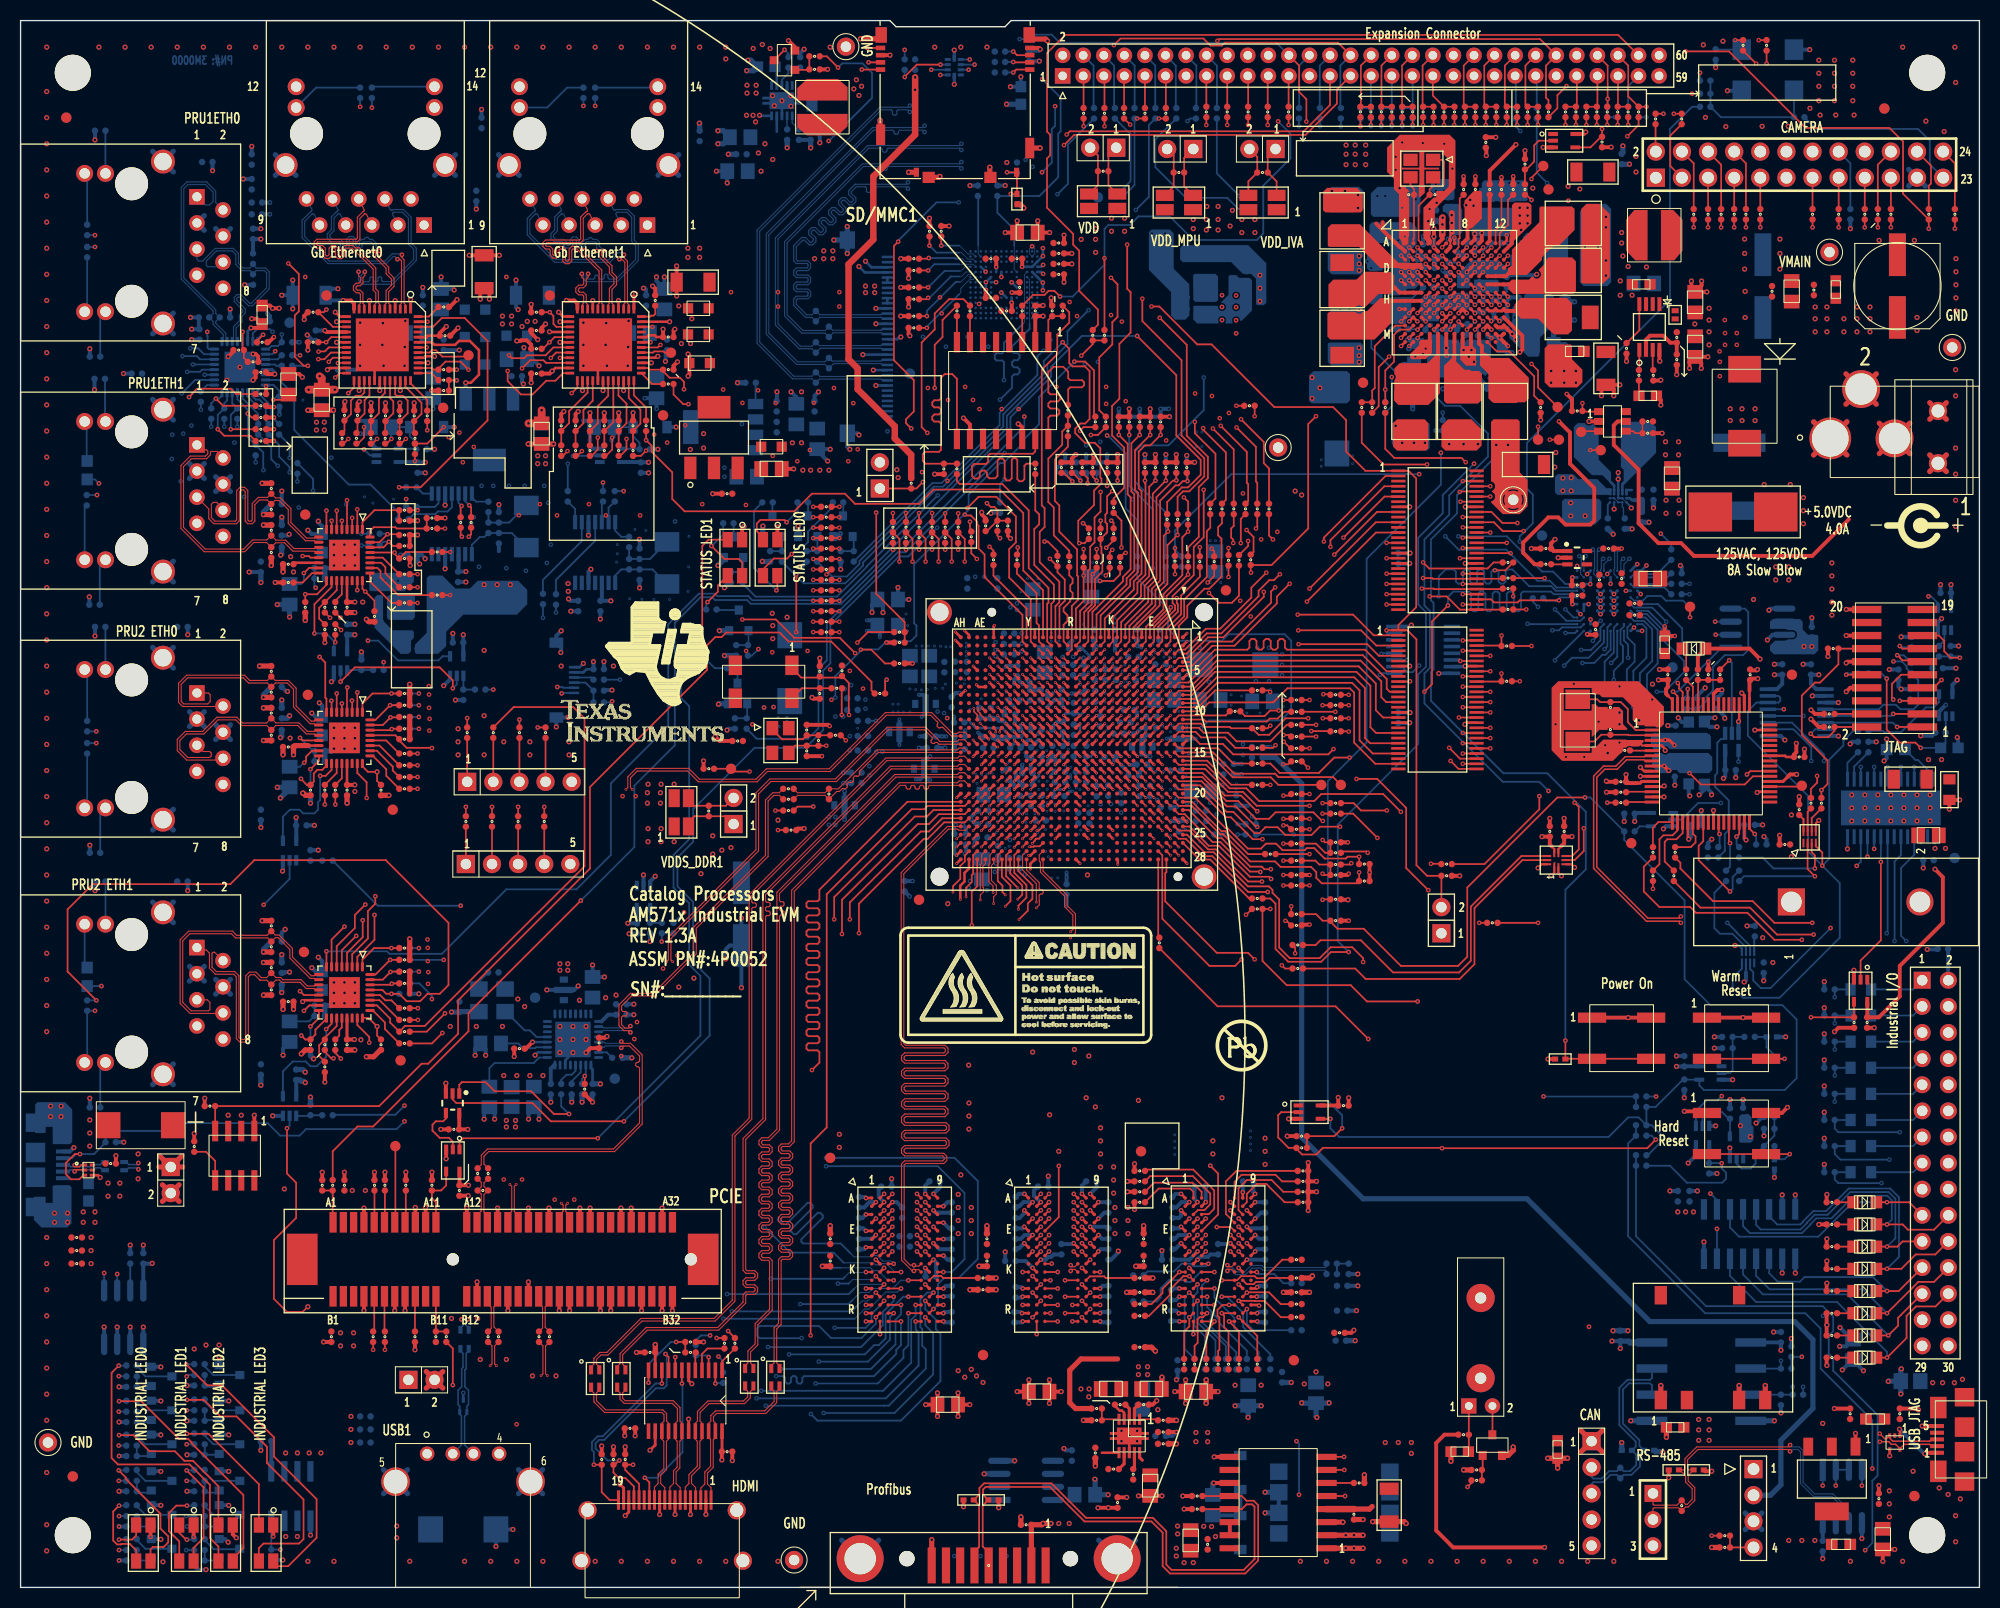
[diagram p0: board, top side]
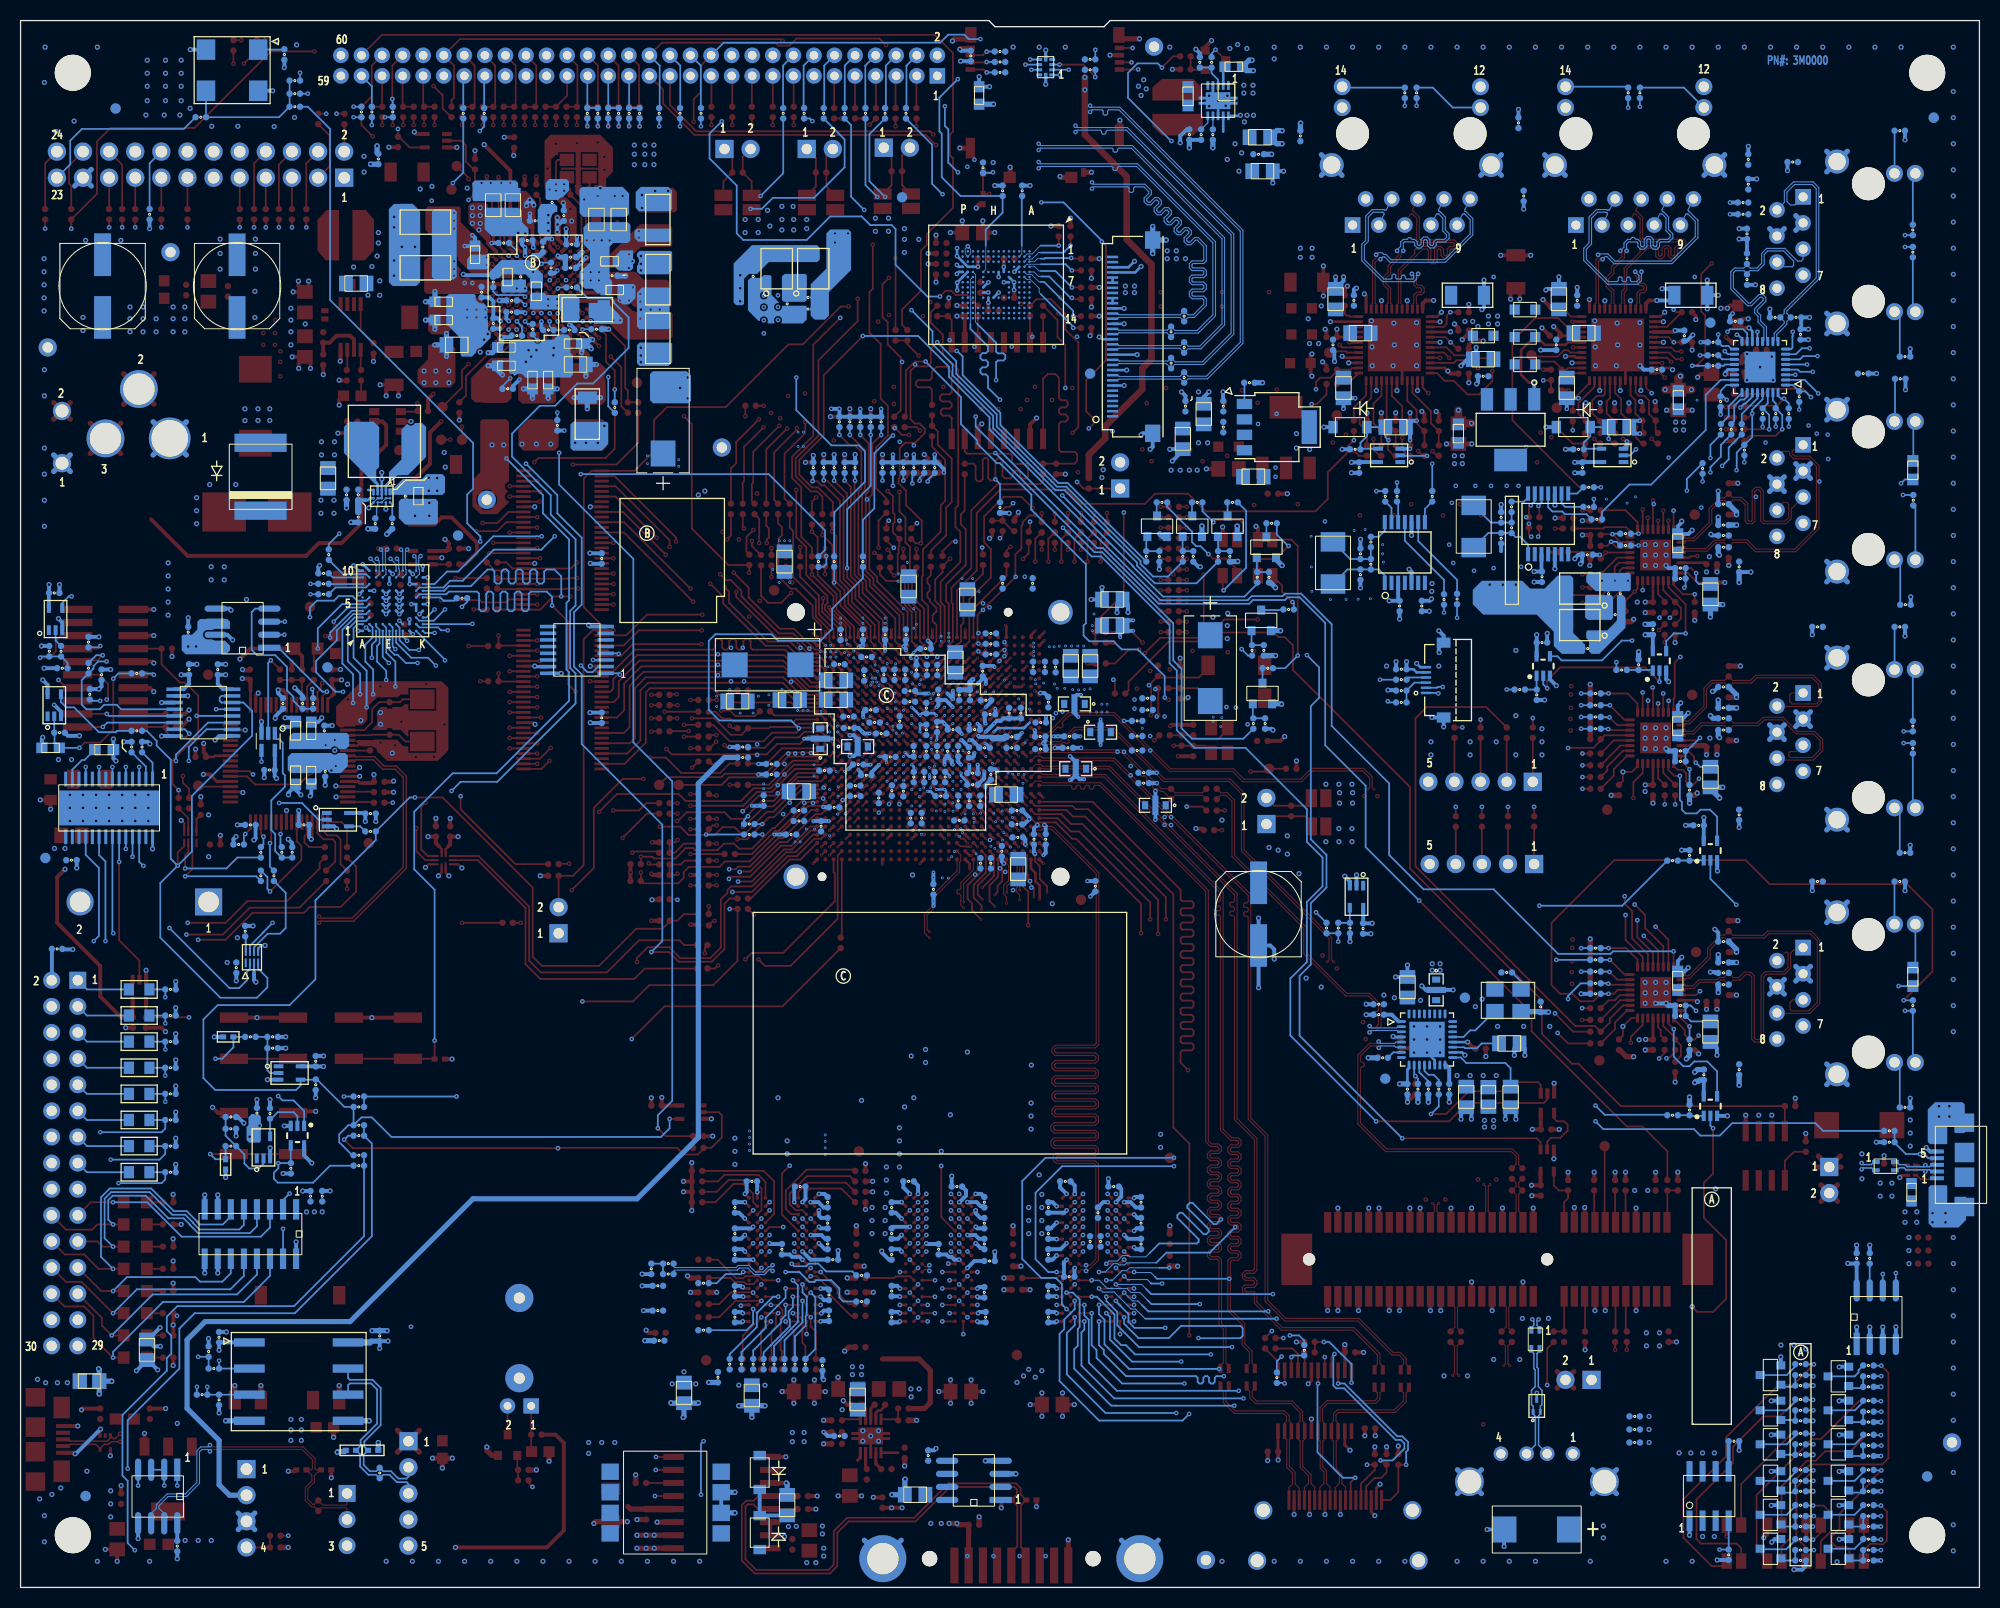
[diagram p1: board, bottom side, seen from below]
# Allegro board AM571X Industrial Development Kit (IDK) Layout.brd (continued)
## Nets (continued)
V3_3AUX_PCIE: J49.2 J52.B10 R654.2(P2)
V3_3D: C3.1 C28.1 C88.1 C104.1 C105.1 C107.1 C113.1 C119.1 C120.1 C122.1 C127.1 C130.1 C132.1 C133.1 C139.1 C143.1 C144.1 C145.1 C151.1 C170.1 C191.1 C209.1 C210.1 C211.1 C212.1 C214.1 C219.1 C220.1 C221.1 C248.1 C249.1 C251.1 C255.1 C256.1 C257.1 C258.1 C261.1 C262.1 C263.1 C264.1 C319.1 C350.1 C360.1 C361.1 C362.1 C363.1 C364.1 C365.1 C367.1 C384.1 C385.1 C386.1 C408.1 C409.1 C410.1 C420.1 C426.1 C428.1 C432.1 C435.1 C444.1 C449.1 C450.1 C451.1 C469.1 C470.1 C479.1 C575.1 C577.1 C579.1 C580.1 D16.1(A) D17.1(A) D18.1(A) D19.1(A) D22.1(A) D23.1(A) FB1.1 FB5.1 FB13.2 J15.4(VDD) J17.5 J21.1 J46.3 J49.1 J52.A9 J52.A10 J52.B8 L2.2 L2.3 L3.1(IN) Q26.2(EMMITTER) R2.2(P2) R8.2(P2) R10.2(P2) R18.2(P2) R22.2(P2) R56.2(P2) R67.2(P2) R76.2(P2) R77.2(P2) R78.2(P2) R89.2(P2) R97.1(P1) R99.1(P1) R100.1(P1) R101.1(P1) R102.1(P1) R107.2(P2) R120.2(P2) R121.2(P2) R122.2(P2) R131.2(P2) R134.2(P2) R141.1(P1) R143.1(P1) R144.1(P1) R145.1(P1) R146.1(P1) R149.2(P2) R152.2(P2) R153.2(P2) R159.2(P2) R160.2(P2) R161.2(P2) R172.2(P2) R180.1(P1) R182.1(P1) R183.1(P1) R184.1(P1) R185.1(P1) R190.2(P2) R200.2(P2) R201.2(P2) R202.2(P2) R203.2(P2) R214.2(P2) R222.1(P1) R224.1(P1) R225.1(P1) R226.1(P1) R227.1(P1) R232.2(P2) R233.2(P2) R259.2(P2) R278.2(P2) R322.2(P2) R366.2(P2) R383.2(P2) R384.2(P2) R410.2(P2) R412.2(P2) R417.2(P2) R419.2(P2) R420.1(P1) R421.2(P2) R422.2(P2) R423.2(P2) R434.2(P2) R435.2(P2) R436.2(P2) R437.2(P2) R438.2(P2) R439.2(P2) R440.2(P2) R441.2(P2) R442.2(P2) R443.2(P2) R444.2(P2) R445.2(P2) R446.2(P2) R447.2(P2) R448.2(P2) R449.2(P2) R450.2(P2) R472.2(P2) R498.2(P2) R505.2(P2) R506.2(P2) R507.2(P2) R508.2(P2) R509.2(P2) R510.2(P2) R511.2(P2) R512.2(P2) R513.2(P2) R543.1(P1) R544.1(P1) R545.2(P2) R551.2(P2) R556.2(P2) R559.2(P2) R563.2(P2) R637.1(P1) R649.2(P2) R678.2(P2) R679.2(P2) R730.2(P2) R741.2(P2) R742.1(P1) R789.2(P2) R790.2(P2) R799.2(P2) R800.2(P2) R804.2(P2) R805.2(P2) R833.2(P2) R834.1(P1) R894.2(P2) R896.2(P2) R902.2(P2) R911.2(P2) R912.2(P2) R924.2(P2) U1.AB6(VDDSHV7#AB6) U1.AB7(VDDSHV7#AB7) U1.AD5(VDDSHV6#AD5) U1.AD7(VDDSHV6#AD7) U1.AE7(VDDSHV6#AE7) U1.AF5(VDDSHV6#AF5) U1.B6(VDDSHV2#B6) U1.B23(VDDSHV3#B23) U1.C24(VDDSHV4) U1.D10(VDDSHV2#D10) U1.D16(VDDSHV3#D16) U1.D22(VDDSHV3#D22) U1.E3(VDDSHV1#E3) U1.E5(VDDSHV1#E5) U1.E10(VDDSHV2#E10) U1.E16(VDDSHV3#E16) U1.E22(VDDSHV3#E22) U1.G4(VDDSHV1#G4) U1.G5(VDDSHV1#G5) U1.G15(VDDSHV3#G15) U1.H8(VDDSHV1#H8) U1.H9(VDDSHV1#H9) U1.H10(VDDSHV2#H10) U1.H11(VDDSHV2#H11) U1.H15(VDDSHV3#H15) U1.H16(VDDSHV3#H16) U1.H18(VDDSHV3#H18) U1.H19(VDDSHV3#H19) U1.J8(VDDSHV11#J8) U1.K8(VDDSHV11#K8) U1.N4(VDDSHV10#N4) U1.N5(VDDSHV10#N5) U1.P10(VDDSHV10#P10) U1.R7(VDDSHV10#R7) U1.R10(VDDSHV10#R10) U1.T4(VDDSHV10#T4) U1.T5(VDDSHV10#T5) U1.U10(VDDSHV9#U10) U1.V12(VDDSHV5) U1.W4(VDDSHV9#W4) U1.W5(VDDSHV9#W5) U2.5(VCC) U3.D9(VIO_IN) U3.J8(SMPS9_FBK) U4.2(VCC) U4.14(VIO/RFU) U8.10(VIN) U9.21(VDD33_IO) U13.21(VDD33_IO) U15.21(VDD33_IO) U17.21(VDD33_IO) U19.5(VCC) U23.6(VDDOUT1) U23.7(VDDOUT2) U25.6(VDDOUT1) U25.7(VDDOUT2) U30.10(VCC) U33.8(VCC) U39.2(A) U39.5(VCC) U40.2(VIN+) U41.1(VCC1) U43.C6(VCCQ#C6) U43.E6(VCC#E6) U43.F5(VCC#F5) U43.J10(VCC#J10) U43.K9(VCC#K9) U43.M4(VCCQ#M4) U43.N4(VCCQ#N4) U43.P3(VCCQ#P3) U43.P5(VCCQ#P5) U44.5(VCC) U46.24(VCCA) U47.5(VCC) U63.1(VCCA) U65.8(VCCB) U68.5(VCC) U69.5(VCC) U70.5(VCC) U71.5(VCC) U73.1(VCC) U74.4(VCC1) U75.1(VCCA) U75.3(A2) U77.8(VCC) U78.5(VCC) U85.5(VCC) U89.B10(VDDIO#B10) U89.H1(VDDIO#H1) U89.K5(VDDIO#K5) U89.K9(VDDIO#K9) U97.5(VCC) U98.5(VCC) U100.1(DIR2) U100.7(VCCA) U102.17(VCC) U103.17(VCC) U104.16(VCC) X1.4(VCC)
V3_3D_PROFIA: L2.4 U74.1(D1)
V3_3D_PROFIB: L2.1 U74.2(D2)
V3_3D_PRU1ETH0JCK: C102.1 C103.1 J3.3 J3.4 R77.1(P1)
V3_3D_PRU1ETH1JCK: C116.1 C117.1 J5.3 J5.4 R121.1(P1)
V3_3D_PRU2ETH0JCK: C128.1 C129.1 J6.3 J6.4 R160.1(P1)
V3_3D_PRU2ETH1JCK: C140.1 C141.1 J8.3 J8.4 R202.1(P1)
V3_3FTDI: C224.1 C228.2 C229.1 C230.2 C233.1 C236.1 C239.1 C242.2 C245.1 C425.1 C443.1 C448.1 C578.1 FB10.2 FB11.2 R472.1(P1) R485.2(P2) R496.2(P2) U34.5(VCC) U37.20(VCCIO.1) U37.31(VCCIO.2) U37.42(VCCIO.3) U37.50(VREGIN) U37.56(VCCIO.4) U38.6(NC2) U38.8(VCC) U63.16(VCCB) U65.1(VCCA) U75.8(VCCB) U99.5(VCC) U100.6(VCCB) U101.2(VOUT1) U101.4(VOUT2)
V3_3USB: C399.1 C400.1 C401.1 U1.AA12(VDDA33V_USB1) U1.Y12(VDDA33V_USB2) U3.B9(LDOUSB_OUT)
V3_7LCD: C222.1 C315.1 C472.1 J16.3 J16.4 J16.5 R681.1 U86.3(VOUT)
V5_0D: C208.1 C418.1 C419.1 C427.1 C476.1 J21.2 J37.27 J37.28 R386.1(P1) R388.1(P1) R389.1(P1) R390.1(P1) R391.1(P1) R392.1(P1) R395.1(P1) R396.1(P1) R424.2(P2) R560.2(P2) R562.2(P2) U46.11(VCC5V) U62.E1(VOUT#E1) U62.E2(VOUT#E2) U66.2(IN#2) U66.3(IN#3) U94.2(IN#2) U94.3(IN#3)
V5_0D_EN: R419.1(P1) U62.A4(EN)
V5_0DFB: R424.1(P1) R427.2(P2) U62.E3(FB)
V5_0HDMICONN: C429.1 J24.18(+5V) U46.13(5V_OUT)
V5_0VOP: C195.1 C205.1 C207.1 U28.5(VCC) U72.15(5VOP)
V12_0D: C196.1 C303.1 C304.1 C461.1 C462.1 D20.1(CATHODE) J37.2 J37.4 J37.6 J37.8 J37.10 J37.12 J37.14 J37.16 J52.A2 J52.A3 J52.B1 J52.B2 J52.B3 R379.2(P2) R647.2(P2)
VDD_CORE: C339.1 C340.1 C341.1 C342.1 C343.1 C344.1 C345.1 C387.1 C473.1 C569.1 C570.1 C571.1 C572.1 C573.1 C574.1 R640.2(I2) R908.2(P2) U1.H13(VDD#H13) U1.H14(VDD#H14) U1.J17(VDD#J17) U1.J18(VDD#J18) U1.L7(VDD#L7) U1.L8(VDD#L8) U1.N10(VDD#N10) U1.N13(VDD#N13) U1.P11(VDD#P11) U1.P12(VDD#P12) U1.P13(VDD#P13) U1.R11(VDD#R11) U1.R16(VDD#R16) U1.R19(VDD#R19) U1.T13(VDD#T13) U1.T16(VDD#T16) U1.T19(VDD#T19) U1.U8(VDD#U8) U1.U9(VDD#U9) U1.U13(VDD#U13) U1.U16(VDD#U16) U1.V8(VDD#V8) U1.V16(VDD#V16) U3.B1(SMPS7_FDBK)
VDD_DSP: C353.1 C354.1 C355.1 C356.1 C357.1 C358.1 C414.1 C475.1 R807.1(P1) TP25.1 U1.K10(VDD_DSP#K10) U1.K11(VDD_DSP#K11) U1.L10(VDD_DSP#L10) U1.L11(VDD_DSP#L11) U1.M10(VDD_DSP#M10) U1.M11(VDD_DSP#M11)
VDD_GPU: C266.1 C267.1 C268.1 C327.1 C328.1 C329.1 C330.1 C331.1 C396.1 L17.2 U1.U11(VDD_GPU#U11) U1.U12(VDD_GPU#U12) U1.V10(VDD_GPU#V10) U1.V11(VDD_GPU#V11) U1.V14(VDD_GPU#V14) U1.W10(VDD_GPU#W10) U1.W11(VDD_GPU#W11) U1.W13(VDD_GPU#W13) U3.K6(SMPS6_FBK)
VDD_IVA: C346.1 C347.1 C348.1 C349.1 C351.1 C413.1 R642.2(I2) R807.2(P2) U1.J13(VDD_IVA#J13) U1.K12(VDD_IVA#K12) U1.K13(VDD_IVA#K13) U1.L12(VDD_IVA#L12) U1.M12(VDD_IVA#M12) U1.M13(VDD_IVA#M13) U3.K2(SMPS45_FDBK)
VDD_MIPI: C424.1 C482.1 FB19.2 U89.E10(VDD_MIPI#E10) U89.H10(VDD_MIPI#H10)
VDD_MPU: C332.1 C333.1 C334.1 C335.1 C336.1 C337.1 C338.1 C352.1 C369.1 C370.1 C371.1 C395.1 C474.1 R641.2(I2) U1.K17(VDD_MPU#K17) U1.K18(VDD_MPU#K18) U1.L15(VDD_MPU#L15) U1.L16(VDD_MPU#L16) U1.L17(VDD_MPU#L17) U1.L18(VDD_MPU#L18) U1.L19(VDD_MPU#L19) U1.M15(VDD_MPU#M15) U1.M16(VDD_MPU#M16) U1.M17(VDD_MPU#M17) U1.M18(VDD_MPU#M18) U1.N17(VDD_MPU#N17) U1.N18(VDD_MPU#N18) U1.P17(VDD_MPU#P17) U1.P18(VDD_MPU#P18) U1.R18(VDD_MPU#R18) U3.B13(SMPS12_FBK)
VDD_RTC: C402.1 R907.2(P2) U3.A5(LDO9_OUT)
VDDR_VREF: C44.2 C45.1 C46.1 C47.2 C53.1 C54.1 C80.2 C81.1 C82.1 C83.1 C99.1 U1.Y18(DDR1_VREF) U5.H1(VREFDQ) U5.M8(VREFCA) U6.H1(VREFDQ) U6.M8(VREFCA) U7.H1(VREFDQ) U7.M8(VREFCA) U8.6(REFOUT)
VDDR_VTT: C87.1 C89.1 C93.1 C94.1 C95.1 C96.1 C97.1 C98.1 C100.1 C313.1 C314.1 R49.1(P1) R50.1(P1) R51.1(P1) R52.1(P1) R53.1(P1) R54.1(P1) R55.1(P1) R57.1(P1) R58.1(P1) R59.1(P1) R60.1(P1) R61.1(P1) R62.1(P1) R63.1(P1) R64.1(P1) R65.1(P1) R66.1(P1) R68.1(P1) R69.2(P2) R70.1(P1) R71.1(P1) R72.1(P1) R73.1(P1) R74.1(P1) R75.1(P1) U8.3(VO)
VDDS_DDR: C29.1 C30.1 C31.1 C32.1 C33.1 C34.1 C35.1 C36.1 C37.1 C38.1 C39.1 C40.1 C41.1 C42.1 C43.1 C44.1 C47.1 C48.1 C49.1 C50.1 C51.1 C52.1 C55.1 C56.1 C57.1 C58.1 C59.1 C60.1 C61.1 C62.1 C63.1 C64.1 C65.1 C66.1 C67.1 C68.1 C69.1 C70.1 C71.1 C72.1 C73.1 C74.1 C75.1 C76.1 C77.1 C78.1 C79.1 C80.1 C84.1 C85.2 C87.2 C89.2 C90.1 C91.1 C92.1 C314.2 R45.2(P2) R639.1(I1) R656.1(P1) U5.A1(VDDQ#A1) U5.A8(VDDQ#A8) U5.B2(VDD#B2) U5.C1(VDDQ#C1) U5.C9(VDDQ#C9) U5.D2(VDDQ#D2) U5.D9(VDD#D9) U5.E9(VDDQ#E9) U5.F1(VDDQ#F1) U5.G7(VDD#G7) U5.H2(VDDQ#H2) U5.H9(VDDQ#H9) U5.K2(VDD#K2) U5.K8(VDD#K8) U5.N1(VDD#N1) U5.N9(VDD#N9) U5.R1(VDD#R1) U5.R9(VDD#R9) U6.A1(VDDQ#A1) U6.A8(VDDQ#A8) U6.B2(VDD#B2) U6.B7(UDQSN) U6.C1(VDDQ#C1) U6.C9(VDDQ#C9) U6.D2(VDDQ#D2) U6.D9(VDD#D9) U6.E9(VDDQ#E9) U6.F1(VDDQ#F1) U6.G7(VDD#G7) U6.H2(VDDQ#H2) U6.H9(VDDQ#H9) U6.K2(VDD#K2) U6.K8(VDD#K8) U6.N1(VDD#N1) U6.N9(VDD#N9) U6.R1(VDD#R1) U6.R9(VDD#R9) U7.A1(VDDQ#A1) U7.A8(VDDQ#A8) U7.B2(VDD#B2) U7.C1(VDDQ#C1) U7.C9(VDDQ#C9) U7.D2(VDDQ#D2) U7.D9(VDD#D9) U7.E9(VDDQ#E9) U7.F1(VDDQ#F1) U7.G7(VDD#G7) U7.H2(VDDQ#H2) U7.H9(VDDQ#H9) U7.K2(VDD#K2) U7.K8(VDD#K8) U7.N1(VDD#N1) U7.N9(VDD#N9) U7.R1(VDD#R1) U7.R9(VDD#R9) U8.2(VLDOIN)
6PORT_LCDN: J51.2 R924.1(P1) R925.2(P2) U102.1(S) U103.1(S) U104.1(S)
AM57XX_AUDIOBUZZER_TRIG: R114.1(P1) U1.A25(SPI1_SCLK)
AM57XX_CLKOUT3: R905.2(P2) U1.C23(XREF_CLK3/CLKOUT3)
AM57XX_GPIO6_14: R685.2(P2) U1.E21(GPIO6_14)
AM57XX_GPIO6_15: R661.2(P2) U1.F20(GPIO6_15)
AM57XX_GPIO6_16: R666.2(P2) U1.F21(GPIO6_16)
AM57XX_GPIO_RS485: R584.2(P2) U1.AA3(MCASP5_ACLKX/PR2_PRU1_R30_1)
AM57XX_GPMC_AD0: R434.1(P1) R453.2(P2) R861.2(P2) U1.M6(GPMC_AD0/GPIO)
AM57XX_GPMC_AD1: R435.1(P1) R454.2(P2) R862.2(P2) U1.M2(GPMC_AD1/GPIO)
AM57XX_GPMC_AD2: R436.1(P1) R455.2(P2) R863.2(P2) U1.L5(GPMC_AD2/GPIO)
AM57XX_GPMC_AD3: R437.1(P1) R456.2(P2) R864.2(P2) U1.M1(GPMC_AD3/GPIO)
AM57XX_GPMC_AD4: R438.1(P1) R457.2(P2) R857.2(P2) U1.L6(GPMC_AD4/GPIO)
AM57XX_GPMC_AD5: R439.1(P1) R458.2(P2) R858.2(P2) U1.L4(GPMC_AD5/GPIO)
AM57XX_GPMC_AD6: R440.1(P1) R459.2(P2) R859.2(P2) U1.L3(GPMC_AD6/GPIO)
AM57XX_GPMC_AD7: R441.1(P1) R460.2(P2) R860.2(P2) U1.L2(GPMC_AD7/GPIO)
AM57XX_GPMC_AD8: R442.1(P1) R461.2(P2) R838.1(P1) U1.L1(GPMC_AD8)
AM57XX_GPMC_AD9: R443.1(P1) R462.2(P2) R839.1(P1) U1.K2(GPMC_AD9)
AM57XX_GPMC_AD10: R444.1(P1) R463.2(P2) R840.1(P1) U1.J1(GPMC_AD10)
AM57XX_GPMC_AD11: R445.1(P1) R464.2(P2) R841.1(P1) U1.J2(GPMC_AD11)
AM57XX_GPMC_AD12: R446.1(P1) R465.2(P2) R842.1(P1) U1.H1(GPMC_AD12)
AM57XX_GPMC_AD13: R447.1(P1) R466.2(P2) R843.1(P1) U1.J3(GPMC_AD13)
AM57XX_GPMC_AD14: R448.1(P1) R467.2(P2) R844.1(P1) U1.H2(GPMC_AD14)
AM57XX_GPMC_AD15: R449.1(P1) R468.2(P2) R845.1(P1) U1.H3(GPMC_AD15)
AM57XX_HDMI_CLK+: L29.4 U1.AH16(HDMI1_CLOCKY)
AM57XX_HDMI_CLK-: L29.1 U1.AG16(HDMI1_CLOCKX)
AM57XX_HDMI_TX0+: L30.4 U1.AH17(HDMI1_DATA0Y)
AM57XX_HDMI_TX0-: L30.1 U1.AG17(HDMI1_DATA0X)
AM57XX_HDMI_TX1+: L31.4 U1.AH18(HDMI1_DATA1Y)
AM57XX_HDMI_TX1-: L31.1 U1.AG18(HDMI1_DATA1X)
AM57XX_HDMI_TX2+: L32.4 U1.AH19(HDMI1_DATA2Y)
AM57XX_HDMI_TX2-: L32.1 U1.AG19(HDMI1_DATA2X)
AM57XX_I2C1_SCL: R384.1(P1) R385.2(P2) R393.2(P2) U1.C20(I2C1_SCL)
AM57XX_I2C1_SDA: R383.1(P1) R387.2(P2) R394.2(P2) U1.C21(I2C1_SDA)
AM57XX_INDETHER_LED0_GRN: R247.1(P1) R803.2(P2)
AM57XX_INDETHER_LED0_RED: R241.2(P2) U1.B26(XREF_CLK2)
AM57XX_INDETHER_LED0_YEL: R253.1(P1) U1.D15(MCASP2_AXR4)
AM57XX_INDETHER_LED1_GRN: R248.1(P1) U1.B17(MCASP2_AXR6)
AM57XX_INDETHER_LED1_RED: R243.2(P2) U1.B16(MCASP2_AXR5)
AM57XX_INDETHER_LED1_YEL: R254.1(P1) U1.A17(MCASP2_AXR7)
AM57XX_INDETHER_LED2_GRN: R590.1(P1) U1.F16(SPI1_D1)
AM57XX_INDETHER_LED2_RED: R600.2(P2) U1.B25(SPI1_D0)
AM57XX_INDETHER_LED2_YEL: R594.1(P1) U1.A24(SPI1_CS0)
AM57XX_INDETHER_LED3_GRN: R593.1(P1) U1.C27(UART1_RTS/GPIO7_25)
AM57XX_INDETHER_LED3_RED: R514.2(P2) U1.A22(SPI1_CS1)
AM57XX_INDETHER_LED3_YEL: R598.1(P1) U1.E25(UART1_CTS/GPIO7_24)
AM57XX_MCASP1_AXR4: R673.2(P2) U1.E12(MCASP1_AXR4)
AM57XX_MCASP1_AXR6: R675.2(P2) U1.C12(MCASP1_AXR6)
AM57XX_MCASP1_AXR7: R676.2(P2) U1.D12(MCASP1_AXR7)
AM57XX_MMC1_CLK: R405.2(P2) U1.W6(MMC1_CLK)
AM57XX_MMC1_CMD: R404.2(P2) U1.Y6(MMC1_CMD)
AM57XX_MMC1_DAT0: R406.2(P2) U1.AA6(MMC1_DAT0)
AM57XX_MMC1_DAT1: R407.2(P2) U1.Y4(MMC1_DAT1)
AM57XX_MMC1_DAT2: R402.2(P2) U1.AA5(MMC1_DAT2)
AM57XX_MMC1_DAT3: R403.2(P2) U1.Y3(MMC1_DAT3)
AM57XX_MMC1_SDCD: R409.2(P2) U1.W7(MMC1_SDCD)
AM57XX_MMC1_SDWP: J44.1 R644.1(P1) U1.Y9(MMC1_SDWP)
AM57XX_OSC0_IN: C2.1 R4.2(P2) U1.AE15(XI_OSC0) Y1.3
AM57XX_OSC0_OUT: R5.1(P1) U1.AD15(XO_OSC0)
AM57XX_PCIE_PERN0: J52.A17 U1.AG13(PCIE_RXN0)
AM57XX_PCIE_PERN1: J52.A22 U1.AF12(PCIE_RXN1)
AM57XX_PCIE_PERP0: J52.A16 U1.AH13(PCIE_RXP0)
AM57XX_PCIE_PERP1: J52.A21 U1.AE12(PCIE_RXP1)
AM57XX_PCIE_PETN0: C477.1 U1.AG14(PCIE_TXN0)
AM57XX_PCIE_PETN1: C581.1 U1.AC11(PCIE_TXN1)
AM57XX_PCIE_PETP0: C478.1 U1.AH14(PCIE_TXP0)
AM57XX_PCIE_PETP1: C582.1 U1.AD11(PCIE_TXP1)
AM57XX_PCIE_REF_CLKN: C438.2 R581.1(P1) U1.AH15(LJCB_CLKN)
AM57XX_PCIE_REF_CLKP: C439.2 R581.2(P2) U1.AG15(LJCB_CLKP)
AM57XX_PORZN: R6.2(P2) U1.F22(PORZ)
AM57XX_PR1_UART0_RXD: R575.2(P2) R851.1(P1) U1.F2(VIN2A_D0/PR1_UART0_RXD)
AM57XX_PR1_UART0_TXD: R199.2(P2) R574.2(P2) R852.1(P1) U1.F3(VIN2A_D1/PR1_UART0_TXD)
AM57XX_PR2_PROFI_TXEN: J21.49 U1.U3(RMII50MHZCLK/PR2_GPIO)
AM57XX_PRU1ETH1_TXCLK: R123.2(P2) U1.C1(VIN2A_D6/PR1_MII_MT1_CLK)
AM57XX_PRU1ETH1_TXD2: R127.2(P2) U1.E6(VIN2A_D9/PR1_MII1_TXD2)
AM57XX_PRU1ETH1_TXD3: R128.2(P2) U1.F5(VIN2A_D8/PR1_MII1_TXD3)
AM57XX_PRU1ETH1_TXEN: R124.2(P2) U1.E4(VIN2A_D7/PR1_MII1_TXEN)
AM57XX_PRU1ETH_MDCLK: R96.2(P2) R140.2(P2) U1.D3(VIN2A_D10/PR1_MDIO_MDCLK)
AM57XX_PRU1ETH_MDDATA: R98.2(P2) R142.2(P2) U1.F6(VIN2A_D11/PR1_MDIO_DATA)
AM57XX_PRU2ETH0_COL: R178.2(P2) R930.1(P1) U1.F15(MCASP3_FSX/PR2_MII0_COL)
AM57XX_PRU2ETH0_CRS: R177.2(P2) R929.1(P1) U1.B18(MCASP3_ACLKX/PR2_MII0_CRS)
AM57XX_PRU2ETH0_MRCLK: R165.2(P2) U1.A13(MCASP1_AXR13/PR2_MII_MR0_CLK)
AM57XX_PRU2ETH0_RXD0: R171.2(P2) U1.C15(MCASP2_AXR2/PR2_MII0_RXD0)
AM57XX_PRU2ETH0_RXD1: R173.2(P2) U1.A18(MCASP2_FSX/PR2_MII0_RXD1)
AM57XX_PRU2ETH0_RXD2: R174.2(P2) U1.A19(MCASP2_ACLKX/PR2_MII0_RXD2)
AM57XX_PRU2ETH0_RXD3: R175.2(P2) U1.F14(MCASP1_AXR15/PR2_MII0_RXD3)
AM57XX_PRU2ETH0_RXDV: R166.2(P2) R197.2(P2) U1.G14(MCASP1_AXR14/PR2_MII0_RXDV)
AM57XX_PRU2ETH0_RXER: R170.2(P2) U1.G12(MCASP1_AXR0/PR2_MII0_RXER)
AM57XX_PRU2ETH0_RXLINK: R188.2(P2) U1.A16(MCASP2_AXR3/PR2_MII0_RXLINK)
AM57XX_PRU2ETH0_TXCLK: R162.2(P2) U1.F12(MCASP1_AXR1/PR2_MII_MT0_CLK)
AM57XX_PRU2ETH0_TXD0: R163.2(P2) U1.E14(MCASP1_AXR12/PR2_MII0_TXD0)
AM57XX_PRU2ETH0_TXD1: R164.2(P2) U1.A12(MCASP1_AXR11/PR2_MII0_TXD1)
AM57XX_PRU2ETH0_TXD2: R168.2(P2) U1.B13(MCASP1_AXR10/PR2_MII0_TXD2)
AM57XX_PRU2ETH0_TXD3: R169.2(P2) U1.A11(MCASP1_AXR9/PR2_MII0_TXD3)
AM57XX_PRU2ETH0_TXEN: R167.2(P2) R196.2(P2) U1.B12(MCASP1_AXR8/PR2_MII0_TXEN)
AM57XX_PRU2ETH1_COL: R220.2(P2) R893.1(P1) U1.D18(XREF_CLK0/PR2_MII1_COL)
AM57XX_PRU2ETH1_CRS: R219.2(P2) R892.1(P1) U1.E17(XREF_CLK1/PR2_MII1_CRS)
AM57XX_PRU2ETH1_MRCLK: R209.2(P2) U1.AC9(MMC3_DAT2/PR2_MII_MR1_CLK)
AM57XX_PRU2ETH1_RXD0: R213.2(P2) U1.AB5(MMC3_DAT7/PR2_MII1_RXD0)
AM57XX_PRU2ETH1_RXD1: R215.2(P2) U1.AB8(MMC3_DAT6/PR2_MII1_RXD1)
AM57XX_PRU2ETH1_RXD2: R216.2(P2) U1.AD6(MMC3_DAT5/PR2_MII1_RXD2)
AM57XX_PRU2ETH1_RXD3: R217.2(P2) U1.AC8(MMC3_DAT4/PR2_MII1_RXD3)
AM57XX_PRU2ETH1_RXDV: R211.2(P2) U1.AC3(MMC3_DAT3/PR2_MII1_RXDV)
AM57XX_PRU2ETH1_RXER: R212.2(P2) U1.B19(MCASP3_AXR0/PR2_MII1_RXER)
AM57XX_PRU2ETH1_TXCLK: R204.2(P2) U1.AC5(GPIO6_10/PR2_MII_MT1_CLK)
AM57XX_PRU2ETH1_TXD0: R206.2(P2) U1.AC6(MMC3_DAT1/PR2_MII1_TXD0)
AM57XX_PRU2ETH1_TXD1: R208.2(P2) U1.AC7(MMC3_DAT0/PR2_MII1_TXD1)
AM57XX_PRU2ETH1_TXD2: R210.2(P2) U1.AC4(MMC3_CMD/PR2_MII1_TXD2)
AM57XX_PRU2ETH1_TXD3: R207.2(P2) U1.AD4(MMC3_CLK/PR2_MII1_TXD3)
AM57XX_PRU2ETH1_TXEN: R205.2(P2) U1.AB4(GPIO6_11/PR2_MII1_TXEN)
AM57XX_PRU2ETH_MDCLK: R179.2(P2) R221.2(P2) U1.C14(MCASP1_ACLKX/PR2_MDIO_MDCLK)
AM57XX_PRU2ETH_MDDATA: R181.2(P2) R223.2(P2) U1.D14(MCASP1_FSX/PR2_MDIO_DATA)
AM57XX_RGMII1_RD0: R333.2(P2) U1.A4(VIN2A_D23/RGMII1_RXD0)
AM57XX_RGMII1_RD1: R334.2(P2) U1.B5(VIN2A_D22/RGMII1_RXD1)
AM57XX_RGMII1_RD2: R335.2(P2) U1.B4(VIN2A_D21/RGMII1_RXD2)
AM57XX_RGMII1_RD3: R336.2(P2) U1.B3(VIN2A_D20/RGMII1_RXD3)
AM57XX_RGMII1_RXCLK: R328.2(P2) U1.C5(VIN2A_D18/RGMII1_RXC)
AM57XX_RGMII1_RXCTL: R329.2(P2) U1.A3(VIN2A_D19/RGMII1_RXCTL)
AM57XX_RGMII1_TD0: R330.2(P2) U1.D6(VIN2A_D17/RGMII1_TXD0)
AM57XX_RGMII1_TD1: R331.2(P2) U1.B2(VIN2A_D16/RGMII1_TXD1)
AM57XX_RGMII1_TD2: R327.2(P2) U1.C4(VIN2A_D15/RGMII1_TXD2)
AM57XX_RGMII1_TD3: R332.2(P2) U1.C3(VIN2A_D14/RGMII1_TXD3)
AM57XX_RGMII1_TXCLK: R325.2(P2) U1.D5(VIN2A_D12/RGMII1_TXC)
AM57XX_RGMII1_TXCTL: R326.2(P2) U1.C2(VIN2A_D13/RGMII1_TXCTL)
AM57XX_RSTOUTN: R36.2(P2) R916.1(P1) U1.F23(RSTOUTN) U47.2(A)
AM57XX_RTCK: R426.2(P2) U1.E18(RTCK)
AM57XX_SPI1_CS0: R369.2(P2) U1.D17(MCASP4_AXR1/SPI3_CS0)
AM57XX_SPI1_D1: R377.2(P2) U1.A21(MCASP4_FSX/SPI3_D1)
AM57XX_SPI1_SCLK: R367.2(P2) U1.C18(MCASP4_ACLKX/SPI3_SCLK)
AM57XX_SPI2_CS0: R890.1(P1) U1.B24(SPI2_CS0)
AM57XX_SPI2_DIN: R888.1(P1) U1.G17(SPI2_D0)
AM57XX_SPI2_DOUT: R889.1(P1) U1.B22(SPI2_D1)
AM57XX_SPI2_SCLK: R684.1(P1) U1.A26(SPI2_SCLK)
AM57XX_STATUSLED0_GRN: R701.1(P1) R732.1(P1) U1.N6(GPMC_BEN0)
AM57XX_STATUSLED0_RED: R692.1(P1) R698.2(P2) U1.M3(GPMC_WEN)
AM57XX_STATUSLED0_YEL: R694.1(P1) R733.1(P1) U1.M4(GPMC_BEN1)
AM57XX_STATUSLED1_GRN: R688.1(P1) R710.1(P1) U1.P1(GPMC_CS3/GPIO)
AM57XX_STATUSLED1_RED: R707.2(P2) R734.1(P1) U1.N2(GPMC_WAIT0)
AM57XX_STATUSLED1_YEL: R686.1(P1) R703.1(P1) U1.T1(GPMC_CS0)
AM57XX_UART2_RXD: R583.2(P2) U1.D28(UART2_RXD)
AM57XX_UART2_TXD: R582.2(P2) U1.D26(UART2_TXD)
AM57XX_UART3_RXD: R487.1(P1) U1.D27(UART2_CTS/UART3_RXD)
AM57XX_UART3_TXD: R486.1(P1) U1.C28(UART2_RTS/UART3_TXD)
AM57XX_USB1_DM: L11.1 U1.AC12(USB1_DM)
AM57XX_USB1_DP: L11.2 U1.AD12(USB1_DP)
AM57XX_USB1_DRVVBUS: R557.2(P2) U1.AB10(USB1_DRVVBUS)
AM57XX_VIN1B_DATA0: R260.2(P2) U1.R6(GPMC_A0/VIN1B_D0)
AM57XX_VIN1B_DATA1: R261.2(P2) U1.T9(GPMC_A1/VIN1B_D1)
AM57XX_VIN1B_DATA2: R263.2(P2) U1.T6(GPMC_A2/VIN1B_D2)
AM57XX_VIN1B_DATA3: R267.2(P2) U1.T7(GPMC_A3/VIN1B_D3)
AM57XX_VIN1B_DATA4: R269.2(P2) U1.P6(GPMC_A4/VIN1B_D4)
AM57XX_VIN1B_DATA5: R271.2(P2) U1.R9(GPMC_A5/VIN1B_D5)
AM57XX_VIN1B_DATA6: R262.1(P1) U1.R5(GPMC_A6/VIN1B_D6)
AM57XX_VIN1B_DATA7: R264.1(P1) U1.P5(GPMC_A7/VIN1B_D7)
AM57XX_VIN1B_DE: R273.2(P2) U1.P9(GPMC_A11/VIN1B_DE1)
AM57XX_VIN1B_FLD: R274.1(P1) U1.P4(GPMC_A12/VIN1B_FLD1)
AM57XX_VIN1B_HSYNC: R258.1(P1) U1.N7(GPMC_A8/VIN1B_HSYNC1)
AM57XX_VIN1B_PCLK: R265.2(P2) U1.N9(GPMC_A10/VIN1B_CLK1)
AM57XX_VIN1B_VSYNC: R257.1(P1) U1.R4(GPMC_A9/VIN1B_VSYNC1)
AM57XX_VIN2A_DE0: R119.2(P2) R670.1(P1) R847.1(P1) U1.G2(VIN2A_DE0)
AM57XX_VIN2A_HSYNC0: R118.2(P2) R672.1(P1) R849.1(P1) U1.G1(VIN2A_HSYNC0)
AM57XX_VOUT1_D0: U1.F11(VOUT1_D0) U103.4(A2)
AM57XX_VOUT1_D1: U1.G10(VOUT1_D1) U103.2(A1)
AM57XX_VOUT1_D2: U1.F10(VOUT1_D2) U103.11(A5)
AM57XX_VOUT1_D3: U1.G11(VOUT1_D3) U103.13(A6)
AM57XX_VOUT1_D4: U1.E9(VOUT1_D4) U103.25(A11)
AM57XX_VOUT1_D5: U1.F9(VOUT1_D5) U103.9(A4)
AM57XX_VOUT1_D6: U1.F8(VOUT1_D6) U103.6(A3)
AM57XX_VOUT1_D7: U1.E7(VOUT1_D7) U103.15(A7)
AM57XX_VOUT1_D8: U1.E8(VOUT1_D8) U103.21(A9)
AM57XX_VOUT1_D9: U1.D9(VOUT1_D9) U103.27(A12)
AM57XX_VOUT1_D10: U1.D7(VOUT1_D10) U103.18(A8)
AM57XX_VOUT1_D11: U1.D8(VOUT1_D11) U103.23(A10)
AM57XX_VOUT1_D12: U1.A5(VOUT1_D12) U102.9(A4)
AM57XX_VOUT1_D13: U1.C6(VOUT1_D13) U102.2(A1)
AM57XX_VOUT1_D14: U1.C8(VOUT1_D14) U102.6(A3)
AM57XX_VOUT1_D15: U1.C7(VOUT1_D15) U102.4(A2)
AM57XX_VOUT1_D16: U1.B7(VOUT1_D16) U102.13(A6)
AM57XX_VOUT1_D17: U1.B8(VOUT1_D17) U102.18(A8)
AM57XX_VOUT1_D18: U1.A7(VOUT1_D18) U102.15(A7)
AM57XX_VOUT1_D19: U1.A8(VOUT1_D19) U102.21(A9)
AM57XX_VOUT1_D20: U1.C9(VOUT1_D20) U102.11(A5)
AM57XX_VOUT1_D21: U1.A9(VOUT1_D21) U102.25(A11)
AM57XX_VOUT1_D22: U1.B9(VOUT1_D22) U102.23(A10)
AM57XX_VOUT1_D23: U1.A10(VOUT1_D23) U102.27(A12)
AM57XX_VOUT1_DE: R634.2(P2) U1.B10(VOUT1_DE)
AM57XX_VOUT1_HSYNC: R636.2(P2) U1.C11(VOUT1_HSYNC)
AM57XX_VOUT1_PCLK: R565.2(P2) U1.D11(VOUT1_CLK)
AM57XX_VOUT1_VSYNC: U1.E11(VOUT1_VSYNC) U104.4(A1)
AM571X_PRU1ETH1_COL: R148.2(P2) R743.2(P2) U1.E2(VIN2A_D3/PR1_MII1_COL)
AM571X_PRU1ETH1_TXD0: R125.2(P2) R576.2(P2) R856.1(P1) U1.F4(VIN2A_D5/PR1_MII1_TXD0)
AM571X_PRU1ETH1_TXD1: R126.2(P2) R855.1(P1) U1.D2(VIN2A_D4/PR1_MII1_TXD1)
AM571X_RGMII0_RD0: R289.2(P2) U1.W2(RGMII0_RXD0)
AM571X_RGMII0_RD1: R290.2(P2) U1.Y2(RGMII0_RXD1)
AM571X_RGMII0_RD2: R291.2(P2) U1.V3(RGMII0_RXD2)
AM571X_RGMII0_RD3: R292.2(P2) U1.V4(RGMII0_RXD3)
AM571X_RGMII0_RXCLK: R288.2(P2) R887.1(P1) U1.U5(RGMII0_RXC)
AM571X_RGMII0_RXCTL: R285.2(P2) U1.V5(RGMII0_RXCTL)
AM571X_RGMII0_TD0: R282.2(P2) R883.1(P1) U1.U6(RGMII0_TXD0)
AM571X_RGMII0_TD1: R287.2(P2) R884.1(P1) U1.V6(RGMII0_TXD1)
AM571X_RGMII0_TD2: R283.2(P2) R885.1(P1) U1.U7(RGMII0_TXD2)
AM571X_RGMII0_TD3: R284.2(P2) R886.1(P1) U1.V7(RGMII0_TXD3)
AM571X_RGMII0_TXCLK: R281.2(P2) R881.1(P1) U1.W9(RGMII0_TXC)
AM571X_RGMII0_TXCTL: R286.2(P2) R882.1(P1) U1.V9(RGMII0_TXCTL)
AM571X_VIN2A_CLK0: R669.1(P1) R846.1(P1) U1.E1(VIN2A_CLK0)
AM571X_VIN2A_D2: R416.2(P2) R853.1(P1) U1.D1(VIN2A_D2/ECAP1_IN_PWM1)
AM571X_VIN2A_FLD0: R671.1(P1) R848.1(P1) U1.H7(VIN2A_FLD0)
AM571X_VIN2A_VSYNC0: R198.2(P2) R803.1(P1) R850.1(P1) U1.G6(VIN2A_VSYNC0)
AM571X_VOUT1_FLD: R564.1(P1) U1.B11(VOUT1_FLD)
AM572X_DCAN1_RX: C253.1 R502.1 U1.G19(DCAN1_RX)
AM572X_DCAN1_TX: R504.1 U1.G20(DCAN1_TX)
AM572X_HDMI_CEC: R683.2(P2) R805.1(P1) U1.B20(SPI1_CS3/HDMI_CEC)
AM572X_HDMI_DDC_SCL: R358.2(P2) R556.1(P1) R795.2(P2) U1.C25(I2C2_SDA/HDMI1_DDC_SCL)
AM572X_HDMI_DDC_SDA: R356.2(P2) R563.1(P1) R796.2(P2) U1.F17(I2C2_SCL/HDMI1_DDC_SDA)
AM572X_HDMI_HPD: R682.2(P2) R804.1(P1) U1.B21(SPI1_CS2/HDMI_HPD)
AM572X_QSPI_CLK: R24.2(P2) U1.R2(GPMC_A18/QSPI1_SCLK)
AM572X_QSPI_CSN: R30.2(P2) U1.P2(GPMC_CS2/QSPI1_CS0)
AM572X_QSPI_D0: R25.2(P2) U1.U1(GPMC_A16/QSPI1_D0)
AM572X_QSPI_D1: R26.2(P2) U1.P3(GPMC_A17/QSPI1_D1)
AM572X_QSPI_D2: R27.2(P2) U1.U2(GPMC_A15/QSPI_D2)
AM572X_QSPI_D3: R28.2(P2) U1.T2(GPMC_A14/QSPI_D3)
AM572X_QSPI_RTCLK: R23.2(P2) U1.R3(GPMC_A13/QSPI_RTCLK)
AM572X_USB2_DM: L33.2 U1.AF11(USB2_DM)
AM572X_USB2_DP: L33.1 U1.AE11(USB2_DP)
AM572X_USB2_DRVVBUS: R787.2(P2) U1.AC10(USB2_DRVVBUS)
BKLT_EN: Q9.G(GATE) R412.1(P1) R416.1(P1)
BKLT_L: L1.1 U32.1(L)
BKLT_SW: L1.2 U32.10(SW)
CAM1_DATA0: J9.3 R260.1(P1)
CAM1_DATA1: J9.5 R261.1(P1)
CAM1_DATA2: J9.7 R263.1(P1)
CAM1_DATA3: J9.13 R267.1(P1)
CAM1_DATA4: J9.15 R269.1(P1)
CAM1_DATA5: J9.17 R271.1(P1)
CAM1_DATA6: J9.6 R262.2(P2)
CAM1_DATA7: J9.8 R264.2(P2)
CAM1_FIELD: J9.20 R274.2(P2)
CAM1_GIO0: J9.16 R259.1(P1)
CAM1_HSYNC: J9.4 R258.2(P2)
CAM1_PCLK: J9.9 R265.1(P1)
CAM1_VSYNC: J9.2 R257.2(P2)
CAM1_WEN: J9.19 R273.1(P1)
CAM_ENN: J9.18 R685.1(P1)
CAN1_H: J38.2 R503.2(P2) U41.7(CANH) U88.1
CAN1_L: J38.3 R503.1(P1) U41.6(CANL) U87.1
CAN1_RXDF: J21.41 R502.2 U41.2(RXD)
CAN1_TXDF: C254.1 J21.43 R504.2 U41.3(TXD)
DDR_A0: R54.2(P2) U1.AD20(DDR1_A0) U5.N3(A0) U6.N3(A0) U7.N3(A0)
DDR_A1: R57.2(P2) U1.AC19(DDR1_A1) U5.P7(A1) U6.P7(A1) U7.P7(A1)
DDR_A2: R55.2(P2) U1.AC20(DDR1_A2) U5.P3(A2) U6.P3(A2) U7.P3(A2)
DDR_A3: R58.2(P2) U1.AB19(DDR1_A3) U5.N2(A3) U6.N2(A3) U7.N2(A3)
DDR_A4: R59.2(P2) U1.AF21(DDR1_A4) U5.P8(A4) U6.P8(A4) U7.P8(A4)
DDR_A5: R60.2(P2) U1.AH22(DDR1_A5) U5.P2(A5) U6.P2(A5) U7.P2(A5)
DDR_A6: R61.2(P2) U1.AG23(DDR1_A6) U5.R8(A6) U6.R8(A6) U7.R8(A6)
DDR_A7: R62.2(P2) U1.AE21(DDR1_A7) U5.R2(A7) U6.R2(A7) U7.R2(A7)
DDR_A8: R63.2(P2) U1.AF22(DDR1_A8) U5.T8(A8) U6.T8(A8) U7.T8(A8)
DDR_A9: R64.2(P2) U1.AE22(DDR1_A9) U5.R3(A9) U6.R3(A9) U7.R3(A9)
DDR_A10: R66.2(P2) U1.AD21(DDR1_A10) U5.L7(A10/AP) U6.L7(A10/AP) U7.L7(A10/AP)
DDR_A11: R65.2(P2) U1.AD22(DDR1_A11) U5.R7(A11) U6.R7(A11) U7.R7(A11)
DDR_A12: R68.2(P2) U1.AC21(DDR1_A12) U5.N7(A12/B\C\) U6.N7(A12/B\C\) U7.N7(A12/B\C\)
DDR_A13: R70.2(P2) U1.AF18(DDR1_A13) U5.T3(A13) U6.T3(A13) U7.T3(A13)
DDR_A14: R71.2(P2) U1.AE17(DDR1_A14) U5.T7(A14) U6.T7(A14) U7.T7(A14)
DDR_BA0: R72.2(P2) U1.AF17(DDR1_BA0) U5.M2(BA0) U6.M2(BA0) U7.M2(BA0)
DDR_BA1: R73.2(P2) U1.AE18(DDR1_BA1) U5.N8(BA1) U6.N8(BA1) U7.N8(BA1)
DDR_BA2: R74.2(P2) U1.AB18(DDR1_BA2) U5.M3(BA2) U6.M3(BA2) U7.M3(BA2)
DDR_CASN: R52.2(P2) U1.AC18(DDR1_CASN) U5.K3(CASN) U6.K3(CASN) U7.K3(CASN)
DDR_CKE: R49.2(P2) U1.AG22(DDR1_CKE) U5.K9(CKE) U6.K9(CKE) U7.K9(CKE)
DDR_CLK: R46.2(P2) U1.AG24(DDR1_CK) U5.J7(CK) U6.J7(CK) U7.J7(CK)
DDR_CLKN: R47.2(P2) U1.AH24(DDR1_CKN) U5.K7(CKN) U6.K7(CKN) U7.K7(CKN)
DDR_CS0N: R50.2(P2) U1.AH23(DDR1_CSN0) U5.L2(CSN) U6.L2(CSN) U7.L2(CSN)
DDR_D0: U1.AF25(DDR1_D0) U5.E3(DQ0)
DDR_D1: U1.AF26(DDR1_D1) U5.F7(DQ1)
DDR_D2: U1.AG26(DDR1_D2) U5.F8(DQ3)
DDR_D3: U1.AH26(DDR1_D3) U5.H8(DQ5)
DDR_D4: U1.AF24(DDR1_D4) U5.F2(DQ2)
DDR_D5: U1.AE24(DDR1_D5) U5.G2(DQ6)
DDR_D6: U1.AF23(DDR1_D6) U5.H3(DQ4)
DDR_D7: U1.AE23(DDR1_D7) U5.H7(DQ7)
DDR_D8: U1.AC23(DDR1_D8) U5.D7(DQ8)
DDR_D9: U1.AF27(DDR1_D9) U5.C3(DQ9)
DDR_D10: U1.AG27(DDR1_D10) U5.A3(DQ15)
DDR_D11: U1.AF28(DDR1_D11) U5.A7(DQ12)
DDR_D12: U1.AE26(DDR1_D12) U5.A2(DQ13)
DDR_D13: U1.AC25(DDR1_D13) U5.C8(DQ10)
DDR_D14: U1.AC24(DDR1_D14) U5.B8(DQ14)
DDR_D15: U1.AD25(DDR1_D15) U5.C2(DQ11)
DDR_D16: U1.V20(DDR1_D16) U7.E3(DQ0)
DDR_D17: U1.W20(DDR1_D17) U7.H8(DQ5)
DDR_D18: U1.AB28(DDR1_D18) U7.H3(DQ4)
DDR_D19: U1.AC28(DDR1_D19) U7.G2(DQ6)
DDR_D20: U1.AC27(DDR1_D20) U7.F2(DQ2)
DDR_D21: U1.Y19(DDR1_D21) U7.F7(DQ1)
DDR_D22: U1.AB27(DDR1_D22) U7.H7(DQ7)
DDR_D23: U1.Y20(DDR1_D23) U7.F8(DQ3)
DDR_D24: U1.AA23(DDR1_D24) U7.D7(DQ8)
DDR_D25: U1.Y22(DDR1_D25) U7.C3(DQ9)
DDR_D26: U1.Y23(DDR1_D26) U7.B8(DQ14)
DDR_D27: U1.AA24(DDR1_D27) U7.A2(DQ13)
DDR_D28: U1.Y24(DDR1_D28) U7.C2(DQ11)
DDR_D29: U1.AA26(DDR1_D29) U7.A7(DQ12)
DDR_D30: U1.AA25(DDR1_D30) U7.C8(DQ10)
DDR_D31: U1.AA28(DDR1_D31) U7.A3(DQ15)
DDR_DQM0: U1.AD23(DDR1_DQM0) U5.E7(LDM)
DDR_DQM1: U1.AB23(DDR1_DQM1) U5.D3(UDM)
DDR_DQM2: U1.AC26(DDR1_DQM2) U7.E7(LDM)
DDR_DQM3: U1.AA27(DDR1_DQM3) U7.D3(UDM)
DDR_DQS0: U1.AH25(DDR1_DQS0) U5.F3(LDQS)
DDR_DQS1: U1.AE27(DDR1_DQS1) U5.C7(UDQS)
DDR_DQS2: U1.AD27(DDR1_DQS2) U7.F3(LDQS)
DDR_DQS3: U1.Y28(DDR1_DQS3) U7.C7(UDQS)
DDR_DQSN0: U1.AG25(DDR1_DQS0N) U5.G3(LDQSN)
DDR_DQSN1: U1.AE28(DDR1_DQS1N) U5.B7(UDQSN)
DDR_DQSN2: U1.AD28(DDR1_DQS2N) U7.G3(LDQSN)
DDR_DQSN3: U1.Y27(DDR1_DQS3N) U7.B7(UDQSN)
DDR_ODT: R75.2(P2) U1.AE20(DDR1_ODT0) U5.K1(ODT) U6.K1(ODT) U7.K1(ODT)
DDR_RASN: R51.2(P2) U1.AF20(DDR1_RASN) U5.J3(RASN) U6.J3(RASN) U7.J3(RASN)
DDR_RESETN: U1.AG21(DDR1_RST) U5.T2(RESETN) U6.T2(RESETN) U7.T2(RESETN)
DDR_WEN: R53.2(P2) U1.AH21(DDR1_WEN) U5.L3(WEN) U6.L3(WEN) U7.L3(WEN)
DDRECC_D0: U1.W22(DDR1_ECC_D0) U6.E3(DQ0)
DDRECC_D1: U1.V23(DDR1_ECC_D1) U6.F7(DQ1)
DDRECC_D2: U1.W19(DDR1_ECC_D2) U6.H8(DQ5)
DDRECC_D3: U1.W23(DDR1_ECC_D3) U6.F8(DQ3)
DDRECC_D4: U1.Y25(DDR1_ECC_D4) U6.F2(DQ2)
DDRECC_D5: U1.V24(DDR1_ECC_D5) U6.H7(DQ7)
DDRECC_D6: U1.V25(DDR1_ECC_D6) U6.H3(DQ4)
DDRECC_D7: U1.Y26(DDR1_ECC_D7) U6.G2(DQ6)
DDRECC_DQM: U1.V26(DDR1_ECC_DQM) U6.E7(LDM)
DDRECC_DQS: U1.V27(DDR1_ECC_DQS) U6.F3(LDQS)
DDRECC_DQSN: U1.V28(DDR1_ECC_DQSN) U6.G3(LDQSN)
DRAIN0: D5.1(CATHODE) J37.19 U73.3(DRAIN0)
DRAIN1: D6.1(CATHODE) J37.20 U73.4(DRAIN1)
DRAIN2: D7.1(CATHODE) J37.21 U73.5(DRAIN2)
DRAIN3: D8.1(CATHODE) J37.22 U73.6(DRAIN3)
DRAIN4: D9.1(CATHODE) J37.23 U73.11(DRAIN4)
DRAIN5: D10.1(CATHODE) J37.24 U73.12(DRAIN5)
DRAIN6: D11.1(CATHODE) J37.25 U73.13(DRAIN6)
DRAIN7: D12.1(CATHODE) J37.26 U73.14(DRAIN7)
EECS: U37.63(EECS) U38.1(CS)
EEDATA: R495.1(P1) U37.61(EEDATA) U38.3(DI)
EESK: U37.62(EESK) U38.2(CLK)
EMMC_RSTN: R564.2(P2) R741.1(P1) U43.K5(RSTN)
EMU_RSTN: C223.1 J18.15(SRST) R429.2(P2) R450.1(P1)
EMU_USB_DM: J19.2(DM) U36.5(IO2) U37.7(DM)
EMU_USB_DP: J19.3(DP) U36.3(IO1) U37.8(DP)
ETH0_LDO_O: Q7.G(GATE) U21.43(LDO_O)
ETH0_MDC: R294.1(P1) U21.36(MDC)
ETH0_MDIO: R295.1(P1) U21.37(MDIO)
ETH0_RXCLK: R288.1(P1) R317.2(P2) U21.35(RX_CLK)
ETH0_RXD0: R289.1(P1) R299.2(P2) U21.32(RXD0)
ETH0_RXD1: R290.1(P1) R301.2(P2) U21.31(RXD1)
ETH0_RXD2: R291.1(P1) R306.2(P2) U21.28(RXD2)
ETH0_RXD3: R292.1(P1) R309.2(P2) U21.27(RXD3)
ETH0_RXDV: R285.1(P1) R304.2(P2) U21.33(RX_DV)
ETH0_TXCLK: R281.1(P1) U21.24(GTX_CLK)
ETH0_TXD0: R282.1(P1) U21.19(TXD0)
ETH0_TXD1: R287.1(P1) U21.20(TXD1)
ETH0_TXD2: R283.1(P1) U21.21(TXD2)
ETH0_TXD3: R284.1(P1) U21.22(TXD3)
ETH0_TXEN: R286.1(P1) U21.25(TX_EN)
ETH0GB_25MHZCLK: R315.2 U21.46(XI)
ETH1_LDO_O: Q8.G(GATE) U24.43(LDO_O)
ETH1_MDC: R338.1(P1) U24.36(MDC)
ETH1_MDIO: R339.1(P1) U24.37(MDIO)
ETH1_RESETN: C189.1 D4.2(ANODE) R324.1(P1) U24.42(RESET_N) U26.4(Y)
ETH1_RXCLK: R328.1(P1) R361.2(P2) U24.35(RX_CLK)
ETH1_RXD0: R333.1(P1) R343.2(P2) U24.32(RXD0)
ETH1_RXD1: R334.1(P1) R345.2(P2) U24.31(RXD1)
ETH1_RXD2: R335.1(P1) R352.2(P2) U24.28(RXD2)
ETH1_RXD3: R336.1(P1) R353.2(P2) U24.27(RXD3)
ETH1_RXDV: R329.1(P1) R348.2(P2) U24.33(RX_DV)
ETH1_TXCLK: R325.1(P1) U24.24(GTX_CLK)
ETH1_TXD0: R330.1(P1) U24.19(TXD0)
ETH1_TXD1: R331.1(P1) U24.20(TXD1)
ETH1_TXD2: R327.1(P1) U24.21(TXD2)
ETH1_TXD3: R332.1(P1) U24.22(TXD3)
ETH1_TXEN: R326.1(P1) U24.25(TX_EN)
ETH1GB_25MHZCLK: R359.2 U24.46(XI)
ETH_MDIO_CLK: R294.2(P2) R338.2(P2) R877.1(P1) U1.V1(MDIO_MCLK)
ETH_MDIO_DATA: R279.1(P1) R295.2(P2) R339.2(P2) R878.1(P1) U1.U4(MDIO_D)
ETHER0_D0N: J10.10 U21.3(TXRXM_A)
ETHER0_D0P: J10.9 U21.2(TXRXP_A)
ETHER0_D1N: J10.8 U21.6(TXRXM_B)
ETHER0_D1P: J10.7 U21.5(TXRXP_B)
ETHER0_D2N: J10.6 U21.8(TXRXM_C)
ETHER0_D2P: J10.5 U21.7(TXRXP_C)
ETHER0_D3N: J10.4 U21.11(TXRXM_D)
ETHER0_D3P: J10.3 U21.10(TXRXP_D)
ETHER1_D0N: J12.10 U24.3(TXRXM_A)
ETHER1_D0P: J12.9 U24.2(TXRXP_A)
ETHER1_D1N: J12.8 U24.6(TXRXM_B)
ETHER1_D1P: J12.7 U24.5(TXRXP_B)
ETHER1_D2N: J12.6 U24.8(TXRXM_C)
ETHER1_D2P: J12.5 U24.7(TXRXP_C)
ETHER1_D3N: J12.4 U24.11(TXRXM_D)
ETHER1_D3P: J12.3 U24.10(TXRXP_D)
F_ADBUS0: R474.2(P2) U37.16(ADBUS0)
F_ADBUS1: R475.2(P2) U37.17(ADBUS1)
F_ADBUS2: R480.2(P2) U37.18(ADBUS2)
F_ADBUS3: R481.2(P2) U37.19(ADBUS3)
F_ADBUS4: R476.2(P2) U37.21(ADBUS4)
F_ADBUS5: R478.2(P2) U37.26(ACBUS0)
F_ADBUS6: R477.2(P2) U37.23(ADBUS6)
F_ADBUS7: R483.2(P2) U37.30(ACBUS4)
FT_SRESET: R478.1(P1) R484.2(P2) U34.1(A)
FT_SRESETB: R473.2(P2) U99.4(Y)
FT_SRESETN: U34.4(Y) U99.2(A)
FT_VBUS: R492.1(P1) U34.2(B)
FTDI_REF: R479.1(P1) U37.6(REF)
FTDI_VPHY: C231.2 C234.2 FB10.1 U37.4(VPHY)
FTDI_VPLL: C237.2 C240.2 FB11.1 U37.9(VPLL)
GB_ETH0_INTN: R297.1(P1) R662.1(P1) U21.38(INT_N / PME_N2)
GB_ETH1_INTN: R342.1(P1) R663.1(P1) U24.38(INT_N / PME_N2)
GBETH0_RESETN: C168.1 D3.2(ANODE) R280.1(P1) U21.42(RESET_N) U22.4(Y)
GPIO_AM572X_USB2_ID: R788.2(P2) U1.F13(MCASP1_AXR5/GPIO)
GPIO_IND_LDN: R371.2(P2) R690.1(P1) R800.1(P1) U1.N1(GPMC_ADVN_ALE)
GPIO_PCIE_RSTDRVN: R659.1(P1) U44.1(O\E\)
GPIO_PCIE_SWRSTN: R660.1(P1) U85.2(B)
GPIO_PRU1_ETH_RESETN: R112.2(P2) R154.2(P2) R675.1(P1)
GPIO_PRU2_ETH_RESETN: R195.2(P2) R234.2(P2) R676.1(P1)
GPIO_TOUCH_RESETN: R661.1(P1) R792.2(P2)
GPIO_USB2_VBUS_DET: R834.2(P2) R904.2(P2) U96.4(Y)
GPIO_VPP_PWR_EN: R638.2(P2) R691.1(P1) U1.M5(GPMC_OEN_REN)
HAPTICS_N: Q16.D(DRAIN) U18.2(N-)
HAPTICS_P: C316.1 R113.1(P1) U18.1(P+)
HDMI_CEC: R683.1(P1) U46.1(CEC_A)
HDMI_CLK+: J24.10(CLK+) L29.3 U46.16(TMDS_CK+)
HDMI_CLK-: J24.12(CLK-) L29.2 U46.15(TMDS_CK-)
HDMI_CT_HPD: R558.2(P2) R559.1(P1) U46.12(CT_HPD)
HDMI_DDC_SCL: R795.1(P1) U46.2(SCL_A)
HDMI_DDC_SDA: R796.1(P1) U46.3(SDA_A)
HDMI_HPLG: R682.1(P1) U46.4(HPD_A)
HDMI_LSOE: R558.1(P1) U46.5(LS_OE)
HDMI_TX0+: J24.7(DAT0+) L30.3 U46.18(TMDS_D0+)
HDMI_TX0-: J24.9(DAT0-) L30.2 U46.17(TMDS_D0-)
HDMI_TX1+: J24.4(DAT1+) L31.3 U46.21(TMDS_D1+)
HDMI_TX1-: J24.6(DAT1-) L31.2 U46.20(TMDS_D1-)
HDMI_TX2+: J24.1(DAT2+) L32.3 U46.23(TMDS_D2+)
HDMI_TX2-: J24.3(DAT2-) L32.2 U46.22(TMDS_D2-)
HDMICONN_CEC: J24.13(CEC) U46.7(CEC_B)
HDMICONN_HPLG: J24.19(HPLG) R561.2(P2) U46.10(HPD_B)
HDMICONN_I2CSCL: J24.15(SCL) R560.1(P1) U46.8(SCL_B)
HDMICONN_I2CSDA: J24.16(SDA) R562.1(P1) U46.9(SDA_B)
HDQ: R300.1(P1) R891.1(P1)
IND_I2C_SCL: J17.2 J21.27 R14.2(P2) R275.1(P1) R314.2(P2) R393.1(P1) R567.2(P2) R652.2(P2) U33.6(SCL)
IND_I2C_SDA: J17.1 J21.29 R15.2(P2) R277.1(P1) R312.2(P2) R394.1(P1) R585.2(P2) R653.2(P2) U33.5(SDA)
INDUS_INPUT0: J37.1 R368.1(P1)
INDUS_INPUT1: J37.3 R370.1(P1)
INDUS_INPUT2: J37.5 R372.1(P1)
INDUS_INPUT3: J37.7 R374.1(P1)
INDUS_INPUT4: J37.9 R373.1(P1)
INDUS_INPUT5: J37.11 R375.1(P1)
INDUS_INPUT6: J37.13 R376.1(P1)
INDUS_INPUT7: J37.15 R378.1(P1)
INDUS_INPUTCLK: R367.1(P1) U72.25(CLK)
INDUS_INPUTCSN: R369.1(P1) U72.24(C\E\)
INDUS_INPUTLDN: R371.1(P1) U72.26(L\D\)
INDUS_INPUTSO: U28.2(A) U72.23(SOP)
JTAG_EMU0: J18.13(EMU0) R422.1(P1) R554.1(P1) U1.G21(EMU0)
JTAG_EMU1: J18.14(EMU1) R423.1(P1) R555.1(P1) U1.D24(EMU1)
JTAG_TCK: R3.2(P2) U1.E20(TCK) U63.4(1A1)
JTAG_TDI: J18.3(TDI) U1.D23(TDI) U63.5(1A2)
JTAG_TDO: J18.7(TDO) U1.F19(TDO) U75.2(A1)
JTAG_TMS: J18.1(TMS) U1.F18(TMS) U63.6(2A1)
JTAG_TRSTN: J18.2(TRSTN) R433.2(P2) U1.D20(TRSTN) U63.7(2A2)
JTAGPOD_PRES: R677.1(P1) U19.4(Y)
LCD_B0: U89.J3(PD0) U103.52(1B2)
LCD_B1: U89.K3(PD1) U103.54(1B1)
LCD_B2: U89.J2(PD2) U103.45(1B5)
LCD_B3: U89.K2(PD3) U103.43(1B6)
LCD_B4: U89.J1(PD4) U103.32(1B11)
LCD_B5: U89.K1(PD5) U103.47(1B4)
LCD_B6: U89.G2(PD6) U103.50(1B3)
LCD_B7: U89.G1(PD7) U103.41(1B7)
LCD_CLKN: J16.20 R632.1(P1) U89.F10(MIPI_CN)
LCD_CLKP: J16.21 R632.2(P2) U89.F9(MIPI_CP)
LCD_DEN: R634.1(P1) U89.J7(DE)
LCD_G0: U89.F2(PD8) U103.36(1B9)
LCD_G1: U89.F1(PD9) U103.30(1B12)
LCD_G2: U89.E2(PD10) U103.39(1B8)
LCD_G3: U89.E1(PD11) U103.34(1B10)
LCD_G4: U89.D2(PD12) U102.47(1B4)
LCD_G5: U89.D1(PD13) U102.54(1B1)
LCD_G6: U89.C2(PD14) U102.50(1B3)
LCD_G7: U89.C1(PD15) U102.52(1B2)
LCD_HS: R636.1(P1) U89.K8(HSYNC)
LCD_MIPI0N: J16.17 R630.2(P2) U89.J10(MIPI_D0N)
LCD_MIPI0P: J16.18 R630.1(P1) U89.J9(MIPI_D0P)
LCD_MIPI1N: J16.14 R631.2(P2) U89.G10(MIPI_D1N)
LCD_MIPI1P: J16.15 R631.1(P1) U89.G9(MIPI_D1P)
LCD_MIPI2N: J16.11 R633.1(P1) U89.D10(MIPI_D2N)
LCD_MIPI2P: J16.12 R633.2(P2) U89.D9(MIPI_D2P)
LCD_MIPI3N: J16.8 R687.1(P1) U89.C10(MIPI_D3N)
LCD_MIPI3P: J16.9 R687.2(P2) U89.C9(MIPI_D3P)
LCD_PCLK: R565.1(P1) U89.J6(PCLK)
LCD_R0: U89.B2(PD16) U102.43(1B6)
LCD_R1: U89.A2(PD17) U102.39(1B8)
LCD_R2: U89.B3(PD18) U102.41(1B7)
LCD_R3: U89.A3(PD19) U102.36(1B9)
LCD_R4: U89.B4(PD20) U102.45(1B5)
LCD_R5: U89.A4(PD21) U102.32(1B11)
LCD_R6: U89.B5(PD22) U102.34(1B10)
LCD_R7: U89.A5(PD23) U102.30(1B12)
LCD_VS: U89.K7(VSYNC) U104.2(1B1)
MMC2_CLK: U1.J7(GPMC_A23/MMC2_CLK) U43.M6(CLK)
MMC2_CMD: R513.1(P1) U1.H6(GPMC_CS1/MMC2_CMD) U43.M5(CMD)
MMC2_DAT0: R505.1(P1) U1.J4(GPMC_A24/MMC2_DAT0) U43.A3(DAT0)
MMC2_DAT1: R506.1(P1) U1.J6(GPMC_A25/MMC2_DAT1) U43.A4(DAT1)
MMC2_DAT2: R507.1(P1) U1.H4(GPMC_A26/MMC2_DAT2) U43.A5(DAT2)
MMC2_DAT3: R508.1(P1) U1.H5(GPMC_A27/MMC2_DAT3) U43.B2(DAT3)
MMC2_DAT4: R509.1(P1) U1.K7(GPMC_A19/MMC2_DAT4) U43.B3(DAT4)
MMC2_DAT5: R510.1(P1) U1.M7(GPMC_A20/MMC2_DAT5) U43.B4(DAT5)
MMC2_DAT6: R511.1(P1) U1.J5(GPMC_A21/MMC2_DAT6) U43.B5(DAT6)
MMC2_DAT7: R512.1(P1) U1.K6(GPMC_A22/MMC2_DAT7) U43.B6(DAT7)
MMC_CD: J15.10(CD) R408.1(P1) R409.1(P1) U84.1
MMC_CLK: J15.5(CLOCK) R405.1(P1) U30.1(IO1)
MMC_CMD: J15.3(CMD) R398.1(P1) R404.1(P1) U30.7(IO5)
MMC_D0: J15.7(DAT0) R399.1(P1) R406.1(P1) U30.2(IO2)
MMC_D1: J15.8(DAT1) R400.1(P1) R407.1(P1) U30.3(IO3)
MMC_D2: J15.1(DAT2) R401.1(P1) R402.1(P1) U30.6(IO4)
MMC_D3: J15.2(CD/DAT3) R397.1(P1) R403.1(P1) U30.8(IO6)
OSC0_OUT: C1.1 R4.1(P1) R5.2(P2) Y1.1
PCI_CONN_REFN: C436.1 U45.5(OUT0N)
PCI_CONN_REFP: C437.1 U45.6(OUT0P)
PCIE_CRDPRESENT: R650.1(P1) R664.1(P1)
PCIE_PERSTN: J52.A11 R545.1(P1) U44.4(Y)
PCIE_REFCLKN: C436.2 J52.A14 R580.2(P2)
PCIE_REFCLKP: C437.2 J52.A13 R580.1(P1)
PCIE_RESETN: R568.2(P2) R917.2(P2) R918.2(P2) U85.1(A)
PCIE_SMB_CLK: J52.B5 R652.1(P1)
PCIE_SMB_DATA: J52.B6 R653.1(P1)
PCIE_TCK: J52.A5 R542.2(P2)
PCIE_TDI: J52.A6 R543.2(P2)
PCIE_TDO: J52.A7 TP20.1
PCIE_TMS: J52.A8 R544.2(P2)
PCIE_TRSTN: J52.B9 R539.1(P1)
PCIE_WAKEN: R655.1(P1) R665.1(P1)
PCIECONN_PETN0: C477.2 J52.B15
PCIECONN_PETN1: C581.2 J52.B20
PCIECONN_PETP0: C478.2 J52.B14
PCIECONN_PETP1: C582.2 J52.B19
PHY0_LED_ACTN: R293.1 R321.2(P2) U21.17(LED1 / PME_N1)
PHY0_LED_LINKN: R296.1 R319.2(P2) U21.15(LED2)
PHY1_LED_ACTN: R337.1 R364.2(P2) U24.17(LED1 / PME_N1)
PHY1_LED_LINKN: R340.1 R363.2(P2) U24.15(LED2)
PHY_RESETN: R913.2(P2) R914.2(P2) U22.2(A) U26.2(A) U68.2(B) U69.2(B) U70.2(B) U71.2(B)
PMIC_EN: R645.1(P1) R922.2(P2) R923.1(P1) U3.E5(NSLEEP)
PMIC_INT: R666.1(P1) U3.K1(INT)
PMIC_RESET_IN: R794.2(P2) R928.2(P2) U105.1(R\E\S\E\T\)
PMIC_RESET_OUTN: R9.1(P1) R833.1(P1) U3.G6(RESET_OUT)
PORZN: C213.1 R6.1(P1) R499.1(P1) R914.1(P1) R918.1(P1) R920.1(P1) U98.4(Y)
PR1_MII0_COL: R95.2(P2) R876.1(P1) U102.33(2B10)
PR1_MII0_CRS: R94.2(P2) U102.29(2B12)
PR1_MII0_RXD0: R88.2(P2) R873.2(P2) U102.35(2B9)
PR1_MII0_RXD1: R90.2(P2) R872.2(P2) U102.40(2B7)
PR1_MII0_RXD2: R91.2(P2) R871.2(P2) U102.37(2B8)
PR1_MII0_RXD3: R92.2(P2) R870.2(P2) U102.42(2B6)
PR1_MII0_RXDV: R86.2(P2) R869.2(P2) U102.51(2B2)
PR1_MII0_RXER: R87.2(P2) R874.1(P1) U102.44(2B5)
PR1_MII0_RXLINK: R76.1(P1) R93.2(P2) R875.1(P1) U9.17(LED_LINK) U102.31(2B11)
PR1_MII0_TXD0: R81.2(P2) R867.2(P2) U102.53(2B1)
PR1_MII0_TXD1: R84.2(P2) R866.2(P2) U102.46(2B4)
PR1_MII0_TXD2: R85.2(P2) R753.2(P2) U103.37(2B8)
PR1_MII0_TXD3: R82.2(P2) R752.2(P2) U103.29(2B12)
PR1_MII0_TXEN: R80.2(P2) R865.2(P2) U103.33(2B10)
PR1_MII1_CRS: R139.2(P2) R744.2(P2) U103.53(2B1)
PR1_MII1_MR1_CLK: R129.2(P2) R745.2(P2) U103.44(2B5)
PR1_MII1_RXD0: R133.2(P2) R750.2(P2) U103.40(2B7)
PR1_MII1_RXD1: R135.2(P2) R749.2(P2) U103.48(2B3)
PR1_MII1_RXD2: R136.2(P2) R748.2(P2) U103.46(2B4)
PR1_MII1_RXD3: R137.2(P2) R747.2(P2) U103.31(2B11)
PR1_MII1_RXDV: R130.2(P2) R746.2(P2) U103.42(2B6)
PR1_MII1_RXER: R132.2(P2) U104.3(2B1)
PR1_MII1_RXLINK: R131.1(P1) R138.2(P2) U13.17(LED_LINK) U103.51(2B2)
PR1_MII_MR0_CLK: R83.2(P2) R868.2(P2) U102.48(2B3)
PR1_MII_MT0_CLK: R79.2(P2) R751.2(P2) U103.35(2B9)
PROFIBUS_A: J14.3 R577.1(P1) U74.12(A) U81.1
PROFIBUS_B: J14.8 R578.2(P2) U74.13(B) U80.1
PRU1ETH0_25MHZCLK: R310.2 U9.23(XI)
PRU1ETH0_COL: R95.1(P1) R104.2(P2) R106.2(P2) U9.29(COL)
PRU1ETH0_CRS: R94.1(P1) U9.27(CRS)
PRU1ETH0_INTN: R669.2(P2) U9.8(PWRDNN/INTN)
PRU1ETH0_MDC: R96.1(P1) U9.20(MDC)
PRU1ETH0_MDIO: R98.1(P1) U9.19(MDIO)
PRU1ETH0_RESETN: U9.18(RESET_N) U68.4(Y)
PRU1ETH0_RXCLK: R83.1(P1) U9.25(RX_CLK)
PRU1ETH0_RXD0: R88.1(P1) R111.2(P2) U9.30(RXD_0)
PRU1ETH0_RXD1: R90.1(P1) R110.2(P2) U9.31(RXD_1)
PRU1ETH0_RXD2: R91.1(P1) R109.2(P2) U9.32(RXD_2)
PRU1ETH0_RXD3: R92.1(P1) R108.2(P2) U9.1(RXD_3)
PRU1ETH0_RXDV: R86.1(P1) U9.26(RX_DV)
PRU1ETH0_RXERR: R87.1(P1) U9.28(RX_ERR)
PRU1ETH0_TXCLK: R79.1(P1) U9.2(TX_CLK)
PRU1ETH0_TXD0: R81.1(P1) U9.4(TXD_0)
PRU1ETH0_TXD1: R84.1(P1) U9.5(TXD_1)
PRU1ETH0_TXD2: R85.1(P1) U9.6(TXD_2)
PRU1ETH0_TXD3: R82.1(P1) U9.7(TXD_3)
PRU1ETH0_TXEN: R80.1(P1) U9.3(TX_EN)
PRU1ETH1_25MHZCLK: R313.2 U13.23(XI)
PRU1ETH1_COL: R148.1(P1) R151.2(P2) R152.1(P1) U13.29(COL)
PRU1ETH1_CRS: R139.1(P1) U13.27(CRS)
PRU1ETH1_INTN: R670.2(P2) U13.8(PWRDNN/INTN)
PRU1ETH1_MDC: R140.1(P1) U13.20(MDC)
PRU1ETH1_MDIO: R120.1(P1) R142.1(P1) U13.19(MDIO)
PRU1ETH1_RESETN: U13.18(RESET_N) U69.4(Y)
PRU1ETH1_RXCLK: R129.1(P1) U13.25(RX_CLK)
PRU1ETH1_RXD0: R133.1(P1) R158.2(P2) U13.30(RXD_0)
PRU1ETH1_RXD1: R135.1(P1) R157.2(P2) U13.31(RXD_1)
PRU1ETH1_RXD2: R136.1(P1) R156.2(P2) U13.32(RXD_2)
PRU1ETH1_RXD3: R137.1(P1) R155.2(P2) U13.1(RXD_3)
PRU1ETH1_RXDV: R130.1(P1) U13.26(RX_DV)
PRU1ETH1_RXERR: R132.1(P1) U13.28(RX_ERR)
PRU1ETH1_TXCLK: R123.1(P1) U13.2(TX_CLK)
PRU1ETH1_TXD0: R125.1(P1) U13.4(TXD_0)
PRU1ETH1_TXD1: R126.1(P1) U13.5(TXD_1)
PRU1ETH1_TXD2: R127.1(P1) U13.6(TXD_2)
PRU1ETH1_TXD3: R128.1(P1) U13.7(TXD_3)
PRU1ETH1_TXEN: R124.1(P1) U13.3(TX_EN)
PRU1ETHER0_RDN: J3.2 R99.2(P2) U9.9(RD-)
PRU1ETHER0_RDP: J3.1 R100.2(P2) U9.10(RD+)
PRU1ETHER0_TDN: J3.6 R101.2(P2) U9.11(TD-)
PRU1ETHER0_TDP: J3.5 R102.2(P2) U9.12(TD+)
PRU1ETHER1_RDN: J5.6 R143.2(P2) U13.9(RD-)
PRU1ETHER1_RDP: J5.5 R144.2(P2) U13.10(RD+)
PRU1ETHER1_TDN: J5.2 R145.2(P2) U13.11(TD-)
PRU1ETHER1_TDP: J5.1 R146.2(P2) U13.12(TD+)
PRU2ETH0_25MHZCLK: R354.2 U15.23(XI)
PRU2ETH0_COL: R178.1(P1) R187.2(P2) R188.1(P1) R189.2(P2) U15.29(COL)
PRU2ETH0_CRS: R177.1(P1) U15.27(CRS)
PRU2ETH0_INTN: R671.2(P2) U15.8(PWRDNN/INTN)
PRU2ETH0_LINKLED: R159.1(P1) R176.2(P2) U15.17(LED_LINK)
PRU2ETH0_MDC: R179.1(P1) U15.20(MDC)
PRU2ETH0_MDIO: R181.1(P1) U15.19(MDIO)
PRU2ETH0_RESETN: U15.18(RESET_N) U70.4(Y)
PRU2ETH0_RXCLK: R165.1(P1) U15.25(RX_CLK)
PRU2ETH0_RXD0: R171.1(P1) R194.2(P2) U15.30(RXD_0)
PRU2ETH0_RXD1: R173.1(P1) R193.2(P2) U15.31(RXD_1)
PRU2ETH0_RXD2: R174.1(P1) R192.2(P2) U15.32(RXD_2)
PRU2ETH0_RXD3: R175.1(P1) R191.2(P2) U15.1(RXD_3)
PRU2ETH0_RXDV: R166.1(P1) U15.26(RX_DV)
PRU2ETH0_RXERR: R170.1(P1) U15.28(RX_ERR)
PRU2ETH0_TXCLK: R162.1(P1) U15.2(TX_CLK)
PRU2ETH0_TXD0: R163.1(P1) U15.4(TXD_0)
PRU2ETH0_TXD1: R164.1(P1) U15.5(TXD_1)
PRU2ETH0_TXD2: R168.1(P1) U15.6(TXD_2)
PRU2ETH0_TXD3: R169.1(P1) U15.7(TXD_3)
PRU2ETH0_TXEN: R167.1(P1) U15.3(TX_EN)
PRU2ETH1_25MHZCLK: R357.2 U17.23(XI)
PRU2ETH1_COL: R220.1(P1) R231.1(P1) R232.1(P1) U17.29(COL)
PRU2ETH1_CRS: R219.1(P1) U17.27(CRS)
PRU2ETH1_INTN: R672.2(P2) U17.8(PWRDNN/INTN)
PRU2ETH1_LINKLED: R200.1(P1) R218.2(P2) U17.17(LED_LINK)
PRU2ETH1_MDC: R221.1(P1) U17.20(MDC)
PRU2ETH1_MDIO: R201.1(P1) R223.1(P1) U17.19(MDIO)
PRU2ETH1_RESETN: U17.18(RESET_N) U71.4(Y)
PRU2ETH1_RXCLK: R209.1(P1) U17.25(RX_CLK)
PRU2ETH1_RXD0: R213.1(P1) R238.2(P2) U17.30(RXD_0)
PRU2ETH1_RXD1: R215.1(P1) R237.2(P2) U17.31(RXD_1)
PRU2ETH1_RXD2: R216.1(P1) R236.2(P2) U17.32(RXD_2)
PRU2ETH1_RXD3: R217.1(P1) R235.2(P2) U17.1(RXD_3)
PRU2ETH1_RXDV: R117.2(P2) R211.1(P1) U17.26(RX_DV)
PRU2ETH1_RXERR: R212.1(P1) U17.28(RX_ERR)
PRU2ETH1_TXCLK: R204.1(P1) U17.2(TX_CLK)
PRU2ETH1_TXD0: R206.1(P1) U17.4(TXD_0)
PRU2ETH1_TXD1: R208.1(P1) U17.5(TXD_1)
PRU2ETH1_TXD2: R210.1(P1) U17.6(TXD_2)
PRU2ETH1_TXD3: R207.1(P1) U17.7(TXD_3)
PRU2ETH1_TXEN: R115.2(P2) R205.1(P1) U17.3(TX_EN)
PRU2ETHER0_RDN: J6.2 R182.2(P2) U15.9(RD-)
PRU2ETHER0_RDP: J6.1 R183.2(P2) U15.10(RD+)
PRU2ETHER0_TDN: J6.6 R184.2(P2) U15.11(TD-)
PRU2ETHER0_TDP: J6.5 R185.2(P2) U15.12(TD+)
PRU2ETHER1_RDN: J8.6 R224.2(P2) U17.9(RD-)
PRU2ETHER1_RDP: J8.5 R225.2(P2) U17.10(RD+)
PRU2ETHER1_TDN: J8.2 R226.2(P2) U17.11(TD-)
PRU2ETHER1_TDP: J8.1 R227.2(P2) U17.12(TD+)
QSPI_CLK: R23.1(P1) R24.1(P1) R31.2(P2)
RS485_A: J39.1 R729.2(P2) U77.6(A) U82.1
RS485_B: J39.2 R729.1(P1) U77.7(B) U83.1
RSTOUTTOPMIC: R36.1(P1) R793.2(P2) U3.E6(NRESWARM)
RT2_MII0_EDIO_DATA0: J7.3 R198.1(P1)
RT2_MII0_EDIO_DATA1: J7.4 R199.1(P1)
RT2_MII0_RXDV: J7.2 R197.1(P1)
RT2_MII0_TXEN: J7.1 R196.1(P1)
RT2_MII1_EDIO_DATA0: J4.3 R118.1(P1)
RT2_MII1_EDIO_DATA1: J4.4 R119.1(P1)
RT2_MII1_RXDV: J4.2 R117.1(P1)
RT2_MII1_TXEN: J4.1 R115.1(P1)
RTCK: J18.9(TCKRTN) R426.1(P1)
SERDES_REF_CLKN: C438.1 U45.2(OUT1N)
SERDES_REF_CLKP: C439.1 U45.3(OUT1P)
SPIMEM_CLK: R31.1(P1) U4.16(SCK)
SPIMEM_CSN: R30.1(P1) U4.7(C\S\)
SPIMEM_D0: R25.1(P1) U4.15(SI/IO0)
SPIMEM_D1: R26.1(P1) U4.8(SO/IO1)
SPIMEM_D2: R22.1(P1) R27.1(P1) U4.9(W\P\/IO2)
SPIMEM_D3: R28.1(P1) R799.1(P1) U4.1(H\O\L\D\/IO3)
SRCCLK: R276.1(P1) R586.2(P2)
SYS_RESETN: J21.25 R29.2(P2) R566.2(P2) R915.2(P2) R916.2(P2)
SYS_WARMRESETN: C576.1 R2.1(P1) R7.2(P2) R473.1(P1) R913.1(P1) R915.1(P1) R917.1(P1) U47.4(Y) U78.4(Y) U97.4(Y)
TCK: J18.11(TCK) R3.1(P1)
TOUCH_INT: R418.2(P2) R673.1(P1)
TSC_INT: J17.4 R418.1(P1)
TSC_RESETN: J17.3 R420.2(P2) R792.1(P1)
UART1_RXD: R879.1(P1) R904.1(P1) U1.B27(UART1_RXD/GPIO7_22)
UART1_TXD: R880.1(P1) U1.C26(UART1_TXD/GPIO7_23)
UARTX_RXD: U37.38(BDBUS0) U100.5(B1)
UARTX_TXD: U37.39(BDBUS1) U100.4(B2)
USB1_CONN_DM: J23.2(DM) L11.4 U64.2(D-)
USB1_CONN_DP: J23.3(DP) L11.3 U64.1(D+)
USB1_OVRCURN: R551.1(P1) U66.5(O\C\)
USB1_VBUS_EN: R553.1(P1) R557.1(P1) U66.4(EN)
USB2_CONN_DM: J45.2(DM) L33.3 U93.2(D-)
USB2_CONN_DP: J45.3(DP) L33.4 U93.1(D+)
USB2_ID: J45.4(ID) R788.1(P1) R789.1(P1) U93.3(ID)
USB2_OVRCURN: R790.1(P1) U94.5(O\C\)
USB2_VBUS_EN: R787.1(P1) R791.1(P1) U94.4(EN)
USBJTAG_ENN: R677.2(P2) U63.14(2O\E\) U63.15(1O\E\) U65.4(O\E\) U75.4(O\E\)
VADD33_PRU1ETH0: C112.1 R97.2(P2) U9.14(AVDD33)
VADD33_PRU1ETH1: C118.1 R141.2(P2) U13.14(AVDD33)
VADD33_PRU2ETH0: C137.1 R180.2(P2) U15.14(AVDD33)
VADD33_PRU2ETH1: C142.1 R222.2(P2) U17.14(AVDD33)
VAM572X_DDR1: C6.1 C7.1 C8.1 C9.1 C10.1 C11.1 C12.1 C114.1 C115.1 C441.1(POS) R639.2(I2) U1.AA21(VDDS_DDR1#AA21) U1.AA22(VDDS_DDR1#AA22) U1.AB21(VDDS_DDR1#AB21) U1.AB22(VDDS_DDR1#AB22) U1.AB24(VDDS_DDR1#AB24) U1.AB25(VDDS_DDR1#AB25) U1.AC22(VDDS_DDR1#AC22) U1.AD26(VDDS_DDR1#AD26) U1.AG20(VDDS_DDR1#AG20) U1.AG28(VDDS_DDR1#AG28) U1.AH27(VDDS_DDR1#AH27) U1.T24(VDDS_DDR1#T24) U1.T25(VDDS_DDR1#T25) U1.W16(VDDS_DDR1#W16) U1.W27(VDDS_DDR1#W27) U3.K13(SMPS3_FDBK)
VANA_OUT: C302.1 U3.C8(LDOVANA_OUT)
VCAN1: C250.1 C252.1 J38.1 U40.7(VOUT+) U41.8(VCC2)
VETH0_AVDDH: C153.1 C154.1 C157.1 FB1.2 Q7.S(SOURCE) U21.1(AVDDH#1) U21.12(AVDDH#12) U21.47(AVDDH#47)
VETH0_AVDDL: C161.1 C162.1 FB4.2 U21.4(AVDDL#4) U21.9(AVDDL#9)
VETH0_AVDDL_PLL: C163.1 C164.1 C165.1 FB2.2 U21.44(AVDDL_PLL)
VETH0_AVDDL_PMOS: C158.1 FB2.1 FB3.1 FB4.1 Q7.D1(DRAIN1) Q7.D2(DRAIN2)
VETH0_DVDDH: C155.1 C156.1 C171.1 D3.1(CATHODE) R278.1(P1) R279.2(P2) R280.2(P2) R297.2(P2) R299.1(P1) R301.1(P1) R306.1(P1) R309.1(P1) U21.16(DVDDH#16) U21.34(DVDDH#34) U21.40(DVDDH#40) U22.5(VCC)
VETH0_DVDDL: C159.1 C160.1 FB3.2 U21.14(DVDDL#14) U21.18(DVDDL#18) U21.23(DVDDL#23) U21.26(DVDDL#26) U21.30(DVDDL#30) U21.39(DVDDL#39)
VETH1_AVDDH: C176.1 C177.1 C178.1 FB5.2 Q8.S(SOURCE) U24.1(AVDDH#1) U24.12(AVDDH#12) U24.47(AVDDH#47)
VETH1_AVDDL: C182.1 C183.1 FB8.2 U24.4(AVDDL#4) U24.9(AVDDL#9)
VETH1_AVDDL_PLL: C184.1 C185.1 C186.1 FB6.2 U24.44(AVDDL_PLL)
VETH1_AVDDL_PMOS: C179.1 FB6.1 FB7.1 FB8.1 Q8.D1(DRAIN1) Q8.D2(DRAIN2)
VETH1_DVDDH: C174.1 C175.1 C192.1 D4.1(CATHODE) R322.1(P1) R324.2(P2) R342.2(P2) R343.1(P1) R345.1(P1) R352.1(P1) R353.1(P1) R364.1(P1) U24.16(DVDDH#16) U24.34(DVDDH#34) U24.40(DVDDH#40) U26.5(VCC)
VETH1_DVDDL: C180.1 C181.1 FB7.2 U24.14(DVDDL#14) U24.18(DVDDL#18) U24.23(DVDDL#23) U24.26(DVDDL#26) U24.30(DVDDL#30) U24.39(DVDDL#39)
VLDO1_OUT: C383.1 R657.2(P2) U3.C6(LDO1_OUT)
VLDO2_OUT: C318.1 R658.2(P2) U3.B6(LDO2_OUT)
VLED+: C215.1 C216.1 C218.1 J16.29 J16.30 U32.9(OUT)
VLED-: J16.23 J16.24 J16.25 J16.26 J16.27 J16.28 R415.2 U32.5(FB)
VMAIN: C20.1 C21.1 C22.1 C23.1 C24.1(POS) C152.1 C217.1 C272.1 C273.1 C274.1 C275.1 C281.1 C282.1 C283.1 C284.1 C285.1 C317.1 C407.1 C411.1(POS) C412.1(POS) C415.1 C416.1 C452.1 C453.1 C458.1 C459.1 C464.1 C465.1 C466.2 C467.2 C468.1 C471.1 C561.1 D2.1(CATHODE) F1.2 J9.1 L28.1 R19.2(P2) R20.2(P2) R113.2(P2) R411.2(P2) R927.2(P2) TP1.1 U3.A6(LDO12_IN) U3.A9(LDOUSB_IN2) U3.A10(LDO7_LDOUSB_IN) U3.C4(LDO9_IN) U3.C5(LDOLN_IN) U3.C7(VCC1) U3.D11(SMPS1_IN_1) U3.D12(SMPS1_IN_2) U3.D13(SMPS1_IN_3) U3.E1(SMPS7_IN_B1_1) U3.E2(SMPS7_IN_B1_2) U3.E3(SMPS7_IN_B1_3) U3.F1(SMPS4_IN1) U3.F2(SMPS4_IN2) U3.F3(SMPS4_IN3) U3.G11(SMPS2_IN_1) U3.G12(SMPS2_IN_2) U3.G13(SMPS2_IN_3) U3.H11(SMPS3_IN1) U3.H12(SMPS3_IN2) U3.H13(SMPS3_IN3) U3.J1(SMPS5_IN1) U3.J2(SMPS5_IN2) U3.J3(SMPS5_IN3) U3.L12(LDO34_IN) U3.L13(LDO34_IN1) U3.M4(LDO58_IN#M4) U3.M6(SMPS6_IN#M6) U3.M8(SMPS9_IN#M8) U3.M9(SMPS8_IN#M9) U3.N3(LDO6_IN) U3.N4(LDO58_IN#N4) U3.N6(SMPS6_IN#N6) U3.N8(SMPS9_IN#N8) U3.N9(SMPS8_IN#N9) U32.2(VIN) U62.A1(VIN#A1) U62.A2(VIN#A2) U76.1(IN) U79.6(IN) U79.7(FREQ) U86.4(VIN) U96.5(VCC) U105.6(VDD)
VPP_CONN: J46.2 R797.1(P1)
VPROFI: C323.1(POS) C325.1(POS) C430.1 C431.1 J14.6 R577.2(P2) U52.7(OUT#7) U52.8(OUT#8) U74.16(VCC2)
VPROFI_SRC: C433.1 C434.1 D14.1(CATHODE) D15.1(CATHODE) U52.5(IN#5) U52.6(IN#6)
VPROFI_TRANSA: D15.2(ANODE) L2.8
VPROFI_TRANSB: D14.2(ANODE) L2.5
VPWRIN_JCK: D1.2(ANODE) J1.1 J2.1 U105.5(SENSE)
VPWRIN_PREFUSE: D1.1(CATHODE) F1.1
VRTC_OUT: C301.1 R17.2(P2) R645.2(P2) R909.2(P2) R928.1(P1) R931.2(P2) U3.A8(LDOVRTC_OUT)
VSDMMC: C483.1 C485.1 C486.1 C487.1 Q27.2(EMMITTER) R397.2(P2) R398.2(P2) R399.2(P2) R400.2(P2) R401.2(P2) R408.2(P2) R644.2(P2) R657.1(P1) R898.2(P2) R900.2(P2) U1.W8(VDDSHV8#W8) U1.Y8(VDDSHV8#Y8)
VSMPS1_2: C276.1 C277.1 L12.2 L13.2 R641.1(I1)
VSMPS1_SW: L12.1 U3.E11(SMPS1_SW_1) U3.E12(SMPS1_SW_2) U3.E13(SMPS1_SW_3)
VSMPS2_SW: L13.1 U3.F11(SMPS2_SW1) U3.F12(SMPS2_SW2) U3.F13(SMPS2_SW3)
VSMPS3: C278.1 L14.2 R656.2(P2)
VSMPS3_SW: L14.1 U3.J11(SMPS3_SW1) U3.J12(SMPS3_SW2) U3.J13(SMPS3_SW3)
VSMPS4_5: C279.1 C280.1 L15.2 L16.2 R642.1(I1)
VSMPS4_SW: L15.1 U3.G1(SMPS4_SW1) U3.G2(SMPS4_SW2) U3.G3(SMPS4_SW3)
VSMPS5_SW: L16.1 U3.H1(SMPS5_SW1) U3.H2(SMPS5_SW2) U3.H3(SMPS5_SW3)
VSMPS6_SW: L17.1 U3.M5(SMPS6_SW#M5) U3.N5(SMPS6_SW#N5)
VSMPS7: C269.1 L18.2 R640.1(I1)
VSMPS7_SW: L18.1 U3.D1(SMPS7_SW1) U3.D2(SMPS7_SW2) U3.D3(SMPS7_SW3)
VSMPS8: C270.1 L19.2 TP26.1 U3.L11(SMPS8_FDBK)
VSMPS8_SW: L19.1 U3.M10(SMPS8_SW#M10) U3.N10(SMPS8_SW#N10)
VSMPS9: C271.1 L20.2 R742.2(P2)
VSMPS9_SW: L20.1 U3.M7(SMPS9_SW#M7) U3.N7(SMPS9_SW#N7)
VUSB_FTDI: C226.1 D13.2(ANODE) FB9.2 R491.2(P2) U101.3(VIN)
VUSB_JTAG: C225.1 FB9.1 J19.1(VBUS) U36.1(VCC)
VUSB_VBUS1: C311.1(POS) J23.1(VBUS) U66.6(OUT#6) U66.7(OUT#7) U66.8(OUT#8)
VUSB_VBUS2: C546.1 C547.1 J45.1(VBUS) J50.2 R21.2(P2) U93.6(VBUS) U94.6(OUT#6) U94.7(OUT#7) U94.8(OUT#8)
XTIN: C243.1 U37.2(XTIN) Y5.1
XTOUT: C244.1 U37.3(XTOUT) Y5.2
N10692191: R11.2(P2) SW2.3 SW2.4 U48.1
N11217419: C85.1 R46.1(P1) R47.1(P1)
N11219802: R67.1(P1) U8.7(EN)
N11219922: R56.1(P1) U8.9(PGOOD)
N11219986: C101.1 R69.1(P1) U8.5(VOSNS)
N11220684: C86.1 R45.1(P1) R48.2(P2) U8.1(REFIN)
N12123192: J10.11 R293.2
N12123204: J10.14 R296.2
N12138943: R298.1 U21.48(ISET)
N12139138: TP16.1 U21.41(CLK125_NDO)
N12220066: C108.1 C109.1 C110.1 C111.1 U9.13(PFBIN1) U9.15(PFBOUT) U9.24(PFBIN2)
N12225140: J5.11 R122.1(P1)
N12225158: C123.1 C124.1 C125.1 C126.1 U13.13(PFBIN1) U13.15(PFBOUT) U13.24(PFBIN2)
N12225278: J5.10 R151.1(P1)
N12226470: J5.9 R134.1(P1)
N12226568: R153.1(P1) R154.1(P1) U69.1(A)
N12957779: R482.2(P2) U37.28(ACBUS2)
N12957783: R482.1(P1) U75.6(B2)
N12957791: R489.2(P2) U37.32(ACBUS5)
N12957851: R491.1(P1) R492.2(P2) R494.2(P2) U37.59(BCBUS7)
N12958009: R485.1(P1) U37.14(RESET#)
N12958129: D13.1(CATHODE) R493.2
N12958219: R495.2(P2) R496.1(P1) U38.4(DO)
N12958339: TP18.1 U37.36(SUSPEND#)
N12958347: R493.1 U37.60(PWREN#)
N12958879: R474.1(P1) U63.13(1B1)
N12958935: R476.1(P1) U63.10(2B2)
N12958939: R481.1(P1) U63.11(2B1)
N12958943: R480.1(P1) U75.7(B1)
N12958955: R475.1(P1) U63.12(1B2)
N15911835: R147.2(P2) U13.16(RBIAS)
N16251668: R385.1(P1) U73.15(SCL)
N16251678: R387.1(P1) U73.2(SDA)
N16383240: C5.1 R11.1(P1) R911.1(P1) U97.2(A)
N16700927: J5.12 R138.1(P1)
N16818596: J3.9 R89.1(P1)
N16818719: R107.1(P1) R112.1(P1) U68.1(A)
N16819128: R103.2(P2) U9.16(RBIAS)
N16839102: C206.1 R379.1(P1) U72.14(VCC)
N16839202: R382.2(P2) U72.13(RLIM)
N16839209: R381.2(P2) U72.2(DB1)
N16839216: R380.2(P2) U72.1(DB0)
N16844891: D6.2(ANODE) R388.2(P2)
N16844892: D11.2(ANODE) R395.2(P2)
N16844893: D12.2(ANODE) R396.2(P2)
N16844894: D9.2(ANODE) R391.2(P2)
N16844899: D10.2(ANODE) R392.2(P2)
N16844909: D5.2(ANODE) R386.2(P2)
N16844924: D8.2(ANODE) R390.2(P2)
N16844930: D7.2(ANODE) R389.2(P2)
N17007255: R366.1(P1) R377.1(P1) U28.4(Y)
N17074741: J3.10 R106.1(P1)
N17120040: J21.3 R743.1(P1)
N17120055: J21.5 R744.1(P1)
N17120058: J21.7 R745.1(P1)
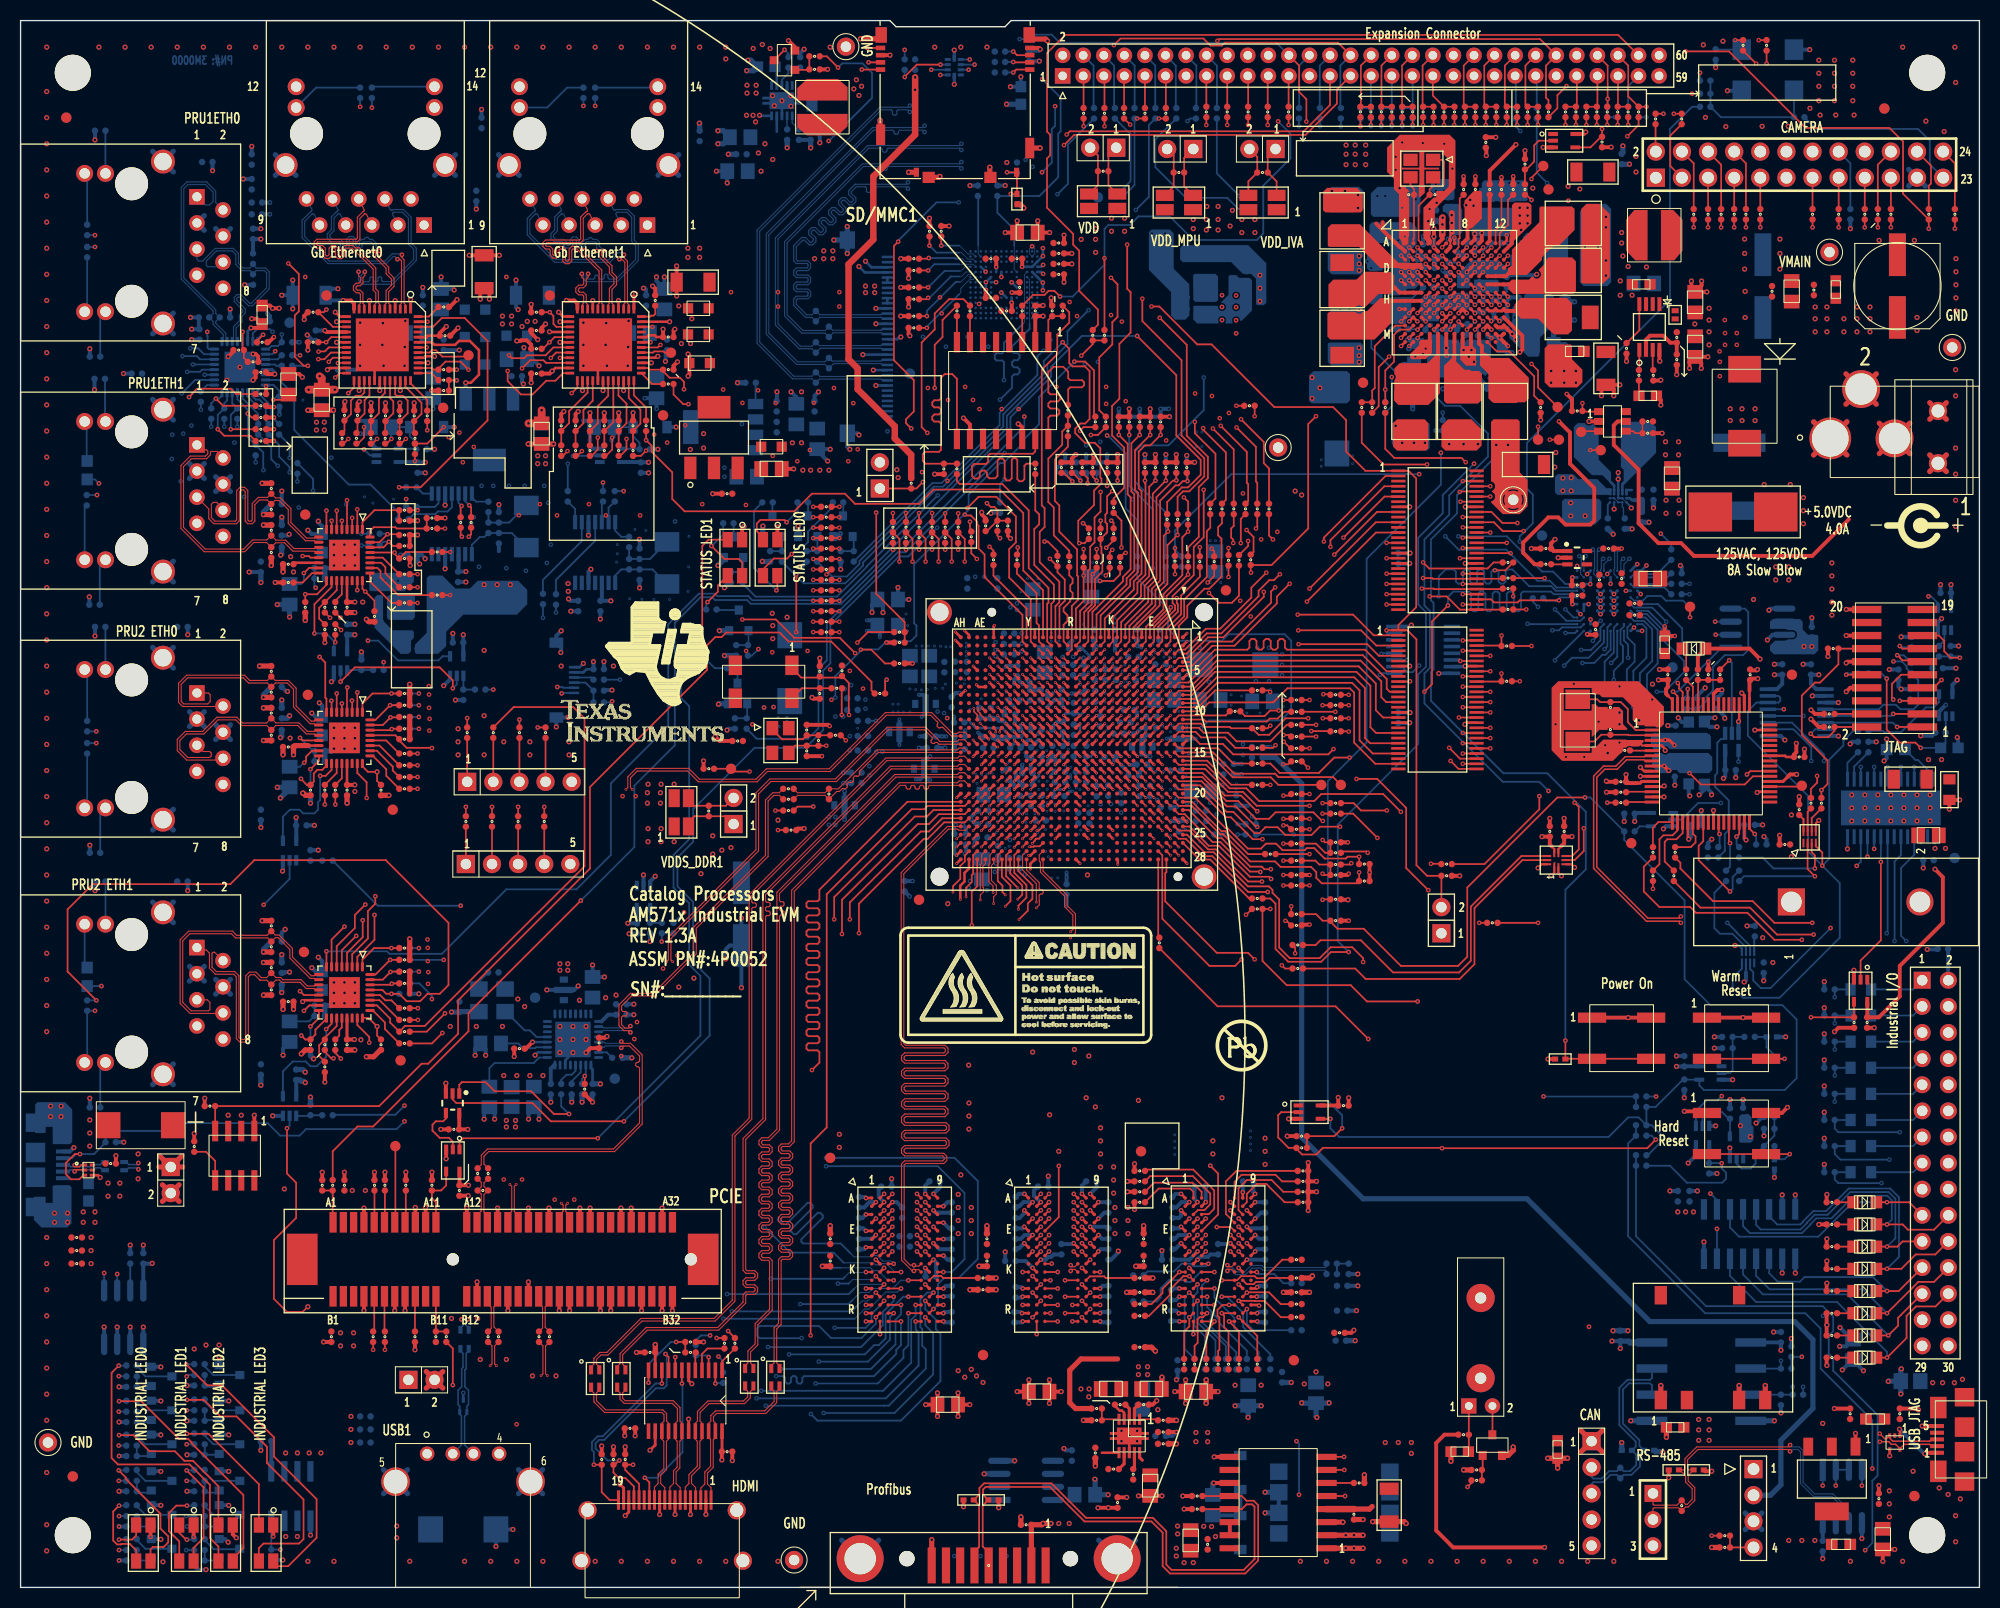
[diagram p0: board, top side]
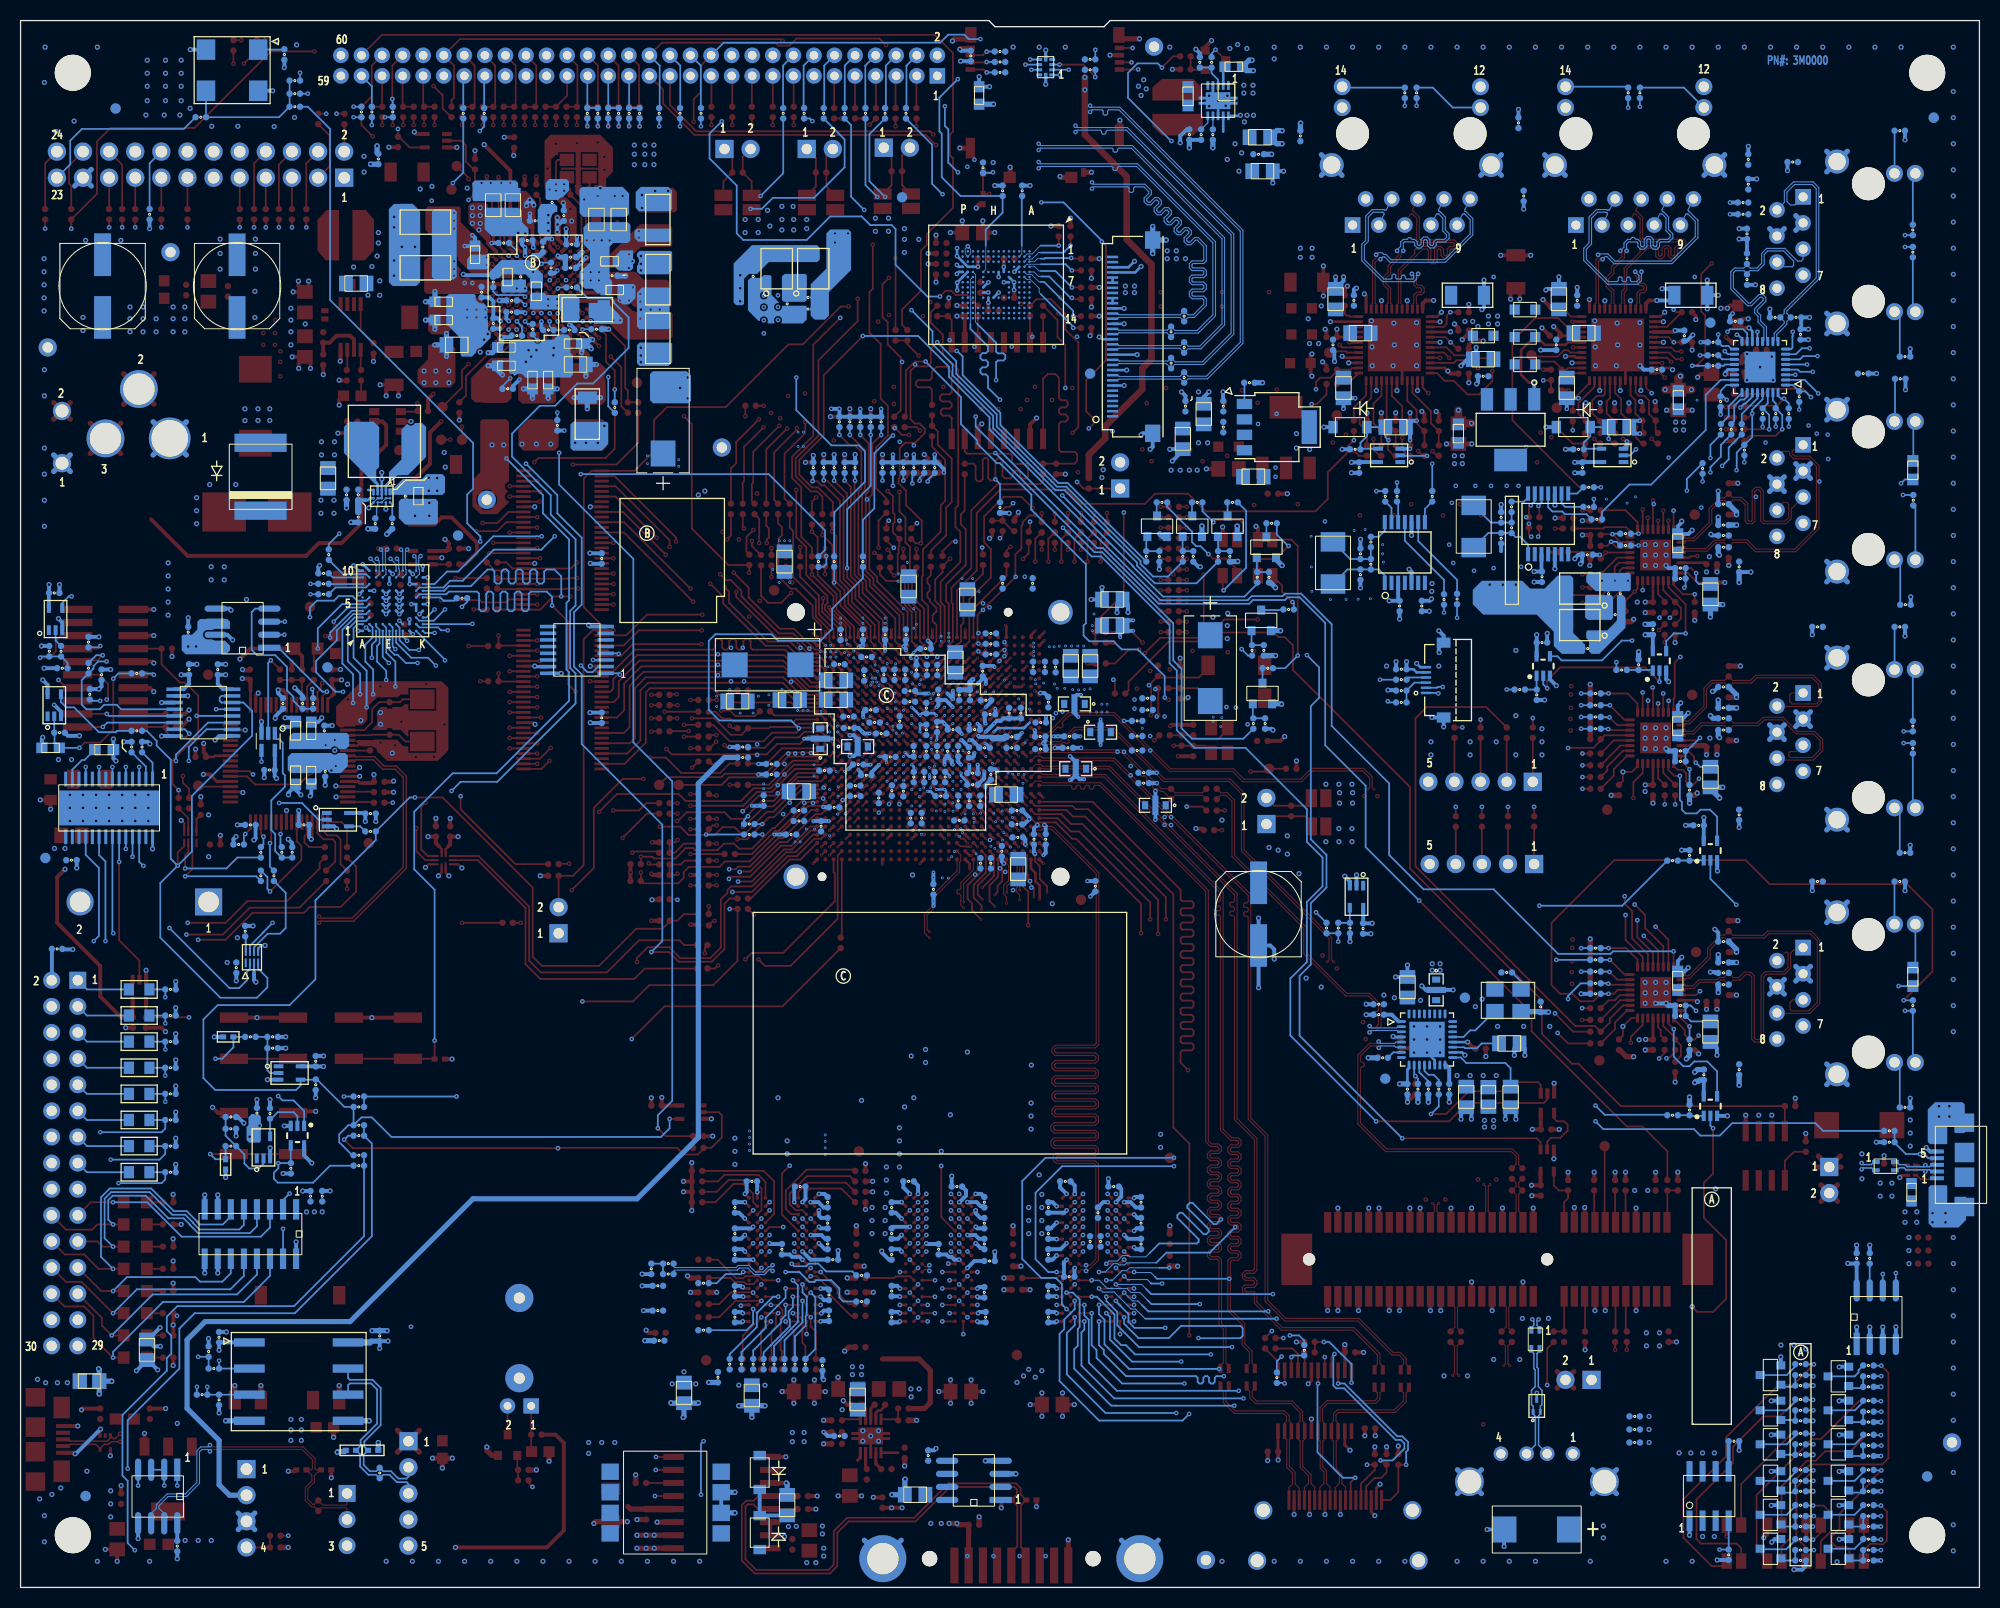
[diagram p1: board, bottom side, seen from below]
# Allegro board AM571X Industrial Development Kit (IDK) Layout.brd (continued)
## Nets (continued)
N17120061: J21.9 R746.1(P1)
N17120072: J21.11 R747.1(P1)
N17120075: J21.13 R748.1(P1)
N17120078: J21.15 R749.1(P1)
N17120081: J21.17 R750.1(P1)
N17120084: J21.19 R751.1(P1)
N17120087: J21.21 R752.1(P1)
N17120090: J21.23 R753.1(P1)
N17120397: J21.45 R869.1(P1)
N17120400: J21.47 R870.1(P1)
N17120403: J21.24 R684.2(P2) R883.2(P2)
N17144335: R29.1(P1) U4.3(R\E\S\E\T\)
N17156111: C172.2 R305.2(P2) U23.1(XIN/CLK) Y3.2
N17156113: C173.2 R305.1(P1) R308.2(P2) Y3.1
N17156222: R308.1(P1) U23.14(XOUT)
N17156522: R310.1 U23.11(Y1)
N17156525: R313.1 U23.9(Y2)
N17156528: R315.1 U23.8(Y3)
N17156983: R314.1(P1) U23.12(S2/SCL)
N17156986: R312.1(P1) U23.13(S1/SDA)
N17569906: J12.11 R337.2
N17569909: J12.14 R340.2
N17569918: R341.1 U24.48(ISET)
N17569921: TP17.1 U24.41(CLK125_NDO)
N17570093: C193.2 R349.2(P2) U25.1(XIN/CLK) Y4.2
N17570094: C194.2 R349.1(P1) R351.2(P2) Y4.1
N17570107: R351.1(P1) U25.14(XOUT)
N17570112: R354.1 U25.11(Y1)
N17570113: R357.1 U25.9(Y2)
N17570114: R359.1 U25.8(Y3)
N17570122: R358.1(P1) U25.12(S2/SCL)
N17570123: R356.1(P1) U25.13(S1/SDA)
N17594977: C134.1 C135.1 C136.1 C138.1 U15.13(PFBIN1) U15.15(PFBOUT) U15.24(PFBIN2)
N17595008: J6.9 R172.1(P1)
N17595032: R190.1(P1) R195.1(P1) U70.1(A)
N17595048: R186.2(P2) U15.16(RBIAS)
N17595072: J6.10 R189.1(P1)
N17595076: J6.11 R161.1(P1)
N17595078: J6.12 R176.1(P1)
N17596821: J8.11 R203.1(P1)
N17596823: C147.1 C148.1 C149.1 C150.1 U17.13(PFBIN1) U17.15(PFBOUT) U17.24(PFBIN2)
N17596838: J8.10 R230.1(P1) R231.2(P2)
N17596847: R230.2(P2) U1.C17(MCASP3_AXR1/PR2_MII1_RXLINK)
N17596886: J8.9 R214.1(P1)
N17596899: R233.1(P1) R234.1(P1) U71.1(A)
N17596976: R228.2(P2) U17.16(RBIAS)
N17596979: J8.12 R218.1(P1)
N17731118: Q1.G(GATE) R241.1(P1) R245.2(P2)
N17731139: Q5.G(GATE) R253.2(P2) R255.2(P2)
N17732522: R410.1(P1) U32.6(EN)
N17732526: R413.2(P2) R414.2(P2) U32.3(SS)
N17732536: Q9.D(DRAIN) R413.1(P1)
N17732560: R411.1(P1) U32.7(FSW)
N17745676: J9.22 R275.2(P2)
N17745678: J9.24 R277.2(P2)
N17745755: R276.2(P2) R300.2(P2) R903.2(P2) R905.1(P1) X1.3(OUT)
N17863265: J3.11 R78.1(P1)
N17863276: J3.12 R93.1(P1)
N18733248: R497.1(P1) U1.AD14(RTC_OSC_XO)
N18733249: C247.1 R497.2(P2) Y6.4
N18733252: C246.1 R919.2(P2) U1.AE14(RTC_OSC_XI) Y6.1
N18733262: R499.2(P2) U1.AF14(RTC_ISO)
N18733263: R498.1(P1) R500.1(P1) U39.4(Y)
N18733273: R500.2(P2) R920.2(P2) U1.AB17(RTC_PORZ)
N18733274: R923.2(P2) U1.Y11(ON_OFF)
N18733276: R921.1(P1) TP19.1 U1.AD17(WAKEUP0)
N18868530: R14.1(P1) R572.2(P2) U3.L1(I2C1_SCL_SCK)
N18868533: R15.1(P1) R588.2(P2) U3.L2(I2C1_SDA_SDI)
N18901325: R794.1(P1) U3.K9(RESET_IN)
N18913166: TP7.1 U3.J5(ENABLE1)
N18913202: R17.1(P1) R906.1(P1) U3.K7(BOOT1)
N18913205: R16.1(P1) U3.L3(BOOT0)
N18913322: R18.1(P1) R931.1(P1) U3.G9(GPIO_7)
N18913403: C26.2 U3.A3(OSC16MIN) Y2.1
N18913412: C25.2 U3.A2(OSC16MOUT) Y2.3
N18913758: C27.2 U3.B7(VBG)
N18914190: TP2.1 U3.M11(CLK32KGO)
N18914214: TP3.1 U3.J7(POWERGOOD)
N18914339: SW3.3 SW3.4 U3.G8(PWRON) U50.1
N18914524: TP6.1 U3.C11(RPWRON)
N18915671: R19.1(P1) U3.B3(VCC_SENSE)
N18915723: R20.1(P1) U3.A11(VCC_SENSE2)
N18915943: R21.1(P1) U3.D8(VBUS)
N19120663: R41.2(P2) U5.L8(ZQ)
N19120749: R44.2(P2) U7.L8(ZQ)
N19127709: R42.2(P2) U6.L8(ZQ)
N19139994: R32.1(P1) U6.D7(DQ8)
N19139997: R33.1(P1) U6.C3(DQ9)
N19140025: R34.1(P1) U6.C8(DQ10)
N19140027: R35.1(P1) U6.C2(DQ11)
N19140065: R37.1(P1) U6.A7(DQ12)
N19140067: R38.1(P1) U6.A2(DQ13)
N19140105: R39.1(P1) U6.B8(DQ14)
N19140107: R40.1(P1) U6.A3(DQ15)
N19258097: R546.1(P1) U45.7(OE)
N19258128: U45.21(XIN) Y7.3(CLK)
N19258198: R547.1(P1) Y7.1(OE)
N19258383: R548.1(P1) U45.11(OS0)
N19258403: R549.1(P1) R550.1(P1) U45.10(OS1)
N19258622: C305.1 U45.17(REG_CAP2)
N19258627: C306.1 U45.19(REG_CAP1)
N19290398: R421.1(P1) U33.7(WP)
N19388440: R566.1(P1) U89.B9(RESXN)
N19415733: R568.1(P1) U45.12(RSTN)
N19425975: R7.1(P1) U1.E23(RESETN)
N19426030: R8.1(P1) U1.D21(NMI_DSP)
N19426454: R569.1(P1) U1.AC15(XI_OSC1)
N19438966: R582.1(P1) U1.AB9(MCASP5_FSX/PR2_PRU1_R31_2) U77.4(D)
N19438972: R583.1(P1) U77.1(R)
N19438984: R584.1(P1) U77.2(R\E\) U77.3(DE)
N19634423: R579.2(P2) U74.6(R\E\)
N19634430: R574.1(P1) U74.8(D)
N19634431: R575.1(P1) U74.5(R)
N19634433: R576.1(P1) U74.7(DE)
N19700674: J18.5(TVDD) R730.1(P1)
N19795587: R425.1(P1) U3.B12(GPIO_0)
N19795594: R428.1(P1) U3.C13(GPIO_1)
N19795604: R430.1(P1) U3.A12(GPIO_2)
N19795606: R431.1(P1) U3.H9(GPIO_3)
N19795618: R570.1(P1) U3.C10(GPIO_5)
N19795620: R571.1(P1) U3.N11(GPIO_6)
N19795629: R432.1(P1) U3.K10(GPIO_4)
N19796448: R572.1(P1) U3.M3(I2C2_SCL_SCE)
N19796451: R588.1(P1) U3.H8(I2C2_SDA_SDO)
N19923823: C286.1 U1.J10(CAP_VBBLDO_IVA)
N19923824: C287.1 U1.J9(CAP_VDDRAM_DSP)
N19923825: C288.1 U1.J16(CAP_VBBLDO_MPU)
N19923831: C292.1 U1.K19(CAP_VDDRAM_MPU)
N19923832: C291.1 U1.K16(CAP_VDDRAM_IVA)
N19923833: C290.1 U1.K9(CAP_VBBLDO_DSP)
N19923834: C289.1 U1.J19(CAP_VDDRAM_CORE4)
N19923844: C293.1 U1.L9(CAP_VDDRAM_CORE3)
N19923851: C298.1 U1.Y14(CAP_VBBLDO_GPU)
N19923852: C297.1 U1.Y13(CAP_VDDRAM_GPU)
N19923853: C296.1 U1.T20(CAP_VDDRAM_CORE1)
N20127658: C403.1 R907.1(P1) R908.1(P1) U1.AB15(VDD_RTC)
N20128389: C404.1 R909.1(P1) R910.1(P1) U1.AB13(VDDA_RTC)
N20144297: R637.2(P2) U89.A9(MSEL)
N20190363: C454.2 J40.2 R639.4(SENS2)
N20190375: C454.1 J40.1 R639.3(SENS1)
N20190748: C455.2 J41.1 R640.3(SENS1)
N20190772: C455.1 J41.2 R640.4(SENS2)
N20190931: C456.2 J42.1 R641.3(SENS1)
N20190955: C456.1 J42.2 R641.4(SENS2)
N20191205: C457.2 J43.1 R642.3(SENS1)
N20191229: C457.1 J43.2 R642.4(SENS2)
N20202943: TP21.1 U3.F8(REGEN1)
N20204529: R643.1(P1) U1.AC16(WAKEUP3)
N20275163: C460.1 U79.8(SS)
N20287248: R647.1(P1) R648.2(P2) U79.2(FB)
N20287275: R646.2(P2) U79.1(COMP)
N20287568: C463.1 R646.1(P1)
N20287584: D20.2(ANODE) L28.2 U79.5(SW)
N20301491: J52.A1 R649.1(P1) R650.2(P2)
N20338433: J52.B11 R654.1(P1) R655.2(P2)
N20537306: U44.2(A) U85.4(Y)
N20594970: R678.1(P1) U86.1(VEN)
N20595300: R679.1(P1) U79.3(EN)
N20619479: R680.2 R681.2 U86.2(ADJ)
N20631200: Q16.G(GATE) R114.2(P2) R116.2(P2)
N20664562: L22.1 U62.B1(L1#B1) U62.B2(L1#B2)
N20664572: C417.1 U62.A3(VINA) U62.B3(VINA1) U62.C4(P\S\) U62.D4(VSEL)
N20665027: L22.2 U62.D1(L2#D1) U62.D2(L2#D2)
N20706534: R554.2(P2) U65.7(B1)
N20706536: R555.2(P2) U65.6(B2)
N20706626: R477.1(P1) U65.2(A1)
N20706635: R483.1(P1) U65.3(A2)
N20721609: Q3.G(GATE) R247.2(P2) R251.2(P2)
N20721766: Q3.D(DRAIN) R242.1(P1)
N20721850: Q1.D(DRAIN) R239.1(P1)
N20722196: D16.3(G) R242.2(P2)
N20722199: Q5.D(DRAIN) R249.1(P1)
N20722204: D16.4(Y) R249.2(P2)
N20722213: D16.2(R) R239.2(P2)
N20722605: Q2.G(GATE) R243.1(P1) R246.2(P2)
N20722618: Q6.G(GATE) R254.2(P2) R256.2(P2)
N20722739: Q4.G(GATE) R248.2(P2) R252.2(P2)
N20722773: Q4.D(DRAIN) R244.1(P1)
N20722790: Q2.D(DRAIN) R240.1(P1)
N20722809: D17.3(G) R244.2(P2)
N20722811: Q6.D(DRAIN) R250.1(P1)
N20722815: D17.4(Y) R250.2(P2)
N20722821: D17.2(R) R240.2(P2)
N20723137: Q11.G(GATE) R599.2(P2) R600.1(P1)
N20723150: Q10.G(GATE) R594.2(P2) R595.2(P2)
N20723271: Q15.G(GATE) R590.2(P2) R591.2(P2)
N20723305: Q15.D(DRAIN) R589.1(P1)
N20723322: Q11.D(DRAIN) R596.1(P1)
N20723341: D18.3(G) R589.2(P2)
N20723343: Q10.D(DRAIN) R601.1(P1)
N20723347: D18.4(Y) R601.2(P2)
N20723353: D18.2(R) R596.2(P2)
N20723697: Q13.G(GATE) R514.1(P1) R597.2(P2)
N20723710: Q12.G(GATE) R515.2(P2) R598.2(P2)
N20723831: Q14.G(GATE) R592.2(P2) R593.2(P2)
N20723865: Q14.D(DRAIN) R603.1(P1)
N20723882: Q13.D(DRAIN) R604.1(P1)
N20723901: D19.3(G) R603.2(P2)
N20723903: Q12.D(DRAIN) R602.1(P1)
N20723907: D19.4(Y) R602.2(P2)
N20723913: D19.2(R) R604.2(P2)
N20729664: Q20.D(DRAIN) R699.1(P1)
N20729666: D22.4(Y) R699.2(P2)
N20729672: D22.2(R) R696.2(P2)
N20729903: Q21.G(GATE) R697.2(P2) R698.1(P1)
N20729915: Q20.G(GATE) R694.2(P2) R695.2(P2)
N20730029: Q22.G(GATE) R700.2(P2) R701.2(P2)
N20730054: Q22.D(DRAIN) R693.1(P1)
N20730079: Q21.D(DRAIN) R696.1(P1)
N20730095: D22.3(G) R693.2(P2)
N20730773: Q23.D(DRAIN) R708.1(P1)
N20730775: D23.4(Y) R708.2(P2)
N20730781: D23.2(R) R705.2(P2)
N20730789: Q24.G(GATE) R706.2(P2) R707.1(P1)
N20730805: Q23.G(GATE) R703.2(P2) R704.2(P2)
N20730910: Q25.G(GATE) R709.2(P2) R710.2(P2)
N20730936: Q25.D(DRAIN) R702.1(P1)
N20730961: Q24.D(DRAIN) R705.1(P1)
N20730985: D23.3(G) R702.2(P2)
N20962931: C421.1 R149.1(P1) R806.1(P1) U19.2(A)
N21013400: R662.2(P2) U1.B14(MCASP1_ACLKR)
N21013403: R663.2(P2) U1.J14(MCASP1_FSR)
N21013406: R664.2(P2) U1.G13(MCASP1_AXR2)
N21013409: R665.2(P2) U1.J11(MCASP1_AXR3)
N21036262: J21.4 R686.2(P2) R877.2(P2)
N21036269: J21.6 R688.2(P2) R878.2(P2)
N21036279: J21.8 R690.2(P2) R880.2(P2)
N21036281: J21.10 R691.2(P2) R879.2(P2)
N21036293: J21.12 R692.2(P2) R874.2(P2)
N21036295: J21.14 R732.2(P2) R875.2(P2)
N21036304: J21.16 R733.2(P2) R876.2(P2)
N21036311: J21.58 R689.2(P2)
N21036394: R689.1(P1) R925.1(P1) U1.P7(GPMC_CLK)
N21036619: J21.52 R734.2(P2)
N21099488: C265.1 U43.C2(VDDI)
N21180149: TP22.1 U1.B15(MCASP2_AXR0)
N21180152: TP23.1 U1.A15(MCASP2_AXR1)
N21306186: TP24.1 U89.B6(GPIO1)
N21306311: R567.1(P1) U89.A8(I2C_SCL)
N21306314: R585.1(P1) U89.B8(I2C_SDA)
N21307911: R586.1(P1) U89.K6(REFCLK)
N21605448: C545.1(POS) J50.1
N21620210: C197.1 R368.2(P2) U72.3(IP0)
N21620213: C198.1 R370.2(P2) U72.5(IP1)
N21620216: C199.1 R372.2(P2) U72.7(IP2)
N21620219: C200.1 R374.2(P2) U72.9(IP3)
N21620222: C201.1 R373.2(P2) U72.11(IP4)
N21620225: C202.1 R375.2(P2) U72.18(IP5)
N21620228: C203.1 R376.2(P2) U72.20(IP6)
N21620231: C204.1 R378.2(P2) U72.22(IP7)
N21685968: C548.1 R797.2(P2) U1.K14(RSVK14)
N21685998: J46.4 R638.1(P1) R798.2(P2)
N21984965: R429.1(P1) U78.2(A)
N21986708: J18.4(TDIS) R587.1(P1)
N21987254: J18.10(GND#10) R806.2(P2)
N22242148: R660.2(P2) U1.V2(UART3_RXD/GPIO5_18)
N22242162: R659.2(P2) U1.Y1(UART3_TXD/GPIO5_19)
N22688543: R428.2(P2) R835.2(P2) U96.2(A)
N22817064: J21.32 R838.2(P2) R846.2(P2)
N22817067: J21.34 R839.2(P2) R847.2(P2)
N22817070: J21.36 R840.2(P2) R848.2(P2)
N22817073: J21.38 R841.2(P2) R849.2(P2)
N22817076: J21.42 R842.2(P2) R850.2(P2)
N22817095: J21.44 R843.2(P2) R851.2(P2)
N22817104: J21.46 R844.2(P2) R852.2(P2)
N22817113: J21.48 R845.2(P2) R853.2(P2)
N22829911: C562.1 R854.2(P2) U3.K12(LDO4_OUT)
N22843188: J21.54 R855.2(P2) R929.2(P2)
N22843197: J21.56 R856.2(P2) R930.2(P2)
N22941894: J21.51 R857.1(P1) R871.1(P1)
N22941897: J21.53 R858.1(P1) R872.1(P1)
N22941900: J21.55 R859.1(P1) R873.1(P1)
N22942582: J21.31 R861.1(P1) R865.1(P1)
N22942589: J21.33 R862.1(P1) R866.1(P1)
N22942599: J21.35 R863.1(P1) R867.1(P1)
N22942601: J21.37 R864.1(P1) R868.1(P1)
N22982995: J21.26 R884.2(P2) R888.2(P2)
N22983025: J21.28 R885.2(P2) R889.2(P2)
N22983056: J21.30 R886.2(P2) R890.2(P2)
N22983147: J21.50 R887.2(P2) R891.2(P2)
N22983150: J21.18 R881.2(P2) R892.2(P2)
N22983153: J21.20 R882.2(P2) R893.2(P2)
N23040939: D24.2(CATHODE) Q26.1(BASE) R894.1(P1) R895.1(P1)
N23040957: D24.1(REF) R895.2(P2) R896.1(P1) R897.2(P2)
N23041291: D25.2(CATHODE) Q27.1(BASE) R898.1(P1) R899.1(P1)
N23041299: D25.1(REF) R899.2(P2) R900.1(P1) R901.2(P2)
N23074888: J21.57 R860.1(P1)
N23239351: R902.1(P1) X1.1(EN)
N23239414: J9.23 R903.1(P1)
N23403418: C4.1 R10.1(P1) R12.1(P1) U2.2(A)
N23403425: R12.2(P2) SW1.3 SW1.4 U49.1
N23403875: R9.2(P2) U98.1(A)
N23404270: R912.1(P1) U2.4(Y) U98.2(B)
N23423235: R487.2(P2) U100.8(A1)
N23423238: R486.2(P2) U100.9(A2)
N23520464: C583.1 R927.1(P1) U105.4(CT)
N23520486: TP27.1 U105.3(M\R\)

Pads without a net: J3 7; J5 7; J6 7; J8 7; J9 10 14; J10 2; J12 2; J14 1 2 4 7 9; J16 1 2 6 31 32; J18 6 17 18 19; J19 4; J24 14; J37 18; J38 5; J52 A19 A25 A26 A29 A30 A32 B12 B17 B23 B24 B27 B28 B30; NOREF 1; NOREF#2 1; NOREF#4 1; NOREF#5 1; NOREF#6 1; NOREF#7 1; NOREF#9 1; NOREF#10 1; NOREF#11 1; NOREF#14 1; NOREF#15 1; NOREF#16 1; NOREF#17 1; NOREF#22 1; NOREF#23 1; NOREF#24 1; NOREF#26 1; NOREF#29 1; NOREF#30 1; NOREF#31 1; NOREF#32 1; NOREF#33 1; NOREF#34 1; NOREF#36 1; NOREF#37 1; NOREF#38 1; NOREF#39 1; NOREF#40 1; NOREF#41 1; NOREF#42 1; NOREF#43 1; NOREF#44 1; NOREF#45 1; NOREF#46 1; NOREF#47 1; U1 A20 A27 AA1 AA2 AA4 AB1 AB2 AB3 AB16 AC1 AC2 AC13 AC17 AD2 AD3 AD8 AD9 AD18 AE1 AE2 AE3 AE5 AE6 AE8 AE9 AF1 AF2 AF3 AF4 AF6 AF8 AF9 AG2 AG3 AG4 AG5 AG6 AG7 AG8 AG9 AG10 AG11 AG12 AH3 AH4 AH5 AH6 AH7 AH9 AH10 AH11 AH12 B28 E15 E24 E26 E27 E28 F24 F25 F26 F27 F28 G16 G22 G23 G24 G25 G26 G27 G28 H20 H21 H22 H23 H24 H25 H26 H27 H28 J20 J21 J22 J23 J24 J25 J26 J27 K20 K21 K22 K23 K27 K28 L20 L21 L22 L23 L24 L25 L26 L27 L28 M20 M21 M22 M23 M24 M25 M26 M27 M28 N20 N21 N22 N23 N27 N28 P19 P22 P23 P24 P25 P26 P27 R20 R22 R23 R24 R25 R26 R27 R28 T22 T23 T27 T28 U18 U19 U22 U23 U24 U25 U26 U27 U28 V18 V19 Y5 Y10 Y15 Y16; U2 1; U3 B4 C9 K4 K5 K8 L4 N12; U4 4 5 6 11 12 13; U5 J1 J9 L1 L9 M7; U6 J1 J9 L1 L9 M7; U7 J1 J9 L1 L9 M7; U9 22; U13 22; U15 22; U17 22; U19 1; U21 45; U22 1; U23 2 4; U24 45; U25 2 4; U26 1; U28 1; U30 4 9; U36 2; U37 22 24 27 29 33 34 40 41 43 44 45 46 48 52 53 54 55 57 58; U39 1; U40 10; U43 A1 A2 A6 A7 A8 A9 A10 A11 A12 A13 A14 B1 B7 B8 B9 B10 B11 B12 B13 B14 C1 C3 C5 C7 C8 C9 C10 C11 C12 C13 C14 D1 D2 D3 D4 D12 D13 D14 E1 E2 E3 E5 E8 E9 E10 E12 E13 E14 F1 F2 F3 F10 F12 F13 F14 G1 G2 G3 G10 G12 G13 G14 H1 H2 H3 H5 H12 H13 H14 J1 J2 J3 J5 J12 J13 J14 K1 K2 K3 K6 K7 K10 K12 K13 K14 L1 L2 L3 L12 L13 L14 M1 M2 M3 M7 M8 M9 M10 M11 M12 M13 M14 N1 N3 N6 N7 N8 N9 N10 N11 N12 N13 N14 P1 P2 P7 P8 P9 P10 P11 P12 P13 P14; U45 8 13 15 23 24 25 26 27 28 29 30 31 32; U47 1; U52 1 2; U72 4 6 8 10 12 16 17 19 21 27; U74 10; U76 4; U78 1; U89 A6; U93 5; U96 1; U97 1; U99 1; U102 3 5 7 10 12 14 16 20 22 24 26 28 55 56; U103 3 5 7 10 12 14 16 20 22 24 26 28 55 56; U104 5 6 7 9 10 11 12 13 14; Y1 2 4; Y2 2 4; Y6 2 3

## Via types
v1: diameter 0.279, hole 0.127, TOP to L2_GND1, 518 vias
v2: diameter 0.457, hole 0.203, TOP to L2_GND1, 612 vias
v3: diameter 0.457, hole 0.203, L2_GND1 to L3_SIG1, 613 vias
v4: diameter 0.279, hole 0.127, L2_GND1 to L3_SIG1, 519 vias
v5: diameter 0.457, hole 0.203, L3_SIG1 to L10_SIG4, 920 vias
v6: diameter 0.457, hole 0.203, L10_SIG4 to L11_GND4, 445 vias
v7: diameter 0.457, hole 0.203, L11_GND4 to BOTTOM, 447 vias
v8: diameter 0.457, hole 0.203, TOP to BOTTOM, 761 vias
v9: diameter 0.508, hole 0.254, TOP to BOTTOM, 1562 vias
v10: diameter 0.279, hole 0.127, L10_SIG4 to L11_GND4, 360 vias
v11: diameter 0.279, hole 0.127, L11_GND4 to BOTTOM, 363 vias

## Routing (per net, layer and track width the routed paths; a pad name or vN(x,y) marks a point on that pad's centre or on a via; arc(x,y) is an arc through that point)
AGND_GBETH0: length 8.5
  BOTTOM w0.508: 40.28,137.35 J10.SHLD1 ; J10.SHLD1 42.28,137.35 ; J10.SHLD1 42.28,139.35 ; 24.77,139.35 J10.SHLD2 ; J10.SHLD2 26.78,137.35 ; J10.SHLD2 24.77,137.35
AGND_GBETH1: length 8.5
  BOTTOM w0.508: J12.SHLD1 64,139.35 ; J12.SHLD1 64,137.35 ; J12.SHLD1 61.99,137.35 ; 46.49,139.35 J12.SHLD2 ; J12.SHLD2 46.49,137.35 ; J12.SHLD2 48.5,137.35
AGND_PROFI: length 12
  TOP w0.381: R573.2 v9(105.79,7.75) v9(104.77,7.75)
  BOTTOM w0.508: 79.86,4.59 J14.11 83.44,4.59 ; 108.44,4.59 J14.10 104.85,4.59
AGNDFRAME_PRU1ETH0: length 8.5
  BOTTOM w0.508: J3.SHLD1 14.85,137.68 ; J3.SHLD1 12.85,139.69 ; J3.SHLD1 14.85,139.69 ; J3.SHLD2 14.85,121.93 ; J3.SHLD2 14.85,123.94 ; J3.SHLD2 12.85,121.93
AGNDFRAME_PRU1ETH1: length 8.5
  BOTTOM w0.508: J5.SHLD2 14.85,97.8 ; J5.SHLD2 14.85,99.81 ; J5.SHLD2 12.85,97.8 ; J5.SHLD1 14.85,113.55 ; J5.SHLD1 12.85,115.56 ; J5.SHLD1 14.85,115.56
AGNDFRAME_PRU2ETH0: length 8.5
  BOTTOM w0.508: J6.SHLD2 14.85,73.67 ; J6.SHLD2 12.85,73.67 ; J6.SHLD2 14.85,75.68 ; 12.85,91.43 J6.SHLD1 ; J6.SHLD1 14.85,89.42 ; J6.SHLD1 14.85,91.43
AGNDFRAME_PRU2ETH1: length 8.5
  BOTTOM w0.508: J8.SHLD2 14.85,50.91 ; J8.SHLD2 12.85,48.91 ; J8.SHLD2 14.85,48.91 ; J8.SHLD1 14.85,64.66 ; J8.SHLD1 14.85,66.66 ; J8.SHLD1 12.85,66.66
DGND: length 2422.4
  TOP w0.203: v9(147.57,69.98) 147.94,70.34 U100.10 ; v9(174.88,74.6) 174.59,74.32 U65.5 ; v3(134.62,131.4) 134.62,131.17 134.65,131.14 U3.A1 ; v9(136.9,132.89) 136.9,132.78 136.91,132.77 136.91,131.28 137.05,131.14 U3.A4 ; U100.2 149.55,69.52 v9(149.86,69.22) ; 157.28,82.3 157.69,81.89 U37.5 ; v9(151.13,70.03) 150.82,70.34 U100.3 ; U3.A7 v3(139.45,131.29)
  TOP w0.254: U5.D8 v8(87.98,35.88) ; U5.A9 v8(88.78,38.28) ; U8.4 107.32,16.98 107.11,17.2 106.88,17.2 106.43,17.65 C100.2 ; U1.E19 v4(110.23,77.62) ; U1.G7 v4(108.63,88.01) ; U21.13 31.03,123.61 v9(30.61,124.03) ; U36.4 v9(181.77,12.81) ; U102.38 140.63,84.11 v9(140.46,83.95) ; U6.E1 v8(112.86,35.08) ; U1.H12 v4(107.83,84.01) ; U1.M19 v4(104.63,77.62) ; U1.R12 v4(101.44,84.01) ; U1.T10 v4(100.64,85.61) ; U1.K25 v4(106.23,72.82) ; U3.E8 v3(139.85,127.93) ; U7.D8 v8(103.22,35.88) ; U6.D3 v8(115.26,35.88) ; v9(159.94,81.41) 159.94,81.54 159.59,81.89 U37.5 ; U1.T21 v4(100.64,76.02) ; U1.T14 v4(100.64,82.41) ; U3.E9 v3(141.44,127.93) ; U3.K3 v3(136.64,123.14) ; U1.N15 v4(103.83,80.82) ; U3.H7 v3(139.84,125.53) ; U37.10 157.9,79.39 v9(157.53,79.76) ; U5.B3 v8(84.78,37.48) ; U1.W28 98.2,70.38 v4(98.2,69.87) ; U37.47 v9(168.66,83.39) ; v9(107.82,14.73) U8.8 ; U3.C1 v3(134.25,129.53) ; U1.T18 v4(100.64,78.42) ; U3.F9 v8(141.44,126.34) ; U3.N1 v3(134.25,120.74) ; U3.L7 v3(139.05,122.34) ; U7.F9 v8(104.82,34.28) ; U1.D13 v4(111.03,83.21) ; U1.AC14 v4(95.04,82.41) ; U1.L13 v4(105.43,83.21) ; U7.G1 v8(97.62,33.48) ; U1.AH20 v4(91.04,76.82) ; v4(94.24,83.21) 94.33,83.12 94.33,83.08 94.55,82.87 94.58,82.87 U1.AD13 ; U1.G8 v4(108.63,87.21) ; U7.G9 v8(104.02,33.48) ; U37.11 v9(157.53,78.89) ; U103.19 v9(135.09,99.6) ; U3.G5 v3(137.45,125.54) ; U1.AE13 94.06,82.59 94.08,82.59 v4(94.16,82.51) ; U6.A9 v8(120.06,38.28) ; v8(120.45,27.41) 120.38,27.48 U6.P9 ; U1.K5 v4(106.23,89.61) ; U3.C3 v3(135.85,129.53) ; U5.B9 v8(89.74,37.08) ; v4(91.82,93.05) 92.24,92.63 U1.AG1 ; U7.J8 v8(104.02,31.88) ; U3.F4 v3(136.65,127.13) ; U24.13 52.75,123.61 v9(52.32,124.03) ; U1.T11 v4(100.64,84.81) ; 98.49,150.6 J15.13 ; v4(91.89,87.22) 91.84,87.22 U1.AH8 ; U5.P1 v8(82.21,27.48) ; U1.U15 v4(99.84,80.82) ; U5.T1 v8(82.21,25.88) ; U1.N24 v4(103.83,73.62) ; U3.G7 v3(139.05,125.54) ; U5.E2 v8(83.98,35.08) ; U6.D8 v8(118.46,35.88) ; U1.N19 v11(103.83,77.62) ; U24.29 56.15,120.11 v9(56.9,120.86) ; J15.14 83.32,150.63 ; U1.A23 v4(113.43,74.42) ; U3.D10 v3(142.24,128.73) ; U3.D4 v3(136.65,128.73) ; U5.M1 v8(82.21,29.08) ; U6.F9 v8(120.06,34.28) ; v9(7.75,39.88) 7.53,40.09 U93.4 ; U3.A13 144.53,131.02 v3(144.53,131.53) ; U6.P1 v8(112.69,27.48) ; U1.W1 v4(98.64,93.15) ; U5.P9 v8(89.74,27.48) ; U1.AD10 v4(94.24,85.61) ; v9(167.07,84.22) 167.14,84.29 U37.51 ; U1.E13 v4(110.23,83.21) ; U7.B9 v8(104.82,37.48) ; U1.R21 v4(101.44,76.02) ; U1.A1 v4(113.43,92.81) ; U1.P28 v4(103.03,70.42) ; U5.M9 v8(89.74,29.08) ; U6.E2 v8(114.46,35.08) ; U1.AD19 v4(94.24,77.62) ; U3.L6 v3(138.25,122.34) ; U3.L9 v3(140.65,122.34) ; U3.E10 v3(142.24,127.93) ; U3.N2 v3(135.05,120.74) ; v9(168.88,77.32) 168.95,77.39 U37.35 ; U37.15 v9(159.82,76.89) ; U1.AB14 v4(95.84,82.41) ; U6.M9 120.14,29.08 v8(120.27,29.21) ; U1.AA10 v4(96.64,85.61) ; U7.E1 97.62,35.08 v8(97.61,35.08) ; U3.J4 v3(136.65,123.94) ; U6.B9 v8(120.06,37.48) ; U1.V17 v11(99.04,79.22) ; U1.N14 v4(103.83,82.41) ; U5.G9 v8(88.78,33.48) ; U1.G9 v4(108.63,86.41) ; U103.8 v9(135.09,105.1) ; U3.D6 v3(138.25,128.73) ; U3.F5 v3(137.45,126.34) ; U5.J2 v8(83.18,31.88) ; U5.D1 v8(83.18,35.88) ; U7.B3 v8(100.02,37.48) ; U1.W15 v4(98.24,80.82) ; U3.G4 v3(136.65,125.54) ; U6.E8 v8(118.46,35.08) ; U1.AA9 v4(96.64,86.41) ; U1.AA11 v4(96.64,84.81) ; U3.D5 v3(137.45,128.73) ; U1.R15 v4(101.44,80.82) ; U102.8 v9(135.09,89.61) ; U6.B1 v8(113.66,37.48) ; U102.19 v9(135.09,84.11) ; U3.L5 v3(137.45,122.34) ; v9(35.18,120.86) 34.43,120.11 U21.29 ; U6.D1 v8(113.66,35.88) ; U1.L14 v4(105.43,82.41) ; U1.K24 v4(106.23,73.62) ; U1.AB11 v4(95.84,84.81) ; U1.AH2 v4(90.91,92.14) ; U1.U17 v11(99.84,79.22) ; U3.F6 v3(138.25,127.13) ; v9(159.84,77.96) 159.78,77.89 U37.13 ; U1.T15 v4(100.64,80.82) ; U1.J15 v11(107.03,80.82) ; U6.B3 v8(115.26,37.48) ; U7.P9 v8(104.98,27.48) ; U5.B1 v8(83.18,37.48) ; U1.A14 v4(113.43,82.41) ; U1.AB20 v4(95.84,76.82) ; U1.F1 v4(109.04,93.15) ; U3.E4 v3(136.65,127.93) ; U1.AD1 94.64,93.49 94.7,93.55 v4(94.7,93.58) ; U3.J9 v8(141.44,123.94) ; U6.T1 v8(112.69,25.88) ; U7.E8 v8(103.22,35.08) ; U5.E1 v8(82.21,34.68) ; U6.C7 v8(117.66,36.68) ; U3.C2 v3(135.05,129.53) ; U7.M1 v8(97.45,29.08) ; U1.B1 v4(112.23,92.98) ; U1.V15 v4(99.04,80.82) ; U3.H10 v3(142.24,124.74) ; U3.M2 v3(135.05,121.54) ; U3.H4 v3(136.65,124.74) ; v4(105.79,93.17) 105.83,93.13 U1.K1 ; U6.G8 v8(118.46,33.48) ; U6.G1 v8(112.86,33.48) ; U1.AH28 v4(91.04,70.42) ; U3.J6 v3(139.04,124.73) ; U1.AA15 v11(96.64,80.82) ; U3.E7 v3(139.05,127.93) ; U7.D1 v8(98.42,35.88) ; U3.J10 v3(142.24,123.94) ; U1.W24 v4(98.24,73.62) ; U37.25 v9(164.64,75.57) ; U1.K4 v4(106.23,90.41) ; U1.U21 v4(99.84,76.02) ; U3.D7 v3(139.05,128.73) ; U7.G8 v8(103.22,33.48) ; U7.B1 v8(98.42,37.48) ; U1.AD24 v4(94.24,73.62) ; U1.AA8 v4(96.64,87.21) ; U1.A2 v4(113.43,92.01) ; U1.A6 v4(113.43,88.81) ; U7.M9 v8(104.98,29.08) ; U103.38 v9(140.5,99.6) ; U1.N25 v4(103.83,72.82) ; U7.T9 v8(104.98,25.88) ; U1.W25 v4(98.24,72.82) ; U102.49 v9(140.5,89.61) ; U1.AE10 v4(93.5,85.55) ; U1.AH1 v4(90.91,92.94) ; U6.T9 v8(120.27,25.88) ; U3.H5 v3(137.45,124.74) ; U3.B2 v3(135.05,130.33) ; U1.U14 v4(99.84,82.41) ; U5.E8 v8(87.98,35.08) ; U3.F7 v3(139.05,126.34) ; U103.49 v9(140.5,105.1) ; U7.P1 v8(97.45,27.48) ; U3.C12 v3(143.84,129.53) ; U3.M1 v3(134.25,121.54) ; U1.J28 106.71,70.74 v4(106.71,70.34) ; U1.F7 v4(109.43,88.01) ; U1.T17 v4(100.64,79.22) ; U1.AA14 v4(96.64,82.41) ; U3.L8 v8(139.85,123.13) ; U3.F10 v8(142.24,126.34) ; U1.T12 v4(100.64,84.01) ; U1.AA20 v4(96.64,76.82) ; U7.A9 v8(104.02,38.28) ; U3.H6 v3(138.25,124.74) ; U1.A28 v4(113.43,70.42) ; U5.T9 v8(89.74,25.88) ; U1.AE19 v4(93.44,77.62) ; U7.T1 v8(97.45,25.88) ; U5.G8 v8(87.98,33.48) ; U6.G9 v8(119.26,33.48) ; U3.G10 v3(142.24,125.54) ; U6.M1 v8(112.69,29.08) ; U1.R1 v4(101.83,93.15) ; U3.L10 v3(141.45,122.34) ; U5.J8 v8(88.78,31.88) ; U1.U20 v4(99.84,76.82) ; U1.D19 v4(111.03,77.62) ; U6.J8 v8(119.26,31.88) ; U3.B10 v3(142.24,130.33) ; U6.J2 v8(114.46,31.88) ; U1.R13 v4(101.44,83.21) ; U5.F9 v8(89.74,33.88) ; U1.K15 v4(106.23,80.82) ; U3.B8 v8(140.64,130.33) ; U3.B11 v3(143.04,130.33) ; U1.J12 v4(107.03,84.01) ; U7.J2 v8(99.22,31.88) ; U5.G1 v8(82.21,33.08) ; U7.E2 v8(99.22,35.08)
  TOP w0.279: J24.5 v9(65.15,7.09) ; J24.17 59.15,7.33 v9(58.8,6.99) ; U46.19 v9(64.97,16.37) ; J24.8 v9(63.65,7.09) ; J24.2 v9(66.65,7.09) ; v9(65.28,19.81) 64.97,20.12 U46.6 ; J24.11 v9(62.15,7.09) ; v9(61.21,13.34) 61.72,13.85 U46.14
  TOP w0.33: R922.1 96.01,102.29 v9(96.27,102.03)
  TOP w0.381: U28.3 178.29,60.02 v9(178.29,60.03) ; R341.2 61.72,126.32 v9(61.47,126.57) ; C186.2 63.5,122.25 v9(63.63,122.38) ; R108.1 v3(23.88,116.84) ; C244.2 v9(155.5,83.95) ; J15.6 v9(84.55,149.04) ; C33.2 v9(91.17,18.92) ; C33.2 v9(92.31,17.78) ; C33.2 v9(91.17,16.64) ; R109.1 24,114.81 v3(24.64,114.81) ; C52.2 v9(101.2,19.05) ; C52.2 v9(100.06,20.19) ; C52.2 v9(100.06,17.91) ; 177.93,17.4 v9(176.39,17.4) ; C261.2 v9(102.23,128.73) ; C547.2 v9(9.27,41.99) ; C232.2 168.29,89.2 168.83,89.2 v9(168.92,89.29) ; v9(22.61,117.43) 22.86,117.68 C105.2 ; v9(20.19,119.72) 20.7,120.22 20.7,120.35 ; v9(177.55,87.12) 177.93,87.5 J18.8 ; R103.1 24.13,121.11 v3(24.64,121.62) ; R38.2 v9(108.33,36.77) ; J52.A18 v9(49.39,36.9) ; R430.2 v3(144.02,137.16) ; J52.B26 v9(57.39,26.92) ; v9(174.12,85.34) 174.5,84.96 R587.2 ; C462.2 163.48,126.64 v9(163.48,127.06) ; C462.2 162.49,126.37 v9(162.49,127.06) ; C462.2 v9(163.99,126.01) ; v9(154.94,115.91) 154.94,116.54 154.51,116.97 ; Q9.S 75.3,149.83 v9(74.68,150.45) ; R317.1 v9(38.28,115.22) ; 154.51,116.97 v9(155.52,116.97) ; 154.51,116.97 C278.2 153.75,116.54 v9(153.75,115.91) ; C195.2 v9(180.28,54.44) ; C176.2 v9(67.31,106.38) ; 56.26,52.45 55.42,52.45 v9(54.99,52.02) ; v9(27.41,117.71) 27.09,118.02 C110.2 ; J52.A23 v9(54.39,36.9) ; J52.B29 v9(60.39,26.92) ; C27.1 v3(140.34,137.24) ; J52.B25 v9(56.39,26.92) ; v9(159.39,89.29) C235.2 ; U76.2 v9(149.53,100.16) ; J52.A24 v9(55.39,36.9) ; R361.1 v9(59.56,114.25) ; C578.2 v9(150.11,74.8) ; U50.2 v9(148.54,51.39) ; v9(63.81,128.53) C179.2 v9(63.81,125.61) ; J52.A15 v9(46.39,36.9) ; v9(50.29,121.37) 49.66,122 C174.2 ; U105.2 v9(152.53,113.41) ; SW1.2 171.29,46.15 v9(171.83,46.69) ; J52.B4 v9(33.39,26.92) ; v9(111,8.91) C88.2 v9(108.71,8.91) ; C461.2 162.31,119.15 v9(162.31,118.57) ; C461.2 163.45,119.09 v9(163.45,118.57) ; C461.2 v9(164.08,119.69) ; R835.1 v9(146.3,139.75) ; C264.2 v9(101.47,126.95) ; R494.1 v3(164.13,90.05) ; SW1.1 163.84,46.31 v9(161.8,46.31) ; v9(43.64,129.57) C158.2 v9(46.56,129.57) ; R304.1 v9(36.88,115.22) ; J52.A27 v9(58.39,36.9) ; R791.2 v9(17.91,47.58) ; v9(161.06,117.96) 161.07,117.97 R648.1 ; v9(91.7,113.74) 92.33,113.11 92.33,111.71 ; v3(143.84,121.54) 144.23,121.94 U3.M13 ; v3(143.84,121.54) U3.N13 v3(144.64,120.74) ; v3(143.84,121.54) U3.M12 ; U44.3 v9(41.39,41.69) ; C303.2 v9(29.46,23.88) ; SW3.2 v9(156.34,55.42) SW3.1 ; J52.B31 v9(62.39,26.92) ; C263.2 v9(101.47,131.53) ; J52.B18 v9(49.39,29.72) ; J52.B16 v9(47.39,26.92) ; U85.3 v9(41.36,49.04) ; C484.2 v3(155.7,101.05) ; v9(76.96,86.56) 77.08,86.44 C247.2 ; C577.2 v9(148.72,74.8) ; J52.B7 v9(36.39,26.92) ; C425.2 v9(171.07,73.15) ; R793.1 v9(123.19,43.9) ; R348.1 v9(58.17,114.25) ; C427.2 v9(59.89,22.86) ; R37.2 R32.2 v9(125.22,41.32) ; R37.2 v9(126.03,39.5) ; R37.2 R34.2 ; C243.2 v9(155.5,85.09) ; R104.1 v3(24.64,113.79) ; v9(110.49,18.16) 110.11,17.78 C90.2 ; J18.12 177.67,90.04 v9(177.55,89.92) ; 182.75,17.4 184.43,17.4 184.56,17.27 v9(184.57,17.27) ; R542.1 v9(34.42,40.39) ; J52.B21 v9(52.39,26.92) ; C177.2 v9(75.18,108.79) ; U83.2 163.82,11.3 v9(164.47,11.3) ; C238.2 154.28,78.36 v9(154.22,78.43) ; J52.B22 v9(53.39,26.92) ; v9(76.2,73.81) 75.59,73.81 R643.2 ; C470.2 v9(40.87,44.55) ; C28.2 99.42,124.67 v9(99.44,124.69) ; J52.A31 v9(62.39,36.9) ; v9(159.64,112.27) C583.2 ; C246.2 v9(77.72,90.38) ; R110.1 v3(24.64,111.51) ; R111.1 v3(24.64,112.65) ; v3(159.89,93.47) C241.2 v3(160.87,92.54) ; R319.1 27.58,123.68 v9(27.58,123.32) ; U94.1 v9(22.73,45.93) ; v9(42.55,122.51) C165.2 ; R921.2 v9(66.42,80.39) ; R571.2 v9(147.83,113.54) ; C181.2 v9(49.66,117.18) ; R425.2 v3(145.16,137.24) ; C109.2 23.11,119.72 22.86,119.97 v9(22.61,119.97) ; U96.3 v9(148.07,140.07) ; J18.16 v9(177.55,92.58) ; J52.B32 v9(63.39,26.92) ; C407.2 v9(146.92,101.05) ; SW2.1 v9(167.51,55.42) SW2.2 ; U47.3 v9(123.32,45.58) ; R33.2 v9(108.33,41.21) ; v9(38.61,102.36) R157.1 R158.1 ; R539.2 v9(38.35,23.11) ; C460.2 v9(156.18,119.25) ; R156.1 v9(41.27,104.01) ; R155.1 v9(38.61,103.76) ; R561.1 v9(56.52,13.76) ; v9(55.63,47.2) R550.2 ; J19.5 v9(184.94,15.7) ; C575.2 v9(129.16,47.62) ; v9(159.42,119.27) 159.42,119.32 159.38,119.36 U79.4 ; v9(178.45,14.99) U101.1 ; C308.2 v9(48.01,51.64) ; C463.2 159.51,115.48 v9(159.51,115) ; R298.2 41.73,124.54 v9(42.44,125.25) ; R321.1 v9(27.94,120.35) ; U82.2 v9(160.28,10.67) ; R34.2 R39.2 v9(125.22,36.66) ; R34.2 v9(126.03,38.48) ; J52.A12 v9(43.39,36.9) ; J18.20 v9(177.55,95.12) ; C428.2 v9(69.22,12.34) ; v9(173.48,81.53) C233.2 ; R13.2 69.22,82.34 67.98,82.34 v9(67.56,82.76) ; R35.2 v9(107.63,39.5) ; v9(98.92,132.92) C479.2 v9(100.08,131.78) ; R433.1 174.88,83.69 v9(174.12,84.45) ; J52.B13 v9(44.39,29.72) ; C429.2 v9(58.76,14.75) ; v3(141.48,137.24) C301.2 ; C262.2 v9(102.23,129.75) ; J52.A4 v9(33.39,36.9) ; C304.2 v9(31.5,40.39) ; C420.2 v9(172.97,76.92) ; R363.1 v9(49.66,124.8) ; v9(181.1,2.54) C224.2 v9(182.26,3.7) ; J52.A20 v9(51.39,36.9) ; J52.A28 v9(59.39,36.9) ; R40.2 v9(107.63,38.48) ; C242.1 v9(180.72,9.91) ; R147.1 v9(24.77,97.74) ; C469.2 v9(43.54,38.1)
  TOP w0.508: v9(30.43,114.5) C156.2 v9(27.94,114.5) ; v9(134.75,6.22) 134.57,6.4 C435.2 v9(131.5,6.4) ; R579.1 v9(130.68,10.95) ; U74.3 v9(128.6,6.35) ; v9(125.63,30.3) 125.43,30.1 124.59,30.1 ; R187.1 R194.1 R193.1 ; v9(33.63,94.16) 33.86,93.93 C123.2 ; 185.67,113.62 J2.2 ; J2.2 187.28,113.62 ; J2.2 187.28,115.23 ; J2.2 185.67,115.23 ; J15.9 v9(86.36,137.65) ; J15.11 v9(99.15,140) ; C53.2 v9(108.46,31.24) ; R44.1 v9(110.11,30.1) ; 180.76,113.24 J1.3 ; J1.3 183.72,113.24 ; J1.3 183.72,110.28 ; J1.3 180.76,110.28 ; C82.2 v9(93.22,31.24) ; R237.1 R238.1 37.85,57.74 ; R236.1 R235.1 v9(37.85,63.07) ; v9(94.26,138.13) 94.26,137.2 J15.15 ; R798.1 v9(164.47,3.89) ; v9(89.41,137.24) 89.31,137.15 J15.16 ; C99.2 v9(104.52,11.81) ; v9(145.16,13.65) 145.16,13.34 144.67,12.84 Q16.S ; C46.2 v9(94.87,28.96) ; v9(83.59,142.7) 83.59,141.35 J15.12 ; v9(37.85,87.84) R191.1 R192.1 ; C45.2 v9(77.98,31.24) ; v9(51.84,111.22) C175.2 v9(49.37,111.22) ; U84.2 97.19,134.54 v9(97.56,134.17) ; C91.2 111,19.32 v9(111,20.45) ; 124.59,28.7 v9(125.35,28.7) ; C86.2 v9(112.41,16.26) ; 83.32,150.63 v9(81.69,150.63) ; C147.2 35,52.28 34.34,51.62 v9(33.63,51.62) ; C64.2 v9(115.3,17.91) ; C64.2 v9(115.3,20.19) ; C64.2 v9(116.44,19.05) ; C144.2 v9(32.5,52.28) ; C142.2 v9(25.53,56.23) ; v9(35.81,77.04) C135.2 ; C93.2 109.98,23.37 v9(110.36,22.99) ; C137.2 v9(25.53,80.99) ; C118.2 v9(25.53,98.77) ; 177.51,118.04 J1.2 ; J1.2 180.47,115.08 ; J1.2 180.47,118.04 ; J1.2 177.51,115.08 ; C101.2 v9(103.37,16.26) ; 98.49,150.6 99.69,150.6 v9(99.87,150.42) ; C83.2 v9(110.11,28.7) ; U40.1 v9(159.51,19.64) ; C130.2 v9(31.75,76.28) ; R41.1 v9(94.87,30.1) ; C432.2 v9(130.56,6.6) ; C120.2 v9(32.5,94.82) ; R48.1 v9(112.41,13.97) ; v9(160.06,14.61) C249.2 ; C316.2 v9(139.1,12.27) ; R116.1 v9(140.34,11.43)
  L2_GND1 w0.508: J44.2 84.37,108.62 ; J44.2 82.76,108.62 ; J44.2 82.76,110.23 ; J44.2 84.37,110.23 ; J21.39 140.04,147.72 ; J21.39 138.65,147.72 ; J21.39 138.65,146.32 ; J21.39 140.04,146.32 ; U18.M2 143.14,27 ; U18.M2 143.14,29.3 ; U18.M2 140.84,27 ; U18.M2 140.84,29.3 ; 170.92,140.46 J9.12 ; J9.12 172.54,140.46 ; J9.12 172.54,138.85 ; J9.12 170.92,138.85 ; J24.MTG3 55.35,1.79 ; J24.MTG3 55.35,3.41 ; J24.MTG3 53.74,1.79 ; J24.MTG3 53.74,3.41 ; 177.51,115.08 J1.2 ; J1.2 180.47,115.08 ; J1.2 180.47,118.04 ; J1.2 177.51,118.04 ; J9.11 172.54,137.92 ; J9.11 172.54,136.31 ; J9.11 170.92,136.31 ; J9.11 170.92,137.92 ; J1.3 183.72,113.24 ; J1.3 183.72,110.28 ; J1.3 180.76,110.28 ; J1.3 180.76,113.24 ; 52.66,69.55 J7.5 ; J7.5 54.27,71.16 ; J7.5 52.66,71.16 ; J7.5 54.27,69.55 ; 60.24,133.23 J12.1 ; J12.1 60.24,131.79 ; J12.1 61.68,133.23 ; J12.1 61.68,131.79 ; 18.97,101.52 J5.8 ; J5.8 18.97,102.95 ; J5.8 20.41,101.52 ; J5.8 20.41,102.95 ; J37.30 188.24,24.26 ; J37.30 186.72,22.73 ; J37.30 188.24,22.73 ; J37.30 186.72,24.26 ; J53.2 185.82,67.79 ; J53.2 185.82,65.56 ; J53.2 183.6,65.56 ; J53.2 183.6,67.79 ; 18.97,127.08 19.69,126.36 ; 19.69,126.36 20.41,127.08 ; 19.69,126.36 20.41,125.65 ; 19.69,126.36 18.97,125.65 ; J12.13 62.73,143.18 ; J12.13 61.21,144.7 ; J12.13 62.73,144.7 ; 170.71,65.18 J53.1 ; J53.1 170.71,68.17 ; J53.1 173.71,68.17 ; J53.1 173.71,65.18 ; J24.MTG1 55.95,6.69 ; J24.MTG1 54.34,6.69 ; J24.MTG1 54.34,8.31 ; J24.MTG1 55.95,8.31 ; TP8.1 81.07,150.67 ; TP8.1 79.46,150.67 ; TP8.1 81.07,149.05 ; TP8.1 79.46,149.05 ; 47.76,146.73 J12.12 ; J12.12 47.76,145.21 ; J12.12 49.28,146.73 ; J12.12 49.28,145.21 ; J21.22 122.04,149.72 ; J21.22 120.65,149.72 ; J21.22 122.04,148.32 ; J21.22 120.65,148.32 ; J10.1 39.96,131.79 ; J10.1 38.53,133.23 ; J10.1 39.96,133.23 ; J10.1 38.53,131.79 ; J10.12 27.57,146.73 ; J10.12 27.57,145.21 ; J10.12 26.04,146.73 ; J10.12 26.04,145.21 ; 18.97,54.06 J8.8 ; J8.8 20.41,54.06 ; J8.8 18.97,52.63 ; J8.8 20.41,52.63 ; 45.86,13.68 J23.4 ; J23.4 47.22,13.68 ; J23.4 45.86,12.33 ; J23.4 47.22,12.33 ; U18.M1 143.14,19.2 ; U18.M1 140.84,19.2 ; U18.M1 143.14,21.5 ; U18.M1 140.84,21.5 ; TP11.1 3.47,14.9 ; TP11.1 1.86,14.9 ; TP11.1 1.86,13.29 ; TP11.1 3.47,13.29 ; J4.5 54.4,77.55 ; J4.5 54.4,79.16 ; J4.5 52.79,79.16 ; J4.5 52.79,77.55 ; TP10.1 76.03,3.47 ; TP10.1 74.42,1.86 ; TP10.1 76.03,1.86 ; TP10.1 74.42,3.47 ; 18.97,77.39 J6.8 ; J6.8 20.41,77.39 ; J6.8 18.97,78.82 ; J6.8 20.41,78.82 ; SCKT1.MCH2 116.11,70.14 ; SCKT1.MCH2 114.09,70.14 ; SCKT1.MCH2 116.11,68.12 ; SCKT1.MCH2 114.09,68.12 ; 184.18,22.73 J37.29 ; J37.29 185.7,24.26 ; J37.29 185.7,22.73 ; J37.29 184.18,24.26 ; 187.05,119.8 TP9.1 ; TP9.1 188.66,119.8 ; TP9.1 187.05,121.41 ; TP9.1 188.66,121.41 ; J2.2 187.28,113.62 ; J2.2 187.28,115.23 ; J2.2 185.67,115.23 ; J2.2 185.67,113.62 ; 158.65,146.32 J21.59 ; J21.59 160.04,146.32 ; J21.59 160.04,147.72 ; J21.59 158.65,147.72 ; J21.40 140.04,149.72 ; J21.40 138.65,148.32 ; J21.40 138.65,149.72 ; J21.40 140.04,148.32 ; J24.MTG4 71.05,1.79 ; J24.MTG4 69.44,3.41 ; J24.MTG4 71.05,3.41 ; J24.MTG4 69.44,1.79 ; J24.MTG2 70.45,8.31 ; J24.MTG2 68.84,8.31 ; J24.MTG2 68.84,6.69 ; J24.MTG2 70.45,6.69 ; 137.37,64.43 J51.1 ; J51.1 137.37,62.82 ; J51.1 138.98,62.82 ; J51.1 138.98,64.43 ; J9.21 185.24,136.31 ; J9.21 185.24,137.92 ; J9.21 183.62,137.92 ; J9.21 183.62,136.31 ; 184.18,37.97 J37.17 ; J37.17 185.7,37.97 ; J37.17 184.18,39.5 ; J37.17 185.7,39.5 ; J39.3 159.51,4.82 ; J39.3 157.99,3.3 ; J39.3 157.99,4.82 ; J39.3 159.51,3.3 ; J10.13 41.01,144.7 ; J10.13 39.49,144.7 ; J10.13 41.01,143.18 ; J46.1 169.33,10.71 ; J46.1 167.72,12.32 ; J46.1 167.72,10.71 ; J46.1 169.33,12.32 ; 88.36,93.84 SCKT1.MCH4 ; SCKT1.MCH4 90.38,95.86 ; SCKT1.MCH4 90.38,93.84 ; SCKT1.MCH4 88.36,95.86 ; J21.60 160.04,148.32 ; J21.60 158.65,149.72 ; J21.60 158.65,148.32 ; J21.60 160.04,149.72
  L3_SIG1 w0.203: v4(94.24,73.62) v5(93.84,73.37)
  L3_SIG1 w0.254: v5(100.23,75.75) 100.2,75.77 100.08,75.77 v4(99.84,76.02) ; v4(91.04,70.42) 91.04,69.95 v5(91.03,69.95) ; v5(96.24,87.46) 96.24,87.46 v4(96.64,87.21) ; v5(96.24,86.66) 96.24,86.66 v4(96.64,86.41) ; v5(113.83,89.06) v4(113.43,88.81) ; v4(94.24,85.61) 94.24,85.61 v5(93.84,85.93) ; v4(98.24,80.82) v5(97.84,80.57) ; v4(100.64,84.01) 100.24,84.26 v5(100.24,84.26) ; v5(96.24,85.06) 96.24,85.06 v4(96.64,84.81) ; v5(109.03,87.46) v4(108.63,87.21) ; v4(95.04,82.41) 94.92,82.41 v5(94.51,82.83) 94.24,83.1 v4(94.24,83.21) ; v4(98.64,93.15) v5(98.64,93.62) ; v5(104.23,82.66) 104.23,82.66 v4(103.83,82.41) ; v4(96.64,76.82) v5(96.24,76.57) ; v11(107.03,80.82) v5(107.43,80.57) ; v5(104.2,73.26) 104.19,73.26 v4(103.83,73.62) ; v5(104.2,72.46) 104.19,72.46 v4(103.83,72.82) ; v5(113.83,82.66) v4(113.43,82.41) ; v4(99.84,80.82) v5(99.44,80.57) ; v4(99.04,80.82) v5(98.64,80.57) ; v5(107.07,69.98) 107.06,69.98 v4(106.71,70.34) ; v5(95.44,85.06) v4(95.84,84.81) ; v5(109.03,86.66) v4(108.63,86.41) ; v5(106.6,73.26) 106.59,73.26 v4(106.23,73.62) ; v5(91.42,93.29) v4(91.82,93.05) ; v4(101.83,93.15) v5(101.83,93.62) ; v5(99.44,82.66) v4(99.84,82.41) ; v5(111.43,83.46) v4(111.03,83.21) ; v5(93.77,82.88) 93.95,82.7 93.96,82.7 94.14,82.51 v4(94.16,82.51) ; v5(101.02,75.72) 100.99,75.75 100.9,75.75 v4(100.64,76.02) ; v5(106.6,72.46) 106.59,72.46 v4(106.23,72.82) ; v4(94.7,93.58) 94.53,93.4 v5(94.24,93.4) ; v3(42.68,112.32) v3(44.07,110.93) 49.64,105.36 v3(50.5,105.36) v3(55.27,105.36) v3(66.29,105.36) 66.34,105.36 66.69,105.72 68.13,105.72 72.47,110.06 v3(73.15,110.06) 73.72,110.63 v3(76.76,110.63) 78.67,110.63 v9(78.74,110.7) 78.81,110.63 80.57,110.63 ; v4(100.64,78.42) v5(100.24,78.17) ; v4(95.84,76.82) v5(95.44,76.57) ; v4(99.84,76.82) 100.14,76.51 100.23,76.51 100.23,76.52 v5(100.26,76.52) ; v11(96.64,80.82) v5(96.24,80.57) ; v4(100.64,84.81) 100.24,85.06 v5(100.24,85.06) ; 80.57,110.63 v9(80.64,110.7) ; 80.57,110.63 81.34,110.63 v3(81.41,110.7) 81.72,110.7 82.11,111.08 84.25,111.08 86.85,108.48 v3(87.67,108.48) 88.52,107.62 v3(90.14,107.62) ; v4(94.24,77.62) v5(93.84,77.37) ; v5(90.51,93.19) v4(90.91,92.94) ; v4(113.43,74.42) 113.68,74.17 v5(113.84,74.17) ; v5(100.24,85.86) 100.24,85.86 v4(100.64,85.61) ; v4(91.04,76.82) v5(90.64,76.57) ; v4(93.5,85.55) 93.5,85.62 93.26,85.87 v5(93.26,85.97) ; v5(113.83,92.26) v4(113.43,92.01) ; v4(98.24,73.62) v5(97.84,73.37) ; v11(99.04,79.22) v5(98.64,78.97) ; v4(100.64,79.22) v11(99.84,79.22) v5(99.44,78.97) ; v3(41.63,111.88) 41.63,110.81 v3(43.01,109.44) 46.53,105.92 46.82,105.92 v3(48.45,104.29) 48.47,104.27 v3(52.17,104.27) v3(56.92,104.27) v3(60.25,104.27) 68.43,104.27 69.44,105.28 v3(70.54,105.28) 74.79,109.54 v3(75.54,109.54) 78.47,109.54 v9(78.49,109.56) 78.5,109.54 v3(80.49,109.54) 83.46,109.54 ; v4(106.23,80.82) v5(106.63,80.57) ; v4(98.2,69.87) v5(97.84,70.17) ; v4(110.23,77.62) v5(110.63,77.37) ; v4(101.44,76.02) 101.68,75.77 v5(101.85,75.77) ; v5(109.83,88.26) v4(109.43,88.01) ; v5(108.23,84.26) 108.23,84.26 v4(107.83,84.01) ; v5(110.63,83.46) v4(110.23,83.21) ; v5(101.04,84.26) v4(101.44,84.01) ; v5(100.24,82.66) 100.24,82.66 v4(100.64,82.41) ; v4(98.24,72.82) v5(97.84,72.57) ; v5(112.63,93.23) v4(112.23,92.98) ; v5(107.43,84.26) v4(107.03,84.01) ; v4(101.44,80.82) v5(101.04,80.57) ; v5(90.51,92.39) v4(90.91,92.14) ; v4(113.43,70.42) v5(112.96,70.42) ; v4(111.03,77.62) v5(111.43,77.37) ; v4(96.64,85.61) 96.24,85.86 v5(96.24,85.86) ; v5(113.83,93.06) v4(113.43,92.81) ; v5(101.04,83.46) v4(101.44,83.21) ; v4(100.64,80.82) v5(100.24,80.57) ; v4(103.83,80.82) v5(104.23,80.57) ; v11(103.83,77.62) v5(104.23,77.37) ; v5(105.83,82.66) v4(105.43,82.41) ; v4(93.44,77.62) v5(93.04,77.37) ; v4(109.04,93.15) v5(109.04,93.62) ; v4(104.63,77.62) v5(105.03,77.37) ; v5(109.03,88.26) v4(108.63,88.01)
  L3_SIG1 w0.381: J44.2 83.46,109.54
  L3_SIG1 w0.508: 79.46,150.67 TP8.1 ; TP8.1 79.46,149.05 ; TP8.1 81.07,150.67 ; TP8.1 81.07,149.05 ; 186.72,22.73 J37.30 ; J37.30 188.24,24.26 ; J37.30 186.72,24.26 ; J37.30 188.24,22.73 ; 39.49,144.7 J10.13 ; J10.13 41.01,144.7 ; J10.13 41.01,143.18 ; U18.M2 143.14,29.3 ; U18.M2 140.84,27 ; U18.M2 140.84,29.3 ; U18.M2 143.14,27 ; 180.76,110.28 J1.3 ; J1.3 180.76,113.24 ; J1.3 183.72,113.24 ; J1.3 183.72,110.28 ; 177.51,115.08 J1.2 ; J1.2 177.51,118.04 ; J1.2 180.47,118.04 ; J1.2 180.47,115.08 ; J37.17 185.7,39.5 ; J37.17 185.7,37.97 ; J37.17 184.18,39.5 ; J37.17 184.18,37.97 ; 38.53,133.23 J10.1 ; J10.1 39.96,133.23 ; J10.1 38.53,131.79 ; J10.1 39.96,131.79 ; 26.04,146.73 J10.12 ; J10.12 26.04,145.21 ; J10.12 27.57,146.73 ; J10.12 27.57,145.21 ; 52.79,79.16 J4.5 ; J4.5 52.79,77.55 ; J4.5 54.4,77.55 ; J4.5 54.4,79.16 ; J8.8 20.41,54.06 ; J8.8 18.97,52.63 ; J8.8 18.97,54.06 ; J8.8 20.41,52.63 ; 185.67,115.23 J2.2 ; J2.2 185.67,113.62 ; J2.2 187.28,115.23 ; J2.2 187.28,113.62 ; 52.66,71.16 J7.5 ; J7.5 54.27,71.16 ; J7.5 52.66,69.55 ; J12.13 62.73,144.7 ; J12.13 61.21,144.7 ; J12.13 62.73,143.18 ; 170.71,65.18 J53.1 173.71,65.18 ; 183.6,65.56 J53.2 185.82,65.56 ; J9.12 172.54,138.85 ; J9.12 170.92,138.85 ; J9.12 170.92,140.46 ; J9.12 172.54,140.46 ; J6.8 20.41,78.82 ; J6.8 18.97,77.39 ; J6.8 20.41,77.39 ; J6.8 18.97,78.82 ; J37.29 185.7,24.26 ; J37.29 184.18,24.26 ; J37.29 185.7,22.73 ; J37.29 184.18,22.73 ; 47.76,146.73 J12.12 ; J12.12 47.76,145.21 ; J12.12 49.28,146.73 ; J12.12 49.28,145.21 ; TP9.1 188.66,121.41 ; TP9.1 187.05,119.8 ; TP9.1 188.66,119.8 ; TP9.1 187.05,121.41 ; J9.11 172.54,137.92 ; J9.11 172.54,136.31 ; J9.11 170.92,137.92 ; J9.11 170.92,136.31 ; 140.84,19.2 U18.M1 ; U18.M1 143.14,19.2 ; U18.M1 143.14,21.5 ; U18.M1 140.84,21.5
  L4_SIG2 w0.508: 19.69,126.36 20.41,125.65 ; 19.69,126.36 18.97,125.65 ; 19.69,126.36 18.97,127.08 ; 19.69,126.36 20.41,127.08 ; J1.3 183.72,113.24 ; J1.3 180.76,113.24 ; J1.3 180.76,110.28 ; J1.3 183.72,110.28 ; 39.49,144.7 J10.13 ; J10.13 41.01,144.7 ; J10.13 41.01,143.18 ; TP8.1 81.07,149.05 ; TP8.1 81.07,150.67 ; TP8.1 79.46,150.67 ; TP8.1 79.46,149.05 ; J10.12 27.57,146.73 ; J10.12 26.04,146.73 ; J10.12 26.04,145.21 ; J10.12 27.57,145.21 ; 38.53,131.79 J10.1 ; J10.1 39.96,131.79 ; J10.1 39.96,133.23 ; J10.1 38.53,133.23 ; 47.76,146.73 J12.12 ; J12.12 47.76,145.21 ; J12.12 49.28,146.73 ; J12.12 49.28,145.21 ; 185.67,113.62 J2.2 ; J2.2 187.28,113.62 ; J2.2 187.28,115.23 ; J2.2 185.67,115.23 ; J12.13 62.73,144.7 ; J12.13 61.21,144.7 ; J12.13 62.73,143.18 ; 177.51,118.04 J1.2 ; J1.2 177.51,115.08 ; J1.2 180.47,118.04 ; J1.2 180.47,115.08
  L5_GND2 w0.508: 183.6,67.79 J53.2 ; J53.2 185.82,65.56 ; J53.2 185.82,67.79 ; J53.2 183.6,65.56 ; 170.71,68.17 J53.1 ; J53.1 170.71,65.18 ; J53.1 173.71,68.17 ; J53.1 173.71,65.18 ; SCKT1.MCH4 90.38,95.86 ; SCKT1.MCH4 90.38,93.84 ; SCKT1.MCH4 88.36,93.84 ; SCKT1.MCH4 88.36,95.86 ; 74.42,3.47 TP10.1 ; TP10.1 76.03,1.86 ; TP10.1 76.03,3.47 ; TP10.1 74.42,1.86 ; TP8.1 81.07,150.67 ; TP8.1 79.46,150.67 ; TP8.1 81.07,149.05 ; TP8.1 79.46,149.05 ; J37.30 188.24,22.73 ; J37.30 186.72,22.73 ; J37.30 188.24,24.26 ; J37.30 186.72,24.26 ; 52.66,71.16 J7.5 ; J7.5 54.27,69.55 ; J7.5 52.66,69.55 ; J7.5 54.27,71.16 ; 187.05,121.41 TP9.1 ; TP9.1 188.66,119.8 ; TP9.1 187.05,119.8 ; TP9.1 188.66,121.41 ; J1.3 183.72,113.24 ; J1.3 180.76,110.28 ; J1.3 183.72,110.28 ; J1.3 180.76,113.24 ; 140.84,27 U18.M2 ; U18.M2 140.84,29.3 ; U18.M2 143.14,27 ; U18.M2 143.14,29.3 ; J24.MTG2 70.45,8.31 ; J24.MTG2 68.84,6.69 ; J24.MTG2 68.84,8.31 ; J24.MTG2 70.45,6.69 ; 1.86,13.29 TP11.1 ; TP11.1 3.47,14.9 ; TP11.1 3.47,13.29 ; TP11.1 1.86,14.9 ; 170.92,136.31 J9.11 ; J9.11 172.54,136.31 ; J9.11 170.92,137.92 ; J9.11 172.54,137.92 ; J44.2 84.37,110.23 ; J44.2 82.76,108.62 ; J44.2 84.37,108.62 ; J44.2 82.76,110.23 ; 19.69,126.36 20.41,127.08 ; 19.69,126.36 18.97,125.65 ; 19.69,126.36 20.41,125.65 ; 19.69,126.36 18.97,127.08 ; 26.04,146.73 J10.12 ; J10.12 27.57,145.21 ; J10.12 27.57,146.73 ; J10.12 26.04,145.21 ; J21.40 140.04,148.32 ; J21.40 138.65,149.72 ; J21.40 138.65,148.32 ; J21.40 140.04,149.72 ; 177.51,115.08 J1.2 ; J1.2 177.51,118.04 ; J1.2 180.47,118.04 ; J1.2 180.47,115.08 ; 158.65,146.32 J21.59 ; J21.59 160.04,146.32 ; J21.59 158.65,147.72 ; J21.59 160.04,147.72 ; 184.18,39.5 J37.17 ; J37.17 185.7,39.5 ; J37.17 184.18,37.97 ; J37.17 185.7,37.97 ; J9.12 172.54,138.85 ; J9.12 172.54,140.46 ; J9.12 170.92,140.46 ; J9.12 170.92,138.85 ; J24.MTG4 71.05,3.41 ; J24.MTG4 71.05,1.79 ; J24.MTG4 69.44,3.41 ; J24.MTG4 69.44,1.79 ; J4.5 54.4,77.55 ; J4.5 52.79,77.55 ; J4.5 54.4,79.16 ; J4.5 52.79,79.16 ; 38.53,131.79 J10.1 ; J10.1 38.53,133.23 ; J10.1 39.96,133.23 ; J10.1 39.96,131.79 ; 45.86,12.33 J23.4 ; J23.4 47.22,12.33 ; J23.4 45.86,13.68 ; J23.4 47.22,13.68 ; 157.99,3.3 J39.3 ; J39.3 159.51,4.82 ; J39.3 157.99,4.82 ; J39.3 159.51,3.3 ; 18.97,54.06 J8.8 ; J8.8 20.41,54.06 ; J8.8 20.41,52.63 ; J8.8 18.97,52.63 ; J21.60 160.04,148.32 ; J21.60 158.65,148.32 ; J21.60 160.04,149.72 ; J21.60 158.65,149.72 ; 47.76,146.73 J12.12 ; J12.12 49.28,146.73 ; J12.12 49.28,145.21 ; J12.12 47.76,145.21 ; J10.13 41.01,144.7 ; J10.13 41.01,143.18 ; J10.13 39.49,144.7 ; U18.M1 143.14,21.5 ; U18.M1 143.14,19.2 ; U18.M1 140.84,19.2 ; U18.M1 140.84,21.5 ; 114.09,68.12 SCKT1.MCH2 ; SCKT1.MCH2 114.09,70.14 ; SCKT1.MCH2 116.11,70.14 ; SCKT1.MCH2 116.11,68.12 ; 60.24,131.79 J12.1 ; J12.1 61.68,131.79 ; J12.1 61.68,133.23 ; J12.1 60.24,133.23 ; J51.1 138.98,64.43 ; J51.1 138.98,62.82 ; J51.1 137.37,62.82 ; J51.1 137.37,64.43 ; J37.29 185.7,22.73 ; J37.29 185.7,24.26 ; J37.29 184.18,24.26 ; J37.29 184.18,22.73 ; 138.65,147.72 J21.39 ; J21.39 140.04,147.72 ; J21.39 138.65,146.32 ; J21.39 140.04,146.32 ; J6.8 20.41,77.39 ; J6.8 20.41,78.82 ; J6.8 18.97,78.82 ; J6.8 18.97,77.39 ; 120.65,149.72 J21.22 ; J21.22 122.04,149.72 ; J21.22 120.65,148.32 ; J21.22 122.04,148.32 ; J24.MTG1 55.95,6.69 ; J24.MTG1 54.34,8.31 ; J24.MTG1 55.95,8.31 ; J24.MTG1 54.34,6.69 ; J24.MTG3 55.35,1.79 ; J24.MTG3 53.74,3.41 ; J24.MTG3 55.35,3.41 ; J24.MTG3 53.74,1.79 ; J2.2 187.28,113.62 ; J2.2 185.67,115.23 ; J2.2 185.67,113.62 ; J2.2 187.28,115.23 ; J12.13 62.73,143.18 ; J12.13 62.73,144.7 ; J12.13 61.21,144.7 ; J5.8 20.41,102.95 ; J5.8 18.97,101.52 ; J5.8 18.97,102.95 ; J5.8 20.41,101.52 ; 183.62,137.92 J9.21 ; J9.21 185.24,136.31 ; J9.21 185.24,137.92 ; J9.21 183.62,136.31 ; J46.1 169.33,10.71 ; J46.1 167.72,10.71 ; J46.1 169.33,12.32 ; J46.1 167.72,12.32
  L6_PWR1 w0.508: J5.8 20.41,102.95 ; J5.8 20.41,101.52 ; J5.8 18.97,102.95 ; J5.8 18.97,101.52 ; 38.53,133.23 J10.1 ; J10.1 39.96,131.79 ; J10.1 39.96,133.23 ; J10.1 38.53,131.79 ; 82.76,110.23 J44.2 ; J44.2 82.76,108.62 ; J44.2 84.37,108.62 ; J44.2 84.37,110.23 ; 39.49,144.7 J10.13 ; J10.13 41.01,144.7 ; J10.13 41.01,143.18 ; J12.13 62.73,143.18 ; J12.13 62.73,144.7 ; J12.13 61.21,144.7 ; 52.79,77.55 J4.5 ; J4.5 52.79,79.16 ; J4.5 54.4,77.55 ; J4.5 54.4,79.16 ; 47.76,146.73 J12.12 ; J12.12 49.28,146.73 ; J12.12 49.28,145.21 ; J12.12 47.76,145.21 ; 26.04,146.73 J10.12 ; J10.12 26.04,145.21 ; J10.12 27.57,145.21 ; J10.12 27.57,146.73 ; J12.1 61.68,133.23 ; J12.1 60.24,133.23 ; J12.1 60.24,131.79 ; J12.1 61.68,131.79 ; 18.97,54.06 J8.8 ; J8.8 20.41,52.63 ; J8.8 20.41,54.06 ; J8.8 18.97,52.63 ; J6.8 20.41,78.82 ; J6.8 18.97,78.82 ; J6.8 18.97,77.39 ; J6.8 20.41,77.39 ; 19.69,126.36 20.41,125.65 ; 19.69,126.36 18.97,127.08 ; 19.69,126.36 20.41,127.08 ; 19.69,126.36 18.97,125.65 ; 88.36,95.86 SCKT1.MCH4 90.38,95.86
  L8_GND3 w0.508: J9.12 172.54,140.46 ; J9.12 172.54,138.85 ; J9.12 170.92,138.85 ; J9.12 170.92,140.46 ; J24.MTG1 55.95,8.31 ; J24.MTG1 54.34,6.69 ; J24.MTG1 54.34,8.31 ; J24.MTG1 55.95,6.69 ; 186.72,22.73 J37.30 ; J37.30 186.72,24.26 ; J37.30 188.24,22.73 ; J37.30 188.24,24.26 ; 74.42,1.86 TP10.1 ; TP10.1 76.03,1.86 ; TP10.1 74.42,3.47 ; TP10.1 76.03,3.47 ; J46.1 169.33,12.32 ; J46.1 167.72,12.32 ; J46.1 169.33,10.71 ; J46.1 167.72,10.71 ; 158.65,149.72 J21.60 ; J21.60 160.04,148.32 ; J21.60 160.04,149.72 ; J21.60 158.65,148.32 ; 158.65,146.32 J21.59 ; J21.59 158.65,147.72 ; J21.59 160.04,147.72 ; J21.59 160.04,146.32 ; 18.97,125.65 19.69,126.36 ; 19.69,126.36 20.41,127.08 ; 19.69,126.36 18.97,127.08 ; 19.69,126.36 20.41,125.65 ; J9.11 172.54,137.92 ; J9.11 172.54,136.31 ; J9.11 170.92,137.92 ; J9.11 170.92,136.31 ; 183.62,136.31 J9.21 ; J9.21 185.24,136.31 ; J9.21 183.62,137.92 ; J9.21 185.24,137.92 ; J21.40 140.04,148.32 ; J21.40 138.65,149.72 ; J21.40 138.65,148.32 ; J21.40 140.04,149.72 ; 68.84,6.69 J24.MTG2 ; J24.MTG2 70.45,8.31 ; J24.MTG2 68.84,8.31 ; J24.MTG2 70.45,6.69 ; 1.86,13.29 TP11.1 ; TP11.1 1.86,14.9 ; TP11.1 3.47,13.29 ; TP11.1 3.47,14.9 ; SCKT1.MCH2 116.11,68.12 ; SCKT1.MCH2 114.09,70.14 ; SCKT1.MCH2 116.11,70.14 ; SCKT1.MCH2 114.09,68.12 ; TP8.1 81.07,150.67 ; TP8.1 79.46,150.67 ; TP8.1 79.46,149.05 ; TP8.1 81.07,149.05 ; J37.29 185.7,22.73 ; J37.29 184.18,22.73 ; J37.29 185.7,24.26 ; J37.29 184.18,24.26 ; 18.97,101.52 J5.8 ; J5.8 20.41,101.52 ; J5.8 18.97,102.95 ; J5.8 20.41,102.95 ; 52.79,77.55 J4.5 ; J4.5 52.79,79.16 ; J4.5 54.4,77.55 ; J4.5 54.4,79.16 ; J2.2 187.28,115.23 ; J2.2 185.67,115.23 ; J2.2 185.67,113.62 ; J2.2 187.28,113.62 ; 47.76,146.73 J12.12 ; J12.12 47.76,145.21 ; J12.12 49.28,146.73 ; J12.12 49.28,145.21 ; J10.12 27.57,145.21 ; J10.12 27.57,146.73 ; J10.12 26.04,146.73 ; J10.12 26.04,145.21 ; J39.3 159.51,3.3 ; J39.3 157.99,4.82 ; J39.3 159.51,4.82 ; J39.3 157.99,3.3 ; 120.65,148.32 J21.22 ; J21.22 122.04,149.72 ; J21.22 120.65,149.72 ; J21.22 122.04,148.32 ; J6.8 20.41,78.82 ; J6.8 18.97,78.82 ; J6.8 18.97,77.39 ; J6.8 20.41,77.39 ; 137.37,62.82 J51.1 ; J51.1 138.98,64.43 ; J51.1 138.98,62.82 ; J51.1 137.37,64.43 ; U18.M1 143.14,19.2 ; U18.M1 143.14,21.5 ; U18.M1 140.84,19.2 ; U18.M1 140.84,21.5 ; 180.76,110.28 J1.3 ; J1.3 183.72,110.28 ; J1.3 180.76,113.24 ; J1.3 183.72,113.24 ; 18.97,54.06 J8.8 ; J8.8 20.41,52.63 ; J8.8 20.41,54.06 ; J8.8 18.97,52.63 ; TP9.1 188.66,119.8 ; TP9.1 188.66,121.41 ; TP9.1 187.05,121.41 ; TP9.1 187.05,119.8 ; J21.39 140.04,146.32 ; J21.39 140.04,147.72 ; J21.39 138.65,146.32 ; J21.39 138.65,147.72 ; J12.13 62.73,143.18 ; J12.13 62.73,144.7 ; J12.13 61.21,144.7 ; 53.74,1.79 J24.MTG3 ; J24.MTG3 55.35,1.79 ; J24.MTG3 55.35,3.41 ; J24.MTG3 53.74,3.41 ; 52.66,71.16 J7.5 ; J7.5 54.27,71.16 ; J7.5 54.27,69.55 ; J7.5 52.66,69.55 ; 45.86,12.33 J23.4 ; J23.4 47.22,13.68 ; J23.4 45.86,13.68 ; J23.4 47.22,12.33 ; 39.49,144.7 J10.13 ; J10.13 41.01,143.18 ; J10.13 41.01,144.7 ; J12.1 61.68,131.79 ; J12.1 61.68,133.23 ; J12.1 60.24,131.79 ; J12.1 60.24,133.23 ; 69.44,1.79 J24.MTG4 ; J24.MTG4 71.05,3.41 ; J24.MTG4 71.05,1.79 ; J24.MTG4 69.44,3.41 ; 184.18,39.5 J37.17 ; J37.17 185.7,39.5 ; J37.17 185.7,37.97 ; J37.17 184.18,37.97 ; J1.2 180.47,118.04 ; J1.2 177.51,115.08 ; J1.2 180.47,115.08 ; J1.2 177.51,118.04 ; J53.2 185.82,65.56 ; J53.2 183.6,67.79 ; J53.2 183.6,65.56 ; J53.2 185.82,67.79 ; 38.53,131.79 J10.1 ; J10.1 39.96,133.23 ; J10.1 39.96,131.79 ; J10.1 38.53,133.23 ; 170.71,68.17 J53.1 170.71,65.18 ; 140.84,27 U18.M2 ; U18.M2 143.14,29.3 ; U18.M2 140.84,29.3 ; U18.M2 143.14,27
  L9_SIG3 w0.508: J1.3 183.72,110.28 ; J1.3 180.76,113.24 ; J1.3 180.76,110.28 ; J1.3 183.72,113.24 ; J12.13 62.73,144.7 ; J12.13 61.21,144.7 ; J12.13 62.73,143.18 ; 1.86,14.9 TP11.1 ; TP11.1 3.47,14.9 ; TP11.1 1.86,13.29 ; TP11.1 3.47,13.29 ; 177.51,115.08 J1.2 ; J1.2 180.47,115.08 ; J1.2 180.47,118.04 ; J1.2 177.51,118.04 ; J37.17 185.7,39.5 ; J37.17 184.18,39.5 ; J37.17 184.18,37.97 ; J37.17 185.7,37.97 ; J12.1 61.68,133.23 ; J12.1 60.24,131.79 ; J12.1 61.68,131.79 ; J12.1 60.24,133.23 ; J53.1 173.71,68.17 ; J53.1 170.71,68.17 ; J53.1 173.71,65.18 ; J53.1 170.71,65.18 ; 140.84,21.5 U18.M1 ; U18.M1 143.14,19.2 ; U18.M1 143.14,21.5 ; U18.M1 140.84,19.2 ; J24.MTG4 71.05,1.79 ; J24.MTG4 69.44,1.79 ; J24.MTG4 69.44,3.41 ; J24.MTG4 71.05,3.41 ; J53.2 185.82,67.79 ; J53.2 185.82,65.56 ; J53.2 183.6,67.79 ; J53.2 183.6,65.56 ; J12.12 49.28,146.73 ; J12.12 47.76,145.21 ; J12.12 47.76,146.73 ; J12.12 49.28,145.21 ; J46.1 169.33,12.32 ; J46.1 167.72,12.32 ; J46.1 167.72,10.71 ; J46.1 169.33,10.71 ; J51.1 138.98,64.43 ; J51.1 137.37,64.43 ; J51.1 138.98,62.82 ; J51.1 137.37,62.82 ; J5.8 20.41,102.95 ; J5.8 18.97,101.52 ; J5.8 18.97,102.95 ; J5.8 20.41,101.52 ; J24.MTG3 55.35,1.79 ; J24.MTG3 53.74,3.41 ; J24.MTG3 55.35,3.41 ; J24.MTG3 53.74,1.79 ; 68.84,6.69 J24.MTG2 ; J24.MTG2 70.45,6.69 ; J24.MTG2 68.84,8.31 ; J24.MTG2 70.45,8.31 ; J37.30 188.24,22.73 ; J37.30 188.24,24.26 ; J37.30 186.72,24.26 ; J37.30 186.72,22.73 ; TP10.1 76.03,3.47 ; TP10.1 76.03,1.86 ; TP10.1 74.42,1.86 ; TP10.1 74.42,3.47 ; J2.2 187.28,115.23 ; J2.2 185.67,113.62 ; J2.2 185.67,115.23 ; J2.2 187.28,113.62 ; 184.18,22.73 J37.29 ; J37.29 185.7,22.73 ; J37.29 185.7,24.26 ; J37.29 184.18,24.26 ; J4.5 54.4,77.55 ; J4.5 52.79,77.55 ; J4.5 52.79,79.16 ; J4.5 54.4,79.16 ; J10.12 27.57,145.21 ; J10.12 26.04,146.73 ; J10.12 26.04,145.21 ; J10.12 27.57,146.73 ; 79.46,150.67 TP8.1 ; TP8.1 81.07,150.67 ; TP8.1 79.46,149.05 ; TP8.1 81.07,149.05 ; 18.97,78.82 J6.8 ; J6.8 18.97,77.39 ; J6.8 20.41,78.82 ; J6.8 20.41,77.39 ; 140.84,29.3 U18.M2 ; U18.M2 143.14,27 ; U18.M2 140.84,27 ; U18.M2 143.14,29.3 ; 52.66,71.16 J7.5 ; J7.5 54.27,71.16 ; J7.5 54.27,69.55 ; J7.5 52.66,69.55 ; J24.MTG1 55.95,8.31 ; J24.MTG1 55.95,6.69 ; J24.MTG1 54.34,6.69 ; J24.MTG1 54.34,8.31 ; J39.3 159.51,3.3 ; J39.3 157.99,4.82 ; J39.3 159.51,4.82 ; J39.3 157.99,3.3 ; 18.97,54.06 J8.8 ; J8.8 20.41,52.63 ; J8.8 20.41,54.06 ; J8.8 18.97,52.63 ; J10.1 39.96,131.79 ; J10.1 38.53,131.79 ; J10.1 39.96,133.23 ; J10.1 38.53,133.23 ; 39.49,144.7 J10.13 ; J10.13 41.01,143.18 ; J10.13 41.01,144.7
  L10_SIG4 w0.254: v5(107.43,84.26) 107.43,84.37 107.72,84.66 107.87,84.66 v11(107.9,84.68) ; v5(110.63,77.37) 110.63,77.33 v11(111,76.97) ; v11(100.64,85.62) v5(100.24,85.86) ; v11(102.34,77.45) 102.32,77.45 v11(101.99,77.78) ; v11(103.02,77.6) 103.06,77.6 v5(103.43,77.37) ; v11(103.83,77.62) v5(104.23,77.37) ; v5(100.26,76.52) 100.05,76.32 v11(99.84,76.32) ; v11(99.84,79.22) v5(99.44,78.97) ; v5(101.02,75.72) 100.76,75.47 v11(100.61,75.47) ; v11(101.9,81.51) 101.9,80.98 101.49,80.57 v5(101.04,80.57) ; v11(96.64,80.82) v5(96.24,80.57) ; v11(93.83,85.34) 93.83,85.86 93.84,85.86 v5(93.84,85.93) ; v5(104.23,80.57) 104.23,80.97 v11(104.5,81.23) ; v11(100.84,81.44) 100.56,81.16 100.56,80.89 v5(100.24,80.57) ; v11(111.83,77.62) v5(111.43,77.37) ; v11(105.43,82.42) v5(105.83,82.66) ; v11(100.64,84.02) v5(100.24,84.26) ; v5(97.84,80.57) 97.84,81.04 v11(97.71,81.16) ; v5(106.63,80.57) 106.61,80.46 106.43,80.35 106.41,80.29 v11(106.3,80.22) ; v11(99.82,75.5) 99.98,75.5 v5(100.23,75.75) ; v11(95.85,87.08) v5(96.24,87.46) ; v11(101.45,75.52) 101.6,75.52 v5(101.85,75.77) ; v5(113.83,82.66) 114.19,82.66 v11(114.3,82.55) ; v11(101.96,82.58) v11(101.96,82.19) ; v11(100.64,82.42) v5(100.24,82.66) ; v11(99.04,79.22) v5(98.64,78.97) ; v5(93.26,85.97) 93.26,86.25 v11(93.43,86.42) ; v11(99.84,82.42) v5(99.44,82.66) ; v5(99.44,80.57) 99.8,80.93 v11(99.8,81.39) ; v11(107.03,80.82) v5(107.43,80.57) ; v5(108.23,84.26) 108.23,84.31 v11(108.56,84.64) ; v11(98.86,81.39) 98.64,81.17 v5(98.64,80.57) ; v11(100.64,84.82) v5(100.24,85.06) ; v11(111.03,83.22) v5(110.63,83.46) ; v11(114.09,73.77) v5(113.84,74.17) ; v11(111.83,83.22) v5(111.43,83.46) ; v11(96.64,85.62) v5(96.24,85.86)
  L10_SIG4 w0.381: v7(103.63,110.19) v7(103.63,111.08) ; v7(87.38,81.66) v5(88.14,81.66) ; v5(86.46,66.62) v7(86.46,67.21)
  L10_SIG4 w0.508: 184.18,39.5 J37.17 ; J37.17 184.18,37.97 ; J37.17 185.7,39.5 ; J37.17 185.7,37.97 ; U18.M2 143.14,27 ; U18.M2 143.14,29.3 ; U18.M2 140.84,29.3 ; U18.M2 140.84,27 ; J24.MTG1 55.95,8.31 ; J24.MTG1 54.34,8.31 ; J24.MTG1 54.34,6.69 ; J24.MTG1 55.95,6.69 ; 18.97,77.39 J6.8 18.97,78.82 ; 53.74,1.79 J24.MTG3 ; J24.MTG3 55.35,1.79 ; J24.MTG3 55.35,3.41 ; J24.MTG3 53.74,3.41 ; 18.97,54.06 J8.8 18.97,52.63 ; 140.84,21.5 U18.M1 ; U18.M1 143.14,19.2 ; U18.M1 143.14,21.5 ; U18.M1 140.84,19.2 ; J37.29 185.7,22.73 ; J37.29 184.18,24.26 ; J37.29 185.7,24.26 ; J37.29 184.18,22.73 ; J2.2 187.28,113.62 ; J2.2 185.67,115.23 ; J2.2 185.67,113.62 ; J2.2 187.28,115.23 ; J1.2 180.47,115.08 ; J1.2 180.47,118.04 ; J1.2 177.51,115.08 ; J1.2 177.51,118.04 ; J1.3 183.72,110.28 ; J1.3 183.72,113.24 ; J1.3 180.76,113.24 ; J1.3 180.76,110.28 ; 74.42,3.47 TP10.1 ; TP10.1 74.42,1.86 ; TP10.1 76.03,1.86 ; TP10.1 76.03,3.47 ; TP9.1 188.66,121.41 ; TP9.1 187.05,121.41 ; TP9.1 187.05,119.8 ; TP9.1 188.66,119.8 ; 167.72,12.32 J46.1 ; J46.1 169.33,12.32 ; J46.1 169.33,10.71 ; J46.1 167.72,10.71 ; J39.3 159.51,4.82 ; J39.3 159.51,3.3 ; J39.3 157.99,4.82 ; J39.3 157.99,3.3 ; 186.72,22.73 J37.30 ; J37.30 188.24,22.73 ; J37.30 186.72,24.26 ; J37.30 188.24,24.26 ; J24.MTG4 71.05,1.79 ; J24.MTG4 71.05,3.41 ; J24.MTG4 69.44,3.41 ; J24.MTG4 69.44,1.79 ; 185.82,67.79 J53.2 185.82,65.56 ; J44.2 84.37,108.62 ; J44.2 84.37,110.23 ; J44.2 82.76,110.23 ; 1.86,13.29 TP11.1 ; TP11.1 3.47,13.29 ; TP11.1 3.47,14.9 ; TP11.1 1.86,14.9
  L11_GND4 w0.508: 157.99,4.82 J39.3 ; J39.3 157.99,3.3 ; J39.3 159.51,4.82 ; J39.3 159.51,3.3 ; J21.40 140.04,148.32 ; J21.40 138.65,149.72 ; J21.40 140.04,149.72 ; J21.40 138.65,148.32 ; 38.53,131.79 J10.1 ; J10.1 39.96,131.79 ; J10.1 39.96,133.23 ; J10.1 38.53,133.23 ; 45.86,13.68 J23.4 ; J23.4 47.22,13.68 ; J23.4 47.22,12.33 ; J23.4 45.86,12.33 ; 170.71,65.18 J53.1 ; J53.1 173.71,68.17 ; J53.1 170.71,68.17 ; J53.1 173.71,65.18 ; J37.29 185.7,24.26 ; J37.29 185.7,22.73 ; J37.29 184.18,24.26 ; J37.29 184.18,22.73 ; J4.5 54.4,79.16 ; J4.5 54.4,77.55 ; J4.5 52.79,77.55 ; J4.5 52.79,79.16 ; 79.46,150.67 TP8.1 ; TP8.1 81.07,150.67 ; TP8.1 81.07,149.05 ; TP8.1 79.46,149.05 ; J10.13 41.01,144.7 ; J10.13 39.49,144.7 ; J10.13 41.01,143.18 ; 26.04,145.21 J10.12 ; J10.12 27.57,145.21 ; J10.12 26.04,146.73 ; J10.12 27.57,146.73 ; 47.76,146.73 J12.12 ; J12.12 47.76,145.21 ; J12.12 49.28,145.21 ; J12.12 49.28,146.73 ; J5.8 20.41,102.95 ; J5.8 18.97,102.95 ; J5.8 18.97,101.52 ; J5.8 20.41,101.52 ; 137.37,64.43 J51.1 ; J51.1 138.98,64.43 ; J51.1 138.98,62.82 ; J51.1 137.37,62.82 ; J24.MTG1 55.95,6.69 ; J24.MTG1 54.34,6.69 ; J24.MTG1 54.34,8.31 ; J24.MTG1 55.95,8.31 ; J24.MTG2 70.45,8.31 ; J24.MTG2 70.45,6.69 ; J24.MTG2 68.84,8.31 ; J24.MTG2 68.84,6.69 ; J12.13 62.73,143.18 ; J12.13 62.73,144.7 ; J12.13 61.21,144.7 ; 158.65,146.32 J21.59 ; J21.59 160.04,146.32 ; J21.59 158.65,147.72 ; J21.59 160.04,147.72 ; J1.3 183.72,113.24 ; J1.3 183.72,110.28 ; J1.3 180.76,110.28 ; J1.3 180.76,113.24 ; J37.17 185.7,39.5 ; J37.17 184.18,37.97 ; J37.17 185.7,37.97 ; J37.17 184.18,39.5 ; 185.67,113.62 J2.2 ; J2.2 185.67,115.23 ; J2.2 187.28,115.23 ; J2.2 187.28,113.62 ; 170.92,136.31 J9.11 ; J9.11 170.92,137.92 ; J9.11 172.54,137.92 ; J9.11 172.54,136.31 ; 167.72,12.32 J46.1 ; J46.1 167.72,10.71 ; J46.1 169.33,12.32 ; J46.1 169.33,10.71 ; 187.05,121.41 TP9.1 ; TP9.1 187.05,119.8 ; TP9.1 188.66,119.8 ; TP9.1 188.66,121.41 ; 18.97,127.08 19.69,126.36 ; 19.69,126.36 20.41,127.08 ; 19.69,126.36 20.41,125.65 ; 19.69,126.36 18.97,125.65 ; 53.74,1.79 J24.MTG3 ; J24.MTG3 53.74,3.41 ; J24.MTG3 55.35,1.79 ; J24.MTG3 55.35,3.41 ; J7.5 54.27,71.16 ; J7.5 54.27,69.55 ; J7.5 52.66,71.16 ; J7.5 52.66,69.55 ; 82.76,110.23 J44.2 ; J44.2 84.37,108.62 ; J44.2 82.76,108.62 ; J44.2 84.37,110.23 ; 69.44,1.79 J24.MTG4 ; J24.MTG4 71.05,3.41 ; J24.MTG4 69.44,3.41 ; J24.MTG4 71.05,1.79 ; U18.M1 143.14,19.2 ; U18.M1 140.84,21.5 ; U18.M1 143.14,21.5 ; U18.M1 140.84,19.2 ; 177.51,118.04 J1.2 ; J1.2 180.47,118.04 ; J1.2 180.47,115.08 ; J1.2 177.51,115.08 ; 18.97,77.39 J6.8 ; J6.8 20.41,78.82 ; J6.8 20.41,77.39 ; J6.8 18.97,78.82 ; 186.72,24.26 J37.30 ; J37.30 188.24,24.26 ; J37.30 186.72,22.73 ; J37.30 188.24,22.73 ; J8.8 20.41,54.06 ; J8.8 18.97,52.63 ; J8.8 18.97,54.06 ; J8.8 20.41,52.63 ; SCKT1.MCH2 116.11,68.12 ; SCKT1.MCH2 116.11,70.14 ; SCKT1.MCH2 114.09,70.14 ; SCKT1.MCH2 114.09,68.12 ; 140.84,27 U18.M2 ; U18.M2 140.84,29.3 ; U18.M2 143.14,29.3 ; U18.M2 143.14,27 ; 88.36,93.84 SCKT1.MCH4 ; SCKT1.MCH4 88.36,95.86 ; SCKT1.MCH4 90.38,93.84 ; SCKT1.MCH4 90.38,95.86 ; 1.86,13.29 TP11.1 ; TP11.1 1.86,14.9 ; TP11.1 3.47,13.29 ; TP11.1 3.47,14.9 ; J21.60 160.04,149.72 ; J21.60 160.04,148.32 ; J21.60 158.65,149.72 ; J21.60 158.65,148.32 ; J12.1 61.68,131.79 ; J12.1 61.68,133.23 ; J12.1 60.24,131.79 ; J12.1 60.24,133.23 ; J21.39 140.04,147.72 ; J21.39 138.65,146.32 ; J21.39 138.65,147.72 ; J21.39 140.04,146.32 ; J21.22 122.04,149.72 ; J21.22 120.65,149.72 ; J21.22 122.04,148.32 ; J21.22 120.65,148.32 ; J53.2 185.82,67.79 ; J53.2 183.6,67.79 ; J53.2 185.82,65.56 ; J53.2 183.6,65.56 ; J9.12 172.54,140.46 ; J9.12 170.92,140.46 ; J9.12 170.92,138.85 ; J9.12 172.54,138.85 ; 74.42,3.47 TP10.1 ; TP10.1 76.03,3.47 ; TP10.1 76.03,1.86 ; TP10.1 74.42,1.86 ; 183.62,137.92 J9.21 ; J9.21 185.24,137.92 ; J9.21 183.62,136.31 ; J9.21 185.24,136.31
  BOTTOM w0.083: v8(98.38,130.44) 98.63,130.19 98.63,129.7 U43.N2 98.13,129.7 98.13,130.19 v8(98.38,130.44)
  BOTTOM w0.102: U62.E4 U62.D3
  BOTTOM w0.203: U62.E4 156.64,105.07 v9(156.64,105) ; U75.5 167.4,62.15 167.11,62.44 v9(166.73,62.44) ; U62.C2 U62.C3 U62.D3 ; U62.B4 v9(154.97,104.89)
  BOTTOM w0.254: v9(53.72,52.02) 52.97,51.27 U45.14 ; U89.A1 v8(157.69,93.04) ; U89.D6 155.28,96.29 v8(154.96,95.97) U89.E6 ; U43.N5 U43.P6 v8(99.42,126.92) v8(99.42,126.16) ; v9(81.91,119.9) J16.13 ; U89.D4 v8(154.96,94.67) U89.E4 ; U43.K8 96.39,126.94 v8(96.38,126.94) ; C566.2 98.42,78.33 99.04,78.94 v11(99.04,79.22) ; v8(93.85,127.97) 93.85,127.98 U43.C4 ; J16.16 85.26,121.4 85.47,121.62 v9(85.6,121.62) ; J16.22 v9(83.18,124.4) ; U89.H2 v8(152.68,94.15) ; v9(54.74,89.87) 54.37,89.51 J17.6 ; v11(96.72,82.07) 96.68,82.07 96.66,82.05 96.57,82.05 96.49,81.97 96.49,81.92 C394.2 ; U32.8 v9(74.04,144.61) ; U89.G5 153.33,95.64 v8(153.66,95.32) U89.F5 ; v8(99.44,128.63) 99.26,128.45 U43.P4 ; U43.G5 v8(95.38,127.46) ; U89.F7 153.98,96.94 v8(153.66,96.62) U89.G7 ; U89.F4 v8(153.66,94.67) 153.33,94.99 U89.G4 ; U43.E7 v8(94.87,126.95) ; v8(158.12,99.4) 157.61,98.89 U89.A10 ; U62.C2 U62.C1 v9(155.37,107.8) v9(155.37,108.44) ; 103.5,87.2 103.26,86.95 102.62,86.95 ; U89.D5 v8(154.96,95.32) U89.E5 ; U64.3 v7(43.05,18.92) ; J16.19 v9(83.18,122.9) ; U89.J8 v8(152.65,97.59) 152.68,97.62 U89.H9 ; v9(82.93,118.4) J16.10 ; v11(106.3,80.22) 106.3,80.65 C338.2 106.46,80.82 v11(107.03,80.82) ; U89.E9 v8(154.63,97.62) ; v9(74.91,145.09) 74.54,145.46 U32.4 ; C339.2 101.96,77.41 102.15,77.41 102.19,77.45 v11(102.34,77.45) ; U72.28 v9(177.66,71.84) ; U89.D7 155.28,96.94 v8(154.96,96.62) U89.E7 ; U89.K10 v8(151.38,99.35) ; U89.B7 v8(156.12,96.94) ; U89.J4 U89.J5 v8(152.49,95.64) ; U89.G6 v8(153.66,95.97) 153.98,96.29 U89.F6 ; C388.2 104.09,80.83 v11(104.5,81.23) ; J16.7 v9(83.18,116.9) ; v8(95.38,125.94) 95.39,125.94 U43.H10
  BOTTOM w0.305: v9(90.8,149.53) 90.8,149.53 U30.5
  BOTTOM w0.33: v9(140.5,89.61) 140.45,89.56 U104.15
  BOTTOM w0.381: v9(48.9,117.05) 48.77,117.19 C153.2 ; v7(38.99,115.67) C159.2 v7(40.13,114.64) ; 44.72,52.91 44.21,52.41 v9(44.21,51.75) ; 44.72,52.91 45.23,52.41 v9(45.23,51.75) ; 44.72,52.91 C306.2 ; R570.2 v7(144.69,130.76) ; C248.2 v9(59.18,63.58) ; C322.2 v9(59.64,55.71) ; v9(33.02,118.83) 32.64,118.45 C160.2 ; C76.2 120.07,37.46 v8(120.06,37.48) ; v11(87.63,84.66) 88.01,85.04 L25.2 88.01,86.57 87.76,86.82 87.38,86.82 v11(87.38,86.82) ; C107.2 v9(23.37,132.16) ; C229.2 v9(169.42,74.17) ; v9(25.53,51.77) 25.53,52.42 C149.2 ; C192.2 v9(61.07,108.41) ; C209.2 v9(160.4,38.56) ; C187.1 44.83,143.75 v9(44.83,143.76) ; v7(55.37,111.59) 55.37,112.19 55.77,112.59 C189.2 55.77,113.11 55.4,113.48 v7(54.74,113.48) ; C567.2 v7(80.01,79.25) ; v9(26.12,102.43) 26.01,102.32 C116.2 ; 90.8,81.53 90.8,81.86 v11(91.06,82.12) 90.83,82.35 C298.2 ; v7(91.31,87) 90.93,87 C446.2 ; v9(30.23,88.09) 30.47,88.33 U69.3 ; v9(13.64,7.98) 13.61,8.01 Q5.S ; v7(88.43,80.84) 87.88,80.29 L26.2 87.88,78.99 ; C239.2 v9(163.45,75.56) ; C9.2 95.07,70.62 v7(94.87,70.41) ; v9(181.47,82.51) R382.1 181.47,80.63 v9(181.23,80.39) ; U66.1 v9(28.19,5.08) ; v9(45.09,45.55) 45.09,46.2 C305.2 45.59,46.71 46.1,46.2 v9(46.1,45.55) ; v8(112.69,25.88) 112.66,25.91 C72.2 ; v7(33.02,112.22) 33.69,112.22 34.05,112.59 C168.2 34.05,113.11 33.69,113.48 v7(33.02,113.48) ; C131.1 v9(16.26,92.66) ; C406.2 95.9,89.63 v11(95.78,89.51) ; v8(84.78,37.48) 85.21,37.48 C41.2 ; U70.3 25.51,69.71 v9(25.48,69.68) ; R489.1 169.8,72.77 v9(169.55,73.02) ; C579.2 135.06,84.07 v9(135.09,84.11) ; v8(88.78,31.88) 89.03,31.63 89.03,30.23 ; R246.1 16.89,2.08 17.24,1.73 v9(18.03,1.73) ; v9(46.23,3.99) C311.2 v9(47.88,5.64) ; v9(111.38,110.19) R464.1 R465.1 ; Q10.S 13.61,21.47 v9(13.64,21.44) ; v9(78.49,109.56) 77.47,110.57 C222.2 78.72,110.71 v9(78.74,110.7) ; U97.3 v9(166.5,49.39) ; v9(25.5,2.67) 24.38,2.67 ; C199.2 v9(175.41,53.85) ; C441.2 68.96,62.44 68.58,62.05 v9(68.58,61.12) ; C441.2 v9(70.1,58.33) ; C441.2 v9(70.1,65.11) ; v9(68.72,136.61) C215.2 v9(67.67,137.75) ; v9(80.64,110.7) 80.4,110.94 J16.MNT1 81.37,112.25 v9(81.53,112.1) ; C70.2 120.37,25.78 v8(120.27,25.88) ; C318.2 v7(140.97,133.61) ; C38.2 89.78,33.91 v8(89.74,33.88) ; C79.2 112.01,29.08 v8(112.69,29.08) ; Q6.S 20.22,8.01 v9(20.24,7.98) ; C201.2 v9(175.41,48.77) ; v9(25.96,87.15) 25.84,87.15 C133.2 ; 108.33,85.34 108.56,85.12 v11(108.56,84.64) ; C265.2 v9(92.33,136.35) ; v7(187.23,85.84) 186.57,85.19 U19.3 ; C166.1 v9(22.48,140.16) ; C51.2 97.36,25.78 v8(97.45,25.88) ; v9(135.09,99.6) 135.06,99.57 C580.2 ; v9(161.21,84.59) 161.21,84.52 161.56,84.17 C231.1 ; 46.51,100.81 46.51,100.81 C172.1 ; R466.1 v7(105.66,110.19) ; R466.1 R468.1 ; R466.1 R455.1 R458.1 ; v7(60.71,115.67) C180.2 v7(61.85,114.64) ; v11(109.99,79.6) C288.2 ; U77.5 v9(179.07,4.75) ; v9(188.34,82.68) 188.43,82.59 C421.2 ; U33.2 v9(10.67,25.32) ; C11.2 92.41,74.88 v7(92.41,74.73) 92.91,74.22 C8.2 ; v9(185.42,62.06) 186.39,62.06 C196.2 ; v9(112.41,20.21) 112.52,20.32 C94.2 ; v9(5.18,42.78) 4.81,42.4 J45.5 ; C329.2 97.94,80.7 97.79,80.85 97.79,81.08 v11(97.71,81.16) ; C399.2 140.64,130.94 v8(140.64,130.33) ; C50.2 104.65,38.91 v8(104.02,38.28) ; Q11.S 13.61,14.86 v9(13.64,14.84) ; U73.8 v9(172.59,38.18) ; C289.2 v11(116.71,73.23) v11(117.2,73.23) ; C140.2 25.68,59.77 25.76,59.85 v9(26.16,59.85) ; 87.88,78.99 87.5,78.61 87.08,78.61 v11(87.07,78.61) ; 87.88,78.99 88.34,78.54 v11(88.47,78.54) ; v9(51.18,58.12) L3.2 53.85,58.12 v9(54.23,58.5) ; U33.4 v9(8.13,25.32) ; U33.1 v9(11.94,25.32) ; v9(68.71,83.39) 68.84,83.52 R706.1 ; C55.2 105.08,25.78 v8(104.98,25.88) ; v9(177.93,82.04) 178.14,82.25 R380.1 ; C108.2 v7(25.17,114.08) ; v7(92.79,72.27) 92.79,72.73 C7.2 ; v11(113.41,74.55) C362.2 111.91,74.55 v11(111.9,74.54) ; R484.1 164.08,72.39 v9(164.47,72.77) ; C34.2 89.41,38.91 v8(88.78,38.28) ; C230.1 v9(155.96,74.5) ; 164.21,40.26 v9(164.97,40.26) ; v9(49.4,45.55) 49.4,46.2 49.91,46.71 C307.2 50.42,46.2 v9(50.42,45.55) ; C568.2 v7(80.01,78.23) ; v9(48.39,124.29) 48.18,124.49 C178.2 v9(48.18,127.16) ; C49.2 96.9,37.08 97.14,37.08 97.53,37.48 v8(98.42,37.48) ; C319.2 v9(186.72,97.54) ; v9(61.72,69.17) 61.23,68.68 U39.3 ; v9(170.03,95.05) 170.18,95.2 U38.5 ; v9(30.48,56.82) v9(31.5,56.82) ; C32.2 90.13,37.46 v8(89.74,37.08) ; C251.2 v9(170.48,24.85) ; v11(98.23,84.01) 98.22,84 C401.2 ; v8(112.86,33.48) 112.28,32.89 112.01,32.89 ; R463.1 R462.1 v9(109.35,110.19) ; R592.1 v9(16.18,19.64) ; C564.2 100.33,83.71 v11(100.64,84.02) 100.83,84.21 C380.2 ; v7(80.14,77.47) L35.2 v7(80.14,74.68) ; R458.1 v7(103.63,110.19) ; R458.1 R459.1 R453.1 ; C104.2 v9(16.64,121.37) ; C236.2 165.74,84.71 v9(165.74,84.54) ; C240.1 v9(160.87,78.02) ; v9(55.63,60.53) C320.2 v9(56.79,59.37) ; v9(20.24,18.14) 20.22,18.17 Q12.S ; v11(82.3,93.05) 83.06,93.05 83.33,93.32 C361.2 ; C48.2 104.83,37.46 v8(104.82,37.48) ; v9(186.82,94.23) 186.45,93.86 U78.3 ; v9(176.94,25.27) 178.1,24.11 C208.2 177.54,23.45 v9(176.91,23.45) ; v8(99.22,31.88) 99.69,31.88 99.97,32.16 100.24,32.16 100.46,32.38 C58.2 ; v9(82.8,94.84) 82.8,95.57 C483.2 83.87,95.55 v9(83.87,94.82) ; v9(176.78,82.8) 176.77,82.81 U63.8 ; 117.98,80.09 v7(118.75,80.09) ; v11(119.38,76.03) v11(118.87,76.03) C292.2 ; v8(97.45,29.08) 97.32,29.21 C57.2 ; v7(146.56,131.53) 146.3,131.27 C281.2 v7(147.32,130.47) ; R467.1 v9(113.41,110.1) ; v9(55.46,99.03) 55.23,98.79 U25.5 ; C169.2 v9(43.31,97.79) ; R515.1 v9(16.18,16.21) ; 81.53,32.89 82.03,32.89 v8(82.21,33.08) ; v8(89.74,29.08) 90,29.34 C37.2 ; C571.2 v7(86.46,67.21) ; C31.2 82.04,36.96 82.56,37.48 v8(83.18,37.48) ; U63.2 v9(174.24,86.72) ; v7(24,123.91) 24.26,123.65 C112.2 ; C155.2 28.46,121.24 v9(27.88,121.82) ; C223.2 v9(188.47,91.57) ; R417.1 77.09,141.81 77.72,141.18 v9(77.72,140.52) ; v8(114.46,31.88) 114.74,32.16 115.48,32.16 115.7,32.38 C62.2 ; C361.2 83.33,93.79 83.06,94.06 v11(82.3,94.06) ; C361.2 83.57,93.32 v11(83.57,92.41) ; C405.2 v7(103.38,90.42) ; v11(111.46,82.55) L21.2 v11(114.3,82.55) ; C324.2 v9(59.64,56.72) ; U23.5 v9(41.29,99.08) ; U68.3 41.77,88.33 v9(41.15,87.71) ; C173.1 46.51,105.32 v9(46.52,105.32) ; v8(88.78,33.48) 89.36,32.89 C36.2 ; R251.1 v9(9.58,9.35) ; v8(141.44,123.94) 141.53,124.03 C392.2 ; U38.7 170.39,92.66 v9(169.88,92.16) ; R906.2 139.85,122.48 v8(139.85,123.13) ; C210.2 v9(163.07,38.56) ; C71.2 115.26,38.92 v8(115.26,37.48) ; R432.2 142.88,121.62 v7(143.76,121.62) ; v11(95.48,79.35) 95.71,79.58 C81.2 ; C113.2 v9(42.04,92.79) ; C234.1 v9(160.2,83.82) ; C61.2 119.26,31.88 v8(119.26,31.88) ; U34.3 v9(167.07,84.22) ; v8(89.74,25.88) 89.84,25.78 C35.2 ; C4.2 v9(169.55,43.91) ; C245.2 v9(174.2,94.32) ; v8(104.98,29.08) 105.24,29.34 C66.2 ; C548.2 v7(121.54,81.74) ; v7(111.66,114.64) v7(110.87,114.64) R460.1 R461.1 R454.1 ; C302.2 139.4,131.19 138.86,131.19 v7(138.81,131.15) ; v9(42.16,126.19) 42.05,126.3 C161.2 v9(40.89,127.46) ; C69.2 v9(99.95,40) ; C211.2 v9(99.08,148.45) ; C562.2 v7(143.87,122.43) ; v9(20.24,14.84) 20.22,14.86 Q13.S ; C200.2 v9(175.41,51.31) ; C219.2 v9(56.73,90.05) ; R453.1 v7(101.6,110.19) ; R453.1 101.36,109.43 100.71,108.78 v7(100.71,108.44) ; v9(73.56,116.29) 73.56,115.42 R680.1 ; v8(97.62,33.48) 97.6,33.48 97.14,33.02 96.9,33.02 96.77,32.89 ; v9(62.71,119.24) 62.67,119.24 62.67,119.27 62.74,119.27 62.74,120.22 C185.2 ; C65.2 106.05,31.88 106.76,32.59 v9(106.76,32.72) ; v9(48.94,120.6) 48.95,120.6 48.95,119.78 C154.2 49.78,119.46 v9(50.42,118.83) ; C103.2 v7(24.26,133.56) ; C207.2 v9(185.04,69.98) ; 112.01,34.92 112.71,34.92 v8(112.86,35.08) ; C167.1 v9(44.32,134.07) ; C202.2 v9(175.41,46.23) ; C253.2 v9(172.21,24.21) ; Q15.S 13.61,18.17 v9(13.64,18.14) ; U26.3 v7(55.37,110.76) ; v9(25.4,125.68) C157.2 ; C157.2 v9(26.47,127.16) ; C157.2 v9(26.47,124.36) ; R414.1 75.82,149.23 v9(76.2,149.61) ; C60.2 v9(111,32.77) ; v9(137.71,134.67) 137.67,134.63 C402.2 ; C214.2 v9(161.04,51.69) ; v8(82.21,34.68) 81.97,34.92 81.53,34.92 ; U71.3 v9(24.52,45.87) ; C164.2 v9(42.67,120.35) ; C194.1 60.2,101.93 v9(60.18,101.94) ; v8(104.82,34.28) 105.19,33.91 C68.2 ; C191.2 v9(53.5,94.95) ; C331.2 96.11,86.14 v11(96.64,85.62) ; U49.2 v9(170.56,39.88) ; R381.1 v9(180.47,82.25) ; R599.1 v8(9.58,12.78) ; C221.2 v9(181.74,89.28) ; U98.3 v9(164.85,44.89) ; v9(52.58,93.05) 52.1,92.57 J17.MNT2 52.58,91.42 52.58,90.98 v9(52.54,90.93) ; C315.2 77.22,115.91 v9(77.6,116.29) ; C162.2 v9(39.12,126.45) ; R245.1 v8(9.58,2.62) ; R252.1 v9(16.18,9.35) ; v9(135.26,93.6) 135.12,93.46 U104.8 ; v9(75.77,99.27) 75.95,99.27 R697.1 ; v5(88.14,81.66) v7(87.38,81.66) ; v11(109.02,79.51) 108.76,79.25 C291.2 ; v9(41.29,105.27) 41.29,105.28 U23.10 ; v9(79.76,99.02) R695.1 ; v9(52.1,83.7) J17.MNT1 v9(53.25,84.62) ; v11(112.45,75.9) 112.42,75.9 112.42,75.9 111.91,75.9 C385.2 ; R595.1 v9(9.58,19.51) ; C190.2 v9(56.39,94.19) ; C3.2 v9(167.51,47.45) ; v7(91.62,74.17) 91.95,73.84 C570.2 ; v11(93.12,83.13) 93.52,82.73 C297.2 ; U73.16 v9(163.7,33.61) ; v7(106.81,114.64) R456.1 R457.1 R454.1 ; U99.3 160.71,74.03 160.01,74.03 v9(159.77,73.79) ; v8(120.06,38.28) 119.89,38.45 C63.2 ; v11(85.47,81.94) L34.2 v11(85.47,84.43) ; U73.10 v9(171.32,30.58) ; v7(34.29,111.46) 34.29,111.08 34.61,110.76 U22.3 ; v7(102.25,92.08) 102.23,92.08 101.98,91.82 101.98,91.31 ; Q2.S 19.89,4.7 v9(20.19,4.4) ; v7(109.86,80.85) 109.47,80.85 109.09,81.23 L24.2 109.09,82.5 109.47,82.89 v7(109.86,82.89) ; 96.77,34.92 97.46,34.92 v8(97.61,35.08) ; v9(30.48,99.4) 30.23,99.14 C124.2 ; v9(162.33,76.99) 162.23,77.09 C237.1 ; C472.2 75.44,115.78 v9(74.93,116.29) ; v7(118.75,79.08) 117.98,79.08 ; U2.3 v9(166.23,42.75) ; v8(113.66,37.48) 112.91,37.48 112.39,36.96 C74.2 ; C203.2 v9(175.41,43.69) ; U33.3 v9(9.4,25.32) ; C228.1 v9(166.8,78.77) ; R255.1 v8(9.58,5.92) ; C73.2 120.43,33.91 v8(120.06,34.28) ; C204.2 v9(175.41,41.15) ; v9(62.61,127.46) C182.2 61.84,127.07 v9(61.84,127.46) ; C254.2 v9(171.2,16.97) ; Q4.S 20.22,11.31 v9(20.24,11.28) ; v11(101.73,66.27) v11(101.73,66.76) C296.2 ; 97.41,79.2 97.41,80.01 v11(97.43,80.04) ; v9(171.58,82.42) 171.19,82.81 U63.9 ; X1.2 v9(173.99,149.57) ; C121.1 v9(10.01,118.06) ; C145.2 25.4,63.68 v9(25.73,64.01) ; C310.2 v9(55.63,47.2) ; C139.2 v9(28.58,74.12) ; C220.2 v9(11.94,33.3) ; v9(19.32,22.43) Q14.S ; C30.2 v9(84.71,39.75) ; R454.1 v7(108.84,114.64) ; C12.2 90.8,74.04 v7(90.93,74.17) ; U73.7 v9(171.32,38.18) ; R597.1 v9(16.18,12.91) ; R591.1 v9(9.58,16.08) ; C171.2 v9(39.36,108.41) ; C106.1 v9(18.67,137.8) ; v9(60.58,126.37) 60.71,126.37 60.83,126.24 C183.2 ; C309.2 v9(51.56,47.2) ; C102.2 v7(24.26,134.7) ; C193.1 v9(60.2,97.22) ; v11(90.78,84.71) C404.2 ; U63.3 v9(176.78,86.07) ; v9(55.23,102.33) U25.10 ; C382.2 v7(136.4,131.4) ; 102.62,86.95 v11(102.18,86.95) ; v9(175.41,56.39) C198.2 ; U48.2 v9(171.66,53.55) ; C403.2 v11(87.43,82.78) ; C75.2 120.48,29.34 120.36,29.21 v8(120.27,29.21) ; v9(175.41,58.93) C197.2 ; U73.9 v9(172.59,30.58) ; C170.2 v7(36.93,100.44) ; C449.2 v9(175.26,2.79) ; C119.2 v9(25.4,106.63) ; R256.1 v7(16.18,5.92) ; Q1.S 13.61,4.7 v9(13.64,4.68) ; C443.2 v9(170.56,89.79) ; C444.2 v9(169.52,59.01) ; 161.8,48.39 v9(161.8,47.62) ; C448.2 v9(167.89,64.34) ; C426.2 v9(173.36,89.79) ; C5.2 v9(164.72,53.55) ; C56.2 v9(95.76,32.64) ; Q3.S 13.61,11.31 v9(13.64,11.28) ; C400.2 v11(95.71,85.48) ; C146.1 v9(16.26,67.77)
  BOTTOM w0.508: C267.2 C327.2 98.17,88.04 v11(97.9,88.31) ; v9(72.14,99.8) 72.16,99.78 R700.1 ; v7(143.94,125.19) 143.92,125.18 R431.2 ; C268.2 v7(135.38,114.64) ; C268.2 v7(134.1,115.73) ; C268.2 v7(136.66,115.73) ; C122.2 v9(25.4,104.09) ; R427.1 v9(158.37,103.6) ; C95.2 125.98,16.61 v9(126.06,16.54) ; C95.2 124.62,17.92 v9(124.59,17.96) ; C95.2 127.22,17.92 v9(127.25,17.96) ; C476.2 v9(158.8,105) ; 135.51,120.99 C272.2 v7(135.93,120.1) ; 135.51,120.99 135.13,121.37 v7(134.87,121.37) ; 135.51,120.99 v7(135,120.48) ; v7(135.89,129.88) 136.37,129.39 C383.2 ; v9(67.82,141.69) 68.32,141.71 C218.2 68.34,140.42 v9(67.82,140.42) ; C134.2 C138.2 30.26,81.36 v9(30.48,81.58) ; C117.2 25.4,100.51 v9(25.3,100.41) ; v7(150.2,122.38) C282.2 v7(151.13,123.27) ; FB12.2 181.66,20.07 v9(181.64,20.04) ; FB12.2 182.84,21.2 v9(182.91,21.26) ; FB12.2 182.84,18.83 v9(182.85,18.82) ; v11(79.73,102.49) 79.45,102.21 Q20.S ; v9(70.61,147.53) 71.29,147.53 C217.2 71.03,148.54 v9(70.74,148.54) ; v7(141.61,116.58) C285.2 v7(140.72,115.65) ; v7(134.49,118.95) C468.2 v7(135.53,117.81) ; Q22.S 72.18,103.22 v9(72.19,103.23) ; R709.1 68.96,97.74 v9(68.45,97.24) ; v9(28.5,51.41) 28.19,51.72 R228.1 ; C188.1 66.04,142.4 v9(66.01,142.42) ; v7(131.65,127.59) 131.69,127.55 132.42,127.55 C453.2 ; R16.2 v7(133.31,122.38) ; v7(150.2,126.07) C283.2 v7(151.13,125.05) ; C313.2 v9(123.57,19.94) ; C152.2 155.83,139.57 v9(155.83,140.21) ; C96.2 v9(118.11,17.67) ; C96.2 v9(120.65,17.67) ; C96.2 v9(119.38,16.54) ; J16.MNT2 v9(80.4,132.37) ; J16.MNT2 v9(80.4,129.74) ; J16.MNT2 v9(79.08,131.05) ; v9(26.16,94.39) C125.2 v9(24.97,95.6) ; C141.2 v9(25.4,57.87) ; R704.1 v9(68.45,90.63) ; v9(25.27,82.66) 25.4,82.78 C129.2 ; v9(25.27,76.79) 25.27,76.79 26.16,77.68 C136.2 v9(24.97,77.82) ; v7(143.76,121.62) 143.76,120.95 C274.2 144.61,120.1 v7(145.03,120.1) ; C151.2 27.43,50.37 v9(27.69,50.12) ; v9(67.87,85.91) 67.91,85.95 Q24.S ; Q23.S v9(67.96,93.06) ; v9(28.19,76.28) R186.1 ; v9(26.16,84.79) 25.91,84.54 C128.2 ; C284.2 v7(130.99,128.99) ; C284.2 131.69,129.67 v7(131.32,129.67) ; C284.2 132.37,128.95 131.75,128.33 v7(131.34,128.33) ; C98.2 v9(129.79,24) ; Q21.S 75.61,103.22 v9(75.62,103.23) ; C132.2 v9(25.4,86.31) ; 183.62,136.31 J9.21 ; J9.21 183.62,137.92 ; J9.21 185.24,136.31 ; v7(139.19,115.65) C452.2 v7(138.3,116.58) ; v9(30.48,56.82) 30.26,56.6 C148.2 C150.2 ; C126.2 C124.2 ; C127.2 v9(32.51,93.68) ; C317.2 v7(150.22,120.86) ; C317.2 v7(149.08,121.98) ; C317.2 v7(149.08,119.74) ; C212.2 v9(95.89,144.27) ; C216.2 v9(68.83,139.4) ; C417.2 v9(156.72,102.96) ; v9(67.82,99.4) 68.4,99.98 Q25.S ; U41.4 v9(170.56,16.21) ; v7(143.64,117.94) 144.11,118.41 C275.2 v7(145.03,118.83) ; C143.2 v9(25.4,61.55)
  vias: v2(39.57,63.02) v2(39.6,62.21) v2(39.6,60.91) v2(39.62,58.7) v2(39.7,87.66) v2(39.73,86.85) v2(39.73,85.55) v2(39.65,59.85) v2(39.78,84.49) v2(39.75,83.34) v2(46.99,39.67) v2(48.25,15.87) v2(48.77,39.67) v2(51.94,37.72) v2(53.85,37.72) v2(58.42,51.69) v2(58.55,76.96) v2(59.69,53.34) v2(59.82,76.96) v2(59.94,54.99) v2(61.61,112.13) v2(62.48,60.2) v2(62.88,111.36) v2(63.88,61.47) v2(64.64,113.04) v2(68.33,116.52) v2(69.09,125.98) v2(70.2,115.22) v2(70.56,91.09) v2(71.72,116.44) v2(73.1,90.96) v2(73.43,115.2) v2(73.66,125.98) v2(73.66,124.59) v2(76.53,91.09) v2(77.14,115.22) v2(78.74,89.28) v2(78.86,86.34) v2(79.1,116.66) v2(79.63,125.98) v2(79.63,124.59) v2(80.64,89.15) v2(80.98,115.18) v2(81.93,87.42) v2(88.23,116.67) v2(89.41,125.48) v2(89.58,123.92) v2(90.2,115.5) v2(91.86,116.77) v2(92.62,115.5) v2(93.22,124.84) v2(93.25,114.61) v2(95.41,114.61) v2(97.06,114.61) v2(100.75,116.77) v2(102.02,125.03) v2(102.74,123.65) v2(105.57,116.77) v2(105.57,115.12) v2(106.05,123.75) v2(107.1,123.12) v2(107.48,115.37) v2(111.41,111.56) v2(114.22,116.13) v2(115.86,115.88) v2(116.62,113.72) v2(117.51,114.23) v2(118.61,95.97) v2(118.87,106.41) v2(119.63,94.44) v2(120.65,101.94) v2(122.22,102.67) v2(133.73,139.15) v2(133.73,137.88) v2(134.37,140.54) v2(134.37,134.19) v2(136.37,140.49) v2(137.03,134.07) v2(138.46,140.41) v2(139.24,138) v2(149.28,83.95) v2(150.29,80.78) v2(151.05,87.89) v2(152.07,80.78) v2(153.47,84.21) v2(154.1,81.92) v2(155.5,87.63) v2(155.5,82.17) v2(158.67,86.36) v2(165.23,120.22) v2(165.25,119.21) v2(165.25,117.81) v2(165.74,123.27) v2(165.76,122) v2(165.76,120.86) v2(166.9,122) v2(166.9,120.86) v3(39.57,63.02) v3(39.6,62.21) v3(39.6,60.91) v3(39.62,58.7) v3(39.7,87.66) v3(39.73,86.85) v3(39.73,85.55) v3(39.65,59.85) v3(39.78,84.49) v3(39.75,83.34) v3(46.99,39.67) v3(48.25,15.87) v3(48.77,39.67) v3(51.94,37.72) v3(53.85,37.72) v3(58.42,51.69) v3(58.55,76.96) v3(59.69,53.34) v3(59.82,76.96) v3(59.94,54.99) v3(61.61,112.13) v3(62.48,60.2) v3(62.88,111.36) v3(63.88,61.47) v3(64.64,113.04) v3(68.33,116.52) v3(69.09,125.98) v3(70.2,115.22) v3(70.56,91.09) v3(71.72,116.44) v3(73.1,90.96) v3(73.43,115.2) v3(73.66,125.98) v3(73.66,124.59) v3(76.53,91.09) v3(77.14,115.22) v3(78.74,89.28) v3(78.86,86.34) v3(79.1,116.66) v3(79.63,125.98) v3(79.63,124.59) v3(80.64,89.15) v3(80.98,115.18) v3(81.93,87.42) v3(88.23,116.67) v3(89.41,125.48) v3(89.58,123.92) v3(90.2,115.5) v3(91.86,116.77) v3(92.62,115.5) v3(93.22,124.84) v3(93.25,114.61) v3(95.41,114.61) v3(97.06,114.61) v3(100.75,116.77) v3(102.02,125.03) v3(102.74,123.65) v3(105.57,116.77) v3(105.57,115.12) v3(106.05,123.75) v3(107.1,123.12) v3(107.48,115.37) v3(111.41,111.56) v3(114.22,116.13) v3(115.86,115.88) v3(116.62,113.72) v3(117.51,114.23) v3(118.61,95.97) v3(118.87,106.41) v3(119.63,94.44) v3(120.65,101.94) v3(122.22,102.67) v3(133.73,139.15) v3(133.73,137.88) v3(134.37,140.54) v3(134.37,134.19) v3(136.37,140.49) v3(136.65,129.53) v3(137.03,134.07) v3(138.46,140.41) v3(139.24,138) v3(149.28,83.95) v3(150.29,80.78) v3(151.05,87.89) v3(152.07,80.78) v3(153.47,84.21) v3(154.1,81.92) v3(155.5,87.63) v3(155.5,82.17) v3(158.67,86.36) v3(165.23,120.22) v3(165.25,119.21) v3(165.25,117.81) v3(165.74,123.27) v3(165.76,122) v3(165.76,120.86) v3(166.9,122) v3(166.9,120.86) v4(107.83,76.82) v6(14.71,109.76) v6(14.76,112.12) v6(15.57,107.57) v6(15.82,112.22) v6(16.61,113.01) v6(20.8,111.36) v6(21.74,106.08) v6(27.05,105.03) v6(30.23,109.89) v6(31.67,105.36) v6(43.81,103.46) v6(44.07,104.09) v6(44.58,99.27) v6(44.83,107.14) v6(45.97,107.14) v6(47.24,99.14) v6(47.5,107.14) v6(49.02,107.14) v6(49.15,98.89) v6(50.93,107.14) v6(51.18,99.65) v6(51.31,105.49) v6(51.56,101.43) v6(63.65,103.69) v6(68.35,114.15) v6(68.45,108.92) v6(68.45,108.03) v6(70.15,113.16) v6(80.64,82.8) v6(80.64,81.41) v6(84.3,112.45) v6(87.76,121.65) v6(89.99,120.68) v6(90.8,3.05) v6(92.1,121.65) v6(92.2,68.07) v6(92.33,68.71) v6(93.34,3.05) v6(93.98,67.82) v6(94.11,120.68) v6(94.74,69.6) v6(95.25,69.93) v6(95.89,3.05) v6(96.22,72.7) v6(97.35,92.83) v6(97.35,91.81) v6(97.35,91.05) v6(97.66,69.34) v6(97.74,120.68) v6(98.42,3.05) v6(100.15,121.32) v6(101.35,90.51) v6(102.36,90.51) v6(103.5,118.95) v6(104.77,119.21) v6(105,111.43) v6(105.03,76.18) v6(105.49,112.76) v6(106.05,76.2) v6(107.04,75.37) v6(108.18,105.82) v6(110.54,76.59) v6(115.7,76.33) v6(116.33,75.21) v6(116.87,78.03) v6(116.87,77.24) v6(120.14,88.14) v6(120.27,91.39) v6(121.41,91.39) v6(121.41,88.14) v6(122.68,90.76) v6(122.68,89.74) v6(122.68,88.73) v6(128.33,124.3) v6(129.22,124.3) v6(130.24,125.82) v6(130.24,125.06) v6(130.24,123.41) v6(130.36,131.92) v6(130.36,131.28) v6(130.94,126.45) v6(131.32,125.18) v6(131.95,135.34) v6(132.21,125.18) v6(132.21,123.25) v6(132.72,135.34) v6(132.84,123.25) v6(134.37,135.34) v6(135.69,135) v6(142.88,136.61) v6(143.76,136.61) v6(144.78,136.61) v6(145.67,136.61) v6(148.34,133.69) v6(148.34,132.92) v6(148.34,132.16) v6(148.34,128.99) v6(148.34,128.22) v6(148.34,127.59) v6(175.29,26.42) v7(14.71,109.76) v7(14.76,112.12) v7(15.57,107.57) v7(15.82,112.22) v7(16.61,113.01) v7(20.8,111.36) v7(21.74,106.08) v7(27.05,105.03) v7(30.23,109.89) v7(31.67,105.36) v7(43.81,103.46) v7(44.07,104.09) v7(44.58,99.27) v7(44.83,107.14) v7(45.97,107.14) v7(47.24,99.14) v7(47.5,107.14) v7(49.02,107.14) v7(49.15,98.89) v7(50.93,107.14) v7(51.18,99.65) v7(51.31,105.49) v7(51.56,101.43) v7(63.65,103.69) v7(68.35,114.15) v7(68.45,108.92) v7(68.45,108.03) v7(70.15,113.16) v7(80.64,82.8) v7(80.64,81.41) v7(84.3,112.45) v7(87.76,121.65) v7(89.99,120.68) v7(90.8,3.05) v7(92.1,121.65) v7(92.2,68.07) v7(92.33,68.71) v7(93.34,3.05) v7(93.98,67.82) v7(94.11,120.68) v7(94.74,69.6) v7(95.25,69.93) v7(95.89,3.05) v7(96.22,72.7) v7(97.35,92.83) v7(97.35,91.81) v7(97.35,91.05) v7(97.66,69.34) v7(97.74,120.68) v7(98.42,3.05) v7(100.15,121.32) v7(101.35,90.51) v7(102.36,90.51) v7(103.5,118.95) v7(104.77,119.21) v7(105,111.43) v7(105.03,76.18) v7(105.49,112.76) v7(106.05,76.2) v7(107.04,75.37) v7(108.18,105.82) v7(110.54,76.59) v7(115.7,76.33) v7(116.33,75.21) v7(116.87,78.03) v7(116.87,77.24) v7(120.14,88.14) v7(120.27,91.39) v7(121.41,91.39) v7(121.41,88.14) v7(122.68,90.76) v7(122.68,89.74) v7(122.68,88.73) v7(128.33,124.3) v7(129.22,124.3) v7(130.24,125.82) v7(130.24,125.06) v7(130.24,123.41) v7(130.36,131.92) v7(130.36,131.28) v7(130.94,126.45) v7(131.32,125.18) v7(131.95,135.34) v7(132.21,125.18) v7(132.21,123.25) v7(132.72,135.34) v7(132.84,123.25) v7(134.37,135.34) v7(135.69,135) v7(142.88,136.61) v7(143.76,136.61) v7(144.78,136.61) v7(145.67,136.61) v7(148.34,133.69) v7(148.34,132.92) v7(148.34,132.16) v7(148.34,128.99) v7(148.34,128.22) v7(148.34,127.59) v7(175.29,26.42) v8(71.17,83.94) v8(72.31,85.58) v8(73.23,85.63) v8(90.12,84.56) v8(152.53,25.35) v9(2.54,149.81) v9(2.54,145.5) v9(2.54,142.96) v9(2.54,140.42) v9(2.54,137.88) v9(2.54,135.34) v9(2.54,132.8) v9(2.54,130.26) v9(2.54,127.72) v9(2.54,125.18) v9(2.54,122.64) v9(2.54,120.1) v9(2.54,117.56) v9(2.54,115.02) v9(2.54,112.48) v9(2.54,109.94) v9(2.54,107.4) v9(2.54,104.86) v9(2.54,102.32) v9(2.54,99.78) v9(2.54,97.24) v9(2.54,94.7) v9(2.54,92.16) v9(2.54,89.62) v9(2.54,87.08) v9(2.54,84.54) v9(2.54,82) v9(2.54,79.46) v9(2.54,76.92) v9(2.54,74.38) v9(2.54,71.84) v9(2.54,69.3) v9(2.54,66.76) v9(2.54,64.22) v9(2.54,61.68) v9(2.54,59.14) v9(2.54,56.6) v9(2.54,54.06) v9(2.54,34.04) v9(2.54,31.5) v9(2.54,28.96) v9(2.54,26.42) v9(2.54,23.88) v9(2.54,21.34) v9(2.54,18.8) v9(2.54,16.26) v9(2.54,11.18) v9(2.54,6.1) v9(2.54,3.56) v9(6.1,36.53) v9(6.1,35.51) v9(6.73,45.47) v9(6.73,44.2) v9(6.73,42.93) v9(6.86,34.04) v9(6.86,32.77) v9(6.86,31.5) v9(7.24,36.53) v9(7.24,35.51) v9(7.62,149.81) v9(10.16,149.81) v9(11.43,42.16) v9(11.43,39.75) v9(12.7,149.81) v9(13.84,2.49) v9(15.24,149.81) v9(16.89,23.2) v9(17.78,149.81) v9(18.03,23.58) v9(19.3,23.58) v9(20.07,117.43) v9(20.32,149.81) v9(21.34,118.7) v9(22.86,149.81) v9(25.4,149.81) v9(27.94,149.81) v9(27.94,2.54) v9(30.48,149.81) v9(30.48,101.43) v9(30.48,100.41) v9(30.48,83.61) v9(30.48,82.6) v9(30.48,58.85) v9(30.48,57.83) v9(30.48,2.54) v9(31.5,101.43) v9(31.5,100.41) v9(31.5,99.4) v9(31.5,83.61) v9(31.5,82.6) v9(31.5,81.58) v9(31.5,58.85) v9(31.5,57.83) v9(32.13,16.64) v9(32.13,15.37) v9(32.13,14.1) v9(32.51,101.43) v9(32.51,100.41) v9(32.51,99.4) v9(32.51,83.61) v9(32.51,82.6) v9(32.51,81.58) v9(32.51,58.85) v9(32.51,57.83) v9(32.51,56.82) v9(33.02,149.81) v9(33.02,123.02) v9(33.02,120.86) v9(35.23,122.97) v9(35.31,118.83) v9(35.56,149.81) v9(37.41,123.19) v9(37.36,120.65) v9(37.34,118.83) v9(38.1,149.81) v9(40.64,149.81) v9(41.78,54.56) v9(41.91,26.16) v9(42.55,83.52) v9(42.55,82.25) v9(42.55,80.98) v9(43.18,149.81) v9(43.18,2.54) v9(44.32,54.56) v9(44.45,26.16) v9(44.7,22.17) v9(45.09,91.14) v9(45.09,84.79) v9(45.09,80.98) v9(45.72,149.81) v9(45.72,2.54) v9(46.86,54.56) v9(46.99,82.25) v9(47.24,22.17) v9(48.26,149.81) v9(48.26,2.54) v9(48.36,57.23) v9(49.02,56.49) v9(49.53,82.25) v9(49.53,80.98) v9(49.78,20.57) v9(50.8,149.81) v9(50.8,2.54) v9(52.07,20.57) v9(52.45,54.56) v9(52.45,53.29) v9(52.45,52.02) v9(52.58,89.62) v9(53.34,149.81) v9(53.34,82.25) v9(53.34,80.98) v9(53.72,54.56) v9(53.72,53.29) v9(54.74,123.02) v9(54.74,120.86) v9(54.74,118.83) v9(54.99,54.56) v9(54.99,53.29) v9(55.88,149.81) v9(55.88,2.54) v9(56.95,122.97) v9(57.02,118.83) v9(57.66,89.62) v9(58.42,149.81) v9(58.42,2.54) v9(59.08,120.65) v9(59.05,118.83) v9(59.13,123.19) v9(60.96,149.81) v9(60.96,2.54) v9(63.5,149.81) v9(63.5,2.54) v9(64.01,58.39) v9(65.48,59.26) v9(66.04,149.81) v9(66.04,2.54) v9(66.42,112.22) v9(66.42,110.83) v9(67.31,73.11) v9(68.58,149.81) v9(68.58,148.67) v9(68.58,2.54) v9(73.13,145.09) v9(73.3,144.12) v9(73.66,74.63) v9(73.66,2.54) v9(74.91,144.07) v9(75.95,116.29) v9(78.74,149.81) v9(79.63,44.07) v9(79.63,42.8) v9(88.9,149.81) v9(90.17,66.5) v9(91.19,38.23) v9(91.19,36.96) v9(91.19,35.69) v9(91.19,34.42) v9(91.44,149.81) v9(91.44,40.13) v9(92.2,50.8) v9(92.23,47.12) v9(92.23,45.85) v9(92.23,44.58) v9(92.46,36.96) v9(92.46,35.69) v9(92.46,34.42) v9(93.98,149.81) v9(98.42,52.07) v9(100.08,45.97) v9(100.97,42.42) v9(102.49,52.32) v9(102.49,51.05) v9(103.12,19.3) v9(103.63,47.62) v9(103.76,69.3) v9(103.89,51.69) v9(103.91,19.3) v9(103.89,18.54) v9(104.52,46.74) v9(105.03,44.7) v9(105.03,43.43) v9(105.03,42.16) v9(105.03,40.89) v9(106.3,40.89) v9(106.3,39.62) v9(106.3,38.35) v9(106.43,36.96) v9(106.43,35.69) v9(106.43,34.42) v9(107.06,15.24) v9(107.06,14.22) v9(107.7,36.96) v9(107.7,35.69) v9(107.7,34.42) v9(108.58,15.24) v9(108.58,14.22) v9(108.71,47.37) v9(110.6,17.29) v9(115.95,43.43) v9(115.95,42.16) v9(116.84,47.62) v9(121.03,43.69) v9(121.03,42.42) v9(121.03,41.15) v9(124.46,2.54) v9(125.6,117.68) v9(125.6,115.65) v9(126.36,116.67) v9(127,2.54) v9(129.54,2.54) v9(130.18,124.29) v9(132.08,2.54) v9(134.11,136.1) v9(134.62,2.54) v9(137.16,2.54) v9(139.7,2.54) v9(142.24,2.54) v9(144.78,2.54) v9(147.07,136.1) v9(147.32,2.54) v9(149.2,108.97) v9(149.3,110.39) v9(149.86,2.54) v9(150.5,136.27) v9(150.75,105.49) v9(150.75,104.22) v9(151.64,136.02) v9(152.15,104.22) v9(152.4,2.54) v9(154.35,81.15) v9(154.94,2.54) v9(155.58,127.08) v9(155.58,125.68) v9(156.72,125.68) v9(157.4,84.33) v9(159.97,111.43) v9(159.97,110.16) v9(161.24,111.43) v9(161.24,110.16) v9(163.65,150.04) v9(163.86,142.98) v9(165.56,150.39) v9(165.84,142.09) v9(167.67,131.15) v9(167.67,129.75) v9(167.67,128.22) v9(167.71,126.06) v9(167.71,123.52) v9(169.37,142.11) v9(171.09,131.15) v9(171.09,129.75) v9(171.09,128.22) v9(171.91,142.11) v9(174.02,143.87) v9(177.95,2.54) v9(178.08,77.09) v9(178.08,75.82) v9(178.08,74.55) v9(179.35,77.09) v9(179.35,75.82) v9(179.35,74.55) v9(180.62,77.09) v9(180.62,75.82) v9(180.62,74.55) v9(180.75,131.02) v9(181.89,77.09) v9(181.89,75.82) v9(181.89,74.55) v9(183.03,149.81) v9(183.03,2.54) v9(183.16,77.09) v9(183.16,75.82) v9(183.16,74.55) v9(184.05,11.3) v9(184.18,131.02) v9(184.43,77.09) v9(184.43,75.82) v9(184.43,74.55) v9(185.29,142.62) v9(185.7,77.09) v9(185.7,75.82) v9(185.7,74.55) v9(187.07,141.61) v9(188.11,149.81) v9(188.18,146.38) v9(188.18,118.44) v9(188.18,115.9) v9(188.18,110.82) v9(188.18,108.28) v9(188.18,105.74) v9(188.18,103.2) v9(188.18,6.98) v9(188.18,4.44) v10(27.46,115.47) v10(33.45,106.08) v10(34.26,105.47) v10(36.27,105.85) v10(57.96,99.73) v10(58.04,101.43) v10(58.04,100.54) v10(59.23,96.17) v10(59.74,102.9) v10(60.43,96.12) v10(60.81,102.8) v10(61.59,96.09) v10(63.12,96.09) v10(64.92,96.88) v10(65,102.24) v10(64.97,99.27) v10(73.68,84.61) v10(73.78,83.74) v10(74.51,84.64) v10(74.52,84.23) v10(81.41,83.57) v10(87.1,91.56) v10(87.68,91.57) v10(88.29,91.57) v10(88.87,91.57) v10(89.48,91.54) v10(89.99,91.49) v10(90.45,91.49) v10(91.82,88.29) v10(91.77,87.88) v10(92.38,85.43) v10(92.81,82.14) v10(92.91,79.08) v10(93.01,78.21) v10(93.47,79.08) v10(94.01,79.1) v10(94.49,79.2) v10(94.82,88.24) v10(97.28,96.86) v10(97.92,98.13) v10(98.89,73.41) v10(98.93,98.13) v10(99.06,73.79) v10(99.19,73.06) v10(99.67,73.72) v10(99.69,71.58) v10(99.95,71.07) v10(100.23,92.82) v10(100.23,92.44) v10(100.23,92.03) v10(100.28,68.99) v10(100.6,76.19) v10(100.86,69.02) v10(100.97,92.54) v10(100.97,92.03) v10(101.73,86.95) v10(101.98,86.44) v10(102.67,77.75) v10(102.9,73.26) v10(103.1,73.66) v10(103.38,93.68) v10(103.63,93.3) v10(103.68,73.64) v10(104.27,99.69) v10(105.17,98.57) v10(105.17,97.87) v10(105.41,89.84) v10(106.22,89.87) v10(106.43,94.29) v10(106.43,93.78) v10(106.91,90.37) v10(107.16,89.1) v10(107.39,89.71) v10(108.58,94.29) v10(108.58,93.78) v10(108.58,83.95) v10(110.74,94.29) v10(110.74,93.78) v10(110.97,77.88) v10(111.07,83.77) v10(111.2,91) v10(111.2,90.5) v10(111.38,84.35) v10(111.71,91.64) v10(111.71,91) v10(111.71,90.5) v10(112.01,89.53) v10(112.22,91.64) v10(112.22,91) v10(112.22,90.5) v10(112.24,44.02) v10(112.24,43.38) v10(112.24,42.75) v10(112.24,42.11) v10(112.73,91) v10(112.65,85.22) v10(113.33,78.94) v10(113.33,80.02) v10(114.38,112.37) v10(114.38,110.98) v10(114.88,112.37) v10(114.88,110.98) v10(115.7,101.81) v10(116.2,101.81) v10(116.46,87.33) v10(116.71,101.81) v10(117.73,86.82) v10(117.73,85.81) v10(119.61,44.4) v10(119.61,43.76) v10(119.61,43.13) v10(119.61,42.49) v10(121.54,87.33) v10(122.81,86.7) v10(122.81,85.68) v11(27.46,115.47) v11(33.45,106.08) v11(34.26,105.47) v11(36.27,105.85) v11(57.96,99.73) v11(58.04,101.43) v11(58.04,100.54) v11(59.23,96.17) v11(59.74,102.9) v11(60.43,96.12) v11(60.81,102.8) v11(61.59,96.09) v11(63.12,96.09) v11(64.92,96.88) v11(65,102.24) v11(64.97,99.27) v11(73.68,84.61) v11(73.78,83.74) v11(74.51,84.64) v11(74.52,84.23) v11(81.41,83.57) v11(87.1,91.56) v11(87.68,91.57) v11(88.29,91.57) v11(88.87,91.57) v11(89.48,91.54) v11(89.99,91.49) v11(90.45,91.49) v11(91.82,88.29) v11(91.77,87.88) v11(92.38,85.43) v11(92.81,82.14) v11(92.91,79.08) v11(93.01,78.21) v11(93.47,79.08) v11(94.01,79.1) v11(94.49,79.2) v11(94.82,88.24) v11(97.28,96.86) v11(97.92,98.13) v11(98.89,73.41) v11(98.93,98.13) v11(99.06,73.79) v11(99.19,73.06) v11(99.67,73.72) v11(99.69,71.58) v11(99.95,71.07) v11(100.23,92.82) v11(100.23,92.44) v11(100.23,92.03) v11(100.28,68.99) v11(100.6,76.19) v11(100.86,69.02) v11(100.97,92.54) v11(100.97,92.03) v11(101.73,86.95) v11(101.98,86.44) v11(102.67,77.75) v11(102.9,73.26) v11(103.1,73.66) v11(103.38,93.68) v11(103.63,93.3) v11(103.68,73.64) v11(104.27,99.69) v11(105.17,98.57) v11(105.17,97.87) v11(105.41,89.84) v11(106.22,89.87) v11(106.43,94.29) v11(106.43,93.78) v11(106.91,90.37) v11(107.16,89.1) v11(107.39,89.71) v11(108.58,94.29) v11(108.58,93.78) v11(108.58,83.95) v11(110.74,94.29) v11(110.74,93.78) v11(110.97,77.88) v11(111.07,83.77) v11(111.2,91) v11(111.2,90.5) v11(111.38,84.35) v11(111.71,91.64) v11(111.71,91) v11(111.71,90.5) v11(112.01,89.53) v11(112.22,91.64) v11(112.22,91) v11(112.22,90.5) v11(112.24,44.02) v11(112.24,43.38) v11(112.24,42.75) v11(112.24,42.11) v11(112.73,91) v11(112.65,85.22) v11(113.33,78.94) v11(113.33,80.02) v11(114.38,112.37) v11(114.38,110.98) v11(114.88,112.37) v11(114.88,110.98) v11(115.7,101.81) v11(116.2,101.81) v11(116.46,87.33) v11(116.71,101.81) v11(117.73,86.82) v11(117.73,85.81) v11(119.61,44.4) v11(119.61,43.76) v11(119.61,43.13) v11(119.61,42.49) v11(121.54,87.33) v11(122.81,86.7) v11(122.81,85.68)
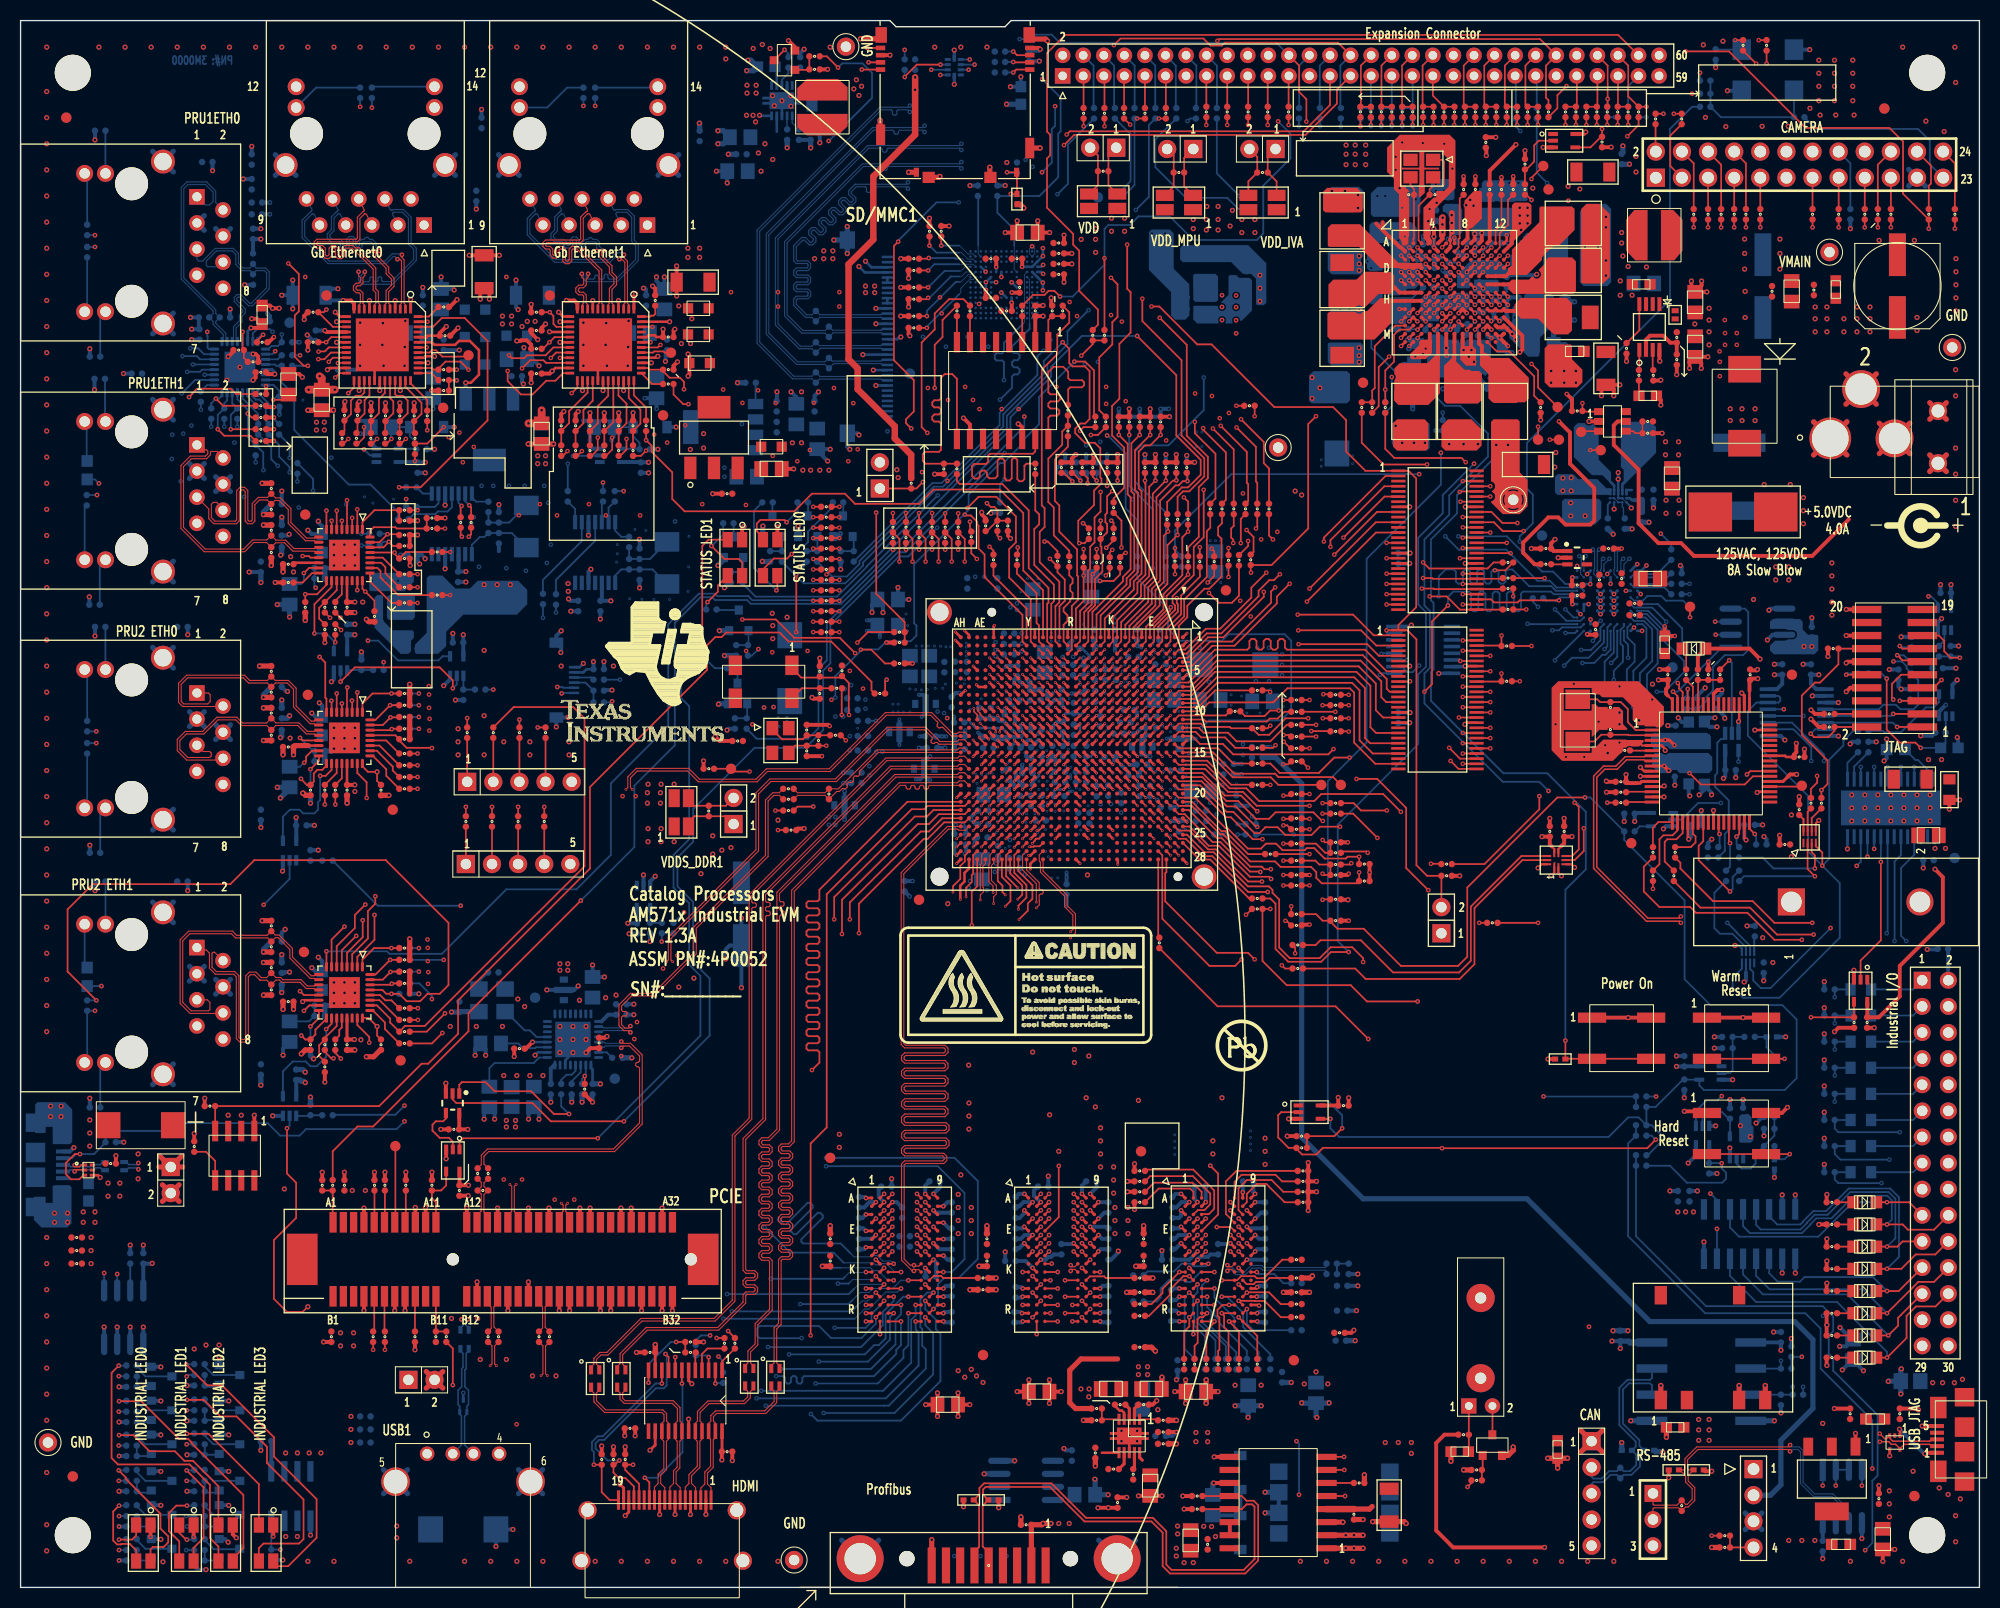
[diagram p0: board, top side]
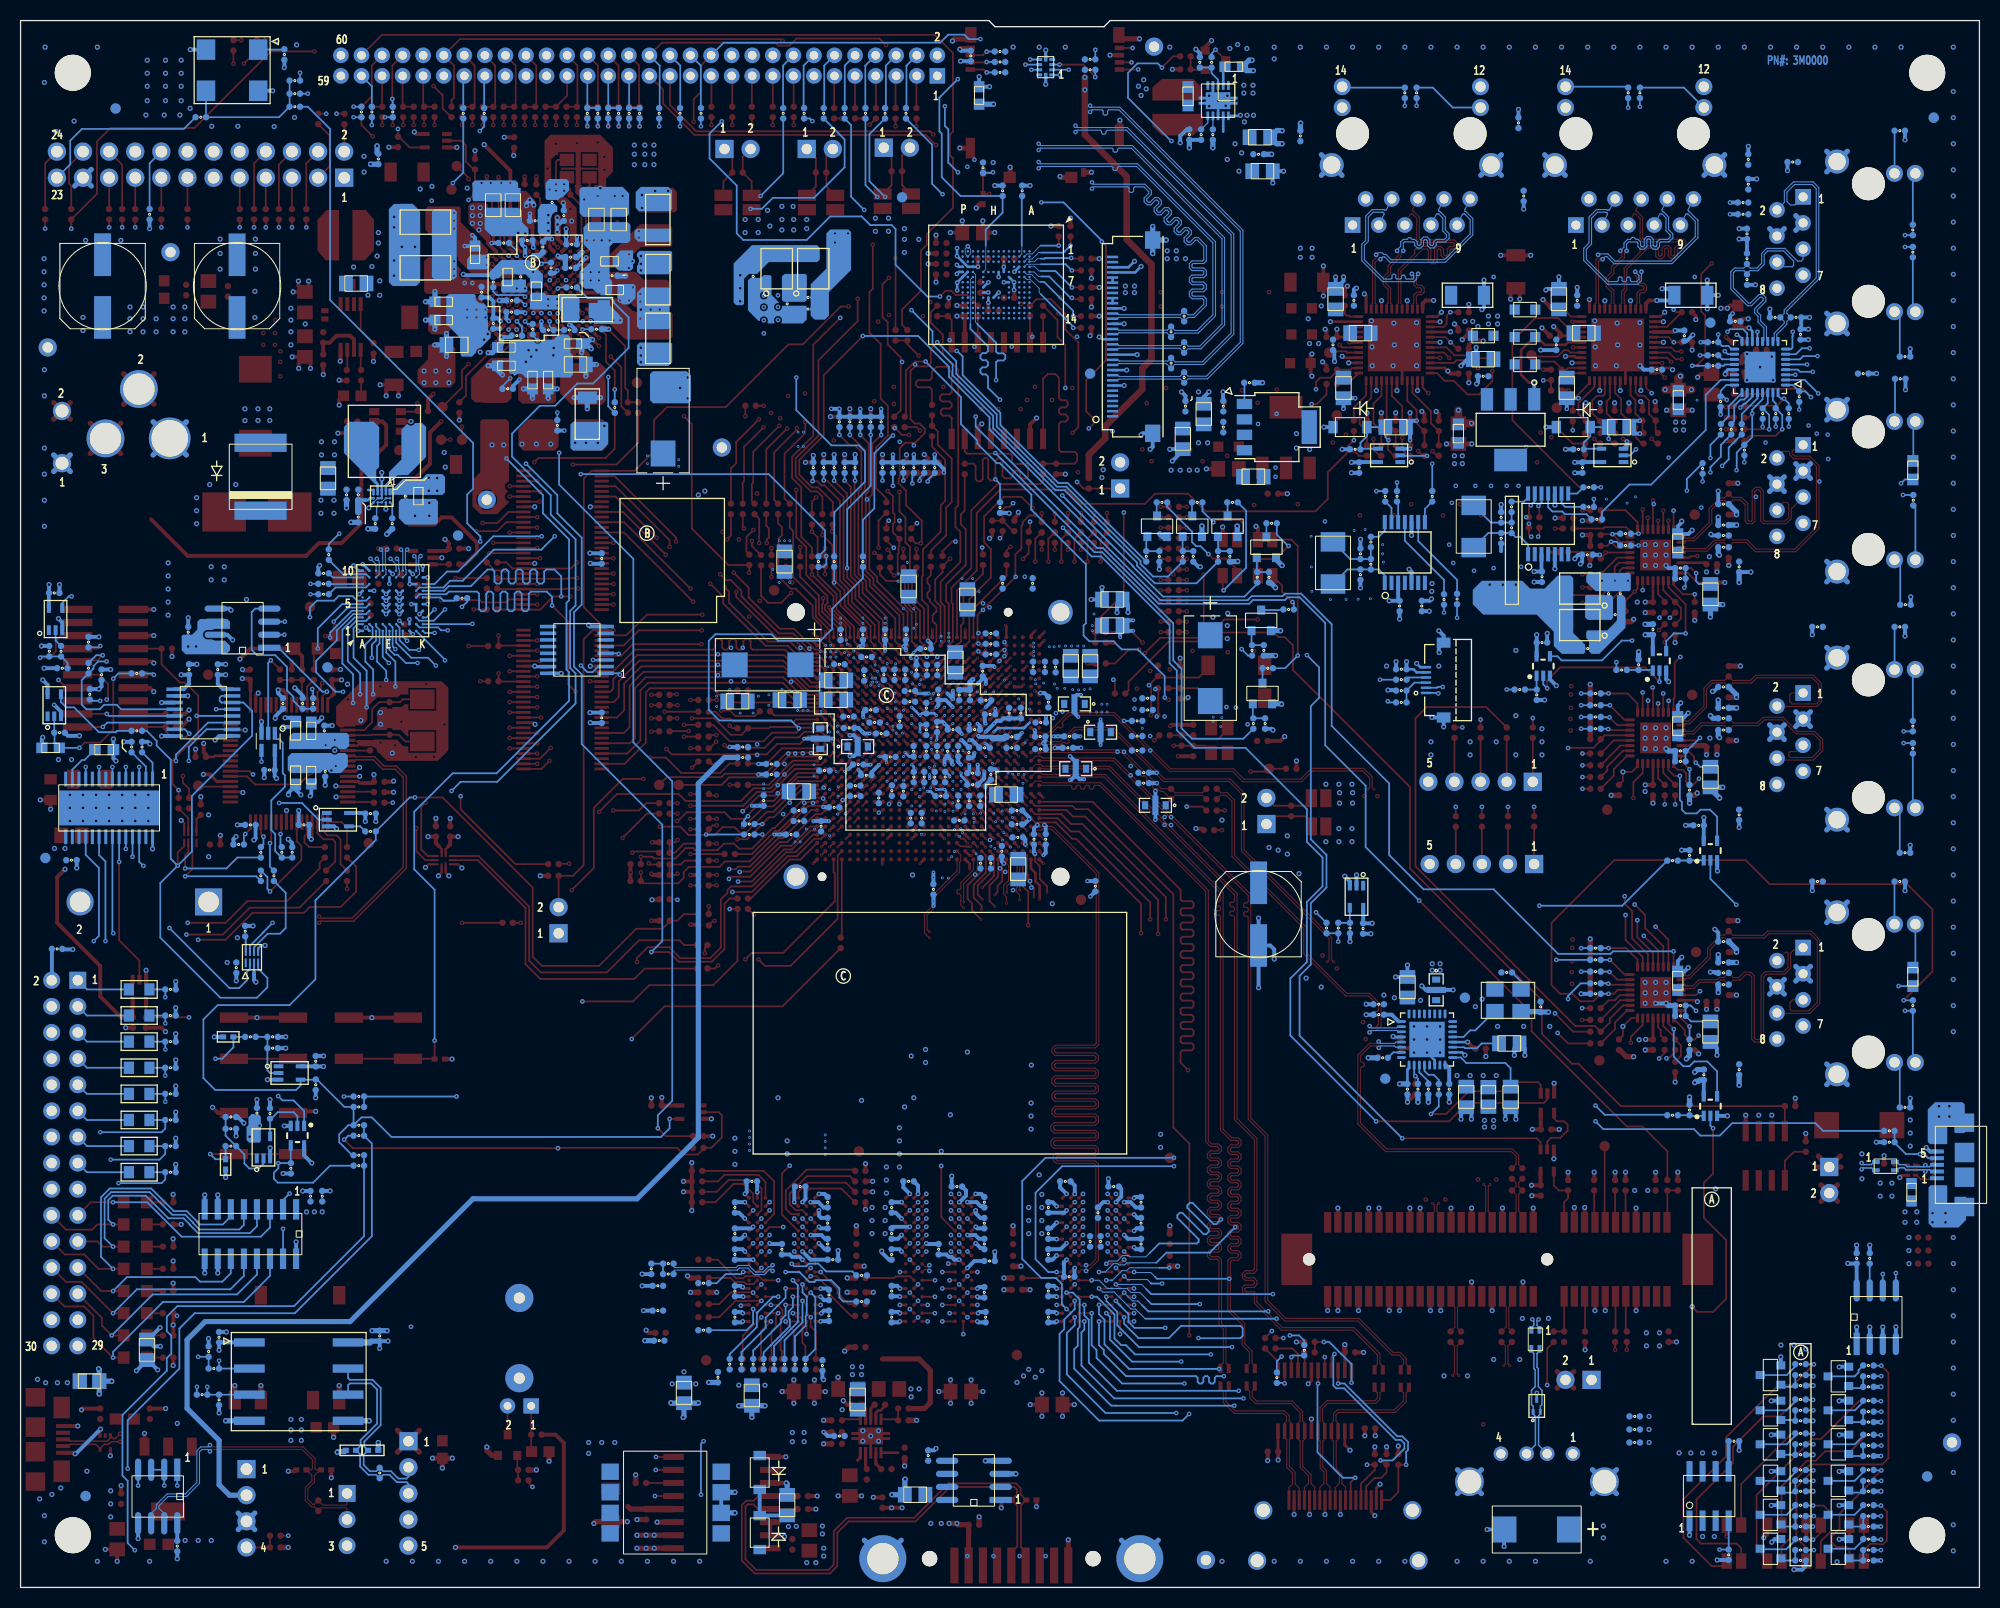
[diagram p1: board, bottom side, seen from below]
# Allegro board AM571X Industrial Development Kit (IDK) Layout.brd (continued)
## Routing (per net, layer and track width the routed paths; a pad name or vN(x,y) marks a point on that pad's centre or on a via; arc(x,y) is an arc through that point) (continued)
GND_CAN1: length 15.5
  TOP w0.508: C250.2 v9(149.48,11.61) ; C250.2 v9(148.51,12.57) ; C250.2 v9(150.44,12.57) ; U40.4 v9(167.13,19.64) ; U40.5 v9(169.67,19.64)
  L3_SIG1 w0.508: 151.98,5.8 J38.4 ; J38.4 151.98,7.41 ; J38.4 153.59,5.8 ; J38.4 153.59,7.41
  BOTTOM w0.508: v9(159.7,13.14) 159.64,13.21 159,13.21 U87.2 ; v9(154.86,24.97) C252.2 v9(156.31,24.97) ; U88.2 v9(155.71,14.1) ; v9(156.59,16.21) U41.5
GND_OSC0: length 10
  TOP w0.254: U1.AF15 v4(92.64,80.82)
  TOP w0.381: C1.2 78.56,83.9 v3(78.68,83.78) ; C2.2 v3(77.93,80.85)
  L3_SIG1 w0.381: 87.12,80.67 87.2,80.59 91.84,80.59 92.06,80.82 v4(92.64,80.82)
GNDPROFI: length 23.1
  TOP w0.381: R573.1 v9(107.57,8.76) ; U74.15 U74.14 ; v9(95.12,7.75) 95.12,7.87 95.12,7.88 U81.2 ; R578.1 v9(113.16,7.62) ; U74.11 v9(116.03,10.16) ; U74.9 v9(116.08,12.7) ; U80.2 v9(91.7,7.85)
  TOP w0.508: J14.5 v9(88.61,4.64) ; C430.2 v9(97.28,6.86)
  BOTTOM w0.381: L2.6 L2.7 ; 102.23,13.34 101.65,13.34 v9(101.47,13.51)
  BOTTOM w0.508: U52.3 v9(93.71,11.05) ; v9(121.03,7.26) L2.6 ; L2.7 v9(121.03,9.25) ; v9(105.77,9.02) C325.2 104.5,10.49 v9(104.47,10.52) ; U52.4 v9(96.67,12.32) ; C433.2 115.95,10.08 v9(116.03,10.16)
  vias: v9(112.52,5.97) v9(112.52,5.21) v9(115.06,5.94) v9(115.82,5.92) v9(116.2,4.95)
GNDUSB1: length 13.2
  BOTTOM w0.508: J23.S1 37.63,9.12 ; J23.S1 35.3,9.12 ; J23.S1 37.63,11.45 ; J23.S1 35.3,11.45 ; J23.S2 50.76,9.12 ; J23.S2 50.76,11.45 ; J23.S2 48.43,9.12 ; J23.S2 48.43,11.45
GNDUSB2:
  vias: v9(2.92,46.82) v9(2.92,45.8) v9(3.3,36.4) v9(3.3,35.51) v9(3.94,46.82) v9(3.94,45.8) v9(4.57,36.4) v9(4.57,35.51)
GNDUSBJ:
  vias: v9(185.95,19.91) v9(186.59,9.68) v9(186.92,19.91) v9(187.45,9.04) v9(188.06,19.91) v9(188.65,8.61) v9(188.85,20.24)
V1_2D: length 1.4
  BOTTOM w0.254: U89.B1 v8(156.91,93.37) ; U89.A7 v8(157.56,96.62) ; U89.K4 v8(151.71,94.67)
V1_2D_EN: length 1.6
  TOP w0.173: R451.1 148.86,99.51 U76.3
V1_8D: length 80.2
  TOP w0.254: U1.P20 v4(103.03,76.82) ; U1.T8 v4(100.64,87.21) ; U1.V22 v4(99.04,76.02) U1.V21 ; U1.P8 v4(103.03,87.21) ; U1.AA7 v4(96.64,88.01) ; U1.Y7 v4(97.44,88.01) ; U1.AA18 v4(96.64,78.42) ; U1.M9 v4(104.63,86.41) ; U1.G18 v4(108.63,78.42) ; U1.R8 v4(101.44,87.21) ; U1.H17 v4(107.83,79.22) ; v4(97.44,76.02) U1.Y21 U1.W21 v4(98.24,76.02) ; U1.W17 v4(98.24,79.22) ; U1.P21 v11(103.03,76.02) ; U1.AA19 v4(96.64,77.62) ; U1.W18 v4(98.24,78.42) ; U1.M8 v4(104.63,87.21) ; U1.N8 v4(103.83,87.21)
  TOP w0.381: R451.2 147.24,99.52 146.13,100.63 146.13,101.63 148.58,104.08 149.54,104.08 150.24,103.38 152.65,103.38 153.04,103.76 153.04,106.93 150.69,109.28 150.69,112.33 v3(149.61,113.41)
  L3_SIG1 w0.254: v5(104.23,87.46) 104.23,87.46 v4(103.83,87.21) ; v5(97.84,75.77) v4(98.24,76.02) ; v11(103.03,76.02) v5(103.43,75.77) ; v4(96.64,78.42) v5(96.24,78.17) ; v4(96.64,88.01) 96.24,88.26 v5(96.24,88.26) ; v4(97.44,88.01) v5(97.04,88.26) ; v4(98.24,79.22) v5(97.84,78.97) ; v4(99.04,76.02) v5(98.64,75.77) ; v4(103.03,76.82) v5(103.43,76.57) ; v4(104.63,86.41) v5(105.03,86.66) ; v4(107.83,79.22) v5(108.23,78.97) ; v4(98.24,78.42) v5(97.84,78.17) ; v5(100.24,87.46) 100.24,87.46 v4(100.64,87.21) ; v4(101.44,87.21) v5(101.04,87.46) ; v4(96.64,77.62) v5(96.24,77.37) ; v4(97.44,76.02) v5(97.04,75.77) ; v4(104.63,87.21) v5(105.03,87.46) ; v4(108.63,78.42) v5(109.03,78.17) ; v4(103.03,87.21) v5(103.43,87.46)
  L3_SIG1 w0.381: v5(132.72,118.75) 132.72,117.47 136.53,113.66 138.05,113.66 139.07,114.68 147.83,114.68 149.1,113.41 v3(149.61,113.41)
  L7_PWR2 w0.381: v5(98.64,78.17) 98.64,78.17 99.03,78.56 ; 99.8,78.54 99.44,78.18 v5(99.44,78.17)
  L10_SIG4 w0.254: v11(99.04,77.62) v5(98.64,77.37) ; v11(98.65,75.24) 98.65,75.75 v5(98.64,75.77) ; v11(97.15,75.3) 97.04,75.41 v5(97.04,75.77) ; v5(97.84,75.77) 97.85,75.76 v11(97.85,75.25) 97.85,74.89 v11(97.76,74.81) v11(97.76,74.43) ; v11(99.04,78.42) v5(98.64,78.17) ; v11(103.1,76.92) v5(103.43,76.57) ; v11(103.03,76.02) v5(103.43,75.77) v11(103.83,76.02) ; v11(97.42,87.88) v5(97.04,88.26) ; v11(103.08,87.82) v5(103.43,87.46) ; v11(99.84,77.62) v5(99.44,77.37) ; v11(99.84,78.42) v5(99.44,78.17) ; v11(96.62,87.88) v5(96.24,88.26)
  L10_SIG4 w0.381: 104.75,86.95 v5(105.03,86.66)
  BOTTOM w0.381: v11(97.42,87.88) 96.93,88.37 C406.1 96.62,88.31 v11(96.62,87.88) ; v9(57.4,95.97) C190.1 56.53,96.11 U25.3 ; U23.3 42.59,98.85 C169.1 v9(43.31,98.81)
  vias: v5(92.61,97.66) v5(93.62,97.33) v5(136.53,135.72) v5(137.03,136.23) v5(138.05,135.34) v5(138.84,135.13) v5(139.57,135.08) v6(92.84,98.3) v6(93.73,98.3) v6(137.64,136.48) v6(137.64,135.84) v6(138.43,136.48) v6(138.43,135.84) v6(139.07,135.97) v7(92.84,98.3) v7(93.73,98.3) v7(137.64,136.48) v7(137.64,135.84) v7(138.43,136.48) v7(138.43,135.84) v7(139.07,135.97) v9(45.09,97.54) v9(46.35,97.54) v9(47.62,97.54) v9(120.52,127.64) v9(120.52,126.36) v9(120.52,125.09) v10(102.95,88.29) v10(103.76,87.88) v10(103.85,89.03) v11(102.95,88.29) v11(103.76,87.88) v11(103.85,89.03)
V1_8FTDI: length 13.2
  TOP w0.203: U37.64 160.64,86.3 160.2,86.75
  TOP w0.254: 168.14,87.21 U37.49
  TOP w0.305: U37.12 157.66,78.39 157.5,78.23 157.2,78.23 ; 171.85,78.84 171.4,78.39 U37.37
  TOP w0.381: v9(156.13,79.06) C238.1 156.27,78.23 157.2,78.23 ; 171.85,78.84 172.09,79.08 v9(172.72,79.08) ; 160.2,86.75 160.03,86.91 160.03,87.41 160.2,87.57 C235.1 v9(159.28,88.27) ; 168.14,87.21 168.14,88.21 C232.1 168.33,88.4 v9(168.94,88.4)
  vias: v9(158.71,87.85)
V1_8PHY_HDMI: length 3
  TOP w0.254: U1.Y17 v4(97.44,79.22)
  L3_SIG1 w0.254: v4(97.44,79.22) v5(97.04,78.97)
  L10_SIG4 w0.254: v11(96.79,79.37) v5(97.04,78.97)
  BOTTOM w0.381: v11(96.79,79.37) 96.79,78.7 97.41,78.08
  vias: v5(81.15,78.49) v5(81.53,79.38) v6(82.55,79.88) v6(82.55,78.99) v7(82.55,79.88) v7(82.55,78.99)
V1_8PHY_LDO3: length 1.5
  TOP w0.254: U3.K11 143.01,123.17 v8(143.03,123.17)
  BOTTOM w0.381: C392.1 143.26,123.4 v8(143.03,123.17)
  vias: v5(85.09,82.58) v5(85.83,82.57) v5(86.01,84.29) v5(86.45,82.58) v5(86.89,84.23) v10(84.84,85.91) v10(84.84,85.15) v10(85.34,85.91) v10(85.34,85.15) v10(85.85,85.15) v10(86.49,85.15) v11(84.84,85.91) v11(84.84,85.15) v11(85.34,85.91) v11(85.34,85.15) v11(85.85,85.15) v11(86.49,85.15)
V1_8PHY_LDO4:
  vias: v5(78.61,78.61) v5(78.61,77.6) v5(79.38,78.11) v5(87.35,85.78) v5(88.16,85.78) v5(145.03,126.87) v5(145.8,127.38) v6(78.61,74.93) v6(78.61,74.17) v6(79.25,74.93) v6(79.25,74.17) v6(146.56,126.87) v6(147.32,126.87) v7(78.61,74.93) v7(78.61,74.17) v7(79.25,74.93) v7(79.25,74.17) v7(146.56,126.87) v7(147.32,126.87)
V1_8PHY_PCIE: length 6.1
  TOP w0.254: U1.AA16 v4(96.64,80.02) ; U1.AA17 v4(96.64,79.22) ; U1.W14 v4(98.24,82.41)
  L3_SIG1 w0.254: v5(97.84,82.66) v4(98.24,82.41) ; v4(96.64,79.22) v5(96.24,78.97) ; v4(96.64,80.02) v5(96.24,79.77)
  L4_SIG2 w0.381: v5(96.24,79.77) v5(96.24,78.97)
  L10_SIG4 w0.254: v11(98.24,82.42) v5(97.84,82.66) ; v11(95.99,80.17) v5(96.24,79.77)
  BOTTOM w0.381: v11(98.24,82.42) 97.96,82.42 97.26,81.72
V1_8PHY_SATA: length 14.8
  TOP w0.254: U1.V13 v4(99.04,83.21)
  L3_SIG1 w0.254: v5(98.64,83.46) v4(99.04,83.21)
  L10_SIG4 w0.254: v11(98.96,83.01) v5(98.64,83.46)
  L10_SIG4 w0.381: v7(83.19,81.28) v7(83.82,81.28) 84.07,81.28 84.84,80.52
  L10_SIG4 w0.508: 92.4,80.42 v5(94.82,80.42)
  L10_SIG4 w0.635: 84.84,80.52 85.75,79.6 91.59,79.6 92.4,80.42
  BOTTOM w0.381: v11(98.96,83.01) 99.31,83.36 C564.1
V1_8PHY_USB: length 8
  TOP w0.254: U1.W12 v4(98.24,84.01) ; U1.AB12 v4(95.84,84.01) ; U1.AA13 v4(96.64,83.21)
  L3_SIG1 w0.254: v4(96.64,83.21) 96.24,83.46 v5(96.24,83.46) ; v5(95.44,84.26) v4(95.84,84.01) ; v5(97.84,84.26) v4(98.24,84.01)
  L10_SIG4 w0.254: v11(96.64,83.22) v5(96.24,83.46) ; v11(95.84,84.02) v5(95.44,84.26)
  BOTTOM w0.381: C391.1 C390.1 94.92,84.54 95.17,84.28 95.57,84.28 v11(95.84,84.02) v11(96.64,83.22)
  vias: v6(89.18,85.19) v6(89.81,85.04) v7(89.18,85.19) v7(89.81,85.04)
V1_8PLL: length 7.8
  TOP w0.152: v3(137.45,130.34) v9(137.45,131.39)
  TOP w0.254: U1.AD16 v4(94.24,80.02) ; U1.AE16 v4(93.44,80.02)
  TOP w0.381: v9(137.45,132.15) v9(137.45,131.39) ; U3.B5 v3(137.45,130.34)
  L3_SIG1 w0.254: v4(93.44,80.02) v5(93.04,79.77) ; v4(94.24,80.02) v5(93.84,79.77)
  L3_SIG1 w0.381: v3(137.45,130.34) v9(137.45,131.39) v9(137.45,132.15)
  BOTTOM w0.381: v9(137.45,132.15) v9(137.45,131.39) 137.45,130.67 C382.1
  vias: v5(93.84,78.17) v5(112.73,81.79) v5(113.61,81.79) v5(114.5,81.79) v5(115.39,81.79) v6(113.64,81.16) v6(114.43,81.13) v6(115.16,81.11) v6(115.82,81.11) v7(113.64,81.16) v7(114.43,81.13) v7(115.16,81.11) v7(115.82,81.11) v9(123.95,106.63) v9(124.59,106.25)
V1_8PLLA: length 7.8
  TOP w0.254: U1.R17 v4(101.44,79.22) ; U1.M14 v4(104.63,82.41) ; U1.N16 v11(103.83,80.02) ; U1.R14 v4(101.44,82.41)
  L3_SIG1 w0.254: v4(101.44,79.22) v5(101.04,78.97) ; v11(103.83,80.02) v5(104.23,79.77) ; v4(101.44,82.41) v5(101.04,82.66)
  L10_SIG4 w0.254: v11(100.13,78.87) 100.22,78.97 v5(101.04,78.97) ; v11(101.44,82.42) v5(101.04,82.66) ; v11(103.83,80.02) v5(104.23,79.77)
  BOTTOM w0.254: C381.1 100.51,79.33 100.13,78.95 v11(100.13,78.87) ; v11(103.83,80.02) 103.63,79.81 C442.1 ; C380.1 101.37,82.48 v11(101.44,82.42)
  vias: v5(106.43,81.49) v5(107.31,81.49) v5(108.2,81.49) v5(109.09,81.49) v10(112.01,83.82) v10(113.41,83.82) v10(113.41,83.44) v11(112.01,83.82) v11(113.41,83.82) v11(113.41,83.44)
V1_8PLLB: length 7.5
  TOP w0.254: U1.N11 v4(103.83,84.81) ; U1.N12 v4(103.83,84.01) ; U1.P16 v11(103.03,80.02) ; U1.P14 v4(103.03,82.41) ; U1.P15 v11(103.03,80.82)
  L3_SIG1 w0.254: v5(104.23,84.26) 104.23,84.26 v4(103.83,84.01) ; v5(104.23,85.06) 104.23,85.06 v4(103.83,84.81) ; v11(103.03,80.82) v5(103.43,80.57) ; v5(103.43,82.66) v4(103.03,82.41) ; v11(103.03,80.02) v5(103.43,79.77)
  L10_SIG4 w0.254: v11(103.83,84.02) v5(104.23,84.26) ; v11(103.03,80.82) v5(103.43,80.57) ; v11(103.83,84.82) v5(104.23,85.06) ; v11(103.03,82.42) v5(103.43,82.66) ; v11(103.03,80.02) v5(103.43,79.77)
V3_3ACDCM: length 3.7
  TOP w0.381: C321.1 56.85,53.47 56.95,53.57 57,53.57 v9(57.02,53.59)
  BOTTOM w0.254: v9(57.02,53.59) 57,53.57 56.95,53.57 56.93,53.54 U45.4 ; U45.1 56.49,55.04
  BOTTOM w0.381: C322.1 57.15,55.71 56.49,55.04
  vias: v9(54.36,57.1) v9(56.9,57.36) v9(57.91,57.61)
V3_3APCIE: length 13.6
  TOP w0.381: C308.1 49.14,52.41 v9(49.78,53.04)
  BOTTOM w0.254: v9(50.04,51.77) 50.31,52.04 U45.18 ; U45.9 55.47,50.53 55.63,50.37 C310.1 ; U45.20 v9(49.78,53.04)
  BOTTOM w0.381: C309.1 51.56,50.47 51.91,50.82 U45.16
  BOTTOM w0.508: R546.2 v9(59.44,51.52) ; Y7.4 42.71,56 C326.1 v9(41.91,55.96) ; R548.2 v9(53.59,47.2) ; R549.2 v9(54.61,47.2) ; C310.1 v9(56.39,48.98)
  vias: v9(46.99,49.78) v9(48.26,49.78) v9(49.53,49.78) v9(50.8,49.78)
V3_3AUX_PCIE: length 4.6
  TOP w0.508: J49.2 41.06,19.39 ; J49.2 39.45,21 ; J49.2 39.45,19.39 ; J49.2 41.06,21
V3_3D: length 316.7
  TOP w0.203: U100.1 149.15,69.52 v9(148.84,69.22) ; U100.7 149.15,71.83 148.91,72.07 ; U65.8 173.39,74.72 C420.1
  TOP w0.254: U1.H10 v4(107.83,85.61) ; v4(92.95,87.8) 92.96,87.8 93.18,87.58 93.8,87.58 U1.AE7 ; U1.H9 v4(107.83,86.41) ; C120.1 31.75,95.84 U13.21 ; U1.C24 v4(111.83,73.62) ; U1.H15 v4(107.83,80.82) ; U1.H8 v4(107.83,87.21) ; U1.G4 v4(108.63,90.41) ; U1.AB7 v4(95.84,88.01) ; U1.AB6 v4(95.84,88.81) ; U1.H19 v4(107.83,77.62) ; U1.T5 v4(100.64,89.61) ; U1.J8 v4(107.03,87.21) ; U1.R7 v4(101.44,88.01) ; U1.E3 v4(110.23,91.21) ; U1.T4 v4(100.64,90.41) ; U1.D10 v4(111.03,85.61) ; U1.K8 v4(106.23,87.21) ; U1.P10 v4(103.03,85.61) ; U1.R10 v4(101.44,85.61) ; U1.N5 v4(103.83,89.61) ; U1.D16 v4(111.03,80.02) ; U102.17 135.11,85.11 v9(135.13,85.09) ; U1.B23 v4(112.63,74.42) ; U1.AD7 v4(94.24,88.01) ; U1.H18 v4(107.83,78.42) ; U1.E22 v4(110.23,75.22) ; U1.W5 v4(98.24,89.61) ; U1.E10 v4(110.23,85.61) ; U1.G5 v4(108.63,89.61) ; U1.W4 v4(98.24,90.41) ; U1.H11 v4(107.83,84.81) ; U1.V12 v4(99.04,84.01) ; C130.1 31.75,78.06 U15.21 ; U1.E5 v4(110.23,89.61) ; v8(141.44,128.73) U3.D9 v8(140.65,127.94) ; U1.AF5 v4(92.64,89.61) ; U1.N4 v4(103.83,90.41) ; U1.AD5 v4(94.24,89.61) ; U1.E16 v4(110.23,80.02) ; U1.U10 v4(99.84,85.61) ; U1.G15 v4(108.63,80.82) ; U1.H16 v4(107.83,80.02) ; U1.B6 v4(112.63,88.81) ; U103.17 v9(135.13,100.6) ; U1.D22 v11(111.03,75.22)
  TOP w0.279: U46.24 68.22,13.23 C428.1
  TOP w0.305: U8.10 108.82,12.64 109.09,12.37 ; C144.1 31.75,53.3 U17.21
  TOP w0.381: v9(100.23,125.43) 100.23,124.77 R799.2 ; v9(99.16,149.61) 99.03,149.73 98.55,149.73 98.55,149.74 J15.4 ; v9(20.98,4.83) 20.64,5.17 D18.1 ; v8(140.64,123.96) 140.26,124.34 U3.J8 v8(139.85,123.94) ; C257.1 94.88,129.23 v8(94.88,128.44) ; v9(96.92,132.92) C479.1 v9(95.76,131.78) ; 148.91,72.07 148.72,72.26 148.72,73.02 v9(147.96,73.02) ; v9(112.39,110.19) R446.2 R445.2 ; R507.2 v9(86.36,124.54) ; R545.2 v9(40,40.39) ; R97.1 24.25,124.68 v9(24.51,124.41) v9(25.15,124.41) ; R544.1 v9(37.46,40.39) ; R22.2 v9(88.9,108.29) ; R383.2 129.03,69.3 v3(129.16,69.42) ; R506.2 v9(85.6,126.45) ; U47.5 128.13,46.88 C575.1 v9(128.14,47.66) ; R366.2 176.78,54.44 v9(176.4,54.06) ; v9(129.1,66.88) 128.44,66.88 R563.2 ; U85.5 42.66,44.57 C470.1 v9(43.48,44.55) ; R423.2 v9(175.77,90.55) ; v5(128.4,72.47) v3(129.07,72.47) ; v8(150.92,95.64) 150.88,95.69 C408.1 ; R412.2 v9(78.49,147.66) ; v9(106.68,110.19) R449.2 R447.2 ; R435.2 R442.2 v9(109.86,114.64) ; R439.2 R436.2 104.34,109.5 v9(104.34,110.16) ; R834.1 v9(154.69,140.08) ; R437.2 R438.2 v9(107.82,114.64) ; R924.2 v9(139.95,69.22) ; R511.2 v9(85.6,123.65) ; R790.2 v9(16.89,44.15) ; U4.2 C28.1 v9(99.44,123.65) ; C105.1 24.05,118.01 v9(24.71,118.01) ; C144.1 v9(32.46,53.29) ; v9(43.56,39.12) C469.1 42.69,39.13 U44.5 ; C130.1 v9(32.5,78.06) ; C409.1 150.88,98.2 v8(150.92,98.24) ; R510.2 v9(86.36,127.34) ; C256.1 96.39,124.95 v8(96.38,124.96) ; R434.2 R440.2 102.23,109.81 v9(102.62,110.19) ; D19.1 v3(24.58,4.95) ; v5(84.96,91.9) v3(84.2,91.9) ; R509.2 v9(88.39,133.18) ; R508.2 v9(90.3,132.42) ; 124.59,64.39 124.67,64.47 v3(125.35,64.47) ; v9(86.49,121.75) 86.36,121.87 R512.2 ; J52.B8 v9(37.39,26.92) ; R120.2 v9(29.59,91.9) ; C120.1 v9(32.5,95.84) ; R649.2 v9(29.34,40.39) ; 97.41,111.71 97.41,112.85 97.09,113.17 v9(97.02,113.17) ; R559.2 v9(66.42,23.88) ; v8(93.88,126.19) 93.85,126.17 93.85,125.43 ; v8(152.35,92.72) 152.41,92.66 C410.1 ; R441.2 v9(111.73,113.87) ; v9(110.36,110.19) R444.2 R443.2 ; v8(96.39,125.95) 96.4,125.94 C258.1 ; D16.1 v3(12.64,4.91) ; R505.2 v9(85.6,129.24) ; D22.1 v9(73.6,103.14) ; C350.1 97.41,128.47 v8(97.39,128.45) ; R679.2 159.47,117.39 v9(159.51,117.43) ; R152.2 37.85,99.45 v9(37.9,99.4) ; J52.A9 v9(38.39,36.96) ; R201.2 v9(29.59,49.15) ; 131.19,68.71 v3(131.19,69.55) 131.19,70.36 ; R448.2 v9(114.17,109.43) ; D17.1 v3(16.83,4.91) ; v5(128.4,64.85) v3(129.16,64.85) ; C428.1 v9(68.2,12.4) ; v9(70.36,103.21) 70.17,103.02 D23.1 ; v5(124.59,69.3) v3(125.35,69.3) ; R543.1 v9(35.43,40.39) ; J52.A10 v9(39.39,36.96)
  TOP w0.508: C432.1 131.19,7.62 131.44,7.87 ; v9(24.38,99.4) 24.38,99.41 R146.1 ; R200.2 27.69,52.28 v9(27.3,51.9) ; R144.1 v9(23.62,104.35) ; v9(23.49,107.4) R143.1 ; R184.1 v9(23.62,85.55) ; R131.2 v9(27.69,94.06) ; R185.1 v9(23.62,82.38) ; v9(23.24,89.62) R182.1 ; R226.1 v9(23.62,60.79) ; R145.1 v9(23.62,103.33) ; R159.2 27.7,77.04 27.49,77.26 v9(27.45,77.26) ; R183.1 v9(23.62,86.57) ; R225.1 v9(23.62,61.8) ; R227.1 v9(23.62,57.61) ; v9(23.49,64.85) R224.1
  TOP w0.635: U74.4 C432.1
  L3_SIG1 w0.254: v5(95.44,88.26) v4(95.84,88.01) ; v5(110.64,74.91) 110.63,74.97 v4(110.23,75.22) ; v5(108.23,85.06) 108.23,85.06 v4(107.83,84.81) ; v5(107.43,87.46) v4(107.03,87.21) ; v4(111.83,73.62) v5(112.23,73.37) ; v4(107.83,77.62) v5(108.23,77.37) ; v5(95.44,89.06) v4(95.84,88.81) ; v4(92.95,87.8) 92.96,87.81 92.96,87.82 92.96,87.82 92.96,87.84 93.04,87.95 v5(93.04,88.26) ; v5(92.24,89.86) 92.24,89.86 v4(92.64,89.61) ; v5(110.63,89.86) v4(110.23,89.61) ; v5(98.64,84.26) v4(99.04,84.01) ; v5(106.63,87.46) v4(106.23,87.21) ; v5(109.03,90.66) v4(108.63,90.41) ; v5(99.44,85.86) v4(99.84,85.61) ; v4(103.83,90.41) 104.23,90.66 v5(104.23,90.66) ; v4(107.83,85.61) 108.23,85.86 v5(108.23,85.86) ; v5(93.84,88.26) v4(94.24,88.01) ; v4(107.83,80.82) v5(108.23,80.57) ; v4(110.23,80.02) v5(110.63,79.77) ; v4(111.03,80.02) v5(111.43,79.77) ; v4(107.83,86.41) 108.23,86.66 v5(108.23,86.66) ; v11(111.03,75.22) v5(111.43,74.97) ; v5(110.63,85.86) v4(110.23,85.61) ; v4(103.83,89.61) 104.23,89.86 v5(104.23,89.86) ; v4(107.83,80.02) v5(108.23,79.77) ; v5(93.84,89.86) v4(94.24,89.61) ; v4(107.83,78.42) v5(108.23,78.17) ; v5(111.43,85.86) v4(111.03,85.61) ; v5(103.43,85.86) v4(103.03,85.61) ; v4(100.64,89.61) 100.24,89.86 v5(100.24,89.86) ; v4(108.63,80.82) v5(109.03,80.57) ; v4(107.83,87.21) 108.23,87.46 v5(108.23,87.46) ; v5(101.04,88.26) v4(101.44,88.01) ; v5(100.24,90.66) 100.24,90.66 v4(100.64,90.41) ; v5(97.84,90.66) v4(98.24,90.41) ; v5(113.03,89.06) v4(112.63,88.81) ; v5(101.04,85.86) v4(101.44,85.61) ; v4(112.63,74.42) v5(113.03,74.17) ; v5(110.63,91.46) v4(110.23,91.21) ; v5(97.84,89.86) v4(98.24,89.61) ; v5(109.03,89.86) v4(108.63,89.61)
  L3_SIG1 w0.381: v3(84.2,91.9) v5(84.96,91.9) ; v5(16.83,4.19) v3(16.83,4.91) ; v3(131.19,69.55) 131.41,69.77 v5(131.95,69.77) ; v3(129.16,69.42) v5(128.4,69.42) ; v3(129.16,64.85) v5(128.4,64.85) ; v3(129.07,72.47) v5(128.4,72.47) ; v3(125.35,64.47) v5(124.59,64.47) ; v3(24.58,4.95) v5(23.9,4.95) ; v5(12.64,4.27) v3(12.64,4.91) ; v3(125.35,69.3) v5(124.59,69.3)
  L7_PWR2 w0.381: v5(108.23,79.77) v5(108.23,80.57)
  L7_PWR2 w0.508: 36.91,21 J49.1 ; J49.1 36.91,19.39 ; J49.1 38.52,21 ; J49.1 38.52,19.39 ; 100.65,146.32 J21.1 ; J21.1 100.65,147.72 ; J21.1 102.04,147.72 ; J21.1 102.04,146.32
  L10_SIG4 w0.254: v11(111.83,73.12) v5(112.23,73.37) ; v11(109.47,90.42) 109.4,90.09 v5(109.03,89.86) ; v11(101.44,85.62) v5(101.04,85.86) ; v11(110.38,79.37) v5(110.63,79.77) ; v11(109.47,91.06) 109.07,90.8 v5(109.03,90.66) ; v5(110.64,74.91) 110.64,74.96 110.31,75.23 v11(110.31,75.26) ; v5(111.43,74.97) 111.27,75.07 111.11,75.17 v11(111.03,75.22) ; v11(103.89,90.34) 103.91,90.34 103.98,90.27 v5(104.23,89.86) ; v11(113.28,73.77) v5(113.03,74.17) ; v11(109.98,90.68) 109.98,90.52 v5(110.63,89.86) ; v5(104.23,90.66) 104.14,90.81 v11(103.63,90.93) ; v5(110.63,91.46) 110.63,91.19 110.38,90.93 v11(110.36,90.93) ; v11(111.18,79.37) v5(111.43,79.77) ; v11(99.84,85.62) v5(99.44,85.86)
  L10_SIG4 w0.381: v7(27.11,121.11) v5(26.42,121.11) ; v7(137.62,112.52) v5(138.3,112.52)
  BOTTOM w0.203: 167.8,59.83 U75.3
  BOTTOM w0.254: v8(157.23,99.52) 157.21,99.52 U89.B10 ; U89.K5 v8(150.92,95.64) ; v8(99.42,130.26) v8(99.42,129.49) U43.P3 U43.N4 U43.M4 v8(97.39,128.45) ; U43.K9 v8(96.39,125.95) ; U89.H1 v8(152.35,92.72) ; U43.E6 94.24,127.3 94.23,127.3 v8(93.88,126.95) v8(93.88,126.19) ; C386.1 103.25,91.31 v11(103.63,90.93) 103.98,90.58 103.98,90.43 v11(103.89,90.34) ; J17.5 54.74,89.01 55.04,89.31 C219.1 ; U43.J10 v8(96.38,124.96) ; U43.P5 99.26,127.95 v8(99.44,127.77) ; U89.K9 v8(150.92,98.24) ; U43.F5 v8(94.88,128.44)
  BOTTOM w0.305: U9.21 24.46,118.45 24.71,118.19 v9(24.71,118.01) ; v9(90.81,146.2) 90.8,146.2 U30.10
  BOTTOM w0.33: v9(137.92,88.9) 138.05,88.9 138.06,88.91 U104.16
  BOTTOM w0.381: R422.2 v9(182.88,92.46) ; v9(135.13,100.6) 135.11,100.58 C580.1 ; 6.73,46.69 v9(6.73,47.58) ; v9(28.32,60.28) 28.69,59.91 R222.1 29.34,60.91 v9(28.96,61.3) ; v9(23.37,131.15) C107.1 R102.1 ; R513.2 94.41,104.52 v9(94.36,104.48) ; C3.1 167.51,45.17 v9(167.26,44.91) ; v9(97.28,146.94) C212.1 v9(96.27,145.96) ; v9(43.05,92.66) 43.05,90.58 U68.5 ; v9(61.21,62.82) R498.2 ; v9(166.24,47.45) R912.2 ; v5(26.42,121.11) v7(27.11,121.11) ; R911.2 v9(164.72,52.45) ; R134.2 v9(6.69,96.35) ; v9(168.78,45.17) 169.37,45.76 R10.2 ; C127.1 31.75,92.5 31.76,92.49 U69.5 ; R789.2 v9(10.03,43.31) ; v11(99.84,85.62) 100.53,86.31 C363.1 101.24,85.81 v11(101.44,85.62) ; R160.2 v9(23.37,73.92) ; U71.5 26.81,49.26 26.8,49.28 C151.1 ; v9(22.23,98.76) R121.2 ; R450.2 v9(188.21,89.41) ; R730.2 v9(182.88,87.38) 182.63,87.63 C221.1 ; U70.5 26.81,74.11 26.8,74.12 v9(26.8,74.88) ; v9(59.05,64.6) C248.1 59.93,64.61 U39.5 ; C219.1 v9(55.72,90.05) ; v9(99.16,149.61) 99.02,149.47 C211.1 ; R18.2 144.7,127.64 147.37,127.64 v9(147.45,127.72) ; R161.2 v9(7.24,92.54) ; R101.1 v9(21.79,126.7) ; U98.5 162.93,42.02 v9(162.18,41.27) ; R203.2 v9(7.24,67.77) ; U97.5 161.81,50.69 C214.1 v9(161.04,50.67) ; 167.8,59.83 167.8,59.06 v9(167.61,58.88) ; v9(12.8,31.52) 12.78,31.5 C220.1 U33.8 ; R259.2 v9(177.95,132.16) ; R122.2 v9(7.19,116.49) ; R741.2 v9(95.76,136.35) ; U19.5 187.87,87.8 v9(188.34,88.27) ; R420.1 56.78,87.28 v9(57.52,87.28) ; v9(171.2,23.07) C251.1 U41.1 ; R100.1 v9(20.38,124.34) ; C191.1 53.47,95.97 v9(53.29,96.14) ; U77.8 C449.1 ; R902.2 v9(164.85,147.83) ; R77.2 v9(21.67,136.99) ; v9(174.88,88.77) C426.1 174.12,87.88 174.64,87.37 U63.1 ; R421.2 v9(10.67,33.3) ; v9(39.34,100.06) 39.34,100.11 39.01,100.44 C170.1 38.63,99.73 v9(38.81,99.55) ; v9(28.96,103.71) 28.96,103.59 29.34,103.21 R141.1 28.31,102.45 v9(27.94,102.82) ; v5(138.3,112.52) v7(137.62,112.52) ; v9(16.64,122.38) C104.1 17.33,122.45 R99.1 v9(16.52,123.53) ; R551.2 v9(23.37,13.34) ; R637.1 161.54,99.27 v9(161.42,99.4) ; R190.2 v9(28.96,71.71) ; R410.2 R417.2 ; U39.2 v9(60.58,69.3) ; U78.5 187.75,96.71 C319.1 v9(187.73,97.54) ; v9(29.05,86.04) 29.34,85.75 R180.1 28.69,84.67 v9(28.32,85.04) ; R107.2 v9(42.29,86.31) ; R149.2 185.9,82.83 v9(184.79,82.83) ; 6.73,119.72 v9(6.73,120.48) ; 6.73,71.46 v9(6.73,72.19) ; C579.1 v9(135.13,85.09) ; R232.2 v9(38.73,57.74) ; R78.2 v9(7.24,140.8) ; X1.4 v9(165.99,145.57)
  BOTTOM w0.508: R226.1 v9(23.62,60.79) ; R121.2 v9(23.37,97.74) ; v9(23.62,86.57) 23.62,86.82 C133.1 ; R145.1 v9(23.62,103.33) ; 167.72,7.24 J46.3 ; J46.3 169.33,7.24 ; J46.3 169.33,5.63 ; J46.3 167.72,5.63 ; R419.2 v9(154.88,102.44) ; C127.1 v9(32.5,92.66) ; R233.2 v9(28.19,47.69) ; v9(23.62,104.35) 23.62,104.6 C119.1 ; v9(27.69,49.1) 27.56,49.23 27.32,49.23 27.19,49.36 C151.1 ; R417.2 v9(76.83,140.03) ; R202.2 v9(23.37,48.85) ; R184.1 v9(23.62,85.55) ; v9(23.62,61.8) 23.62,62.06 C145.1 ; R678.2 v9(69.72,117.18) ; R153.2 v9(33.15,91)
  vias: v5(34.04,97.28) v5(35.18,97.28) v5(37.08,97.28) v5(85.34,94.87) v5(85.34,93.86) v5(85.78,92.74) v5(118.87,86.06) v5(119.63,86.06) v5(120.4,86.06) v6(34.16,97.92) v6(35.43,97.92) v6(36.7,97.92) v7(34.16,97.92) v7(35.43,97.92) v7(36.7,97.92) v9(28.78,113.34) v9(28.78,112.58) v9(29.54,113.34) v9(29.54,112.58) v9(32.51,77.42) v9(33.1,53.27) v9(33.27,95.84) v9(47.24,45.42) v9(47.24,44.79) v9(48.13,45.42) v9(48.13,44.79) v9(48.77,122.64) v9(49.28,123.14) v9(50.04,123.14) v9(50.29,110.06) v9(50.29,109.3) v9(51.05,110.06) v9(51.05,109.3) v9(52.45,60.66) v9(52.45,60.03) v9(53.21,60.66) v9(53.21,60.03) v9(53.24,97.64) v9(53.26,96.88) v9(75.06,111.33) v9(75.95,111.33) v9(114.3,15.07) v9(114.3,14.18) v9(115.44,15.07) v9(115.44,14.18) v9(132.72,14.1) v9(133.99,14.1) v9(135.26,14.1) v9(135.26,13.04) v9(161.16,36.53) v9(161.93,36.53) v9(162.69,36.53) v9(163.2,16.34) v9(163.2,15.32) v9(163.2,14.31) v9(164.21,16.34) v9(164.21,15.32) v9(164.21,14.31) v9(168.22,43.84) v9(170.41,60.79) v9(171.96,4.57) v9(172.21,75.14) v9(173.23,4.57) v9(174.5,4.57) v9(176.15,99.65) v9(176.15,98.38) v9(176.15,97.11) v9(176.15,95.84) v9(176.15,94.57) v10(86.11,94.68) v10(86.27,93.55) v10(86.27,93.05) v10(91.97,91.85) v10(91.97,91.47) v10(91.97,91.03) v10(91.97,90.6) v10(107.03,87.72) v10(107.24,88.06) v10(107.34,88.44) v10(107.62,88.06) v10(107.7,88.44) v10(107.82,87.76) v10(118.75,86.7) v10(119.25,85.04) v10(120.52,85.04) v11(86.11,94.68) v11(86.27,93.55) v11(86.27,93.05) v11(91.97,91.85) v11(91.97,91.47) v11(91.97,91.03) v11(91.97,90.6) v11(107.03,87.72) v11(107.24,88.06) v11(107.34,88.44) v11(107.62,88.06) v11(107.7,88.44) v11(107.82,87.76) v11(118.75,86.7) v11(119.25,85.04) v11(120.52,85.04)
V3_3D_PROFIA: length 3.6
  TOP w0.508: U74.1 v9(128.87,3.81) v9(129.67,3.81) v9(130.56,3.81)
V3_3D_PROFIB: length 3.6
  TOP w0.508: U74.2 v9(128.87,5.08) v9(129.67,5.08) v9(130.56,5.08)
V3_3D_PRU1ETH0JCK: length 4.1
  BOTTOM w0.508: 17.87,133.43 J3.3 17.87,132 ; 18.97,132.16 19.69,131.44 20.41,132.16
V3_3D_PRU1ETH1JCK: length 8.1
  BOTTOM w0.508: J5.4 20.41,108.03 ; J5.4 18.97,108.03 ; J5.4 20.41,106.6 ; J5.4 18.97,106.6 ; 16.43,107.87 J5.3 ; J5.3 17.87,109.3 ; J5.3 16.43,109.3 ; J5.3 17.87,107.87
V3_3D_PRU2ETH0JCK: length 8.1
  BOTTOM w0.508: J6.4 20.41,83.9 ; J6.4 18.97,82.47 ; J6.4 20.41,82.47 ; J6.4 18.97,83.9 ; 16.43,85.17 J6.3 ; J6.3 16.43,83.74 ; J6.3 17.87,85.17 ; J6.3 17.87,83.74
V3_3D_PRU2ETH1JCK: length 8.1
  BOTTOM w0.508: 18.97,59.14 J8.4 ; J8.4 18.97,57.71 ; J8.4 20.41,57.71 ; J8.4 20.41,59.14 ; 16.43,60.41 J8.3 ; J8.3 16.43,58.98 ; J8.3 17.87,58.98 ; J8.3 17.87,60.41
V3_3FTDI: length 42
  TOP w0.203: U100.6 149.55,71.83 149.8,72.07
  TOP w0.254: U37.20 162.14,72.87 v9(162.23,72.78) ; v9(167.81,72.7) 167.64,72.87 U37.31 ; U37.42 171.58,80.89 171.7,80.77 C233.1
  TOP w0.305: U37.50 167.64,86.74 v9(167.39,87) ; 164.64,86.91 U37.56
  TOP w0.381: 164.64,86.91 165.02,87.3 v9(165.45,87.3) ; R485.2 v9(154.23,77.35) ; C233.1 172.47,81.01 172.69,81.24 v9(172.69,82.09) ; 149.8,72.07 150.11,72.39 150.11,73.02 v9(150.88,73.02)
  L10_SIG4 w0.381: v9(156.97,74.5) 155.49,73.02 v9(150.88,73.02)
  BOTTOM w0.203: U75.8 168.6,63.27 C448.1
  BOTTOM w0.381: R496.2 163.07,86.74 v9(163.83,87.5) ; v9(162.23,72.78) 162.43,72.98 C239.1 ; C229.1 167.64,72.87 v9(167.81,72.7) ; 163.75,77.98 163.75,77.6 v9(163.25,77.09) ; 163.75,77.98 164.45,77.28 v9(164.45,77.09) ; 163.75,77.98 FB11.2 ; C236.1 165.45,86.96 v9(165.45,87.3) ; v9(156.97,74.5) C230.2 157.03,75.33 U99.5 ; v9(165.61,78.69) 165.79,78.87 C228.2 165.77,79.52 U34.5 ; C245.1 v9(174.2,91.52) ; U63.16 170.8,87.37 171.32,87.88 C443.1 v9(170.56,88.77) ; v9(164.78,84.59) 164.12,84.59 FB10.2 163.75,84.21 164.26,83.7 v9(164.97,83.7)
  vias: v9(169.42,63.2) v9(172.21,71.07) v9(173.44,91.52) v9(181.74,9.4) v9(181.74,8.13) v9(181.74,6.86)
V3_3USB: length 7.3
  TOP w0.254: v8(141.44,130.33) U3.B9 v8(141.44,129.54) ; U1.Y12 v4(97.44,84.01) ; U1.AA12 v4(96.64,84.01)
  L3_SIG1 w0.254: v5(97.04,84.26) v4(97.44,84.01) ; v5(96.24,84.26) 96.24,84.26 v4(96.64,84.01)
  L10_SIG4 w0.254: v11(96.64,84.02) v5(96.24,84.26) ; v11(97.44,84.02) v5(97.04,84.26)
  BOTTOM w0.381: C399.1 141.73,130.62 v8(141.44,130.33) v8(141.44,129.54) ; C401.1 97.21,83.79 v11(97.44,84.02) ; C400.1 96.72,84.1 v11(96.64,84.02)
  vias: v5(82.32,91.26) v5(82.73,92.05) v5(82.83,93.57) v5(83.51,93.55) v5(83.59,91.71)
V5_0D: length 26.1
  TOP w0.279: 61.72,22.86 U46.11
  TOP w0.381: R560.2 v9(58.8,13.68) ; C427.1 61.72,22.86 ; v9(175.67,29.59) 175.64,29.57 R391.1 ; R389.1 175.64,33.88 v9(175.67,33.91) ; R386.1 175.64,38.2 v9(175.67,38.23) ; v9(175.67,21.59) 175.64,21.62 R396.1 ; R390.1 175.64,31.72 v9(175.67,31.75) ; R388.1 v9(174.88,35.31) ; R562.2 v9(57.66,13.68) ; R392.1 175.64,25.55 v9(175.67,25.53) 175.64,25.5 R395.1
  TOP w0.508: C427.1 v9(61.72,23.62)
  L6_PWR1 w0.508: 184.18,26.8 J37.27 ; J37.27 184.18,25.27 ; J37.27 185.7,25.27 ; J37.27 185.7,26.8 ; 186.72,26.8 J37.28 ; J37.28 188.24,25.27 ; J37.28 188.24,26.8 ; J37.28 186.72,25.27
  L9_SIG3 w0.508: J21.2 102.04,148.32 ; J21.2 100.65,149.72 ; J21.2 100.65,148.32
  BOTTOM w0.254: 156.69,106.74 U62.E1 U62.E2
  BOTTOM w0.381: v9(179.22,21.08) 178.21,22.1 C208.1 178.12,22.11 v9(177.17,21.16)
  vias: v9(20.19,45.93) v9(21.46,45.93) v9(25.78,4.95) v9(26.92,4.95) v9(160.02,105.75) v9(160.02,104.48) v9(161.29,105.75) v9(161.29,104.48) v9(170.69,99.27) v9(170.69,98) v9(171.96,99.27) v9(171.96,98) v9(174.88,148.54) v9(174.88,147.27) v9(174.88,146) v9(174.88,144.61) v9(175.01,143.21) v9(176.4,148.54) v9(176.4,147.27) v9(176.4,146) v9(176.4,144.61) v9(176.53,143.21) v9(178.18,148.54) v9(178.18,147.27) v9(178.18,146) v9(178.18,144.61) v9(178.31,143.21)
V5_0D_EN: length 1.6
  BOTTOM w0.173: U62.A4 154.36,105.32 R419.1
V5_0DFB: length 2.7
  BOTTOM w0.254: U62.E3 156.51,105.94 156.7,105.76 156.91,105.76
  BOTTOM w0.381: 156.91,105.76 R424.1
  BOTTOM w0.635: R424.1 R427.2
V5_0HDMICONN: length 2.4
  TOP w0.279: v9(58.29,10.03) 58.65,9.68 J24.18
  TOP w0.381: C429.1 v9(59.77,14.75)
V5_0VOP: length 20
  TOP w0.381: U28.5 179.59,55.47 C195.1 180.72,55.45 182.75,57.49 182.75,60.45 186.94,64.64 186.94,69.09 v9(186.18,69.85)
  vias: v9(186.18,71.88) v9(187.2,71.88)
V12_0D: length 39.4
  TOP w0.381: v9(188.58,76.6) R379.2 v9(187.58,75.69)
  L7_PWR2 w0.508: 186.72,45.59 J37.12 ; J37.12 188.24,47.12 ; J37.12 186.72,47.12 ; J37.12 188.24,45.59 ; 186.72,52.2 J37.8 ; J37.8 186.72,50.67 ; J37.8 188.24,50.67 ; J37.8 188.24,52.2 ; J37.14 188.24,43.05 ; J37.14 188.24,44.58 ; J37.14 186.72,43.05 ; J37.14 186.72,44.58 ; J37.2 188.24,59.82 ; J37.2 186.72,59.82 ; J37.2 186.72,58.29 ; J37.2 188.24,58.29 ; J37.10 188.24,49.66 ; J37.10 186.72,48.13 ; J37.10 188.24,48.13 ; J37.10 186.72,49.66 ; J37.16 188.24,42.04 ; J37.16 188.24,40.51 ; J37.16 186.72,40.51 ; J37.16 186.72,42.04 ; J37.6 188.24,54.74 ; J37.6 186.72,53.21 ; J37.6 186.72,54.74 ; J37.6 188.24,53.21 ; J37.4 188.24,55.75 ; J37.4 188.24,57.28 ; J37.4 186.72,55.75 ; J37.4 186.72,57.28
  BOTTOM w0.381: C196.1 187.45,59.08 J37.2
  vias: v9(31.12,24.77) v9(31.12,23.49) v9(32.26,38.61) v9(32.38,24.77) v9(32.38,23.49) v9(33.53,38.61) v9(162.81,122.89) v9(164.21,124.41) v9(164.21,123.27) v9(164.21,122.13) v9(164.21,120.86) v9(188.21,129.24) v9(188.21,127.97) v9(188.21,126.7) v9(188.21,125.43) v9(188.21,124.16)
VDD_CORE: length 51.7
  TOP w0.254: U1.P12 v4(103.03,84.01) ; U1.L7 v4(105.43,88.01) ; U1.U13 v4(99.84,83.21) ; U1.U8 v4(99.84,87.21) ; U1.U16 v11(99.84,80.02) ; U1.R16 v4(101.44,80.02) ; U1.L8 v4(105.43,87.21) ; U1.N13 v4(103.83,83.21) ; U1.J18 v4(107.03,78.42) ; U1.P11 v4(103.03,84.81) ; U1.V8 v4(99.04,87.21) ; U1.T19 v11(100.64,77.62) ; U1.N10 v4(103.83,85.61) ; U1.J17 v4(107.03,79.22) ; U1.H13 v4(107.83,83.21) ; U1.R19 v11(101.44,77.62) ; U1.T13 v4(100.64,83.21) ; U1.U9 v4(99.84,86.41) ; U1.H14 v4(107.83,82.41) ; U1.T16 v11(100.64,80.02) ; U1.V16 v11(99.04,80.02) ; U1.P13 v4(103.03,83.21) ; U1.R11 v4(101.44,84.81)
  TOP w0.381: 132.46,132.03 134.16,130.33 134.25,130.33 U3.B1 ; 132.46,132.03 131.83,132.67 ; 132.46,132.03 132.46,132.8
  L3_SIG1 w0.203: v11(101.44,77.62) v5(101.04,77.37) ; v11(100.64,77.62) v5(100.24,77.37)
  L3_SIG1 w0.254: v5(99.44,86.66) v4(99.84,86.41) ; v4(107.03,78.42) v5(107.43,78.17) ; v5(104.23,83.46) 104.23,83.46 v4(103.83,83.21) ; v5(108.23,83.46) 108.23,83.46 v4(107.83,83.21) ; v11(99.84,80.02) v5(99.44,79.77) ; v5(103.43,85.06) v4(103.03,84.81) ; v5(103.43,84.26) v4(103.03,84.01) ; v5(101.04,85.06) v4(101.44,84.81) ; v4(103.83,85.61) 104.23,85.86 v5(104.23,85.86) ; v5(98.64,87.46) v4(99.04,87.21) ; v5(99.44,87.46) v4(99.84,87.21) ; v5(105.83,88.26) v4(105.43,88.01) ; v11(99.04,80.02) v5(98.64,79.77) ; v4(101.44,80.02) v5(101.04,79.77) ; v5(103.43,83.46) v4(103.03,83.21) ; v11(100.64,80.02) v5(100.24,79.77) ; v4(107.03,79.22) v5(107.43,78.97) ; v5(99.44,83.46) v4(99.84,83.21) ; v4(107.83,82.41) 108.23,82.66 v5(108.23,82.66) ; v5(100.24,83.46) 100.24,83.46 v4(100.64,83.21) ; v5(105.83,87.46) v4(105.43,87.21)
  L10_SIG4 w0.254: v11(100.64,80.02) v5(100.24,79.77) ; v11(107.95,83.06) 108.01,82.8 v5(108.23,82.66) ; v11(99.84,87.22) v5(99.44,87.46) ; v11(108.63,83.22) v5(108.23,83.46) ; v11(101.44,84.82) v5(101.04,85.06) ; v11(103.03,84.82) v5(103.43,85.06) ; v11(99.84,86.42) v5(99.44,86.66) ; v11(101.44,77.62) 101.4,77.6 101.19,77.39 101.07,77.39 v5(101.04,77.37) ; v11(103.03,84.02) v5(103.43,84.26) ; v11(99.04,80.02) v5(98.64,79.77) ; v11(100.64,77.62) v5(100.24,77.37) ; v11(103.03,83.22) v5(103.43,83.46) ; v11(103.83,85.62) v5(104.23,85.86) ; v11(99.84,80.02) v5(99.44,79.77)
  L10_SIG4 w0.381: v5(86.44,68.2) 86.74,68.5 v7(86.74,68.71) ; v7(89.92,81.66) v5(89.15,81.66) ; v7(91.85,71.35) v5(91.85,70.76)
  BOTTOM w0.254: v11(103.83,85.62) v11(103.03,84.82) 102.83,85.02 C341.1 101.64,85.02 v11(101.44,84.82) ; C339.1 100.51,77.49 v11(100.64,77.62) v11(101.44,77.62) ; v11(103.03,83.22) v11(103.03,84.02) 102.95,83.93 C343.1
  BOTTOM w0.381: 99.84,86.42 v11(99.84,86.42) ; 99.84,86.42 100.38,86.97 ; 99.84,86.42 v11(99.84,87.22) ; v7(91.85,71.35) 91.95,71.45 C570.1 ; v11(99.84,80.02) 99.93,80.11 99.93,80.4 C344.1 100.64,80.55 v11(100.64,80.02) ; v7(86.74,68.71) C571.1 ; v5(89.15,81.66) v7(89.92,81.66) ; v11(107.95,83.06) 108.47,83.06 v11(108.63,83.22) 109.01,83.6 C342.1 ; v11(99.04,80.02) 99.31,80.29 C345.1
  vias: v5(79.25,84.07) v5(80.01,84.07) v5(112.14,77.22) v5(112.75,77.25) v5(113.46,77.24) v6(79.25,84.71) v6(80.01,84.71) v6(112.39,77.81) v6(112.45,76.73) v6(113.44,76.3) v6(114.3,76.33) v7(79.25,84.71) v7(80.01,84.71) v7(112.39,77.81) v7(112.45,76.73) v7(113.44,76.3) v7(114.3,76.33) v9(73.1,94.74) v9(73.15,93.55) v9(73.15,92.28) v9(74.55,94.37) v9(103.15,131.12) v9(104.55,132.16) v9(104.55,131.12) v9(104.55,129.85) v9(128.91,140.29) v9(128.91,139.4) v9(128.91,138.38) v9(129.79,140.29) v9(129.79,139.4) v9(129.79,138.38) v9(130.81,140.29) v9(130.81,139.4) v9(130.81,138.38)
VDD_DSP: length 13.2
  TOP w0.254: U1.M11 v4(104.63,84.81) ; U1.K10 v4(106.23,85.61) ; U1.M10 v4(104.63,85.61) ; U1.L11 v4(105.43,84.81) ; U1.L10 v4(105.43,85.61) ; U1.K11 v4(106.23,84.81)
  L3_SIG1 w0.254: v5(105.03,85.06) v4(104.63,84.81) ; v5(105.83,85.86) v4(105.43,85.61) ; v5(105.83,85.06) v4(105.43,84.81) ; v5(106.63,85.86) v4(106.23,85.61) ; v5(106.63,85.06) v4(106.23,84.81) ; v5(105.03,85.86) v4(104.63,85.61)
  L4_SIG2 w0.508: TP25.1 123.11,110.07 ; TP25.1 123.11,111.68 ; TP25.1 121.5,111.68 ; TP25.1 121.5,110.07
  L10_SIG4 w0.254: v5(127,109.81) 126.87,109.68 v11(126.49,109.68) ; v11(126.49,109.05) v5(127.3,109.05) ; v11(129.54,110.06) v5(129.03,110.06) ; v11(129.54,109.3) v5(129.03,109.3)
  vias: v5(113.41,86.06) v5(114.17,86.06) v5(114.94,86.06) v5(115.44,98.63) v5(116.03,105.59) v5(116.03,104.83) v5(116.03,98.63) v5(116.2,97.87) v5(116.79,105.59) v5(116.79,104.83) v5(116.79,104.07) v5(117.55,104.83) v10(104.63,85.31) v10(105.41,85.45) v10(105.48,86.97) v10(105.44,86.13) v10(106.2,86.16) v10(106.22,85.48) v10(113.94,85.32) v10(114.4,85.31) v10(114.94,85.3) v10(115.7,97.74) v10(116.71,97.74) v10(117.35,99.01) v11(104.63,85.31) v11(105.41,85.45) v11(105.48,86.97) v11(105.44,86.13) v11(106.2,86.16) v11(106.22,85.48) v11(113.94,85.32) v11(114.4,85.31) v11(114.94,85.3) v11(115.7,97.74) v11(116.71,97.74) v11(117.35,99.01)
VDD_GPU: length 14.3
  TOP w0.254: U1.W13 v4(98.24,83.21) ; U1.U11 v4(99.84,84.81) ; U3.K6 v8(138.25,123.14) ; U3.K6 v8(138.25,123.93) ; U3.K6 v8(139.04,123.93) ; U1.V10 v4(99.04,85.61) ; U1.V14 v4(99.04,82.41) ; U1.W10 v4(98.24,85.61) ; U1.V11 v4(99.04,84.81) ; U1.U12 v4(99.84,84.01) ; U1.W11 v4(98.24,84.81)
  L3_SIG1 w0.254: v5(97.84,85.06) v4(98.24,84.81) ; v5(98.64,85.86) v4(99.04,85.61) ; v5(97.84,83.46) v4(98.24,83.21) ; v5(97.84,85.86) v4(98.24,85.61) ; v5(98.64,85.06) v4(99.04,84.81) ; v5(98.64,82.66) v4(99.04,82.41) ; v5(99.44,85.06) v4(99.84,84.81) ; v5(99.44,84.26) v4(99.84,84.01)
  L10_SIG4 w0.254: v11(99.04,85.62) v5(98.64,85.86) ; v11(99.84,84.82) v5(99.44,85.06) ; v11(99.04,84.82) v5(98.64,85.06) ; v11(99.04,82.42) v5(98.64,82.66) ; v11(99.84,84.02) v5(99.44,84.26) ; v11(98.24,84.82) v5(97.84,85.06) ; v11(98.24,85.62) v5(97.84,85.86)
  BOTTOM w0.381: v11(99.04,82.42) 98.97,82.42 C329.1
  vias: v5(89.04,88.45) v5(89.61,88.35) v5(90.17,88.34) v5(90.42,87.76) v5(90.86,87.41) v9(133.73,112.98) v9(134.37,111.33) v9(135.51,111.33) v9(136.58,111.33) v10(86.49,87.4) v10(87.05,87.33) v10(87.6,87.3) v10(88.19,87.33) v10(88.95,87.45) v10(89.69,87.45) v10(89.94,87.86) v10(91.01,87.96) v11(86.49,87.4) v11(87.05,87.33) v11(87.6,87.3) v11(88.19,87.33) v11(88.95,87.45) v11(89.69,87.45) v11(89.94,87.86) v11(91.01,87.96)
VDD_IVA: length 7.3
  TOP w0.254: U1.M12 v4(104.63,84.01) ; U1.K12 v4(106.23,84.01) ; U1.L12 v4(105.43,84.01) ; v8(135.05,123.14) U3.K2 v8(135.84,123.14) ; U1.M13 v4(104.63,83.21) ; U1.J13 v4(107.03,83.21) ; U1.K13 v4(106.23,83.21)
  L3_SIG1 w0.254: v5(105.03,84.26) v4(104.63,84.01) ; v5(105.03,83.46) v4(104.63,83.21) ; v5(106.63,84.26) v4(106.23,84.01) ; v5(106.63,83.46) v4(106.23,83.21) ; v5(107.43,83.46) v4(107.03,83.21) ; v5(105.83,84.26) v4(105.43,84.01)
  vias: v9(117.62,132.42) v9(117.86,133.94) v9(118.77,133.05) v9(118.77,131.78) v9(120.04,133.05) v9(120.04,131.78) v10(104.75,83.08) v10(105.33,83.08) v10(105.66,83.77) v10(105.66,83.39) v10(106.23,84.02) v11(104.75,83.08) v11(105.33,83.08) v11(105.66,83.77) v11(105.66,83.39) v11(106.23,84.02)
VDD_MIPI: length 0.9
  BOTTOM w0.254: U89.E10 v8(154.31,98.57) ; U89.H10 v8(152.35,98.57)
VDD_MPU: length 29.6
  TOP w0.254: U1.M17 v11(104.63,79.22) ; U1.L17 v11(105.43,79.22) ; U1.L19 v4(105.43,77.62) ; U1.P18 v4(103.03,78.42) ; U1.M18 v4(104.63,78.42) ; U1.K17 v11(106.23,79.22) ; U1.M15 v11(104.63,80.82) ; U1.L16 v11(105.43,80.02) ; U1.L18 v4(105.43,78.42) ; U1.N18 v4(103.83,78.42) ; U1.K18 v11(106.23,78.42) ; U1.P17 v4(103.03,79.22) ; U1.R18 v4(101.44,78.42) ; U1.N17 v4(103.83,79.22) ; U1.M16 v11(104.63,80.02) ; U1.L15 v4(105.43,80.82)
  TOP w0.381: U3.B13 145.03,130.73 145.03,131.15 145.42,131.53
  L3_SIG1 w0.254: v4(104.63,78.42) v5(105.03,78.17) ; v11(105.43,79.22) v5(105.83,78.97) ; v4(105.43,80.82) v5(105.83,80.57) ; v4(103.03,79.22) v5(103.43,78.97) ; v11(104.63,80.82) v5(105.03,80.57) ; v4(103.03,78.42) v5(103.43,78.17) ; v11(104.63,80.02) v5(105.03,79.77) ; v11(106.23,78.42) v5(106.63,78.17) ; v11(106.23,79.22) v5(106.63,78.97) ; v11(104.63,79.22) v5(105.03,78.97) ; v11(105.43,80.02) v5(105.83,79.77) ; v4(105.43,77.62) v5(105.83,77.37) ; v4(101.44,78.42) v5(101.04,78.17) ; v4(103.83,79.22) v5(104.23,78.97) ; v4(103.83,78.42) v5(104.23,78.17) ; v4(105.43,78.42) v5(105.83,78.17)
  L10_SIG4 w0.254: v5(104.23,78.17) 104.59,78.39 v11(104.62,78.52) 104.65,78.41 v5(105.03,78.17) ; v11(106.23,79.22) v5(106.63,78.97) ; v11(104.63,80.02) v5(105.03,79.77) ; v11(106.23,78.42) v5(106.63,78.17) ; v11(105.43,80.02) v5(105.83,79.77) ; v5(105.03,78.97) v11(104.63,79.22) v5(104.23,78.97) ; v11(105.41,78.52) 105.81,78.27 v5(105.83,78.17) ; v11(105.43,79.22) v5(105.83,78.97) ; v11(104.63,80.82) v5(105.03,80.57)
  L10_SIG4 w0.381: v7(116.2,79.08) v5(115.57,79.08) ; v11(103.63,95.2) v5(103.63,94.47) ; v11(104.65,95.2) v5(104.65,94.44) ; v5(113.44,90.66) 113.79,91.01 v7(113.79,91.31) ; v7(114.66,91.39) 114.66,91.5 v5(115.06,91.9) ; v7(115.57,88.09) v5(116.46,88.09) ; v7(116.2,80.09) v5(115.57,80.09)
  BOTTOM w0.254: v11(102.11,79.05) v11(102.11,78.67)
  vias: v5(97.26,94.62) v5(97.26,94.06) v5(97.26,93.5) v6(96.27,95.33) v6(96.9,95.71) v6(96.9,95.08) v7(96.27,95.33) v7(96.9,95.71) v7(96.9,95.08) v8(116.84,125.68) v8(116.84,124.54) v8(116.84,123.27) v8(118.21,125.66) v8(118.21,124.52) v8(118.21,123.25) v8(118.21,121.98) v9(145.8,134.19) v9(145.8,133.43) v9(145.8,132.67) v9(145.92,132.03) v9(146.56,134.19) v9(146.56,133.43) v9(146.56,132.67) v10(101.63,79.89) v10(102.13,79.76) v11(101.63,79.89) v11(102.13,79.76)
VDD_RTC: length 3.5
  TOP w0.381: v9(138.29,131.83) 138.29,131.18 U3.A5
  BOTTOM w0.381: v9(138.29,131.83) 138.3,131.84 138.3,132.54 v9(138.28,132.57) ; v9(138.28,132.57) 138.28,132.59 138.3,132.62 v9(138.3,133.23) ; v9(138.28,132.57) 138.19,132.66 138.07,132.66 137.8,132.92 C402.1
  vias: v5(79.91,86.44) v5(80.67,86.44) v6(80.14,87.38) v6(80.77,87.76) v7(80.14,87.38) v7(80.77,87.76)
VDDR_VREF: length 9.9
  TOP w0.254: U5.M8 v8(87.98,29.48) ; U8.6 105.15,13.11 ; U5.H1 v8(83.18,32.68) ; U7.H1 v8(98.42,32.68) ; U7.M8 v8(103.22,29.48) ; U1.Y18 v4(97.44,78.42) ; U6.M8 v8(118.46,29.48) ; U6.H1 v8(113.66,32.68)
  TOP w0.508: C46.1 v9(92.33,28.96) ; C54.1 v9(122.81,28.7) ; C83.1 v9(107.57,28.7)
  L3_SIG1 w0.254: v4(97.44,78.42) v5(97.04,78.17)
  L10_SIG4 w0.254: v11(96.66,77.82) 96.81,77.97 97.01,78.17 v5(97.04,78.17)
  BOTTOM w0.381: v11(96.66,77.82) 96.66,78.05 C81.1
  vias: v9(91.19,21.08) v9(91.82,20.45) v9(92.46,21.21) v9(92.96,20.57) v9(93.6,19.94)
VDDR_VTT: length 12.2
  TOP w0.305: C100.1 107.82,17.4 U8.3
  TOP w0.508: R69.2 102.6,17.4 102.03,17.97 102.03,21.13 103.13,22.23 106.68,22.23
  vias: v9(118.11,19.67) v9(120.65,19.67) v9(124.84,19.8) v9(125.98,20.98) v9(127.13,19.8)
VDDS_DDR: length 108.5
  TOP w0.254: U7.A8 v8(103.22,38.28) ; U7.C1 v8(97.62,36.68) ; U7.K2 v8(98.42,31.08) ; U6.H2 v8(114.46,32.68) ; U5.N9 v8(89.74,28.28) ; U5.D2 v8(83.98,35.88) ; U7.F1 v8(98.42,34.28) ; U5.E9 v8(88.78,35.08) ; U5.R1 v8(82.21,26.68) ; U6.C1 v8(112.86,36.68) ; U5.G7 v8(87.18,33.48) ; U6.H9 v8(120.06,32.68) ; U6.E9 v8(119.26,35.08) ; U7.N1 v8(97.45,28.28) ; U5.F1 v8(83.18,34.28) ; U6.A8 v8(118.86,38.44) ; v8(97.38,26.68) U7.R1 ; U5.H2 v8(83.98,32.68) ; U7.A1 v8(97.62,38.28) ; U5.C1 v8(82.21,36.28) ; U5.H9 v8(89.74,32.28) ; U7.H2 v8(99.22,32.68) ; U6.A1 v8(112.86,38.28) ; U7.N9 v8(104.98,28.28) ; U7.D2 v8(99.22,35.88) ; U7.H9 v8(104.82,32.68) ; U6.N9 v8(120.22,28.28) ; U6.D9 v8(120.06,35.88) ; U6.B7 v8(117.66,37.48) ; v8(112.64,26.66) 112.65,26.68 U6.R1 ; U5.D9 v8(89.74,35.48) ; U5.K8 v8(87.98,31.08) ; U6.C9 v8(119.26,36.68) ; U7.C9 v8(104.02,36.68) ; U5.C9 v8(88.78,36.68) ; U7.R9 v8(104.98,26.68) ; U7.E9 v8(104.02,35.08) ; U7.B2 v8(99.22,37.48) ; U5.N1 v8(82.21,28.28) ; U5.K2 v8(83.98,31.08) ; U5.A8 v8(87.98,38.28) ; U7.D9 v8(104.82,35.88) ; U6.D2 v8(114.46,35.88) ; U6.B2 v8(114.46,37.48) ; U6.K8 v8(118.46,31.08) ; U6.G7 v8(117.66,33.48) ; U7.K8 v8(103.22,31.08) ; U5.A1 v8(82.21,37.88) ; U5.R9 v8(89.74,26.68) ; U5.B2 v8(83.98,37.48) ; U6.F1 v8(113.66,34.28) ; U6.R9 v8(120.27,26.68) ; U6.N1 v8(112.69,28.28) ; U7.G7 v8(102.42,33.48) ; U6.K2 v8(113.66,31.08)
  TOP w0.305: U8.2 108.32,17.39 C90.1
  TOP w0.381: C64.1 v9(112.24,19.05) ; C64.1 v9(113.3,17.91) ; C64.1 v9(113.3,20.19) ; C52.1 v9(98.06,17.91) ; C52.1 v9(96.92,19.05) ; C52.1 v9(98.06,20.19) ; v9(129.67,25.02) 129.41,24.77 C89.2 ; C33.1 v9(89.17,16.64) ; C33.1 v9(88.03,17.78) ; C33.1 v9(89.17,18.92) ; R45.2 v8(112.39,15.11)
  TOP w0.508: C47.1 v9(109.22,35.18) ; C80.1 v9(93.98,35.18) ; C44.1 v9(78.74,35.18)
  L3_SIG1 w0.381: v9(109.6,20.7) 108.97,20.07 108.97,17.1 110.95,15.11 v8(112.39,15.11)
  BOTTOM w0.381: v8(112.64,26.66) 112.38,26.92 C72.1 ; v8(97.62,38.28) 97.08,38.28 C49.1 ; C48.1 105.39,36.45 v8(104.82,35.88) ; v8(104.98,26.68) 105.1,26.8 C55.1 ; C50.1 103.22,39.08 v8(103.22,38.28) ; C85.2 v9(130.05,30.48) ; C32.1 89.01,36.45 v8(88.78,36.68) ; C59.1 97.28,33.91 97.65,34.28 v8(98.42,34.28) ; v8(104.82,32.68) 105.03,32.89 C65.1 ; C77.1 112.65,35.94 112.86,36.15 v8(112.86,36.68) ; C60.1 113.66,31.88 v8(114.46,32.68) ; C67.1 97.16,35.94 97.62,36.41 v8(97.62,36.68) ; v8(89.74,26.68) 89.86,26.8 C35.1 ; v8(117.66,33.48) 117.58,33.4 C62.1 ; 111.38,14.73 112.01,14.73 v8(112.39,15.11) ; C61.1 120.27,32.89 v8(120.06,32.68) ; v8(83.98,37.48) 83.46,38 83.46,38.75 C30.1 ; v8(119.26,35.08) 119.41,34.92 C73.1 ; v8(87.98,38.28) 87.98,39.08 C34.1 ; C51.1 97.26,26.8 v8(97.38,26.68) ; v8(113.66,34.28) 112.62,34.28 112.26,33.91 C78.1 ; v8(112.69,28.28) 112.36,27.94 C79.1 ; v8(114.46,37.48) 114.17,37.76 C71.1 ; C63.1 118.87,38.46 v8(118.86,38.44) ; v8(83.18,34.28) 82.81,33.91 C42.1 ; v8(97.45,28.28) 97.37,28.19 C57.1 ; C314.2 v9(129.92,26.92) ; v8(89.74,28.28) 89.79,28.32 C37.1 ; C56.1 97.75,31.75 v8(98.42,31.08) ; C29.1 81.88,35.94 v8(82.21,36.28) ; v8(89.74,32.28) 90.14,31.88 C36.1 ; C70.1 120.39,26.8 v8(120.27,26.68) ; v8(87.98,31.08) 88.01,31.05 C39.1 ; v8(120.06,35.88) 120.63,36.45 C76.1 ; C66.1 105.03,28.32 v8(104.98,28.28) ; v8(120.22,28.28) 120.27,28.32 C75.1 ; C38.1 90.3,34.92 v8(89.74,35.48) ; v8(82.21,37.88) 82.12,37.97 C31.1 ; C58.1 102.34,33.4 v8(102.42,33.48) ; v8(112.86,38.28) 112.32,38.28 C74.1 ; C68.1 105.64,35.08 v8(104.02,35.08) ; 98.93,38.99 98.55,38.61 98.55,38.1 99.18,37.48 v8(99.22,37.48) ; C87.2 v9(130.05,29.34)
  vias: v9(61.02,73.81) v9(61.02,72.54) v9(62.29,73.81) v9(62.29,72.54) v9(63.56,72.54) v9(108.71,21.46) v9(108.71,20.7) v9(109.6,21.46) v9(148.84,118.32) v9(148.84,117.18) v9(150.11,118.32) v9(150.11,117.18) v9(151.26,118.32) v9(151.26,117.18)
6PORT_LCDN: length 102.1
  TOP w0.173: v3(109.98,124.59) 110.74,124.59 114.43,120.9 115.82,120.9 121.92,114.81 127.64,114.81 128.91,113.54 128.91,110.49 130.79,108.6 U103.1 134.98,108.6 135.72,107.86 135.72,95.34 133.99,93.61 U102.1 ; R925.2 v3(105.41,129.29) ; v3(132.84,93.09) 132.86,93.11 U102.1 ; 138.18,66.17 R924.1 136.78,69.22 135.74,70.25 135.74,92.22 134.85,93.11 U102.1
  L3_SIG1 w0.109: v3(105.41,129.29) 106.3,129.29 109.98,125.6 v3(109.98,124.59) ; v3(132.84,93.09) v5(133.48,93.09)
  L10_SIG4 w0.109: v5(133.48,93.09) 133.48,90.65 132.21,89.38 v7(132.21,88.77)
  BOTTOM w0.173: U104.1 132.34,88.91 v7(132.21,88.77)
AM57XX_AUDIOBUZZER_TRIG: length 82.7
  TOP w0.173: v8(140.72,9.78) 141.1,10.16 R114.1 ; U1.A25 113.43,73.21 115.13,71.51 116.03,71.51 119.36,68.19 121.4,68.19 121.75,67.84 121.75,67.56 122.4,66.91 122.4,62.24 123.43,61.21 126.34,61.21 127.4,62.27 129.5,62.27 130.57,61.2 v3(130.57,60.83)
  L3_SIG1 w0.109: v3(130.57,60.83) 130.57,19.93 v8(140.72,9.78)
AM57XX_CLKOUT3: length 164.8
  TOP w0.173: U1.C23 v4(111.83,74.42)
  L3_SIG1 w0.109: v4(111.83,74.42) 112.46,75.04 114.83,75.04 119.08,70.79 119.08,69.25 120.19,68.13 121.44,68.13 122.3,67.26 125.99,67.26 126.24,67.51 132.02,67.51 135.77,71.26 140.36,71.26 141.64,72.55 146.75,72.55 147.74,73.54 150.04,73.54 151.37,74.86 154.56,74.86 155.49,75.79 160.41,75.79 162.12,77.5 162.84,77.5 165.91,80.57 169.39,80.57 v5(169.67,80.85) ; v8(163.32,147.32) 163.32,147.96 164.21,148.84 174.12,148.84 174.83,149.56 177.89,149.56 180.79,146.66 180.79,137 172.72,128.93 172.72,116.29 v5(166.12,109.68)
  L10_SIG4 w0.109: v5(169.67,80.85) 170.59,81.76 170.59,86.75 172.41,88.57 172.41,89.39 172.4,89.39 172.4,96.83 171.2,98.03 171.2,104.6 v5(166.12,109.68)
  BOTTOM w0.173: R905.2 v8(163.32,147.32)
AM57XX_GPIO6_14: length 17.7
  TOP w0.173: R685.2 v3(122.81,68.28) ; U1.E21 v4(110.23,76.02)
  L3_SIG1 w0.109: v3(122.81,68.28) 122.35,68.74 122.35,69.37 122.05,69.68 122.05,70.03 121.01,71.07 119.91,71.07 115.7,75.29 111.76,75.29 111.35,75.7 110.9,75.7 110.58,76.02 v4(110.23,76.02)
AM57XX_GPIO6_15: length 11.5
  TOP w0.173: U1.F20 v4(109.43,76.82)
  L3_SIG1 w0.109: v4(109.43,76.82) v5(109.83,76.57)
  L10_SIG4 w0.109: v7(118.36,74.25) 118.36,74.68 117.83,75.21 117.4,75.21 117.02,75.6 112.32,75.6 111.76,76.15 110.25,76.15 v5(109.83,76.57)
  BOTTOM w0.173: R661.2 v7(118.36,74.25)
AM57XX_GPIO6_16: length 11.5
  TOP w0.173: U1.F21 v4(109.43,76.02)
  L3_SIG1 w0.109: v4(109.43,76.02) v5(109.83,75.77)
  L10_SIG4 w0.109: v7(118.36,73.23) 117.32,74.27 116.71,74.27 115.62,75.37 112.17,75.37 111.61,75.93 109.99,75.93 v5(109.83,75.77)
  BOTTOM w0.173: R666.2 v7(118.36,73.23)
AM57XX_GPIO_RS485: length 12.9
  TOP w0.173: R584.2 92.46,100.58 v3(93,100.04) ; U1.AA3 v4(96.64,91.21)
  L3_SIG1 w0.109: v3(93,100.04) 93.64,99.4 93.83,99.4 95.94,97.29 95.94,96.85 96.64,96.15 v4(96.64,91.21)
AM57XX_GPMC_AD0: length 96.5
  TOP w0.173: R434.1 101.45,108.41 v8(102.29,107.57) ; U1.M6 v4(104.63,88.81)
  L3_SIG1 w0.109: v5(116.89,138.35) 124.79,138.35 128.55,142.11 v5(129.41,142.11) ; v5(105.03,89.06) 105.03,89.06 104.64,88.81 v4(104.63,88.81)
  L4_SIG2 w0.114: v5(105.03,89.06) 105.44,89.47 105.44,92.2 105.03,92.6 105.03,93.17 105.31,93.45 105.31,94.51 104.77,95.05 104.77,96.83 106.24,98.29 107.83,98.29 108.81,99.28 108.81,102.21 108.41,102.62 108.41,104.06 106.65,105.82 105.02,105.82 104.19,106.64 103.22,106.64 v8(102.29,107.57) 103.22,108.51 103.22,108.51 103.41,108.51 104.86,109.95 104.86,110.58 104.06,111.38 104.06,113.63 104.62,114.2 104.62,115.84 105.22,116.44 105.22,123.83 104.59,124.47 104.59,128.56 104.03,129.11 104.03,134.9 106,136.87 107.54,136.87 109.65,138.97 109.65,141.25 110.55,142.15 115.1,142.15 v5(115.82,142.88)
  L9_SIG3 w0.114: v5(115.82,142.88) 116.2,142.5 116.2,139.05 v5(116.89,138.35)
  L10_SIG4 w0.109: v7(130.3,142.11) v5(129.41,142.11)
  BOTTOM w0.173: R453.2 102.29,107.73 v8(102.29,107.57) ; R861.2 v7(130.3,142.11)
AM57XX_GPMC_AD1: length 76.2
  TOP w0.173: R435.1 v8(108.84,112.1) 108.03,111.28 108.03,106.6 108.31,106.32 108.31,98.89 107.56,98.14 107.56,97.55 104.64,94.63 104.64,92.02 U1.M2
  L4_SIG2 w0.114: v8(108.84,112.1) 108.84,113.47 108.33,113.98 108.33,114.42 108.34,114.42 108.34,114.85 108.33,114.85 108.33,120.37 107.85,120.85 107.85,127.92 109.05,129.12 109.05,134.15 111.33,136.43 113.62,136.43 113.62,136.43 113.86,136.43 116.44,139.01 117.4,139.01 117.83,138.58 122.81,138.58 126.8,142.57 v5(129.82,142.57)
  L10_SIG4 w0.109: v7(133.35,142.11) 132.89,142.57 v5(129.82,142.57)
  BOTTOM w0.173: R862.2 v7(133.35,142.11) ; R435.1 v8(108.84,112.1)
AM57XX_GPMC_AD2: length 95.6
  TOP w0.173: R436.1 104.27,108.03 v8(104.65,107.65) ; U1.L5 v4(105.43,89.61)
  L3_SIG1 w0.099: v5(106.54,97.13) 106.06,97.13 104.92,95.99 104.92,95.47 105.23,95.16 105.23,94.16 104.7,93.63 104.7,92.15 104.93,91.92 104.93,90.5
  L3_SIG1 w0.109: 104.93,90.5 105.43,89.99 v4(105.43,89.61)
  L4_SIG2 w0.114: v5(136.02,141.53) 136.02,144.07 134.64,145.45 130,145.45 128.83,144.27 119.58,144.27 116.31,141.01 113.59,141.01 112.95,140.36 112.95,138.94 111.91,137.91 110.67,137.91 106.61,133.85 106.61,128.75 106.39,128.53 106.39,127.12 105.5,126.23 105.5,124.79 106.1,124.19 106.1,116.08 105.5,115.48 105.5,112.99 104.93,112.43 104.93,111.74 105.77,110.91 105.77,108.77 v8(104.65,107.65) 104.65,107.54 105.48,106.7 107.09,106.7 109.37,104.42 109.37,103.1 109.86,102.62 109.86,98.37 108.61,97.13 v5(106.54,97.13)
  L10_SIG4 w0.109: v5(136.02,141.53) 135.43,142.11 v7(135.38,142.11)
  BOTTOM w0.173: R863.2 v7(135.38,142.11) ; R455.2 v8(104.65,107.65)
AM57XX_GPMC_AD3: length 82.9
  TOP w0.173: R864.2 v3(138.43,142.24) ; R437.1 v8(106.81,112.1) 107.67,111.23 107.67,106.32 107.95,106.04 107.95,99.03 107.21,98.29 107.21,97.86 104.23,94.88 U1.M1
  L3_SIG1 w0.109: v3(138.43,142.24) v5(138.43,141.66)
  L4_SIG2 w0.114: v8(106.81,112.1) 106.43,112.48 106.43,115.17 106.97,115.72 106.97,124.62 106.43,125.16 106.43,125.92 107.27,126.76 107.27,128.16 108.46,129.36 108.46,134.39 111.09,137.02 111.21,137.02 111.21,137.02 113.62,137.02 119.68,143.08 127.67,143.08 v5(128.21,143.62)
  L9_SIG3 w0.114: v5(128.21,143.62) 136.46,143.62 v5(138.43,141.66)
  BOTTOM w0.173: R437.1 v8(106.81,112.1)
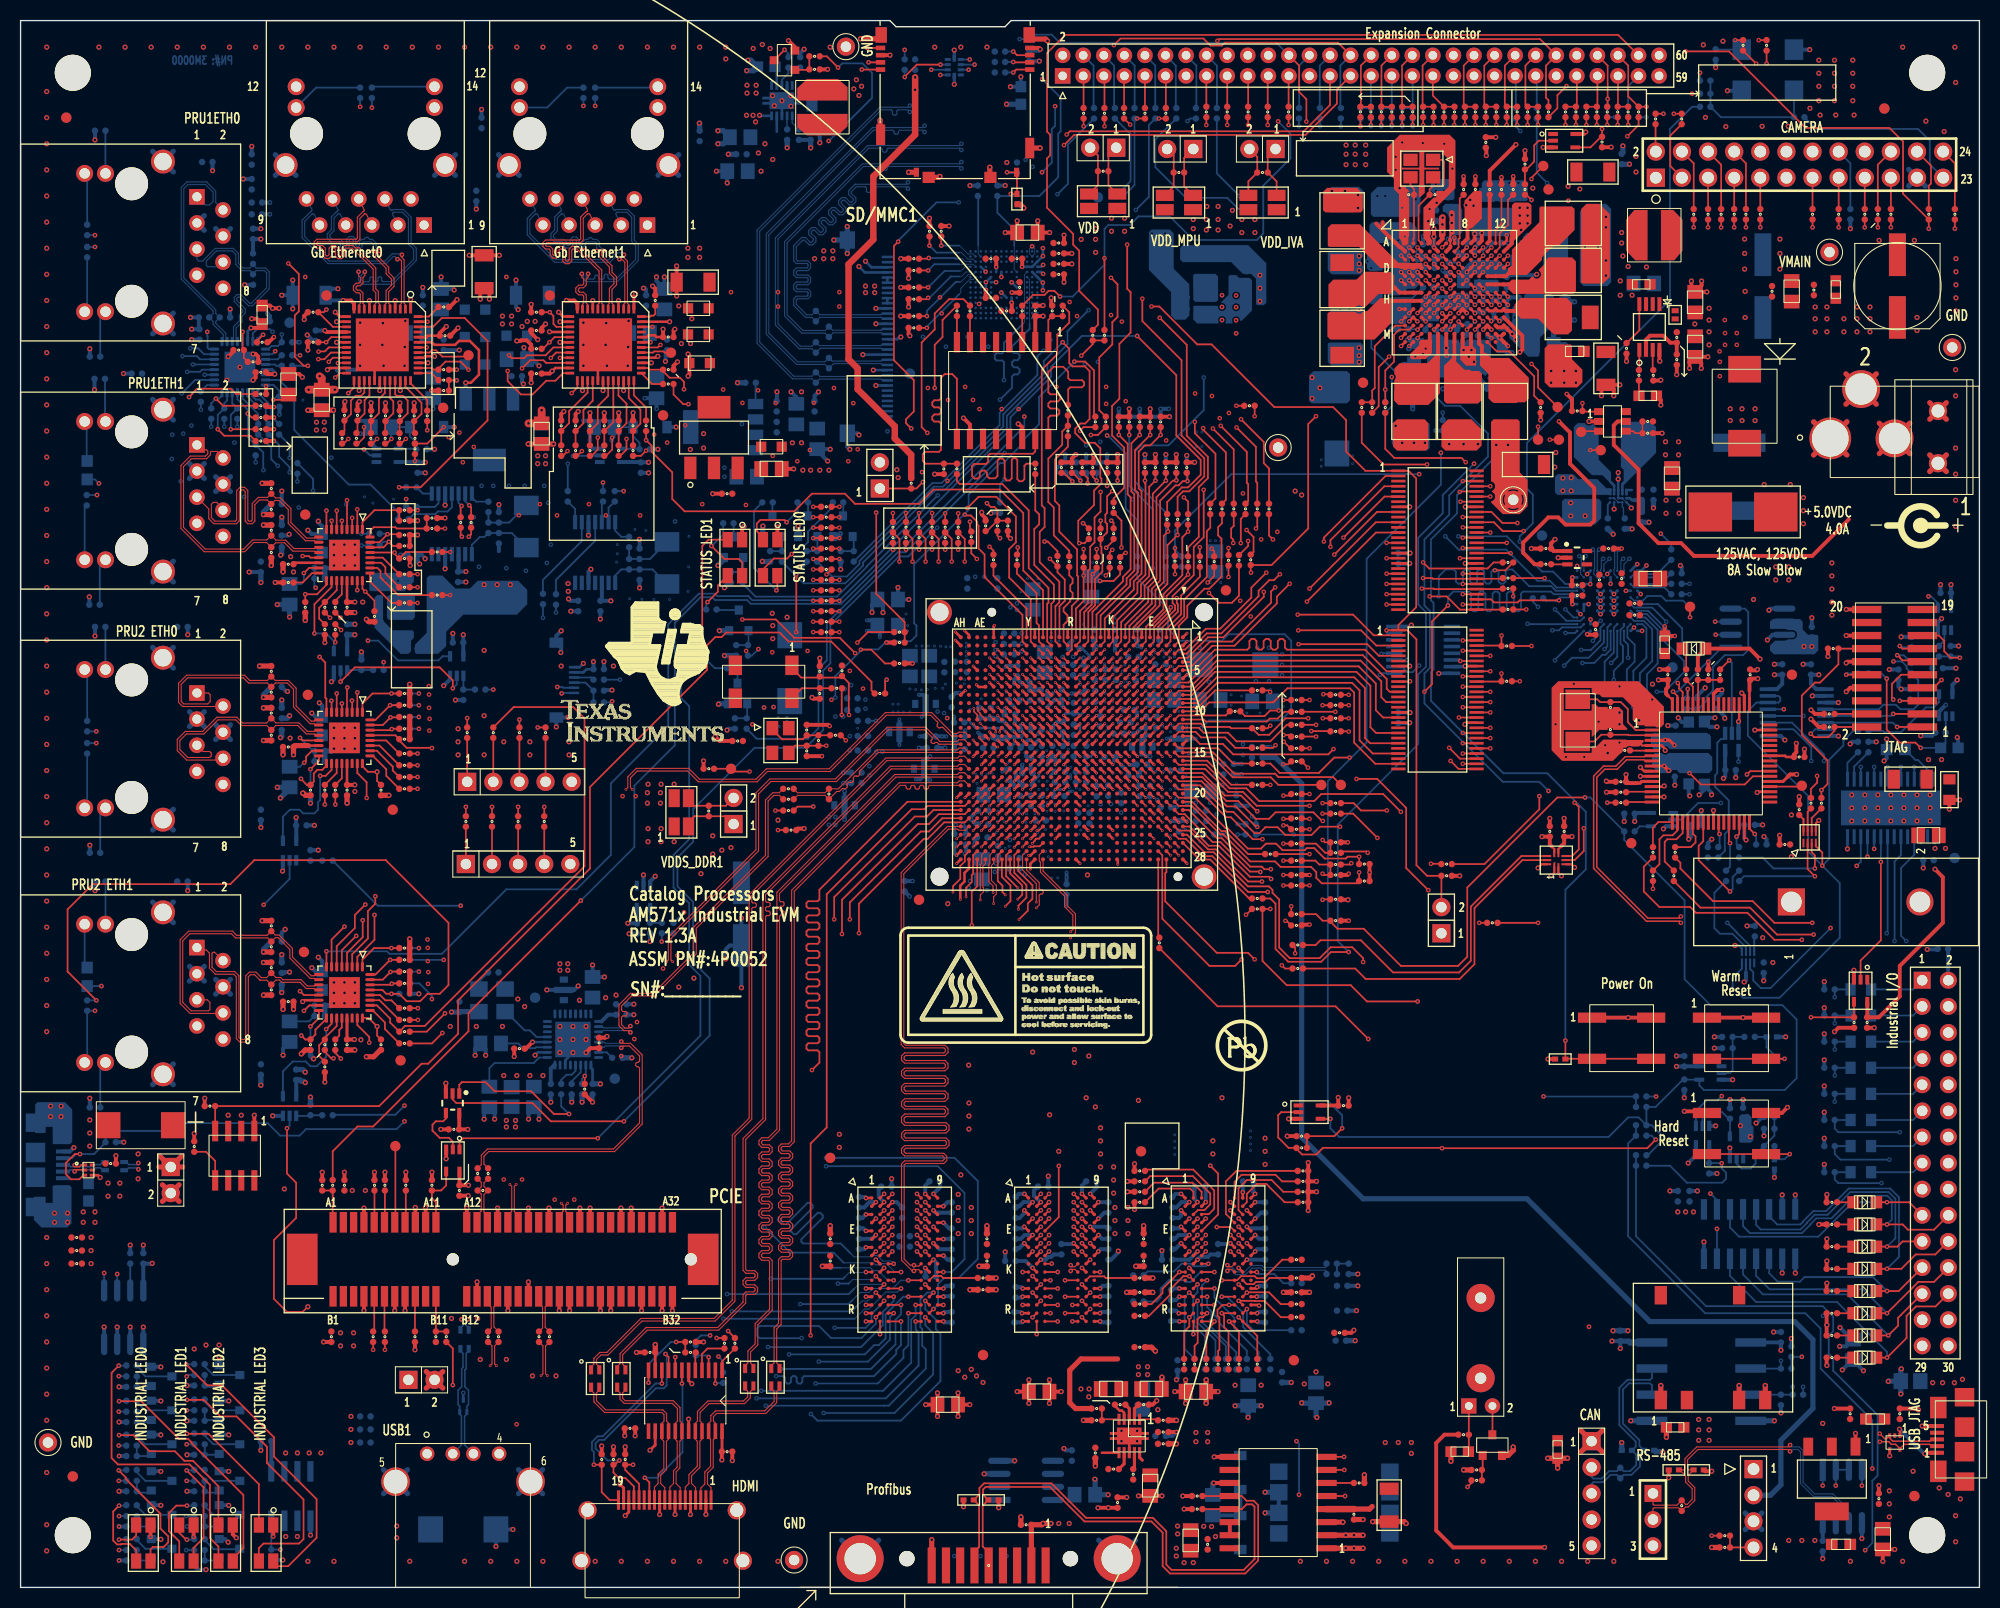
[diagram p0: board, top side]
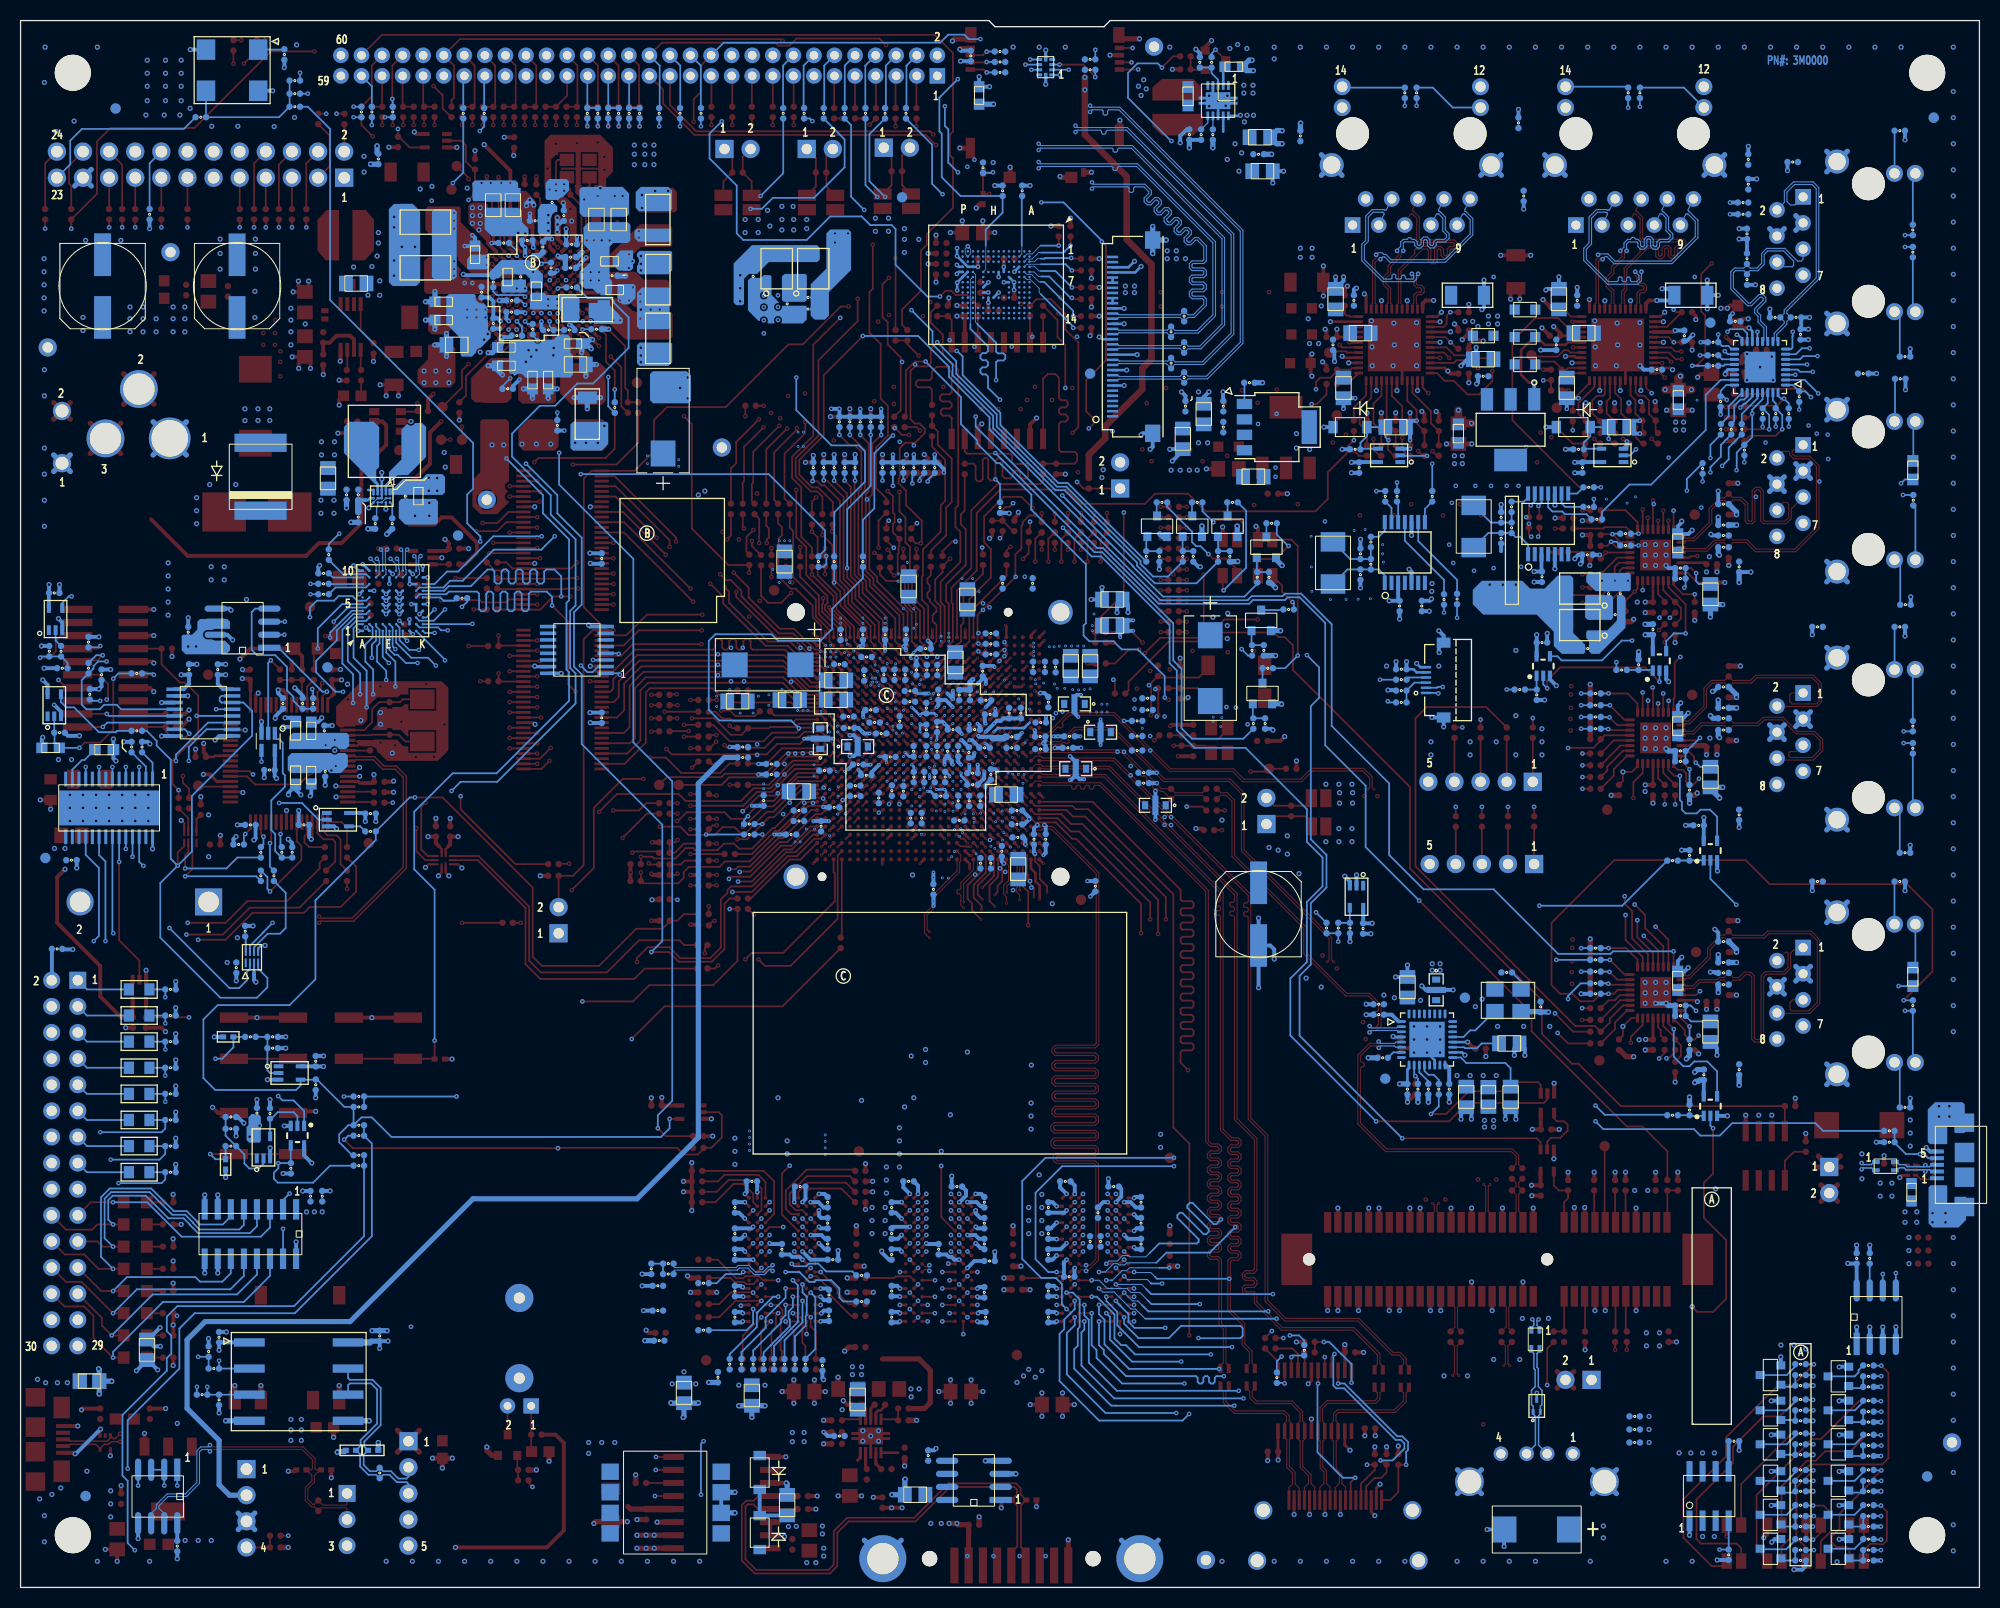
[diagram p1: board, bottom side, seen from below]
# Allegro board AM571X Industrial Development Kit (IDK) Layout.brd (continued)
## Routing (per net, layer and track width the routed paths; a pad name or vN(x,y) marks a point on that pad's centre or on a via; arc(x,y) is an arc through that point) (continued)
AM57XX_GPMC_AD4: length 103.1
  TOP w0.173: U1.L6 v4(105.43,88.81) ; R438.1 v8(107.82,112.1) ; R857.2 v3(150.24,142.24)
  L3_SIG1 w0.109: v3(150.24,142.24) 149.1,142.24 147.18,144.16 132.88,144.16 132.19,144.85 126.69,144.85 124.48,142.64 v5(123.9,142.64) ; v5(105.83,89.06) 105.83,89.06 105.44,88.81 v4(105.43,88.81)
  L4_SIG2 w0.114: v5(123.9,142.64) 122.98,142.64 122.45,142.11 119.13,142.11 113.74,136.72 111.21,136.72 108.76,134.27 108.76,129.24 107.56,128.04 107.56,126.64 106.81,125.89 106.81,125.2 107.27,124.74 107.27,115.6 106.81,115.14 106.81,113.11 v8(107.82,112.1) ; v5(111.59,99.36) 111.59,97.57 108.59,94.57 107.12,94.57 105.83,93.29 v5(105.83,89.06)
  L10_SIG4 w0.109: v5(111.59,99.36) 110.33,99.36 v7(110.11,99.14)
  BOTTOM w0.173: v7(110.11,99.14) 110.11,104.86 107.82,107.14 v8(107.82,112.1) R438.1
AM57XX_GPMC_AD5: length 111.3
  TOP w0.173: v8(103.77,107.38) 103.78,107.4 103.78,107.88 R439.1 ; U1.L4 v4(105.43,90.41) ; R858.2 v3(152.27,142.24)
  L3_SIG1 w0.099: 105.79,96.29 105.54,96.29 105.17,95.92 105.17,95.51 105.43,95.24 105.43,94.07 104.9,93.54 104.9,92.54 105.14,92.3 105.14,91.07
  L3_SIG1 w0.109: v5(125.3,144.71) 125.33,144.71 125.76,145.14 132.46,145.14 133.15,144.44 150.07,144.44 v3(152.27,142.24) ; v4(105.43,90.41) 105.43,90.78 105.14,91.07 ; 105.79,96.29 v5(106.09,96.6)
  L4_SIG2 w0.114: v8(103.77,107.38) 103.78,107.4 ; 103.78,107.4 104.26,107.4 105.25,106.41 106.95,106.41 109.07,104.29 109.07,102.9 109.52,102.44 109.52,98.53 108.7,97.7 106.48,97.7 106.09,97.31 v5(106.09,96.6) ; 103.78,107.4 103.78,107.88 104.27,108.36 104.74,108.36 105.46,109.08 105.46,110.8 104.64,111.62 104.64,112.72 105.21,113.28 105.21,115.6 105.81,116.2 105.81,124.07 105.21,124.67 105.21,126.35 105.58,126.73 105.58,135.54 106.32,136.28 107.78,136.28 110.29,138.78 110.29,140.44 111.15,141.31 116.11,141.31 116.15,141.34 116.15,141.34 119.37,144.56 125.16,144.56 125.3,144.7 v5(125.3,144.71)
  BOTTOM w0.173: v8(103.77,107.38) 103.78,107.4 103.78,108.26 R458.2
AM57XX_GPMC_AD6: length 115
  TOP w0.173: R440.1 102.31,108.41 v8(103.07,107.65) ; U1.L3 v4(105.43,91.21) ; R859.2 v3(156.34,142.24)
  L3_SIG1 w0.099: v4(105.43,91.21) 105.43,92.29 105.1,92.63 105.1,93.46 105.66,94.02 v5(105.66,95.87)
  L3_SIG1 w0.109: v3(156.34,142.24) 156.34,143.51 154.27,145.58 125.15,145.58 v5(124.61,145.03)
  L4_SIG2 w0.114: v5(105.66,95.87) 105.66,97.3 106.36,98 107.95,98 109.17,99.21 109.17,102.29 108.71,102.74 108.71,104.22 106.81,106.12 105.13,106.12 104.31,106.93 103.58,106.93 103.07,107.44 v8(103.07,107.65) 105.15,109.73 105.15,110.7 104.35,111.5 104.35,113.09 104.91,113.65 104.91,115.72 105.51,116.32 105.51,123.95 104.91,124.55 104.91,126.47 105.29,126.85 105.29,135.66 105.46,135.83 105.46,135.83 106.2,136.57 107.66,136.57 109.98,138.89 109.98,140.67 110.95,141.64 116.03,141.64 119.43,145.03 v5(124.61,145.03)
  BOTTOM w0.173: R459.2 102.62,108.39 103.07,107.93 v8(103.07,107.65)
AM57XX_GPMC_AD7: length 106.4
  TOP w0.173: U1.L2 105.43,92.01 105.43,94.24 108.26,97.06 108.26,97.85 109.02,98.61 109.02,106.63 108.74,106.91 108.74,110.47 109.35,111.08 109.86,111.08 v8(110.87,112.1) R441.1
  L3_SIG1 w0.109: v5(157.35,141.61) 156.36,141.61 155.76,142.2 155.76,142.57 153.31,145.01 v5(133.79,145.01)
  L4_SIG2 w0.114: v8(110.87,112.1) 110.42,112.54 110.42,114.83 109.55,115.7 109.55,122.33 108.73,123.14 108.73,125.6 109.98,126.85 109.98,133.83 111.7,135.55 114.22,135.55 115.97,137.3 123.97,137.3 124.46,137.8 131.06,137.8 133.79,140.52 v5(133.79,145.01)
  L10_SIG4 w0.109: v7(156.34,142.24) 156.72,142.24 v5(157.35,141.61)
  BOTTOM w0.173: R860.2 v7(156.34,142.24) ; R441.1 v8(110.87,112.1)
AM57XX_GPMC_AD8: length 72.7
  TOP w0.173: R442.1 v8(109.86,112.1) 108.38,110.62 108.38,106.76 108.66,106.48 108.66,98.75 107.91,98 107.91,97.41 105.04,94.53 U1.L1 ; R838.1 v3(131.32,142.24)
  L3_SIG1 w0.109: v3(131.32,142.24) v5(131.32,141.5)
  L4_SIG2 w0.114: v8(109.86,112.1) 109.86,113.51 109.26,114.11 109.26,122.21 108.44,123.02 108.44,123.08 108.44,123.08 108.44,125.99 109.63,127.18 109.63,133.9 111.58,135.84 114.1,135.84 115.85,137.6 122.92,137.6 126.19,140.87 130.68,140.87 v5(131.32,141.5)
  BOTTOM w0.173: v8(109.86,112.1) R442.1
AM57XX_GPMC_AD9: length 76.4
  TOP w0.173: R443.1 v8(109.35,107.65) 109.35,107.39 109.4,107.34 109.4,98.5 108.61,97.71 108.61,96.73 106.24,94.35 106.24,92.02 U1.K2 ; R839.1 v3(133.35,142.24)
  L3_SIG1 w0.109: v3(133.35,142.24) v5(133.35,141.5)
  L4_SIG2 w0.114: v5(133.35,141.5) 132.61,142.24 131.37,142.24 130.48,141.35 126.24,141.35 122.78,137.89 115.73,137.89 113.98,136.14 111.7,136.14 111.45,136.14 109.34,134.02 109.34,127.32 108.14,126.13 108.14,121.17 108.77,120.54 108.77,113.95 109.28,113.45 109.28,111.9 108.41,111.03 108.41,108.59 v8(109.35,107.65)
  BOTTOM w0.173: R443.1 v8(109.35,107.65)
AM57XX_GPMC_AD10: length 75.9
  TOP w0.173: R444.1 v8(110.36,107.65) 109.75,107.04 109.75,98.36 108.96,97.56 108.96,96.39 106.64,94.07 U1.J1 ; R840.1 v3(135.38,142.24)
  L3_SIG1 w0.109: v3(135.38,142.24) v5(135.38,141.5)
  L4_SIG2 w0.114: v5(135.38,141.5) 131.27,137.39 124.47,137.39 124.09,137.01 116.09,137.01 114.33,135.25 112.14,135.25 110.3,133.41 110.3,126.63 109.54,125.87 109.54,124.97 110.18,124.33 110.18,115.81 110.72,115.27 110.72,113.29 111.38,112.62 111.38,111.98 109.86,110.46 109.86,108.16 v8(110.36,107.65)
  BOTTOM w0.173: R444.1 v8(110.36,107.65)
AM57XX_GPMC_AD11: length 77.1
  TOP w0.173: U1.J2 107.03,92.01 107.03,93.88 109.31,96.16 109.31,97.42 110.11,98.22 110.11,106.38 v8(111.38,107.65) R445.1 ; R841.1 v3(137.41,142.24)
  L3_SIG1 w0.109: v3(137.41,142.24) v5(137.41,141.66)
  L4_SIG2 w0.114: v5(137.41,141.66) 132.82,137.06 124.56,137.06 124.22,136.72 116.21,136.72 114.45,134.96 113.14,134.96 111.42,133.23 111.42,129.27 111.96,128.73 111.96,123.21 111.58,122.83 111.58,115.26 112.39,114.45 112.39,111.43 111.91,110.95 111.91,109.07 111.38,108.54 v8(111.38,107.65)
  BOTTOM w0.173: R445.1 v8(111.38,107.65)
AM57XX_GPMC_AD12: length 80.6
  TOP w0.173: R842.1 v3(141.48,142.24) ; U1.H1 107.43,93.62 109.66,95.85 109.66,97.27 110.46,98.08 110.46,106.04 112.07,107.65 112.37,107.65 v8(112.39,107.68) R446.1
  L3_SIG1 w0.109: v3(141.48,142.24) v5(141.48,141.66)
  L4_SIG2 w0.114: v5(141.48,141.66) 141.04,141.22 137.97,141.22 133.45,136.7 124.62,136.7 124.34,136.43 116.33,136.43 114.48,134.57 113.41,134.57 111.91,133.08 111.91,129.29 112.39,128.8 112.39,122.95 112.04,122.59 112.04,115.39 113.93,113.51 113.93,109.85 113.02,108.94 113.02,108.27 112.42,107.68 v8(112.39,107.68)
  BOTTOM w0.173: R446.1 v8(112.39,107.68)
AM57XX_GPMC_AD13: length 94.6
  TOP w0.173: R843.1 v3(143.51,142.24) ; R447.1 v8(105.66,107.14) ; U1.J3 v4(107.03,91.21)
  L3_SIG1 w0.099: v4(107.03,91.21) 107.03,91.5 107.28,91.74 107.28,94.92
  L3_SIG1 w0.109: v3(143.51,142.24) 142.54,143.21 132.84,143.21 131.77,144.27 128.04,144.27 v5(127.36,143.59) ; v5(108.4,96.03) 107.28,94.92
  L4_SIG2 w0.114: v5(127.36,143.59) 126.97,143.97 119.74,143.97 113.38,137.61 111.01,137.61 111.01,137.61 110.97,137.61 110.96,137.6 110.77,137.6 107.88,134.71 107.88,129.6 106.68,128.41 106.68,127 105.79,126.11 105.79,124.91 106.39,124.31 106.39,115.96 105.79,115.36 105.79,112.79 105.23,112.23 105.23,111.86 106.07,111.02 106.07,109.96 106.55,109.48 106.55,108.14 106.24,107.83 106.24,107.72 v8(105.66,107.14) 107.08,107.14 109.83,104.39 109.83,103.1 110.2,102.73 110.2,98.21 108.4,96.41 v5(108.4,96.03)
  BOTTOM w0.173: R447.1 v8(105.66,107.14)
AM57XX_GPMC_AD14: length 87.4
  TOP w0.173: U1.H2 107.83,92.01 107.83,93.51 110.01,95.69 110.01,97.13 110.82,97.94 110.82,105.7 112.32,107.19 112.62,107.19 113.03,107.6 v8(113.48,107.6) 113.48,108.35 R448.1 ; R844.1 v3(145.54,142.24)
  L3_SIG1 w0.109: v3(145.54,142.24) v5(145.54,143.43)
  L4_SIG2 w0.114: v8(113.48,107.6) 113.95,107.6 114.94,108.58 114.94,113.77 113.16,115.54 113.16,129.72 112.9,129.97 112.9,133.4 113.44,133.94 114.26,133.94 116.44,136.12 124.59,136.12 124.87,136.4 133.68,136.4 138.1,140.82 141.38,140.82 142.04,141.48 142.04,142.39 143.08,143.43 v5(145.54,143.43)
  BOTTOM w0.173: v8(113.48,107.6) 113.41,107.67 R448.1
AM57XX_GPMC_AD15: length 96.2
  TOP w0.173: R449.1 v8(106.68,107.65) ; U1.H3 v4(107.83,91.21) ; R845.1 v3(147.57,142.24)
  L3_SIG1 w0.099: v4(107.83,91.21) 107.94,91.32 107.94,94.14
  L3_SIG1 w0.109: v5(109.57,96.43) 109.57,95.77 107.94,94.14 ; v3(147.57,142.24) 145.94,143.87 132.61,143.87 131.92,144.56 127.38,144.56 v5(126.35,143.53)
  L4_SIG2 w0.114: v5(109.57,96.43) 109.57,97.13 110.49,98.04 110.49,103 110.13,103.35 110.13,105.18 107.67,107.65 v8(106.68,107.65) 107.44,108.41 107.44,110.84 106.08,112.2 106.08,115.24 106.68,115.84 106.68,124.43 106.08,125.03 106.08,125.99 106.97,126.88 106.97,128.28 108.17,129.48 108.17,134.51 110.97,137.31 111.08,137.31 111.09,137.31 111.38,137.31 111.38,137.32 113.5,137.32 119.72,143.53 v5(126.35,143.53)
  BOTTOM w0.173: R449.1 v8(106.68,107.65)
AM57XX_HDMI_CLK+: length 84.1
  TOP w0.108: U1.AH16 84.25,80.42 71.11,67.28 71.11,66.69 71.22,66.58 71.44,66.58 71.55,66.47 71.55,66.25 71.44,66.15 71.22,66.15 71.11,66.04 71.11,65.82 71.22,65.71 71.44,65.71 71.55,65.61 71.55,65.39 71.44,65.28 71.22,65.28 71.11,65.17 71.11,45.53 69.47,43.9 69.47,27.83 67.54,25.91 60.43,25.91 57.13,22.61 56.44,22.61 56.01,22.18 56.01,21.72 56.28,21.44 L29.4
AM57XX_HDMI_CLK-: length 84.3
  TOP w0.108: U1.AG16 91.81,80.84 91.28,80.84 91.11,80.67 84.14,80.67 70.85,67.38 70.85,45.64 69.22,44 69.22,27.94 67.44,26.16 60.32,26.16 57.02,22.86 56.33,22.86 55.75,22.28 55.75,21.72 55.48,21.44 L29.1
AM57XX_HDMI_TX0+: length 85.2
  TOP w0.108: U1.AH17 84.68,79.62 72.45,67.38 72.45,66.75 72.56,66.64 72.79,66.64 72.9,66.53 72.9,66.31 72.79,66.21 72.56,66.21 72.45,66.1 72.45,65.88 72.56,65.78 72.79,65.78 72.9,65.67 72.9,65.45 72.79,65.34 72.56,65.34 72.45,65.24 72.45,45.5 70.52,43.56 70.52,30.93 70.64,30.81 71.4,30.81 71.68,30.53 71.68,30.14 71.4,29.87 70.64,29.87 70.52,29.74 70.52,29.56 70.64,29.44 71.4,29.44 71.68,29.16 71.68,28.77 71.4,28.5 70.64,28.5 70.52,28.37 70.52,27.65 67.89,25.02 60.94,25.02 58.56,22.64 58.56,21.71 58.82,21.44 L30.4
AM57XX_HDMI_TX0-: length 85.4
  TOP w0.108: U1.AG17 91.81,80.04 91.28,80.04 91.11,79.87 84.58,79.87 72.2,67.49 72.2,45.6 70.26,43.67 70.26,30.83 70.54,30.55 71.3,30.55 71.42,30.43 71.42,30.25 71.3,30.12 70.54,30.12 70.26,29.85 70.26,29.46 70.54,29.18 71.3,29.18 71.42,29.05 71.42,28.88 71.3,28.75 70.54,28.75 70.26,28.47 70.26,27.76 67.78,25.28 60.84,25.28 58.3,22.74 58.3,21.77 58.02,21.49 L30.1
AM57XX_HDMI_TX1+: length 85.4
  TOP w0.108: L31.4 71.27,21.57 70.99,21.84 70.99,22.89 71.69,23.59 71.69,25.55 73.09,26.95 73.09,31.8 72.82,32.08 72.19,32.08 72.06,32.2 72.06,32.38 72.19,32.51 72.82,32.51 73.09,32.78 73.09,33.17 72.82,33.45 72.19,33.45 72.06,33.57 72.06,33.75 72.19,33.88 72.82,33.88 73.09,34.16 73.09,34.54 72.82,34.82 72.19,34.82 72.06,34.95 72.06,35.13 72.19,35.25 72.82,35.25 73.09,35.53 73.09,35.92 72.82,36.19 72.19,36.19 72.06,36.32 72.06,36.5 72.19,36.62 72.82,36.62 73.09,36.9 73.09,37.29 72.82,37.56 72.19,37.56 72.06,37.69 72.06,37.87 72.19,37.99 72.82,37.99 73.09,38.27 73.09,38.66 72.82,38.93 72.19,38.93 72.06,39.06 72.06,39.24 72.19,39.37 72.82,39.37 73.09,39.64 73.09,40.03 72.82,40.31 72.19,40.31 72.06,40.43 72.06,40.61 72.19,40.74 72.82,40.74 73.09,41.01 73.09,41.4 72.82,41.68 72.19,41.68 72.06,41.8 72.06,41.98 72.19,42.11 72.82,42.11 73.09,42.38 73.09,42.77 72.82,43.05 72.19,43.05 72.06,43.18 72.06,43.35 72.19,43.48 72.82,43.48 73.81,44.47 73.81,65.29 73.92,65.4 74.14,65.4 74.24,65.5 74.24,65.72 74.14,65.83 73.92,65.83 73.81,65.94 73.81,66.15 73.92,66.26 74.14,66.26 74.24,66.37 74.24,66.58 74.14,66.69 73.92,66.69 73.81,66.8 73.81,67.51 85.12,78.81 U1.AH18
AM57XX_HDMI_TX1-: length 85.7
  TOP w0.108: U1.AG18 91.81,79.24 91.28,79.24 91.11,79.07 85.01,79.07 73.55,67.61 73.55,44.58 72.71,43.74 72.08,43.74 71.81,43.46 71.81,43.07 72.08,42.8 72.71,42.8 72.84,42.67 72.84,42.49 72.71,42.36 72.08,42.36 71.81,42.09 71.81,41.7 72.08,41.42 72.71,41.42 72.84,41.3 72.84,41.12 72.71,40.99 72.08,40.99 71.81,40.72 71.81,40.33 72.08,40.05 72.71,40.05 72.84,39.93 72.84,39.75 72.71,39.62 72.08,39.62 71.81,39.35 71.81,38.96 72.08,38.68 72.71,38.68 72.84,38.55 72.84,38.38 72.71,38.25 72.08,38.25 71.81,37.97 71.81,37.58 72.08,37.31 72.71,37.31 72.84,37.18 72.84,37 72.71,36.88 72.08,36.88 71.81,36.6 71.81,36.21 72.08,35.94 72.71,35.94 72.84,35.81 72.84,35.63 72.71,35.51 72.08,35.51 71.81,35.23 71.81,34.84 72.08,34.57 72.71,34.57 72.84,34.44 72.84,34.26 72.71,34.13 72.08,34.13 71.81,33.86 71.81,33.47 72.08,33.19 72.71,33.19 72.84,33.07 72.84,32.89 72.71,32.76 72.08,32.76 71.81,32.49 71.81,32.1 72.08,31.82 72.71,31.82 72.84,31.7 72.84,27.06 71.44,25.66 71.44,23.7 70.74,23 70.74,21.84 70.47,21.57 L31.1
AM57XX_HDMI_TX2+: length 83.6
  TOP w0.108: L32.4 73.81,21.57 73.53,21.84 73.53,25.15 73.96,25.58 73.96,31.79 74.09,31.91 74.81,31.91 75.08,32.19 75.08,32.58 74.81,32.85 74.09,32.85 73.96,32.98 73.96,33.16 74.09,33.29 74.81,33.29 75.08,33.56 75.08,33.95 74.81,34.23 74.09,34.23 73.96,34.35 73.96,34.53 74.09,34.66 74.81,34.66 75.08,34.93 75.08,35.32 74.81,35.6 74.09,35.6 73.96,35.72 73.96,35.9 74.09,36.03 74.81,36.03 75.08,36.3 75.08,36.69 74.81,36.97 74.09,36.97 73.96,37.1 73.96,37.27 74.09,37.4 74.81,37.4 75.08,37.68 75.08,38.07 74.81,38.34 74.09,38.34 73.96,38.47 73.96,38.65 74.09,38.77 74.81,38.77 75.08,39.05 75.08,39.44 74.81,39.71 74.09,39.71 73.96,39.84 73.96,40.02 74.09,40.14 74.81,40.14 75.08,40.42 75.08,40.81 74.81,41.08 74.09,41.08 73.96,41.21 73.96,41.39 74.09,41.52 74.81,41.52 75.08,41.79 75.08,42.18 74.81,42.46 74.09,42.46 73.96,42.58 73.96,42.76 74.09,42.89 74.78,42.89 75.24,43.35 75.24,67.7 85.55,78.02 86.02,78.02 86.13,77.91 86.13,77.76 86.23,77.65 86.45,77.65 86.56,77.76 86.56,77.91 86.67,78.02 86.88,78.02 86.99,77.91 86.99,77.76 87.1,77.65 87.31,77.65 87.42,77.76 87.42,77.91 87.53,78.02 87.74,78.02 87.85,77.91 87.85,77.76 87.96,77.65 88.18,77.65 88.28,77.76 88.28,77.91 88.39,78.02 U1.AH19
AM57XX_HDMI_TX2-: length 83.7
  TOP w0.108: L32.1 73.01,21.57 73.28,21.84 73.28,25.25 73.71,25.68 73.71,31.89 73.99,32.17 74.7,32.17 74.83,32.29 74.83,32.47 74.7,32.6 73.99,32.6 73.71,32.88 73.71,33.26 73.99,33.54 74.7,33.54 74.83,33.67 74.83,33.85 74.7,33.97 73.99,33.97 73.71,34.25 73.71,34.64 73.99,34.91 74.7,34.91 74.83,35.04 74.83,35.22 74.7,35.34 73.99,35.34 73.71,35.62 73.71,36.01 73.99,36.28 74.7,36.28 74.83,36.41 74.83,36.59 74.7,36.71 73.99,36.71 73.71,36.99 73.71,37.38 73.99,37.65 74.7,37.65 74.83,37.78 74.83,37.96 74.7,38.09 73.99,38.09 73.71,38.36 73.71,38.75 73.99,39.03 74.7,39.03 74.83,39.15 74.83,39.33 74.7,39.46 73.99,39.46 73.71,39.73 73.71,40.12 73.99,40.4 74.7,40.4 74.83,40.52 74.83,40.7 74.7,40.83 73.99,40.83 73.71,41.1 73.71,41.49 73.99,41.77 74.7,41.77 74.83,41.9 74.83,42.07 74.7,42.2 73.99,42.2 73.71,42.48 73.71,42.87 73.99,43.14 74.68,43.14 74.99,43.45 74.99,67.81 85.45,78.27 91.11,78.27 91.28,78.44 91.81,78.44 U1.AG19
AM57XX_I2C1_SCL: length 22.3
  TOP w0.173: U1.C20 v4(111.83,76.82) ; v3(126.62,72.7) 126.85,72.47 R384.1 R385.2 126.87,71.46 125.98,72.34 124.59,72.34
  L3_SIG1 w0.109: v3(126.62,72.7) 126.03,73.29 125.19,73.29 124.81,73.66 122.4,73.66 121.03,75.04 120.02,75.04 117.96,77.09 116.28,77.09 116,76.82 v4(111.83,76.82)
AM57XX_I2C1_SDA: length 22.9
  TOP w0.173: U1.C21 v4(111.83,76.02) ; 124.59,70.69 125.92,70.69 126.3,70.31 R387.2 R383.1 126.75,69.3 v3(126.62,69.42)
  L3_SIG1 w0.109: v3(126.62,69.42) 125.65,70.39 124.53,70.39 123.75,71.18 122.28,71.18 121.13,72.32 119.48,72.32 116,75.8 112.05,75.8 v4(111.83,76.02)
AM57XX_INDETHER_LED0_GRN: length 264.5
  TOP w0.173: R803.2 106.3,105.92 107.31,106.93 107.31,110.87 106.15,112.04 106.15,114.91 106.86,115.62 106.86,120.95 107.95,122.05 107.95,125.98 107.62,126.31 v3(107.62,130.61)
  L3_SIG1 w0.109: v5(4.19,83.13) 3.89,82.84 3.89,48.21 4.83,47.27 4.83,44.63 2.79,42.59 2.79,35.01 3.79,34.01 3.79,32.46 6.65,29.59 6.65,13.26 v8(9.55,10.37) ; v5(72.03,135.86) 77.83,135.86 79.18,137.22 84.75,137.22 86.74,139.22 103.02,139.22 108.03,134.21 108.03,131.65 107.62,131.24 v3(107.62,130.61)
  L4_SIG2 w0.114: v5(4.19,83.13) 4.19,92.33 5.74,93.88 16.31,93.88 18.95,91.24 31.29,91.24 31.62,91.57 37.59,91.57 41.91,95.89 41.91,96.9 40.31,98.5 40.31,105.13 41.76,106.58 57.2,106.58 58.24,107.62 60.73,107.62 60.74,107.61 63.87,107.61 65.79,109.52 65.79,112.78 66.9,113.89 66.9,129.08 68.4,130.59 68.4,132.23 v5(72.03,135.86)
  BOTTOM w0.173: R247.1 v8(9.55,10.37)
AM57XX_INDETHER_LED0_RED: length 196.9
  TOP w0.173: U1.B26 v4(112.63,72.02)
  L3_SIG1 w0.109: v8(9.58,3.64) 9.98,3.23 14.2,3.23 14.66,2.77 17.5,2.77 17.96,3.23 25.44,3.23 26.07,3.86 29.95,3.86 32.01,1.8 48.46,1.8 51.31,4.65 69.98,4.65 v5(86.87,21.54) ; v4(112.63,72.02) v5(113.03,71.77)
  L4_SIG2 w0.114: v5(113.03,71.77) 115.97,71.77 121.03,66.7 121.5,66.7 122.61,65.59 122.61,64.87 137.41,50.06 137.41,29.84 129.85,22.28 87.61,22.28 v5(86.87,21.54)
  BOTTOM w0.173: R241.2 v8(9.58,3.64)
AM57XX_INDETHER_LED0_YEL: length 249
  TOP w0.173: U1.D15 v4(111.03,80.82)
  L3_SIG1 w0.109: v5(128.02,78.69) 128.01,78.7 126.9,78.7 126.48,78.28 123.62,78.28 123.06,78.84 120.9,78.84 120.32,79.42 117.46,79.42 116.4,80.48 111.73,80.48 111.39,80.82 v4(111.03,80.82) ; v8(9.58,6.94) 10.59,5.92 17.64,5.92 18.66,6.94 28.24,6.94 31.39,3.78 41.35,3.78 42.21,4.65 48.44,4.65 49.43,5.64 65.92,5.64 68.32,8.05 68.32,8.05 69.88,9.61 v5(72.77,9.61)
  L4_SIG2 w0.114: v5(72.77,9.61) 102.91,9.61 104.25,8.26 106,8.26 106.13,8.13 113.37,8.13 113.68,7.83 133.58,7.83 139.47,13.72 144.45,13.72 153.49,22.76 153.49,63.55 149.86,67.18 149.1,67.18 145.92,70.36 145.92,70.99 140.59,76.33 140.59,77.47 138.72,79.34 130.17,79.34 129.47,78.64 128.07,78.64 v5(128.02,78.69)
  BOTTOM w0.173: R253.1 v8(9.58,6.94)
AM57XX_INDETHER_LED1_GRN: length 253.1
  TOP w0.173: U1.B17 112.64,79.21 114.93,79.21 117.12,77.02 118.69,77.02 120.22,75.49 v8(120.27,75.49)
  L3_SIG1 w0.109: v8(16.15,10.37) 17.91,12.12 21.05,12.12 24.99,8.18 28.42,8.18 31.14,5.46 37.84,5.46 38.85,6.46 52.94,6.46 v5(53.21,6.73)
  L4_SIG2 w0.114: v8(120.27,75.49) 123.53,78.76 127.21,78.76 128.52,80.07 132.31,80.07 133.86,81.62 136.02,81.62 136.99,80.64 139.45,80.64 140.65,79.44 141.92,79.44 144.78,76.58 144.78,75.31 155.83,64.26 155.83,56.13 155.58,55.88 155.58,47.12 155.83,46.86 155.83,27.56 156.84,26.54 156.84,22.78 139.52,5.46 130.9,5.46 130.65,5.71 128.78,5.71 128.53,5.46 117.35,5.46 116.33,6.48 103.75,6.48 101.87,8.37 74.81,8.37 72.62,6.17 53.77,6.17 v5(53.21,6.73)
  BOTTOM w0.173: R248.1 v8(16.15,10.37)
AM57XX_INDETHER_LED1_RED: length 237
  TOP w0.173: v3(134.24,75.44) 132.51,77.17 126.49,77.17 125.82,76.49 125.16,76.49 125.15,76.48 120.45,76.48 119.21,77.72 117.58,77.72 115.29,80.01 112.64,80.01 U1.B16
  L3_SIG1 w0.109: v5(74.42,12.34) 74.42,10.4 69.21,5.19 50.35,5.19 48.59,3.43 43,3.43 42.95,3.48 31.17,3.48 28.72,5.92 23.42,5.92 21.14,3.64 17.73,3.64 17.35,3.25 15.88,3.25 v5(15.49,3.64) ; v3(134.24,75.44) 136.14,75.44 v5(137.67,76.96)
  L4_SIG2 w0.114: v5(74.42,12.34) 74.79,12.71 95.37,12.71 97,11.08 113.22,11.08 114.95,9.35 116.59,9.35 117.4,10.16 131.19,10.16 134.61,13.58 134.61,15.54 141.24,22.17 145.94,22.17 149.73,25.96 149.73,63.88 143.51,70.1 143.51,71.12 v5(137.67,76.96)
  L10_SIG4 w0.109: v7(16.1,3.64) v5(15.49,3.64)
  BOTTOM w0.173: R243.2 v7(16.1,3.64)
AM57XX_INDETHER_LED1_YEL: length 223.6
  TOP w0.173: U1.A17 115.2,79.62 117.44,77.37 118.87,77.37 120.22,76.03 v3(125.35,76.03)
  L3_SIG1 w0.109: v5(16.71,6.93) 18.5,8.72 22.78,8.72 24.05,7.44 28.27,7.44 31.62,4.09 41.2,4.09 43.28,6.18 56.13,6.18 58.04,8.08 66.92,8.08 v5(73.15,14.31) ; v3(125.35,76.03) 125.65,75.72 127.28,75.72 v5(127.38,75.62)
  L4_SIG2 w0.114: v5(73.15,14.31) 101.6,14.31 102.21,13.7 105.01,13.7 106.13,12.58 115.05,12.58 115.44,12.19 116.3,12.19 117.54,13.43 128.85,13.43 139.93,24.51 144.12,24.51 146.53,26.92 146.53,64.19 140.65,70.07 140.65,71.44 135.79,76.3 131.84,76.3 131.17,75.62 v5(127.38,75.62)
  L10_SIG4 w0.109: v5(16.71,6.93) 16.71,6.94 v7(16.1,6.94)
  BOTTOM w0.173: R254.1 v7(16.1,6.94)
AM57XX_INDETHER_LED2_GRN: length 251.3
  TOP w0.173: U1.F16 v4(109.44,80.01)
  L3_SIG1 w0.109: v8(9.55,17.1) 9.86,16.79 17.53,16.79 20.22,14.1 20.57,14.1 25.25,9.42 28.78,9.42 30.43,7.77 50.75,7.77 52.81,9.83 56.26,9.83 57.76,11.33 62.89,11.33 v5(63.5,10.72) ; v5(127.08,78.26) 126.79,77.98 123.52,77.98 122.96,78.53 120.79,78.53 120.19,79.13 116.98,79.13 116.42,79.69 112.18,79.69 111.56,80.32 109.75,80.32 v4(109.44,80.01)
  L4_SIG2 w0.114: v5(127.08,78.26) 127.83,78.26 127.83,78.26 129.61,78.26 130.4,79.04 138.38,79.04 139.95,77.47 139.95,76.45 145.29,71.12 145.29,70.48 148.88,66.89 149.64,66.89 152.63,63.91 152.63,25.94 153.02,25.56 153.02,22.89 144.45,14.33 139.45,14.33 133.28,8.16 114.49,8.16 112.74,9.91 105.82,9.91 105.05,9.13 103.79,9.13 103.01,9.91 74.29,9.91 73.48,10.72 v5(63.5,10.72)
  BOTTOM w0.173: R590.1 v8(9.55,17.1)
AM57XX_INDETHER_LED2_RED: length 210.2
  TOP w0.173: v8(121.28,67.65) 119.38,67.65 115.9,71.12 115,71.12 113.31,72.82 112.63,72.82 U1.B25
  L3_SIG1 w0.109: v5(70.08,20.22) 70.08,15.94 63.57,9.42 52.83,9.42 50.77,7.37 30.23,7.37 28.47,9.12 25.15,9.12 20.62,13.64 18.62,13.64 16.69,15.58 13.31,15.58 11.54,13.8 v8(9.55,13.8)
  L4_SIG2 w0.114: v8(121.28,67.65) 129.64,67.65 140.03,57.25 140.03,30.82 128.49,19.28 121.76,19.28 120.86,20.18 117.9,20.18 117.39,19.68 112.21,19.68 112.07,19.82 100.41,19.82 100.27,19.68 94.48,19.68 93.93,19.13 91.99,19.13 90.91,20.22 v5(70.08,20.22)
  BOTTOM w0.173: R600.2 v8(9.55,13.8)
AM57XX_INDETHER_LED2_YEL: length 204.7
  TOP w0.173: v8(121.61,68.92) 121.61,68.95 121.44,69.12 119.55,69.12 116.54,72.14 115.54,72.14 113.67,74.02 U1.A24
  L3_SIG1 w0.109: v5(59.69,19.77) 54.66,14.73 24.51,14.73 18.28,20.96 13.9,20.96 13.49,20.55 v8(9.55,20.55)
  L4_SIG2 w0.114: v8(121.61,68.92) 122.5,68.03 130.27,68.03 140.57,57.73 140.57,30.95 128.16,18.54 116.21,18.54 115.57,19.18 113.1,19.18 112.46,18.54 111.34,18.54 110.87,19 107.19,19 106.21,18.03 100.67,18.03 100.27,18.42 97.85,18.42 97.83,18.41 64.44,18.41 63.66,19.19 60.27,19.19 v5(59.69,19.77)
  BOTTOM w0.173: v8(9.55,20.55) 10.26,20.55 R594.1
AM57XX_INDETHER_LED3_GRN: length 189.5
  TOP w0.173: v4(111.83,71.22) U1.C27
  L3_SIG1 w0.109: v5(30.99,13.46) 30.11,14.34 24.4,14.34 21.11,17.63 20.03,17.63 17.13,20.53 v8(16.15,20.53) ; v4(111.83,71.22) v5(112.23,70.97)
  L4_SIG2 w0.114: v5(30.99,13.46) 32.51,13.46 37.34,18.29 54.36,18.29 61.47,25.4 67.26,25.4 71.32,21.34 81.28,21.34 82.52,22.57 129.63,22.57 136.88,29.82 136.88,49.39 117.35,68.94 117.27,69.02 117.27,69.85 115.9,71.22 112.49,71.22 v5(112.23,70.97)
  BOTTOM w0.173: R593.1 16.28,20.66 v8(16.15,20.53)
AM57XX_INDETHER_LED3_RED: length 206.2
  TOP w0.173: v8(121.59,69.86) 120.96,69.86 120.76,70.06 120.74,70.06 120.69,70.11 119.58,70.11 116.81,72.88 116.35,72.88 113.61,75.62 U1.A22
  L3_SIG1 w0.109: v5(71.12,17.91) 71.12,13.52 66.62,9.02 53.24,9.02 51.26,7.04 30.05,7.04 28.37,8.71 25.07,8.71 20.52,13.26 16.82,13.26 v8(16.15,13.92)
  L4_SIG2 w0.114: v5(71.12,17.91) 86.86,17.91 87.5,17.27 88.24,17.27 88.84,17.86 91.5,17.86 92.1,17.27 102.5,17.27 102.97,17.74 106.33,17.74 106.38,17.78 106.85,17.78 107.75,18.68 110.74,18.68 111.25,18.16 112.49,18.16 112.95,18.62 115.71,18.62 116.09,18.24 121.59,18.24 122.68,17.15 124.51,17.15 124.8,17.44 127.48,17.44 141.1,31.06 141.1,58.39 131.16,68.33 123.12,68.33 v8(121.59,69.86)
  BOTTOM w0.173: R514.2 v8(16.15,13.92)
AM57XX_INDETHER_LED3_YEL: length 223.2
  TOP w0.173: v4(110.23,72.82) U1.E25
  L3_SIG1 w0.109: v5(139.77,66.49) 139.77,65.73 139.07,65.02 136.65,65.02 133.6,61.98 130.18,61.98 129.67,62.48 128.91,62.48 128.49,62.06 125.74,62.06 125.02,62.78 122.9,62.78 117.42,68.26 117.42,70.17 115.02,72.56 112.01,72.56 111.97,72.52 110.53,72.52 v4(110.23,72.82) ; v8(16.15,17.23) 18.58,17.23 23.94,11.86 v5(30.23,11.86)
  L4_SIG2 w0.114: v5(30.23,11.86) 33.1,11.86 38.13,16.89 55.4,16.89 56.82,18.31 61.19,18.31 63.64,15.86 65.18,15.86 65.45,16.13 73.28,16.13 73.93,15.48 102.48,15.48 102.94,15.02 105.83,15.02 106.7,15.89 109.2,15.89 110.47,14.62 112.6,14.62 112.88,14.91 112.88,15.2 113.85,16.17 116.93,16.17 118.01,15.08 120,15.08 120.55,15.63 124.99,15.63 125.48,15.14 126.87,15.14 127.61,15.88 128.83,15.88 138.99,26.04 143.27,26.04 144.53,27.3 144.53,32.51 143.68,33.36 143.68,63.33 140.52,66.49 v5(139.77,66.49)
  BOTTOM w0.173: R598.1 v8(16.15,17.23)
AM57XX_MCASP1_AXR4: length 18.6
  TOP w0.173: R673.2 v3(126.62,85.81) ; U1.E12 v4(110.23,84.01)
  L3_SIG1 w0.109: v3(126.62,85.81) 126.37,85.55 125.86,85.55 125.71,85.7 123.57,85.7 122.72,84.85 116.79,84.85 116.64,84.7 112.14,84.7 111.96,84.52 111.95,84.52 111.94,84.51 110.73,84.51 v4(110.23,84.01)
AM57XX_MCASP1_AXR6: length 17.4
  TOP w0.173: v3(125.53,83.29) 127.36,83.29 R675.2 ; U1.C12 v4(111.83,84.01)
  L3_SIG1 w0.109: v3(125.53,83.29) 124.89,83.93 123.34,83.93 122.78,83.36 122.66,83.36 122.36,83.07 121.61,83.07 121.36,82.82 120.35,82.82 119.02,84.15 112.31,84.15 112.18,84.01 v4(111.83,84.01)
AM57XX_MCASP1_AXR7: length 18.6
  TOP w0.173: U1.D12 v4(111.03,84.01) ; R676.2 v3(126.64,84.54)
  L3_SIG1 w0.099: v4(111.03,84.01) 111.33,84.31 112.16,84.31
  L3_SIG1 w0.109: 112.16,84.31 112.28,84.43 116.79,84.43 116.9,84.54 119.12,84.54 120.47,83.19 121.28,83.19 121.46,83.36 122.2,83.36 122.48,83.64 122.55,83.64 123.9,84.99 125.38,84.99 125.5,84.87 126.31,84.87 v3(126.64,84.54)
AM57XX_MMC1_CLK: length 33.3
  TOP w0.173: 78.87,105.11 v3(79.63,105.11) ; U1.W6 v4(98.24,88.81)
  L3_SIG1 w0.109: v5(98.02,98.61) 97.54,99.09 97.54,99.27 95.53,101.27 95.4,101.27 93.54,103.13 81.61,103.13 v3(79.63,105.11) ; v4(98.24,88.81) 98.23,88.81 97.84,89.06 v5(97.84,89.06)
  L10_SIG4 w0.109: v5(98.02,98.61) 98.37,98.25 98.37,94.47 97.97,94.06 97.97,93.25 97.79,93.07 97.79,91.29 98.25,90.84 98.25,89.47 v5(97.84,89.06)
AM57XX_MMC1_CMD: length 32.3
  TOP w0.173: 78.87,104.09 v3(79.63,104.09) ; U1.Y6 v4(97.44,88.81)
  L3_SIG1 w0.109: v3(79.63,104.09) 80.06,104.09 81.38,102.77 93.37,102.77 97.03,99.12 v5(97.03,98.42) ; v5(97.04,89.06) v4(97.44,88.81)
  L10_SIG4 w0.109: v5(97.03,98.42) 97.03,97.26 95.81,96.04 95.81,93.1 96.52,92.39 96.52,89.58 v5(97.04,89.06)
AM57XX_MMC1_DAT0: length 27.7
  TOP w0.173: 78.87,101.05 v3(79.63,101.05) ; U1.AA6 v4(96.64,88.81)
  L3_SIG1 w0.109: v5(95.5,97.11) 95.3,97.11 93.8,98.6 84.79,98.6 82.34,101.05 v3(79.63,101.05) ; v4(96.64,88.81) 96.64,88.82 v5(96.24,89.06)
  L10_SIG4 w0.109: v5(95.5,97.11) 95.58,97.03 95.58,93.02 96.24,92.36 v5(96.24,89.06)
AM57XX_MMC1_DAT1: length 27.7
  TOP w0.173: 78.87,102.06 v3(79.63,102.06) ; U1.Y4 v4(97.44,90.41)
  L3_SIG1 w0.109: v4(97.44,90.41) 97.03,90.82 97.03,92.57 96.85,92.75 96.85,94.98 97.21,95.33 97.21,96.12 96.4,96.93 96.4,97.31 93.22,100.48 83.92,100.48 82.93,101.47 80.22,101.47 v3(79.63,102.06)
AM57XX_MMC1_DAT2: length 25.9
  TOP w0.173: 78.87,100.03 v3(79.63,100.03) ; U1.AA5 v4(96.64,89.61)
  L3_SIG1 w0.102: v4(96.64,89.61) 96.14,90.11 96.14,91.93 96.14,91.93
  L3_SIG1 w0.109: v3(79.63,100.03) 80.26,100.03 82.04,98.25 93.62,98.25 96.14,95.74 96.14,91.93
AM57XX_MMC1_DAT3: length 27.9
  TOP w0.173: 78.87,103.08 v3(79.63,103.08) ; U1.Y3 v4(97.44,91.21)
  L3_SIG1 w0.109: v4(97.44,91.21) 97.44,92.74 97.69,92.99 97.69,94.59 97.92,94.82 97.92,95.89 96.74,97.07 96.74,97.45 92.11,102.07 82.04,102.07 81.81,101.84 80.86,101.84 v3(79.63,103.08)
AM57XX_MMC1_SDCD: length 35.8
  TOP w0.173: 78.87,99.01 v3(78.38,98.53) ; v3(75.44,92.92) v3(75.44,98.51) ; U1.W7 v4(98.24,88.01)
  L3_SIG1 w0.099: 94.87,87.72 95.16,87.72 95.28,87.84 95.58,87.84 95.61,87.83 95.71,87.72 95.96,87.72 96.07,87.84 96.08,87.84 96.38,87.84 96.41,87.83 96.51,87.72 96.76,87.72 96.88,87.84 96.88,87.84 97.18,87.84 97.21,87.83 97.31,87.72 97.56,87.72 97.85,88.01 v4(98.24,88.01)
  L3_SIG1 w0.109: v3(78.38,98.53) 78.36,98.51 v3(75.44,98.51) ; 94.87,87.72 94.54,88.05 94.54,88.93 94.35,89.12 93.61,89.12 92.48,90.25 91.76,90.25 91.09,90.91 90.07,90.91 89.03,91.95 85.83,91.95 85.22,92.56 81.03,92.56 80.87,92.41 75.95,92.41 v3(75.44,92.92)
AM57XX_MMC1_SDWP: length 40.3
  TOP w0.173: v8(87.76,107.52) 87.12,106.89 R644.1 J44.1 ; U1.Y9 v4(97.44,86.41)
  L3_SIG1 w0.109: v4(97.44,86.41) v5(97.04,86.66)
  L4_SIG2 w0.114: v5(97.04,86.66) 97.45,86.25 101.41,86.25 101.73,86.57 101.73,91.82 100.13,93.42 100.13,98.25 99.09,99.29 99.09,101.53 94.91,105.7 94.55,105.7 94.08,106.17 92.74,106.17 92.18,106.73 88.55,106.73 v8(87.76,107.52)
AM57XX_OSC0_IN: length 20.2
  TOP w0.173: Y1.3 74.71,81.27 75.31,81.87 C2.1 R4.2 v3(78.36,81.87) ; U1.AE15 v4(93.44,80.82)
  L3_SIG1 w0.109: v3(78.36,81.87) 78.43,81.94 82.04,81.94 82.6,81.38 87.35,81.38 87.71,81.03 91.62,81.03 91.75,81.16 92.78,81.16 92.86,81.08 93.17,81.08 v4(93.44,80.82)
AM57XX_OSC0_OUT: length 16
  TOP w0.173: U1.AD15 v4(94.24,80.82) ; v3(80.25,82.39) R5.1
  L3_SIG1 w0.109: v4(94.24,80.82) 93.67,81.38 91.56,81.38 91.44,81.25 87.96,81.25 87.38,81.84 82.78,81.84 82.23,82.39 v3(80.25,82.39)
AM57XX_PCIE_PERN0: length 90.3
  TOP w0.108: U1.AG13 91.87,83.18 91.23,83.18 91.12,83.07 90.63,83.07 88.61,85.09 84.11,85.09 78.64,79.62 72.53,79.62 71.52,78.61 66.02,78.61 64.96,79.67 59.88,79.67 59.05,78.85 59.05,77.8 v4(58.88,77.62) ; v4(48.2,39.19) 48.02,39.02 48.02,36.56 48.39,36.19 J52.A17
  L3_SIG1 w0.083: v4(48.2,39.19) 48.06,39.06 48.06,38.25 48.58,37.73 49.16,37.73 52.45,41.02 52.45,50.04 51.18,51.31 51.18,56.9 54.1,59.82 54.1,63.37 59.03,68.3 59.03,77.47 v4(58.88,77.62)
AM57XX_PCIE_PERN1: length 85.4
  TOP w0.108: J52.A22 53.39,36.19 53.02,36.56 53.02,37.19 v4(53.2,37.37) ; v4(92.66,83.99) U1.AF12
  L3_SIG1 w0.083: v4(92.66,83.99) 91.65,83.99 91.11,84.53 90.98,84.53 90.87,84.42 90.74,84.42 90.64,84.52 90.64,84.66 90.74,84.76 90.74,84.9 90.18,85.46 90.04,85.46 89.94,85.36 89.8,85.36 89.7,85.45 89.7,85.59 89.81,85.7 89.81,85.83 89.41,86.23 89.23,86.23 89.13,86.14 89.13,85.97 89.03,85.88 88.9,85.88 88.8,85.97 88.8,86.14 88.7,86.23 84.45,86.23 84.2,86.49 81.53,86.49 81.11,86.91 78.65,86.91 76.33,84.58 68.33,84.58 64.64,80.9 64.64,70.23 61.1,66.68 60.08,66.68 58.04,64.64 58.04,61.09 58.8,60.32 58.8,57.15 58.38,56.73 58.38,53.81 57.53,52.96 57.53,43.05 53.04,38.57 53.04,37.52 v4(53.2,37.37)
AM57XX_PCIE_PERP0: length 90.2
  TOP w0.108: v4(59.49,77.62) 59.31,77.8 59.31,78.74 59.98,79.41 64.86,79.41 65.91,78.36 71.63,78.36 72.64,79.37 78.75,79.37 84.21,84.84 88.5,84.84 89.19,84.15 89.19,83.97 89.14,83.91 89.14,83.76 89.29,83.61 89.44,83.61 89.5,83.66 89.67,83.66 90.52,82.81 U1.AH13 ; J52.A16 47.39,36.22 47.76,36.59 47.76,39.02 v4(47.59,39.19)
  L3_SIG1 w0.083: v4(59.49,77.62) 59.33,77.47 59.33,68.17 54.41,63.25 54.41,59.69 51.49,56.77 51.49,51.43 52.76,50.16 52.76,40.89 49.29,37.43 48.45,37.43 47.75,38.13 47.75,39.03 v4(47.59,39.19)
AM57XX_PCIE_PERP1: length 85.4
  TOP w0.108: U1.AE12 93.76,83.62 v4(93.32,84.06) ; J52.A21 52.39,36.22 52.76,36.59 52.76,37.19 v4(52.59,37.37)
  L3_SIG1 w0.083: v4(93.32,84.06) 93.02,84.06 92.79,84.29 91.78,84.29 89.53,86.54 84.58,86.54 84.33,86.79 81.66,86.79 81.24,87.21 78.53,87.21 76.2,84.89 68.2,84.89 64.34,81.03 64.34,70.36 60.97,66.99 59.95,66.99 57.73,64.77 57.73,60.96 58.5,60.2 58.5,57.28 58.08,56.86 58.08,53.93 57.23,53.08 57.23,43.18 52.74,38.69 52.74,37.52 v4(52.59,37.37)
AM57XX_PCIE_PETN0: length 99.6
  TOP w0.108: U1.AG14 91.81,82.44 91.23,82.44 91.06,82.27 89.42,82.27 88.02,83.67 84.27,83.67 79.24,78.64 72.86,78.64 71.52,77.29 71.52,71.75 62.99,63.23 62.99,61.04 v4(62.81,60.86) ; C477.1 46.1,23.49 46.1,21.74 v4(46.28,21.57)
  L3_SIG1 w0.083: v4(62.81,60.86) 62.99,61.04 62.99,61.72 62.86,61.85 62.1,61.85 61.9,61.65 61.9,58.88 63.63,57.15 63.63,35.31 54.1,25.78 49.76,25.78 46.13,22.15 46.13,21.72 v4(46.28,21.57)
AM57XX_PCIE_PETN1: length 122.8
  TOP w0.108: U1.AC11 v4(95.04,84.81) ; C581.1 51.05,23.49 51.05,20.78 v4(51.23,20.6)
  L3_SIG1 w0.083: v4(51.23,20.6) 51.08,20.75 51.08,21.36 50.67,21.77 49.12,21.77 48.31,20.95 42.72,20.95 39.93,23.75 39.93,34.93 42.47,37.47 42.47,53.47 57.96,68.96 57.96,78.87 66.04,86.94 75.56,86.94 76.71,88.09 82.42,88.09 83.11,87.4 89.49,87.4 92.38,84.51 94.73,84.51 v4(95.04,84.81)
AM57XX_PCIE_PETP0: length 99.6
  TOP w0.108: C478.1 45.85,23.49 45.85,21.74 v4(45.67,21.57) ; U1.AH14 89.31,82.02 89.14,82.19 88.96,82.19 88.85,82.09 88.68,82.09 88.55,82.22 88.55,82.39 88.65,82.5 88.65,82.68 87.91,83.41 84.38,83.41 79.35,78.38 72.97,78.38 71.77,77.18 71.77,71.64 63.25,63.12 63.25,61.04 v4(63.42,60.86)
  L3_SIG1 w0.083: v4(63.42,60.86) 63.3,60.98 63.3,61.85 62.99,62.15 61.98,62.15 61.59,61.77 61.59,58.75 63.32,57.02 63.32,35.43 53.98,26.09 49.63,26.09 45.82,22.28 45.82,21.72 v4(45.67,21.57)
AM57XX_PCIE_PETP1: length 122.7
  TOP w0.108: v4(50.62,20.6) 50.8,20.78 50.8,23.49 C582.1 ; U1.AD11 v4(94.24,84.81)
  L3_SIG1 w0.083: v4(94.24,84.81) 93.61,84.81 93.51,84.91 93.51,85.02 93.42,85.12 93.28,85.12 93.18,85.02 93.18,84.91 93.09,84.81 92.51,84.81 89.62,87.71 83.24,87.71 82.55,88.39 76.58,88.39 75.44,87.25 65.91,87.25 57.66,78.99 57.66,69.09 42.16,53.59 42.16,37.59 39.62,35.05 39.62,23.62 42.6,20.65 48.44,20.65 49.25,21.46 50.55,21.46 50.77,21.23 50.77,20.75 v4(50.62,20.6)
AM57XX_PCIE_REF_CLKN: length 19.2
  TOP w0.108: U1.AH15 83.43,81.21 83.24,81.02 81.6,79.38 81.6,79.23 81.62,79.21 81.62,79.06 81.46,78.9 81.31,78.9 81.29,78.92 81.14,78.92 80.99,78.77 80.99,78.62 81.01,78.6 81.01,78.45 80.85,78.29 80.7,78.29 80.68,78.31 80.53,78.31 80.37,78.16 80.37,78.01 80.4,77.99 80.4,77.84 80.24,77.68 80.09,77.68 80.07,77.7 79.92,77.7 79.64,77.42 79.38,77.42 R581.1 78.23,77.04 75.56,77.04 C438.2
AM57XX_PCIE_REF_CLKP: length 19.2
  TOP w0.108: U1.AG15 91.81,81.64 91.28,81.64 91.11,81.47 83.32,81.47 79.53,77.68 R581.2 78.23,77.3 75.56,77.3 C439.2
AM57XX_PORZN: length 34.6
  TOP w0.173: v3(137.16,70.39) 138.15,70.39 R6.2 ; U1.F22 v4(109.43,75.22)
  L3_SIG1 w0.109: v3(137.16,70.39) 136.56,70.39 136.53,70.36 v5(136.4,70.36) ; v4(109.43,75.22) v5(109.83,74.97)
  L4_SIG2 w0.114: v5(109.83,74.97) 109.83,74.99 110.62,75.77 112.02,75.77 112.27,76.02 115.17,76.02 116.24,74.96 116.24,74.54 119.5,71.28 128.78,71.28 130.97,73.46 133.93,73.46 136.4,70.99 v5(136.4,70.36)
AM57XX_PR1_UART0_RXD: length 109.4
  TOP w0.173: R851.1 v3(142.49,142.24) ; U1.F2 109.43,92.01 109.43,93.41 111.15,95.13 111.15,96.63 112.98,98.46 112.98,102.13 v3(113.54,102.69) R575.2
  L3_SIG1 w0.109: v5(114.15,102.59) 114.05,102.69 v3(113.54,102.69) ; v3(142.49,142.24) v5(142.49,141.66)
  L4_SIG2 w0.114: v5(142.49,141.66) 142.49,141.33 141.59,140.42 139.84,140.42 138.05,138.63 138.05,136.03 136.39,134.37 136.39,131.72 136.78,131.33 136.78,122.17 135.66,121.05 135.66,113.9 137.09,112.46 137.09,110.3 137.67,109.73 137.67,98.54 138.87,97.34 138.87,96.2 138.37,95.7 138.37,93.48 135.44,90.55 131.84,90.55 128.41,87.12 127.83,87.12 127.42,86.71 125.94,86.71 125.44,86.21 120.93,86.21 118.72,88.43 118.72,98.51 114.63,102.59 v5(114.15,102.59)
AM57XX_PR1_UART0_TXD: length 302.1
  TOP w0.173: R852.1 v3(144.53,142.24) ; U1.F3 v4(109.43,91.21) ; R199.2 v8(50.93,75.92)
  L3_SIG1 w0.099: 109.43,94.17 v4(109.43,91.21)
  L3_SIG1 w0.109: v3(144.53,142.24) v5(144.53,141.63) ; 109.43,94.17 111.25,95.99 111.25,96.61 111.46,96.82 111.46,98.37 112.04,98.96 112.04,100.23 112.56,100.75 v5(113.27,100.75)
  L4_SIG2 w0.114: v5(113.27,100.75) 114.21,100.75 114.86,100.1 116.18,100.1 117.83,98.45 117.83,86.26 118.62,85.47 126.6,85.47 127.96,86.83 128.53,86.83 131.94,90.25 135.55,90.25 139.25,93.95 139.25,95.66 140.01,96.42 140.01,96.79 137.96,98.84 137.96,105.03 141.94,109.01 145.65,109.01 146.39,109.75 146.39,117.72 147.03,118.36 147.03,122.18 144.15,125.06 144.15,135.64 141.76,138.02 141.76,140.08 143.31,141.63 v5(144.53,141.63) 144.53,141.68 148.13,145.29 151.41,145.29 152.37,146.25 152.37,150.01 151.62,150.76 101.39,150.76 100.33,149.7 100.33,144.35 v8(100.61,144.07) ; v8(99.34,137.65) 96.26,134.57 85.45,134.57 84.11,133.24 84.11,116.14 83.74,115.77 83.74,115.77 79.91,111.93 79.91,110.04 80.59,109.35 80.59,101.86 77.29,98.56 64.39,98.56 61.85,96.01 61.85,88.14 55.56,81.85 55.56,81.85 55.37,81.66 48.89,81.66 47.42,80.18 47.42,77.73 48.44,76.71 50.14,76.71 v8(50.93,75.92)
  L10_SIG4 w0.109: v5(113.27,100.75) 112.53,100.75 112.14,100.36 v7(112.14,100.31)
  BOTTOM w0.173: v8(99.34,137.65) 100.28,138.59 100.28,141.83 100.61,142.16 v8(100.61,144.07) ; v7(112.14,100.31) 112.14,99.52 112.39,99.27 R574.2
AM57XX_PR2_PROFI_TXEN: length 112.5
  TOP w0.173: U1.U3 v4(99.84,91.21)
  L3_SIG1 w0.109: v4(99.84,91.21) 100,91.38 100,92 99.77,92.23 99.77,96.14 99.92,96.29 100.02,96.29 100.29,96.55 100.29,98.29 101.93,99.93 101.93,100.66 v5(101.78,100.81)
  L4_SIG2 w0.114: J21.49 148.15,145.82 138.85,145.82 138.64,146.03 124.11,146.03 123.8,145.72 116.76,145.72 114.37,143.33 110.91,143.33 109.07,141.49 109.07,139.22 107.3,137.45 105.76,137.45 102.64,134.33 102.64,130.44 103.45,129.62 103.45,128.34 103.74,128.05 103.74,126.1 102.58,124.93 102.58,120.61 103.34,119.84 103.34,118.68 102.26,117.59 102.26,111.2 100.47,109.41 100.47,107.4 102.54,105.33 103.36,105.33 104.25,104.44 106.02,104.44 106.51,103.96 106.51,102.56 107.52,101.54 107.52,99.88 107.27,99.62 104.66,99.62 103.47,100.81 v5(101.78,100.81)
AM57XX_PRU1ETH1_TXCLK: length 8.2
  TOP w0.173: U1.C1 111.43,93.23 112.86,94.66 112.86,96.48 114.71,98.32 114.71,98.48 114.68,98.51 R123.2
AM57XX_PRU1ETH1_TXD2: length 14.4
  TOP w0.173: R127.2 116.08,98.38 v3(115.44,97.74) ; U1.E6 v4(110.23,88.81)
  L3_SIG1 w0.099: 111.33,92.99 111.33,91.09 111.16,90.92 110.33,90.92 109.94,90.54 109.94,89.49 110.23,89.2 v4(110.23,88.81)
  L3_SIG1 w0.109: v3(115.44,97.74) 114.8,97.1 114.37,97.1 112.57,95.3 112.57,94.24 111.33,92.99
AM57XX_PRU1ETH1_TXD3: length 17.9
  TOP w0.173: U1.F5 v4(109.43,89.61) ; v3(117.47,98.28) R128.2
  L3_SIG1 w0.099: 109.94,94 109.94,90.82 109.74,90.62 109.74,89.92 v4(109.43,89.61)
  L3_SIG1 w0.109: 109.94,94 111.77,95.83 111.77,96.22 112.73,97.18 112.73,97.89 112.65,97.97 112.65,98.32 114.1,99.78 116.08,99.78 117.47,98.38 v3(117.47,98.28)
AM57XX_PRU1ETH1_TXEN: length 16.8
  TOP w0.173: v3(115.57,96.73) 116.53,95.77 117.8,95.77 118.49,96.46 R124.2 ; U1.E4 v4(110.23,90.41)
  L3_SIG1 w0.099: 111.54,92.7 111.54,90.97 110.98,90.41 v4(110.23,90.41)
  L3_SIG1 w0.109: v3(115.57,96.73) 114.35,96.73 113.03,95.41 113.03,94.19 111.54,92.7
AM57XX_PRU1ETH_MDCLK: length 189.4
  TOP w0.173: v3(26.03,128.78) 27.06,127.75 27.06,124.12 26.67,123.73 26.67,119.69 27.53,118.83 v8(27.94,118.83) ; R140.2 v8(31.12,94.32) ; U1.D3 v4(111.03,91.21)
  L3_SIG1 w0.099: v4(111.03,91.21) 111.03,93.59
  L3_SIG1 w0.109: v3(26.03,128.78) 26.29,129.03 33.91,129.03 34.72,128.22 37.01,128.22 38.44,129.65 42.75,129.65 47.14,134.03 61.59,134.03 62.43,134.87 103.87,134.87 105.46,133.28 105.46,131.27 112.62,124.11 112.62,122.64 123.8,111.46 123.8,107.78 125.98,105.59 125.98,103.1 v5(126.31,102.77) ; 111.03,93.59 v5(111.76,94.32)
  L9_SIG3 w0.114: v8(27.94,118.83) 26.88,118.83 26.29,118.24 26.29,109.46 28.24,107.51 28.24,103.33 29.63,101.94 29.63,99.5 31.12,98.02 v8(31.12,94.32)
  L10_SIG4 w0.109: v5(111.76,94.32) 112.22,93.86 112.22,93.01 113.51,91.72 114.12,91.72 115.01,92.61 116.23,92.61 120.93,97.31 122.45,97.31 124.64,99.5 124.64,101.1 v5(126.31,102.77)
  BOTTOM w0.173: v8(27.94,118.83) 27.41,118.83 R96.2
AM57XX_PRU1ETH_MDDATA: length 239.9
  TOP w0.173: v8(30.1,94.32) R142.2 ; U1.F6 v4(109.43,88.81)
  L3_SIG1 w0.109: v4(109.43,88.81) 109.43,88.82 v5(109.83,89.06) ; v5(126.85,103.45) 126.85,105.52 124.31,108.06 124.31,111.71 113,123.02 113,124.29 106.81,130.48 106.81,133.53 103.15,137.19 91.51,137.19 90.83,136.5 79.53,136.5 78.23,135.2 61.9,135.2 61.08,136.02 48.72,136.02 42.64,129.94 38.27,129.94 36.91,128.57 34.9,128.57 34.06,129.41 25.25,129.41 20.89,125.06 20.89,124.13 20.59,123.83 17.88,123.83 17.44,123.38 17.44,121.05 17.99,120.49 17.99,114.76 15.56,112.33 15.56,102.3 16.26,101.6 16.26,93.47 18.67,91.06 27.56,91.06 29.24,92.74 29.24,93.45 v8(30.1,94.32)
  L9_SIG3 w0.114: v8(27.18,119.84) 25.76,118.42 25.76,109.58 27.43,107.91 27.43,102.61 27.46,102.58 27.46,102.56 29.18,100.84 29.18,99.21 30.1,98.3 v8(30.1,94.32)
  L10_SIG4 w0.109: v5(126.85,103.45) 126.85,102.29 126.64,102.09 126.29,102.09 125.07,100.87 125.07,99.45 122.63,97.01 121.29,97.01 114.15,89.87 111.33,89.87 110.53,89.06 v5(109.83,89.06)
  BOTTOM w0.173: R98.2 v8(27.18,119.84)
AM57XX_PRU2ETH0_COL: length 188
  TOP w0.173: v3(136.91,67.82) 134.75,69.98 134.75,75.82 131.93,78.64 v3(129.92,78.64) ; R178.2 123.29,80.07 v3(122.81,80.07) ; U1.F15 v4(109.43,80.82)
  L3_SIG1 w0.109: v3(136.91,67.82) 137.29,67.44 156.71,67.44 160.02,70.75 170.18,70.75 176.01,76.58 178.29,76.58 178.59,76.88 178.59,78.01 178.91,78.33 181.98,78.33 183.68,80.02 183.68,84.49 185.67,86.49 185.67,94.11 186.56,95 186.56,96.77 180.39,102.95 167.71,102.95 163.54,107.13 163.54,107.19 161.85,108.87 159.5,108.87 156.49,111.88 156.49,118.11 157.23,118.85 157.23,131.72 155.9,133.05 155.9,138.73 158.14,140.97 161.67,140.97 162.76,142.06 v5(162.76,142.11) ; v3(129.92,78.64) 128.95,78.64 127.58,80.02 126.95,80.02 125.89,78.96 124.44,78.96 123.62,79.78 123.09,79.78 v3(122.81,80.07) 121.29,80.07 120.94,80.42 117.94,80.42 117.2,81.16 112.21,81.16 112.04,81.32 110.82,81.32 110.81,81.31 110.28,81.31 109.79,80.82 v4(109.43,80.82)
  L10_SIG4 w0.109: v7(158.12,143) 159.48,143 159.59,142.9 160.96,142.9 161.06,143 161.87,143 v5(162.76,142.11)
  BOTTOM w0.173: R930.1 v7(158.12,143)
AM57XX_PRU2ETH0_CRS: length 434
  TOP w0.173: U1.B18 112.23,78.81 112.63,78.42 114.86,78.42 117.31,75.97 118.17,75.97 120.14,74 120.25,74 v3(120.27,73.98) ; R177.2 v8(38.61,79.96)
  L3_SIG1 w0.109: v5(161.01,141.66) 158.42,141.66 155.58,138.81 155.58,132.97 156.34,132.2 156.34,129.21 155.83,128.69 155.83,128.27 156.21,127.88 156.21,119.94 156.69,119.46 156.69,119.04 156.21,118.55 156.21,111.76 159.39,108.58 161.73,108.58 163.25,107.07 163.25,107.01 167.6,102.66 180.17,102.66 186.18,96.65 186.18,95.12 185.32,94.25 185.32,86.61 183.39,84.68 183.39,80.14 181.86,78.61 178.69,78.61 177.17,77.09 176.02,77.09 170.18,71.25 159.89,71.25 159.19,70.54 147.42,70.54 146.98,70.1 v5(141.35,70.1) ; v3(120.27,73.98) v5(119.68,73.98)
  L4_SIG2 w0.114: v8(38.61,79.96) 37.33,78.69 37.33,61.22 38.01,60.54 38.01,53.53 34.42,49.94 34.42,42.29 33.9,41.78 33.9,39.63 34.32,39.22 34.32,30.25 27.58,23.52 27.58,22.6 26.59,21.6 26.59,20.51 26.3,20.22 26.3,10.55 28.94,7.91 49.85,7.91 57.5,15.56 60.11,15.56 61.23,14.44 72.4,14.44 72.97,13.87 99.28,13.87 100.33,12.83 101.85,12.83 102.23,13.2 105.1,13.2 106.01,12.29 114.93,12.29 115.32,11.89 116.42,11.89 117.66,13.14 129.34,13.14 140.28,24.08 144.4,24.08 147.09,26.77 147.09,64.05 141.35,69.79 v5(141.35,70.1) 141.35,71.25 135.86,76.74 131.65,76.74 130.97,76.06 127.2,76.06 125.04,73.9 119.76,73.9 v5(119.68,73.98)
  L10_SIG4 w0.109: v7(155.07,143) 156.72,143 158.06,141.66 v5(161.01,141.66)
  BOTTOM w0.173: R929.1 v7(155.07,143)
AM57XX_PRU2ETH0_MRCLK: length 258.1
  TOP w0.173: U1.A13 113.92,82.81 114.69,82.04 116.92,82.04 117.94,81.03 127.17,81.03 v3(127.69,81.54) ; R165.2 v8(38.61,77.68)
  L3_SIG1 w0.109: v3(127.69,81.54) 127.3,81.15 v5(127.24,81.15)
  L10_SIG4 w0.109: v8(38.61,77.68) 38.61,73.11 30.72,65.22 30.72,62.14 34.21,58.66 34.21,55.88 38.86,51.23 38.86,36.58 41.91,33.53 43.18,33.53 51.56,25.15 55.88,25.15 59.71,21.32 62.2,21.32 64.92,18.6 67.95,18.6 71.44,15.11 91.59,15.11 92.2,15.73 103.56,15.73 106.83,19 107.32,19 107.45,18.87 107.45,18.44 107.57,18.31 107.75,18.31 107.88,18.44 107.88,18.87 108.01,19 108.19,19 108.32,18.87 108.32,18.44 108.45,18.31 108.63,18.31 108.76,18.44 108.76,18.87 108.88,19 111.25,19 111.66,18.59 115.16,18.59 122.33,25.76 122.33,30.24 122.44,30.35 123.16,30.35 123.27,30.46 123.27,30.68 123.16,30.79 122.44,30.79 122.33,30.9 122.33,31.12 122.44,31.23 123.41,31.23 123.52,31.34 123.52,31.55 123.41,31.66 122.44,31.66 122.33,31.77 122.33,32.18 122.44,32.29 123.49,32.29 123.6,32.39 123.6,32.61 123.49,32.72 122.44,32.72 122.33,32.83 122.33,33.05 122.44,33.16 123.49,33.16 123.6,33.27 123.6,33.49 123.49,33.6 122.44,33.6 122.33,33.71 122.33,33.92 122.44,34.03 123.49,34.03 123.6,34.14 123.6,34.36 123.49,34.47 122.44,34.47 122.33,34.58 122.33,34.8 122.44,34.91 123.49,34.91 123.6,35.02 123.6,35.23 123.49,35.34 122.44,35.34 122.33,35.45 122.33,35.67 122.44,35.78 123.49,35.78 123.6,35.89 123.6,36.11 123.49,36.22 122.44,36.22 122.33,36.33 122.33,36.54 122.44,36.65 123.49,36.65 123.6,36.76 123.6,36.98 123.49,37.09 122.44,37.09 122.33,37.2 122.33,37.42 122.44,37.53 123.49,37.53 123.6,37.64 123.6,37.86 123.49,37.96 122.44,37.96 122.33,38.07 122.33,38.29 122.44,38.4 123.49,38.4 123.6,38.51 123.6,38.73 123.49,38.84 122.44,38.84 122.33,38.95 122.33,39.17 122.44,39.28 123.49,39.28 123.6,39.38 123.6,39.6 123.49,39.71 122.44,39.71 122.33,39.82 122.33,40.04 122.44,40.15 123.49,40.15 123.6,40.26 123.6,40.48 123.49,40.59 122.44,40.59 122.33,40.7 122.33,40.91 122.44,41.02 123.49,41.02 123.6,41.13 123.6,41.35 123.49,41.46 122.44,41.46 122.33,41.57 122.33,41.79 122.44,41.9 123.49,41.9 123.6,42.01 123.6,42.22 123.49,42.33 122.44,42.33 122.33,42.44 122.33,42.66 122.44,42.77 123.49,42.77 123.6,42.88 123.6,43.1 123.49,43.21 122.44,43.21 122.33,43.32 122.33,45.31 118.75,48.89 118.75,70.23 121.12,72.61 121.12,73.29 123.24,75.41 123.24,77.72 126.67,81.15 v5(127.24,81.15)
AM57XX_PRU2ETH0_RXD0: length 258.5
  TOP w0.173: v4(111.83,80.82) 111.81,80.82 111.43,81.19 U1.C15
  L3_SIG1 w0.109: v4(111.83,80.82) 111.96,80.69 116.79,80.69 117.71,79.77 120.48,79.77 121.05,79.2 123.18,79.2 123.76,78.62 126.16,78.62 v5(127.13,79.58)
  L10_SIG4 w0.109: v5(127.13,79.58) 126.39,78.85 126.39,77.75 126.8,77.35 126.8,70.76 122.33,66.29 122.33,65.81 122.45,65.68 123.44,65.68 123.57,65.55 123.57,65.37 123.44,65.24 122.45,65.24 122.33,65.12 122.33,64.93 122.45,64.81 123.44,64.81 123.57,64.68 123.57,64.5 123.44,64.37 122.45,64.37 122.33,64.24 122.33,64.06 122.45,63.93 123.44,63.93 123.57,63.8 123.57,63.62 123.44,63.5 122.45,63.5 122.33,63.37 122.33,63.19 122.45,63.06 123.44,63.06 123.57,62.93 123.57,62.75 123.44,62.62 122.45,62.62 122.33,62.49 122.33,62.31 122.45,62.19 123.44,62.19 123.57,62.06 123.57,61.88 123.44,61.75 122.45,61.75 122.33,61.62 122.33,61.44 122.45,61.31 123.44,61.31 123.57,61.18 123.57,61 123.44,60.87 122.45,60.87 122.33,60.75 122.33,60.57 122.45,60.44 123.44,60.44 123.57,60.31 123.57,60.13 123.44,60 122.45,60 122.33,59.87 122.33,59.69 122.45,59.56 123.44,59.56 123.57,59.44 123.57,59.26 123.44,59.13 122.45,59.13 122.33,59 122.33,58.82 122.45,58.69 123.44,58.69 123.57,58.56 123.57,58.38 123.44,58.25 122.45,58.25 122.33,58.13 122.33,57.94 122.45,57.82 123.44,57.82 123.57,57.69 123.57,57.51 123.44,57.38 122.45,57.38 122.33,57.25 122.33,49.12 122.89,48.56 124.05,48.56 125.12,47.5 125.12,41.87 124.76,41.51 124.76,26.34 118.8,20.37 118.8,19.53 116.03,16.77 112.02,16.77 111.05,15.79 106.1,15.79 104.68,14.38 93.19,14.38 92.35,13.54 70.36,13.54 68.63,15.27 64.44,15.27 60.6,19.12 59.62,19.12 54.74,24 51.05,24 48.6,26.45 46.95,26.45 43.94,29.46 40.08,29.46 36.6,32.94 36.6,38.35 36,38.95 36,41.21 31.58,45.63 31.58,54.5 29.35,56.73 29.35,60.25 28.49,61.1 28.49,64.69 37.29,73.49 37.29,79.3 38.53,80.55 39.04,80.55 39.34,80.85 39.34,82.91 v8(38.73,83.52)
  BOTTOM w0.173: R171.2 v8(38.73,83.52)
AM57XX_PRU2ETH0_RXD1: length 257.7
  TOP w0.173: v3(126.64,74.55) 126.56,74.55 125.72,75.39 122.05,75.39 121.41,74.76 120.14,74.76 118.4,76.49 117.26,76.49 114.94,78.81 U1.A18
  L3_SIG1 w0.109: v5(126.06,74.2) 126.42,74.55 v3(126.64,74.55)
  L10_SIG4 w0.109: v5(126.06,74.2) 126.06,71.8 120.37,66.12 120.37,65.69 120.5,65.57 121.18,65.57 121.31,65.44 121.31,65.26 121.18,65.13 120.5,65.13 120.37,65 120.37,64.82 120.5,64.69 121.18,64.69 121.31,64.56 121.31,64.38 121.18,64.26 120.5,64.26 120.37,64.13 120.37,63.95 120.5,63.82 121.18,63.82 121.31,63.69 121.31,63.51 121.18,63.38 120.5,63.38 120.37,63.25 120.37,63.07 120.5,62.95 121.18,62.95 121.31,62.82 121.31,62.64 121.18,62.51 120.5,62.51 120.37,62.38 120.37,62.2 120.5,62.07 121.18,62.07 121.31,61.94 121.31,61.76 121.18,61.63 120.5,61.63 120.37,61.51 120.37,61.33 120.5,61.2 121.18,61.2 121.31,61.07 121.31,60.89 121.18,60.76 120.5,60.76 120.37,60.63 120.37,60.45 120.5,60.32 121.18,60.32 121.31,60.2 121.31,60.02 121.18,59.89 120.5,59.89 120.37,59.76 120.37,59.58 120.5,59.45 121.18,59.45 121.31,59.32 121.31,59.14 121.18,59.01 120.5,59.01 120.37,58.89 120.37,58.7 120.5,58.58 121.18,58.58 121.31,58.45 121.31,58.27 121.18,58.14 120.5,58.14 120.37,58.01 120.37,57.83 120.5,57.7 121.18,57.7 121.31,57.57 121.31,57.39 121.18,57.27 120.5,57.27 120.37,57.14 120.37,56.96 120.5,56.83 121.18,56.83 121.31,56.7 121.31,56.52 121.18,56.39 120.5,56.39 120.37,56.26 120.37,56.08 120.5,55.96 121.18,55.96 121.31,55.83 121.31,55.65 121.18,55.52 120.5,55.52 120.37,55.39 120.37,55.21 120.5,55.08 121.18,55.08 121.31,54.95 121.31,54.77 121.18,54.64 120.5,54.64 120.37,54.52 120.37,54.34 120.5,54.21 121.18,54.21 121.31,54.08 121.31,53.9 121.18,53.77 120.5,53.77 120.37,53.64 120.37,53.46 120.5,53.33 121.18,53.33 121.31,53.21 121.31,53.03 121.18,52.9 120.5,52.9 120.37,52.77 120.37,52.59 120.5,52.46 121.18,52.46 121.31,52.33 121.31,52.15 121.18,52.02 120.5,52.02 120.37,51.9 120.37,51.71 120.5,51.59 121.18,51.59 121.31,51.46 121.31,51.28 121.18,51.15 120.5,51.15 120.37,51.02 120.37,49.38 121.84,47.9 122.66,47.9 124.37,46.19 124.37,26.7 117.55,19.88 117.55,19.02 115.63,17.11 111.71,17.11 110.89,16.29 106.12,16.29 104.56,14.73 93.04,14.73 92.18,13.88 70.53,13.88 68.61,15.8 64.39,15.8 59.92,20.27 59.61,20.27 55.5,24.38 51.31,24.38 45.47,30.23 39.83,30.23 37.24,32.82 37.24,38.61 36.56,39.28 36.56,42.79 31.92,47.43 31.92,54.64 30.02,56.54 30.02,60.98 29.31,61.69 29.31,64.95 37.64,73.28 37.64,78.49 38.53,79.38 38.77,79.38 40.49,81.1 40.49,82.91 v8(38.73,84.66)
  BOTTOM w0.173: R173.2 v8(38.73,84.66)
AM57XX_PRU2ETH0_RXD2: length 257.6
  TOP w0.173: v3(128.32,74) 126.35,74 125.54,73.18 123,73.18 122.24,73.94 121.06,73.94 120.48,73.36 120.02,73.36 117.94,75.44 117.29,75.44 114.72,78.02 U1.A19
  L3_SIG1 w0.109: v3(128.32,74) v5(129.03,74)
  L10_SIG4 w0.109: v8(38.73,85.81) 37.53,84.6 37.53,82.15 36.3,80.91 36.3,73.74 27.52,64.97 27.52,59.95 28.62,58.85 28.67,58.8 28.67,55.88 29.29,55.25 29.29,51.3 30.31,50.28 30.31,43.22 34.57,38.96 34.57,33.83 39.83,28.58 43.82,28.58 46.61,25.78 48.18,25.78 50.8,23.16 53.8,23.16 58.52,18.44 60.32,18.44 63.89,14.86 64.45,14.31 68.5,14.31 70.03,12.77 92.75,12.77 93.64,13.66 100.41,13.66 101.04,13.04 101.83,13.04 102.46,13.66 106.49,13.66 106.73,13.43 109.63,13.43 110.66,14.45 112.35,14.45 113.99,16.09 116.31,16.09 117.2,16.98 118.28,16.98 119.89,18.59 120.51,18.59 121.36,19.44 121.36,21.11 126.49,26.24 126.49,39.69 126.18,40 126.18,49.2 124.71,50.67 124.71,55.38 124.84,55.51 125.86,55.51 125.98,55.63 125.98,55.81 125.86,55.94 124.84,55.94 124.71,56.07 124.71,56.25 124.84,56.38 125.86,56.38 125.98,56.51 125.98,56.69 125.86,56.82 124.84,56.82 124.71,56.94 124.71,57.13 124.84,57.25 125.86,57.25 125.98,57.38 125.98,57.56 125.86,57.69 124.84,57.69 124.71,57.82 124.71,58 124.84,58.13 125.86,58.13 125.98,58.25 125.98,58.44 125.86,58.56 124.84,58.56 124.71,58.69 124.71,58.87 124.84,59 125.86,59 125.98,59.13 125.98,59.31 125.86,59.44 124.84,59.44 124.71,59.57 124.71,59.75 124.84,59.87 125.86,59.87 125.98,60 125.98,60.18 125.86,60.31 124.84,60.31 124.71,60.44 124.71,60.62 124.84,60.75 125.86,60.75 125.98,60.88 125.98,61.06 125.86,61.19 124.84,61.19 124.71,61.31 124.71,61.49 124.84,61.62 125.86,61.62 125.98,61.75 125.98,61.93 125.86,62.06 124.84,62.06 124.71,62.19 124.71,62.37 124.84,62.5 125.86,62.5 125.98,62.62 125.98,62.8 125.86,62.93 124.84,62.93 124.71,63.06 124.71,63.7 125.15,64.14 125.15,67.03 127.71,69.6 127.71,72.67 129.03,73.99 v5(129.03,74)
  BOTTOM w0.173: R174.2 v8(38.73,85.81)
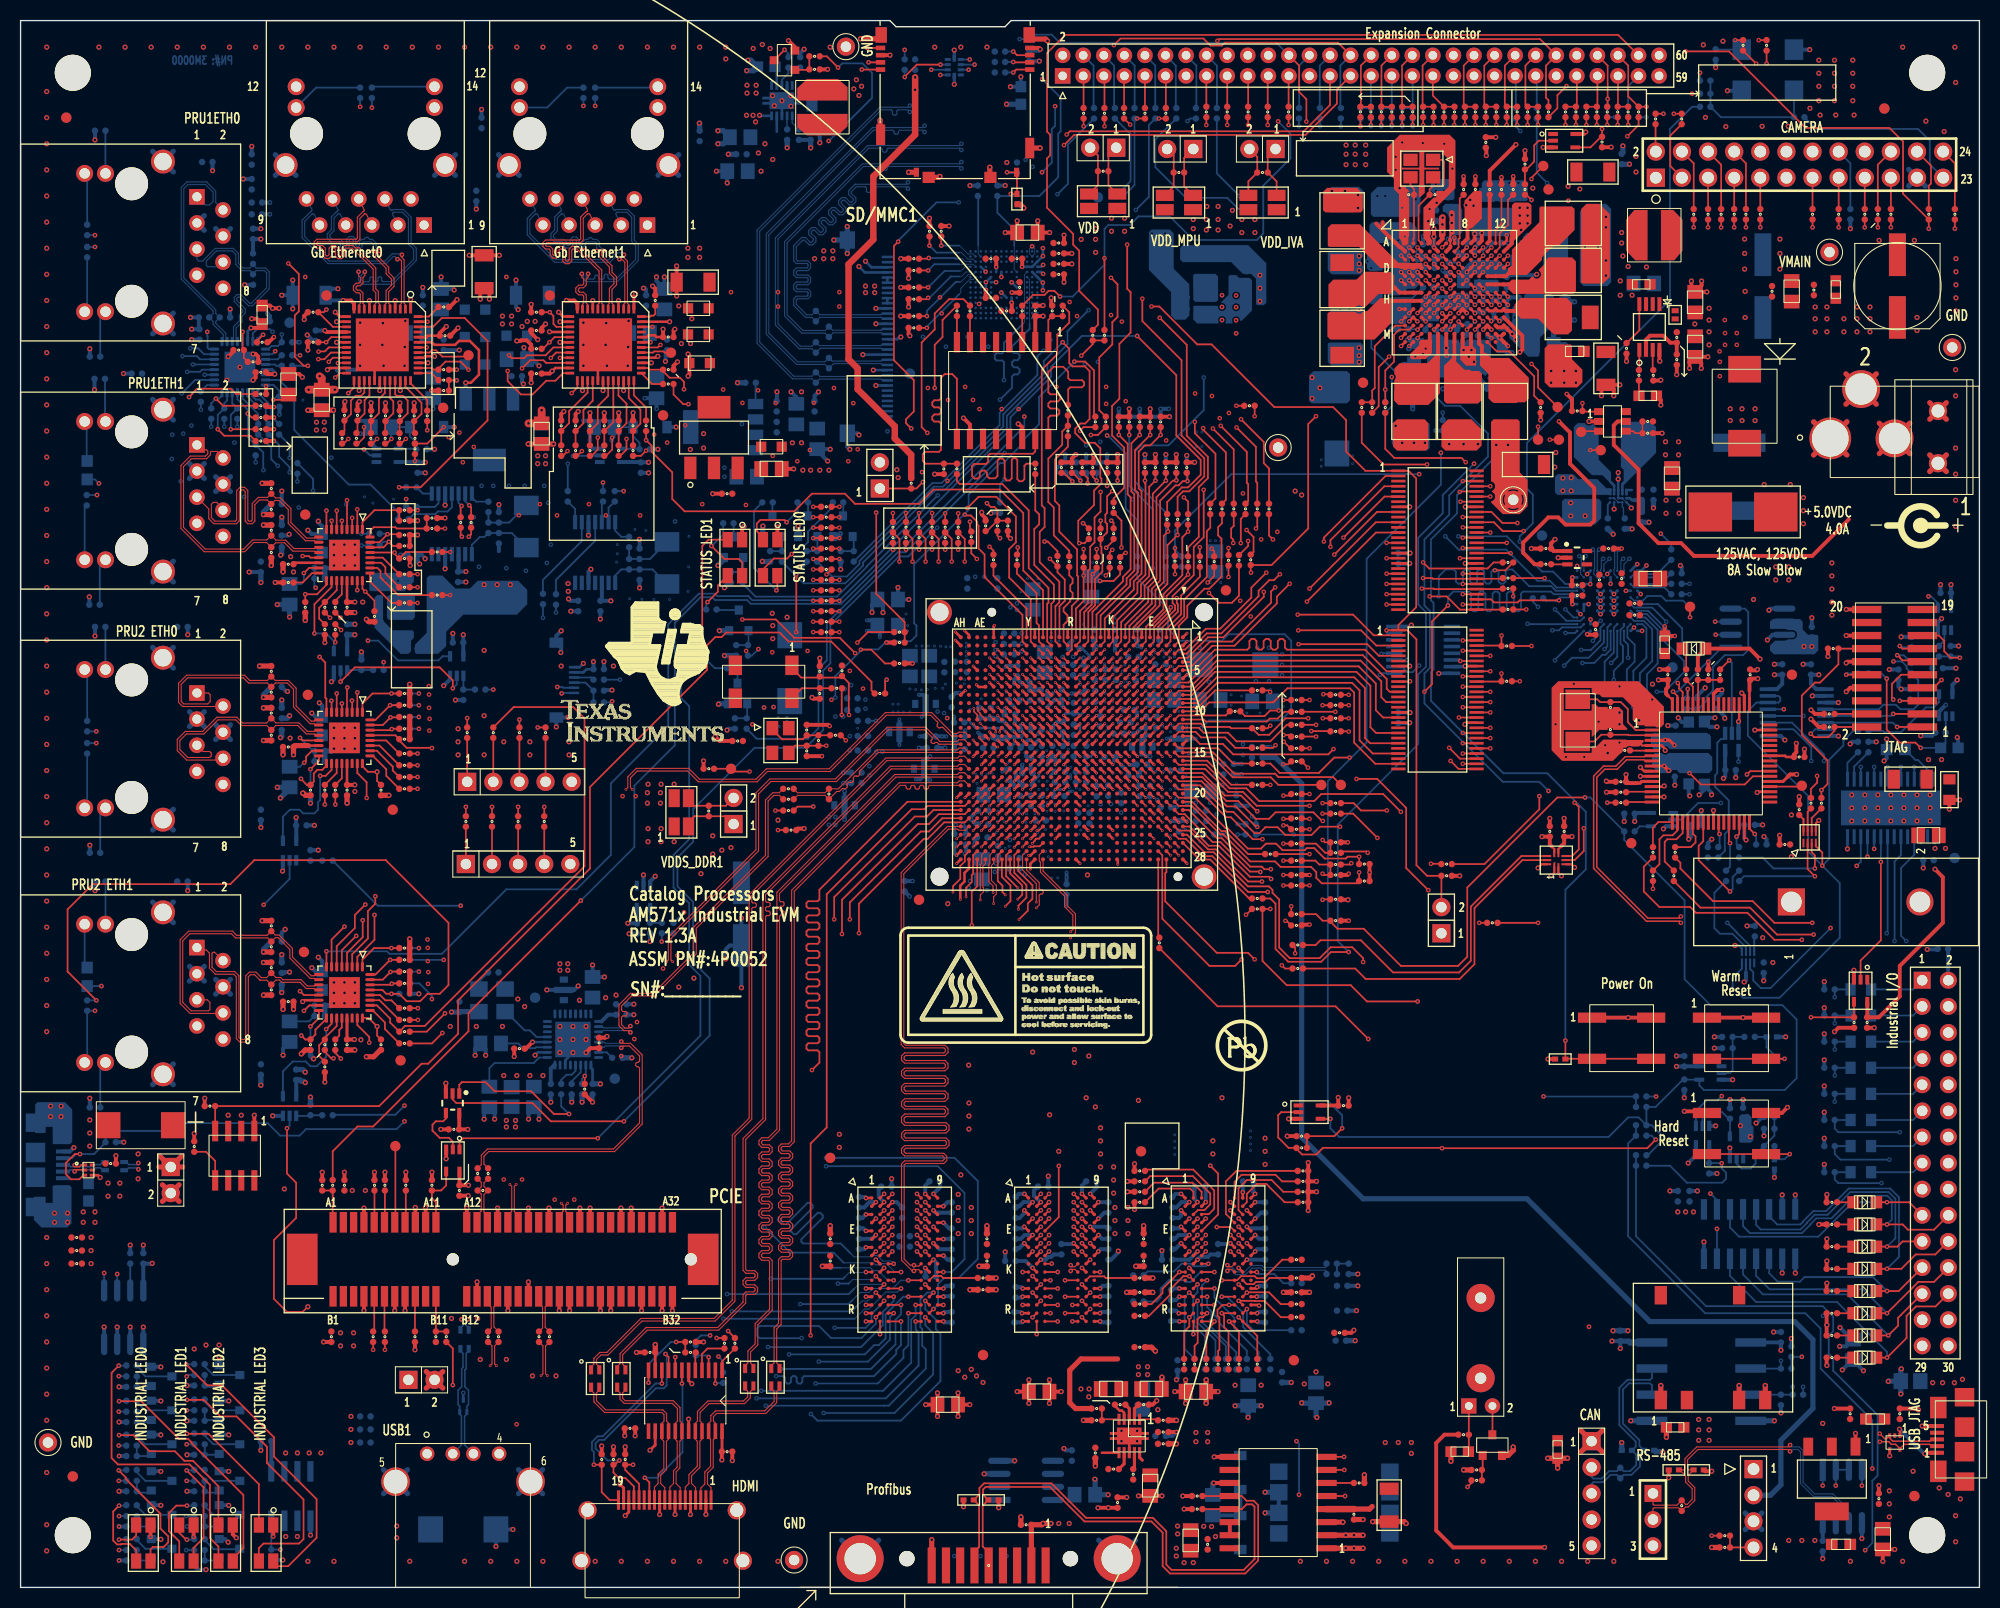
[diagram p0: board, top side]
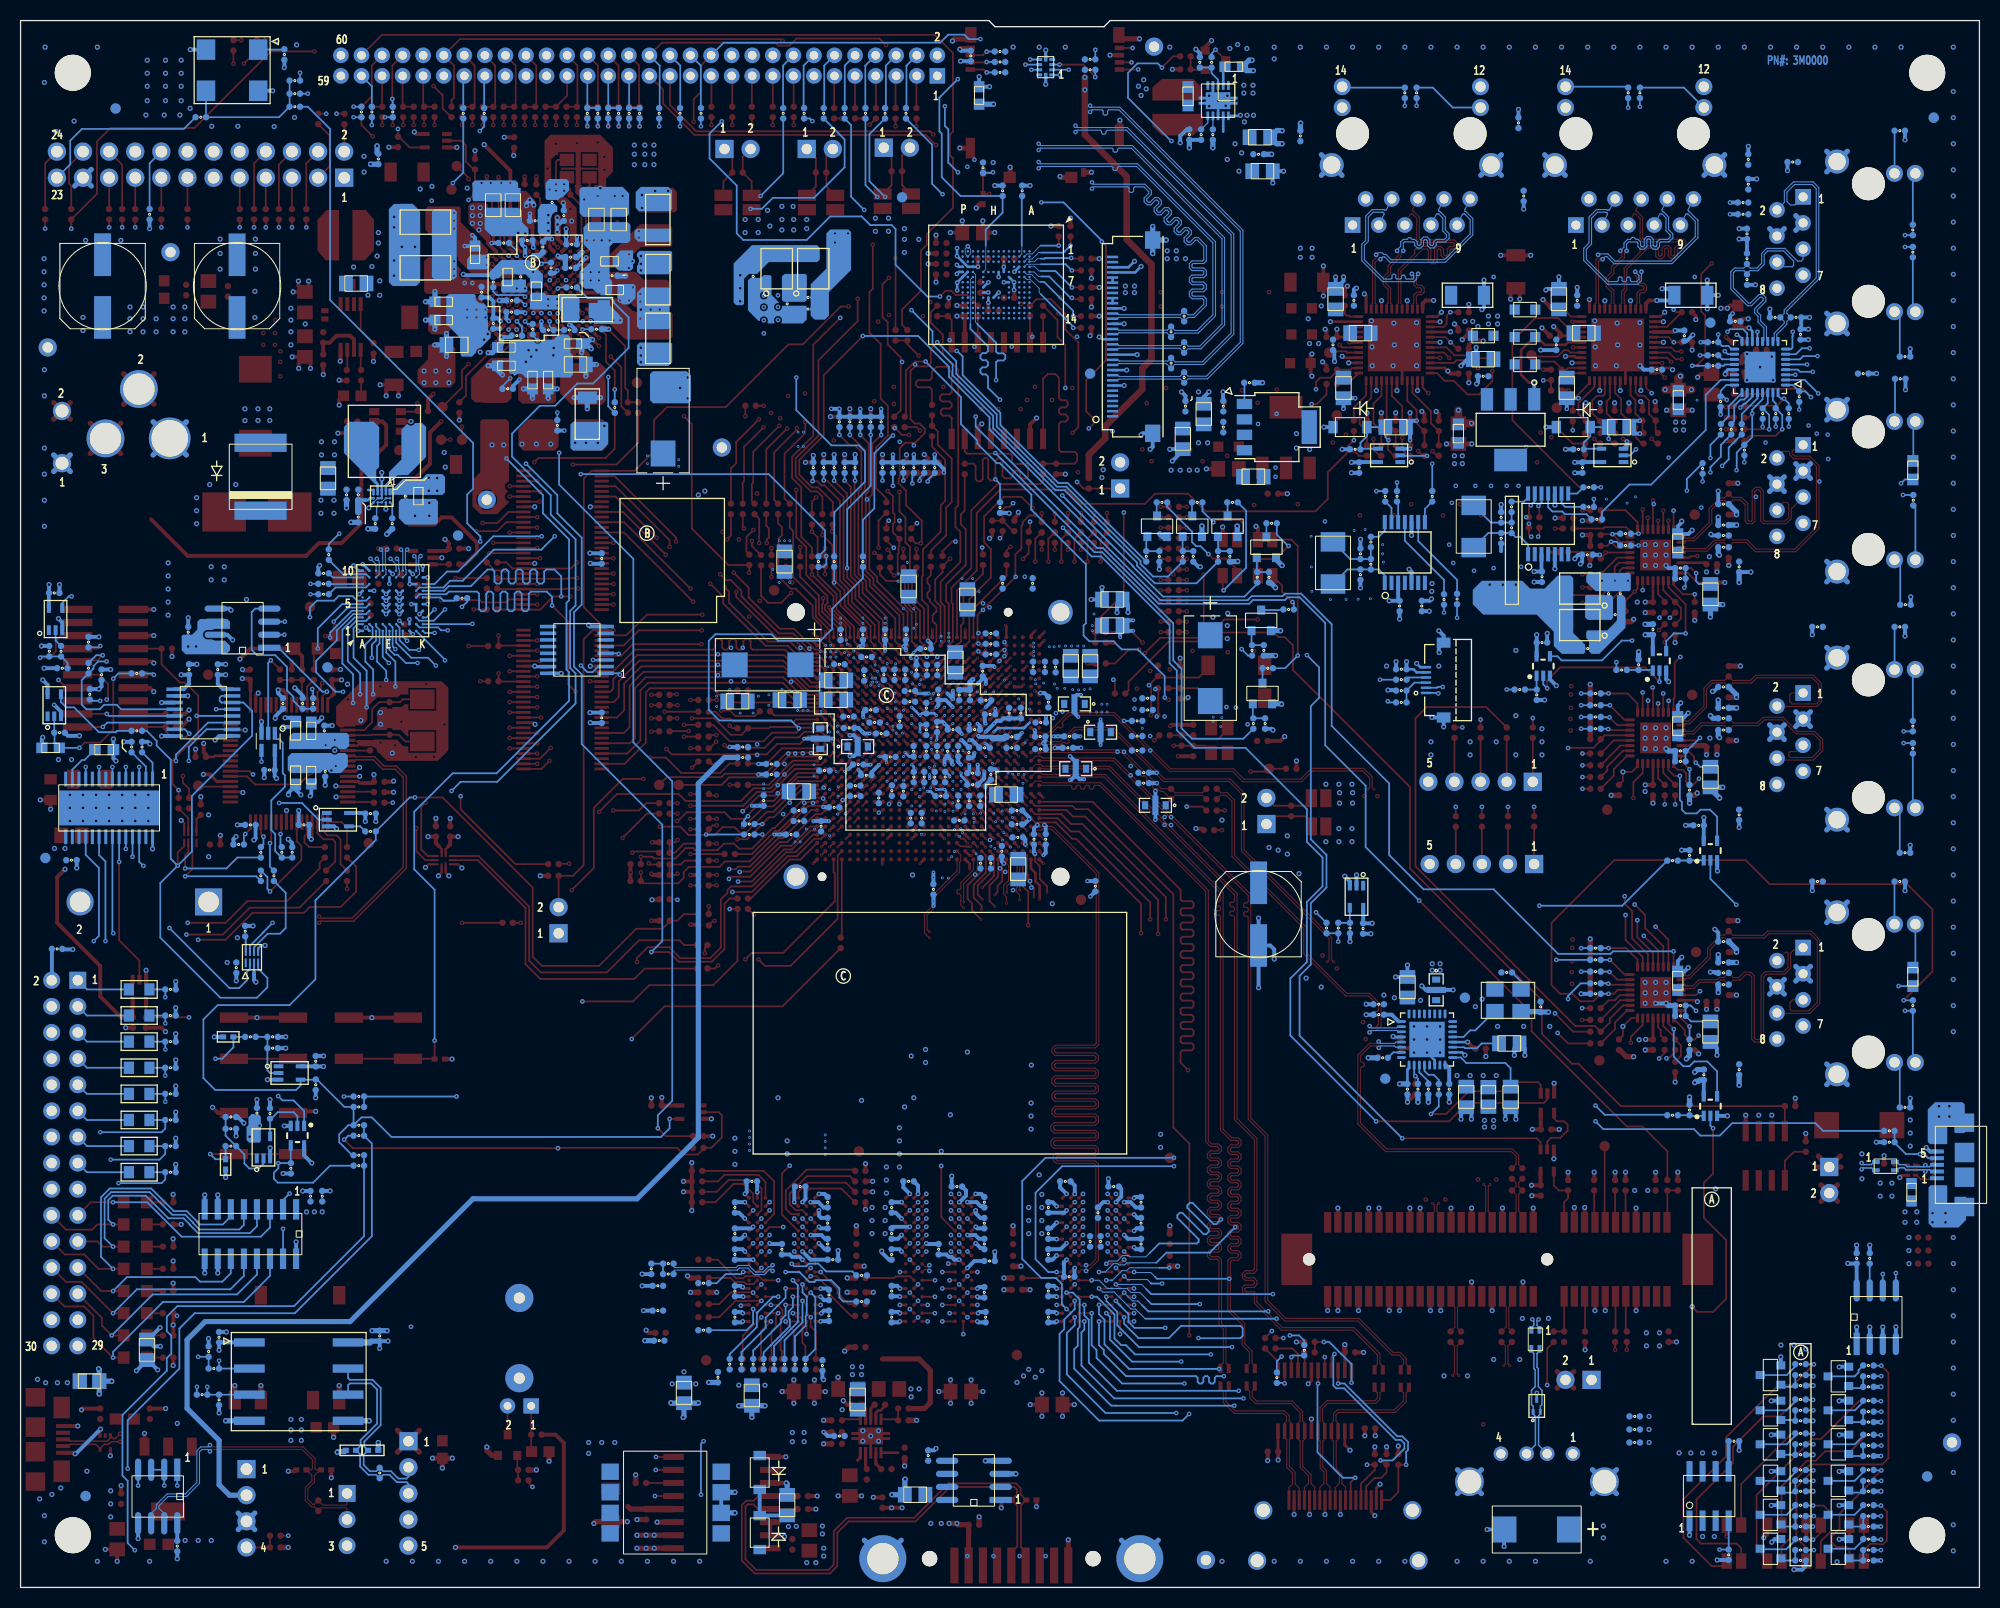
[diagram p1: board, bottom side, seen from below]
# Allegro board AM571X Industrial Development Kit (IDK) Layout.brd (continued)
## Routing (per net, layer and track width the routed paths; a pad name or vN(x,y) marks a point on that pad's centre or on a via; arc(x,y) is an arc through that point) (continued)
AM57XX_PRU2ETH0_RXD3: length 256.1
  TOP w0.173: U1.F14 v4(109.43,82.41)
  L3_SIG1 w0.109: v5(129.29,79.08) 128.5,79.86 128.26,79.86 127.77,80.36 126.81,80.36 126.62,80.17 125.04,80.17 124.37,80.84 121.5,80.84 121.24,81.1 119.56,81.1 118.21,82.45 117.3,82.45 116.7,83.05 113.22,83.05 112.27,82.1 109.75,82.1 v4(109.43,82.41)
  L10_SIG4 w0.109: v5(129.29,79.08) 129.59,78.77 129.59,73.48 129.01,72.9 129.01,68.07 126.82,65.88 126.82,58.96 126.83,58.95 126.83,53.37 126.7,53.25 125.93,53.25 125.81,53.12 125.81,52.94 125.93,52.81 126.7,52.81 126.83,52.68 126.83,52.5 126.7,52.37 125.93,52.37 125.81,52.25 125.81,52.06 125.93,51.94 126.7,51.94 126.83,51.81 126.83,51.63 126.7,51.5 125.93,51.5 125.81,51.37 125.81,51.19 125.93,51.06 126.7,51.06 126.83,50.93 126.83,50.75 126.7,50.63 125.93,50.63 125.81,50.5 125.81,50.32 125.93,50.19 126.7,50.19 126.83,50.06 126.83,26.1 121.7,20.97 121.7,19.3 120.58,18.19 120.1,18.19 118.56,16.64 117.34,16.64 116.45,15.76 114.34,15.76 113.84,15.26 113.84,14.7 112.23,13.09 106.59,13.09 106.35,13.32 102.6,13.32 101.97,12.7 100.9,12.7 100.27,13.32 94.17,13.32 92.75,11.9 70.37,11.9 68.31,13.97 64.31,13.97 60.18,18.1 58.22,18.1 53.5,22.83 50.66,22.83 48.04,25.44 46.44,25.44 43.69,28.19 39.73,28.19 34.16,33.76 34.16,38.73 29.97,42.92 29.97,48.12 29.13,48.96 29.13,49.91 28.04,51.01 28.04,52.68 28.88,53.52 28.88,55.18 28.33,55.74 28.33,58.59 27.18,59.73 27.18,66.13 35.33,74.27 35.33,80.9 36.83,82.4 36.83,85.04 v8(38.73,86.95)
  BOTTOM w0.173: R175.2 v8(38.73,86.95)
AM57XX_PRU2ETH0_RXDV: length 259.3
  TOP w0.173: R197.2 v8(45.85,75.92) ; U1.G14 v4(108.63,82.41) ; R166.2 v8(38.61,78.82)
  L3_SIG1 w0.109: v5(124.23,80.35) 123.18,80.35 123.03,80.5 121.36,80.5 121.1,80.76 118.51,80.76 117.9,81.37 112.57,81.37 112.24,81.7 109.72,81.7 109,82.41 v4(108.63,82.41)
  L10_SIG4 w0.109: v8(38.61,78.82) 40.41,78.82 41.22,79.63 44.27,79.63 44.78,79.13 44.78,76.99 v8(45.85,75.92) 45.3,75.37 41.45,75.37 31.06,64.97 31.06,62.28 34.82,58.52 34.82,56.31 39.5,51.64 39.5,37.72 51.69,25.53 56.01,25.53 59.74,21.8 64.23,21.8 66.85,19.18 67.87,19.18 71.51,15.54 91.21,15.54 92.46,16.79 100.87,16.79 101,16.92 101,17.27 101.12,17.4 101.3,17.4 101.43,17.27 101.43,16.92 101.56,16.79 101.74,16.79 101.87,16.92 101.87,17.27 102,17.4 102.18,17.4 102.31,17.27 102.31,16.92 102.43,16.79 102.85,16.79 105.57,19.51 112.43,19.51 112.69,19.25 115.24,19.25 121.92,25.94 121.92,44.81 121,45.72 120.4,45.72 117.73,48.39 117.73,52.22 117.6,52.35 117.1,52.35 116.97,52.48 116.97,52.66 117.1,52.78 117.6,52.78 117.73,52.91 117.73,53.72 117.6,53.85 116.87,53.85 116.74,53.98 116.74,54.16 116.87,54.29 117.6,54.29 117.73,54.41 117.73,54.59 117.6,54.72 116.87,54.72 116.74,54.85 116.74,55.03 116.87,55.16 117.6,55.16 117.73,55.29 117.73,55.47 117.6,55.6 116.87,55.6 116.74,55.72 116.74,55.91 116.87,56.03 117.6,56.03 117.73,56.16 117.73,56.34 117.6,56.47 116.87,56.47 116.74,56.6 116.74,56.78 116.87,56.91 117.6,56.91 117.73,57.03 117.73,57.22 117.6,57.34 116.87,57.34 116.74,57.47 116.74,57.65 116.87,57.78 117.6,57.78 117.73,57.91 117.73,58.09 117.6,58.22 116.87,58.22 116.74,58.35 116.74,58.53 116.87,58.65 117.6,58.65 117.73,58.78 117.73,58.96 117.6,59.09 116.87,59.09 116.74,59.22 116.74,59.4 116.87,59.53 117.6,59.53 117.73,59.66 117.73,59.84 117.6,59.97 116.87,59.97 116.74,60.09 116.74,60.27 116.87,60.4 117.6,60.4 117.73,60.53 117.73,60.71 117.6,60.84 116.87,60.84 116.74,60.97 116.74,61.15 116.87,61.28 117.6,61.28 117.73,61.4 117.73,61.58 117.6,61.71 116.87,61.71 116.74,61.84 116.74,62.02 116.87,62.15 117.6,62.15 117.73,62.28 117.73,62.46 117.6,62.59 116.87,62.59 116.74,62.71 116.74,62.9 116.87,63.02 117.6,63.02 117.73,63.15 117.73,63.33 117.6,63.46 116.87,63.46 116.74,63.59 116.74,63.77 116.87,63.9 117.6,63.9 117.73,64.03 117.73,64.21 117.6,64.33 116.87,64.33 116.74,64.46 116.74,64.64 116.87,64.77 117.6,64.77 117.73,64.9 117.73,71.4 122.66,76.33 122.66,78.77 v5(124.23,80.35)
AM57XX_PRU2ETH0_RXER: length 259.1
  TOP w0.173: U1.G12 v4(108.63,84.01) ; R170.2 v8(38.61,81.11)
  L3_SIG1 w0.109: v4(108.63,84.01) 108.63,84.02 109.03,84.26 v5(109.03,84.26)
  L10_SIG4 w0.109: v5(109.03,84.26) 110.02,84.26 110.41,84.66 113.5,84.66 114.09,84.08 123.04,84.08 123.61,84.65 129.86,84.65 130.2,84.31 130.2,83.77 129.39,82.96 129.39,80.57 128.6,79.79 128.6,75.67 127.23,74.3 127.23,70.19 124.15,67.11 124.15,56.15 124.02,56.02 123.27,56.02 123.14,55.89 123.14,55.71 123.27,55.58 124.02,55.58 124.15,55.45 124.15,55.27 124.02,55.14 123.27,55.14 123.14,55.02 123.14,54.84 123.27,54.71 124.02,54.71 124.15,54.58 124.15,54.4 124.02,54.27 123.27,54.27 123.14,54.14 123.14,53.96 123.27,53.83 124.02,53.83 124.15,53.71 124.15,53.52 124.02,53.4 123.27,53.4 123.14,53.27 123.14,53.09 123.27,52.96 124.02,52.96 124.15,52.83 124.15,52.65 124.02,52.52 123.27,52.52 123.14,52.39 123.14,52.21 123.27,52.09 124.02,52.09 124.15,51.96 124.15,51.78 124.02,51.65 123.27,51.65 123.14,51.52 123.14,51.34 123.27,51.21 124.02,51.21 124.15,51.08 124.15,50.9 124.02,50.78 123.27,50.78 123.14,50.65 123.14,50.47 123.27,50.34 124.02,50.34 124.15,50.21 124.15,50.03 124.02,49.9 123.27,49.9 123.14,49.77 123.14,49.59 123.27,49.46 124.02,49.46 124.15,49.34 124.15,49.05 125.68,47.52 125.68,41.13 125.57,41.02 125.57,38.29 126.09,37.77 126.09,26.35 116.17,16.43 113.24,16.43 112.35,15.55 111.28,15.55 109.49,13.76 106.87,13.76 106.63,14 93.5,14 92.7,13.2 70.14,13.2 68.61,14.74 64.5,14.74 60.46,18.78 58.95,18.78 54.13,23.6 50.84,23.6 48.32,26.12 46.78,26.12 43.81,29.08 39.8,29.08 35.86,33.02 35.86,38.18 30.65,43.39 30.65,50.63 30,51.28 30,51.64 30.25,51.9 30.25,54.77 29.01,56.02 29.01,58.94 27.86,60.09 27.86,64.67 36.7,73.51 36.7,79.2 v8(38.61,81.11)
AM57XX_PRU2ETH0_RXLINK: length 7.7
  TOP w0.173: U1.A16 115.39,80.42 117.73,78.07 119.75,78.07 R188.2
AM57XX_PRU2ETH0_TXCLK: length 15.9
  TOP w0.173: R162.2 123.42,82.91 v3(122.83,82.91) ; U1.F12 v4(109.43,84.01)
  L3_SIG1 w0.099: 111.96,83.72 111.71,83.72 111.59,83.84 111.28,83.84 111.16,83.72 110.91,83.72 110.79,83.84 110.48,83.84 110.36,83.72 110.11,83.72 109.82,84.01 v4(109.43,84.01)
  L3_SIG1 w0.109: 111.96,83.72 112.64,83.72 112.81,83.89 117.13,83.89 117.21,83.81 118.88,83.81 120.21,82.48 121.5,82.48 121.75,82.73 122.65,82.73 v3(122.83,82.91)
AM57XX_PRU2ETH0_TXD0: length 15.5
  TOP w0.173: R163.2 123.49,81.62 v3(122.85,82.26) ; U1.E14 v4(110.23,82.41)
  L3_SIG1 w0.109: v4(110.23,82.41) 110.53,82.71 111.41,82.71 111.62,82.92 112.13,82.92 112.89,83.68 117.01,83.68 117.22,83.47 118.71,83.47 120.09,82.09 121.59,82.09 121.87,82.37 122.73,82.37 v3(122.85,82.26)
AM57XX_PRU2ETH0_TXD1: length 11.7
  TOP w0.173: U1.A12 114.58,83.62 115.06,83.13 117.41,83.13 118.25,82.3 121.54,82.3 123.14,83.9 R164.2
AM57XX_PRU2ETH0_TXD2: length 8.3
  TOP w0.173: R168.2 118.14,81.66 117.12,82.68 114.81,82.68 114.27,83.22 112.64,83.22 U1.B13
AM57XX_PRU2ETH0_TXD3: length 11
  TOP w0.173: R169.2 122.92,85.17 122.25,84.51 121.48,84.51 121.19,84.22 115.27,84.22 115.08,84.42 U1.A11
AM57XX_PRU2ETH0_TXEN: length 241.4
  TOP w0.173: v3(125.22,84.54) 123.03,84.54 121.43,82.93 120.4,82.93 R167.2 117.73,83.57 117.6,83.69 115.11,83.69 114.79,84.01 112.63,84.01 U1.B12 ; R196.2 v8(43.31,75.92)
  L3_SIG1 w0.109: v3(125.22,84.54) 126.01,84.54 126.47,84.08 126.83,84.08 127.13,84.38 128.6,84.38 128.9,84.08 129.69,84.08 v5(129.72,84.1)
  L10_SIG4 w0.109: v8(43.31,75.92) 41.06,78.16 38.38,78.16 38.02,77.81 38.02,73.11 30.38,65.47 30.38,62 33.6,58.79 33.6,54.19 34.34,53.45 34.34,48.97 36.45,46.86 36.45,44.58 37,44.02 37,39.45 37.85,38.61 37.85,34.16 41.4,30.61 45.59,30.61 51.43,24.77 55.63,24.77 59.61,20.78 62.08,20.78 65.23,17.63 67.28,17.63 70.17,14.75 92.19,14.75 92.71,15.27 104.62,15.27 106.17,16.83 110.79,16.83 111.41,17.45 115.49,17.45 117.17,19.13 117.17,19.99 124.03,26.85 124.03,46 123.24,46.79 122.17,46.79 119.43,49.53 119.43,69.37 122.2,72.14 122.2,73.75 123.81,75.36 124.31,75.36 125.22,76.28 125.22,78.49 127,80.26 128.57,80.26 128.99,80.69 128.99,83.33 129.72,84.05 v5(129.72,84.1)
AM57XX_PRU2ETH1_COL: length 169.8
  TOP w0.173: U1.D18 v4(111.03,78.42) ; v3(122.81,74.76) 123.53,74.76 R220.2 ; R893.1 v3(169.8,148.21)
  L3_SIG1 w0.109: v3(169.8,148.21) v5(169.8,146.35) ; v3(122.81,74.76) 122.56,75.01 v5(122.2,75.01) 122.13,75.01 119.44,77.69 116.22,77.69 116.08,77.55 114.35,77.55 114.02,77.88 111.91,77.88 111.38,78.42 v4(111.03,78.42)
  L4_SIG2 w0.114: v5(122.2,75.01) 122.2,75.01 122.61,75.41 125.31,75.41 126.84,76.94 129.94,76.94 130.86,77.85 136.16,77.85 143.22,70.79 143.22,69.98 147.37,65.83 v5(147.37,65.56)
  L9_SIG3 w0.114: v5(147.37,65.56) 169.01,65.56 171.2,63.37 v5(172.21,63.37)
  L10_SIG4 w0.109: v5(169.8,146.35) 173.06,143.1 173.06,136.38 171.22,134.54 170.33,134.54 168.5,132.72 168.5,117.78 170.41,115.87 170.41,109.73 174.12,106.02 174.12,96.04 174.8,95.35 174.8,89.84 173.7,88.74 173.7,85.71 172.94,84.95 172.94,83.07 172.18,82.3 172.18,81.33 174.41,79.1 174.41,76.75 173.36,75.69 173.36,71.49 169.98,68.12 169.98,65.6 v5(172.21,63.37)
AM57XX_PRU2ETH1_CRS: length 406.8
  TOP w0.173: U1.E17 v4(110.23,79.22) ; R892.1 v3(168.78,148.21) ; R219.2 v3(38.64,55.2)
  L3_SIG1 w0.099: 112.04,78.71 110.74,78.71 v4(110.23,79.22)
  L3_SIG1 w0.109: v5(124.33,76.03) 121.97,76.03 119.73,78.26 116.05,78.26 115.87,78.08 114.7,78.08 114.08,78.71 112.04,78.71 ; v3(38.64,55.2) 37,55.2 v5(36.98,55.22) ; v3(168.78,148.21) v5(168.78,147.45)
  L4_SIG2 w0.114: v5(36.98,55.22) 36.98,54.16 30.86,48.04 30.86,35.05 33.44,32.47 33.44,30.61 26.71,23.88 26.71,22.99 24.64,20.92 24.64,10.85 28.94,6.55 31.27,4.22 41.16,4.22 42.02,5.09 48.26,5.09 55.55,12.38 56.31,12.38 56.9,11.79 58.56,11.79 59.31,12.54 64.19,12.54 64.76,13.11 71.85,13.11 73.14,11.82 74.53,11.82 74.89,12.19 95.47,12.19 96.88,10.79 103.38,10.79 104.16,10.01 104.68,10.01 105.46,10.79 113.1,10.79 114.83,9.06 116.71,9.06 117.52,9.87 132.82,9.87 139,16.05 143.56,16.05 150.42,22.91 150.42,52.63 150.75,52.96 150.75,53.9 150.42,54.23 v5(150.42,63.74) 143.89,70.26 143.89,71.15 138.5,76.54 138.5,77.16 137.5,78.17 130.76,78.17 129.82,77.23 126.71,77.23 125.51,76.03 v5(124.33,76.03)
  L9_SIG3 w0.114: v5(150.42,63.74) 168.02,63.74 170.03,61.72 v5(172.09,61.72)
  L10_SIG4 w0.109: v5(168.78,147.45) 168.78,144.27 170.31,142.75 170.31,135.89 167.26,132.84 167.26,131.83 166.37,130.94 166.37,118.24 169.55,115.06 169.55,108.97 172.85,105.66 172.85,90 172.84,90 172.84,89.58 172.85,89.57 172.85,88.37 172.66,88.18 172.66,84.23 171.04,82.61 171.04,82.07 174.12,78.98 174.12,76.97 172.85,75.69 172.85,73.28 171.58,72.01 171.58,70.59 169.7,68.71 169.7,64.14 170.34,63.49 170.34,63.47 v5(172.09,61.72)
AM57XX_PRU2ETH1_MRCLK: length 113.9
  TOP w0.173: R209.2 40,52.91 v8(41.02,53.93) ; U1.AC9 v4(95.04,86.41)
  L3_SIG1 w0.109: v4(95.04,86.41) 95.03,86.42 v5(94.64,86.66)
  L10_SIG4 w0.109: v8(41.02,53.93) 56.22,53.93 56.76,54.47 57.26,54.47 59.04,56.25 59.83,56.25 63.43,59.86 65.06,59.86 65.68,60.47 65.68,60.65 65.1,61.23 65.1,61.41 65.23,61.54 65.41,61.54 65.99,60.96 66.17,60.96 66.3,61.09 66.3,61.27 65.72,61.85 65.72,62.03 65.84,62.16 66.02,62.16 66.61,61.58 66.79,61.58 68.91,63.7 68.91,64.56 69.91,65.57 70.91,65.57 71.39,66.05 71.39,66.23 70.77,66.86 70.77,67.04 70.9,67.17 71.08,67.17 71.7,66.54 71.88,66.54 72.01,66.67 72.01,66.85 71.39,67.47 71.39,67.66 71.52,67.78 71.7,67.78 72.32,67.16 72.5,67.16 72.63,67.29 72.63,67.47 72.01,68.09 72.01,68.27 72.14,68.4 72.32,68.4 72.94,67.78 73.12,67.78 73.25,67.91 73.25,68.09 72.63,68.71 72.63,68.89 72.75,69.02 72.93,69.02 73.56,68.4 73.74,68.4 73.87,68.53 73.87,68.71 73.24,69.33 73.24,69.51 73.37,69.64 73.55,69.64 74.17,69.02 74.36,69.02 74.48,69.14 74.48,69.33 73.86,69.95 73.86,70.13 73.99,70.26 74.17,70.26 74.79,69.63 74.97,69.63 75.1,69.76 75.1,69.94 74.48,70.57 74.48,70.75 74.61,70.87 74.79,70.87 75.41,70.25 75.59,70.25 75.72,70.38 75.72,70.56 75.1,71.18 75.1,71.36 75.23,71.49 75.41,71.49 76.03,70.87 76.21,70.87 76.34,71 76.34,71.18 75.72,71.8 75.72,71.98 75.84,72.11 76.03,72.11 76.65,71.49 76.83,71.49 77.72,72.38 77.72,78.9 77.6,79.03 77.01,79.03 76.89,79.16 76.89,79.34 77.01,79.47 77.6,79.47 77.72,79.6 77.72,79.78 77.6,79.91 77.01,79.91 76.89,80.03 76.89,80.21 77.01,80.34 77.6,80.34 77.72,80.47 77.72,80.65 77.6,80.78 77.01,80.78 76.89,80.91 76.89,81.09 77.01,81.22 77.6,81.22 77.72,81.34 77.72,81.52 77.6,81.65 77.01,81.65 76.89,81.78 76.89,81.96 77.01,82.09 77.6,82.09 77.72,82.22 77.72,82.4 77.6,82.53 77.01,82.53 76.89,82.65 76.89,82.84 77.01,82.96 77.6,82.96 77.72,83.09 77.72,83.27 77.6,83.4 77.01,83.4 76.89,83.53 76.89,83.71 77.01,83.84 77.6,83.84 77.72,83.97 77.72,84.15 77.6,84.27 77.01,84.27 76.89,84.4 76.89,84.58 77.01,84.71 77.6,84.71 77.72,84.84 77.72,85.8 80.84,88.92 86.17,88.92 86.69,89.44 90.91,89.44 91.26,89.08 91.87,89.08 92.38,88.57 92.38,87.91 92.76,87.53 93.77,87.53 v5(94.64,86.66)
AM57XX_PRU2ETH1_RXD0: length 114.1
  TOP w0.173: U1.AB5 v4(95.84,89.61)
  L3_SIG1 w0.102: 95.33,91.62 95.33,90.5 95.84,90 v4(95.84,89.61)
  L3_SIG1 w0.109: v5(92.79,96.21) 93.22,95.78 93.22,94.37 93.73,93.86 93.73,93.22 95.33,91.62
  L10_SIG4 w0.109: v5(92.79,96.21) 92.38,95.8 92.38,93.14 90.98,91.74 90.98,91.14 90.15,90.31 85.8,90.31 85.23,89.74 79.37,89.74 76.15,86.52 76.15,74.68 75.69,74.22 75.69,73.16 65.55,63.02 63.49,63.02 63.35,62.88 63.35,62.68 63.91,62.12 63.91,61.92 63.76,61.78 63.57,61.78 63.01,62.34 62.81,62.34 62.67,62.2 62.67,62 63.23,61.44 63.23,61.24 62.94,60.95 62.74,60.95 61.6,62.09 61.4,62.09 61.26,61.95 61.26,61.75 62.4,60.61 62.4,60.41 62.26,60.27 62.06,60.27 60.92,61.41 60.72,61.41 60.58,61.27 60.58,61.07 61.72,59.93 61.72,59.73 61.58,59.59 61.38,59.59 60.24,60.73 60.04,60.73 59.9,60.59 59.9,60.39 61.04,59.25 61.04,59.06 60.88,58.89 60.23,58.89 59.18,59.94 56.29,59.94 55.8,59.46 51.92,59.46 51.12,60.26 46.95,60.26 46.81,60.4 46.81,61.64 46.67,61.78 46.47,61.78 46.33,61.64 46.33,60.4 46.19,60.26 45.99,60.26 45.85,60.4 45.85,61.64 45.71,61.78 45.51,61.78 45.37,61.64 45.37,60.4 45.23,60.26 43.82,60.26 42.42,58.85 42.42,55.75 42.06,55.4 40.95,55.4 40,56.34 v8(40,57.23)
  BOTTOM w0.173: v8(40,57.23) 40,57.53 38.78,58.76 R213.2
AM57XX_PRU2ETH1_RXD1: length 114.5
  TOP w0.173: U1.AB8 v4(95.84,87.21)
  L3_SIG1 w0.109: v5(95.44,87.46) 95.83,87.22 v4(95.84,87.21)
  L10_SIG4 w0.109: v5(95.44,87.46) 94.13,87.46 93.86,87.74 92.91,87.74 92.61,88.04 92.61,88.8 92.08,89.33 91.52,89.33 90.93,89.92 86.66,89.92 86.02,89.27 80.58,89.27 76.5,85.2 76.5,74.5 76.83,74.17 76.83,73.53 76.45,73.15 76.33,73.15 63.63,60.45 63.11,60.45 60.83,58.17 55.57,58.17 55.29,57.89 53.52,57.89 52.75,58.65 48.73,58.65 48.4,58.98 48.4,59.54 48.26,59.68 48.06,59.68 47.92,59.54 47.92,57.93 47.78,57.79 47.58,57.79 47.44,57.93 47.44,59.59 47.3,59.73 47.1,59.73 46.96,59.59 46.96,57.98 46.82,57.84 46.62,57.84 46.48,57.98 46.48,59.62 46.34,59.76 46.14,59.76 46,59.62 46,57.93 45.86,57.79 45.66,57.79 45.52,57.93 45.52,59.62 45.38,59.76 45.18,59.76 45.04,59.62 45.04,57.93 44.9,57.79 44.7,57.79 44.56,57.93 44.56,59.62 44.42,59.76 44.22,59.76 44.08,59.62 44.08,58.31 43.94,58.17 43.01,58.17 42.8,57.96 42.8,55.63 42.22,55.04 40.67,55.04 38.79,56.92 36.98,56.92 36.83,57.07 36.83,57.42 36.96,57.54 37.9,57.54 38.02,57.67 38.02,57.85 37.9,57.98 36.96,57.98 36.83,58.11 36.83,58.29 36.96,58.42 37.9,58.42 38.02,58.55 38.02,58.73 37.9,58.86 36.96,58.86 36.83,58.98 36.83,59.16 36.96,59.29 37.9,59.29 38.02,59.42 38.02,59.6 37.9,59.73 36.96,59.73 36.83,59.86 36.83,60.25 37.11,60.53 38.1,60.53 v8(38.73,59.9)
  BOTTOM w0.173: R215.2 v8(38.73,59.9)
AM57XX_PRU2ETH1_RXD2: length 113.9
  TOP w0.173: U1.AD6 v4(94.24,88.81)
  L3_SIG1 w0.109: v5(85.12,91.26) 85.42,91.57 88.97,91.57 89.93,90.6 90.84,90.6 92.63,88.81 v4(94.24,88.81)
  L10_SIG4 w0.109: v5(85.12,91.26) 83.57,91.26 83.11,90.8 81.86,90.8 81.53,91.14 77.74,91.14 74.88,88.27 74.88,75.18 73.41,73.71 73.41,72.7 69.38,68.68 54.05,68.68 53.94,68.57 53.94,67.45 53.8,67.31 53.6,67.31 53.46,67.45 53.46,68.57 53.32,68.71 53.12,68.71 52.98,68.57 52.98,67.45 52.84,67.31 52.64,67.31 52.5,67.45 52.5,68.57 52.36,68.71 52.16,68.71 52.02,68.57 52.02,67.45 51.88,67.31 51.68,67.31 51.54,67.45 51.54,68.57 51.4,68.71 51.2,68.71 51.06,68.57 51.06,67.45 50.92,67.31 50.72,67.31 50.58,67.45 50.58,68.57 50.44,68.71 50.24,68.71 50.1,68.57 50.1,67.45 49.96,67.31 49.76,67.31 49.62,67.45 49.62,68.57 49.48,68.71 49.28,68.71 49.14,68.57 49.14,67.45 49,67.31 48.8,67.31 48.66,67.45 48.66,68.57 48.52,68.71 48.32,68.71 48.18,68.57 48.18,67.45 48.04,67.31 47.84,67.31 47.7,67.45 47.7,68.57 47.56,68.71 47.36,68.71 47.22,68.57 47.22,67.45 47.08,67.31 46.88,67.31 46.74,67.45 46.74,68.57 46.6,68.71 46.4,68.71 46.26,68.57 46.26,67.45 46.12,67.31 45.92,67.31 45.78,67.45 45.78,68.57 45.64,68.71 45.24,68.71 45.13,68.6 45.13,67.3 45.02,67.19 44.81,67.19 44.7,67.3 44.7,68.6 44.59,68.71 44.37,68.71 44.26,68.6 44.26,67.3 44.15,67.19 43.93,67.19 43.82,67.3 43.82,68.6 43.71,68.71 43.49,68.71 43.39,68.6 43.39,67.3 43.28,67.19 43.06,67.19 42.95,67.3 42.95,68.6 42.84,68.71 41.96,68.71 41.15,67.9 v8(41.15,61.04)
  BOTTOM w0.173: R216.2 v8(41.15,61.04)
AM57XX_PRU2ETH1_RXD3: length 112.7
  TOP w0.173: U1.AC8 v4(95.04,87.21)
  L3_SIG1 w0.109: v4(95.04,87.21) 94.74,87.51 93.08,87.51 93.07,87.51 92.81,87.51 90.22,90.09 89.76,90.09 88.93,90.93 85.6,90.93 85.42,90.75 v5(83.92,90.75)
  L10_SIG4 w0.109: v5(83.92,90.75) 83.58,90.42 79.06,90.42 75.44,86.79 75.44,75.06 74.93,74.55 74.93,73.36 67.78,66.21 60.94,66.21 60.82,66.09 60.82,65.53 60.69,65.41 60.51,65.41 60.38,65.53 60.38,66.09 60.25,66.21 60.07,66.21 59.94,66.09 59.94,65.53 59.81,65.41 59.63,65.41 59.51,65.53 59.51,66.09 59.38,66.21 59.2,66.21 59.07,66.09 59.07,65.53 58.94,65.41 58.76,65.41 58.63,65.53 58.63,66.09 58.5,66.21 58.32,66.21 58.19,66.09 58.19,65.53 58.07,65.41 57.89,65.41 57.76,65.53 57.76,66.09 57.63,66.21 57.45,66.21 57.32,66.09 57.32,65.53 57.19,65.41 57.01,65.41 56.88,65.53 56.88,66.09 56.76,66.21 56.57,66.21 56.45,66.09 56.45,65.53 56.32,65.41 56.14,65.41 56.01,65.53 56.01,66.09 55.88,66.21 55.7,66.21 55.57,66.09 55.57,65.53 55.45,65.41 55.26,65.41 55.14,65.53 55.14,66.09 55.01,66.21 54.83,66.21 54.7,66.09 54.7,65.53 54.57,65.41 54.39,65.41 54.26,65.53 54.26,66.09 54.13,66.21 52.21,66.21 51.83,66.59 49.43,66.59 49.29,66.46 49.29,65.44 49.19,65.33 48.97,65.33 48.86,65.44 48.86,66.46 48.75,66.57 48.53,66.57 48.42,66.46 48.42,65.44 48.31,65.33 48.09,65.33 47.98,65.44 47.98,66.46 47.87,66.57 47.66,66.57 47.55,66.46 47.55,65.44 47.44,65.33 47.22,65.33 47.11,65.44 47.11,66.46 47,66.57 46.78,66.57 46.67,66.46 46.67,65.44 46.56,65.33 46.35,65.33 46.24,65.44 46.24,66.46 46.13,66.57 45.91,66.57 45.8,66.46 45.8,65.44 45.69,65.33 45.47,65.33 45.36,65.44 45.36,66.46 45.25,66.57 45.04,66.57 44.93,66.46 44.93,65.44 44.82,65.33 44.6,65.33 44.49,65.44 44.49,66.46 44.2,66.75 42.14,66.75 41.83,66.45 41.83,65.83 41.96,65.7 43,65.7 43.13,65.57 43.13,65.39 43,65.26 41.96,65.26 41.83,65.13 41.83,64.95 41.96,64.82 43,64.82 43.13,64.7 43.13,64.51 43,64.39 41.96,64.39 41.83,64.26 41.83,60.57 41.57,60.3 40.62,60.3 v8(38.73,62.18)
  BOTTOM w0.173: R217.2 v8(38.73,62.18)
AM57XX_PRU2ETH1_RXDV: length 112.4
  TOP w0.173: R211.2 39.5,54.06 v8(41.27,55.83) ; U1.AC3 v4(95.04,91.21)
  L3_SIG1 w0.109: v5(92.48,96.68) 92.41,96.6 92.41,94.77 93.47,93.71 93.47,93.1 95.04,91.53 v4(95.04,91.21)
  L10_SIG4 w0.109: v5(92.48,96.68) 92.1,96.3 92.1,93.19 90.77,91.86 90.77,91.22 90.19,90.64 85.66,90.64 85.09,90.08 79.2,90.08 75.79,86.67 75.79,74.93 75.31,74.45 75.31,73.26 65.57,63.52 61.03,63.52 60.49,62.98 53.21,62.98 53.08,63.1 53.08,63.91 52.95,64.03 52.77,64.03 52.65,63.91 52.65,63.1 52.52,62.98 52.34,62.98 52.21,63.1 52.21,63.91 52.08,64.03 51.9,64.03 51.77,63.91 51.77,63.1 51.64,62.98 51.46,62.98 51.34,63.1 51.34,63.91 51.21,64.03 51.03,64.03 50.9,63.91 50.9,63.1 50.77,62.98 50.59,62.98 50.46,63.1 50.46,63.91 50.33,64.03 50.15,64.03 50.02,63.91 50.02,63.1 49.9,62.98 49.72,62.98 49.59,63.1 49.59,63.91 49.46,64.03 49.28,64.03 49.15,63.91 49.15,63.1 49.02,62.98 48.84,62.98 48.71,63.1 48.71,63.91 48.59,64.03 48.41,64.03 48.28,63.91 48.28,63.1 48.15,62.98 47.97,62.98 47.84,63.1 47.84,63.91 47.71,64.03 47.53,64.03 47.4,63.91 47.4,63.1 47.28,62.98 47.09,62.98 46.97,63.1 46.97,63.91 46.84,64.03 46.66,64.03 46.53,63.91 46.53,63.1 46.4,62.98 46.22,62.98 46.09,63.1 46.09,63.91 45.96,64.03 45.78,64.03 45.66,63.91 45.66,63.1 45.53,62.98 45.35,62.98 45.22,63.1 45.22,63.91 45.09,64.03 44.91,64.03 44.78,63.91 44.78,63.1 44.65,62.98 44.47,62.98 44.35,63.1 44.35,63.91 44.22,64.03 44.04,64.03 43.91,63.91 43.91,63.1 43.78,62.98 42.91,62.98 42.56,62.63 42.56,60.6 41.27,59.31 v8(41.27,55.83)
AM57XX_PRU2ETH1_RXER: length 114
  TOP w0.173: U1.B19 112.23,78.01 112.63,77.62 114.54,77.62 117.25,74.91 117.7,74.91 119.84,72.78 120.77,72.78 v3(120.78,72.77) ; R212.2 v8(38.64,56.34)
  L3_SIG1 w0.109: v3(120.78,72.77) 120.77,72.78 v5(119.74,72.78)
  L9_SIG3 w0.114: v5(62.99,58.42) 68.96,64.39 70.94,64.39 85.09,78.54 89.1,78.54 89.95,79.38 96.4,79.38 97.2,80.18 112.51,80.18 113.63,79.06 114.03,79.06 116.56,76.53 117.58,76.53 119.13,74.98 119.13,73.39 v5(119.74,72.78)
  L10_SIG4 w0.109: v5(62.99,58.42) 62.99,57.2 60.45,54.66 60.45,53.82 58.19,51.56 52.2,51.56 51.46,52.3 40.41,52.3 39.5,53.21 39.5,55.48 v8(38.64,56.34)
AM57XX_PRU2ETH1_TXCLK: length 22.6
  TOP w0.173: 78.87,95.97 v3(79.63,95.97) ; U1.AC5 v4(95.04,89.61)
  L3_SIG1 w0.102: v4(95.04,89.61) 94.74,89.91 94.74,90.76 94.54,90.96 94.54,91.38 94.44,91.47
  L3_SIG1 w0.109: 94.44,91.47 92.86,93.05 92.86,93.42 91.64,94.64 91.64,96.42 91.08,96.98 87.83,96.98 87.5,96.65 86.23,96.65 85.72,96.14 82.96,96.14 82.52,96.58 80.24,96.58 v3(79.63,95.97)
AM57XX_PRU2ETH1_TXD0: length 22.9
  TOP w0.173: U1.AC6 v4(95.04,88.81) ; 78.87,94.95 v3(79.63,94.95)
  L3_SIG1 w0.099: 93.94,91.56 93.94,91 94.24,90.71
  L3_SIG1 w0.102: 94.24,90.71 94.36,90.71 94.53,90.54 94.53,89.71 95.04,89.2 v4(95.04,88.81)
  L3_SIG1 w0.109: 93.94,91.56 92.46,93.05 92.46,93.26 91.39,94.33 91.39,95.94 90.73,96.6 87.96,96.6 86.97,95.61 86.08,95.61 85.9,95.79 82.17,95.79 81.34,94.95 v3(79.63,94.95)
AM57XX_PRU2ETH1_TXD1: length 19.7
  TOP w0.173: U1.AC7 v4(95.04,88.01) ; 78.87,92.92 v3(79.63,92.92)
  L3_SIG1 w0.099: v4(95.04,88.01) 94.74,88.31 94.74,89.05 94.47,89.32 93.72,89.32 93.38,89.66 93.38,89.9 93.22,90.06 92.98,90.06 92.47,90.58 91.73,90.58
  L3_SIG1 w0.109: 91.73,90.58 91.12,91.19 90.42,91.19 89.23,92.38 86.84,92.38 85.9,93.32 83.95,93.32 83.55,92.92 v3(79.63,92.92)
AM57XX_PRU2ETH1_TXD2: length 22.5
  TOP w0.173: U1.AC4 v4(95.04,90.41) ; 78.87,96.98 v3(79.63,96.98)
  L3_SIG1 w0.102: 94.74,91.49 94.74,91.09 95.04,90.8 v4(95.04,90.41)
  L3_SIG1 w0.109: 94.74,91.49 93.22,93.02 93.22,93.53 91.95,94.8 91.95,96.83 91.34,97.44 86.44,97.44 85.65,96.65 83.26,96.65 82.4,97.52 80.16,97.52 v3(79.63,96.98)
AM57XX_PRU2ETH1_TXD3: length 19
  TOP w0.173: U1.AD4 v4(94.24,90.41) ; 78.87,93.93 v3(79.63,93.93)
  L3_SIG1 w0.099: 93.73,91.39 93.73,90.92 94.23,90.41
  L3_SIG1 w0.109: v4(94.24,90.41) 94.23,90.41 ; v3(79.63,93.93) 81.03,93.93 82.45,95.36 85.67,95.36 88.19,92.84 89.34,92.84 90.6,91.57 91.52,91.57 91.72,91.78 93.35,91.78 93.73,91.39
AM57XX_PRU2ETH1_TXEN: length 23.4
  TOP w0.173: U1.AB4 v4(95.84,90.41) ; 78.87,98 v3(79.63,98)
  L3_SIG1 w0.102: 95.58,91.37 95.54,91.34 95.54,90.71 v4(95.84,90.41)
  L3_SIG1 w0.109: v3(79.63,98) 79.73,97.9 91.74,97.9 92.53,97.11 92.99,97.11 93.49,96.61 94.27,96.61 95.58,95.31 95.58,91.37
AM57XX_PRU2ETH_MDCLK: length 355.9
  TOP w0.173: U1.C14 v4(111.83,82.41) ; R179.2 v8(30.61,76.15) ; v8(31.15,51.45) 30.61,51.99 R221.2
  L3_SIG1 w0.109: v5(135.64,80.35) 131.17,80.35 130.89,80.07 129.21,80.07 128.97,80.31 128.41,80.31 128,80.71 126.68,80.71 126.52,80.55 125.14,80.55 124.51,81.18 121.67,81.18 121.39,81.45 119.72,81.45 118.36,82.81 117.25,82.81 116.8,83.26 113.07,83.26 112.23,82.41 v4(111.83,82.41) ; v8(30.61,76.15) 29.59,75.14 28.63,75.14 22.23,68.73 22.23,53.47 15.65,46.89 12.09,46.89 7.24,42.03 7.24,37.47 9.78,34.92 13.46,34.92 v5(25.02,23.37)
  L4_SIG2 w0.114: v5(25.02,23.37) 22.73,21.08 22.73,11.3 30.05,3.99 30.69,3.35 47.76,3.35 53.59,9.17 61.11,9.17 61.85,9.91 71.25,9.91 71.99,9.17 102.63,9.17 104.73,7.07 120.49,7.07 120.82,6.74 121.24,6.74 122.04,7.54 139.77,7.54 154.15,21.92 154.15,63.65 149.92,67.88 148.91,67.88 146.56,70.23 146.56,70.99 141.22,76.33 141.22,77.47 139,79.69 136.29,79.69 v5(135.64,80.35)
  L9_SIG3 w0.114: v8(31.15,51.45) 31.15,53.88 33.27,56.01 33.27,63.88 32.51,64.65 32.51,66.43 30.61,68.33 v8(30.61,76.15)
AM57XX_PRU2ETH_MDDATA: length 368.4
  TOP w0.173: U1.D14 v4(111.03,82.41) ; R223.2 29.59,52.09 30.22,51.46 v8(30.43,51.46) ; R181.2 v8(29.59,76.15)
  L3_SIG1 w0.109: v5(135,81.18) 128.85,81.18 128.04,82 127.37,82 126.35,80.98 125.12,80.98 124.63,81.46 121.82,81.46 121.53,81.75 119.92,81.75 118.56,83.11 117.25,83.11 116.89,83.47 112.98,83.47 112.22,82.71 111.71,82.71 111.42,82.41 v4(111.03,82.41)
  L4_SIG2 w0.114: v5(135,81.18) 135.76,81.18 136.81,80.14 139.19,80.14 148.12,71.21 148.12,69.17 148.84,68.45 149.99,68.45 154.94,63.5 154.94,27.18 155.73,26.39 155.73,24.19 154.94,23.41 154.94,21.72 140.44,7.22 127.13,7.22 126.36,6.45 120.7,6.45 120.37,6.78 104.61,6.78 102.51,8.88 53.71,8.88 47.89,3.05 29.33,3.05 27.44,4.95 27.44,6.04 22.35,11.13 22.35,22.48 27.05,27.18 27.05,28.7 25.78,29.97 19.71,29.97 10.72,38.96 10.72,44.78 4.93,50.57 4.93,56.24 7.87,59.18 13.21,59.18 14.99,60.96 17.65,60.96 19.43,62.74 19.43,65.53 25.15,71.25 27.05,71.25 29.59,73.79 v8(29.59,76.15)
  L9_SIG3 w0.114: v8(30.43,51.46) 30.43,55.25 29.69,55.99 29.69,58.01 27.71,59.99 27.71,64.21 29.59,66.09 v8(29.59,76.15)
AM57XX_RGMII1_RD0: length 115.8
  TOP w0.173: U1.A4 113.68,90.02 115.67,92 117.83,92 121.61,95.78 121.61,96.88 v3(122.01,97.27) ; R333.2 56.92,110.06 57.53,110.67 v3(57.53,111.84)
  L3_SIG1 w0.109: v3(57.53,111.84) 56.91,112.47 54.98,112.47 54.74,112.7 54.74,115.25 54.96,115.47 55.84,115.47 55.96,115.35 55.96,114.98 56.07,114.86 56.24,114.86 56.35,114.98 56.35,115.35 56.47,115.47 59.12,115.47 59.35,115.24 59.51,115.24 59.63,115.36 59.63,115.52 59.19,115.96 59.19,116.12 59.31,116.24 59.47,116.24 59.91,115.8 60.07,115.8 60.19,115.92 60.19,116.08 59.75,116.52 59.75,116.68 59.87,116.8 60.03,116.8 60.47,116.36 60.63,116.36 60.75,116.48 60.75,116.64 60.32,117.08 60.32,117.24 60.48,117.4 63.09,117.4 63.93,118.24 64.53,118.24 65.51,119.22 65.67,119.22 65.79,119.1 65.96,119.1 66.07,119.21 66.07,119.38 65.96,119.49 65.96,119.65 66.08,119.77 66.24,119.77 66.45,119.56 66.62,119.56 66.73,119.67 66.73,119.84 66.52,120.05 66.52,120.24 67.09,120.81 75.25,120.81 75.36,120.7 75.36,120.33 75.46,120.22 75.68,120.22 75.79,120.33 75.79,120.7 75.9,120.81 76.12,120.81 76.23,120.7 76.23,120.33 76.34,120.22 76.56,120.22 76.67,120.33 76.67,120.7 76.78,120.81 78,120.81 79.43,119.38 101.44,119.38 102.1,118.72 107.7,118.72 113.23,113.19 113.23,112.65 114.2,111.69 116.87,111.69 124.49,104.07 124.49,99.75 v3(122.01,97.27)
AM57XX_RGMII1_RD1: length 114.8
  TOP w0.173: R334.2 55.52,110.06 56.13,110.67 v3(56.13,111.84) ; U1.B5 112.64,89.62 113.2,89.62 113.2,89.62 113.92,89.62 115.89,91.59 118.05,91.59 122.17,95.71 122.17,96.37 v3(123.42,97.62)
  L3_SIG1 w0.109: v3(56.13,111.84) 53.6,111.84 53.43,112.01 53.43,115.23 54.12,115.92 57.37,115.92 59.31,117.86 62.92,117.86 63.75,118.7 64.36,118.7 67,121.34 78.34,121.34 79.15,120.53 79.59,120.53 79.69,120.42 79.69,120 79.8,119.89 80.02,119.89 80.13,120 80.13,120.42 80.24,120.53 80.46,120.53 80.57,120.42 80.57,120 80.68,119.89 80.9,119.89 81,120 81,120.42 81.11,120.53 81.97,120.53 82.67,119.82 101.25,119.82 102.03,120.6 104.09,120.6 105.49,119.21 107.9,119.21 113.74,113.37 113.74,113.16 114.73,112.17 117.02,112.17 125.4,103.79 125.4,99.6 v3(123.42,97.62)
AM57XX_RGMII1_RD2: length 114.4
  TOP w0.173: v3(120.9,96.83) 120.9,96.35 116.97,92.41 115.47,92.41 113.48,90.41 112.63,90.41 U1.B4 ; R335.2 54.13,110.06 v3(54.58,110.52)
  L3_SIG1 w0.109: v3(120.9,96.83) 121.46,97.39 121.46,98.25 123.44,100.23 123.44,103.48 116.56,110.37 113.96,110.37 110.2,114.13 109.6,114.13 109.09,114.64 109.09,115.47 106.76,117.81 101.6,117.81 101.17,118.24 83.42,118.24 83.12,117.94 79.44,117.94 79,118.39 78.84,118.39 78.4,117.95 78.24,117.95 78.09,118.11 78.09,118.26 78.53,118.7 78.53,118.86 78.07,119.31 77.42,119.31 77.31,119.2 77.31,118.33 77.2,118.22 76.99,118.22 76.88,118.33 76.88,119.2 76.77,119.31 76.55,119.31 76.44,119.2 76.44,118.33 76.33,118.22 76.11,118.22 76,118.33 76,119.2 75.89,119.31 70.29,119.31 70.18,119.2 70.18,118.33 70.07,118.22 69.85,118.22 69.74,118.33 69.74,119.2 69.63,119.31 69.41,119.31 69.3,119.2 69.3,118.33 69.19,118.22 68.98,118.22 68.87,118.33 68.87,119.2 68.76,119.31 68.1,119.31 64.87,116.08 63.11,116.08 62.45,115.42 62.45,115.26 62.82,114.89 62.82,114.74 62.66,114.58 62.51,114.58 62.14,114.95 61.98,114.95 61.83,114.8 61.83,114.65 62.2,114.27 62.2,114.12 62.04,113.97 61.89,113.97 61.52,114.34 61.36,114.34 61.21,114.18 61.21,114.03 61.58,113.66 61.58,113.5 61.43,113.35 61.27,113.35 60.9,113.72 60.75,113.72 60.59,113.56 60.59,113.41 60.86,113.14 60.86,112.99 60.71,112.83 60.55,112.83 60.28,113.1 60.13,113.1 59.55,112.53 59.55,111.68 59,111.13 55.19,111.13 v3(54.58,110.52)
AM57XX_RGMII1_RD3: length 114.2
  TOP w0.173: R336.2 52.73,110.06 v3(53.19,110.52) ; U1.B3 112.64,91.22 113.25,91.22 115.28,93.25 116.66,93.25 119.69,96.28 119.69,97.24 v3(121.15,98.7)
  L3_SIG1 w0.109: v3(53.19,110.52) 53.67,110.04 55.56,110.04 55.67,110.15 55.67,110.51 55.78,110.62 56,110.62 56.11,110.51 56.11,110.15 56.21,110.04 56.43,110.04 56.54,110.15 56.54,110.51 56.65,110.62 56.87,110.62 56.98,110.51 56.98,110.15 57.09,110.04 57.31,110.04 57.42,110.15 57.42,110.51 57.53,110.62 57.74,110.62 57.85,110.51 57.85,110.15 57.96,110.04 58.55,110.04 61.26,112.75 61.74,112.75 62.35,113.36 62.51,113.36 62.71,113.16 62.86,113.16 62.97,113.27 62.97,113.43 62.77,113.64 62.77,113.8 64.59,115.63 65.09,115.63 67.22,117.76 70.9,117.76 71.02,117.87 71.02,118.74 71.14,118.85 71.3,118.85 71.42,118.74 71.42,117.87 71.53,117.76 71.7,117.76 71.81,117.87 71.81,118.74 71.93,118.85 72.09,118.85 72.21,118.74 72.21,117.87 72.33,117.76 72.49,117.76 72.61,117.87 72.61,118.74 72.72,118.85 72.89,118.85 73,118.74 73,117.87 73.12,117.76 73.28,117.76 73.4,117.87 73.4,118.74 73.51,118.85 73.68,118.85 73.79,118.74 73.79,117.87 73.91,117.76 74.07,117.76 74.19,117.87 74.19,118.74 74.31,118.85 74.47,118.85 74.59,118.74 74.59,117.87 74.7,117.76 74.87,117.76 74.98,117.87 74.98,118.74 75.1,118.85 75.26,118.85 75.38,118.74 75.38,117.87 75.75,117.5 83.3,117.5 83.56,117.76 100.99,117.76 101.4,117.35 106.48,117.35 108.54,115.29 108.54,114.55 109.47,113.62 110.09,113.62 113,110.7 113,109.89 113.24,109.65 113.58,109.65 113.82,109.89 116.25,109.89 122.81,103.33 122.81,101.68 121.15,100.01 v3(121.15,98.7)
AM57XX_RGMII1_RXCLK: length 115.4
  TOP w0.173: U1.C5 v4(111.83,89.61) ; v3(60.83,110.57) 60.32,110.06 R328.2
  L3_SIG1 w0.109: v3(60.83,110.57) 62.11,111.85 64.24,111.85 66.08,113.69 66.23,113.69 66.72,113.2 66.87,113.2 67.02,113.36 67.02,113.51 66.52,114.02 66.52,114.18 66.67,114.33 66.83,114.33 67.33,113.82 67.49,113.82 67.64,113.98 67.64,114.13 67.12,114.65 67.12,114.81 67.26,114.95 67.44,114.95 67.95,114.44 68.11,114.44 68.26,114.6 68.26,114.75 67.78,115.23 67.78,115.39 68.12,115.73 74.12,115.73 74.3,115.55 75.44,115.55 75.61,115.73 80.58,115.73 80.86,116.01 97.75,116.01 97.86,115.9 97.86,114.74 97.97,114.64 98.19,114.64 98.29,114.74 98.29,115.9 98.4,116.01 98.62,116.01 98.73,115.9 98.73,114.74 98.84,114.64 99.06,114.64 99.17,114.74 99.17,115.9 99.28,116.01 99.5,116.01 99.61,115.9 99.61,114.74 99.71,114.64 99.93,114.64 100.04,114.74 100.04,115.9 100.15,116.01 100.37,116.01 100.48,115.9 100.48,114.74 100.59,114.64 100.81,114.64 100.92,114.74 100.92,115.9 101.03,116.01 101.24,116.01 101.35,115.9 101.35,114.74 101.46,114.64 101.68,114.64 101.79,114.74 101.79,115.9 101.9,116.01 102.12,116.01 102.23,115.9 102.23,114.74 102.34,114.64 102.55,114.64 102.66,114.74 102.66,115.9 102.77,116.01 102.99,116.01 103.1,115.9 103.1,114.74 103.21,114.64 103.43,114.64 103.54,114.74 103.54,115.9 103.65,116.01 103.87,116.01 103.97,115.9 103.97,114.74 104.08,114.64 104.3,114.64 104.41,114.74 104.41,115.9 104.52,116.01 105.67,116.01 108.88,112.79 109.04,112.63 109.98,112.63 110.34,112.27 110.34,111.36 110.87,110.83 111.61,110.83 111.93,110.5 111.93,110.01 112.63,109.31 113.65,109.31 113.99,108.97 115.66,108.97 121.22,103.41 121.22,101.66 120.24,100.69 120.24,97.87 119.2,96.82 119.2,95.18 119,94.98 119,93.17 116.08,90.25 112.78,90.25 112.14,89.61 v4(111.83,89.61)
AM57XX_RGMII1_RXCTL: length 114.7
  TOP w0.173: v3(122.47,98.54) 121.89,97.97 121.44,97.97 120.4,96.93 120.4,96.42 116.77,92.79 115.37,92.79 113.39,90.81 U1.A3 ; v3(58.93,111.71) 58.93,110.67 58.32,110.06 R329.2
  L3_SIG1 w0.109: v3(58.93,111.71) 58.93,112.49 58.81,112.61 57.83,112.61 57.7,112.73 57.7,112.9 57.81,113 59.19,113 59.31,113.12 59.31,113.28 59.19,113.4 57.87,113.4 57.76,113.51 57.76,113.66 57.87,113.77 58.81,113.77 58.81,113.77 60.09,113.77 60.46,114.15 60.46,114.31 59.98,114.79 59.98,114.95 60.1,115.07 60.26,115.07 60.74,114.59 60.9,114.59 61.02,114.71 61.02,114.87 60.57,115.33 60.57,115.49 60.69,115.61 60.85,115.61 61.3,115.15 61.47,115.15 61.58,115.27 61.58,115.44 61.13,115.89 61.13,116.05 61.25,116.17 61.41,116.17 61.86,115.72 62.03,115.72 62.14,115.83 62.14,116 61.67,116.47 61.67,116.64 61.78,116.75 61.95,116.75 62.42,116.28 62.59,116.28 62.71,116.4 62.71,116.56 62.58,116.69 62.58,116.85 62.69,116.96 62.88,116.96 62.99,116.84 63.15,116.84 63.31,117 64.82,117 68.18,120.35 68.67,120.35 68.78,120.24 68.78,119.9 68.89,119.79 69.11,119.79 69.22,119.9 69.22,120.24 69.33,120.35 69.54,120.35 69.65,120.24 69.65,119.9 69.76,119.79 69.98,119.79 70.09,119.9 70.09,120.24 70.2,120.35 70.42,120.35 70.53,120.24 70.53,119.9 70.64,119.79 70.85,119.79 70.96,119.9 70.96,120.24 71.07,120.35 71.29,120.35 71.4,120.24 71.4,119.9 71.51,119.79 71.73,119.79 71.84,119.9 71.84,120.24 71.95,120.35 72.17,120.35 72.27,120.24 72.27,119.9 72.38,119.79 72.6,119.79 72.71,119.9 72.71,120.24 72.82,120.35 73.04,120.35 73.15,120.24 73.15,119.9 73.26,119.79 73.48,119.79 73.59,119.9 73.59,120.24 73.69,120.35 74.06,120.35 74.66,119.75 78.35,119.75 79.16,118.94 101.15,118.94 101.83,118.27 107.32,118.27 111.28,114.3 111.28,114.07 111.27,114.06 111.27,113.68 111.28,113.68 111.28,113.67 114.07,110.88 116.83,110.88 123.95,103.76 123.95,100.03 v3(122.47,98.54)
AM57XX_RGMII1_TD0: length 23.5
  TOP w0.173: R330.2 121.41,102.32 v3(121.79,101.94) ; U1.D6 v4(111.03,88.81)
  L3_SIG1 w0.109: v4(111.03,88.81) 111.34,89.12 112.04,89.12 112.94,90.02 116.87,90.02 120.45,93.6 120.45,97.21 120.7,97.46 120.7,100.41 121.79,101.5 v3(121.79,101.94)
AM57XX_RGMII1_TD1: length 15.2
  TOP w0.173: U1.B2 112.63,92.01 112.63,93.53 113.46,94.36 113.46,95.48 115.13,97.14 115.61,97.14 116.79,98.33 116.79,102 116.46,102.33 116.46,103.12 116.84,103.5 R331.2
AM57XX_RGMII1_TD2: length 18.4
  TOP w0.173: v3(117.93,101.58) 117.93,101.91 117.73,102.11 117.73,103 117.98,103.25 R327.2 ; U1.C4 v4(111.83,90.41)
  L3_SIG1 w0.109: v3(117.93,101.58) 117.93,98.09 117.04,97.21 117.04,93.6 116.11,92.66 114.78,92.66 113.83,91.72 113.14,91.72 v4(111.83,90.41)
AM57XX_RGMII1_TD3: length 20.7
  TOP w0.173: R332.2 118.67,103.94 v3(118.67,101.58) ; U1.C3 v4(111.83,91.21)
  L3_SIG1 w0.099: 111.96,90.12 111.65,90.12 111.52,90.25 111.52,90.57 111.83,90.89 v4(111.83,91.21)
  L3_SIG1 w0.109: 111.96,90.12 113.27,91.43 115.56,91.43 117.58,93.45 117.58,97.03 118.49,97.94 118.49,101.4 v3(118.67,101.58)
AM57XX_RGMII1_TXCLK: length 21.2
  TOP w0.173: U1.D5 v4(111.03,89.61) ; R325.2 120.27,103.12 v3(120.14,103)
  L3_SIG1 w0.099: v4(111.03,89.61) 111.34,89.92 112.06,89.92
  L3_SIG1 w0.109: 112.06,89.92 113.28,91.14 115.96,91.14 118.05,93.24 118.05,96.72 119,97.66 119,100.41 120.14,101.55 v3(120.14,103)
AM57XX_RGMII1_TXCTL: length 14.5
  TOP w0.173: U1.C2 111.83,92.01 111.83,93.12 113.16,94.44 113.16,96.08 115.37,98.29 115.37,102.74 115.7,103.07 R326.2
AM57XX_RSTOUTN: length 91
  TOP w0.173: v8(159.03,43.56) 158.19,42.72 v8(138.24,42.72) 138.21,42.75 126.65,42.75 126.01,42.11 124.63,42.11 124.08,42.66 R36.2 123.32,42.75 122.3,43.77 122.3,45.93 122.6,46.23 U47.2 ; U1.F23 v4(109.43,74.42)
  L3_SIG1 w0.109: v4(109.43,74.42) v5(109.83,74.17)
  L4_SIG2 w0.114: v5(109.83,74.17) 110.74,74.17 112.06,72.85 115.31,72.85 121.13,67.03 122.72,67.03 138.24,51.51 v8(138.24,42.72)
  BOTTOM w0.173: R916.1 158.62,43.94 159,43.56 v8(159.03,43.56)
AM57XX_RTCK: length 15.9
  TOP w0.173: R426.2 123.19,74.12 v3(122.81,74.12) ; U1.E18 v4(110.23,78.42)
  L3_SIG1 w0.109: v3(122.81,74.12) 122.5,74.43 122.04,74.43 120.52,75.95 119.63,75.95 118.18,77.4 116.26,77.4 116.13,77.27 114.12,77.27 113.74,77.65 111.81,77.65 111.39,78.07 110.58,78.07 v4(110.23,78.42)
AM57XX_SPI1_CS0: length 18.2
  TOP w0.173: U1.D17 v4(111.03,79.22) ; R369.2 v3(126.62,76.28)
  L3_SIG1 w0.099: 111.96,78.92 111.33,78.92 v4(111.03,79.22)
  L3_SIG1 w0.109: v3(126.62,76.28) 125.98,76.28 125.78,76.48 121.92,76.48 119.85,78.55 115.96,78.55 115.82,78.41 114.75,78.41 114.24,78.92 111.96,78.92
AM57XX_SPI1_D1: length 10.1
  TOP w0.173: R377.2 119.38,71.33 117.14,73.56 116.78,73.56 113.93,76.42 U1.A21
AM57XX_SPI1_SCLK: length 17.6
  TOP w0.173: U1.C18 v4(111.83,78.42) ; R367.2 v3(126.62,75.27)
  L3_SIG1 w0.109: v3(126.62,75.27) 123.7,75.27 123.41,75.55 122.04,75.55 119.61,77.98 116.2,77.98 116,77.78 114.63,77.78 113.99,78.42 v4(111.83,78.42)
AM57XX_SPI2_CS0: length 126.6
  TOP w0.173: U1.B24 112.63,73.62 113.66,73.62 115.49,71.79 116.26,71.79 119.38,68.66 120.72,68.66 v8(120.72,68.66)
  L4_SIG2 w0.114: v5(150.06,133.83) 148.95,134.94 148.95,140.4 149.23,140.67 149.23,142.34 v5(149.58,142.7)
  L9_SIG3 w0.114: v8(120.72,68.66) 120.12,69.26 120.12,69.78 123.81,73.47 124.87,73.47 125.18,73.79 125.18,74.61 126.59,76.02 126.59,79.71 128.96,82.07 128.96,84.07 129.43,84.54 130.01,84.54 131.19,85.72 131.19,86.61 130.68,87.12 130.68,88.65 131.96,89.92 132.96,89.92 137.27,94.23 140.34,94.23 143.38,97.28 143.38,106.86 150.72,114.2 150.72,121.49 151.28,122.05 151.28,124.89 152.17,125.77 152.17,129.01 150.06,131.12 v5(150.06,133.83)
  L10_SIG4 w0.109: v5(149.58,142.7) 149,142.11 140.92,142.11 140.01,143.02 129.17,143.02 128.4,142.24 v7(128.4,142.11)
  BOTTOM w0.173: R890.1 v7(128.4,142.11)
AM57XX_SPI2_DIN: length 149.4
  TOP w0.173: U1.G17 v4(108.63,79.22)
  L3_SIG1 w0.109: v4(108.63,79.22) v5(109.03,78.97)
  L4_SIG2 w0.114: v5(147.65,143.07) 147.69,143.07 148.44,143.81 v5(153.26,143.81) ; v5(109.03,78.97) 109.42,79.35 114.76,79.35 114.99,79.58 116.01,79.58 117.37,80.94 117.37,82.2 117.85,82.68 125.2,82.68 130.57,88.05 134.67,88.05 135.9,89.28 135.9,89.77 139.83,93.71 139.83,95.42 140.6,96.18 140.6,97.33 140.01,97.91 140.01,98.79 139.74,99.06 138.94,99.06 138.54,99.45 138.54,103.88 139.24,104.57 140.97,104.57 144.68,108.28 145.75,108.28 152.27,114.81 156.97,114.81 158.2,116.03 v5(163.7,116.03)
  L10_SIG4 w0.109: v5(163.7,116.03) 164.08,116.41 164.08,118.7 163.48,119.31 163.48,124.77 164.5,125.8 164.5,131.28 163.57,132.21 163.57,134.94 162.75,135.76 162.75,141.29 161.8,142.24 158.19,142.24 156.62,143.81 v5(153.26,143.81) ; v5(147.65,143.07) 147.3,142.72 141.12,142.72 140.25,143.59 128.8,143.59 128.36,143.15 126.58,143.15 125.55,142.11 v7(124.33,142.11)
  BOTTOM w0.173: R888.1 v7(124.33,142.11)
AM57XX_SPI2_DOUT: length 128.2
  TOP w0.173: U1.B22 112.23,75.61 112.63,75.22 113.21,75.22 115.93,72.5 116.69,72.5 119.56,69.63 120.53,69.63 v8(120.57,69.59)
  L4_SIG2 w0.114: v8(150.52,134.87) 149.86,135.53 149.86,139.76 150.24,140.14 150.24,142.98 v5(149.91,143.31)
  L9_SIG3 w0.114: v8(150.52,134.87) 150.52,131.14 152.46,129.2 152.46,123.43 151.79,122.77 151.79,114.81 143.76,106.78 143.76,97.02 140.47,93.73 137.18,93.73 133.08,89.63 132.08,89.63 130.98,88.52 130.98,87.24 131.51,86.7 131.51,81.55 129.73,79.76 129.73,78.73 125.48,74.48 125.48,73.53 124.92,72.98 123.95,72.98 v8(120.57,69.59)
  L10_SIG4 w0.109: v5(149.91,143.31) 149.07,143.31 148.18,142.42 141.02,142.42 140.13,143.3 128.92,143.3 128.47,142.86 127.12,142.86 v7(126.36,142.11)
  BOTTOM w0.173: R889.1 v7(126.36,142.11)
AM57XX_SPI2_SCLK: length 9
  TOP w0.173: U1.A26 114.66,70.79 115.7,70.79 119.48,67.01 R684.1
AM57XX_STATUSLED0_GRN: length 92.7
  TOP w0.173: v3(104.98,97.89) 106.29,97.89 106.93,98.53 R732.1 ; U1.N6 v4(103.83,88.81)
  L3_SIG1 w0.099: v4(103.83,88.81) 103.83,89.2 103.53,89.51 103.53,91.42 103.4,91.54 103.4,94.16 103.25,94.31 103.25,94.65 103.76,95.15 103.76,96.64 v5(104.58,97.46) 104.98,97.86 v3(104.98,97.89)
  L4_SIG2 w0.114: v5(104.58,97.46) 105.87,98.75 107.72,98.75 108.48,99.51 108.48,102.03 107.92,102.59 107.92,104.09 106.55,105.46 104.96,105.46 104.07,106.35 102.89,106.35 101.85,107.39 101.85,108.28 103.66,110.09 103.66,113.74 104.29,114.38 104.29,118.39 104.6,118.7 104.6,123.46 v5(104.41,123.66)
  L10_SIG4 w0.109: v5(104.41,123.66) 104.41,123.69 v7(103.86,124.23)
  BOTTOM w0.173: v7(103.86,124.23) 101.81,122.18 101.81,120.92 99.86,118.97 99.86,117.9 95.92,113.95 95.92,112.77 89.86,106.72 88.96,106.72 81.93,99.69 81.93,99.4 80.2,97.66 76.15,97.66 R701.1
AM57XX_STATUSLED0_RED: length 77.2
  TOP w0.173: U1.M3 v4(104.63,91.21) ; 103.89,101.98 103.47,101.57 v3(102.96,101.57) 102.86,101.67 102.86,103.75 104.39,105.28 104.39,106.68 105.12,107.4 105.12,107.84 105,107.96 105,110.8 104.47,111.33 103.5,111.33 102.56,112.28 102.56,112.7 103.07,113.21 103.53,113.21 103.96,113.64 103.96,118.3 103.5,118.77 102.3,118.77 101.98,119.08 101.98,120.48 v8(101.35,121.11)
  L3_SIG1 w0.099: 106.32,98.2 104.27,96.14 104.27,94.22 103.87,93.82 103.87,91.85 104.26,91.46 104.39,91.46 v4(104.63,91.21)
  L3_SIG1 w0.109: 106.32,98.2 106.32,100.41 106.61,100.69 106.61,101.1 106.14,101.57 v3(102.96,101.57)
  BOTTOM w0.173: R698.2 78.92,98.32 80.36,98.32 81.58,99.55 81.58,99.84 88.81,107.07 89.71,107.07 95.56,112.92 95.56,114.1 99.51,118.04 99.51,119.28 v8(101.35,121.11)
AM57XX_STATUSLED0_YEL: length 67.5
  TOP w0.173: 106.3,101.98 106.3,101.84 v8(105.58,101.12) ; U1.M4 v4(104.63,90.41)
  L3_SIG1 w0.099: v4(104.63,90.41) 104.63,90.8 103.6,91.83 103.6,93.84 104.01,94.25 104.01,96.28 106.02,98.29
  L3_SIG1 w0.109: v8(105.58,101.12) 105.16,100.7 105.16,99.9 106.02,99.03 106.02,98.29
  L4_SIG2 w0.114: v5(100.36,120.27) 100.8,119.82 100.8,111.8 99.01,110.01 99.01,106.38 101.78,103.61 102.5,103.61 104.98,101.12 v8(105.58,101.12)
  L10_SIG4 w0.109: v5(100.36,120.27) v7(99.47,120.27)
  BOTTOM w0.173: R694.1 88.67,107.42 89.57,107.42 95.21,113.06 95.21,114.25 98.88,117.91 98.88,119.74 99.42,120.27 v7(99.47,120.27)
AM57XX_STATUSLED1_GRN: length 50.4
  TOP w0.173: R688.1 v3(103.38,98.42) 103.38,95.95 102.64,95.2 U1.P1
  L3_SIG1 w0.109: v3(103.38,98.42) v5(102.95,98.86)
  L4_SIG2 w0.114: v5(102.95,98.86) 102.95,99.52 102.62,99.85 101.3,99.85 100.83,100.31 100.83,102.56 99.33,104.05 v5(99,104.05)
  L10_SIG4 w0.109: v7(89.19,106.21) 89.46,106.21 91,104.67 92.53,104.67 93.09,105.23 93.57,105.23 93.82,104.99 98.07,104.99 v5(99,104.05)
  BOTTOM w0.173: v7(89.19,106.21) 82.28,99.31 82.28,99.25 79.4,96.37 71.48,96.37 70.23,97.62 R710.1
AM57XX_STATUSLED1_RED: length 71.4
  TOP w0.173: U1.N2 103.83,92.01 103.83,94.87 104.5,95.53 104.5,98.09 105.2,98.8 105.2,100.51 105.12,100.6 105.12,101.2 105.03,101.28 105.03,101.98 105.66,102.62 105.66,103.44 105.5,103.61 105.5,104.35 105.66,104.52 105.66,106.12 v3(106.17,106.63)
  L3_SIG1 w0.109: v5(97,110.34) 98.9,108.44 105.15,108.44 106.17,107.42 v3(106.17,106.63)
  L10_SIG4 w0.109: v5(97,110.34) v7(95.71,110.34)
  BOTTOM w0.173: v7(95.71,110.34) 86.06,100.69 85.32,100.69 78.41,93.78 78.41,90.17 77.6,89.36 77.6,83.57 76.58,82.55 71.58,82.55 R707.2
AM57XX_STATUSLED1_YEL: length 45.5
  TOP w0.173: v3(100.1,100.05) R686.1 100.84,98.75 101.55,98.03 101.55,95.96 101.04,95.45 U1.T1
  L3_SIG1 w0.109: v5(100.1,100.71) v3(100.1,100.05)
  L10_SIG4 w0.109: v5(100.1,100.71) 90.12,100.71 89.87,100.46 88.77,100.46 88.09,99.77 79.02,99.77 77.6,98.35 77.6,97.13 76.96,96.49 76.07,96.49 74.96,95.38 72.9,95.38 71.32,93.8 71.32,91.7 v8(71.75,91.27)
  BOTTOM w0.173: R703.1 71.12,90.63 v8(71.75,91.27)
AM57XX_UART2_RXD: length 7.7
  TOP w0.173: R583.2 110.64,63.31 U1.D28
AM57XX_UART2_TXD: length 13.7
  TOP w0.173: R582.2 119.2,65.44 v3(119.18,65.44) ; U1.D26 v4(111.03,72.02)
  L3_SIG1 w0.099: 114.49,71.51 113.31,71.51 113.19,71.39 112.88,71.39 112.76,71.51 111.54,71.51 v4(111.03,72.02)
  L3_SIG1 w0.109: 114.49,71.51 115.44,71.51 116.89,70.05 116.89,67.72 v3(119.18,65.44)
AM57XX_UART3_RXD: length 23
  TOP w0.173: v3(118.75,61.09) 118.11,60.45 115.62,60.45 111.04,65.04 111.04,71.21 U1.D27 ; v3(123.95,61.68) 123.95,62.23 R487.1
  L3_SIG1 w0.109: v3(118.75,61.09) 119.33,61.68 v3(123.95,61.68)
AM57XX_UART3_TXD: length 19.2
  TOP w0.173: v3(120.02,61.09) 119.38,61.72 116.33,61.72 111.31,66.74 111.31,69.45 111.43,69.58 U1.C28 ; v3(122.66,60.51) 122.97,60.2 R486.1
  L3_SIG1 w0.109: v3(120.02,61.09) 122.08,61.09 v3(122.66,60.51)
AM57XX_USB1_DM: length 103.9
  TOP w0.15: v4(95.22,83.2) 95.22,83.2 95.22,83.4 U1.AC12
  L3_SIG1 w0.109: v8(42.88,26.07) 43.03,26.23 43.03,29.52 45.19,31.67 55.42,31.67 62.1,38.35 62.1,56.72 60.27,58.55 60.27,64.74 65.61,70.07 65.61,76.45 70.49,81.33 74.71,81.33 79.31,85.93 80.99,85.93 81.57,85.34 84.48,85.34 84.72,85.1 88.92,85.1 89.97,84.05 91.08,84.05 91.55,83.59 93.62,83.59 93.87,83.84 94.64,83.84 95.22,83.25 v4(95.22,83.2)
  BOTTOM w0.15: L11.1 42.78,25.25 43.03,25.5 43.03,25.92 v8(42.88,26.07)
AM57XX_USB1_DP: length 103.3
  TOP w0.15: U1.AD12 94.83,83.42 v4(94.83,83.21)
  L3_SIG1 w0.109: v8(43.48,26.07) 43.33,26.23 43.33,29.39 45.31,31.37 55.55,31.37 62.41,38.23 62.41,56.85 60.58,58.67 60.58,64.61 65.91,69.95 65.91,76.33 70.61,81.03 74.84,81.03 79.44,85.62 80.86,85.62 81.44,85.04 82.4,85.04 82.47,84.96 82.9,84.96 82.98,85.04 83.31,85.04 83.46,84.89 83.82,84.89 83.97,85.04 84.35,85.04 84.6,84.79 86.28,84.79 86.39,84.68 86.72,84.68 86.83,84.79 87.15,84.79 87.27,84.68 87.59,84.68 87.7,84.79 88.03,84.79 88.14,84.68 88.47,84.68 88.58,84.79 88.8,84.79 89.84,83.75 90.96,83.75 91.42,83.28 93.75,83.28 94,83.53 94.51,83.53 v4(94.83,83.21)
  BOTTOM w0.15: L11.2 43.58,25.25 43.33,25.5 43.33,25.92 v8(43.48,26.07)
AM57XX_USB1_DRVVBUS: length 2.6
  TOP w0.254: U1.AB10 v4(95.84,85.61)
  TOP w0.381: v5(85.98,89.87) v3(86.74,89.87)
  L3_SIG1 w0.254: v5(95.44,85.86) v4(95.84,85.61)
  L3_SIG1 w0.381: v3(86.74,89.87) v5(85.98,89.87)
AM57XX_VIN1B_DATA0: length 110.5
  TOP w0.173: U1.R6 v4(101.44,88.81) ; R260.2 v8(160.78,143.34)
  L3_SIG1 w0.099: v4(101.44,88.81) 101.94,89.32 101.94,91.48
  L3_SIG1 w0.109: 101.94,91.48 101.94,91.79 100.91,92.82 100.91,94.44 v5(101.65,95.18)
  L4_SIG2 w0.114: v8(160.78,143.34) 159.89,142.44 155.22,142.44 153.16,140.39 153.16,139.47 153.28,139.36 154.06,139.36 154.18,139.25 154.18,139.02 154.06,138.9 153.28,138.9 153.16,138.79 153.16,138.56 153.28,138.45 154.06,138.45 154.18,138.33 154.18,138.1 154.06,137.99 153.28,137.99 153.16,137.87 153.16,137.65 153.28,137.53 154.06,137.53 154.18,137.42 154.18,137.19 154.06,137.07 153.28,137.07 153.16,136.96 v5(153.16,131.4)
  L10_SIG4 w0.109: v5(153.16,131.4) 152.83,131.07 152.83,129.68 154.66,127.84 154.66,118.21 153.92,117.47 153.92,117.18 142.74,105.99 133.42,105.99 131.85,104.42 126.36,104.42 123.88,101.94 123.88,99.68 122.16,97.97 120.7,97.97 119.48,96.75 119.48,96.75 118.94,96.22 116.59,96.22 116.18,96.63 113.82,96.63 112.46,95.27 105.11,95.27 104.75,95.63 102.1,95.63 v5(101.65,95.18)
AM57XX_VIN1B_DATA1: length 112.6
  TOP w0.173: U1.T9 v4(100.64,86.41) ; R261.2 v8(164.11,132.29)
  L3_SIG1 w0.109: v5(100.24,86.66) 100.24,86.66 v4(100.64,86.41)
  L4_SIG2 w0.114: v5(149.1,126.7) 149.73,126.7 152.27,129.24 153.42,129.24 154.31,130.13 156.03,130.13 156.16,130.26 156.77,130.26 156.88,130.37 156.88,131.18 157,131.3 157.23,131.3 157.34,131.18 157.34,130.37 157.45,130.26 157.68,130.26 157.8,130.37 157.8,131.18 157.91,131.3 158.14,131.3 158.25,131.18 158.25,130.37 158.37,130.26 158.6,130.26 158.71,130.37 158.71,131.18 158.83,131.3 159.05,131.3 159.17,131.18 159.17,130.37 159.28,130.26 159.51,130.26 159.63,130.37 159.63,131.18 159.74,131.3 159.97,131.3 160.08,131.18 160.08,130.37 160.2,130.26 160.43,130.26 160.54,130.37 160.54,131.18 160.65,131.3 160.88,131.3 161,131.18 161,130.37 161.11,130.26 161.34,130.26 161.45,130.37 161.45,131.18 161.57,131.3 161.8,131.3 161.91,131.18 161.91,130.37 162.03,130.26 162.25,130.26 162.37,130.37 162.37,131.18 162.48,131.3 162.71,131.3 162.83,131.18 162.83,130.37 162.94,130.26 163.7,130.26 164.11,130.66 v8(164.11,132.29)
  L10_SIG4 w0.109: v5(100.24,86.66) 100.63,87.06 100.63,101.01 101.4,101.77 102.18,101.77 103.14,102.74 106.97,102.74 107.57,102.14 112.55,102.14 114.22,103.81 114.22,104.98 122.24,112.99 131.01,112.99 133.83,110.17 137.09,110.17 148.31,121.39 148.31,125.91 v5(149.1,126.7)
AM57XX_VIN1B_DATA2: length 112.7
  TOP w0.173: R263.2 v8(166.65,132.29) ; U1.T6 v4(100.64,88.81)
  L3_SIG1 w0.099: 100.93,91.24 100.93,89.11 v4(100.64,88.81)
  L3_SIG1 w0.109: v5(101.6,98.76) 100.62,97.78 100.62,96.59 100.43,96.39 100.42,96.39 100.37,96.34 100,95.97 100,92.38 100.93,91.46 100.93,91.24
  L4_SIG2 w0.114: v8(166.65,132.29) 166.65,129.06 165.25,127.67 164.86,127.67 164.75,127.78 164.75,128.24 164.63,128.35 164.4,128.35 164.29,128.24 164.29,127.78 164.17,127.67 163.95,127.67 163.83,127.78 163.83,128.24 163.72,128.35 163.49,128.35 163.37,128.24 163.37,127.78 163.26,127.67 163.03,127.67 162.92,127.78 162.92,128.24 162.8,128.35 162.57,128.35 162.46,128.24 162.46,127.78 162.35,127.67 161.71,127.67 161.6,127.55 161.6,126.99 161.49,126.88 161.26,126.88 161.14,126.99 161.14,127.55 161.03,127.67 160.8,127.67 160.69,127.55 160.69,126.99 160.57,126.88 160.34,126.88 160.23,126.99 160.23,127.55 160.11,127.67 159.89,127.67 159.77,127.55 159.77,126.99 159.66,126.88 159.43,126.88 159.31,126.99 159.31,127.55 159.2,127.67 158.97,127.67 158.86,127.55 158.86,126.99 158.74,126.88 158.51,126.88 158.4,126.99 158.4,127.55 158.28,127.67 158.06,127.67 157.94,127.55 157.94,126.99 157.83,126.88 157.6,126.88 157.48,126.99 157.48,127.55 157.37,127.67 157.14,127.67 157.03,127.55 157.03,126.99 156.91,126.88 156.68,126.88 156.57,126.99 156.57,127.55 156.46,127.67 155.24,127.67 154.38,126.8 153.18,126.8 152.81,126.42 151.92,126.42 v5(151.38,126.96)
  L10_SIG4 w0.109: v5(101.6,98.76) 101.6,99.6 102.72,100.72 103.92,100.72 104.8,101.6 106.53,101.6 107.01,101.12 113.01,101.12 113.08,101.19 113.86,101.19 115.8,103.13 116.94,103.13 119.48,105.67 119.48,106 125.46,111.98 130.52,111.98 133.35,109.15 138.96,109.15 141.25,111.44 141.25,112.22 148.34,119.3 149.29,119.3 151.57,121.58 151.57,123.62 150.69,124.49 150.69,126.27 v5(151.38,126.96)
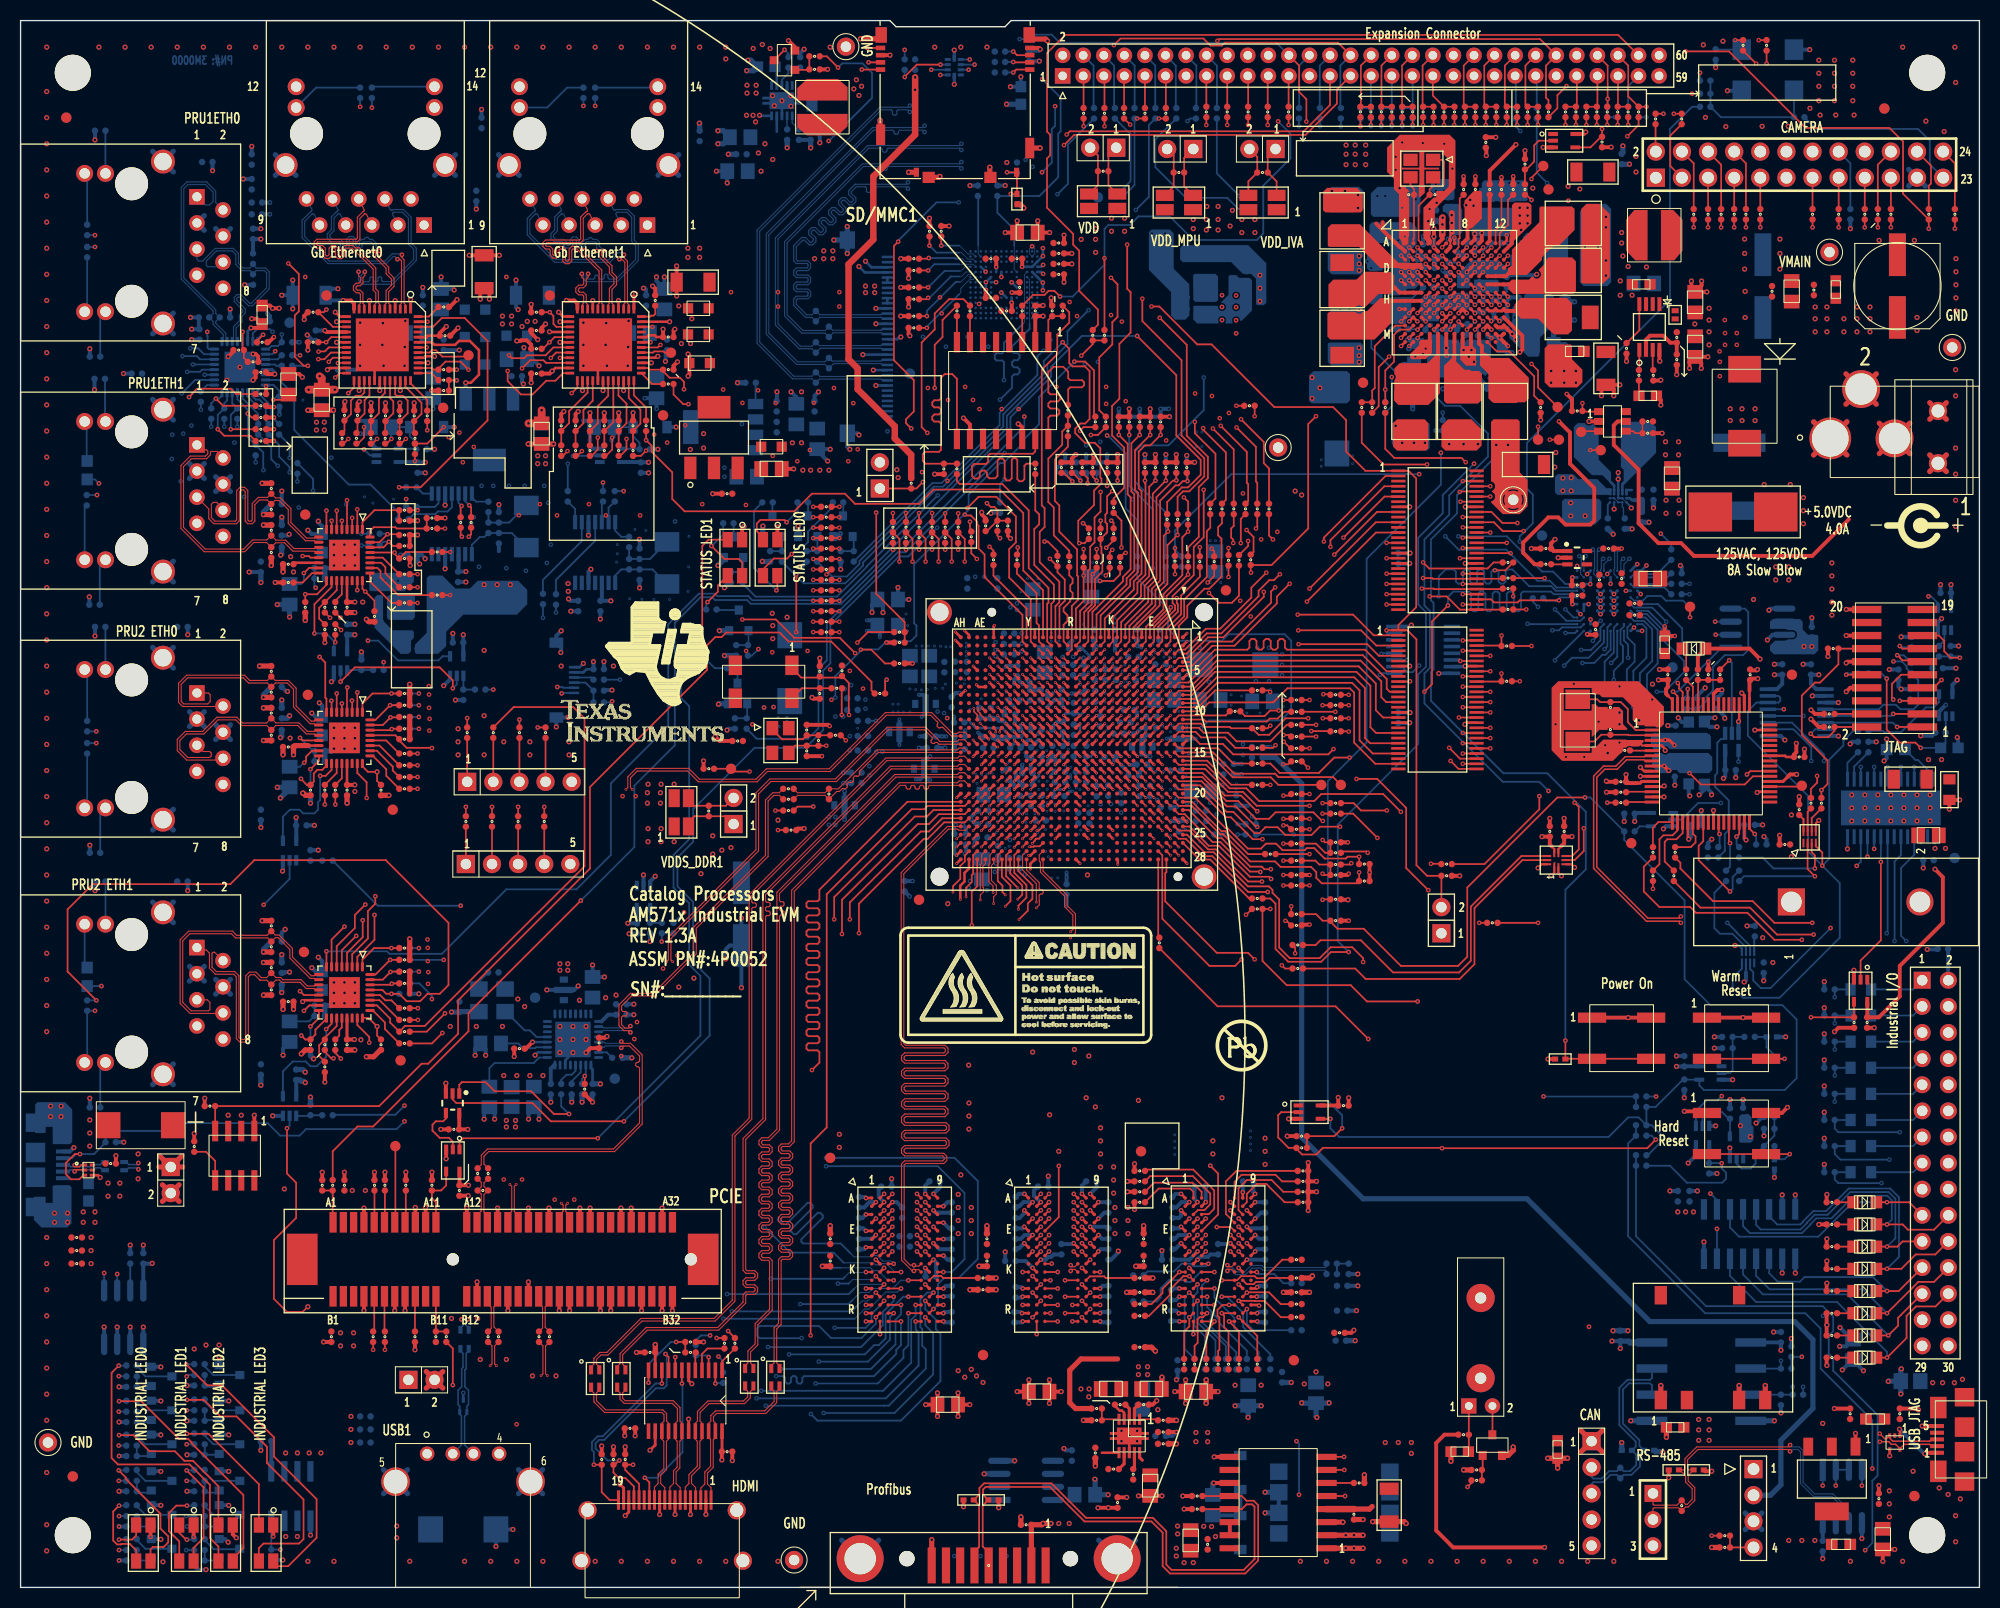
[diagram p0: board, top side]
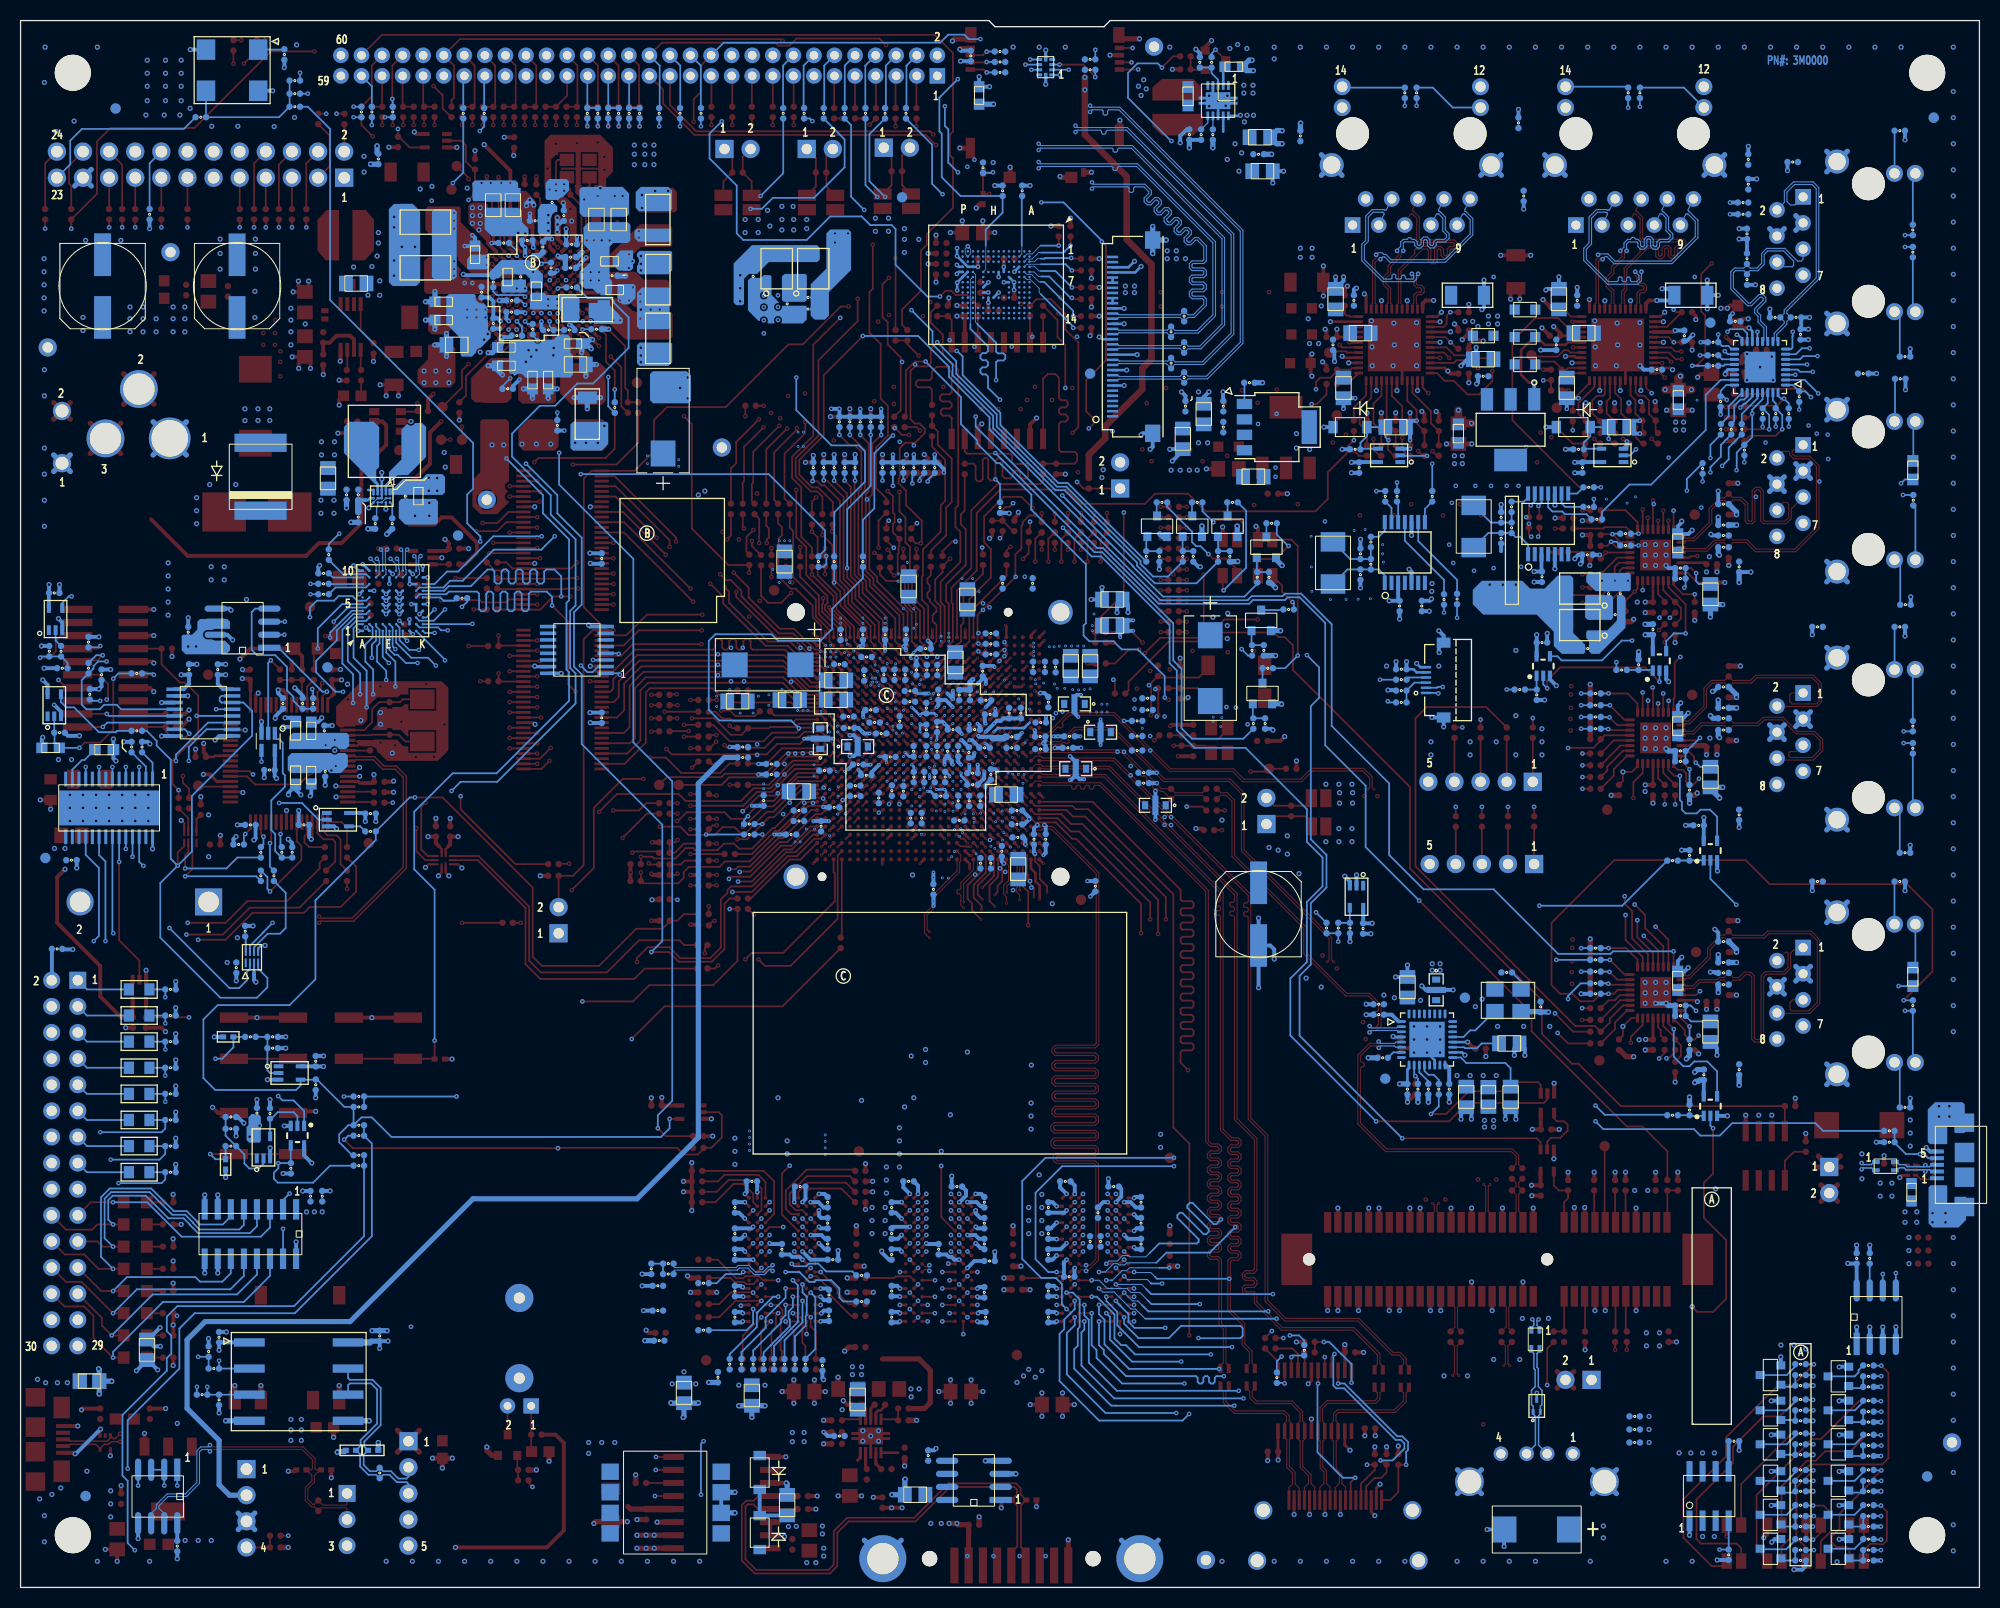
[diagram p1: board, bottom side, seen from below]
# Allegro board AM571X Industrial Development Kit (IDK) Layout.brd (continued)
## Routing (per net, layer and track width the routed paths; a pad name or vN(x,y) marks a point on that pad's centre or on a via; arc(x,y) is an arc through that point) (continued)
AM57XX_VIN1B_DATA3: length 113.1
  TOP w0.173: U1.T7 v4(100.64,88.01) ; R267.2 v8(174.27,132.29)
  L3_SIG1 w0.099: 101.14,91.4 101.14,88.91 100.64,88.4 v4(100.64,88.01)
  L3_SIG1 w0.109: 101.14,91.4 101.14,91.57 100.23,92.49 100.23,95.79 101.14,96.7 101.14,97.54 v5(101.6,98)
  L4_SIG2 w0.114: v8(174.27,132.29) 173.36,131.37 173.36,127.84 171.39,125.88 171.23,125.88 170.69,126.42 170.53,126.42 170.37,126.25 170.37,126.09 170.91,125.56 170.91,125.39 170.74,125.23 170.58,125.23 170.05,125.77 169.88,125.77 169.72,125.61 169.72,125.45 170.26,124.91 170.26,124.75 169.75,124.24 165.99,124.24 165.61,123.86 152.83,123.86 v5(152.02,124.67)
  L10_SIG4 w0.109: v5(101.6,98) 102.03,98.43 102.03,99.55 102.2,99.73 103.45,99.73 104.44,100.72 104.83,100.72 105.02,100.53 105.64,100.53 105.83,100.72 108.94,100.72 109.83,99.82 112.97,99.82 114.6,101.45 116.99,101.45 119.89,104.35 119.89,105.92 125.6,111.64 130.35,111.64 133.17,108.81 139.99,108.81 142.19,111.02 142.19,111.53 142.19,111.53 142.19,111.89 148.15,117.86 149.04,117.86 149.45,118.28 149.45,118.79 151.92,121.26 151.92,122.89 152.02,122.99 v5(152.02,124.67)
AM57XX_VIN1B_DATA4: length 112.8
  TOP w0.173: U1.P6 v4(103.03,88.81) ; R269.2 v8(176.81,132.29)
  L3_SIG1 w0.099: v4(103.03,88.81) 102.15,89.7 102.15,91.54
  L3_SIG1 w0.109: 102.15,91.54 102.15,91.94 101.14,92.94 101.14,94.12 102.13,95.11 102.13,98.91 v5(102.49,99.27)
  L4_SIG2 w0.114: v5(152.36,122.71) 152.97,122.1 156.77,122.1 156.9,122.24 156.9,122.55 157.04,122.68 157.23,122.68 157.36,122.55 157.36,122.24 157.49,122.1 163.04,122.1 163.65,122.71 169.98,122.71 174.24,126.98 174.24,130.71 175.82,132.29 v8(176.81,132.29)
  L10_SIG4 w0.109: v5(102.49,99.27) 102.57,99.34 108.36,99.34 109,98.71 110.69,98.71 110.89,98.91 112.32,98.91 112.67,99.26 112.9,99.26 114.73,101.1 117.12,101.1 117.8,101.78 119.34,101.78 120.42,102.87 120.42,105.98 125.74,111.3 130.18,111.3 133.63,107.85 137.92,107.85 138.55,108.48 141.14,108.48 143.05,110.38 143.05,111.4 146.92,115.27 148.9,115.27 150.6,116.97 150.6,119.45 152.36,121.21 v5(152.36,122.71)
AM57XX_VIN1B_DATA5: length 114.3
  TOP w0.173: U1.R9 v4(101.44,86.41) ; R271.2 v8(179.35,132.29)
  L3_SIG1 w0.109: v5(101.04,86.66) v4(101.44,86.41)
  L4_SIG2 w0.114: v5(149.89,123.13) 151.5,121.52 169.67,121.52 179.35,131.2 v8(179.35,132.29)
  L10_SIG4 w0.109: v5(149.89,123.13) 149.52,122.75 149.52,121.52 149.24,121.24 149.05,121.24 139.54,111.72 139.54,111.15 138.21,109.83 133.66,109.83 130.84,112.65 122.47,112.65 114.58,104.76 114.58,103.68 112.69,101.8 107.43,101.8 106.83,102.4 103.44,102.4 102.53,101.48 101.82,101.48 101,100.66 101,93.26 101.26,93 101.26,91.75 100.96,91.45 100.96,89.56 101.42,89.1 101.42,87.05 v5(101.04,86.66)
AM57XX_VIN1B_DATA6: length 109.6
  TOP w0.173: U1.R5 v4(101.44,89.61) ; R262.1 v8(165.38,132.29)
  L3_SIG1 w0.099: v4(101.44,89.61) 101.73,89.91 101.73,91.43
  L3_SIG1 w0.109: 101.73,91.43 101.73,91.65 100.69,92.69 100.69,95.18 v5(101.73,96.22)
  L4_SIG2 w0.114: v8(165.38,132.29) 165.38,131.53 165.49,131.42 165.95,131.42 166.07,131.3 166.07,131.07 165.95,130.96 165.49,130.96 165.38,130.84 165.38,130.62 165.49,130.5 165.95,130.5 166.07,130.39 166.07,130.16 165.95,130.04 165.49,130.04 165.38,129.93 165.38,129.6 164.81,129.03 164.35,129.03 164.23,129.14 164.23,129.74 164.12,129.85 163.89,129.85 163.77,129.74 163.77,129.14 163.66,129.03 163.43,129.03 163.32,129.14 163.32,129.74 163.2,129.85 162.97,129.85 162.86,129.74 162.86,129.14 162.75,129.03 162.52,129.03 162.4,129.14 162.4,129.74 162.29,129.85 162.06,129.85 161.95,129.74 161.95,129.14 161.83,129.03 161.6,129.03 161.49,129.14 161.49,129.74 161.37,129.85 161.15,129.85 161.03,129.74 161.03,129.14 160.92,129.03 160.69,129.03 160.57,129.14 160.57,129.74 160.46,129.85 160.23,129.85 160.12,129.74 160.12,129.14 160,129.03 159.77,129.03 159.66,129.14 159.66,129.74 159.55,129.85 159.32,129.85 159.2,129.74 159.2,129.14 159.09,129.03 158.86,129.03 158.75,129.14 158.75,129.74 158.63,129.85 158.4,129.85 158.29,129.74 158.29,129.14 158.17,129.03 156.15,129.03 155.47,128.35 154.18,128.35 153.65,127.82 v5(153.65,127.24)
  L10_SIG4 w0.109: v5(101.73,96.22) 104.54,96.22 105.27,95.48 112.17,95.48 113.58,96.9 116.2,96.9 116.55,96.56 118.8,96.56 120.57,98.33 122.04,98.33 123.52,99.81 123.52,102.06 126.34,104.88 130.02,104.88 131.5,106.35 142.62,106.35 153.54,117.27 153.54,117.6 154.1,118.16 154.1,126.78 v5(153.65,127.24)
AM57XX_VIN1B_DATA7: length 110.3
  TOP w0.173: R264.1 v8(167.79,132.29) ; U1.P5 v4(103.03,89.61)
  L3_SIG1 w0.099: v4(103.03,89.61) 102.37,90.28 102.37,91.56
  L3_SIG1 w0.109: 102.37,91.56 102.37,92.07 101.4,93.05 101.4,94.07 102.49,95.17 102.49,97.96 v5(102.65,98.13)
  L4_SIG2 w0.114: v8(167.79,132.29) 168.3,131.78 168.3,129.6 165.53,126.83 164.01,126.83 163.58,126.4 162.89,126.4 162.77,126.28 162.77,125.75 162.66,125.63 162.43,125.63 162.32,125.75 162.32,126.28 162.2,126.4 161.97,126.4 161.86,126.28 161.86,125.75 161.75,125.63 161.52,125.63 161.4,125.75 161.4,126.28 161.29,126.4 161.06,126.4 160.95,126.28 160.95,125.75 160.83,125.63 160.6,125.63 160.49,125.75 160.49,126.28 160.37,126.4 160.14,126.4 160.03,126.28 160.03,125.75 159.92,125.63 159.69,125.63 159.57,125.75 159.57,126.28 159.46,126.4 159.23,126.4 159.12,126.28 159.12,125.75 159,125.63 158.77,125.63 158.66,125.75 158.66,126.28 158.54,126.4 158.32,126.4 158.2,126.28 158.2,125.75 158.09,125.63 157.86,125.63 157.74,125.75 157.74,126.28 157.63,126.4 153.6,126.4 v5(153.22,126.01)
  L10_SIG4 w0.109: v5(102.65,98.13) 102.93,98.4 103.58,98.4 104.12,98.94 107.9,98.94 108.47,98.37 110.86,98.37 111.04,98.55 112.45,98.55 112.8,98.91 113.03,98.91 114.71,100.59 117.14,100.59 117.98,101.43 119.46,101.43 120.93,102.9 120.93,106.01 125.88,110.96 130.03,110.96 133.48,107.51 138.3,107.51 138.93,108.14 142.43,108.14 145.29,111 145.29,112.02 147.52,114.25 148.99,114.25 152.02,117.29 152.02,119.88 152.79,120.66 152.79,124.04 153.22,124.47 v5(153.22,126.01)
AM57XX_VIN1B_DE: length 112
  TOP w0.173: U1.P9 v4(103.03,86.41) ; R273.2 v8(181.89,132.29)
  L3_SIG1 w0.109: v5(103.43,86.66) v4(103.03,86.41)
  L9_SIG3 w0.114: v5(155.18,122.56) 155.18,123.25 163.32,131.39 163.32,132.42 164.34,133.43 180.75,133.43 v8(181.89,132.29)
  L10_SIG4 w0.109: v5(103.43,86.66) 103.05,86.66 102.72,87 102.72,87.3 102.18,87.83 102.18,89.33 102.95,90.09 102.95,93.67 103.32,94.04 105.33,94.04 106.12,94.82 112.65,94.82 114.24,96.42 115.85,96.42 116.43,95.84 119.05,95.84 120.83,97.62 122.29,97.62 124.26,99.59 124.26,101.84 126.49,104.07 133.48,104.07 133.93,104.52 138.83,104.52 139.95,105.64 142.86,105.64 152.29,115.06 153.63,115.06 154.31,115.74 154.31,117.09 155.18,117.97 v5(155.18,122.56)
AM57XX_VIN1B_FLD: length 108.6
  TOP w0.173: U1.P4 v4(103.03,90.41) ; R274.1 v8(180.62,132.29)
  L3_SIG1 w0.099: v4(103.03,90.41) 102.74,90.71 102.74,93.96 102.65,94.06 102.65,95.02 102.89,95.26 102.89,97.43
  L3_SIG1 w0.109: v5(103.25,97.79) 102.89,97.43
  L9_SIG3 w0.114: v8(180.62,132.29) 179.86,133.05 165.35,133.05 164.67,132.36 164.67,130.59 v5(153.16,119.08)
  L10_SIG4 w0.109: v5(153.16,119.08) 152.65,118.57 152.65,117.34 143.06,107.75 139.38,107.75 138.81,107.17 133.29,107.17 129.84,110.63 126.02,110.63 121.31,105.91 121.31,102.8 119.58,101.07 118.19,101.07 117.35,100.23 114.86,100.23 113.18,98.55 112.93,98.55 112.57,98.2 111.2,98.2 111.03,98.03 108.04,98.03 107.94,98.13 106.46,98.13 105.35,97.02 104.02,97.02 v5(103.25,97.79)
AM57XX_VIN1B_HSYNC: length 110.6
  TOP w0.173: U1.N7 v4(103.83,88.01) ; R258.1 v8(162.71,132.29)
  L3_SIG1 w0.109: v5(104.23,88.26) 104.23,88.26 v4(103.83,88.01)
  L4_SIG2 w0.114: v5(155.04,131.15) 155.04,133.48 155.35,133.79 155.89,133.79 156,133.67 156,132.53 156.12,132.42 156.34,132.42 156.46,132.53 156.46,133.67 156.57,133.79 156.8,133.79 156.92,133.67 156.92,132.53 157.03,132.42 157.26,132.42 157.37,132.53 157.37,133.67 157.49,133.79 157.72,133.79 157.83,133.67 157.83,132.53 157.94,132.42 158.17,132.42 158.29,132.53 158.29,133.67 158.4,133.79 158.63,133.79 158.74,133.67 158.74,132.53 158.86,132.42 159.09,132.42 159.2,132.53 159.2,133.67 159.32,133.79 159.55,133.79 159.66,133.67 159.66,132.53 159.77,132.42 160,132.42 160.12,132.53 160.12,133.67 160.23,133.79 160.46,133.79 160.57,133.67 160.57,132.53 160.69,132.42 160.92,132.42 161.03,132.53 161.03,133.67 161.15,133.79 161.37,133.79 161.49,133.67 161.49,132.53 161.6,132.42 161.83,132.42 161.95,132.53 161.95,133.67 162.06,133.79 162.43,133.79 162.71,133.51 v8(162.71,132.29)
  L10_SIG4 w0.109: v5(155.04,131.15) 155.04,125.05 155.62,124.48 155.62,117.77 155.06,117.22 155.06,116.67 155.4,116.33 155.4,115.71 154.2,114.51 152.21,114.51 142.35,104.65 140.59,104.65 139.95,104.01 134.11,104.01 133.73,103.63 129.41,103.63 127.48,101.71 126.45,101.71 125.53,100.79 125.53,99.42 122.75,96.65 121.41,96.65 114.27,89.51 112.88,89.51 112.52,89.15 111.22,89.15 110.74,88.68 108.43,88.68 107.71,89.4 106.89,89.4 106.17,88.68 105.2,88.68 104.79,88.26 v5(104.23,88.26)
AM57XX_VIN1B_PCLK: length 114.9
  TOP w0.173: U1.N9 v4(103.83,86.41) ; R265.2 v8(169.19,132.29)
  L3_SIG1 w0.109: v5(104.23,86.66) 104.23,86.66 v4(103.83,86.41)
  L4_SIG2 w0.114: v5(149.73,125.31) 149.98,125.56 154.46,125.56 155.04,124.97 165.61,124.97 169.19,128.55 169.19,129.01 169.3,129.13 170.35,129.13 170.46,129.24 170.46,129.47 170.35,129.59 169.3,129.59 169.19,129.7 169.19,129.93 169.3,130.04 170.4,130.04 170.51,130.16 170.51,130.39 170.4,130.5 169.3,130.5 169.19,130.62 169.19,130.84 169.3,130.96 170.37,130.96 170.48,131.07 170.48,131.3 170.37,131.42 169.3,131.42 169.19,131.53 v8(169.19,132.29)
  L10_SIG4 w0.109: v5(149.73,125.31) 149.73,124.37 150.67,123.42 150.67,121.95 149.2,120.48 148.93,120.48 139.87,111.43 139.87,111.01 138.35,109.49 133.52,109.49 130.69,112.31 125.32,112.31 119.07,106.07 119.07,105.74 116.92,103.59 115.77,103.59 113.74,101.55 112.95,101.55 112.86,101.46 107.29,101.46 106.76,101.99 103.51,101.99 101.22,99.69 101.22,93.43 101.87,92.78 101.87,87.78 102.49,87.16 102.49,86.93 103.13,86.28 103.85,86.28 v5(104.23,86.66)
AM57XX_VIN1B_VSYNC: length 115.1
  TOP w0.173: R257.1 v8(159.77,143.34) ; U1.R4 v4(101.44,90.41)
  L3_SIG1 w0.109: v5(101.6,97.21) 101.6,96.65 100.46,95.51 100.46,92.59 101.44,91.61 v4(101.44,90.41)
  L4_SIG2 w0.114: v5(152.27,132.29) 152.27,137.46 152.16,137.57 151.27,137.57 151.16,137.69 151.16,137.92 151.27,138.03 152.16,138.03 152.27,138.14 152.27,138.37 152.16,138.49 151.27,138.49 151.16,138.6 151.16,138.83 151.27,138.94 152.16,138.94 152.27,139.06 152.27,139.29 152.16,139.4 151.27,139.4 151.16,139.52 151.16,139.74 151.27,139.86 152.16,139.86 152.27,139.97 152.27,140.2 152.16,140.32 151.27,140.32 151.16,140.43 151.16,140.66 151.27,140.77 152.16,140.77 152.91,141.52 152.91,142.24 154.01,143.34 v8(159.77,143.34)
  L10_SIG4 w0.109: v5(101.6,97.21) 102.16,96.65 105.44,96.65 105.87,96.21 107.87,96.21 108.07,96.42 108.92,96.42 109.29,96.04 111.79,96.04 113.89,98.14 113.89,98.78 114.99,99.88 117.47,99.88 118.31,100.72 119.7,100.72 121.69,102.7 121.69,105.82 124.16,108.29 130.29,108.29 131.75,106.84 139.35,106.84 139.9,107.39 143.18,107.39 153.16,117.37 153.16,117.73 153.72,118.29 153.72,126.12 152.83,127.02 152.83,128.6 151.61,129.82 151.61,131.63 v5(152.27,132.29)
AM57XX_VIN2A_DE0: length 174.6
  TOP w0.173: R119.2 v8(50.29,83.65) ; R670.1 v3(112.52,102.36) 111.53,101.37 111.53,97.61 110.78,96.85 110.78,95.52 108.63,93.37 108.63,92.01 108.24,91.62 U1.G2 ; R847.1 v3(132.33,142.24)
  L3_SIG1 w0.109: v5(112.37,130.76) 112.85,130.76 113.31,131.22 117.15,131.22 118.27,132.33 120.04,132.33 122,134.29 126.26,134.29 126.61,134.63 126.61,135.62 127.84,136.86 131.22,136.86 132.82,138.46 132.82,141.76 v3(132.33,142.24) ; v3(112.52,102.36) v5(112.52,103.66) ; v5(76.54,128.57) 80.37,128.57 81.29,129.5 83.66,129.5 84.58,128.57 85.67,128.57 86.89,129.8 97.36,129.8 98.12,129.04 100.66,129.04 102.87,126.83 106.63,126.83 107.82,125.63 107.82,125.18 v5(112.52,120.48)
  L4_SIG2 w0.114: v5(112.37,130.76) 112.37,129.51 112.8,129.08 112.8,122.66 112.52,122.38 v5(112.52,120.48) 112.52,115.52 114.59,113.45 114.59,109.26 114.34,109.01 114.18,109.01 112.95,107.79 112.95,105.28 112.52,104.85 v5(112.52,103.66) ; v8(50.29,83.65) 50.97,84.33 52.45,84.33 52.7,84.07 56.64,84.07 61.15,88.58 61.15,98.26 70.09,107.2 70.09,112.87 70.42,113.21 70.42,122.46 v5(76.54,128.57)
AM57XX_VIN2A_HSYNC0: length 172.3
  TOP w0.173: U1.G1 108.23,93.38 110.36,95.51 110.36,96.98 111.18,97.79 111.18,102.29 v3(111.59,102.7) 111.59,103.29 R672.1 ; R118.2 v8(48.51,84.41) ; R849.1 v3(136.4,142.24)
  L3_SIG1 w0.109: v5(115.57,126.16) 116.26,126.16 122.68,132.59 129.72,132.59 132.36,135.23 132.36,136.3 133.11,137.05 134.02,137.05 135.48,138.51 135.48,140.31 136.63,141.45 136.63,142.01 v3(136.4,142.24) ; v5(107.26,125.56) 106.5,126.32 102.97,126.32 101.09,128.2 98.71,128.2 98.42,127.92 96.94,127.92 95.57,129.29 90.3,129.29 89.82,128.8 86.31,128.8 85.47,127.97 78.46,127.97 78.36,128.07 75.34,128.07 v5(74.87,128.54) ; v5(110.82,104.04) 110.82,103.48 v3(111.59,102.7)
  L4_SIG2 w0.114: v5(107.26,125.56) 107.56,125.26 107.56,115.38 107.26,115.08 107.26,113.78 108.38,112.65 108.38,111.64 108,111.26 108,108.03 110.82,105.21 v5(110.82,104.04) ; v5(74.87,128.54) 69.09,122.76 69.09,106.99 60.85,98.75 60.85,88.79 57.23,85.17 49.28,85.17 v8(48.51,84.41)
  L10_SIG4 w0.109: v5(115.57,126.16) 108.79,126.16 108.18,125.56 v5(107.26,125.56)
AM57XX_VOUT1_D0: length 37.5
  TOP w0.173: v3(127.38,101.22) 127.38,101.85 132.63,107.1 U103.4 ; U1.F11 v4(109.43,84.81)
  L3_SIG1 w0.109: v3(127.38,101.22) 126.62,100.46 126.62,99.31 123.7,96.39 123.36,96.39 v5(121.79,94.82) ; v5(109.83,85.06) v4(109.43,84.81)
  L10_SIG4 w0.109: v5(109.83,85.06) 109.91,85.15 111.79,85.15 112.32,85.68 112.32,86.21 113.44,87.33 114.78,87.33 115.09,87.03 116.71,87.03 117.37,87.69 117.37,89.59 121.79,94.01 v5(121.79,94.82)
AM57XX_VOUT1_D1: length 39
  TOP w0.173: v3(126.75,101.73) 126.75,102.11 132.74,108.1 U103.2 ; U1.G10 v4(108.63,85.61)
  L3_SIG1 w0.109: v5(109.03,85.86) v4(108.63,85.61) ; v5(121.28,94.44) 121.28,95.46 122.63,96.8 123.47,96.8 126.11,99.44 126.11,101.09 v3(126.75,101.73)
  L10_SIG4 w0.109: v5(121.28,94.44) 121.28,94.06 116.99,89.77 116.99,87.84 116.79,87.63 115.01,87.63 114.94,87.71 113.41,87.71 112.04,86.34 112.04,85.91 111.58,85.45 109.45,85.45 v5(109.03,85.86)
AM57XX_VOUT1_D2: length 32.8
  TOP w0.173: v3(125.35,97.16) 131.8,103.6 U103.11 ; U1.F10 v4(109.43,85.61)
  L3_SIG1 w0.109: v5(109.83,85.86) v4(109.43,85.61) ; v5(124.59,96.65) 124.84,96.65 v3(125.35,97.16)
  L10_SIG4 w0.109: v5(109.83,85.86) 111.92,87.95 114.64,87.95 120.75,94.06 120.75,94.54 121.68,95.48 123.03,95.48 124.2,96.65 v5(124.59,96.65)
AM57XX_VOUT1_D3: length 35.2
  TOP w0.173: v3(125.09,95.89) 131.81,102.6 U103.13 ; U1.G11 v4(108.63,84.81)
  L3_SIG1 w0.109: v5(124.33,95.89) v3(125.09,95.89) ; v5(109.03,85.06) v4(108.63,84.81)
  L10_SIG4 w0.109: v5(124.33,95.89) 124.33,95 120.85,91.52 120.85,90.69 117.38,87.22 117.38,86.81 115.04,84.46 114.14,84.46 113.72,84.89 110.26,84.89 110.01,84.64 109.46,84.64 v5(109.03,85.06)
AM57XX_VOUT1_D4: length 28.5
  TOP w0.173: U1.E9 v4(110.23,86.41) ; U103.25 v3(132.84,96.6)
  L3_SIG1 w0.099: v4(110.23,86.41) 110.74,86.92 111.97,86.92
  L3_SIG1 w0.109: v3(132.84,96.6) 130.68,96.6 124.53,90.45 122.58,90.45 119.64,87.51 118.27,87.51 117.82,87.05 117.54,87.05 117.21,87.05 117.08,86.92 111.97,86.92
AM57XX_VOUT1_D5: length 32.9
  TOP w0.173: U1.F9 v4(109.43,86.41) ; v3(127.76,100.46) 131.91,104.6 U103.9
  L3_SIG1 w0.109: v3(127.76,100.46) 127.76,100.41 127.3,99.95 v5(127.25,99.95) ; v5(109.83,86.66) v4(109.43,86.41)
  L10_SIG4 w0.109: v5(127.25,99.95) 127.02,99.95 122.94,95.86 121.59,95.86 120.32,94.59 120.32,94.14 114.4,88.22 111.39,88.22 v5(109.83,86.66)
AM57XX_VOUT1_D6: length 34
  TOP w0.173: U103.6 132.65,106.1 v3(128.65,102.11) ; U1.F8 v4(109.43,87.21)
  L3_SIG1 w0.109: v3(128.65,102.11) 128.65,102.08 128.17,101.6 v5(128.14,101.6) ; v5(109.83,87.46) v4(109.43,87.21)
  L10_SIG4 w0.109: v5(109.83,87.46) 110.97,88.6 114.3,88.6 119.96,94.26 119.96,94.72 121.54,96.3 122.88,96.3 126.03,99.45 126.03,100.82 126.31,101.09 127.68,101.09 128.14,101.55 v5(128.14,101.6)
AM57XX_VOUT1_D7: length 30.9
  TOP w0.173: U1.E7 v4(110.23,88.01) ; U103.15 v3(132.84,101.6)
  L3_SIG1 w0.109: v4(110.23,88.01) 110.74,88.52 111.62,88.52 111.62,88.52 114.22,88.52 115.1,89.4 117.3,89.4 117.43,89.54 117.49,89.54 117.88,89.54 122.4,94.06 126.03,94.06 128.79,96.81 128.79,98.39 132,101.6 132.84,101.6 v3(132.84,101.6)
AM57XX_VOUT1_D8: length 29.3
  TOP w0.173: U1.E8 v4(110.23,87.21) ; U103.21 v3(132.84,98.6)
  L3_SIG1 w0.109: v4(110.23,87.21) 110.74,87.72 114.73,87.72 115.49,88.48 116.62,88.48 116.62,88.47 116.64,88.47 116.97,88.14 117.47,88.14 117.85,88.52 118.95,88.52 123.04,92.61 125.73,92.61 131.72,98.6 v3(132.84,98.6)
AM57XX_VOUT1_D9: length 27.3
  TOP w0.173: U1.D9 v4(111.03,86.41) ; U103.27 v3(132.84,95.6)
  L3_SIG1 w0.099: v4(111.03,86.41) 111.33,86.71 112.05,86.71
  L3_SIG1 w0.109: v3(132.84,95.6) 130.73,95.6 124.66,89.54 122.43,89.54 122.41,89.52 122.19,89.52 119.84,87.17 118.41,87.17 117.95,86.71 112.05,86.71
AM57XX_VOUT1_D10: length 29.1
  TOP w0.173: U1.D7 v4(111.03,88.01) ; U103.18 v3(132.84,100.1)
  L3_SIG1 w0.099: v4(111.03,88.01) 111.42,88.01 111.71,88.31 112.04,88.31
  L3_SIG1 w0.109: v3(132.84,100.1) 131.68,100.1 129.18,97.61 129.18,96.65 126.22,93.68 122.81,93.68 118.33,89.2 117.63,89.2 117.57,89.2 117.44,89.06 115.22,89.06 114.46,88.31 112.04,88.31
AM57XX_VOUT1_D11: length 27.8
  TOP w0.173: U1.D8 v4(111.03,87.21) ; U103.23 v3(132.84,97.6)
  L3_SIG1 w0.099: 111.96,87.51 111.83,87.51 111.33,87.51 v4(111.03,87.21)
  L3_SIG1 w0.109: v3(132.84,97.6) 131.2,97.6 125.85,92.26 123.16,92.26 119.09,88.18 117.99,88.18 117.54,87.73 116.91,87.73 116.69,87.51 111.96,87.51 111.96,87.51
AM57XX_VOUT1_D12: length 27.5
  TOP w0.173: U1.A5 114.15,89.21 116.15,91.21 119.3,91.21 119.51,91.41 119.51,92.05 119.71,92.25 119.99,92.25 120.2,92.05 120.2,91.41 120.4,91.21 120.69,91.21 120.89,91.41 120.89,92.05 121.09,92.25 121.38,92.25 121.58,92.05 121.58,91.41 121.78,91.21 122.07,91.21 122.27,91.41 122.27,92.05 122.47,92.25 122.76,92.25 122.96,92.05 122.96,91.41 123.16,91.21 130.75,91.21 132.85,89.11 U102.9
AM57XX_VOUT1_D13: length 26
  TOP w0.173: U1.C6 v4(111.83,88.81) ; v3(124.2,94.62) 129.58,94.62 131.59,92.61 U102.2
  L3_SIG1 w0.109: v3(124.2,94.62) 122.2,94.62 117.63,90.05 117.39,90.05 117.06,89.72 113.01,89.72 112.1,88.81 v4(111.83,88.81)
AM57XX_VOUT1_D14: length 25.1
  TOP w0.173: U1.C8 v4(111.83,87.21) ; U102.6 132.1,90.61 130.96,91.74 v3(124.28,91.74)
  L3_SIG1 w0.109: v3(124.28,91.74) 123.39,91.74 119.49,87.85 118.13,87.85 117.68,87.39 117.06,87.39 116.88,87.21 v4(111.83,87.21)
AM57XX_VOUT1_D15: length 25.4
  TOP w0.173: v3(124.26,93.09) 130.36,93.09 131.84,91.61 U102.4 ; U1.C7 v4(111.83,88.01)
  L3_SIG1 w0.109: v3(124.26,93.09) 122.73,93.09 118.5,88.86 117.71,88.86 117.58,88.73 115.31,88.73 114.6,88.01 v4(111.83,88.01)
AM57XX_VOUT1_D16: length 25.1
  TOP w0.173: U1.B7 112.64,88.02 113.59,88.02 116.25,90.68 130.53,90.68 132.86,88.35 132.86,87.41 133.16,87.11 U102.13
AM57XX_VOUT1_D17: length 26.5
  TOP w0.173: U1.B8 112.63,87.21 113.9,87.21 116.28,89.59 130.13,89.59 131.8,87.92 131.8,85.32 132.51,84.61 U102.18
AM57XX_VOUT1_D18: length 24.6
  TOP w0.173: U102.15 132.81,86.11 132.33,86.59 132.33,88.14 130.32,90.14 116.33,90.14 113.8,87.62 U1.A7
AM57XX_VOUT1_D19: length 26.7
  TOP w0.173: U1.A8 113.93,86.81 116.16,89.05 129.92,89.05 131.27,87.7 131.27,83.66 131.82,83.11 U102.21
AM57XX_VOUT1_D20: length 26.9
  TOP w0.173: U102.11 135.1,88.11 v3(135.13,88.14) ; U1.C9 v4(111.83,86.41)
  L3_SIG1 w0.109: v3(135.13,88.14) 135.02,88.14 133.98,89.18 122.33,89.18 119.98,86.83 118.55,86.83 118.01,86.3 115.24,86.3 115.09,86.44 113.25,86.44 113.02,86.21 112.04,86.21 v4(111.83,86.41)
AM57XX_VOUT1_D21: length 27.5
  TOP w0.173: U102.25 131.5,81.11 130.22,82.39 130.22,87.26 129.49,87.99 116.37,87.99 114.4,86.02 U1.A9
AM57XX_VOUT1_D22: length 28.3
  TOP w0.173: U102.23 131.25,82.11 130.74,82.61 130.74,87.48 129.7,88.52 116.33,88.52 114.22,86.41 112.63,86.41 U1.B9
AM57XX_VOUT1_D23: length 27.8
  TOP w0.173: U102.27 131.75,80.11 129.69,82.17 129.69,87.04 129.28,87.45 123.2,87.45 121.83,86.08 115.58,86.08 114.72,85.21 U1.A10
AM57XX_VOUT1_DE: length 8.4
  TOP w0.173: U1.B10 112.63,85.61 114.54,85.61 116.17,87.25 R634.2
AM57XX_VOUT1_HSYNC: length 12.9
  TOP w0.173: R636.2 v3(122.81,86.31) ; U1.C11 v4(111.83,84.81)
  L3_SIG1 w0.109: v3(122.81,86.31) 122.25,85.75 122.15,85.75 121.59,85.19 116.67,85.19 116.48,85.01 112.03,85.01 v4(111.83,84.81)
AM57XX_VOUT1_PCLK: length 18
  TOP w0.173: U1.D11 v4(111.03,84.81) ; v3(126.7,86.87) 127.33,86.87 R565.2
  L3_SIG1 w0.109: v4(111.03,84.81) 111.31,85.09 111.61,85.09 111.79,85.27 116.28,85.27 116.61,85.6 121.52,85.6 122.37,86.45 122.37,86.49 122.7,86.82 124.71,86.82 125.04,87.15 126.01,87.15 126.28,86.87 v3(126.7,86.87)
AM57XX_VOUT1_VSYNC: length 26.4
  TOP w0.173: U1.E11 v4(110.23,84.81)
  L3_SIG1 w0.109: v5(128.52,88.65) 127.97,88.09 121.8,88.09 120.2,86.5 118.69,86.5 118.15,85.96 117.87,85.96 116.13,85.96 115.8,85.63 111.86,85.63 111.52,85.3 110.72,85.3 v4(110.23,84.81)
  L10_SIG4 w0.109: v7(132.33,90.8) 130.68,90.8 v5(128.52,88.65)
  BOTTOM w0.173: v7(132.33,90.8) 132.39,90.86 U104.4
AM571X_PRU1ETH1_COL: length 389.2
  TOP w0.173: v3(111.86,95.33) 111.81,95.28 111.81,95.01 110.24,93.44 110.24,92.02 U1.E2 ; R148.2 v3(41.78,100.71) ; R743.2 v3(103.38,142.11)
  L3_SIG1 w0.109: v5(71.12,135.76) 71.88,136.53 73.72,136.53 75.5,138.3 76.58,138.3 77.02,137.87 78.83,137.87 80.52,139.56 85.76,139.56 86.1,139.89 96.73,139.89 97.74,140.9 100.45,140.9 101.66,142.11 v3(103.38,142.11) ; v3(41.78,100.71) v5(38.73,100.71) ; v5(113.87,97.36) 113.61,97.1 113.61,96.7 112.24,95.33 v3(111.86,95.33)
  L4_SIG2 w0.114: v5(71.12,135.76) 68.07,132.72 68.07,130.67 66.42,129.02 66.42,114.53 65.28,113.39 65.28,112.01 64.62,111.36 64.62,110.34 63.88,109.6 63.88,108.33 63.45,107.9 60.86,107.9 60.45,108.3 55.7,108.3 54.48,107.08 41.04,107.08 38.73,104.77 38.73,104.52 39.12,104.13 39.12,101.1 v5(38.73,100.71) ; v5(120.8,83.64) 120.03,83.64 117.37,86.3 117.37,96.01 116.03,97.36 v5(113.87,97.36)
  L9_SIG3 w0.114: v5(38.73,100.71) 38.49,100.71 37.2,99.42 37.2,98.06 38.48,96.77 38.48,95.22 37.49,94.23 37.49,90.26 35.03,87.8 35.03,80.47 33.15,78.59 31.32,78.59 29.15,76.42 29.15,73.22 28.44,72.51 28.44,65.6 27.05,64.21 27.05,59.66 28.8,57.91 28.8,56.01 29.03,55.78 29.03,51.87 31.78,49.12 31.78,42.01 35,38.79 35,33.71 39.62,29.08 46.25,29.08 49.15,26.19 49.15,20.07 56.7,12.52 57.75,12.52 58.27,13.03 59.41,13.03 59.66,12.78 66.47,12.78 67.02,13.32 74.01,13.32 74.41,13.72 76.73,13.72 77.85,12.6 95.43,12.6 96.27,11.76 101.78,11.76 103.53,13.51 105.89,13.51 106.5,12.9 115.54,12.9 116.15,13.51 124.41,13.51 131.57,20.68 131.57,48.56 127.23,52.91 127.23,56.97 126.14,58.06 126.14,59.39 118.24,67.28 118.24,70.59 120.8,73.15 v5(120.8,83.64)
AM571X_PRU1ETH1_TXD0: length 89.7
  TOP w0.173: R576.2 v3(118.24,114.94) ; R856.1 157.35,142.24 v3(156.26,141.15) ; U1.F4 v4(109.43,90.41) ; R125.2 v3(112.27,98.55)
  L3_SIG1 w0.099: 109.73,94.09 109.73,91.06 109.43,90.76 v4(109.43,90.41)
  L3_SIG1 w0.109: v5(119.79,123.47) 119.79,127.66 123.09,130.96 130.17,130.96 136.77,137.56 139.53,137.56 141.07,139.1 141.07,139.35 141.55,139.83 142.72,139.83 143.74,138.81 151.89,138.81 153.77,140.69 155.8,140.69 v3(156.26,141.15) ; v5(112.75,100.31) 112.75,99.06 112.27,98.58 v3(112.27,98.55) 111.81,98.09 111.81,96.67 111.54,96.4 111.54,95.9 109.73,94.09 ; v3(118.24,114.94) v5(117.73,115.44)
  L4_SIG2 w0.114: v5(112.75,100.31) 112.75,101.91 114.73,103.89 114.73,105.31 116.2,106.78 116.2,112.01 117.12,112.93 117.12,114.83 v5(117.73,115.44) 117.73,118.57 118.88,119.72 118.88,122.57 v5(119.79,123.47)
AM571X_PRU1ETH1_TXD1: length 94.4
  TOP w0.173: U1.D2 111.03,92.01 111.03,93.39 112.55,94.9 112.55,95.62 112.45,95.72 v3(112.45,96.22) ; R855.1 v3(154.31,142.24) ; v3(125.98,113.92) 125.22,113.16 125.22,103 121.67,99.44 R126.2 119.63,98.73 v3(119.66,98.7)
  L3_SIG1 w0.109: v3(154.31,142.24) 154.31,141.73 151.77,139.19 144.15,139.19 143.17,140.16 141.38,140.16 140.67,139.45 140.67,139.27 139.92,138.52 137.25,138.52 130.05,131.32 122.68,131.32 119.32,127.95 119.32,120.59 v3(125.98,113.92) ; v3(112.45,96.22) 112.49,96.22 113.14,96.87 113.14,97.27 113.8,97.92 v5(114.35,97.92) ; v3(119.66,98.7) v5(119.66,99.44)
  L10_SIG4 w0.109: v5(114.35,97.92) 114.25,98.02 114.25,98.66 115.11,99.52 117.73,99.52 117.86,99.4 119.61,99.4 v5(119.66,99.44)
AM571X_RGMII0_RD0: length 101.9
  TOP w0.173: U1.W2 98.24,92.01 98.24,96.13 96.14,98.23 96.14,100.99 96.8,101.65 96.8,104.17 94.89,106.08 93.17,106.08 v3(92.08,104.98) ; v3(36.07,111.71) 35.61,111.26 R289.2
  L3_SIG1 w0.109: v3(92.08,104.98) 91.52,105.54 90.85,105.54 90.55,105.24 90.55,104.32 90.27,104.04 82.75,104.04 80.42,106.38 76.14,106.38 72.95,103.19 72.95,102.16 71.42,100.64 68.73,100.64 68.63,100.75 68.63,101.29 68.52,101.4 68.32,101.4 68.19,101.27 68.19,100.75 68.08,100.64 66.46,100.64 66.35,100.75 66.35,101.72 66.24,101.83 66.02,101.83 65.91,101.72 65.91,100.75 65.8,100.64 65.59,100.64 65.48,100.75 65.48,101.72 65.37,101.83 65.15,101.83 65.04,101.72 65.04,100.75 64.93,100.64 64.71,100.64 64.6,100.75 64.6,101.72 64.49,101.83 64.27,101.83 64.17,101.72 64.17,100.75 64.06,100.64 63.84,100.64 63.73,100.75 63.73,101.72 63.62,101.83 63.4,101.83 63.29,101.72 63.29,100.75 63.18,100.64 62.96,100.64 62.85,100.75 62.85,101.72 62.75,101.83 62.53,101.83 62.42,101.72 62.42,100.75 62.31,100.64 62.09,100.64 61.98,100.75 61.98,101.72 61.87,101.83 61.65,101.83 61.54,101.72 61.54,100.75 61.43,100.64 51.43,100.64 50.35,101.72 45.5,101.72 42.44,104.78 42.44,105.41 41.13,106.73 39.49,106.73 36.07,110.15 v3(36.07,111.71)
AM571X_RGMII0_RD1: length 101.7
  TOP w0.173: R290.2 34.21,111.26 v3(34.67,111.71) ; v3(91.82,104.35) 91.9,104.27 92.41,104.27 93.04,103.63 93.04,103.38 93.17,103.25 93.17,101.05 93.75,100.46 93.75,98.28 97.43,94.59 97.43,92.02 U1.Y2
  L3_SIG1 w0.109: v3(34.67,111.71) 34.67,110.8 39.2,106.27 40.95,106.27 41.88,105.34 41.88,104.69 45.31,101.27 50.02,101.27 51.71,99.57 52.46,99.57 52.56,99.68 52.56,100.07 52.67,100.18 52.89,100.18 53,100.07 53,99.68 53.11,99.57 53.33,99.57 53.44,99.68 53.44,100.07 53.55,100.18 53.77,100.18 53.87,100.07 53.87,99.68 53.98,99.57 54.2,99.57 54.31,99.68 54.31,100.07 54.42,100.18 54.64,100.18 54.75,100.07 54.75,99.68 54.86,99.57 55.08,99.57 55.19,99.68 55.19,100.07 55.29,100.18 55.51,100.18 55.62,100.07 55.62,99.68 55.73,99.57 55.95,99.57 56.06,99.68 56.06,100.07 56.17,100.18 56.39,100.18 56.5,100.07 56.5,99.68 56.61,99.57 56.82,99.57 56.93,99.68 56.93,100.07 57.04,100.18 57.26,100.18 57.37,100.07 57.37,99.68 57.48,99.57 57.7,99.57 57.81,99.68 57.81,100.07 57.92,100.18 58.13,100.18 58.24,100.07 58.24,99.68 58.35,99.57 58.57,99.57 58.68,99.68 58.68,100.07 58.79,100.18 59.01,100.18 59.12,100.07 59.12,99.68 59.23,99.57 59.45,99.57 59.55,99.68 59.55,100.07 59.66,100.18 59.88,100.18 59.99,100.07 59.99,99.68 60.1,99.57 60.32,99.57 60.43,99.68 60.43,100.07 60.54,100.18 60.76,100.18 60.87,100.07 60.87,99.68 60.97,99.57 61.19,99.57 61.3,99.68 61.3,100.07 61.41,100.18 61.63,100.18 61.74,100.07 61.74,99.68 61.85,99.57 62.74,99.57 63.5,98.81 64.92,98.81 65.03,98.92 65.03,99.72 65.14,99.83 65.36,99.83 65.47,99.72 65.47,98.92 65.58,98.81 65.8,98.81 65.91,98.92 65.91,99.72 66.02,99.83 66.23,99.83 66.34,99.72 66.34,98.92 66.45,98.81 66.67,98.81 66.78,98.92 66.78,99.72 66.89,99.83 67.11,99.83 67.22,99.72 67.22,98.92 67.33,98.81 68.54,98.81 68.65,98.92 68.65,99.49 68.76,99.6 68.98,99.6 69.09,99.49 69.09,98.92 69.2,98.81 70.41,98.81 75.44,103.84 75.44,104.86 76.35,105.77 79.98,105.77 82.17,103.59 91.06,103.59 v3(91.82,104.35)
AM571X_RGMII0_RD2: length 101.9
  TOP w0.173: U1.V3 v4(99.04,91.21) ; R291.2 32.82,111.26 33.4,111.84 v3(33.4,112.86)
  L3_SIG1 w0.109: v3(33.4,112.86) 33.83,113.29 37.94,113.29 39.93,111.3 40.41,111.3 41,110.71 41,109.85 41.27,109.58 41.42,109.58 41.7,109.86 41.86,109.86 42.01,109.71 42.01,109.55 41.73,109.27 41.73,109.12 41.89,108.97 42.04,108.97 42.32,109.24 42.47,109.24 42.63,109.09 42.63,108.94 42.35,108.66 42.35,108.5 42.5,108.35 42.66,108.35 42.94,108.63 43.09,108.63 43.25,108.47 43.25,108.32 42.97,108.04 42.97,107.88 43.12,107.73 43.28,107.73 43.56,108.01 43.71,108.01 43.87,107.85 43.87,107.7 43.59,107.42 43.59,107.27 43.74,107.11 43.89,107.11 44.17,107.39 44.33,107.39 44.48,107.24 44.48,107.08 44.2,106.8 44.2,106.65 44.36,106.49 44.51,106.49 44.79,106.77 44.95,106.77 45.1,106.62 45.1,106.46 44.82,106.18 44.82,106.03 44.98,105.87 45.13,105.87 45.41,106.15 45.57,106.15 45.72,106 45.72,105.84 45.44,105.56 45.44,105.41 46.45,104.4 46.6,104.4 46.87,104.67 47.03,104.67 47.18,104.51 47.18,104.36 46.91,104.09 46.91,103.94 47.19,103.66 68.83,103.66 69.8,104.63 72.09,104.63 73.19,105.73 73.19,105.9 72.67,106.42 72.67,106.58 72.78,106.7 72.95,106.7 73.47,106.18 73.63,106.18 73.75,106.29 73.75,106.46 73.23,106.98 73.23,107.14 73.34,107.26 73.51,107.26 74.03,106.74 74.2,106.74 75.56,108.11 79.54,108.11 79.65,108.22 79.65,108.56 79.76,108.67 79.98,108.67 80.09,108.56 80.09,108.22 80.2,108.11 80.42,108.11 80.53,108.22 80.53,108.56 80.64,108.67 80.85,108.67 80.96,108.56 80.96,108.22 81.07,108.11 81.29,108.11 81.4,108.22 81.4,108.56 81.51,108.67 81.73,108.67 81.84,108.56 81.84,108.22 81.95,108.11 84.3,108.11 85.85,106.56 92.09,106.56 93.74,104.91 94.79,104.91 96.85,102.85 97.82,102.85 98.52,102.15 98.52,100.22 99.39,99.34 99.39,96.6 99.29,96.5 99.29,92.74 98.83,92.28 98.83,91.42 v4(99.04,91.21)
AM571X_RGMII0_RD3: length 100.7
  TOP w0.173: U1.V4 v4(99.04,90.41) ; R292.2 31.42,111.26 v3(31.88,111.71)
  L3_SIG1 w0.099: v4(99.04,90.41) 99.04,90.75 98.55,91.23 98.55,91.5
  L3_SIG1 w0.109: v3(31.88,111.71) 33.08,111.71 33.21,111.84 33.21,112.23 33.32,112.35 33.49,112.35 33.6,112.23 33.6,111.7 33.72,111.59 34.06,111.59 34.2,111.72 34.2,112.38 34.59,112.78 35.05,112.78 35.17,112.66 35.17,112.22 35.28,112.1 35.45,112.1 35.56,112.22 35.56,112.66 35.71,112.81 37.03,112.81 37.31,112.53 37.47,112.53 37.68,112.74 37.85,112.74 37.96,112.63 37.96,112.46 37.75,112.25 37.75,112.09 37.87,111.97 38.03,111.97 38.24,112.18 38.41,112.18 38.53,112.06 38.53,111.9 38.31,111.69 38.31,111.52 38.43,111.41 38.59,111.41 38.81,111.62 38.97,111.62 39.09,111.5 39.09,111.34 38.87,111.13 38.87,110.96 38.99,110.85 39.15,110.85 39.37,111.06 39.53,111.06 39.65,110.94 39.65,110.78 39.44,110.57 39.44,110.4 40.52,109.32 40.87,109.32 40.99,109.2 40.99,109.04 40.53,108.59 40.53,108.42 40.65,108.31 40.82,108.31 41.27,108.77 41.44,108.77 41.56,108.65 41.56,108.49 41.1,108.03 41.1,107.86 41.21,107.75 41.38,107.75 41.54,107.91 41.54,107.92 41.81,108.18 41.99,108.18 46.96,103.21 50.6,103.21 52.17,101.63 52.74,101.63 52.85,101.74 52.85,102.31 52.96,102.42 53.17,102.42 53.28,102.31 53.28,101.74 53.39,101.63 55.24,101.63 56.72,103.1 69.06,103.1 70.13,104.17 72.44,104.17 75.82,107.55 81.25,107.55 83.03,105.77 84.12,105.77 84.43,106.08 90.25,106.08 90.4,106.23 91.97,106.23 92.81,105.39 92.81,104.42 93.09,104.14 93.85,104.14 94.1,103.89 95.17,103.89 96.67,102.39 97.33,102.39 98.02,101.7 98.02,100.09 98.93,99.18 98.93,96.7 98.76,96.52 98.76,94.52 99.03,94.24 99.03,92.99 98.55,92.51 98.55,91.5
AM571X_RGMII0_RXCLK: length 101.6
  TOP w0.173: v3(41.15,112.86) 39.55,111.26 38.36,111.26 R887.1 ; U1.U5 v4(99.84,89.61)
  L3_SIG1 w0.099: 99.11,91.7 99.11,91.55 99.33,91.33 99.33,90.12 v4(99.84,89.61)
  L3_SIG1 w0.109: v3(41.15,112.86) 41.48,112.52 41.73,112.52 42.92,111.33 42.92,111.1 42.64,110.83 42.64,110.66 42.76,110.55 42.92,110.55 43.2,110.82 43.37,110.82 43.48,110.71 43.48,110.54 43.2,110.27 43.2,110.1 43.32,109.98 43.49,109.98 43.76,110.26 43.93,110.26 44.04,110.15 44.04,109.98 43.77,109.7 43.77,109.54 43.88,109.42 44.05,109.42 44.32,109.7 44.49,109.7 44.6,109.59 44.6,109.42 44.33,109.14 44.33,108.98 44.44,108.86 44.61,108.86 44.89,109.14 45.05,109.14 45.17,109.02 45.17,108.86 44.89,108.58 44.89,108.42 45,108.3 45.17,108.3 45.45,108.58 45.61,108.58 45.73,108.46 45.73,108.3 45.45,108.02 45.45,107.86 45.56,107.74 45.73,107.74 46.01,108.02 46.17,108.02 46.29,107.9 46.29,107.74 46.01,107.46 46.01,107.3 46.13,107.18 46.29,107.18 46.57,107.46 46.73,107.46 46.85,107.34 46.85,107.18 46.57,106.9 46.57,106.74 46.68,106.63 46.86,106.63 47.13,106.9 47.29,106.9 47.47,106.72 47.47,106.57 47.27,106.36 47.27,106.21 47.42,106.05 47.57,106.05 47.78,106.26 47.93,106.26 48.09,106.1 48.09,105.95 47.88,105.74 47.88,105.59 48.04,105.43 48.19,105.43 48.4,105.64 48.55,105.64 48.71,105.48 48.71,105.33 48.5,105.12 48.5,104.97 48.66,104.82 48.81,104.82 49.02,105.02 49.17,105.02 49.38,104.81 68.09,104.81 69.7,106.43 69.86,106.43 70.31,105.98 70.5,105.98 70.63,106.1 70.63,106.26 70.13,106.76 70.13,106.91 70.28,107.07 70.44,107.07 70.94,106.57 71.09,106.57 71.25,106.72 71.25,106.88 70.75,107.38 70.75,107.53 70.9,107.68 71.05,107.68 71.55,107.18 71.71,107.18 71.86,107.34 71.86,107.49 71.36,107.99 71.36,108.15 71.52,108.3 71.67,108.3 72.17,107.8 72.33,107.8 72.48,107.96 72.48,108.11 71.98,108.61 71.98,108.77 72.14,108.92 72.29,108.92 72.79,108.42 72.95,108.42 74.61,110.08 81.9,110.08 82.37,110.55 84.05,110.55 87.53,107.07 90.82,107.07 91,106.89 92.33,106.89 93.19,106.02 93.95,106.02 94.61,105.36 95.04,105.36 97.1,103.31 98.15,103.31 99.13,102.33 99.13,100.23 99.85,99.51 99.85,96.68 99.54,96.37 99.54,92.66 99.11,92.23 99.11,91.7
AM571X_RGMII0_RXCTL: length 100.8
  TOP w0.173: U1.V5 v4(99.04,89.61) ; R285.2 37.01,111.26 v3(37.46,111.71)
  L3_SIG1 w0.099: 98.09,91.48 98.09,91.32 98.74,90.67 98.74,89.91 v4(99.04,89.61)
  L3_SIG1 w0.109: v3(37.46,111.71) 37.46,109.4 39.65,107.21 42.3,107.21 44.47,105.04 44.47,104.88 43.84,104.25 43.84,104.09 43.96,103.97 44.12,103.97 44.72,104.57 44.89,104.57 45,104.46 45,104.29 44.38,103.67 44.38,103.5 44.49,103.38 44.66,103.38 45.26,103.99 45.45,103.99 45.56,103.88 45.56,103.73 44.92,103.08 44.92,102.93 45.03,102.82 45.22,102.82 45.82,103.43 45.98,103.43 46.1,103.31 46.1,103.14 45.57,102.62 45.57,102.46 45.81,102.23 46.41,102.23 46.52,102.34 46.52,102.59 46.63,102.7 46.85,102.7 46.96,102.59 46.96,102.34 47.07,102.23 47.28,102.23 47.39,102.34 47.39,102.59 47.5,102.7 47.72,102.7 47.83,102.59 47.83,102.34 47.94,102.23 48.16,102.23 48.27,102.34 48.27,102.59 48.38,102.7 48.6,102.7 48.7,102.59 48.7,102.34 48.81,102.23 49.03,102.23 49.14,102.34 49.14,102.59 49.25,102.7 49.47,102.7 49.58,102.59 49.58,102.34 49.69,102.23 49.91,102.23 50.01,102.34 50.01,102.59 50.12,102.7 50.34,102.7 50.45,102.59 50.45,102.34 50.56,102.23 50.71,102.23 51.82,101.12 56.23,101.12 56.34,101.23 56.34,101.75 56.45,101.86 56.66,101.86 56.77,101.75 56.77,101.23 56.88,101.12 57.1,101.12 57.21,101.23 57.21,101.75 57.32,101.86 57.54,101.86 57.65,101.75 57.65,101.23 57.76,101.12 57.97,101.12 58.08,101.23 58.08,101.75 58.19,101.86 58.41,101.86 58.52,101.75 58.52,101.23 58.63,101.12 58.85,101.12 58.96,101.23 58.96,101.75 59.07,101.86 59.28,101.86 59.39,101.75 59.39,101.23 59.5,101.12 60.25,101.12 61.52,102.39 70.64,102.39 71.96,103.71 72.72,103.71 75.97,106.96 81.14,106.96 82.82,105.29 84.3,105.29 84.6,105.58 90.33,105.58 90.64,105.9 91.77,105.9 92.48,105.19 92.48,104.09 92.8,103.77 93.59,103.77 93.92,103.43 94.87,103.43 95.78,102.52 95.78,101.71 98.48,99.01 98.48,94.52 98.25,94.29 98.25,92.61 98.09,92.46 98.09,91.48
AM571X_RGMII0_TD0: length 29.8
  TOP w0.173: U1.U6 v4(99.84,88.81) ; v3(86.74,99.78) 86.74,101.98 R883.1
  L3_SIG1 w0.109: v4(99.84,88.81) 99.84,88.82 v5(99.44,89.06) ; v3(86.74,99.78) v5(86.74,99.14)
  L10_SIG4 w0.109: v5(86.74,99.14) 87.2,98.68 88.19,98.68 89.24,99.74 90.16,99.74 90.53,100.1 99.07,100.1 99.7,99.47 100,99.17 100,93.32 99.11,92.44 99.11,91.5 99.44,91.17 99.44,89.07 v5(99.44,89.06)
AM571X_RGMII0_TD1: length 20.3
  TOP w0.173: U1.V6 v4(99.04,88.81) ; v3(91.82,99.78) 91.82,101.98 R884.1
  L3_SIG1 w0.099: v4(99.04,88.81) 98.54,89.31 98.54,90.59 97.84,91.29 97.84,91.42
  L3_SIG1 w0.109: v5(95.54,99.28) 95.54,99.27 98.02,96.79 98.02,96.6 98.17,96.45 98.17,94.57 98.02,94.42 98.02,92.84 97.84,92.66 97.84,91.42 ; v3(91.82,99.78) v5(91.82,99.14)
  L10_SIG4 w0.109: v5(95.54,99.28) 91.96,99.28 v5(91.82,99.14)
AM571X_RGMII0_TD2: length 29.8
  TOP w0.173: v3(88.01,99.78) 88.01,101.98 R885.1 ; U1.U7 v4(99.84,88.01)
  L3_SIG1 w0.109: v3(88.01,99.78) v5(88.01,99.14) ; v5(99.44,88.26) v4(99.84,88.01)
  L10_SIG4 w0.109: v5(88.01,99.14) 88.02,99.14 89.07,100.19 90.03,100.19 90.28,100.43 99.17,100.43 100.3,99.29 100.3,93.32 99.69,92.71 99.69,92.16 99.97,91.88 99.97,91.17 99.74,90.93 99.74,89.83 99.89,89.68 99.89,88.71 v5(99.44,88.26)
AM571X_RGMII0_TD3: length 26.9
  TOP w0.173: v3(89.28,99.78) 89.28,101.98 R886.1 ; U1.V7 v4(99.04,88.01)
  L3_SIG1 w0.109: v3(89.28,99.78) v5(89.28,99.14) ; v5(98.64,88.26) v4(99.04,88.01)
  L10_SIG4 w0.109: v5(89.28,99.14) 89.71,98.71 91.95,98.71 92.27,99.03 94.46,99.03 94.74,98.76 95.73,98.76 96.42,99.44 98.55,99.44 99.49,98.5 99.49,93.48 98.48,92.46 98.48,91.37 98.78,91.06 98.78,88.41 v5(98.64,88.26)
AM571X_RGMII0_TXCLK: length 32.5
  TOP w0.173: U1.W9 v4(98.24,86.41) ; R881.1 85.47,101.98 v3(85.47,99.78)
  L3_SIG1 w0.109: v3(85.47,99.78) v5(85.47,99.14) ; v5(97.84,86.66) v4(98.24,86.41)
  L10_SIG4 w0.109: v5(97.84,86.66) 98.22,87.05 98.22,88.93 98.5,89.21 98.5,90.96 98.06,91.4 98.06,92.4 99.06,93.4 99.06,97.57 98.6,98.02 98.6,98.71 98.28,99.03 96.7,99.03 96.03,98.36 94.47,98.36 94.06,98.78 92.48,98.78 91.62,97.92 86.7,97.92 v5(85.47,99.14)
AM571X_RGMII0_TXCTL: length 27.5
  TOP w0.173: U1.V9 v4(99.04,86.41) ; v3(90.55,99.78) 90.55,101.98 R286.2
  L3_SIG1 w0.109: v3(90.55,99.78) v5(90.55,99.14) ; v5(98.64,86.66) v4(99.04,86.41)
  L10_SIG4 w0.109: v5(90.55,99.14) 91.12,99.71 99.03,99.71 99.77,98.97 99.77,93.43 98.78,92.44 98.78,91.39 99.03,91.14 99.03,87.06 v5(98.64,86.66)
AM571X_VIN2A_CLK0: length 69.9
  TOP w0.173: R846.1 v3(130.3,142.11) ; U1.E1 109.83,93.42 111.45,95.03 111.45,96.43 v3(113.54,98.52) R669.1
  L3_SIG1 w0.109: v5(113.12,98.11) 113.53,98.52 v3(113.54,98.52) ; v5(125.37,135.18) 125.37,137.54 128.93,141.1 129.29,141.1 v3(130.3,142.11)
  L4_SIG2 w0.114: v5(125.37,135.18) 125.37,134.42 124.03,133.07 123.34,133.07 121.16,135.25 117.75,135.25 117.31,134.8 117.31,133.97 116.97,133.63 116.97,131.53 114.91,129.46 114.91,121.36 115.85,120.42 115.85,107.01 114.38,105.54 114.38,104.11 111.66,101.4 111.66,100.41 113.12,98.95 v5(113.12,98.11)
AM571X_VIN2A_D2: length 141.9
  TOP w0.173: R853.1 v3(146.56,142.24) ; R416.2 78.4,148.93 v8(79.5,147.83) ; v3(115.06,106.76) 115.06,102.16 114.09,101.19 114.09,98.47 112.03,96.41 112.03,95.75 112.28,95.5 112.28,95.09 110.64,93.45 U1.D1
  L3_SIG1 w0.109: v5(137.31,139.19) 137.64,138.86 139.78,138.86 140.23,139.32 140.23,139.5 141.27,140.54 144.27,140.54 144.6,140.87 145.77,140.87 146.56,141.66 v3(146.56,142.24) ; v3(115.06,106.76) v5(114.48,106.76)
  L4_SIG2 w0.114: v5(137.31,139.19) 137.31,138.57 134.33,135.58 133.9,135.58 133.52,135.97 129.67,135.97 129.01,135.31 127.31,135.31 126.79,135.83 116.56,135.83 115.88,135.15 115.88,134.11 115.42,133.65 113.92,133.65 113.45,133.19 v5(113.45,130.26) 113.49,130.22 113.49,115.87 115.24,114.12 115.24,108.33 114.48,107.57 v5(114.48,106.76)
  L10_SIG4 w0.109: v8(78.59,140.69) 79.1,140.69 84.68,135.1 89.92,135.1 91.72,136.91 96.52,136.91 97.41,136.02 107.69,136.02 108.94,134.77 108.94,130.86 109.55,130.26 v5(113.45,130.26)
  BOTTOM w0.173: v8(79.5,147.83) 79.91,148.23 81.88,148.23 82.8,147.31 82.8,144.88 78.61,140.69 v8(78.59,140.69)
AM571X_VIN2A_FLD0: length 82.4
  TOP w0.173: R848.1 v3(134.37,142.24) ; U1.H7 v4(107.83,88.01)
  L3_SIG1 w0.109: v5(108.23,88.26) 108.23,88.26 v4(107.83,88.01) ; v5(123.52,133.51) 128.02,133.51 129.24,134.72 130.25,134.72 132.92,137.39 133.93,137.39 134.9,138.36 134.9,141.71 v3(134.37,142.24)
  L4_SIG2 w0.114: v5(108.23,88.26) 107.75,88.74 107.75,93.06 107.78,93.09 107.78,93.43 110.75,96.41 110.93,96.41 v5(112.27,97.74) 112.27,99.36 111.81,99.82 111.48,99.82 111.25,100.05 111.25,101.6 114.07,104.42 114.07,105.71 115.54,107.19 115.54,120.09 114.33,121.31 114.33,130.32 115.94,131.94 115.94,133.26 116.25,133.56 116.5,133.56 117.02,134.09 117.02,135.03 117.53,135.54 121.48,135.54 v5(123.52,133.51)
  L10_SIG4 w0.109: v5(112.27,97.74) v7(111.38,97.74)
  BOTTOM w0.173: v7(111.38,97.74) R671.1
AM571X_VIN2A_VSYNC0: length 215.8
  TOP w0.173: R850.1 v3(140.46,142.24) ; R198.2 v8(48.39,75.92) ; R803.1 107.06,103.76 v3(107.06,101.14) ; U1.G6 v4(108.63,88.81)
  L3_SIG1 w0.099: 106.63,98.1 104.66,96.13 104.66,95.45 105.03,95.08 105.03,94.24 104.47,93.68 104.36,93.68 v5(104.26,93.58)
  L3_SIG1 w0.109: v3(140.46,142.24) v5(140.46,141.66) ; 106.63,98.1 106.63,100.23 106.91,100.51 106.91,100.99 v3(107.06,101.14) ; v4(108.63,88.81) 108.64,88.82 v5(109.03,89.06) ; v5(77.8,127.59) 85.83,127.59 86.16,127.92 87.43,127.92 87.91,127.44 92.18,127.44 93.71,128.97 95.22,128.97 96.85,127.34 100.37,127.34 101.26,126.44 102.44,126.44 103.35,125.53 v5(104.04,125.53)
  L4_SIG2 w0.114: v5(77.8,127.59) 70.72,120.5 70.72,113.08 70.38,112.75 70.38,106.71 61.44,97.77 61.44,88.24 56.26,83.06 49.12,83.06 47.12,81.05 47.12,77.19 v8(48.39,75.92) ; v5(140.46,141.66) 136.38,145.74 124.29,145.74 123.98,145.43 117.34,145.43 114.35,142.44 110.43,142.44 109.36,141.37 109.36,139.09 107.42,137.16 105.88,137.16 103.74,135.02 103.74,128.46 104.03,128.17 104.03,125.54 v5(104.04,125.53) 103.53,125.03 103.53,123.35 104.31,122.57 104.31,118.82 103.23,117.73 103.23,110.07 101.56,108.4 101.56,107.21 102.71,106.06 103.95,106.06 104.9,105.11 106.19,105.11 107.09,104.2 107.09,102.94 108.11,101.92 108.11,99.55 107.6,99.04 105.34,99.04 104.14,97.84 104.14,97.64 104.14,97.64 104.14,97.27 104.14,97.27 104.14,93.7 v5(104.26,93.58)
  L10_SIG4 w0.109: v5(109.03,89.06) 108.05,90.04 106.63,90.04 105.92,90.76 105.92,92.03 104.37,93.58 v5(104.26,93.58)
AM571X_VOUT1_FLD: length 5.7
  TOP w0.173: U1.B11 112.63,84.81 117.2,84.81 R564.1
AM572X_DCAN1_RX: length 121.5
  TOP w0.173: U1.G19 v4(108.63,77.62)
  L3_SIG1 w0.109: v4(108.63,77.62) v5(109.03,77.37)
  L4_SIG2 w0.114: v8(173.23,22.43) 173.23,56.39 168.54,61.09 167.01,61.09 160.98,67.12 160.98,68.65 142.37,87.25 140.46,87.25 139.95,86.74 139.07,86.74 138.05,85.72 136.4,85.72 136.02,86.11 133.52,86.11 132.16,87.46 130.82,87.46 125.43,82.08 119.32,82.08 118.24,81 118.24,79.84 115.84,77.44 114.2,77.44 113.89,77.75 109.42,77.75 v5(109.03,77.37)
  BOTTOM w0.173: v8(173.23,22.43) C253.1 R502.1
AM572X_DCAN1_TX: length 122.8
  TOP w0.173: U1.G20 v4(108.63,76.82)
  L3_SIG1 w0.109: v4(108.63,76.82) v5(109.03,76.57)
  L4_SIG2 w0.114: v5(109.03,76.57) 109.42,76.95 111.27,76.95 111.39,76.83 115.74,76.83 118.62,79.71 118.62,80.97 119.44,81.79 125.55,81.79 130.94,87.17 132.04,87.17 133.49,85.72 135.51,85.72 136.53,84.71 139.57,84.71 140.34,85.47 142.59,85.47 159.75,68.31 159.75,67.69 168.53,58.91 168.53,57.91 168.03,57.41 168.03,44.38 167.71,44.06 167.71,24.4 v5(173.36,18.75)
  L10_SIG4 w0.109: v7(173.36,19.51) v5(173.36,18.75)
  BOTTOM w0.173: v5(173.36,18.75) v7(173.36,19.51)
AM572X_HDMI_CEC: length 167.5
  TOP w0.173: R805.1 v3(130.18,71.07) 129.06,71.07 128.88,70.9 126.82,70.9 125.81,71.91 125.09,71.91 124.89,71.71 122.73,71.71 122.1,72.34 121.11,72.34 120.63,71.86 119.35,71.86 117.35,73.87 117.17,73.87 114.22,76.81 113.2,76.81 113.2,76.81 112.64,76.81 U1.B20 ; v8(68.81,24.93) 69.47,24.27 R683.2
  L3_SIG1 w0.109: v3(130.18,71.07) v5(130.18,71.66)
  L4_SIG2 w0.114: v5(130.18,71.66) 131.09,70.74 131.83,70.74 137.61,64.95 139.13,64.95 141.29,62.8 141.29,61.28 142.26,60.3 142.26,31.4 127.62,16.76 127.25,16.76 126.51,16.02 125.85,16.02 125.36,16.51 122.5,16.51 122.15,16.86 120.54,16.86 119.63,15.96 118.38,15.96 117.23,17.1 111.55,17.1 110.94,16.48 109.85,16.48 109.32,17.02 103.12,17.02 102.74,16.64 91.9,16.64 91.38,17.15 88.96,17.15 88.45,16.64 87.3,16.64 86.62,17.32 71.57,17.32 71.42,17.18 69.28,17.18 68.64,17.81 64.64,17.81 v5(64.01,17.18)
  L9_SIG3 w0.114: v5(64.01,17.18) 68.81,21.98 v8(68.81,24.93)
AM572X_HDMI_DDC_SCL: length 236.2
  TOP w0.173: v4(111.83,72.82) U1.C25 ; R556.1 123.12,64.84 v3(123.01,64.84)
  L3_SIG1 w0.099: 111.92,72.77 111.88,72.77 v4(111.83,72.82)
  L3_SIG1 w0.109: v5(132.59,62.51) 130.55,62.51 130.05,63.02 125.45,63.02 124.96,63.51 124.34,63.51 v3(123.01,64.84) 121.25,64.84 117.7,68.38 117.7,70.29 115.22,72.77 111.93,72.77 111.92,72.77
  L4_SIG2 w0.114: v5(132.59,62.51) 132.59,62.51 138.81,56.29 138.81,30.64 130.16,21.99 89.09,21.99 88.05,20.95 69.38,20.95 v8(67.87,22.46)
  L9_SIG3 w0.114: v8(56.64,107.47) 56.64,100.16 58.55,98.25 58.55,95.5 59.69,94.36 59.69,85.47 58.67,84.45 58.67,81.79 57.81,80.92 57.81,74.04 55.65,71.88 55.65,61.83 60.83,56.64 60.83,29.59 59.82,28.58 59.82,26.59 63.32,23.09 67.23,23.09 v8(67.87,22.46)
  BOTTOM w0.173: R358.2 v8(56.64,107.47) ; v8(67.87,22.46) 68.33,22 R795.2
AM572X_HDMI_DDC_SDA: length 277.7
  TOP w0.173: U1.F17 v4(109.43,79.22) ; v8(126.62,66.88) 126.66,66.93 R563.1
  L3_SIG1 w0.109: v4(109.43,79.22) v5(109.83,78.97)
  L4_SIG2 w0.114: v8(67.06,24.51) 67.06,23.65 66.45,23.04 66.45,21.77 67.56,20.66 90.89,20.66 92.12,19.42 93.81,19.42 95.09,20.71 107.98,20.71 108.5,20.19 110.01,20.19 110.78,20.96 120.5,20.96 121,20.46 129.17,20.46 139.45,30.73 139.45,56.87 130.23,66.09 127.41,66.09 v8(126.62,66.88) ; v5(136.35,86.48) 135.93,86.9 133.14,86.9 132.28,87.76 130.69,87.76 125.31,82.37 119.2,82.37 117.84,81.01 117.84,80.2 116.33,78.69 115.93,78.69 115.44,78.21 112.45,78.21 111.69,78.97 v5(109.83,78.97)
  L9_SIG3 w0.114: v5(136.35,86.48) 135.76,86.48 134.44,85.17 134.44,80.67 126.18,72.41 126.18,67.32 v8(126.62,66.88) ; v8(58.65,106.63) 57.28,105.26 57.28,100.42 59.35,98.34 59.35,95.71 60.32,94.74 60.32,84.96 59.69,84.33 59.69,80.26 59.18,79.76 59.18,73.41 57.15,71.37 57.15,61.75 61.47,57.43 61.47,26.92 63.27,25.12 66.45,25.12 v8(67.06,24.51)
  BOTTOM w0.173: R356.2 v8(58.65,106.63) ; v8(67.06,24.51) 66.17,24.51 65.66,24 R796.2
AM572X_HDMI_HPD: length 161.9
  TOP w0.173: v3(130.18,69.55) R804.1 129.95,68.48 126.54,68.48 126.01,69.02 126.01,69.57 125.5,70.08 122.53,70.08 122,70.62 119.58,70.62 116.94,73.26 116.66,73.26 113.9,76.02 112.63,76.02 U1.B21 ; R682.2 v8(67.69,24.26)
  L3_SIG1 w0.109: v3(130.18,69.55) v5(130.18,68.94)
  L4_SIG2 w0.114: v5(130.18,68.94) 130.23,68.88 131.04,68.88 141.61,58.32 141.61,31.16 127.5,17.05 124.82,17.05 124.63,16.86 122.56,16.86 122.27,17.15 120.44,17.15 120.32,17.27 118.44,17.27 118.32,17.15 117.59,17.15 117.35,17.39 111.43,17.39 110.81,16.77 109.97,16.77 109.35,17.4 103.04,17.4 102.62,16.97 91.97,16.97 91.47,17.48 88.87,17.48 88.33,16.93 87.42,16.93 86.74,17.61 71.45,17.61 71.3,17.47 69.4,17.47 68.76,18.1 v5(63.5,18.1)
  L9_SIG3 w0.114: v5(63.5,18.1) 64.38,18.1 68.38,22.1 68.38,23.57 v8(67.69,24.26)
AM572X_QSPI_CLK: length 8.8
  TOP w0.173: U1.R2 101.44,92.01 101.44,93.62 101.63,93.82 101.8,93.99 101.8,94.56 101.63,94.73 101.44,94.92 101.44,95.27 102.08,95.92 102.08,96.08 102.31,96.31 102.31,96.72 102.08,96.95 102.08,97.47 102.31,97.7 102.31,98.12 101.98,98.45 R24.2
AM572X_QSPI_CSN: length 51.9
  TOP w0.173: R30.2 91.69,125.3 90.3,125.3 88.9,123.91 88.9,122.36 87.63,121.09 87.63,112.86 v3(88.19,112.3) ; v3(105.03,106.55) 105.03,104.65 104.44,104.06 104.44,101.65 104.01,101.22 104.01,99.09 103.81,98.88 103.81,95.74 103.03,94.97 103.03,92.01 U1.P2
  L3_SIG1 w0.109: v3(88.19,112.3) 89.26,112.3 90.4,111.16 95.55,111.16 98.6,108.1 103.69,108.1 104.22,107.57 104.22,107.37 v3(105.03,106.55)
AM572X_QSPI_D0: length 17.1
  TOP w0.173: R25.2 98.68,104.75 99.06,104.37 99.06,103.41 98.58,102.93 98.58,99.45 100.49,97.54 100.49,95.93 100.24,95.67 U1.U1
AM572X_QSPI_D1: length 43.8
  TOP w0.173: U1.P3 v4(103.03,91.21) ; v8(88.9,116.67) 88.9,120.86 89.66,121.62 89.66,123.27 R26.2
  L3_SIG1 w0.099: 103,91.25 103,93.99 102.85,94.14 102.85,94.88 103.22,95.25 103.22,97.15 103.81,97.74
  L3_SIG1 w0.109: v4(103.03,91.21) 103,91.25 ; v5(93.22,106.63) 93.98,106.63 94.77,105.85 95.35,105.85 97.44,103.76 98.32,103.76 100.58,101.5 101.88,101.5 102.46,100.91 102.46,99.97 103.81,98.62 103.81,97.74
  L4_SIG2 w0.114: v8(88.9,116.67) 89.66,115.91 89.66,113.87 91.51,112.03 91.51,108.07 92.32,107.26 92.59,107.26 v5(93.22,106.63)
AM572X_QSPI_D2: length 23
  TOP w0.173: R27.2 91.06,107.6 91.34,107.32 95.48,107.32 98.04,104.75 98.04,99.14 99.96,97.22 99.96,95.79 99.83,95.66 99.83,92.02 U1.U2
AM572X_QSPI_D3: length 35.8
  TOP w0.173: R28.2 101.98,124.03 101.98,123.02 100.82,121.85 100.82,119.95 99.31,118.45 99.31,105.24 99.59,104.96 99.59,103.14 99.11,102.67 99.11,99.73 101.02,97.82 101.02,95.82 100.64,95.43 100.64,92.01 U1.T2
AM572X_QSPI_RTCLK: length 23
  TOP w0.173: R23.2 101.85,110.96 100.59,109.69 100.59,105.68 101.02,105.25 101.02,102.69 102.74,100.96 102.74,98.43 102.84,98.34 102.84,96.06 102.23,95.46 102.23,91.21 U1.R3
AM572X_USB2_DM: length 112.6
  TOP w0.15: U1.AF11 93.04,84.88 92.71,85.2 v4(92.71,85.49)
  L3_SIG1 w0.109: v4(92.71,85.49) 92.71,85.51 91.29,86.94 91.29,87.77 90.01,89.05 87.88,89.05 87.4,88.57 85.14,88.57 84.47,89.24 81.3,89.24 80.68,89.85 78.53,89.85 78.19,89.51 66.4,89.51 56.16,79.27 56.16,70.25 53.6,67.69 52.4,67.69 40.31,55.6 40.31,55.19 28.07,42.95 14.78,42.95 12.81,40.98 11.77,40.98 11.46,40.67 v8(11.45,40.67)
  BOTTOM w0.15: L33.2 10.27,40.57 10.49,40.8 11.33,40.8 v8(11.45,40.67)
AM572X_USB2_DP: length 113.2
  TOP w0.15: U1.AE11 93.34,84.91 93.34,85.01 93.1,85.25 v4(93.1,85.49)
  L3_SIG1 w0.109: v4(93.1,85.49) 93.1,85.56 91.59,87.07 91.59,87.9 90.13,89.35 87.75,89.35 87.27,88.87 85.27,88.87 84.6,89.54 81.42,89.54 80.81,90.16 78.4,90.16 78.06,89.82 66.27,89.82 55.85,79.4 55.85,70.38 53.47,68 52.27,68 40,55.73 40,55.32 27.94,43.26 14.66,43.26 12.68,41.28 v8(11.45,41.28)
  BOTTOM w0.15: v8(11.45,41.28) 11.3,41.13 10.52,41.13 10.27,41.38 L33.1
AM572X_USB2_DRVVBUS: length 14.7
  TOP w0.173: R787.2 84.07,88.14 v8(84.23,88.29) ; U1.AC10 v4(95.04,85.61)
  L3_SIG1 w0.109: v4(95.04,85.61) 95.03,85.61 v5(94.64,85.86)
  L10_SIG4 w0.109: v8(84.23,88.29) 84.23,87.53 84.67,87.09 85.63,87.09 86.26,86.46 91.44,86.46 91.95,86.97 93.53,86.97 94.63,85.86 v5(94.64,85.86)
BKLT_EN: length 2.7
  TOP w0.173: R416.1 R412.1 76.66,147.6 Q9.G
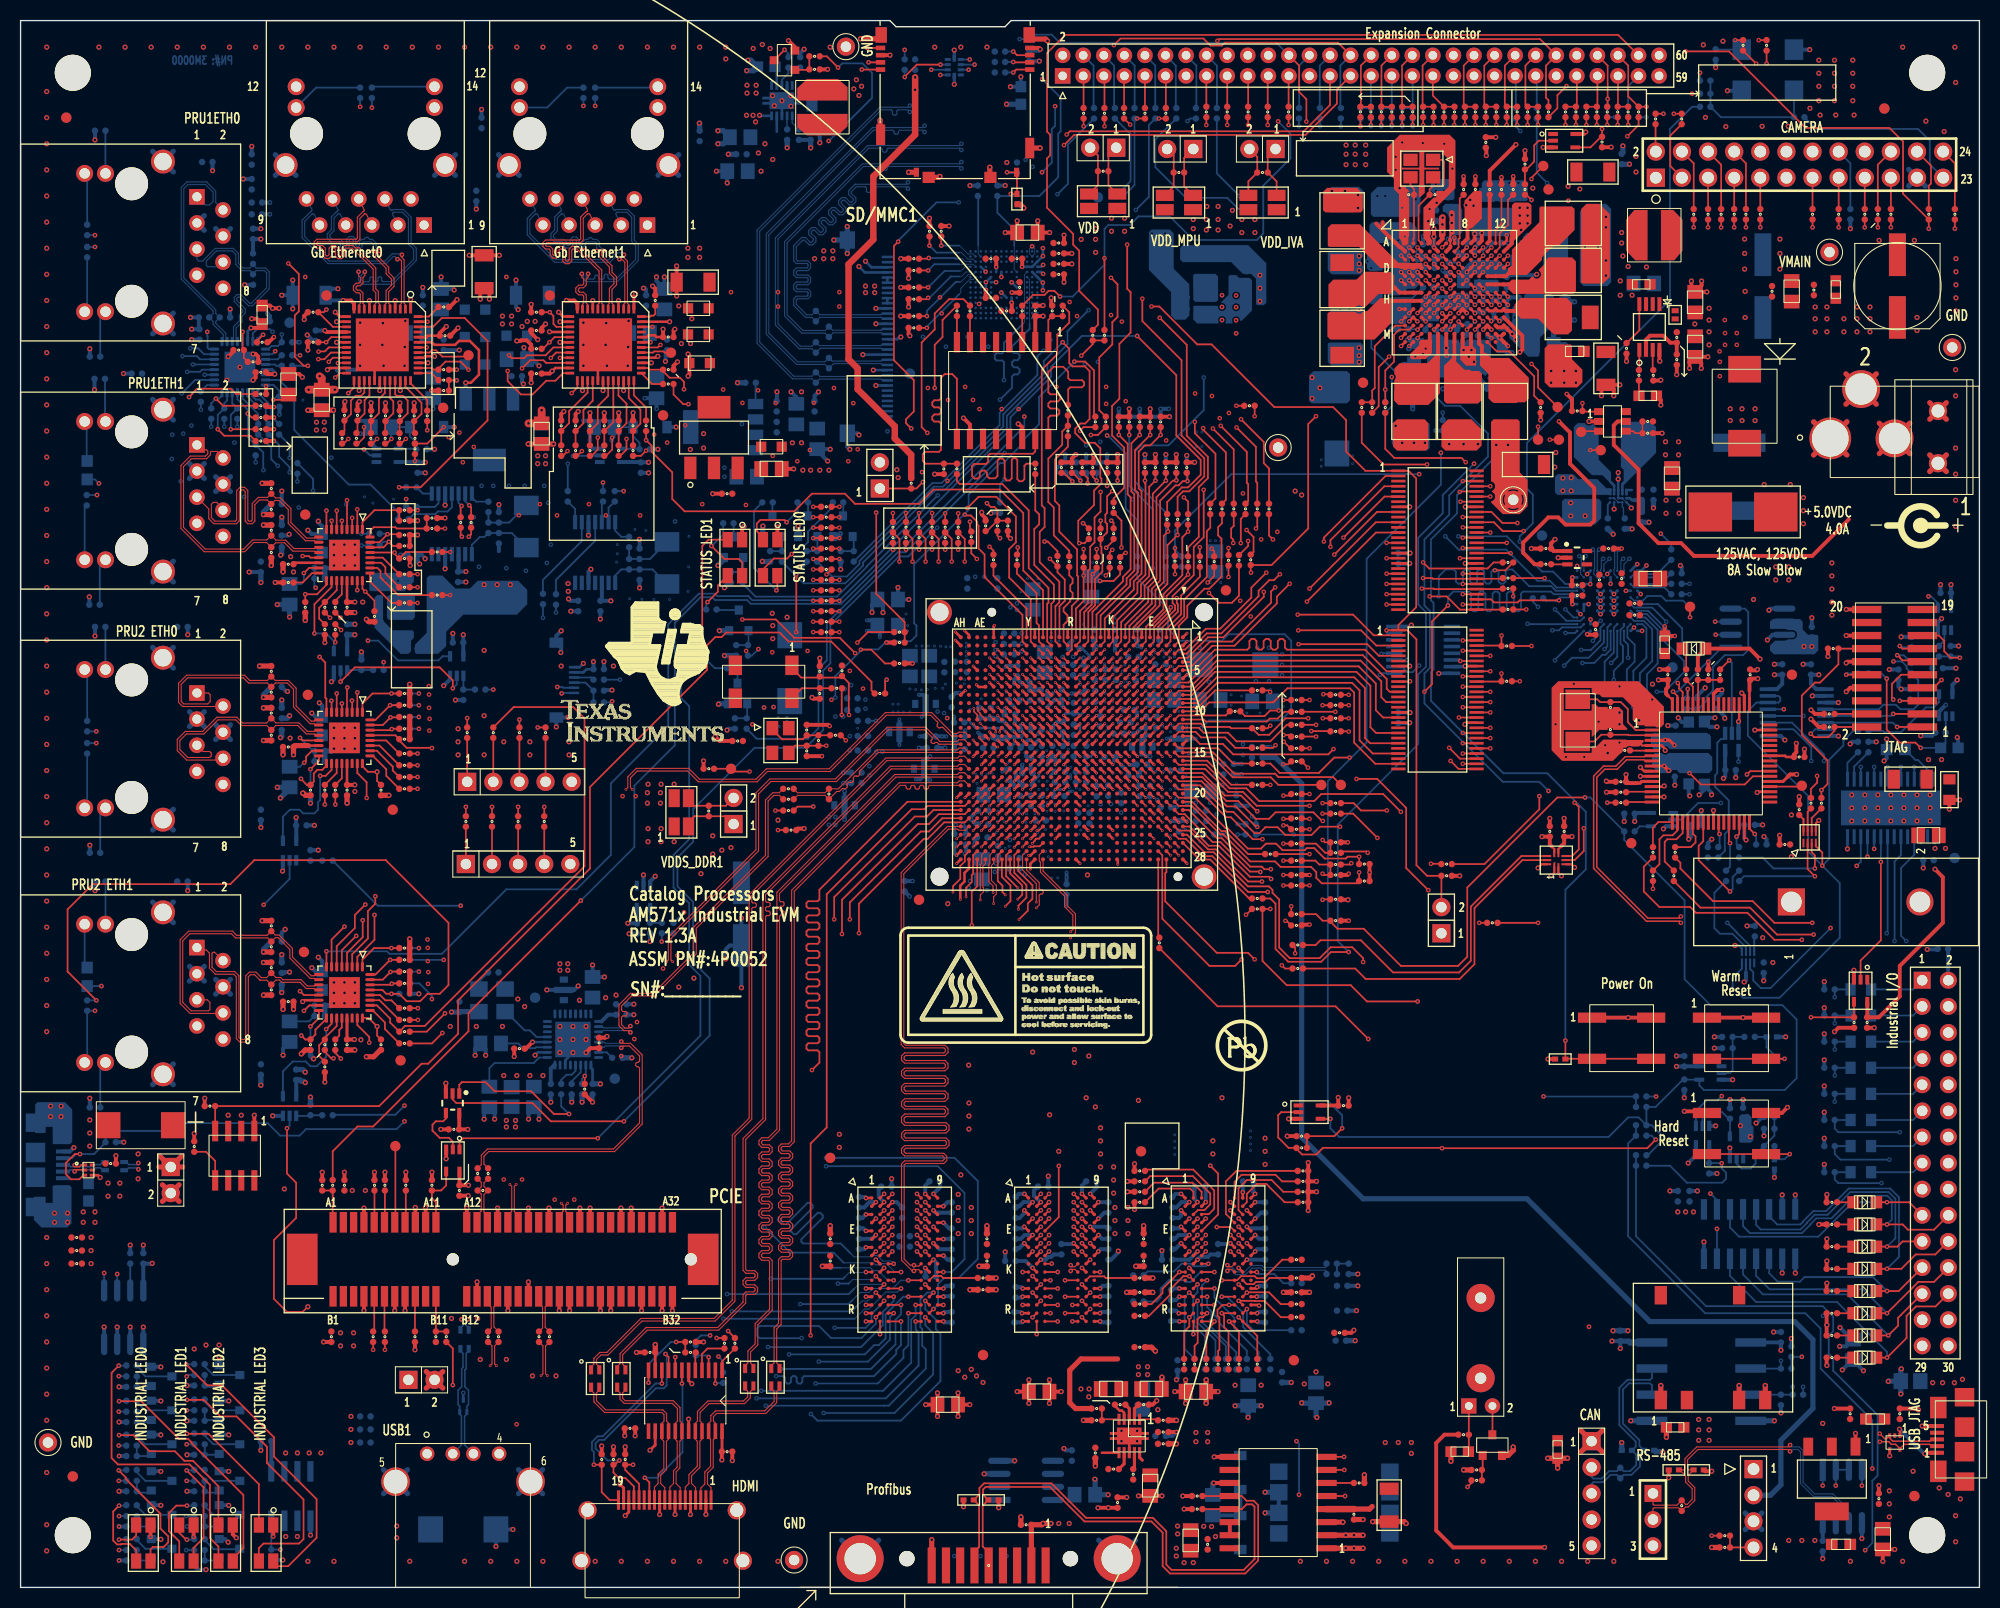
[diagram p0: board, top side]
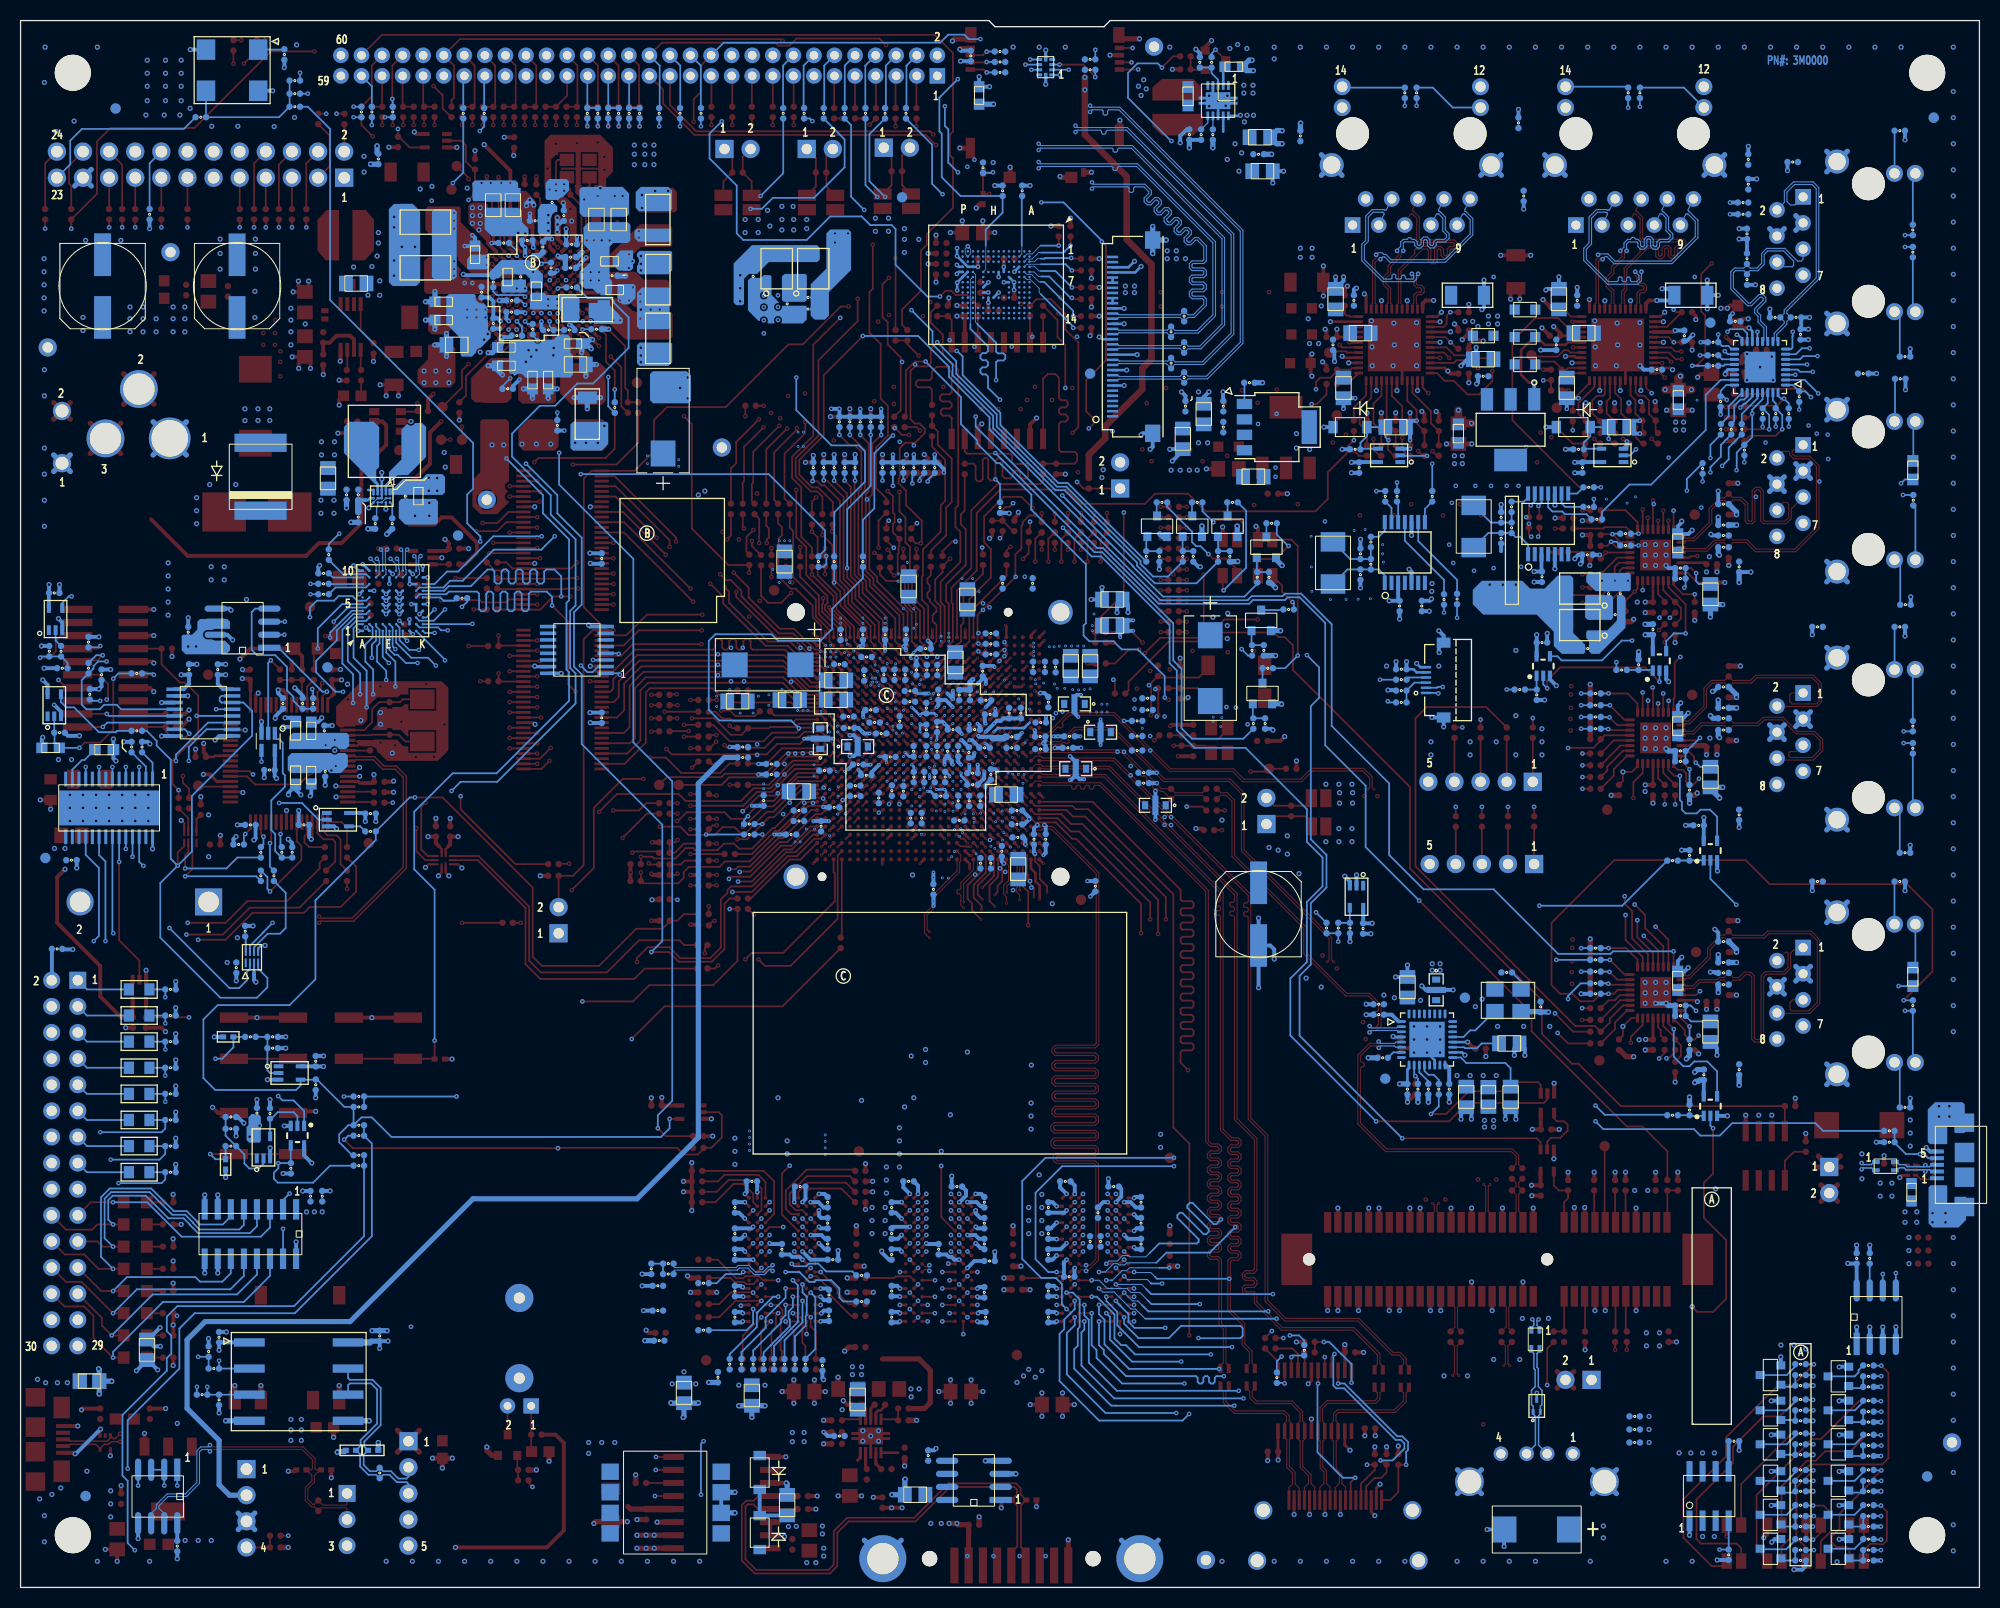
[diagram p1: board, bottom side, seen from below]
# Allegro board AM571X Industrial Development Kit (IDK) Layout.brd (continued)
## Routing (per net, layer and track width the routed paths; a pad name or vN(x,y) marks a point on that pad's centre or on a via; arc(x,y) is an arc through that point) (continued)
BKLT_L:
  vias: v9(70.64,146.11) v9(70.64,145.34) v9(71.53,146.11) v9(71.53,145.34)
BKLT_SW: length 1.2
  BOTTOM w0.254: U32.10 71.92,143.13 v9(71.86,143.18)
  vias: v9(70.59,143.18) v9(71.23,143.18) v9(71.48,142.55)
CAM1_DATA0: length 6.1
  TOP w0.173: R260.1 160.44,141.21 160.44,138.25 J9.3
CAM1_DATA1: length 3
  TOP w0.173: R261.1 J9.5
CAM1_DATA2: length 3
  TOP w0.173: R263.1 J9.7
CAM1_DATA3: length 3
  TOP w0.173: R267.1 J9.13
CAM1_DATA4: length 3
  TOP w0.173: R269.1 J9.15
CAM1_DATA5: length 3
  TOP w0.173: J9.17 R271.1
CAM1_DATA6: length 6.1
  TOP w0.173: J9.6 165.38,138.38 R262.2
CAM1_DATA7: length 6.1
  TOP w0.173: J9.8 167.79,138.51 R264.2
CAM1_FIELD: length 6.1
  TOP w0.173: R274.2 180.62,138.38 J9.20
CAM1_GIO0: length 6.1
  BOTTOM w0.173: J9.16 177.95,138.51 R259.1
CAM1_HSYNC: length 6.1
  TOP w0.173: R258.2 162.71,138.51 J9.4
CAM1_PCLK: length 3
  TOP w0.173: R265.1 J9.9
CAM1_VSYNC: length 2.7
  TOP w0.173: R257.2 159,139.68 J9.2
CAM1_WEN: length 3
  TOP w0.173: J9.19 R273.1
CAM_ENN: length 115
  TOP w0.173: 124.59,68.28 v3(125.35,68.28)
  L3_SIG1 w0.109: v5(164.34,114.13) 164.34,114.13 172.18,121.97 172.18,129.36 177.91,135.09 177.91,138.21 J9.18 ; v5(165.1,81) 163.22,81 160.87,78.66 159,78.66 157.16,76.81 153.8,76.81 153.27,77.34 150.13,77.34 146.06,73.27 141.34,73.27 140.08,72.01 135.26,72.01 133.91,70.66 133.78,70.66 131.6,68.48 125.55,68.48 v3(125.35,68.28)
  L10_SIG4 w0.109: v5(164.34,114.13) 164.34,108.97 169.42,103.89 169.42,92.86 168.12,91.56 168.12,88.45 166.87,87.21 166.87,85.58 166.25,84.95 166.25,83.27 165.1,82.12 v5(165.1,81)
CAN1_H: length 19.1
  BOTTOM w0.173: U41.7 158.65,20.37 158.48,20.2 156.27,20.2 155.48,19.4 155.48,15.79 157.08,14.19 157.08,13.7 U88.1 157.13,12.92 157.13,11.91 156.52,11.31 155.91,11.31 R503.2 155.24,11.31 154.48,11.31 153.76,10.59 152.95,10.59 152.78,10.76 J38.2
CAN1_L: length 19.2
  BOTTOM w0.173: J38.3 152.78,10.07 152.95,10.24 153.91,10.24 154.63,10.95 155.24,10.95 R503.1 155.91,10.95 156.67,10.95 157.48,11.77 157.48,12.95 U87.1 157.43,13.78 157.43,14.33 155.83,15.93 155.83,19.26 156.42,19.84 158.48,19.84 158.65,19.67 U41.6
CAN1_RXDF: length 159
  L10_SIG4 w0.109: J21.41 142.57,145.8 160.02,145.8 165.51,140.31 165.51,135.82 164.87,135.18 164.87,108.94 169.8,104.01 169.8,96.88 170.79,95.89 170.79,92.05 170.05,91.31 169.22,91.31 168.41,90.5 168.41,87.18 167.61,86.39 167.61,80.5 168.48,79.64 168.48,78.41 168.21,78.15 168.21,73.09 168.85,72.45 168.85,71.06 167.13,69.34 167.13,63.33 167.68,62.78 167.68,60.52 168.63,59.56 168.63,59.08 170.99,56.72 170.99,43.18 169.8,41.99 169.8,27.89 172.97,24.72 172.97,23.94 171.98,22.95 171.98,22.84 v7(171.2,22.05)
  BOTTOM w0.173: v7(171.2,22.05) R502.2 U41.2
CAN1_TXDF: length 167.9
  L10_SIG4 w0.109: J21.43 144.38,148.05 144.38,149.42 145.17,150.22 160.93,150.22 162.05,149.1 162.05,146.77 167.86,140.97 167.86,135.88 165.89,133.91 165.89,131.3 165.48,130.89 165.48,109.09 170.18,104.4 170.18,97.79 171.96,96 171.96,89.28 170.13,87.45 170.13,82.35 169.21,81.43 169.21,80.67 171.25,78.64 171.25,75.37 171.83,74.78 171.83,72.77 171.07,72.01 171.07,70.87 169.41,69.22 169.41,64.02 170.05,63.37 170.05,62.86 172.5,60.42 172.5,58.41 173.29,57.61 173.29,26.69 174.37,25.61 174.37,21.54 v7(172.34,19.51)
  BOTTOM w0.173: U41.3 C254.1 R504.2 v7(172.34,19.51)
DDR_A0: length 146.4
  TOP w0.173: U6.N3 v8(115.39,28.28) ; U5.N3 v8(84.91,28.28) ; U7.N3 v8(100.15,28.28) ; U1.AD20 v4(94.24,76.82)
  L3_SIG1 w0.109: v8(115.39,28.28) 114.23,28.28 113.03,27.08 112.32,27.08 111.84,26.6 108.97,26.6 108.82,26.45 108.57,26.45 108.42,26.6 108.16,26.6 108.01,26.45 107.76,26.45 107.61,26.6 107.35,26.6 107.21,26.45 106.95,26.45 106.8,26.6 105.74,26.6 105.26,27.08 104.72,27.08 104.32,27.49 103.89,27.49 103.83,27.43 103.03,27.43 102.59,27.87 101.4,27.87 100.99,28.28 v8(100.15,28.28) 99.04,28.28 97.84,27.08 97.23,27.08 96.75,26.6 96.15,26.6 96,26.45 95.75,26.45 95.6,26.6 95.34,26.6 95.2,26.45 94.94,26.45 94.79,26.6 94.54,26.6 94.39,26.45 94.13,26.45 93.98,26.6 93.73,26.6 93.58,26.45 93.33,26.45 93.18,26.6 92.92,26.6 92.77,26.45 92.52,26.45 92.37,26.6 92.11,26.6 91.97,26.45 91.71,26.45 91.56,26.6 91.31,26.6 91.16,26.45 90.9,26.45 90.75,26.6 90.47,26.6 89.99,27.08 89.48,27.08 89.1,27.46 88.63,27.46 88.59,27.43 87.73,27.43 87.3,27.86 86.16,27.86 85.75,28.28 v8(84.91,28.28) ; v4(94.24,76.82) v5(93.84,76.57)
  L10_SIG4 w0.109: v7(72.69,23.37) 72.69,23.84 70.99,25.53 70.99,39.6 74.41,43.01 74.41,45.22 74.3,45.33 73.95,45.33 73.84,45.44 73.84,45.66 73.95,45.77 74.3,45.77 74.41,45.88 74.41,46.1 74.3,46.21 73.72,46.21 73.61,46.32 73.61,46.54 73.72,46.64 74.3,46.64 74.41,46.75 74.41,46.97 74.3,47.08 73.72,47.08 73.61,47.19 73.61,47.41 73.72,47.52 74.3,47.52 74.41,47.63 74.41,47.85 74.3,47.96 73.72,47.96 73.61,48.06 73.61,48.28 73.72,48.39 74.3,48.39 74.41,48.5 74.41,48.72 74.3,48.83 73.72,48.83 73.61,48.94 73.61,49.16 73.72,49.27 74.3,49.27 74.41,49.38 74.41,49.59 74.3,49.7 73.72,49.7 73.61,49.81 73.61,50.03 73.72,50.14 74.3,50.14 74.41,50.25 74.41,50.47 74.3,50.58 73.72,50.58 73.61,50.69 73.61,50.9 73.72,51.01 74.3,51.01 74.41,51.12 74.41,51.34 74.3,51.45 73.72,51.45 73.61,51.56 73.61,51.78 73.72,51.89 74.3,51.89 74.41,52 74.41,52.22 74.3,52.32 73.72,52.32 73.61,52.43 73.61,52.65 73.72,52.76 74.3,52.76 74.41,52.87 74.41,53.09 74.3,53.2 73.72,53.2 73.61,53.31 73.61,53.53 73.72,53.63 74.3,53.63 74.41,53.74 74.41,53.96 74.3,54.07 73.72,54.07 73.61,54.18 73.61,54.4 73.72,54.51 74.3,54.51 74.41,54.62 74.41,54.84 74.3,54.95 73.72,54.95 73.61,55.05 73.61,55.27 73.72,55.38 74.3,55.38 74.41,55.49 74.41,55.71 74.3,55.82 73.72,55.82 73.61,55.93 73.61,56.15 73.72,56.26 74.3,56.26 74.41,56.37 74.41,56.58 74.3,56.69 73.72,56.69 73.61,56.8 73.61,57.02 73.72,57.13 74.3,57.13 74.41,57.24 74.41,64.99 85.27,75.85 89.15,75.85 90.35,77.04 91.69,77.04 92.17,76.57 v5(93.84,76.57)
  BOTTOM w0.173: v8(115.39,28.28) 115.39,27.27 115.81,26.85 115.81,26.17 115.68,26.05 115.68,25.42 117.5,23.61 117.5,23.6 118.24,22.86 R54.2 ; v7(72.69,23.37) 81.73,23.37 83.84,25.49 83.84,26.8 84.91,27.86 v8(84.91,28.28)
DDR_A1: length 145.9
  TOP w0.173: U6.P7 v8(117.53,27.48) 116.88,27.48 116.4,26.99 116.4,26.42 116.59,26.24 116.59,23.11 116.46,22.99 R57.2 ; U5.P7 v8(87.05,27.48) ; U1.AC19 v4(95.04,77.62) ; U7.P7 v8(102.29,27.48)
  L3_SIG1 w0.109: v4(95.04,77.62) v5(94.64,77.37)
  L10_SIG4 w0.109: v7(72.03,19.13) 71.5,19.66 71.5,23.47 70.08,24.9 70.08,39.47 72.62,42.01 72.62,58.79 72.73,58.9 73.25,58.9 73.36,59 73.36,59.22 73.25,59.33 72.73,59.33 72.62,59.44 72.62,59.66 72.73,59.77 73.25,59.77 73.36,59.88 73.36,60.1 73.25,60.21 72.73,60.21 72.62,60.32 72.62,60.53 72.73,60.64 73.25,60.64 73.36,60.75 73.36,60.97 73.25,61.08 72.73,61.08 72.62,61.19 72.62,61.41 72.73,61.52 73.25,61.52 73.36,61.63 73.36,61.84 73.25,61.95 72.73,61.95 72.62,62.06 72.62,62.28 72.73,62.39 73.25,62.39 73.36,62.5 73.36,62.72 73.25,62.83 72.73,62.83 72.62,62.94 72.62,63.84 85.5,76.71 89.54,76.71 90.27,77.45 92.23,77.45 92.71,76.97 94.24,76.97 v5(94.64,77.37) ; v8(117.53,27.48) 116.67,27.48 116.26,27.89 115.95,27.89 115.44,27.39 114.1,27.39 112.98,26.27 108,26.27 107.87,26.14 107.58,26.14 107.46,26.26 107.14,26.26 107.03,26.14 107.03,26 106.91,25.88 106.74,25.88 106.62,26 106.62,26.14 106.5,26.26 106.1,26.26 105.28,27.08 104.7,27.08 104.3,27.48 v8(102.29,27.48) 101.41,27.48 101.02,27.87 100.69,27.87 100.23,27.41 98.88,27.41 97.74,26.27 93.61,26.27 93.39,26.05 93.15,26.05 92.94,26.26 92.71,26.26 92.59,26.14 92.59,26 92.48,25.88 92.31,25.88 92.19,26 92.19,26.14 92.07,26.26 91.9,26.26 91.79,26.14 91.79,26 91.67,25.88 91.5,25.88 91.38,26 91.38,26.14 91.26,26.26 90.86,26.26 90.04,27.08 89.53,27.08 89.14,27.48 v8(87.05,27.48)
  BOTTOM w0.173: v7(72.03,19.13) 83.88,19.13 86.61,21.86 86.61,26.03 87.05,26.47 v8(87.05,27.48)
DDR_A2: length 147.3
  TOP w0.173: U6.P3 v8(116.1,27.48) ; U5.P3 v8(85.62,27.48) ; U7.P3 v8(100.86,27.48) ; U1.AC20 v4(95.04,76.82)
  L3_SIG1 w0.109: v8(85.62,27.48) 86.02,27.08 86.49,27.08 86.89,26.67 88.23,26.67 89.59,25.32 94.86,25.32 95.02,25.49 95.34,25.49 95.5,25.32 97.45,25.32 97.99,25.87 97.99,26.42 98.35,26.78 98.82,26.78 99.52,27.48 v8(100.86,27.48) 101.26,27.08 101.75,27.08 102.16,26.67 103.47,26.67 104.66,25.49 112.85,25.49 113.26,25.89 113.26,26.45 113.49,26.67 113.96,26.67 114.76,27.48 v8(116.1,27.48) ; v4(95.04,76.82) v5(94.64,76.57)
  L10_SIG4 w0.109: v7(73.94,21.25) 73.94,24.24 71.91,26.27 71.91,39.67 75.56,43.33 75.56,44.96 75.67,45.06 76.22,45.06 76.33,45.17 76.33,45.39 76.22,45.5 75.67,45.5 75.56,45.61 75.56,45.83 75.67,45.94 76.22,45.94 76.33,46.05 76.33,46.27 76.22,46.38 75.67,46.38 75.56,46.48 75.56,46.7 75.67,46.81 76.22,46.81 76.33,46.92 76.33,47.14 76.22,47.25 75.67,47.25 75.56,47.36 75.56,47.58 75.67,47.69 76.22,47.69 76.33,47.8 76.33,48.01 76.22,48.12 75.67,48.12 75.56,48.23 75.56,48.45 75.67,48.56 76.22,48.56 76.33,48.67 76.33,48.89 76.22,49 75.67,49 75.56,49.11 75.56,49.32 75.67,49.43 76.22,49.43 76.33,49.54 76.33,49.76 76.22,49.87 75.67,49.87 75.56,49.98 75.56,50.2 75.67,50.31 76.22,50.31 76.33,50.42 76.33,50.63 76.22,50.74 75.67,50.74 75.56,50.85 75.56,51.07 75.67,51.18 76.22,51.18 76.33,51.29 76.33,51.51 76.22,51.62 75.67,51.62 75.56,51.73 75.56,51.95 75.67,52.05 76.22,52.05 76.33,52.16 76.33,52.38 76.22,52.49 75.67,52.49 75.56,52.6 75.56,52.82 75.67,52.93 76.17,52.93 76.28,53.04 76.28,53.26 76.17,53.37 75.67,53.37 75.56,53.47 75.56,53.69 75.67,53.8 76.14,53.8 76.25,53.91 76.25,54.13 76.14,54.24 75.67,54.24 75.56,54.35 75.56,54.57 75.67,54.68 76.14,54.68 76.25,54.79 76.25,55 76.14,55.11 75.67,55.11 75.56,55.22 75.56,55.3 75.57,55.3 75.57,65.51 85.45,75.39 89.77,75.39 90.04,75.67 91.28,75.67 91.79,76.17 94.24,76.17 v5(94.64,76.57)
  BOTTOM w0.173: v8(85.62,27.48) 85.62,26.57 85.09,26.03 85.09,23.65 82.7,21.25 v7(73.94,21.25) ; v8(116.1,27.48) 116.1,26.47 116.52,26.05 116.52,25.77 119.25,23.04 R55.2
DDR_A3: length 146.2
  TOP w0.173: U5.N2 v8(83.18,28.68) ; U1.AB19 v4(95.84,77.62) ; U7.N2 v8(98.42,28.68) ; U6.N2 v8(113.66,28.68)
  L3_SIG1 w0.109: v8(113.66,28.68) 112.85,27.87 112.37,27.87 111.56,27.06 109.63,27.06 109.48,27.21 109.24,27.21 109.09,27.06 108.78,27.06 108.6,27.24 108.4,27.24 108.22,27.06 107.98,27.06 107.79,27.24 107.6,27.24 107.39,27.03 106.18,27.03 105.34,27.87 103.86,27.87 103.45,28.28 103.08,28.28 102.99,28.19 102.25,28.19 101.76,28.68 v8(98.42,28.68) 97.61,27.87 97.13,27.87 96.3,27.03 95.18,27.03 94.98,27.24 94.78,27.24 94.59,27.06 94.35,27.06 94.17,27.24 93.97,27.24 93.79,27.06 93.54,27.06 93.36,27.24 93.16,27.24 92.98,27.06 92.74,27.06 92.55,27.24 92.36,27.24 92.15,27.03 91.95,27.03 91.74,27.24 91.55,27.24 91.34,27.03 90.94,27.03 90.1,27.87 88.54,27.87 88.14,28.28 87.71,28.28 87.62,28.19 87.01,28.19 86.52,28.68 v8(83.18,28.68) ; v4(95.84,77.62) v5(95.44,77.37)
  L10_SIG4 w0.109: v7(69.16,26.85) 69.16,39.32 70.73,40.89 70.73,42.26 70.87,42.4 71.83,42.4 72.04,42.61 72.04,43.13 71.93,43.24 70.98,43.24 70.87,43.35 70.87,43.57 70.98,43.68 71.93,43.68 72.04,43.79 72.04,44 71.93,44.11 70.98,44.11 70.87,44.22 70.87,44.44 70.98,44.55 71.93,44.55 72.04,44.66 72.04,44.88 71.93,44.99 70.98,44.99 70.87,45.1 70.87,45.32 70.98,45.42 71.93,45.42 72.04,45.53 72.04,45.75 71.93,45.86 70.98,45.86 70.87,45.97 70.87,46.19 70.98,46.3 71.93,46.3 72.04,46.41 72.04,46.63 71.93,46.73 70.98,46.73 70.87,46.84 70.87,47.06 70.98,47.17 71.93,47.17 72.04,47.28 72.04,47.5 71.93,47.61 70.98,47.61 70.87,47.72 70.87,47.94 70.98,48.05 71.93,48.05 72.04,48.15 72.04,48.37 71.93,48.48 70.98,48.48 70.87,48.59 70.87,48.81 70.98,48.92 71.93,48.92 72.04,49.03 72.04,49.25 71.93,49.36 70.98,49.36 70.87,49.47 70.87,49.68 70.98,49.79 71.93,49.79 72.04,49.9 72.04,50.12 71.93,50.23 70.9,50.23 70.79,50.34 70.79,50.56 70.9,50.67 71.93,50.67 72.04,50.78 72.04,63.92 85.29,77.17 89.52,77.17 90.1,77.75 95.05,77.75 v5(95.44,77.37)
  BOTTOM w0.102: 81.46,27.48 81.84,27.86 82.37,27.86 v8(83.18,28.68)
  BOTTOM w0.173: v8(113.66,28.68) 113.21,28.23 113.21,23.19 R58.2 ; v7(69.16,26.85) 69.49,26.85 69.5,26.85 80.82,26.85 81.46,27.48
DDR_A4: length 145.2
  TOP w0.173: U7.P8 v8(103.22,27.88) ; U1.AF21 v4(92.64,76.02) ; U5.P8 v8(87.98,27.88) ; R59.2 122.55,26.29 120.98,27.86 120.05,27.86 120.04,27.88 v8(118.46,27.88) U6.P8
  L3_SIG1 w0.099: 92.23,76.02 92.03,75.82
  L3_SIG1 w0.109: v5(75.13,38.21) 75.13,48.39 74.55,48.98 74.55,52.91 75.95,54.31 75.95,64.65 78.69,67.39 81.53,67.39 89.97,75.82 92.03,75.82 ; v4(92.64,76.02) 92.23,76.02
  L10_SIG4 w0.109: v7(76.86,16.87) 75.52,16.87 74.51,17.87 73.37,17.87 73.23,18.02 73.23,18.22 73.36,18.35 75.06,18.35 75.2,18.49 75.2,18.69 75.06,18.83 73.57,18.83 73.43,18.97 73.43,19.17 73.57,19.31 75.06,19.31 75.2,19.45 75.2,23.22 75.6,23.61 76.41,23.61 76.82,24.02 76.82,28.01 75.13,29.69 v5(75.13,38.21) ; v8(118.46,27.88) 116.58,27.88 116.26,28.2 115.9,28.2 115.54,27.84 115.11,27.84 114.68,28.28 114.25,28.28 113.06,27.08 112.22,27.08 111.96,26.82 111.31,26.82 111.15,26.66 110.83,26.66 110.64,26.85 110.08,26.85 109.96,26.73 109.45,26.73 109.35,26.82 106.3,26.82 105.24,27.88 v8(103.22,27.88) 101.36,27.88 101.02,28.22 100.66,28.22 100.3,27.87 99.82,27.87 99.39,28.3 99.03,28.3 97.82,27.08 97.23,27.08 96.97,26.82 96.86,26.82 96.67,26.63 96.45,26.63 96.26,26.82 96.02,26.82 95.9,26.94 95.9,27.12 95.78,27.23 95.61,27.23 95.5,27.12 95.5,26.94 95.38,26.82 91.06,26.82 90,27.88 v8(87.98,27.88)
  BOTTOM w0.173: v7(76.86,16.87) 77.5,16.23 85.62,16.23 89.46,20.07 89.46,24.66 89.01,25.12 89.01,26.06 87.98,27.08 v8(87.98,27.88)
DDR_A5: length 146.1
  TOP w0.173: v3(79.12,64.98) 79.12,67.14 86.97,74.98 88.15,74.98 88.78,75.62 U1.AH22 ; U5.P2 v8(83.98,27.88) ; U6.P2 v8(114.46,27.88) ; U7.P2 v8(99.22,27.88)
  L3_SIG1 w0.109: v5(77.42,39.75) 77.42,52.84 78.71,54.13 78.71,64.57 v3(79.12,64.98) ; v8(114.46,27.88) 114.07,27.49 114.07,27.25 113.72,26.9 113.28,26.9 113.03,26.65 113.03,26.45 112.85,26.27 112.42,26.27 112.12,25.96 107.32,25.96 107.2,25.84 106.77,25.84 106.65,25.96 105.64,25.96 105.33,26.27 104.72,26.27 104.36,26.62 103.91,26.62 103.45,27.08 102.14,27.08 101.88,27.34 101.55,27.34 101.01,27.88 v8(99.22,27.88) 98.83,27.49 98.83,27.25 98.61,27.03 98.3,27.03 97.54,26.27 97.21,26.27 96.83,25.89 93.91,25.89 93.78,25.76 93.53,25.76 93.38,25.92 93.13,25.92 92.98,25.76 92.72,25.76 92.6,25.89 92.32,25.89 92.17,25.74 91.92,25.74 91.76,25.89 91.51,25.89 91.36,25.74 91.11,25.74 90.96,25.89 90.32,25.89 89.94,26.27 89.48,26.27 89.07,26.67 88.62,26.67 88.24,27.06 86.89,27.06 86.64,27.31 86.33,27.31 85.77,27.88 v8(83.98,27.88)
  L10_SIG4 w0.109: v7(79.17,25.25) 80.16,25.25 80.98,24.44 80.98,18.1 80.26,17.38 79.89,17.38 79.75,17.52 79.75,18.23 79.61,18.37 79.41,18.37 79.27,18.22 79.27,17.52 79.13,17.38 78.92,17.38 78.63,17.67 78.63,18.65 78.77,18.79 80.14,18.79 80.27,18.92 80.27,19.12 80.12,19.27 78.77,19.27 78.63,19.41 78.63,19.61 78.77,19.75 80.13,19.75 80.27,19.89 80.27,20.09 80.13,20.23 78.77,20.23 78.63,20.37 78.63,20.57 78.77,20.71 80.13,20.71 80.27,20.85 80.27,21.05 80.13,21.19 78.77,21.19 78.63,21.33 78.63,21.53 78.77,21.67 80.13,21.67 80.27,21.81 80.27,22.01 80.13,22.15 78.77,22.15 78.63,22.29 78.63,22.49 78.77,22.63 80.13,22.63 80.27,22.77 80.27,22.97 80.13,23.11 78.77,23.11 78.63,23.25 78.63,23.51 78.77,23.65 79.35,23.65 79.5,23.8 79.5,23.99 79.37,24.13 78.75,24.13 78.64,24.24 78.64,25.56 80.23,27.16 80.23,32.64 79.76,33.12 79.76,37.46 77.47,39.75 v5(77.42,39.75)
  BOTTOM w0.173: v7(79.17,25.25) 79.2,25.25 79.2,25.25 82.17,25.25 82.75,25.83 82.75,26.59 83.98,27.82 v8(83.98,27.88) ; R60.2 116.2,24.03 114.46,25.78 v8(114.46,27.88)
DDR_A6: length 146.9
  TOP w0.173: v3(81.53,63.63) 81.53,66.5 87.84,72.81 88.22,72.81 89.83,74.41 91.83,74.41 U1.AG23 ; U6.R8 v8(119.26,27.08) ; U7.R8 v8(104.02,27.08) ; U5.R8 v8(88.78,27.08)
  L3_SIG1 w0.109: v3(81.53,63.63) 81.53,62.83 81.64,62.72 82.01,62.72 82.12,62.61 82.12,62.39 82.01,62.28 81.64,62.28 81.53,62.17 81.53,61.95 81.64,61.84 82.01,61.84 82.12,61.73 82.12,61.51 82.01,61.41 81.64,61.41 81.53,61.3 81.53,61.08 81.64,60.97 82.01,60.97 82.12,60.86 82.12,60.64 82.01,60.53 81.64,60.53 81.53,60.42 81.53,51.31 79,48.78 79,48.35 79.11,48.23 79.83,48.23 79.95,48.11 79.95,47.95 79.84,47.83 79.11,47.83 79,47.72 79,47.55 79.11,47.44 79.84,47.44 79.96,47.32 79.96,47.16 79.84,47.04 79.11,47.04 79,46.93 79,46.76 79.11,46.65 79.77,46.65 79.88,46.53 79.88,46.37 79.77,46.25 79.11,46.25 79,46.13 79,45.97 79.11,45.85 79.77,45.85 79.88,45.74 79.88,45.57 79.77,45.46 79.11,45.46 79,45.34 79,45.18 79.11,45.06 79.89,45.06 80.01,44.94 80.01,44.78 79.89,44.66 79.11,44.66 79,44.55 79,43.81 79.38,43.43 79.76,43.43 80.52,42.67 80.52,38.1 80.06,37.65 78.81,37.65 78.33,38.13 78.33,39.28 78.47,39.42 79.96,39.42 80.1,39.57 80.1,39.76 79.96,39.9 78.47,39.9 78.33,40.05 78.33,40.24 78.47,40.38 79.96,40.38 80.1,40.53 80.1,40.72 79.96,40.86 78.47,40.86 78.33,41.01 78.33,41.2 78.47,41.34 79.96,41.34 80.1,41.49 80.1,41.68 79.96,41.82 78.47,41.82 78.33,41.97 v5(78.33,43.13)
  L10_SIG4 w0.109: v5(78.33,43.13) v7(78.33,41.78) ; v8(119.26,27.08) 115.18,27.08 113.97,25.86 113.59,25.86 113.21,25.48 111.76,25.48 111.59,25.65 111.27,25.65 111.11,25.5 110.79,25.5 110.63,25.65 110.31,25.65 110.15,25.5 109.83,25.5 109.67,25.65 109.35,25.65 109.19,25.5 108.87,25.5 108.71,25.65 108.39,25.65 108.23,25.5 106.08,25.5 105.31,26.27 104.83,26.27 v8(104.02,27.08) 99.97,27.08 98.73,25.84 98.32,25.84 97.97,25.48 96.82,25.48 96.69,25.62 96.69,25.7 96.57,25.82 96.4,25.82 96.29,25.7 96.29,25.62 96.17,25.5 96,25.5 95.88,25.62 95.88,25.7 95.76,25.81 95.6,25.81 95.48,25.7 95.48,25.62 95.36,25.5 95.04,25.5 94.92,25.61 94.92,25.68 94.8,25.8 94.64,25.8 94.53,25.69 94.53,25.61 94.41,25.5 90.84,25.5 90.07,26.27 89.59,26.27 v8(88.78,27.08)
  BOTTOM w0.173: R61.2 119.89,25.02 119.26,25.65 v8(119.26,27.08) ; v8(88.78,27.08) 89.23,27.53 89.23,29.51 89.81,30.1 91.23,30.1 93.09,31.96 93.09,39.52 90.83,41.78 v7(78.33,41.78)
DDR_A7: length 143.7
  TOP w0.173: R62.2 113.16,24.89 113.66,25.39 v8(113.66,26.28) U6.R2 ; U5.R2 v8(83.18,26.28) ; U1.AE21 v4(93.44,76.02) ; U7.R2 v8(98.42,26.28)
  L3_SIG1 w0.099: v4(93.44,76.02) 93.05,76.02 92.76,76.31 92.13,76.31 91.98,76.15
  L3_SIG1 w0.109: v8(83.18,26.28) 83.86,26.28 84.66,27.08 85.09,27.08 85.32,26.85 85.6,26.85 86.16,26.29 87.25,26.29 88.75,24.79 94.57,24.79 94.72,24.94 95.05,24.94 95.2,24.79 95.51,24.79 95.69,24.97 95.92,24.97 96.09,24.79 97.23,24.79 98.42,25.98 v8(98.42,26.28) 99.1,26.28 99.9,27.08 100.61,27.08 101.4,26.29 102.49,26.29 103.88,24.9 112.68,24.9 113.66,25.88 v8(113.66,26.28) ; 91.98,76.15 89.66,76.15 81.36,67.85 78.41,67.85 75.44,64.88 75.44,54.44 74.05,53.05 74.05,48.77 74.68,48.14 74.68,47.58 74.57,47.47 74.33,47.47 74.22,47.36 74.22,47.14 74.33,47.03 74.57,47.03 74.68,46.92 74.68,46.57 74.57,46.46 73.64,46.46 73.53,46.35 73.53,46.13 73.64,46.02 74.57,46.02 74.68,45.91 74.68,45.69 74.57,45.58 73.64,45.58 73.53,45.48 73.53,45.26 73.64,45.15 74.57,45.15 74.68,45.04 74.68,44.82 74.57,44.71 73.64,44.71 73.53,44.6 73.53,44.38 73.64,44.27 74.57,44.27 74.68,44.16 74.68,43.95 74.57,43.84 73.64,43.84 73.53,43.73 73.53,43.51 73.64,43.4 74.57,43.4 74.68,43.29 74.68,43.07 74.57,42.96 73.64,42.96 73.53,42.85 73.53,42.64 73.64,42.53 74.57,42.53 74.68,42.42 74.68,42.2 74.57,42.09 73.64,42.09 73.53,41.98 73.53,41.76 73.64,41.65 74.57,41.65 74.68,41.54 v5(74.68,39.75)
  L10_SIG4 w0.109: v7(75.95,24.26) 76.37,24.67 76.37,25.29 76.26,25.4 74.89,25.4 74.78,25.5 74.78,25.72 74.89,25.83 76.26,25.83 76.37,25.94 76.37,26.16 76.26,26.27 74.89,26.27 74.78,26.38 74.78,26.6 74.89,26.71 76.26,26.71 76.37,26.82 76.37,27.77 74.68,29.46 v5(74.68,39.75)
  BOTTOM w0.173: v8(83.18,26.28) 83.18,25.65 81.79,24.26 78.82,24.26 77.65,25.43 71.86,25.43 71.65,25.22 71.65,24.48 71.88,24.24 75.94,24.24 v7(75.95,24.26)
DDR_A8: length 143.6
  TOP w0.173: U1.AF22 v4(92.64,75.22) ; U7.T8 v8(103.22,26.28) ; v8(118.46,26.28) U6.T8 120.27,24.47 R63.2 ; U5.T8 v8(87.98,26.28)
  L3_SIG1 w0.109: v5(76.5,39.75) 76.5,52.89 77.37,53.75 77.37,54.05 77.48,54.16 77.97,54.16 78.08,54.27 78.08,54.49 77.97,54.6 77.48,54.6 77.37,54.71 77.37,54.93 77.48,55.03 78.15,55.03 78.26,55.14 78.26,55.36 78.15,55.47 77.48,55.47 77.37,55.58 77.37,55.8 77.48,55.91 78.15,55.91 78.26,56.02 78.26,56.24 78.15,56.35 77.48,56.35 77.37,56.45 77.37,56.67 77.48,56.78 78.15,56.78 78.26,56.89 78.26,57.11 78.15,57.22 77.48,57.22 77.37,57.33 77.37,57.55 77.48,57.66 78.15,57.66 78.26,57.77 78.26,57.98 78.15,58.09 77.48,58.09 77.37,58.2 77.37,58.42 77.48,58.53 78.15,58.53 78.26,58.64 78.26,58.86 78.15,58.97 77.48,58.97 77.37,59.08 77.37,59.29 77.48,59.4 78.15,59.4 78.26,59.51 78.26,59.73 78.15,59.84 77.48,59.84 77.37,59.95 77.37,60.17 77.48,60.28 78.15,60.28 78.26,60.39 78.26,60.6 78.15,60.71 77.48,60.71 77.37,60.82 77.37,61.04 77.48,61.15 78.15,61.15 78.26,61.26 78.26,61.48 78.15,61.59 77.48,61.59 77.37,61.7 77.37,61.92 77.48,62.02 78.15,62.02 78.26,62.13 78.26,62.35 78.15,62.46 77.48,62.46 77.37,62.57 77.37,62.79 77.48,62.9 78.15,62.9 78.26,63.01 78.26,63.23 78.15,63.34 77.48,63.34 77.37,63.44 77.37,63.89 79.5,66.02 82.07,66.02 91.06,75.01 92.43,75.01 v4(92.64,75.22)
  L10_SIG4 w0.109: v5(76.5,39.75) 76.5,37.55 76.76,37.29 76.76,30.36 78.18,28.94 78.18,17.04 v7(78.11,16.97) ; v8(118.46,26.28) 117.09,26.28 116.19,25.38 113.84,25.38 112.74,24.28 104.79,24.28 103.22,25.86 v8(103.22,26.28) 101.85,26.28 100.9,25.33 98.55,25.33 97.18,23.96 93.37,23.96 93.23,24.1 93.23,24.18 93.09,24.32 92.89,24.32 92.75,24.18 92.75,24.1 92.61,23.96 90.3,23.96 v8(87.98,26.28)
  BOTTOM w0.173: v7(78.11,16.97) 84.99,16.97 88.75,20.73 88.75,24.74 87.98,25.51 v8(87.98,26.28)
DDR_A9: length 144.1
  TOP w0.173: U6.R3 v8(115.39,26.68) 115,26.29 114.68,26.29 114.45,26.06 114.45,24.83 114.48,24.81 114.48,23.8 114.17,23.49 R64.2 ; U7.R3 v8(100.15,26.68) ; U1.AE22 v4(93.44,75.22) ; U5.R3 v8(84.91,26.68)
  L3_SIG1 w0.099: 92.2,75.27 92.44,75.51 92.82,75.51 93.12,75.22 v4(93.44,75.22)
  L3_SIG1 w0.109: v8(115.39,26.68) 114.91,26.2 114.91,26.2 112.94,24.23 103.1,24.23 101.02,26.32 100.51,26.32 v8(100.15,26.68) 99.67,26.2 99.67,26.2 97.7,24.23 96.17,24.23 96.05,24.11 95.78,24.11 95.66,24.23 95.36,24.23 95.26,24.12 94.96,24.12 94.85,24.23 87.86,24.23 85.83,26.27 85.32,26.27 v8(84.91,26.68) ; 92.2,75.27 90.68,75.27 81.89,66.48 79.3,66.48 76.91,64.09 76.91,53.98 76.05,53.12 76.05,37.78 76.79,37.04 76.79,29.68 76.39,29.28 75.45,29.28 75.03,29.7 75.03,30.28 75.17,30.42 75.71,30.42 75.86,30.57 75.86,30.77 75.72,30.9 75.17,30.9 75.03,31.04 75.03,31.35 75.17,31.49 75.82,31.49 75.96,31.63 75.96,31.83 75.82,31.97 75.17,31.97 75.03,32.11 75.03,32.31 75.17,32.45 75.82,32.45 75.96,32.59 75.96,32.79 75.82,32.93 75.17,32.93 75.03,33.07 75.03,33.27 75.17,33.41 75.82,33.41 75.96,33.55 75.96,33.75 75.82,33.89 75.17,33.89 75.03,34.03 75.03,34.23 75.17,34.37 75.82,34.37 75.96,34.51 75.96,34.71 75.82,34.85 75.17,34.85 75.03,34.99 75.03,35.19 75.17,35.33 75.82,35.33 75.96,35.47 75.96,35.67 75.82,35.81 75.17,35.81 75.03,35.95 75.03,36.67 75.34,36.98 v5(76.17,36.98)
  L10_SIG4 w0.109: v5(76.17,36.98) 76.15,36.96 76.15,30.26 77.7,28.71 77.7,22.04 v7(77.63,21.97)
  BOTTOM w0.173: v7(77.63,21.97) 77.64,21.96 82.41,21.96 84.55,24.11 84.55,26.32 v8(84.91,26.68)
DDR_A10: length 146.7
  TOP w0.173: U5.L7 v8(86.34,29.88) ; U1.AD21 v4(94.24,76.02) ; R66.2 122.71,31.88 120.9,30.07 120.22,30.07 120.02,30.28 118.69,30.28 118.29,29.88 U6.L7 v8(116.82,29.88) ; U7.L7 v8(101.58,29.88)
  L3_SIG1 w0.099: v4(94.24,76.02) 93.85,76.02 93.35,76.51 92.53,76.51 92.13,76.91 92.13,76.94 91.84,77.22
  L3_SIG1 w0.109: v5(74.22,36.96) 74.45,36.73 74.45,30.12 74.25,29.92 73.6,29.92 73.42,30.09 73.42,32.55 73.28,32.69 72.1,32.69 71.96,32.83 71.96,33.03 72.1,33.17 73.28,33.17 73.42,33.31 73.42,33.51 73.28,33.65 72.1,33.65 71.96,33.79 71.96,33.99 72.1,34.13 73.28,34.13 73.42,34.27 73.42,34.47 73.28,34.61 72.1,34.61 71.96,34.75 71.96,34.95 72.1,35.09 73.28,35.09 73.42,35.23 73.42,35.43 73.28,35.57 72.1,35.57 71.96,35.71 71.96,35.91 72.1,36.05 73.28,36.05 73.42,36.19 73.42,36.98 74.17,37.72 74.17,40.31 73.05,41.43 73.05,47.25 73.61,47.81 73.61,53.32 74.98,54.69 74.98,65.13 78.21,68.36 81.05,68.36 89.92,77.22 91.84,77.22
  L10_SIG4 w0.109: v8(116.82,29.88) 116.41,30.28 114.66,30.28 113.84,29.47 112.13,29.47 111.91,29.25 111.71,29.25 111.51,29.46 111.31,29.46 111.19,29.34 111.19,29.1 111.07,28.98 110.9,28.98 110.79,29.1 110.79,29.34 110.67,29.46 106.41,29.46 105.8,30.06 104.12,30.06 103.94,29.88 v8(101.58,29.88) 101.17,30.28 99.39,30.28 98.58,29.47 96.92,29.47 96.79,29.34 96.79,29.24 96.67,29.12 96.51,29.12 96.39,29.24 96.39,29.34 96.27,29.46 96.07,29.46 95.95,29.34 95.95,29.1 95.83,28.98 95.66,28.98 95.55,29.1 95.55,29.34 95.43,29.46 91.17,29.46 90.56,30.06 89.72,30.06 89.2,30.58 88.39,30.58 88.14,30.33 87.58,30.33 87.13,29.88 v8(86.34,29.88) ; v5(74.22,36.96) 74.22,29.17 v7(75.83,27.56)
  BOTTOM w0.102: 80.9,27.94 81.65,28.69 82.52,28.69 82.9,29.08 84.82,29.08 85.62,29.88 v8(86.34,29.88)
  BOTTOM w0.173: v7(75.83,27.56) 80.52,27.56 80.9,27.94
DDR_A11: length 145.3
  TOP w0.173: U5.R7 v8(86.34,26.68) ; R65.2 117.47,24.89 117.04,25.32 117.04,26.45 v8(116.82,26.68) U6.R7 ; U1.AD22 v4(94.24,75.22) ; U7.R7 v8(101.58,26.68)
  L3_SIG1 w0.099: 92.11,75.52 92.3,75.71 93.43,75.71 93.93,75.22 v4(94.24,75.22)
  L3_SIG1 w0.109: 92.11,75.52 90.3,75.52 81.71,66.93 78.99,66.93 76.45,64.39 76.45,54.16 74.99,52.69 74.99,52.18 75.1,52.08 75.43,52.08 75.54,51.97 75.54,51.75 75.43,51.64 75.1,51.64 74.99,51.53 74.99,51.31 75.1,51.2 75.43,51.2 75.54,51.09 75.54,50.87 75.43,50.76 75.1,50.76 74.99,50.66 74.99,49.18 75.59,48.58 v5(75.59,39.75)
  L10_SIG4 w0.109: v8(86.34,26.68) 88.24,26.68 90.15,24.77 90.77,24.77 90.89,24.65 90.89,24.53 91.01,24.41 91.17,24.41 91.29,24.53 91.29,24.65 91.41,24.77 91.58,24.77 91.7,24.65 91.7,24.53 91.81,24.41 91.98,24.41 92.1,24.53 92.1,24.65 92.22,24.77 97.64,24.77 98.45,25.58 99.9,25.58 100.99,26.68 v8(101.58,26.68) 103.53,26.68 105.44,24.77 106.14,24.77 106.31,24.95 106.54,24.95 106.72,24.77 106.94,24.77 107.12,24.95 107.35,24.95 107.53,24.77 112.88,24.77 113.74,25.63 115.16,25.63 115.9,26.37 116.51,26.37 v8(116.82,26.68) ; v5(75.59,39.75) 75.59,29.98 77.26,28.32 77.26,23.28 77.1,23.13 75.96,23.13 75.66,22.83 75.66,22.61 75.8,22.47 76.96,22.47 77.1,22.32 77.1,22.13 76.96,21.99 75.8,21.99 75.66,21.84 75.66,21.65 75.8,21.51 77.29,21.51 77.44,21.36 77.44,21.16 77.3,21.03 75.8,21.03 75.66,20.88 75.66,20.69 75.8,20.55 76.8,20.55 76.94,20.4 76.94,20.21 76.8,20.06 75.8,20.06 75.66,19.92 75.66,19.73 75.8,19.58 76.7,19.58 76.84,19.44 76.84,19.25 76.7,19.1 75.8,19.1 75.66,18.96 75.66,18.1 76.07,17.69 76.99,17.69 77.32,18.02 v7(77.32,19.84)
  BOTTOM w0.173: v7(77.32,19.84) 83.37,19.84 85.86,22.33 85.86,23.09 86.34,23.57 v8(86.34,26.68)
DDR_A12: length 149
  TOP w0.173: U7.N7 v8(101.58,28.28) ; U5.N7 v8(86.34,28.28) ; U1.AC21 v4(95.04,76.02) ; U6.N7 v8(116.82,28.28)
  L3_SIG1 w0.109: v4(95.04,76.02) v5(94.64,75.77)
  L10_SIG4 w0.109: v8(116.82,28.28) 116.41,28.68 114.25,28.68 113.44,27.87 112.29,27.87 111.96,27.53 109.59,27.53 109.35,27.29 109.11,27.29 108.87,27.53 108.63,27.53 108.39,27.29 108.18,27.29 107.94,27.53 107.71,27.53 107.59,27.42 107.59,27.34 107.48,27.23 107.31,27.23 107.19,27.34 107.19,27.42 107.07,27.53 106.55,27.53 105.41,28.68 104.72,28.68 104.32,28.28 v8(101.58,28.28) 101.17,28.68 98.98,28.68 98.17,27.87 96.93,27.87 96.59,27.53 95.31,27.53 95.07,27.29 94.83,27.29 94.59,27.53 94.35,27.53 94.11,27.29 93.87,27.29 93.63,27.53 93.39,27.53 93.15,27.29 92.94,27.29 92.7,27.53 92.47,27.53 92.35,27.42 92.35,27.34 92.24,27.23 92.07,27.23 91.95,27.34 91.95,27.42 91.83,27.53 91.31,27.53 90.17,28.68 89.53,28.68 89.13,28.28 v8(86.34,28.28) ; v5(94.64,75.77) 94.37,75.5 91.97,75.5 91.69,75.22 90.21,75.22 89.92,74.93 85.8,74.93 77.25,66.39 77.25,56.32 77.36,56.21 77.97,56.21 78.08,56.1 78.08,55.88 77.97,55.77 77.36,55.77 77.25,55.66 77.25,55.44 77.36,55.33 77.97,55.33 78.08,55.23 78.08,55.01 77.97,54.9 77.36,54.9 77.25,54.79 77.25,54.57 77.36,54.46 77.97,54.46 78.08,54.35 78.08,54.13 77.97,54.02 77.36,54.02 77.25,53.92 77.25,53.7 77.36,53.59 77.97,53.59 78.08,53.48 78.08,53.26 77.97,53.15 77.36,53.15 77.25,53.04 77.25,52.82 77.36,52.71 77.97,52.71 78.08,52.6 78.08,52.39 77.97,52.28 77.36,52.28 77.25,52.17 77.25,51.95 77.36,51.84 77.97,51.84 78.08,51.73 78.08,51.51 77.97,51.4 77.36,51.4 77.25,51.29 77.25,51.08 77.36,50.97 77.97,50.97 78.08,50.86 78.08,50.64 77.97,50.53 77.36,50.53 77.25,50.42 77.25,50.2 77.36,50.09 77.97,50.09 78.08,49.98 78.08,49.76 77.97,49.66 77.36,49.66 77.25,49.55 77.25,49.33 77.36,49.22 77.97,49.22 78.08,49.11 78.08,48.89 77.97,48.78 77.36,48.78 77.25,48.67 77.25,48.45 77.36,48.34 77.97,48.34 78.08,48.24 78.08,48.02 77.97,47.91 77.36,47.91 77.25,47.8 77.25,47.58 77.36,47.47 77.97,47.47 78.08,47.36 78.08,47.14 77.97,47.03 77.36,47.03 77.25,46.92 77.25,46.71 77.36,46.6 77.94,46.6 78.05,46.49 78.05,46.27 77.94,46.16 77.36,46.16 77.25,46.05 77.25,45.83 77.36,45.72 77.94,45.72 78.05,45.61 78.05,45.4 77.94,45.29 77.36,45.29 77.25,45.18 77.25,44.03 72.82,39.6 72.82,34.22 72.49,33.89 72.49,26.53 74.74,24.27 v7(74.74,22.67)
  BOTTOM w0.173: v8(86.34,28.28) 85.83,28.28 84.12,26.56 84.12,24.22 83.46,23.57 83.01,23.57 82.11,22.67 v7(74.74,22.67) ; v8(116.82,28.28) 117.32,28.28 118.9,26.7 118.9,25.32 121.54,22.68 R68.2
DDR_A13: length 144.7
  TOP w0.173: U6.T3 v8(116.1,25.88) 116.1,25.78 115.32,24.99 R70.2 ; U1.AF18 v4(92.64,78.42) ; U7.T3 v8(100.86,25.88) ; U5.T3 v8(85.62,25.88)
  L3_SIG1 w0.109: v5(71.45,38.23) 70.99,38.69 70.99,53.73 71.65,54.39 71.65,66.25 72.44,67.04 72.59,67.04 72.95,66.68 73.1,66.68 73.26,66.84 73.26,66.99 72.9,67.34 72.9,67.5 73.06,67.65 73.21,67.65 73.57,67.3 73.72,67.3 73.88,67.46 73.88,67.61 73.52,67.96 73.52,68.12 73.68,68.27 73.83,68.27 74.19,67.92 74.34,67.92 74.49,68.07 74.49,68.23 74.14,68.58 74.14,68.74 74.3,68.89 74.45,68.89 74.8,68.54 74.96,68.54 75.11,68.69 75.11,68.85 74.76,69.2 74.76,69.35 74.91,69.51 75.07,69.51 75.42,69.16 75.58,69.16 75.73,69.31 75.73,69.46 75.38,69.82 75.38,69.97 75.53,70.13 75.69,70.13 76.04,69.77 76.19,69.77 76.35,69.93 76.35,70.08 76,70.44 76,70.59 82.73,77.32 86.13,77.32 86.66,77.86 88.21,77.86 88.77,78.42 v4(92.64,78.42) ; v8(116.1,25.88) 116.1,25.72 114.07,23.68 103.16,23.68 100.97,25.88 v8(100.86,25.88) 100.86,25.12 99.43,23.68 87.92,23.68 85.73,25.88 v8(85.62,25.88)
  L10_SIG4 w0.109: v5(71.45,38.23) 71.45,25.91 73.48,23.88 73.48,22.94 73.34,22.8 72.55,22.8 72.41,22.66 72.41,22.46 72.55,22.32 73.34,22.32 73.48,22.18 73.48,21.98 73.34,21.84 72.55,21.84 72.41,21.7 72.41,21.5 72.55,21.36 73.34,21.36 73.48,21.22 v7(73.48,20.55)
  BOTTOM w0.173: v7(73.48,20.55) 74.21,20.55 74.37,20.39 74.37,19.99 74.53,19.83 74.76,19.83 74.92,19.99 74.92,20.39 75.08,20.55 75.31,20.55 75.48,20.39 75.48,19.99 75.64,19.83 75.87,19.83 76.03,19.99 76.03,20.39 76.19,20.55 82.99,20.55 85.15,22.71 85.15,23.1 85.62,23.57 v8(85.62,25.88)
DDR_A14: length 143.3
  TOP w0.173: R71.2 118.49,24.91 v8(117.53,25.88) U6.T7 ; U5.T7 v8(87.05,25.88) ; U7.T7 v8(102.29,25.88) ; U1.AE17 v4(93.44,79.22)
  L3_SIG1 w0.099: 91.8,79.11 92.32,79.11 92.51,78.92 93.14,78.92 v4(93.44,79.22)
  L3_SIG1 w0.109: v5(69.62,38.21) 69.62,53.83 70.74,54.95 70.74,59.49 70.63,59.6 70.14,59.6 70.03,59.71 70.03,59.93 70.14,60.04 70.63,60.04 70.74,60.15 70.74,60.37 70.63,60.48 70.11,60.48 70,60.58 70,60.8 70.11,60.91 70.63,60.91 70.74,61.02 70.74,61.24 70.63,61.35 70.11,61.35 70,61.46 70,61.68 70.11,61.79 70.63,61.79 70.74,61.9 70.74,66.63 82.45,78.34 85.88,78.34 86.37,78.83 88.07,78.83 88.35,79.11 91.8,79.11
  L10_SIG4 w0.109: v7(71.58,18.39) 71.02,18.95 71.02,23.14 69.62,24.54 v5(69.62,38.21) ; v8(87.05,25.88) 89.44,23.49 97.1,23.49 98.7,25.09 99.34,25.09 99.46,24.97 99.46,24.91 99.58,24.79 99.74,24.79 99.86,24.91 99.86,24.97 99.98,25.09 101.5,25.09 v8(102.29,25.88) 104.32,23.84 112.69,23.84 113.97,25.13 116.78,25.13 v8(117.53,25.88)
  BOTTOM w0.173: v7(71.58,18.39) 84.14,18.39 87.33,21.58 87.33,24.81 87.05,25.09 v8(87.05,25.88)
DDR_BA0: length 147.3
  TOP w0.173: U5.M2 v8(83.98,29.48) ; U6.M2 v8(114.46,29.48) ; U1.AF17 v4(92.64,79.22) ; U7.M2 v8(99.22,29.48)
  L3_SIG1 w0.109: v8(83.98,29.48) 83.98,29.48 85.79,29.48 86.03,29.24 86.72,29.24 86.93,29.46 87.44,29.46 88.02,28.88 88.38,28.88 88.6,29.09 89.2,29.09 89.59,29.47 90.01,29.47 91.01,28.47 92.79,28.47 92.93,28.61 92.93,28.86 93.07,29 93.27,29 93.41,28.86 93.41,28.61 93.55,28.47 95.66,28.47 96.25,29.06 96.85,29.06 97.31,29.52 97.84,29.52 97.94,29.42 99.16,29.42 v8(99.22,29.48) 100.69,29.48 100.69,29.48 101.08,29.48 101.32,29.24 101.96,29.24 102.17,29.46 102.63,29.46 103.21,28.88 103.65,28.88 103.89,29.11 104.42,29.11 104.77,29.47 105.25,29.47 106.25,28.47 107.2,28.47 107.46,28.21 107.97,28.21 108.23,28.47 109.25,28.47 109.53,28.19 110.62,28.19 111.49,29.06 112.06,29.06 112.48,29.48 112.93,29.48 113.09,29.32 114.3,29.32 v8(114.46,29.48) ; v4(92.64,79.22) 92.33,79.52 88.25,79.52 88.01,79.28 86.08,79.28 85.65,78.85 82.24,78.85 69.24,65.85 69.24,65.48 69.13,65.37 68.44,65.37 68.33,65.26 68.33,65.04 68.44,64.93 69.13,64.93 69.24,64.82 69.24,64.6 69.13,64.49 68.44,64.49 68.33,64.38 68.33,64.17 68.44,64.06 69.13,64.06 69.24,63.95 69.24,63.73 69.13,63.62 68.44,63.62 68.33,63.51 68.33,63.29 68.44,63.18 69.13,63.18 69.24,63.07 69.24,62.85 69.13,62.75 68.44,62.75 68.33,62.64 68.33,62.42 68.44,62.31 69.13,62.31 69.24,62.2 69.24,54.41 68.71,53.88 68.71,47.03 68.6,46.93 67.93,46.93 67.82,46.82 67.82,46.6 67.93,46.49 68.6,46.49 68.71,46.38 68.71,46.16 68.6,46.05 67.93,46.05 67.82,45.94 67.82,45.72 67.93,45.61 68.6,45.61 68.71,45.51 68.71,45.29 68.6,45.18 67.93,45.18 67.82,45.07 67.82,44.85 67.93,44.74 68.6,44.74 68.71,44.63 68.71,44.41 68.6,44.3 67.93,44.3 67.82,44.19 67.82,43.98 67.93,43.87 68.6,43.87 68.71,43.76 68.71,43.54 68.6,43.43 67.93,43.43 67.82,43.32 67.82,43.1 67.93,42.99 68.6,42.99 68.71,42.88 68.71,42.67 68.6,42.56 67.93,42.56 67.82,42.45 67.82,42.23 67.93,42.12 68.6,42.12 68.71,42.01 68.71,41.79 68.6,41.68 67.93,41.68 67.82,41.57 67.82,41.36 67.93,41.25 68.6,41.25 68.71,41.14 68.71,40.92 68.6,40.81 67.93,40.81 67.82,40.7 67.82,40.48 67.93,40.37 68.6,40.37 68.71,40.26 68.71,40.04 68.6,39.94 68,39.94 67.89,39.83 67.89,39.61 68,39.5 68.6,39.5 68.71,39.39 v5(68.71,37.67)
  L10_SIG4 w0.109: v7(68.71,28.53) v5(68.71,37.67)
  BOTTOM w0.102: v8(83.98,29.48) 81.49,29.48 81.04,29.03
  BOTTOM w0.173: v8(114.46,29.48) 114.46,28.7 114.04,28.29 114.04,26.48 114.15,26.38 114.15,25.46 115.19,24.42 R72.2 ; 81.04,29.03 80.54,28.53 v7(68.71,28.53)
DDR_BA1: length 144.6
  TOP w0.173: U6.N8 v8(119.26,28.68) 119.28,28.7 121.41,28.7 122.55,27.56 R73.2 ; U5.N8 v8(88.78,28.68) ; U7.N8 v8(104.02,28.68) ; U1.AE18 v4(93.44,78.42)
  L3_SIG1 w0.099: v4(93.44,78.42) 93.14,78.71 91.83,78.71
  L3_SIG1 w0.109: v5(70.54,37.01) 70.54,54.03 71.2,54.69 71.2,66.43 82.55,77.78 85.95,77.78 86.49,78.31 88.15,78.31 88.54,78.71 91.83,78.71
  L10_SIG4 w0.109: v7(72.47,17.68) 72.52,17.73 72.52,20.27 71.95,20.83 71.95,23.78 70.54,25.2 v5(70.54,37.01) ; v8(88.78,28.68) 89.17,29.06 89.17,29.15 89.49,29.47 90.19,29.47 91.67,27.99 92.86,27.99 93,28.13 93,28.23 93.14,28.37 93.34,28.37 93.48,28.23 93.48,28.13 93.62,27.99 96.16,27.99 96.85,28.68 97.78,28.68 98.16,29.06 100.05,29.06 100.46,29.47 101.63,29.47 102.42,28.68 v8(104.02,28.68) 104.41,29.06 104.41,29.15 104.73,29.47 105.43,29.47 106.78,28.12 111.68,28.12 112.24,28.68 113.02,28.68 113.43,29.09 115.32,29.09 115.72,29.49 116.54,29.49 117.35,28.68 v8(119.26,28.68)
  BOTTOM w0.173: v7(72.47,17.68) 83.99,17.68 83.99,17.68 84.43,17.68 88.04,21.29 88.04,23.15 87.68,23.5 87.68,25.14 87.5,25.32 87.5,28.01 88.17,28.68 v8(88.78,28.68)
DDR_BA2: length 149.4
  TOP w0.173: U5.M3 v8(85.62,29.08) ; U6.M3 v8(116.1,29.08) ; U1.AB18 v4(95.84,78.42) ; U7.M3 v8(100.86,29.08)
  L3_SIG1 w0.109: v4(95.84,78.42) v5(95.44,78.17) ; v8(116.1,29.08) 113.3,29.08 112.9,28.68 112.11,28.68 111.09,27.66 109.36,27.66 109.12,27.89 108.59,27.89 108.39,27.69 107.35,27.69 107.15,27.89 106.06,27.89 105.27,28.68 104.83,28.68 104.24,28.1 104.01,28.1 103.58,28.53 102.39,28.53 101.91,29.01 100.93,29.01 v8(100.86,29.08) 98.16,29.08 97.76,28.68 96.87,28.68 96.08,27.89 94.97,27.89 94.73,27.66 94.57,27.66 94.33,27.89 94.16,27.89 93.96,27.69 93.72,27.69 93.52,27.89 93.35,27.89 93.15,27.69 92.92,27.69 92.71,27.89 92.55,27.89 92.31,27.66 92.14,27.66 91.91,27.89 91.74,27.89 91.5,27.66 91.33,27.66 91.1,27.89 90.82,27.89 90.03,28.68 89.48,28.68 88.9,28.1 88.67,28.1 88.26,28.5 87.17,28.5 86.67,29.01 85.69,29.01 v8(85.62,29.08)
  L10_SIG4 w0.109: v7(68.35,26.14) 68.25,26.24 68.25,39.65 69.08,40.47 69.61,40.47 69.75,40.62 69.75,40.81 69.61,40.95 68.06,40.95 67.92,41.1 67.92,41.29 68.06,41.44 69.73,41.44 69.87,41.58 69.87,41.77 69.73,41.92 68.57,41.92 68.43,42.06 68.43,42.25 68.57,42.4 69.73,42.4 69.87,42.54 69.87,42.73 69.73,42.88 68.9,42.88 68.76,43.02 68.76,43.21 68.9,43.36 69.73,43.36 69.87,43.5 69.87,43.69 69.73,43.84 68.9,43.84 68.76,43.98 68.76,44.17 68.9,44.32 69.73,44.32 69.87,44.46 69.87,44.65 69.73,44.8 68.77,44.8 68.63,44.94 68.63,45.14 68.76,45.28 69.73,45.28 69.87,45.42 69.87,45.64 69.73,45.78 69.14,45.78 69.02,45.91 69.02,46.11 69.18,46.26 69.47,46.26 69.55,46.34 69.55,62.11 85.31,77.87 89.35,77.87 90.04,78.57 94.03,78.57 94.43,78.17 v5(95.44,78.17)
  BOTTOM w0.102: v8(85.62,29.08) 85.27,28.73 84.15,28.73 82.5,27.08 82.07,27.08 81.13,26.14
  BOTTOM w0.173: R74.2 120.4,22.89 118.04,25.24 118.04,26.23 116.1,28.17 v8(116.1,29.08) ; v7(68.35,26.14) 68.36,26.14 81.13,26.14
DDR_CASN: length 149.1
  TOP w0.173: U1.AC18 v4(95.04,78.42) ; U5.K3 v8(85.62,30.68) ; U7.K3 v8(100.86,30.68) ; U6.K3 v8(116.1,30.68)
  L3_SIG1 w0.099: v4(95.04,78.42) 94.71,78.09 94.3,78.09 94.01,77.8 93.98,77.79 93.68,77.79 93.47,78 92.96,78
  L3_SIG1 w0.109: v5(72.36,36.98) 72.36,38.18 71.58,38.97 71.58,53.6 72.16,54.18 72.16,54.8 72.27,54.91 72.56,54.91 72.67,55.02 72.67,55.23 72.56,55.34 72.27,55.34 72.16,55.45 72.16,55.67 72.27,55.78 72.79,55.78 72.9,55.89 72.9,56.11 72.79,56.22 72.27,56.22 72.16,56.33 72.16,56.54 72.27,56.65 72.79,56.65 72.9,56.76 72.9,56.98 72.79,57.09 72.27,57.09 72.16,57.2 72.16,57.42 72.27,57.53 72.79,57.53 72.9,57.64 72.9,57.86 72.79,57.96 72.27,57.96 72.16,58.07 72.16,58.29 72.27,58.4 72.79,58.4 72.9,58.51 72.9,58.73 72.79,58.84 72.27,58.84 72.16,58.95 72.16,59.17 72.27,59.28 72.79,59.28 72.9,59.38 72.9,59.6 72.79,59.71 72.27,59.71 72.16,59.82 72.16,60.04 72.27,60.15 72.79,60.15 72.9,60.26 72.9,60.48 72.79,60.59 72.27,60.59 72.16,60.7 72.16,60.91 72.27,61.02 72.79,61.02 72.9,61.13 72.9,61.35 72.79,61.46 72.27,61.46 72.16,61.57 72.16,61.79 72.27,61.9 72.79,61.9 72.9,62.01 72.9,62.22 72.79,62.33 72.27,62.33 72.16,62.44 72.16,62.66 72.27,62.77 72.79,62.77 72.9,62.88 72.9,63.1 72.79,63.21 72.27,63.21 72.16,63.32 72.16,63.53 72.27,63.64 72.79,63.64 72.9,63.75 72.9,63.97 72.79,64.08 72.27,64.08 72.16,64.19 72.16,64.73 77.84,70.41 77.84,70.61 77.36,71.1 77.36,71.3 77.5,71.44 77.7,71.44 78.18,70.95 78.38,70.95 78.52,71.09 78.52,71.29 78.04,71.78 78.04,71.98 78.18,72.12 78.38,72.12 78.86,71.63 79.06,71.63 79.2,71.77 79.2,71.97 78.72,72.46 78.72,72.66 78.86,72.8 79.05,72.8 79.54,72.31 79.74,72.31 79.88,72.45 79.88,72.65 79.39,73.14 79.39,73.34 79.53,73.48 79.73,73.48 80.22,72.99 80.42,72.99 80.56,73.13 80.56,73.33 80.07,73.82 80.07,74.02 80.21,74.16 80.41,74.16 80.9,73.67 81.1,73.67 81.24,73.81 81.24,74.01 80.75,74.5 80.75,74.7 80.89,74.84 81.09,74.84 81.58,74.35 81.78,74.35 81.92,74.49 81.92,74.69 81.43,75.18 81.43,75.38 81.57,75.52 81.77,75.52 82.26,75.03 82.46,75.03 82.6,75.17 82.6,75.37 82.11,75.86 82.11,76.06 82.25,76.2 82.45,76.2 82.94,75.71 83.14,75.71 83.28,75.85 83.28,76.05 82.79,76.54 82.79,76.73 82.93,76.88 83.13,76.88 83.62,76.39 83.82,76.39 84.21,76.78 86.22,76.78 86.84,77.4 88.3,77.4 88.9,78 92.96,78 ; v8(116.1,30.68) 115.44,30.68 115.01,30.25 114.22,30.25 113.84,29.88 113.46,29.88 113.06,30.28 111.2,30.28 110.79,30.69 109.65,30.69 109.17,30.21 107.39,30.21 107.06,30.54 106.66,30.54 106.33,30.21 104.85,30.21 104.47,30.59 103.79,30.59 103.31,30.1 101.9,30.1 101.73,30.28 101.26,30.28 v8(100.86,30.68) 100.2,30.68 99.77,30.25 99.03,30.25 98.65,29.88 98.22,29.88 97.82,30.28 95.96,30.28 95.55,30.69 94.39,30.69 93.91,30.21 92.04,30.21 91.92,30.33 91.92,30.64 91.81,30.75 91.64,30.75 91.52,30.64 91.52,30.33 91.4,30.21 89.63,30.21 89.26,30.59 88.55,30.59 88.04,30.08 86.69,30.08 86.39,30.38 85.91,30.38 v8(85.62,30.68)
  L10_SIG4 w0.109: v5(72.36,36.98) v7(72.36,35.05)
  BOTTOM w0.102: 80.06,31.58 82.93,31.58 83.13,31.37 83.69,31.37 83.82,31.5 84.2,31.5 85.02,30.68 v8(85.62,30.68)
  BOTTOM w0.173: v8(116.1,30.68) 114.75,30.68 113.79,29.72 113.28,29.72 113.11,29.89 111.67,29.89 110.87,29.09 110.87,28.19 110.49,27.81 R52.2 ; v7(72.36,35.05) 74.85,32.56 79.07,32.56 80.06,31.58
DDR_CKE: length 105.3
  TOP w0.173: U5.K9 v8(89.74,30.68) ; U7.K9 v8(104.98,30.68) ; v3(79.88,63.56) 79.88,66.88 87.25,74.25 88.34,74.25 89.3,75.21 91.83,75.21 U1.AG22 ; U6.K9 v8(120.22,30.68)
  L3_SIG1 w0.109: v3(79.88,63.56) 79.88,50.66 78.33,49.11 v5(78.33,44.09)
  L10_SIG4 w0.109: v8(89.74,30.68) 95.99,30.68 96.79,29.88 98.6,29.88 99.4,30.68 100.17,30.68 100.61,31.12 101.04,31.12 101.8,30.36 103.53,30.36 103.87,30.7 104.97,30.7 v8(104.98,30.68) 111.23,30.68 112.05,29.85 113.82,29.85 114.64,30.68 115.43,30.68 115.85,31.09 116.38,31.09 117.09,30.38 119.93,30.38 v8(120.22,30.68) ; v5(78.33,44.09) 77.55,43.31 77.55,41.76 v7(78.33,40.97)
  BOTTOM w0.173: v7(78.33,40.97) 89.2,40.97 91.8,38.38 91.8,31.93 90.54,30.68 v8(89.74,30.68) ; R49.2 122.81,29.59 121.92,30.48 120.42,30.48 v8(120.22,30.68)
DDR_CLK: length 158.5
  TOP w0.108: v8(102.12,31.34) 102.27,31.19 102.53,31.19 U7.J7 ; U5.J7 87.36,31.26 86.97,31.26 v8(86.88,31.34) 86.88,31.35 86.51,31.35 85.93,31.93 85.93,41.09 86.07,41.23 89.78,41.23 90.07,41.53 90.07,41.94 89.78,42.23 86.07,42.23 85.93,42.37 85.93,42.57 86.07,42.72 90.01,42.72 90.3,43.01 90.3,43.42 90.01,43.71 86.07,43.71 85.93,43.86 85.93,44.06 86.07,44.2 90.01,44.2 90.3,44.5 90.3,44.91 90.01,45.2 86.07,45.2 85.93,45.34 85.93,45.65 86.07,45.79 89.9,45.79 90.2,46.09 90.2,46.5 89.9,46.79 86.07,46.79 85.93,46.93 85.93,47.14 86.07,47.28 89.9,47.28 90.2,47.57 90.2,47.99 89.9,48.28 86.07,48.28 85.93,48.42 85.93,48.62 86.07,48.77 89.9,48.77 90.2,49.06 90.2,49.47 89.9,49.76 86.07,49.76 85.93,49.91 85.93,50.11 86.07,50.25 89.9,50.25 90.2,50.54 90.2,50.96 89.9,51.25 86.07,51.25 85.93,51.39 85.93,51.59 86.07,51.74 89.9,51.74 90.2,52.03 90.2,52.44 89.9,52.73 86.07,52.73 85.89,52.91 85.89,69.41 90.24,73.76 91.14,73.76 91.25,73.64 91.86,73.64 U1.AG24 ; U6.J7 117.77,31.19 117.51,31.19 v8(117.36,31.34)
  L3_SIG1 w0.083: v8(117.36,31.34) 117.24,31.22 116.94,31.22 115.99,32.17 115.22,32.17 114.84,31.8 114.84,31.71 114.64,31.51 114.3,31.51 113.6,32.21 106.85,32.21 106.54,31.91 104.65,31.91 104.25,31.51 103.86,31.51 103.62,31.75 102.94,31.75 102.4,31.22 102.25,31.22 v8(102.12,31.34) 102,31.22 101.7,31.22 100.75,32.17 99.98,32.17 99.6,31.8 99.6,31.71 99.4,31.51 99.06,31.51 98.36,32.21 91.61,32.21 91.3,31.91 89.41,31.91 89.01,31.51 88.62,31.51 88.38,31.75 87.7,31.75 87.16,31.22 87.01,31.22 v8(86.88,31.34)
  BOTTOM w0.108: R46.2 127,31.22 126.89,31.12 120.9,31.12 120.7,31.32 119.66,31.32 119.02,30.68 118.27,30.68 117.76,31.19 117.51,31.19 v8(117.36,31.34)
DDR_CLKN: length 158.5
  TOP w0.108: U7.K7 102.56,30.94 102.27,30.94 v8(102.12,30.78) ; U5.K7 87.35,30.9 87,30.9 v8(86.88,30.78) 86.88,30.79 86.72,30.79 85.67,31.83 85.67,41.19 85.97,41.49 89.67,41.49 89.82,41.63 89.82,41.83 89.68,41.98 85.97,41.98 85.67,42.27 85.67,42.68 85.97,42.97 89.9,42.97 90.04,43.12 90.04,43.32 89.9,43.46 85.97,43.46 85.67,43.75 85.67,44.17 85.97,44.46 89.9,44.46 90.04,44.6 90.04,44.8 89.9,44.95 85.97,44.95 85.67,45.24 85.67,45.76 85.97,46.05 89.8,46.05 89.94,46.19 89.94,46.39 89.8,46.54 85.97,46.54 85.67,46.83 85.67,47.24 85.97,47.53 89.8,47.53 89.94,47.68 89.94,47.88 89.8,48.02 85.97,48.02 85.67,48.31 85.67,48.73 85.97,49.02 89.8,49.02 89.94,49.16 89.94,49.37 89.8,49.51 85.97,49.51 85.67,49.8 85.67,50.21 85.97,50.51 89.8,50.51 89.94,50.65 89.94,50.85 89.8,50.99 85.97,50.99 85.67,51.29 85.67,51.7 85.97,51.99 89.8,51.99 89.94,52.14 89.94,52.34 89.8,52.48 85.97,52.48 85.64,52.81 85.64,69.52 90.14,74.02 U1.AH24 ; v8(117.36,30.78) 117.51,30.94 117.8,30.94 U6.K7
  L3_SIG1 w0.083: v8(117.36,30.78) 117.23,30.92 116.81,30.92 115.86,31.87 115.35,31.87 115.15,31.67 115.15,31.58 114.77,31.2 114.18,31.2 113.48,31.9 106.97,31.9 106.67,31.6 104.78,31.6 104.38,31.2 103.74,31.2 103.49,31.45 103.07,31.45 102.53,30.91 102.25,30.91 v8(102.12,30.78) 101.99,30.92 101.57,30.92 100.62,31.87 100.11,31.87 99.91,31.67 99.91,31.58 99.53,31.2 98.94,31.2 98.24,31.9 91.73,31.9 91.43,31.6 89.54,31.6 89.14,31.2 88.5,31.2 88.25,31.45 87.83,31.45 87.29,30.91 87.01,30.91 v8(86.88,30.78)
  BOTTOM w0.108: R47.2 127,30.75 126.89,30.86 120.8,30.86 120.6,31.06 119.76,31.06 119.13,30.43 118.16,30.43 117.65,30.94 117.51,30.94 v8(117.36,30.78)
DDR_CS0N: length 145.7
  TOP w0.173: R50.2 109.74,26.42 110.59,27.27 111.76,28.44 111.76,28.95 113.09,30.28 v8(113.66,30.28) U6.L2 ; U5.L2 v8(83.18,30.28) ; U7.L2 v8(98.42,30.28) ; U1.AH23 89.64,74.81 88.35,73.53 87.54,73.53 80.64,66.63 v3(80.64,64.98)
  L3_SIG1 w0.109: v3(80.64,64.98) 79.38,63.71 79.38,51.94 79.1,51.67 79.1,51.51 79.26,51.35 79.26,51.18 79.15,51.07 78.98,51.07 78.82,51.23 78.66,51.23 77.88,50.44 77.88,37.94 79.36,36.46 79.36,36.11 79.89,35.57 80.87,35.57 80.99,35.46 80.99,35.29 80.87,35.17 79.89,35.17 79.78,35.05 79.78,34.88 79.89,34.77 80.87,34.77 80.99,34.65 80.99,34.48 80.87,34.36 79.89,34.36 79.78,34.24 79.78,34.08 79.89,33.96 80.87,33.96 80.99,33.84 80.99,33.67 80.87,33.55 79.89,33.55 79.78,33.44 79.78,33.27 79.89,33.15 80.87,33.15 80.99,33.03 80.99,32.87 80.87,32.75 79.89,32.75 79.78,32.63 79.78,32.46 79.89,32.34 80.87,32.34 80.99,32.22 80.99,32.06 80.87,31.94 79.89,31.94 79.78,31.82 79.78,31.65 79.89,31.54 80.87,31.54 80.99,31.42 80.99,31.25 80.87,31.13 79.89,31.13 79.78,31.01 79.78,30.72 79.89,30.6 80.87,30.6 80.98,30.49 80.98,30.32 80.86,30.2 80.41,30.2 79.78,29.57 79.44,29.57 79.33,29.46 79.33,29.1 79.22,28.99 79,28.99 78.9,29.1 78.9,29.46 78.79,29.57 78.57,29.57 78.46,29.46 78.46,29.1 78.35,28.99 78.13,28.99 78.02,29.1 78.02,29.46 77.91,29.57 77.63,29.57 77.29,29.91 77.29,31.8 77.43,31.94 78.93,31.94 79.07,32.08 79.07,32.28 78.93,32.42 77.43,32.42 77.29,32.56 77.29,32.76 77.43,32.9 78.99,32.9 79.14,33.04 79.14,33.24 78.99,33.38 77.43,33.38 77.29,33.52 77.29,33.72 77.43,33.86 78.99,33.86 79.14,34 79.14,34.2 78.99,34.34 77.43,34.34 77.29,34.48 77.29,36.75 77.54,37.01 v5(77.9,37.01)
  L10_SIG4 w0.109: v8(83.18,30.28) 83.52,30.62 84.66,30.62 85.77,31.73 87.42,31.73 87.65,31.5 88.18,31.5 88.56,31.12 91.69,31.12 92.33,31.75 93.99,31.75 94.17,31.58 94.17,31.42 94.31,31.27 94.51,31.27 94.65,31.41 94.65,31.56 94.79,31.7 95.84,31.7 97.26,30.28 v8(98.42,30.28) 100.05,31.91 100.82,31.91 100.91,31.82 101.26,31.82 101.31,31.88 102.52,31.88 102.89,31.5 103.42,31.5 103.8,31.12 106.93,31.12 107.57,31.75 110.64,31.75 112.12,30.28 v8(113.66,30.28) ; v5(77.9,37.01) 79.5,35.41 79.5,32.52 80.02,32 80.02,30.09 v7(79.48,29.56)
  BOTTOM w0.102: v8(83.18,30.28) 82.85,29.95 80.92,29.95 80.59,29.62
  BOTTOM w0.173: v7(79.48,29.56) 80.53,29.56 80.59,29.62
DDR_D0: length 59.5
  TOP w0.173: U5.E3 v8(84.78,35.08) ; U1.AF25 v4(92.64,72.82)
  L3_SIG1 w0.109: v4(92.64,72.82) v5(92.24,72.57)
  L10_SIG4 w0.109: v5(92.24,72.57) 91.8,73 88.29,73 83.57,68.28 83.57,53.28 83.68,53.16 83.99,53.16 84.1,53.05 84.1,52.88 83.99,52.77 83.68,52.77 83.57,52.65 83.57,52.49 83.68,52.37 83.99,52.37 84.1,52.25 84.1,52.09 83.99,51.97 83.68,51.97 83.57,51.86 83.57,51.69 83.68,51.58 83.99,51.58 84.1,51.46 84.1,51.3 83.99,51.18 83.68,51.18 83.57,51.07 83.57,50.9 83.68,50.79 83.99,50.79 84.1,50.67 84.1,50.51 83.99,50.39 83.68,50.39 83.57,50.27 83.57,50.11 83.68,49.99 83.99,49.99 84.1,49.88 84.1,49.71 83.99,49.6 83.68,49.6 83.57,49.48 83.57,49.32 83.68,49.2 83.99,49.2 84.1,49.08 84.1,48.92 83.99,48.8 83.68,48.8 83.57,48.69 83.57,48.52 83.68,48.41 83.99,48.41 84.1,48.29 84.1,48.13 83.99,48.01 83.68,48.01 83.57,47.9 83.57,47.73 83.68,47.62 83.99,47.62 84.1,47.5 84.1,47.34 83.99,47.22 83.68,47.22 83.57,47.1 83.57,46.94 83.68,46.82 83.99,46.82 84.1,46.71 84.1,46.54 83.99,46.43 83.68,46.43 83.57,46.31 83.57,46.15 83.68,46.03 83.96,46.03 84.08,45.91 84.08,45.75 83.96,45.63 83.68,45.63 83.57,45.52 83.57,45.35 83.68,45.24 83.96,45.24 84.08,45.12 84.08,44.96 83.96,44.84 83.68,44.84 83.57,44.73 83.57,44.56 83.68,44.45 83.96,44.45 84.08,44.33 84.08,44.17 83.96,44.05 83.68,44.05 83.57,43.93 83.57,43.77 83.68,43.65 83.96,43.65 84.08,43.54 84.08,43.37 83.96,43.26 83.68,43.26 83.57,43.14 83.57,42.98 83.68,42.86 83.96,42.86 84.08,42.74 84.08,42.58 83.96,42.46 83.68,42.46 83.57,42.35 83.57,42.18 83.68,42.07 83.96,42.07 84.08,41.95 84.08,41.79 83.96,41.67 83.62,41.67 83.5,41.56 83.5,41.39 83.62,41.28 83.91,41.28 84.03,41.16 84.03,40.88 83.91,40.76 83.71,40.76 83.59,40.64 83.59,40.47 83.71,40.36 83.91,40.36 84.03,40.24 84.03,39.88 83.57,39.42 83.57,35.74 83.82,35.48 84.15,35.48 84.56,35.08 v8(84.78,35.08)
DDR_D1: length 59.5
  TOP w0.173: U1.AF26 v4(92.64,72.02) ; U5.F7 v8(87.18,34.28)
  L3_SIG1 w0.109: v4(92.64,72.02) v5(92.24,71.77)
  L10_SIG4 w0.109: v8(87.18,34.28) 86.72,34.74 86.72,35.66 86.56,35.82 86.56,39.95 89.39,42.78 89.39,43.94 89.51,44.06 90.39,44.06 90.5,44.16 90.5,44.33 90.37,44.45 89.51,44.45 89.39,44.57 89.39,44.73 89.51,44.85 90.4,44.85 90.52,44.97 90.52,45.13 90.4,45.25 89.51,45.25 89.39,45.36 89.39,45.53 89.51,45.64 90.22,45.64 90.34,45.76 90.34,45.92 90.22,46.04 89.51,46.04 89.39,46.15 89.39,46.32 89.51,46.43 90.22,46.43 90.34,46.55 90.34,46.71 90.22,46.83 89.51,46.83 89.39,46.95 89.39,47.11 89.51,47.23 90.22,47.23 90.34,47.34 90.34,47.51 90.22,47.62 89.51,47.62 89.39,47.74 89.39,47.9 89.51,48.02 90.17,48.02 90.29,48.14 90.29,48.3 90.17,48.42 89.51,48.42 89.39,48.53 89.39,48.7 89.51,48.81 90.17,48.81 90.29,48.93 90.29,49.09 90.17,49.21 89.51,49.21 89.39,49.32 89.39,49.49 89.51,49.6 90.17,49.6 90.29,49.72 90.29,49.88 90.17,50 89.51,50 89.39,50.12 89.39,50.28 89.51,50.4 90.17,50.4 90.29,50.51 90.29,50.68 90.17,50.79 89.51,50.79 89.39,50.91 89.39,51.07 89.51,51.19 90.17,51.19 90.29,51.31 90.29,51.47 90.17,51.59 89.51,51.59 89.39,51.7 89.39,51.87 89.51,51.98 90.13,51.98 90.24,52.09 90.24,52.25 90.11,52.38 89.51,52.38 89.39,52.49 89.39,64.71 89.64,64.95 89.64,66.6 92.24,69.2 v5(92.24,71.77)
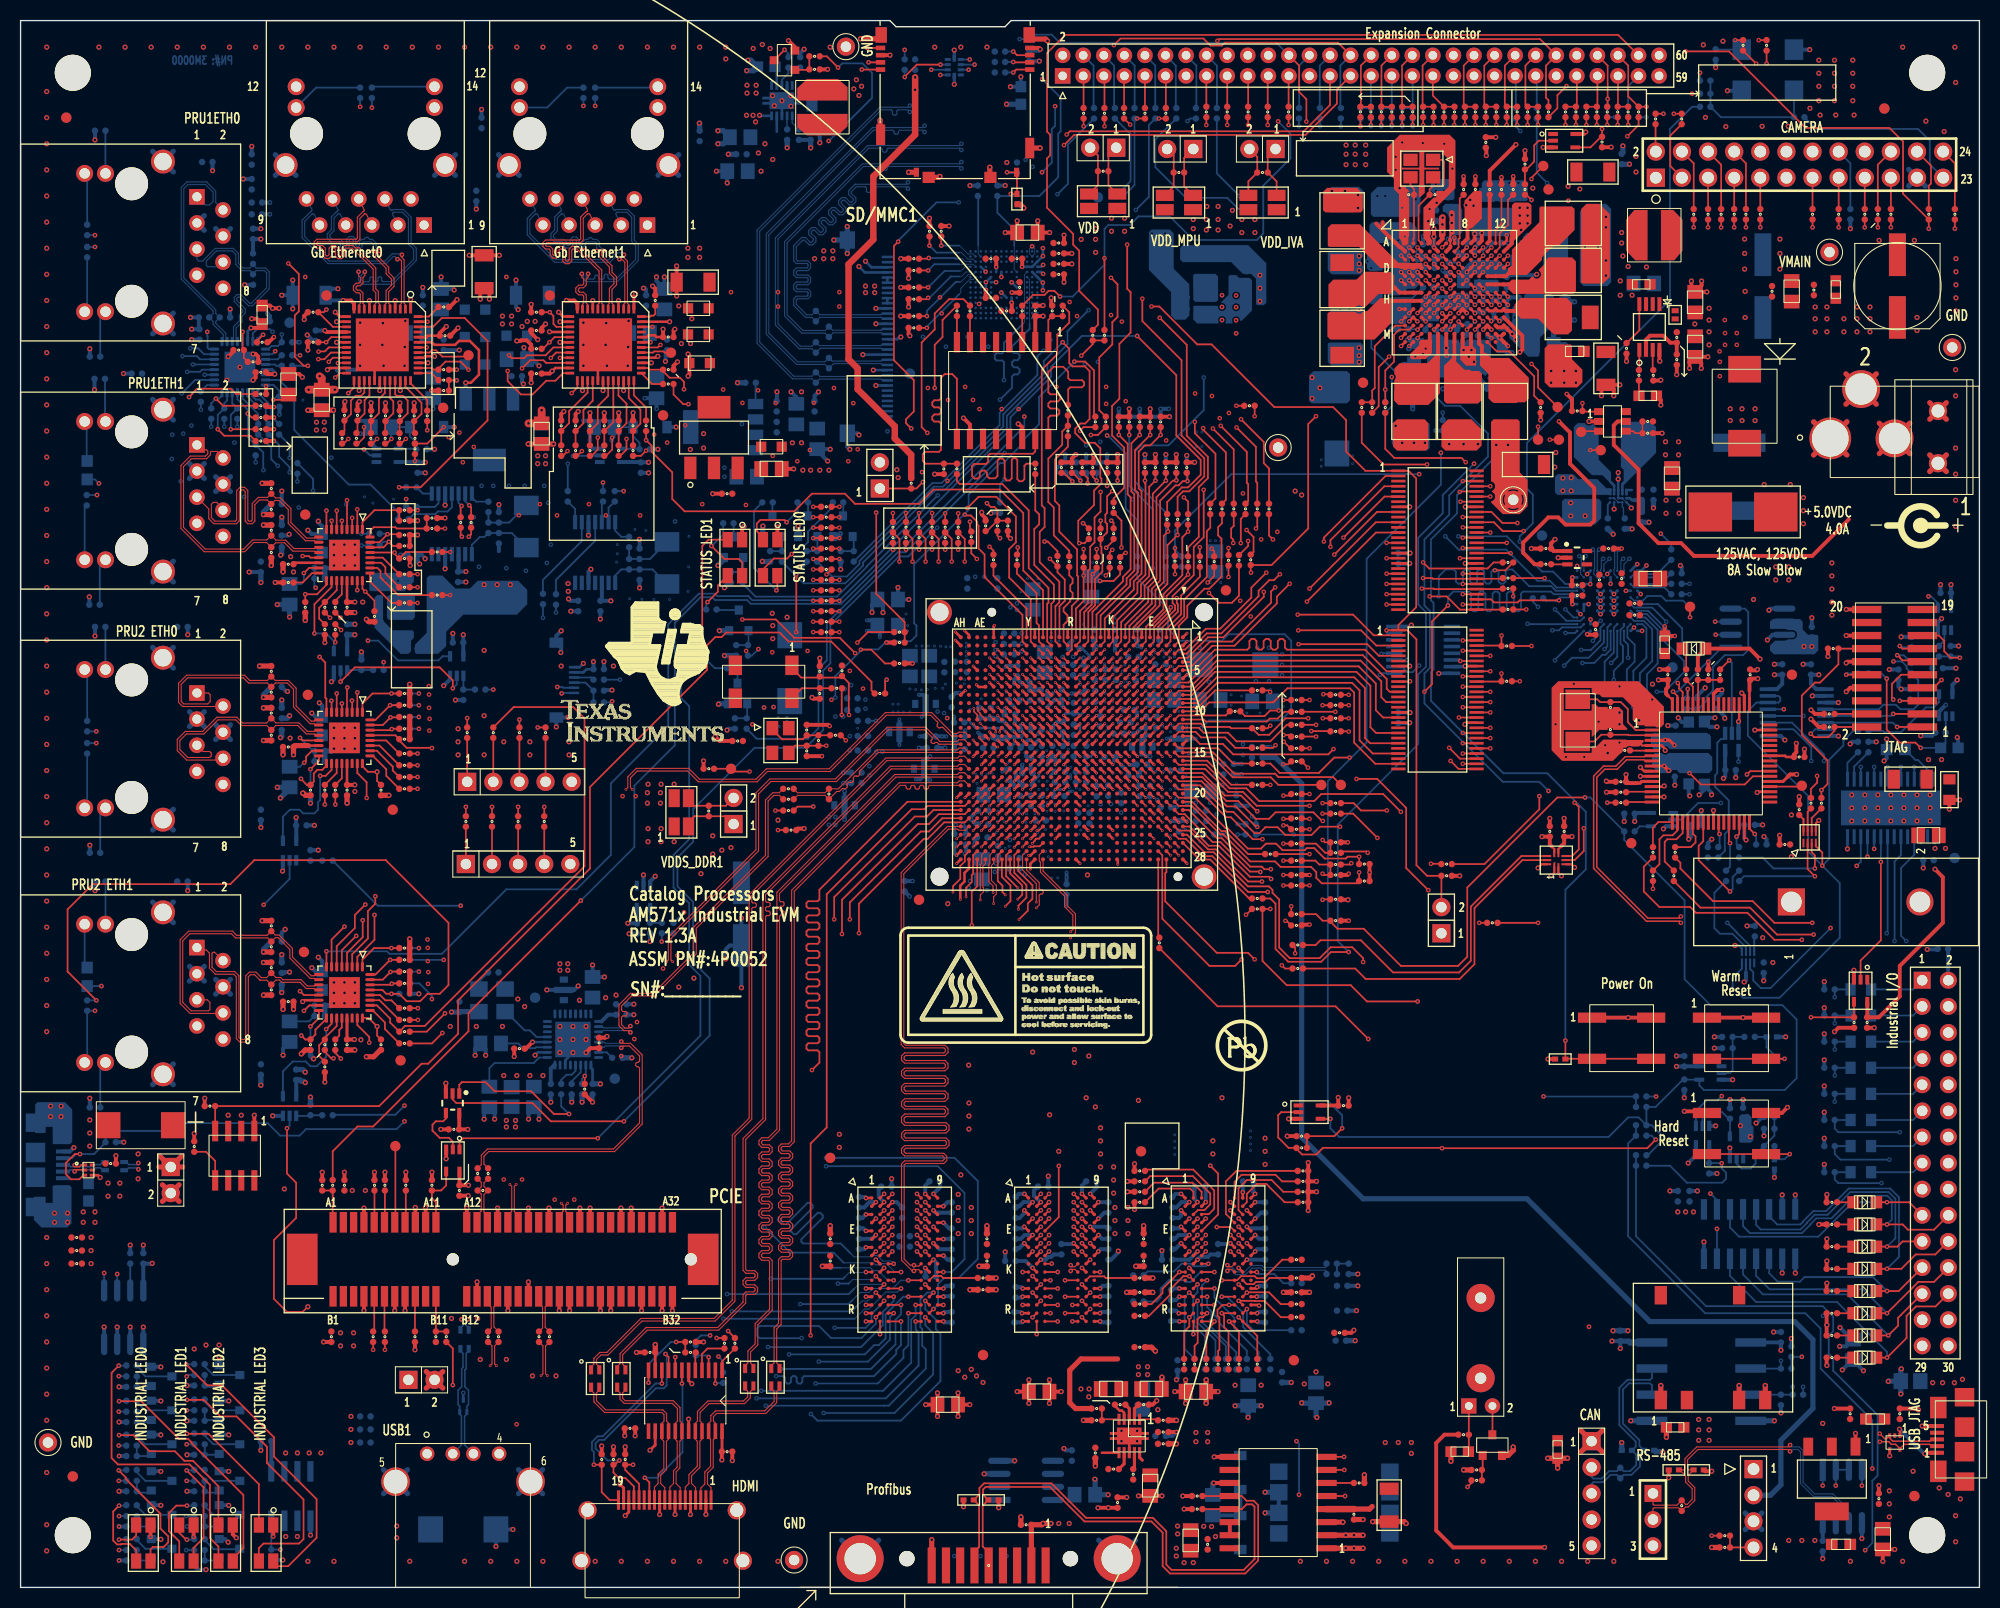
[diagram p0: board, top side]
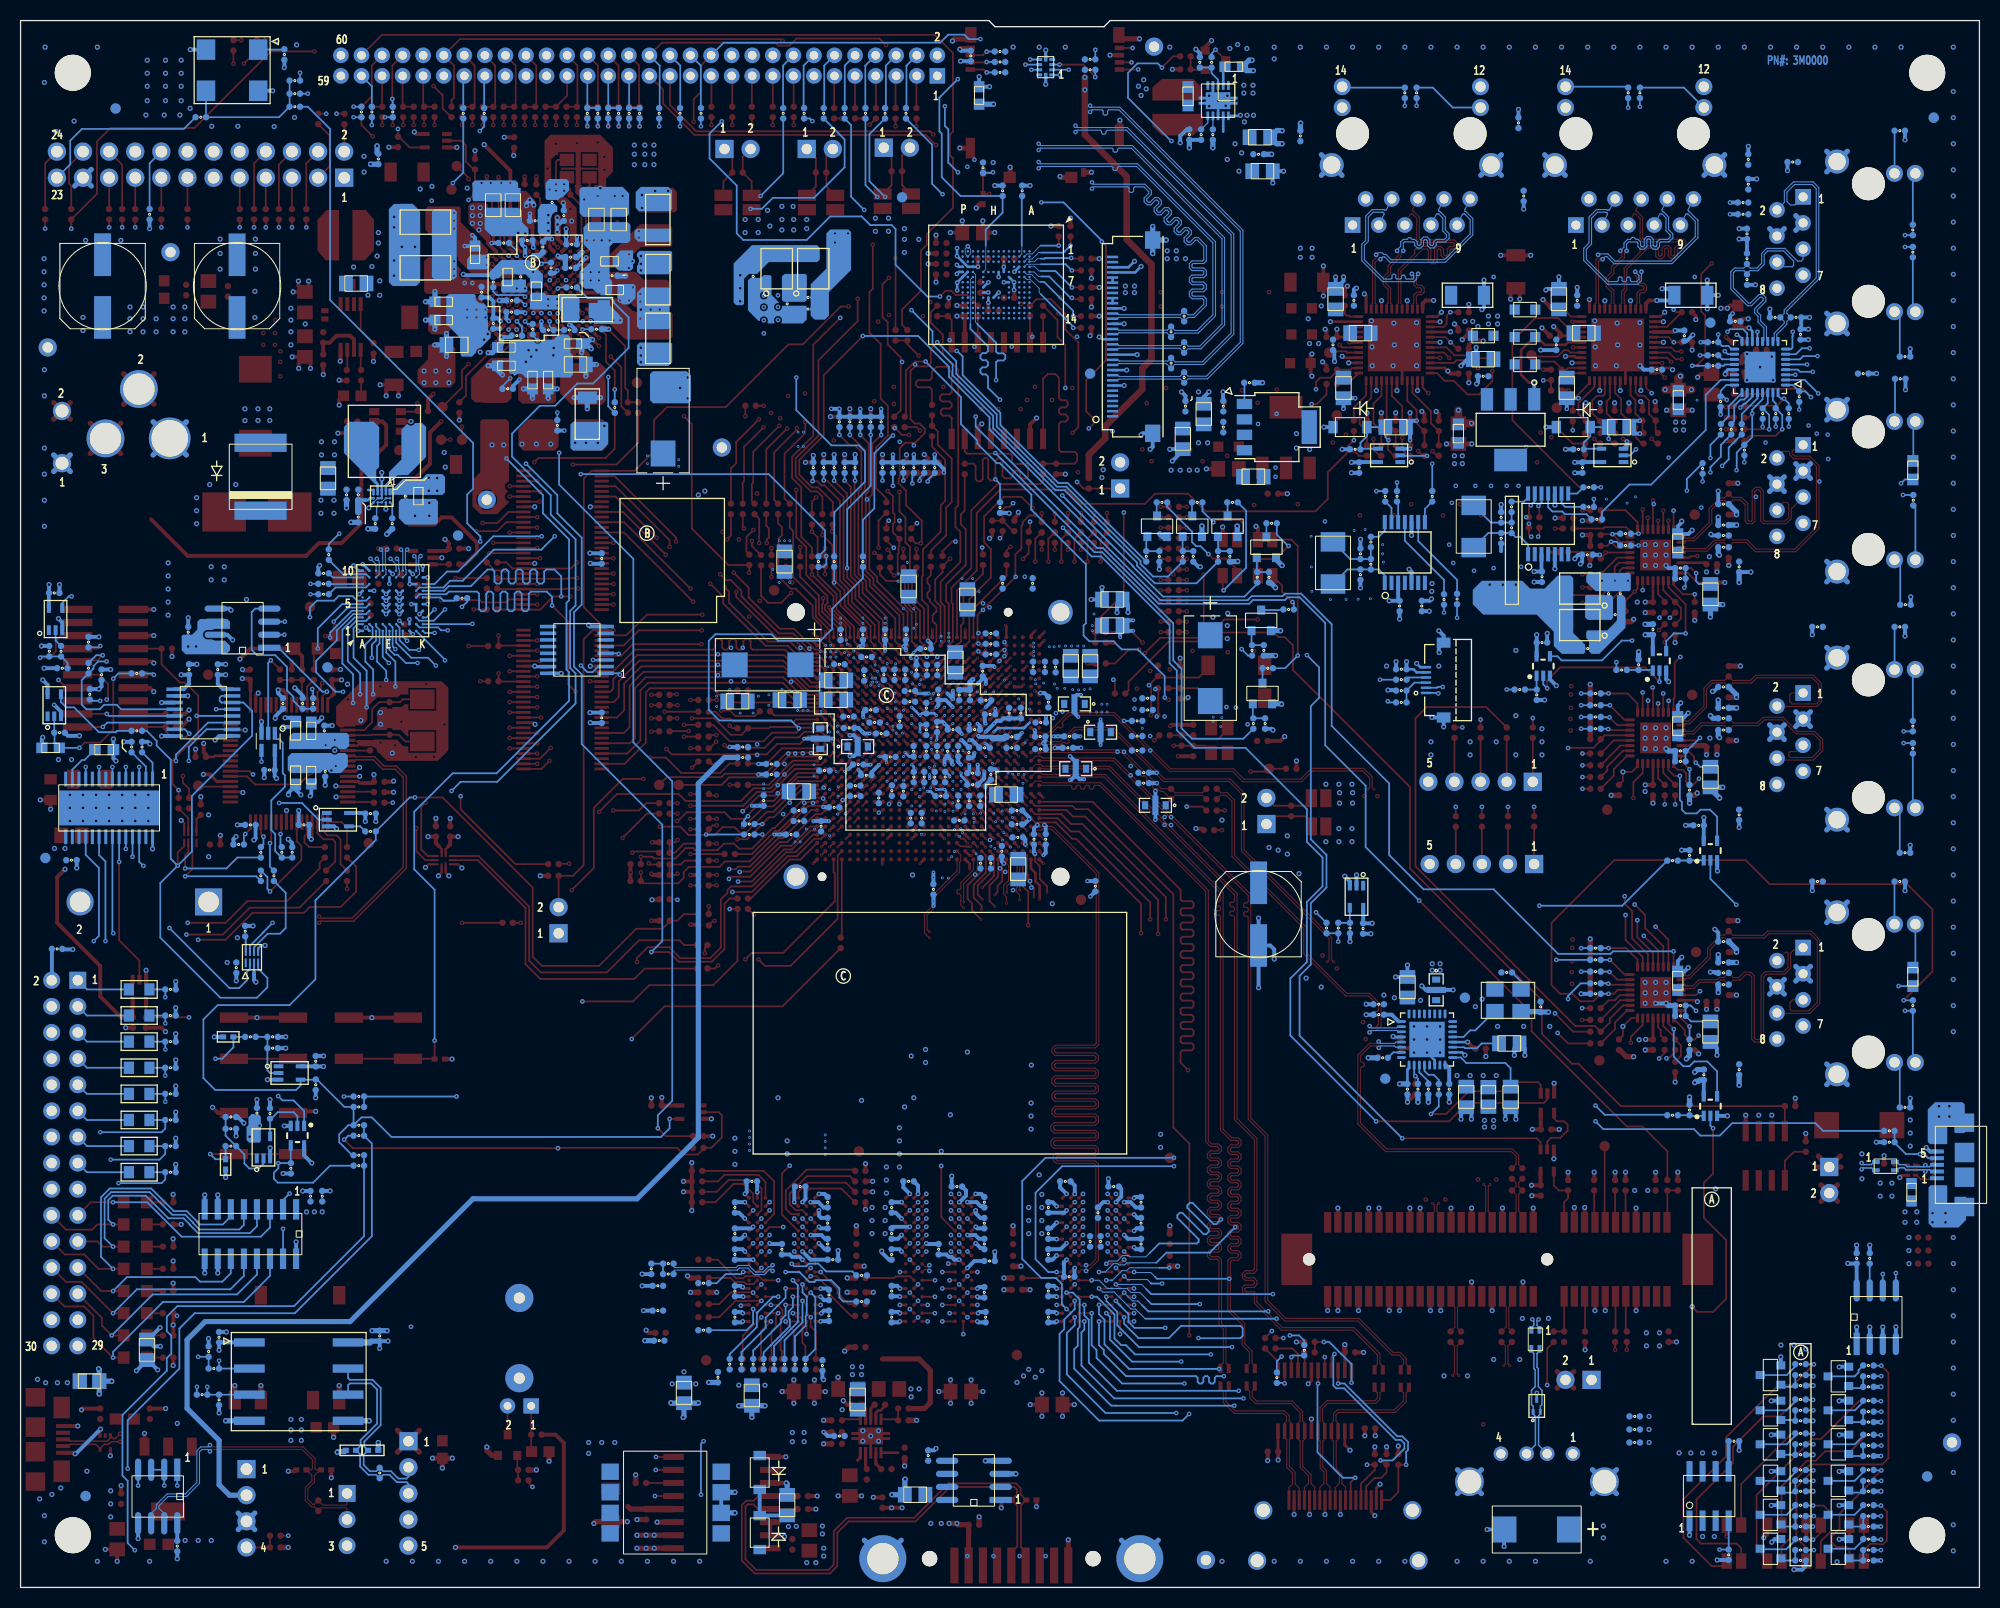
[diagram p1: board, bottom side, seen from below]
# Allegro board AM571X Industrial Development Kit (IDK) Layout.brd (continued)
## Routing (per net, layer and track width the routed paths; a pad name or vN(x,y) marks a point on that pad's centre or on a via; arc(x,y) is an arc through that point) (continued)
DDR_D2: length 59.5
  TOP w0.173: U5.F8 v8(87.98,34.28) ; U1.AG26 v4(91.84,72.02)
  L3_SIG1 w0.109: v4(91.84,72.02) v5(91.44,71.77)
  L10_SIG4 w0.109: v8(87.98,34.28) 87.59,33.88 87.02,33.88 86.46,34.44 86.46,35.61 86.33,35.74 86.33,40.4 87.91,41.98 87.91,44.06 88.02,44.18 88.74,44.18 88.85,44.3 88.85,44.46 88.74,44.58 88.02,44.58 87.91,44.69 87.91,44.86 88.02,44.97 88.74,44.97 88.85,45.09 88.85,45.25 88.74,45.37 88.02,45.37 87.91,45.48 87.91,45.65 88.02,45.76 88.74,45.76 88.85,45.88 88.85,46.04 88.74,46.16 88.02,46.16 87.91,46.28 87.91,46.44 88.02,46.56 88.74,46.56 88.85,46.67 88.85,46.84 88.74,46.95 88.02,46.95 87.91,47.07 87.91,47.23 88.02,47.35 88.74,47.35 88.85,47.47 88.85,47.63 88.74,47.75 88.02,47.75 87.91,47.86 87.91,48.03 88.02,48.14 88.76,48.14 88.87,48.25 88.87,48.42 88.75,48.54 88.02,48.54 87.91,48.65 87.91,48.82 88.02,48.93 88.78,48.93 88.89,49.05 88.89,49.21 88.77,49.33 88.02,49.33 87.91,49.45 87.91,49.61 88.02,49.73 88.79,49.73 88.89,49.83 88.89,50 88.77,50.12 88.02,50.12 87.91,50.24 87.91,50.4 88.02,50.52 88.79,50.52 88.89,50.62 88.89,50.79 88.77,50.92 88.02,50.92 87.91,51.03 87.91,51.2 88.02,51.31 88.75,51.31 88.88,51.44 88.88,51.6 88.77,51.71 88.02,51.71 87.91,51.82 87.91,65.43 91.44,68.96 v5(91.44,71.77)
DDR_D3: length 59.4
  TOP w0.173: U5.H8 v8(87.98,32.68) ; U1.AH26 v4(91.04,72.02)
  L3_SIG1 w0.109: v4(91.04,72.02) v5(90.64,71.77)
  L10_SIG4 w0.109: v8(87.98,32.68) 87.59,33.07 87.02,33.07 86.79,33.3 86.79,33.48 86.23,34.04 86.23,35.33 86.06,35.51 86.06,40.81 87.37,42.12 87.37,42.77 87.26,42.89 85.75,42.89 85.64,43.01 85.64,43.17 85.75,43.29 87.26,43.29 87.37,43.4 87.37,43.57 87.26,43.68 85.75,43.68 85.64,43.8 85.64,43.96 85.75,44.08 87.26,44.08 87.37,44.19 87.37,44.36 87.26,44.47 85.75,44.47 85.64,44.59 85.64,44.75 85.75,44.87 87.26,44.87 87.37,44.99 87.37,45.21 87.26,45.33 86.42,45.33 86.3,45.44 86.3,45.61 86.42,45.73 87.26,45.73 87.37,45.84 87.37,53.12 87.26,53.23 86.52,53.23 86.41,53.34 86.41,53.51 86.53,53.63 87.26,53.63 87.37,53.75 87.37,53.91 87.26,54.03 86.42,54.03 86.31,54.14 86.31,54.31 86.42,54.42 87.26,54.42 87.37,54.54 87.37,69.81 89.33,71.77 v5(90.64,71.77)
DDR_D4: length 59.5
  TOP w0.173: U5.F2 v8(83.98,34.28) ; U1.AF24 v4(92.64,73.62)
  L3_SIG1 w0.109: v4(92.64,73.62) v5(92.24,73.37)
  L10_SIG4 w0.109: v8(83.98,34.28) 82.68,35.58 82.68,36.7 81.81,37.57 81.81,39.48 82.87,40.54 82.87,47.87 83,48.01 83,48.25 82.89,48.37 82.53,48.37 82.41,48.49 82.41,48.65 82.52,48.76 82.89,48.76 83,48.88 83,49.04 82.89,49.16 82.44,49.16 82.33,49.27 82.33,49.43 82.45,49.56 82.89,49.56 83,49.67 83,49.84 82.89,49.95 82.33,49.95 82.22,50.07 82.22,50.23 82.33,50.35 82.89,50.35 83,50.46 83,50.63 82.89,50.74 82.33,50.74 82.22,50.86 82.22,51.02 82.33,51.14 82.89,51.14 83,51.26 83,51.42 82.89,51.54 82.33,51.54 82.22,51.65 82.22,51.82 82.33,51.93 82.89,51.93 83,52.05 83,52.21 82.89,52.33 82.33,52.33 82.22,52.45 82.22,52.61 82.33,52.73 82.89,52.73 83,52.84 83,53.01 82.89,53.12 82.33,53.12 82.22,53.24 82.22,53.4 82.33,53.52 82.89,53.52 83,53.63 83,53.8 82.89,53.91 82.33,53.91 82.22,54.03 82.22,54.19 82.33,54.31 82.89,54.31 83,54.43 83,54.59 82.89,54.71 82.33,54.71 82.22,54.82 82.22,54.99 82.33,55.1 82.89,55.1 83,55.22 83,68.4 87.97,73.37 v5(92.24,73.37)
DDR_D5: length 59.5
  TOP w0.173: U5.G2 v8(83.98,33.48) ; U1.AE24 v4(93.44,73.62)
  L3_SIG1 w0.109: v5(93.04,73.37) 93.04,73.39 93.42,73.62 v4(93.44,73.62)
  L10_SIG4 w0.109: v8(83.98,33.48) 83.36,33.48 82.68,34.16 82.68,34.9 82.4,35.18 81.91,35.18 81.39,35.71 81.39,39.72 81.8,40.13 81.8,40.29 81.38,40.71 81.38,40.88 81.5,41 81.65,41 82.08,40.57 82.25,40.57 82.4,40.72 82.4,41.55 82.28,41.66 81.47,41.66 81.35,41.78 81.35,41.94 81.47,42.06 82.3,42.06 82.42,42.18 82.42,42.35 82.31,42.46 81.47,42.46 81.35,42.57 81.35,42.74 81.47,42.85 82.3,42.85 82.41,42.96 82.41,43.13 82.29,43.25 81.47,43.25 81.35,43.36 81.35,43.53 81.47,43.64 82.28,43.64 82.4,43.76 82.4,47.3 81.39,48.31 81.39,67.46 87.69,73.77 92.64,73.77 v5(93.04,73.37)
DDR_D6: length 59.5
  TOP w0.173: U1.AF23 v4(92.64,74.42) ; U5.H3 v8(84.78,32.68)
  L3_SIG1 w0.109: v4(92.64,74.42) v5(92.24,74.17)
  L10_SIG4 w0.109: v8(84.78,32.68) 84.38,33.08 83.04,33.08 81.59,34.53 81.43,34.53 81.24,34.34 81.08,34.34 80.97,34.45 80.97,34.64 81.14,34.81 81.14,34.98 80.9,35.22 80.9,44.49 81.04,44.63 81.8,44.63 81.94,44.77 81.94,44.97 81.8,45.11 81.04,45.11 80.9,45.25 80.9,45.45 81.04,45.59 81.8,45.59 81.94,45.73 81.94,45.93 81.8,46.07 81.04,46.07 80.9,46.21 80.9,46.41 81.04,46.55 81.8,46.55 81.94,46.69 81.94,46.89 81.8,47.03 81.04,47.03 80.9,47.17 80.9,67.86 87.06,74.02 90.15,74.02 90.73,74.6 91.8,74.6 v5(92.24,74.17)
DDR_D7: length 59.6
  TOP w0.173: U1.AE23 v4(93.44,74.42) ; U5.H7 v8(87.18,32.68)
  L3_SIG1 w0.109: v4(93.44,74.42) v5(93.04,74.17)
  L10_SIG4 w0.109: v5(93.04,74.17) 93.04,74.17 93.04,74.74 92.63,75.14 92.13,75.14 91.87,74.88 90.43,74.88 90.02,74.48 86.54,74.48 80.39,68.33 80.39,34.34 82.44,32.29 85.88,32.29 86.27,32.68 v8(87.18,32.68)
DDR_D8: length 52.7
  TOP w0.173: U5.D7 v8(87.18,35.88) ; U1.AC23 v4(95.04,74.42)
  L3_SIG1 w0.099: 90.43,73.11 91.96,73.11 92.08,72.99 92.39,72.99 92.51,73.11 92.76,73.11 92.88,72.99 93.99,72.99 94.11,73.11 94.32,73.11 94.74,73.53 94.74,74.12 v4(95.04,74.42)
  L3_SIG1 w0.109: 90.43,73.11 87,69.67 87,66.32 85.35,64.67 85.35,51.19 82.74,48.58 82.58,48.58 82.46,48.7 82.3,48.7 82.19,48.59 82.19,48.41 82.3,48.3 82.3,48.14 81.79,47.63 81.79,37.29 82.8,36.28 86.78,36.28 v8(87.18,35.88)
DDR_D9: length 53
  TOP w0.173: U5.C3 v8(84.78,36.68) ; v4(91.95,67.16) 91.95,68.05 92.51,68.61 92.51,69.29 92.63,69.42 92.63,71.22 93.03,71.62 U1.AF27
  L3_SIG1 w0.109: v4(91.95,67.16) 91.95,66.93 88.87,63.85 88.87,60.41 88.76,60.3 88.45,60.3 88.34,60.19 88.34,59.97 88.45,59.86 88.76,59.86 88.87,59.76 88.87,59.54 88.76,59.43 88.45,59.43 88.34,59.32 88.34,59.1 88.45,58.99 88.76,58.99 88.87,58.88 88.87,58.66 88.76,58.55 88.45,58.55 88.34,58.44 88.34,58.23 88.45,58.12 88.76,58.12 88.87,58.01 88.87,57.79 88.76,57.68 88.45,57.68 88.34,57.57 88.34,57.35 88.45,57.24 88.76,57.24 88.87,57.13 88.87,56.92 88.76,56.81 88.45,56.81 88.34,56.7 88.34,56.48 88.45,56.37 88.76,56.37 88.87,56.26 88.87,56.04 88.76,55.93 88.45,55.93 88.34,55.82 88.34,55.61 88.45,55.5 88.76,55.5 88.87,55.39 88.87,55.17 88.76,55.06 88.45,55.06 88.34,54.95 88.34,54.73 88.45,54.62 88.76,54.62 88.87,54.51 88.87,54.29 88.76,54.19 88.45,54.19 88.34,54.08 88.34,53.86 88.45,53.75 88.76,53.75 88.87,53.64 88.87,53.42 88.76,53.31 88.45,53.31 88.34,53.2 88.34,52.98 88.45,52.87 88.76,52.87 88.87,52.77 88.87,51.66 87.93,50.73 87.93,50.23 88.04,50.12 88.64,50.12 88.75,50.01 88.75,49.79 88.64,49.68 88.04,49.68 87.93,49.57 87.93,49.35 88.04,49.24 88.64,49.24 88.75,49.13 88.75,48.92 88.64,48.81 88.04,48.81 87.93,48.7 87.93,48.48 88.04,48.37 88.64,48.37 88.75,48.26 88.75,48.04 88.64,47.93 88.04,47.93 87.93,47.82 87.93,47.61 88.04,47.5 88.64,47.5 88.75,47.39 88.75,47.17 88.64,47.06 88.04,47.06 87.93,46.95 87.93,46.73 88.04,46.62 88.64,46.62 88.75,46.51 88.75,46.29 88.64,46.19 88.04,46.19 87.93,46.08 87.93,42.23 85.36,39.66 85.36,37.26 v8(84.78,36.68)
DDR_D10: length 53
  TOP w0.173: v4(90.68,67.62) 90.68,68.2 91.39,68.91 91.39,70.17 91.83,70.62 91.83,71.21 U1.AG27 ; U5.A3 v8(84.78,38.28)
  L3_SIG1 w0.109: v4(90.68,67.62) 90.14,67.09 89.89,67.09 87.86,65.05 87.86,59.8 87.75,59.69 87.41,59.69 87.3,59.58 87.3,59.36 87.41,59.25 87.75,59.25 87.86,59.15 87.86,58.93 87.75,58.82 87.41,58.82 87.3,58.71 87.3,58.49 87.41,58.38 87.75,58.38 87.86,58.27 87.86,58.05 87.75,57.94 87.41,57.94 87.3,57.84 87.3,57.62 87.41,57.51 87.75,57.51 87.86,57.4 87.86,57.18 87.75,57.07 87.41,57.07 87.3,56.96 87.3,56.74 87.41,56.63 87.75,56.63 87.86,56.52 87.86,56.31 87.75,56.2 87.41,56.2 87.3,56.09 87.3,55.87 87.41,55.76 87.75,55.76 87.86,55.65 87.86,55.43 87.75,55.32 87.41,55.32 87.3,55.21 87.3,55 87.41,54.89 87.75,54.89 87.86,54.78 87.86,54.56 87.75,54.45 87.41,54.45 87.3,54.34 87.3,54.12 87.41,54.01 87.75,54.01 87.86,53.9 87.86,53.68 87.75,53.58 87.41,53.58 87.3,53.47 87.3,53.25 87.41,53.14 87.75,53.14 87.86,53.03 87.86,52.35 87.38,51.88 87.38,43.93 86.6,43.15 86.6,42.99 87.18,42.41 87.18,42.24 87.06,42.13 86.9,42.13 86.2,42.83 86.02,42.83 85.9,42.71 85.9,42.56 86.62,41.85 86.62,41.68 86.5,41.57 86.34,41.57 85.62,42.29 85.45,42.29 85.34,42.17 85.34,42.01 86.06,41.29 86.06,41.12 85.94,41.01 85.78,41.01 85.03,41.75 84.86,41.75 84.74,41.63 84.74,41.48 85.5,40.73 85.5,40.56 85.38,40.45 85.21,40.45 84.64,41.03 84.47,41.03 84.28,40.83 84.28,38.78 v8(84.78,38.28)
DDR_D11: length 53.1
  TOP w0.173: U1.AF28 93.04,68.2 92.51,67.67 v3(92.51,64.39) ; U5.A7 v8(87.18,38.28)
  L3_SIG1 w0.109: v8(87.18,38.28) 87.18,38.79 90.02,41.63 90.18,41.63 91.17,40.65 91.33,40.65 91.45,40.76 91.45,40.93 90.46,41.91 90.46,42.08 90.58,42.19 90.75,42.19 91.79,41.15 91.98,41.15 92.09,41.26 92.09,41.41 91.03,42.47 91.03,42.64 91.14,42.75 91.31,42.75 92.42,41.64 92.59,41.64 92.7,41.76 92.7,41.92 91.59,43.04 91.59,43.2 91.7,43.32 91.87,43.32 92.75,42.43 92.92,42.43 93.03,42.55 93.03,42.71 92.15,43.6 92.15,43.76 93.03,44.64 93.03,48.11 92.91,48.23 92.34,48.23 92.23,48.34 92.23,48.51 92.34,48.62 92.91,48.62 93.03,48.74 93.03,48.9 92.91,49.02 92.37,49.02 92.25,49.13 92.25,49.3 92.37,49.41 92.91,49.41 93.03,49.53 93.03,49.69 92.91,49.81 92.37,49.81 92.25,49.93 92.25,50.09 92.37,50.21 92.91,50.21 93.03,50.32 93.03,52.28 92.92,52.39 92.46,52.39 92.35,52.49 92.35,52.71 92.46,52.82 92.92,52.82 93.03,52.93 93.03,53.41 92.51,53.93 v3(92.51,64.39)
DDR_D12: length 52.7
  TOP w0.173: U1.AE26 v4(93.44,72.02) ; U5.A2 v8(83.98,38.28)
  L3_SIG1 w0.109: v4(93.44,72.02) 93.35,71.93 93.35,71.91 92.33,70.9 92.33,69.69 90.19,67.55 89.5,67.55 86.61,64.66 86.61,49.08 86.72,48.96 86.82,48.96 86.94,48.85 86.94,48.68 86.82,48.57 86.72,48.57 86.61,48.45 86.61,48.29 86.72,48.17 86.82,48.17 86.94,48.05 86.94,47.89 86.82,47.77 86.72,47.77 86.61,47.66 86.61,47.49 86.72,47.38 86.82,47.38 86.94,47.26 86.94,47.1 86.82,46.98 86.72,46.98 86.61,46.87 86.61,46.7 86.72,46.58 86.82,46.58 86.94,46.47 86.94,46.3 86.82,46.19 86.72,46.19 86.61,46.07 86.61,45.91 86.72,45.79 86.82,45.79 86.94,45.68 86.94,45.51 86.82,45.4 86.72,45.4 86.61,45.28 86.61,45.05 86.31,44.76 83.9,44.76 83.7,44.55 83.7,44.39 83.9,44.18 86.19,44.18 86.3,44.07 86.3,43.91 86.18,43.79 83.86,43.79 83.74,43.67 83.74,43.51 83.86,43.39 85.55,43.39 85.67,43.27 85.67,43.1 85.56,42.99 83.86,42.99 83.74,42.88 83.74,42.71 83.86,42.6 84.48,42.6 84.6,42.48 84.6,42.31 84.49,42.2 83.86,42.2 83.74,42.09 83.74,38.51 v8(83.98,38.28)
DDR_D13: length 52.7
  TOP w0.173: U1.AC25 v4(95.04,72.82) ; U5.C8 v8(87.98,36.68)
  L3_SIG1 w0.099: 94.17,71.24 94.74,71.81 94.74,72.52 v4(95.04,72.82)
  L3_SIG1 w0.109: v8(87.98,36.68) 88.37,36.28 93.58,36.28 93.96,36.67 93.96,37.59 93.85,37.7 92.51,37.7 92.39,37.82 92.39,37.98 92.51,38.1 93.85,38.1 93.96,38.22 93.96,38.38 93.85,38.5 92.48,38.5 92.37,38.61 92.37,38.78 92.48,38.89 93.85,38.89 93.96,39.01 93.96,39.17 93.85,39.29 92.49,39.29 92.38,39.4 92.38,39.56 92.5,39.68 93.85,39.68 93.96,39.8 93.96,66.48 94.17,66.69 94.17,71.24
DDR_D14: length 52.7
  TOP w0.173: U5.B8 v8(87.98,37.48) ; U1.AC24 v4(95.04,73.62)
  L3_SIG1 w0.099: v4(95.04,73.62) 95.04,73.32 94.53,72.82 94.53,71.9 93.73,71.09
  L3_SIG1 w0.109: 93.73,71.09 93.73,66.82 93.48,66.58 93.48,41.41 91.95,39.88 91.95,38.25 91.18,37.48 90.74,37.48 90.63,37.59 90.63,40.17 90.52,40.28 90.35,40.28 90.23,40.15 90.23,37.59 90.11,37.48 89.95,37.48 89.83,37.59 89.83,40.12 89.72,40.24 89.55,40.24 89.44,40.12 89.44,37.59 89.32,37.48 v8(87.98,37.48)
DDR_D15: length 52.6
  TOP w0.173: U1.AD25 v4(94.24,72.82) ; U5.C2 v8(83.98,36.68)
  L3_SIG1 w0.099: v4(94.24,72.82) 93.94,72.52 92.73,72.52 92.4,72.19 92.08,72.19 91.96,72.31 91.71,72.31 91.59,72.19 91.28,72.19 91.16,72.31 90.91,72.31 90.79,72.19 90.19,72.19
  L3_SIG1 w0.109: 90.19,72.19 87.5,69.5 87.5,66.19 85.95,64.64 85.95,50.67 85.57,50.29 85.57,50.13 85.96,49.74 85.96,49.58 85.84,49.46 85.68,49.46 85.29,49.85 85.13,49.85 85.01,49.73 85.01,49.57 85.48,49.11 85.48,48.94 85.36,48.83 85.2,48.83 84.73,49.29 84.57,49.29 84.45,49.17 84.45,49.01 84.91,48.55 84.91,48.38 84.8,48.26 84.63,48.26 84.17,48.73 84.01,48.73 83.89,48.61 83.89,48.45 84.35,47.98 84.35,47.82 84.24,47.7 84.07,47.7 83.61,48.17 83.45,48.17 83.33,48.05 83.33,47.89 83.82,47.4 83.82,47.25 83.7,47.13 83.53,47.13 83.05,47.61 82.89,47.61 82.63,47.35 82.63,37.26 83.21,36.68 v8(83.98,36.68)
DDR_D16: length 52.1
  TOP w0.173: v8(100.97,41) 100.97,36.02 U7.E3 ; U1.V20 v4(99.04,76.82)
  L3_SIG1 w0.109: v4(99.04,76.82) v5(98.64,76.57)
  L10_SIG4 w0.109: v8(100.97,41) 101.86,41.89 101.86,52.32 101.75,52.43 101.43,52.43 101.32,52.54 101.32,52.76 101.43,52.87 101.75,52.87 101.86,52.98 101.86,53.2 101.75,53.31 101.43,53.31 101.32,53.41 101.32,53.63 101.43,53.74 101.75,53.74 101.86,53.85 101.86,54.07 101.75,54.18 101.43,54.18 101.32,54.29 101.32,54.51 101.43,54.62 101.75,54.62 101.86,54.73 101.86,54.94 101.75,55.05 101.43,55.05 101.32,55.16 101.32,55.38 101.43,55.49 101.75,55.49 101.86,55.6 101.86,55.82 101.75,55.93 101.43,55.93 101.32,56.04 101.32,56.25 101.43,56.36 101.75,56.36 101.86,56.47 101.86,56.69 101.75,56.8 101.43,56.8 101.32,56.91 101.32,57.13 101.43,57.24 101.75,57.24 101.86,57.35 101.86,57.57 101.75,57.67 101.43,57.67 101.32,57.78 101.32,58 101.43,58.11 101.75,58.11 101.86,58.22 101.86,58.44 101.75,58.55 101.43,58.55 101.32,58.66 101.32,58.88 101.43,58.98 101.75,58.98 101.86,59.09 101.86,62.17 100.81,63.23 100.81,66.53 98.25,69.09 98.25,76.18 v5(98.64,76.57)
DDR_D17: length 51.8
  TOP w0.173: U1.W20 v4(98.24,76.82) ; U7.H8 v8(103.22,32.68)
  L3_SIG1 w0.109: v4(98.24,76.82) v5(97.84,76.57)
  L10_SIG4 w0.109: v8(103.22,32.68) 103.88,32.68 105.28,34.08 105.28,39.12 103.02,41.38 103.02,47.98 103.58,48.54 103.58,50.04 103.02,50.61 103.02,61.73 101.3,63.45 101.3,67.01 98.58,69.72 98.58,74.54 99.06,75.03 99.06,76.69 98.78,76.97 98.24,76.97 v5(97.84,76.57)
DDR_D18: length 52
  TOP w0.173: U7.H3 v8(100.02,32.68) ; v4(96.98,66.93) 97.41,67.37 97.41,68.28 96.24,69.45 U1.AB28
  L3_SIG1 w0.109: v4(96.98,66.93) 96.98,66.93 v5(96.63,66.59)
  L10_SIG4 w0.109: v8(100.02,32.68) 101.08,33.73 101.08,35.02 100.53,35.56 100.53,37.57 100.23,37.88 99.85,37.88 99.62,38.1 99.62,38.44 99.37,38.68 95.84,38.68 94.8,39.72 94.8,40.38 94.91,40.49 95.62,40.49 95.73,40.6 95.73,40.82 95.62,40.93 94.91,40.93 94.8,41.04 94.8,41.26 94.91,41.37 95.57,41.37 95.68,41.48 95.68,41.69 95.57,41.8 94.91,41.8 94.8,41.91 94.8,42.13 94.91,42.24 95.57,42.24 95.68,42.35 95.68,42.57 95.57,42.68 94.91,42.68 94.8,42.79 94.8,43.01 94.91,43.11 95.57,43.11 95.68,43.22 95.68,43.44 95.57,43.55 94.91,43.55 94.8,43.66 94.8,48.32 96.96,50.47 96.96,66.29 96.66,66.59 v5(96.63,66.59)
DDR_D19: length 52.1
  TOP w0.173: U7.G2 v8(99.22,33.48) ; U1.AC28 95.43,69.11 96.27,68.28 96.27,66.76 v4(95.76,66.25)
  L3_SIG1 w0.109: v5(95.46,65.83) 95.76,66.13 v4(95.76,66.25)
  L10_SIG4 w0.109: v5(95.46,65.83) 96.1,66.48 96.1,68.42 95.37,69.14 94.21,69.14 92.78,67.72 92.78,37.37 97.13,33.02 97.94,33.02 98.4,33.48 v8(99.22,33.48)
DDR_D20: length 52
  TOP w0.173: U7.F2 v8(99.22,34.28) ; v4(95.76,67.37) 95.49,67.63 95.49,68.25 95.04,68.71 95.04,71.22 U1.AC27
  L3_SIG1 w0.109: v5(95.5,66.96) 95.5,67.11 v4(95.76,67.37)
  L10_SIG4 w0.109: v8(99.22,34.28) 98.83,33.89 97,33.89 96.72,34.17 96.72,34.42 96.52,34.63 96.27,34.63 95.95,34.94 95.95,35.1 96.21,35.36 96.21,35.52 96.06,35.67 95.91,35.67 95.64,35.41 95.49,35.41 95.33,35.56 95.33,35.71 95.62,36 95.62,36.16 95.47,36.31 95.31,36.31 95.02,36.02 94.87,36.02 94.71,36.18 94.71,36.33 95,36.62 95,36.78 94.85,36.93 94.69,36.93 94.4,36.64 94.25,36.64 94.09,36.8 94.09,36.95 94.38,37.24 94.38,37.4 94.23,37.55 94.08,37.55 93.79,37.26 93.63,37.26 93.26,37.63 93.26,67.68 94.49,68.9 95.09,68.9 95.5,68.49 v5(95.5,66.96)
DDR_D21: length 51.8
  TOP w0.173: U7.F7 v8(102.42,34.28) ; U1.Y19 v4(97.44,77.62)
  L3_SIG1 w0.109: v4(97.44,77.62) v5(97.04,77.37)
  L10_SIG4 w0.109: v8(102.42,34.28) 102.82,34.68 102.82,39.04 101.85,40.01 100.66,40.01 99.53,41.14 99.53,45.03 99.42,45.14 98.94,45.14 98.83,45.25 98.83,45.47 98.94,45.57 99.42,45.57 99.53,45.68 99.53,45.9 99.42,46.01 98.92,46.01 98.81,46.12 98.81,46.34 98.92,46.45 99.42,46.45 99.53,46.56 99.53,46.78 99.42,46.89 98.92,46.89 98.81,46.99 98.81,47.21 98.92,47.32 99.42,47.32 99.53,47.43 99.53,66.08 96.65,68.97 96.65,76.98 v5(97.04,77.37)
DDR_D22: length 52
  TOP w0.173: U1.AB27 95.84,71.22 95.84,69.19 v4(96.98,68.05) ; U7.H7 v8(102.42,32.68)
  L3_SIG1 w0.109: v4(96.98,68.05) v5(96.64,67.71)
  L10_SIG4 w0.109: v8(102.42,32.68) 101.48,33.62 101.48,35.57 101.05,35.99 101.05,38 100.08,38.98 97.44,38.98 96.74,39.67 96.74,44.9 96.63,45.01 95.82,45.01 95.71,45.11 95.71,45.33 95.82,45.44 96.63,45.44 96.74,45.55 96.74,45.77 96.63,45.88 95.84,45.88 95.73,45.99 95.73,46.21 95.84,46.32 96.63,46.32 96.74,46.43 96.74,46.64 96.63,46.75 95.84,46.75 95.73,46.86 95.73,47.08 95.84,47.19 96.63,47.19 96.74,47.3 96.74,47.52 96.63,47.63 95.84,47.63 95.73,47.74 95.73,47.95 95.84,48.06 96.63,48.06 96.74,48.17 96.74,49.62 97.56,50.45 97.56,66.8 96.65,67.71 v5(96.64,67.71)
DDR_D23: length 51.8
  TOP w0.173: U1.Y20 v4(97.44,76.82) ; U7.F8 v8(103.22,34.28)
  L3_SIG1 w0.109: v4(97.44,76.82) v5(97.04,76.57)
  L10_SIG4 w0.109: v5(97.04,76.57) 97.43,76.17 97.43,75.57 97.54,75.47 97.54,75.01 97.43,74.91 97.43,72.96 97.18,72.7 97.18,69.07 100.32,65.93 100.32,62.39 100.84,61.88 100.84,51.45 100.73,51.34 100.44,51.34 100.33,51.23 100.33,51.01 100.44,50.9 100.73,50.9 100.84,50.79 100.84,50.57 100.73,50.46 100.44,50.46 100.33,50.35 100.33,50.13 100.44,50.03 100.73,50.03 100.84,49.92 100.84,49.7 100.73,49.59 100.44,49.59 100.33,49.48 100.33,49.26 100.44,49.15 100.73,49.15 100.84,49.04 100.84,48.82 100.73,48.71 100.44,48.71 100.33,48.61 100.33,48.39 100.44,48.28 100.73,48.28 100.84,48.17 100.84,47.95 100.73,47.84 100.57,47.84 100.46,47.73 100.46,47.51 100.57,47.4 100.73,47.4 100.84,47.29 100.84,45.21 100.38,44.75 100.38,40.97 100.79,40.57 102.14,40.57 103.63,39.07 103.63,34.69 v8(103.22,34.28)
DDR_D24: length 48.4
  TOP w0.173: U1.AA23 v4(96.64,74.42) ; U7.D7 v8(102.42,35.88)
  L3_SIG1 w0.099: 95.98,69.47 95.98,71.91 96.14,72.06 96.14,72.19 96.34,72.39 96.34,72.94 96.51,73.11 96.65,73.11 96.94,73.4 96.94,73.75 96.64,74.06 v4(96.64,74.42)
  L3_SIG1 w0.109: v8(102.42,35.88) 101.59,35.88 100.74,36.73 100.74,39.93 99.16,41.5 99,41.5 98.64,41.15 98.49,41.15 98.37,41.26 98.37,41.44 98.72,41.78 98.72,41.95 98.6,42.06 98.44,42.06 98,41.63 97.84,41.63 97.72,41.74 97.72,41.91 98.16,42.34 98.16,42.51 98.04,42.62 97.88,42.62 97.41,42.16 97.26,42.16 97.15,42.27 97.15,42.46 97.6,42.9 97.6,43.07 97.12,43.54 97.12,57.24 96.55,57.82 96.55,63.63 97.59,64.68 97.59,67.87 95.98,69.47
DDR_D25: length 48.4
  TOP w0.173: U1.Y22 v4(97.44,75.22) ; U7.C3 v8(100.02,36.68)
  L3_SIG1 w0.099: 95.44,72.02 95.2,72.27 95.2,72.57 95.48,72.84 95.48,72.87 95.71,73.11 95.83,73.11 96.14,73.41 96.14,74.33 96.64,74.84 97.06,74.84 v4(97.44,75.22)
  L3_SIG1 w0.109: v8(100.02,36.68) 99.63,37.06 95.98,37.06 95.81,37.23 95.65,37.23 95.37,36.96 95.18,36.96 95.07,37.07 95.07,37.22 95.52,37.67 95.52,37.83 95.42,37.94 95.23,37.94 94.73,37.44 94.57,37.44 94.45,37.56 94.45,37.72 94.81,38.08 94.81,38.24 94.56,38.49 94.56,65.84 95.11,66.39 95.11,67.99 95.44,68.32 95.44,72.02
DDR_D26: length 48.4
  TOP w0.173: U7.B8 v8(103.22,37.48) ; U1.Y23 v4(97.44,74.42)
  L3_SIG1 w0.099: 96.63,69.79 96.63,71.54 96.93,71.84 96.93,73 97.14,73.22 97.14,73.74 97.44,74.03
  L3_SIG1 w0.109: v4(97.44,74.42) 97.44,74.03 ; v8(103.22,37.48) 103.63,37.89 103.63,39.4 103.52,39.51 103,39.51 102.88,39.63 102.88,39.79 103,39.91 103.64,39.91 103.77,40.04 103.77,40.2 103.66,40.31 103.02,40.31 102.91,40.42 102.91,40.58 103.03,40.7 103.6,40.7 103.71,40.82 103.71,40.98 103.6,41.1 103.02,41.1 102.91,41.21 102.91,41.37 103.03,41.5 103.52,41.5 103.64,41.61 103.64,45.1 103.52,45.22 102.99,45.22 102.87,45.34 102.87,45.5 102.99,45.62 103.52,45.62 103.64,45.73 103.64,46.12 102.7,47.06 102.54,47.06 102.44,46.97 102.28,46.97 102.16,47.08 102.16,47.25 102.26,47.34 102.26,47.51 102.14,47.62 101.98,47.62 101.88,47.53 101.72,47.53 101.6,47.64 101.6,47.81 101.69,47.9 101.69,48.07 101.58,48.18 101.41,48.18 101.32,48.09 101.16,48.09 101.04,48.2 101.04,48.37 101.13,48.46 101.13,48.63 100.53,49.23 100.53,54.31 100.18,54.67 100.18,66.65 98.65,68.18 98.24,68.18 96.63,69.79
DDR_D27: length 48.4
  TOP w0.173: U7.A2 v8(99.22,38.28) ; U1.AA24 v4(96.64,73.62)
  L3_SIG1 w0.099: v4(96.64,73.62) 96.13,73.11 96.13,72.46 95.94,72.27 95.94,72.23 95.65,71.94
  L3_SIG1 w0.109: 95.65,71.94 95.65,68.51 96.2,67.95 96.2,65.93 95,64.73 95,45.45 95.11,45.34 95.5,45.34 95.61,45.23 95.61,45.01 95.5,44.9 95.11,44.9 95,44.79 95,44.57 95.11,44.46 95.5,44.46 95.61,44.35 95.61,44.14 95.5,44.03 95.11,44.03 95,43.92 95,43.7 95.11,43.59 95.5,43.59 95.61,43.48 95.61,43.26 95.5,43.15 95.11,43.15 95,43.04 95,42.83 95.11,42.72 95.5,42.72 95.61,42.61 95.61,42.39 95.5,42.28 95.11,42.28 95,42.17 95,41.95 95.11,41.84 95.5,41.84 95.61,41.73 95.61,41.51 95.5,41.41 95.11,41.41 95,41.3 95,41.08 95.11,40.97 95.5,40.97 95.61,40.86 95.61,40.64 95.5,40.53 95.11,40.53 95,40.42 95,40.2 95.11,40.09 95.5,40.09 95.61,39.99 95.61,39.77 95.5,39.66 95.11,39.66 95,39.55 95,39.09 96.22,37.87 98.82,37.87 v8(99.22,38.28)
DDR_D28: length 48.4
  TOP w0.173: U7.C2 v8(99.22,36.68) ; U1.Y24 v4(97.44,73.62)
  L3_SIG1 w0.099: v4(97.44,73.62) 97.44,73.23 97.14,72.94 97.14,71.68 96.84,71.37 96.84,69.97
  L3_SIG1 w0.109: v8(99.22,36.68) 99.62,36.28 99.62,35.72 99.85,35.49 103.38,35.49 104.42,36.52 104.42,46.11 100.99,49.54 100.99,54.67 100.62,55.04 100.62,66.8 98.83,68.58 98.22,68.58 96.84,69.97
DDR_D29: length 48.3
  TOP w0.173: U1.AA26 96.64,72.02 v4(96.64,71.98) ; U7.A7 v8(102.42,38.28)
  L3_SIG1 w0.099: 96.64,71.97 96.42,71.76 96.42,69.69
  L3_SIG1 w0.109: v8(102.42,38.28) 102.44,38.3 102.44,41.97 102.56,42.09 102.95,42.09 103.05,42.19 103.05,42.36 102.92,42.49 102.56,42.49 102.44,42.6 102.44,42.77 102.56,42.88 103,42.88 103.11,43 103.11,43.16 102.99,43.28 102.53,43.28 102.42,43.39 102.42,43.56 102.53,43.67 102.94,43.67 103.06,43.79 103.06,43.95 102.94,44.07 102.53,44.07 102.42,44.19 102.42,44.51 102.3,44.63 101.33,44.63 101.22,44.74 101.22,44.91 101.33,45.02 102.3,45.02 102.42,45.14 102.42,46.14 102.16,46.4 101.99,46.4 100.88,45.29 100.72,45.29 100.6,45.4 100.6,45.57 101.71,46.68 101.71,46.85 101.39,47.17 101.23,47.17 100.69,46.62 100.52,46.62 100.4,46.74 100.4,46.9 100.95,47.45 100.95,47.61 100.83,47.73 100.67,47.73 100.57,47.63 100.4,47.63 100.29,47.74 100.29,47.91 100.39,48.01 100.39,48.17 100.08,48.49 100.08,54.06 99.73,54.4 99.73,66.66 98.47,67.92 98.19,67.92 96.42,69.69 ; 96.64,71.97 v4(96.64,71.98)
DDR_D30: length 48.3
  TOP w0.173: U7.C8 v8(103.22,36.68) ; U1.AA25 v4(96.64,72.82)
  L3_SIG1 w0.099: 96.2,69.59 96.2,71.82 96.34,71.96 96.34,72.11 96.64,72.4 v4(96.64,72.82)
  L3_SIG1 w0.109: 96.2,69.59 98.04,67.76 98.04,63.88 97,62.84 97,58.25 97.6,57.65 97.6,45.05 97.72,44.93 98.08,44.93 98.19,44.81 98.19,44.65 98.08,44.53 97.72,44.53 97.6,44.42 97.6,43.77 97.8,43.57 97.96,43.57 98.25,43.86 98.42,43.86 98.54,43.74 98.54,43.59 98.24,43.29 98.24,43.13 98.36,43.01 98.52,43.01 98.84,43.33 99,43.33 99.12,43.21 99.12,43.05 98.8,42.73 98.8,42.57 98.92,42.45 99.08,42.45 99.36,42.73 99.54,42.73 99.65,42.61 99.65,42.46 99.36,42.17 99.36,42.01 99.48,41.89 99.64,41.89 100.18,42.42 100.35,42.42 100.46,42.3 100.46,42.15 99.92,41.61 99.92,41.44 100.96,40.41 100.96,37.11 101.8,36.28 102.82,36.28 v8(103.22,36.68)
DDR_D31: length 48.6
  TOP w0.173: U1.AA28 97.04,69.67 98.4,68.31 98.4,66.97 97.96,66.53 97.96,65.83 v4(97.1,64.97) ; U7.A3 v8(100.02,38.28)
  L3_SIG1 w0.109: v4(97.1,64.97) 96.09,63.96 96.09,57.61 96.65,57.05 96.65,56.68 96.54,56.57 96.17,56.57 96.06,56.47 96.06,56.25 96.17,56.14 96.54,56.14 96.65,56.03 96.65,55.81 96.54,55.7 96.2,55.7 96.09,55.59 96.09,55.37 96.2,55.26 96.54,55.26 96.65,55.16 96.65,54.94 96.54,54.83 96.2,54.83 96.09,54.72 96.09,54.5 96.2,54.39 96.54,54.39 96.65,54.28 96.65,40.01 96.77,39.9 96.94,39.9 97.9,40.86 98.07,40.86 98.18,40.74 98.18,40.58 96.97,39.36 96.97,39.2 97.08,39.08 97.25,39.08 98.92,40.75 99.1,40.75 99.25,40.6 99.25,40.46 98.12,39.33 98.12,39.16 98.23,39.05 98.4,39.05 99.05,39.7 99.22,39.7 99.33,39.59 99.33,39.42 99.21,39.3 99.21,39.13 99.32,39.02 99.49,39.02 99.61,39.14 99.78,39.14 100.02,38.9 v8(100.02,38.28)
DDR_DQM0: length 59.5
  TOP w0.173: U5.E7 v8(87.18,35.08) ; U1.AD23 v4(94.24,74.42)
  L3_SIG1 w0.099: v4(94.24,74.42) v5(93.84,74.17)
  L10_SIG4 w0.109: v5(93.84,74.17) 94.22,73.78 94.22,73.12 92.95,71.85 92.95,68.25 91.71,67.01 91.71,53.46 91.6,53.34 90.92,53.34 90.79,53.22 90.79,53.06 90.9,52.95 91.6,52.95 91.71,52.83 91.71,52.67 91.6,52.55 90.86,52.55 90.74,52.43 90.74,52.27 90.86,52.15 91.6,52.15 91.71,52.04 91.71,51.87 91.6,51.76 90.86,51.76 90.74,51.64 90.74,51.48 90.86,51.36 91.6,51.36 91.71,51.25 91.71,51.08 91.6,50.97 90.86,50.97 90.74,50.85 90.74,50.69 90.86,50.57 91.6,50.57 91.71,50.45 91.71,50.29 91.6,50.17 90.86,50.17 90.74,50.06 90.74,49.89 90.86,49.78 91.6,49.78 91.71,49.66 91.71,49.5 91.6,49.38 90.86,49.38 90.74,49.26 90.74,49.1 90.86,48.98 91.6,48.98 91.71,48.87 91.71,48.7 91.6,48.59 90.9,48.59 90.78,48.46 90.78,48.3 90.88,48.19 91.6,48.19 91.71,48.08 91.71,47.91 91.6,47.8 91.06,47.8 90.94,47.67 90.94,47.51 91.05,47.4 91.6,47.4 91.71,47.28 91.71,47.12 91.6,47 91.03,47 90.91,46.88 90.91,46.72 91.02,46.61 91.6,46.61 91.71,46.49 91.71,46.33 91.6,46.21 91.04,46.21 90.93,46.1 90.93,45.94 91.05,45.81 91.6,45.81 91.71,45.7 91.71,43.76 88.39,40.44 88.39,35.74 88.13,35.48 87.59,35.48 v8(87.18,35.08)
DDR_DQM1: length 52.6
  TOP w0.173: U5.D3 v8(84.78,35.88) ; U1.AB23 v4(95.84,74.42)
  L3_SIG1 w0.099: v4(95.84,74.42) 95.45,74.42 95.16,74.71 94.91,74.71 94.74,74.54 94.74,74.41 94.31,73.97 94.18,73.97 93.99,73.79 93.68,73.79 93.56,73.91 93.31,73.91 93.19,73.79 92.88,73.79 92.76,73.91 92.51,73.91 92.39,73.79 90.47,73.79
  L3_SIG1 w0.109: 90.47,73.79 84.74,68.06 84.74,52.19 81.28,48.73 81.28,36.16 81.95,35.49 84.39,35.49 v8(84.78,35.88)
DDR_DQM2: length 51.8
  TOP w0.173: U7.E7 v8(102.42,35.08) ; U1.AC26 v4(95.04,72.02)
  L3_SIG1 w0.109: v5(95.03,71.45) 95.03,72.02 v4(95.04,72.02)
  L10_SIG4 w0.109: v5(95.03,71.45) 95.03,70.91 95.81,70.13 95.81,69.16 98.98,65.99 98.98,51.09 97.55,49.66 97.55,44.49 97.66,44.38 98.32,44.38 98.42,44.27 98.42,44.05 98.32,43.94 97.66,43.94 97.55,43.84 97.55,43.62 97.66,43.51 98.32,43.51 98.42,43.4 98.42,43.18 98.32,43.07 97.66,43.07 97.55,42.96 97.55,42.74 97.66,42.63 98.32,42.63 98.42,42.52 98.42,42.31 98.32,42.2 97.66,42.2 97.55,42.09 97.55,41.87 97.66,41.76 98.32,41.76 98.42,41.65 98.42,41.43 98.32,41.32 97.66,41.32 97.55,41.21 97.55,41 97.66,40.89 98.39,40.89 98.53,40.75 98.53,40.56 98.42,40.45 97.66,40.45 97.55,40.34 97.55,39.95 98.15,39.35 101.28,39.35 101.88,38.75 101.88,35.61 v8(102.42,35.08)
DDR_DQM3: length 48.7
  TOP w0.173: v4(97.05,65.95) 97.05,66.32 97.82,67.09 97.82,68.33 96.64,69.51 96.64,71.22 U1.AA27 ; U7.D3 v8(100.02,35.88)
  L3_SIG1 w0.109: v8(100.02,35.88) 100.46,36.31 100.46,37.6 100.18,37.88 99.86,37.88 99.62,38.12 99.62,38.44 99.39,38.66 96.67,38.66 96.09,39.25 96.09,47.49 95.98,47.6 95.64,47.6 95.53,47.71 95.53,47.92 95.64,48.03 95.98,48.03 96.09,48.14 96.09,48.36 95.98,48.47 95.56,48.47 95.45,48.58 95.45,48.8 95.56,48.91 95.98,48.91 96.09,49.02 96.09,49.23 95.98,49.34 95.56,49.34 95.45,49.45 95.45,49.67 95.56,49.78 95.98,49.78 96.09,49.89 96.09,50.11 95.98,50.22 95.56,50.22 95.45,50.33 95.45,50.54 95.56,50.65 95.98,50.65 96.09,50.76 96.09,50.98 95.98,51.09 95.56,51.09 95.45,51.2 95.45,51.42 95.56,51.53 95.98,51.53 96.09,51.64 96.09,51.86 95.98,51.96 95.59,51.96 95.48,52.07 95.48,52.29 95.59,52.4 95.98,52.4 96.09,52.51 96.09,52.73 95.98,52.84 95.59,52.84 95.48,52.95 95.48,53.17 95.59,53.28 95.98,53.28 96.09,53.38 96.09,53.83 95.55,54.36 95.55,64.46 v4(97.05,65.95)
DDR_DQS0: length 59.6
  TOP w0.108: U5.F3 v8(84.78,34.28) ; U1.AH25 v4(91.04,72.82)
  L3_SIG1 w0.083: v4(91.04,72.82) v5(90.64,72.57)
  L10_SIG4 w0.083: v8(84.78,34.28) 85.04,34.01 85.16,34.01 85.24,34.1 85.24,41.44 84.73,41.95 84.73,53.58 84.24,54.06 84.24,55.58 84.5,55.84 85.34,55.84 85.42,55.92 85.42,56.09 85.34,56.17 84.5,56.17 84.24,56.43 84.24,56.85 84.5,57.11 85.34,57.11 85.42,57.19 85.42,57.36 85.34,57.44 84.5,57.44 84.24,57.7 84.24,58.12 84.5,58.38 85.34,58.38 85.42,58.46 85.42,58.63 85.34,58.71 84.5,58.71 84.24,58.97 84.24,59.39 84.5,59.65 85.34,59.65 85.42,59.73 85.42,59.9 85.34,59.98 84.5,59.98 84.24,60.24 84.24,60.66 84.5,60.92 85.34,60.92 85.42,61 85.42,61.17 85.34,61.25 84.5,61.25 84.24,61.51 84.24,61.93 84.5,62.19 85.34,62.19 85.42,62.27 85.42,62.44 85.34,62.52 84.5,62.52 84.24,62.78 84.24,63.2 84.5,63.46 85.34,63.46 85.42,63.54 85.42,63.71 85.34,63.79 84.5,63.79 84.24,64.05 84.24,65.71 84.63,66.09 85.09,66.09 85.37,66.37 85.37,67.63 85.29,67.71 84.92,67.71 84.84,67.8 84.84,67.96 84.92,68.04 85.29,68.04 85.37,68.13 85.37,69.14 88.79,72.57 v5(90.64,72.57)
DDR_DQS1: length 53.1
  TOP w0.108: U5.C7 v8(87.18,36.68) ; v4(93.33,67.82) 93.33,70.28 93.46,70.41 93.46,71.24 U1.AE27
  L3_SIG1 w0.083: v4(93.33,67.82) 93.33,67.82 92.32,66.81 92.32,66.2 91.34,65.23 91.34,50.38 91.26,50.3 89.72,50.3 89.46,50.04 89.46,49.62 89.72,49.36 91.26,49.36 91.34,49.28 91.34,49.11 91.26,49.03 89.72,49.03 89.46,48.77 89.46,48.35 89.72,48.09 91.26,48.09 91.34,48.01 91.34,47.84 91.26,47.76 89.72,47.76 89.46,47.5 89.46,47.08 89.72,46.82 91.26,46.82 91.34,46.74 91.34,46.57 91.26,46.49 89.72,46.49 89.46,46.23 89.46,45.81 89.72,45.55 91.26,45.55 91.34,45.47 91.34,44.54 85.95,39.14 85.95,37.41 86.43,36.92 86.93,36.92 v8(87.18,36.68)
DDR_DQS2: length 52.1
  TOP w0.108: U7.F3 v8(100.02,34.28) ; v4(94.58,67.59) 94.57,67.6 94.57,68.22 94.17,68.63 94.17,70.32 94.27,70.43 94.27,71.25 U1.AD27
  L3_SIG1 w0.083: v4(94.58,67.59) 94.58,68.02 v5(94.67,68.1)
  L10_SIG4 w0.083: v8(100.02,34.28) 99.59,34.71 98.55,34.71 97.61,35.65 97,35.65 93.89,38.77 93.89,50.95 94.15,51.21 95.12,51.21 95.2,51.29 95.2,51.46 95.12,51.54 94.15,51.54 93.89,51.8 93.89,52.22 94.15,52.48 95.12,52.48 95.2,52.56 95.2,52.73 95.12,52.81 94.15,52.81 93.89,53.07 93.89,53.49 94.15,53.75 95.12,53.75 95.2,53.83 95.2,54 95.12,54.08 94.15,54.08 93.89,54.34 93.89,54.76 94.15,55.02 95.12,55.02 95.2,55.1 95.2,55.27 95.12,55.35 94.15,55.35 93.89,55.61 93.89,66.69 94.26,67.06 94.26,67.16 94.67,67.57 v5(94.67,68.1)
DDR_DQS3: length 48.7
  TOP w0.108: v4(98.78,66.1) 99.08,66.39 99.08,66.78 99.06,66.79 99.06,67.33 99.17,67.44 99.33,67.44 99.44,67.55 99.44,67.76 99.33,67.87 99.17,67.87 99.06,67.98 99.06,68.56 97.83,69.79 U1.Y28 ; U7.C7 v8(102.42,36.68)
  L3_SIG1 w0.083: v8(102.42,36.68) 102.17,36.92 101.93,36.92 101.54,37.32 101.54,42.95 100.99,43.49 100.87,43.49 100.52,43.14 100.15,43.14 99.85,43.43 99.85,43.8 100.21,44.16 100.21,44.27 100.09,44.39 99.97,44.39 99.54,43.96 99.17,43.96 98.88,44.26 98.88,44.63 99.31,45.06 99.31,45.17 99.02,45.47 99.02,46.63 98.93,46.71 98.48,46.71 98.22,46.97 98.22,47.39 98.48,47.65 98.93,47.65 99.02,47.73 99.02,47.9 98.93,47.98 98.48,47.98 98.22,48.24 98.22,48.66 98.48,48.92 98.93,48.92 99.02,49 99.02,49.17 98.93,49.25 98.48,49.25 98.22,49.51 98.22,49.93 98.48,50.19 98.93,50.19 99.02,50.27 99.02,50.44 98.93,50.52 98.48,50.52 98.22,50.78 98.22,51.2 98.48,51.46 98.93,51.46 99.02,51.54 99.02,53.68 98.43,54.26 98.43,57.68 97.61,58.5 97.61,59.56 97.87,59.82 98.42,59.82 98.5,59.91 98.5,60.07 98.42,60.15 97.89,60.15 97.63,60.41 97.63,60.83 97.89,61.09 98.42,61.09 98.5,61.18 98.5,61.34 98.42,61.42 97.87,61.42 97.61,61.68 97.61,62.53 98.78,63.71 v4(98.78,66.1)
DDR_DQSN0: length 59.7
  TOP w0.108: U1.AG25 v4(91.84,72.82) ; U5.G3 v8(84.78,33.48)
  L3_SIG1 w0.083: v4(91.84,72.82) v5(91.44,72.57)
  L10_SIG4 w0.083: v8(84.78,33.48) 85.01,33.71 85.29,33.71 85.55,33.97 85.55,41.56 85.03,42.08 85.03,53.71 84.55,54.19 84.55,55.45 84.63,55.53 85.46,55.53 85.72,55.8 85.72,56.21 85.46,56.47 84.63,56.47 84.55,56.56 84.55,56.72 84.63,56.8 85.46,56.8 85.72,57.07 85.72,57.48 85.46,57.74 84.63,57.74 84.55,57.83 84.55,57.99 84.63,58.07 85.46,58.07 85.72,58.34 85.72,58.75 85.46,59.01 84.63,59.01 84.55,59.1 84.55,59.26 84.63,59.34 85.46,59.34 85.72,59.61 85.72,60.02 85.46,60.28 84.63,60.28 84.55,60.37 84.55,60.53 84.63,60.61 85.46,60.61 85.72,60.88 85.72,61.29 85.46,61.55 84.63,61.55 84.55,61.64 84.55,61.8 84.63,61.88 85.46,61.88 85.72,62.15 85.72,62.56 85.46,62.82 84.63,62.82 84.55,62.91 84.55,63.07 84.63,63.15 85.46,63.15 85.72,63.42 85.72,63.83 85.46,64.09 84.63,64.09 84.55,64.18 84.55,65.58 84.75,65.79 85.21,65.79 85.67,66.25 85.67,69.02 88.92,72.26 90.4,72.26 90.47,72.19 91.06,72.19 v5(91.44,72.57)
DDR_DQSN1: length 53
  TOP w0.108: v4(93.33,66.88) 93.33,67.35 93.65,67.67 93.65,68.05 93.59,68.11 93.59,70.17 93.83,70.42 U1.AE28 ; U5.B7 v8(87.18,37.48)
  L3_SIG1 w0.083: v4(93.33,66.88) 93.33,67.12 93.25,67.2 93.13,67.2 92.62,66.69 92.62,66.08 92.36,65.81 92.36,65.69 92.52,65.54 92.52,65.42 92.4,65.3 92.28,65.3 92.12,65.46 92.01,65.46 91.65,65.1 91.65,50.26 91.39,50 89.85,50 89.76,49.91 89.76,49.75 89.85,49.67 91.39,49.67 91.65,49.4 91.65,48.99 91.39,48.73 89.85,48.73 89.76,48.64 89.76,48.48 89.85,48.4 91.39,48.4 91.65,48.13 91.65,47.72 91.39,47.46 89.85,47.46 89.76,47.37 89.76,47.21 89.85,47.13 91.39,47.13 91.65,46.86 91.65,46.45 91.39,46.19 89.85,46.19 89.76,46.1 89.76,45.94 89.85,45.86 91.39,45.86 91.65,45.59 91.65,44.41 86.25,39.01 86.25,37.53 86.55,37.23 86.93,37.23 v8(87.18,37.48)
DDR_DQSN2: length 52.1
  TOP w0.108: U7.G3 v8(100.02,33.48) ; U1.AD28 94.64,70.43 94.42,70.22 94.42,68.75 94.89,68.28 94.89,67.44 94.63,67.18 v4(94.63,66.51)
  L3_SIG1 w0.083: v4(94.63,66.51) v5(94.63,67)
  L10_SIG4 w0.083: v5(94.63,67) 94.19,66.56 94.19,55.74 94.27,55.65 95.24,55.65 95.5,55.39 95.5,54.97 95.24,54.71 94.27,54.71 94.19,54.63 94.19,54.47 94.27,54.38 95.24,54.38 95.5,54.12 95.5,53.7 95.24,53.44 94.27,53.44 94.19,53.36 94.19,53.2 94.27,53.11 95.24,53.11 95.5,52.85 95.5,52.43 95.24,52.17 94.27,52.17 94.19,52.09 94.19,51.93 94.27,51.84 95.24,51.84 95.5,51.58 95.5,51.16 95.24,50.9 94.27,50.9 94.19,50.82 94.19,38.89 97.12,35.96 97.73,35.96 98.24,35.45 99.37,35.45 100.39,34.43 100.39,33.85 v8(100.02,33.48)
DDR_DQSN3: length 48.7
  TOP w0.108: U1.Y27 97.83,71.62 97.45,71.23 97.45,69.79 98.78,68.46 v4(98.78,66.65) ; U7.B7 v8(102.42,37.48)
  L3_SIG1 w0.083: v4(98.78,66.65) 99.11,66.32 99.11,65.97 99.08,65.95 99.08,63.58 97.91,62.41 97.91,61.81 97.99,61.73 98.55,61.73 98.81,61.47 98.81,61.05 98.55,60.79 98.02,60.79 97.94,60.71 97.94,60.54 98.02,60.46 98.55,60.46 98.81,60.2 98.81,59.78 98.55,59.52 97.99,59.52 97.91,59.44 97.91,58.63 98.73,57.81 98.73,54.39 99.32,53.8 99.32,51.42 99.06,51.16 98.61,51.16 98.53,51.07 98.53,50.91 98.61,50.83 99.06,50.83 99.32,50.57 99.32,50.15 99.06,49.89 98.61,49.89 98.53,49.8 98.53,49.64 98.61,49.56 99.06,49.56 99.32,49.3 99.32,48.88 99.06,48.62 98.61,48.62 98.53,48.53 98.53,48.37 98.61,48.29 99.06,48.29 99.32,48.03 99.32,47.61 99.06,47.35 98.61,47.35 98.53,47.26 98.53,47.1 98.61,47.02 99.06,47.02 99.32,46.76 99.32,45.59 99.61,45.3 99.61,44.93 99.18,44.5 99.18,44.38 99.3,44.27 99.42,44.27 99.85,44.7 100.22,44.7 100.51,44.4 100.51,44.03 100.16,43.68 100.16,43.56 100.28,43.44 100.39,43.44 100.75,43.8 101.12,43.8 101.84,43.07 101.84,37.44 102.05,37.23 102.17,37.23 v8(102.42,37.48)
DDR_ODT: length 143.7
  TOP w0.173: R75.2 109.98,27.56 111.05,28.63 111.05,29.04 v8(112.69,30.68) U6.K1 ; U5.K1 v8(82.21,30.68) ; U1.AE20 v4(93.44,76.82) ; U7.K1 v8(97.45,30.68)
  L3_SIG1 w0.099: 91.93,77.7 92.16,77.7 93.05,76.82 v4(93.44,76.82)
  L3_SIG1 w0.109: v5(73.28,38.21) 72.06,39.43 72.06,53.14 73.36,54.44 73.36,55.26 73.46,55.37 73.7,55.37 73.81,55.48 73.81,55.69 73.7,55.8 73.46,55.8 73.36,55.91 73.36,56.13 73.46,56.24 73.96,56.24 74.07,56.35 74.07,56.57 73.96,56.68 73.46,56.68 73.36,56.79 73.36,57.01 73.46,57.11 73.96,57.11 74.07,57.22 74.07,57.44 73.96,57.55 73.46,57.55 73.36,57.66 73.36,57.88 73.46,57.99 73.96,57.99 74.07,58.1 74.07,58.32 73.96,58.43 73.46,58.43 73.36,58.53 73.36,58.75 73.46,58.86 73.96,58.86 74.07,58.97 74.07,59.19 73.96,59.3 73.46,59.3 73.36,59.41 73.36,59.63 73.46,59.74 73.96,59.74 74.07,59.84 74.07,60.06 73.96,60.17 73.46,60.17 73.36,60.28 73.36,60.5 73.46,60.61 73.96,60.61 74.07,60.72 74.07,60.94 73.96,61.05 73.46,61.05 73.36,61.16 73.36,61.37 73.46,61.48 73.96,61.48 74.07,61.59 74.07,61.81 73.96,61.92 73.46,61.92 73.36,62.03 73.36,62.25 73.46,62.36 73.96,62.36 74.07,62.47 74.07,62.68 73.96,62.79 73.46,62.79 73.36,62.9 73.36,63.12 73.46,63.23 73.96,63.23 74.07,63.34 74.07,63.56 73.96,63.67 73.46,63.67 73.36,63.78 73.36,64 73.46,64.1 73.96,64.1 74.07,64.21 74.07,64.43 73.96,64.54 73.46,64.54 73.36,64.65 73.36,65.3 78.19,70.14 78.39,70.14 79.02,69.52 79.22,69.52 79.36,69.66 79.36,69.86 78.73,70.48 78.73,70.68 78.87,70.82 79.07,70.82 79.7,70.2 79.9,70.2 80.04,70.34 80.04,70.53 79.41,71.16 79.41,71.36 79.55,71.5 79.75,71.5 80.38,70.87 80.58,70.87 80.72,71.01 80.72,71.21 80.09,71.84 80.09,72.04 80.23,72.18 80.43,72.18 81.06,71.55 81.26,71.55 81.4,71.69 81.4,71.89 80.77,72.52 80.77,72.72 80.91,72.86 81.11,72.86 81.74,72.23 81.94,72.23 82.08,72.37 82.08,72.57 81.45,73.2 81.45,73.4 81.59,73.54 81.79,73.54 82.42,72.91 82.62,72.91 82.76,73.05 82.76,73.25 82.13,73.88 82.13,74.08 82.27,74.22 82.47,74.22 83.1,73.59 83.29,73.59 83.44,73.73 83.44,73.93 82.81,74.56 82.81,74.76 82.95,74.9 83.15,74.9 83.78,74.27 83.97,74.27 84.11,74.41 84.11,74.61 83.49,75.24 83.49,75.44 83.63,75.58 83.83,75.58 84.45,74.95 84.65,74.95 84.79,75.09 84.79,75.29 84.17,75.92 84.17,76.11 84.38,76.33 86.41,76.33 87.02,76.94 88.39,76.94 89.15,77.7 91.93,77.7
  L10_SIG4 w0.109: v8(112.69,30.68) 111.16,32.22 107.27,32.22 106.54,31.49 103.83,31.49 103.58,31.73 103.14,31.73 102.74,32.13 99.65,32.13 99.49,32.29 99.06,32.29 v8(97.45,30.68) 97.45,31.41 96.65,32.21 92.03,32.21 91.21,31.39 88.68,31.39 88.34,31.73 87.9,31.73 87.6,32.03 85.49,32.03 85.37,31.91 84.05,31.91 82.82,30.68 v8(82.21,30.68) ; v7(72.95,30.02) 72.95,33.13 73.28,33.46 v5(73.28,38.21)
  BOTTOM w0.102: 80.16,30.2 80.59,30.63 82.17,30.63 v8(82.21,30.68)
  BOTTOM w0.173: v7(72.95,30.02) 79.98,30.02 80.16,30.2
DDR_RASN: length 146.9
  TOP w0.173: U7.J3 100.26,31.48 v8(100.28,31.5) ; U5.J3 v8(84.91,31.48) ; U1.AF20 v4(92.64,76.82) ; U6.J3 v8(115.51,31.48)
  L3_SIG1 w0.109: v4(92.64,76.82) 91.98,77.47 89.36,77.47 88.47,76.59 87.3,76.59 87.04,76.33 87.04,75.99 87.48,75.55 87.48,75.36 87.34,75.21 87.14,75.21 86.54,75.82 86.34,75.82 86.2,75.68 86.2,75.48 86.77,74.9 86.77,74.7 86.63,74.56 86.43,74.56 85.86,75.14 85.66,75.14 85.52,75 85.52,74.8 86.09,74.22 86.09,74.02 85.95,73.88 85.75,73.88 85.18,74.46 84.98,74.46 84.84,74.32 84.84,74.12 85.41,73.54 85.41,73.34 85.27,73.2 85.08,73.2 84.5,73.78 84.3,73.78 84.16,73.64 84.16,73.44 84.74,72.86 84.74,72.66 84.59,72.52 84.4,72.52 83.82,73.1 83.62,73.1 83.48,72.96 83.48,72.76 84.06,72.18 84.06,71.99 83.92,71.84 83.72,71.84 83.14,72.42 82.94,72.42 82.8,72.28 82.8,72.08 83.38,71.5 83.38,71.31 83.24,71.16 83.04,71.16 82.46,71.74 82.26,71.74 82.12,71.6 82.12,71.4 82.7,70.83 82.7,70.63 82.56,70.49 82.36,70.49 81.78,71.06 81.58,71.06 81.44,70.92 81.44,70.72 82.02,70.15 82.02,69.97 81.88,69.83 81.65,69.83 81.1,70.38 80.9,70.38 80.76,70.24 80.76,70.04 81.34,69.47 81.34,69.27 81.2,69.13 81,69.13 80.42,69.7 80.22,69.7 79.54,69.02 77.94,69.02 74.52,65.61 74.52,54.87 72.57,52.91 72.57,52.32 72.68,52.21 73.04,52.21 73.15,52.1 73.15,51.88 73.04,51.77 72.68,51.77 72.57,51.66 72.57,51.45 72.68,51.34 73.04,51.34 73.15,51.23 73.15,51.01 73.04,50.9 72.68,50.9 72.57,50.79 72.57,50.57 72.68,50.46 73.04,50.46 73.15,50.35 73.15,50.13 73.04,50.03 72.68,50.03 72.57,49.92 72.57,49.7 72.68,49.59 73.04,49.59 73.15,49.48 73.15,49.26 73.04,49.15 72.68,49.15 72.57,49.04 72.57,48.82 72.68,48.71 73.04,48.71 73.15,48.61 73.15,48.39 73.04,48.28 72.68,48.28 72.57,48.17 72.57,40.9 v5(73.71,39.76) ; v8(84.91,31.48) 85.45,31.48 86.21,30.71 86.38,30.71 86.72,30.38 87.83,30.38 88.29,30.84 89.18,30.84 89.41,31.07 90.3,31.07 90.43,30.94 90.43,30.74 90.55,30.62 90.72,30.62 90.84,30.74 90.84,30.94 90.95,31.06 92.58,31.06 92.96,30.68 93.64,30.68 94.1,31.14 97.77,31.14 98.22,30.69 99.47,30.69 v8(100.28,31.5) 100.63,31.15 100.99,31.15 101.5,30.64 101.7,30.64 101.96,30.38 103.1,30.38 103.53,30.82 104.39,30.82 104.65,31.07 105.33,31.07 105.66,30.74 106.07,30.74 106.39,31.06 107.82,31.06 108.2,30.68 109,30.68 109.45,31.14 112.94,31.14 113.39,30.69 114.72,30.69 v8(115.51,31.48)
  L10_SIG4 w0.109: v7(73.76,35.79) 73.76,39.71 v5(73.71,39.76)
  BOTTOM w0.102: 80.71,32.51 81.06,32.16 82.63,32.16 82.75,32.28 83.31,32.28 83.85,31.75 84.64,31.75 v8(84.91,31.48)
  BOTTOM w0.173: v8(115.51,31.48) 115.28,31.24 114.08,31.24 113.83,31.49 112.92,31.49 112.16,30.73 109.6,30.73 R51.2 ; 80.71,32.51 79.76,33.45 76.1,33.45 75.93,33.62 75.93,33.87 78.01,35.95 78.01,36.19 77.77,36.44 77.52,36.44 75.44,34.36 75.2,34.36 74.95,34.6 74.95,34.85 77.03,36.93 77.03,37.17 76.79,37.41 76.54,37.41 74.46,35.34 74.22,35.34 v7(73.76,35.79)
DDR_RESETN: length 106.3
  TOP w0.173: U5.T2 v8(83.58,24.64) ; U6.T2 v8(114.06,24.64) ; U7.T2 v8(98.82,24.64) ; v3(76.83,24.51) 76.83,43.18 78.39,44.74 78.39,67.43 86.66,75.7 87.89,75.7 88.21,76.02 91.83,76.02 U1.AG21
  L3_SIG1 w0.109: v8(83.58,24.64) 82.9,23.96 77.39,23.96 v3(76.83,24.51)
  L10_SIG4 w0.109: v8(83.58,24.64) 83.58,24.6 85.78,22.4 96.59,22.4 v8(98.82,24.64) 98.82,24.6 101.02,22.4 111.83,22.4 v8(114.06,24.64)
DDR_WEN: length 150.8
  TOP w0.173: U7.L3 v8(100.15,29.88) ; v3(76.96,50.32) 77.69,51.05 77.69,52.07 77.52,52.24 76.6,52.24 76.43,52.41 76.43,52.76 76.6,52.93 77.52,52.93 77.69,53.1 77.69,53.45 77.52,53.62 76.6,53.62 76.43,53.79 76.43,54.14 76.6,54.31 77.52,54.31 77.69,54.48 77.69,54.83 77.52,55 76.6,55 76.43,55.17 76.43,55.52 76.6,55.69 77.52,55.69 77.69,55.87 77.69,56.21 77.52,56.38 76.6,56.38 76.43,56.56 76.43,56.9 76.6,57.07 77.52,57.07 77.69,57.25 77.69,57.59 77.52,57.77 76.6,57.77 76.43,57.94 76.43,58.28 76.6,58.46 77.52,58.46 77.69,58.63 77.69,58.97 77.52,59.15 76.6,59.15 76.43,59.32 76.43,59.67 76.6,59.84 77.52,59.84 77.69,60.01 77.69,60.36 77.52,60.53 76.6,60.53 76.43,60.7 76.43,61.05 76.6,61.22 77.52,61.22 77.69,61.39 77.69,61.74 77.52,61.91 76.6,61.91 76.43,62.08 76.43,62.43 76.6,62.6 77.52,62.6 77.69,62.77 77.69,63.12 77.52,63.29 76.6,63.29 76.43,63.47 76.43,63.81 76.6,63.98 77.52,63.98 77.69,64.16 77.69,64.5 77.52,64.67 76.6,64.67 76.43,64.85 76.43,65.19 76.6,65.37 77.52,65.37 77.69,65.54 77.69,65.88 77.52,66.06 76.6,66.06 76.43,66.23 76.43,66.57 76.6,66.75 77.52,66.75 77.69,66.92 77.69,67.86 86.24,76.42 U1.AH21 ; U5.L3 v8(84.91,29.88) ; U6.L3 v8(115.39,29.88)
  L3_SIG1 w0.109: v8(115.39,29.88) 114.63,29.88 114.63,29.88 114.23,29.88 114,29.65 113.36,29.65 113.13,29.88 112.39,29.88 112.05,29.54 107.9,29.54 107.58,29.86 107.22,29.86 107.1,29.74 107.1,29.22 106.99,29.11 106.83,29.11 106.7,29.24 106.7,29.74 106.58,29.86 102.12,29.86 101.73,29.47 101.42,29.47 101.01,29.88 v8(100.15,29.88) 99.39,29.88 99.39,29.88 99.01,29.88 98.78,29.65 98.02,29.65 97.78,29.88 96.98,29.88 96.64,29.54 92.66,29.54 92.34,29.86 91.98,29.86 91.86,29.74 91.86,29.35 91.75,29.24 91.58,29.24 91.46,29.37 91.46,29.74 91.34,29.86 91,29.86 90.89,29.74 90.89,29.61 90.77,29.49 90.6,29.49 90.48,29.61 90.48,29.74 90.36,29.86 86.88,29.86 86.49,29.47 86.18,29.47 85.77,29.88 v8(84.91,29.88) ; v3(76.96,50.32) 76.96,38.31 77.09,38.18 v5(77.22,38.18)
  L10_SIG4 w0.109: v7(78.79,31.09) 79.39,30.49 79.39,30.27 79.02,29.9 79.02,29.29 79.49,28.82 79.49,27 79.24,26.75 78.84,26.75 78.64,26.95 78.64,29.27 78.06,29.85 78.06,30 78.15,30.09 78.15,30.31 78,30.45 77.83,30.45 77.72,30.34 77.57,30.34 77.24,30.67 77.24,32.16 77.38,32.3 79.06,32.3 79.2,32.44 79.2,32.64 79.07,32.78 77.36,32.78 77.22,32.92 77.22,33.12 77.36,33.26 78.82,33.26 78.96,33.4 78.96,33.6 78.82,33.74 77.36,33.74 77.22,33.88 77.22,34.08 77.36,34.22 78.4,34.22 78.54,34.36 78.54,34.56 78.4,34.7 77.36,34.7 77.22,34.84 77.22,35.1 77.36,35.24 77.85,35.24 77.99,35.38 77.99,35.58 77.85,35.72 77.33,35.72 77.22,35.83 v5(77.22,38.18)
  BOTTOM w0.102: v8(84.91,29.88) 84.32,29.88 83.39,30.81 82.93,30.81 82.65,31.09 79.76,31.09
  BOTTOM w0.173: R53.2 117.22,23.49 114.91,25.81 114.91,29.4 v8(115.39,29.88) ; v7(78.79,31.09) 79.76,31.09
DDRECC_D0: length 58.2
  TOP w0.173: U1.W22 v4(99.02,75.23) ; v8(115.7,41.02) 116.46,40.26 116.46,36.28 U6.E3
  L3_SIG1 w0.099: v4(99.02,75.23) 99.46,74.79 99.46,74.14 99.56,74.04 99.56,73.23 99.34,73.02 99.34,71.02 99.58,70.78
  L3_SIG1 w0.109: 99.58,70.78 100.46,69.91 101,69.91 104.26,66.64 104.26,66 105.44,64.83 105.44,62.74 105.99,62.18 105.99,56.76 117.8,44.96 117.8,44.44 117.91,44.33 118.64,44.33 118.75,44.22 118.75,44 118.64,43.89 117.91,43.89 117.8,43.78 117.8,43.56 117.91,43.45 118.94,43.45 119.05,43.34 119.05,43.12 118.94,43.02 117.91,43.02 117.8,42.91 117.8,42.69 117.91,42.58 118.94,42.58 119.05,42.47 119.05,42.25 118.94,42.14 117.91,42.14 117.8,42.03 117.8,41.6 117.22,41.02 v8(115.7,41.02)
DDRECC_D1: length 57.8
  TOP w0.173: U1.V23 v4(98.96,74.34) ; U6.F7 v8(117.66,34.28)
  L3_SIG1 w0.099: 99.19,70.55 98.94,70.79 98.94,73.19 99.12,73.37 99.12,73.86 98.96,74.02 v4(98.96,74.34)
  L3_SIG1 w0.109: 99.19,70.55 100.47,69.27 100.78,69.27 103.38,66.67 103.38,65.44 104.42,64.4 104.42,62.41 105.08,61.76 105.08,56.26 113.55,47.79 113.55,47.62 113.25,47.32 113.25,47.13 113.36,47.02 113.51,47.02 113.83,47.34 113.99,47.34 114.17,47.16 114.17,46.64 114.29,46.52 114.68,46.52 114.81,46.39 114.81,46.23 114.71,46.12 114.29,46.12 114.17,46.01 114.17,45.84 114.29,45.73 114.67,45.73 114.78,45.61 114.78,45.45 114.67,45.33 114.29,45.33 114.17,45.21 114.17,45.05 114.29,44.93 114.67,44.93 114.78,44.82 114.78,44.65 114.67,44.54 114.29,44.54 114.17,44.42 114.17,44.26 114.29,44.14 114.67,44.14 114.78,44.03 114.78,43.86 114.67,43.75 114.29,43.75 114.17,43.63 114.17,43.47 114.29,43.35 114.67,43.35 114.78,43.23 114.78,43.07 114.67,42.95 114.29,42.95 114.17,42.84 114.17,42.67 114.29,42.56 114.67,42.56 114.78,42.44 114.78,42.28 114.67,42.16 114.29,42.16 114.17,42.04 114.17,41.06 115.23,40 117.35,40 118.06,39.29 118.06,34.68 v8(117.66,34.28)
DDRECC_D2: length 57.8
  TOP w0.173: U1.W19 v4(98.24,77.62) ; U6.H8 v8(118.46,32.68)
  L3_SIG1 w0.099: 99.83,70.83 99.54,71.12 99.54,72.94 99.77,73.16 99.77,74.11 99.66,74.23 99.66,74.98 99.47,75.17 99.47,76.79 99.16,77.11 98.91,77.11 98.75,76.95 98.52,76.95 98.24,77.23 v4(98.24,77.62)
  L3_SIG1 w0.109: v8(118.46,32.68) 119.3,32.68 120.57,33.95 120.57,39.5 119.92,40.15 119.92,43.79 106.45,57.26 106.45,62.36 105.89,62.92 105.89,65 104.95,65.94 104.95,66.26 101,70.21 100.45,70.21 99.83,70.83
DDRECC_D3: length 57.9
  TOP w0.173: U6.F8 v8(118.46,34.28) ; U1.W23 v4(98.24,74.42)
  L3_SIG1 w0.099: v4(98.24,74.42) 98.46,74.64 99.09,74.64 99.26,74.47 99.26,74.06 99.32,73.99 99.32,73.28 99.14,73.1 99.14,70.9 99.41,70.63
  L3_SIG1 w0.109: v8(118.46,34.28) 118.85,34.66 118.85,37.06 119.28,37.49 119.28,38.69 117.66,40.31 115.65,40.31 115.24,40.72 115.24,43.92 115.35,44.04 116.55,44.04 116.66,44.16 116.66,44.32 116.55,44.44 115.38,44.44 115.26,44.55 115.26,44.72 115.38,44.83 116.55,44.83 116.66,44.95 116.66,45.11 116.55,45.23 115.38,45.23 115.26,45.34 115.26,46.73 105.54,56.45 105.54,61.94 104.93,62.55 104.93,64.59 103.82,65.7 103.82,66.77 101.02,69.58 100.47,69.58 99.41,70.63
DDRECC_D4: length 57.8
  TOP w0.173: U6.F2 v8(114.46,34.28) ; U1.Y25 v4(97.44,72.82)
  L3_SIG1 w0.099: 97.25,70.2 97.25,71.04 97.73,71.51 97.73,72.14 97.44,72.43 v4(97.44,72.82)
  L3_SIG1 w0.109: v8(114.46,34.28) 114.42,34.28 113.9,34.8 113.41,34.8 113.06,34.45 112.07,34.45 110.24,36.28 110.24,36.64 110.35,36.75 110.92,36.75 111.03,36.87 111.03,37.03 110.92,37.15 110.35,37.15 110.24,37.27 110.24,37.43 110.35,37.55 110.92,37.55 111.03,37.66 111.03,37.83 110.92,37.94 110.35,37.94 110.24,38.06 110.24,38.22 110.35,38.34 110.92,38.34 111.03,38.46 111.03,38.62 110.92,38.74 110.35,38.74 110.24,38.85 110.24,40.16 109.53,40.87 109.53,41.03 109.89,41.4 109.89,41.57 109.77,41.68 109.62,41.68 109.25,41.31 109.08,41.31 108.97,41.43 108.97,41.59 109.65,42.28 109.65,42.43 109.54,42.54 109.36,42.54 108.69,41.87 108.52,41.87 107.95,42.44 107.95,43.33 108.07,43.44 108.66,43.44 108.78,43.56 108.78,43.72 108.66,43.84 108.07,43.84 107.95,43.96 107.95,44.76 101.96,50.75 101.96,55 101.51,55.44 101.51,66.62 98.96,69.16 98.29,69.16 97.25,70.2
DDRECC_D5: length 57.9
  TOP w0.173: U1.V24 99.03,73.61 v4(98.83,73.61) ; U6.H7 v8(117.66,32.68)
  L3_SIG1 w0.099: v4(98.83,73.61) 98.83,73.38 98.74,73.29 98.74,70.67 98.95,70.46
  L3_SIG1 w0.109: v8(117.66,32.68) 117.22,33.11 117.22,38.61 116.2,39.62 115,39.62 113.66,40.96 113.66,45.93 112.53,47.07 112.53,47.95 108.82,51.66 108.65,51.66 108.51,51.52 108.35,51.52 108.23,51.64 108.23,51.8 108.37,51.94 108.37,52.11 108.26,52.22 108.09,52.22 107.72,51.85 107.56,51.85 107.44,51.97 107.44,52.13 107.81,52.5 107.81,52.67 107.7,52.78 107.53,52.78 107.16,52.41 107,52.41 106.88,52.53 106.88,52.69 107.25,53.06 107.25,53.23 107.13,53.34 106.97,53.34 106.6,52.97 106.44,52.97 106.32,53.09 106.32,53.25 106.69,53.62 106.69,53.79 106.57,53.91 106.41,53.91 106.04,53.53 105.88,53.53 105.76,53.65 105.76,53.81 106.13,54.19 106.13,54.35 106.01,54.47 105.85,54.47 105.48,54.1 105.31,54.1 105.2,54.21 105.2,54.38 105.67,54.85 105.67,55.04 104.62,56.09 104.62,61.59 103.95,62.26 103.95,64.11 102.94,65.12 102.94,66.71 100.68,68.97 100.45,68.97 98.95,70.46
DDRECC_D6: length 58
  TOP w0.173: U1.V25 99.05,72.83 98.78,72.83 98.62,72.67 98.62,72.61 v4(98.39,72.38) ; U6.H3 v8(115.26,32.68)
  L3_SIG1 w0.099: v4(98.39,72.38) 98.54,72.22 98.54,70.52 98.7,70.36
  L3_SIG1 w0.109: 98.7,70.36 102.49,66.57 102.49,64.93 103.51,63.91 103.51,62.07 104.17,61.41 104.17,55.91 104.72,55.35 104.72,53.97 108.92,49.77 109.09,49.77 109.41,50.1 109.58,50.1 109.69,49.98 109.69,49.82 109.37,49.49 109.37,49.33 109.48,49.21 109.65,49.21 109.97,49.54 110.14,49.54 110.25,49.42 110.25,49.26 109.93,48.93 109.93,48.77 110.04,48.65 110.21,48.65 110.53,48.98 110.7,48.98 110.81,48.86 110.81,48.7 110.49,48.37 110.49,48.21 112.52,46.17 112.52,45.34 112.64,45.22 113.08,45.22 113.2,45.1 113.2,44.94 113.08,44.82 112.64,44.82 112.52,44.71 112.52,44.54 112.64,44.43 113.08,44.43 113.2,44.31 113.2,44.15 113.08,44.03 112.64,44.03 112.52,43.92 112.52,43.75 112.64,43.64 113.08,43.64 113.2,43.52 113.2,43.36 113.08,43.24 112.64,43.24 112.52,43.12 112.52,42.96 112.64,42.84 112.86,42.84 112.97,42.73 112.97,42.56 112.86,42.45 112.64,42.45 112.52,42.33 112.52,41.41 114.58,39.35 115.71,39.35 116.97,38.1 116.97,34.38 v8(115.26,32.68)
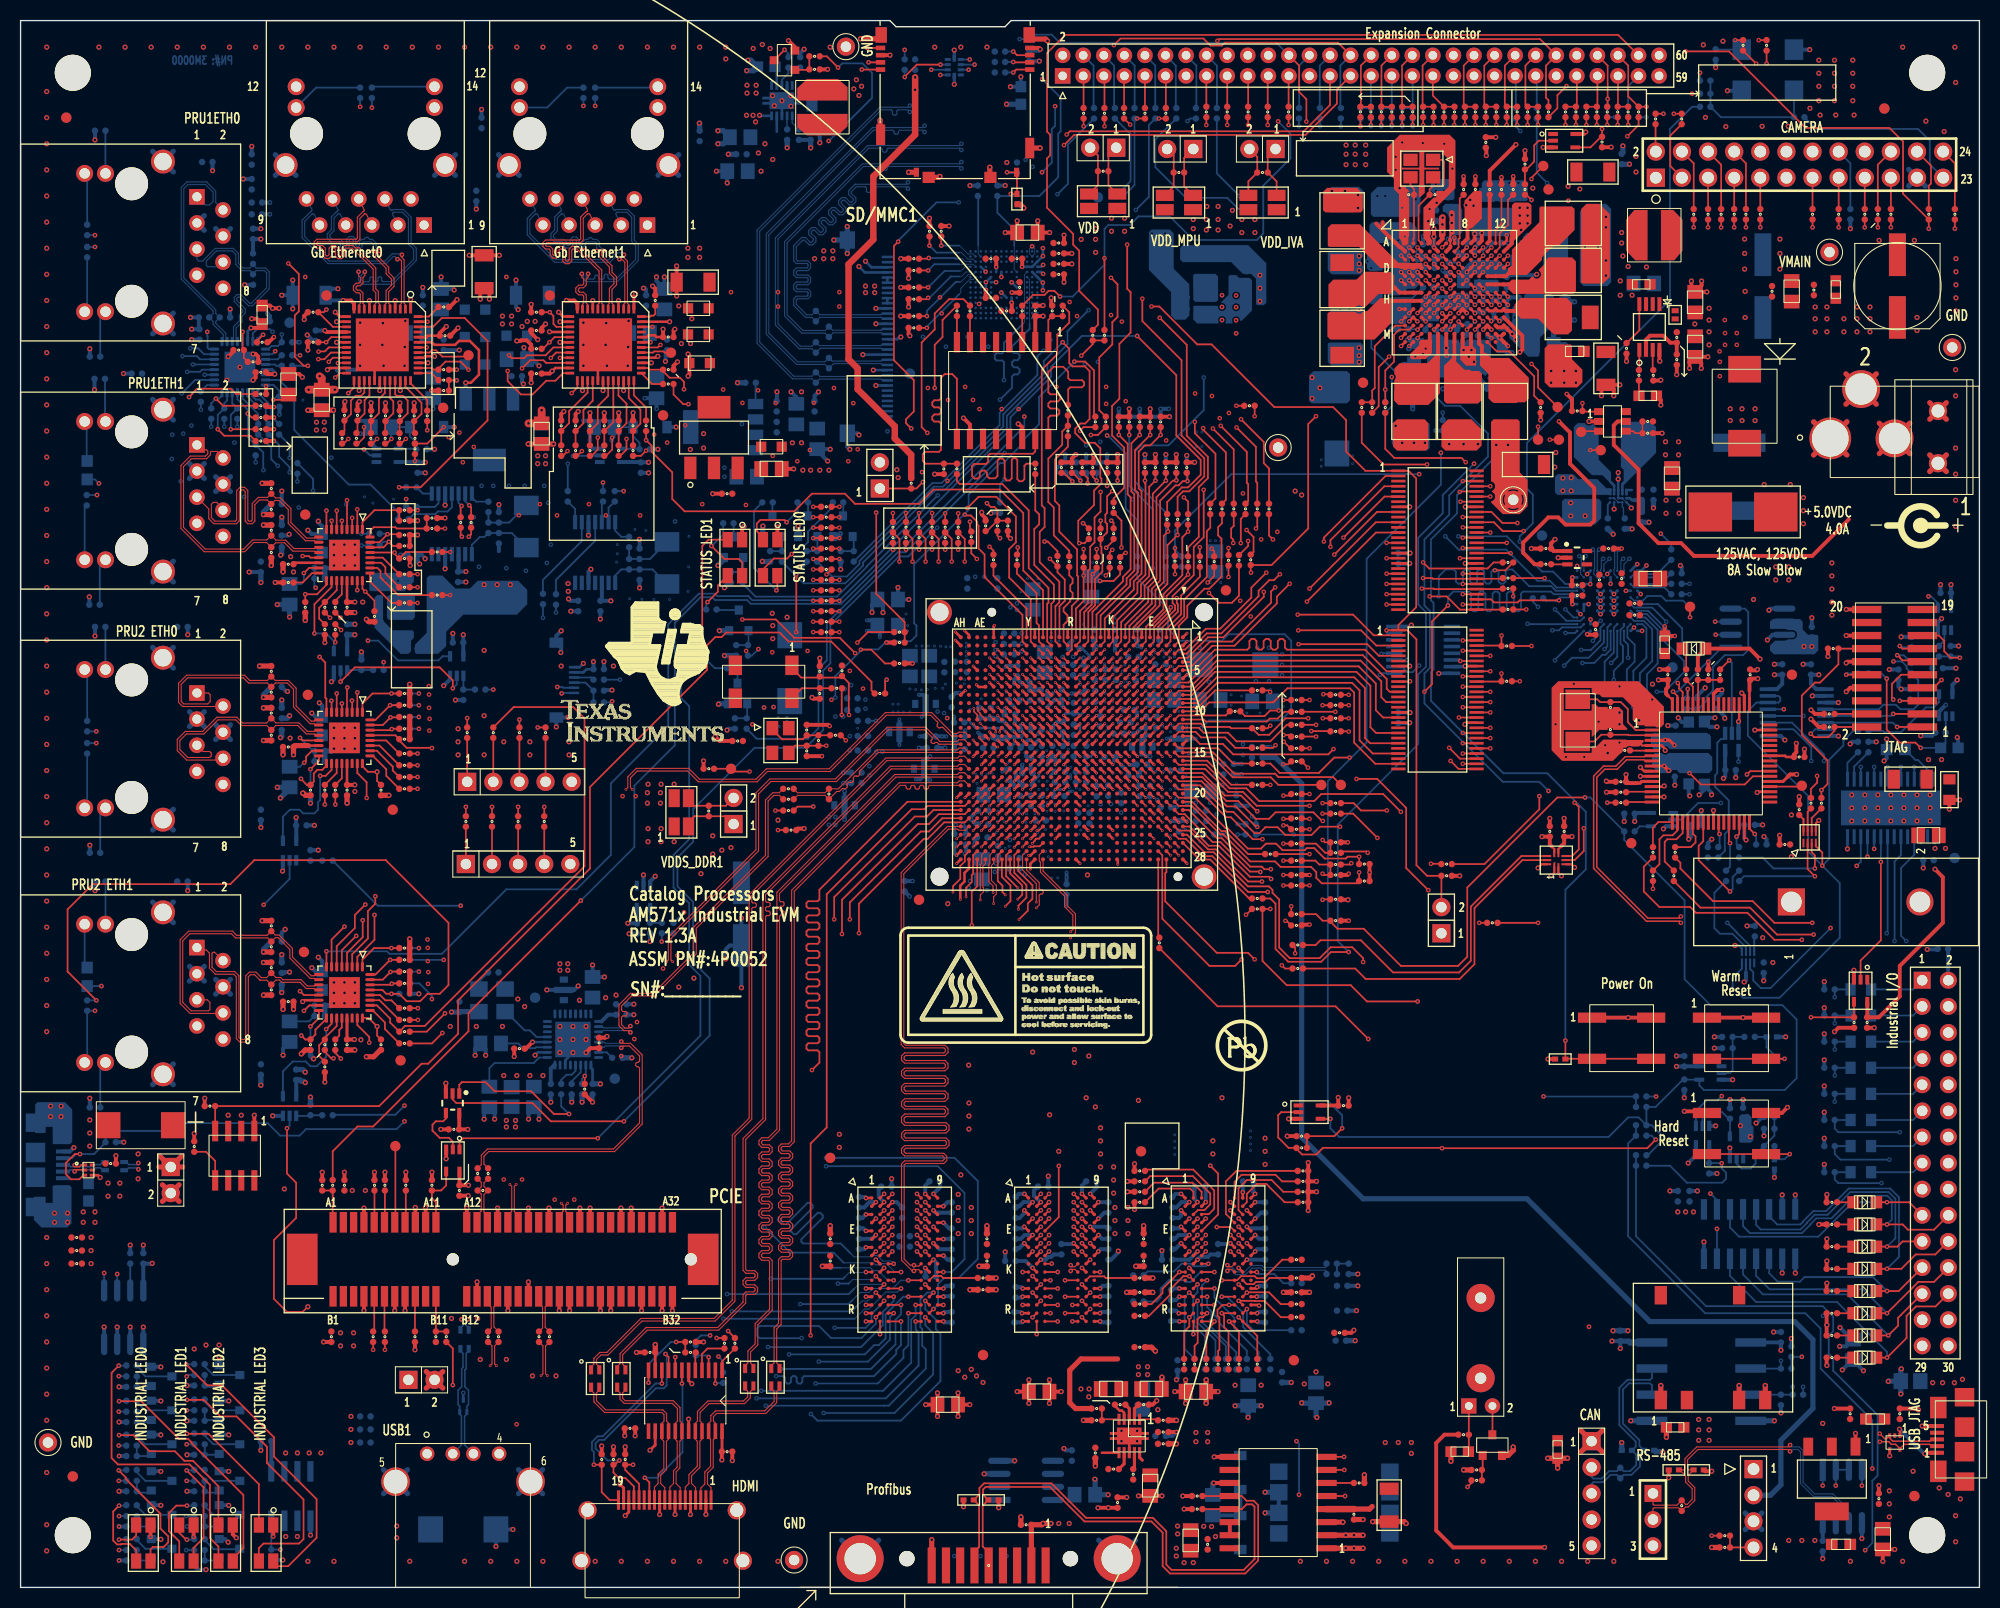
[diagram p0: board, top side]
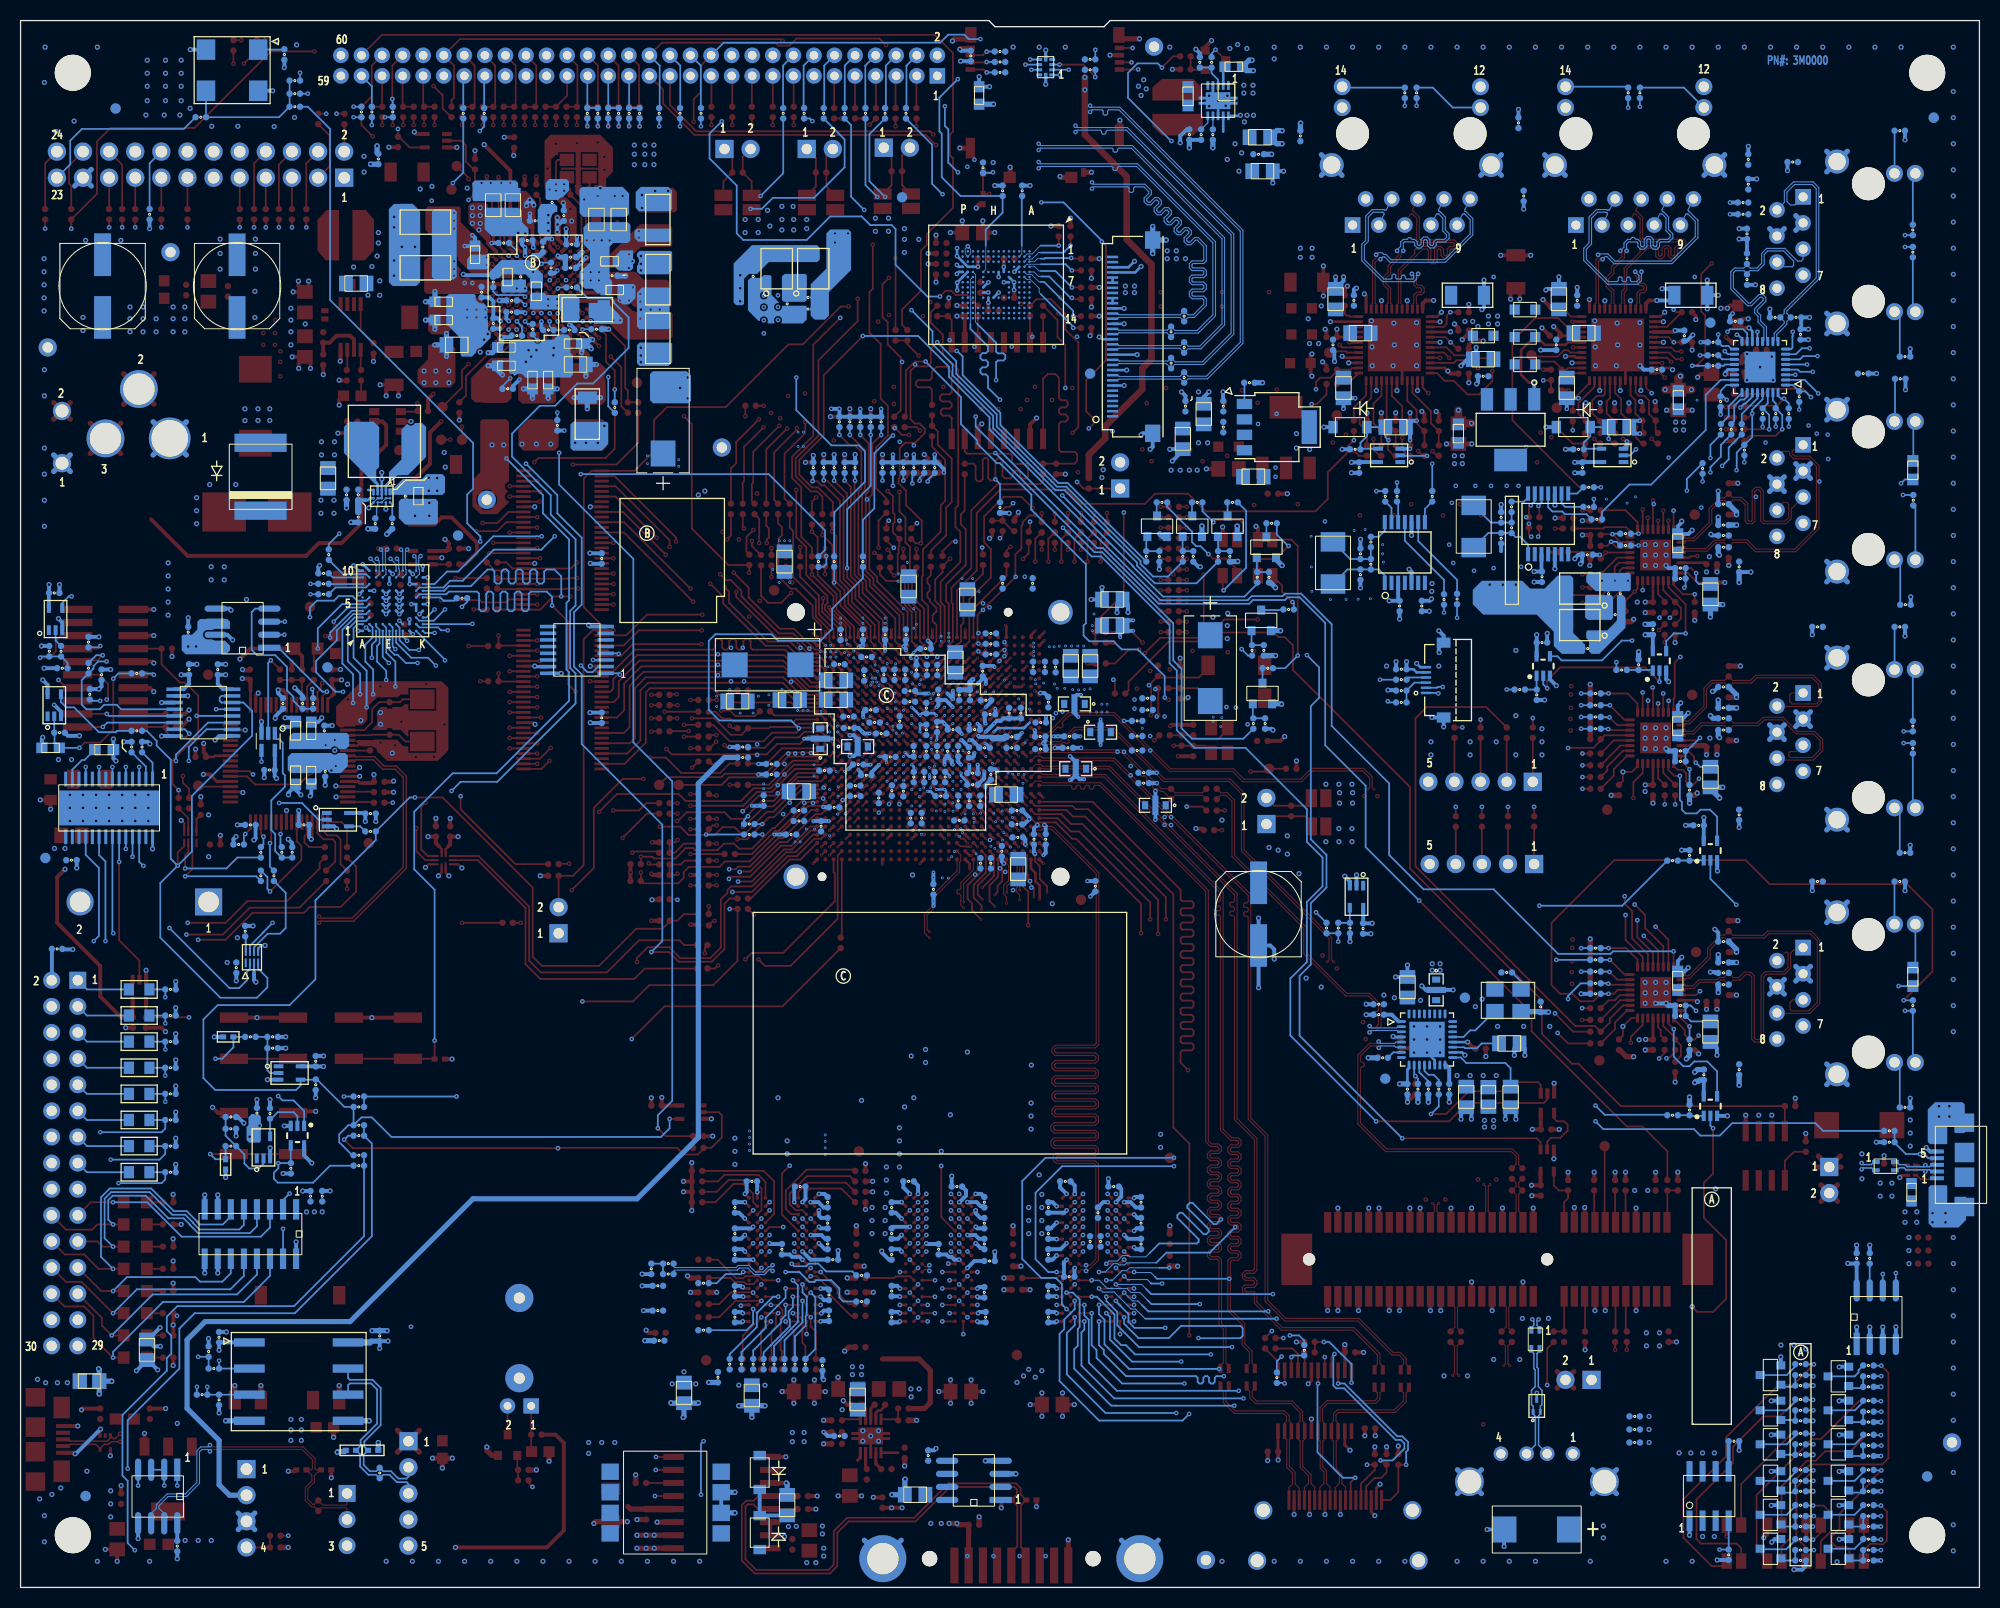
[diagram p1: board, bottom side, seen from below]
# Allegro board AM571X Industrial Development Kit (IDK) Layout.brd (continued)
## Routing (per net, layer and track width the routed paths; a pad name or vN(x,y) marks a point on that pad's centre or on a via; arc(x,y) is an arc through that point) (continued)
DDRECC_D7: length 57.8
  TOP w0.173: U6.G2 v8(114.46,33.48) ; U1.Y26 v4(97.44,72.02)
  L3_SIG1 w0.099: 97.05,70.09 97.05,71.21 97.44,71.6 v4(97.44,72.02)
  L3_SIG1 w0.109: 97.05,70.09 98.23,68.91 98.89,68.91 101.07,66.73 101.07,55.26 101.52,54.81 101.52,50.5 106.37,45.65 106.37,45.49 105.87,44.99 105.87,44.8 105.98,44.69 106.14,44.69 106.65,45.21 106.81,45.21 107.23,44.79 107.23,44.09 107.11,43.98 105.96,43.98 105.85,43.86 105.85,43.7 105.96,43.58 107.11,43.58 107.23,43.47 107.23,43.3 107.11,43.19 105.96,43.19 105.85,43.07 105.85,42.91 105.96,42.79 107.11,42.79 107.23,42.67 107.23,42.51 107.11,42.39 105.96,42.39 105.85,42.28 105.85,42.11 105.96,42 107.11,42 107.23,41.88 107.23,41.39 109.47,39.14 109.47,36.32 111.76,34.04 113.16,34.04 113.72,33.48 v8(114.46,33.48)
DDRECC_DQM: length 57.9
  TOP w0.173: v4(98.12,72.06) 98.25,72.06 98.25,72.05 98.53,72.05 98.57,72.09 99.11,72.09 U1.V26 ; U6.E7 117.68,35.05 v8(116.33,35.05)
  L3_SIG1 w0.099: v4(98.12,72.06) 98.34,71.84 98.34,70.29 98.56,70.07
  L3_SIG1 w0.109: 98.56,70.07 101.99,66.64 101.99,64.8 103.06,63.73 103.06,56.28 103.64,55.69 103.91,55.43 103.91,53.96 105.75,52.12 105.75,51.97 105.43,51.65 105.43,51.5 105.58,51.34 105.74,51.34 106.06,51.66 106.21,51.66 106.37,51.51 106.37,51.35 106.05,51.03 106.05,50.88 106.2,50.72 106.36,50.72 106.67,51.04 106.83,51.04 106.98,50.89 106.98,50.73 106.79,50.54 106.79,50.39 106.95,50.23 107.1,50.23 107.29,50.42 107.45,50.42 107.6,50.27 107.6,50.11 107.41,49.92 107.41,49.77 107.57,49.61 107.72,49.61 107.91,49.81 108.07,49.81 108.22,49.65 108.22,49.5 108.03,49.31 108.03,49.15 108.18,49 108.34,49 108.53,49.19 108.68,49.19 108.84,49.03 108.84,48.88 108.65,48.69 108.65,48.53 108.8,48.38 108.96,48.38 109.15,48.57 109.3,48.57 109.46,48.41 109.46,48.26 109.14,47.94 109.14,47.79 109.29,47.63 109.45,47.63 109.77,47.95 109.92,47.95 110.08,47.8 110.08,47.64 109.88,47.45 109.88,47.3 110.04,47.14 110.19,47.14 110.38,47.33 110.54,47.33 110.69,47.18 110.69,47.02 110.5,46.83 110.5,46.68 110.66,46.52 110.81,46.52 111,46.71 111.16,46.71 111.74,46.13 111.74,40.79 112.2,40.33 112.35,40.33 112.56,40.53 112.71,40.53 112.87,40.38 112.87,40.22 112.66,40.02 112.66,39.86 112.82,39.71 112.97,39.71 113.18,39.91 113.33,39.91 113.48,39.76 113.48,39.6 113.28,39.4 113.28,39.25 113.66,38.86 115.3,38.86 116.33,37.83 v8(116.33,35.05)
DDRECC_DQS: length 58.4
  TOP w0.108: U6.F3 v8(115.26,34.28) ; U1.V27 99.07,71.25 99.07,70.66 99.18,70.55 99.18,69.58 101.52,67.23 101.52,66.22 102.34,65.41 102.34,64.01 v4(102.12,63.79)
  L3_SIG1 w0.083: v8(115.26,34.28) 115.26,34.82 115.99,35.55 115.99,36.35 115.5,36.84 113.69,36.84 112.02,38.52 112.02,39.38 111.14,40.26 111.14,42.96 110.61,43.49 110.61,43.61 111.08,44.08 111.08,44.45 110.78,44.75 110.41,44.75 109.94,44.27 109.82,44.27 109.71,44.39 109.71,44.5 110.46,45.26 110.46,45.65 110.18,45.94 109.81,45.94 109.04,45.17 108.92,45.17 108.81,45.29 108.81,45.4 109.66,46.26 109.66,46.63 109.37,46.92 109,46.92 108.14,46.07 108.03,46.07 106.75,47.35 106.75,47.46 107.54,48.26 107.54,48.62 107.24,48.92 106.87,48.92 106.08,48.13 105.96,48.13 105.85,48.25 105.85,48.36 106.64,49.16 106.64,49.52 106.34,49.82 105.97,49.82 105.18,49.03 105.07,49.03 104.81,49.29 104.81,52.21 103.3,53.71 103.3,54.93 102.42,55.82 102.42,63.02 102.45,63.05 102.45,63.45 v4(102.12,63.79)
DDRECC_DQSN: length 58.4
  TOP w0.108: U6.G3 v8(115.26,33.48) ; U1.V28 99.43,69.68 101.78,67.34 101.78,66.32 102.59,65.51 102.59,63.65 v4(102.11,63.17)
  L3_SIG1 w0.083: v8(115.26,33.48) 114.89,33.85 114.89,34.44 114.95,34.5 114.95,34.94 115.69,35.68 115.69,36.22 115.37,36.54 113.57,36.54 111.71,38.39 111.71,39.25 110.83,40.14 110.83,42.83 110.3,43.36 110.3,43.73 110.78,44.21 110.78,44.32 110.66,44.44 110.54,44.44 110.07,43.97 109.7,43.97 109.4,44.26 109.4,44.63 110.16,45.38 110.16,45.53 110.05,45.63 109.93,45.63 109.17,44.87 108.8,44.87 108.5,45.16 108.5,45.53 109.36,46.39 109.36,46.5 109.24,46.62 109.12,46.62 108.27,45.76 107.9,45.76 106.44,47.22 106.44,47.59 107.23,48.38 107.23,48.5 107.12,48.62 107,48.62 106.21,47.83 105.84,47.83 105.54,48.12 105.54,48.49 106.33,49.28 106.33,49.4 106.22,49.52 106.1,49.52 105.31,48.72 104.94,48.72 104.5,49.16 104.5,52.08 103,53.59 103,54.81 102.11,55.69 v4(102.11,63.17)
DRAIN0: length 23.8
  TOP w0.173: D5.1 v8(181.51,37.46) 183.67,37.46 J37.19
  BOTTOM w0.173: U73.3 166.24,35.01 167.13,34.12 174.83,34.12 178.18,37.46 v8(181.51,37.46)
DRAIN1: length 28.4
  TOP w0.173: J37.20 186.08,34.8 183.54,34.8 183.03,35.31 v8(181.51,35.31) D6.1
  BOTTOM w0.173: v8(181.51,35.31) 181.98,35.77 181.98,37.66 181.53,38.1 178.32,38.1 176.12,35.9 174.63,35.9 174.06,35.33 174.06,35.29 173.24,34.47 168.18,34.47 167.51,35.13 167.51,36.77
DRAIN2: length 26.7
  TOP w0.173: J37.21 183.03,33.66 182.52,33.15 v8(181.51,33.15) D7.1
  BOTTOM w0.173: U73.5 168.78,35.26 169.22,34.82 173.1,34.82 173.71,35.43 173.71,35.47 174.49,36.25 175.74,36.25 177.94,38.45 181.68,38.45 182.33,37.8 182.33,33.96 v8(181.51,33.15)
DRAIN3: length 31
  TOP w0.173: J37.22 186.21,32.38 184.3,32.38 182.91,30.99 v8(181.51,30.99) D8.1
  BOTTOM w0.173: v8(181.51,30.99) 182.68,32.16 182.68,37.95 181.82,38.8 177.8,38.8 175.6,36.6 174.34,36.6 173.36,35.62 173.36,35.58 173.09,35.3 170.83,35.3 170.05,36.08 U73.6
DRAIN4: length 19.4
  TOP w0.173: D9.1 v8(181.51,28.83) 182.65,28.83 J37.23
  BOTTOM w0.173: U73.11 170.05,30.56 170.87,29.74 173.05,29.74 173.49,30.19 180.15,30.19 v8(181.51,28.83)
DRAIN5: length 24.7
  TOP w0.173: D10.1 v8(181.51,26.67) 184.56,29.72 186.08,29.72 J37.24
  BOTTOM w0.173: v8(181.51,26.67) 179.18,29 170.09,29 168.78,30.31 U73.12
DRAIN6: length 24.7
  TOP w0.173: D11.1 v8(181.64,24.51) 182.59,25.46 182.59,26.23 J37.25
  BOTTOM w0.173: v8(181.64,24.51) 177.65,28.5 169.45,28.5 167.51,30.43 167.51,31.97
DRAIN7: length 31.4
  TOP w0.173: J37.26 186.23,27.33 184.33,27.33 183.41,26.42 183.41,24.26 v8(181.51,22.35) D12.1
  BOTTOM w0.173: U73.14 166.24,30.31 168.78,27.77 176.65,27.77 181.51,22.91 v8(181.51,22.35)
EECS: length 8.8
  TOP w0.173: U37.63 161.14,86.69 v8(160.71,87.13)
  BOTTOM w0.173: v8(160.71,87.13) 161.15,87.13 165.41,91.39 U38.1
EEDATA: length 12.3
  TOP w0.173: U37.61 v8(162.14,87.38)
  L3_SIG1 w0.109: v8(162.14,87.38) 162.14,88.86 165.61,92.33 165.61,93.13 v8(164.8,93.93)
  BOTTOM w0.173: U38.3 v8(164.8,93.93) ; R495.1 162.05,87.29 v8(162.14,87.38)
EESK: length 10
  TOP w0.173: U37.62 161.64,87.08 161.29,87.43 161.29,87.84 v3(161.16,87.97)
  L3_SIG1 w0.109: v3(161.16,87.97) 161.16,88.98 v8(164.85,92.66)
  BOTTOM w0.173: U38.2 v8(164.85,92.66)
EMMC_RSTN: length 180.1
  TOP w0.173: v3(122.35,85.29) 121.52,85.29 120.97,84.75 119.09,84.75 R564.2
  L3_SIG1 w0.109: v3(122.35,85.29) 122.63,85.29 123.78,86.44 124.84,86.44 125.17,86.77 125.91,86.77 126.28,86.39 v5(128.14,86.39)
  L4_SIG2 w0.114: v5(128.14,86.39) 128.5,86.39 130.45,88.34 134.55,88.34 135.61,89.4 135.61,89.89 139.54,93.83 139.54,95.54 140.3,96.3 140.3,96.91 138.25,98.96 138.25,104.91 142.06,108.72 145.77,108.72 146.69,109.63 146.69,117.6 147.32,118.24 147.32,122.3 144.53,125.09 144.53,140.28 145.11,140.87 145.11,141.85 147.99,144.73 152.55,144.73 154.32,146.49 154.32,149.42 152.69,151.05 101.27,151.05 99.85,149.64 99.85,147.2 v8(99.35,146.7)
  BOTTOM w0.083: 96.63,130.51 96.63,128.2 U43.K5
  BOTTOM w0.173: v8(99.35,146.7) 101.14,144.91 101.14,141.63 100.91,141.4 100.91,137.16 99.09,135.34 R741.1 95,133.71 96.63,132.07 96.63,130.51
EMU_RSTN: length 8.6
  TOP w0.173: J18.15 186.56,92.58 187.07,92.08 187.07,91.06 187.71,90.42 v8(188.59,90.42)
  BOTTOM w0.173: R450.1 185.93,89.92 R429.2 C223.1 188.47,90.55 v8(188.59,90.42)
EMU_USB_DM: length 97.5
  TOP w0.15: U37.7 158,80.89 157.91,80.8 156.05,80.8 155.14,79.89 153.95,79.89 152.98,78.92 152.98,69.93 158.12,64.8 161.31,64.8 v3(161.46,64.65) ; J19.2 185.83,13.75 185.65,13.92 183.19,13.92 182.77,13.5 ; 182.77,13.5 182.35,13.92 181.94,13.92 181.69,14.17 v3(180.82,14.17) ; 182.77,13.5 U36.5
  L3_SIG1 w0.109: v3(161.46,64.65) 161.62,64.8 162.31,64.8 163.96,63.15 167.13,63.15 168.6,61.68 170.38,61.68 171.43,60.63 175.82,60.63 178.05,58.4 178.05,16.18 179.84,14.4 180.59,14.4 v3(180.82,14.17)
EMU_USB_DP: length 96.6
  TOP w0.15: U37.8 157.99,80.39 157.89,80.49 156.18,80.49 155.27,79.58 154.08,79.58 153.29,78.8 153.29,70.06 158.24,65.11 161.31,65.11 v3(161.46,65.26) ; J19.3 185.84,14.4 185.67,14.23 182.06,14.23 181.77,14.52 U36.3 181.48,14.48 181.28,14.48 v3(180.8,14.96)
  L3_SIG1 w0.109: v3(161.46,65.26) 161.62,65.11 162.43,65.11 164.08,63.45 167.25,63.45 168.73,61.98 170.51,61.98 171.55,60.94 175.95,60.94 178.36,58.53 178.36,16.31 179.96,14.71 180.54,14.71 v3(180.8,14.96)
ETH0_LDO_O: length 12.2
  TOP w0.254: U21.43 40.01,121.11 40.26,120.86 42.26,120.86 42.64,121.24 43.69,121.24 44.58,120.35 44.58,117.95 43.8,117.18 v9(43.29,117.18)
  BOTTOM w0.381: Q7.G v9(43.29,117.18)
ETH0_MDC: length 3.6
  TOP w0.173: R294.1 39.55,115.5 37.93,117.12 U21.36
ETH0_MDIO: length 2.3
  TOP w0.173: U21.37 39.96,118.11 R295.1
ETH0_RXCLK: length 6.1
  TOP w0.173: U21.35 37.43,116.78 38.99,115.22 38.99,114.15 R317.2 38.25,113.42 38.25,112.37 R288.1
ETH0_RXD0: length 5.6
  TOP w0.173: U21.32 35.93,115.69 36.25,115.37 36.25,114.21 R299.2 35.46,113.42 R289.1
ETH0_RXD1: length 5.7
  TOP w0.173: R290.1 34.06,113.42 R301.2 34.85,114.2 34.85,115.6 35.43,116.18 U21.31
ETH0_RXD2: length 5.6
  TOP w0.173: U21.28 33.93,115.96 33.45,115.48 33.45,114.18 R306.2 32.77,112.37 R291.1
ETH0_RXD3: length 6.3
  TOP w0.173: R292.1 31.5,112.5 R309.2 32.13,114.13 32.13,115.45 32.58,115.91 33.12,115.91 33.43,116.21 U21.27
ETH0_RXDV: length 6.3
  TOP w0.173: U21.33 36.43,116.05 36.58,115.91 37.19,115.91 37.65,115.45 37.65,114.21 R304.2 36.86,113.42 R285.1
ETH0_TXCLK: length 70.3
  TOP w0.173: v3(30.61,117.68) 31.03,118.11 U21.24 ; R281.1 v3(84.84,104.5)
  L3_SIG1 w0.109: v3(30.61,117.68) v5(29.97,117.68) ; v3(84.84,104.5) v5(84.84,105.11)
  L10_SIG4 w0.109: v5(84.84,105.11) 85.9,106.18 85.9,110.01 82.24,113.68 80.43,113.68 80.32,113.57 80.32,113.02 80.21,112.91 79.99,112.91 79.88,113.02 79.88,113.57 79.77,113.68 79.55,113.68 79.44,113.57 79.44,113.04 79.33,112.93 79.12,112.93 79.01,113.04 79.01,113.57 78.9,113.68 61.95,113.68 59.98,115.65 42.42,115.65 40.64,117.43 30.23,117.43 v5(29.97,117.68)
ETH0_TXD0: length 72.4
  TOP w0.173: v3(28.98,120.2) 29.01,120.22 29.59,120.22 29.98,120.61 U21.19 ; R282.1 v3(86.11,104.5)
  L3_SIG1 w0.109: v5(30.23,120.2) 30.15,120.27 29.05,120.27 v3(28.98,120.2) ; v3(86.11,104.5) v5(86.11,105.11)
  L10_SIG4 w0.109: v5(86.11,105.11) 86.82,105.82 86.82,110.65 82.82,114.64 62.6,114.64 60.32,116.92 52.07,116.92 51.74,116.59 44.65,116.59 43.28,117.96 41.5,117.96 41.3,118.17 33.04,118.17 33.01,118.14 32.23,118.14 30.23,120.14 v5(30.23,120.2)
ETH0_TXD1: length 82.5
  TOP w0.173: U21.20 30.19,120.11 29.54,119.46 v3(28.96,119.46) ; R287.1 v3(91.19,104.48)
  L3_SIG1 w0.109: v3(28.96,119.46) 29.4,119.46 v5(29.72,119.78) ; v3(91.19,104.48) v5(91.19,105.11)
  L10_SIG4 w0.109: v5(29.72,119.78) 29.72,120.4 29.98,120.65 30.47,120.65 30.86,120.27 35.66,120.27 36.53,121.14 38.15,121.14 38.51,120.78 41.25,120.78 42.16,119.87 45.31,119.87 45.89,119.29 51.96,119.29 52.91,118.34 62.89,118.34 64.03,117.2 65.39,117.2 66.02,117.83 66.58,117.83 66.71,117.96 66.71,118.24 66.83,118.36 67.01,118.36 67.14,118.24 67.14,117.96 67.27,117.83 67.45,117.83 67.58,117.96 67.58,118.24 67.71,118.36 67.89,118.36 68.02,118.24 68.02,117.96 68.14,117.83 68.32,117.83 68.45,117.96 68.45,118.24 68.58,118.36 68.76,118.36 68.89,118.24 68.89,117.96 69.02,117.83 69.2,117.83 69.33,117.96 69.33,118.24 69.45,118.36 69.64,118.36 69.76,118.24 69.76,117.96 69.89,117.83 82.23,117.83 82.56,117.5 84,117.5 84.5,117.01 86.42,117.01 89.71,113.72 89.71,106.59 v5(91.19,105.11)
ETH0_TXD2: length 72.4
  TOP w0.173: v3(29.97,119.21) 30.37,119.61 U21.21 ; R283.1 v3(87.38,104.5)
  L3_SIG1 w0.109: v3(29.97,119.21) 30.53,119.76 v5(31.24,119.76) ; v3(87.38,104.5) v5(87.38,105.11)
  L10_SIG4 w0.109: v5(31.24,119.76) 32,119 32.38,119 32.73,119.34 38.29,119.34 39.01,118.62 41.1,118.62 41.39,118.92 44.23,118.92 45.24,117.91 49.68,117.91 50.22,117.38 60.53,117.38 62.28,115.63 67.18,115.63 67.69,115.12 80.67,115.12 80.8,115.25 80.8,115.72 80.93,115.85 81.11,115.85 81.24,115.72 81.24,115.25 81.37,115.12 83.54,115.12 87.3,111.36 87.3,105.19 v5(87.38,105.11)
ETH0_TXD3: length 75.1
  TOP w0.173: U21.22 30.89,119.11 v3(30.86,119.08) ; R284.1 v3(88.65,104.5)
  L3_SIG1 w0.109: v3(88.65,104.5) v5(88.65,105.11) ; v3(30.86,119.08) 31.83,119.08 v5(32.26,119.51)
  L10_SIG4 w0.109: v5(32.26,119.51) 32.57,119.82 38.46,119.82 38.67,119.6 39.37,119.6 40.04,120.27 40.87,120.27 41.76,119.38 45.03,119.38 46.02,118.39 49.89,118.39 50.44,117.84 61.85,117.84 63.62,116.07 66.44,116.07 66.55,116.17 66.55,116.81 66.66,116.92 66.87,116.92 66.98,116.81 66.98,116.17 67.09,116.07 67.31,116.07 67.42,116.17 67.42,116.81 67.53,116.92 67.75,116.92 67.86,116.81 67.86,116.17 67.97,116.07 72.54,116.07 73.03,115.57 79.15,115.57 80.02,116.44 84.83,116.44 87.88,113.39 87.88,111.03 88.39,110.52 88.39,107.5 88.65,107.24 v5(88.65,105.11)
ETH0_TXEN: length 74.6
  TOP w0.173: U21.25 32.43,116.71 v8(31.88,116.16) ; R286.1 v3(89.92,104.48)
  L3_SIG1 w0.109: v3(89.92,104.48) v5(89.92,105.11)
  L10_SIG4 w0.109: v5(89.92,105.11) 89.13,104.32 84.38,104.32 82.17,106.53 82.17,108.45 78.43,112.19 77.94,112.19 77.82,112.08 77.82,110.76 77.71,110.65 77.54,110.65 77.43,110.76 77.43,112.08 77.31,112.19 77.14,112.19 77.03,112.08 77.03,110.76 76.91,110.65 76.75,110.65 76.63,110.76 76.63,112.08 76.52,112.19 72.75,112.19 72.72,112.16 70.12,112.16 69.99,112.03 69.99,111.63 69.86,111.51 69.68,111.51 69.55,111.63 69.55,112.03 69.42,112.16 67.56,112.16 67.12,111.71 66.28,111.71 65.83,112.16 61.54,112.16 60.71,112.99 54.2,112.99 53.31,113.87 50.47,113.87 49.94,114.41 40.79,114.41 40.51,114.13 38.71,114.13 37.01,115.83 32.77,115.83 32.44,116.16 v8(31.88,116.16)
ETH0GB_25MHZCLK: length 27.7
  TOP w0.173: v8(36.82,107) 38.9,107 45.42,113.52 45.42,121.24 43.18,123.47 40.97,123.47 40.1,122.61 U21.46
  BOTTOM w0.173: R315.2 v8(36.82,107)
ETH1_LDO_O: length 14.3
  TOP w0.254: U24.43 v3(61.26,121.11)
  L3_SIG1 w0.381: v3(61.26,121.11) v5(60.66,121.11)
  L9_SIG3 w0.381: v5(60.66,121.11) 60.52,120.97 60.52,119.45
  L9_SIG3 w0.635: 60.52,119.45 60.52,114.54 64.38,110.68 v9(65.14,110.68)
ETH1_MDC: length 4.4
  TOP w0.173: R338.1 60.83,114.76 59.65,115.95 U24.36
ETH1_MDIO: length 2.6
  TOP w0.173: R339.1 61.43,117.05 U24.37
ETH1_RESETN: length 26.3
  TOP w0.173: U24.42 61.98,120.61 v3(62.23,120.86)
  L3_SIG1 w0.109: v3(62.23,120.86) v5(62.81,120.86)
  L9_SIG3 w0.114: v5(62.81,120.86) 62.15,121.52 62.13,121.52 61.5,122.15 59.48,122.15 58.08,120.75 58.08,115.89 58.98,114.99 58.98,113.31 58.22,112.55 v5(58.22,111.59)
  L10_SIG4 w0.109: v7(57.47,111.59) v5(58.22,111.59)
  BOTTOM w0.173: v7(57.47,111.59) 57.77,111.88 C189.1 D4.2 59.56,111.97 60.2,111.33 R324.1 60.14,110.76 U26.4
ETH1_RXCLK: length 7.1
  TOP w0.173: R328.1 R361.2 60.28,113.19 60.28,114.56 59.15,115.69 U24.35
ETH1_RXD0: length 6.7
  TOP w0.173: R333.1 R343.2 57.65,113.35 U24.32
ETH1_RXD1: length 7
  TOP w0.173: U24.31 57.15,115.9 56.13,114.89 56.13,113.24 R345.2 R334.1
ETH1_RXD2: length 7
  TOP w0.173: U24.28 55.65,115.42 54.74,114.52 54.74,113.24 R352.2 R335.1
ETH1_RXD3: length 7.4
  TOP w0.173: U24.27 55.15,116.22 53.34,114.41 53.34,113.24 R353.2 R336.1
ETH1_RXDV: length 6.9
  TOP w0.173: R329.1 R348.2 58.93,113.24 58.93,115.14 58.15,115.93 U24.33
ETH1_TXCLK: length 100.5
  TOP w0.173: U24.24 52.75,118.11 52.01,117.37 51.12,117.37 49.78,116.03 48.67,116.03 47.37,117.33 v3(47.37,118.32) ; v3(118.26,112.82) 120.14,110.93 120.14,107.57 120.27,107.44 R325.1
  L3_SIG1 w0.109: v3(47.37,118.32) 49.43,120.38 49.43,121.87 50.6,123.04 50.6,123.09 50.9,123.4 51.43,123.4 52.2,122.64 52.71,122.64 53.75,123.68 58.45,123.68 59.08,124.31 60.05,124.31 60.83,125.1 63.81,125.1 63.82,125.1 64.2,125.1 64.21,125.1 65.15,125.1 65.26,125.21 65.26,125.55 65.37,125.66 65.59,125.66 65.7,125.55 65.7,125.21 65.81,125.1 66.03,125.1 66.14,125.21 66.14,125.55 66.25,125.66 66.46,125.66 66.57,125.55 66.57,125.21 66.68,125.1 66.9,125.1 67.01,125.21 67.01,125.55 67.12,125.66 67.34,125.66 67.45,125.55 67.45,125.21 67.56,125.1 67.77,125.1 67.88,125.21 67.88,125.55 67.99,125.66 68.21,125.66 68.32,125.55 68.32,125.21 68.43,125.1 83.12,125.1 83.15,125.13 87.23,125.13 87.7,124.65 89.74,124.65 90.18,124.21 106.86,124.21 v3(118.26,112.82)
ETH1_TXD0: length 98.3
  TOP w0.173: v3(47.5,119.84) 47.78,119.56 48.97,119.56 49.25,119.84 51.05,119.84 51.82,120.61 U24.19 ; R330.1 121.41,108.84 120.9,109.35 120.9,111.41 v3(118.69,113.62)
  L3_SIG1 w0.109: v3(47.5,119.84) 47.5,121.46 48.21,122.17 48.21,122.69 48.21,122.7 48.21,122.91 49.18,123.88 49.63,123.88 52.04,126.29 59.99,126.29 60.4,125.89 61.34,125.89 61.57,126.12 63.04,126.12 64.01,127.08 85.72,127.08 86.11,126.7 87.3,126.7 87.48,126.88 91.77,126.88 92.96,125.68 94.23,125.68 94.97,126.42 96.9,126.42 97.64,125.68 99.67,125.68 99.98,125.99 102.15,125.99 103.1,125.05 107.31,125.05 118.69,113.67 v3(118.69,113.62)
ETH1_TXD1: length 106.4
  TOP w0.173: R331.1 117.22,105.79 117.22,110.39 115.01,112.6 v3(115.01,112.76) ; U24.20 52.08,120.11 v3(51.56,119.59)
  L3_SIG1 w0.109: v3(115.01,112.76) 115.01,113.39 107.96,120.44 106.31,120.44 104.72,122.03 100.79,122.03 100.28,121.52 87.08,121.52 86.31,120.76 83.07,120.76 82.38,121.44 79.49,121.44 78.7,122.23 72.77,122.23 72.16,122.84 66.07,122.84 64.74,121.52 64.11,121.52 62.99,120.4 61.88,120.4 60.93,119.46 60.62,119.46 60.5,119.58 60.5,120.46 60.39,120.58 60.22,120.58 60.11,120.46 60.11,119.58 59.99,119.46 59.82,119.46 59.71,119.58 59.71,120.01 59.59,120.12 59.43,120.12 59.31,120.01 59.31,119.58 59.2,119.46 58.31,119.46 58.19,119.34 58.19,118.94 58.07,118.83 57.91,118.83 57.79,118.94 57.79,119.34 57.68,119.46 56.18,119.46 54.81,118.09 54.64,118.09 53.55,119.18 53.39,119.18 53.29,119.07 53.29,118.88 54.36,117.81 54.36,117.64 54.24,117.53 54.08,117.53 52.98,118.63 52.82,118.63 52.7,118.51 52.7,118.35 53.8,117.25 53.8,117.08 53.68,116.97 53.52,116.97 52.42,118.07 52.26,118.07 52.14,117.95 52.14,117.79 53.24,116.69 53.24,116.52 52.06,115.34 51.02,115.34 50.73,115.64 50.73,116.29 50.85,116.4 52.04,116.4 52.16,116.52 52.16,116.68 52.04,116.8 50.85,116.8 50.73,116.92 50.73,117.08 50.85,117.2 51.78,117.2 51.91,117.32 51.91,117.48 51.8,117.59 50.85,117.59 50.73,117.71 50.73,118.41 51.56,119.24 v3(51.56,119.59)
ETH1_TXD2: length 102.5
  TOP w0.173: v3(52.45,119.59) 52.47,119.61 U24.21 ; R327.1 117.98,110.69 v3(115.95,112.72)
  L3_SIG1 w0.109: v3(115.95,112.72) 115.95,113.09 107.93,121.11 106.41,121.11 105.03,122.48 100.58,122.48 100.08,121.98 97.59,121.98 97.14,122.42 96.03,122.42 95.91,122.54 95.91,122.81 95.8,122.92 95.63,122.92 95.52,122.81 95.52,122.54 95.38,122.41 95.23,122.41 95.12,122.51 95.12,122.81 95,122.92 94.84,122.92 94.72,122.81 94.72,122.54 94.59,122.41 94.44,122.41 94.33,122.51 94.33,122.81 94.21,122.92 94.05,122.92 93.93,122.81 93.93,122.54 93.8,122.41 93.64,122.41 93.53,122.51 93.53,122.81 93.42,122.92 93.25,122.92 93.14,122.81 93.14,122.54 93.01,122.41 92.85,122.41 92.74,122.51 92.74,122.81 92.63,122.92 92.46,122.92 92.35,122.81 92.35,122.54 92.21,122.41 92.06,122.41 91.95,122.51 91.95,122.81 91.83,122.92 91.67,122.92 91.55,122.81 91.55,122.54 91.42,122.41 91.27,122.41 91.16,122.51 91.16,122.81 91.04,122.92 90.88,122.92 90.76,122.81 90.76,122.54 90.63,122.41 90.47,122.41 90.36,122.51 90.36,122.81 90.25,122.92 90.08,122.92 89.97,122.81 89.97,122.54 89.84,122.41 89.68,122.41 89.57,122.51 89.57,122.81 89.46,122.92 89.29,122.92 89.18,122.81 89.18,122.54 89.04,122.41 88.89,122.41 88.78,122.51 88.78,122.86 88.66,122.97 87.77,122.97 87.48,122.69 84.91,122.69 84.17,123.43 82.58,123.43 82.47,123.32 82.47,122.87 82.36,122.76 82.14,122.76 82.03,122.87 82.03,123.32 81.92,123.43 81.7,123.43 81.59,123.32 81.59,122.87 81.48,122.76 81.27,122.76 81.16,122.87 81.16,123.32 81.05,123.43 80.83,123.43 80.72,123.32 80.72,122.87 80.61,122.76 80.39,122.76 80.28,122.87 80.28,123.32 80.17,123.43 79.96,123.43 79.85,123.32 79.85,122.87 79.74,122.76 79.52,122.76 79.41,122.87 79.41,123.32 79.3,123.43 79.08,123.43 78.97,123.32 78.97,122.87 78.86,122.76 78.64,122.76 78.54,122.87 78.54,123.32 78.43,123.43 78.21,123.43 78.1,123.32 78.1,122.87 77.99,122.76 77.77,122.76 77.66,122.87 77.66,123.32 77.55,123.43 77.33,123.43 77.22,123.32 77.22,122.87 77.12,122.76 76.9,122.76 76.79,122.87 76.79,123.32 76.68,123.43 76.46,123.43 76.35,123.32 76.35,122.87 76.24,122.76 76.02,122.76 75.91,122.87 75.91,123.32 75.81,123.43 75.59,123.43 75.48,123.32 75.48,122.87 75.37,122.76 75.15,122.76 75.04,122.87 75.04,123.32 74.93,123.43 74.71,123.43 74.6,123.32 74.6,122.87 74.49,122.76 74.28,122.76 74.17,122.87 74.17,123.32 74.06,123.43 73.84,123.43 73.73,123.32 73.73,122.87 73.62,122.76 73.4,122.76 73.29,122.87 73.29,123.32 73.18,123.43 66.02,123.43 65.4,122.81 64.74,122.81 63.8,121.87 63.59,121.87 63.47,121.76 63.47,121.58 63.34,121.45 63.18,121.45 63.07,121.56 63.07,121.7 62.96,121.82 62.79,121.82 62.68,121.7 62.68,121.53 62.56,121.42 62.4,121.42 62.28,121.53 62.28,121.7 62.17,121.82 59.81,121.82 59.7,121.71 59.7,121.08 59.59,120.97 59.43,120.97 59.26,121.14 58.9,121.14 58.57,120.8 58.4,120.8 58.2,121 58.05,121 57.94,120.89 57.94,120.7 58.12,120.52 58.12,120.36 57.96,120.2 55.97,120.2 55.86,120.31 55.86,120.87 55.74,120.99 55.58,120.99 55.46,120.87 55.46,120.31 55.35,120.2 54.89,120.2 54.28,119.59 53.85,119.59 53.73,119.7 53.73,119.85 53.61,119.97 53.45,119.97 53.33,119.85 53.33,119.7 53.22,119.59 v3(52.45,119.59)
ETH1_TXD3: length 100.1
  TOP w0.173: U24.22 52.13,119.11 52.13,119.11 51.1,119.11 50.85,119.36 49.56,119.36 v3(48.77,118.57) ; R332.1 119.38,105.66 119.38,107.31 119.25,107.44 119.25,110.44 v3(116.71,112.98)
  L3_SIG1 w0.109: v3(116.71,112.98) 116.33,113.37 116.31,113.37 107.94,121.73 106.51,121.73 106.31,121.94 106.31,122.12 106.51,122.32 106.51,122.5 106.38,122.63 106.2,122.63 106,122.43 105.82,122.43 105.31,122.94 100.33,122.94 99.85,122.46 97.74,122.46 96.82,123.38 89.15,123.38 88.42,124.11 87.78,124.11 86.84,123.17 85.22,123.17 84.47,123.92 82.88,123.92 82.68,124.12 65.15,124.12 64.88,123.86 64.35,123.86 64.24,123.74 64.24,123.03 64.12,122.92 63.96,122.92 63.84,123.03 63.84,123.74 63.73,123.86 62.38,123.86 62.26,123.74 62.26,122.98 62.14,122.86 61.98,122.86 61.86,122.98 61.86,123.74 61.75,123.86 61.58,123.86 61.47,123.74 61.47,123.21 61.35,123.09 61.19,123.09 61.07,123.21 61.07,123.74 60.96,123.86 60.58,123.86 58.94,122.22 58.43,122.22 58.12,121.9 57.65,121.9 57.53,122.02 57.53,122.39 57.42,122.51 57.25,122.51 57.14,122.39 57.14,122.02 57.02,121.9 56.86,121.9 56.74,122.02 56.74,122.39 56.62,122.51 56.46,122.51 56.34,122.39 56.34,122.02 56.23,121.9 56.06,121.9 55.95,122.02 55.95,122.39 55.83,122.51 55.67,122.51 55.55,122.39 55.55,122.02 55.44,121.9 55.27,121.9 55.16,122.02 55.16,122.39 55.04,122.51 54.88,122.51 54.76,122.39 54.76,122.02 54.64,121.9 54.48,121.9 54.36,122.02 54.36,122.39 54.25,122.51 54.08,122.51 53.97,122.39 53.97,121.86 52.61,120.5 50.7,120.5 v3(48.77,118.57)
ETH1_TXEN: length 107.3
  TOP w0.173: R326.1 116.2,105.92 116.2,110.26 114.2,112.27 v3(114.2,113.37) ; U24.25 54.15,116.71 v3(53.59,116.16)
  L3_SIG1 w0.109: v3(53.59,116.16) 54.93,117.5 55.09,117.5 55.34,117.25 55.5,117.25 55.62,117.37 55.62,117.53 55.38,117.78 55.38,117.94 55.75,118.32 56.1,118.32 56.22,118.2 56.22,117.35 56.33,117.23 56.5,117.23 56.61,117.35 56.61,118.2 56.73,118.32 56.89,118.32 57.01,118.2 57.01,116.87 57.12,116.75 57.29,116.75 57.4,116.87 57.4,118.2 57.52,118.32 57.68,118.32 57.8,118.2 57.8,117.4 57.92,117.29 58.08,117.29 58.2,117.4 58.2,118.2 58.31,118.32 59.57,118.32 59.68,118.43 59.68,118.81 59.8,118.92 59.97,118.92 60.08,118.81 60.08,118.43 60.2,118.32 60.36,118.32 60.48,118.43 60.48,118.81 60.59,118.92 60.76,118.92 60.87,118.81 60.87,118.43 60.99,118.32 62.69,118.32 63.32,118.95 63.32,119.79 64.01,120.48 65.37,120.48 65.97,121.07 65.97,121.24 65.67,121.54 65.67,121.7 65.79,121.82 65.95,121.82 66.25,121.52 66.41,121.52 66.53,121.64 66.53,121.8 66.23,122.1 66.23,122.26 66.35,122.38 66.51,122.38 66.81,122.08 66.98,122.08 67.26,122.37 67.55,122.37 67.67,122.25 67.67,121.9 67.79,121.78 67.95,121.78 68.07,121.9 68.07,122.25 68.18,122.37 68.35,122.37 68.46,122.25 68.46,121.9 68.58,121.78 68.74,121.78 68.86,121.9 68.86,122.25 68.97,122.37 69.14,122.37 69.25,122.25 69.25,121.9 69.37,121.78 69.53,121.78 69.65,121.9 69.65,122.25 69.77,122.37 69.93,122.37 70.05,122.25 70.05,121.9 70.16,121.78 70.33,121.78 70.44,121.9 70.44,122.25 70.56,122.37 70.72,122.37 70.84,122.25 70.84,121.9 70.96,121.78 71.12,121.78 71.24,121.9 71.24,122.25 71.35,122.37 71.52,122.37 71.63,122.25 71.63,121.9 71.75,121.78 78.53,121.78 79.32,120.99 82.22,120.99 82.91,120.3 89.93,120.3 90.05,120.43 90.05,120.88 90.18,121.01 90.36,121.01 90.49,120.88 90.49,120.43 90.62,120.3 90.8,120.3 90.93,120.43 90.93,120.88 91.05,121.01 91.24,121.01 91.36,120.88 91.36,120.43 91.49,120.3 91.67,120.3 91.8,120.43 91.8,120.88 91.93,121.01 92.11,121.01 92.24,120.88 92.24,120.43 92.37,120.3 92.55,120.3 92.67,120.43 92.67,120.88 92.8,121.01 92.98,121.01 93.11,120.88 93.11,120.43 93.24,120.3 93.42,120.3 93.55,120.43 93.55,120.88 93.68,121.01 93.86,121.01 93.99,120.88 93.99,120.43 94.11,120.3 94.29,120.3 94.42,120.43 94.42,120.88 94.55,121.01 94.73,121.01 94.86,120.88 94.86,120.43 94.99,120.3 95.17,120.3 95.3,120.43 95.3,120.88 95.42,121.01 95.6,121.01 95.73,120.88 95.73,120.43 95.86,120.3 96.04,120.3 96.17,120.43 96.17,120.88 96.3,121.01 96.48,121.01 96.61,120.88 96.61,120.43 96.73,120.3 96.92,120.3 97.04,120.43 97.04,120.88 97.17,121.01 97.35,121.01 97.48,120.88 97.48,120.43 97.61,120.3 97.79,120.3 97.92,120.43 97.92,120.88 98.05,121.01 98.23,121.01 98.35,120.88 98.35,120.43 98.48,120.3 98.66,120.3 98.79,120.43 98.79,120.88 98.92,121.01 99.1,121.01 99.23,120.88 99.23,120.43 99.36,120.3 99.72,120.3 100.99,121.57 104.39,121.57 106.13,119.83 107.91,119.83 114.2,113.54 v3(114.2,113.37)
ETH1GB_25MHZCLK: length 28.9
  TOP w0.173: U24.46 v3(61.44,122.61)
  L3_SIG1 w0.109: v5(50.16,111.08) 50,111.24 50,115.29 50.24,115.52 50.24,118.22 49.86,118.6 49.86,119.02 50.88,120.05 52.78,120.05 54.18,121.44 58.34,121.44 58.63,121.73 59.09,121.73 59.97,122.61 v3(61.44,122.61)
  L10_SIG4 w0.109: v7(53.21,109.3) 51.92,110.59 50.65,110.59 v5(50.16,111.08)
  BOTTOM w0.173: v7(53.21,109.3) R359.2
ETH_MDIO_CLK: length 187.6
  TOP w0.173: R338.2 v8(60.83,111.59) 61.38,111.04 61.38,110.45 63.37,108.46 63.37,105.87 64.58,104.67 75.25,104.67 76.96,106.38 80.17,106.38 81.15,105.39 87.39,105.39 88.79,106.79 95.22,106.79 97.51,104.5 97.51,98.91 99.43,96.99 U1.V1 ; R294.2 v8(39.55,112.55)
  L9_SIG3 w0.114: v8(60.83,111.59) 62.17,111.59 64.08,109.68 66.42,109.68 67.49,110.74 67.49,122.89 64.14,126.24 62.71,126.24 61.01,124.54 54.76,124.54 53.24,126.06 53.24,128.88 55.32,130.96 56.31,130.96 57.1,131.75 57.1,133.1 58.42,134.42 58.42,136.27 v5(57.28,137.41)
  L10_SIG4 w0.109: v5(57.28,137.41) 61.03,137.41 61.7,136.75 67.71,136.75 68.08,137.12 81.98,137.12 84.3,134.8 90.2,134.8 90.96,135.56 92.13,135.56 92.68,135 95.89,135 96.39,135.51 v7(100.84,135.51) ; v8(60.83,111.59) 59.87,112.55 53.82,112.55 53.06,113.31 50.24,113.31 49.68,113.87 41.91,113.87 40.59,112.55 v8(39.55,112.55)
  BOTTOM w0.173: R877.1 101.85,140.34 101.85,136.53 v7(100.84,135.51)
ETH_MDIO_DATA: length 176.3
  TOP w0.173: U1.U4 v4(99.84,90.41) ; v8(42.42,117.4) 41.68,117.4 R295.2 R279.1 ; v8(64.95,115.09) 64.44,115.09 63.5,116.03 R339.2 ; v8(86.61,112.73) 86.11,113.24 86.11,113.62 86.87,114.38 86.87,117.43 84.94,119.36 84.94,130.48 v8(85.34,130.89)
  L3_SIG1 w0.099: v5(99.57,91.72) 99.54,91.7 99.54,90.71 v4(99.84,90.41)
  L3_SIG1 w0.109: v8(85.34,130.89) 84.38,131.86 80.19,131.86 79.43,132.62 64.19,132.62 58.7,127.13 53.6,127.13 52.91,127.82 47.6,127.82 v8(47.24,127.46)
  L4_SIG2 w0.114: v5(99.57,91.72) 99.16,92.13 99.16,98.55 98.51,99.2 98.51,101.69 95.21,104.99 93.82,104.99 93.37,105.44 93.01,105.44 92.05,106.4 87.98,106.4 87.3,107.08 87.3,110.37 86.61,111.05 v8(86.61,112.73)
  L9_SIG3 w0.114: v8(47.24,127.46) 46.16,126.38 46.16,125.07 42.11,121.01 42.11,120.12 42.42,119.8 v8(42.42,117.4) 42.44,117.43 42.55,117.43 44.7,119.59 52.45,119.59 56.69,123.83 63.96,123.83 66.34,121.44 66.34,116.46 64.97,115.09 v8(64.95,115.09)
  L10_SIG4 w0.109: v7(106.43,135.26) 101.2,135.26 101.02,135.07 96.36,135.07 96,134.71 v7(91.24,134.71)
  BOTTOM w0.173: v7(106.43,135.26) 107.95,136.78 107.95,141.35 R878.1 ; v7(91.24,134.71) 89.07,134.71 85.34,130.99 v8(85.34,130.89)
ETHER0_D0N: length 20.2
  TOP w0.108: U21.3 36.93,124.78 37.04,124.9 37.04,129.03 36.88,129.19 v8(36.65,129.19)
  BOTTOM w0.108: J10.10 28.34,133.99 28.3,133.85 28.29,133.84 28.2,133.8 27.38,132.98 27.38,131.27 29.89,128.76 35.55,128.76 36.24,129.45 36.39,129.45 v8(36.65,129.19)
ETHER0_D0P: length 20.1
  TOP w0.108: v8(37.08,129.62) 37.08,129.35 37.3,129.13 37.3,124.91 37.43,124.78 U21.2
  BOTTOM w0.108: v8(37.08,129.62) 37,129.71 36.14,129.71 35.44,129.01 30,129.01 27.63,131.38 27.63,132.87 28.35,133.59 28.41,133.62 28.55,133.57 29.08,132.51
ETHER0_D1N: length 19
  TOP w0.108: v8(34.32,130) 34.52,129.8 34.52,129.34 35.54,128.31 35.54,127.78 36.07,127.26 36.07,126.65 35.54,126.13 35.54,124.91 35.43,124.79 U21.6
  BOTTOM w0.108: J10.8 30.88,133.99 30.84,133.85 30.83,133.84 30.74,133.8 30.7,133.78 30.23,133.3 30.23,132.06 29.82,131.65 29.82,131.25 30.2,130.87 31,130.87 31.11,130.76 31.11,130.41 31.36,130.15 31.72,130.15 31.98,130.41 31.98,131.04 32.08,131.15 32.23,131.15 32.34,131.04 32.34,130.41 32.59,130.15 32.96,130.15 33.21,130.41 33.21,130.76 33.32,130.87 34.11,130.87 34.32,130.66 v8(34.32,130)
ETHER0_D1P: length 19
  TOP w0.108: v8(34.92,130) 34.77,129.85 34.77,129.44 35.8,128.42 35.8,127.88 36.32,127.36 36.32,126.55 35.8,126.02 35.8,124.91 35.93,124.78 U21.5
  BOTTOM w0.108: v8(34.92,130) 34.92,130.01 34.57,130.36 34.57,130.77 34.22,131.12 33.96,131.12 33.77,131.31 33.6,131.31 33.41,131.12 33.21,131.12 32.96,130.87 32.96,130.51 32.85,130.41 32.7,130.41 32.59,130.51 32.59,131.14 32.34,131.4 31.98,131.4 31.72,131.14 31.72,130.51 31.62,130.41 31.47,130.41 31.36,130.51 31.36,130.87 31.11,131.12 30.31,131.12 30.07,131.35 30.07,131.55 30.48,131.95 30.48,133.2 30.85,133.57 30.86,133.57 30.95,133.62 31.09,133.57 31.62,132.51
ETHER0_D2N: length 22.9
  TOP w0.108: J10.6 33.42,133.99 33.38,133.85 33.37,133.84 33.28,133.8 32.75,133.27 32.75,131.24 32.64,131.13 28.8,131.13 28.55,130.88 28.55,130.51 28.8,130.26 29.28,130.26 29.38,130.15 29.38,129.51 29.63,129.26 29.99,129.26 30.25,129.52 30.25,130.15 30.36,130.26 30.51,130.26 30.61,130.15 30.61,129.49 30.87,129.24 31.23,129.24 31.48,129.49 31.48,130.15 31.59,130.26 32.25,130.26 34.29,128.22 34.29,126.19 34.54,125.94 34.54,124.9 34.43,124.78 U21.8
ETHER0_D2P: length 22.8
  TOP w0.108: U21.7 34.93,124.79 34.8,124.92 34.8,126.04 34.54,126.3 34.54,128.33 33,129.87 33,130.02 33.04,130.06 33.04,130.21 32.93,130.31 32.78,130.31 32.75,130.28 32.6,130.28 32.36,130.51 31.48,130.51 31.23,130.26 31.23,129.6 31.12,129.49 30.97,129.49 30.87,129.6 30.87,130.26 30.61,130.51 30.25,130.51 30,130.26 30,129.63 29.88,129.52 29.73,129.52 29.64,129.61 29.64,130.26 29.38,130.51 28.91,130.51 28.8,130.62 28.8,130.77 28.91,130.88 32.75,130.88 33,131.13 33,133.16 33.43,133.59 33.49,133.62 33.63,133.57 J10.5
ETHER0_D3N: length 20.2
  TOP w0.108: U21.11 32.93,124.78 33.04,124.9 33.04,125.79 32.92,125.92 32.64,125.92 32.37,126.19 32.37,126.58 32.64,126.86 32.92,126.86 33.04,126.99 33.04,127.42 32.87,127.6 v8(32.87,127.97)
  BOTTOM w0.108: v8(32.87,127.97) 32.87,127.11 33.22,126.75 36.17,126.75 38.48,129.06 38.48,130.26 37.97,130.76 37.97,133.28 37.24,134.02 36.26,134.02 36.11,133.94 35.96,133.99 J10.4
ETHER0_D3P: length 20.3
  TOP w0.108: U21.10 33.43,124.77 33.3,124.9 33.3,125.9 33.02,126.17 32.75,126.17 32.62,126.3 32.62,126.48 32.75,126.61 33.02,126.61 33.3,126.88 33.3,127.42 33.48,127.6 v8(33.48,127.97)
  BOTTOM w0.108: v8(33.48,127.97) 33.12,127.61 33.12,127.21 33.33,127.01 33.85,127.01 33.95,127.11 33.95,127.34 34.06,127.45 34.21,127.45 34.31,127.34 34.31,127.11 34.42,127.01 34.65,127.01 34.76,127.11 34.76,127.36 34.87,127.47 35.02,127.47 35.12,127.36 35.12,127.11 35.23,127.01 36.06,127.01 38.23,129.17 38.23,130.15 37.72,130.66 37.72,133.18 37.13,133.76 36.32,133.76 36.22,133.72 36.22,133.71 36.17,133.57 36.7,132.51
ETHER1_D0N: length 19.6
  TOP w0.108: v8(58.24,129.19) 58.47,129.19 58.76,128.9 58.76,124.91 58.65,124.79 U24.3
  BOTTOM w0.108: v8(58.24,129.19) 58.03,129.41 57.84,129.41 57.32,128.89 51.93,128.89 49.27,131.55 49.27,133.15 49.92,133.8 50.01,133.84 50.01,133.85 50.06,133.99 J12.10
ETHER1_D0P: length 19.6
  TOP w0.108: U24.2 59.15,124.78 59.01,124.91 59.01,129 58.67,129.35 v8(58.67,129.62)
  BOTTOM w0.108: v8(58.67,129.62) 58.48,129.82 58.09,129.82 57.94,129.66 57.73,129.66 57.22,129.15 52.04,129.15 49.53,131.66 49.53,133.05 50.07,133.59 50.12,133.62 50.27,133.57 J12.9
ETHER1_D1N: length 18.4
  TOP w0.108: U24.6 57.15,124.79 57.26,124.91 57.26,126.36 57.71,126.8 57.71,127.37 57.26,127.82 57.26,128.44 56.24,129.46 56.24,129.8 v8(56.03,130)
  BOTTOM w0.108: v8(56.03,130) 56.03,130.76 55.92,130.87 55.03,130.87 54.93,130.76 54.93,130.54 54.67,130.28 54.31,130.28 54.06,130.54 54.06,130.99 53.95,131.09 53.8,131.09 53.7,130.99 53.7,130.54 53.44,130.28 53.08,130.28 52.83,130.54 52.83,130.76 52.72,130.87 51.92,130.87 51.57,131.21 51.57,131.67 51.94,132.03 51.94,133.3 52.42,133.78 52.46,133.8 52.55,133.84 52.55,133.85 52.6,133.99 J12.8
ETHER1_D1P: length 18.3
  TOP w0.108: U24.5 57.65,124.78 57.51,124.91 57.51,126.25 57.96,126.7 57.96,127.47 57.51,127.92 57.51,128.54 56.49,129.57 56.49,129.85 v8(56.64,130)
  BOTTOM w0.108: J12.7 52.81,133.57 52.66,133.62 52.57,133.57 52.57,133.57 52.2,133.2 52.2,131.93 51.83,131.56 51.83,131.31 52.02,131.12 52.82,131.12 53.08,130.87 53.08,130.64 53.19,130.54 53.34,130.54 53.44,130.64 53.44,131.09 53.7,131.35 54.06,131.35 54.31,131.09 54.31,130.64 54.42,130.54 54.57,130.54 54.67,130.64 54.67,130.87 54.93,131.12 55.16,131.12 55.31,131.27 55.52,131.27 55.67,131.12 56.03,131.12 56.29,130.86 56.29,130.44 56.64,130.09 v8(56.64,130)
ETHER1_D2N: length 22.5
  TOP w0.108: U24.8 56.15,124.78 56.26,124.9 56.26,128.03 54.11,130.18 53.71,130.18 53.6,130.08 53.6,129.02 53.34,128.75 52.97,128.75 52.73,129 52.73,130.08 52.63,130.18 52.48,130.18 52.37,130.08 52.37,129.55 52.12,129.3 51.76,129.3 51.5,129.55 51.5,130.08 51.4,130.18 51.05,130.18 50.8,130.44 50.8,130.8 51.05,131.05 54.36,131.05 54.47,131.16 54.47,133.29 54.96,133.78 55,133.8 55.09,133.84 55.09,133.85 55.14,133.99 J12.6
ETHER1_D2P: length 22.5
  TOP w0.108: U24.7 56.65,124.77 56.51,124.9 56.51,128.14 54.91,129.74 54.91,129.89 54.95,129.93 54.95,130.08 54.84,130.19 54.69,130.19 54.65,130.15 54.5,130.15 54.22,130.44 53.6,130.44 53.35,130.18 53.35,129.13 53.23,129.01 53.08,129.01 52.99,129.1 52.99,130.18 52.73,130.44 52.37,130.44 52.12,130.18 52.12,129.66 52.01,129.55 51.86,129.55 51.76,129.66 51.76,130.18 51.5,130.44 51.16,130.44 51.05,130.54 51.05,130.69 51.16,130.8 54.47,130.8 54.72,131.05 54.72,133.18 55.11,133.57 55.11,133.57 55.2,133.62 55.35,133.57 J12.5
ETHER1_D3N: length 19.5
  TOP w0.108: v8(54.58,127.77) 54.58,127.45 54.76,127.27 54.76,126.79 54.63,126.66 54.27,126.66 53.99,126.39 53.99,126 54.27,125.72 54.63,125.72 54.76,125.6 54.76,124.92 54.65,124.81 U24.11
  BOTTOM w0.108: v8(54.58,127.77) 54.76,127.59 54.76,127.23 54.98,127.01 58.03,127.01 60.07,129.05 60.07,130.64 59.69,131.02 59.69,133.38 59.05,134.02 57.93,134.02 57.89,133.97 57.83,133.94 57.68,133.99 J12.4
ETHER1_D3P: length 19.2
  TOP w0.108: v8(55.19,127.77) 55.19,127.45 55.01,127.27 55.01,126.68 54.74,126.41 54.38,126.41 54.25,126.28 54.25,126.1 54.38,125.98 54.74,125.98 55.01,125.7 55.01,124.92 55.15,124.79 U24.10
  BOTTOM w0.108: J12.3 57.89,133.57 57.94,133.71 58.04,133.76 58.95,133.76 59.44,133.27 59.44,130.91 59.82,130.53 59.82,129.15 57.93,127.26 57.23,127.26 57.12,127.37 57.12,127.62 57.02,127.72 56.87,127.72 56.76,127.62 56.76,127.37 56.66,127.26 56.31,127.26 56.2,127.37 56.2,127.53 56.1,127.63 55.95,127.63 55.84,127.53 55.84,127.37 55.73,127.26 55.09,127.26 55.01,127.34 55.01,127.59 v8(55.19,127.77)
F_ADBUS0: length 2.6
  TOP w0.173: U37.16 156.19,76.39 R474.2
F_ADBUS1: length 4
  TOP w0.173: R475.2 158.75,73.91 159.28,74.44 U37.17
F_ADBUS2: length 6.2
  TOP w0.173: U37.18 161.14,73.64 160.66,73.15 159.77,73.15 159.39,72.77 159.39,70.36 R480.2
F_ADBUS3: length 6.3
  TOP w0.173: R481.2 159.89,70.61 159.89,72.52 160.15,72.77 161.04,72.77 161.64,73.37 U37.19
F_ADBUS4: length 4.3
  TOP w0.173: U37.21 162.64,73.3 162.89,73.04 162.89,72.47 162.43,72.01 R476.2
F_ADBUS5: length 2.5
  TOP w0.173: v8(165.23,73.28) 165.14,73.37 U37.26
  BOTTOM w0.173: R478.2 165.23,72.14 v8(165.23,73.28)
F_ADBUS6: length 10.6
  TOP w0.173: U37.23 163.64,72.58 163.2,72.14 163.2,70.74 v8(166.24,67.69)
  BOTTOM w0.173: v8(166.24,67.69) 166.5,67.95 166.5,69.09 R477.2
F_ADBUS7: length 2.6
  TOP w0.173: U37.30 167.14,73.29 v8(166.88,73.02)
  BOTTOM w0.173: v8(166.88,73.02) 166.88,72.26 R483.2
FT_SRESET: length 14.6
  BOTTOM w0.173: U34.1 165.77,82.67 165.62,82.52 165.36,82.52 165,82.16 165,79.2 164.8,78.99 164.8,77.87 166.12,76.55 166.12,73.66 165.74,73.28 165.74,71.63 165.1,70.99 164.08,70.99
FT_SRESETB: length 1.8
  BOTTOM w0.173: R473.2 157.47,74.03 U99.4
FT_SRESETN: length 11.1
  L10_SIG4 w0.109: v7(167.07,80.31) 166.27,79.51 166.27,77.21 v7(165.35,76.3)
  BOTTOM w0.173: U99.2 161.52,74.68 163.14,76.3 v7(165.35,76.3) ; v7(167.07,80.31) U34.4
FT_VBUS: length 8.5
  TOP w0.173: v8(166.17,90.17) R492.1
  BOTTOM w0.173: v8(166.17,90.17) 166.42,89.92 U34.2
FTDI_REF: length 2.2
  TOP w0.173: U37.6 156.53,81.39 R479.1
FTDI_VPHY: length 2.4
  TOP w0.305: U37.4 159.91,82.39 v8(159.94,82.43) 160.32,82.43 v8(160.83,81.92)
FTDI_VPLL: length 1.8
  TOP w0.254: v8(159.84,79.89) U37.9
  TOP w0.381: v8(159.84,79.89) 160.25,79.49 160.25,79.48 v9(160.27,79.46)
GB_ETH0_INTN: length 355.2
  TOP w0.173: R662.1 121.54,80.14 122.45,79.22 126.26,79.22 127.75,80.71 v3(129.25,80.71) ; v3(43.56,118.45) 42.78,119.23 41.33,119.23 40.64,118.54 R297.1 40.17,118.45 40,118.61 U21.38
  L3_SIG1 w0.109: v3(129.25,80.71) 129.12,80.85 v5(128.52,80.85) ; v3(43.56,118.45) v5(44.07,117.94)
  L4_SIG2 w0.114: v5(128.52,80.85) 127.72,80.85 126,79.14 120.35,79.14 119.96,78.75 119.96,77.36 119.25,76.65 119.25,73.8 119.5,73.54 126.02,73.54 127.81,75.33 131.38,75.33 132.06,76.01 135.67,76.01 140.14,71.53 140.14,70.17 146.02,64.29 146.02,27.1 143.87,24.94 139.7,24.94 128.48,13.72 116.47,13.72 116.11,13.37 113.53,13.37 113.03,12.87 106.38,12.87 105.26,13.99 102.59,13.99 101.98,14.6 73.48,14.6 73.22,14.86 63.26,14.86 61.63,16.49 58.02,16.49 55.68,14.15 37.52,14.15 32.89,9.53 29.72,9.53 27.44,11.81 27.44,22.04 27.88,22.48 27.88,23.4 35.51,31.03 35.51,39.74 35.95,40.17 35.95,50.17 38.3,52.53 38.3,55.32 39.37,56.39 39.37,76.58 40.96,78.17 40.96,84.6 v5(40.51,85.04)
  L9_SIG3 w0.114: v5(44.07,117.94) 44.07,117.15 43.53,116.61 41.98,116.61 37.21,111.84 33.66,111.84 32.64,110.83 32.64,109.56 37.53,104.66 37.53,103.92 38.23,103.23 38.97,103.23 39.91,102.28 39.91,88.31 40.51,87.71 v5(40.51,85.04)
GB_ETH1_INTN: length 80.7
  TOP w0.173: v3(106.05,127.38) 106.68,126.75 106.68,123.57 106.17,123.06 106.17,120.9 104.9,119.63 104.9,114.51 R663.1 ; U24.38 61,118.61 61.16,118.45 R342.1 62.48,118.29 63.12,117.66 64.13,117.66 64.52,117.27 v8(64.52,116.54)
  L3_SIG1 w0.109: v3(106.05,127.38) 102.85,127.38 99.16,131.07 87,131.07 86.14,130.21 80.99,130.21 79.55,131.65 v5(64.62,131.65)
  L4_SIG2 w0.114: v8(64.52,116.54) 64.59,116.54 65.84,117.8 65.84,127.53 64.31,129.06 64.31,131.34 v5(64.62,131.65)
GBETH0_RESETN: length 19.2
  TOP w0.173: U21.42 v3(39.49,120.61)
  L3_SIG1 w0.109: v3(39.49,120.61) 39.49,120.6 v5(38.99,120.1)
  L9_SIG3 w0.114: v5(36.07,112.35) 36.07,118.7 37.46,120.1 v5(38.99,120.1)
  L10_SIG4 w0.109: v7(36.07,111.71) v5(36.07,112.35)
  BOTTOM w0.173: U22.4 38.42,110.76 R280.1 38.48,111.33 37.85,111.97 D3.2 C168.1 36.05,111.73 v7(36.07,111.71)
GPIO_AM572X_USB2_ID: length 301.9
  TOP w0.173: U1.F13 v4(109.43,83.21)
  L3_SIG1 w0.109: v5(109.83,83.46) v4(109.43,83.21)
  L4_SIG2 w0.114: v8(37.34,45.34) 36.83,44.83 36.83,31.52 34.8,29.49 34.8,24.51 29.46,19.18 29.46,14.1 29.72,13.84 29.72,12.33 29.46,12.07 29.46,11.56 29.84,11.18 33.02,11.18 38.23,16.38 55.75,16.38 57.18,17.81 61.18,17.81 63.43,15.57 73.34,15.57 73.72,15.19 102.36,15.19 102.82,14.73 105.79,14.73 107.07,13.46 112.62,13.46 113.66,14.5 113.66,15.16 114.09,15.58 115.66,15.58 116.63,14.61 123.32,14.61 123.79,15.08 124.4,15.08 125.09,14.39 127.75,14.39 139.11,25.75 143.39,25.75 144.88,27.24 144.88,63.78 141.29,67.37 140.02,67.37 138.68,68.71 138.68,69.98 134.14,74.52 127.83,74.52 126.26,72.95 122.91,72.95 122.09,72.14 119.43,72.14 118.32,73.25 118.32,78.4 119.37,79.45 119.37,80.9 119.78,81.31 126.01,81.31 v5(128.24,83.54) ; v5(109.83,83.46) 110.22,83.08 122.17,83.08 122.48,83.39 v5(123.44,83.39)
  L10_SIG4 w0.109: v5(123.44,83.39) 128.1,83.39 v5(128.24,83.54)
  BOTTOM w0.173: v8(37.34,45.34) 36.58,44.58 27.76,44.58 27.13,43.95 25.25,43.95 24.03,45.16 15.95,45.16 15.19,44.4 R788.2
GPIO_IND_LDN: length 45.6
  TOP w0.173: v8(83.21,104.55) 83.21,96.65 85.98,93.88 R371.2 R800.1 ; R690.1 104.65,98.93 v3(104.27,98.55) 104.17,98.45 104.17,95.59 103.43,94.86 U1.N1
  L3_SIG1 w0.109: v5(99.66,103.11) 100.91,101.85 102.01,101.85 102.8,101.06 102.8,100.12 104.27,98.65 v3(104.27,98.55)
  L10_SIG4 w0.109: v5(99.66,103.11) 97.52,103.11 96.72,103.91 93.24,103.91 92.96,104.19 90.7,104.19 90.22,103.71 84.05,103.71 v8(83.21,104.55)
GPIO_PCIE_RSTDRVN: length 104.2
  TOP w0.173: v8(56.13,43.69) 43.05,43.69 42.69,43.32 U44.1 ; v3(94.23,101.22) 94.61,100.84 R659.1
  L3_SIG1 w0.109: v5(81.15,102.36) 81.2,102.41 93.04,102.41 v3(94.23,101.22)
  L4_SIG2 w0.114: v5(81.15,102.36) 81.15,101.15 77.42,97.42 76.21,97.42 74.68,95.89 71.88,95.89 69.72,93.73 v5(69.72,92.98)
  L10_SIG4 w0.109: v7(65.41,90.68) 65.79,91.07 66.69,91.07 68.61,92.98 v5(69.72,92.98)
  BOTTOM w0.173: v7(65.41,90.68) 64.22,89.49 64.22,86.53 65.02,85.72 65.02,72.77 63.5,71.25 63.5,68.07 65.02,66.55 65.02,60.58 66.12,59.49 66.12,53.67 v8(56.13,43.69)
GPIO_PCIE_SWRSTN: length 103.9
  TOP w0.173: v8(96.98,101.15) 96.98,100.53 R660.1 ; U85.2 42.01,47.48 42.37,47.12 49.78,47.12 51.56,45.34 v8(58.67,45.34)
  L10_SIG4 w0.109: v8(96.98,101.15) 96.6,101.52 94.69,101.52 93.14,103.07 v7(89.13,103.07)
  BOTTOM w0.173: v7(89.13,103.07) 86.33,100.28 85.42,100.28 78.76,93.62 78.76,89.89 78.06,89.19 78.06,83.39 76.33,81.66 71.37,81.66 65.41,75.69 65.41,72.52 63.88,70.99 63.88,68.2 65.41,66.67 65.41,60.83 67.02,59.22 67.02,53.68 v8(58.67,45.34)
GPIO_PRU1_ETH_RESETN: length 356.1
  TOP w0.173: R675.1 129.13,83.27 v3(129.16,83.24)
  L3_SIG1 w0.109: v8(35.31,90) 35.31,87.09 36.04,86.36 41.58,86.36 42.55,87.33 v8(45.97,87.33) 45,86.36 43.18,86.36 41.27,84.45 41.27,82.02 39.86,80.6 37.95,80.6 34.8,77.44 33.25,77.44 32.87,77.06 32.87,76.68 29.6,73.41 27.81,73.41 22.51,68.11 22.51,51.46 17.65,46.6 14.47,46.6 10.19,42.33 10.19,38.69 21.96,26.92 25.15,26.92 v5(26.16,27.94) ; v3(129.16,83.24) 129.44,82.96 v5(130.15,82.96)
  L4_SIG2 w0.114: v5(26.16,27.94) 22.01,23.79 22.01,10.83 26.3,6.55 26.3,4.5 27.42,3.38 28.43,3.38 29.82,1.98 48.43,1.98 49.83,3.38 53.04,3.38 53.92,4.27 72.23,4.27 75.2,7.23 95.34,7.23 96.18,8.08 101.73,8.08 103.61,6.19 110.74,6.19 112.5,4.44 130.93,4.44 131.18,4.69 139.54,4.69 157.4,22.56 157.4,64.59 140.08,81.91 134.11,81.91 132.84,83.19 130.37,83.19 v5(130.15,82.96)
  BOTTOM w0.173: R154.2 v8(35.31,90) ; v8(45.97,87.33) R112.2
GPIO_PRU2_ETH_RESETN: length 303.8
  TOP w0.173: R676.1 v3(129.16,84.54)
  L3_SIG1 w0.109: v3(129.16,84.54) 129.26,84.64 130.3,84.64 v5(130.86,84.08)
  L4_SIG2 w0.114: v5(130.86,84.08) 130.31,84.08 128.43,82.19 127.39,82.19 126.18,80.98 120.85,80.98 119.67,79.79 119.67,79.23 118.61,78.18 118.61,73.92 119.29,73.25 126.14,73.25 127.93,75.04 136.23,75.04 139.32,71.94 139.32,69.12 140.05,68.39 141.29,68.39 145.47,64.21 145.47,27.28 143.61,25.43 139.39,25.43 128.07,14.1 124.97,14.1 124.38,14.69 123.83,14.69 123.42,14.28 116.27,14.28 115.66,13.66 113.4,13.66 112.9,13.16 106.72,13.16 105.54,14.35 102.78,14.35 102.23,14.9 73.6,14.9 73.26,15.24 63.29,15.24 61.75,16.78 57.89,16.78 56.1,14.99 37.46,14.99 32.51,10.03 29.85,10.03 28.58,11.3 28.58,14.09 28.19,14.48 28.19,18.32 34.07,24.2 34.07,29.18 36.32,31.43 36.32,45.85 v8(37.34,46.86) 37.34,50.93 38.6,52.18 38.6,55.11 40.51,57.02 40.51,64.02 v8(42.8,66.31)
  BOTTOM w0.173: R195.2 34.74,66.31 v8(42.8,66.31) ; v8(37.34,46.86) 36.45,45.97 30.4,45.97 R234.2
GPIO_TOUCH_RESETN: length 317.5
  L4_SIG2 w0.114: v5(120.04,76.41) 119.63,76 119.63,75.23 119.99,74.88 121.61,74.88 122.3,74.19 124.92,74.19 127.08,76.35 130.5,76.35 131.41,77.27 135.84,77.27 142.49,70.61 142.49,69.06 147.65,63.9 147.65,26.49 144.76,23.6 140.51,23.6 129.14,12.23 117.17,12.23 116.54,11.6 115.2,11.6 114.81,12 105.89,12 104.98,12.91 102.7,12.91 102.23,12.45 99.82,12.45 98.69,13.58 72.85,13.58 72.28,14.15 59.06,14.15 59.01,14.19 57.44,14.19 57.03,13.77 57.03,13.54 56.73,13.24 55.59,13.24 49.97,7.62 28.73,7.62 25.27,11.09 25.27,19.6 26.3,20.63 26.3,21.72 27.29,22.72 27.29,23.64 34.02,30.37 34.02,32.72 32.33,34.41 32.33,37.21 33.01,37.89 33.01,42.48 33.91,43.37 33.91,50.06 37.72,53.87 37.72,60.28 37.04,60.96 37.04,79.02 38.5,80.47 39.46,80.47 40.44,81.46 40.44,83.46 40.07,83.83 40.07,87.53 41.5,88.95 46.39,88.95 49.66,85.68 57.02,85.68 v8(57.53,86.19)
  L10_SIG4 w0.109: v7(119.76,75.01) 119.79,75.04 119.79,76.15 v5(120.04,76.41)
  BOTTOM w0.173: v7(119.76,75.01) 120.14,74.63 R661.1 ; R792.2 57.43,86.08 v8(57.53,86.19)
GPIO_USB2_VBUS_DET: length 105.7
  TOP w0.173: 143.64,64.64 v3(147.57,64.64) ; U96.4 152.67,140.07 153.7,141.1 R834.2 v8(153.8,141.86)
  L3_SIG1 w0.109: v3(147.57,64.64) v5(148.21,64.64)
  L10_SIG4 w0.109: v8(153.8,141.86) 154.56,141.1 159.64,141.1 160.36,140.38 160.36,135.26 163.15,132.47 163.15,128.12 163.99,127.27 163.99,126.85 162.3,125.16 162.3,119.3 162.86,118.74 162.86,116.03 163.45,115.44 163.45,109.98 162.01,108.55 162.01,103.52 160.88,102.39 160.88,100.99 162.81,99.06 162.81,86.33 162.05,85.57 162.05,82.09 160.86,80.9 159.18,80.9 158.7,80.42 158.7,79.22 157.34,77.86 152.55,77.86 151.71,77.02 151.71,74.88 150.24,73.41 150.24,71.63 148.21,69.6 v5(148.21,64.64)
GPIO_VPP_PWR_EN: length 389
  TOP w0.173: U1.M5 v4(104.63,89.61) ; v3(81.17,90.87) 79.67,92.36 75.23,92.36 73.45,94.15 v3(70.19,94.15) ; v3(105.54,98.42) 105.92,98.81 R691.1 ; R638.2 v8(164.47,5.03)
  L3_SIG1 w0.099: 103.33,88.69 103.16,88.52 103.13,88.52 102.23,87.63 102.23,87.15 101.96,86.87 101.37,86.87 101.21,87.03 101.18,87.04 100.88,87.04 100.88,87.04 100.7,86.87 100.57,86.87 100.41,87.03 100.38,87.04 100.08,87.04 100.08,87.04 99.9,86.87 99.77,86.87 99.61,87.03 99.58,87.04 99.28,87.04 99.28,87.04 99.1,86.87 98.97,86.87 98.81,87.03 98.78,87.04 98.48,87.04 98.48,87.04 98.3,86.87 98.17,86.87 98.01,87.03 97.98,87.04 97.68,87.04 97.68,87.04 97.5,86.87 97.37,86.87 97.21,87.03 97.18,87.04 96.88,87.04 96.88,87.04 96.7,86.87 96.57,86.87 96.41,87.03 96.38,87.04 96.08,87.04 95.9,86.87 95.77,86.87 95.59,87.04 95.28,87.04 95.1,86.87 94.97,86.87 94.79,87.04 94.46,87.04 ; 103.33,88.69 103.33,91.34 103.2,91.46 103.2,94.08 103.05,94.23 103.05,94.75 103.56,95.26 103.56,96.98 104,97.42 ; 103.33,88.69 103.54,88.69 103.71,88.52 103.96,88.52 104.13,88.69 104.13,89.11 v4(104.63,89.61)
  L3_SIG1 w0.109: 94.46,87.04 92.81,87.04 90.17,89.69 89.43,89.69 88.62,90.5 85.67,90.5 85.47,90.3 81.74,90.3 v3(81.17,90.87) ; v8(164.47,5.03) 161.01,1.57 146.97,1.57 138,10.54 135.39,10.54 124.44,21.49 110.29,21.49 109.65,22.14 108.67,22.14 107.95,21.43 97.29,21.43 91.49,15.62 85.26,15.62 73.73,4.09 51.28,4.09 48.63,1.44 23.92,1.44 22.73,2.62 18.09,2.62 17.33,1.86 8.38,1.86 7.52,2.72 7.52,7.34 5.46,9.4 5.46,29.34 2.03,32.77 2.03,33.82 2.03,33.82 2.03,34.25 2.03,34.25 2.03,47.71 3.3,48.98 3.3,83.74 5.24,85.68 12.07,85.68 15.24,88.85 19.03,88.85 19.58,88.3 24.76,88.3 25.32,88.85 28.64,88.85 29.54,89.75 32.65,89.75 34.13,91.24 34.69,91.8 36.24,91.8 38.64,89.39 50.15,89.39 52.58,91.82 67.06,91.82 67.56,92.33 69.72,92.33 70.19,92.8 v3(70.19,94.15) ; v3(105.54,98.42) 105.53,98.41 104.76,98.41 104.15,97.81 104.15,97.57 104,97.42
HAPTICS_N: length 2.8
  TOP w0.173: U18.2 143.14,14.86 Q16.D
HAPTICS_P: length 4.5
  TOP w0.173: U18.1 R113.1 140.84,13.25 C316.1
HDMI_CEC: length 2.6
  TOP w0.173: U46.1 68.22,21.99 R683.1
HDMI_CLK+: length 17.7
  TOP w0.108: L29.3 56.28,19.2 56.01,18.92 56.01,18.16 56.9,17.27 62.46,17.27 62.83,16.91 62.83,16.18 63.02,15.99 U46.16 63.02,14.43 62.81,14.23 62.81,11.46 62.25,10.9 62.25,10.11 62.65,9.72 J24.10
HDMI_CLK-: length 17.7
  TOP w0.108: J24.12 61.65,9.76 62,10.11 62,11.01 62.56,11.57 62.56,14.23 62.37,14.42 U46.15 62.37,15.97 62.57,16.18 62.57,16.8 62.36,17.02 56.79,17.02 55.75,18.06 55.75,18.92 55.48,19.2 L29.2
HDMI_CT_HPD: length 8.5
  TOP w0.173: U46.12 v8(61.07,19.92) ; v8(63.75,23.88) 64.64,23.88 64.64,22.86
  BOTTOM w0.173: v8(61.07,19.92) 61.07,21.71 63.23,23.88 v8(63.75,23.88)
HDMI_DDC_SCL: length 2.1
  TOP w0.173: U46.2 v8(67.57,19.84)
  BOTTOM w0.173: v8(67.57,19.84) 67.62,19.89 R795.1
HDMI_DDC_SDA: length 2.6
  TOP w0.173: U46.3 v8(66.92,22.4)
  BOTTOM w0.173: R796.1 66.76,22.56 v8(66.92,22.4)
HDMI_HPLG: length 4
  TOP w0.173: R682.1 66.8,23.24 66.27,22.71 U46.4
HDMI_LSOE: length 1.8
  TOP w0.173: U46.5 65.62,22.82 R558.1
HDMI_TX0+: length 16.6
  TOP w0.108: J24.7 64.15,9.72 63.75,10.11 63.75,11.25 64.11,11.61 64.11,14.23 64.32,14.43 U46.18 64.32,15.99 64.13,16.18 64.13,17.51 63.48,18.16 58.8,18.16 58.55,18.41 58.55,18.92 58.82,19.2 L30.3
HDMI_TX0-: length 16.6
  TOP w0.108: J24.9 63.15,9.76 63.5,10.11 63.5,11.36 63.86,11.71 63.86,14.23 63.67,14.42 U46.17 63.67,15.97 63.87,16.18 63.87,17.41 63.37,17.91 58.7,17.91 58.29,18.31 58.29,18.92 58.02,19.2 L30.2
HDMI_TX1+: length 15.9
  TOP w0.108: L31.3 71.27,19.35 70.97,19.05 70.97,18.44 70.41,17.88 66.94,17.88 66.08,17.01 66.08,16.18 66.27,15.99 U46.21 66.27,14.43 66.06,14.23 66.06,11.68 65.25,10.87 65.25,10.11 65.65,9.72 J24.4
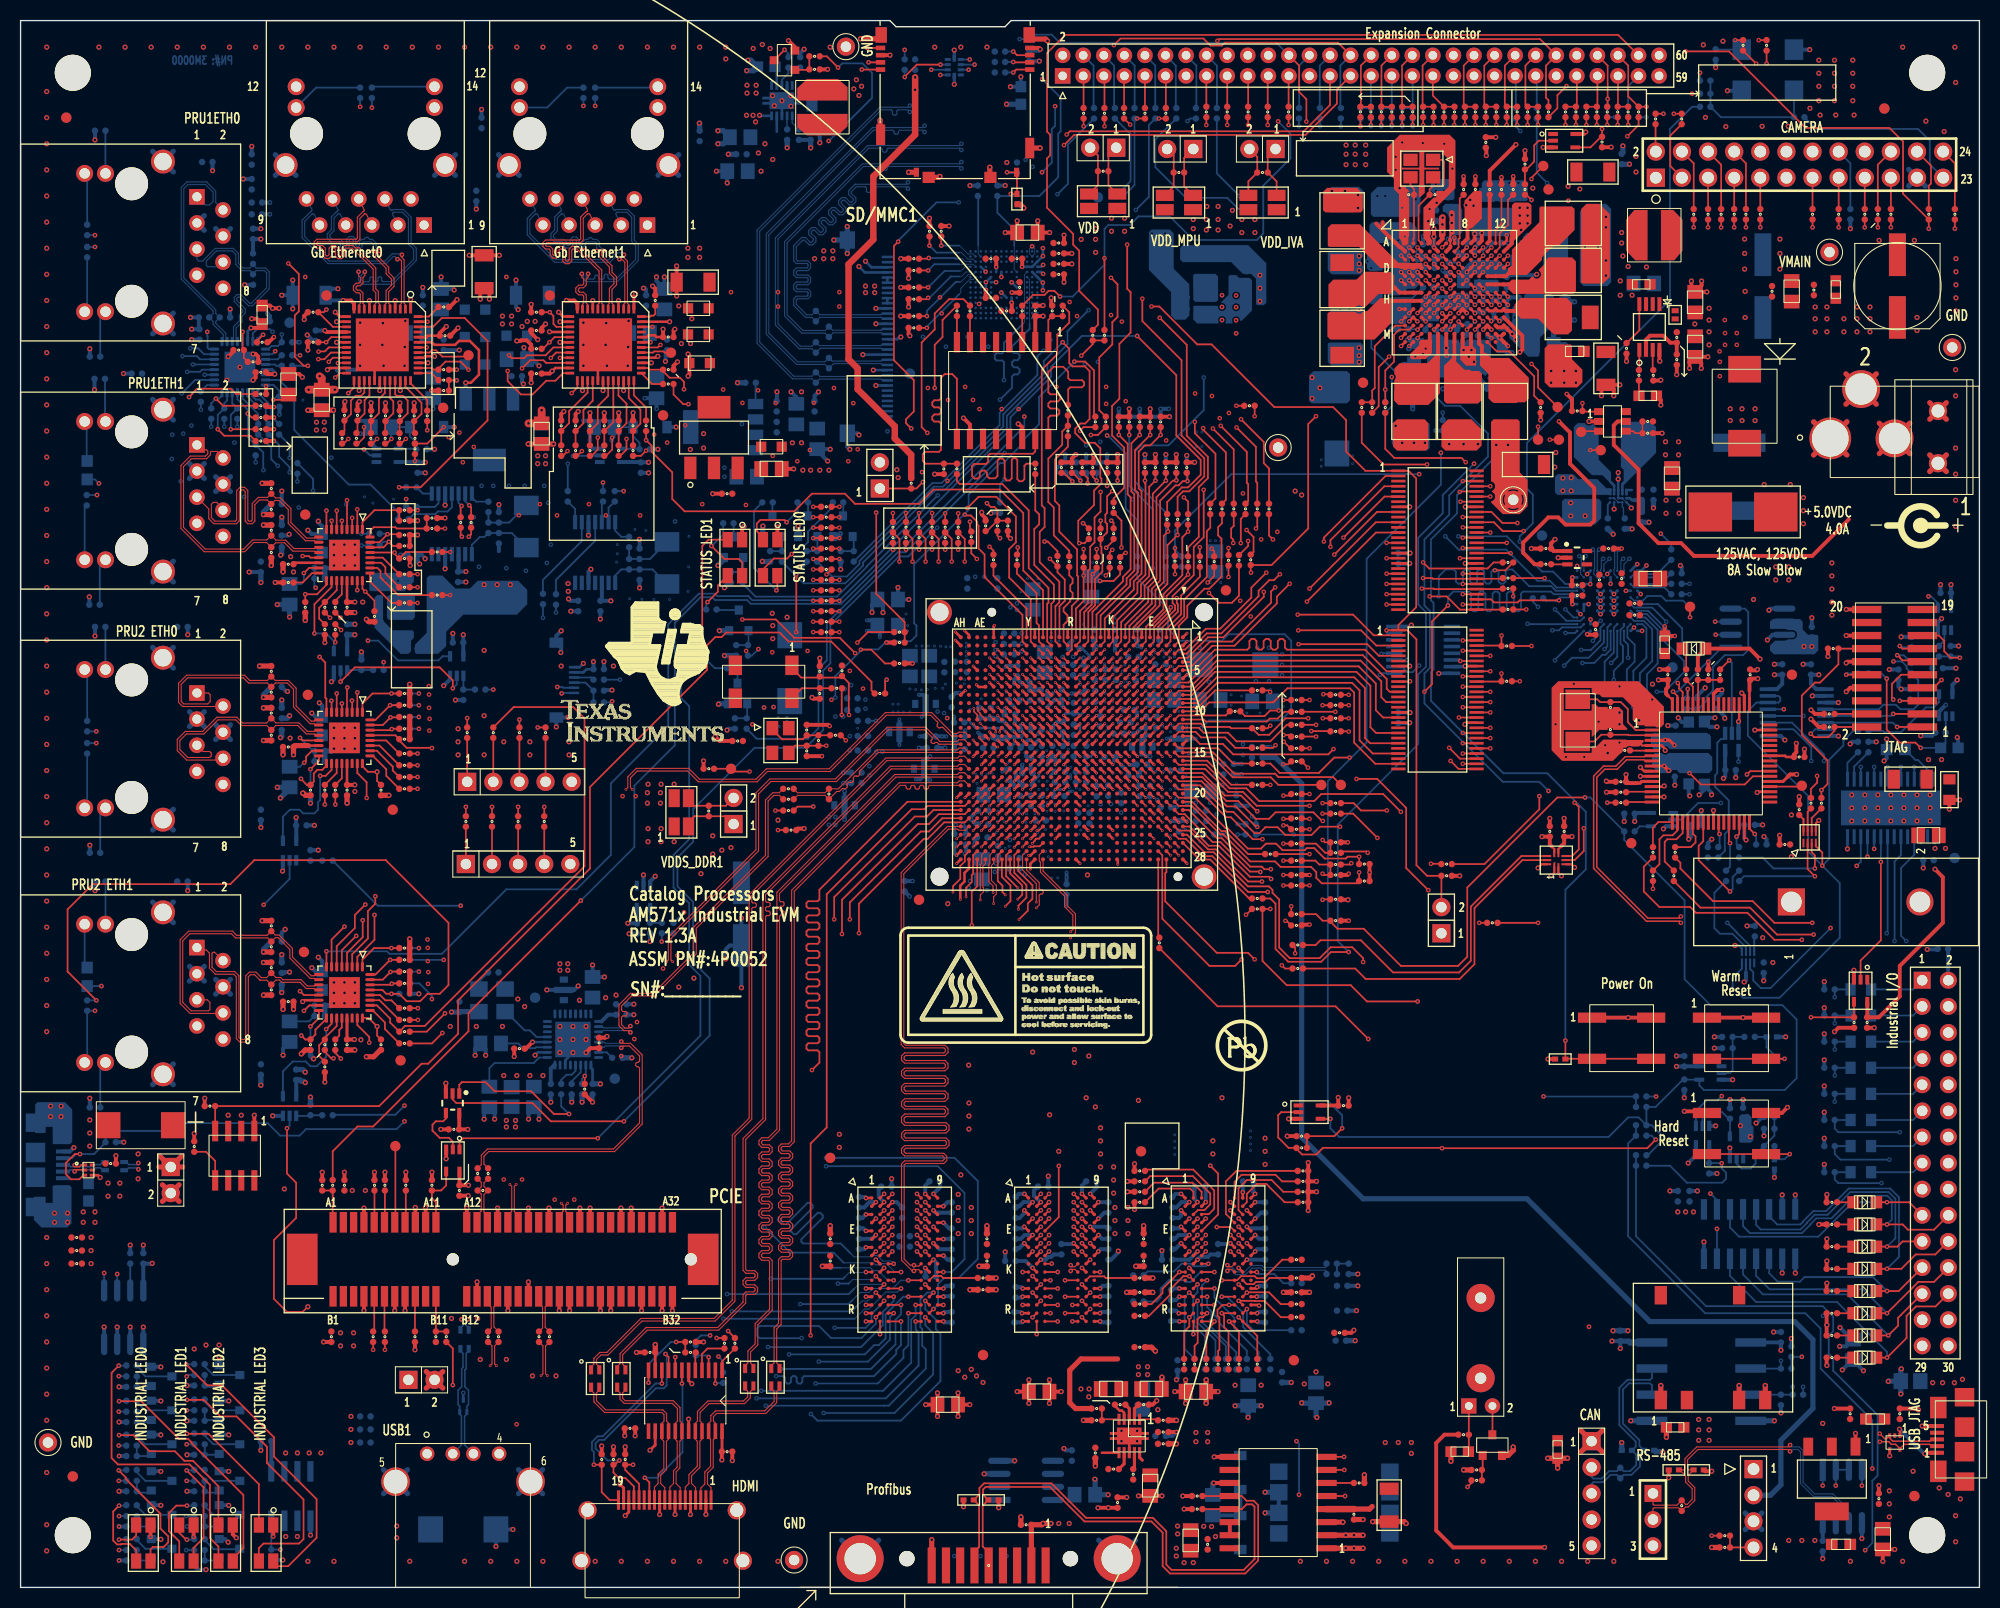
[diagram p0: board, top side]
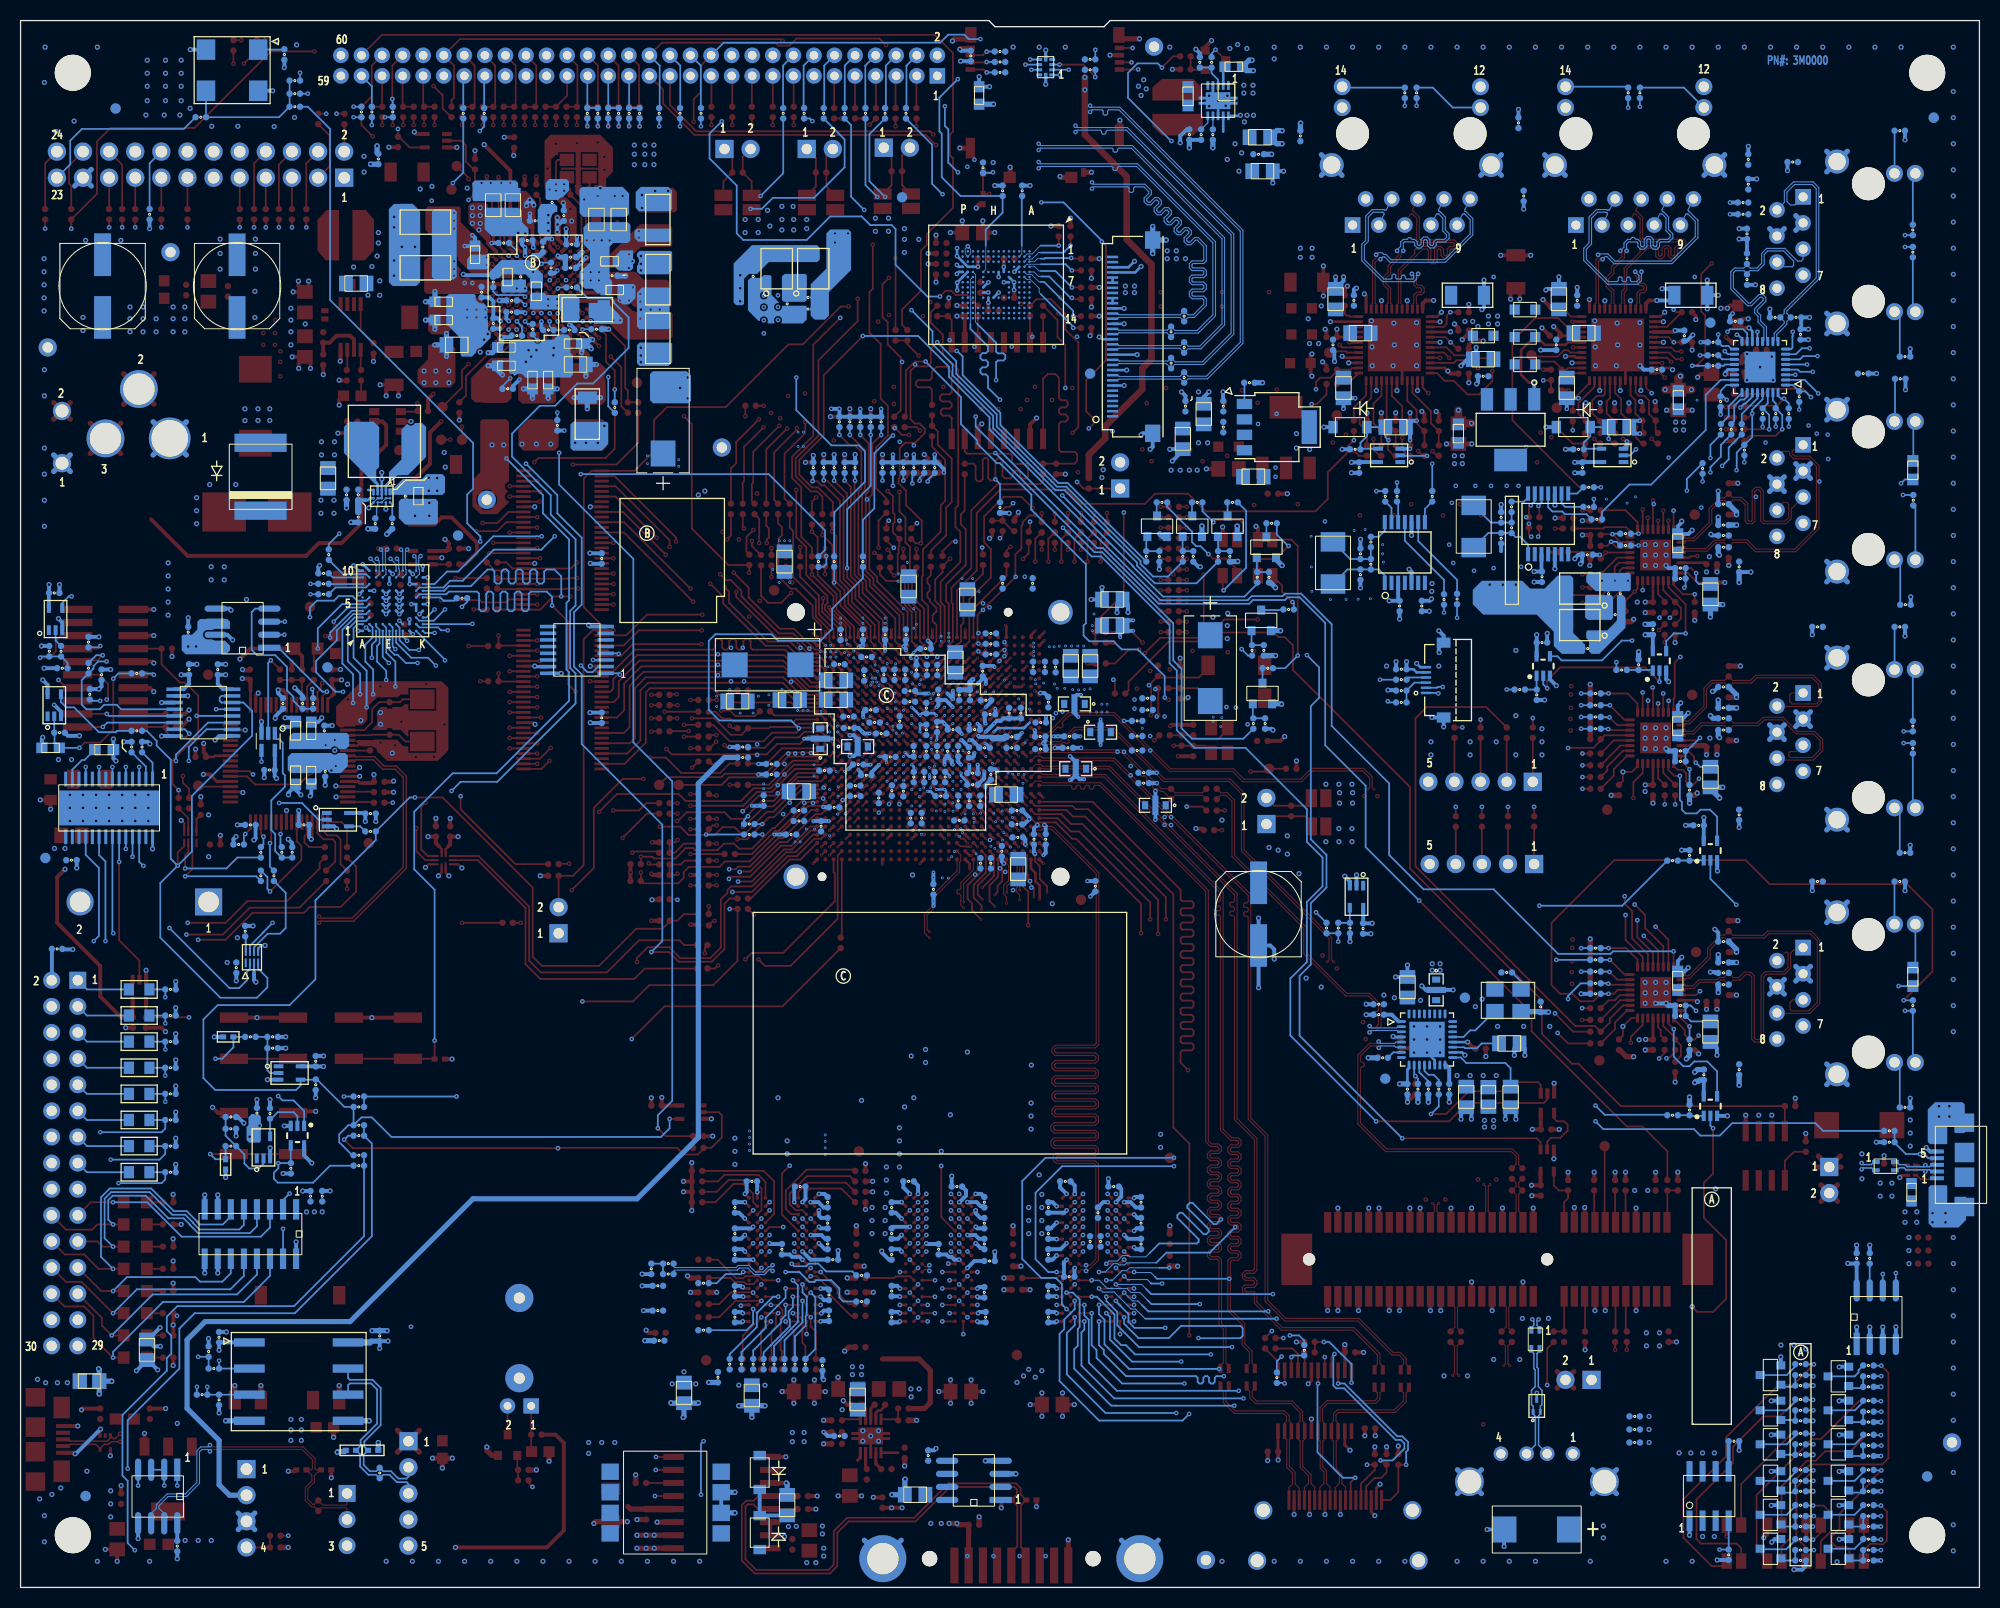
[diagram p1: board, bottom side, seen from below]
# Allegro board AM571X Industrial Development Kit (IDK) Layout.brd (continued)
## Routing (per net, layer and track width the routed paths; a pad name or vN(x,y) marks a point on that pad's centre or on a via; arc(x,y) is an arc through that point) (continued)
HDMI_TX1-: length 15.9
  TOP w0.108: J24.6 64.65,9.76 65,10.11 65,10.97 65.81,11.78 65.81,14.23 65.62,14.42 U46.20 65.62,15.97 65.83,16.18 65.83,17.12 66.84,18.13 70.3,18.13 70.71,18.54 70.71,19.08 70.47,19.32 L31.2
HDMI_TX2+: length 17.1
  TOP w0.108: J24.1 67.15,9.71 66.8,10.06 66.8,11.12 67.36,11.68 67.36,14.35 67.57,14.56 U46.23 67.57,15.99 67.38,16.18 67.38,16.61 67.69,16.92 72.47,16.92 73.53,17.98 73.53,19.05 73.81,19.32 L32.3
HDMI_TX2-: length 17.1
  TOP w0.108: J24.3 66.15,9.66 66.55,10.06 66.55,11.23 67.11,11.79 67.11,14.38 66.92,14.57 U46.22 66.92,15.97 67.13,16.18 67.13,16.72 67.59,17.18 72.37,17.18 73.28,18.09 73.28,19.05 73.01,19.32 L32.2
HDMICONN_CEC: length 15
  TOP w0.173: v8(60.71,10.67) 61.15,10.23 J24.13 ; U46.7 v8(64.32,19.84)
  BOTTOM w0.173: v8(60.71,10.67) 61.89,10.67 64.37,13.15 64.37,19.78 v8(64.32,19.84)
HDMICONN_HPLG: length 18.1
  TOP w0.173: J24.19 57.29,8.5 56.52,9.27 R561.2 v8(55.75,11.94) ; U46.10 v8(62.37,19.84)
  BOTTOM w0.173: v8(62.37,19.84) 61.75,19.84 56.62,14.7 56.12,14.7 55.57,14.15 55.57,13.37 55.75,13.18 v8(55.75,11.94)
HDMICONN_I2CSCL: length 22.1
  TOP w0.173: v8(59.56,11.94) R560.1 58.8,11.43 60.15,10.08 J24.15 ; U46.8 v8(63.67,22.4)
  L3_SIG1 w0.109: v8(63.67,22.4) 66.17,19.91 66.17,15.58 62.48,11.89 59.61,11.89 v8(59.56,11.94)
HDMICONN_I2CSDA: length 22.7
  TOP w0.173: U46.9 63.02,22.41 v8(62.72,22.71) ; J24.16 59.65,9.82 58.83,10.64 58.19,10.64 57.66,11.18 R562.1 57.78,11.94 58.2,12.35 v8(58.24,12.35)
  BOTTOM w0.173: v8(58.24,12.35) 57.08,12.35 55.92,13.51 55.92,14 56.27,14.35 56.76,14.35 61.78,19.37 62.56,19.37 62.84,19.64 62.84,22.59 v8(62.72,22.71)
HDQ: length 17
  TOP w0.173: R891.1 149.45,143.87 149.45,145.14 v3(150.34,146.02)
  L3_SIG1 w0.109: v8(162.56,145.29) 161.82,146.02 v3(150.34,146.02)
  BOTTOM w0.173: R300.1 v8(162.56,145.29)
IND_I2C_SCL: length 505.9
  TOP w0.173: J21.27 127.35,144.19 124.79,141.63 102.05,141.63 v3(101.74,141.32) ; R14.2 130.43,111.33 132.54,109.22 v3(136.78,109.22) ; R314.2 42.8,102.32 v8(42.91,102.21) ; v3(34.29,23.11) R652.2 ; R393.1 v3(122.81,72.34) ; v8(185.57,132.16) R275.1 183.07,135.55 183.07,140.63 181.75,141.95 173.6,141.95 166.15,149.4 v3(161.93,149.4)
  L3_SIG1 w0.109: v8(52.2,87.58) 46.65,87.58 46.02,88.22 38.19,88.22 35.88,90.53 35.08,90.53 33.16,88.6 30.01,88.6 29.11,87.7 25.79,87.7 25.24,87.15 19.28,87.15 17.78,85.65 15.88,85.65 14,83.77 7.04,83.77 5.11,81.84 5.11,48.48 6.16,47.43 6.16,42.76 6.71,42.21 6.71,34.93 9.4,32.24 v8(9.4,30.48) 9.4,29.72 10.82,28.3 18.52,28.3 24.3,22.52 33.7,22.52 v3(34.29,23.11) ; v5(147.19,107.31) 146.05,108.46 140.84,108.46 140.08,109.22 v3(136.78,109.22) ; v3(161.93,149.4) 161.9,149.4 160.68,150.62 129.58,150.62 128.38,149.42 128.38,148.05 J21.27 ; v3(101.74,141.32) 101.74,141.31 v5(101.3,140.87) ; v3(122.81,72.34) v5(124.21,72.34)
  L4_SIG2 w0.114: v5(101.3,140.87) 101.3,141.24 97.83,144.7 97.83,149.56 97.04,150.34 90.75,150.34 89.69,149.28 86.99,149.28 81.75,144.03 81.75,139.99 77.39,135.63 72.65,135.63 69.22,132.2 69.22,132.2 68.69,131.67 68.69,130.46 67.78,129.55 67.78,108.83 63.95,105 54.17,105 52.22,103.05 43.75,103.05 v8(42.91,102.21) 42.91,100.06 42.67,99.82 42.67,97.11 v8(52.2,87.58) ; v5(147.19,107.31) 148.59,107.31 154.69,113.41 160.53,113.41 162.18,115.06 164.08,115.06 169.16,120.14 179.27,120.14 185.57,126.45 v8(185.57,132.16)
  L9_SIG3 w0.114: v5(161.67,97.62) 158.29,97.62 156.18,99.72 156.18,102.85 152.65,106.38 152.65,107.52 150.45,109.73 148.64,109.73 147.19,108.28 v5(147.19,107.31) 147.19,103.63 145.29,101.73 145.29,97.57 140.55,92.84 139.57,92.84 137.03,90.3 137.03,89.36 133.6,85.92 133.6,81.1 124.84,72.34 v5(124.21,72.34)
  L10_SIG4 w0.109: v7(162.31,97.62) v5(161.67,97.62)
  BOTTOM w0.173: R567.2 v7(162.31,97.62) ; U33.6 v8(9.4,30.48) ; v8(52.2,87.58) 52.69,87.58 52.77,87.51 J17.2
IND_I2C_SDA: length 509.1
  TOP w0.173: R277.1 v8(188.11,132.16) ; R15.2 132.72,110.74 133.6,109.86 140.13,109.86 v3(140.54,109.45) ; J21.29 128.02,145.69 128.02,144.32 124.97,141.27 102.46,141.27 v3(101.47,140.28) ; R312.2 43.81,102.42 v8(43.59,102.2) ; v3(35.43,23.11) R653.2 ; R394.1 v3(122.81,70.69)
  L3_SIG1 w0.109: v3(101.47,140.28) v5(100.63,140.28) ; v3(122.81,70.69) v5(123.44,70.69) ; v8(52.62,86.96) 52.75,87.09 52.75,87.84 52.08,88.51 38.3,88.51 36,90.81 34.96,90.81 33.04,88.89 29.89,88.89 28.99,87.99 25.67,87.99 25.12,87.44 19.22,87.44 18.67,87.99 16.77,87.99 12.89,84.1 6.79,84.1 4.49,81.8 4.49,48.6 5.78,47.31 5.78,44.66 4.45,43.33 4.45,39.55 5.41,38.58 5.41,33.45 6.73,32.13 7.18,32.13 8.13,31.18 v8(8.13,30.58) 10.74,27.97 18.44,27.97 24.19,22.23 34.54,22.23 v3(35.43,23.11) ; v5(148.21,107.82) 147.7,107.82 146.66,108.87 141.12,108.87 v3(140.54,109.45)
  L4_SIG2 w0.114: v5(148.21,107.82) 148.21,108.71 149.25,109.75 149.76,109.75 154.43,114.43 160.27,114.43 161.42,115.57 164.08,115.57 169.29,120.78 179.45,120.78 183.26,124.59 183.26,131.27 184.83,132.84 187.43,132.84 v8(188.11,132.16) ; v5(100.63,140.28) 100.63,141.12 97.28,144.48 97.28,145.8 93.8,149.28 91.69,149.28 91.38,148.97 87.14,148.97 82.04,143.87 82.04,139.85 76.81,134.62 72.05,134.62 68.98,131.55 68.98,130.34 68.07,129.43 68.07,108.71 63.97,104.61 55.56,104.61 53.46,102.51 43.91,102.51 v8(43.59,102.2) 43.59,100.58 44.11,100.06 44.11,96.81 52.96,87.97 52.96,87.3 v8(52.62,86.96)
  L9_SIG3 w0.114: v5(161.67,96.6) 158.41,96.6 155.78,99.24 155.78,102.6 151,107.37 149.5,107.37 149.05,107.82 v5(148.21,107.82) 148.21,103.89 146.05,101.73 146.05,97.92 133.89,85.76 133.89,80.63 123.95,70.69 v5(123.44,70.69)
  L10_SIG4 w0.109: v8(188.11,132.16) 187.5,132.16 183.1,136.56 183.1,137.46 182.34,138.21 181.77,138.21 180.79,139.2 180.79,139.77 179,141.56 175.39,141.56 167.85,149.1 162.69,149.1 161.09,150.7 131.65,150.7 130.31,149.36 130.31,147.99 J21.29 ; v7(162.31,96.6) v5(161.67,96.6)
  BOTTOM w0.173: J17.1 52.71,87.01 52.67,86.96 v8(52.62,86.96) ; R585.2 v7(162.31,96.6) ; U33.5 v8(8.13,30.58)
INDUS_INPUT0: length 5.3
  BOTTOM w0.173: J37.1 184.05,58.17 R368.1
INDUS_INPUT1: length 5.3
  BOTTOM w0.173: J37.3 184.05,55.63 R370.1
INDUS_INPUT2: length 5.3
  BOTTOM w0.173: R372.1 184.05,53.09 J37.5
INDUS_INPUT3: length 5.3
  BOTTOM w0.173: J37.7 184.05,50.55 R374.1
INDUS_INPUT4: length 5.3
  BOTTOM w0.173: J37.9 184.05,48.01 R373.1
INDUS_INPUT5: length 5.3
  BOTTOM w0.173: J37.11 184.05,45.47 R375.1
INDUS_INPUT6: length 5.3
  BOTTOM w0.173: R376.1 184.05,42.93 J37.13
INDUS_INPUT7: length 5.3
  BOTTOM w0.173: J37.15 184.05,40.39 R378.1
INDUS_INPUTCLK: length 57.8
  TOP w0.173: v3(131.95,72.9) 129.59,75.27 R367.1
  L3_SIG1 w0.109: v3(131.95,72.9) v5(133.78,72.9)
  L9_SIG3 w0.114: v5(133.78,72.9) 135.81,74.93 146.81,74.93 147.45,75.56 152.18,75.56 156.75,70.99 170.82,70.99 171.45,71.63 175.77,71.63 176.28,71.12 178.05,71.12 178.31,71.37 179.31,71.37 v8(179.61,71.07)
  BOTTOM w0.173: U72.25 v8(179.61,71.07)
INDUS_INPUTCSN: length 56.3
  TOP w0.173: R369.1 129.64,76.28 130.35,75.57 v3(132.87,75.57)
  L3_SIG1 w0.109: v3(132.87,75.57) v5(133.53,75.57)
  L9_SIG3 w0.114: v5(133.53,75.57) 146.56,75.57 147.07,76.07 152.74,76.07 157.31,71.5 170.43,71.5 171.12,72.18 176.45,72.18 176.91,72.64 179.46,72.64 v8(180.26,71.84)
  BOTTOM w0.173: U72.24 v8(180.26,71.84)
INDUS_INPUTLDN: length 281.9
  TOP w0.173: v3(81.38,91.9) 82.4,92.92 R371.1
  L3_SIG1 w0.109: v3(81.38,91.9) v5(79.25,91.9)
  L9_SIG3 w0.114: v8(124.33,9.02) 125.73,7.62 131.32,7.62 133.73,5.21 153.92,5.21 156.81,2.32 173.01,2.32 179.58,8.89 179.58,20.02 180.21,20.66 180.21,50.67 181.1,51.56 181.1,58.29 178.56,60.83 v8(178.56,70.19) ; v5(79.25,91.9) 77.96,91.9 75.62,89.56 75.62,75.49 73.8,73.67 73.8,72 62.1,60.3 62.1,39.24 63.12,38.22 63.12,29.82 67.54,25.4 68.96,25.4 69.25,25.12 69.25,18.76 71.33,16.68 74.59,16.68 77.93,13.34 96.88,13.34 97.71,12.5 102.01,12.5 103.68,14.17 105.74,14.17 106.65,13.26 115.47,13.26 116.43,14.22 v8(124.08,14.22)
  BOTTOM w0.173: v8(124.08,14.22) 124.33,13.97 v8(124.33,9.02) ; U72.26 178.96,70.59 v8(178.56,70.19)
INDUS_INPUTSO: length 14.7
  TOP w0.173: v8(180.91,70.57) 180.91,62.95 178.94,60.97 U28.2
  BOTTOM w0.173: U72.23 v8(180.91,70.57)
JTAG_EMU0: length 101.4
  TOP w0.173: J18.13 183.01,91.31 v8(182.75,91.57) ; v3(174.72,78.93) 174.72,78.28 174.12,77.68 R554.1 ; U1.G21 v4(108.63,76.02)
  L3_SIG1 w0.109: v4(108.63,76.02) v5(109.03,75.77) ; v5(115.85,74.57) 115.98,74.57 119.53,71.02 119.53,70.44 119.84,70.13 120.68,70.13 121.46,69.35 121.81,69.35 122.05,69.12 122.05,68.18 122.43,67.79 125.8,67.79 126.01,68 131.65,68 135.36,71.7 140.18,71.7 141.46,72.99 146.18,72.99 148.63,75.44 154.43,75.44 155.24,76.24 160.24,76.24 161.94,77.94 162.66,77.94 165.73,81.01 168.89,81.01 169.37,81.48 171.2,81.48 172.08,80.6 173.05,80.6 v3(174.72,78.93) 177.73,78.93 v5(179.37,80.57)
  L10_SIG4 w0.109: v8(182.75,91.57) 179.37,88.19 v5(179.37,80.57) ; v5(109.03,75.77) 109.43,75.37 109.98,75.37 110.2,75.58 111.52,75.58 111.99,75.11 115.31,75.11 v5(115.85,74.57)
  BOTTOM w0.173: R422.1 182.88,91.44 v8(182.75,91.57)
JTAG_EMU1: length 104.3
  TOP w0.173: J18.14 R423.1 176.78,89.79 175.01,88.01 174.5,88.01 173.23,86.74 173.23,82.93 175.73,80.43 175.73,78.15 v8(175.13,77.55) R555.1 ; v4(111.03,73.62) U1.D24
  L3_SIG1 w0.099: 112.96,73.16 112.79,72.99 112.08,72.99 111.78,73.28 111.37,73.28 v4(111.03,73.62)
  L3_SIG1 w0.109: v8(175.13,77.55) 172.29,77.55 171.4,76.66 169.29,76.66 168.1,75.48 167.95,75.48 167.65,75.78 167.49,75.78 167.34,75.62 167.34,75.47 167.64,75.17 167.64,75.01 167.49,74.86 167.33,74.86 167.03,75.16 166.87,75.16 166.72,75.01 166.72,74.85 167.02,74.55 167.02,74.39 166.87,74.24 166.71,74.24 166.41,74.54 166.26,74.54 166.09,74.38 164.03,74.38 163.92,74.27 163.92,73.42 163.82,73.31 163.6,73.31 163.49,73.42 163.49,74.27 163.38,74.38 163.16,74.38 163.05,74.27 163.05,73.42 162.94,73.31 162.72,73.31 162.61,73.42 162.61,74.27 162.5,74.38 162.29,74.38 162.18,74.27 162.18,73.42 162.07,73.31 161.85,73.31 161.74,73.42 161.74,74.27 161.63,74.38 161.41,74.38 161.3,74.27 161.3,73.42 161.19,73.31 160.6,73.31 158.12,70.83 147.3,70.83 147.01,70.54 141.07,70.54 140.36,69.83 138.38,69.83 137.67,69.11 136.02,69.11 130.93,64.03 127.83,64.03 126.57,65.28 121.21,65.28 118.01,68.48 118.01,70.39 115.24,73.16 112.96,73.16
JTAG_TCK: length 99.6
  TOP w0.173: U1.E20 v4(110.23,76.82)
  L3_SIG1 w0.109: v4(110.23,76.82) 110.74,76.31 116.51,76.31 116.64,76.43 117.53,76.43 119.53,74.43 120.75,74.43 122.08,73.09 124.57,73.09 125.04,72.62 125.6,72.62 126.49,71.73 129.23,71.73 131.85,74.36 145.71,74.36 148.15,76.8 148.15,77.65 148.41,77.91 149.2,77.91 151.1,79.81 155.85,79.81 157.98,81.94 160.17,81.94 160.63,82.41 166.78,82.41 v5(168.53,84.16)
  L9_SIG3 w0.114: v8(182.14,90.07) 181,90.07 179.12,88.19 179.12,86.42 176.63,83.92 173.38,83.92 172.72,84.58 168.96,84.58 v5(168.53,84.16)
  BOTTOM w0.173: v8(182.14,90.07) 182.95,90.07 183.41,89.61 183.41,89.39 R3.2 184.55,88.24 184.55,85.87 184.09,85.42 182.81,85.42 182.37,85.85 181.16,85.85 180.72,85.42 U63.4
JTAG_TDI: length 97.5
  TOP w0.173: J18.3 v8(182.12,84.96) ; v4(111.03,74.42) U1.D23
  L3_SIG1 w0.099: 112.5,74.12 111.33,74.12 v4(111.03,74.42)
  L3_SIG1 w0.109: 112.5,74.12 112.88,73.74 115.49,73.74 118.62,70.62 118.62,69.04 120.84,66.82 124.72,66.82 125.17,66.37 131.5,66.37 135.95,70.82 140.54,70.82 141.83,72.11 149.24,72.11 151.55,74.42 154.74,74.42 155.66,75.34 160.63,75.34 161.72,76.43 164.52,76.43 166.27,78.18 166.27,79.1 166.73,79.55 168.01,79.55 168.11,79.46 170.82,79.46 171.91,78.36 177.78,78.36 180.46,81.04 181.87,81.04 182.93,82.1 182.93,84.15 v8(182.12,84.96)
  BOTTOM w0.173: v8(182.12,84.96) 181.92,84.76 U63.5
JTAG_TDO: length 122.5
  TOP w0.173: v8(186.82,88.27) 186.06,87.5 J18.7 ; U1.F19 v4(109.43,77.62)
  L3_SIG1 w0.109: v4(109.43,77.62) v5(109.83,77.37) ; v5(174.75,81.11) 174.67,81.02 172.25,81.02 171.36,81.91 169.37,81.91 168.94,81.49 163.03,81.49 160.49,78.94 158.77,78.94 157.73,77.91 150.28,77.91 145.94,73.56 141.22,73.56 140.83,73.17 136.01,73.17 134.58,71.74 133.24,71.74 132.35,70.85 131.12,70.85 130.81,70.54 129.97,70.54 129.57,70.95 126.36,70.95 125.53,71.79 124.89,71.79 124.59,71.48 122.58,71.48 122.17,71.89 122.17,72.19 121.13,73.23 119.08,73.23 116.84,75.47 v5(116.84,76.03)
  L4_SIG2 w0.114: v5(174.75,81.11) 176.02,79.84 176.02,74.85 176.02,74.84 176.02,64.14 v8(176.02,64.14)
  L9_SIG3 w0.114: v8(186.82,88.27) 186.51,87.95 182.08,87.95 181.79,87.66 181.31,87.66 177.93,84.28 177.5,84.28 176.15,82.93 176.15,82.5 v5(174.75,81.11)
  L10_SIG4 w0.109: v5(109.83,77.37) 110.75,78.29 113.69,78.29 115.04,76.94 115.93,76.94 v5(116.84,76.03)
  BOTTOM w0.173: U75.2 168.2,60.15 168.5,59.84 168.5,59.03 169.25,58.29 170.18,58.29 v8(176.02,64.14)
JTAG_TMS: length 94.5
  TOP w0.173: J18.1 v8(182.5,83.69) ; U1.F18 v4(109.43,78.42)
  L3_SIG1 w0.109: v4(109.43,78.42) v5(109.83,78.17) ; v5(117.47,75.77) 117.47,75.29 119.23,73.54 121.23,73.54 121.97,72.8 124.43,72.8 124.92,72.32 125.48,72.32 126.44,71.35 129.25,71.35 131.97,74.07 146.04,74.07 150.39,78.41 153.26,78.41 153.8,78.95 154.43,78.95 155.07,78.31 157.73,78.31 158.67,79.25 158.67,79.53 159.89,80.75 161.09,80.75 162.32,81.98 167.97,81.98 168.95,82.96 172.77,82.96 173.46,82.27 174.48,82.27 175.64,81.11 178.39,81.11 180.98,83.69 v8(182.5,83.69)
  L10_SIG4 w0.109: v5(109.83,78.17) 110.31,78.64 114.1,78.64 115.29,77.45 115.85,77.45 116.57,76.72 117.11,76.72 117.47,76.36 v5(117.47,75.77)
  BOTTOM w0.173: U63.6 182.08,84.11 v8(182.5,83.69)
JTAG_TRSTN: length 79.7
  TOP w0.173: v4(111.03,76.82) U1.D20 ; J18.2 R433.2 176.4,83.31 175.79,82.7 174.42,82.7 v8(174.09,83.03)
  L3_SIG1 w0.099: v4(111.03,76.82) 111.33,76.52 112.22,76.52
  L3_SIG1 w0.109: 112.22,76.52 116.17,76.52 116.38,76.74 117.81,76.74 119.81,74.73 120.87,74.73 122.23,73.38 124.69,73.38 125.14,72.93 125.76,72.93 126.57,72.12 127.11,72.12 128.13,73.13 129.03,73.13 129.36,73.46 130.37,73.46 131.56,74.65 144.74,74.65 150.37,80.27 155.65,80.27 158.52,83.14 160.81,83.14 161.11,82.83 166.45,82.83 168.28,84.66 169.16,84.66 170.43,83.39 173.73,83.39 v8(174.09,83.03)
  BOTTOM w0.173: v8(174.09,83.03) 174.52,83.46 U63.7
JTAGPOD_PRES: length 8.9
  BOTTOM w0.173: R677.1 181.11,83.31 181.24,83.19 182.88,83.19 185.29,85.6 186.06,85.6 186.57,86.12 U19.4
LCD_B0: length 22.4
  TOP w0.173: v3(139.95,106.55) 140.01,106.6 U103.52
  L3_SIG1 w0.109: v5(146.02,103.99) 144.3,103.99 142.24,106.05 140.46,106.05 v3(139.95,106.55)
  L10_SIG4 w0.109: v5(146.02,103.99) 146.02,103.4 148.79,100.63 148.79,95.55 v7(149.23,95.12)
  BOTTOM w0.173: v7(149.23,95.12) 150.32,94.03 151.72,94.03 U89.J3
LCD_B1: length 22.6
  TOP w0.173: U103.54 v3(140.26,107.6)
  L3_SIG1 w0.109: v5(147.7,105.66) 145.76,107.6 v3(140.26,107.6)
  L10_SIG4 w0.109: v5(147.7,105.66) 150.24,103.12 v7(150.24,95.12)
  BOTTOM w0.173: U89.K3 151.02,94.34 v7(150.24,95.12)
LCD_B2: length 26.8
  TOP w0.173: U103.45 v3(140.26,103.1)
  L3_SIG1 w0.109: v3(140.26,103.1) v5(139.57,103.1)
  L10_SIG4 w0.109: v5(139.57,103.1) 140.99,103.1 141.53,102.57 141.53,100.41 143.97,97.97 143.97,96.95 144.46,96.46 144.46,96.28 143.86,95.67 143.86,95.49 143.98,95.36 144.17,95.36 144.77,95.97 144.95,95.97 145.08,95.84 145.08,95.66 144.4,94.97 144.4,94.82 144.53,94.69 144.73,94.69 145.39,95.35 145.57,95.35 145.7,95.22 145.7,95.04 145.07,94.41 145.07,94.23 145.2,94.1 145.38,94.1 146.01,94.73 146.19,94.73 147.83,93.09 v7(148.97,93.09)
  BOTTOM w0.173: U89.J2 151.72,93.38 149.89,93.38 149.61,93.09 v7(148.97,93.09)
LCD_B3: length 24.4
  TOP w0.173: U103.43 v3(140.26,102.1)
  L3_SIG1 w0.109: v3(140.26,102.1) v5(140.94,102.1)
  L10_SIG4 w0.109: v5(140.94,102.1) 140.94,101.49 140.82,101.37 140.39,101.37 140.26,101.24 140.26,101.06 140.39,100.93 140.82,100.93 140.94,100.8 140.94,100.43 143.51,97.87 143.51,94.79 145.06,93.24 145.24,93.24 145.53,93.53 145.71,93.53 145.84,93.41 145.84,93.22 145.55,92.94 145.55,92.75 145.89,92.41 146.19,92.41 146.32,92.54 146.32,92.84 146.44,92.96 146.62,92.96 146.75,92.84 146.75,92.54 146.88,92.41 147.12,92.41 147.29,92.58 147.29,92.99 v7(146.56,93.73)
  BOTTOM w0.173: v7(146.56,93.73) 146.59,93.69 U89.K2
LCD_B4: length 32.5
  TOP w0.173: U103.32 v3(140.26,96.6)
  L3_SIG1 w0.109: v3(140.26,96.6) v5(139.57,96.6)
  L10_SIG4 w0.109: v7(149.23,90.17) 148.51,89.46 148.04,89.46 147.91,89.33 147.91,89.03 147.78,88.9 147.6,88.9 147.48,89.03 147.48,89.33 147.35,89.46 147.17,89.46 147.04,89.33 147.04,89.03 146.91,88.9 146.73,88.9 146.6,89.03 146.6,89.33 146.47,89.46 146.29,89.46 146.17,89.33 146.17,89.03 146.04,88.9 145.86,88.9 145.73,89.03 145.73,89.33 145.6,89.46 145.34,89.46 145.19,89.61 145.01,89.61 144.76,89.36 144.57,89.36 144.45,89.49 144.45,89.67 144.7,89.92 144.7,90.1 144.57,90.23 144.39,90.23 144.14,89.98 143.96,89.98 143.83,90.11 143.83,90.29 144.08,90.54 144.08,90.72 143.95,90.85 143.77,90.85 143.52,90.6 143.34,90.6 143.21,90.72 143.21,90.91 143.46,91.16 143.46,91.34 143.33,91.47 143.15,91.47 142.9,91.21 142.72,91.21 142.59,91.34 142.59,91.52 142.84,91.77 142.84,91.96 142.71,92.08 142.53,92.08 142.28,91.83 142.1,91.83 141.97,91.96 141.97,92.14 142.22,92.39 142.22,92.57 142.1,92.7 141.91,92.7 141.66,92.45 141.48,92.45 141.35,92.58 141.35,92.76 141.61,93.01 141.61,93.19 141.38,93.42 141.38,93.62 141.25,93.75 140.31,93.75 140.18,93.88 140.18,94.06 140.31,94.19 141.25,94.19 141.38,94.32 141.38,94.5 141.25,94.63 140.31,94.63 140.18,94.75 140.18,94.93 140.31,95.06 141.25,95.06 141.38,95.19 141.38,95.78 140.56,96.6 v5(139.57,96.6)
  BOTTOM w0.173: v7(149.23,90.17) 149.23,90.24 U89.J1
LCD_B5: length 26.5
  TOP w0.173: U103.47 v3(140.26,104.1)
  L3_SIG1 w0.109: v3(140.26,104.1) v5(140.94,104.1)
  L10_SIG4 w0.109: v5(140.94,104.1) 141.74,104.1 142.85,103 142.85,102.09 142.72,101.96 142.29,101.96 142.16,101.83 142.16,101.65 142.29,101.53 142.72,101.53 142.85,101.4 142.85,101.22 142.72,101.09 142.29,101.09 142.16,100.96 142.16,100.78 142.29,100.65 142.72,100.65 142.85,100.52 142.85,99.77 144.4,98.22 144.4,97.89 144.7,97.59 144.7,97.4 144.48,97.18 144.48,97 144.61,96.87 144.79,96.87 145.01,97.1 145.19,97.1 145.32,96.97 145.32,96.79 145.1,96.56 145.1,96.38 145.23,96.25 145.41,96.25 145.63,96.48 145.81,96.48 145.94,96.35 145.94,96.17 145.72,95.94 145.72,95.76 145.84,95.63 146.02,95.63 146.25,95.86 146.43,95.86 146.56,95.73 146.56,95.55 146.33,95.32 146.33,95.14 146.46,95.02 146.64,95.02 146.87,95.24 147.05,95.24 147.37,94.92 148.16,94.92 148.37,94.71 148.37,94.53 147.86,94.03 147.86,93.85 147.99,93.72 148.17,93.72 148.68,94.22 148.86,94.22 v7(150.24,92.84)
  BOTTOM w0.173: U89.K1 151.18,92.84 v7(150.24,92.84)
LCD_B6: length 25.4
  TOP w0.173: U103.50 v3(140.03,105.6)
  L3_SIG1 w0.109: v3(140.03,105.6) 142.12,105.6 v5(144.63,103.1)
  L10_SIG4 w0.109: v5(144.63,103.1) 145.57,103.1 147.5,101.17 147.5,100.05 147.37,99.93 147.04,99.93 146.91,99.8 146.91,99.62 147.04,99.49 147.37,99.49 147.5,99.36 147.5,99.18 147.37,99.05 147.04,99.05 146.91,98.92 146.91,98.74 147.04,98.62 147.37,98.62 147.5,98.49 147.5,96.19 149.46,94.23 151.89,94.23 152.24,94.59 152.86,94.59 153.43,94.02 v7(153.66,94.02)
  BOTTOM w0.173: v7(153.66,94.02) U89.G2
LCD_B7: length 30.1
  TOP w0.173: U103.41 v3(140.26,101.1)
  L3_SIG1 w0.109: v3(140.26,101.1) v5(139.57,101.1)
  L10_SIG4 w0.109: v7(152.91,92.08) 145.62,92.08 142.93,94.77 142.93,97.84 140.96,99.81 140.94,99.81 140.69,100.07 139.95,100.07 139.5,100.51 139.07,100.51 138.61,100.05 136.12,100.05 135.86,100.3 135.86,100.81 136.16,101.1 v5(139.57,101.1)
  BOTTOM w0.173: U89.G1 153.33,92.5 v7(152.91,92.08)
LCD_CLKN: length 164.7
  L10_SIG4 w0.083: v7(154.52,100.05) 154.51,100.05 154.3,100.27 154.3,109.01 158.83,113.54 158.83,122.33 159.81,123.32 159.81,131.61 152.2,139.22 145.73,139.22 144.87,140.09 132.18,140.09 131.17,141.1 123.14,141.1 120.61,143.63 118.22,143.63 117.95,143.36 117.95,142.74 117.85,142.65 117.71,142.65 117.61,142.74 117.61,143.36 117.34,143.63 98.99,143.63 98.15,142.8 90.85,142.8 88.49,140.44 88.49,137.24 87.76,136.5 86.46,136.5 v7(86.3,136.66)
  BOTTOM w0.108: v7(154.52,100.05) 153.98,99.51 U89.F10 ; v7(86.3,136.66) 86.12,136.48 81.16,136.48 80.53,135.85 80.53,135.49 80.98,135.04 80.98,134.89 80.82,134.73 80.67,134.73 80.22,135.18 79.86,135.18 79.56,134.88 79.56,134.52 80.01,134.07 80.01,133.91 79.85,133.76 79.7,133.76 79.25,134.21 78.89,134.21 78.58,133.91 78.58,133.55 79.04,133.1 79.04,132.94 78.88,132.79 78.73,132.79 78.28,133.24 77.91,133.24 77.61,132.94 77.61,132.58 78.06,132.12 78.06,131.97 77.91,131.82 77.76,131.82 77.31,132.27 76.94,132.27 76.64,131.97 76.64,131.6 77.09,131.15 77.09,131 76.94,130.85 76.79,130.85 76.34,131.3 75.97,131.3 75.18,130.51 75.18,129.03 75.44,128.77 76.47,128.77 76.58,128.66 76.58,128.44 76.47,128.34 75.44,128.34 75.18,128.08 75.18,127.65 75.44,127.4 76.47,127.4 76.58,127.29 76.58,127.07 76.47,126.97 75.44,126.97 75.18,126.71 75.18,126.28 75.44,126.03 76.47,126.03 76.58,125.92 76.58,125.7 76.47,125.59 75.44,125.59 75.18,125.34 75.18,124.69 76.35,123.53 76.96,123.53 R632.1 77.73,123.53 83.69,123.53 83.82,123.4 J16.20
LCD_CLKP: length 164.8
  L10_SIG4 w0.083: v7(86.3,136.05) 86.45,136.2 87.88,136.2 88.8,137.11 88.8,140.31 90.98,142.49 98.28,142.49 99.12,143.33 117.21,143.33 117.31,143.23 117.31,142.62 117.59,142.34 117.97,142.34 118.25,142.62 118.25,143.23 118.35,143.33 120.48,143.33 123.02,140.8 131.04,140.8 132.06,139.78 144.74,139.78 145.61,138.92 152.07,138.92 159.51,131.48 159.51,123.45 158.52,122.46 158.52,113.66 154,109.14 154,100.14 v7(153.91,100.05)
  BOTTOM w0.108: J16.21 83.79,123.9 83.67,123.78 77.72,123.78 R632.2 76.96,123.78 76.45,123.78 75.44,124.8 75.44,125.23 75.55,125.34 76.58,125.34 76.83,125.6 76.83,126.02 76.58,126.28 75.55,126.28 75.44,126.39 75.44,126.6 75.55,126.71 76.58,126.71 76.83,126.97 76.83,127.39 76.58,127.65 75.55,127.65 75.44,127.76 75.44,127.97 75.55,128.08 76.58,128.08 76.83,128.34 76.83,128.77 76.58,129.02 75.55,129.02 75.44,129.13 75.44,130.4 76.08,131.04 76.23,131.04 76.68,130.59 77.04,130.59 77.35,130.9 77.35,131.26 76.9,131.71 76.9,131.86 77.05,132.02 77.2,132.02 77.65,131.56 78.02,131.56 78.32,131.87 78.32,132.23 77.87,132.68 77.87,132.83 78.02,132.99 78.17,132.99 78.62,132.53 78.99,132.53 79.29,132.84 79.29,133.2 78.84,133.65 78.84,133.81 78.99,133.96 79.14,133.96 79.6,133.51 79.96,133.51 80.26,133.81 80.26,134.17 79.81,134.62 79.81,134.78 79.96,134.93 80.12,134.93 80.57,134.48 80.93,134.48 81.23,134.78 81.23,135.14 80.78,135.59 80.78,135.75 81.26,136.23 82.15,136.23 82.26,136.12 82.26,135.8 82.37,135.69 82.58,135.69 82.69,135.8 82.69,136.12 82.8,136.23 86.12,136.23 v7(86.3,136.05) ; v7(153.91,100.05) 153.73,99.87 153.73,99.08 153.66,99.01 153.66,98.56 U89.F9
LCD_DEN: length 54.3
  TOP w0.173: R634.1 121.37,87.25 v3(121.52,87.1)
  L3_SIG1 w0.109: v3(121.52,87.1) 121.56,87.1 v5(122.05,87.58)
  L10_SIG4 w0.109: v7(138.56,102.23) 132.23,102.23 131.61,101.61 131.42,101.61 131.05,101.99 130.86,101.99 130.74,101.86 130.74,101.68 131.12,101.3 131.12,101.12 130.99,100.99 130.81,100.99 130.43,101.37 130.25,101.37 130.12,101.24 130.12,101.06 130.5,100.68 130.5,100.5 130.37,100.37 130.19,100.37 129.81,100.75 129.63,100.75 129.5,100.62 129.5,100.44 129.88,100.07 129.88,99.88 129.75,99.76 129.57,99.76 129.19,100.13 129.01,100.13 128.88,100.01 128.88,99.83 129.26,99.45 129.26,99.27 129.13,99.14 128.95,99.14 128.57,99.52 128.39,99.52 128.27,99.39 128.27,99.21 128.65,98.83 128.65,98.65 128.52,98.52 128.34,98.52 127.96,98.9 127.78,98.9 127.65,98.77 127.65,98.59 128.03,98.21 128.03,98.03 127.9,97.9 127.72,97.9 127.34,98.28 127.16,98.28 127.03,98.15 127.03,97.97 127.41,97.59 127.41,97.41 127.28,97.28 127.1,97.28 126.72,97.66 126.54,97.66 126.41,97.53 126.41,97.35 126.79,96.97 126.79,96.79 126.66,96.66 126.48,96.66 126.1,97.04 125.92,97.04 125.8,96.92 125.8,96.73 126.17,96.36 126.17,96.17 125.4,95.4 125.4,90.37 122.61,87.58 v5(122.05,87.58)
  BOTTOM w0.173: v7(138.56,102.23) 139.85,100.94 144.48,100.94 147.5,97.92 148.72,97.92 149.38,97.25 151.72,97.25 U89.J7
LCD_G0: length 31.7
  TOP w0.173: U103.36 v3(140.26,98.6)
  L3_SIG1 w0.109: v3(140.26,98.6) v5(139.57,98.6)
  L10_SIG4 w0.109: v5(139.57,98.6) 138.84,99.34 137.36,99.34 136.86,98.83 136.86,98.02 137.28,97.59 137.71,97.59 137.84,97.72 137.84,98.12 137.97,98.25 138.15,98.25 138.28,98.12 138.28,97.72 138.41,97.59 138.59,97.59 138.71,97.72 138.71,98.12 138.84,98.25 139.02,98.25 139.15,98.12 139.15,97.72 139.28,97.59 140.19,97.59 140.64,98.04 141.23,98.04 142.14,97.13 142.14,94.46 145.42,91.19 v7(151.77,91.19)
  BOTTOM w0.173: v7(151.77,91.19) 152.7,91.19 153.64,92.13 153.64,93.35 U89.F2
LCD_G1: length 34.2
  TOP w0.173: U103.30 v3(140.26,95.6)
  L3_SIG1 w0.109: v3(140.26,95.6) v5(140.94,95.6)
  L10_SIG4 w0.109: v5(140.94,95.6) 139.6,95.6 139.01,95.02 137.54,95.02 136.91,94.39 136.91,93.09 137.45,92.55 137.74,92.55 137.87,92.67 137.87,93.37 137.99,93.5 138.17,93.5 138.3,93.37 138.3,92.67 138.43,92.55 138.61,92.55 138.74,92.67 138.74,93.37 138.87,93.5 139.05,93.5 139.18,93.37 139.18,92.67 139.3,92.55 139.48,92.55 139.61,92.67 139.61,93.37 139.74,93.5 139.92,93.5 140.05,93.37 140.05,92.67 140.18,92.55 140.91,92.55 144.91,88.54 149,88.54 v7(150.11,89.66)
  BOTTOM w0.173: U89.F1 153.98,91.9 152.5,90.42 150.88,90.42 v7(150.11,89.66)
LCD_G2: length 32.1
  TOP w0.173: U103.39 v3(139.98,100.1)
  L3_SIG1 w0.109: v5(139.32,100.08) 139.35,100.1 v3(139.98,100.1)
  L10_SIG4 w0.109: v7(154.05,91.27) 154.61,91.83 154.61,92.35 154.94,92.68 155.63,92.68 155.91,92.41 155.91,92.12 155.78,92 155.47,92 155.35,91.87 155.35,91.69 155.47,91.56 155.78,91.56 155.91,91.43 155.91,91.19 155.35,90.63 153,90.63 151.94,91.69 145.52,91.69 142.54,94.67 142.54,97.26 140.82,98.98 140.41,98.98 v5(139.32,100.08)
  BOTTOM w0.173: v7(154.05,91.27) 154.32,91.53 154.32,93.38 U89.E2
LCD_G3: length 33.5
  TOP w0.173: U103.34 v3(140.26,97.6)
  L3_SIG1 w0.109: v3(140.26,97.6) v5(140.94,97.6)
  L10_SIG4 w0.109: v7(151.89,89.92) 151.89,89.18 151.26,88.54 150.83,88.54 150.55,88.82 150.55,90.04 149.91,90.68 148.34,90.68 148.21,90.55 148.21,89.94 148.08,89.81 147.9,89.81 147.77,89.94 147.77,90.55 147.65,90.68 147.47,90.68 147.34,90.55 147.34,89.94 147.21,89.81 147.03,89.81 146.9,89.94 146.9,90.55 146.77,90.68 146.59,90.68 146.46,90.55 146.46,89.94 146.34,89.81 146.15,89.81 146.03,89.94 146.03,90.55 145.9,90.68 145.36,90.68 145.16,90.89 144.98,90.89 144.75,90.66 144.57,90.66 144.44,90.79 144.44,90.97 144.67,91.19 144.67,91.38 144.54,91.5 144.36,91.5 144.13,91.28 143.95,91.28 143.82,91.41 143.82,91.59 144.05,91.81 144.05,91.99 143.92,92.12 143.74,92.12 143.51,91.9 143.33,91.9 143.2,92.02 143.2,92.21 143.43,92.43 143.43,92.61 143.3,92.74 143.12,92.74 142.9,92.51 142.71,92.51 142.59,92.64 142.59,92.82 142.81,93.05 142.81,93.23 142.68,93.36 142.5,93.36 142.28,93.13 142.1,93.13 141.97,93.26 141.97,93.44 142.19,93.67 142.19,93.85 141.76,94.28 141.76,95.88 140.94,96.7 v5(140.94,97.6)
  BOTTOM w0.173: U89.E1 154.63,91.21 154.14,90.72 153.84,90.72 153.04,89.92 v7(151.89,89.92)
LCD_G4: length 36.9
  TOP w0.173: U102.47 v3(140.26,88.61)
  L3_SIG1 w0.109: v3(140.26,88.61) v5(140.94,88.61)
  L10_SIG4 w0.109: v7(154.05,87.63) 154.05,86.49 153.44,85.88 153.31,85.88 153.18,85.75 153.18,85.52 153.06,85.39 152.87,85.39 152.75,85.52 152.75,85.75 152.62,85.88 152.44,85.88 152.31,85.75 152.31,85.52 152.18,85.39 152,85.39 151.87,85.52 151.87,85.75 151.75,85.88 151.56,85.88 151.44,85.75 151.44,85.52 151.31,85.39 151.13,85.39 151,85.52 151,85.75 150.87,85.88 150.69,85.88 150.56,85.75 150.56,85.52 150.43,85.39 150.25,85.39 150.13,85.52 150.13,85.75 150,85.88 149.82,85.88 149.69,85.75 149.69,85.52 149.56,85.39 149.38,85.39 149.25,85.52 149.25,85.75 149.12,85.88 148.94,85.88 148.82,85.75 148.82,85.52 148.69,85.39 148.51,85.39 148.38,85.52 148.38,85.75 148.25,85.88 148.07,85.88 147.94,85.75 147.94,85.52 147.81,85.39 147.63,85.39 147.5,85.52 147.5,85.75 147.38,85.88 147.2,85.88 147.07,85.75 147.07,85.52 146.94,85.39 146.76,85.39 146.63,85.52 146.63,85.75 146.5,85.88 146.32,85.88 146.19,85.75 146.19,85.52 146.07,85.39 145.88,85.39 145.76,85.52 145.76,85.75 145.63,85.88 145.45,85.88 145.32,85.75 145.32,85.52 145.19,85.39 145.01,85.39 144.88,85.52 144.88,85.75 144.76,85.88 144.57,85.88 144.45,85.75 144.45,85.52 144.32,85.39 144.14,85.39 144.01,85.52 144.01,85.75 143.88,85.88 143.68,85.88 143.46,86.1 143.28,86.1 143.07,85.89 142.89,85.89 142.76,86.02 142.76,86.2 142.97,86.4 142.97,86.59 142.84,86.71 142.66,86.71 142.45,86.51 142.27,86.51 142.14,86.63 142.14,86.82 142.35,87.02 142.35,87.2 142.22,87.33 142.04,87.33 141.83,87.12 141.65,87.12 141.52,87.25 141.52,87.43 141.73,87.64 141.73,87.82 141.48,88.07 139.97,88.07 139.75,88.29 139.75,88.8 139.95,89 140.55,89 v5(140.94,88.61)
  BOTTOM w0.173: v7(154.05,87.63) 154.05,90.04 154.94,90.93 154.94,93.35 U89.D2
LCD_G5: length 35.6
  TOP w0.173: U102.54 v3(140.26,92.11)
  L3_SIG1 w0.109: v3(140.26,92.11) v5(139.57,92.11)
  L10_SIG4 w0.109: v5(139.57,92.11) 140.66,92.11 144.68,88.09 145.39,88.09 145.52,87.96 145.52,87.43 145.64,87.3 145.82,87.3 145.95,87.43 145.95,87.96 146.08,88.09 146.26,88.09 146.39,87.96 146.39,87.43 146.52,87.3 146.7,87.3 146.83,87.43 146.83,87.96 146.95,88.09 147.13,88.09 147.26,87.96 147.26,87.43 147.39,87.3 147.57,87.3 147.7,87.43 147.7,87.96 147.83,88.09 148.01,88.09 148.14,87.96 148.14,87.43 148.26,87.3 148.45,87.3 148.57,87.43 148.57,87.96 148.7,88.09 148.88,88.09 149.01,87.96 149.01,87.43 149.14,87.3 149.32,87.3 149.45,87.43 149.45,87.96 149.58,88.09 149.76,88.09 149.88,87.96 149.88,87.43 150.01,87.3 150.19,87.3 150.32,87.43 150.32,87.96 150.45,88.09 150.63,88.09 150.76,87.96 150.76,87.43 150.89,87.3 151.07,87.3 151.19,87.43 151.19,87.96 151.31,88.08 151.49,88.08 151.82,87.74 152,87.74 152.13,87.87 152.13,88.05 151.8,88.38 151.8,88.57 151.93,88.69 152.11,88.69 152.44,88.36 152.62,88.36 152.75,88.49 152.75,88.67 152.42,89 152.42,89.18 152.55,89.31 152.73,89.31 153.06,88.98 153.24,88.98 153.37,89.11 153.37,89.29 153.04,89.62 153.04,89.8 153.53,90.3 154.31,90.3 v7(154.69,89.92)
  BOTTOM w0.173: U89.D1 155.28,90.51 v7(154.69,89.92)
LCD_G6: length 36.7
  TOP w0.173: U102.50 v3(140,90.11)
  L3_SIG1 w0.109: v3(140,90.11) v5(139.32,90.11)
  L10_SIG4 w0.109: v5(139.32,90.11) 138.09,91.34 137.06,91.34 136.7,90.98 136.7,90.55 136.83,90.42 137.59,90.42 137.72,90.29 137.72,90.11 137.59,89.98 136.83,89.98 136.7,89.85 136.7,89.03 137.31,88.42 138.61,88.42 140.28,90.09 140.72,90.09 144.35,86.46 152.1,86.46 153.9,88.27 v7(154.94,88.27)
  BOTTOM w0.173: v7(154.94,88.27) 154.94,89.15 155.83,90.04 155.83,91.57 155.59,91.8 155.59,93.15 155.93,93.48 U89.C2
LCD_G7: length 36.2
  TOP w0.173: U102.52 v3(140.26,91.11)
  L3_SIG1 w0.109: v3(140.26,91.11) v5(140.94,91.11)
  L10_SIG4 w0.109: v7(156.34,90.42) 156.34,90.91 156.74,91.31 158.55,91.31 158.88,90.98 158.88,90.62 158.75,90.49 158.14,90.49 158.01,90.36 158.01,90.18 158.14,90.05 158.75,90.05 158.88,89.93 158.88,89.74 158.75,89.62 158.14,89.62 158.01,89.49 158.01,89.31 158.14,89.18 158.75,89.18 158.88,89.05 158.88,88.75 158.01,87.88 157.3,87.88 157.17,88.01 157.17,88.7 157.05,88.82 156.87,88.82 156.74,88.7 156.74,88.01 156.61,87.88 156.18,87.88 155.04,89.03 153.8,89.03 151.71,86.94 145.11,86.94 v5(140.94,91.11)
  BOTTOM w0.173: U89.C1 155.93,92.1 156.34,91.69 v7(156.34,90.42)
LCD_HS: length 48.5
  TOP w0.173: 124.59,86.31 v3(125.35,86.31)
  L3_SIG1 w0.109: v3(125.35,86.31) 125.73,86.31 v5(126.01,86.03)
  L10_SIG4 w0.109: v7(139.83,102.23) 139.19,101.6 133.45,101.6 131.33,99.48 131.15,99.48 130.86,99.77 130.68,99.77 130.55,99.64 130.55,99.46 130.84,99.17 130.84,98.99 130.72,98.86 130.53,98.86 130.25,99.15 130.07,99.15 129.94,99.02 129.94,98.84 130.23,98.55 130.23,98.37 130.1,98.25 129.92,98.25 129.63,98.53 129.45,98.53 129.32,98.41 129.32,98.23 129.61,97.94 129.61,97.76 129.48,97.63 129.3,97.63 129.01,97.92 128.83,97.92 128.7,97.79 128.7,97.61 128.99,97.32 128.99,97.14 128.86,97.01 128.68,97.01 128.39,97.3 128.21,97.3 128.08,97.17 128.08,96.99 128.37,96.7 128.37,96.52 128.24,96.39 128.06,96.39 127.77,96.68 127.59,96.68 127.46,96.55 127.46,96.37 127.75,96.08 127.75,95.9 127.62,95.77 127.44,95.77 127.15,96.06 126.97,96.06 126.85,95.93 126.85,95.75 127.13,95.46 127.13,95.28 127.01,95.15 126.83,95.15 126.54,95.44 126.36,95.44 126.23,95.32 126.23,95.13 126.52,94.85 126.52,94.66 126.01,94.16 v5(126.01,86.03)
  BOTTOM w0.173: v7(139.83,102.23) 144.53,102.23 147.96,98.81 149.03,98.81 150.24,97.59 U89.K8
LCD_MIPI0N: length 164.9
  L10_SIG4 w0.083: v7(152.21,100.31) 152.07,100.44 152.07,102.54 151.64,102.97 151.64,109.3 151.36,109.57 150.77,109.57 150.67,109.67 150.67,109.8 150.77,109.9 151.36,109.9 151.64,110.18 151.64,110.64 157.04,116.03 157.04,123.97 157.61,124.54 157.61,131.22 151.44,137.39 144.17,137.39 143.8,137.76 134.1,137.76 133.04,136.71 124.46,136.71 124.19,136.45 124.19,135.44 124.11,135.36 123.95,135.36 123.86,135.44 123.86,136.45 123.6,136.71 123.19,136.71 122.92,136.45 122.92,135.44 122.84,135.36 122.68,135.36 122.59,135.44 122.59,136.45 122.33,136.71 121.92,136.71 121.65,136.45 121.65,135.44 121.57,135.36 121.41,135.36 121.32,135.44 121.32,136.45 121.06,136.71 120.65,136.71 120.38,136.45 120.38,135.44 120.3,135.36 120.14,135.36 120.05,135.44 120.05,136.45 119.79,136.71 118.1,136.71 118.01,136.79 118.01,137.77 117.75,138.03 117.34,138.03 117.07,137.77 117.07,136.79 116.99,136.71 116.83,136.71 116.74,136.79 116.74,137.77 116.48,138.03 116.07,138.03 115.8,137.77 115.8,136.79 115.72,136.71 115.56,136.71 115.47,136.79 115.47,137.77 115.21,138.03 114.8,138.03 114.53,137.77 114.53,136.79 114.45,136.71 114.29,136.71 114.2,136.79 114.2,137.77 113.94,138.03 113.53,138.03 113.26,137.77 113.26,136.79 113.18,136.71 112.41,136.71 110.58,138.54 99.89,138.54 98.27,140.16 94.95,140.16 93.29,138.51 91.62,138.51 v7(91.49,138.64)
  BOTTOM w0.108: v7(152.21,100.31) 152.03,100.13 U89.J10 ; v7(91.49,138.64) 91.31,138.46 81.87,138.46 74.3,130.89 74.3,123.67 75.97,122 78.23,122 R630.2 79.02,122.03 83.69,122.03 83.81,121.9 J16.17
LCD_MIPI0P: length 164.8
  L10_SIG4 w0.083: v7(151.6,100.31) 151.77,100.47 151.77,102.41 151.33,102.84 151.33,109.17 151.24,109.27 150.64,109.27 150.37,109.54 150.37,109.93 150.64,110.21 151.24,110.21 151.33,110.3 151.33,110.76 156.73,116.16 156.73,124.1 157.3,124.67 157.3,131.09 151.31,137.09 144.04,137.09 143.67,137.46 134.22,137.46 133.17,136.4 124.58,136.4 124.5,136.32 124.5,135.32 124.24,135.06 123.82,135.06 123.56,135.32 123.56,136.32 123.48,136.4 123.31,136.4 123.23,136.32 123.23,135.32 122.97,135.06 122.55,135.06 122.29,135.32 122.29,136.32 122.21,136.4 122.04,136.4 121.96,136.32 121.96,135.32 121.7,135.06 121.28,135.06 121.02,135.32 121.02,136.32 120.94,136.4 120.77,136.4 120.69,136.32 120.69,135.32 120.43,135.06 120.01,135.06 119.75,135.32 119.75,136.32 119.67,136.4 117.97,136.4 117.71,136.66 117.71,137.64 117.63,137.72 117.46,137.72 117.38,137.64 117.38,136.66 117.12,136.4 116.7,136.4 116.44,136.66 116.44,137.64 116.36,137.72 116.19,137.72 116.11,137.64 116.11,136.66 115.85,136.4 115.43,136.4 115.17,136.66 115.17,137.64 115.09,137.72 114.92,137.72 114.84,137.64 114.84,136.66 114.58,136.4 114.16,136.4 113.9,136.66 113.9,137.64 113.82,137.72 113.65,137.72 113.57,137.64 113.57,136.66 113.31,136.4 112.29,136.4 110.45,138.24 99.76,138.24 98.14,139.86 95.07,139.86 93.42,138.21 91.67,138.21 v7(91.49,138.03)
  BOTTOM w0.108: J16.18 83.82,122.4 83.7,122.28 78.96,122.28 R630.1 78.23,122.26 76.07,122.26 74.55,123.78 74.55,130.79 81.97,138.21 83.73,138.21 83.83,138.1 83.83,137.93 83.94,137.83 84.16,137.83 84.26,137.93 84.26,138.1 84.37,138.21 91.31,138.21 v7(91.49,138.03) ; U89.J9 151.71,98.56 151.71,99.01 151.78,99.08 151.78,100.13 v7(151.6,100.31)
LCD_MIPI1N: length 165.3
  L10_SIG4 w0.083: v7(153.51,100.94) 153.29,101.16 153.29,110.37 153.77,110.85 153.9,110.85 154.15,110.6 154.54,110.6 154.82,110.88 154.82,111.27 154.57,111.52 154.57,111.65 154.67,111.75 154.8,111.75 155.05,111.5 155.44,111.5 155.72,111.78 155.72,112.17 155.47,112.42 155.47,112.55 155.56,112.65 155.7,112.65 155.95,112.4 156.34,112.4 156.62,112.68 156.62,113.06 156.37,113.32 156.37,113.45 157.93,115.02 157.93,122.7 158.92,123.69 158.92,131.23 151.84,138.31 144.52,138.31 144.12,138.71 133.67,138.71 132.66,137.7 128.3,137.7 128.22,137.78 128.22,139.06 127.95,139.32 127.54,139.32 127.28,139.06 127.28,137.78 127.19,137.7 127.03,137.7 126.95,137.78 126.95,139.06 126.68,139.32 126.27,139.32 126.01,139.06 126.01,137.78 125.92,137.7 125.76,137.7 125.68,137.78 125.68,139.06 125.41,139.32 125,139.32 124.74,139.06 124.74,137.78 124.65,137.7 124.49,137.7 124.41,137.78 124.41,139.06 124.14,139.32 123.73,139.32 123.47,139.06 123.47,137.78 123.38,137.7 119.94,137.7 116.09,141.54 103.11,141.54 102.68,141.97 99.7,141.97 99,141.28 93.44,141.28 92.51,140.34 91.59,140.34 91.58,140.33 v7(91.49,140.42)
  BOTTOM w0.108: v7(91.49,140.42) 91.31,140.24 82.38,140.24 73.41,131.27 73.41,122.78 75.71,120.48 76.96,120.48 R631.2 77.78,120.53 83.69,120.53 83.82,120.4 J16.14 ; v7(153.51,100.94) 153.33,100.77 U89.G10
LCD_MIPI1P: length 165.2
  L10_SIG4 w0.083: v7(152.9,100.94) 152.9,101.27 152.98,101.35 152.98,110.5 153.64,111.16 154.03,111.16 154.28,110.91 154.42,110.91 154.51,111 154.51,111.14 154.26,111.39 154.26,111.78 154.54,112.06 154.93,112.06 155.18,111.8 155.32,111.8 155.41,111.9 155.41,112.04 155.16,112.29 155.16,112.68 155.44,112.96 155.83,112.96 156.08,112.7 156.21,112.7 156.31,112.8 156.31,112.94 156.06,113.19 156.06,113.58 157.63,115.14 157.63,122.83 158.61,123.82 158.61,131.1 151.71,138 144.39,138 143.99,138.4 133.8,138.4 132.79,137.39 128.17,137.39 127.91,137.65 127.91,138.94 127.83,139.02 127.66,139.02 127.58,138.94 127.58,137.65 127.32,137.39 126.9,137.39 126.64,137.65 126.64,138.94 126.56,139.02 126.39,139.02 126.31,138.94 126.31,137.65 126.05,137.39 125.63,137.39 125.37,137.65 125.37,138.94 125.29,139.02 125.12,139.02 125.04,138.94 125.04,137.65 124.78,137.39 124.36,137.39 124.1,137.65 124.1,138.94 124.02,139.02 123.85,139.02 123.77,138.94 123.77,137.65 123.51,137.39 119.81,137.39 115.97,141.24 102.98,141.24 102.55,141.67 99.82,141.67 99.12,140.97 93.57,140.97 92.63,140.04 91.72,140.04 v7(91.49,139.81)
  BOTTOM w0.108: J16.15 83.79,120.9 83.67,120.78 77.67,120.78 R631.1 76.96,120.73 75.82,120.73 73.66,122.89 73.66,131.17 82.48,139.99 83.71,139.99 83.82,139.88 83.82,139.71 83.92,139.6 84.14,139.6 84.25,139.71 84.25,139.88 84.36,139.99 91.31,139.99 v7(91.49,139.81) ; U89.G9 153.01,98.56 153.01,99.01 153.08,99.08 153.08,100.77 v7(152.9,100.94)
LCD_MIPI2N: length 165.2
  L10_SIG4 w0.083: v7(87.91,142.17) 88.04,142.03 88.79,142.03 90.47,143.72 97.73,143.72 98.89,144.88 123.25,144.88 123.85,144.27 125.68,144.27 125.91,144.5 141.7,144.5 141.93,144.27 150.27,144.27 151.69,142.85 151.69,141 160.71,131.98 160.71,119.18 160.28,118.75 160.28,117.83 161.19,116.92 161.19,114.53 158.98,112.32 158.98,111.89 158.7,111.62 158.26,111.62 158.17,111.52 158.17,111.39 158.26,111.29 158.7,111.29 158.98,111.01 158.98,110.27 158.62,109.9 158.62,109.79 159.02,109.38 159.02,109.01 158.73,108.72 158.36,108.72 157.95,109.12 157.83,109.12 157.72,109.01 157.72,108.89 158.12,108.48 158.12,108.11 157.83,107.82 157.46,107.82 157.05,108.22 156.94,108.22 156.82,108.11 156.82,107.99 157.22,107.58 157.22,107.22 156.93,106.92 156.56,106.92 156.15,107.32 156.04,107.32 155.85,107.14 155.85,102.18 155.32,101.65 155.32,101.08 v7(155.46,100.94)
  BOTTOM w0.108: v7(155.46,100.94) 155.28,100.77 U89.D10 ; J16.11 84.07,118.9 84.07,118.91 83.82,118.91 83.69,119.03 79.07,119.03 R633.1 78.23,118.95 75.46,118.95 72.52,121.9 72.52,131.65 82.85,141.99 87.73,141.99 v7(87.91,142.17)
LCD_MIPI2P: length 165.2
  L10_SIG4 w0.083: v7(154.85,100.94) 155.02,101.11 155.02,101.78 155.55,102.31 155.55,107.27 155.91,107.63 156.28,107.63 156.68,107.22 156.8,107.22 156.92,107.34 156.92,107.46 156.51,107.86 156.51,108.23 156.81,108.53 157.18,108.53 157.58,108.12 157.7,108.12 157.82,108.24 157.82,108.36 157.41,108.76 157.41,109.13 157.71,109.43 158.08,109.43 158.48,109.02 158.6,109.02 158.72,109.14 158.72,109.26 158.31,109.66 158.31,110.03 158.67,110.39 158.67,110.89 158.58,110.98 158.14,110.98 157.86,111.26 157.86,111.65 158.14,111.92 158.58,111.92 158.67,112.02 158.67,112.45 160.88,114.66 160.88,116.79 159.98,117.7 159.98,118.88 160.4,119.3 160.4,131.85 151.38,140.87 151.38,142.72 150.14,143.97 141.81,143.97 141.58,144.2 126.03,144.2 125.81,143.97 123.72,143.97 123.12,144.57 99.02,144.57 97.86,143.41 90.6,143.41 88.92,141.73 88.08,141.73 v7(87.91,141.56)
  BOTTOM w0.108: J16.12 83.79,119.4 83.67,119.28 78.92,119.28 R633.2 78.23,119.21 75.56,119.21 72.77,122 72.77,131.55 82.96,141.74 84.84,141.74 84.95,141.63 84.95,141.46 85.05,141.36 85.27,141.36 85.38,141.46 85.38,141.63 85.48,141.74 87.73,141.74 v7(87.91,141.56) ; v7(154.85,100.94) 155.03,100.77 155.03,99.08 154.96,99.01 154.96,98.56 U89.D9
LCD_MIPI3N: length 165.3
  L10_SIG4 w0.083: v7(156.47,100.05) 156.32,100.21 156.32,100.56 157.53,101.78 157.53,105.11 160.05,107.63 160.19,107.63 160.39,107.44 160.78,107.44 161.05,107.71 161.05,108.1 160.86,108.3 160.86,108.44 162.26,109.83 162.26,117.9 161.67,118.49 161.67,132.29 153.16,140.8 153.16,142.77 150.74,145.19 142.31,145.19 141.72,145.79 98.29,145.79 97.65,145.14 88.45,145.14 87.28,143.97 86.64,143.97 v7(86.49,144.12)
  BOTTOM w0.108: J16.8 83.82,117.4 83.69,117.53 77.7,117.53 R687.1 76.96,117.56 75.08,117.56 71.63,121.01 71.63,132.01 83.59,143.97 86.33,143.97 v7(86.49,144.12) ; U89.C10 155.93,99.51 v7(156.47,100.05)
LCD_MIPI3P: length 165.4
  L10_SIG4 w0.083: v7(86.49,143.51) 86.64,143.67 87.4,143.67 88.58,144.84 97.77,144.84 98.41,145.48 141.59,145.48 142.19,144.89 150.62,144.89 152.86,142.65 152.86,140.67 161.37,132.16 161.37,118.36 161.95,117.78 161.95,109.96 160.55,108.56 160.55,108.17 160.75,107.98 160.75,107.84 160.65,107.74 160.51,107.74 160.32,107.94 159.93,107.94 157.23,105.24 157.23,101.9 156.01,100.69 156.01,100.21 v7(155.86,100.05)
  BOTTOM w0.108: v7(155.86,100.05) 155.63,99.82 155.63,98.55 U89.C9 ; J16.9 83.79,117.9 83.67,117.78 77.75,117.78 R687.2 76.96,117.81 75.18,117.81 71.88,121.11 71.88,131.91 83.69,143.72 84.68,143.72 84.79,143.61 84.79,143.32 84.89,143.21 85.11,143.21 85.22,143.32 85.22,143.61 85.32,143.72 86.28,143.72 v7(86.49,143.51)
LCD_PCLK: length 45.6
  TOP w0.173: R565.1 v3(129.16,86.82) ; v3(136.53,87.12) 137.26,87.86 137.26,93.95 v8(138.81,95.5)
  L3_SIG1 w0.109: v3(129.16,86.82) 129.62,87.28 134.67,87.28 134.83,87.12 v3(136.53,87.12)
  BOTTOM w0.173: v8(138.81,95.5) 138.81,96.34 139.33,96.86 140.87,96.86 141.08,96.66 141.08,95.15 141.28,94.95 141.56,94.95 141.77,95.15 141.77,96.66 141.97,96.86 142.25,96.86 142.46,96.66 142.46,95.15 142.66,94.95 142.95,94.95 143.15,95.15 143.15,96.66 143.35,96.86 143.64,96.86 143.84,96.66 143.84,95.15 144.04,94.95 144.33,94.95 144.53,95.15 144.53,96.66 144.73,96.86 145.02,96.86 145.22,96.66 145.22,95.15 145.42,94.95 145.71,94.95 145.91,95.15 145.91,96.66 146.11,96.86 148.84,96.86 149.09,96.6 151.72,96.6 U89.J6
LCD_R0: length 38.3
  TOP w0.173: U102.43 v3(140.26,86.61)
  L3_SIG1 w0.109: v3(140.26,86.61) v5(140.94,86.61)
  L10_SIG4 w0.109: v5(140.94,86.61) 141.73,85.82 141.73,85.64 141.41,85.32 141.41,85.14 141.53,85.01 141.72,85.01 142.04,85.33 142.22,85.33 142.35,85.2 142.35,85.02 142.02,84.7 142.02,84.52 142.15,84.39 142.33,84.39 142.66,84.71 142.84,84.71 142.97,84.59 142.97,84.41 142.64,84.08 142.64,83.9 142.77,83.77 142.95,83.77 143.28,84.1 143.46,84.1 143.73,83.82 144,83.82 144.12,83.69 144.12,83.41 144.25,83.29 144.43,83.29 144.56,83.41 144.56,83.69 144.69,83.82 144.87,83.82 145,83.69 145,83.41 145.12,83.29 145.31,83.29 145.43,83.41 145.43,83.69 145.56,83.82 145.74,83.82 145.87,83.69 145.87,83.41 146,83.29 146.18,83.29 146.31,83.41 146.31,83.69 146.44,83.82 146.62,83.82 146.74,83.69 146.74,83.41 146.87,83.29 147.05,83.29 147.18,83.41 147.18,83.69 147.31,83.82 147.49,83.82 147.62,83.69 147.62,83.41 147.75,83.29 147.93,83.29 148.06,83.41 148.06,83.69 148.18,83.82 148.36,83.82 148.49,83.69 148.49,83.41 148.62,83.29 148.8,83.29 148.93,83.41 148.93,83.69 149.06,83.82 149.24,83.82 149.37,83.69 149.37,83.41 149.49,83.29 149.67,83.29 149.8,83.41 149.8,83.69 149.93,83.82 150.11,83.82 150.24,83.69 150.24,83.41 150.37,83.29 150.55,83.29 150.68,83.41 150.68,83.69 150.8,83.82 150.99,83.82 151.11,83.69 151.11,83.41 151.24,83.29 151.42,83.29 151.55,83.41 151.55,83.69 151.68,83.82 151.86,83.82 151.99,83.69 151.99,83.41 152.12,83.29 152.3,83.29 152.42,83.41 152.42,83.69 152.55,83.82 153.01,83.82 155.23,86.04 155.38,86.04 v7(156.21,86.87)
  BOTTOM w0.173: v7(156.21,86.87) 156.21,89.28 156.97,90.04 156.97,91.69 156.26,92.4 156.26,93.38 U89.B2
LCD_R1: length 37.2
  TOP w0.173: U102.39 v3(139.88,84.61)
  L3_SIG1 w0.109: v3(139.88,84.61) v5(140.56,84.61)
  L10_SIG4 w0.109: v5(140.56,84.61) 137.73,84.61 137.57,84.45 137.57,83.72 137.73,83.55 138.7,83.55 138.83,83.68 138.83,83.95 138.96,84.07 139.14,84.07 139.27,83.95 139.27,83.68 139.4,83.55 139.76,83.55 140.36,82.96 141.43,82.96 141.83,82.55 153.31,82.55 155.27,84.51 155.72,84.51 156.81,85.6 v7(156.84,85.6)
  BOTTOM w0.173: v7(156.84,85.6) 156.84,89.15 158.12,90.42 158.12,93.3 157.72,93.69 U89.A2
LCD_R2: length 39.5
  TOP w0.173: U102.41 v3(140.26,85.61)
  L3_SIG1 w0.109: v3(140.26,85.61) v5(139.57,85.61)
  L10_SIG4 w0.109: v5(139.57,85.61) 138.75,86.44 137.9,86.44 137.59,86.13 137.59,85.42 137.9,85.12 140.84,85.12 141.51,84.45 141.51,84.27 141.16,83.91 141.16,83.73 141.29,83.61 141.47,83.61 141.82,83.96 142,83.96 142.13,83.83 142.13,83.65 141.78,83.3 141.78,83.12 141.9,82.99 142.09,82.99 142.44,83.34 142.62,83.34 143.03,82.93 152.65,82.93 155.32,85.6 156.21,85.6 v7(157.48,86.87)
  BOTTOM w0.173: v7(157.48,86.87) 157.48,88.9 158.67,90.09 158.67,93.21 157.87,94 156.92,94 U89.B3
LCD_R3: length 36.6
  TOP w0.173: U102.36 v3(140.26,83.11)
  L3_SIG1 w0.109: v3(140.26,83.11) v5(139.57,83.11)
  L10_SIG4 w0.109: v5(139.57,83.11) 140.11,82.58 141.2,82.58 141.61,82.17 154.3,82.17 154.43,82.3 154.43,82.85 154.55,82.98 154.73,82.98 154.86,82.85 154.86,82.3 154.99,82.17 155.27,82.17 155.63,82.53 155.63,82.71 155.32,83.01 155.32,83.19 155.45,83.32 155.63,83.32 155.94,83.02 156.12,83.02 156.24,83.14 156.24,83.32 155.94,83.63 155.94,83.81 156.07,83.94 156.25,83.94 156.55,83.63 156.73,83.63 156.9,83.79 156.9,84.76 v7(158.17,86.03)
  BOTTOM w0.173: U89.A3 158.01,94.34 159.21,93.15 159.21,89.87 158.17,88.82 v7(158.17,86.03)
LCD_R4: length 36
  TOP w0.173: U102.45 v3(140.26,87.61)
  L3_SIG1 w0.109: v3(140.26,87.61) v5(139.57,87.61)
  L10_SIG4 w0.109: v7(159.13,87.12) 158.34,87.12 158.09,87.38 155.7,87.38 153.37,85.04 143.26,85.04 140.69,87.61 v5(139.57,87.61)
  BOTTOM w0.173: v7(159.13,87.12) 159.87,87.12 161.77,89.03 161.77,90.1 159.74,92.13 159.74,93.07 158.14,94.67 156.9,94.67 U89.B4
LCD_R5: length 36.3
  TOP w0.173: U102.32 v3(140.26,81.11)
  L3_SIG1 w0.109: v3(140.26,81.11) v5(139.57,81.11)
  L10_SIG4 w0.109: v5(139.57,81.11) 140.68,81.11 141.39,80.4 154.65,80.4 160.27,86.03 160.27,87.31 160.4,87.44 v7(160.4,92.38)
  BOTTOM w0.173: U89.A4 158.28,94.99 160.4,92.87 v7(160.4,92.38)
LCD_R6: length 35.4
  TOP w0.173: U102.34 v3(140.26,82.11)
  L3_SIG1 w0.109: v3(140.26,82.11) v5(140.94,82.11)
  L10_SIG4 w0.109: v5(140.94,82.11) 141.42,81.64 155.4,81.64 159.92,86.16 159.92,90.4 159.51,90.8 159.51,93.4 v7(160.05,93.93)
  BOTTOM w0.173: U89.B5 156.92,95.31 158.67,95.31 v7(160.05,93.93)
LCD_R7: length 37.3
  TOP w0.173: U102.30 v3(140.26,80.11)
  L3_SIG1 w0.109: v3(140.26,80.11) v5(140.94,80.11)
  L10_SIG4 w0.109: v5(140.94,80.11) 140.99,80.07 154.84,80.07 161.59,86.82 v7(161.59,91.32)
  BOTTOM w0.173: U89.A5 159.23,95.64 161.59,93.27 v7(161.59,91.32)
LCD_VS: length 36
  L10_SIG4 w0.109: v7(137.92,96.39) 136.02,94.49 v7(136.02,89.66)
  BOTTOM w0.173: U89.K7 149.3,96.94 148.86,97.39 146.71,97.39 145.08,99.01 144.62,99.01 144.42,98.81 144.42,97.84 144.22,97.64 143.93,97.64 143.73,97.84 143.73,98.81 143.53,99.01 143.24,99.01 143.04,98.81 143.04,97.84 142.84,97.64 142.55,97.64 142.35,97.84 142.35,98.81 142.15,99.01 141.86,99.01 141.66,98.81 141.66,97.84 141.45,97.64 141.17,97.64 140.97,97.84 140.97,98.81 140.76,99.01 140.48,99.01 140.28,98.81 140.28,97.84 140.07,97.64 139.79,97.64 139.58,97.84 139.58,98.81 139.38,99.01 138.58,99.01 137.92,98.35 v7(137.92,96.39) ; v7(136.02,89.66) 135.38,89.03 134.87,89.03 134.34,89.56 U104.2
MMC2_CLK: length 68.7
  TOP w0.173: U1.J7 v4(107.03,88.01)
  L3_SIG1 w0.099: 108.34,88.91 107.9,88.47 107.54,88.47 107.16,88.09 ; 110.88,96.05 108.57,93.75 108.57,90.77 ; 108.34,90.54 108.34,88.91
  L3_SIG1 w0.102: 108.57,90.77 108.34,90.54
  L3_SIG1 w0.109: 110.88,96.05 110.88,96.73 111.08,96.93 111.08,102.11 111,102.2 109.58,103.61 109.57,104.45 108.26,105.76 107.44,105.76 107.15,106.05 104.62,106.05 104.17,106.5 103.05,106.5 102.5,107.05 101.99,107.05 101.3,107.74 98.48,107.74 95.6,110.62 v5(93.6,110.62) ; 108.34,88.91 108.34,88.91 ; 107.16,88.09 v4(107.03,88.01)
  L10_SIG4 w0.109: v7(95.25,115.52) 93.6,113.87 93.6,113.29 93.72,113.17 95.26,113.17 95.38,113.06 95.38,112.89 95.26,112.78 93.72,112.78 93.6,112.66 93.6,112.5 93.72,112.38 95.26,112.38 95.38,112.26 95.38,112.1 95.26,111.98 93.72,111.98 93.6,111.87 93.6,111.7 93.72,111.59 95.26,111.59 95.38,111.47 95.38,111.31 95.26,111.19 93.72,111.19 93.6,111.08 v5(93.6,110.62)
  BOTTOM w0.083: U43.M6 98.13,127.2 98.13,122.89
  BOTTOM w0.173: v7(95.25,115.52) 96.42,116.69 96.42,117.78 96.62,117.98 96.95,117.98 97.16,118.18 97.16,118.47 96.95,118.67 96.62,118.67 96.42,118.88 96.42,119.16 96.62,119.36 96.95,119.36 97.16,119.57 97.16,119.85 96.95,120.05 96.62,120.05 96.42,120.26 96.42,120.71 98.13,122.42 98.13,122.89
MMC2_CMD: length 64.3
  TOP w0.173: U1.H6 v4(107.83,88.81)
  L3_SIG1 w0.099: 107.72,94.3 107.72,91.55 107.54,91.37 107.54,89.49 107.83,89.2 v4(107.83,88.81)
  L3_SIG1 w0.109: 107.72,94.3 109.14,95.73 109.14,97.4 110.01,98.27 110.01,101.75 108.21,103.55 108.21,103.56 108.21,103.56 108.21,103.94 108.21,104.01 107.47,104.75 107.01,104.75 106.81,104.95 104.62,104.95 104.49,104.82 102.27,104.82 102.19,104.9 102.19,104.9 100.36,106.73 98.06,106.73 96.34,108.45 v5(95.7,108.45)
  L4_SIG2 w0.114: v5(95.63,116.79) 95.63,115.96 95.49,115.83 94.88,115.83 94.74,115.69 94.74,115.5 94.88,115.36 95.49,115.36 95.63,115.22 95.63,115.03 95.49,114.89 94.88,114.89 94.74,114.76 94.74,114.56 94.88,114.43 95.49,114.43 95.63,114.29 95.63,114.1 95.49,113.96 94.88,113.96 94.74,113.82 94.74,113.63 94.88,113.49 95.49,113.49 95.63,113.35 95.63,113.16 95.49,113.02 94.88,113.02 94.74,112.89 94.74,112.69 94.88,112.56 95.49,112.56 95.63,112.42 95.63,112.23 95.49,112.09 94.88,112.09 94.74,111.95 94.74,111.76 94.88,111.62 95.49,111.62 95.63,111.48 95.63,108.52 v5(95.7,108.45)
  L10_SIG4 w0.109: v5(95.7,108.45) v7(95.7,107.78) ; v7(95.63,117.43) v5(95.63,116.79)
  BOTTOM w0.083: 97.46,122.89 97.63,123.06 97.63,127.7 U43.M5
  BOTTOM w0.173: 97.46,122.89 95.63,121.06 95.63,120.2 95.46,120.03 94.91,120.03 94.74,119.86 94.74,119.51 94.91,119.34 95.46,119.34 95.63,119.17 v7(95.63,117.43) ; R513.1 95.25,107.33 v7(95.7,107.78)
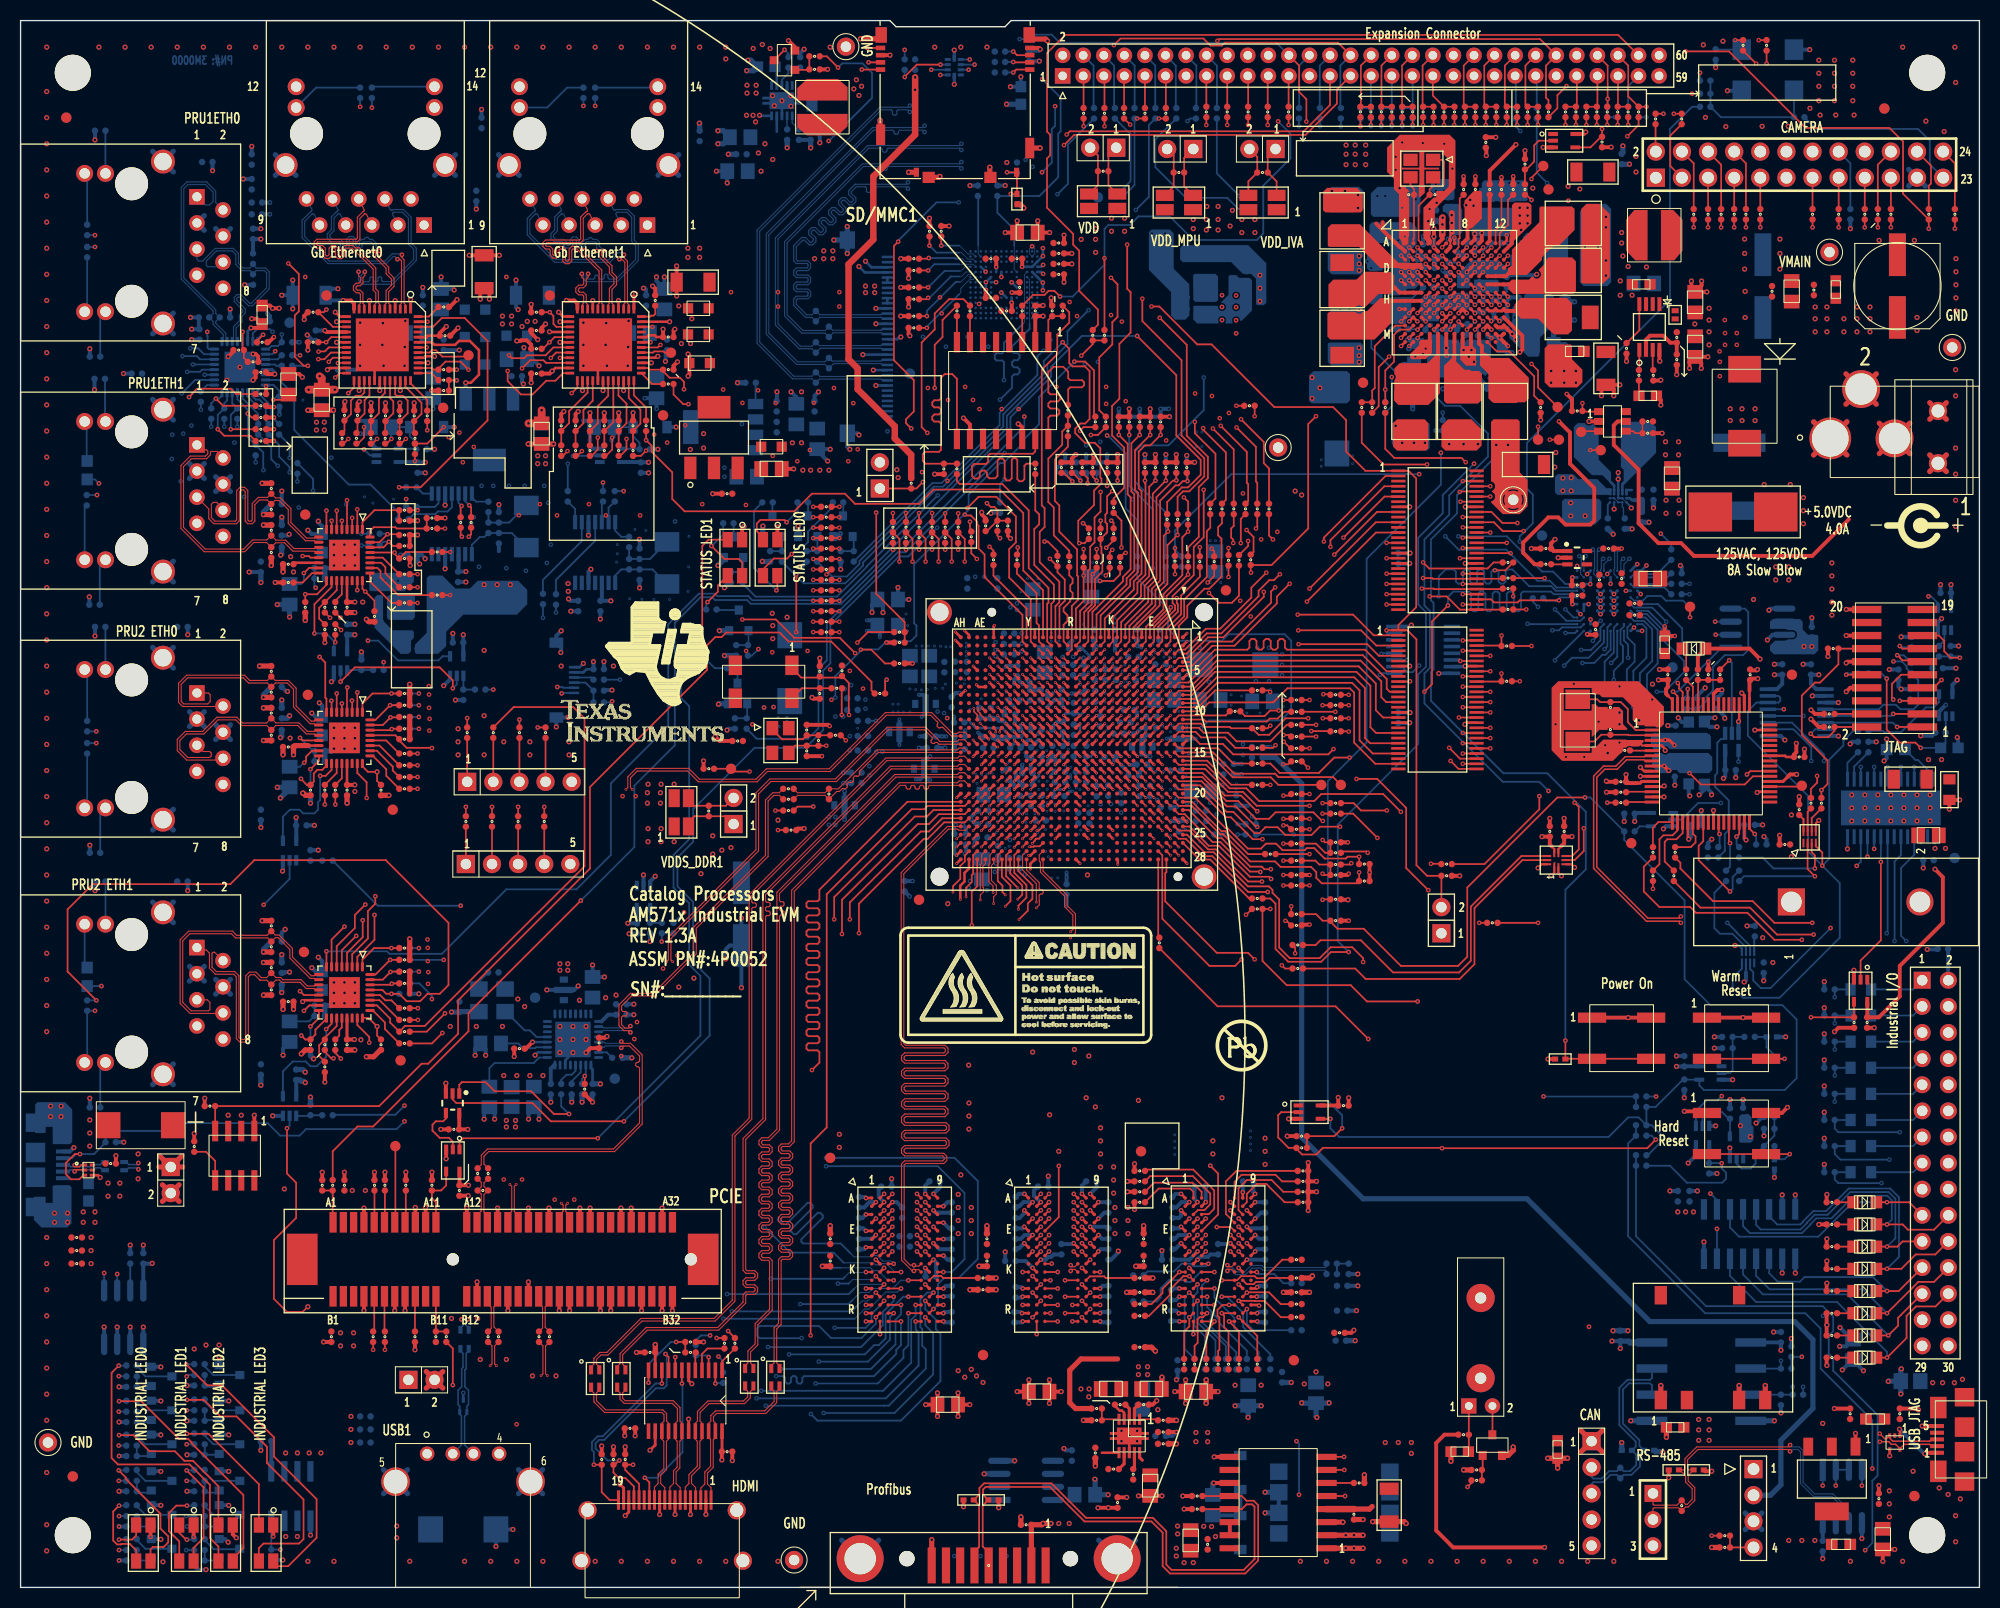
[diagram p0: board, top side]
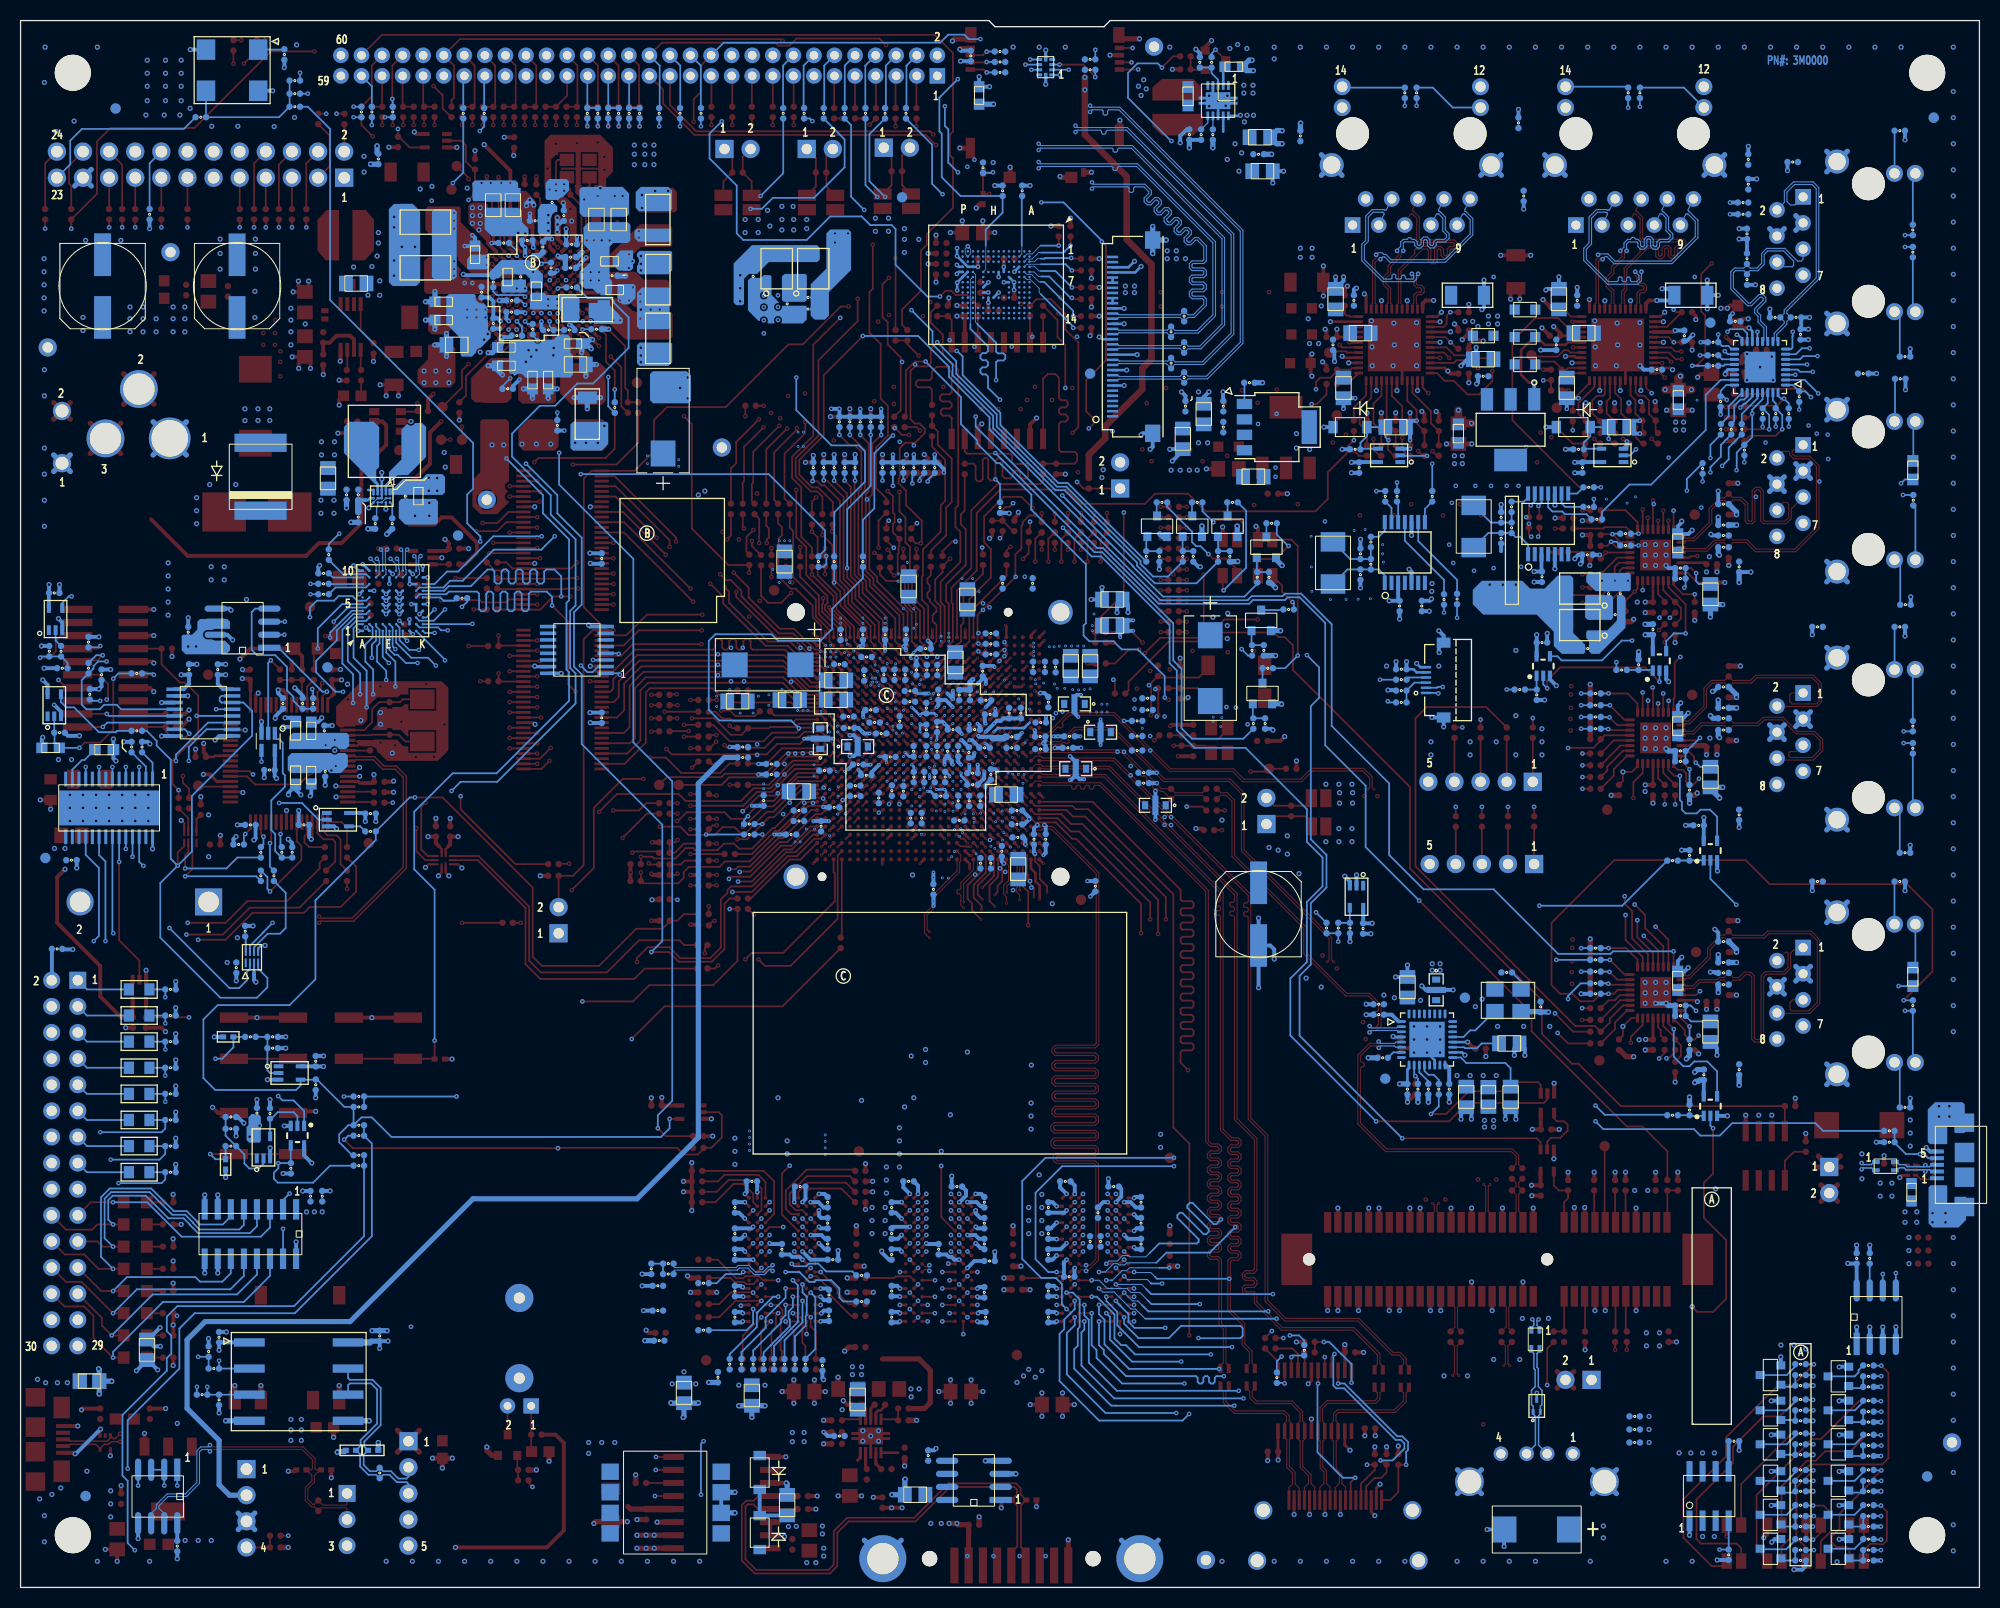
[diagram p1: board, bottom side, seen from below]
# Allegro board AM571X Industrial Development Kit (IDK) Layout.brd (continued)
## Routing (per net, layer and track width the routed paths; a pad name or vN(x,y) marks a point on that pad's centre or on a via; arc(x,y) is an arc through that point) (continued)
MMC2_DAT0: length 62.4
  TOP w0.173: v8(88.33,129.3) 88.27,129.24 R505.1 ; U1.J4 v4(107.03,90.41)
  L3_SIG1 w0.099: v4(107.03,90.41) 107.03,90.8 106.74,91.09 106.74,91.61 107.07,91.93 107.07,95.26
  L3_SIG1 w0.109: 107.07,95.26 108.46,96.65 108.46,97.68 109.34,98.56 109.34,101.44 106.5,104.27 104.9,104.27 104.77,104.14 101.99,104.14 100.13,106 97.74,106 96.09,107.65 95.38,107.65 94.39,108.64 92.48,108.64 v5(90.8,110.32)
  L4_SIG2 w0.114: v8(88.33,129.3) 87.25,128.22 87.25,115.78 87.66,115.37 87.66,111.43 88.77,110.32 v5(90.8,110.32)
  BOTTOM w0.083: U43.A3 91.9,128.95 91.61,129.24 91.27,129.24
  BOTTOM w0.173: v8(88.33,129.3) 90.87,129.3 90.93,129.24 91.27,129.24
MMC2_DAT1: length 62.6
  TOP w0.173: R506.1 v8(88.27,126.45) ; U1.J6 v4(107.03,88.81)
  L3_SIG1 w0.099: v4(107.03,88.81) 107.03,89.2 106.74,89.49 106.74,90.81 106.54,91.01 106.54,91.73 106.27,92 106.27,92.95 106.8,93.47 106.8,95.37
  L3_SIG1 w0.109: v5(92.1,108.29) 94.26,108.29 95.25,107.29 95.96,107.29 97.61,105.64 99.97,105.64 101.86,103.76 102.46,103.76 103.16,103.06 107.23,103.06 109,101.29 109,98.76 108.12,97.88 108.12,96.69 106.8,95.37
  L4_SIG2 w0.114: v8(88.27,126.45) 90.04,124.67 90.04,124.05 92.33,121.76 92.33,118.42 92.19,118.29 91.83,118.29 91.69,118.15 91.69,117.96 91.83,117.82 92.19,117.82 92.33,117.68 92.33,117.49 92.19,117.35 91.83,117.35 91.69,117.21 91.69,117.02 91.83,116.88 92.19,116.88 92.33,116.75 92.33,116.03 93.16,115.2 93.16,109.34 v5(92.1,108.29)
  BOTTOM w0.083: U43.A4 91.86,128.45 91.45,128.04 91.27,128.04
  BOTTOM w0.173: v8(88.27,126.45) 89.86,128.04 91.27,128.04
MMC2_DAT2: length 62.5
  TOP w0.173: U1.H4 v4(107.83,90.41) ; R507.1 88.14,125.3 v8(88.27,125.43)
  L3_SIG1 w0.099: 107.83,90.73 108.15,91.05 108.15,93.97 110.01,95.83
  L3_SIG1 w0.109: 110.01,95.83 110.01,97.08 109.84,97.25 109.84,97.61 110.35,98.12 110.35,101.89 109.45,102.79 108.55,103.69 108.55,103.7 108.55,103.96 108.54,104.16 107.61,105.08 107.15,105.08 106.95,105.28 106.69,105.28 104.44,105.28 104.32,105.16 102.41,105.16 100.51,107.07 98.2,107.07 95.92,109.35 93.07,109.35 92.71,109.71 v5(92.71,110.32) ; v4(107.83,90.41) 107.83,90.73
  L4_SIG2 w0.114: v8(88.27,125.43) 88.27,124.59 91.06,121.79 91.06,121.38 91.2,121.25 91.81,121.25 91.95,121.11 91.95,120.92 91.81,120.78 91.2,120.78 91.06,120.64 91.06,120.45 91.2,120.31 91.81,120.31 91.95,120.17 91.95,119.98 91.81,119.84 91.2,119.84 91.06,119.71 91.06,119.51 91.2,119.38 91.81,119.38 91.95,119.24 91.95,119.05 91.81,118.91 91.2,118.91 91.06,118.77 91.06,116.16 92.71,114.51 v5(92.71,110.32)
  BOTTOM w0.083: U43.A5 91.93,127.95 91.49,127.51 91.27,127.51
  BOTTOM w0.173: 91.27,127.51 90.47,127.51 88.39,125.43 v8(88.27,125.43)
MMC2_DAT3: length 62.3
  TOP w0.173: R508.1 v8(89.53,130.51) ; U1.H5 v4(107.83,89.61)
  L3_SIG1 w0.099: 108.36,93.83 108.36,90.84 108.13,90.62 ; 108.36,93.83 110.31,95.79
  L3_SIG1 w0.102: 108.13,89.91 108.13,90.62
  L3_SIG1 w0.109: 110.31,95.79 110.54,96.02 110.54,96.87 110.74,97.07 110.74,97.88 110.69,97.93 110.69,102.03 109.2,103.52 109.19,103.98 109.19,103.99 107.76,105.42 107.3,105.42 107.06,105.66 104.52,105.66 104.27,105.92 102.62,105.92 101.13,107.41 98.34,107.41 95.91,109.83 v5(93.62,109.83) ; v4(107.83,89.61) 108.13,89.91 ; 108.36,93.83 108.36,93.83
  L4_SIG2 w0.114: v5(93.62,109.83) 94.23,110.44 94.23,120.6 91.31,123.53 91.31,128.73 v8(89.53,130.51)
  BOTTOM w0.083: 91.27,130.51 91.32,130.51 92.13,129.7 92.63,129.7 U43.B2
  BOTTOM w0.173: v8(89.53,130.51) 91.27,130.51
MMC2_DAT4: length 68.5
  TOP w0.173: R509.1 v8(88.39,130.51) ; U1.K7 v4(106.23,88.01)
  L3_SIG1 w0.099: 106.58,95.58 106.58,93.53 106.07,93.03 106.07,91.92 106.22,91.77 106.22,91.05 106.53,90.74 106.53,88.69 106.23,88.4 v4(106.23,88.01)
  L3_SIG1 w0.109: v5(90.8,109.43) 90.8,108.95 91.97,107.78 94.28,107.78 95.15,106.91 95.86,106.91 97.51,105.26 99.88,105.26 101.72,103.42 102.32,103.42 103.02,102.72 107.06,102.72 108.66,101.12 108.66,98.91 107.78,98.03 107.78,96.78 106.58,95.58
  L4_SIG2 w0.114: v5(90.8,109.43) 89.03,109.43 87.22,111.23 87.22,113.39 85.09,115.52 85.09,127.21 v8(88.39,130.51)
  BOTTOM w0.083: U43.B3 92.63,129.2 92.13,129.2 91.77,129.56 91.49,129.83 91.27,129.83
  BOTTOM w0.173: v8(88.39,130.51) 89.07,129.83 91.27,129.83
MMC2_DAT5: length 63.9
  TOP w0.173: R510.1 v8(88.27,128.1) ; U1.M7 v4(104.63,88.01)
  L3_SIG1 w0.099: v4(104.63,88.01) 104.63,88.4 104.34,88.69 104.34,88.94 104.51,89.11 104.54,89.11 104.88,89.44 105.19,89.44 105.31,89.32 105.56,89.32 105.73,89.49 105.73,91.63 105.64,91.72 105.64,92.37 105.3,92.71 105.3,93.38 106.09,94.17 106.09,96.05
  L3_SIG1 w0.109: 106.09,96.05 107.06,97.02 107.06,98.36 107.95,99.25 107.95,100.87 106.81,102.01 102.78,102.01 102.58,102.21 101.36,102.21 100.9,102.66 100.9,103.12 99.5,104.53 97.18,104.53 95.5,106.2 94.89,106.2 93.92,107.17 91.51,107.17 89.94,108.74 89.94,110.04 v5(88.39,111.59)
  L4_SIG2 w0.114: v8(88.27,128.1) 87.68,127.52 87.68,116.22 88.39,115.51 v5(88.39,111.59)
  BOTTOM w0.083: 91.27,128.7 92.63,128.7 U43.B4
  BOTTOM w0.173: 91.27,128.7 88.87,128.7 v8(88.27,128.1)
MMC2_DAT6: length 62.2
  TOP w0.173: U1.J5 v4(107.03,89.61) ; R511.1 v8(88.14,123.65)
  L3_SIG1 w0.099: v4(107.03,89.61) 107.03,90 107.34,90.31 107.34,91.46 107.49,91.61 107.49,94.57
  L3_SIG1 w0.109: 107.49,94.57 108.8,95.87 108.8,97.54 109.68,98.42 109.68,101.58 106.65,104.61 104.76,104.61 104.64,104.49 102.13,104.49 102.1,104.52 102.09,104.52 100.25,106.35 97.96,106.35 96.31,108.01 95.5,108.01 94.51,109 92.83,109 v5(92.27,109.56)
  L4_SIG2 w0.114: v8(88.14,123.65) 89.85,121.94 89.85,121.42 89.99,121.28 90.42,121.28 90.55,121.15 90.55,120.96 90.42,120.83 89.99,120.83 89.85,120.69 89.85,120.5 89.99,120.37 90.42,120.37 90.55,120.23 90.55,120.05 90.42,119.91 89.99,119.91 89.85,119.78 89.85,119.59 89.99,119.45 90.42,119.45 90.55,119.32 90.55,119.13 90.42,119 89.99,119 89.85,118.86 89.85,118.67 89.99,118.54 90.42,118.54 90.55,118.41 90.55,118.22 90.42,118.08 89.99,118.08 89.85,117.95 89.85,116.67 92.27,114.25 v5(92.27,109.56)
  BOTTOM w0.083: U43.B5 92.63,127.7 92.17,127.7 91.45,126.98 91.27,126.98
  BOTTOM w0.173: v8(88.14,123.65) 88.14,124.16 90.96,126.98 91.27,126.98
MMC2_DAT7: length 63
  TOP w0.173: U1.K6 v4(106.23,88.81) ; v8(88.14,122.51) R512.1
  L3_SIG1 w0.099: 106.33,95.8 106.33,94.12 105.5,93.29 105.5,92.79 105.87,92.42 105.87,91.83 105.94,91.76 105.94,89.49 106.23,89.2 v4(106.23,88.81)
  L3_SIG1 w0.109: 106.33,95.8 107.43,96.91 107.43,98.18 108.32,99.07 108.32,100.98 108.24,101.06 108.24,101.06 106.94,102.37 102.9,102.37 102.72,102.55 101.5,102.55 101.24,102.8 101.24,103.26 99.59,104.91 97.38,104.91 95.73,106.56 95.02,106.56 94.1,107.48 91.74,107.48 90.28,108.93 90.28,110.58 v5(89.03,111.84)
  L4_SIG2 w0.114: v5(89.03,111.84) 89.03,115.4 88.14,116.29 88.14,117.78 88.27,117.92 88.77,117.92 88.9,118.05 88.9,118.24 88.77,118.37 88.27,118.37 88.14,118.51 88.14,118.7 88.27,118.83 88.77,118.83 88.9,118.96 88.9,119.15 88.77,119.29 88.27,119.29 88.14,119.42 88.14,119.61 88.27,119.75 88.77,119.75 88.9,119.88 88.9,120.07 88.77,120.2 88.27,120.2 88.14,120.34 88.14,120.53 88.27,120.66 88.77,120.66 88.9,120.79 88.9,120.98 88.77,121.12 88.27,121.12 88.14,121.25 v8(88.14,122.51)
  BOTTOM w0.083: 91.27,125.78 91.44,125.94 91.44,126.36 92.28,127.2 92.63,127.2 U43.B6
  BOTTOM w0.173: v8(88.14,122.51) 88.14,122.64 91.27,125.78
MMC_CD: length 57.1
  TOP w0.173: v3(96.29,135.54) 96.29,135.54 U84.1 96.9,137.61 J15.10 95.94,137.65 v8(95.93,137.65) ; R409.1 v3(77.09,99.01)
  L3_SIG1 w0.109: v3(77.09,99.01) v5(76.45,99.01) ; v3(96.29,135.54) v5(95.71,135.54)
  L4_SIG2 w0.114: v5(76.45,99.01) 76.56,99.01 79.32,101.78 79.32,111.76 83.82,116.26 83.82,133.73 85.63,135.54 v5(95.71,135.54)
  BOTTOM w0.173: R408.1 96.01,137.58 v8(95.93,137.65)
MMC_CLK: length 65
  TOP w0.173: R405.1 v3(77.09,105.11) ; J15.5 v8(82.36,149.74)
  L3_SIG1 w0.109: v3(77.09,105.11) v5(76.45,105.11) ; v8(82.36,149.74) 82.36,149.2 82.02,148.85 82.02,148.16 82.3,147.88 87.13,147.88 87.9,147.11 v8(89.45,147.11)
  L4_SIG2 w0.114: v8(89.45,147.11) 89.45,145.19 82.68,138.42 82.68,128.61 81.91,127.84 81.62,127.84 72.2,118.41 72.2,107.68 74.77,105.11 v5(76.45,105.11)
  BOTTOM w0.173: U30.1 v8(89.45,147.11)
MMC_CMD: length 66.9
  TOP w0.173: J15.3 96.9,149.04 v8(96.55,149.39) ; R404.1 v3(77.09,104.09)
  L3_SIG1 w0.109: v8(92.78,148.11) 93.49,148.82 94.81,148.82 95.38,149.39 v8(96.55,149.39) ; v3(77.09,104.09) v5(76.45,104.09)
  L4_SIG2 w0.114: v5(76.45,104.09) 76.86,104.09 77.54,104.77 77.54,105.29 76.91,105.92 74.48,105.92 72.57,107.83 72.57,118.26 81.8,127.49 82.07,127.49 83.07,128.49 83.07,138.28 90.34,145.56 90.34,146.74 91.72,148.11 v8(92.78,148.11)
  BOTTOM w0.173: R398.1 v8(96.55,149.39) ; U30.7 v8(92.78,148.11)
MMC_D0: length 69.4
  TOP w0.173: J15.7 v8(82.47,148.34) ; R406.1 v3(77.09,101.05)
  L3_SIG1 w0.109: v3(77.09,101.05) v5(76.45,101.05) ; v8(88.57,147.61) 87.23,148.95 86.58,148.95 v8(85.98,149.55) 83.69,149.55 v8(82.47,148.34)
  L4_SIG2 w0.114: v5(76.45,101.05) 74.45,101.05 72.69,102.8 72.69,103.79 71.46,105.03 71.46,119.93 80.9,129.37 80.9,137.69 88.57,145.36 v8(88.57,147.61)
  BOTTOM w0.173: U30.2 v8(88.57,147.61) ; R399.1 v8(85.98,149.55)
MMC_D1: length 69.8
  TOP w0.173: R407.1 v3(77.09,102.06) ; v8(85.99,146.9) 85.99,146.95 87.15,148.11 v8(89.46,148.11) ; J15.8 v8(81.82,147.64)
  L3_SIG1 w0.109: v8(85.99,146.9) 82.55,146.9 v8(81.82,147.64) ; v3(77.09,102.06) v5(76.45,102.06)
  L4_SIG2 w0.114: v5(76.45,102.06) 75.33,102.06 73.04,104.36 73.04,104.55 73.24,104.75 73.24,104.94 73.11,105.08 72.92,105.08 72.71,104.87 72.53,104.87 71.83,105.57 71.83,119.72 81.41,129.3 81.41,137.67 89.01,145.28 89.01,147.66 v8(89.46,148.11)
  BOTTOM w0.173: v8(85.99,146.9) 85.98,146.91 R400.1 ; U30.3 v8(89.46,148.11)
MMC_D2: length 74.7
  TOP w0.173: v8(96.55,147.36) 96.83,147.64 J15.1 ; R402.1 v3(77.09,100.03)
  L3_SIG1 w0.109: v3(77.09,100.03) v5(76.45,100.03) ; v8(96.55,147.36) 95.75,146.56 92.23,146.56 91.64,147.15 91.64,147.95 v8(92.3,148.61)
  L4_SIG2 w0.114: v8(92.3,148.61) 88.76,148.61 87.46,147.32 87.46,144.77 79.76,137.07 79.76,128.76 71.09,120.09 71.09,103.65 74.7,100.03 v5(76.45,100.03)
  BOTTOM w0.173: U30.6 v8(92.3,148.61) ; R401.1 v8(96.55,147.36)
MMC_D3: length 72.7
  TOP w0.173: v8(96.55,148.37) 96.58,148.34 J15.2 ; R403.1 v3(77.09,103.08)
  L3_SIG1 w0.109: v3(77.09,103.08) v5(76.45,103.08) ; v8(92.2,147.61) 95.79,147.61 v8(96.55,148.37)
  L4_SIG2 w0.114: v8(92.2,147.61) 92.2,146.89 83.44,138.13 83.44,128.22 82.32,127.11 81.94,127.11 74.02,119.19 74.02,115.42 74.14,115.31 74.99,115.31 75.11,115.19 75.11,114.96 74.99,114.85 74.14,114.85 74.02,114.74 74.02,114.51 74.14,114.39 74.99,114.39 75.11,114.28 75.11,114.05 74.99,113.94 74.14,113.94 74.02,113.82 74.02,113.59 74.14,113.48 74.99,113.48 75.11,113.36 75.11,113.14 74.99,113.02 74.14,113.02 74.02,112.91 74.02,112.68 74.14,112.56 74.99,112.56 75.11,112.45 75.11,112.22 74.99,112.11 74.14,112.11 74.02,111.99 74.02,107.28 74.75,106.55 76.97,106.55 77.95,105.57 77.95,104.58 v5(76.45,103.08)
  BOTTOM w0.173: R397.1 v8(96.55,148.37) ; U30.8 v8(92.2,147.61)
OSC0_OUT: length 6.3
  TOP w0.173: Y1.1 73.11,83.43 74.05,82.49 76.06,82.49 C1.1 R4.1 R5.2
PCI_CONN_REFN: length 29.7
  TOP w0.108: v8(58.42,53.1) 58.6,52.92 59.32,52.92 60.45,51.79 60.45,45.08 57.76,42.39 45.52,42.39 45.06,41.94 45.06,41.17 C436.1
  BOTTOM w0.108: v8(58.42,53.1) 58.24,52.92 56.87,52.92 56.74,53.04 U45.5
PCI_CONN_REFP: length 29.7
  TOP w0.108: C437.1 44.81,41.12 44.81,42.04 45.41,42.65 57.66,42.65 60.2,45.19 60.2,50.51 60.07,50.64 59.94,50.64 59.82,50.77 59.82,50.95 59.94,51.07 60.07,51.07 60.2,51.2 60.2,51.69 59.22,52.67 58.6,52.67 v8(58.42,52.49)
  BOTTOM w0.108: v8(58.42,52.49) 58.24,52.67 56.87,52.67 56.75,52.54 U45.6
PCIE_CRDPRESENT: length 134.1
  TOP w0.173: R650.1 30.35,42.42 32.77,44.83 34.29,44.83 43.56,54.1 43.56,55.88 v8(54.48,66.8)
  L9_SIG3 w0.114: v8(105.66,112.04) 103.83,113.88 v8(97.61,113.88)
  BOTTOM w0.173: v8(97.61,113.88) 97.61,113.88 97.61,112.91 85.8,101.1 85.23,101.1 79.81,95.67 71.02,95.67 70.65,96.04 67.54,96.04 67.27,96.31 66.11,96.31 63.63,93.82 63.63,81.91 59.69,77.98 59.69,72.01 v8(54.48,66.8) ; R664.1 108.58,103.84 107.47,104.95 107.47,110.31 105.74,112.04 v8(105.66,112.04)
PCIE_PERSTN: length 6.2
  TOP w0.173: U44.4 41.39,39.1 40.89,38.61 R545.1 40,37.85 40.39,37.46 J52.A11
PCIE_REFCLKN: length 4.9
  TOP w0.108: C436.2 45.06,39.34 45.06,39.01 R580.2 45.06,38.2 45.06,36.52 45.39,36.19 J52.A14
PCIE_REFCLKP: length 4.9
  TOP w0.108: C437.2 44.81,39.4 44.81,38.96 R580.1 44.81,38.25 44.81,36.63 44.39,36.22 J52.A13
PCIE_RESETN: length 177.6
  TOP w0.173: U85.1 42.66,48.88 42.93,49.15 45.21,49.15 46.1,48.26 49.66,48.26 51.87,46.05 v8(53.34,46.05)
  L4_SIG2 w0.114: v5(62.74,13.68) 62.77,13.71 72.31,13.71 72.73,13.29 97.96,13.29 99.1,12.15 102.96,12.15 103.42,12.62 104.86,12.62 105.77,11.7 114.69,11.7 115.08,11.31 116.66,11.31 117.29,11.94 129.67,11.94 140.77,23.04 145.03,23.04 148.11,26.11 v8(148.11,47.75)
  L9_SIG3 w0.114: v5(62.74,13.68) 62.74,15.75 59.05,19.43 59.05,35.05 57.53,36.58 57.53,44.65 56.13,46.05 v8(53.34,46.05)
  BOTTOM w0.173: v8(53.34,46.05) 53.31,46.05 52.58,46.79 R568.2 ; v8(148.11,47.75) 157.1,47.75 157.1,46.74
PCIE_SMB_CLK: length 3.5
  TOP w0.173: J52.B5 34.39,24.99 R652.1
PCIE_SMB_DATA: length 3.4
  TOP w0.173: J52.B6 35.39,24.93 R653.1
PCIE_TCK: length 3.1
  TOP w0.173: R542.2 34.42,35.54 J52.A5
PCIE_TDI: length 3.1
  TOP w0.173: R543.2 35.43,35.55 J52.A6
PCIE_TDO: length 7.4
  TOP w0.173: TP20.1 36.45,35.57 J52.A7
PCIE_TMS: length 3.1
  TOP w0.173: J52.A8 37.46,35.59 R544.2
PCIE_TRSTN: length 3.4
  TOP w0.173: J52.B9 38.35,28.27 R539.1
PCIE_WAKEN: length 159.5
  TOP w0.173: R665.1 104.39,114 104.39,118.37 103.53,119.23 v8(102.49,119.23) ; R655.1 42.04,23.24 v8(42.04,19.69)
  L4_SIG2 w0.114: v8(42.04,19.69) 41.02,18.67 37.21,18.67 36.39,19.49 36.39,23.18 38.48,25.27 38.48,31.24 37.85,31.88 37.85,38.1 39.12,39.37 39.12,48.26 v5(41.02,50.16)
  L10_SIG4 w0.109: v5(41.02,50.16) 44.7,50.16 45.21,50.67 54.99,50.67 55.5,50.16 59.94,50.16 62.28,52.5 62.28,54.94 66.04,58.7 66.04,60.22 78.11,72.29 78.11,78.99 78.56,79.45 78.56,85.88 v7(79.23,86.55)
  BOTTOM w0.173: v8(102.49,119.23) 99.05,115.79 99.05,113.15 97.46,111.56 97.46,111.25 95.55,109.35 95.25,109.35 92.2,106.3 92.2,104.82 86.9,99.52 86.9,93.78 87.12,93.55 87.12,92.58 86.57,92.03 84.21,92.03 83.41,91.24 81.84,91.24 79.23,88.63 v7(79.23,86.55)
PCIECONN_PETN0: length 3.8
  TOP w0.108: J52.B15 46.39,27.64 46.02,27.28 46.02,25.35 C477.2
PCIECONN_PETN1: length 3.7
  TOP w0.108: J52.B20 51.39,27.64 51.02,27.27 51.02,25.31 C581.2
PCIECONN_PETP0: length 3.7
  TOP w0.108: C478.2 45.77,25.2 45.77,27.26 45.39,27.64 J52.B14
PCIECONN_PETP1: length 3.7
  TOP w0.108: C582.2 50.76,25.24 50.76,27.26 50.39,27.64 J52.B19
PHY0_LED_ACTN: length 29.7
  TOP w0.173: U21.17 30.21,121.61 v8(29.72,121.11) R321.2
  L9_SIG3 w0.114: v8(33.02,144.02) 33.87,143.17 33.87,134.65 33.02,133.8 33.02,131.65 28.63,127.26 28.63,122.2 v8(29.72,121.11)
  BOTTOM w0.173: R293.1 v8(33.02,144.02)
PHY0_LED_LINKN: length 28.7
  TOP w0.173: v8(29.74,124.29) 29.49,124.03 R319.2 30.38,122.61 U21.15
  L9_SIG3 w0.114: v8(29.74,124.29) 32.68,127.23 34.44,127.23 35.43,128.22 35.43,132.62 34.17,133.88 34.17,143.93 v8(34.16,143.93)
  BOTTOM w0.173: R296.1 v8(34.16,143.93)
PHY1_LED_ACTN: length 29.7
  TOP w0.173: R364.2 50.8,120.48 v8(51.43,121.11) 51.93,121.61 U24.17
  L9_SIG3 w0.114: v8(51.43,121.11) 52,121.68 52,122.85 51.02,123.83 51.02,129.72 52.37,131.06 52.37,132.91 53.64,134.18 53.64,135.45 55.37,137.19 55.37,143.47 v8(54.74,144.1)
  BOTTOM w0.173: R337.1 v8(54.74,144.1)
PHY1_LED_LINKN: length 26.5
  TOP w0.173: U24.15 52.11,122.61 51.82,122.9 51.82,123.68 v8(51.46,124.03) R363.2
  L9_SIG3 w0.114: v8(55.88,144.1) 55.88,134.7 54.31,133.13 54.31,132.11 51.46,129.25 v8(51.46,124.03)
  BOTTOM w0.173: R340.1 v8(55.88,144.1)
PHY_RESETN: length 367.8
  TOP w0.173: v8(42.04,87.46) 42.04,88.22 40.77,89.49 32.51,89.49 v8(31.12,88.09) ; v8(25.91,44.66) 25.91,40.26 26.8,39.37 26.8,35.94 24.64,33.78 24.64,28.07 25.91,26.8 27.43,26.8 v9(27.94,27.3)
  L9_SIG3 w0.114: v5(52.58,110.7) 52.51,110.63 44.51,110.63 43.63,109.75 39.84,109.75 38.89,110.7 v8(33.4,110.7) 33.4,109.3 38.18,104.52 38.96,104.52 39.7,103.78 39.7,103 40.39,102.32 40.39,91.01 42.04,89.36 v8(42.04,87.46) ; v9(27.94,27.3) 29.08,26.16 32.59,26.16 34.52,24.24 34.52,19.71 37.08,17.14 45.34,17.14 53.42,9.07 59.97,9.07 60.2,9.3 72.06,9.3 72.64,8.71 96.27,8.71 96.65,9.09 104.9,9.09 105.84,10.03 114.3,10.03 122.31,2.03 175.64,2.03 177.23,3.62 v8(179.39,3.62) ; v8(25.91,44.66) 25.91,48.41 22.5,51.82 22.5,65.26 v8(23.65,66.4) 22.83,67.21 22.83,76.56 29.08,82.8 29.08,85.32 29.62,85.85 29.62,86.59 v8(31.12,88.09)
  L10_SIG4 w0.109: v7(53.72,110.06) 53.21,110.06 v5(52.58,110.7)
  BOTTOM w0.173: U26.2 56.28,110.06 v7(53.72,110.06) ; v8(42.04,87.46) 42.42,87.84 U68.2 ; 157.1,42.04 157.1,34.16 163.91,27.36 175.26,27.36 176.28,26.34 176.28,24.92 175.84,24.49 175.84,22.73 176.28,22.3 176.28,21.08 180.59,16.76 180.59,10.88 180.09,10.37 180.09,4.32 v8(179.39,3.62) ; v8(25.91,44.66) 26.16,44.91 U71.2 ; v8(23.65,66.4) 26.16,68.92 U70.2 ; v8(31.12,88.09) U69.2 ; U22.2 33.99,110.11 v8(33.4,110.7)
PMIC_EN: length 69.4
  TOP w0.173: R923.1 93.98,102.74 R645.1 ; R923.1 R922.2 ; R923.1 95,104.81 94.72,105.08 94.35,105.08 v8(93.98,105.45) ; U3.E5 v8(137.45,127.14)
  L10_SIG4 w0.109: v8(93.98,105.45) 99.35,105.45 100.6,106.71 105.92,106.71 109.04,103.59 111,103.59 112.57,105.15 112.57,105.85 111.91,106.51 111.91,111.99 114.29,114.37 119.78,114.37 122.31,116.91 124.1,116.91 125.39,118.19 126.56,118.19 128.2,116.56 131.32,116.56 134.11,119.35 134.11,121.64 134.67,122.2 134.67,124.36 v8(137.45,127.14)
PMIC_INT: length 63.9
  TOP w0.173: U3.K1 v3(134.25,123.14)
  L3_SIG1 w0.109: v5(133.55,123.14) v3(134.25,123.14)
  L4_SIG2 w0.114: v5(133.55,123.14) 135.26,121.44 135.26,112.52 136.02,111.75 136.02,109.98 137.03,108.97 137.03,98.55 v5(138.43,97.16)
  L9_SIG3 w0.114: v5(123.83,74.76) 123.88,74.76 125.73,76.61 125.73,81.25 126.73,82.26 126.73,83.28 130.18,86.73 130.18,88.65 131.85,90.32 132.94,90.32 137.15,94.53 137.71,94.53 138.36,95.18 138.36,97.09 v5(138.43,97.16)
  L10_SIG4 w0.109: v7(123.83,73.23) v5(123.83,74.76)
  BOTTOM w0.173: R666.1 v7(123.83,73.23)
PMIC_RESET_IN: length 18.2
  TOP w0.173: v3(151.89,115.19) R928.2 151.96,114.36 U105.1
  L3_SIG1 w0.109: v5(140.97,121.28) 141.73,121.28 142.49,120.52 142.49,119.25 143.64,118.11 146.05,118.11 148.97,115.19 v3(151.89,115.19)
  L10_SIG4 w0.109: v7(140.21,121.28) v5(140.97,121.28)
  BOTTOM w0.173: R794.2 140.69,121.77 v7(140.21,121.28)
PMIC_RESET_OUTN: length 23.6
  TOP w0.173: U3.G6 v8(138.25,126.33)
  L10_SIG4 w0.109: v7(138.3,114.27) 138.84,114.81 141.22,114.81 144.27,117.86 144.27,118.49 143.38,119.38 143.38,121.78 143.43,121.83 143.43,125.69 142.4,126.73 138.67,126.73 138.27,126.33 v8(138.25,126.33)
  BOTTOM w0.173: R9.1 138.14,126.45 v8(138.25,126.33) ; R833.1 v7(138.3,114.27)
PORZN: length 262.8
  TOP w0.173: R499.1 v3(73.41,75.56) ; R6.1 142.37,70.36 147.7,75.69 v8(147.7,76.96)
  L3_SIG1 w0.109: v8(159.05,47.75) 159.05,46.81 161.93,43.94 162.75,43.94 165.42,41.27 ; 165.42,41.27 164.59,41.27 158.88,35.56 158.88,32.77 147.19,21.08 147.19,13.44 142.39,8.64 141.1,8.64 138.62,11.11 135.81,11.11 133.23,13.7 133.23,14.46 125.9,21.78 110.41,21.78 109.77,22.43 108.55,22.43 107.94,21.82 87.34,21.82 86.82,22.34 70.71,22.34 68.2,24.85 68.2,33.79 66.04,35.95 66.04,59.44 64.52,60.96 v8(64.52,65.66) 70.87,72.01 70.87,73.91 72.52,75.56 v3(73.41,75.56) ; 165.42,41.27 v8(165.43,41.26)
  L4_SIG2 w0.114: v8(165.43,41.26) 165.43,45.33 159.08,51.68 159.08,66.98 149.1,76.96 v8(147.7,76.96)
  BOTTOM w0.173: R920.1 v8(64.52,65.66) ; R918.1 v8(159.05,47.75) ; R914.1 160.4,41.02 162.05,39.37 165.48,39.37 165.86,39.75 165.86,40.34 165.43,40.77 v8(165.43,41.26) 165.42,41.27 C213.1 164.23,41.29 U98.4
PR1_MII0_COL: length 376.6
  TOP w0.173: U102.33 v3(142.93,81.61)
  L3_SIG1 w0.109: v3(142.93,81.61) 139.75,81.61 138.68,82.68 138.68,85.54 138.09,86.13 138.09,87.51 136.14,89.46 136.14,89.92 135.38,90.68 v5(129.16,90.68)
  L4_SIG2 w0.114: v5(129.16,90.68) 128.78,91.06 128.78,106.68 129.9,107.8 129.9,113.31 128.14,115.06 125.3,115.06 119.91,120.45 119.91,122.91 121.16,124.16 121.16,129.41 119.51,131.06 119.51,134.38 v5(119.2,134.68)
  L9_SIG3 w0.114: v5(22.86,110.21) 26.64,106.43 26.64,100.61 28.26,98.99 28.26,94.95 31.54,91.67 33.22,91.67 33.93,90.96 33.93,81.05 32.77,79.88 30.73,79.88 28.62,77.77 27.24,77.77 26.94,77.47 26.94,76.06 26.25,75.38 26.25,65.47 24.46,63.68 24.46,51.43 27.56,48.34 27.56,47.5 28.5,46.56 28.5,34.04 37.57,24.97 40.31,24.97 41.61,23.67 41.61,22.71 53.26,11.05 60.12,11.05 60.25,11.18 63.66,11.18 63.84,11 92.15,11 93.04,10.11 95.99,10.11 96.27,10.39 102.95,10.39 103.78,11.23 124.54,11.23 133.78,20.47 133.78,48.65 128.65,53.78 128.65,60.55 127,62.2 127,64.01 124.46,66.55 120.93,66.55 119.3,68.17 119.3,70.05 123.01,73.76 123.01,76 122.43,76.58 122.43,83.2 126.24,87.01 126.24,87.38 128.6,89.74 128.6,90.12 v5(129.16,90.68)
  L10_SIG4 w0.109: v7(22.86,109.43) v5(22.86,110.21) ; v5(119.2,134.68) 119.19,134.68 v7(118.54,135.33)
  BOTTOM w0.173: R876.1 116.33,137.54 v7(118.54,135.33) ; 22.86,110.11 v7(22.86,109.43)
PR1_MII0_CRS: length 309.2
  TOP w0.173: U102.29 139.85,79.61 v3(139.07,80.39)
  L3_SIG1 w0.109: v3(139.07,80.39) 137.92,81.53 137.92,85.34 137.41,85.85 137.41,87.23 137.09,87.56 136.32,87.56 135.24,88.65 134.99,88.65 134.12,89.52 128.41,89.52 v5(127.89,90.04)
  L9_SIG3 w0.114: v5(127.89,90.04) 125.5,87.66 125.5,87.02 121.92,83.44 121.92,76.2 122.66,75.46 122.66,73.91 118.95,70.21 118.95,67.97 121.58,65.33 124.89,65.33 126.57,63.65 126.57,61.92 128.3,60.2 128.3,53.49 133.2,48.59 133.2,20.85 123.95,11.61 105.86,11.61 104.98,12.5 104.07,12.5 102.34,10.77 95.22,10.77 94.31,11.68 60,11.68 59.77,11.46 53.82,11.46 42.11,23.16 42.11,23.93 36.58,29.46 34.32,29.46 30.23,33.55 30.23,41.4 29.21,42.42 29.21,48.01 28.83,48.39 28.83,49.7 27.45,51.08 27.03,51.08 24.79,53.31 24.79,60.03 26.34,61.58 26.34,64.82 27.68,66.16 27.68,76.49 27.98,76.8 28.21,76.8 30.86,79.45 32.87,79.45 34.29,80.87 34.29,88.3 36.2,90.2 36.2,97.76 33.45,100.51 33.45,103.96 v5(29.84,107.57)
  L10_SIG4 w0.109: v7(26.92,107.57) v5(29.84,107.57)
  BOTTOM w0.173: R94.2 v7(26.92,107.57)
PR1_MII0_RXD0: length 243.8
  TOP w0.173: R873.2 v3(155.32,142.24) ; U102.35 v3(142.93,82.61)
  L3_SIG1 w0.109: v3(142.93,82.61) 139.39,82.61 139.02,82.97 139.02,85.68 138.43,86.27 138.43,87.65 136.91,89.17 136.91,89.66 135.38,91.19 v5(135.26,91.19) ; v3(155.32,142.24) v5(155.32,141.66)
  L4_SIG2 w0.114: v5(123.06,121.79) 130.43,121.79 133.86,118.36 133.86,114.81 133.06,114.01 133.06,110.86 134.57,109.35 134.57,108 135.71,106.86 135.71,94.79 136.02,94.49 136.02,91.95 v5(135.26,91.19) ; v5(155.32,141.66) 155.32,136.47 153.71,134.87 153.71,131.71 v5(154.13,131.29)
  L9_SIG3 w0.114: v5(154.13,131.29) 154.81,130.61 154.81,123.88 152.2,121.26 152.2,114.71 146.99,109.5 146.62,109.13 146.62,103.95 144.78,102.11 144.78,97.55 140.41,93.18 139.43,93.18 137.44,91.19 v5(135.26,91.19)
  L10_SIG4 w0.109: v5(123.06,121.79) 119.02,117.75 116.23,117.75 115.26,118.73 114.28,118.73 113.54,117.98 109.25,117.98 109.12,118.11 109.12,118.87 108.99,119 108.81,119 108.68,118.87 108.68,118.11 108.55,117.98 108.37,117.98 108.24,118.11 108.24,118.87 108.12,119 107.94,119 107.81,118.87 107.81,118.11 107.68,117.98 107.5,117.98 107.37,118.11 107.37,118.87 107.24,119 107.06,119 106.93,118.87 106.93,118.11 106.81,117.98 106.63,117.98 106.5,118.11 106.5,118.87 106.37,119 106.19,119 106.06,118.87 106.06,118.11 105.93,117.98 97.79,117.98 96.77,119 86.26,119 85.12,120.14 82.93,120.14 82.3,120.78 67.31,120.78 65.79,122.3 64.58,122.3 63.31,123.57 60.62,123.57 59.56,122.51 52.09,122.51 50.83,123.77 49.96,123.77 48.64,125.09 47.12,125.09 46.81,124.79 39.28,124.79 38.41,123.92 31.94,123.92 30.77,125.09 29.46,125.09 28.24,123.88 28.24,123.24 27.3,122.3 26.8,122.3 25.91,121.41 25.91,120.14 23.62,117.86 23.62,116.71 21.08,114.17 v7(21.08,112.9)
  BOTTOM w0.173: 21.08,113.66 v7(21.08,112.9)
PR1_MII0_RXD1: length 249
  TOP w0.173: R872.2 v3(153.29,142.24) ; U102.40 v3(142.93,85.11)
  L3_SIG1 w0.109: v3(153.29,142.24) 153.29,141.94 152.3,140.94 148.29,140.94 147.52,140.18 v5(147.02,140.18) ; v5(131.83,92.58) 135.51,92.58 140.05,88.05 140.55,88.05 141.38,87.22 141.38,86.66 v3(142.93,85.11)
  L4_SIG2 w0.114: v5(131.83,92.58) 130.94,92.58 129.92,93.6 129.92,106.55 130.78,107.42 130.78,113.69 126.24,118.24 123.57,118.24 v5(120.78,121.03)
  L9_SIG3 w0.114: v5(131.83,92.58) 131.83,94.74 132.84,95.76 134.24,95.76 137.41,98.93 139.07,98.93 142.24,102.11 142.24,107.19 148.38,113.33 148.38,118.51 149.29,119.42 149.29,126 149.73,126.44 149.73,129.51 148.94,130.31 148.94,134.3 149.1,134.46 149.1,137.8 147.02,139.88 v5(147.02,140.18)
  L10_SIG4 w0.109: v5(120.78,121.03) 119.13,119.38 106.68,119.38 105.41,120.65 102.74,120.65 101.47,119.38 98.33,119.38 98.21,119.51 98.21,120.01 98.08,120.14 97.9,120.14 97.77,120.01 97.77,119.51 97.64,119.38 97.46,119.38 97.33,119.51 97.33,120.01 97.2,120.14 97.02,120.14 96.9,120.01 96.9,119.51 96.77,119.38 96.59,119.38 96.46,119.51 96.46,120.01 96.33,120.14 96.15,120.14 96.02,120.01 96.02,119.51 95.89,119.38 95.71,119.38 95.59,119.51 95.59,120.01 95.46,120.14 95.28,120.14 95.15,120.01 95.15,119.51 95.02,119.38 94.84,119.38 94.71,119.51 94.71,120.01 94.58,120.14 94.4,120.14 94.27,120.01 94.27,119.51 94.15,119.38 93.97,119.38 93.84,119.51 93.84,120.01 93.71,120.14 93.53,120.14 93.4,120.01 93.4,119.51 93.27,119.38 93.09,119.38 92.96,119.51 92.96,120.01 92.84,120.14 92.65,120.14 92.53,120.01 92.53,119.51 92.4,119.38 92.22,119.38 92.09,119.51 92.09,120.01 91.96,120.14 91.78,120.14 91.65,120.01 91.65,119.51 91.53,119.38 91.34,119.38 91.22,119.51 91.22,120.01 91.09,120.14 90.91,120.14 90.78,120.01 90.78,119.51 90.65,119.38 90.47,119.38 90.34,119.51 90.34,120.01 90.21,120.14 90.03,120.14 89.91,120.01 89.91,119.51 89.78,119.38 89.6,119.38 89.47,119.51 89.47,120.01 89.34,120.14 89.16,120.14 89.03,120.01 89.03,119.51 88.9,119.38 88.72,119.38 88.59,119.51 88.59,120.01 88.47,120.14 88.29,120.14 88.16,120.01 88.16,119.51 88.03,119.38 87.85,119.38 87.72,119.51 87.72,120.01 87.59,120.14 87.41,120.14 87.28,120.01 87.28,119.51 87.16,119.38 86.5,119.38 85.36,120.52 83.18,120.52 82.55,121.16 68.45,121.16 65.6,124.01 53,124.01 52.52,124.49 50.67,124.49 48.92,126.24 42.86,126.24 42.36,125.73 39.6,125.73 38.23,124.36 36.07,124.36 34.79,125.64 28.48,125.64 24.96,122.12 24.96,121.54 21.59,118.17 21.59,115.57 19.81,113.79 v7(19.81,112.9)
  BOTTOM w0.173: 19.81,113.66 v7(19.81,112.9)
PR1_MII0_RXD2: length 248
  TOP w0.173: U102.37 v3(142.93,83.61) ; R871.2 v3(151.26,142.24)
  L3_SIG1 w0.109: v3(151.26,142.24) 150.6,141.58 147.8,141.58 v5(147.32,141.1) ; v3(142.93,83.61) 142.32,83.61 140.84,85.09 140.84,85.64 140.44,86.05 140.01,86.05 138.77,87.29 138.77,88.82 135.64,91.95 v5(131.19,91.95)
  L4_SIG2 w0.114: v5(131.19,91.95) 130.56,91.95 129.41,93.09 129.41,106.68 130.44,107.71 130.44,113.4 126.62,117.22 123.63,117.22 120.34,120.51 120.34,122.12 v5(120.78,122.55)
  L9_SIG3 w0.114: v5(131.19,91.95) 132.08,91.95 132.33,92.2 132.33,94.61 132.97,95.25 134.37,95.25 137.28,98.17 140.08,98.17 142.66,100.75 142.66,107.1 149.31,113.75 149.31,118.9 149.65,119.25 149.65,121.98 150.37,122.7 150.37,129.64 149.28,130.73 149.28,134.16 149.53,134.4 149.53,137.95 147.52,139.95 147.52,140.89 v5(147.32,141.1)
  L10_SIG4 w0.109: v7(18.54,112.9) 18.54,113.57 20.79,115.82 20.79,122.37 22.29,123.86 23.23,123.86 23.77,123.32 24.73,123.32 27.53,126.11 28.96,126.11 29.7,126.86 32.12,126.86 32.66,126.32 37.51,126.32 38.32,127.13 40.26,127.13 40.69,126.7 49.09,126.7 50.02,125.76 53.15,125.76 54.57,124.35 61.1,124.35 61.86,125.1 62.33,125.1 62.46,124.98 62.46,124.59 62.58,124.46 62.76,124.46 62.89,124.59 62.89,124.98 63.02,125.1 65.02,125.1 68.62,121.5 82.69,121.5 83.28,120.9 85.6,120.9 85.98,120.52 88.9,120.52 89.53,121.16 90.13,121.16 90.51,120.78 92.96,120.78 93.98,121.79 101.85,121.79 102.49,121.16 115.21,121.16 115.34,121.29 115.34,122.05 115.47,122.17 115.65,122.17 115.78,122.05 115.78,121.29 115.9,121.16 116.08,121.16 116.21,121.29 116.21,122.05 116.34,122.17 116.52,122.17 116.65,122.05 116.65,121.29 116.78,121.16 116.96,121.16 117.09,121.29 117.09,122.05 117.21,122.17 117.39,122.17 117.52,122.05 117.52,121.29 117.65,121.16 119.38,121.16 v5(120.78,122.55)
  BOTTOM w0.173: 18.54,113.66 v7(18.54,112.9)
PR1_MII0_RXD3: length 242.1
  TOP w0.173: U102.42 v3(142.93,86.11)
  L3_SIG1 w0.109: v5(130.81,93.47) 131.57,93.47 131.7,93.6 133.99,93.6 134.62,92.96 135.64,92.96 139.55,89.05 141.12,89.05 141.38,88.79 141.38,87.73 142.93,86.18 v3(142.93,86.11)
  L4_SIG2 w0.114: v5(130.81,93.47) 130.43,93.85 130.43,106.17 131.22,106.96 131.22,114.02 126.36,118.87 v5(125.35,118.87)
  L9_SIG3 w0.114: v5(130.81,93.47) 130.81,93.74 130.75,93.8 130.75,94.18 132.72,96.14 133.99,96.14 138.43,100.58 140.23,100.58 141.86,102.21 141.86,107.31 147.35,112.8 147.35,117.98 148.49,119.13 148.49,135.99 v5(148.46,136.02)
  L10_SIG4 w0.109: v7(17.53,114.55) 17.53,115.06 19.56,117.09 19.56,121.75 22.79,124.99 25.78,124.99 27.64,126.84 29.05,126.84 30.02,127.81 31.79,127.81 32.76,126.84 37.31,126.84 38.39,127.92 48.48,127.92 50.2,126.2 57.75,126.2 59.04,124.91 61.08,124.91 62.24,126.07 64.68,126.07 68.92,121.83 69.28,121.83 69.4,121.96 69.4,122.81 69.53,122.94 69.71,122.94 69.84,122.81 69.84,121.96 69.97,121.83 70.15,121.83 70.28,121.96 70.28,122.81 70.41,122.94 70.59,122.94 70.72,122.81 70.72,121.96 70.84,121.83 71.02,121.83 71.15,121.96 71.15,122.81 71.28,122.94 71.46,122.94 71.59,122.81 71.59,121.96 71.72,121.83 71.9,121.83 72.03,121.96 72.03,122.81 72.15,122.94 72.33,122.94 72.46,122.81 72.46,121.96 72.59,121.83 72.77,121.83 72.9,121.96 72.9,122.81 73.03,122.94 73.21,122.94 73.34,122.81 73.34,121.96 73.46,121.83 85.13,121.83 85.6,122.3 87.63,122.3 87.86,122.07 88.32,122.07 89,122.75 109.44,122.75 110.6,123.92 124.11,123.92 126.11,121.92 126.11,119.63 v5(125.35,118.87) ; v7(148.46,136.6) v5(148.46,136.02)
  BOTTOM w0.173: R92.2 v7(17.53,114.55) ; R870.2 147.45,137.62 v7(148.46,136.6)
PR1_MII0_RXDV: length 241.1
  TOP w0.173: U102.51 v3(142.93,90.61)
  L3_SIG1 w0.109: v3(142.93,90.61) 140.66,92.88 138.26,92.88 135.79,95.35 133.71,95.35 v5(132.84,94.49)
  L4_SIG2 w0.114: v5(132.84,94.49) 131.57,95.76 131.57,105.79 132.84,107.06 132.84,109.73 132.28,110.29 132.28,114.35 126.49,120.14 v5(125.35,120.14)
  L9_SIG3 w0.114: v5(146.56,140.97) 147.14,141.55 147.5,141.55 148.84,140.21 148.84,139.12 149.87,138.09 149.87,134.26 149.63,134.01 149.63,130.87 151.12,129.38 151.12,127.5 150.83,127.2 150.83,122.67 150.38,122.22 150.38,119.24 149.65,118.51 149.65,113.89 149.65,113.61 143,106.96 143,100.58 140.21,97.79 138.43,97.79 134.62,93.98 133.35,93.98 v5(132.84,94.49)
  L10_SIG4 w0.109: v5(125.35,120.14) 122.94,117.73 122.3,117.73 120.52,115.95 102.63,115.95 102.51,115.82 102.51,114.68 102.38,114.55 102.2,114.55 102.07,114.68 102.07,115.82 101.94,115.95 101.76,115.95 101.63,115.82 101.63,114.68 101.5,114.55 101.32,114.55 101.19,114.68 101.19,115.82 101.07,115.95 100.89,115.95 100.76,115.82 100.76,114.68 100.63,114.55 100.45,114.55 100.32,114.68 100.32,115.82 100.19,115.95 100.01,115.95 99.88,115.82 99.88,114.68 99.76,114.55 99.58,114.55 99.45,114.68 99.45,115.82 99.32,115.95 99.14,115.95 99.01,115.82 99.01,114.68 98.88,114.55 98.7,114.55 98.57,114.68 98.57,115.82 98.45,115.95 97.92,115.95 96.01,117.86 95.82,117.86 95.81,117.86 95.45,117.86 95.44,117.86 85.54,117.86 84.39,119 65.02,119 63.79,120.23 59.31,120.23 58.97,119.89 47.35,119.89 45.44,121.79 29.78,121.79 29.21,121.22 29.21,118.7 28.62,118.11 28.62,115.4 30.1,113.92 30.1,110.49 28.07,108.46 v7(26.16,108.46) ; v7(145.85,141.66) 146.53,140.97 v5(146.56,140.97)
  BOTTOM w0.173: v7(26.16,108.46) 26.16,108.97 25.15,109.98 25.15,111.12 R86.2 ; v7(145.85,141.66) 145.42,142.09 R869.2
PR1_MII0_RXER: length 211.1
  TOP w0.173: U102.44 v3(142.93,87.11)
  L3_SIG1 w0.109: v5(131.19,93.98) 134.24,93.98 134.49,94.23 135.64,94.23 139.32,90.55 140.21,90.55 141.72,89.04 141.72,88.32 v3(142.93,87.11)
  L4_SIG2 w0.114: v5(120.14,134.09) 121.54,132.69 121.54,120.93 122.96,119.51 v5(123.06,119.51) 126.24,119.51 131.67,114.07 131.67,106.78 130.94,106.05 130.94,94.23 v5(131.19,93.98)
  L10_SIG4 w0.109: v7(25.02,109.09) 25.02,111.69 25.91,112.58 25.91,119.19 28.32,121.6 28.32,121.6 28.34,121.63 28.34,122.31 29.6,123.57 30.92,123.57 31.02,123.48 36.48,123.48 37.22,122.73 38.02,122.73 39.65,124.36 44.12,124.36 46.43,122.05 50.86,122.05 51.24,121.67 51.63,121.67 51.88,121.92 65.5,121.92 67.06,120.37 67.86,120.37 67.99,120.24 67.99,120.02 68.11,119.89 68.29,119.89 68.42,120.02 68.42,120.24 68.55,120.37 68.73,120.37 68.86,120.24 68.86,120.02 68.99,119.89 69.17,119.89 69.3,120.02 69.3,120.24 69.42,120.37 69.61,120.37 69.73,120.24 69.73,120.02 69.86,119.89 70.04,119.89 70.17,120.02 70.17,120.24 70.3,120.37 70.48,120.37 70.61,120.24 70.61,120.02 70.74,119.89 70.92,119.89 71.04,120.02 71.04,120.24 71.17,120.37 71.35,120.37 71.48,120.24 71.48,120.02 71.61,119.89 71.79,119.89 71.92,120.02 71.92,120.24 72.05,120.37 72.23,120.37 72.35,120.24 72.35,120.02 72.48,119.89 72.66,119.89 72.79,120.02 72.79,120.24 72.92,120.37 73.1,120.37 73.23,120.24 73.23,120.02 73.36,119.89 73.54,119.89 73.67,120.02 73.67,120.24 73.79,120.37 82.11,120.37 82.69,119.78 84.71,119.78 85.92,118.57 96.53,118.57 98.31,116.8 98.78,116.8 98.91,116.92 98.91,117.47 99.03,117.6 99.21,117.6 99.34,117.47 99.34,116.92 99.47,116.8 99.65,116.8 99.78,116.92 99.78,117.47 99.91,117.6 100.09,117.6 100.22,117.47 100.22,116.92 100.34,116.8 100.53,116.8 100.65,116.92 100.65,117.47 100.78,117.6 100.96,117.6 101.09,117.47 101.09,116.92 101.22,116.8 101.4,116.8 101.53,116.92 101.53,117.47 101.66,117.6 101.84,117.6 101.96,117.47 101.96,116.92 102.09,116.8 102.27,116.8 102.4,116.92 102.4,117.47 102.53,117.6 102.71,117.6 102.84,117.47 102.84,116.92 102.97,116.8 120.35,116.8 v5(123.06,119.51) ; v7(119.51,134.09) v5(120.14,134.09)
  BOTTOM w0.173: v7(119.51,134.09) 118.41,134.09 117.35,135.15 113.33,135.15 110.36,138.13 110.36,140.84 R874.1 ; R87.2 24.38,110.87 24.38,109.73 v7(25.02,109.09)
PR1_MII0_RXLINK: length 472.5
  TOP w0.173: U102.31 139.99,80.61 v3(138.94,81.66)
  L3_SIG1 w0.109: v3(138.94,81.66) 138.3,82.3 138.3,85.44 137.75,85.99 137.75,87.37 135.64,89.49 135.64,89.92 135.41,90.14 128.68,90.14 v5(127.89,90.93)
  L9_SIG3 w0.114: v5(127.89,90.93) 125.04,88.09 125.04,87.17 121.51,83.64 121.51,73.28 118.59,70.36 118.59,67.67 126.57,59.69 126.57,58.57 127.89,57.25 127.89,53.31 132.77,48.44 132.77,20.93 123.75,11.91 106.58,11.91 105.36,13.13 103.66,13.13 101.75,11.23 96.19,11.23 95.25,12.17 76.86,12.17 76.05,12.98 67.16,12.98 66.65,12.47 59.39,12.47 58.8,11.89 56.82,11.89 55.75,12.95 53.19,12.95 43.21,22.94 43.21,23.49 36.89,29.81 35.27,29.81 30.81,34.26 30.81,49.38 29.72,50.47 28.7,50.47 27.86,51.31 27.86,53.8 27.61,54.05 27.61,55.19 28.17,55.75 28.17,57.73 26.7,59.2 26.7,64.62 28.06,65.98 28.06,74.59 28.8,75.34 28.8,76.71 31.08,78.99 32.97,78.99 34.65,80.67 34.65,87.93 36.58,89.87 36.58,98.58 34.54,100.62 34.54,103.86 27.18,111.23 27.18,116.4 28.45,117.67 28.45,120.56 28.15,120.86 27.98,120.86 27.18,121.67 25.95,121.67 v5(25.4,121.11) 25.4,122 22.31,125.09 17.93,125.09 15.75,127.28 15.75,127.89 14.99,128.65 11.64,128.65 8.76,131.53 v8(7.24,131.53)
  L10_SIG4 w0.109: v7(113.49,142.62) 99.43,142.62 98.68,141.88 91.82,141.88 90.65,140.72 90.65,136.3 89.79,135.43 85.01,135.43 78.46,141.99 69.72,141.99 64.39,147.32 25.91,147.32 17.02,138.43 16.26,138.43 9.91,132.08 7.79,132.08 v8(7.24,131.53) ; v7(25.4,121.87) v5(25.4,121.11)
  BOTTOM w0.173: R93.2 v8(7.24,131.53) ; U9.17 24.11,120.45 24.41,120.75 25.04,120.75 v5(25.4,121.11) v7(25.4,121.87) ; v7(113.49,142.62) 113.74,142.88 R875.1
PR1_MII0_TXD0: length 79.5
  TOP w0.173: U102.53 143.98,91.61 R81.2 v3(144.02,92.58)
  L3_SIG1 w0.109: v3(144.02,92.58) 141.38,95.22 141.38,96.1 140.44,97.04 139.94,97.04 138.13,98.86 138.13,99.32 136.88,100.56 136.88,101.91 131.71,107.08 128.57,107.08 126.49,109.16 126.49,112.42 116.18,122.73 116.18,124.38 115.11,125.45 115.11,126.32 119.67,130.88 120.27,130.88 123.34,133.94 127.87,133.94 130.07,136.14 131.2,136.14 133.3,138.24 133.3,140.36 v5(134.37,141.43)
  L10_SIG4 w0.109: v7(134.37,142.11) v5(134.37,141.43)
  BOTTOM w0.173: R867.2 v7(134.37,142.11)
PR1_MII0_TXD1: length 90.8
  TOP w0.173: v3(144.02,88.9) R84.2 143.99,88.11 U102.46
  L3_SIG1 w0.109: v5(132.33,141.43) 132.33,138.79 130.78,137.24 127.74,137.24 126.27,135.76 126.27,135.13 125.86,134.72 124.49,134.72 123.83,135.38 115.06,135.38 110.74,131.06 110.74,129.34 115.77,124.31 115.77,122.66 126.15,112.28 126.15,109.02 128.43,106.74 131.57,106.74 136.53,101.79 136.53,100.44 137.46,99.5 137.46,98.98 139.14,97.31 139.14,96.42 139.45,96.12 139.45,95.25 144.02,90.68 v3(144.02,88.9)
  L10_SIG4 w0.109: v7(132.33,142.11) v5(132.33,141.43)
  BOTTOM w0.173: R866.2 v7(132.33,142.11)
PR1_MII0_TXD2: length 73.1
  TOP w0.173: v3(136.4,99.69) 136.99,99.1 U103.37 142.66,99.1 143.26,99.69 R85.2 ; R753.2 v3(123.32,142.24)
  L3_SIG1 w0.109: v3(136.4,99.69) 136.02,100.08 136.02,101.09 133.48,103.63 130.89,103.63 125.81,108.71 125.81,112.14 114.53,123.42 114.53,125.04 110.13,129.44 110.13,132.46 116.49,138.81 122.76,138.81 123.32,139.37 v3(123.32,142.24)
PR1_MII0_TXD3: length 73.5
  TOP w0.173: R752.2 v3(121.28,142.24) ; R82.2 144.13,95.1 U103.29 139.97,95.1 138.68,96.39 v3(137.03,96.39)
  L3_SIG1 w0.109: v3(137.03,96.39) 137.03,98.3 135.59,99.74 135.59,101.01 133.35,103.25 129.8,103.25 128.15,104.9 128.15,105.85 125.48,108.52 125.48,112 114.12,123.35 114.12,124.95 109.78,129.29 109.78,132.59 118.54,141.35 119.4,141.35 120.29,142.24 v3(121.28,142.24)
PR1_MII0_TXEN: length 92.6
  TOP w0.173: v3(136.27,97.16) 137.41,97.16 137.47,97.1 U103.33 144.09,97.1 R80.2
  L3_SIG1 w0.109: v5(111.86,144.13) 112.8,143.19 112.8,137.29 108.61,133.1 108.61,129.24 113.36,124.49 113.36,123.16 124.71,111.8 124.71,108.33 127.41,105.64 127.41,103.69 128.52,102.58 132.56,102.58 133.99,101.15 133.99,98.93 135.76,97.16 v3(136.27,97.16)
  L10_SIG4 w0.109: v5(111.86,144.13) 121.58,144.13 124.1,141.61 130.43,141.61 130.94,142.11 v7(131.32,142.11)
  BOTTOM w0.173: R865.2 v7(131.32,142.11)
PR1_MII1_CRS: length 473.7
  TOP w0.173: R744.2 v3(105.41,142.11) ; U103.53 v3(142.93,107.1) ; R139.2 v3(38.61,97.28)
  L3_SIG1 w0.109: v5(35.69,95.35) 37.11,96.77 38.1,96.77 v3(38.61,97.28) ; v5(76.07,137.8) 76.83,137.03 78.51,137.03 79.27,137.8 84.84,137.8 86.6,139.56 96.87,139.56 97.83,140.51 99.47,140.51 100.28,139.7 101.98,139.7 104.39,142.11 v3(105.41,142.11) ; v5(141.35,106.93) 141.52,107.1 v3(142.93,107.1)
  L4_SIG2 w0.114: v5(35.69,95.35) 33.88,95.35 32.77,94.23 31.65,94.23 31.22,93.8 29.03,93.8 v5(28.78,93.55) 28.3,93.55 28.02,93.27 19.38,93.27 17.6,95.05 6.07,95.05 4.48,96.63 4.48,106.06 6.97,108.55 12.56,108.55 18.2,114.19 18.2,118.89 20.62,121.31 20.62,122.71 22.64,124.73 22.64,125.24 27.02,129.62 34.09,129.62 34.95,128.75 36.9,128.75 37.58,129.44 42.8,129.44 43.19,129.04 47,129.04 47.87,129.91 54.99,129.91 56.16,128.75 59.06,128.75 64.7,134.39 67.64,134.39 70.1,136.84 70.1,138.01 71.08,138.99 72.24,138.99 72.67,139.42 74.45,139.42 v5(76.07,137.8)
  L9_SIG3 w0.114: v5(28.78,93.55) 31.19,91.14 31.83,91.14 33.45,89.52 33.45,81.2 32.54,80.29 29.79,80.29 28.59,79.1 26.97,79.1 26.21,78.33 26.21,75.83 24.79,74.4 24.79,64.64 24.16,64.01 24.16,51.23 27.2,48.18 27.2,46.81 28.07,45.94 28.07,33.45 37.83,23.69 39.15,23.69 42.65,20.19 43.56,20.19 53.16,10.59 59,10.59 59.44,10.16 63.65,10.16 64.13,10.64 74.17,10.64 74.8,10.01 91.06,10.01 91.32,9.75 96.22,9.75 96.47,10.01 104.78,10.01 105.64,10.87 125.02,10.87 134.47,20.32 134.47,48.72 130,53.19 130,60.05 127.46,62.59 127.46,64.06 124.46,67.06 120.9,67.06 119.76,68.2 119.76,69.93 123.37,73.53 123.37,76.28 122.89,76.76 122.89,81.33 126.67,85.12 126.67,86.97 127.74,88.04 128.89,88.04 130.3,89.45 130.3,94.23 132.59,96.52 133.86,96.52 139.19,101.85 139.83,101.85 141.48,103.5 141.48,105.92 141.35,106.05 v5(141.35,106.93)
PR1_MII1_MR1_CLK: length 492.8
  TOP w0.173: U103.44 v3(142.93,102.6) ; v5(37.85,95.76) v3(38.61,95.76) ; R745.2 v3(107.91,142.28)
  L3_SIG1 w0.109: v3(107.91,142.28) 106.74,142.28 106.47,142.55 101.62,142.55 100.31,141.24 97.6,141.24 96.59,140.23 85.24,140.23 84.9,139.89 80.38,139.89 78.79,138.3 v5(77.98,138.3) ; v3(142.93,102.6) 142.93,101.21 147.53,96.61 147.53,87.71 143.51,83.69 143.51,80.52 142.11,79.12 v5(142.11,76.45) ; v3(38.61,95.76) v5(37.85,95.76)
  L4_SIG2 w0.114: v5(37.85,95.76) 37.85,94.57 36.41,93.13 31.75,93.13 31.65,93.23 29.73,93.23 28.83,92.33 28.19,92.33 27.99,92.53 19.58,92.53 17.41,94.7 5.93,94.7 4.14,96.49 4.14,106.2 6.83,108.89 12.42,108.89 17.86,114.33 17.86,119.03 20.17,121.34 20.17,122.74 22.3,124.87 22.3,125.38 27.55,130.63 38.1,130.63 38.47,130.26 55.14,130.26 55.83,129.56 57.43,129.56 58.12,130.26 60.08,130.26 64.55,134.73 67.5,134.73 69.76,136.99 69.76,138.19 71.56,139.99 72.13,139.99 72.31,139.8 73.67,139.8 74.36,140.49 75.16,140.49 77.34,138.3 v5(77.98,138.3)
  L10_SIG4 w0.109: v5(142.11,76.45) 142.11,62.27 141.98,62.14 141.1,62.14 140.97,62.01 140.97,61.83 141.1,61.7 141.98,61.7 142.11,61.58 142.11,61.39 141.98,61.27 141.1,61.27 140.97,61.14 140.97,60.96 141.1,60.83 141.98,60.83 142.11,60.7 142.11,60.52 141.98,60.39 141.1,60.39 140.97,60.26 140.97,60.08 141.1,59.96 141.98,59.96 142.11,59.83 142.11,59.65 141.98,59.52 141.1,59.52 140.97,59.39 140.97,59.21 141.1,59.08 141.98,59.08 142.11,58.95 142.11,58.77 141.98,58.65 141.1,58.65 140.97,58.52 140.97,58.34 141.1,58.21 141.98,58.21 142.11,58.08 142.11,57.9 141.98,57.77 141.1,57.77 140.97,57.64 140.97,57.46 141.1,57.33 141.98,57.33 142.11,57.21 142.11,57.03 141.98,56.9 141.1,56.9 140.97,56.77 140.97,56.59 141.1,56.46 141.98,56.46 142.11,56.33 142.11,54.61 141.3,53.8 141.12,53.8 140.35,54.57 140.17,54.57 140.04,54.44 140.04,54.26 140.81,53.49 140.81,53.31 140.68,53.18 140.5,53.18 139.73,53.95 139.55,53.95 139.42,53.82 139.42,53.64 140.19,52.87 140.19,52.69 140.06,52.56 139.88,52.56 139.11,53.33 138.93,53.33 138.8,53.21 138.8,53.02 139.57,52.25 139.57,52.07 139.45,51.94 139.27,51.94 138.49,52.72 138.31,52.72 138.18,52.59 138.18,52.41 138.96,51.63 138.96,51.45 138.83,51.33 138.65,51.33 137.88,52.1 137.69,52.1 137.57,51.97 137.57,51.79 138.34,51.02 138.34,50.84 138.21,50.71 138.03,50.71 137.26,51.48 137.08,51.48 136.95,51.35 136.95,51.17 137.72,50.4 137.72,50.22 137.59,50.09 137.41,50.09 136.64,50.86 136.46,50.86 136.33,50.73 136.33,50.55 137.1,49.78 137.1,49.6 136.97,49.47 136.79,49.47 136.02,50.24 135.84,50.24 135.71,50.11 135.71,49.93 136.48,49.16 136.48,48.98 135.28,47.78 135.28,24.63 123.48,12.83 121.77,12.83 119.66,10.72 106.28,10.72 104.45,8.9 91.07,8.9 90.68,8.51 72.61,8.51 71.64,9.48 63.19,9.48 59.46,13.21 57.47,13.21 56.98,13.71 56.98,14.02 56.15,14.85 55.32,14.85 51.13,19.04 47.63,19.04 46.3,20.37 42.73,20.37 37.83,25.26 36.62,25.26 35.48,26.4 35.48,28.88 31.51,32.84 28.93,32.84 26.38,35.39 26.38,39.66 23.75,42.29 23.75,47.24 22.69,48.31 22.69,79.71 24.26,81.28 24.26,82.42 25.27,83.44 25.65,83.44 26.92,84.71 26.92,85.85 33.91,92.84 34.92,92.84 v5(37.85,95.76)
PR1_MII1_RXD0: length 487.5
  TOP w0.173: v3(144.91,100.58) 144.89,100.6 U103.40 ; R750.2 v3(117.35,142.24)
  L3_SIG1 w0.109: v5(22.61,88.9) 20.45,88.9 19.56,89.79 17.65,89.79 15.11,92.33 15.11,96.9 15.49,97.28 15.49,100.97 14.86,101.6 14.86,113.28 15.71,114.14 15.71,124.65 19,127.94 21,127.94 23.93,130.86 42.34,130.86 48.39,136.91 61.98,136.91 62.27,136.61 67.77,136.61 74.38,143.21 98.55,143.21 100.08,144.74 100.08,149.63 101.07,150.62 115.49,150.62 116.33,149.78 116.33,143.26 v3(117.35,142.24) ; v5(144.91,78.11) 144.91,84.13 148.34,87.56 148.34,97.28 147.07,98.55 147.07,99.06 145.54,100.58 v3(144.91,100.58)
  L10_SIG4 w0.109: v7(33.15,101.35) 33.15,99.03 29.62,95.5 28.48,95.5 22.61,89.63 v5(22.61,88.9) 21.67,87.97 21.67,48.09 21,47.42 21,40.97 23.37,38.61 23.37,34.29 25.85,31.81 29.47,31.81 34.38,26.9 34.38,26.01 35.31,25.08 35.31,20.89 38.18,18.02 49.53,18.02 53.72,13.83 54.67,13.83 56.39,12.12 56.39,11.29 61.27,6.4 95.94,6.4 96.9,7.37 102.24,7.37 102.66,6.94 117.31,6.94 121.45,11.07 123.16,11.07 137.21,25.12 137.21,37.26 137.96,38.01 137.96,38.19 136.93,39.22 136.93,39.4 137.06,39.52 137.24,39.52 138.27,38.5 138.45,38.5 138.58,38.63 138.58,38.81 137.55,39.83 137.55,40.01 137.68,40.14 137.86,40.14 138.89,39.12 139.07,39.12 139.19,39.25 139.19,39.43 138.17,40.45 138.17,40.63 138.3,40.76 138.48,40.76 139.5,39.74 139.68,39.74 139.81,39.86 139.81,40.04 138.79,41.07 138.79,41.25 138.92,41.38 139.1,41.38 140.12,40.35 140.3,40.35 140.43,40.48 140.43,40.66 139.41,41.69 139.41,41.87 139.53,42 139.71,42 140.74,40.97 140.92,40.97 141.05,41.1 141.05,41.28 140.02,42.31 140.02,42.49 140.15,42.62 140.33,42.62 141.36,41.59 141.54,41.59 141.67,41.72 141.67,41.9 140.64,42.93 140.64,43.11 140.77,43.23 140.95,43.23 141.98,42.21 142.16,42.21 142.29,42.34 142.29,42.52 141.26,43.54 141.26,43.72 141.39,43.85 141.57,43.85 142.6,42.83 142.78,42.83 144.25,44.3 144.25,74.65 145.42,75.82 145.42,77.6 v5(144.91,78.11)
  BOTTOM w0.173: R133.2 v7(33.15,101.35)
PR1_MII1_RXD1: length 452.8
  TOP w0.173: U103.48 143.05,104.6 144.12,103.53 v3(145.57,103.53) ; R749.2 v3(115.32,142.24)
  L3_SIG1 w0.109: v5(145.92,78.11) 145.92,84.67 148.72,87.47 148.72,98.6 145.57,101.75 v3(145.57,103.53) ; v3(115.32,142.24) 115.32,143.41 113.74,144.98 102.62,144.98 99.89,142.25 97.18,142.25 96.17,141.24 84.7,141.24 84.37,140.91 80.38,140.91 79.44,140.91 78.04,139.51 75.75,139.51 75.05,138.81 v5(74.42,138.81)
  L4_SIG2 w0.114: v5(33.91,102.49) 30.99,102.49 27.69,105.79 27.69,106.3 20.84,113.15 20.84,115.61 19.56,116.89 19.56,118.01 22.83,121.29 22.83,121.95 23.65,122.76 23.65,124.99 27.53,128.88 33.76,128.88 34.57,128.07 37.18,128.07 37.48,128.36 47.28,128.36 48.15,129.23 54.71,129.23 55.87,128.07 59.35,128.07 64.88,133.6 67.83,133.6 71.51,137.29 72.9,137.29 v5(74.42,138.81)
  L10_SIG4 w0.109: v5(145.92,78.11) 145.96,78.07 145.96,72.8 144.69,71.53 144.69,41.56 143.83,40.71 143.65,40.71 143.17,41.19 142.99,41.19 142.87,41.06 142.87,40.88 143.34,40.4 143.34,40.22 143.22,40.09 143.04,40.09 142.56,40.57 142.38,40.57 142.25,40.44 142.25,40.26 142.73,39.78 142.73,39.6 142.6,39.47 142.42,39.47 141.94,39.95 141.76,39.95 141.63,39.83 141.63,39.64 142.11,39.17 142.11,38.98 141.98,38.86 141.8,38.86 141.32,39.34 141.14,39.34 141.01,39.21 141.01,39.03 141.49,38.55 141.49,38.37 141.36,38.24 141.18,38.24 140.7,38.72 140.52,38.72 140.39,38.59 140.39,38.41 140.87,37.93 140.87,37.75 140.74,37.62 140.56,37.62 140.08,38.1 139.9,38.1 139.77,37.97 139.77,37.79 140.25,37.31 140.25,37.13 140.13,37 139.94,37 139.47,37.48 139.28,37.48 139.16,37.35 139.16,37.17 139.64,36.69 139.64,36.51 139.51,36.38 139.33,36.38 138.85,36.86 138.67,36.86 138.54,36.73 138.54,36.55 139.02,36.07 139.02,35.89 138.89,35.77 138.71,35.77 138.23,36.24 138.05,36.24 137.92,36.12 137.92,35.94 138.4,35.46 138.4,35.28 137.92,34.8 137.92,25.35 123.06,10.49 121.34,10.49 117.45,6.6 102.25,6.6 102.17,6.68 97.76,6.68 97.14,6.07 61.01,6.07 49.55,17.53 38.2,17.53 34.8,20.93 34.8,24.31 27.64,31.47 25.55,31.47 22.99,34.03 22.99,36.7 20.66,39.03 20.66,47.71 21.34,48.39 21.34,88.84 27,94.51 27,99.14 30.35,102.49 v7(33.15,102.49) v5(33.91,102.49)
  BOTTOM w0.173: v5(33.91,102.49) v7(33.15,102.49)
PR1_MII1_RXD2: length 326.6
  TOP w0.173: R748.2 v3(31.16,93.12) ; U103.46 143.28,103.6 144.15,102.74 v3(146.18,102.74) ; R136.2 v3(41.27,103)
  L3_SIG1 w0.109: v5(22.29,90.61) 27.59,90.61 30.1,93.12 v3(31.16,93.12) ; v3(146.18,102.74) 147.45,102.74 149.07,101.12 149.07,87.34 146.56,84.83 v5(146.56,78.74) ; v3(41.27,103) v5(41.27,102.23)
  L10_SIG4 w0.109: v5(146.56,78.74) 146.56,72.64 145.34,71.42 145.34,41.58 138.3,34.54 138.3,25.26 123.05,10.01 122.44,10.01 117.84,5.41 115.27,5.41 114.6,4.75 110.44,4.75 109.56,5.63 60.97,5.63 50.34,16.26 38.99,16.26 34.18,21.07 34.18,24.32 27.37,31.13 25.41,31.13 22.4,34.14 22.4,36.53 19.56,39.37 19.56,47.4 21,48.84 21,89.32 v5(22.29,90.61) 23.85,92.18 23.85,97.75 25.8,99.69 26.8,99.69 30.39,103.29 35.91,103.29 37.41,101.78 40.82,101.78 v5(41.27,102.23)
PR1_MII1_RXD3: length 503.7
  TOP w0.173: R137.2 v3(38.61,104.77) ; U103.31 143,96.1 143.3,95.81 145.59,95.81 145.8,96.01 v3(149.61,96.01) ; R747.2 v3(110.69,142.88)
  L3_SIG1 w0.109: v3(110.69,142.88) 109.52,144.04 102.16,144.04 100.03,141.91 97.32,141.91 96.31,140.91 84.87,140.91 84.54,140.57 79.61,140.57 78.42,139.38 78.39,139.38 78.18,139.17 75.89,139.17 74.93,138.21 v5(73.02,138.21) ; v3(149.61,96.01) 149.61,87.4 147.19,84.99 v5(147.19,79.38) ; v3(38.61,104.77) v5(39.37,104.77)
  L4_SIG2 w0.114: v5(73.02,138.21) 70.79,138.21 70.45,137.87 70.45,136.7 67.79,134.04 64.84,134.04 59.2,128.41 56.02,128.41 54.85,129.57 48.01,129.57 47.14,128.7 37.33,128.7 37.04,128.41 34.79,128.41 33.93,129.26 27.15,129.26 22.99,125.09 22.99,124.59 21.08,122.68 21.08,121.28 18.54,118.75 18.54,114.05 12.7,108.2 7.11,108.2 4.83,105.92 4.83,96.77 6.21,95.39 21.23,95.39 21.5,95.12 30.61,95.12 32.05,96.56 37.38,96.56 39.81,98.99 39.81,104.34 v5(39.37,104.77)
  L10_SIG4 w0.109: v5(147.19,79.38) 147.19,72.39 146.69,71.88 146.69,42.04 143.85,39.2 143.85,39.02 144.36,38.52 144.36,38.34 144.23,38.21 144.05,38.21 143.54,38.71 143.36,38.71 143.23,38.59 143.23,38.41 143.74,37.9 143.74,37.72 143.61,37.59 143.43,37.59 142.93,38.1 142.74,38.1 142.62,37.97 142.62,37.79 143.12,37.28 143.12,37.1 142.99,36.97 142.81,36.97 142.31,37.48 142.13,37.48 142,37.35 142,37.17 142.5,36.66 142.5,36.48 142.37,36.36 142.19,36.36 141.69,36.86 141.51,36.86 141.38,36.73 141.38,36.55 141.88,36.05 141.88,35.87 141.76,35.74 141.58,35.74 141.07,36.24 140.89,36.24 140.76,36.11 140.76,35.93 141.27,35.43 141.27,35.25 141.14,35.12 140.96,35.12 140.45,35.62 140.27,35.62 140.14,35.5 140.14,35.31 140.65,34.81 140.65,34.63 140.52,34.5 140.34,34.5 139.83,35.01 139.65,35.01 138.68,34.04 138.68,25.16 123.18,9.65 122.78,9.65 117.53,4.41 110.15,4.41 109.26,5.29 59.78,5.29 50.34,14.73 40,14.73 33.48,21.26 33.48,24.32 27.02,30.79 25.27,30.79 21.84,34.22 21.84,35.18 19.18,37.85 19.18,47.5 20.66,48.98 20.66,89.62 22.91,91.87 22.91,98.7 25.3,101.09 27.72,101.09 30.25,103.62 35.43,103.62 36.59,104.77 v5(39.37,104.77)
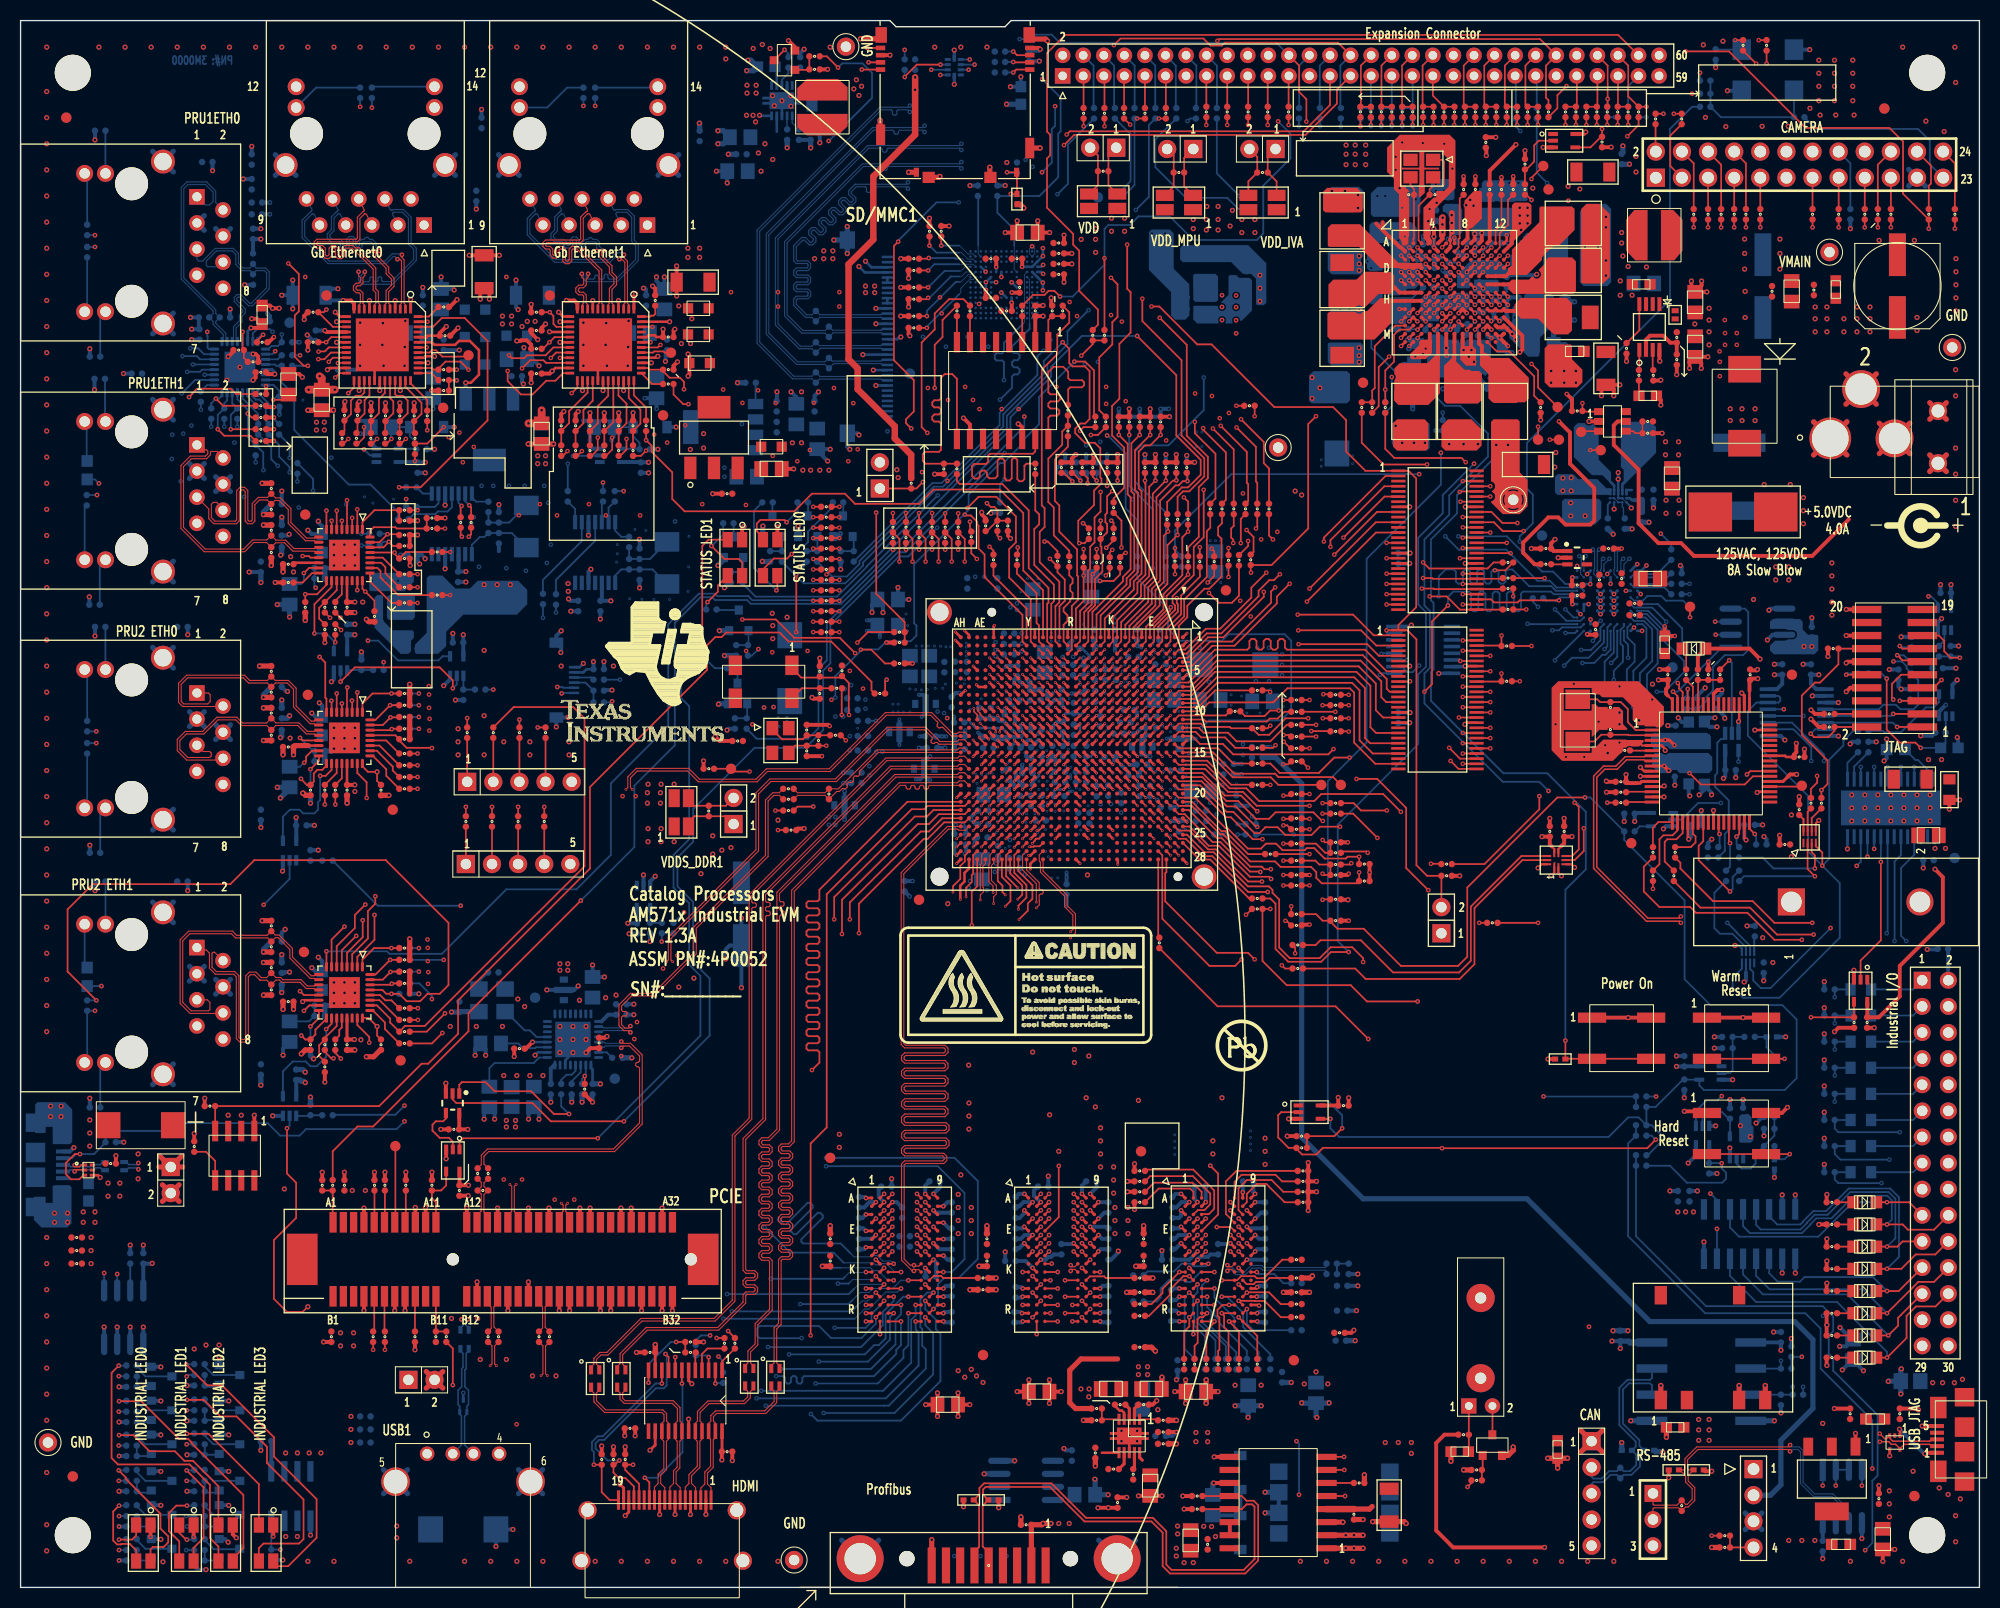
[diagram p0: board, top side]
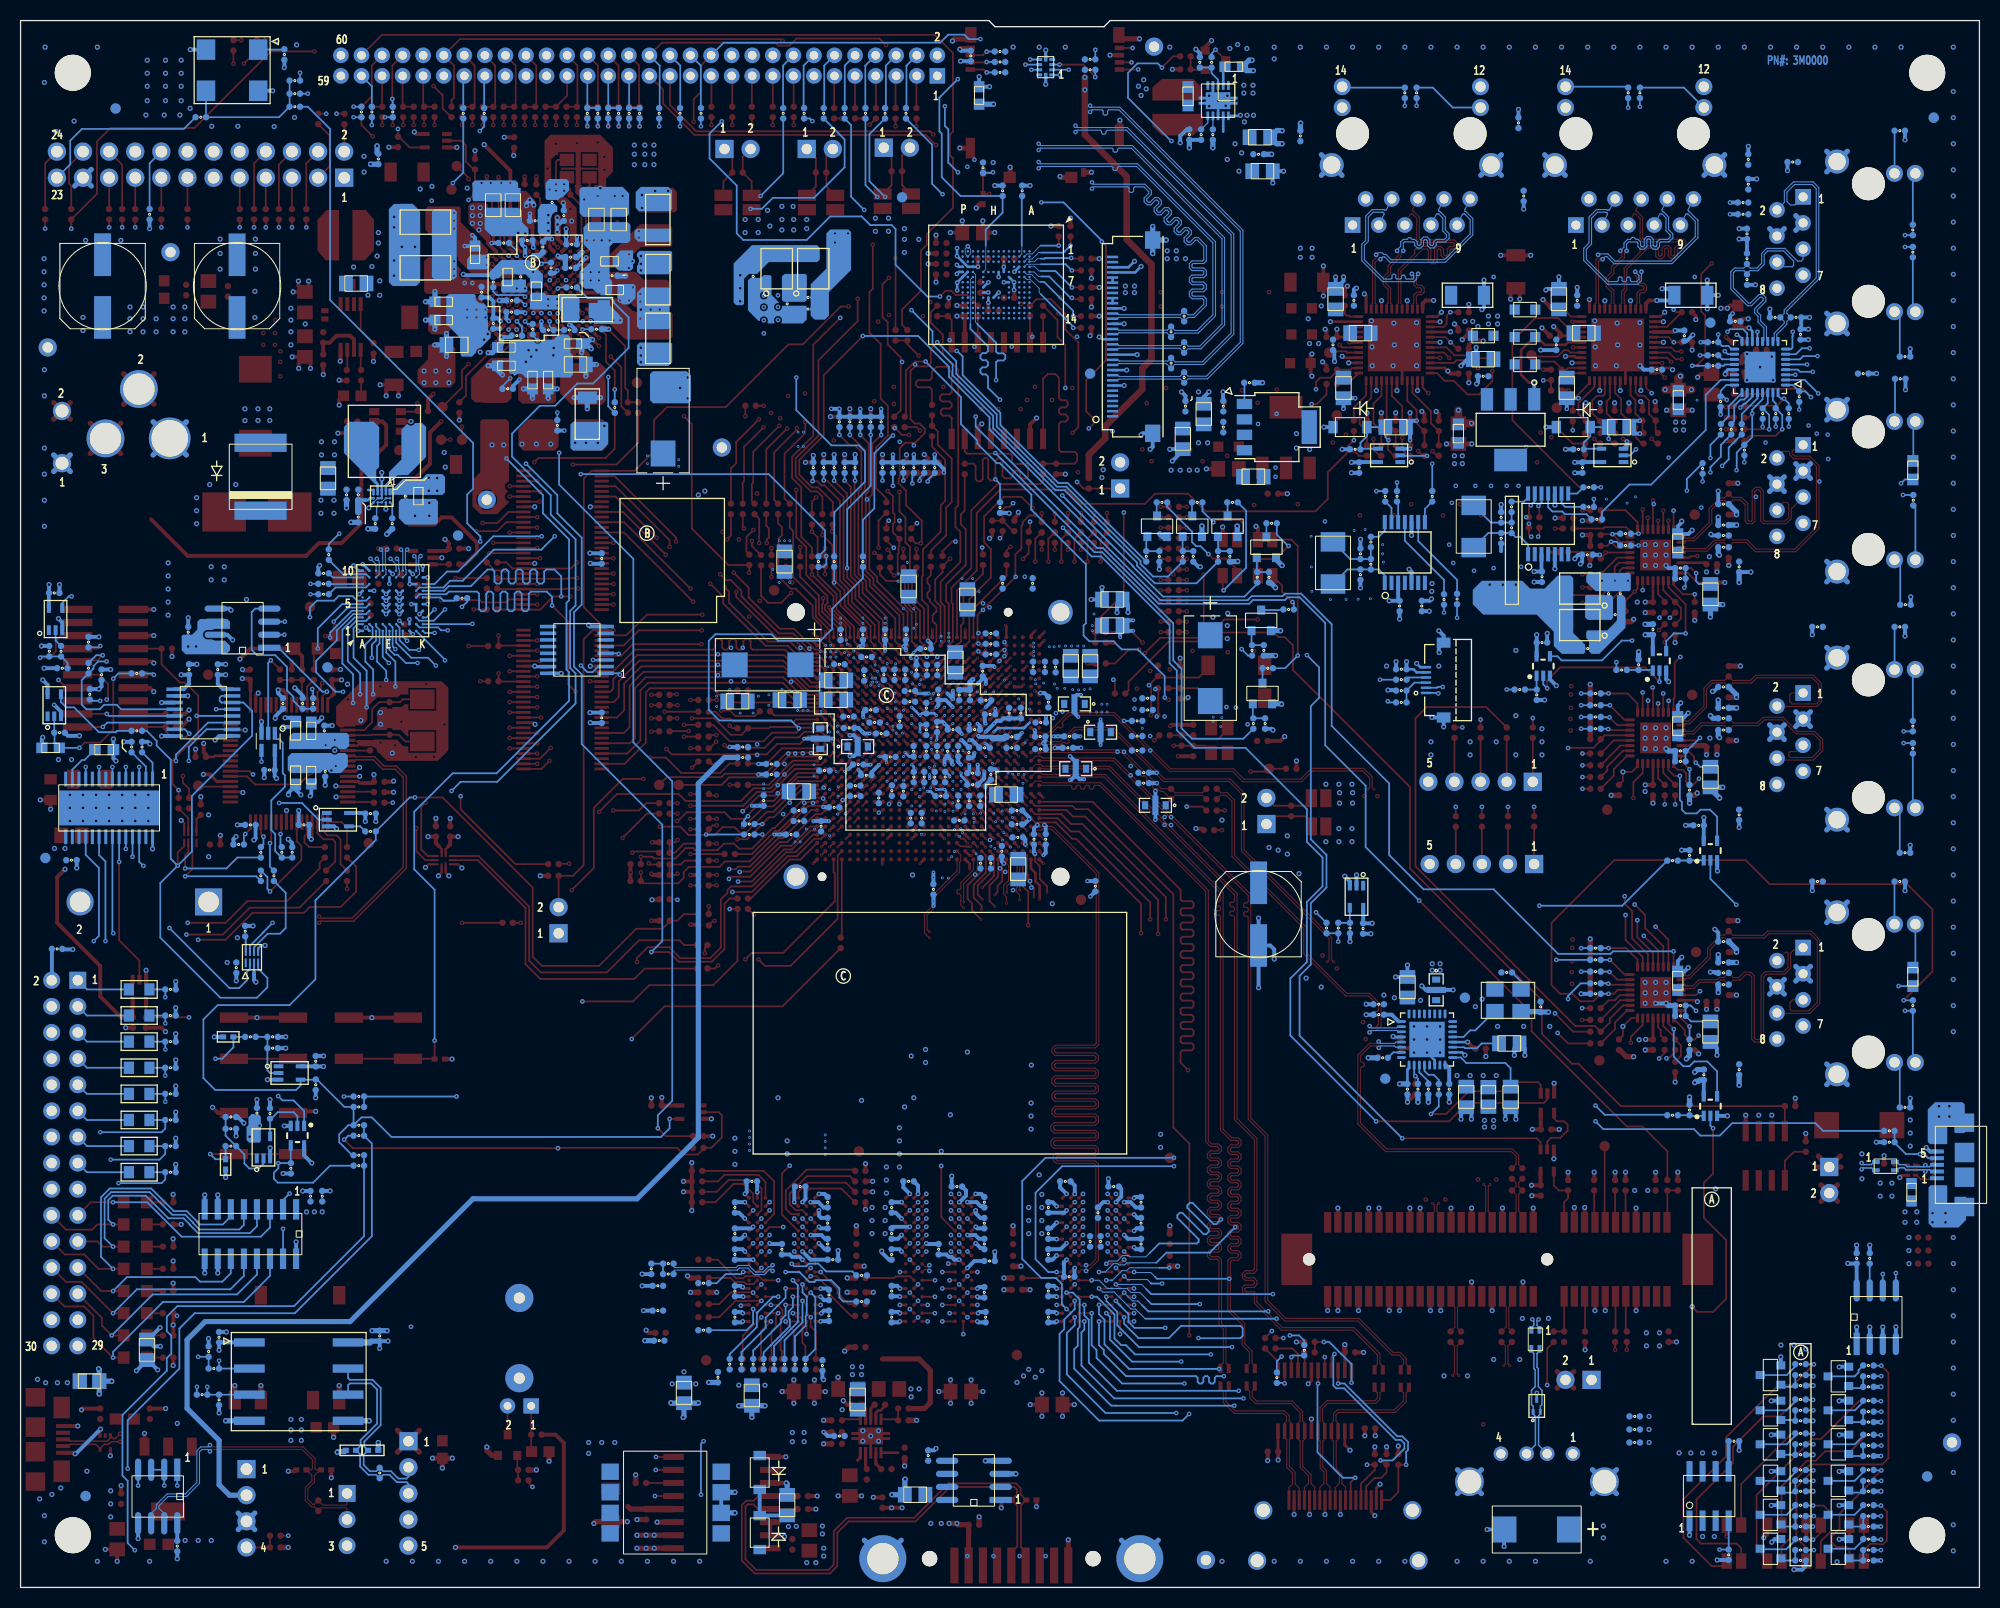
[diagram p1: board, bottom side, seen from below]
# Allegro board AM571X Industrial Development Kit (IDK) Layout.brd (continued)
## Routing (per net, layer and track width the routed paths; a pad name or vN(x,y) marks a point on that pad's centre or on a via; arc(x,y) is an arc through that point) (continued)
PR1_MII1_RXDV: length 491.9
  TOP w0.173: U103.42 144.52,101.6 v3(144.53,101.6) ; v5(41.02,96.52) v3(41.78,96.52) ; R746.2 v3(108.58,142.88)
  L3_SIG1 w0.109: v5(78.69,138.83) 80.09,140.23 84.73,140.23 85.07,140.57 96.45,140.57 97.46,141.58 100.17,141.58 101.48,142.89 108.57,142.89 v3(108.58,142.88) ; v3(41.78,96.52) v5(41.02,96.52) ; v5(142.75,77.47) 142.75,79.28 143.85,80.38 143.85,83.55 147.96,87.66 147.96,96.66 144.22,100.4 144.22,101.3 v3(144.53,101.6)
  L4_SIG2 w0.114: v5(78.69,138.83) 76.64,140.88 71.66,140.88 66.22,135.43 62.26,135.43 59.69,132.87 59.69,131.67 58.62,130.6 38.74,130.6 38.35,130.99 27.42,130.99 21.96,125.52 21.96,125.01 19.1,122.16 19.1,120.76 17.51,119.17 17.51,114.47 12.27,109.23 6.69,109.23 3.8,106.34 3.8,96.35 5.78,94.36 16.56,94.36 18.97,91.95 28.96,91.95 29.37,92.37 29.78,92.37 29.96,92.19 33.26,92.19 33.6,92.53 33.96,92.53 34.3,92.19 37.73,92.19 41.02,95.48 v5(41.02,96.52)
  L10_SIG4 w0.109: v5(41.02,96.52) 37.99,96.52 34.65,93.17 33.77,93.17 22.35,81.76 22.35,46.2 22.27,46.12 22.27,41.53 25.15,38.65 25.15,35.59 28.25,32.48 29.75,32.48 35.05,27.18 35.05,26.29 36.58,24.77 37.74,24.77 42.48,20.03 45.86,20.03 47.19,18.7 50.77,18.7 56.59,12.88 59.32,12.88 63.05,9.14 71.5,9.14 72.64,8 90.81,8 91.37,8.56 104.59,8.56 105.56,9.53 106.72,9.53 106.85,9.65 106.85,10.16 106.97,10.29 107.16,10.29 107.28,10.16 107.28,9.65 107.41,9.53 107.59,9.53 107.72,9.65 107.72,10.16 107.85,10.29 108.03,10.29 108.16,10.16 108.16,9.65 108.29,9.53 108.47,9.53 108.59,9.65 108.59,10.16 108.72,10.29 108.9,10.29 109.03,10.16 109.03,9.65 109.16,9.53 109.34,9.53 109.47,9.65 109.47,10.16 109.6,10.29 109.78,10.29 109.9,10.16 109.9,9.65 110.03,9.53 110.21,9.53 110.34,9.65 110.34,10.16 110.47,10.29 110.65,10.29 110.78,10.16 110.78,9.65 110.91,9.53 111.09,9.53 111.22,9.65 111.22,10.16 111.34,10.29 111.52,10.29 111.65,10.16 111.65,9.65 111.78,9.53 111.96,9.53 112.09,9.65 112.09,10.16 112.22,10.29 112.4,10.29 112.53,10.16 112.53,9.65 112.65,9.53 112.83,9.53 112.96,9.65 112.96,10.16 113.09,10.29 113.27,10.29 113.4,10.16 113.4,9.65 113.53,9.53 113.71,9.53 113.84,9.65 113.84,10.16 113.96,10.29 114.15,10.29 114.27,10.16 114.27,9.65 114.4,9.53 114.58,9.53 114.71,9.65 114.71,10.16 114.84,10.29 115.02,10.29 115.15,10.16 115.15,9.65 115.28,9.53 116.88,9.53 117.01,9.65 117.01,10.01 117.14,10.13 117.32,10.13 117.45,10.01 117.45,9.65 117.58,9.53 117.76,9.53 117.89,9.65 117.89,10.01 118.01,10.13 118.19,10.13 118.32,10.01 118.32,9.65 118.45,9.53 118.94,9.53 121.89,12.47 123.61,12.47 135.62,24.49 135.62,42.4 137.4,44.18 137.4,44.36 136.44,45.33 136.44,45.51 136.57,45.63 136.75,45.63 137.71,44.67 137.89,44.67 138.02,44.8 138.02,44.98 137.06,45.94 137.06,46.12 137.19,46.25 137.37,46.25 138.33,45.29 138.51,45.29 138.64,45.42 138.64,45.6 137.68,46.56 137.68,46.74 137.8,46.87 137.98,46.87 138.95,45.91 139.13,45.91 142.75,49.53 v5(142.75,77.47)
PR1_MII1_RXER: length 326.7
  TOP w0.173: v5(37.85,98.55) v3(38.61,98.55)
  L3_SIG1 w0.109: v3(38.61,98.55) v5(37.85,98.55)
  L10_SIG4 w0.109: v7(134.83,90.21) 134.44,89.82 134.44,86.54 135.76,85.22 135.76,80.95 138.48,78.23 142.88,78.23 144.17,76.94 144.17,75.46 143.57,74.86 143.57,49.72 142.98,49.13 142.98,48.95 143.88,48.05 143.88,47.87 143.75,47.74 143.57,47.74 142.67,48.64 142.49,48.64 142.36,48.51 142.36,48.33 143.26,47.43 143.26,47.25 143.13,47.12 142.95,47.12 142.05,48.02 141.87,48.02 141.74,47.89 141.74,47.71 142.64,46.81 142.64,46.63 142.51,46.5 142.33,46.5 141.43,47.4 141.25,47.4 141.12,47.27 141.12,47.09 142.02,46.19 142.02,46.01 141.89,45.88 141.71,45.88 140.82,46.78 140.63,46.78 140.51,46.65 140.51,46.47 141.4,45.57 141.4,45.39 141.28,45.27 141.1,45.27 140.2,46.16 140.02,46.16 139.89,46.03 139.89,45.85 140.79,44.96 140.79,44.78 140.66,44.65 140.48,44.65 139.58,45.54 139.4,45.54 139.27,45.42 139.27,45.24 140.17,44.34 140.17,44.16 140.04,44.03 139.86,44.03 138.96,44.93 138.78,44.93 138.65,44.8 138.65,44.62 139.55,43.72 139.55,43.54 139.42,43.41 139.24,43.41 138.34,44.31 138.16,44.31 137.25,43.39 137.25,43.21 137.7,42.76 137.7,42.58 137.57,42.45 137.39,42.45 136.94,42.9 136.76,42.9 136.63,42.78 136.63,42.59 137.34,41.89 137.34,41.71 137.21,41.58 137.03,41.58 136.32,42.29 136.14,42.29 135.96,42.11 135.96,36.68 136.09,36.55 136.73,36.55 136.86,36.42 136.86,36.24 136.73,36.11 136.09,36.11 135.96,35.99 135.96,35.8 136.09,35.68 136.73,35.68 136.86,35.55 136.86,35.37 136.73,35.24 136.09,35.24 135.96,35.11 135.96,34.93 136.09,34.8 136.73,34.8 136.86,34.67 136.86,34.49 136.73,34.37 136.09,34.37 135.96,34.24 135.96,34.06 136.09,33.93 136.73,33.93 136.86,33.8 136.86,33.62 136.73,33.49 136.09,33.49 135.96,33.36 135.96,33.18 136.09,33.06 136.73,33.06 136.86,32.93 136.86,32.75 136.73,32.62 136.09,32.62 135.96,32.49 135.96,32.31 136.09,32.18 136.73,32.18 136.86,32.05 136.86,31.87 136.73,31.74 136.09,31.74 135.96,31.62 135.96,24.35 123.45,11.84 121.73,11.84 118.1,8.21 117.11,8.21 116.98,8.08 116.98,7.49 116.85,7.37 116.67,7.37 116.54,7.49 116.54,8.08 116.42,8.21 116.23,8.21 116.11,8.08 116.11,7.49 115.98,7.37 115.8,7.37 115.67,7.49 115.67,8.08 115.54,8.21 115.36,8.21 115.23,8.08 115.23,7.49 115.11,7.37 114.92,7.37 114.8,7.49 114.8,8.08 114.67,8.21 114.49,8.21 114.36,8.08 114.36,7.49 114.23,7.37 114.05,7.37 113.92,7.49 113.92,8.08 113.79,8.21 112.65,8.21 111.72,7.28 111.15,7.28 111.02,7.41 111.02,7.75 110.9,7.87 110.72,7.87 110.59,7.75 110.59,7.41 110.46,7.28 110.28,7.28 110.15,7.41 110.15,7.75 110.02,7.87 109.84,7.87 109.71,7.75 109.71,7.41 109.59,7.28 102.83,7.28 102.36,7.75 96.39,7.75 95.93,7.29 72.34,7.29 70.82,8.8 60.19,8.8 54.82,14.17 53.86,14.17 49.67,18.36 40.19,18.36 38.99,19.56 38.99,21.46 35.69,24.77 35.69,25.18 34.71,26.15 34.71,27.04 29.61,32.14 27.9,32.14 24.64,35.41 24.64,38.1 21.93,40.8 21.93,46.26 22.01,46.34 22.01,87.42 33.15,98.55 v5(37.85,98.55)
  BOTTOM w0.173: U104.3 v7(134.83,90.21)
PR1_MII1_RXLINK: length 336.8
  TOP w0.173: U13.17 29.75,97.52 28.83,96.6 v8(27.69,96.6) R131.1 ; U103.51 v3(142.93,106.1)
  L3_SIG1 w0.109: v5(148.59,103.5) 147.57,103.5 146.63,104.44 144.59,104.44 v3(142.93,106.1)
  L4_SIG2 w0.114: v8(7.62,107.38) 10.68,107.38 21.46,96.6 v8(27.69,96.6)
  L9_SIG3 w0.114: v8(27.69,96.6) 27.05,95.97 27.05,93.17 29.51,90.7 31.44,90.7 32.31,89.83 32.31,86.87 33.08,86.09 33.08,81.39 32.38,80.7 28.69,80.7 27.57,79.58 26.57,79.58 25.83,78.84 25.83,76.32 24.41,74.9 24.41,64.9 22.86,63.35 22.86,51.99 26.54,48.31 26.54,33.02 35.08,24.49 35.08,20.42 37.64,17.86 45.14,17.86 53.54,9.45 59.64,9.45 59.84,9.65 65,9.65 65.63,10.29 73.91,10.29 74.65,9.55 90.88,9.55 91.34,9.09 96.14,9.09 96.6,9.55 104.83,9.55 105.77,10.49 114.5,10.49 115.6,9.4 119.05,9.4 119.94,10.29 124.97,10.29 135.15,20.47 135.15,48.59 130.62,53.12 130.62,62.2 129.26,63.56 129.26,65.53 127.89,66.9 127.89,68.03 127,68.92 127,71.77 128.19,72.96 129.4,72.96 136.14,79.7 136.14,85.55 139.95,89.36 139.95,91.06 147.7,98.81 147.7,102.62 v5(148.59,103.5)
  BOTTOM w0.173: R138.2 7.24,107.77 v8(7.62,107.38)
PR1_MII_MR0_CLK: length 216.6
  TOP w0.173: v3(139.42,142.24) 139.45,142.27 R868.2 ; U102.48 v3(142.93,89.11)
  L3_SIG1 w0.109: v3(142.93,89.11) 141.72,90.32 141.72,90.95 140.69,91.98 140.69,92.29 140.44,92.55 137.96,92.55 135.89,94.61 133.73,94.61 v5(133.6,94.49) ; v3(139.42,142.24) 139.42,140.76 138.29,139.63 136.71,139.63 136.37,139.29 136.37,138.58 134.5,136.71 133.81,136.71 133.3,136.2 133.3,135.26 130.18,132.13 v5(124.08,132.13)
  L4_SIG2 w0.114: v5(124.08,132.13) 121.92,129.97 121.92,122.12 122.89,121.16 v5(124.21,121.16) 126.85,121.16 132.72,115.29 132.72,110.46 134.11,109.07 134.11,103.42 133.98,103.29 132.62,103.29 132.49,103.15 132.49,102.96 132.62,102.83 133.98,102.83 134.11,102.7 134.11,102.51 133.98,102.37 132.62,102.37 132.49,102.24 132.49,102.05 132.62,101.92 133.98,101.92 134.11,101.78 134.11,101.59 133.98,101.46 132.62,101.46 132.49,101.33 132.49,101.14 132.62,101 133.98,101 134.11,100.87 134.11,100.68 133.98,100.54 132.62,100.54 132.49,100.41 132.49,100.22 132.62,100.09 133.98,100.09 134.42,99.64 134.42,95.31 v5(133.6,94.49)
  L10_SIG4 w0.109: v5(124.21,121.16) 124.21,119.89 122.38,118.07 122.16,118.07 120.55,116.46 98.17,116.46 96.39,118.24 85.78,118.24 84.57,119.44 67.5,119.44 65.46,121.48 62.42,121.48 61.62,120.67 60.18,120.67 59.37,121.48 54.1,121.48 53.15,120.52 49.95,120.52 49.4,121.07 48.75,121.07 48.72,121.03 48.7,121.03 48.32,120.65 47.21,120.65 44.29,123.57 39.48,123.57 38.21,122.29 30.61,122.29 29.97,122.94 29.59,122.94 28.77,122.12 28.77,120.34 26.8,118.36 26.8,113.65 26.93,113.52 27.28,113.52 27.41,113.39 27.41,113.21 27.28,113.08 26.93,113.08 26.8,112.95 26.8,112.77 26.93,112.64 27.28,112.64 27.41,112.52 27.41,112.34 27.28,112.21 26.93,112.21 26.8,112.08 26.8,111.9 26.93,111.77 27.28,111.77 27.41,111.64 27.41,111.46 27.28,111.33 26.93,111.33 26.8,111.21 26.8,110.49 v7(26.16,109.86)
  BOTTOM w0.173: R83.2 26.16,111.12 v7(26.16,109.86)
PR1_MII_MT0_CLK: length 71.5
  TOP w0.173: R79.2 144.08,98.1 U103.35 137.35,98.1 137.29,98.17 v3(136.4,98.17) ; R751.2 v3(119.38,142.24)
  L3_SIG1 w0.109: v3(136.4,98.17) 135.49,98.17 134.49,99.17 134.49,101.12 132.7,102.91 128.66,102.91 127.81,103.76 127.81,105.71 125.12,108.4 125.12,111.88 113.72,123.28 113.72,124.72 109.19,129.24 109.19,132.82 118.62,142.24 v3(119.38,142.24)
PROFIBUS_A: length 52
  TOP w0.173: 114.94,8.89 U74.12 118.76,8.89 119.22,8.43 119.93,8.43 120.36,8 120.36,2.61 119.1,1.36 111.79,1.36 111.07,2.07 111.07,5.33 109.98,6.42 103.46,6.42 100.1,9.78 93.85,9.78 93.6,9.53 93.6,9.02 U81.1 93.57,7.96 93.57,3.99 94.15,3.41 J14.3
PROFIBUS_B: length 51.4
  TOP w0.173: 114.94,7.62 U74.13 118.76,7.62 119.22,8.08 119.78,8.08 120,7.86 120,2.76 118.95,1.71 111.93,1.71 111.42,2.22 111.42,5.47 110.12,6.77 103.61,6.77 100.25,10.13 93.71,10.13 93.25,9.67 93.25,9.06 U80.1 93.22,7.99 93.22,3.94 92.76,3.48 J14.8
PRU1ETH0_25MHZCLK: length 20.9
  BOTTOM w0.173: R310.2 36.7,104.6 34.04,107.27 31.92,107.27 26.62,112.57 26.62,115.98 25.15,117.45 U9.23
PRU1ETH0_COL: length 41.9
  TOP w0.173: R104.2 22.48,113.79 v8(22.1,114.17)
  L9_SIG3 w0.114: v8(7.24,130.38) 8.89,130.38 16,123.27 16,121.75 14.99,120.73 14.99,118.19 16.89,116.28 16.89,114.1 20.83,110.16 20.83,109.68 v5(22.1,108.41)
  L10_SIG4 w0.109: v7(23.62,108.67) 22.35,108.67 v5(22.1,108.41)
  BOTTOM w0.173: R106.2 v8(7.24,130.38) ; v7(23.62,108.67) 23.6,108.69 23.6,110.38 R95.1 22.1,111.89 v8(22.1,114.17) 22.1,114.55 21.09,115.57 U9.29
PRU1ETH0_CRS: length 16.7
  L10_SIG4 w0.109: v7(28.45,106.68) 26.54,106.68 24.08,109.14 24.08,113.92 v7(23.24,114.76)
  BOTTOM w0.173: R94.1 28.45,107.82 v7(28.45,106.68) ; v7(23.24,114.76) 22.86,115.14 22.76,115.14 22.09,115.82 U9.27
PRU1ETH0_INTN: length 133.6
  TOP w0.173: v8(110.78,123.48) 113.41,120.86 113.41,112.02 115.47,109.96 115.47,107.9 114.58,107.01 114.58,102.18 113.54,101.14 R669.2
  L3_SIG1 w0.109: v8(18.16,122.13) 19.28,123.25 20.48,123.25 22.12,124.89 22.12,125.48 24.84,128.2 27.26,128.2 27.77,128.71 33.68,128.71 34.54,127.84 37.19,127.84 38.41,129.06 43.85,129.06 48.54,133.74 84.48,133.74 85.1,133.12 87.48,133.12 88.09,133.73 97.21,133.73 97.33,133.61 104.27,133.61 105.08,132.8 105.08,131.25 110.78,125.54 v8(110.78,123.48)
  BOTTOM w0.173: v8(18.16,122.13) 18.16,121.71 18.18,121.69 18.18,120.58 18.32,120.45 U9.8
PRU1ETH0_MDC: length 1.6
  BOTTOM w0.173: U9.20 24.75,118.95 24.87,118.83 R96.1
PRU1ETH0_MDIO: length 1.8
  BOTTOM w0.173: U9.19 25.01,119.45 R98.1
PRU1ETH0_RESETN: length 43.2
  L9_SIG3 w0.114: v8(33.78,92.09) 31.61,92.09 29.59,94.11 29.59,98.04 28.78,98.86 28.78,100.66 27.05,102.39 27.05,107.87 25.45,109.47 25.45,118.18 24.77,118.87 v8(24.77,120.24)
  BOTTOM w0.173: U68.4 41.04,90.57 40.64,90.17 36.7,90.17 34.78,92.09 v8(33.78,92.09) ; U9.18 24.47,119.95 v8(24.77,120.24)
PRU1ETH0_RXCLK: length 3.9
  BOTTOM w0.173: R83.1 24.38,113.92 24.38,114.89 23.09,116.19 U9.25
PRU1ETH0_RXD0: length 6.5
  TOP w0.173: R111.2 v8(20.45,112.65)
  BOTTOM w0.173: v8(20.45,112.65) 20.45,114.05 R88.1 20.59,115.18 U9.30
PRU1ETH0_RXD1: length 8.1
  TOP w0.173: R110.2 22.35,112.01 19.81,112.01 v8(19.18,112.65)
  BOTTOM w0.173: U9.31 20.09,115.44 19.81,115.17 R90.1 19.18,114.05 v8(19.18,112.65)
PRU1ETH0_RXD2: length 6.3
  TOP w0.173: R109.2 19.69,114.94 v8(19,115.63)
  BOTTOM w0.173: U9.32 19.59,115.92 19.28,115.62 19,115.62 v8(19,115.63) 18.54,115.17 R91.1
PRU1ETH0_RXD3: length 10
  TOP w0.173: v8(16.38,115.78) 16.7,116.09 16.7,116.14 17.14,116.59 20.45,116.59 20.95,116.08 R108.2
  BOTTOM w0.173: U9.1 18.14,116.95 R92.1 16.94,116.33 v8(16.38,115.78)
PRU1ETH0_RXDV: length 3.9
  BOTTOM w0.173: R86.1 23.85,113.44 23.85,114.91 23.23,115.54 22.87,115.54 22.59,115.82 U9.26
PRU1ETH0_RXERR: length 3.7
  BOTTOM w0.173: U9.28 21.59,115.66 23.11,114.13 R87.1
PRU1ETH0_TXCLK: length 178.1
  TOP w0.173: 145.16,98.17 v3(148.21,98.17)
  L3_SIG1 w0.109: v5(123.57,129.03) 130.64,121.97 130.64,114.85 132.44,113.05 132.44,110.82 139.62,103.63 143.21,103.63 147.45,99.39 147.45,98.93 v3(148.21,98.17)
  L10_SIG4 w0.109: v7(15.67,116.13) 12.34,119.47 12.34,123.43 16.18,127.27 16.18,128.04 16.75,128.6 17.55,128.6 19.42,130.48 23.35,130.48 23.81,130.94 40.51,130.94 41.66,132.08 49.15,132.08 50.42,130.81 77.17,130.81 79.71,133.35 80.64,133.35 82.55,131.44 89.28,131.44 90.17,130.56 97.03,130.56 98.04,131.57 99.28,131.57 100.43,130.43 104.77,130.43 106.17,129.03 v5(123.57,129.03)
  BOTTOM w0.173: U9.2 16.99,117.45 v7(15.67,116.13)
PRU1ETH0_TXD0: length 180.7
  TOP w0.173: R81.1 v3(146.94,91.57)
  L3_SIG1 w0.109: v3(146.94,91.57) 146.94,96.72 141.12,102.54 139.52,102.54 139.14,102.92 139.14,103.61 132.1,110.64 132.1,112.6 129.16,115.54 129.16,119.01 129.29,119.14 129.54,119.14 129.67,119.27 129.67,119.45 129.54,119.58 129.29,119.58 129.16,119.71 129.16,119.89 129.29,120.02 129.54,120.02 129.67,120.14 129.67,120.32 129.54,120.45 129.29,120.45 129.16,120.58 129.16,120.76 129.29,120.89 129.54,120.89 129.67,121.02 129.67,121.2 129.54,121.33 129.29,121.33 129.16,121.45 129.16,121.64 129.29,121.76 129.54,121.76 129.67,121.89 129.67,122.07 129.54,122.2 129.29,122.2 129.16,122.33 129.16,122.81 123.38,128.59 v5(122.43,128.59)
  L10_SIG4 w0.109: v7(16.21,118.24) 15.24,119.21 15.24,123.91 19.11,127.77 19.93,127.77 21.7,129.54 23.04,129.54 23.99,130.5 40.77,130.5 41.84,131.57 48.89,131.57 51.18,129.29 57.02,129.29 57.91,130.18 63.12,130.18 64.77,128.52 69.09,128.52 70.36,129.79 76.76,129.79 78.79,131.83 80.39,131.83 82.42,129.79 91.84,129.79 91.96,129.67 91.96,129.16 92.09,129.03 92.27,129.03 92.4,129.16 92.4,129.67 92.53,129.79 92.71,129.79 92.84,129.67 92.84,129.16 92.97,129.03 93.15,129.03 93.27,129.16 93.27,129.67 93.4,129.79 97.03,129.79 98.17,130.94 99.3,130.94 100.95,129.29 102.62,129.29 103.31,128.59 v5(122.43,128.59)
  BOTTOM w0.173: U9.4 17.66,118.45 17.44,118.24 v7(16.21,118.24)
PRU1ETH0_TXD1: length 180.2
  TOP w0.173: R84.1 v3(145.8,88.14)
  L3_SIG1 w0.109: v3(145.8,88.14) 145.8,96.39 144.91,97.28 142.49,97.28 140.63,99.14 139.62,99.14 137.8,100.96 137.8,103.04 131.93,108.92 131.66,108.92 131.35,108.6 131.17,108.6 131.04,108.73 131.04,108.91 131.43,109.3 131.43,109.48 131.3,109.61 131.12,109.61 130.73,109.22 130.55,109.22 130.42,109.35 130.42,109.53 130.81,109.92 130.81,110.1 130.68,110.23 130.5,110.23 130.12,109.84 129.93,109.84 129.81,109.97 129.81,110.15 130.19,110.54 130.19,110.72 130.07,110.85 129.88,110.85 129.5,110.46 129.32,110.46 129.19,110.59 129.19,110.77 129.58,111.16 129.58,111.34 129.33,111.58 129.33,112.08 129.2,112.21 128.4,112.21 128.27,112.34 128.27,112.52 128.4,112.64 129.2,112.64 129.33,112.77 129.33,112.95 129.2,113.08 128.4,113.08 128.27,113.21 128.27,113.39 128.4,113.52 129.2,113.52 129.33,113.65 129.33,113.83 129.2,113.95 128.4,113.95 127.34,115.02 127.34,116.85 126.49,117.7 126.49,121.54 123.57,124.46 v5(123.57,126.11)
  L10_SIG4 w0.109: v7(16.76,118.95) 18.12,118.95 18.68,119.51 18.68,123.29 20.19,124.8 21.36,124.8 25.74,129.18 32.91,129.18 33.43,128.66 34.15,128.66 34.62,128.2 36.9,128.2 37.75,129.05 41.19,129.05 42.32,130.18 47.47,130.18 50.32,127.33 61.32,127.33 61.65,127 71.66,127 73.63,125.04 86.87,125.04 87.2,124.7 95.9,124.7 96.37,124.23 100.74,124.23 103.12,126.62 118.75,126.62 119.63,125.73 121.16,125.73 122.05,126.62 123.06,126.62 v5(123.57,126.11)
  BOTTOM w0.173: U9.5 v7(16.76,118.95)
PRU1ETH0_TXD2: length 176.7
  TOP w0.173: 145.16,99.69 144.4,98.93 v3(143.38,98.93)
  L3_SIG1 w0.109: v5(123.57,127.13) 123.58,127.13 124.34,126.37 124.34,125.29 124.44,125.19 124.62,125.19 125.04,125.61 125.22,125.61 125.35,125.48 125.35,125.3 124.93,124.88 124.93,124.7 125.06,124.57 125.24,124.57 125.65,124.99 125.84,124.99 125.96,124.86 125.96,124.68 125.55,124.27 125.55,124.08 125.68,123.96 125.86,123.96 126.27,124.37 126.45,124.37 126.58,124.24 126.58,124.06 126.17,123.65 126.17,123.47 126.3,123.34 126.48,123.34 126.89,123.75 127.07,123.75 127.2,123.62 127.2,123.44 126.79,123.03 126.79,122.85 127,122.63 127,122.34 127.13,122.21 127.63,122.21 127.76,122.08 127.76,121.9 127.63,121.77 127.13,121.77 127,121.65 127,121.47 127.13,121.34 127.63,121.34 127.76,121.21 127.76,121.03 127.63,120.9 127.13,120.9 127,120.77 127,120.59 127.13,120.46 127.63,120.46 127.76,120.34 127.76,120.15 127.63,120.03 127.13,120.03 127,119.9 127,119.72 127.13,119.59 127.63,119.59 127.76,119.46 127.76,119.28 127.63,119.15 127.13,119.15 127,119.02 127,117.67 127.68,116.99 127.68,115.15 128.54,114.29 129.41,114.29 129.67,114.04 129.67,113.09 129.8,112.96 130.55,112.96 130.68,112.83 130.68,112.65 130.55,112.52 129.8,112.52 129.67,112.4 129.67,111.84 138.4,103.1 138.4,101.66 139.39,100.67 140.76,100.67 142.49,98.93 v3(143.38,98.93)
  L10_SIG4 w0.109: v5(123.57,127.13) 122.55,128.15 100.72,128.15 99.87,127.3 97.36,127.3 96.77,127.9 94.88,127.9 94.37,127.39 93.46,127.39 92.32,128.53 82.69,128.53 81.19,127.03 74.26,127.03 74.13,127.16 74.13,127.86 74,127.99 73.82,127.99 73.69,127.86 73.69,127.16 73.56,127.03 72.87,127.03 71.88,128.03 63.66,128.03 62.93,128.75 51.09,128.75 48.71,131.13 42.02,131.13 40.95,130.06 36.2,130.06 35.69,129.54 33.79,129.54 33.27,130.06 24.17,130.06 23.22,129.1 21.88,129.1 20.11,127.33 19.29,127.33 15.75,123.79 v7(15.75,119.76)
  BOTTOM w0.173: U9.6 17.46,119.45 17.14,119.76 v7(15.75,119.76)
PRU1ETH0_TXD3: length 177.8
  TOP w0.173: 145.16,95.12 v3(146.43,95.12)
  L3_SIG1 w0.109: v5(122.43,127.25) 122.74,127.56 123.93,127.56 128.14,123.35 128.14,122.71 128.27,122.58 128.68,122.58 128.8,122.45 128.8,122.27 128.68,122.15 128.27,122.15 128.14,122.02 128.14,121.84 128.27,121.71 128.68,121.71 128.8,121.58 128.8,121.4 128.68,121.27 128.27,121.27 128.14,121.14 128.14,120.96 128.27,120.84 128.68,120.84 128.8,120.71 128.8,120.53 128.68,120.4 128.27,120.4 128.14,120.27 128.14,120.09 128.27,119.96 128.68,119.96 128.8,119.83 128.8,119.65 128.68,119.52 128.27,119.52 128.14,119.4 128.14,119.22 128.27,119.09 128.68,119.09 128.8,118.96 128.8,118.78 128.68,118.65 128.27,118.65 128.14,118.52 128.14,118.34 128.27,118.21 128.68,118.21 128.8,118.09 128.8,117.91 128.68,117.78 128.27,117.78 128.14,117.65 128.14,117.47 128.27,117.34 128.68,117.34 128.8,117.21 128.8,117.03 128.68,116.9 128.27,116.9 128.14,116.78 128.14,116.08 131.06,113.16 131.06,111.93 131.19,111.8 131.57,111.8 131.7,111.67 131.7,111.49 131.57,111.36 131.19,111.36 131.06,111.23 131.06,110.95 138.8,103.21 138.8,102.78 139.92,101.67 140.77,101.67 142.88,99.57 143.51,99.57 146.43,96.65 v3(146.43,95.12)
  L10_SIG4 w0.109: v7(16.51,120.52) 17.14,121.16 17.14,122.38 21.1,126.33 21.1,127.4 22.34,128.64 23.38,128.64 24.36,129.62 33.09,129.62 33.61,129.1 34.6,129.1 34.95,128.75 36.83,128.75 37.57,129.49 41,129.49 42.2,130.68 48.51,130.68 50.88,128.31 62.75,128.31 63.47,127.59 71.7,127.59 73.81,125.48 85.6,125.48 86.13,126.01 89.4,126.01 89.53,126.14 89.53,126.72 89.66,126.85 89.84,126.85 89.97,126.72 89.97,126.14 90.1,126.01 90.28,126.01 90.41,126.14 90.41,126.72 90.53,126.85 90.72,126.85 90.84,126.72 90.84,126.14 90.97,126.01 91.15,126.01 91.28,126.14 91.28,126.72 91.41,126.85 91.59,126.85 91.72,126.72 91.72,126.14 91.84,126.01 92.03,126.01 92.15,126.14 92.15,126.72 92.28,126.85 92.46,126.85 92.59,126.72 92.59,126.14 92.72,126.01 93.44,126.01 93.95,125.5 99.3,125.5 101.44,127.64 110.62,127.64 111,127.25 119.63,127.25 119.89,127 121.28,127 121.54,127.25 v5(122.43,127.25)
  BOTTOM w0.173: v7(16.51,120.52) 17.27,120.52 17.85,119.95 U9.7
PRU1ETH0_TXEN: length 178.2
  TOP w0.173: 145.16,97.16 v3(145.16,96.39)
  L3_SIG1 w0.109: v5(122.43,125.86) 122.43,123.7 126.11,120.02 126.11,117.6 127,116.71 127,110.72 130.3,107.41 131.85,107.41 137.47,101.8 137.47,100.81 138.68,99.59 138.68,98.78 139.3,98.17 140.44,98.17 140.44,98.17 141.1,98.17 142.49,96.77 144.78,96.77 v3(145.16,96.39)
  L10_SIG4 w0.109: v7(17.91,117.95) 19.12,119.16 19.12,121.93 25.92,128.74 31.48,128.74 32.69,127.53 36.86,127.53 37.8,128.47 48.51,128.47 50.24,126.75 57.98,126.75 59.38,125.35 60.9,125.35 62.11,126.56 71.48,126.56 73.45,124.6 82.34,124.6 83.74,123.19 88.88,123.19 89.01,123.32 89.01,124.08 89.13,124.21 89.31,124.21 89.44,124.08 89.44,123.32 89.57,123.19 89.75,123.19 89.88,123.32 89.88,124.08 90.01,124.21 90.19,124.21 90.32,124.08 90.32,123.32 90.44,123.19 90.62,123.19 90.75,123.32 90.75,124.08 90.88,124.21 91.06,124.21 91.19,124.08 91.19,123.32 91.32,123.19 91.5,123.19 91.63,123.32 91.63,124.08 91.75,124.21 91.94,124.21 92.06,124.08 92.06,123.32 92.19,123.19 101.02,123.19 102.7,124.87 106.21,124.87 106.81,124.27 110.76,124.27 110.89,124.4 110.89,125.63 111.01,125.76 111.2,125.76 111.32,125.63 111.32,124.4 111.45,124.27 111.63,124.27 111.76,124.4 111.76,125.63 111.89,125.76 112.07,125.76 112.2,125.63 112.2,124.4 112.32,124.27 112.51,124.27 112.63,124.4 112.63,125.63 112.76,125.76 112.94,125.76 113.07,125.63 113.07,124.4 113.2,124.27 113.38,124.27 113.51,124.4 113.51,125.63 113.64,125.76 113.82,125.76 113.94,125.63 113.94,124.4 114.07,124.27 114.62,124.27 115.44,125.09 119.25,125.09 119.76,124.59 121.16,124.59 v5(122.43,125.86)
  BOTTOM w0.173: U9.3 v7(17.91,117.95)
PRU1ETH1_25MHZCLK: length 12.5
  TOP w0.173: U13.23 v8(32.75,97)
  L4_SIG2 w0.114: v8(32.75,97) 37.5,101.75 v8(37.5,105.86)
  BOTTOM w0.173: R313.2 v8(37.5,105.86)
PRU1ETH1_COL: length 43
  TOP w0.173: R148.1 37.46,100.71 R152.1 36.38,100.53 v3(36.38,100.66) U13.29
  L3_SIG1 w0.109: v3(36.38,100.66) v5(35.94,101.1)
  L4_SIG2 w0.114: v5(35.94,101.1) 30.96,96.12 20.8,96.12 10.67,106.25 v8(7.43,106.25)
  BOTTOM w0.173: R151.2 v8(7.43,106.25)
PRU1ETH1_CRS: length 4.2
  TOP w0.173: R139.1 35.48,98.63 35.48,99.25 35.07,99.66 U13.27
PRU1ETH1_INTN: length 143.4
  TOP w0.173: v3(109.09,125.35) 109.09,123.17 112.9,119.36 112.9,112.03 115.12,109.82 115.12,108.07 113.65,106.61 113.04,106.61 112.52,106.09 R670.2 ; U13.8 v8(29.75,104.73)
  L3_SIG1 w0.109: v8(27.69,127.46) 28.42,128.19 29.97,128.19 30.63,127.53 37.39,127.53 38.43,128.57 59.13,128.57 64.01,133.46 84.19,133.46 85.03,132.62 88.62,132.62 89.16,133.15 95.9,133.15 96.69,132.37 99.15,132.37 99.4,132.61 102.49,132.61 104.03,131.07 104.03,129.64 104.97,128.71 105.99,128.71 109.09,125.6 v3(109.09,125.35)
  L4_SIG2 w0.114: v8(27.69,127.46) 27.69,124.84 23.24,120.4 23.24,111.23 v8(29.75,104.73)
PRU1ETH1_MDC: length 2.4
  TOP w0.173: R140.1 30.61,95.97 31.25,96.61 U13.20
PRU1ETH1_MDIO: length 5.2
  TOP w0.173: U13.19 30.75,96.99 R142.1 29.59,95.83 29.03,95.28 29.03,94.24 R120.1
PRU1ETH1_RESETN: length 9
  TOP w0.173: U13.18 30.25,97.3 28.58,95.63 v8(28.58,92.79)
  BOTTOM w0.173: U69.4 30.47,92.04 29.72,92.79 v8(28.58,92.79)
PRU1ETH1_RXCLK: length 4.5
  TOP w0.173: U13.25 33.97,97.86 36.07,95.76 R129.1
PRU1ETH1_RXD0: length 4.3
  TOP w0.173: 35.81,101.68 36.2,101.3 R158.2 ; 35.81,101.68 v8(35.81,101.71) ; 35.81,101.68 35.29,101.16 U13.30
  BOTTOM w0.173: R133.1 35.29,101.71 v8(35.81,101.71)
PRU1ETH1_RXD1: length 4
  TOP w0.173: U13.31 34.9,101.66 v8(35.69,102.44) 36.75,102.44 R157.2
  BOTTOM w0.173: v8(35.69,102.44) 35.64,102.49 R135.1
PRU1ETH1_RXD2: length 7.3
  TOP w0.173: R156.2 R136.1 36.58,103 36.45,103.12 34.35,103.12 33.97,102.74 U13.32
PRU1ETH1_RXD3: length 5.8
  TOP w0.173: R155.2 R137.1 34.42,104.77 33.25,103.6 U13.1
PRU1ETH1_RXDV: length 7.5
  TOP w0.173: R130.1 36.73,96.52 35,98.25 35,98.86 34.7,99.16 U13.26
PRU1ETH1_RXERR: length 3.5
  TOP w0.173: U13.28 35.22,100.16 R132.1
PRU1ETH1_TXCLK: length 352.3
  TOP w0.173: R123.1 v3(114.68,101.17) ; U13.2 v3(32.75,104.86)
  L3_SIG1 w0.109: v3(114.68,101.17) 114.68,101.17 113.77,101.17 113.08,101.85 113.08,103.84 112.57,104.34 111.39,104.34 106.6,109.14 99.34,109.14 97.34,111.14 96.52,111.14 95.81,111.85 90.84,111.85 89.41,113.28 86.41,113.28 85.67,112.55 81.73,112.55 81.73,112.56 81.34,112.56 81.33,112.55 73.9,112.55 69.41,108.06 65.89,108.06 64.26,106.43 59.56,106.43 58.9,107.09 58.29,107.09 58.03,106.82 55.25,106.82 54.77,106.34 50.03,106.34 45.34,111.02 45.34,111.53 42.14,114.73 33.19,114.73 30.98,112.51 30.98,111.03 32.21,109.8 34.57,109.8 36.2,108.18 36.2,107.01 36.64,106.57 37.81,106.57 38.92,105.45 39.4,105.45 40.72,104.14 40.72,103.89 41.05,103.55 41.47,103.55 41.85,103.17 41.85,102.17 43.53,100.49 49.7,100.49 49.91,100.28 49.91,100.1 49.21,99.41 49.21,99.23 49.34,99.1 49.52,99.1 50.22,99.79 50.4,99.79 50.52,99.66 50.52,99.48 49.83,98.79 49.83,98.61 49.96,98.48 50.14,98.48 50.83,99.17 51.01,99.17 51.14,99.05 51.14,98.86 50.45,98.17 50.45,97.99 50.58,97.86 50.76,97.86 51.45,98.56 51.63,98.56 51.75,98.44 51.98,98.44 52.11,98.31 52.11,97.36 52.24,97.23 52.42,97.23 52.55,97.36 52.55,98.31 52.68,98.44 54.19,98.44 54.51,98.12 54.75,98.12 54.88,97.99 54.88,97.16 55.01,97.03 55.19,97.03 55.32,97.16 55.32,97.99 55.45,98.12 55.63,98.12 55.76,97.99 55.76,96.62 55.88,96.49 56.06,96.49 56.19,96.62 56.19,97.99 56.32,98.12 56.46,98.12 57.28,97.31 59.46,97.31 60.22,96.55 60.69,96.55 60.82,96.67 60.82,97.23 60.95,97.36 61.13,97.36 61.26,97.23 61.26,96.67 61.39,96.55 61.57,96.55 61.69,96.67 61.69,97.23 61.82,97.36 62,97.36 62.13,97.23 62.13,96.67 62.26,96.55 62.44,96.55 62.57,96.67 62.57,97.23 62.7,97.36 62.88,97.36 63.01,97.23 63.01,96.67 63.13,96.55 66.09,96.55 66.34,96.29 66.34,94.41 66.04,94.1 65.67,94.1 65.54,94.23 65.54,95.99 65.41,96.11 65.23,96.11 65.1,95.99 65.1,94.23 64.97,94.1 64.79,94.1 64.67,94.23 64.67,95.99 64.54,96.11 64.36,96.11 64.23,95.99 64.23,94.23 64.1,94.1 63.92,94.1 63.79,94.23 63.79,95.99 63.66,96.11 63.48,96.11 63.35,95.99 63.35,94.23 63.23,94.1 63.05,94.1 62.92,94.23 62.92,95.99 62.79,96.11 62.61,96.11 62.48,95.99 62.48,94.23 62.35,94.1 62.17,94.1 62.04,94.23 62.04,95.99 61.92,96.11 61.74,96.11 61.61,95.99 61.61,94.23 61.48,94.1 61.3,94.1 61.17,94.23 61.17,95.99 61.04,96.11 60.86,96.11 60.73,95.99 60.73,94.23 60.61,94.1 60.42,94.1 60.3,94.23 60.3,95.99 60.17,96.11 59.99,96.11 59.86,95.99 59.86,94.23 59.73,94.1 59.55,94.1 59.42,94.23 59.42,96.57 59.3,96.7 59.11,96.7 58.99,96.57 58.99,94.23 58.86,94.1 58.68,94.1 58.55,94.23 58.55,96.57 58.42,96.7 58.24,96.7 58.11,96.57 58.11,94.23 57.98,94.1 57.12,94.1 57.05,94.18 57.05,95.22 56.79,95.48 55.8,95.48 55.62,95.29 55.62,94.07 55.46,93.91 54.87,93.91 54.74,94.04 54.74,96.37 54.62,96.49 54.43,96.49 54.31,96.37 54.31,94.04 54.18,93.91 53.37,93.91 53,93.55 51.54,93.55 51.41,93.68 51.41,94.12 51.54,94.25 52.68,94.25 52.81,94.38 52.81,94.56 52.68,94.69 51.54,94.69 51.41,94.82 51.41,95 51.54,95.13 52.68,95.13 52.81,95.25 52.81,95.44 52.68,95.56 51.54,95.56 51.41,95.69 51.41,95.87 51.54,96 52.68,96 52.81,96.13 52.81,96.31 52.68,96.44 51.54,96.44 51.41,96.57 51.41,96.82 51.29,96.95 51.11,96.95 50.98,96.82 50.98,93.68 50.85,93.55 50.67,93.55 50.54,93.68 50.54,96.82 50.41,96.95 50.23,96.95 50.1,96.82 50.1,93.68 49.98,93.55 49.8,93.55 49.67,93.68 49.67,96.82 49.54,96.95 49.36,96.95 49.23,96.82 49.23,93.68 49.1,93.55 48.92,93.55 48.79,93.68 48.79,96.82 48.67,96.95 48.48,96.95 48.36,96.82 48.36,93.68 48.23,93.55 48.05,93.55 47.92,93.68 47.92,96.82 47.79,96.95 47.61,96.95 47.48,96.82 47.48,93.68 47.35,93.55 47.17,93.55 47.05,93.68 47.05,96.82 46.92,96.95 46.74,96.95 46.61,96.82 46.61,93.68 46.48,93.55 46.3,93.55 46.17,93.68 46.17,96.82 46.04,96.95 45.86,96.95 45.74,96.82 45.74,93.68 45.61,93.55 45.43,93.55 45.3,93.68 45.3,96.82 45.17,96.95 44.99,96.95 44.86,96.82 44.86,93.68 44.73,93.55 44.55,93.55 44.42,93.68 44.42,96.82 44.3,96.95 44.12,96.95 43.99,96.82 43.99,93.68 43.86,93.55 43.68,93.55 43.55,93.68 43.55,96.82 43.42,96.95 43.24,96.95 43.11,96.82 43.11,93.68 42.99,93.55 42.81,93.55 42.68,93.68 42.68,96.82 42.55,96.95 42.37,96.95 42.24,96.82 42.24,93.68 41.96,93.4 41.19,93.4 41.06,93.52 41.06,95.12 40.93,95.25 40.75,95.25 40.62,95.12 40.62,93.52 40.49,93.4 40.31,93.4 40.18,93.52 40.18,95.12 40.06,95.25 39.88,95.25 39.75,95.12 39.75,93.52 39.62,93.4 37.7,93.4 37.57,93.52 37.57,94.87 37.44,95 37.26,95 37.13,94.87 37.13,93.52 37,93.4 36.82,93.4 36.69,93.52 36.69,94.87 36.57,95 36.39,95 36.26,94.87 36.26,93.52 36.13,93.4 35.79,93.4 34.92,94.26 34.92,96.01 35.66,96.75 35.66,98.22 37.2,99.76 37.2,103.57 34.16,106.6 31.39,106.6 30.94,106.15 30.94,105.49 31.57,104.86 v3(32.75,104.86)
PRU1ETH1_TXD0: length 348.3
  TOP w0.173: R125.1 v3(112.27,101.09) ; v3(31.75,105.74) U13.4
  L3_SIG1 w0.109: v3(31.75,105.74) 33.3,105.74 36.86,102.18 36.86,100.03 35.59,98.76 34.87,98.76 34.54,98.42 34.54,94.01 35.68,92.86 39.14,92.86 39.27,92.74 39.27,92.56 39.14,92.43 38.08,92.43 37.95,92.3 37.95,92.12 38.08,91.99 39.7,91.99 39.83,91.86 39.83,91.68 39.7,91.55 38.08,91.55 37.95,91.43 37.95,91.25 38.08,91.12 39.7,91.12 39.83,90.99 39.83,90.7 40.11,90.42 40.43,90.42 40.56,90.55 40.56,91.95 40.68,92.08 40.87,92.08 40.99,91.95 40.99,90.55 41.12,90.42 41.3,90.42 41.43,90.55 41.43,91.95 41.56,92.08 41.74,92.08 41.87,91.95 41.87,90.55 41.99,90.42 42.18,90.42 42.3,90.55 42.3,91.95 42.43,92.08 42.61,92.08 42.74,91.95 42.74,90.55 42.87,90.42 43.05,90.42 43.18,90.55 43.18,91.95 43.31,92.08 43.49,92.08 43.61,91.95 43.61,90.55 43.74,90.42 43.92,90.42 44.05,90.55 44.05,91.95 44.18,92.08 44.36,92.08 44.49,91.95 44.49,90.55 44.62,90.42 45.44,90.42 45.56,90.55 45.56,92.94 45.69,93.07 45.87,93.07 46,92.94 46,90.55 46.13,90.42 46.31,90.42 46.44,90.55 46.44,92.94 46.57,93.07 46.75,93.07 46.87,92.94 46.87,90.55 47,90.42 47.18,90.42 47.31,90.55 47.31,92.94 47.44,93.07 47.62,93.07 47.75,92.94 47.75,90.55 47.88,90.42 48.06,90.42 48.19,90.55 48.19,92.94 48.31,93.07 48.49,93.07 48.62,92.94 48.62,90.55 48.75,90.42 48.93,90.42 49.06,90.55 49.06,92.94 49.19,93.07 49.37,93.07 49.5,92.94 49.5,90.55 49.62,90.42 49.81,90.42 49.93,90.55 49.93,92.94 50.06,93.07 50.24,93.07 50.37,92.94 50.37,90.55 50.5,90.42 50.7,90.42 52.44,92.16 53.25,92.16 53.38,92.29 53.38,93.45 53.51,93.57 53.69,93.57 53.82,93.45 53.82,92.29 53.94,92.16 54.13,92.16 54.25,92.29 54.25,93.45 54.38,93.57 54.56,93.57 54.69,93.45 54.69,92.29 54.82,92.16 55,92.16 55.13,92.29 55.13,93.45 55.26,93.57 55.44,93.57 55.56,93.45 55.56,92.29 55.69,92.16 55.87,92.16 56,92.29 56,93.45 56.13,93.57 56.31,93.57 56.44,93.45 56.44,92.29 56.57,92.16 56.75,92.16 56.87,92.29 56.87,93.45 57,93.57 57.18,93.57 57.31,93.45 57.31,92.29 57.44,92.16 57.62,92.16 57.75,92.29 57.75,93.45 57.88,93.57 58.06,93.57 58.19,93.45 58.19,92.29 58.31,92.16 58.49,92.16 58.62,92.29 58.62,93.45 58.75,93.57 58.93,93.57 59.06,93.45 59.06,92.29 59.19,92.16 59.37,92.16 59.5,92.29 59.5,93.45 59.62,93.57 59.8,93.57 59.93,93.45 59.93,92.29 60.06,92.16 60.24,92.16 60.37,92.29 60.37,93.45 60.5,93.57 60.68,93.57 60.81,93.45 60.81,92.29 60.93,92.16 61.12,92.16 61.24,92.29 61.24,93.45 61.37,93.57 61.55,93.57 61.68,93.45 61.68,92.29 61.81,92.16 61.99,92.16 62.12,92.29 62.12,93.45 62.25,93.57 62.43,93.57 62.55,93.45 62.55,92.29 62.68,92.16 62.86,92.16 62.99,92.29 62.99,93.45 63.12,93.57 63.3,93.57 63.43,93.45 63.43,92.29 63.56,92.16 63.74,92.16 63.86,92.29 63.86,93.45 63.99,93.57 64.17,93.57 64.3,93.45 64.3,92.29 64.43,92.16 64.61,92.16 64.74,92.29 64.74,93.45 64.87,93.57 65.05,93.57 65.18,93.45 65.18,92.29 65.3,92.16 65.48,92.16 65.61,92.29 65.61,93.45 65.74,93.57 65.92,93.57 66.05,93.45 66.05,92.29 66.18,92.16 66.68,92.16 67.28,92.76 67.28,93.52 67.41,93.64 69.19,93.64 69.32,93.77 69.32,93.95 69.19,94.08 67.41,94.08 67.28,94.21 67.28,94.39 67.41,94.52 69.19,94.52 69.32,94.65 69.32,94.83 69.19,94.96 67.41,94.96 67.28,95.08 67.28,95.26 67.41,95.39 69.44,95.39 69.57,95.52 69.57,95.7 69.44,95.83 67.41,95.83 67.28,95.96 67.28,96.14 67.41,96.27 69.44,96.27 69.57,96.39 69.57,96.58 69.44,96.7 67.93,96.7 67.82,96.81 67.82,97.97 67.64,98.15 65.98,98.15 65.85,98.02 65.85,97.33 65.72,97.21 65.54,97.21 65.41,97.33 65.41,98.02 65.28,98.15 65.1,98.15 64.98,98.02 64.98,97.33 64.85,97.21 64.67,97.21 64.54,97.33 64.54,98.02 64.41,98.15 64.23,98.15 64.1,98.02 64.1,97.33 63.97,97.21 63.79,97.21 63.67,97.33 63.67,98.02 63.54,98.15 63.35,98.15 62.41,99.09 62.2,99.09 62.07,98.96 62.07,97.89 61.94,97.76 61.76,97.76 61.63,97.89 61.63,98.96 61.51,99.09 61.32,99.09 61.2,98.96 61.2,97.89 61.07,97.76 60.89,97.76 60.76,97.89 60.76,98.96 60.63,99.09 60.45,99.09 60.32,98.96 60.32,97.89 60.19,97.76 60.01,97.76 59.89,97.89 59.89,98.96 59.76,99.09 59.58,99.09 59.45,98.96 59.45,97.89 59.32,97.76 59.14,97.76 59.01,97.89 59.01,98.96 58.88,99.09 58.7,99.09 58.57,98.96 58.57,97.89 58.45,97.76 58.27,97.76 58.14,97.89 58.14,98.96 58.01,99.09 57.83,99.09 57.7,98.96 57.7,97.89 57.57,97.76 57.39,97.76 57.26,97.89 57.26,98.96 57.14,99.09 56.92,99.09 56.34,98.5 54.61,98.5 54.33,98.78 51.89,98.78 49.84,100.83 43.67,100.83 42.19,102.31 42.19,103.76 41.14,104.81 41.06,104.81 40.08,105.79 39.06,105.79 34.61,110.24 32.49,110.24 31.32,111.4 31.32,112.21 33.16,114.05 38.46,114.05 38.99,113.52 42.87,113.52 45.01,111.39 45.01,110.88 49.89,106 55.17,106 55.28,106.11 55.28,106.37 55.39,106.48 55.61,106.48 55.72,106.37 55.72,106.11 55.83,106 56.04,106 56.15,106.11 56.15,106.37 56.26,106.48 56.48,106.48 56.59,106.37 56.59,106.11 56.7,106 56.92,106 57.03,106.11 57.03,106.37 57.14,106.48 57.36,106.48 57.46,106.37 57.46,106.11 57.57,106 64.43,106 65.03,106.6 65.19,106.6 65.83,105.96 65.99,105.96 66.11,106.08 66.11,106.24 65.47,106.88 65.47,107.04 65.59,107.16 65.75,107.16 66.39,106.52 66.55,106.52 66.67,106.64 66.67,106.8 66.03,107.44 66.03,107.6 66.15,107.72 66.31,107.72 66.95,107.08 68.91,107.08 73.82,111.99 76.99,111.99 77.1,111.88 77.1,111.29 77.22,111.17 77.38,111.17 77.5,111.29 77.5,111.88 77.61,111.99 77.78,111.99 77.89,111.88 77.89,111.29 78.01,111.17 78.17,111.17 78.29,111.29 78.29,111.88 78.41,111.99 78.57,111.99 78.69,111.88 78.69,111.29 78.8,111.17 78.97,111.17 79.08,111.29 79.08,111.88 79.2,111.99 79.36,111.99 79.48,111.88 79.48,111.29 79.59,111.17 79.76,111.17 80.09,111.5 83.17,111.5 83.28,111.62 83.28,112.04 83.4,112.15 83.56,112.15 83.68,112.04 83.68,111.62 83.8,111.5 83.96,111.5 84.08,111.62 84.08,112.04 84.19,112.15 84.36,112.15 84.47,112.04 84.47,111.56 84.59,111.45 84.75,111.45 84.87,111.56 84.87,112.04 84.99,112.15 85.5,112.15 85.62,112.04 85.62,110.52 85.73,110.41 85.9,110.41 86.01,110.52 86.01,112.04 86.13,112.15 86.29,112.15 86.41,112.04 86.41,109.78 86.52,109.67 86.69,109.67 86.81,109.79 86.81,110.39 86.92,110.5 87.74,110.5 87.85,110.62 87.85,110.78 87.74,110.9 86.92,110.9 86.81,111.01 86.81,111.33 86.92,111.44 87.7,111.44 87.82,111.56 87.82,111.72 87.7,111.84 86.92,111.84 86.81,111.95 86.81,112.28 87.3,112.78 89.41,112.78 90.68,111.51 95.67,111.51 96.38,110.8 97.2,110.8 99.21,108.79 106.18,108.79 109.98,104.98 109.98,103.7 111.63,102.05 111.63,101.73 v3(112.27,101.09)
PRU1ETH1_TXD1: length 340.3
  TOP w0.173: R126.1 119.91,100.73 119.91,102.17 v3(119.23,102.85) ; U13.5 31.25,103.75 v3(31.25,103.75)
  L3_SIG1 w0.109: v3(31.25,103.75) 31.41,103.6 32.2,103.6 32.87,102.93 32.87,102.08 32.67,101.89 32.5,101.89 32.37,102.02 32.37,102.92 32.24,103.05 32.06,103.05 31.93,102.92 31.93,102.02 31.8,101.89 31.62,101.89 31.5,102.02 31.5,102.92 31.37,103.05 31.19,103.05 31.06,102.92 31.06,102.02 30.93,101.89 30.75,101.89 30.62,102.02 30.62,102.92 30.49,103.05 30.31,103.05 30.18,102.92 30.18,102.02 30.06,101.89 29.88,101.89 29.75,102.02 29.75,102.92 29.62,103.05 29.44,103.05 29.31,102.92 29.31,102.02 29.18,101.89 29.02,101.89 28.85,102.06 28.85,102.82 28.37,103.3 26.09,103.3 25.81,103.03 25.63,103.03 25.05,103.61 24.87,103.61 24.74,103.48 24.74,103.3 25.32,102.72 25.32,102.54 24.99,102.21 23.22,102.21 23.09,102.34 23.09,103.96 22.97,104.09 22.78,104.09 22.66,103.96 22.66,102.34 22.53,102.21 21.95,102.21 21.76,102.03 21.76,101.23 21.64,101.1 18.42,101.1 18.29,100.97 18.29,100.79 18.42,100.66 21.64,100.66 21.76,100.54 21.76,100.36 21.64,100.23 18.42,100.23 18.29,100.1 18.29,99.92 18.42,99.79 21.64,99.79 21.76,99.66 21.76,99.48 21.64,99.35 18.42,99.35 18.29,99.23 18.29,99.05 18.42,98.92 21.64,98.92 21.76,98.79 21.76,98.61 21.64,98.48 18.42,98.48 18.29,98.35 18.29,98.17 18.42,98.04 21.64,98.04 21.76,97.92 21.76,97.73 21.64,97.61 18.42,97.61 18.29,97.48 18.29,97.3 18.42,97.17 21.64,97.17 21.76,97.04 21.76,96.82 21.59,96.65 18.67,96.65 18.29,96.27 18.29,95.25 18.53,95.01 18.95,95.01 19.07,95.14 19.07,96.01 19.2,96.14 19.38,96.14 19.51,96.01 19.51,95.14 19.64,95.01 19.82,95.01 19.95,95.14 19.95,96.01 20.07,96.14 20.26,96.14 20.38,96.01 20.38,95.14 20.51,95.01 20.69,95.01 20.82,95.14 20.82,96.01 20.95,96.14 21.13,96.14 21.26,96.01 21.26,95.14 21.39,95.01 21.57,95.01 21.69,95.14 21.69,96.01 21.82,96.14 22,96.14 22.13,96.01 22.13,95.14 22.26,95.01 22.44,95.01 22.57,95.14 22.57,96.01 22.7,96.14 22.88,96.14 23.01,96.01 23.01,95.14 23.13,95.01 24.14,95.01 24.64,94.52 24.64,93.81 24.26,93.43 23.84,93.43 23.71,93.56 23.71,94.23 23.58,94.36 23.4,94.36 23.28,94.23 23.28,93.56 23.15,93.43 22.97,93.43 22.84,93.56 22.84,94.23 22.71,94.36 22.53,94.36 22.4,94.23 22.4,93.56 22.27,93.43 22.09,93.43 21.97,93.56 21.97,94.23 21.84,94.36 21.66,94.36 21.53,94.23 21.53,93.56 21.4,93.43 21.22,93.43 21.09,93.56 21.09,94.23 20.96,94.36 20.78,94.36 20.65,94.23 20.65,93.56 20.53,93.43 20.35,93.43 20.22,93.56 20.22,94.23 20.09,94.36 19.91,94.36 19.78,94.23 19.78,93.56 19.65,93.43 19.47,93.43 19.34,93.56 19.34,94.23 19.22,94.36 19.04,94.36 18.91,94.23 18.91,93.56 18.78,93.43 18.3,93.43 18.15,93.58 17.36,94.37 17.36,101.33 18.75,102.73 18.75,102.83 19.3,103.38 20.45,103.38 20.66,103.59 20.66,104.76 20.79,104.89 22.86,104.89 22.99,105.02 22.99,105.2 22.86,105.33 20.79,105.33 20.66,105.46 20.66,105.64 20.79,105.76 22.86,105.76 22.99,105.89 22.99,106.07 22.86,106.2 20.79,106.2 20.66,106.33 20.66,106.51 20.79,106.64 22.86,106.64 22.99,106.77 22.99,106.95 22.86,107.08 20.79,107.08 20.66,107.2 20.66,107.38 20.79,107.51 22.86,107.51 22.99,107.64 22.99,107.82 22.86,107.95 20.79,107.95 20.66,108.08 20.66,108.42 21.04,108.8 21.04,110.44 21.17,110.56 22.58,110.56 22.71,110.69 22.71,110.87 22.58,111 21.17,111 21.04,111.13 21.04,111.31 21.17,111.44 23.39,111.44 23.52,111.57 23.52,111.75 23.39,111.87 21.17,111.87 21.04,112 21.04,112.18 21.17,112.31 23.39,112.31 23.52,112.44 23.52,112.62 23.39,112.75 21.17,112.75 21.04,112.88 21.04,113.06 21.17,113.18 23.39,113.18 23.52,113.31 23.52,113.49 23.39,113.62 21.17,113.62 21.04,113.75 21.04,114.6 21.17,114.73 23.29,114.73 23.42,114.86 23.42,115.04 23.29,115.17 21.17,115.17 21.04,115.3 21.04,115.48 21.17,115.61 23.29,115.61 23.42,115.73 23.42,115.91 23.29,116.04 21.17,116.04 21.04,116.17 21.04,116.35 21.17,116.48 23.29,116.48 23.42,116.61 23.42,116.79 23.29,116.92 21.17,116.92 21.04,117.04 21.04,117.4 25.94,122.31 25.94,124.49 26.28,124.82 30.59,124.82 31.17,124.25 31.92,124.25 32.05,124.38 32.05,125.09 32.18,125.22 32.36,125.22 32.48,125.09 32.48,124.38 32.61,124.25 32.79,124.25 32.92,124.38 32.92,125.09 33.05,125.22 33.23,125.22 33.36,125.09 33.36,124.38 33.49,124.25 34.29,124.25 34.42,124.38 34.42,125.09 34.55,125.22 34.73,125.22 34.86,125.09 34.86,124.38 34.98,124.25 35.16,124.25 35.29,124.38 35.29,125.09 35.42,125.22 35.6,125.22 35.73,125.09 35.73,124.38 35.86,124.25 36.87,124.25 37,124.38 37,125.22 37.13,125.35 37.31,125.35 37.44,125.22 37.44,124.38 37.56,124.25 38.62,124.25 38.75,124.38 38.75,125.86 38.88,125.98 39.06,125.98 39.19,125.86 39.19,124.38 39.32,124.25 39.5,124.25 39.62,124.38 39.62,125.86 39.75,125.98 39.93,125.98 40.06,125.86 40.06,124.38 40.19,124.25 40.37,124.25 40.5,124.38 40.5,125.86 40.63,125.98 40.81,125.98 40.93,125.86 40.93,124.38 41.06,124.25 41.24,124.25 41.37,124.38 41.37,125.86 41.5,125.98 41.68,125.98 41.81,125.86 41.81,124.38 41.94,124.25 42.59,124.25 42.7,124.36 42.7,124.86 42.86,125.02 44.2,125.02 44.41,124.81 45.57,124.81 46.02,124.37 46.02,117.69 48.51,115.19 48.51,110.95 49.61,109.86 49.61,109.18 49.94,108.84 51.18,108.84 51.18,108.84 51.25,108.84 51.67,109.26 59.57,109.26 60.88,107.95 61.27,107.95 61.94,108.63 64.15,108.63 65.42,109.9 66.87,109.9 71.17,114.2 84.71,114.2 84.98,114.47 91.63,114.47 92.84,113.26 96.24,113.26 96.8,112.7 98.42,112.7 99.2,111.92 103.65,111.92 103.91,111.66 104.88,111.66 105.55,110.99 107.1,110.99 109.5,108.58 110.52,108.58 110.65,108.46 110.65,108 110.78,107.87 110.96,107.87 111.08,108 111.08,108.46 111.21,108.58 111.57,108.58 111.7,108.46 111.7,108.05 111.83,107.92 112.01,107.92 112.14,108.05 112.14,108.46 112.26,108.58 112.67,108.58 113.18,108.08 113.85,108.08 113.98,107.95 113.98,107.29 114.11,107.16 114.29,107.16 114.42,107.29 114.42,107.95 114.54,108.08 115.06,108.08 115.25,107.89 115.25,107.71 115.05,107.51 115.05,107.33 115.18,107.2 115.36,107.2 115.56,107.4 115.74,107.4 116,107.14 116,106.96 115.35,106.32 115.35,106.14 115.48,106.01 115.66,106.01 116.31,106.65 116.49,106.65 118.4,104.74 118.4,104.56 117.14,103.31 117.14,103.13 117.27,103 117.45,103 118.71,104.25 118.89,104.25 119.23,103.91 v3(119.23,102.85)
PRU1ETH1_TXD2: length 345
  TOP w0.173: R127.1 116.08,100.79 v3(115.82,101.05) ; U13.6 v3(30.75,104.73)
  L3_SIG1 w0.109: v3(30.75,104.73) 29.79,105.69 27.15,105.69 26.95,105.89 26.95,106.44 27.08,106.57 30.45,106.57 30.58,106.7 30.58,106.88 30.45,107.01 27.08,107.01 26.95,107.13 26.95,107.32 27.08,107.44 29.16,107.44 29.29,107.57 29.29,107.75 29.16,107.88 27.08,107.88 26.95,108.01 26.95,108.19 27.08,108.32 30.45,108.32 30.58,108.45 30.58,108.63 30.45,108.75 27.08,108.75 26.95,108.88 26.95,109.06 27.08,109.19 30.45,109.19 30.58,109.32 30.58,109.5 30.45,109.63 27.08,109.63 26.95,109.76 26.95,109.94 27.08,110.06 30.45,110.06 30.58,110.19 30.58,110.37 30.45,110.5 27.08,110.5 26.95,110.63 26.95,110.81 27.08,110.94 30.45,110.94 30.58,111.07 30.58,111.25 30.45,111.38 27.08,111.38 26.95,111.5 26.95,111.68 27.08,111.81 28.35,111.81 28.47,111.94 28.47,112.12 28.35,112.25 27.08,112.25 26.95,112.38 26.95,112.56 27.08,112.69 28.22,112.69 28.35,112.81 28.35,112.99 28.22,113.12 27.08,113.12 26.95,113.25 26.95,113.5 27.08,113.63 28.19,113.63 28.47,113.92 28.47,114.22 28.6,114.35 29.82,114.35 29.95,114.48 29.95,114.66 29.82,114.79 28.6,114.79 28.47,114.92 28.47,115.1 28.6,115.23 29.82,115.23 29.95,115.35 29.95,115.53 29.82,115.66 28.6,115.66 28.47,115.79 28.47,115.97 28.6,116.1 29.82,116.1 29.95,116.23 29.95,116.41 29.82,116.54 28.6,116.54 28.47,116.66 28.47,116.87 28.22,117.12 27,117.12 26.61,117.5 25.66,117.5 25.53,117.63 25.53,117.81 25.66,117.94 26.61,117.94 26.74,118.07 26.74,120.8 27.2,121.26 27.98,121.26 28.43,121.72 29.73,121.72 30.15,121.29 30.15,120.89 30.62,120.42 32.03,120.42 33.16,119.29 33.49,119.29 33.62,119.42 33.62,120.06 33.75,120.19 33.93,120.19 34.06,120.06 34.06,119.42 34.19,119.29 34.37,119.29 34.49,119.42 34.49,120.06 34.62,120.19 34.8,120.19 34.93,120.06 34.93,119.42 35.06,119.29 35.24,119.29 35.37,119.42 35.37,120.06 35.5,120.19 35.68,120.19 35.81,120.06 35.81,119.42 35.93,119.29 36.11,119.29 36.24,119.42 36.24,120.06 36.37,120.19 36.55,120.19 36.68,120.06 36.68,119.42 36.81,119.29 36.99,119.29 37.12,119.42 37.12,120.06 37.24,120.19 37.42,120.19 37.55,120.06 37.55,119.42 37.68,119.29 37.86,119.29 37.99,119.42 37.99,120.06 38.12,120.19 38.3,120.19 38.43,120.06 38.43,119.42 38.55,119.29 39.15,119.29 40.07,120.2 40.89,120.2 41.02,120.08 41.02,119.05 41.15,118.92 41.33,118.92 41.46,119.05 41.46,120.08 41.59,120.2 42.17,120.2 42.93,119.44 42.93,118.19 42.7,117.97 41.41,117.97 41.02,118.37 31.4,118.37 31.06,118.03 31.06,117.17 31.34,116.89 31.68,116.89 31.8,117.02 31.8,117.83 31.93,117.96 32.11,117.96 32.24,117.83 32.24,117.02 32.37,116.89 32.55,116.89 32.68,117.02 32.68,117.83 32.81,117.96 32.99,117.96 33.11,117.83 33.11,117.02 33.24,116.89 33.42,116.89 33.55,117.02 33.55,117.83 33.68,117.96 33.86,117.96 33.99,117.83 33.99,115.88 34.12,115.75 34.3,115.75 34.42,115.88 34.42,117.83 34.55,117.96 34.73,117.96 34.86,117.83 34.86,117.02 34.99,116.89 35.17,116.89 35.3,117.02 35.3,117.83 35.43,117.96 35.61,117.96 35.74,117.83 35.74,115.77 35.86,115.65 36.04,115.65 36.17,115.77 36.17,117.83 36.3,117.96 36.48,117.96 36.61,117.83 36.61,117.02 36.74,116.89 36.92,116.89 37.05,117.02 37.05,117.83 37.17,117.96 37.36,117.96 37.48,117.83 37.48,115.88 37.61,115.75 37.79,115.75 37.92,115.88 37.92,117.83 38.05,117.96 38.23,117.96 38.36,117.83 38.36,115.88 38.48,115.75 38.67,115.75 38.79,115.88 38.79,117.83 38.92,117.96 39.1,117.96 39.23,117.83 39.23,117.02 39.36,116.89 39.54,116.89 39.67,117.02 39.67,117.83 39.8,117.96 39.98,117.96 40.1,117.83 40.1,117.02 40.23,116.89 40.41,116.89 40.54,117.02 40.54,117.83 40.67,117.96 40.85,117.96 40.98,117.83 40.98,116.58 41.11,116.45 44.25,116.45 44.37,116.32 44.37,116.14 44.25,116.02 41.11,116.02 40.98,115.89 40.98,115.51 41.17,115.32 42.16,115.32 42.83,114.65 43.79,114.65 44.87,115.73 45.05,115.73 45.18,115.6 45.18,115.42 44.1,114.35 44.1,114.16 44.23,114.04 44.41,114.04 45.49,115.11 45.67,115.11 45.8,114.98 45.8,114.8 44.52,113.52 44.52,113.29 44.63,113.18 44.79,113.18 46.11,114.49 46.29,114.49 46.63,114.15 46.63,113.68 46.51,113.56 45.75,113.56 45.62,113.43 45.62,113.25 45.75,113.12 46.51,113.12 46.63,112.99 46.63,112.81 46.51,112.68 45.75,112.68 45.62,112.55 45.62,112.37 45.75,112.24 46.51,112.24 46.63,112.12 46.63,111.19 46.83,110.99 46.83,110.81 46.52,110.5 46.52,110.32 46.65,110.19 46.83,110.19 47.14,110.5 47.32,110.5 47.45,110.37 47.45,110.19 47.14,109.88 47.14,109.7 47.27,109.57 47.45,109.57 47.76,109.88 47.94,109.88 48.07,109.76 48.07,109.57 47.76,109.27 47.76,109.08 47.89,108.96 48.07,108.96 48.38,109.27 48.56,109.27 48.69,109.14 48.69,108.96 48.38,108.65 48.38,108.47 48.51,108.34 48.69,108.34 49,108.65 49.18,108.65 49.31,108.52 49.31,108.34 49,108.03 49,107.85 49.13,107.72 49.31,107.72 49.62,108.03 49.8,108.03 49.92,107.91 50.33,107.91 50.45,107.78 50.45,106.83 50.58,106.71 50.76,106.71 50.89,106.83 50.89,107.78 51.02,107.91 51.2,107.91 51.33,107.78 51.33,106.83 51.46,106.71 51.64,106.71 51.76,106.83 51.76,107.78 51.89,107.91 52.07,107.91 52.2,107.78 52.2,106.83 52.33,106.71 52.51,106.71 52.64,106.83 52.64,107.78 52.77,107.91 52.95,107.91 53.07,107.78 53.07,106.83 53.2,106.71 53.38,106.71 53.51,106.83 53.51,107.78 53.64,107.91 53.82,107.91 53.95,107.78 53.95,106.83 54.08,106.71 54.26,106.71 54.39,106.83 54.39,107.78 54.51,107.91 54.69,107.91 54.82,107.78 54.82,107.32 54.98,107.16 55.15,107.16 55.26,107.27 55.26,107.78 55.39,107.91 55.57,107.91 55.7,107.78 55.7,107.29 55.82,107.16 56,107.16 56.13,107.29 56.13,107.78 56.26,107.91 57.11,107.91 57.24,107.78 57.24,107.29 57.37,107.16 57.55,107.16 57.68,107.29 57.68,107.78 57.81,107.91 59.97,107.91 60.41,107.47 60.41,107.47 60.6,107.28 61.55,107.28 62.22,107.95 62.53,107.95 62.66,107.83 62.66,107.01 62.79,106.88 62.97,106.88 63.1,107.01 63.1,107.83 63.22,107.95 63.41,107.95 63.53,107.83 63.53,107.01 63.66,106.88 63.84,106.88 63.97,107.01 63.97,107.83 64.1,107.95 64.43,107.95 65.7,109.22 65.92,109.22 66.05,109.09 66.05,108.56 66.18,108.43 66.36,108.43 66.49,108.56 66.49,109.09 66.62,109.22 66.8,109.22 66.92,109.09 66.92,108.56 67.05,108.43 67.23,108.43 67.36,108.56 67.36,109.09 67.49,109.22 67.67,109.22 68.08,108.81 68.55,108.81 68.87,109.13 69.05,109.13 69.43,108.75 69.61,108.75 69.74,108.88 69.74,109.06 69.36,109.44 69.36,109.62 69.49,109.75 69.67,109.75 70.05,109.37 70.23,109.37 70.36,109.5 70.36,109.68 69.98,110.06 69.98,110.24 70.1,110.37 70.29,110.37 70.67,109.99 70.85,109.99 70.97,110.12 70.97,110.3 70.59,110.68 70.59,110.86 70.72,110.99 70.9,110.99 71.28,110.61 71.46,110.61 71.59,110.73 71.59,110.92 71.21,111.3 71.21,111.48 71.34,111.6 71.52,111.6 71.9,111.22 72.08,111.22 72.21,111.35 72.21,111.53 71.83,111.91 71.83,112.09 72.19,112.46 72.19,112.64 71.7,113.13 71.7,113.31 71.83,113.44 72.01,113.44 72.5,112.95 72.68,112.95 73.26,113.52 73.5,113.52 73.63,113.39 73.63,113.03 73.76,112.9 73.94,112.9 74.07,113.03 74.07,113.39 74.19,113.52 74.38,113.52 74.5,113.39 74.5,113.03 74.63,112.9 74.81,112.9 74.94,113.03 74.94,113.39 75.07,113.52 75.25,113.52 75.38,113.39 75.38,113.03 75.51,112.9 75.69,112.9 75.81,113.03 75.81,113.39 75.94,113.52 76.12,113.52 76.25,113.39 76.25,113.03 76.38,112.9 76.56,112.9 76.69,113.03 76.69,113.39 76.82,113.52 77,113.52 77.13,113.39 77.13,113.03 77.25,112.9 77.43,112.9 77.56,113.03 77.56,113.39 77.69,113.52 77.87,113.52 78,113.39 78,113.03 78.13,112.9 78.31,112.9 78.44,113.03 78.44,113.39 78.56,113.52 78.74,113.52 78.87,113.39 78.87,113.03 79,112.9 79.18,112.9 79.31,113.03 79.31,113.39 79.44,113.52 79.62,113.52 79.75,113.39 79.75,113.03 79.87,112.9 80.06,112.9 80.18,113.03 80.18,113.39 80.31,113.52 80.49,113.52 80.62,113.39 80.62,113.03 80.75,112.9 80.93,112.9 81.06,113.03 81.06,113.39 81.19,113.52 81.37,113.52 81.49,113.39 81.49,113.03 81.62,112.9 81.8,112.9 81.93,113.03 81.93,113.39 82.06,113.52 82.24,113.52 82.37,113.39 82.37,113.03 82.5,112.9 82.68,112.9 82.8,113.03 82.8,113.39 82.93,113.52 83.11,113.52 83.24,113.39 83.24,113.03 83.37,112.9 83.55,112.9 83.68,113.03 83.68,113.39 83.81,113.52 83.99,113.52 84.12,113.39 84.12,113.03 84.24,112.9 84.42,112.9 84.55,113.03 84.55,113.39 84.68,113.52 84.99,113.52 85.26,113.79 90.52,113.79 91.37,112.94 92.2,112.94 92.56,112.58 95.96,112.58 96.52,112.02 98.14,112.02 98.92,111.25 99.57,111.25 99.7,111.12 99.7,109.6 99.82,109.47 100.01,109.47 100.13,109.6 100.13,111.12 100.26,111.25 100.44,111.25 100.57,111.12 100.57,109.6 100.7,109.47 100.88,109.47 101.01,109.6 101.01,111.12 101.13,111.25 101.32,111.25 101.44,111.12 101.44,109.6 101.57,109.47 101.75,109.47 101.88,109.6 101.88,111.12 102.01,111.25 103.37,111.25 103.63,110.98 104.6,110.98 105.27,110.31 105.9,110.31 106.74,109.48 106.92,109.48 107.16,109.73 107.34,109.73 107.47,109.6 107.47,109.42 107.23,109.17 107.23,108.99 107.36,108.86 107.54,108.86 107.78,109.11 107.96,109.11 108.09,108.98 108.09,108.8 107.85,108.55 107.85,108.37 107.97,108.24 108.15,108.24 108.4,108.49 108.58,108.49 108.71,108.36 108.71,108.18 108.46,107.94 108.46,107.75 109.03,107.19 109.71,107.19 110.05,106.85 111.19,106.85 111.38,106.66 111.38,106.48 110.76,105.86 110.76,105.67 110.89,105.55 111.07,105.55 111.69,106.17 111.87,106.17 112,106.04 112,105.86 111.38,105.24 111.38,105.06 111.51,104.93 111.69,104.93 112.31,105.55 112.49,105.55 112.8,105.24 114.07,105.24 114.26,105.05 114.26,104.87 113.49,104.09 113.49,103.91 113.61,103.78 113.79,103.78 114.57,104.56 114.75,104.56 114.88,104.43 114.88,104.25 114.1,103.48 114.1,103.29 114.23,103.17 114.41,103.17 115.19,103.94 115.37,103.94 115.5,103.81 115.5,103.63 114.72,102.86 114.72,102.68 114.85,102.55 115.03,102.55 115.81,103.32 115.99,103.32 116.12,103.2 116.12,103.02 115.34,102.24 115.34,102.06 115.47,101.93 115.65,101.93 116.43,102.71 116.61,102.71 116.87,102.45 116.87,102.09 v3(115.82,101.05)
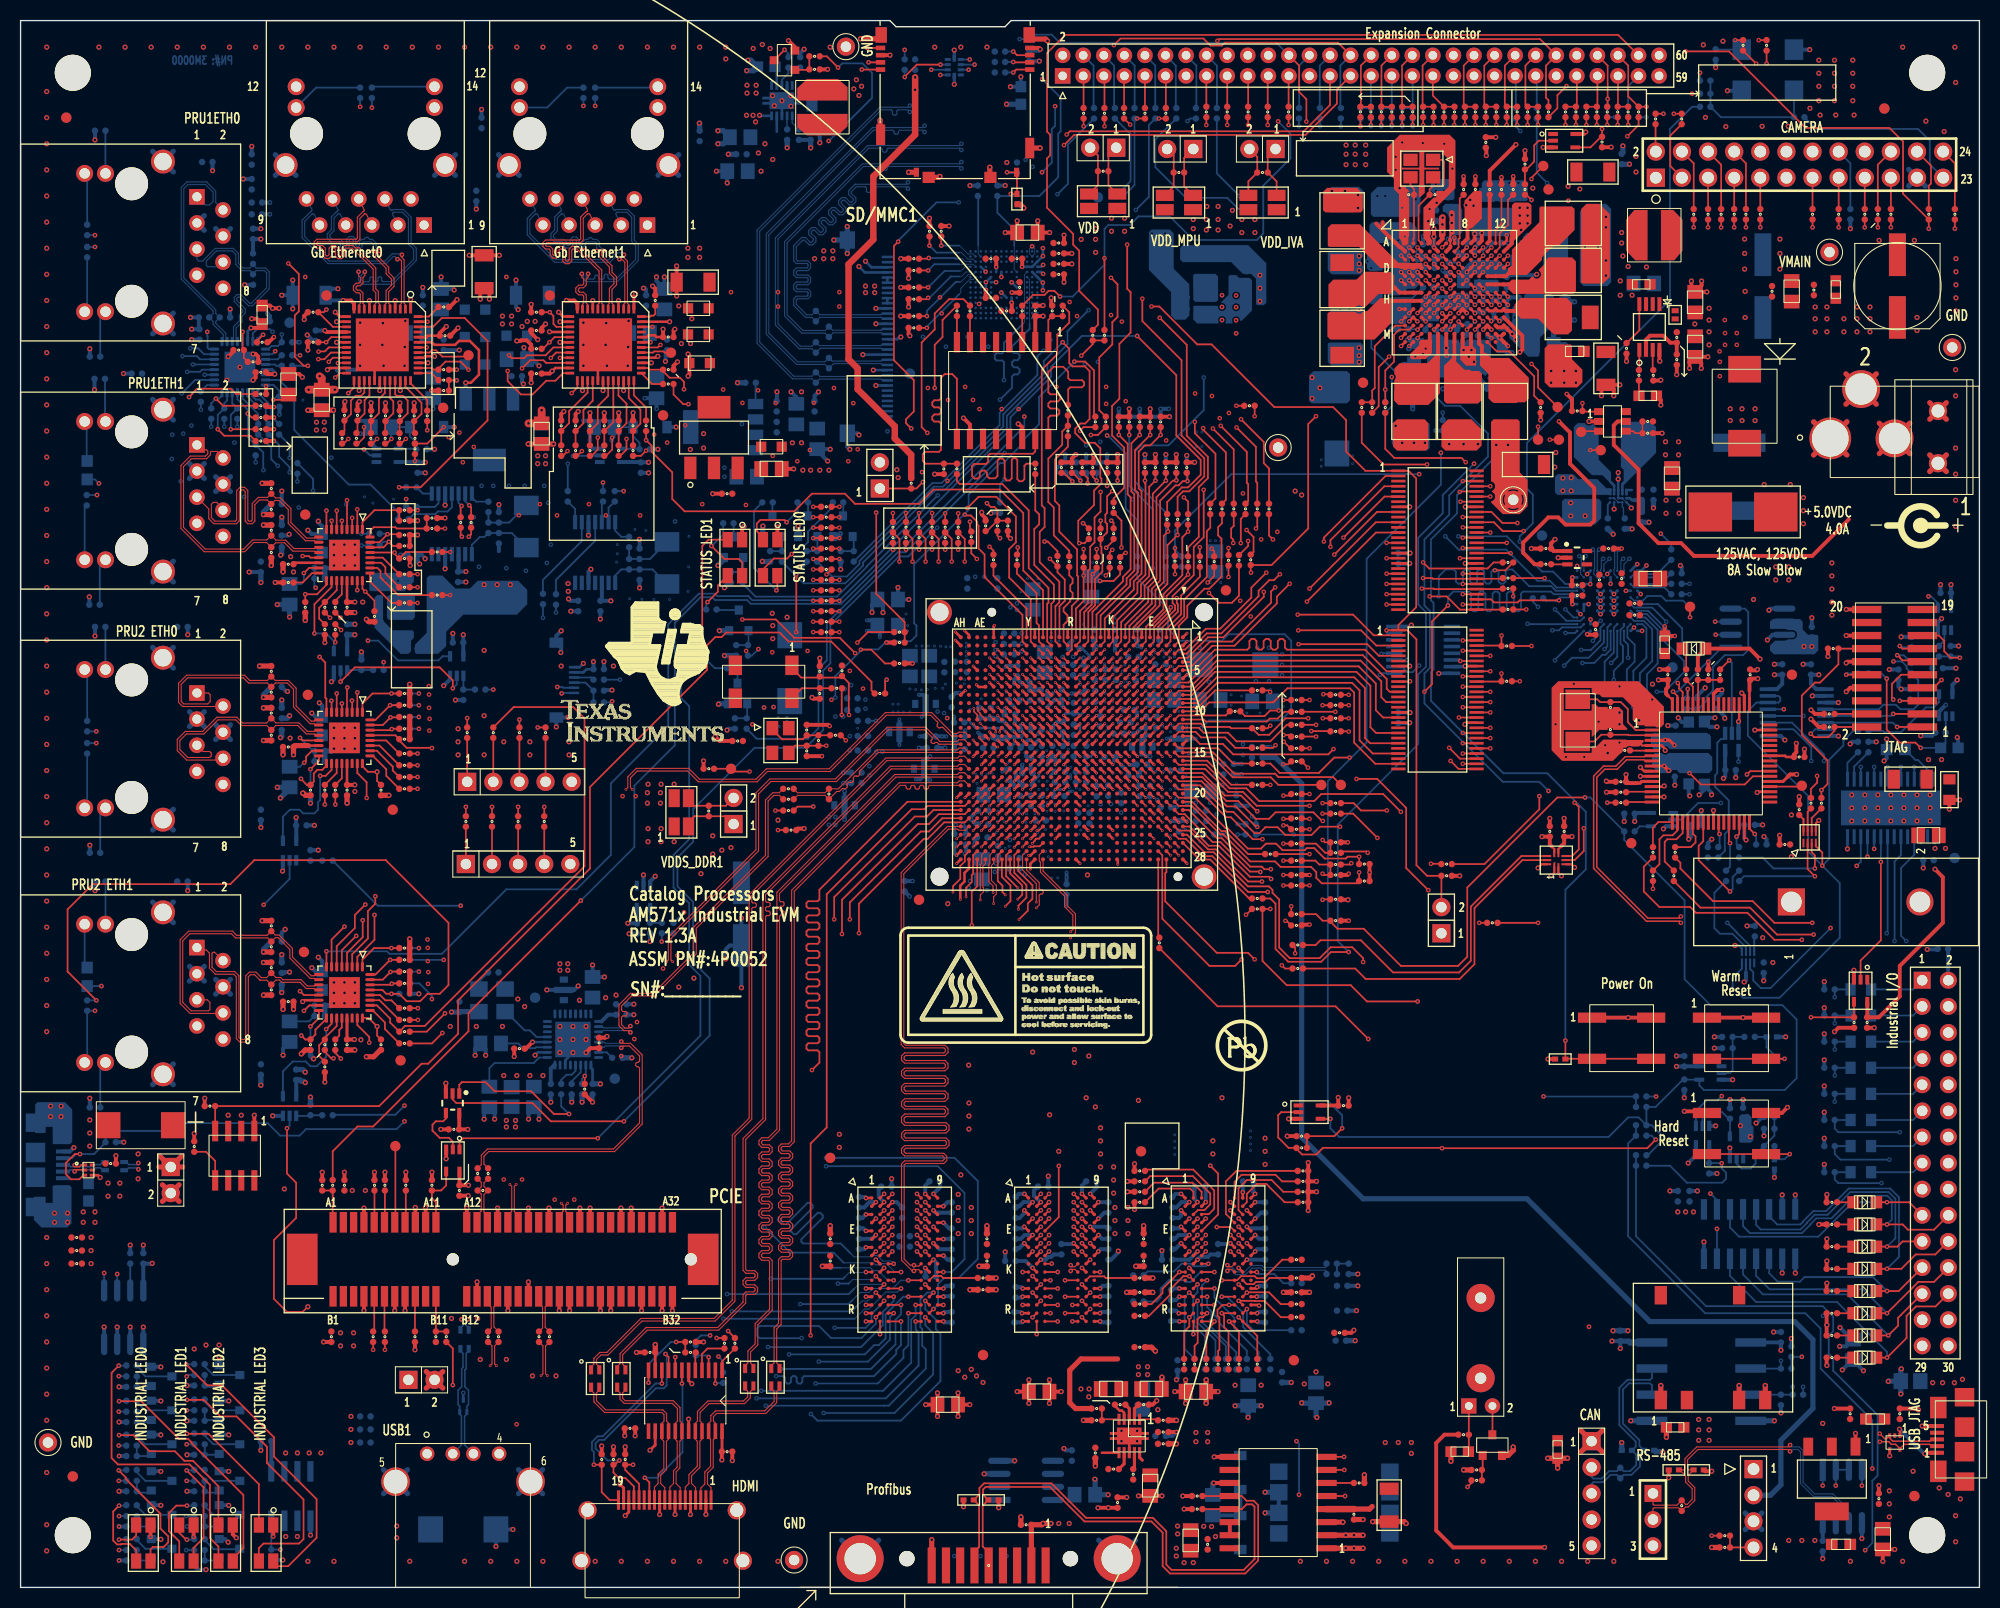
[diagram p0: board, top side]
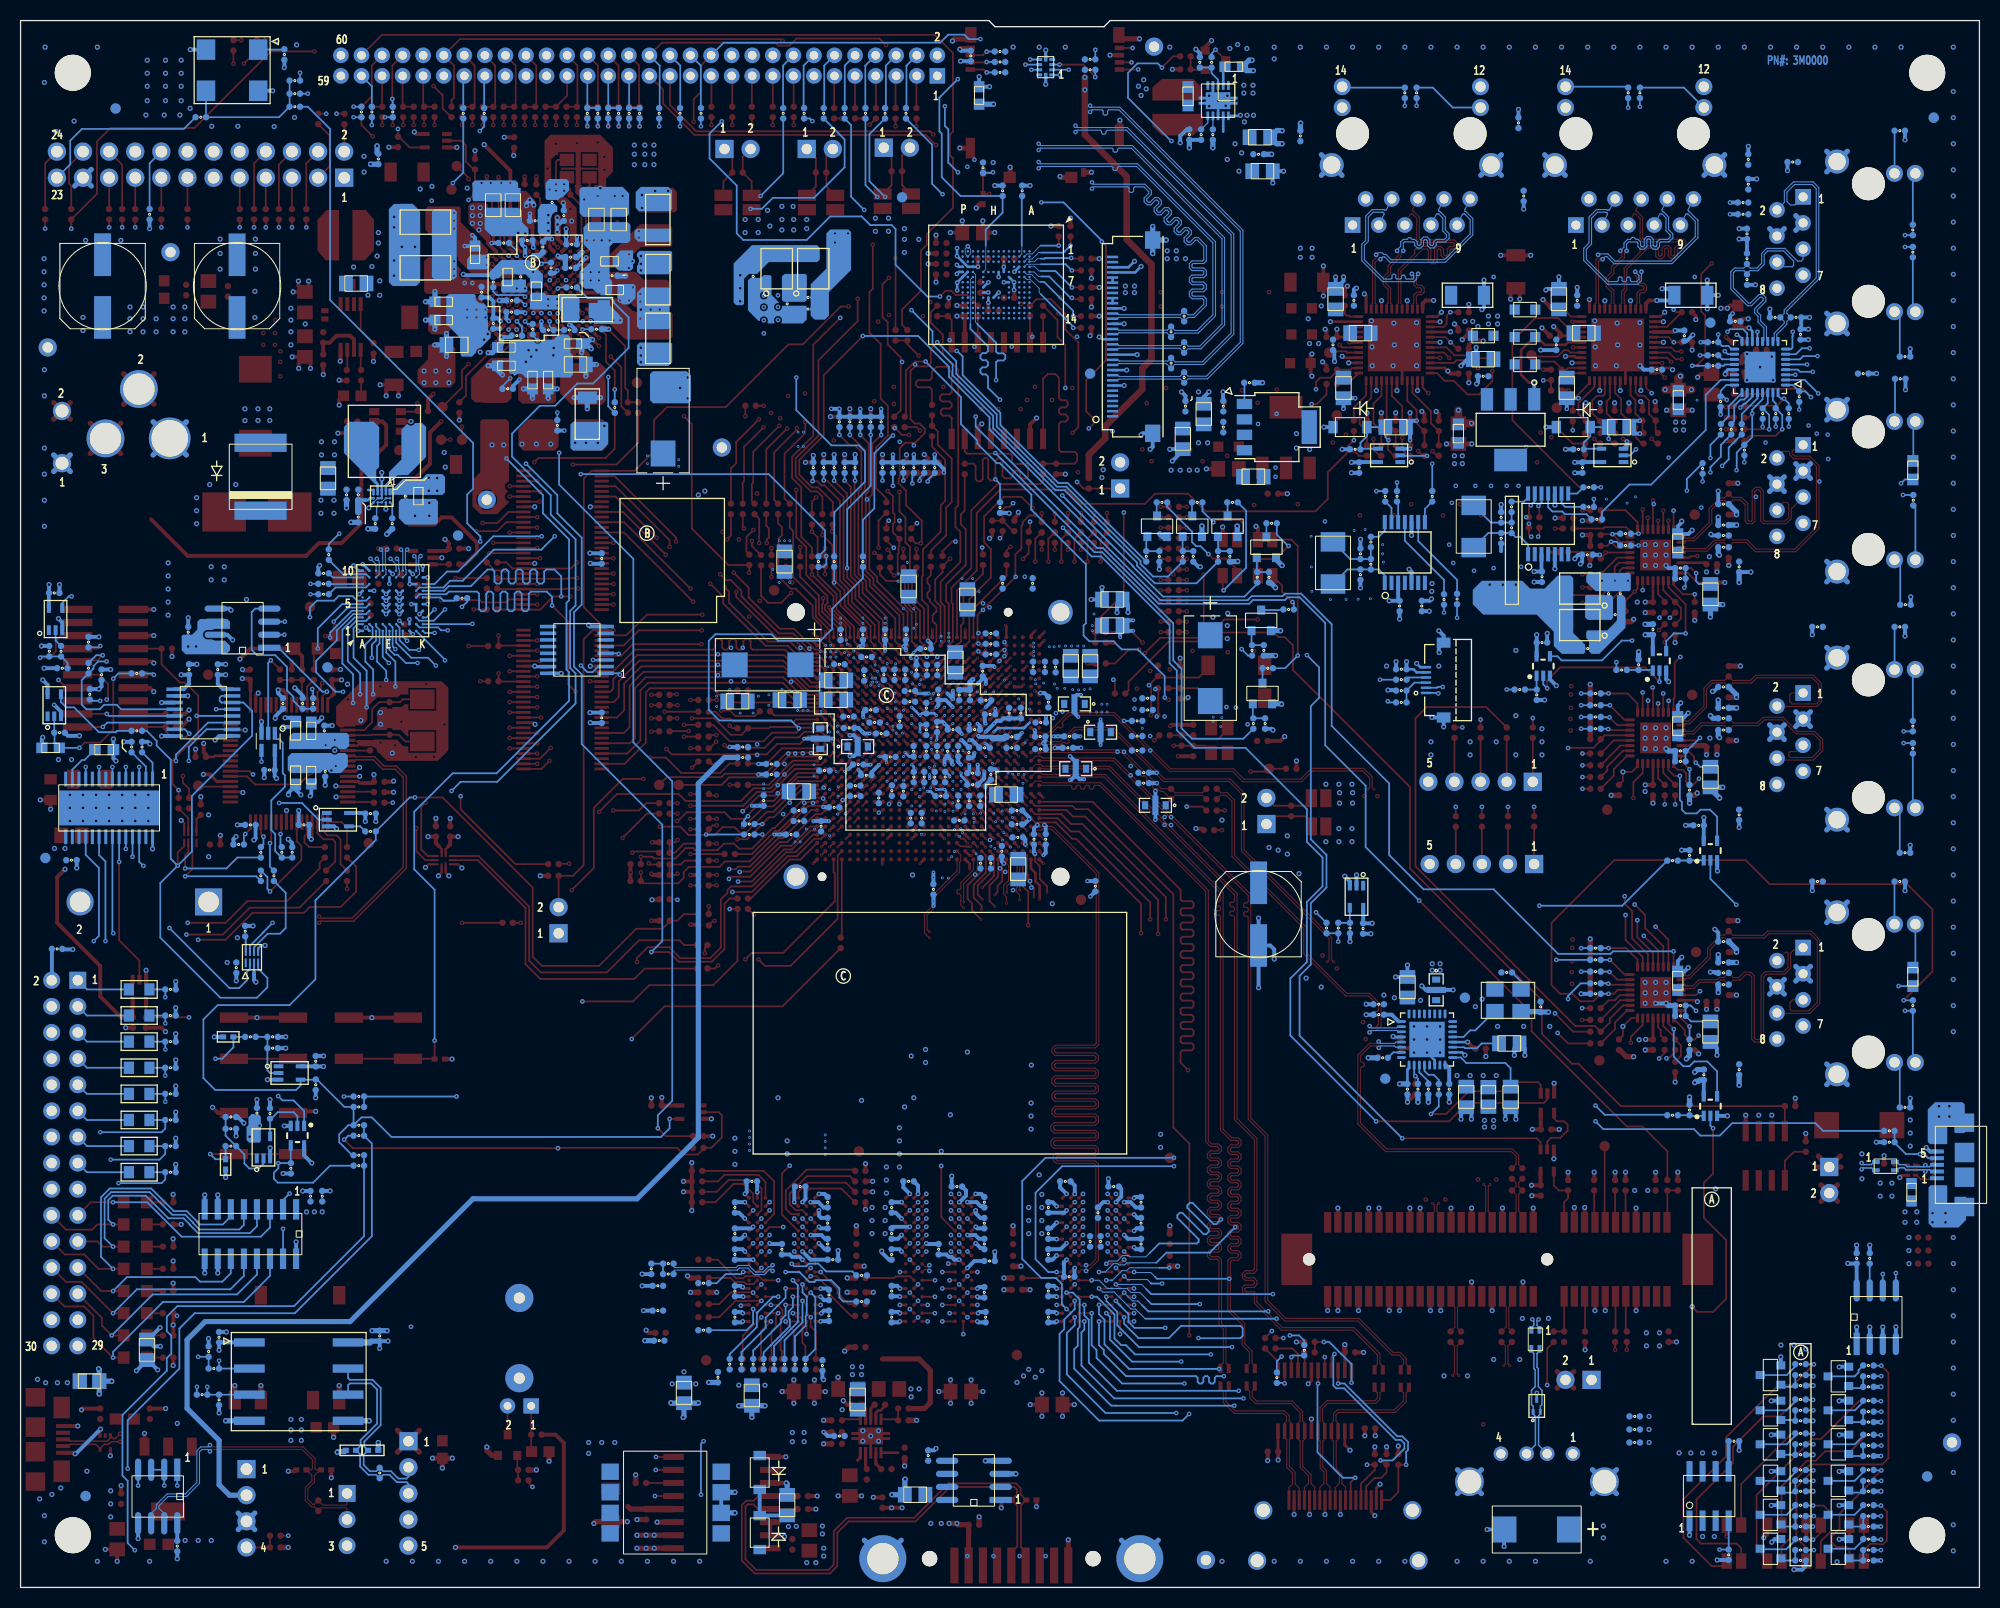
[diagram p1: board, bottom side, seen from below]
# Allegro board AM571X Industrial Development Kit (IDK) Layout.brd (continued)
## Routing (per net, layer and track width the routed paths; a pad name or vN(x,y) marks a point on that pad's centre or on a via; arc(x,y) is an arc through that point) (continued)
PRU1ETH1_TXD3: length 340.9
  TOP w0.173: v3(30.25,103.75) 30.25,103.75 U13.7 ; R128.1 v3(117.47,101.1)
  L3_SIG1 w0.109: v3(117.47,101.1) 117.47,102.32 114.21,105.58 112.96,105.58 112.95,105.59 112.93,105.59 111.33,107.19 110.19,107.19 109.89,107.48 109.89,107.72 109.53,108.09 109.47,108.09 106.9,110.65 105.41,110.65 104.74,111.32 103.77,111.32 103.51,111.58 99.06,111.58 98.28,112.36 96.66,112.36 96.1,112.92 92.7,112.92 92.34,113.28 91.51,113.28 90.66,114.13 85.12,114.13 84.85,113.86 71.31,113.86 70.9,113.45 70.9,113.27 71.62,112.55 71.62,112.37 71.5,112.24 71.32,112.24 70.59,112.96 70.41,112.96 70.28,112.83 70.28,112.65 71.01,111.93 71.01,111.75 70.88,111.62 70.7,111.62 69.97,112.34 69.79,112.34 69.67,112.21 69.67,112.03 70.39,111.31 70.39,111.13 70.26,111 70.08,111 69.36,111.72 69.18,111.72 69.05,111.6 69.05,111.42 69.77,110.69 69.77,110.51 69.64,110.38 69.46,110.38 68.74,111.11 68.56,111.11 68.43,110.98 68.43,110.8 69.15,110.07 69.15,109.89 69.02,109.77 68.84,109.77 68.12,110.49 67.94,110.49 67.81,110.36 67.81,110.18 68.53,109.46 68.53,109.28 68.41,109.15 68.22,109.15 67.5,109.87 67.32,109.87 67.01,109.56 65.56,109.56 64.29,108.29 62.08,108.29 61.41,107.61 60.74,107.61 59.43,108.92 59.03,108.92 58.9,108.79 58.9,108.38 58.77,108.25 58.59,108.25 58.46,108.38 58.46,108.79 58.33,108.92 58.15,108.92 58.02,108.79 58.02,108.38 57.9,108.25 57.72,108.25 57.59,108.38 57.59,108.79 57.46,108.92 57.28,108.92 57.15,108.79 57.15,108.38 57.02,108.25 56.84,108.25 56.71,108.38 56.71,108.79 56.59,108.92 56.4,108.92 56.28,108.79 56.28,108.38 56.15,108.25 55.97,108.25 55.84,108.38 55.84,108.79 55.71,108.92 55.53,108.92 55.4,108.79 55.4,108.38 55.27,108.25 55.09,108.25 54.97,108.38 54.97,108.79 54.84,108.92 54.66,108.92 54.53,108.79 54.53,108.38 54.4,108.25 54.22,108.25 54.09,108.38 54.09,108.79 53.96,108.92 53.78,108.92 53.66,108.79 53.66,108.38 53.53,108.25 53.35,108.25 53.22,108.38 53.22,108.79 53.09,108.92 52.91,108.92 52.78,108.79 52.78,108.38 52.65,108.25 52.47,108.25 52.34,108.38 52.34,108.79 52.22,108.92 51.81,108.92 51.38,108.5 51.32,108.5 51.32,108.5 49.8,108.5 49.27,109.04 49.27,109.72 48.18,110.81 48.18,111.32 48.05,111.45 47.12,111.45 46.99,111.58 46.99,111.76 47.12,111.89 48.05,111.89 48.18,112.01 48.18,112.2 48.05,112.32 47.12,112.32 46.99,112.45 46.99,112.63 47.12,112.76 48.05,112.76 48.18,112.89 48.18,113.07 48.05,113.2 47.12,113.2 46.99,113.33 46.99,113.51 47.12,113.63 48.05,113.63 48.18,113.76 48.18,113.94 48.05,114.07 47.12,114.07 46.99,114.2 46.99,114.38 47.12,114.51 48.05,114.51 48.18,114.64 48.18,115.05 47.67,115.56 47.49,115.56 46.77,114.85 46.59,114.85 46.46,114.98 46.46,115.16 47.18,115.87 47.18,116.05 47.05,116.18 46.87,116.18 46.15,115.47 45.97,115.47 45.85,115.6 45.85,115.78 46.56,116.49 46.56,116.67 46.43,116.8 46.25,116.8 45.54,116.09 45.36,116.09 45.23,116.21 45.23,116.4 45.94,117.11 45.94,117.29 45.68,117.55 45.68,118.05 45.55,118.18 44.63,118.18 44.5,118.31 44.5,118.49 44.63,118.62 45.55,118.62 45.68,118.75 45.68,119.07 45.55,119.19 43.44,119.19 43.31,119.32 43.31,119.5 43.44,119.63 45.55,119.63 45.68,119.76 45.68,119.94 45.55,120.07 43.44,120.07 43.31,120.2 43.31,120.38 43.44,120.5 45.55,120.5 45.68,120.63 45.68,120.81 45.55,120.94 43.03,120.94 42.9,121.07 42.9,121.25 43.03,121.38 45.55,121.38 45.68,121.51 45.68,121.69 45.55,121.82 43.03,121.82 42.9,121.94 42.9,122.12 43.03,122.25 45.55,122.25 45.68,122.38 45.68,124.09 45.31,124.46 44.93,124.46 44.8,124.33 44.8,122.84 44.67,122.71 44.49,122.71 44.36,122.84 44.36,124.33 44.23,124.46 44.05,124.46 43.92,124.33 43.92,122.84 43.8,122.71 43.62,122.71 43.49,122.84 43.49,124.33 43.36,124.46 43.18,124.46 43.05,124.33 43.05,123.09 42.92,122.96 42.74,122.96 42.61,123.09 42.61,123.7 42.49,123.83 42.19,123.83 42.04,123.67 42.04,121.88 41.91,121.75 41.58,121.75 41.45,121.63 41.45,121.45 41.58,121.32 41.91,121.32 42.04,121.19 42.04,120.8 41.82,120.58 41.27,120.58 41.04,120.81 41.04,122.02 40.92,122.15 40.74,122.15 40.61,122.02 40.61,120.69 40.48,120.56 40.3,120.56 40.17,120.69 40.17,122.02 40.04,122.15 39.86,122.15 39.73,122.02 39.73,121.19 39.61,121.07 39.42,121.07 39.3,121.19 39.3,122.02 39.17,122.15 38.99,122.15 38.86,122.02 38.86,120.63 38.73,120.51 38.55,120.51 38.42,120.63 38.42,122.02 38.3,122.15 38.11,122.15 37.99,122.02 37.99,121.19 37.86,121.07 37.68,121.07 37.55,121.19 37.55,122.02 37.42,122.15 37.24,122.15 37.11,122.02 37.11,121.07 36.98,120.94 36.8,120.94 36.68,121.07 36.68,122.02 36.55,122.15 36.37,122.15 36.24,122.02 36.24,120.79 36.11,120.66 35.93,120.66 35.8,120.79 35.8,122.02 35.67,122.15 35.49,122.15 35.36,122.02 35.36,121.45 35.24,121.32 35.06,121.32 34.93,121.45 34.93,122.02 34.8,122.15 34.62,122.15 34.49,122.02 34.49,120.76 34.36,120.63 34.18,120.63 34.05,120.76 34.05,122.02 33.93,122.15 33.75,122.15 33.62,122.02 33.62,121.45 33.49,121.32 33.31,121.32 33.18,121.45 33.18,122.02 33.05,122.15 32.87,122.15 32.74,122.02 32.74,121.45 32.62,121.32 32.43,121.32 32.31,121.45 32.31,122.02 32.18,122.15 32,122.15 31.87,122.02 31.87,121.45 31.74,121.32 31.39,121.32 31.19,121.51 31.19,121.7 31.06,121.83 30.2,121.83 30.07,121.95 30.07,122.14 30.2,122.26 31.06,122.26 31.19,122.39 31.19,122.63 31.34,122.78 32.6,122.78 32.87,122.51 40.64,122.51 41,122.87 41,123.52 40.69,123.83 39.39,123.83 39.26,123.7 39.26,123.47 39.13,123.34 38.95,123.34 38.82,123.47 38.82,123.7 38.69,123.83 38.51,123.83 38.38,123.7 38.38,122.91 38.26,122.78 38.08,122.78 37.95,122.91 37.95,123.7 37.82,123.83 37.18,123.83 37.05,123.7 37.05,123.5 36.92,123.37 36.74,123.37 36.62,123.5 36.62,123.7 36.49,123.83 36.31,123.83 36.18,123.7 36.18,122.94 36.05,122.81 35.87,122.81 35.74,122.94 35.74,123.7 35.61,123.83 34.98,123.83 34.85,123.7 34.85,123.25 34.74,123.14 34.56,123.14 34.41,123.29 34.41,123.7 34.28,123.83 34.1,123.83 33.97,123.7 33.97,122.89 33.85,122.76 33.67,122.76 33.54,122.89 33.54,123.7 33.41,123.83 32.82,123.83 32.69,123.7 32.69,123.34 32.56,123.22 32.38,123.22 32.26,123.34 32.26,123.7 32.13,123.83 31.95,123.83 31.82,123.7 31.82,123.22 31.69,123.09 31.51,123.09 31.38,123.22 31.38,123.7 31.25,123.83 31.05,123.83 30.8,123.57 30.42,123.57 30.16,123.83 29.67,123.83 29.55,123.7 29.55,122.86 29.42,122.73 29.24,122.73 29.11,122.86 29.11,124.12 29,124.23 28.78,124.23 28.67,124.12 28.67,122.86 28.54,122.73 28.36,122.73 28.24,122.86 28.24,123.7 28.11,123.83 27.84,123.83 27.71,123.95 27.71,124.36 27.59,124.49 27.41,124.49 27.28,124.36 27.28,123.95 27.15,123.83 26.88,123.83 26.39,123.33 26.39,121.7 25.98,121.29 25.98,120.84 25.59,120.45 25.59,120.27 26.36,119.51 26.36,119.32 26.23,119.2 26.05,119.2 25.28,119.96 25.1,119.96 24.98,119.83 24.98,119.65 25.74,118.89 25.74,118.71 25.61,118.58 25.43,118.58 24.67,119.34 24.49,119.34 24.23,119.09 24.23,118.86 24.1,118.73 22.84,118.73 22.71,118.6 22.71,118.42 22.84,118.29 24.1,118.29 24.23,118.16 24.23,117.98 24.1,117.86 23.19,117.86 23.06,117.73 23.06,117.55 23.19,117.42 24.92,117.42 25.1,117.25 25.1,117.05 25.22,116.92 26.47,116.92 26.59,116.8 26.59,116.61 26.47,116.49 25.22,116.49 25.1,116.36 25.1,116.18 25.22,116.05 26.47,116.05 26.59,115.92 26.59,115.74 26.47,115.61 25.22,115.61 25.1,115.48 25.1,115.3 25.22,115.18 26.47,115.18 26.59,115.05 26.59,114.87 26.47,114.74 25.22,114.74 25.1,114.61 25.1,114.43 25.22,114.3 26.47,114.3 26.59,114.17 26.59,113.99 26.47,113.87 25.22,113.87 25.1,113.74 25.1,113.56 25.22,113.43 26.47,113.43 26.59,113.3 26.59,113.12 26.47,112.99 25.22,112.99 25.1,112.86 25.1,112.68 25.22,112.55 26.47,112.55 26.59,112.43 26.59,112.25 26.47,112.12 25.22,112.12 25.1,111.99 25.1,111.81 25.22,111.68 26.47,111.68 26.59,111.55 26.59,111.37 26.47,111.24 25.22,111.24 25.1,111.12 25.1,110.94 25.22,110.81 26.47,110.81 26.59,110.68 26.59,110.5 26.47,110.37 25.22,110.37 25.1,110.24 25.1,110.08 24.94,109.93 23.2,109.93 23.07,109.8 23.07,109.62 23.2,109.49 26.47,109.49 26.59,109.36 26.59,109.18 26.47,109.05 23.12,109.05 22.99,108.92 22.99,108.74 23.12,108.61 26.47,108.61 26.59,108.49 26.59,108.31 26.47,108.18 24.08,108.18 23.96,108.05 23.96,107.87 24.08,107.74 26.47,107.74 26.59,107.61 26.59,107.43 26.47,107.3 24.08,107.3 23.96,107.18 23.96,107 24.08,106.87 24.79,106.87 24.92,106.74 24.92,106.56 24.79,106.43 23.5,106.43 23.37,106.3 23.37,106.12 23.5,105.99 25.68,105.99 25.81,105.87 25.81,105.68 25.68,105.56 24.08,105.56 23.96,105.43 23.96,104.97 24.33,104.6 25.58,104.6 25.98,104.19 26.35,104.19 26.48,104.32 26.48,105.21 26.61,105.33 26.79,105.33 26.92,105.21 26.92,103.84 27.05,103.71 27.23,103.71 27.36,103.84 27.36,105.21 27.48,105.33 27.66,105.33 27.79,105.21 27.79,103.84 27.92,103.71 28.1,103.71 28.23,103.84 28.23,105.21 28.36,105.33 28.54,105.33 28.67,105.21 28.67,104.32 28.79,104.19 29.16,104.19 29.6,103.75 v3(30.25,103.75)
PRU1ETH1_TXEN: length 342.6
  TOP w0.173: v3(32.25,104.03) U13.3 ; v3(119.38,101.78) 119.38,101.3 R124.1
  L3_SIG1 w0.109: v3(32.25,104.03) 32.87,104.03 33.53,103.38 33.53,103.08 33.66,102.95 35.05,102.95 35.18,102.82 35.18,102.13 35.05,102.01 33.66,102.01 33.53,101.88 33.53,101.7 33.66,101.57 35.05,101.57 35.18,101.44 35.18,101.26 35.05,101.13 33.66,101.13 33.53,101 33.53,100.82 33.66,100.7 35.05,100.7 35.18,100.57 35.18,100.39 35.05,100.26 33.66,100.26 33.53,100.13 33.53,99.95 33.66,99.82 35.05,99.82 35.18,99.69 35.18,99.51 35.05,99.39 33.66,99.39 33.53,99.26 33.53,98.3 33.15,97.92 32.83,97.92 32.71,98.05 32.71,98.8 32.58,98.93 32.4,98.93 32.27,98.8 32.27,98.05 32.14,97.92 31.96,97.92 31.83,98.05 31.83,98.8 31.7,98.93 31.52,98.93 31.4,98.8 31.4,98.05 31.27,97.92 30.86,97.92 29.51,99.26 29.51,99.44 29.97,99.9 29.97,100.08 29.84,100.21 29.66,100.21 29.21,99.75 29.02,99.75 28.5,100.28 28.5,100.46 28.63,100.59 29.84,100.59 29.97,100.72 29.97,100.9 29.84,101.03 28.63,101.03 28.5,101.15 28.5,102.23 28.37,102.36 28.19,102.36 28.06,102.23 28.06,101.09 27.93,100.97 27.75,100.97 27.63,101.09 27.63,102.23 27.5,102.36 27.32,102.36 27.19,102.23 27.19,101.09 27.06,100.97 26.79,100.97 26.67,101.09 26.67,101.73 26.54,101.85 26.36,101.85 26.23,101.73 26.23,101.09 26.1,100.97 25.92,100.97 25.79,101.09 25.79,101.73 25.66,101.85 25.48,101.85 25.35,101.73 25.35,101.09 25.23,100.97 25.05,100.97 24.92,101.09 24.92,101.73 24.79,101.85 24.61,101.85 24.48,101.73 24.48,100.08 24.35,99.95 24.17,99.95 24.04,100.08 24.04,101.73 23.92,101.85 23.74,101.85 23.61,101.73 23.61,98.43 23.48,98.3 23.3,98.3 23.17,98.43 23.17,101.73 23.04,101.85 22.86,101.85 22.73,101.73 22.73,96.9 26.16,93.47 26.16,92.58 25.78,92.2 25.48,92.2 25.35,92.33 25.35,92.96 25.22,93.09 25.04,93.09 24.91,92.96 24.91,92.33 24.79,92.2 24.61,92.2 24.48,92.33 24.48,92.96 24.35,93.09 24.17,93.09 24.04,92.96 24.04,92.33 23.91,92.2 23.73,92.2 23.6,92.33 23.6,92.96 23.48,93.09 23.29,93.09 23.17,92.96 23.17,92.33 23.04,92.2 22.86,92.2 22.73,92.33 22.73,92.96 22.6,93.09 22.42,93.09 22.29,92.96 22.29,92.33 22.16,92.2 21.98,92.2 21.86,92.33 21.86,92.96 21.73,93.09 21.55,93.09 21.42,92.96 21.42,92.33 21.29,92.2 21.11,92.2 20.98,92.33 20.98,92.96 20.85,93.09 20.67,93.09 20.55,92.96 20.55,92.33 20.42,92.2 20.24,92.2 20.11,92.33 20.11,92.96 19.98,93.09 19.8,93.09 19.67,92.96 19.67,92.33 19.54,92.2 19.05,92.2 17.02,94.23 17.02,101.47 18.41,102.87 18.41,107.41 19.65,108.65 20.26,108.65 20.7,109.09 20.7,110.36 19.81,111.25 19.81,113.29 19.94,113.42 20.55,113.42 20.68,113.55 20.68,113.73 20.55,113.86 19.94,113.86 19.81,113.99 19.81,114.17 19.94,114.29 20.55,114.29 20.68,114.42 20.68,114.6 20.55,114.73 19.94,114.73 19.81,114.86 19.81,115.04 19.94,115.17 20.55,115.17 20.68,115.3 20.68,115.48 20.55,115.6 19.94,115.6 19.81,115.73 19.81,115.95 19.05,116.71 19.05,118.22 19.18,118.34 20.57,118.34 20.7,118.47 20.7,118.65 20.57,118.78 19.18,118.78 19.05,118.91 19.05,119.09 19.18,119.22 19.62,119.22 19.73,119.33 19.73,119.59 19.62,119.7 19.22,119.7 19.01,119.91 19.01,120.3 19.15,120.45 19.36,120.45 19.49,120.57 19.49,122.25 19.62,122.38 19.8,122.38 19.93,122.25 19.93,120.57 20.06,120.45 20.24,120.45 20.37,120.57 20.37,122.25 20.49,122.38 20.67,122.38 20.8,122.25 20.8,120.57 20.93,120.45 21.25,120.45 21.38,120.57 21.38,121.56 21.5,121.69 21.68,121.69 21.81,121.56 21.81,120.57 21.94,120.45 22.12,120.45 22.25,120.57 22.25,121.56 22.38,121.69 22.56,121.69 22.69,121.56 22.69,120.57 22.81,120.45 23.49,120.45 24.02,120.98 24.02,121.69 24.26,121.92 24.26,122.1 23.21,123.15 23.21,123.34 23.34,123.46 23.52,123.46 24.57,122.41 24.75,122.41 24.88,122.54 24.88,122.72 23.83,123.77 23.83,123.95 23.95,124.08 24.14,124.08 25.19,123.03 25.37,123.03 25.61,123.27 25.61,124.67 26.16,125.22 26.33,125.22 26.46,125.35 26.46,126.54 26.59,126.67 26.77,126.67 26.9,126.54 26.9,125.35 27.03,125.22 27.21,125.22 27.33,125.35 27.33,126.54 27.46,126.67 27.64,126.67 27.77,126.54 27.77,125.35 27.9,125.22 28.08,125.22 28.21,125.35 28.21,126.54 28.34,126.67 28.52,126.67 28.65,126.54 28.65,125.35 28.77,125.22 28.95,125.22 29.08,125.35 29.08,126.54 29.21,126.67 29.39,126.67 29.52,126.54 29.52,125.35 29.65,125.22 29.83,125.22 29.96,125.35 29.96,126.54 30.08,126.67 30.26,126.67 30.39,126.54 30.39,125.35 30.52,125.22 30.67,125.22 31.1,125.65 31.53,125.65 31.65,125.78 31.65,126.72 31.78,126.85 31.96,126.85 32.09,126.72 32.09,125.78 32.22,125.65 32.4,125.65 32.53,125.78 32.53,126.72 32.66,126.85 32.84,126.85 32.97,126.72 32.97,125.78 33.09,125.65 33.27,125.65 33.4,125.78 33.4,126.72 33.53,126.85 33.71,126.85 33.84,126.72 33.84,125.78 33.97,125.65 34.15,125.65 34.28,125.78 34.28,126.72 34.4,126.85 34.58,126.85 34.71,126.72 34.71,125.78 34.84,125.65 35.02,125.65 35.15,125.78 35.15,126.72 35.28,126.85 35.46,126.85 35.59,126.72 35.59,125.78 35.71,125.65 35.9,125.65 36.02,125.78 36.02,126.72 36.15,126.85 36.33,126.85 36.46,126.72 36.46,125.78 36.59,125.65 36.77,125.65 36.9,125.78 36.9,126.72 37.03,126.85 37.21,126.85 37.33,126.72 37.33,125.78 37.46,125.65 37.67,125.65 37.74,125.72 38.05,125.72 38.16,125.83 38.16,126.78 38.29,126.91 38.99,126.91 39.12,127.04 39.12,127.79 39.25,127.91 39.43,127.91 39.56,127.79 39.56,127.04 39.68,126.91 39.87,126.91 39.99,127.04 39.99,127.79 40.12,127.91 40.3,127.91 40.43,127.79 40.43,127.04 40.56,126.91 41.59,126.91 41.72,127.04 41.72,127.79 41.85,127.91 42.03,127.91 42.16,127.79 42.16,127.04 42.28,126.91 42.46,126.91 42.59,127.04 42.59,127.79 42.72,127.91 42.9,127.91 43.03,127.79 43.03,127.04 43.16,126.91 43.34,126.91 43.47,127.04 43.47,127.79 43.59,127.91 43.77,127.91 43.9,127.79 43.9,127.04 44.03,126.91 44.21,126.91 44.34,127.04 44.34,127.79 44.47,127.91 44.65,127.91 44.78,127.79 44.78,127.04 44.9,126.91 45.09,126.91 45.21,127.04 45.21,127.79 45.34,127.91 45.52,127.91 45.65,127.79 45.65,127.04 45.78,126.91 45.97,126.91 46.55,126.32 48.21,126.32 48.34,126.19 48.34,126.01 48.21,125.88 46.48,125.88 46.35,125.75 46.35,125.57 46.48,125.45 47.75,125.45 47.88,125.32 47.88,125.14 47.75,125.01 46.48,125.01 46.35,124.88 46.35,124.7 46.48,124.57 47.75,124.57 47.88,124.44 47.88,124.26 47.75,124.13 46.48,124.13 46.35,124.01 46.35,117.83 48.89,115.29 48.89,111.05 49.33,110.62 52.02,110.62 53.04,109.6 60.2,109.6 60.83,108.97 61.83,108.97 61.96,109.1 61.96,109.88 62.09,110.01 62.27,110.01 62.4,109.88 62.4,109.1 62.53,108.97 62.71,108.97 62.83,109.1 62.83,109.88 62.96,110.01 63.14,110.01 63.27,109.88 63.27,109.1 63.4,108.97 64.01,108.97 65.28,110.24 66.67,110.24 67.34,110.9 67.34,111.08 66.73,111.69 66.73,111.87 66.86,112 67.04,112 67.65,111.39 67.83,111.39 67.96,111.52 67.96,111.7 67.35,112.31 67.35,112.49 67.48,112.62 67.66,112.62 68.27,112.01 68.45,112.01 68.58,112.14 68.58,112.32 67.97,112.93 67.97,113.11 68.1,113.23 68.28,113.23 68.89,112.63 69.07,112.63 69.2,112.76 69.2,112.94 68.59,113.54 68.59,113.72 68.72,113.85 68.9,113.85 69.5,113.25 69.69,113.25 69.81,113.37 69.81,113.56 69.21,114.16 69.21,114.34 69.34,114.47 69.52,114.47 70.12,113.86 70.3,113.86 70.99,114.55 84.58,114.55 84.84,114.81 91.82,114.81 93,113.63 97.21,113.63 97.51,113.33 103.68,113.33 103.91,113.11 104.09,113.11 104.78,113.8 104.96,113.8 105.09,113.68 105.09,113.5 104.4,112.8 104.4,112.62 104.53,112.49 104.71,112.49 105.4,113.19 105.58,113.19 105.71,113.06 105.71,112.88 105.02,112.18 105.02,112 105.69,111.33 107.24,111.33 109.6,108.97 112.83,108.97 113.26,108.53 115.24,108.53 119.67,104.11 119.67,102.07 v3(119.38,101.78)
PRU1ETHER0_RDN: length 23.1
  BOTTOM w0.108: J3.2 18.97,134.7 18.97,135.82 18.09,136.71 16.18,136.71 15.62,136.15 15.62,127.26 18.73,124.15 18.73,123.91 R99.2 18.73,123.14 18.73,122.85 19.71,121.88 19.71,121.3 U9.9
PRU1ETHER0_RDP: length 23.2
  BOTTOM w0.108: J3.1 17.93,134.47 18.39,134.47 18.72,134.8 18.72,135.72 17.98,136.45 16.28,136.45 15.88,136.05 15.88,127.36 18.98,124.26 18.98,123.91 R100.2 18.98,123.14 18.98,122.96 19.96,121.98 19.96,121.3 U9.10
PRU1ETHER0_TDN: length 21.1
  BOTTOM w0.108: 22.61,127.79 22.89,128.07 23.72,128.07 23.93,127.87 23.93,126.4 22.45,124.92 22.27,124.92 21.44,125.75 21.05,125.75 20.77,125.48 20.77,125.09 21.61,124.25 21.61,124.07 21.28,123.75 21.28,123.2 20.71,122.62 20.71,121.3 U9.11 ; 22.61,127.79 R101.2 ; 22.61,127.79 22.33,128.07 21.54,128.07 20.93,128.68 20.93,129.64 20.58,129.99 19.04,129.99 18.06,129.01 18.06,128.61 18.21,128.45 19.24,128.45 19.69,128.91
PRU1ETHER0_TDP: length 21.3
  BOTTOM w0.108: 22.61,128.63 22.3,128.33 21.64,128.33 21.18,128.78 21.18,129.75 20.69,130.24 18.94,130.24 17.7,129.01 17.32,129.01 17.15,129.18 J3.5 ; 22.61,128.63 R102.2 ; 22.61,128.63 22.91,128.33 23.83,128.33 24.18,127.97 24.18,126.29 22.55,124.66 22.17,124.66 21.33,125.5 21.15,125.5 21.03,125.37 21.03,125.19 21.86,124.36 21.86,123.97 21.54,123.64 21.54,123.08 20.96,122.51 20.96,121.3 U9.12
PRU1ETHER1_RDN: length 24.3
  TOP w0.108: U13.9 28.7,102.16 28.6,102.06 27.81,102.06 26.29,103.59 26.29,104.94 25.26,105.97 24.79,105.97 R143.2 24.03,106.02 23.13,106.02 22.53,105.42 22.53,103.82 22.42,103.71 22.2,103.71 22.1,103.82 22.1,106.69 21.78,107 21.35,107 21.02,106.67 21.02,103.84 20.89,103.71 18.9,103.71 18.55,104.06 18.55,105.35 18.75,105.54 19.08,105.54 19.69,104.93 J5.6
PRU1ETHER1_RDP: length 24.2
  TOP w0.108: U13.10 28.72,101.66 28.58,101.81 27.71,101.81 26.03,103.48 26.03,104.83 25.15,105.72 24.74,105.72 R144.2 23.98,105.77 23.24,105.77 22.78,105.32 22.78,103.72 22.53,103.46 22.1,103.46 21.84,103.71 21.84,106.58 21.68,106.75 21.45,106.75 21.27,106.57 21.27,103.74 20.99,103.46 18.8,103.46 18.3,103.96 18.3,104.9 J5.5
PRU1ETHER1_TDN: length 26
  TOP w0.108: U13.11 28.69,101.16 28.58,101.05 26.6,101.05 25.78,101.86 24.84,101.86 R145.2 23.95,101.88 22.58,101.88 21.69,101 17.96,101 15.85,103.1 15.85,109.02 16.61,109.78 18.08,109.78 18.46,110.16 18.46,110.41 18.55,110.49 19.1,110.49 19.68,109.92 19.68,109.87 J5.2
PRU1ETHER1_TDP: length 26.3
  TOP w0.108: U13.12 28.71,100.66 28.58,100.79 26.49,100.79 25.68,101.6 24.82,101.6 R146.2 23.93,101.63 22.68,101.63 21.79,100.74 17.85,100.74 15.6,103 15.6,109.13 16.51,110.04 17.98,110.04 18.21,110.27 18.21,110.52 18.08,110.65 17.63,110.65 J5.1
PRU2ETH0_25MHZCLK: length 38.1
  TOP w0.173: v3(33.66,76.79) 33.66,78.31 32.75,79.22 U15.23
  L3_SIG1 w0.109: v3(33.66,76.79) v5(34.42,76.79)
  L9_SIG3 w0.114: v5(39.24,94.82) 39.24,90.76 36.69,88.21 36.69,83.3 35.97,82.58 35.97,78.34 v5(34.42,76.79)
  L10_SIG4 w0.109: v7(52.07,94.82) v5(39.24,94.82)
  BOTTOM w0.173: R354.2 v7(52.07,94.82)
PRU2ETH0_COL: length 347.9
  TOP w0.173: U15.29 36.45,82.88 R187.2 36.83,82.38 37.54,81.66 39.98,81.66 v8(40,81.64) ; 124.59,80.35 124.59,80.34 v3(125.2,79.73) ; R188.1 v3(121.54,78.06)
  L3_SIG1 w0.109: v3(121.54,78.06) 122.81,78.06 v5(123.83,77.04) ; v3(125.2,79.73) v5(124.49,79.73) ; v8(7.37,82.12) 15.39,82.12 16.23,82.96 17.81,82.96 18.8,81.97 20.57,81.97 22.77,84.17 33.69,84.17 36.22,81.64 v8(40,81.64)
  L4_SIG2 w0.114: v8(40,81.64) 38.52,81.64 35.18,78.3 35.18,57.53 31.95,54.3 31.95,51.63 30.35,50.03 30.35,33.02 32.13,31.24 32.13,29.72 26.42,24 26.42,23.11 24.26,20.95 24.26,10.61 30.93,3.93 41.28,3.93 42.14,4.79 48.39,4.79 55.09,11.5 74.62,11.5 74.8,11.68 95.57,11.68 96.75,10.5 103.26,10.5 104.03,9.72 104.8,9.72 105.58,10.5 112.98,10.5 114.73,8.74 121.24,8.74 122.08,9.58 133.2,9.58 139.15,15.53 143.98,15.53 151.08,22.63 151.08,64.63 149.73,65.98 148.78,65.98 144.4,70.36 144.4,71.06 138.94,76.52 138.94,77.34 137.82,78.46 130.64,78.46 129.7,77.52 126.59,77.52 125.81,76.73 124.14,76.73 v5(123.83,77.04)
  L9_SIG3 w0.114: v5(123.83,77.04) 124.49,77.7 v5(124.49,79.73)
  BOTTOM w0.173: R189.2 v8(7.37,82.12)
PRU2ETH0_CRS: length 3.7
  TOP w0.173: U15.27 34.91,81.88 R177.1
PRU2ETH0_INTN: length 192.9
  TOP w0.173: U15.8 29.75,86.44 29.63,86.56 29.63,89.96 v8(29.08,90.51)
  L3_SIG1 w0.109: v8(29.08,90.51) 29.97,90.51 31.67,92.21 31.67,94.52 31.27,94.92 29.36,94.92 26.14,91.69 18.85,91.69 16.64,93.9 16.64,101.98 16.13,102.48 16.13,106.68 16.84,107.39 17.72,107.39 18.41,108.08 18.41,113.36 18.92,113.87 18.92,114.93 19.43,115.45 19.43,115.81 18.67,116.57 18.67,120.63 18.47,120.83 18.47,121.74 19.69,122.96 20.65,122.96 22.48,124.79 22.48,125.3 24.94,127.76 26.64,127.76 27.38,127.03 27.87,127.03 28.37,127.53 30,127.53 30.33,127.2 37.46,127.2 38.53,128.27 59.31,128.27 64,132.96 84.06,132.96 85.16,131.86 91.22,131.86 91.7,132.34 95.99,132.34 96.45,131.88 98.98,131.88 100.38,130.48 103.25,130.48 103.61,130.13 103.61,128.99 104.62,127.97 106.09,127.97 108.58,125.48 108.58,125 111.84,121.75 112.24,121.75 115.06,118.93 v5(115.06,118.29)
  L10_SIG4 w0.109: v7(115.06,117.68) v5(115.06,118.29)
  BOTTOM w0.173: v7(115.06,117.68) 115.06,114.51 111.63,111.08 108.97,111.08 108.38,110.49 108.38,107.55 111.38,104.55 R671.2
PRU2ETH0_LINKLED: length 26.9
  TOP w0.173: U15.17 29.75,79.93 29.34,79.52 28.86,79.52 28.52,79.17 28.52,78.38 R159.1 27.84,78.06 27.38,78.52 27.38,78.54 v8(27.27,78.65)
  L4_SIG2 w0.114: v8(7.37,83.27) 16.64,83.27 16.65,83.25 17.86,83.25 19.31,81.81 23.27,81.81 26.42,78.65 v8(27.27,78.65)
  BOTTOM w0.173: R176.2 v8(7.37,83.27)
PRU2ETH0_MDC: length 2.4
  TOP w0.173: R179.1 31.25,78.7 U15.20
PRU2ETH0_MDIO: length 2.6
  TOP w0.173: U15.19 30.75,79.21 R181.1
PRU2ETH0_RESETN: length 11.7
  TOP w0.173: v8(29.13,78.94) 29.66,78.94 30.25,79.52 U15.18
  BOTTOM w0.173: v8(29.13,78.94) 29.13,76.58 28.93,76.38 28.93,75.64 28.58,75.29 27.48,75.29 27.12,75.65 26.2,75.65 25.51,74.96 U70.4
PRU2ETH0_RXCLK: length 4.6
  TOP w0.173: R165.1 35.56,78.95 35.56,79.58 34.26,80.88 U15.25
PRU2ETH0_RXD0: length 3.7
  TOP w0.173: U15.30 36,83.38 v8(36.1,83.49) 36.13,83.52 R194.2
  BOTTOM w0.173: v8(36.1,83.49) 36.13,83.52 R194.2
PRU2ETH0_RXD1: length 4.1
  TOP w0.173: U15.31 35.22,83.88 v8(35.97,84.63) 36.8,84.63 R193.2
  BOTTOM w0.173: v8(35.97,84.63) 36.8,84.63 R193.2
PRU2ETH0_RXD2: length 4.3
  TOP w0.173: R192.2 v8(35.94,85.81) 34.52,84.38 U15.32
  BOTTOM w0.173: R192.2 v8(35.94,85.81)
PRU2ETH0_RXD3: length 5.6
  TOP w0.173: R191.2 v8(36.07,86.95) 34.23,86.95 33.25,85.97 U15.1
  BOTTOM w0.173: R191.2 v8(36.07,86.95)
PRU2ETH0_RXDV: length 4.1
  TOP w0.173: R166.1 36.2,79.46 36.2,79.84 34.65,81.38 U15.26
PRU2ETH0_RXERR: length 3.4
  TOP w0.173: U15.28 35.56,82.38 R170.1
PRU2ETH0_TXCLK: length 246.2
  TOP w0.173: U15.2 v8(32.75,87.05) ; 124.59,82.76 v3(125.98,82.76)
  L3_SIG1 w0.109: v3(125.98,82.76) 126.34,82.76 126.67,83.09 128.47,83.09 129.06,82.5 130.63,82.5 v5(130.86,82.73)
  L10_SIG4 w0.109: v5(130.86,82.73) 130.86,80.54 131.09,80.31 131.09,71.88 130.63,71.42 130.63,69.19 131.09,68.73 131.09,64.44 129.61,62.96 129.61,60.03 129.48,59.9 129.16,59.9 129.03,59.77 129.03,59.59 129.16,59.46 129.48,59.46 129.61,59.33 129.61,59.15 129.48,59.02 129.16,59.02 129.03,58.9 129.03,58.71 129.16,58.59 129.48,58.59 129.67,58.4 129.67,44.6 128.36,43.29 128.36,42.34 128.49,42.21 129.16,42.21 129.29,42.08 129.29,41.9 129.16,41.77 128.49,41.77 128.36,41.65 128.36,41.46 128.49,41.34 129.16,41.34 129.29,41.21 129.29,41.03 129.16,40.9 128.49,40.9 128.36,40.77 128.36,40.59 128.49,40.46 129.16,40.46 129.29,40.33 129.29,40.15 129.16,40.03 128.49,40.03 128.36,39.9 128.36,26.4 122.66,20.7 122.66,17.9 120.5,15.74 118.13,15.74 114.81,12.41 106.31,12.41 106.07,12.65 102.88,12.65 102.19,11.96 96.97,11.96 95.59,10.59 93.3,10.59 92.72,11.17 66.16,11.17 59.9,17.43 57.88,17.43 53.21,22.1 50.43,22.1 48.04,24.49 42.44,24.49 33.27,33.66 33.27,34.9 31.84,36.33 31.84,37.42 30.12,39.14 29.82,39.14 28.83,40.13 28.83,41.43 27.38,42.88 27.38,48.74 26.51,49.62 26.51,55.61 26.08,56.04 26.08,59.01 25.7,59.39 25.7,60.5 26.51,61.3 26.51,67 33.27,73.77 33.27,86.52 v8(32.75,87.05)
PRU2ETH0_TXD0: length 245.9
  TOP w0.173: 124.59,81.62 v3(125.35,81.62) ; U15.4 31.75,87.5 v8(31.78,87.53)
  L3_SIG1 w0.109: v3(125.35,81.62) 126.5,81.62 127.24,82.35 128.17,82.35 128.83,81.69 v5(130.16,81.69)
  L10_SIG4 w0.109: v8(31.78,87.53) 33.17,87.53 33.66,87.05 33.66,73.41 26.85,66.6 26.85,59.31 27.99,58.16 27.99,55.91 26.84,54.76 26.84,51.71 28.15,50.4 28.15,48.91 27.73,48.5 27.73,43.01 29.97,40.77 29.97,39.9 32.33,37.54 32.33,36.35 33.78,34.9 33.78,33.66 39.63,27.81 43.56,27.81 46.27,25.1 47.9,25.1 50.53,22.48 53.37,22.48 58.08,17.76 60.04,17.76 66.3,11.51 93.09,11.51 94.57,12.99 100.13,12.99 100.82,12.3 102.05,12.3 102.74,12.99 106.21,12.99 106.45,12.75 114.67,12.75 117.99,16.08 120.36,16.08 122.33,18.04 122.33,20.93 127.28,25.88 127.28,26.47 127.41,26.6 127.74,26.6 127.86,26.73 127.86,26.91 127.74,27.04 127.41,27.04 127.28,27.17 127.28,27.35 127.41,27.48 127.74,27.48 127.86,27.6 127.86,27.79 127.74,27.91 127.41,27.91 127.28,28.04 127.28,28.22 127.41,28.35 127.74,28.35 127.86,28.48 127.86,28.66 127.74,28.79 127.41,28.79 127.28,28.92 127.28,29.1 127.41,29.22 127.74,29.22 127.86,29.35 127.86,29.53 127.74,29.66 127.41,29.66 127.28,29.79 127.28,29.97 127.41,30.1 127.74,30.1 127.86,30.23 127.86,30.41 127.74,30.53 127.41,30.53 127.28,30.66 127.28,44.12 127.82,44.66 127.82,45.76 127.56,46.01 127.56,58.83 127.69,58.96 127.69,65.18 128.6,66.09 130.18,66.09 130.61,66.52 130.61,67.74 129.51,68.83 129.51,72.14 130.61,73.23 130.61,79.73 130.16,80.18 v5(130.16,81.69)
PRU2ETH0_TXD1: length 250.9
  TOP w0.173: U15.5 31.25,85.97 v8(31.25,85.97) ; 124.59,83.9 v3(125.98,83.9)
  L3_SIG1 w0.109: v3(125.98,83.9) 126.19,83.7 127.23,83.7 127.56,84.02 128.45,84.02 128.77,83.7 129.39,83.7 129.67,83.42 131.39,83.42 v5(132.11,82.7)
  L10_SIG4 w0.109: v5(132.11,82.7) 132.59,82.22 132.59,80.75 132.11,80.26 132.11,73.1 132.55,72.66 132.55,65.72 132,65.18 132,44.08 131.88,43.95 131.32,43.95 131.19,43.82 131.19,43.64 131.32,43.51 131.88,43.51 132,43.38 132,43.2 131.88,43.07 131.32,43.07 131.19,42.95 131.19,42.76 131.32,42.64 131.88,42.64 132,42.51 132,42.33 131.88,42.2 131.32,42.2 131.19,42.07 131.19,41.89 131.32,41.76 131.88,41.76 132,41.63 132,41.45 131.88,41.33 131.32,41.33 131.19,41.2 131.19,41.02 131.32,40.89 131.88,40.89 132,40.76 132,40.58 131.88,40.45 131.32,40.45 131.19,40.32 131.19,40.14 131.32,40.02 131.88,40.02 132,39.89 132,39.71 131.88,39.58 131.32,39.58 131.19,39.45 131.19,39.27 131.32,39.14 131.88,39.14 132,39.01 132,25.56 125.05,18.6 125.05,17.77 119.02,11.74 105.1,11.74 104.39,11.02 97.25,11.02 96.14,9.91 93.02,9.91 92.44,10.49 64.84,10.49 58.83,16.5 57.8,16.5 52.96,21.34 50.24,21.34 47.87,23.7 40.83,23.7 38.61,25.91 38.61,27.17 32.06,33.73 32.06,34.85 31.04,35.87 31.04,36.65 27.94,39.75 27.94,41.37 26.71,42.6 26.71,48.37 24.6,50.48 24.6,68.07 31.25,74.71 31.25,80.97 31.01,81.21 31.01,84.66 31.25,84.89 v8(31.25,85.97)
PRU2ETH0_TXD2: length 252.7
  TOP w0.173: R168.1 121.79,81.66 v3(122.05,81.91) ; U15.6 v8(30.75,86.95)
  L3_SIG1 w0.109: v3(122.05,81.91) 122.15,81.81 123.34,81.81 123.78,82.25 126.36,82.25 126.82,82.71 128.32,82.71 128.88,82.15 130.66,82.15 130.89,81.92 v5(132.14,81.92)
  L10_SIG4 w0.109: v5(132.14,81.92) 132.14,81.14 131.62,80.62 131.62,72.07 132.06,71.64 132.06,71.27 131.11,70.33 131.11,69.32 131.57,68.86 131.57,62.17 131.44,62.04 131.04,62.04 130.91,61.91 130.91,61.73 131.04,61.6 131.44,61.6 131.57,61.48 131.57,61.3 131.44,61.17 131.04,61.17 130.91,61.04 130.91,60.86 131.04,60.73 131.44,60.73 131.57,60.6 131.57,52.32 130.51,51.26 130.51,37.63 130.38,37.5 129.85,37.5 129.72,37.37 129.72,37.19 129.85,37.06 130.38,37.06 130.51,36.93 130.51,26.7 124.03,20.22 124.03,17.51 122.48,15.95 121.19,15.95 117.31,12.07 106.17,12.07 105.93,12.31 103.12,12.31 102.43,11.62 97.11,11.62 95.73,10.25 93.16,10.25 92.58,10.83 64.97,10.83 58.97,16.84 57.97,16.84 53.09,21.72 50.33,21.72 47.95,24.1 40.9,24.1 39.11,25.9 39.11,27.34 32.39,34.06 32.39,35.22 31.39,36.23 31.39,36.93 28.32,40.01 28.32,41.46 27.05,42.74 27.05,48.6 24.94,50.7 24.94,66.5 32.54,74.1 32.54,76.54 32.03,77.04 32.03,83.93 32.77,84.66 32.77,86.34 32.16,86.95 v8(30.75,86.95)
PRU2ETH0_TXD3: length 251.7
  TOP w0.173: v8(30.23,86.24) 30.25,86.22 U15.7 ; 124.59,85.17 v3(127.86,85.17)
  L3_SIG1 w0.109: v3(127.86,85.17) 128.04,85.35 131.65,85.35 v5(132.94,84.05)
  L10_SIG4 w0.109: v8(30.23,86.24) 28.68,84.69 28.68,75.62 23.03,69.98 23.03,50.96 25.47,48.52 25.47,41.68 26.95,40.2 26.95,35.31 29.08,33.18 31.65,33.18 35.81,29.02 35.81,26.54 36.76,25.6 37.97,25.6 42.87,20.7 46.44,20.7 47.77,19.38 51.27,19.38 55.46,15.19 57.33,15.19 58.22,14.29 58.86,14.29 63.33,9.82 71.78,9.82 72.51,9.09 73.58,9.09 73.73,9.24 104.31,9.24 106.14,11.06 119.52,11.06 134.26,25.8 134.26,77.96 133.45,78.78 133.45,79.94 134.26,80.76 134.26,82.73 v5(132.94,84.05)
PRU2ETH0_TXEN: length 253.7
  TOP w0.173: v3(121.54,83.82) 121.28,83.57 R167.1 ; v8(32.23,86.25) 32.25,86.25 U15.3
  L3_SIG1 w0.109: v3(121.54,83.82) 121.74,84.02 122.4,84.02 123.72,85.35 125.52,85.35 125.65,85.22 126.78,85.22 127.26,84.73 128.3,84.73 128.55,84.99 130.94,84.99 v5(132.23,83.7)
  L10_SIG4 w0.109: v8(32.23,86.25) 31.98,86.49 31.14,86.49 29.39,84.74 29.39,80.7 29.59,80.5 29.59,78.41 29.16,77.97 29.16,75.97 29.18,75.94 29.18,75.46 24.26,70.54 24.26,50.34 26.37,48.23 26.37,41.26 27.53,40.09 27.53,35.59 29.23,33.89 31.42,33.89 38.12,27.19 38.12,25.93 42.36,21.69 46.35,21.69 47.98,20.07 53.72,20.07 57.63,16.16 58.09,16.16 59.31,14.94 59.31,14.56 60.99,12.88 61.97,12.88 64.7,10.16 92.3,10.16 92.88,9.57 96.29,9.57 96.47,9.75 104.35,9.75 106,11.4 119.38,11.4 133.04,25.06 133.04,72.87 132.63,73.28 132.63,79.9 132.99,80.26 132.99,82.94 v5(132.23,83.7)
PRU2ETH1_25MHZCLK: length 61.9
  TOP w0.173: v3(33.91,52.99) 33.91,53.55 32.75,54.71 U17.23
  L3_SIG1 w0.109: v3(33.91,52.99) v5(33.91,52.41)
  L9_SIG3 w0.114: v5(38.48,94.32) 38.73,94.06 38.73,90.88 35.48,87.63 35.48,79.17 33.48,77.16 33.48,67.72 33.02,67.26 33.02,65.91 33.91,65.02 v5(33.91,52.41)
  L10_SIG4 w0.109: v7(50.8,94.32) v5(38.48,94.32)
  BOTTOM w0.173: R357.2 v7(50.8,94.32)
PRU2ETH1_COL: length 330.9
  TOP w0.173: 124.59,74.8 124.63,74.76 v3(125.35,74.76) ; U17.29 35.18,58.12 35.56,57.74 v8(36.07,57.74) 36.83,57.74 37.55,57.02 38.85,57.02 39.58,57.74 40.77,57.74 41.62,58.59 41.62,64.64 35.51,70.74 22.73,70.74 20.4,68.41 7.03,68.41 4.57,65.95 4.57,59.9 v8(7.37,57.1)
  L3_SIG1 w0.109: v3(125.35,74.76) 124.71,74.76 v5(124.59,74.63)
  L4_SIG2 w0.114: v8(36.07,57.74) 36.49,57.74 37.42,56.81 37.42,54.18 32.04,48.81 32.04,39.66 31.37,38.99 31.37,34.96 33.73,32.6 33.73,30.49 27,23.76 27,22.87 24.93,20.8 24.93,11.01 29.32,6.62 49.39,6.62 55.59,12.83 64.07,12.83 64.64,13.4 72.2,13.4 72.61,13 97.13,13 98.45,11.68 103.38,11.68 104.02,12.33 104.73,12.33 105.65,11.41 114.56,11.41 114.98,10.99 129.14,10.99 130.93,12.78 132.13,12.78 133.43,14.08 133.43,14.96 141.07,22.61 145.47,22.61 148.95,26.09 148.95,50.65 149.23,50.93 149.23,51.79 148.95,52.07 148.95,63.27 142.88,69.34 142.88,70.72 136.04,77.56 130.98,77.56 130.06,76.64 126.96,76.64 124.94,74.63 v5(124.59,74.63)
  BOTTOM w0.173: R232.1 v8(36.07,57.74) ; R231.1 v8(7.37,57.1)
PRU2ETH1_CRS: length 3.7
  TOP w0.173: U17.27 34.91,57.12 R219.1
PRU2ETH1_INTN: length 138.6
  TOP w0.173: U17.8 v8(29.75,61.87) ; R672.2 111.51,105.57 112.93,106.99 113.54,106.99 114.77,108.22 114.77,109.67 112.39,112.05 112.39,117.91 v8(108.58,121.72)
  BOTTOM w0.173: v8(29.75,61.87) 35.64,61.87 35.88,61.63 40.97,61.63 47.24,67.9 54.06,67.9 57.4,71.25 57.4,78.2 62.99,83.79 62.99,93.68 65.97,96.66 67.53,96.66 67.77,96.42 70.77,96.42 71.16,96.02 79.66,96.02 96.27,112.63 96.27,113.81 100.21,117.75 100.21,118.72 103.21,121.72 v8(108.58,121.72)
PRU2ETH1_LINKLED: length 26.6
  TOP w0.173: U17.17 29.75,55.31 28.67,54.24 28.67,53.77 R200.1 27.69,53.29 v8(27.3,53.68)
  L4_SIG2 w0.114: v8(27.3,53.68) 24.76,53.68 21.34,57.1 18.89,57.1 17.5,58.49 v8(7.86,58.49)
  BOTTOM w0.173: R218.2 v8(7.86,58.49)
PRU2ETH1_MDC: length 2.4
  TOP w0.173: U17.20 31.25,54.48 30.99,54.22 30.99,53.68 R221.1
PRU2ETH1_MDIO: length 5.2
  TOP w0.173: R201.1 29.03,51.69 29.03,52.73 29.59,53.29 R223.1 29.59,53.45 30.75,54.61 U17.19
PRU2ETH1_RESETN: length 11.6
  TOP w0.173: U17.18 30.25,54.82 v8(29.73,54.3)
  BOTTOM w0.173: U71.4 25.51,50.2 26.47,51.16 27.74,51.16 28.2,50.69 28.8,50.69 29.73,51.62 v8(29.73,54.3)
PRU2ETH1_RXCLK: length 4.6
  TOP w0.173: U17.25 34.26,56.12 35.43,54.95 35.43,54.31 R209.1
PRU2ETH1_RXD0: length 3.7
  TOP w0.173: U17.30 36,58.62 v8(36.1,58.72) 36.13,58.76 R238.2
  BOTTOM w0.173: v8(36.1,58.72) 36.13,58.76 R238.2
PRU2ETH1_RXD1: length 4.1
  TOP w0.173: R237.2 36.01,59.9 v8(35.97,59.87) 35.22,59.12 U17.31
  BOTTOM w0.173: R237.2 36.01,59.9 v8(35.97,59.87)
PRU2ETH1_RXD2: length 4.3
  TOP w0.173: U17.32 34.52,59.62 v8(35.94,61.04) R236.2
  BOTTOM w0.173: v8(35.94,61.04) R236.2
PRU2ETH1_RXD3: length 5.5
  TOP w0.173: U17.1 33.25,61.06 34.37,62.18 v8(36.07,62.18) R235.2
  BOTTOM w0.173: R235.2 v8(36.07,62.18)
PRU2ETH1_RXDV: length 53.4
  TOP w0.173: U17.26 34.65,56.62 35.94,55.33 35.94,54.95 R211.1 37.39,54.61 39.31,54.61 50.41,65.71 50.42,65.71 54.84,70.14 54.84,84.53 53.75,85.63 47.96,85.63 R117.2
PRU2ETH1_RXERR: length 3.4
  TOP w0.173: R212.1 36.07,57.1 35.47,57.1 34.96,57.62 U17.28
PRU2ETH1_TXCLK: length 95.2
  TOP w0.173: U17.2 32.75,61.32 34.42,62.99 v8(34.42,65.41) ; R204.1 v3(77.09,95.97)
  L3_SIG1 w0.109: v3(77.09,95.97) v5(76.45,95.97)
  L10_SIG4 w0.109: v8(34.42,65.41) 35.56,66.55 35.56,67.14 42.53,74.11 53.33,74.11 54.85,75.64 62.89,75.64 64.16,76.91 64.16,77.87 64.29,78 65.05,78 65.18,78.12 65.18,78.3 65.05,78.43 64.29,78.43 64.16,78.56 64.16,78.74 64.29,78.87 65.05,78.87 65.18,79 65.18,79.18 65.05,79.31 64.29,79.31 64.16,79.43 64.16,79.62 64.29,79.74 65.05,79.74 65.18,79.87 65.18,80.05 65.05,80.18 64.29,80.18 64.16,80.31 64.16,80.98 64.6,81.42 64.6,81.6 64.19,82.01 64.19,82.19 64.31,82.32 64.49,82.32 64.91,81.91 65.09,81.91 65.22,82.04 65.22,82.22 64.8,82.63 64.8,82.81 64.93,82.94 65.11,82.94 65.53,82.53 65.71,82.53 65.84,82.65 65.84,82.83 65.42,83.25 65.42,83.43 65.55,83.56 65.73,83.56 66.15,83.14 66.33,83.14 66.45,83.27 66.45,83.45 66.04,83.87 66.04,84.05 66.17,84.18 66.35,84.18 66.76,83.76 66.94,83.76 69.02,85.84 69.02,86 68.01,87.01 68.01,87.17 68.16,87.32 68.32,87.32 69.33,86.31 69.49,86.31 69.64,86.46 69.64,86.62 68.68,87.58 68.68,87.73 68.83,87.89 68.99,87.89 69.95,86.92 70.11,86.92 70.26,87.08 70.26,87.23 69.32,88.17 69.32,88.33 69.46,88.47 69.64,88.47 70.39,87.72 70.55,87.72 70.68,87.85 70.68,88.05 69.95,88.78 69.95,88.93 70.1,89.07 70.28,89.07 71.13,88.22 71.28,88.22 71.42,88.37 71.42,88.55 70.55,89.42 70.55,89.58 70.69,89.72 70.87,89.72 71.81,88.78 71.96,88.78 72.12,88.93 72.12,89.09 71.27,89.94 71.27,90.09 71.41,90.23 71.59,90.23 72.43,89.4 72.58,89.4 73.13,89.94 73.13,90.14 72.47,90.8 72.47,91 72.61,91.14 72.81,91.14 73.08,90.86 73.28,90.86 73.42,91 73.42,91.2 73.25,91.37 73.25,91.57 73.66,91.98 73.66,94.18 74.37,94.89 75.38,94.89 v5(76.45,95.97)
PRU2ETH1_TXD0: length 93.5
  TOP w0.173: U17.4 31.75,61.72 33.27,63.25 v8(33.27,64.9) ; R206.1 v3(77.09,94.95)
  L3_SIG1 w0.109: v3(77.09,94.95) v5(76.45,94.95)
  L10_SIG4 w0.109: v8(33.27,64.9) 34.67,64.9 36.08,66.31 36.08,66.75 42.89,73.56 54.35,73.56 55.4,74.6 63.83,74.6 63.96,74.73 63.96,75.41 64.08,75.54 64.26,75.54 64.39,75.41 64.39,74.73 64.52,74.6 64.7,74.6 64.83,74.73 64.83,75.41 64.96,75.54 65.14,75.54 65.27,75.41 65.27,74.73 65.39,74.6 65.57,74.6 65.7,74.73 65.7,75.41 65.83,75.54 66.01,75.54 66.14,75.41 66.14,74.73 66.27,74.6 66.62,74.6 67.7,75.68 67.7,79.32 67.84,79.46 70.67,79.46 70.81,79.6 70.81,79.8 70.67,79.94 67.84,79.94 67.7,80.08 67.7,80.28 67.84,80.42 70.67,80.42 70.81,80.56 70.81,80.76 70.67,80.9 67.84,80.9 67.7,81.04 67.7,81.24 67.84,81.38 70.67,81.38 70.81,81.52 70.81,81.72 70.67,81.86 67.84,81.86 67.7,82 67.7,82.2 67.84,82.34 69.23,82.34 69.55,82.67 69.55,83.17 70.81,84.43 70.81,86.82 74.04,90.04 74.04,91.82 74.15,91.93 74.69,91.93 74.8,92.04 74.8,92.25 74.69,92.36 74.15,92.36 74.04,92.47 74.04,93.09 74.93,93.98 75.48,93.98 v5(76.45,94.95)
PRU2ETH1_TXD1: length 97.5
  TOP w0.173: R208.1 v3(77.09,92.92) ; v8(32.64,63.37) 31.25,61.98 U17.5
  L3_SIG1 w0.109: v3(77.09,92.92) v5(76.45,92.92)
  L10_SIG4 w0.109: v5(76.45,92.92) 76.45,90.78 74.16,88.49 74.16,76.32 73.15,75.31 73.15,74.25 68.96,70.05 58.09,70.05 55.54,72.6 50.34,72.6 50.2,72.46 50.2,71.71 50.06,71.57 49.86,71.57 49.72,71.71 49.72,72.46 49.58,72.6 49.38,72.6 49.24,72.46 49.24,71.71 49.1,71.57 48.9,71.57 48.76,71.71 48.76,72.46 48.62,72.6 48.42,72.6 48.28,72.46 48.28,71.71 48.14,71.57 47.94,71.57 47.8,71.71 47.8,72.46 47.66,72.6 47.46,72.6 47.32,72.46 47.32,71.71 47.18,71.57 46.98,71.57 46.84,71.71 46.84,72.46 46.7,72.6 46.5,72.6 46.36,72.46 46.36,71.71 46.22,71.57 46.02,71.57 45.88,71.71 45.88,72.46 45.74,72.6 45.54,72.6 45.4,72.46 45.4,71.71 45.26,71.57 45.06,71.57 44.92,71.71 44.92,72.46 44.78,72.6 44.58,72.6 44.44,72.46 44.44,71.71 44.3,71.57 44.1,71.57 43.96,71.71 43.96,72.46 43.82,72.6 43.64,72.6 39.44,68.4 39.44,68.22 40.04,67.62 40.04,67.44 39.91,67.32 39.73,67.32 39.13,67.91 38.95,67.91 38.82,67.78 38.82,67.6 39.42,67.01 39.42,66.83 39.29,66.7 39.11,66.7 38.51,67.29 38.33,67.29 38.2,67.17 38.2,66.98 38.8,66.39 38.8,66.21 38.67,66.08 38.49,66.08 37.9,66.68 37.71,66.68 37.59,66.55 37.59,66.37 38.18,65.77 38.18,65.59 38.05,65.46 37.87,65.46 37.28,66.06 37.1,66.06 36.97,65.93 36.97,65.75 37.56,65.15 37.56,64.97 37.44,64.84 37.26,64.84 36.66,65.44 36.48,65.44 36.35,65.31 36.35,65.13 36.95,64.53 36.95,64.35 36.82,64.22 36.64,64.22 36.04,64.82 35.86,64.82 35.73,64.69 35.73,64.51 36.33,63.92 36.33,63.73 36.2,63.61 36.02,63.61 35.42,64.2 35.24,64.2 34.41,63.37 v8(32.64,63.37)
PRU2ETH1_TXD2: length 94.4
  TOP w0.173: R210.1 v3(77.09,96.98) ; U17.6 30.75,62.37 32.51,64.14 32.51,65.41 v8(33.53,66.42)
  L3_SIG1 w0.109: v3(77.09,96.98) v5(76.45,96.98)
  L10_SIG4 w0.109: v8(33.53,66.42) 34.54,66.42 35.18,67.06 35.18,67.36 42.32,74.5 52.83,74.5 55.37,77.04 55.37,78.82 56.08,79.53 56.08,79.71 55.39,80.41 55.39,80.59 55.52,80.71 55.7,80.71 56.39,80.02 56.57,80.02 56.7,80.15 56.7,80.33 56.01,81.02 56.01,81.2 56.14,81.33 56.32,81.33 57.01,80.64 57.19,80.64 57.32,80.77 57.32,80.95 56.63,81.64 56.63,81.82 56.75,81.95 56.94,81.95 57.63,81.26 57.81,81.26 57.94,81.39 57.94,81.57 57.24,82.26 57.24,82.44 57.37,82.57 57.55,82.57 58.25,81.88 58.43,81.88 58.55,82.01 58.55,82.19 57.86,82.88 57.86,83.06 57.99,83.19 58.17,83.19 58.86,82.5 59.04,82.5 59.17,82.62 59.17,82.8 58.48,83.5 58.48,83.68 58.61,83.81 58.79,83.81 59.48,83.11 59.66,83.11 59.79,83.24 59.79,83.42 59.1,84.11 59.1,84.3 59.23,84.42 59.41,84.42 60.1,83.73 60.28,83.73 60.41,83.86 60.41,84.04 59.72,84.73 59.72,84.91 59.85,85.04 60.03,85.04 60.72,84.35 60.9,84.35 61.03,84.48 61.03,84.66 60.34,85.35 60.34,85.53 60.46,85.66 60.64,85.66 61.34,84.97 61.52,84.97 61.65,85.1 61.65,85.28 60.95,85.97 60.95,86.15 61.08,86.28 61.26,86.28 61.95,85.59 62.14,85.59 62.26,85.72 62.26,85.9 61.57,86.59 61.57,86.77 61.7,86.9 61.88,86.9 62.57,86.21 62.75,86.21 62.88,86.33 62.88,86.51 62.19,87.21 62.19,87.39 62.32,87.52 62.5,87.52 63.19,86.82 63.37,86.82 63.5,86.95 63.5,87.13 62.81,87.82 62.81,88.01 62.94,88.13 63.12,88.13 63.81,87.44 63.99,87.44 67.73,91.19 69.44,91.19 70.87,92.61 70.87,93.88 72.97,95.99 74.8,95.99 74.82,96 74.94,96 75.92,96.98 v5(76.45,96.98)
PRU2ETH1_TXD3: length 96.7
  TOP w0.173: v8(31.5,64.26) 30.25,63.01 U17.7 ; R207.1 v3(77.09,93.93)
  L3_SIG1 w0.109: v3(77.09,93.93) v5(76.45,93.93)
  L10_SIG4 w0.109: v5(76.45,93.93) 75.9,93.38 75.9,91.21 72.86,88.18 72.86,87.23 72.75,87.12 72.07,87.12 71.86,86.91 71.86,85.15 72.07,84.93 73.22,84.93 73.33,84.83 73.33,84.61 73.22,84.5 72.07,84.5 71.96,84.39 71.96,84.17 72.07,84.06 73.22,84.06 73.33,83.95 73.33,83.73 73.22,83.62 72.07,83.62 71.96,83.51 71.96,83.3 72.07,83.19 73.4,83.19 73.51,83.08 73.51,82.86 73.4,82.75 72.07,82.75 71.96,82.64 71.96,82.42 72.07,82.31 73.4,82.31 73.51,82.2 73.51,81.99 73.4,81.88 72.07,81.88 71.96,81.77 71.96,81.55 72.07,81.44 73.4,81.44 73.51,81.33 73.51,81.11 73.4,81 72.07,81 71.96,80.89 71.96,80.67 72.07,80.57 73.4,80.57 73.51,80.46 73.51,80.24 73.4,80.13 72.07,80.13 71.96,80.02 71.96,79.8 72.07,79.69 73.4,79.69 73.51,79.58 73.51,79.36 73.4,79.25 72.07,79.25 71.96,79.15 71.96,78.93 72.07,78.82 73.4,78.82 73.51,78.71 73.51,78.49 73.4,78.38 72.07,78.38 71.96,78.27 71.96,73.62 69.08,70.74 61.72,70.74 59.51,72.95 43.51,72.95 34.82,64.26 v8(31.5,64.26)
PRU2ETH1_TXEN: length 93.7
  TOP w0.173: v8(43.43,84.55) R115.2 ; v8(34.5,67.23) 34.5,66.5 33.78,65.79 33.78,63.12 32.25,61.58 U17.3 ; R205.1 v3(77.09,98)
  L3_SIG1 w0.109: v3(77.09,98) v5(76.45,98)
  L10_SIG4 w0.109: v8(34.5,67.23) 42.15,74.88 46.51,74.88 47.19,75.57 47.19,80.8 v8(43.43,84.55) 44.58,85.7 54.89,85.7 57.96,88.77 62.05,88.77 62.48,89.2 62.48,89.38 61.74,90.11 61.74,90.29 61.87,90.42 62.05,90.42 62.79,89.69 62.97,89.69 63.09,89.82 63.09,90 62.36,90.73 62.36,90.91 62.49,91.04 62.67,91.04 63.4,90.31 63.58,90.31 63.71,90.43 63.71,90.61 62.98,91.35 62.98,91.53 63.11,91.66 63.29,91.66 64.02,90.92 64.2,90.92 64.33,91.05 64.33,91.23 63.6,91.97 63.6,92.15 63.73,92.28 63.91,92.28 64.64,91.54 64.82,91.54 64.95,91.67 64.95,91.85 64.22,92.58 64.22,92.77 64.34,92.89 64.53,92.89 65.26,92.16 65.44,92.16 65.57,92.29 65.57,92.47 64.83,93.2 64.83,93.38 64.96,93.51 65.14,93.51 65.88,92.78 66.06,92.78 66.19,92.91 66.19,93.09 65.45,93.82 65.45,94 65.58,94.13 65.76,94.13 66.5,93.4 66.68,93.4 66.8,93.52 66.8,93.71 66.07,94.44 66.07,94.62 66.2,94.75 66.38,94.75 67.11,94.01 67.29,94.01 69.62,96.34 74.8,96.34 v5(76.45,98)
PRU2ETHER0_RDN: length 23.6
  TOP w0.108: J6.2 19.64,85.68 15.77,85.68 15.37,86.08 15.37,87.94 16.15,88.73 21.77,88.73 22.28,88.22 24,88.22 R182.2 24.77,88.22 26.05,88.22 26.8,87.47 26.8,85.73 28.27,84.26 28.55,84.26 28.67,84.38 U15.9
PRU2ETHER0_RDP: length 23.6
  TOP w0.108: U15.10 28.67,83.88 28.55,84 28.17,84 26.54,85.63 26.54,87.36 25.94,87.97 24.78,87.97 24.4,87.58 R183.2 24,87.97 22.17,87.97 21.67,88.47 16.26,88.47 15.62,87.84 15.62,86.19 15.88,85.93 18.2,85.93 18.44,86.17 18.44,86.82 18.27,87 J6.1
PRU2ETHER0_TDN: length 21.7
  TOP w0.108: J6.6 19.52,80.47 16.15,80.47 15.24,81.38 15.24,82.48 16.02,83.26 17.71,83.26 18.39,83.94 18.39,83.94 19.09,84.64 21.03,84.64 21.59,84.08 23.93,84.08 R184.2 24.83,84.09 27.06,84.09 27.89,83.27 28.55,83.27 28.66,83.38 U15.11
PRU2ETHER0_TDP: length 21.7
  TOP w0.108: U15.12 28.68,82.88 28.55,83.01 27.78,83.01 26.96,83.84 24.83,83.84 R185.2 23.95,83.82 21.48,83.82 20.93,84.38 19.19,84.38 18.49,83.68 17.81,83 16.12,83 15.49,82.38 15.49,81.49 16.26,80.73 18.39,80.73 18.54,80.88 18.54,81.16 18.39,81.31 17.76,81.31 J6.5
PRU2ETHER1_RDN: length 27.3
  TOP w0.108: J8.6 19.64,55.83 16.48,55.83 15.52,56.8 15.52,63 16.35,63.84 20.6,63.84 21.01,63.43 23.98,63.43 R224.2 24.77,63.45 25.15,63.45 26.44,62.16 26.44,61.32 28.27,59.49 28.55,59.49 28.67,59.62 U17.9
PRU2ETHER1_RDP: length 27.3
  TOP w0.108: U17.10 28.67,59.12 28.55,59.24 28.17,59.24 26.19,61.22 26.19,62.05 25.04,63.2 24.78,63.2 24.4,62.82 R225.2 24.03,63.17 20.9,63.17 20.5,63.58 16.46,63.58 15.77,62.9 15.77,56.9 16.59,56.09 18.29,56.09 18.41,56.22 18.41,56.9 18.16,57.15 J8.5
PRU2ETHER1_TDN: length 26.9
  TOP w0.108: U17.11 28.66,58.62 28.55,58.5 27.89,58.5 27.28,59.11 25.5,59.11 25.29,59.33 24.83,59.33 R226.2 23.93,59.31 23.42,59.31 22.89,59.85 22.25,59.85 21.89,59.49 21.89,53.45 21.74,53.29 21.44,53.29 21.23,53.5 21.23,59.49 20.83,59.9 19.05,59.9 18.62,60.33 18.62,61.68 18.72,61.78 18.87,61.78 J8.2
PRU2ETHER1_TDP: length 27.3
  TOP w0.108: J8.1 17.38,62.01 18.06,62.01 18.36,61.7 18.36,60.22 18.94,59.64 20.72,59.64 20.98,59.39 20.98,53.39 21.33,53.04 21.85,53.04 22.15,53.34 22.15,59.39 22.36,59.59 22.76,59.59 23.27,59.09 23.29,59.09 23.31,59.06 23.95,59.06 R227.2 24.83,59.07 25.18,59.07 25.4,58.86 27.17,58.86 27.78,58.25 28.55,58.25 28.68,58.12 U17.12
QSPI_CLK: length 15.3
  TOP w0.173: R31.2 R23.1 101.3,112.43 101.3,111.15 99.95,109.8 99.95,105.57 100.48,105.03 100.48,102.34 101.98,100.84 R24.1
RS485_A: length 32.6
  TOP w0.108: 161.37,11.43 161.93,10.88 161.93,10.24 162.56,9.61 162.56,8.56 162.08,8.08 161.93,8.08 R729.2 161.08,8 158.86,8 158.75,8.11 J39.1 ; 161.37,11.43 161.75,11.43 161.86,11.54 161.86,12.53 163,13.67 171.91,13.67 v8(172.09,13.85) ; 161.37,11.43 U82.1
  BOTTOM w0.108: U77.6 177.8,7.19 177.29,7.7 177.29,8.06 176.25,9.1 174.48,9.1 173.36,10.22 173.36,13.29 172.97,13.67 172.26,13.67 v8(172.09,13.85)
RS485_B: length 32.1
  TOP w0.108: J39.2 158.75,7.64 158.86,7.75 161.24,7.75 R729.1 161.93,7.83 162.18,7.83 162.81,8.46 162.81,9.71 162.18,10.35 162.18,10.91 U83.1 162.22,11.43 162.12,11.54 162.12,12.42 163.11,13.42 171.91,13.42 v8(172.09,13.24)
  BOTTOM w0.108: v8(172.09,13.24) 172.26,13.42 172.87,13.42 173.1,13.18 173.1,10.11 174.37,8.84 176.15,8.84 177.04,7.96 177.04,7.7 176.53,7.19 U77.7
RSTOUTTOPMIC: length 95
  TOP w0.173: U3.E6 v8(139.04,127.14) ; R36.1 R793.2 127.76,43.9 v8(128.52,44.66)
  L4_SIG2 w0.114: v8(138.13,110.36) 137.5,110.99 137.5,112.81 137.03,113.28 137.03,119.04 137.5,119.51 137.5,126.65 138,127.14 v8(139.04,127.14)
  BOTTOM w0.173: v8(128.52,44.66) 128.52,45.93 127.13,47.33 127.13,78.41 130.91,82.2 130.91,100.05 138.13,107.26 v8(138.13,110.36)
RT2_MII0_EDIO_DATA0: length 3.6
  TOP w0.173: R198.1 48.39,70.36
RT2_MII0_EDIO_DATA1: length 3.6
  TOP w0.173: R199.1 50.93,70.36
RT2_MII0_RXDV: length 3.6
  TOP w0.173: R197.1 45.85,70.36
RT2_MII0_TXEN: length 3.6
  TOP w0.173: R196.1 J7.1
RT2_MII1_EDIO_DATA0: length 4.3
  TOP w0.173: R118.1 J4.3
RT2_MII1_EDIO_DATA1: length 4.3
  TOP w0.173: R119.1 J4.4
RT2_MII1_RXDV: length 4.3
  TOP w0.173: R117.1 J4.2
RT2_MII1_TXEN: length 4.3
  TOP w0.173: R115.1 J4.1
RTCK: length 70.9
  TOP w0.173: J18.9 182.88,88.77 181.99,87.88 181.99,86.49 v8(182.12,86.36) ; 124.59,73.74 v3(125.35,73.74)
  L3_SIG1 w0.109: v3(125.35,73.74) 126.85,73.74 128.04,74.93 144.62,74.93 146.81,77.12 146.81,78.34 149.83,81.36 152.4,81.36 153.14,80.62 155.42,80.62 159.16,84.36 160.68,84.36 161.87,83.16 165.25,83.16 167.11,85.02 169.57,85.02 170.69,83.9 179.66,83.9 v8(182.12,86.36)
SERDES_REF_CLKN: length 35.9
  TOP w0.108: v8(59.31,54.6) 59.12,54.41 58.78,54.41 58.45,54.74 58.45,55.46 58.57,55.59 58.85,55.59 58.98,55.71 58.98,55.89 58.85,56.02 58.57,56.02 58.45,56.15 58.45,56.56 59.41,57.53 61.62,57.53 65.71,61.62 65.71,64.11 72.69,71.1 72.69,76.48 73.26,77.04 73.79,77.04 C438.1
  BOTTOM w0.108: v8(59.31,54.6) 59.13,54.42 56.68,54.42 56.56,54.54 U45.2
SERDES_REF_CLKP: length 35.9
  TOP w0.108: v8(59.31,53.99) 59.15,54.15 58.67,54.15 58.19,54.64 58.19,56.67 59.31,57.78 61.51,57.78 65.46,61.73 65.46,64.22 72.44,71.2 72.44,76.59 73.15,77.3 73.79,77.3 C439.1
  BOTTOM w0.108: U45.3 56.54,54.04 56.66,54.17 59.13,54.17 v8(59.31,53.99)
SPIMEM_CLK: length 18.2
  TOP w0.173: U4.16 99.95,113.77 100.15,113.97 100.81,113.97 101.02,114.18 101.02,114.46 100.81,114.66 100.15,114.66 99.95,114.87 99.95,115.15 100.15,115.35 100.89,115.35 101.09,115.56 101.09,115.84 100.89,116.05 100.15,116.05 99.95,116.25 99.95,118.22 100.46,118.72 101.4,118.72 101.88,118.24 101.88,117.62 102.08,117.42 103.23,117.42 103.43,117.22 103.43,116.93 103.23,116.73 102.08,116.73 101.88,116.53 101.88,115.04 R31.1
SPIMEM_CSN: length 2.5
  TOP w0.173: R30.1 92.33,121.11
SPIMEM_D0: length 25.6
  TOP w0.173: R25.1 97.83,109.3 97.62,109.1 97.62,107.79 97.42,107.59 97.14,107.59 96.93,107.8 96.93,109.66 96.74,109.85 96.56,109.85 96.39,109.69 96.39,107.87 96.19,107.67 95.9,107.67 95.7,107.87 95.7,109.59 95.49,109.79 95.21,109.79 95.01,109.6 95.01,108.11 94.78,107.88 94.2,107.88 93.98,108.11 93.98,108.42 93.77,108.63 93.49,108.63 93.29,108.42 93.29,108.06 93.08,107.85 92.78,107.85 92.53,108.1 92.53,109.07 92.74,109.27 93.89,109.27 94.09,109.47 94.09,110.09 94.26,110.26 98.44,110.26 98.68,110.5 U4.15
SPIMEM_D1: length 2.5
  TOP w0.173: R26.1 U4.8
SPIMEM_D2: length 23.2
  TOP w0.173: U4.9 91.06,117.56 90.6,118.01 89.86,118.01 89.51,117.66 89.51,115.67 89.31,115.47 88.86,115.47 88.66,115.27 88.66,114.98 88.86,114.78 89.31,114.78 89.51,114.58 89.51,114.29 89.31,114.09 88.86,114.09 88.66,113.89 88.66,113.6 88.86,113.4 89.31,113.4 89.51,113.2 89.51,110.65 89.31,110.45 87.97,110.45 87.74,110.22 87.74,109.57 88.01,109.3 R22.1 R27.1
SPIMEM_D3: length 3.7
  TOP w0.173: U4.1 99.95,123.27 R799.1 R28.1
SRCCLK: length 59.2
  L10_SIG4 w0.109: v7(147.57,95.38) 145.03,97.92 145.03,100.97 v7(145.8,101.73)
  BOTTOM w0.173: R586.2 147.07,95.89 v7(147.57,95.38) ; R276.1 162.56,144.02 160.4,141.86 160.4,125.22 146.49,111.32 146.49,106.87 147.07,106.3 147.07,103.5 145.79,102.23 145.79,101.74 v7(145.8,101.73)
SYS_RESETN: length 291.9
  TOP w0.173: v8(101.09,125.56) 100.54,126.11 99.97,126.11 99.57,125.71 98.45,125.71 R29.2
  L3_SIG1 w0.109: J21.25 122.3,143.98 v8(122.3,142.6)
  L9_SIG3 w0.114: v8(180.09,11.56) 180.09,19.51 182.65,22.07 182.65,64.05 182.63,64.07 182.63,78.82 187.33,83.53 187.33,84.83 186.94,85.22 186.94,85.98 187.33,86.37 187.33,92.32 177.97,101.68 160.32,101.68 v8(159.51,102.49) 158.75,102.49 157.61,103.63 157.61,109.09 152.65,114.05 152.65,120.02 153.29,120.65 153.29,121.79 155.32,123.83 155.32,124.59 156.2,125.47 156.2,127.5 157.1,128.4 157.1,132.84 148.03,141.91 145.36,141.91 143.13,144.15 123.85,144.15 v8(122.3,142.6)
  BOTTOM w0.173: v8(122.3,142.6) 123.49,141.4 123.49,138.99 120.85,136.35 120.85,131.7 120.22,131.06 114.05,131.06 111.76,133.35 108.71,133.35 107.87,132.51 105.79,132.51 105.41,132.13 105.41,128.65 102.32,125.56 v8(101.09,125.56) ; R566.2 160.53,101.47 v8(159.51,102.49) ; v8(180.09,11.56) 180.09,16.26 175.06,21.29 175.06,25.18 173.57,26.67 163.83,26.67 156.34,34.16 156.34,43.18 157.1,43.94 157.1,44.96
SYS_WARMRESETN: length 198
  TOP w0.173: v8(152.15,76.83) 149.45,76.83 140.69,68.07 140.69,61.34 139.8,60.45 134.24,60.45 130.62,64.07 128.07,64.07 127.38,64.76 R2.1 126.62,64.85 125.98,65.49 124.59,65.49 ; v8(127.38,45.58) 127,45.58 U47.4
  L3_SIG1 w0.109: v5(162.31,100.92) 181.02,100.92 v8(185.55,96.39)
  L10_SIG4 w0.109: v5(162.31,100.92) 163.58,99.65 163.58,88.67 163.23,88.33 163.23,85.89 162.56,85.22 162.56,81.51 161.52,80.47 159.51,80.47 159.08,80.04 159.08,78.99 156.92,76.83 v8(152.15,76.83)
  BOTTOM w0.173: v8(185.55,96.39) 185.8,96.39 186.45,95.75 U78.4 ; R915.1 158.62,44.96 159.51,44.07 159.51,43.31 158.24,42.04 R913.1 ; R915.1 R917.1 159,46.74 161.67,49.4 C576.1 161.81,49.39 U97.4 163.26,48.83 163.7,48.39 171.58,48.39 172.72,49.53 172.72,55.24 171.32,56.64 164.34,56.64 161.82,59.16 161.82,66.83 155.96,72.7 R473.1 152.65,76.83 v8(152.15,76.83) ; R915.1 157.35,45.72 156.34,45.72 154.43,43.81 128.22,43.81 127.38,44.66 v8(127.38,45.58)
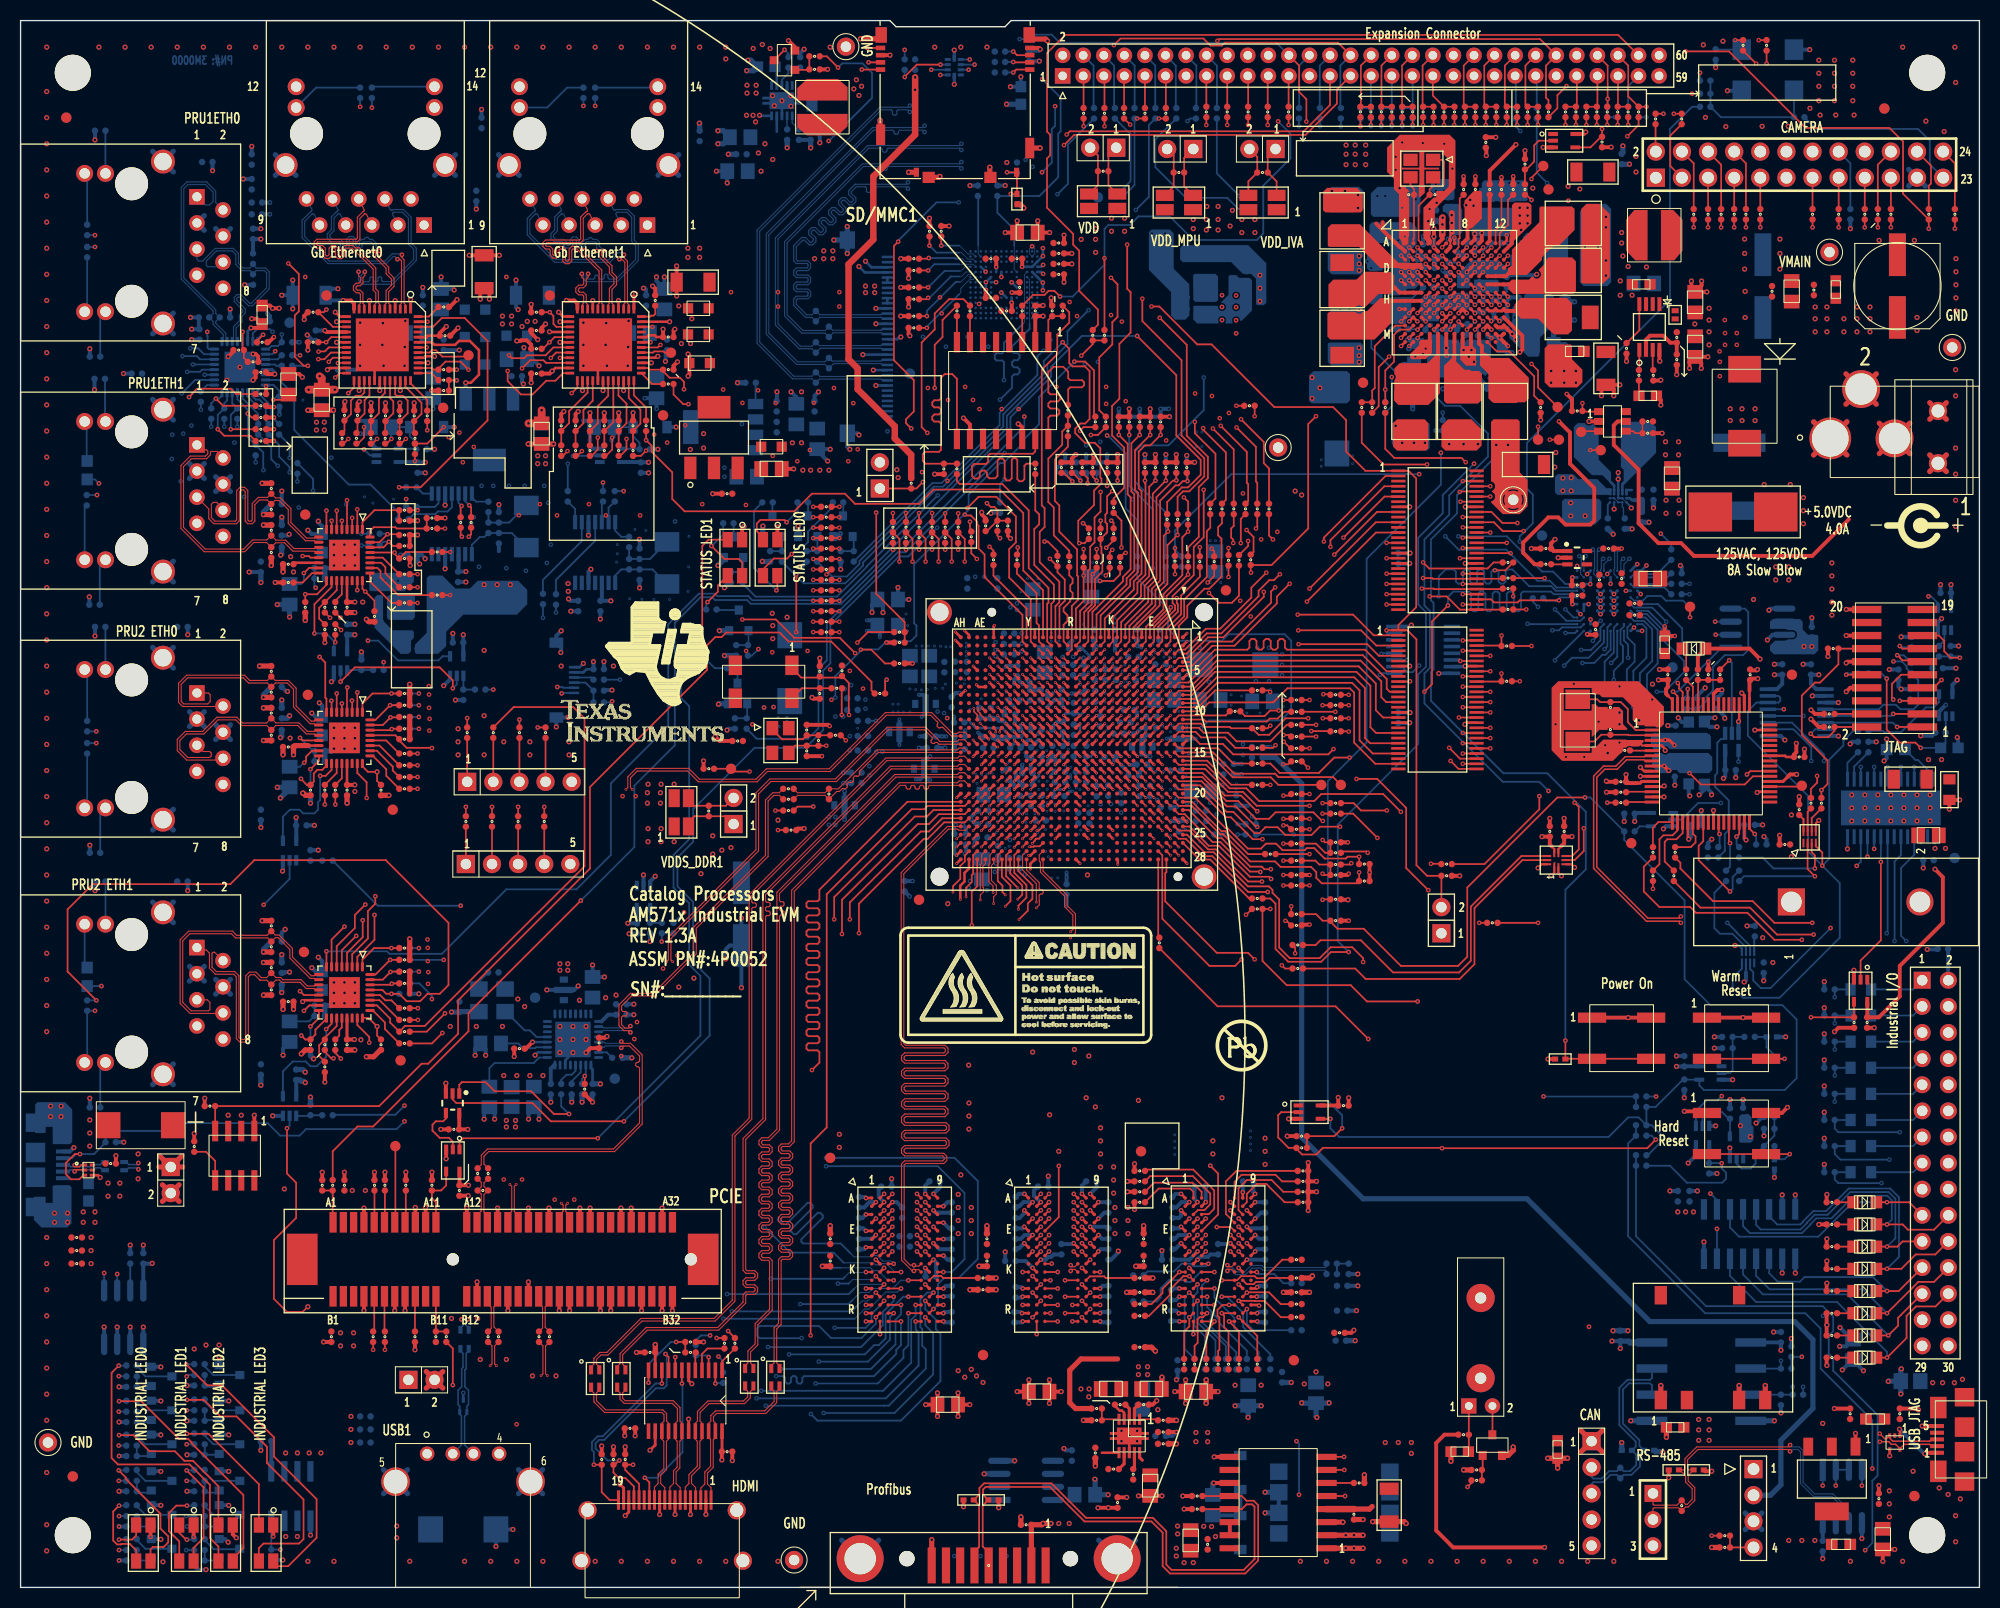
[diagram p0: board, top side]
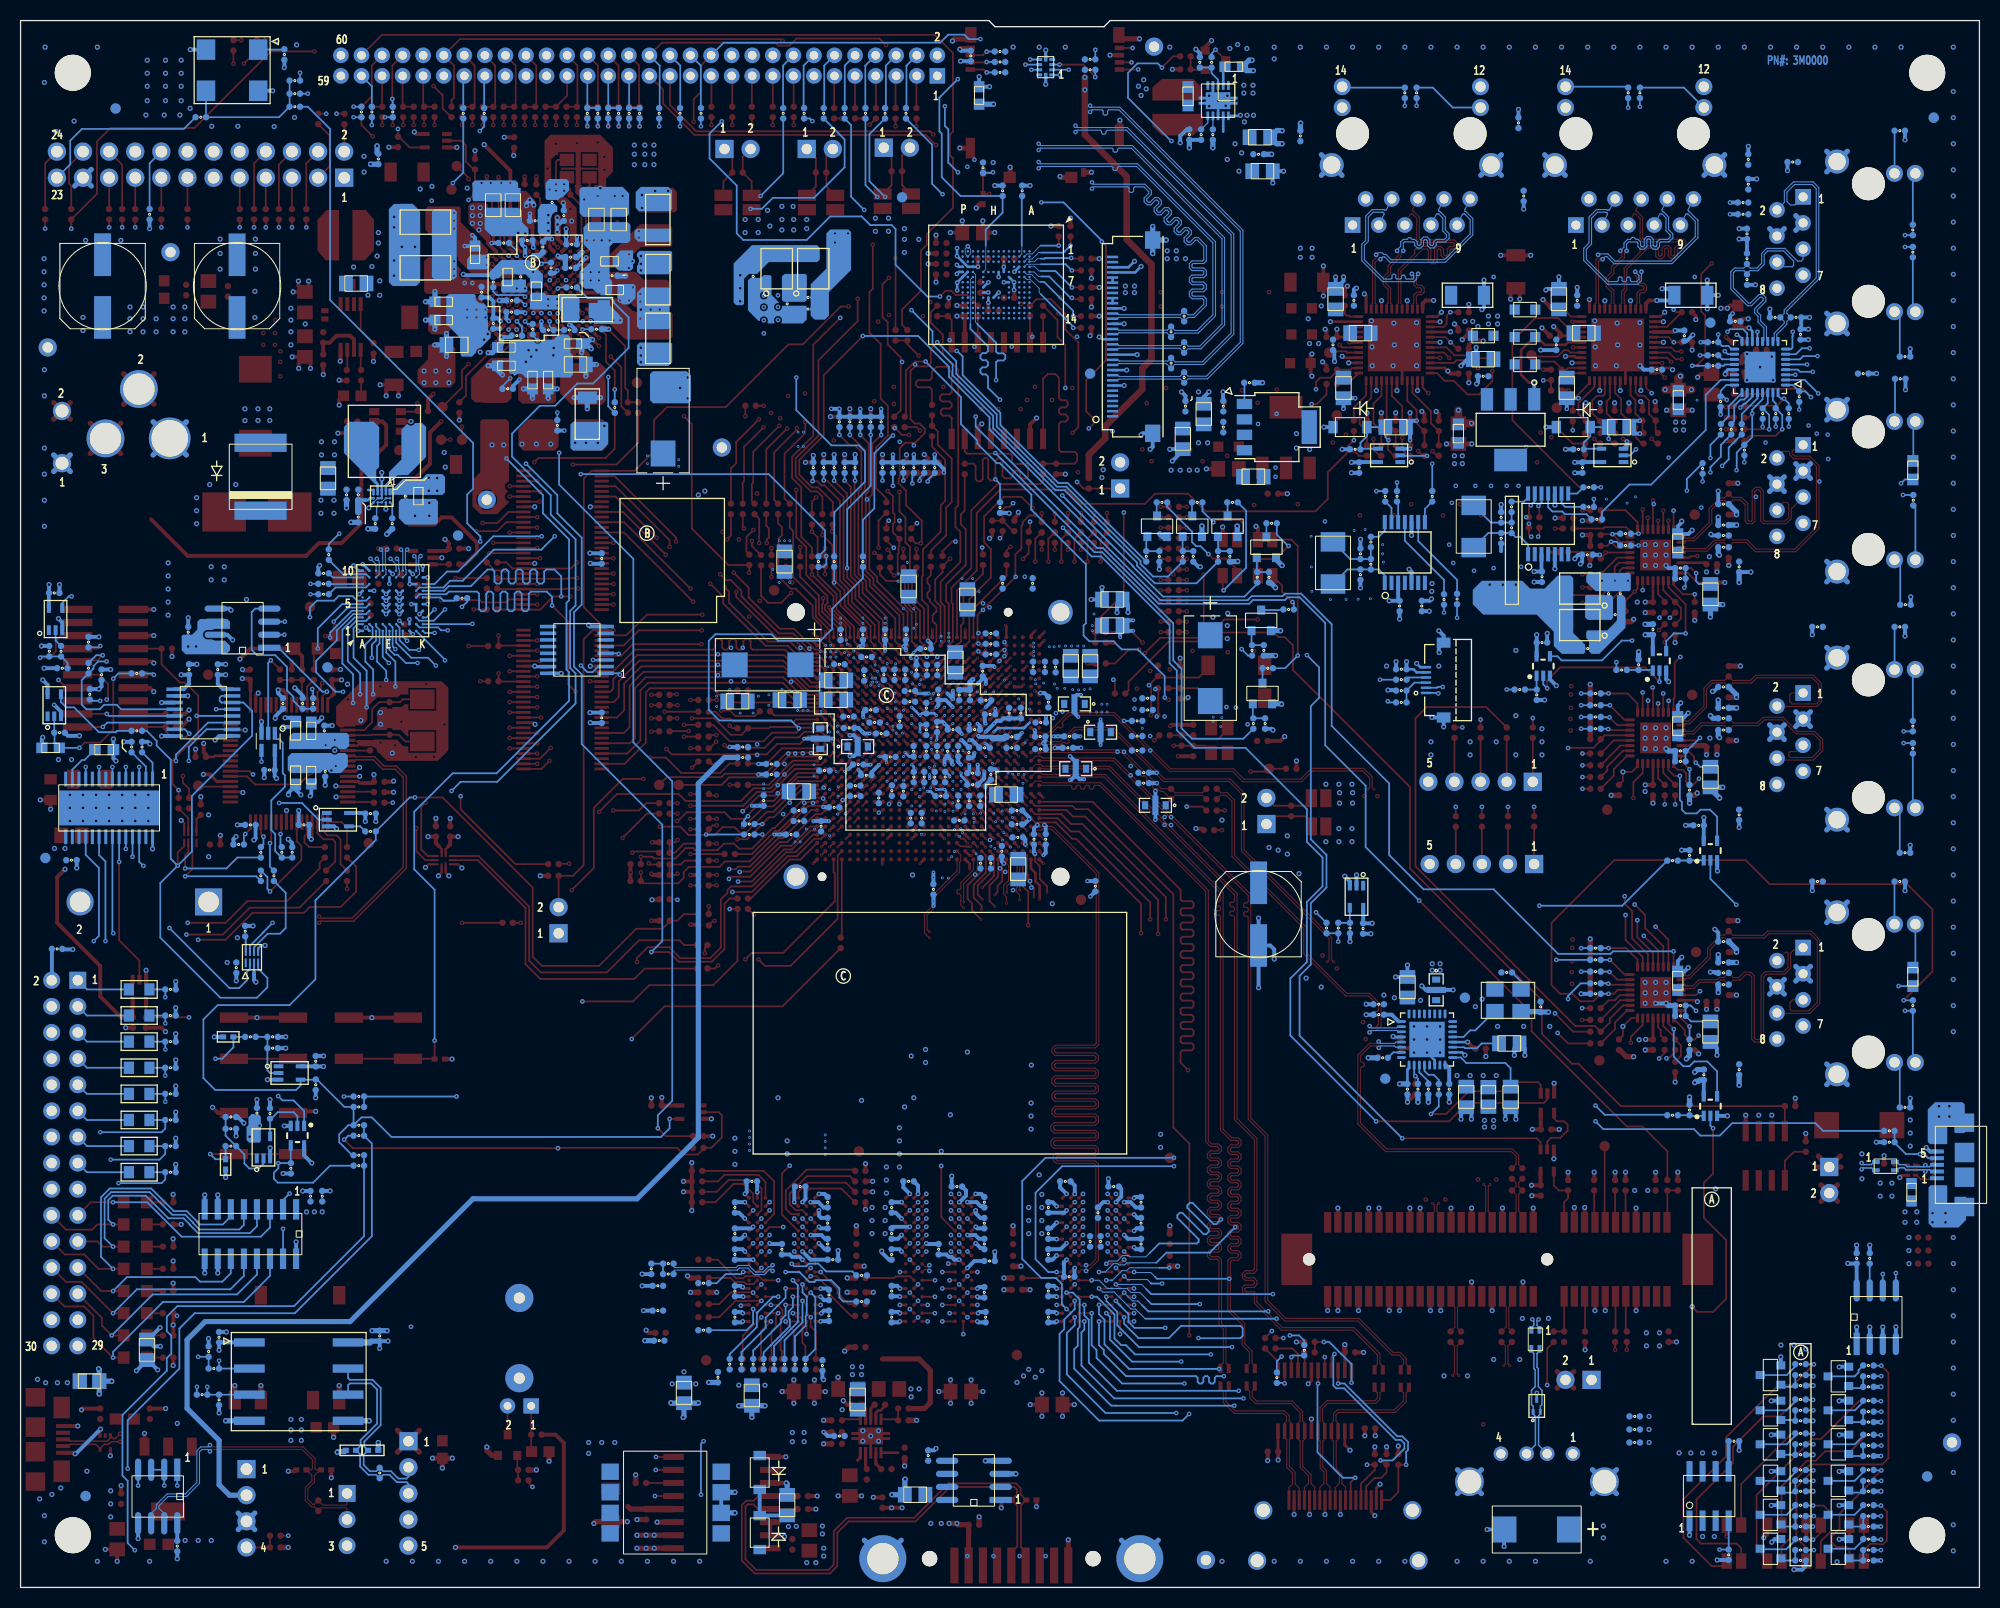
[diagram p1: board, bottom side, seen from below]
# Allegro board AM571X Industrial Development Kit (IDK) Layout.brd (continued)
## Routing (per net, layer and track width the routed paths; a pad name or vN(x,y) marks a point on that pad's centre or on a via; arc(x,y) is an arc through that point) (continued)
TCK: length 4.4
  TOP w0.173: v8(182.51,90.67) 182.58,90.67 182.75,90.5 182.75,90.42 183.01,90.17 184.82,90.17 J18.11
  BOTTOM w0.173: v8(182.51,90.67) 183.14,90.67 183.39,90.42 R3.1
TOUCH_INT: length 365.1
  TOP w0.173: R673.1 v3(129.16,85.81)
  L3_SIG1 w0.109: v5(25.02,27.43) 23.24,29.21 20.08,29.21 10.48,38.81 10.48,42.21 14.59,46.32 17.77,46.32 22.8,51.34 22.8,67.99 27.93,73.12 31.37,73.12 34.86,76.61 34.86,77.1 37.26,79.5 39.17,79.5 41.56,81.9 41.56,84.22 43.3,85.96 45.82,85.96 46.88,87.02 v5(49.68,87.02) ; v3(129.16,85.81) 129.62,86.26 v5(130.68,86.26)
  L4_SIG2 w0.114: v5(49.68,87.02) 50.55,86.15 54.4,86.15 56.04,87.79 58.13,87.79 v5(58.29,87.63) ; v5(130.68,86.26) 131.59,86.26 135.31,82.55 140.08,82.55 140.59,83.06 144.59,83.06 147.83,79.82 147.83,78.23 146.77,77.17 146.77,76.03 158.5,64.3 158.5,20.29 154.79,16.59 154.79,14.17 153.52,12.9 152.23,12.9 152.22,12.9 151.89,12.9 142.29,3.3 134.11,3.3 132.71,1.9 112.15,1.9 108.44,5.61 103.37,5.61 101.48,7.49 96.42,7.49 95.58,6.65 75.03,6.65 72.3,3.93 54,3.93 53.14,3.07 49.94,3.07 48.51,1.65 29.74,1.65 28.32,3.07 26.9,3.07 21.72,8.25 21.72,24.13 v5(25.02,27.43)
  L10_SIG4 w0.109: v7(58.29,88.29) v5(58.29,87.63)
  BOTTOM w0.173: R418.2 v7(58.29,88.29)
TSC_INT: length 2
  BOTTOM w0.173: J17.4 55.5,88.51 R418.1
TSC_RESETN: length 3.4
  BOTTOM w0.173: R792.1 R420.2 54.94,88.01 J17.3
UART1_RXD: length 389
  TOP w0.173: R904.1 v3(141.86,64.64) ; v4(112.63,71.22) U1.B27
  L3_SIG1 w0.109: v3(141.86,64.64) v5(141.22,64.64) 141.22,64.01 138.56,61.34 130.43,61.34 129.79,60.71 125.98,60.71 124.58,62.11 121.88,62.11 116.68,67.32 116.68,69.76 115.26,71.18 115.26,71.18 112.67,71.18 v4(112.63,71.22)
  L4_SIG2 w0.114: v5(87.1,133.68) 84.7,131.28 84.7,113.53 81.66,110.49 81.66,106.78 82.3,106.15 82.3,97.66 76.11,91.48 72.61,91.48 71.63,92.46 70.87,92.46 70.1,91.69 63.88,91.69 62.61,90.42 62.61,88.07 54.92,80.38 54.92,77.79 51.94,74.8 44.58,74.8 42.04,72.26 42.04,69.34 43.56,67.82 43.56,65.93 42.49,64.86 42.49,61.26 42.04,60.8 42.04,57.56 39.18,54.7 39.18,51.7 38.61,51.13 38.61,39.75 37.46,38.61 37.46,31.59 38.07,30.99 38.07,26.64 30.31,18.88 30.31,13.21 31.07,12.45 32.38,12.45 37.85,17.91 55.5,17.91 56.49,18.89 61.67,18.89 63.83,16.74 64.19,16.74 64.88,17.43 68.61,17.43 69.16,16.88 73.35,16.88 74.17,16.06 102.73,16.06 103.18,15.61 105.59,15.61 106.46,16.48 109.44,16.48 109.73,16.19 111.32,16.19 111.94,16.81 117.11,16.81 118.26,15.66 119.76,15.66 120.31,16.22 125.24,16.22 125.73,15.73 126.63,15.73 127.37,16.47 127.74,16.47 143.09,31.82 143.09,62.78 v5(141.22,64.64)
  L10_SIG4 w0.109: v7(108.46,133.99) 107.94,134.5 98.62,134.5 97.77,133.66 97.35,133.66 96.88,134.13 92.85,134.13 92.43,133.71 89.3,133.71 88.87,134.13 87.55,134.13 v5(87.1,133.68)
  BOTTOM w0.173: v7(108.46,133.99) 109.73,135.26 109.73,142.24 R879.1
UART1_TXD: length 392.6
  TOP w0.173: v4(111.83,72.02) U1.C26
  L3_SIG1 w0.099: v4(111.83,72.02) 112.18,72.36 114.93,72.36 114.93,72.35
  L3_SIG1 w0.109: 114.93,72.35 117.13,70.16 117.13,68.14 122.78,62.5 124.6,62.5 125.74,61.35 129.67,61.35 129.97,61.66 138.11,61.66 140.59,64.14 v5(140.59,65.53)
  L4_SIG2 w0.114: v5(85.65,133.93) 84.4,132.69 84.4,113.65 81.37,110.61 81.37,106.3 82,105.67 82,97.78 75.99,91.77 72.73,91.77 71.75,92.75 70.74,92.75 69.98,91.99 63.76,91.99 62.32,90.55 62.32,88.19 55.49,81.37 54.73,81.37 52.2,78.84 52.2,75.48 51.82,75.1 44.46,75.1 41.74,72.38 41.74,69.22 43.27,67.7 43.27,66.05 42.2,64.99 42.2,61.38 41.66,60.83 41.66,57.75 38.89,54.98 38.89,51.97 38.23,51.31 38.23,39.82 37.15,38.74 37.15,31.05 35.24,29.15 35.24,24.45 29.76,18.96 29.76,14.22 30.02,13.96 30.02,13.09 30.95,12.15 32.98,12.15 38.23,17.4 55.5,17.4 56.7,18.6 61.55,18.6 63.71,16.45 64.31,16.45 64.9,17.04 68.59,17.04 69.21,16.42 73.4,16.42 74.05,15.77 102.6,15.77 103.06,15.32 105.71,15.32 106.58,16.19 109.32,16.19 109.77,15.74 112.62,15.74 113.4,16.52 116.99,16.52 118.14,15.37 119.88,15.37 120.43,15.93 125.12,15.93 125.6,15.44 126.75,15.44 127.49,16.17 128.7,16.17 138.87,26.34 142.89,26.34 144.23,27.68 144.23,32.39 143.38,33.24 143.38,63.1 140.95,65.53 v5(140.59,65.53)
  L10_SIG4 w0.109: v5(85.65,133.93) 86.13,134.42 88.99,134.42 89.42,133.99 92.26,133.99 92.68,134.42 96.11,134.42 96.48,134.79 106.72,134.79 v7(107.19,135.26)
  BOTTOM w0.173: R880.1 108.33,136.4 v7(107.19,135.26)
UARTX_RXD: length 27.8
  TOP w0.173: U37.38 168.47,78.89 167.68,78.1 163.41,78.1 v3(162.31,79.2) ; U100.5 150.9,71.14 151.54,71.78 151.54,75.92 v3(151.13,76.33)
  L3_SIG1 w0.109: v3(162.31,79.2) 161.57,78.47 161.57,78 161.02,77.45 158.2,77.45 157.28,76.53 155.12,76.53 154.49,75.9 151.56,75.9 v3(151.13,76.33)
UARTX_TXD: length 25.7
  TOP w0.173: U37.39 168.21,79.39 v8(167.89,79.08) ; v3(152.02,73.84) 152.02,71.63 151.13,70.74 U100.4
  L3_SIG1 w0.109: v8(167.89,79.08) 167.89,77.32 165.61,75.03 155.76,75.03 154.57,73.84 v3(152.02,73.84)
USB1_CONN_DM: length 11
  BOTTOM w0.15: L11.4 42.78,23.01 43.03,22.76 43.03,21.41 42.9,21.29 42.9,19.53 42.55,19.18 42.55,17.78 42.7,17.62 U64.2 42.7,16.86 42.88,16.69 42.88,13.84 J23.2
USB1_CONN_DP: length 11
  BOTTOM w0.15: J23.3 43.18,13.86 43.18,16.64 43.4,16.86 U64.1 43.4,17.62 43.56,17.78 43.56,19.18 43.21,19.53 43.21,21.16 43.33,21.29 43.33,22.76 43.58,23.01 L11.3
USB1_OVRCURN: length 2.9
  BOTTOM w0.381: U66.5 R551.1
USB1_VBUS_EN: length 179.5
  TOP w0.173: R557.1 84.07,89.87 82.73,91.21 v3(81.71,91.21)
  L3_SIG1 w0.109: v3(81.71,91.21) 81.61,91.31 78.59,91.31 78.31,91.6 72.64,91.6 72.42,91.82 70.54,91.82 69.9,91.19 64.26,91.19 63.07,90 59.05,90 v5(58.42,90.63)
  L4_SIG2 w0.114: v8(25.27,3.68) 23.95,2.36 15.49,2.36 14.33,3.53 12.66,3.53 9.78,6.41 8.85,6.41 6.48,8.79 6.48,26.87 5.19,28.15 5.19,38.24 3.68,39.75 3.68,44.07 4.62,45.01 4.62,56.57 7.65,59.59 12.83,59.59 28.71,75.47 28.71,78.74 28.7,78.75 28.7,79.12 28.71,79.13 28.71,83.4 30.29,84.98 32.69,84.98 37.58,89.87 47.75,89.87 51.18,86.44 54.23,86.44 56.26,88.47 57.53,88.47 58.42,89.36 v5(58.42,90.63)
  BOTTOM w0.173: v8(25.27,3.68) R553.1 U66.4
USB2_CONN_DM: length 5.5
  TOP w0.15: U93.2 6.2,40.62 5.41,40.62 v8(5.26,40.47)
  BOTTOM w0.15: L33.3 8.02,40.57 7.78,40.82 7.34,40.82 7.14,40.62 5.41,40.62 v8(5.26,40.47) 5.1,40.62 4.85,40.62 4.68,40.45 J45.2
USB2_CONN_DP: length 5.6
  TOP w0.15: v8(5.26,41.08) 5.41,40.92 5.71,40.92 5.88,41.09 U93.1
  BOTTOM w0.15: L33.4 8.02,41.38 7.77,41.12 7.21,41.12 7.02,40.92 5.41,40.92 v8(5.26,41.08) 5.1,40.92 4.85,40.92 4.67,41.1 J45.3
USB2_ID: length 10.9
  TOP w0.173: U93.3 6.1,40.09 5.71,39.7 4.9,39.7 4.42,40.18 4.42,41.3 5.27,42.15 v8(5.78,42.15)
  BOTTOM w0.173: R788.1 R789.1 8.25,43.26 7.15,42.15 v8(5.78,42.15) 5.4,42.15 5,41.75 J45.4
USB2_OVRCURN: length 4.3
  TOP w0.173: U94.5 18.92,41.48 18.03,42.37 R790.1
USB2_VBUS_EN: length 96.5
  TOP w0.173: U94.4 R791.1 34.88,46.82 39,50.94 39.64,50.94 42.55,53.85 42.55,57.1 55.37,69.92 55.37,77.85 66.76,89.24 66.76,91.63 67.56,92.43 68.17,92.43 68.62,92.88 73.83,92.88 74.7,92 78.84,92 82.75,88.09 82.75,87.25 R787.1
USBJTAG_ENN: length 64.2
  TOP w0.173: v8(175.22,70.2) 175.22,71.47 174.59,72.1 U65.4
  BOTTOM w0.173: v8(175.22,70.2) 175.9,70.88 175.9,80.52 177.27,81.89 177.27,82.35 178.23,83.31 R677.2 ; v8(175.22,70.2) 173.84,71.58 173.84,76.99 167.98,82.84 167.98,85.23 168.82,86.07 U63.14 170.96,86.07 171.13,86.24 171.13,86.54 170.96,86.72 U63.15 ; v8(175.22,70.2) 176.91,68.51 176.91,63.2 171.07,57.36 167.51,57.36 166.5,58.37 166.5,59.29 167.4,60.19 U75.4
VADD33_PRU1ETH0: length 3.9
  TOP w0.381: v9(22.48,123.4) 22.98,123.4 R97.2 23.48,122.88 23.11,122.51 v9(22.41,122.51)
  BOTTOM w0.254: U9.14 22.09,122.19 v9(22.41,122.51)
VADD33_PRU1ETH1: length 2.5
  TOP w0.254: 26.54,99.52 26.68,99.66 U13.14
  vias: v9(26.26,100.26) v9(26.54,98.77)
VADD33_PRU2ETH0: length 3.3
  TOP w0.254: 27.97,81.88 U15.14
  TOP w0.508: 27.97,81.88 26.68,81.88 26.54,81.74 v9(26.54,80.99)
  vias: v9(26.21,82.61)
VADD33_PRU2ETH1: length 2.4
  TOP w0.254: U17.14 27.57,57.12 v9(27.43,56.98)
  TOP w0.508: 26.54,56.98 v9(26.54,56.23)
VAM572X_DDR1: length 32.2
  TOP w0.254: U1.T25 v4(100.64,72.82) ; U1.T24 v4(100.64,73.62) ; U1.AH27 v11(91.04,71.22) ; U1.W27 98.23,71.21 v4(98.04,71.21) ; U1.AG28 92.24,69.93 91.8,69.49 91.8,68.66 91.39,68.25 v4(91.39,66.93) ; U1.AA22 v4(96.64,75.22) ; U1.AB25 v4(95.84,72.82) ; U1.AB21 v4(95.84,76.02) ; U1.AG20 v4(91.84,76.82) ; U1.AC22 v4(95.04,75.22) ; U1.AB22 v4(95.84,75.22) ; U1.AA21 v4(96.64,76.02) ; U1.AD26 v11(94.24,72.02) ; U1.AB24 v4(95.84,73.62) ; U1.W16 v11(98.24,80.02)
  TOP w0.381: U3.K13 146.05,121.73 146.05,120.4 v9(145.8,120.14)
  L3_SIG1 w0.254: v5(95.59,72.42) v4(95.84,72.82) ; v11(94.24,72.02) v5(93.84,71.77) ; v4(95.84,75.22) v5(95.44,74.97) ; v11(91.04,71.22) v5(90.64,70.97) ; v4(95.84,76.02) v5(95.44,75.77) ; v4(91.84,76.82) v5(91.44,76.57) ; v4(96.64,75.22) v5(96.24,74.97) ; v11(98.24,80.02) v5(97.84,79.77) ; v4(98.04,71.21) v5(97.64,70.83) ; v4(100.64,72.82) v5(100.24,72.57) ; v4(95.84,73.62) v5(95.44,73.37) ; v5(91.06,66.6) v4(91.39,66.93) ; v4(95.04,75.22) v5(94.64,74.97) ; v4(96.64,76.02) v5(96.24,75.77) ; v4(100.64,73.62) v5(100.24,73.37)
  L10_SIG4 w0.254: v5(96.24,75.77) 96.18,75.51 v11(95.85,75.31) ; v5(95.44,74.97) 95.01,74.54 v11(95.01,74.53) ; v5(96.24,74.97) 95.76,74.49 v11(95.67,74.49) ; v11(95.04,75.52) v5(95.44,75.77) ; v5(97.64,70.83) 97.62,70.83 97.7,71.18 v11(97.59,71.37) ; v11(94.88,73.41) 94.93,73.37 v5(95.44,73.37) ; v11(94.24,72.02) v5(93.84,71.77) ; v11(98.24,80.02) v5(97.84,79.77) ; v11(94.04,74.9) 94.11,74.97 v5(94.64,74.97) ; v11(95,72.69) 95.27,72.42 v5(95.59,72.42) ; v11(91.04,71.22) v5(90.64,70.97)
  BOTTOM w0.381: C114.1 98.24,79.39 v11(98.24,80.02) ; v11(91.04,71.22) 90.8,71.45 C12.1
  vias: v9(61.02,78.12) v9(60.96,77.3) v9(60.96,76.28) v9(62.23,77.3) v9(62.23,76.28) v9(62.29,78.12) v9(63.56,78.12) v9(66.17,69.42) v9(67.31,71.33) v9(68.2,71.71) v9(69.09,71.96) v10(95.76,71.88) v10(96.14,72.09) v11(95.76,71.88) v11(96.14,72.09)
VANA_OUT: length 1.6
  TOP w0.381: U3.C8 v8(140.64,129.53)
  BOTTOM w0.508: v8(140.64,129.53) 140.04,129.53 C302.1
VCAN1: length 10.7
  TOP w0.508: J38.1 153.85,13.16 ; J38.1 151.71,15.29 ; J38.1 151.71,13.16 ; J38.1 153.85,15.29
  BOTTOM w0.381: v9(154.76,23.96) C252.1 v9(155.58,23.25)
  BOTTOM w0.508: C252.1 156.4,23.96 156.53,23.83
  BOTTOM w0.635: 156.53,23.83 U41.8
VETH0_AVDDH: length 7.5
  TOP w0.254: U21.47 v3(39.57,123.11)
  TOP w0.305: U21.1 v9(37.93,125.26)
  TOP w0.381: v9(31.37,125.18) 32.13,125.18 32.43,124.88 U21.12
  L3_SIG1 w0.381: v3(39.57,123.11) v5(40.16,123.11)
  BOTTOM w0.381: v9(31.37,125.18) 30.17,125.18 C157.1 30.3,126.32 v9(30.86,126.32)
  vias: v9(46.86,123.65) v9(46.86,122.89) v9(47.75,123.65) v9(47.75,122.89)
VETH0_AVDDL: length 1.6
  TOP w0.254: U21.9 v9(33.93,125.16) ; U21.4 v9(36.43,125.16)
VETH0_AVDDL_PLL: length 3.3
  TOP w0.254: U21.44 39.49,121.61 39.62,121.75 C165.1
  TOP w0.381: v9(41.4,122.64) 40.77,122 C165.1
VETH0_AVDDL_PMOS: length 2.5
  TOP w0.381: v9(44.7,125.3) 44.7,125.99 C158.1 45.59,125.86 v9(45.59,125.3)
VETH0_DVDDH: length 20.1
  TOP w0.254: U21.34 v9(36.93,116.41) ; U21.40 39.23,119.61 39.36,119.74 v9(40.26,119.74)
  TOP w0.381: R309.1 31.5,115.3 v9(31.55,115.35) ; R306.1 32.77,115.17 v9(32.94,115.35) ; v9(29.59,122.26) 29.74,122.11 U21.16 ; R279.2 v3(39.95,116.41) ; v5(41.66,118.45) v3(42.42,118.45) ; R301.1 v9(34.09,115.22) ; R299.1 v9(35.48,115.22)
  TOP w0.762: C156.1 v9(30.57,116.5) ; C156.1 v9(28.01,116.5) ; C156.1 29.29,117.61 v9(29.08,117.81)
  L3_SIG1 w0.381: v3(42.42,118.45) v5(41.66,118.45) ; v3(39.95,116.41) v5(39.37,116.41)
  BOTTOM w0.381: R280.2 v9(40.26,110.7) ; U22.5 38.58,109.46 C171.1 v9(39.36,109.43) ; C155.1 v9(29.59,122.26) ; D3.1 v9(42.16,112.86)
VETH0_DVDDL: length 6.8
  TOP w0.254: U21.18 v9(30.73,121.11) ; U21.30 v9(34.93,116.41) ; U21.23 30.19,118.61 30.18,118.6 30,118.6 v9(29.84,118.45) ; U21.26 v9(32.93,116.41) ; U21.14 v9(30.73,123.11) ; U21.39 v9(39.62,119.11)
VETH1_AVDDH: length 10.4
  TOP w0.254: U24.47 v9(63.12,123.11)
  TOP w0.305: v9(59.82,125.81) 59.65,125.64 U24.1
  TOP w0.381: v9(53.09,125.18) 53.85,125.18 54.15,124.88 U24.12
  L4_SIG2 w0.381: v9(59.82,125.81) 61.14,124.49 61.74,124.49 v9(63.12,123.11)
  vias: v9(64.9,130.26) v9(64.9,129.37) v9(66.04,130.26) v9(66.04,129.37)
VETH1_AVDDL: length 1.6
  TOP w0.254: U24.4 v9(58.15,125.16) ; U24.9 v9(55.65,125.16)
  vias: v9(64.01,124.64) v9(65.28,123.4)
VETH1_AVDDL_PLL: length 3
  TOP w0.254: U24.44 60.9,121.61 61.09,121.8 61.67,121.8 61.85,121.62 C186.1
  TOP w0.381: C186.1 v9(62.48,122.38)
  vias: v9(64.26,120.99) v9(65.15,120.99)
VETH1_DVDDH: length 18.7
  TOP w0.254: v9(51.43,122.13) 51.46,122.11 U24.16 ; v9(61.98,119.74) 61.87,119.74 61.74,119.61 U24.40 ; U24.34 v9(58.65,116.41)
  TOP w0.381: R345.1 v9(55.37,114.25) ; v9(54.23,114.38) 53.98,114.13 R352.1 ; R364.1 49.66,120.88 49.24,121.3 48.66,121.3 48.59,121.24 v9(48.26,121.24) ; R342.2 63.5,118.83 v9(63.88,119.21) ; R353.1 52.58,114.13 v9(52.83,114.38) ; v9(51.05,122.89) 50.67,122.51 C174.1 ; R343.1 v9(56.77,114.25)
  TOP w0.762: v9(50.67,114.5) C175.1 v9(49.39,113.22)
  BOTTOM w0.381: R324.2 v9(61.98,110.7) ; v9(61.07,109.43) C192.1 60.29,109.46 U26.5 ; 62.86,112.86 v9(63.75,112.86)
VETH1_DVDDL: length 10.1
  TOP w0.254: U24.30 v9(56.65,116.41) ; U24.14 v9(52.45,123.11) ; U24.39 v9(61.34,119.11) ; v9(51.7,118.31) 52,118.61 U24.23 ; U24.26 v9(54.65,116.41) ; U24.18 v9(52.45,121.11)
  TOP w0.381: v9(64.91,117.81) 65.04,117.94 FB7.2 65.04,119.84 v9(64.91,119.97) ; C181.1 51.46,118.06 v9(51.7,118.31)
VLDO1_OUT: length 2.4
  TOP w0.254: U3.C6 v8(138.25,129.53)
  BOTTOM w0.381: v8(138.25,129.53) 138.11,129.39
  BOTTOM w0.508: 138.11,129.39 C383.1 R657.2
VLDO2_OUT: length 1.6
  TOP w0.173: 138.94,131.02 139.03,131.11 139.03,131.46 139.07,131.5 139.07,131.84 v9(139.18,131.95)
  TOP w0.381: U3.B6 139.05,130.34
  vias: v9(139.18,133.48) v9(139.18,132.72)
VLED+: length 6.9
  BOTTOM w0.254: 73.54,141.58 U32.9 ; v9(82.17,128.99) 82.75,128.4 J16.30 ; v9(81.53,128.48) 82.11,127.9 J16.29
  vias: v9(71.75,139.53) v9(72.01,137.75) v9(72.39,140.42) v9(73.15,138.89)
VLED-: length 1
  BOTTOM w0.254: J16.28 J16.27 ; J16.23 J16.24
  vias: v9(81.03,145.75) v9(81.28,146.64) v9(81.53,145.12) v9(81.79,146) v9(82.17,126.57) v9(82.17,125.94) v9(83.06,126.57) v9(83.06,125.94)
VMAIN: length 211.1
  TOP w0.203: U3.A6 v3(138.25,130.34)
  TOP w0.254: U3.J2 v3(135.05,123.94) ; U3.G12 v3(143.84,125.54) ; U3.F2 v8(135.05,127.13) ; U3.D13 v3(144.64,128.73) ; U3.E3 v8(135.85,127.93) ; U3.J3 v3(135.85,123.94) ; U3.C4 v3(136.65,129.53) ; U3.D11 v3(143.04,128.73) ; U3.G13 v3(144.64,125.54) ; U3.C7 v3(139.84,129.53) ; U3.D12 v3(143.84,128.73) ; U3.H13 v3(144.64,124.74) ; U3.E2 v8(135.05,127.93) ; U3.E1 v8(134.25,127.93) ; U3.H12 v3(143.84,124.74) ; U3.J1 v3(134.09,124.34) ; U3.F1 v8(134.25,127.13) ; U3.F3 v8(135.85,127.13) ; U3.H11 v3(143.04,124.74) ; U3.G11 v3(143.04,125.54) ; U3.C5 v3(137.45,129.53)
  TOP w0.381: U96.5 152.01,141.37 v9(152.21,141.57) ; U3.A9 141.42,131.11 v9(141.42,131.67) ; U3.M8 U3.N8 140.25,120.44 v9(140.34,120.35) ; R113.2 138.48,14.86 137.67,14.05 137.67,5.54 139.32,3.89 v9(148.21,3.89) ; R19.2 v9(143.46,141.05) ; R20.2 142.88,137.8 v9(145.42,140.34) ; U76.1 149.08,100.81 C407.1 148.84,101.55 v9(149.23,101.94) ; U3.A10 142.1,130.99 v9(142.1,131.73) ; v9(138.68,119.84) 138.65,119.88 v9(138.65,120.56) U3.N6 U3.M6 ; v9(141.1,120.35) 141.05,120.4 U3.N9 U3.M9 ; v9(145.42,121.37) 145.42,121.57 v9(145.07,121.91) U3.L13 144.07,122.56 143.62,122.56 U3.L12 ; U3.N3 136.25,120.89 v3(136.65,120.49) 137.05,120.89 U3.N4 U3.M4
  L3_SIG1 w0.381: v9(175.67,124.54) 175.67,129.62 TP1.1
  L4_SIG2 w0.381: v9(148.21,3.89) 149.64,3.89 151.64,1.89 172.83,1.89 176.4,5.46 181.99,5.46 185.29,8.76 185.29,11.56 183.9,12.95 183.9,21.72 183.01,22.61 183.01,56.54 176.78,62.76 176.78,72.26 177.18,72.66 177.18,79.7 175.13,81.74 175.13,86.74 175.77,87.38 175.77,89.15 175.01,89.92 175.01,94.49 173.4,96.09 v9(168.53,96.09)
  L6_PWR1 w0.508: J9.1 159.84,137.92 ; J9.1 158.22,136.31 ; J9.1 159.84,136.31 ; J9.1 158.22,137.92
  BOTTOM w0.203: U62.A2 U62.A1
  BOTTOM w0.254: U32.2 73.54,147.73 C217.1 ; U62.A1 154.24,106.74 154.24,106.74
  BOTTOM w0.381: C272.1 138.22,120.99 v9(138.65,120.56)
  BOTTOM w0.508: C152.1 v9(156.46,138.43) ; R411.2 v9(74.55,140.03)
  vias: v2(135.64,119.72) v2(136.4,119.97) v3(135.64,119.72) v3(136.4,119.97) v5(132.72,124.67) v5(132.72,124.03) v5(133.35,124.67) v5(133.35,124.03) v5(133.99,132.42) v5(134.62,132.42) v5(135.26,132.42) v5(135.89,131.78) v5(136.14,119.33) v5(136.67,121.05) v5(136.94,119.83) v5(139.19,130.54) v5(139.86,130.7) v5(140.23,131.25) v5(145.8,125.68) v5(145.92,129.37) v5(145.92,128.73) v5(145.92,124.92) v5(146.56,125.68) v5(146.69,129.37) v5(146.69,128.73) v5(146.69,124.92) v5(147.32,125.68) v5(147.45,124.92) v6(133.22,131.02) v6(133.99,131.02) v6(134.75,131.02) v6(135.43,131.02) v6(145.16,129.37) v6(145.16,128.61) v6(145.29,124.29) v6(145.29,123.53) v6(146.18,124.29) v6(146.18,123.53) v6(147.07,124.29) v6(147.07,123.53) v7(133.22,131.02) v7(133.99,131.02) v7(134.75,131.02) v7(135.43,131.02) v7(145.16,129.37) v7(145.16,128.61) v7(145.29,124.29) v7(145.29,123.53) v7(146.18,124.29) v7(146.18,123.53) v7(147.07,124.29) v7(147.07,123.53) v9(71.25,149.69) v9(72.14,150.07) v9(72.9,149.69) v9(76.07,108.67) v9(76.83,108.67) v9(77.22,129.24) v9(77.72,108.67) v9(78.11,130) v9(78.11,129.24) v9(78.61,108.67) v9(78.99,130) v9(78.99,129.24) v9(140.84,119.72) v9(141.35,119.21) v9(149.99,107.9) v9(149.99,106.66) v9(150.8,107.93) v9(150.8,106.66) v9(155.7,131.78) v9(155.7,130.76) v9(155.83,129.49) v9(156.34,128.48) v9(157.1,139.19) v9(157.1,137.67) v9(158.12,128.43) v9(166.27,114.64) v9(166.27,113.5) v9(167.41,114.64) v9(167.41,113.5) v9(168.68,114.64) v9(168.68,113.49) v9(174.52,124.54) v9(174.52,123.4) v9(174.52,122.13) v9(175.67,123.4) v9(175.67,122.13) v9(177.32,123.4) v9(177.32,122.13) v9(178.59,124.54) v9(178.59,123.4) v9(178.59,122.13) v9(179.86,124.54) v9(179.86,123.4) v9(179.86,122.13) v9(184.43,123.53) v9(184.43,122.26)
VPP_CONN: length 115.6
  BOTTOM w0.508: R797.1 122.05,80.73 124.59,78.19 124.59,43.77 130.56,37.8 146.5,37.8 158.44,25.86 172.54,25.86 174.31,24.09 174.31,17.42 171.2,14.31 171.2,9.99 170.18,8.97 J46.2
VPROFI: length 12.8
  TOP w0.381: R577.2 v9(113.03,8.89)
  TOP w0.508: v9(100.2,6.22) v9(99.44,6.22) 99.31,6.1 C430.1 98.3,5.4 98.3,5.39 J14.6
  L9_SIG3 w0.381: v9(113.03,8.89) 111.63,7.49 111.63,4.57 v9(112.39,3.81)
  vias: v9(100.97,6.22) v9(101.98,6.22) v9(112.39,3.05) v9(113.16,2.41) v9(114.05,2.41)
VPROFI_SRC: length 5.2
  BOTTOM w0.381: D15.1 D14.1 118.6,7 C433.1
VPWRIN_JCK: length 62.5
  TOP w0.381: 177.8,103.89 174.24,100.33 162.74,100.33 161.49,101.57 159.28,101.57 157.35,103.5 157.35,108.71 154.94,111.12 154.94,113.03 155.32,113.41 U105.5
  TOP w0.508: 185.67,110.15 J2.1 ; J2.1 187.28,110.15 ; J2.1 185.67,108.54 ; J2.1 187.28,108.54 ; 174.38,113.37 J1.1 ; J1.1 174.38,110.15 ; J1.1 177.61,113.37 ; J1.1 177.61,110.15
  BOTTOM w0.508: J2.1 187.28,110.15 ; J2.1 185.67,110.15 ; J2.1 185.67,108.54 ; J2.1 187.28,108.54 ; 174.38,113.37 J1.1 ; J1.1 174.38,110.15 ; J1.1 177.61,110.15 ; J1.1 177.61,113.37
VPWRIN_PREFUSE:
  vias: v9(169.57,107.27) v9(172.11,107.27) v9(173.38,106) v9(173.38,104.73) v9(173.38,103.46)
VRTC_OUT: length 73
  TOP w0.381: U3.A8 140.72,131.21 140.72,132.29 ; 140.97,132.54 140.72,132.29 ; 140.72,132.29 140.72,132.8 141.35,133.43 ; v3(150.37,116.08) 150.88,115.57 R928.1 ; R645.2 93.85,103.99 93.47,104.37 v9(93.47,104.57)
  TOP w0.762: 141.73,133.3 140.97,132.54
  L3_SIG1 w0.381: v3(150.37,116.08) 148.97,116.08 147.96,117.09 147.96,119.89 148.21,120.14 148.21,127.87 147.83,128.25 147.83,137.16 146.94,138.05 144.02,138.05 143.31,137.34 143.31,136.45 142.37,135.51 141.52,135.51 v9(140.97,134.96)
  L10_SIG4 w0.381: v7(141.99,117.47) 142.18,117.67 142.18,121.35 141.22,122.3 137.62,122.3 v7(137.13,122.78) 136.91,123.01 136.91,125.86 138.71,127.66 139.62,127.66 139.89,127.39 140.93,127.39 141.14,127.6 141.85,127.6 144.17,129.93 144.17,134.17 142.93,135.41 141.42,135.41 v9(140.97,134.96)
  BOTTOM w0.381: v7(137.13,122.78) 136.97,122.78 136.63,122.44 R17.2 ; v7(141.99,117.47) 142.62,116.84 R931.2 ; v9(141.3,134.4) 141.3,134.63 v9(140.97,134.96) 140.59,134.57 v9(140.59,134.45)
VSDMMC: length 96.3
  TOP w0.254: U1.W8 v4(98.24,87.21) ; U1.Y8 v4(97.44,87.21)
  TOP w0.635: R644.2 86.61,110.16 85.01,111.76 85.01,112.93 81.41,116.54 81.41,118.57 80.52,119.46 80.52,128.69 82.93,131.1 82.93,137.24 87,141.31 v9(87,145.67) v9(87,146.88)
  L3_SIG1 w0.254: v4(98.24,87.21) v5(97.84,87.46) ; v4(97.44,87.21) v5(97.04,87.46)
  L10_SIG4 w0.254: v11(96.65,87.08) v5(97.04,87.46) ; v11(97.45,87.08) v5(97.84,87.46)
  L10_SIG4 w0.635: v7(111.3,131.7) 113.13,131.7 114.32,130.51 131.96,130.51 132.72,129.75 135.1,129.75 v7(135.49,129.35) v7(136,128.84) ; v7(110.03,131.7) 110.03,134.79 107.92,136.91 99.06,136.91 98.42,137.54 v7(98.42,138.18) 98.42,138.18 v7(97.74,138.87) 96.19,138.87 v9(95.91,138.59)
  BOTTOM w0.381: R657.1 v7(136,128.84) v7(135.49,129.35) ; v9(85.33,97.26) C483.1 v9(86.39,96.09)
  vias: v5(92.96,91.27) v5(93.47,90.63) v5(95.17,92.48) v6(94.81,91.94) v6(94.81,91.17) v6(94.82,90.58) v6(95.3,90.12) v6(111.3,130.81) v7(94.81,91.94) v7(94.81,91.17) v7(94.82,90.58) v7(95.3,90.12) v7(111.3,130.81) v9(85.22,108.71) v9(85.34,107.95)
VSMPS1_2:
  vias: v9(114.05,133.05) v9(114.05,132.16) v9(115.32,133.05) v9(115.32,132.03) v9(115.37,134.32) v9(116.46,134.32) v9(116.46,133.05) v9(116.46,132.03) v9(152.15,130.38) v9(153.42,130.38) v9(154.18,133.3) v9(154.18,132.29) v9(154.18,129.06) v9(154.18,127.59)
VSMPS1_SW: length 2.3
  TOP w0.381: 144.79,127.88 144.45,127.54 U3.E13 U3.E12 U3.E11
VSMPS2_SW: length 2.6
  TOP w0.381: 145.17,126.85 145.05,126.74 144.65,126.74 144.65,126.74 U3.F13 U3.F12 U3.F11
VSMPS3_SW: length 3.1
  TOP w0.305: U3.J11 142.82,124.16 143.27,124.16 U3.J12 143.62,124.16 144.07,124.16 U3.J13
  TOP w0.381: U3.J13 144.42,124.16 145.42,124.16
VSMPS4_5: length 3.9
  BOTTOM w0.381: C279.1 128.73,128.81 129.41,129.49 v9(130.18,129.49) ; v9(130.18,120.58) 129.41,120.58 128.73,119.89 C280.1
  vias: v9(130.18,128.73) v9(130.18,128.1) v9(130.18,119.82) v9(130.18,119.18)
VSMPS4_SW: length 3.8
  TOP w0.381: 132.72,126.32 132.84,126.45 133.62,126.45 134.13,125.94 U3.G1 U3.G2 U3.G3
VSMPS5_SW: length 3.5
  TOP w0.381: U3.H3 U3.H2 U3.H1 133.06,125.14 132.84,124.92
VSMPS6_SW: length 2.7
  TOP w0.381: 137.67,119.33 137.85,119.51 U3.N5 U3.M5
VSMPS7:
  vias: v9(106.1,133.18) v9(106.1,131.91) v9(107.37,133.18) v9(107.37,131.91) v9(127.53,135.82) v9(128.8,135.82) v9(130.07,135.44) v9(130.07,134.17)
VSMPS7_SW: length 2.1
  TOP w0.381: U3.D3 136.25,128.38 136.02,128.61 135.71,128.61 U3.D2 135.39,128.34 135.13,128.61 134.91,128.61 U3.D1
VSMPS8: length 19
  TOP w0.381: v8(142.25,122.34) U3.L11 v8(143.04,122.34)
  TOP w0.508: 144.36,106.6 TP26.1 ; TP26.1 145.97,106.6 ; TP26.1 145.97,104.99 ; TP26.1 144.36,104.99
  L4_SIG2 w0.381: v9(144.65,111.12) v9(143.51,111.12) 143.51,121.87 v8(143.04,122.34) v8(142.25,122.34)
VSMPS8_SW: length 4.4
  TOP w0.381: U3.M10 U3.N10 141.85,121 142.11,120.73 142.11,118.95 143,118.06
VSMPS9: length 0.8
  L10_SIG4 w0.381: 139.95,125.43 v5(139.95,126.19)
  vias: v5(138.05,125.81) v5(138.61,125.89) v5(140.72,126.19) v6(138.3,125.3) v6(138.3,124.67) v6(139.19,125.3) v6(139.19,124.67) v7(138.3,125.3) v7(138.3,124.67) v7(139.19,125.3) v7(139.19,124.67) v9(138.94,111.21) v9(140.34,111.21) v9(141.73,111.21)
VSMPS9_SW: length 2.5
  TOP w0.381: U3.M7 U3.N7 139.45,119.46
VUSB_FTDI: length 91.3
  TOP w0.381: v9(169.16,90.3) 168.14,91.32 D13.2 163.12,90.57 R491.2
  L10_SIG4 w0.381: v9(175.26,15.96) 174.62,15.96 171.71,18.87 171.71,19.77 172.61,20.66 172.61,22.69 173.6,23.69 173.6,25.49 170.56,28.53 170.56,38.68 171.25,39.37 171.25,42.55 172.67,43.97 172.67,54.62 171.87,55.41 171.87,58.13 168.4,61.59 168.4,63.37 168.78,63.75 168.78,69.72 170.26,71.2 170.26,78.74 168.29,80.71 168.29,81.79 169.49,83 169.49,87.96 169.67,88.14 169.67,89.79 v9(169.16,90.3)
VUSB_JTAG: length 5.3
  TOP w0.254: U36.1 182.77,15.35 v9(182.73,15.39)
  TOP w0.381: J19.1 185.28,13.1 v9(185.19,13)
  BOTTOM w0.381: v9(185.19,13) 185.11,13 v9(182.73,15.39)
VUSB_VBUS1: length 3.8
  L10_SIG4 w0.508: 38.86,13.68 J23.1 ; J23.1 40.22,13.68 ; J23.1 38.86,12.33 ; J23.1 40.22,12.33
  vias: v9(25.78,13.08) v9(26.92,13.08) v9(28.07,13.08) v9(29.21,13.08) v9(36.58,5.97) v9(36.58,4.83) v9(37.85,2.54)
VUSB_VBUS2: length 252
  TOP w0.508: 13.8,37.55 J50.2 ; J50.2 15.41,37.55 ; J50.2 15.41,39.16 ; J50.2 13.8,39.16
  L9_SIG3 w0.381: v9(25.65,38.76) 25.65,43.1 25.27,43.48 25.27,47.88 21.82,51.33 21.82,76.5 24.56,79.25 24.56,94.82 24.1,95.28 24.1,98.48 23.37,99.21 23.37,101.65 24.31,102.59 24.31,107.52 21.84,109.98 21.84,112.84 20.51,114.17 20.51,115.3 19.18,116.64 19.18,122.3 14.35,127.13 v5(14.35,127.89)
  L10_SIG4 w0.381: v7(138.3,128.1) 137.57,128.1 136.56,127.09 136.56,126.96 134.24,124.64 134.24,122.48 133.35,121.59 129.46,121.59 126.64,124.41 126.64,127.74 124.76,129.62 106.98,129.62 105.45,131.15 105.45,132.3 104.77,132.97 100.2,132.97 99.51,132.28 97.99,132.28 96.84,131.13 95.49,131.13 94.92,131.7 93.22,131.7 92.84,131.32 90.3,131.32 89.53,132.08 82.93,132.08 80.98,134.04 79.55,134.04 76.96,131.44 66.12,131.44 61.04,136.53 26.62,136.53 25.63,135.53 19.71,135.53 18.03,137.21 16.61,137.21 14.35,134.95 v5(14.35,127.89)
  BOTTOM w0.381: R21.2 138.56,127.84 v7(138.3,128.1)
  vias: v9(8.51,39.32) v9(8.51,38.05) v9(9.65,39.32) v9(9.65,38.05)
XTIN: length 9.2
  TOP w0.173: U37.2 157.07,83.39 156.31,84.16 156.31,85.43 155.63,86.11 C243.1 153.61,86.11 153.34,86.38 Y5.1
XTOUT: length 7.5
  TOP w0.173: U37.3 156.38,82.89 156.34,82.94 C244.1 153.72,82.94 153.07,82.28 Y5.2
N10692191: length 11.9
  TOP w0.173: SW2.3 SW2.4 v8(171.54,51.42)
  BOTTOM w0.173: v8(171.54,51.42) 170.91,51.42 169.8,52.53 169.8,53.54 U48.1 R11.2
N11217419: length 2.2
  BOTTOM w0.173: R47.1 R46.1 C85.1
N11219802: length 1.8
  TOP w0.305: 106.81,11.51 107.32,12.03 U8.7
N11219922: length 1.6
  TOP w0.305: R56.1 108.32,11.63 U8.9
N11219986: length 2.9
  TOP w0.173: R69.1 C101.1 105.26,16.36 U8.5
N11220684: length 1.8
  TOP w0.173: C86.1 110.52,16.36 U8.1
N12123192: length 7
  BOTTOM w0.173: R293.2 28.74,145.88 J10.11
N12123204: length 6.1
  BOTTOM w0.173: R296.2 34.26,145.97 J10.14
N12138943: length 2.4
  TOP w0.173: R298.1 39.71,123.61 U21.48
N12139138: length 5.3
  TOP w0.173: U21.41 39.78,120.11 40.01,120.34 40.4,120.34 41.02,119.72 43.43,119.72 TP16.1
N12220066: length 22.8
  TOP w0.173: v8(21.59,122.13) 21.59,120.48 C111.1 21.72,119.59 C109.1 ; C110.1 25.54,115.51 v8(24.57,115.51)
  L9_SIG3 w0.114: v8(21.59,122.13) 21.59,119.97 23.24,118.32 23.24,116.84 v8(24.57,115.51)
  L10_SIG4 w0.109: v8(21.59,122.13) 21.84,121.87 22.61,121.87 23.09,122.36 24.28,122.36 v7(24.51,122.13)
  BOTTOM w0.173: U9.24 24.61,116.95 25.17,116.39 C108.1 24.92,115.85 v8(24.57,115.51) ; v7(24.51,122.13) 24.26,122.38 22.99,122.38 22.59,121.98 U9.15 ; U9.13 v8(21.59,122.13)
N12225140: length 4.2
  BOTTOM w0.173: J5.11 8.21,113.46 R122.1
N12225158: length 11.1
  TOP w0.173: U13.24 33.25,97.14 v3(33.53,96.86) 34.42,95.97 C123.1 ; v8(27.55,98.66) 28.05,99.16 U13.15 ; U13.13 28.19,100.16 28.05,100.31 v3(27.43,100.31)
  BOTTOM w0.173: C124.1 C126.1 28.58,97.36 v8(28.7,97.24) ; C125.1 27.29,97.6 27.55,97.86 v8(27.55,98.66)
N12225278: length 5.4
  BOTTOM w0.173: R151.1 6.23,105.03 J5.10
N12226470: length 4.6
  BOTTOM w0.173: R134.1 7.7,99.4 J5.9
N12226568: length 2.6
  BOTTOM w0.173: U69.1 31.83,89.24 R153.1 R154.1
N12957779: length 4.9
  TOP w0.173: v8(166.24,72.39) 166.14,72.49 U37.28
  BOTTOM w0.173: v8(166.24,72.39) 166.24,70.1 R482.2
N12957783: length 9.3
  BOTTOM w0.173: U75.6 167.8,62.26 166.47,63.58 165.27,63.58 164.72,64.14 164.72,67.56 R482.1
N12957791: length 2.4
  TOP w0.173: v8(168.66,73.28) 168.14,73.8 U37.32
  BOTTOM w0.173: v8(168.66,73.28) 168.78,73.15 R489.2
N12957851: length 4.6
  TOP w0.173: U37.59 163.14,88.25 R491.1 R494.2 R492.2
N12958009: length 2.6
  TOP w0.173: U37.14 156.18,77.39 R485.1
N12958129: length 2.2
  TOP w0.173: R493.2 161.98,90.95 D13.1
N12958219: length 15.4
  BOTTOM w0.173: U38.4 167.69,95.2 168.02,94.87 168.02,91.19 167.51,90.68 165.74,90.68 164.59,89.53 164.59,87.25 163.96,86.61 163.96,86.23 163.2,85.47 R496.1 R495.2
N12958339: length 3.2
  TOP w0.173: U37.36 173.14,77.89 TP18.1
N12958347: length 2.7
  TOP w0.173: R493.1 162.64,87.61 U37.60
N12958879: length 25.2
  TOP w0.173: R474.1 v8(154.31,76.33)
  L9_SIG3 w0.114: v8(154.31,76.33) 155.62,77.65 155.62,80.28 161.19,85.86 171.04,85.86 v8(171.47,85.42)
  BOTTOM w0.173: v8(171.47,85.42) 171.47,85.42 U63.13
N12958935: length 39.8
  TOP w0.173: v8(174.24,64.64) 170.56,64.64 168.45,66.76 164.59,66.76 161.42,69.93 161.42,70.48 160.91,70.99
  L10_SIG4 w0.109: v8(174.24,64.64) 174.85,65.24 174.85,66.27 175.92,67.34 175.92,78.62 v7(174.14,80.39)
  BOTTOM w0.173: U63.10 172.41,83.46 174.14,81.74 v7(174.14,80.39)
N12958939: length 41.1
  TOP w0.173: R481.1 163.37,66.12 168.19,66.12 170.82,63.5 v8(174.37,63.5)
  L10_SIG4 w0.109: v8(174.37,63.5) 175.13,64.26 175.13,66.15 176.2,67.22 176.2,79.57 v7(175.39,80.39)
  BOTTOM w0.173: U63.11 172.27,84.11 175.39,81 v7(175.39,80.39)
N12958943: length 17.1
  TOP w0.173: R480.1 v3(158.75,67.95)
  L3_SIG1 w0.109: v3(158.75,67.95) 160.02,69.22 v5(165.99,69.22)
  L10_SIG4 w0.109: v5(165.99,69.22) 165.61,68.83 165.61,65.02 v7(165.99,64.64)
  BOTTOM w0.173: v7(165.99,64.64) 166.88,63.75 166.88,63.72 168.2,62.4 U75.7
N12958955: length 47.9
  TOP w0.173: 158.75,70.99 157.86,70.1 157.86,67.69 159.37,66.18 162.37,66.18 162.94,65.61 167.94,65.61 170.56,62.99 v8(173.23,62.99)
  L10_SIG4 w0.109: v8(173.23,62.99) 173.23,64.43 174.24,65.45 174.24,68.45 173.86,68.83 173.86,75.56 174.7,76.4 174.7,79.22 173.71,80.21 173.71,80.72 173.99,81 173.99,81.76 173.38,82.37 v7(173.38,84.77)
  BOTTOM w0.173: U63.12 169.92,84.77 v7(173.38,84.77)
N15911835: length 2.9
  TOP w0.173: 26.54,97.74 27.43,97.74 28.35,98.66 U13.16
N16251668: length 58
  TOP w0.173: v3(131.01,71.46) 130.89,71.58 128.52,71.58 R385.1
  L3_SIG1 w0.109: v3(131.01,71.46) v5(131.62,71.46)
  L9_SIG3 w0.114: v5(131.62,71.46) 131.62,71.42 132.77,70.28 132.77,65.23 148.34,49.66 150.75,49.66 164.97,35.43 v8(164.97,34.88)
  BOTTOM w0.173: v8(164.97,34.88) U73.15
N16251678: length 56.4
  TOP w0.173: R387.1 129.29,70.31 v3(129.41,70.44)
  L3_SIG1 w0.109: v5(133.48,71.2) 132.84,70.57 131.29,70.57 130.94,70.21 129.64,70.21 v3(129.41,70.44)
  L9_SIG3 w0.114: v8(164.34,38.31) 164.34,40.34 145.5,59.18 139.83,59.18 135.17,63.84 135.17,69.51 v5(133.48,71.2)
  BOTTOM w0.173: U73.2 164.97,37.67 v8(164.34,38.31)
N16383240: length 5.6
  BOTTOM w0.173: R11.1 C5.1 R911.1 166.5,50.29 166.24,50.04 U97.2
N16700927: length 3.9
  BOTTOM w0.173: J5.12 6.43,113.2 6.43,109.61 R138.1
N16818596: length 4.6
  BOTTOM w0.173: R89.1 7.75,123.57 J3.9
N16818719: length 2.5
  BOTTOM w0.173: R112.1 R107.1 43.07,87.35 U68.1
N16819128: length 1.9
  TOP w0.173: v8(23.59,121.84) 22.99,121.24 R103.2
  BOTTOM w0.173: U9.16 23.09,121.47 23.46,121.84 v8(23.59,121.84)
N16839102:
  vias: v9(185.55,80.52) v9(186.82,80.52)
N16839202: length 3.9
  BOTTOM w0.173: U72.13 185.46,79.54 184.53,80.47 184.29,80.47 R382.2
N16839209: length 3.2
  BOTTOM w0.173: U72.2 178.31,79.84 R381.2
N16839216: length 3
  BOTTOM w0.173: R380.2 177.66,80.21 U72.1
N16844891: length 1.6
  TOP w0.173: R388.2 D6.2
N16844892: length 1.6
  TOP w0.173: R395.2 D11.2
N16844893: length 1.6
  TOP w0.173: R396.2 D12.2
N16844894: length 1.6
  TOP w0.173: R391.2 D9.2
N16844899: length 1.6
  TOP w0.173: R392.2 D10.2
N16844909: length 1.6
  TOP w0.173: R386.2 D5.2
N16844924: length 1.6
  TOP w0.173: R390.2 D8.2
N16844930: length 1.6
  TOP w0.173: R389.2 D7.2
N17007255: length 65.8
  TOP w0.173: U28.4 178.29,55.47 R366.1 v8(174.12,55.45) ; R377.1 v3(125.35,71.33)
  L3_SIG1 w0.109: v5(128.54,70.22) 126.45,70.22 v3(125.35,71.33)
  L9_SIG3 w0.114: v8(174.12,55.45) 167.8,61.77 145.64,61.77 135.43,71.98 131.44,71.98 130.51,71.05 129.37,71.05 v5(128.54,70.22)
N17074741: length 5.4
  BOTTOM w0.173: J3.10 6.48,124.33 R106.1
N17120040: length 3.1
  TOP w0.173: J21.3 103.38,146.99 R743.1
N17120055: length 3.2
  TOP w0.173: R744.1 105.41,146.96 J21.5
N17120058: length 3.1
  TOP w0.173: R745.1 107.31,146.99 J21.7
N17120061: length 3.1
  TOP w0.173: J21.9 109.35,147.02 R746.1
N17120072: length 3.1
  TOP w0.173: J21.11 111.38,146.99 R747.1
N17120075: length 157.6
  TOP w0.173: R748.1 v3(30.61,91.93)
  L3_SIG1 w0.109: J21.13 112.25,145.92 101.74,145.92 98.69,142.88 93.79,142.88 93.07,142.15 77.91,142.15 75.26,139.5 73.03,139.5 69.14,135.61 62.13,135.61 61.42,136.32 48.61,136.32 42.75,130.45 27.13,130.45 26.39,129.72 23.6,129.72 21.18,127.3 21.18,125.75 20.31,124.88 18.33,124.88 17.15,123.7 17.15,120.93 17.71,120.37 17.71,114.88 15.27,112.45 15.27,101.82 15.88,101.22 15.88,95 15.66,94.79 15.66,92.31 17.55,90.42 21.59,90.42 21.89,90.13 28.09,90.13 28.9,90.94 29.62,90.94 v3(30.61,91.93)
N17120078: length 3
  TOP w0.173: J21.15 115.32,146.99 R749.1
N17120081: length 3
  TOP w0.173: J21.17 117.35,147.02 R750.1
N17120084: length 3
  TOP w0.173: R751.1 119.38,146.99 J21.19
N17120087: length 3
  TOP w0.173: R752.1 121.28,146.96 J21.21
N17120090: length 3
  TOP w0.173: J21.23 123.32,146.99 R753.1
N17120397: length 3.2
  BOTTOM w0.173: R869.1 145.42,146.95 J21.45
N17120400: length 3.2
  BOTTOM w0.173: J21.47 147.45,146.92 R870.1
N17120403: length 385.7
  TOP w0.173: R684.2 121.54,67.01 122.05,66.5 122.05,62.09 123.28,60.86 126.49,60.86 127.43,61.8 v8(129.16,61.8) ; J21.24 124.35,148.02 124.35,145.45 125.04,144.75 v3(125.04,142.57) ; R883.2 v3(86.11,100.94)
  L3_SIG1 w0.109: v3(86.11,100.94) v5(86.11,101.52) ; v5(139.57,139.32) 139.88,139.62 139.88,142.75 139.73,142.9 132.66,142.9 131.67,143.89 129.9,143.89 128.57,142.57 v3(125.04,142.57)
  L4_SIG2 w0.114: v8(141.35,109.3) 145.53,109.3 146.1,109.88 146.1,117.84 146.74,118.48 146.74,122.06 143.74,125.05 143.74,135.15 v5(139.57,139.32)
  L10_SIG4 w0.109: v7(97.16,150.6) 97.08,150.52 97.06,150.52 95.74,149.2 93.47,149.2 93.34,149.34 92,149.34 91.68,149.02 87.45,149.02 86.61,148.18 83.62,148.18 82.93,148.87 81.79,148.87 79.65,146.73 67.65,146.73 65.36,149.02 10.74,149.02 3.64,141.92 3.64,113.45 17.42,99.67 20.81,99.67 22.71,101.58 24.36,101.58 24.71,101.92 26.34,101.92 26.77,102.36 26.77,103.99 27.04,104.26 27.37,104.26 28.21,105.1 29.11,105.1 29.27,105.26 31.09,105.26 31.47,104.88 33.11,104.88 34.1,105.86 34.36,105.86 36.3,107.8 37.23,107.8 37.99,107.04 43.41,107.04 44.05,107.67 51.84,107.67 52.35,107.17 54.84,107.17 55.99,108.31 59.97,108.31 60.98,107.29 67.69,107.29 68.19,106.79 78.72,106.79 83.24,102.27 85.36,102.27 v5(86.11,101.52)
  BOTTOM w0.173: v8(141.35,109.3) 138.3,106.25 138.3,104.48 135.93,102.1 135.93,95.61 136.68,94.86 136.68,89.56 135.93,88.81 135.93,82.03 128.09,74.19 128.09,62.87 v8(129.16,61.8) ; J21.24 122.12,150.25 101.06,150.25 100.28,151.03 98.73,151.03 98.3,150.6 v7(97.16,150.6)
N17144335: length 2.5
  TOP w0.173: R29.1 97.41,121.11
N17156111: length 7.3
  BOTTOM w0.173: U23.1 43.89,101.41 44.66,102.18 45.12,102.18 R305.2 C172.2 47.77,102.56 Y3.2
N17156113: length 5.4
  BOTTOM w0.173: R308.2 R305.1 C173.2 47.51,103.57 Y3.1
N17156222: length 2.2
  BOTTOM w0.173: U23.14 43.89,106.02 44.3,105.6 R308.1
N17156522: length 6
  BOTTOM w0.173: U23.11 41.94,105.06 41.53,104.65 40.57,104.65 40.32,104.39 38.23,104.39 R310.1
N17156525: length 3.2
  BOTTOM w0.173: U23.9 40.64,105.45 40.29,105.1 R313.1
N17156528: length 1.7
  BOTTOM w0.173: R315.1 39.12,106.4 U23.8
N17156983: length 2.5
  TOP w0.173: R314.1 42.8,105.11 v8(42.88,105.19)
  BOTTOM w0.173: U23.12 42.59,105.49 v8(42.88,105.19)
N17156986: length 2.5
  TOP w0.173: v8(43.63,105.26) 43.81,105.07 R312.1
  BOTTOM w0.173: U23.13 43.24,105.65 v8(43.63,105.26)
N17569906: length 7
  BOTTOM w0.173: R337.2 53.16,145.88 51.22,143.94 J12.11
N17569909: length 6.1
  BOTTOM w0.173: R340.2 61.88,145.88 J12.14
N17569918: length 2.3
  TOP w0.173: R341.1 61.72,123.86 61.56,123.7 61.31,123.7 61.22,123.61 U24.48
N17569921: length 3
  TOP w0.173: TP17.1 62.65,120.1 62.52,120.22 61.62,120.22 61.5,120.11 U24.41
N17570093: length 6.6
  BOTTOM w0.173: U25.1 57.83,98.42 58.42,99.01 R349.2 C193.2 61.45,99.01 Y4.2
N17570094: length 5.5
  BOTTOM w0.173: Y4.1 61.2,100.03 C194.2 R349.1 R351.2
N17570107: length 2.4
  BOTTOM w0.173: R351.1 58.42,102.19 57.83,102.78 U25.14
N17570112: length 8.6
  BOTTOM w0.173: R354.1 52.07,98 55.88,101.81 U25.11
N17570113: length 8.5
  BOTTOM w0.173: R357.1 50.8,98 54.58,101.78 U25.9
N17570114: length 2.3
  BOTTOM w0.173: U25.8 53.93,104.9 R359.1
N17570122: length 2
  BOTTOM w0.173: U25.12 56.53,105.51 R358.1
N17570123: length 2.3
  BOTTOM w0.173: R356.1 57.18,105.01 U25.13
N17594977: length 12
  TOP w0.173: U15.15 28.34,81.38 27.76,80.8 27.76,80.4 v8(27.58,80.22) ; v8(27.18,82.63) 27.43,82.38 U15.13 ; C135.1 34.67,78.44 34.67,79.33 v9(34.67,79.33) 34.67,79.33 33.78,79.33 33.25,79.86 U15.24
  BOTTOM w0.173: v8(27.18,82.63) 28.45,81.36 C138.1 C134.1 ; C136.1 27.16,79.82 27.56,80.22 v8(27.58,80.22)
N17595008: length 4.6
  BOTTOM w0.173: R172.1 7.75,75.31 J6.9
N17595032: length 2.5
  BOTTOM w0.173: R195.1 R190.1 28.16,70.73 U70.1
N17595048: length 3.2
  TOP w0.173: v8(28.19,79.58) 29.02,80.41 U15.16
  BOTTOM w0.173: v8(28.19,79.58) R186.2
N17595072: length 5.4
  BOTTOM w0.173: J6.10 6.48,76.07 R189.1
N17595076: length 4.2
  BOTTOM w0.173: R161.1 8.25,89.28 J6.11
N17595078: length 5.1
  BOTTOM w0.173: J6.12 6.48,89.03 R176.1
N17596821: length 4.2
  BOTTOM w0.173: J8.11 8.26,68.66 R203.1
N17596823: length 11.7
  TOP w0.173: U17.24 33.84,55.39 v9(34.67,54.56) 34.67,53.68 C147.1 ; v8(27.56,56.09) 28.09,56.62 U17.15 ; U17.13 27.55,57.62 v8(27.18,57.99)
  BOTTOM w0.173: v8(27.56,56.09) 28.07,56.6 C148.1 C150.1 28.05,55.06 C149.1
N17596838: length 283.9
  TOP w0.173: 124.59,77.17 v3(125.35,77.17)
  L3_SIG1 w0.109: v5(124.64,77.17) v3(125.35,77.17)
  L4_SIG2 w0.114: v5(124.64,77.17) 125.28,77.81 129.58,77.81 130.52,78.75 138.04,78.75 139.45,77.34 139.45,76.42 144.91,70.96 144.91,70.36 148.91,66.36 149.76,66.36 151.87,64.26 151.87,22.61 144.27,15.01 139.34,15.01 132.78,8.45 114.61,8.45 112.86,10.2 105.7,10.2 104.93,9.43 103.91,9.43 103.14,10.2 96.63,10.2 96.42,10.41 74.68,10.41 73.93,11.16 55.16,11.16 48.51,4.5 42.27,4.5 41.4,3.64 30.81,3.64 30.16,4.29 23.88,10.57 23.88,21.22 25.78,23.11 25.78,24.38 27.34,25.95 27.34,28.82 23.3,32.87 23.3,39.43 15.46,47.27 15.46,53.46 12.83,56.09 v8(7.24,56.09)
  BOTTOM w0.173: v8(7.24,56.09) R231.2 6.48,51.31 J8.10
N17596847: length 13.4
  TOP w0.173: U1.C17 v4(111.83,79.22) ; R230.2 123.42,77.02 v3(122.81,77.02)
  L3_SIG1 w0.109: v4(111.83,79.22) 114.77,79.22 115.29,78.69 115.73,78.69 115.88,78.84 120.05,78.84 121.28,77.6 122.22,77.6 v3(122.81,77.02)
N17596886: length 4.6
  BOTTOM w0.173: J8.9 7.75,50.55 R214.1
N17596899: length 2.6
  BOTTOM w0.173: R234.1 R233.1 28.13,45.87 U71.1
N17596976: length 3.2
  TOP w0.173: v8(28.19,54.56) 29.02,55.39 U17.16
  BOTTOM w0.173: R228.2 v8(28.19,54.56)
N17596979: length 4.3
  BOTTOM w0.173: J8.12 6.23,60.54 R218.1
N17731118: length 2.5
  BOTTOM w0.173: Q1.G 12.51,2.62 R245.2 R241.1
N17731139: length 2.5
  BOTTOM w0.173: R253.2 R255.2 12.51,5.92 Q5.G
N17732522: length 1.6
  BOTTOM w0.127: R410.1 75.04,142.46 U32.6
N17732526: length 3.2
  BOTTOM w0.173: U32.3 74.04,146.65 74.68,147.28 R413.2 R414.2
N17732536: length 2.3
  TOP w0.173: v8(74.3,149.56) 74.3,149.55 Q9.D
  BOTTOM w0.173: R413.1 74.68,149.18 v8(74.3,149.56)
N17732560: length 1.3
  BOTTOM w0.127: U32.7 74.54,141.82 R411.1
N17745676: length 6.2
  TOP w0.173: R275.2 185.57,136.33 185.79,136.55 185.79,138.29 J9.22
N17745678: length 6.1
  TOP w0.173: R277.2 188.11,138.51 J9.24
N17745755: length 13.7
  BOTTOM w0.173: X1.3 R903.2 165.35,143 R276.2 R300.2 R905.1
N17863265: length 4.2
  BOTTOM w0.173: J3.11 8.25,137.54 R78.1
N17863276: length 5.1
  BOTTOM w0.173: R93.1 6.48,137.29 J3.12
N18733248: length 19.8
  TOP w0.173: R497.1 79.86,87.43 v3(79.86,84.86) ; v4(95.03,81.75) 94.9,81.75 U1.AD14
  L3_SIG1 w0.109: v4(95.03,81.75) 94.57,82.22 94.04,82.22 93.84,82.41 93.05,82.41 92.93,82.54 92.93,82.54 92.76,82.71 92.71,82.76 91.21,82.76 90.84,83.13 89.22,83.13 89.07,83.28 87.74,83.28 87.6,83.41 84.61,83.41 84.35,83.16 83.24,83.16 82.55,83.85 80.95,83.85 79.93,84.86 v3(79.86,84.86)
N18733249: length 4.3
  TOP w0.173: R497.2 C247.1 75.98,87.46 Y6.4
N18733252: length 24.5
  TOP w0.173: U1.AE14 93.23,82.62 v4(93.23,82.71) ; v3(80.57,84.86) 80.54,84.89 80.54,87.99 R919.2 79.73,88.49 77.83,88.49 C246.1 77.62,88.49 75.93,88.49 75.01,89.41 Y6.1
  L3_SIG1 w0.109: v4(93.23,82.71) 93.23,82.7 92.93,83 91.27,83 90.92,83.35 89.31,83.35 89.04,83.62 87.91,83.62 87.81,83.72 84.51,83.72 84.25,83.46 83.9,83.46 83.16,84.2 81.23,84.2 v3(80.57,84.86)
N18733262: length 29.3
  TOP w0.173: U1.AF14 v4(92.64,82.41) ; v8(77.09,75.95) 75.56,75.95 R499.2
  L3_SIG1 w0.109: v5(90.74,82.51) 90.77,82.51 90.86,82.41 v4(92.64,82.41)
  L9_SIG3 w0.114: v5(90.74,82.51) 91.81,82.51 92.25,82.07 92.25,80.85 91.47,80.06 84.67,80.06 82.79,81.95 77.93,81.95 77.13,81.15 77.13,75.99 v8(77.09,75.95)
N18733263: length 2.6
  BOTTOM w0.173: R500.1 R498.1 61.23,64.66 U39.4
N18733273: length 49.7
  TOP w0.173: U1.AB17 v4(95.84,79.22)
  L3_SIG1 w0.099: 93.2,80.31 94.37,80.31
  L3_SIG1 w0.109: 94.37,80.31 94.54,80.14 94.54,79.91 95.24,79.22 v4(95.84,79.22) ; 93.2,80.31 92.27,80.31 92.05,80.09 82.4,80.09 82.3,80.19 80.72,80.19 80.09,79.55 74.85,79.55 74.14,80.26 70.97,80.26 66.75,76.05 66.75,68.78 62.36,64.39 v8(62.36,62.82)
  BOTTOM w0.173: v8(62.36,62.82) R500.2 R920.2
N18733274: length 21.1
  TOP w0.173: v8(95.25,102.06) 95,102.31 R923.2 ; U1.Y11 v4(97.44,84.81)
  L3_SIG1 w0.109: v5(97.04,85.06) v4(97.44,84.81)
  L4_SIG2 w0.114: v5(97.04,85.06) 97.01,85.06 96.63,85.45 96.63,86.03 96.37,86.28 96.08,86.28 95.85,86.5 95.85,86.83 95.6,87.08 95.28,87.08 95.05,87.3 95.05,89.67 96.39,91.02 96.39,100.91 v8(95.25,102.06)
N18733276: length 28.2
  TOP w0.173: U1.AD17 v4(94.24,79.22) ; R921.1 TP19.1 69.36,79.35 v3(70.89,79.35)
  L3_SIG1 w0.099: 92.05,79.79 92.48,79.79 92.88,79.39 93.2,79.39 93.31,79.51 93.56,79.51 93.85,79.22 v4(94.24,79.22)
  L3_SIG1 w0.109: 92.05,79.79 82.27,79.79 82.17,79.88 81,79.88 80.37,79.25 71,79.25 v3(70.89,79.35)
N18868530: length 10.4
  TOP w0.173: U3.L1 134.64,122.73 133.7,122.73 131.7,120.73 131.7,116.67 131.44,116.41 R572.2 R14.1
N18868533: length 10.4
  TOP w0.173: U3.L2 135.05,122.34 134.07,122.34 133.57,121.84 133.57,119.22 132.72,118.36 v8(132.72,116.51) R15.1
  BOTTOM w0.173: R15.1 v8(132.72,116.51)
N18901325: length 1.4
  TOP w0.173: U3.K9 v8(141.44,123.14)
  BOTTOM w0.173: v8(141.44,123.14) 141.18,122.89 R794.1
N18913166: length 36.9
  TOP w0.173: U3.J5 v3(137.45,123.94) ; v3(152.65,110.62) TP7.1
  L3_SIG1 w0.109: v3(152.65,110.62) 151.89,109.86 143.51,109.86 142.75,110.62 138.56,110.62 137.8,111.38 137.29,111.38 134.62,114.05 134.16,114.05 131.7,116.51 131.7,120.35 134.08,122.73 135.97,122.73 136.26,123.01 136.26,123.3 136.51,123.56 137.07,123.56 v3(137.45,123.94)
N18913202: length 2.6
  TOP w0.173: U3.K7 v8(139.05,123.14)
  BOTTOM w0.173: R17.1 R906.1 139.05,122.69 v8(139.05,123.14)
N18913205: length 1.4
  TOP w0.173: U3.L3 v8(135.85,122.34)
  BOTTOM w0.173: 135,122.38 135.81,122.38 v8(135.85,122.34)
N18913322: length 14.1
  TOP w0.173: U3.G9 v8(141.44,125.54)
  L10_SIG4 w0.109: v8(141.44,125.54) 141.44,125.54 142.64,124.34 142.64,124.34 142.64,122.2 142.88,121.96 v7(142.88,117.6)
  BOTTOM w0.173: 143.64,116.59 143.64,116.84 v7(142.88,117.6) ; R18.1 144.54,126.04 144.2,125.7 141.6,125.7 v8(141.44,125.54)
N18913403: length 10.8
  TOP w0.173: U3.A3 135.95,131.03 135.95,134.38 C26.2 137.03,135.99 137.33,136.29 138.24,136.29 138.43,136.48 138.43,138.68 138.26,138.85 Y2.1
N18913412: length 6.6
  TOP w0.173: U3.A2 135.45,131.16 135.51,131.23 C25.2 135.51,136 135.17,136.34 Y2.3
N18913758: length 5.9
  TOP w0.173: C27.2 139.96,135.09 139.96,133.56 139.95,133.56 139.95,131.25 139.85,131.14 139.85,130.34 U3.B7
N18914190: length 11.9
  TOP w0.173: U3.M11 142.65,121.9 v3(143.05,121.5) ; TP2.1 147.57,116.71 147.57,118.36 v3(146.94,119)
  L3_SIG1 w0.109: v3(146.94,119) 143.55,119 143.05,119.51 v3(143.05,121.5)
N18914214: length 34.5
  TOP w0.173: TP3.1 v3(148.72,111.63) ; U3.J7 v3(139.84,124.73)
  L3_SIG1 w0.109: v3(148.72,111.63) 148.21,111.12 146.94,111.12 146.18,111.89 137.29,111.89 134.84,114.33 134.28,114.33 132.08,116.53 132.08,119.96 134.05,121.93 136.07,121.93 136.91,122.76 138.09,122.76 138.09,122.76 139.21,122.76 139.45,122.99 U3.J7 v3(139.84,124.73)
N18914339: length 100.7
  TOP w0.173: v8(150.23,53.19) U50.1 150.27,51.42 SW3.3 SW3.4 ; U3.G8 v3(140.64,125.54)
  L3_SIG1 w0.109: v5(145.48,119.51) 144.65,119.51 143.44,120.72 143.44,123.34 143.23,123.56 142.08,123.56 141.82,123.81 141.82,124.1 141.6,124.33 141.31,124.33 141.06,124.58 141.06,125.13 v3(140.64,125.54)
  L4_SIG2 w0.114: v5(145.48,119.51) 145.48,115.13 144.91,114.55 144.91,112.84 145.48,112.27 145.48,111.04 144.81,110.36 v5(143.76,110.36)
  L10_SIG4 w0.109: v5(143.76,110.36) 143.26,109.86 v7(143.26,109.81)
  BOTTOM w0.173: v7(143.26,109.81) 139.7,106.25 139.7,104.48 137.16,101.94 137.16,96.01 137.41,95.76 137.41,89.28 137.16,89.03 137.16,86.23 144.21,79.18 148.48,79.18 152.22,75.44 152.22,69.85 150.23,67.86 v8(150.23,53.19)
N18914524: length 22.1
  TOP w0.173: v3(147.57,112.9) TP6.1 ; U3.C11 v8(143.04,129.53)
  L3_SIG1 w0.109: v3(147.57,112.9) 147.32,113.16 v5(145.54,113.16)
  L4_SIG2 w0.114: v5(145.54,113.16) 145.81,113.42 145.81,117.97 146.44,118.6 146.44,121.94 143.52,124.86 143.52,129.05 v8(143.04,129.53)
N18915671: length 16.9
  TOP w0.254: U3.B3 v3(135.85,130.33)
  TOP w0.381: v9(142.54,139.27) 142.54,139.98 R19.1
  L3_SIG1 w0.381: v3(135.85,130.33) 136.53,131 136.53,132.33 135.84,133.02 135.84,135.92 136.8,136.88 138.94,136.88 139.22,136.6 141.68,136.6 141.7,136.62 141.74,136.62 142.54,137.43 v9(142.54,139.27)
N18915723: length 4.8
  TOP w0.381: R20.1 142.88,130.97 U3.A11
N18915943: length 1.6
  TOP w0.173: U3.D8 v8(139.85,128.73)
  BOTTOM w0.173: R21.1 138.92,128.86 139.73,128.86 v8(139.85,128.73)
N19120663: length 5
  TOP w0.173: U5.L8 88.8,30.3 89.53,30.3 89.73,30.1 R41.2
N19120749: length 4.9
  TOP w0.173: R44.2 105.53,30.1 105.37,30.26 104,30.26 U7.L8
N19127709: length 5.1
  TOP w0.173: R42.2 121.46,30.1 121.08,29.72 120.14,29.72 119.93,29.5 119.23,29.5 U6.L8
N19139994: length 11.8
  TOP w0.173: U6.D7 118.06,35.48 117.22,36.32 117.22,39.5 118.24,40.51 R32.1
N19139997: length 10.9
  TOP w0.173: R33.1 109.47,40.64 114.05,40.64 116.08,38.61 116.08,36.83 115.56,36.31 114.9,36.31 U6.C3
N19140025: length 9.3
  TOP w0.173: R34.1 122.81,38.48 121.67,39.62 119.25,39.62 118.44,38.81 118.44,36.7 U6.C8
N19140027: length 10.4
  TOP w0.173: U6.C2 114.48,36.7 115.13,36.7 115.7,37.27 115.7,38.31 114,40 109.86,40 R35.1
N19140065: length 8.3
  TOP w0.173: U6.A7 118.06,39.45 118.75,40.13 122.05,40.13 122.68,39.5 R37.1
N19140067: length 6
  TOP w0.173: R38.1 110.68,38.79 113.75,38.79 114.06,38.48 U6.A2
N19140105: length 7.5
  TOP w0.173: U6.B8 119.25,37.47 119.25,38.28 120.22,39.24 121.16,39.24 122.94,37.46 R39.1
N19140107: length 6.9
  TOP w0.173: R40.1 110.24,39.37 113.97,39.37 114.86,38.48 U6.A3
N19258097: length 1.6
  BOTTOM w0.173: U45.7 57,52.04 R546.1
N19258128: length 5.1
  BOTTOM w0.173: 47.12,56 47.2,56 49.02,54.18 49.53,54.18 50.17,53.54 U45.21
N19258198: length 2
  BOTTOM w0.173: Y7.1 44.58,58.93 R547.1
N19258383: length 2.2
  BOTTOM w0.173: R548.1 53.59,49.23 54.47,50.11 U45.11
N19258403: length 2.8
  TOP w0.173: R550.1 v8(54.86,49.74)
  BOTTOM w0.173: U45.10 54.97,49.84 v8(54.86,49.74) 54.61,49.48 R549.1
N19258622: length 7.9
  BOTTOM w0.173: U45.17 50.44,51.54 49.9,51.01 46.1,51.01 45.59,50.5 C305.1
N19258627: length 4.8
  BOTTOM w0.173: U45.19 50.12,52.54 50.03,52.45 48.86,52.45 48.4,52.91 C306.1
N19290398: length 2.6
  BOTTOM w0.173: R421.1 U33.7
N19388440: length 4.7
  BOTTOM w0.173: U89.B9 156.89,98.55 159.13,98.55 R566.1
N19415733: length 2.7
  BOTTOM w0.173: U45.12 53.97,50.24 53.59,49.87 53.09,49.87 52.58,49.36 R568.1
N19425975: length 19.2
  TOP w0.173: U1.E23 v4(110.23,74.42) ; R7.1 v3(123.57,66.25)
  L3_SIG1 w0.099: 112.36,73.91 111.11,73.91 110.6,74.42 v4(110.23,74.42)
  L3_SIG1 w0.109: 112.36,73.91 112.78,73.49 115.34,73.49 118.31,70.51 118.31,68.58 120.37,66.53 122.04,66.53 122.32,66.25 v3(123.57,66.25)
N19426030: length 16.3
  TOP w0.173: U1.D21 v4(111.03,76.02) ; R8.1 v3(122.81,69.3)
  L3_SIG1 w0.109: v3(122.81,69.3) 122.81,69.95 121.23,71.53 119.87,71.53 115.85,75.54 111.89,75.54 111.42,76.02 v4(111.03,76.02)
N19426454: length 17.7
  TOP w0.173: U1.AC15 v4(95.06,80.84)
  L3_SIG1 w0.099: v4(95.06,80.84) 95.39,80.5 95.48,80.5
  L3_SIG1 w0.109: 95.48,80.5 v5(95.5,80.48)
  L10_SIG4 w0.109: v5(95.5,80.48) 95.5,80.95 95.1,81.36 92.25,81.36 91.21,80.31 87.53,80.31 86.03,81.81 84.4,81.81 83.9,82.32 83.9,83.57 v7(83.19,84.28)
  BOTTOM w0.173: 82.42,84.28 v7(83.19,84.28)
N19438966: length 259.2
  TOP w0.173: v8(135.86,57) 130.94,57 129.36,58.58 123.13,58.58 120.78,60.93 R582.1 v8(121.54,65.99) ; U1.AB9 v4(95.84,86.41)
  L3_SIG1 w0.109: v5(162.81,102.87) 159.82,102.87 156.54,106.15 150.2,106.15 147.72,106.15 145.8,108.08 137.29,108.08 135.81,109.55 135.13,109.55 v5(134.05,110.63) ; v5(158.12,74.55) 154.68,71.12 147.18,71.12 146.89,70.83 140.95,70.83 140.35,70.22 137.98,70.22 137.16,69.4 135.34,69.4 131.75,65.81 121.72,65.81 v8(121.54,65.99) ; v4(95.84,86.41) v5(95.44,86.66)
  L4_SIG2 w0.114: v5(95.44,86.66) 95.23,86.66 94.83,87.06 94.83,89.98 95.99,91.13 95.99,95.64 95,96.63 95,100.96 94.61,101.35 v5(94.61,102.9)
  L9_SIG3 w0.114: v8(179.07,9.91) 177.93,11.05 177.93,14.97 149.9,42.99 149.87,42.99 v8(135.86,57)
  L10_SIG4 w0.109: v5(134.05,110.63) 130.55,114.13 122.51,114.13 113.87,105.49 113.87,103.96 112.53,102.62 107.56,102.62 107.11,103.07 103,103.07 102.16,102.23 97.26,102.23 96.59,102.9 v5(94.61,102.9) ; v5(162.81,102.87) 164.34,101.34 164.34,86.26 162.94,84.86 162.94,81.36 160.1,78.51 159.54,78.51 158.12,77.09 v5(158.12,74.55)
  BOTTOM w0.173: U77.4 v8(179.07,9.91)
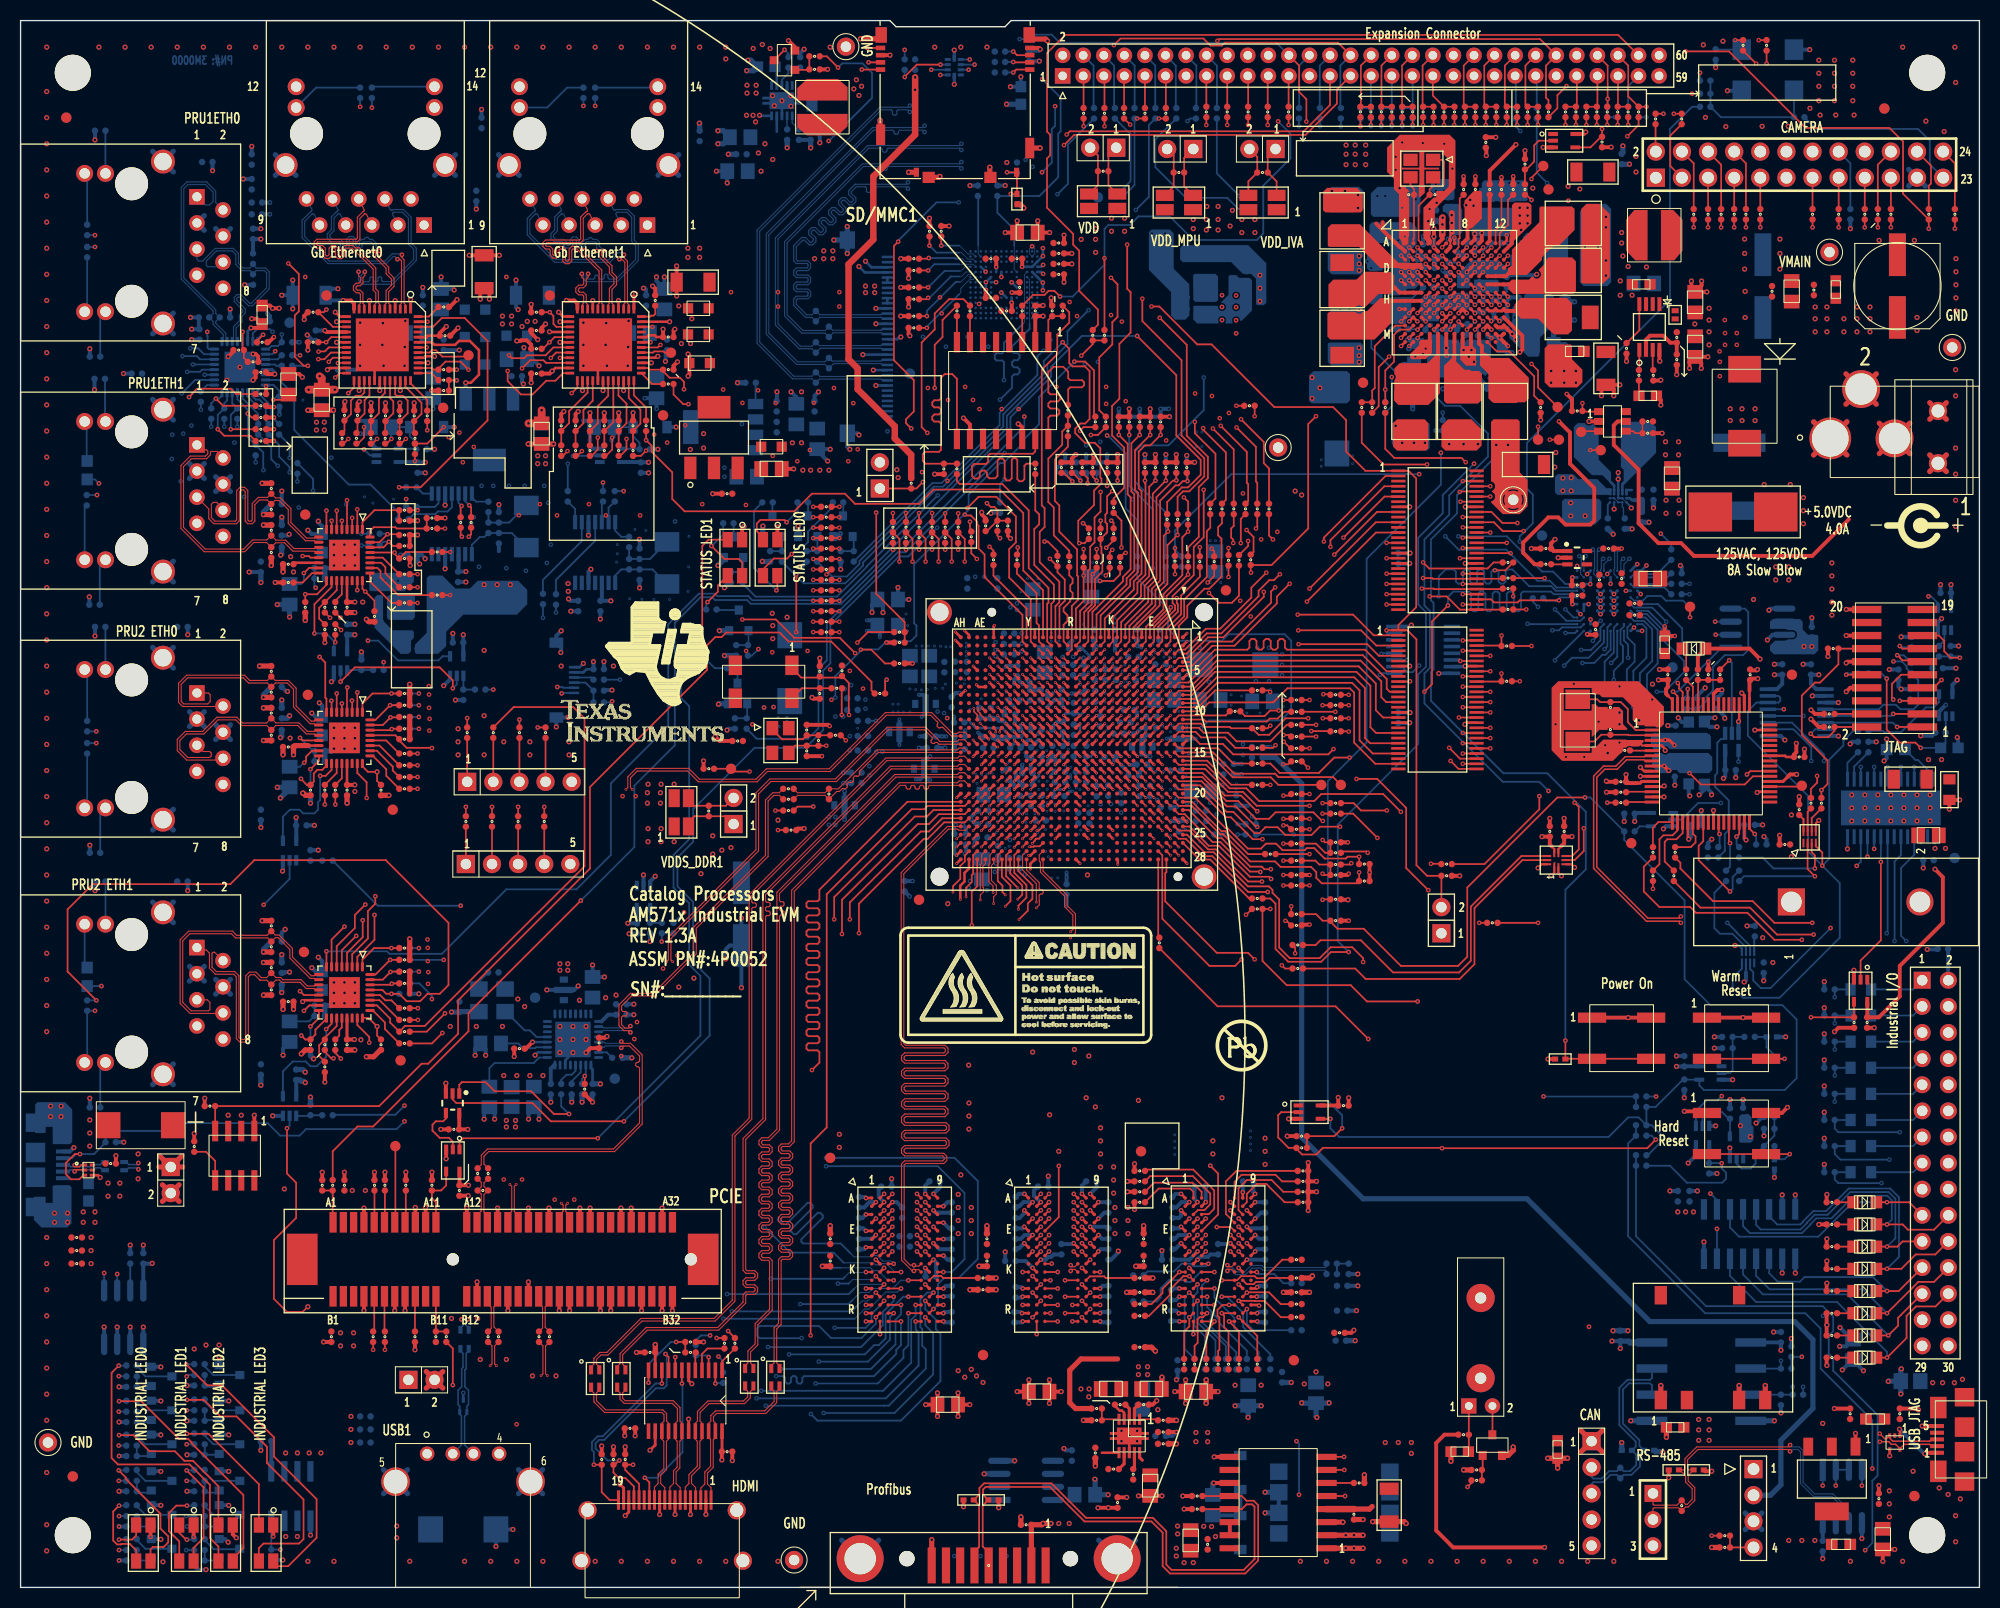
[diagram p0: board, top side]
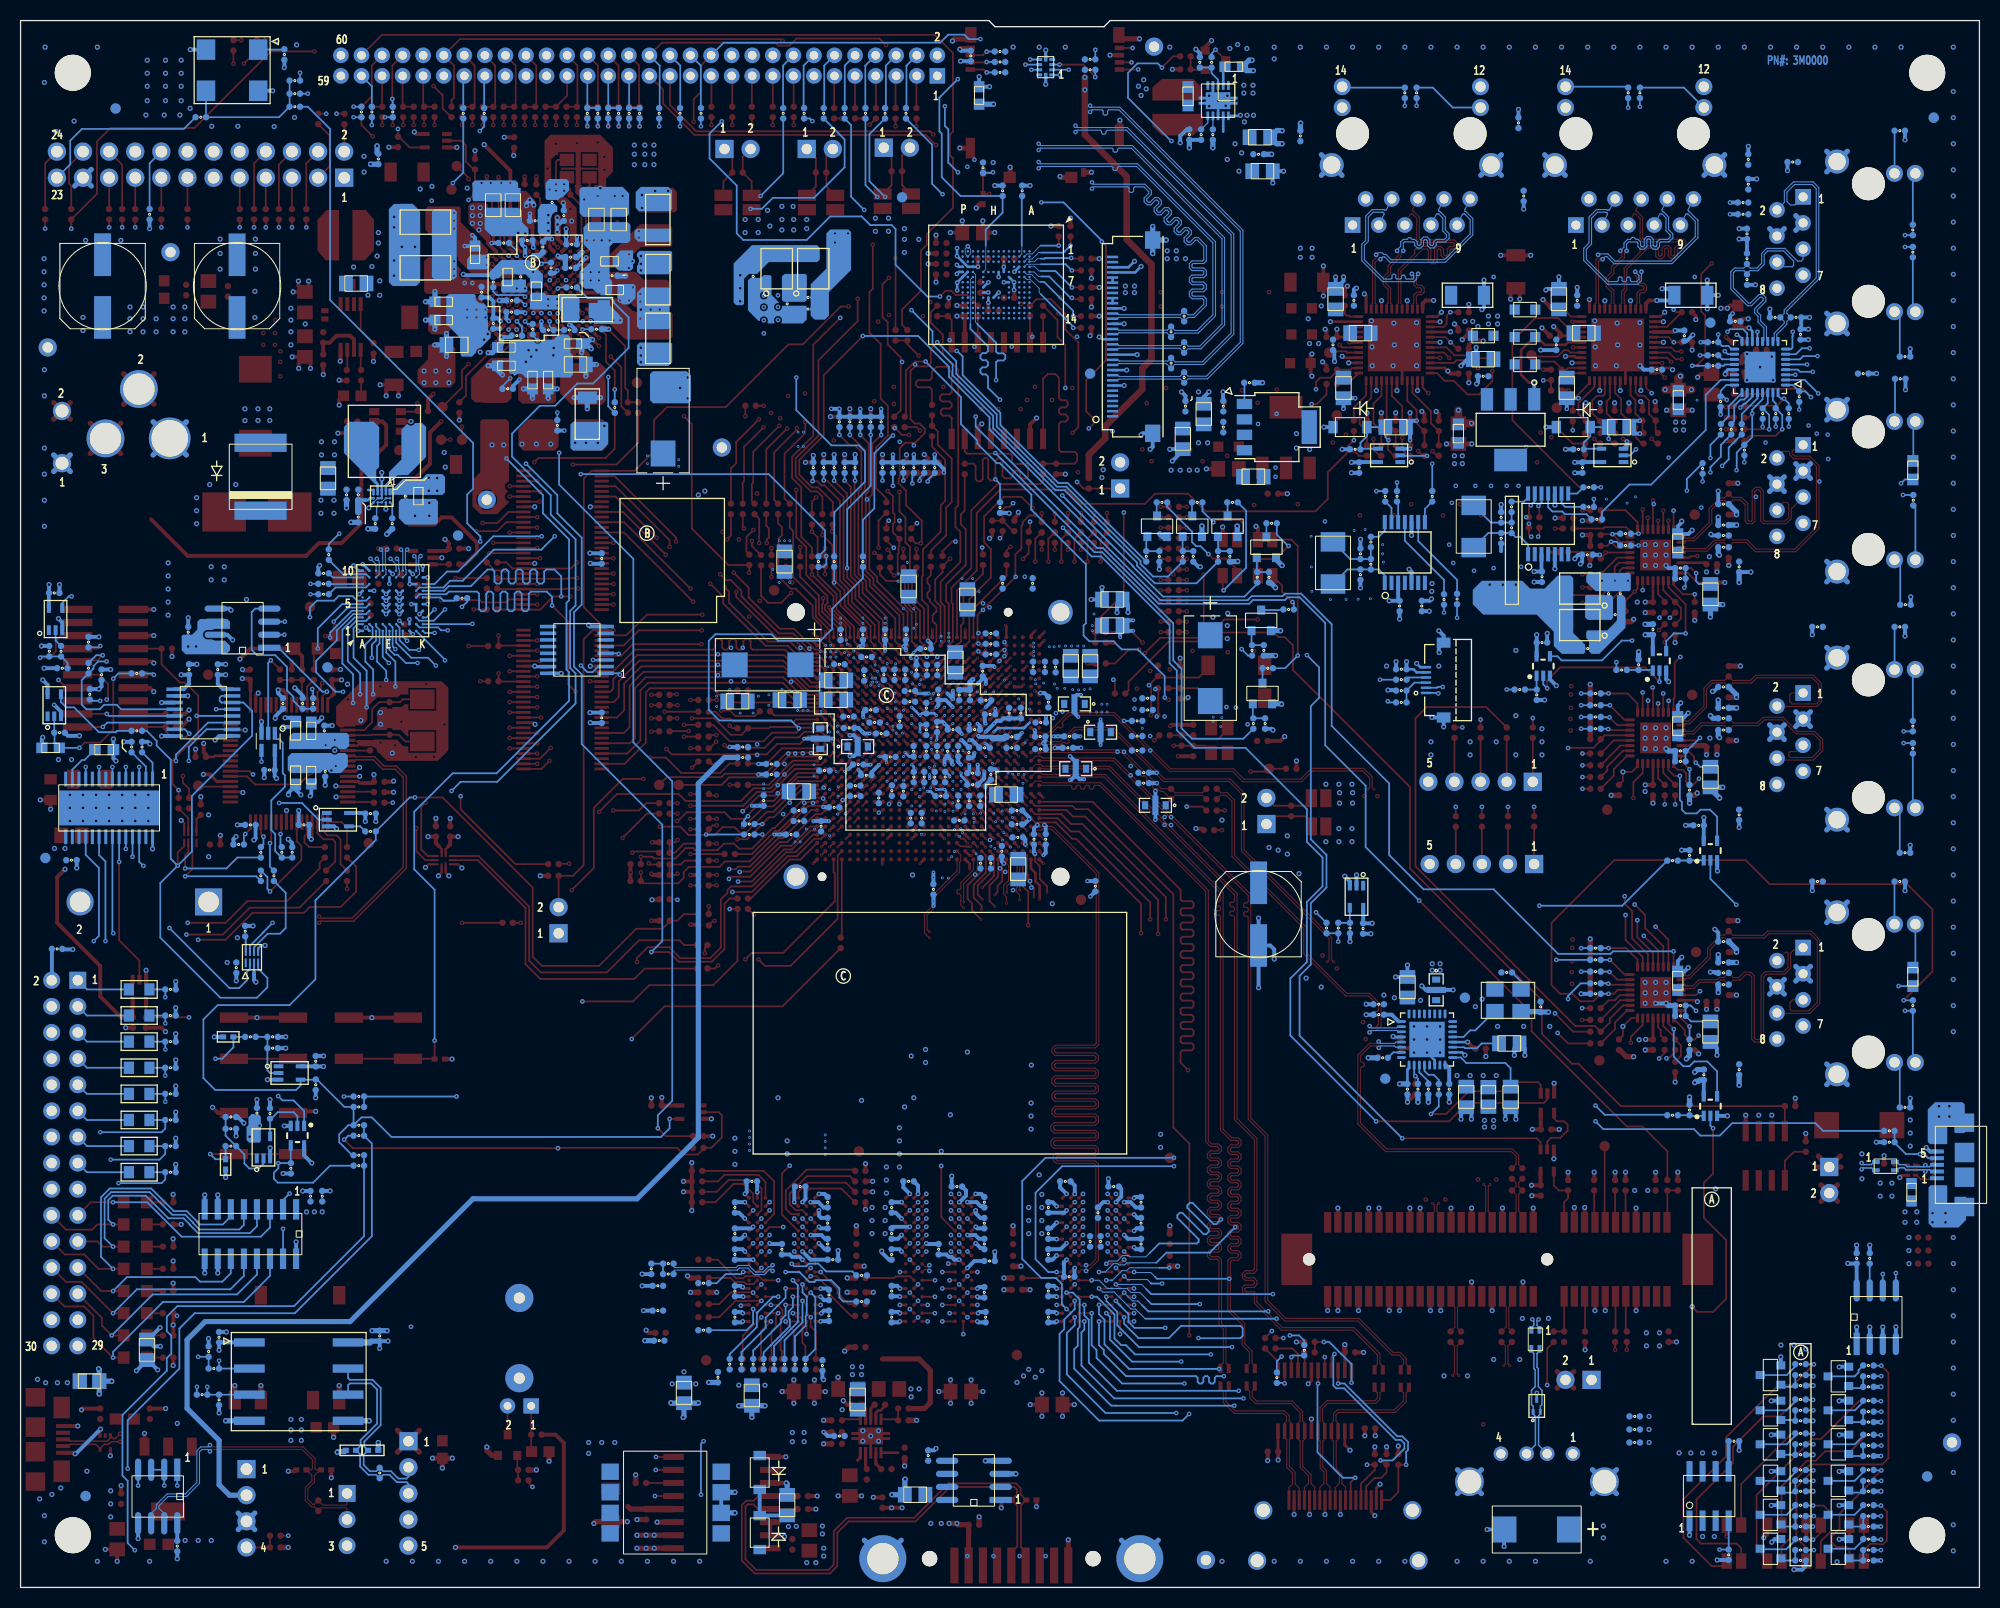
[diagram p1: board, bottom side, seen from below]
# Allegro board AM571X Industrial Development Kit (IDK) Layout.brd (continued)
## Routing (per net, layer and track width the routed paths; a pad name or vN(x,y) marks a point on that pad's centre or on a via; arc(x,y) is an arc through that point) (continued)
N19438972: length 91.4
  TOP w0.173: R583.1 116.41,56.52 127.88,56.52 v8(131.06,53.34)
  L9_SIG3 w0.114: v8(175.26,9.91) 175.26,13.04 172.09,16.21 172.09,19.43 138.18,53.34 v8(131.06,53.34)
  BOTTOM w0.173: v8(175.26,9.91) U77.1
N19438984: length 200.5
  TOP w0.173: R584.1 92.33,102.82 v8(92.33,103.66)
  L3_SIG1 w0.109: v5(176.66,102.19) 166.5,102.19 160.74,107.94 158.86,107.94 154.41,112.39 139.57,112.39 v5(139.07,112.9)
  L10_SIG4 w0.109: v8(92.33,103.66) 92.36,103.66 92.42,103.61 92.76,103.61 92.78,103.62 96.61,103.62 97.61,102.62 100.05,102.62 103.84,106.4 105.64,106.4 108.76,103.28 111.1,103.28 113.04,105.21 113.04,106.54 122.83,116.33 125.86,116.33 127,115.19 127.76,115.19 128.36,115.79 132.17,115.79 134.55,113.41 138.56,113.41 v5(139.07,112.9) ; v5(176.66,102.19) 178.9,99.95 178.9,81.62 176.56,79.27 176.56,67.16 175.51,66.12 175.51,62.61 173.99,61.09 173.99,55.94 173.68,55.63 173.68,26.93 175.15,25.46 175.15,17.08 176.53,15.7 v8(176.53,9.91)
  BOTTOM w0.173: U77.3 U77.2 v8(176.53,9.91)
N19634423: length 2.7
  TOP w0.173: U74.6 R579.2
N19634430: length 168.7
  TOP w0.173: U74.8 v8(128.71,12.7)
  L3_SIG1 w0.109: v8(136.02,108.29) 137.22,107.09 140.31,107.09 140.97,106.43 141.99,106.43 142.11,106.55 143.76,106.55 144.4,107.19 145.67,107.19 146.94,105.92 146.94,105.79 147.75,104.98 153.93,104.98 157.18,101.73 162.94,101.73 v5(164.08,102.87)
  L10_SIG4 w0.109: v5(164.08,102.87) 164.67,102.29 164.67,100.05 165.3,99.42 165.3,88.19 164.67,87.55 164.67,86.18 163.46,84.97 163.46,79.65 158.75,74.94 158.75,74.04 149.1,64.39 149.1,42.42 139.19,32.51 139.19,22.5 129.39,12.7 v8(128.71,12.7)
  BOTTOM w0.173: R574.1 112.27,100.92 112.27,102.81 117.75,108.29 v8(136.02,108.29)
N19634431: length 188.9
  TOP w0.173: R575.1 113.54,105.62 v3(113.13,106.02) ; U74.5 v8(128.81,8.89)
  L3_SIG1 w0.109: v5(162.81,106.89) 161.42,108.28 158.93,108.28 152.91,114.3 149.1,114.3 147.7,115.7 138.93,115.7 v5(137.54,114.3) ; v5(112.43,106.7) 112.49,106.7 113.13,106.06 v3(113.13,106.02)
  L10_SIG4 w0.109: v5(137.54,114.3) 136.65,115.19 133.35,115.19 132.27,116.27 128.08,116.27 127,117.35 125.99,117.35 125.26,116.62 122.43,116.62 119.9,114.09 115.15,114.09 112.9,111.84 112.9,107.17 v5(112.43,106.7) ; v5(162.81,106.89) 166.73,102.97 166.73,89.77 166.38,89.42 166.38,86.93 166.34,86.89 166.34,86.88 164.24,84.77 164.24,79.62 161.82,77.2 161.82,76.52 161.16,75.86 161.16,73.79 150.75,63.38 150.75,41.15 145.31,35.71 145.31,15.27 140.72,10.67 135.46,10.67 133.69,8.89 v8(128.81,8.89)
N19634433: length 163.2
  TOP w0.173: U74.7 v8(128.73,11.43) ; R576.1 v3(120.02,113.92)
  L3_SIG1 w0.109: v3(120.02,113.92) v5(120.78,113.16) ; v5(165.35,102.36) 162.56,105.16 161.04,105.16 160.66,105.54 160.66,106.68 159.77,107.57 158.83,107.57 156.95,109.45 150.47,109.45 149.35,108.33 148.97,108.33 147.83,109.47 143.26,109.47 142.82,109.91 137.09,109.91 136.4,110.6 v5(135.39,110.6)
  L10_SIG4 w0.109: v8(128.73,11.43) 129.34,11.43 132.2,14.3 132.2,14.31 139.83,21.93 139.83,31.39 149.61,41.17 149.61,63.88 159.13,73.41 159.13,74.92 163.85,79.64 163.85,84.81 166.09,87.05 166.09,89.63 165.73,89.99 165.73,101.98 v5(165.35,102.36) ; v5(135.39,110.6) 134.98,111.01 134.98,111.54 134.49,112.02 133.91,112.02 131.09,114.84 122.46,114.84 v5(120.78,113.16)
N19700674: length 3.3
  TOP w0.173: J18.5 v8(182.75,86.23)
  BOTTOM w0.173: R730.1 183.64,86.23 v8(182.75,86.23)
N19795587: length 6.2
  TOP w0.173: U3.B12 143.85,130.34 143.85,131.71 144.65,132.52 144.65,134.96 R425.1
N19795594: length 8.4
  TOP w0.173: v8(146.94,134.96) 146.43,135.46 R428.1 ; U3.C13 v3(144.64,129.53)
  L3_SIG1 w0.109: v3(144.64,129.53) 145.16,130.05 145.16,134.21 145.91,134.96 v8(146.94,134.96)
N19795604: length 5
  TOP w0.173: R430.1 144.02,132.62 143.45,132.05 U3.A12
N19795606: length 1.5
  TOP w0.173: U3.H9 v8(141.44,124.74)
  BOTTOM w0.173: R431.1 141.87,125.18 v8(141.44,124.74)
N19795618: length 2.1
  TOP w0.173: U3.C10 v8(142.24,129.53)
  BOTTOM w0.173: R570.1 142.24,130 v8(142.24,129.53)
N19795620: length 8.7
  TOP w0.173: R571.1 147.19,115.91 147.19,117.81 144.78,120.22 143.56,120.22 U3.N11
N19795629: length 2.2
  TOP w0.173: U3.K10 v8(142.24,123.14)
  BOTTOM w0.173: v8(142.24,123.14) 141.73,122.64 R432.1
N19796448: length 10.6
  TOP w0.173: v3(133.1,119.72) 132.08,118.7 132.08,114.89 R572.1 ; v3(135.86,121.52) 135.86,121.56 U3.M3
  L3_SIG1 w0.109: v3(133.1,119.72) 133.1,120.35 133.87,121.13 135.47,121.13 v3(135.86,121.52)
N19796451: length 15.9
  TOP w0.173: U3.H8 v3(140.64,124.74)
  L3_SIG1 w0.109: v8(133.35,117.73) 133.35,118.46 136.65,121.76 136.76,121.87 139.45,121.87 140.24,122.66 140.24,124.34 v3(140.64,124.74)
  BOTTOM w0.173: R588.1 133.35,114.89 v8(133.35,117.73)
N19923823: length 1
  TOP w0.254: U1.J10 v4(107.03,85.61)
  L3_SIG1 w0.254: v5(107.43,85.86) v4(107.03,85.61)
  vias: v5(110.62,93.05) v5(110.62,92.41) v10(110.11,91.75) v10(110.19,92.16) v11(110.11,91.75) v11(110.19,92.16)
N19923824: length 2.1
  TOP w0.254: U1.J9 v4(107.03,86.41)
  L3_SIG1 w0.254: v5(107.43,86.66) v4(107.03,86.41)
  BOTTOM w0.381: v11(109,91.43) 108.88,91.55 v11(108.58,91.55) C287.1
  vias: v5(108.97,92.66) v5(108.96,92)
N19923825: length 2.2
  TOP w0.254: U1.J16 v4(107.03,80.02)
  L3_SIG1 w0.254: v4(107.03,80.02) v5(107.43,79.77)
  L10_SIG4 w0.254: v11(107.83,80.02) v5(107.43,79.77)
  BOTTOM w0.381: v11(107.83,80.02) 108.51,80.02 C288.1
N19923831: length 1.5
  TOP w0.254: U1.K19 v4(106.23,77.62)
  L3_SIG1 w0.254: v4(106.23,77.62) v5(106.63,77.37)
  L10_SIG4 w0.381: v11(118.24,78.16) v11(118.24,77.68)
  vias: v5(119.1,77.2)
N19923832: length 2.8
  TOP w0.254: U1.K16 v4(106.23,80.02)
  L3_SIG1 w0.254: v4(106.23,80.02) v5(106.63,79.77)
  L10_SIG4 w0.254: v11(107.03,80.02) v5(106.63,79.77)
  BOTTOM w0.381: v11(107.03,80.02) 107.03,79.99 107.75,79.28 C291.1
N19923833: length 2.1
  TOP w0.254: U1.K9 v4(106.23,86.41)
  L3_SIG1 w0.254: v5(106.63,86.66) v4(106.23,86.41)
  BOTTOM w0.381: C290.1 v11(106.43,91.55) v11(106.43,91.09)
  vias: v5(106.65,92.79) v5(106.65,92.16)
N19923834: length 1
  TOP w0.254: U1.J19 v4(107.03,77.62)
  L3_SIG1 w0.254: v4(107.03,77.62) v5(107.43,77.37)
  vias: v5(114.25,74.63) v5(114.63,74.15) v10(114.68,72.52) v10(115.19,72.52) v11(114.68,72.52) v11(115.19,72.52)
N19923844: length 2.8
  TOP w0.254: U1.L9 v4(105.43,86.41)
  L3_SIG1 w0.254: v5(105.83,86.66) v4(105.43,86.41)
  L4_SIG2 w0.381: v5(105.83,86.66) 105.8,86.66 105.46,87
  BOTTOM w0.381: C293.1 104.39,91.78 v11(104.65,91.52) 104.39,91.27 v11(104.39,91.14)
  vias: v5(104.27,92.66) v5(104.27,92.03)
N19923851: length 7.5
  TOP w0.254: U1.Y14 v4(97.44,82.41)
  L3_SIG1 w0.254: v5(97.19,82.02) v4(97.44,82.41)
  L10_SIG4 w0.381: v5(97.19,82.02) 96.91,82.3 93.45,82.3 93.15,82.59 92.69,82.59 v11(91.9,83.39)
  BOTTOM w0.381: v11(91.9,83.39) 91.85,83.34 C298.1
N19923852: length 4.7
  TOP w0.254: U1.Y13 v4(97.44,83.21)
  L3_SIG1 w0.254: v5(97.04,83.46) v4(97.44,83.21)
  L10_SIG4 w0.254: v5(97.04,83.46) 97.36,83.26 v11(97.36,82.83)
  BOTTOM w0.381: v11(97.36,82.83) 97.26,82.73 96.84,82.73 96.84,82.73 96.09,82.73 95.96,82.61
  BOTTOM w0.635: C297.1 94.73,82.73 94.85,82.61 95.96,82.61
N19923853: length 2.2
  TOP w0.254: U1.T20 v4(100.64,76.82)
  L3_SIG1 w0.254: v5(100.97,76.48) 100.95,76.48 100.95,76.5 v4(100.64,76.82)
  BOTTOM w0.381: C296.1 v11(101.73,69.04) v11(101.73,69.55)
N20127658: length 8
  TOP w0.254: U1.AB15 v4(95.84,80.82)
  L3_SIG1 w0.254: v4(95.84,80.82) 95.84,80.82 95.38,81.28
  L3_SIG1 w0.381: v5(90.07,82.3) 90.39,81.97 93.7,81.97 94.39,81.28 95.38,81.28
  BOTTOM w0.381: C403.1 89.61,82.78 v11(89.61,82.78) v11(90.04,82.78)
  vias: v5(82.68,85.85) v5(83.44,85.85) v5(88.37,82.78) v5(89.03,82.78) v6(82.17,86.36) v6(82.17,85.47) v7(82.17,86.36) v7(82.17,85.47)
N20128389: length 5.4
  TOP w0.254: U1.AB13 v4(95.84,83.21)
  L3_SIG1 w0.254: v4(95.84,83.21) 95.93,83.12 v5(96.2,82.9)
  L10_SIG4 w0.254: v11(95.84,83.22) 95.84,83.16 96.15,82.89 v5(96.2,82.9)
  BOTTOM w0.254: 92.35,84.13 92.9,83.58 95.47,83.58 v11(95.84,83.22)
N20144297: length 3.5
  BOTTOM w0.173: U89.A9 160.14,98.24 R637.2
N20190363: length 5.3
  TOP w0.173: R639.4 64.96,76.34 65.28,76.03 C454.2 68.58,76.03 J40.2
N20190375: length 5.4
  TOP w0.173: R639.3 64.96,74.44 65.53,75.01 C454.1 68.58,75.01 J40.1
N20190748: length 5.2
  TOP w0.173: J41.1 105.79,139.27 C455.2 105.79,136.39 R640.3
N20190772: length 5.2
  TOP w0.173: J41.2 104.77,139.27 C455.1 104.77,136.39 R640.4
N20190931: length 5.2
  TOP w0.173: J42.1 113.16,139.02 C456.2 113.16,136.27 R641.3
N20190955: length 5.1
  TOP w0.173: J42.2 112.14,139.27 C456.1 112.14,136.27 R641.4
N20191205: length 5.2
  TOP w0.173: J43.1 121.28,139.15 C457.2 122.15,136.76 R642.3
N20191229: length 5.2
  TOP w0.173: 119.51,139.91 120.27,139.15 C457.1 119.4,136.76 R642.4
N20202943: length 15.7
  TOP w0.173: TP21.1 146.94,137.11 v3(146.94,136.99) ; U3.F8 v3(140.64,127.13)
  L3_SIG1 w0.109: v3(140.64,127.13) 141.48,127.13 141.82,127.47 141.82,130.48 142.62,131.27 142.62,133.43 146.18,136.99 v3(146.94,136.99)
N20204529: length 31
  TOP w0.173: v4(95.84,80.02) 95.44,80.42 U1.AC16 ; v5(74.42,73.66) v3(73.66,73.66)
  L3_SIG1 w0.109: v4(95.84,80.02) 95.3,80.02 v5(95.25,79.96) ; v3(73.66,73.66) v5(74.42,73.66)
  L9_SIG3 w0.114: v5(74.42,73.66) 76.07,75.31 77.47,75.31 77.88,75.72 77.88,79.04 77.52,79.4 77.52,80.42 78.26,81.15 82.52,81.15 83.92,79.76 91.8,79.76 92.61,80.57 93.67,80.57 94.28,79.96 v5(95.25,79.96)
N20275163: length 4.3
  TOP w0.173: C460.1 157.43,122.27 U79.8
N20287248: length 5.6
  TOP w0.381: R648.2 R647.1 160.44,121.07 159.77,121.75 158.46,121.75 158.08,121.37 U79.2
N20287275: length 2
  TOP w0.173: R646.2 157.43,118.44 U79.1
N20287568: length 1.5
  TOP w0.173: C463.1 157.39,115.91 R646.1
N20301491: length 4.1
  TOP w0.173: J52.A1 30.35,35.55 R650.2 R649.1
N20338433: length 4.4
  TOP w0.173: R655.2 R654.1 40.39,24.9 J52.B11
N20537306: length 5.8
  TOP w0.173: U44.2 42.04,43.36 41.67,43.73 40.76,43.73 40.06,44.43 40.06,45.01 40.39,45.34 41.1,45.34 41.36,45.6 U85.4
N20594970: length 2.1
  BOTTOM w0.173: U86.1 71.48,117.15 R678.1
N20595300: length 2
  TOP w0.173: U79.3 158.73,118.46 R679.1
N20631200: length 2.5
  TOP w0.173: 142.11,10.41 142.11,11.43 142.19,11.51 Q16.G
N20664562: length 1.3
  BOTTOM w0.254: 154.61,107.54 154.97,107.18 U62.B1 U62.B2
N20664572: length 3
  BOTTOM w0.102: U62.B3 U62.C4
  BOTTOM w0.13: C417.1 155.88,104.11 155.88,105.01 155.77,105.12 U62.D4 U62.C4 ; U62.A3 U62.B3
N20665027: length 1.5
  BOTTOM w0.254: 156.13,107.66 155.77,107.3 U62.D1 U62.D2
N20706534: length 2.4
  TOP w0.173: U65.7 173.79,75.45 R554.2
N20706536: length 2.7
  TOP w0.173: U65.6 174.19,74.83 R555.2
N20706626: length 11.1
  TOP w0.173: U65.2 173.79,69.88 v8(174.5,69.17)
  BOTTOM w0.173: v8(174.5,69.17) 167.59,69.17 R477.1
N20706635: length 10.4
  TOP w0.173: U65.3 174.19,71.51 174.5,71.2 v8(174.5,69.93)
  BOTTOM w0.173: v8(174.5,69.93) 170.48,69.93 169.42,70.99 167.13,70.99
N20721609: length 2.6
  BOTTOM w0.173: R247.2 R251.2 11.3,9.23 12.51,9.23 Q3.G
N20721766: length 4
  BOTTOM w0.173: Q3.D 12.14,10.37 11.3,11.21 R242.1
N20721850: length 3.9
  BOTTOM w0.173: Q1.D 12.14,3.76 11.3,4.6 11.3,4.7
N20722196: length 12.9
  TOP w0.173: v8(9.55,11.38) 10.24,10.7 10.24,10.54 13.61,7.17 13.61,5.73 14.36,4.97 14.36,4.38 13.92,3.94 12.88,3.94 12.64,3.7 D16.3
  BOTTOM w0.173: v8(9.55,11.38) 10.24,11.38 R242.2
N20722199: length 3.9
  BOTTOM w0.173: R249.1 11.3,7.9 12.14,7.07 Q5.D
N20722204: length 8.1
  TOP w0.173: D16.4 11.24,3.62 10.63,4.23 9.82,4.23 9.77,4.19 9.38,4.19 9.01,4.56 9.01,7.39 v8(9.58,7.96)
  BOTTOM w0.173: v8(9.58,7.96) 10.24,7.96 R249.2
N20722213: length 3.6
  TOP w0.173: v8(9.58,4.65) 10.85,4.65 11.24,5.05 D16.2
  BOTTOM w0.173: R239.2 10.24,4.65 v8(9.58,4.65)
N20722605: length 2.5
  BOTTOM w0.173: Q2.G 19.11,2.62 R246.2 R243.1
N20722618: length 2.5
  BOTTOM w0.173: R254.2 R256.2 19.11,5.92 Q6.G
N20722739: length 2.6
  BOTTOM w0.173: Q4.G 19.11,9.23 17.91,9.23 R252.2 R248.2
N20722773: length 4
  BOTTOM w0.173: Q4.D 18.75,10.37 17.91,11.21 R244.1
N20722790: length 3.9
  BOTTOM w0.173: Q2.D 21.27,3.71 18.8,3.71 17.91,4.6 17.91,4.7
N20722809: length 10.7
  TOP w0.173: v8(16.15,11.38) 17.8,9.74 17.8,4.82 16.83,3.85 D17.3
  BOTTOM w0.173: v8(16.15,11.38) 16.85,11.38 R244.2
N20722811: length 3.9
  BOTTOM w0.173: R250.1 17.91,7.9 18.75,7.07 Q6.D
N20722815: length 7.9
  TOP w0.173: D17.4 15.43,4.48 14.43,5.48 14.43,7.24 15.14,7.96 v8(16.18,7.96)
  BOTTOM w0.173: v8(16.18,7.96) 16.85,7.96 R250.2
N20722821: length 2.5
  TOP w0.173: D17.2 15.43,5.32 16.1,4.65 v8(16.18,4.65)
  BOTTOM w0.173: v8(16.18,4.65) 16.85,4.65 R240.2
N20723137: length 2.5
  BOTTOM w0.173: Q11.G 12.51,12.78 R599.2 R600.1
N20723150: length 2.6
  BOTTOM w0.173: Q10.G 12.51,19.39 11.3,19.39 R595.2 R594.2
N20723271: length 2.5
  BOTTOM w0.173: R590.2 R591.2 12.51,16.08 Q15.G
N20723305: length 3.9
  BOTTOM w0.173: Q15.D 12.11,17.23 11.3,18.03 R589.1
N20723322: length 3.9
  BOTTOM w0.173: Q11.D 12.11,13.92 11.3,14.73 R596.1
N20723341: length 23.5
  TOP w0.173: D18.3 20.64,2.81 21.67,3.84 21.67,8.99 16.62,14.04 16.62,14.12 16.3,14.44 15.41,14.44 11.73,18.12 v8(9.58,18.12)
  BOTTOM w0.173: R589.2 10.24,18.12 v8(9.58,18.12)
N20723343: length 4
  BOTTOM w0.173: Q10.D 12.14,20.53 11.76,20.91 11.76,21.13 R601.1
N20723347: length 28.4
  TOP w0.173: v8(9.55,21.57) 8.85,20.87 8.85,12.58 9.47,11.96 16.44,11.96 18.41,9.99 18.41,4.8 19.24,3.98 D18.4
  BOTTOM w0.173: R601.2 10.27,21.57 v8(9.55,21.57)
N20723353: length 16.2
  TOP w0.173: D18.2 19.24,9.84 16.77,12.31 15.93,12.31 15,13.25 12.53,13.25 10.97,14.81 v8(9.58,14.81)
  BOTTOM w0.173: v8(9.58,14.81) 10.24,14.81 R596.2
N20723697: length 2.5
  BOTTOM w0.173: R514.1 R597.2 19.24,12.91 Q13.G
N20723710: length 2.5
  BOTTOM w0.173: R598.2 R515.2 17.98,16.29 Q12.G
N20723831: length 2.6
  BOTTOM w0.173: Q14.G 19.11,19.51 17.91,19.51 R592.2 R593.2
N20723865: length 4
  BOTTOM w0.173: R603.1 17.91,21.49 18.75,20.66 Q14.D
N20723882: length 4
  BOTTOM w0.173: R604.1 17.91,14.76 18.75,13.92 Q13.D
N20723901: length 29.4
  TOP w0.173: D19.3 24.58,2.47 24.98,2.07 26.03,2.07 28.79,4.83 28.79,8.59 24.65,12.73 24.65,14.59 19.58,19.66 18.14,19.66 v8(16.1,21.7)
  BOTTOM w0.173: v8(16.1,21.7) 16.87,21.7 R603.2
N20723903: length 4
  BOTTOM w0.173: Q12.D 18.76,17.23 17.91,18.08 R602.1
N20723907: length 26.8
  TOP w0.173: D19.4 23.18,3.82 23.62,4.27 27.08,4.27 27.52,4.71 27.52,8.55 23.96,12.11 23.96,13.68 21.01,16.64 19.43,16.64 17.83,18.24 v8(16.18,18.24)
  BOTTOM w0.173: R602.2 16.85,18.24 v8(16.18,18.24)
N20723913: length 13.7
  TOP w0.173: D19.2 23.18,10.05 18.28,14.94 v8(16.18,14.94)
  BOTTOM w0.173: v8(16.18,14.94) 16.85,14.94 R604.2
N20729664: length 1.3
  BOTTOM w0.173: R699.1 80.01,104.25 Q20.D
N20729666: length 11
  TOP w0.173: D22.4 72.2,99.02 73.25,100.08 74.55,100.08 v8(74.98,100.51)
  BOTTOM w0.173: R699.2 78.99,105.11 76.58,102.7 76.58,101.68 76.17,101.27 75.75,101.27 v8(74.98,100.51)
N20729672: length 7.3
  TOP w0.173: v8(74.5,103.61) 74.28,103.82 71.94,103.82 71.59,103.48 71.59,102.74 72.2,102.14 D22.2
  BOTTOM w0.173: R696.2 75.56,104.68 v8(74.5,103.61)
N20729903: length 2.4
  BOTTOM w0.173: Q21.G 77.49,100.81 R698.1 R697.2
N20729915: length 2.7
  BOTTOM w0.173: R695.2 R694.2 81.03,102.11 Q20.G
N20730029: length 2.6
  BOTTOM w0.173: Q22.G 74.04,102.19 R701.2 R700.2
N20730054: length 1.3
  BOTTOM w0.173: Q22.D 73.12,105.51 R693.1
N20730079: length 1.3
  BOTTOM w0.173: R696.1 76.58,104.25 Q21.D
N20730095: length 11.3
  TOP w0.173: D22.3 73.6,97.07 v8(73.51,96.98)
  BOTTOM w0.173: v8(73.51,96.98) 71.32,99.17 71.32,104.72 R693.2
N20730773: length 2.2
  BOTTOM w0.173: R708.1 67.75,95.06 Q23.D
N20730775: length 4.2
  TOP w0.173: D23.4 67.82,97.46 67.82,96.86 v8(66.8,95.84)
  BOTTOM w0.173: v8(66.8,95.84) 66.67,95.71 R708.2
N20730781: length 16.3
  TOP w0.173: v8(66.29,90.63) 66.29,101.3 66.9,101.91 D23.2
  BOTTOM w0.173: R705.2 67.52,89.41 v8(66.29,90.63)
N20730789: length 2.6
  BOTTOM w0.173: R706.2 R707.1 70.66,84.59 Q24.G
N20730805: length 2.6
  BOTTOM w0.173: Q23.G 70.79,91.7 R703.2 R704.2
N20730910: length 2.6
  BOTTOM w0.173: Q25.G 70.28,98.81 R710.2 R709.2
N20730936: length 1.3
  BOTTOM w0.173: Q25.D R702.1
N20730961: length 1.5
  BOTTOM w0.173: R705.1 Q24.D
N20730985: length 7.7
  TOP w0.173: D23.3 70.17,99.71 69.85,100.03 68.45,100.03 v8(67.18,101.3)
  BOTTOM w0.173: v8(67.18,101.3) 67.23,101.3 68.33,102.4 R702.2
N20962931: length 16.2
  TOP w0.173: v8(181.48,88.39) 181.48,83.44 182.75,82.17 184.28,82.17 v8(184.79,81.66)
  BOTTOM w0.173: U19.2 R149.1 187.2,83.11 187.2,82.13 C421.1 v8(184.79,81.66) ; R806.1 180.98,88.9 v8(181.48,88.39)
N21013400: length 8.3
  TOP w0.173: R662.2 117.94,80.14 116.46,81.62 112.64,81.62 U1.B14
N21013403: length 46.7
  TOP w0.173: R663.2 104.77,112.1 v3(104.09,112.1) ; U1.J14 v4(107.03,82.41)
  L3_SIG1 w0.109: v4(107.03,82.41) 107.03,82.42 107.43,82.66 v5(107.43,82.66) ; v5(98.86,112.88) 99.46,112.88 99.54,112.96 103.23,112.96 v3(104.09,112.1)
  L4_SIG2 w0.114: v5(98.86,112.88) 97.55,111.57 97.55,103.89 99.27,102.17 99.76,102.17 100.02,101.91 100.02,101.36 99.64,100.99 99.64,99.49 100.56,98.58 100.56,93.7 102.32,91.94 102.32,85.63 103.04,84.9 103.3,84.65 107.59,84.65 107.82,84.43 107.82,83.05 v5(107.43,82.66)
N21013406: length 44.1
  TOP w0.173: U1.G13 v4(108.63,83.21)
  L3_SIG1 w0.109: v5(109.03,83.46) v4(108.63,83.21)
  L10_SIG4 w0.109: v7(114.81,83.57) 114.3,83.57 113.54,84.33 111.99,84.33 111.66,84 111.3,84 111.15,84.15 110.44,84.15 110.24,83.95 109.52,83.95 v5(109.03,83.46)
  BOTTOM w0.173: v7(114.81,83.57) 115.57,84.33 122.55,84.33 123.57,85.34 123.57,92.08 122.94,92.71 117.47,92.71 116.84,92.08 112.72,92.08 111.58,93.22 111.58,95.18 108.58,98.17 R664.2
N21013409: length 40.9
  TOP w0.173: R665.2 103.38,112.86 v3(103.03,112.51) ; U1.J11 v4(107.03,84.81)
  L3_SIG1 w0.109: v5(107.43,85.06) v4(107.03,84.81) ; v3(103.03,112.51) 102.88,112.36 v5(99.43,112.36)
  L4_SIG2 w0.114: v5(107.43,85.06) 107.04,85.45 103.29,85.45 102.54,86.21 102.54,92.15 100.81,93.88 100.81,96.67 100.99,96.85 100.99,98.89 100.54,99.35 100.54,101.8 99.88,102.46 99.39,102.46 97.84,104.01 97.84,110.77 v5(99.43,112.36)
N21036262: length 61.9
  TOP w0.173: v8(99.58,101.73) 99.89,101.73 100.84,100.79 R686.2
  L4_SIG2 w0.114: v8(99.58,101.73) 99.29,101.73 96.39,104.63 96.39,120.86 93.31,123.94 93.31,130.72 101.98,139.39 101.98,145.26 102.34,145.62 102.34,148.01 J21.4
  BOTTOM w0.173: J21.4 104.35,148.02 104.35,143.94 R877.2
N21036269: length 63.9
  TOP w0.173: 103.38,100.2 v3(103.38,101)
  L3_SIG1 w0.109: v3(103.38,101) v5(103.38,100.28)
  L4_SIG2 w0.114: v5(103.38,100.28) 101.42,100.28 101.14,100.56 101.14,102.67 98.13,105.68 98.13,110.38 99.92,112.17 99.92,112.71 98.02,114.62 98.02,129.37 97.84,129.55 97.84,133.72 102.31,138.19 102.31,141.21 104.37,143.27 104.37,148.05 J21.6
  BOTTOM w0.173: R878.2 106.35,143.97 106.35,148.02 J21.6
N21036279: length 64.2
  TOP w0.173: 104.65,100.2 v3(104.65,101)
  L3_SIG1 w0.109: v3(104.65,101) v5(104.65,100.28)
  L4_SIG2 w0.114: v5(104.65,100.28) 104.65,100.63 102.92,102.36 101.9,102.36 98.42,105.84 98.42,110.25 100.22,112.04 100.22,112.84 98.31,114.74 98.31,129.31 98.91,129.9 98.91,131.8 99.47,132.36 99.47,133.81 102.67,137.01 102.67,140.62 106.37,144.33 106.37,148.05 J21.8
  BOTTOM w0.173: J21.8 108.35,148.02 108.35,143.91 R880.2
N21036281: length 66.1
  TOP w0.173: 105.92,100.2 105.92,100.67 v3(106.17,100.92)
  L3_SIG1 w0.109: v5(105.6,100.09) 105.6,100.35 v3(106.17,100.92)
  L4_SIG2 w0.114: v5(105.6,100.09) 102.92,102.77 102.08,102.77 98.72,106.13 98.72,110.13 100.51,111.92 100.51,112.96 98.63,114.83 98.63,127.51 99.28,128.16 99.6,128.16 99.84,128.4 99.84,131.29 99.56,131.57 99.56,131.99 100.34,132.77 100.34,134.26 105.16,139.08 105.16,142.55 108.32,145.71 108.32,147.99 J21.10
  BOTTOM w0.173: R879.2 110.35,143.91 110.35,148.02 J21.10
N21036293: length 61.1
  TOP w0.173: R692.2 103.37,103.51 v8(103.33,103.51)
  L4_SIG2 w0.114: J21.12 110.32,147.99 110.32,144.41 107.9,141.99 107.9,139.71 106.8,138.62 105.27,138.62 100.67,134.01 100.67,131.1 100.33,130.76 100.33,126.26 99.71,125.64 99.71,125.15 100.2,124.66 100.2,121.04 101.09,120.15 101.09,111.68 99.3,109.89 99.3,106.59 101.9,103.99 102.53,103.99 103.02,103.5 103.31,103.5 v8(103.33,103.51)
  BOTTOM w0.173: J21.12 112.35,148.02 112.35,143.94 R874.2
N21036295: length 67.2
  TOP w0.173: 106.93,100.2 107.36,100.63 v3(107.47,100.63)
  L3_SIG1 w0.109: v3(107.47,100.63) 107.47,100.62 107.09,100.24 v5(107.09,100.06)
  L4_SIG2 w0.114: J21.14 112.32,147.99 112.32,145.99 108.19,141.87 108.19,139.59 106.93,138.33 105.39,138.33 100.96,133.89 100.96,130.28 100.96,126.73 101.6,126.09 101.6,123.66 100.91,122.97 100.91,120.75 101.38,120.27 101.38,111.56 99.59,109.77 99.59,106.81 102.08,104.32 102.61,104.32 102.98,103.95 103.51,103.95 107.09,100.37 v5(107.09,100.06)
  BOTTOM w0.173: J21.14 114.35,148.02 114.35,143.94 R875.2
N21036304: length 64.8
  TOP w0.173: R733.2 106.3,103.53 v8(106.07,103.76)
  L4_SIG2 w0.114: J21.16 114.32,147.99 114.32,146.62 112.33,144.63 111.37,144.63 108.48,141.74 108.48,139.47 107.05,138.03 105.51,138.03 102.05,134.57 102.05,130.96 101.3,130.2 101.3,128.22 101.99,127.52 101.99,126.74 101.89,126.65 101.89,120.81 101.68,120.6 101.68,111.44 99.89,109.65 99.89,106.97 102.18,104.67 102.67,104.67 103.03,104.32 103.55,104.32 104.62,103.25 105.56,103.25 v8(106.07,103.76)
  BOTTOM w0.173: J21.16 116.35,148.02 116.35,143.9 R876.2
N21036311: length 88.5
  TOP w0.173: R689.2 104.77,122.81 104.77,124.29 102.95,126.12 102.95,130.02 102.36,130.61 102.36,131.65 99.82,134.19 99.82,138.99 100.13,139.29 100.13,141.3 99.82,141.61 99.82,149.23 101.59,151 155.36,151 J21.58
N21036394: length 46.2
  TOP w0.173: v3(103.15,119.81) 104.27,120.92 R689.1 R925.1 ; U1.P7 v4(103.03,88.01)
  L3_SIG1 w0.109: v5(103.43,88.26) 103.43,88.26 v4(103.03,88.01) ; v5(103.79,120.1) 103.5,119.81 v3(103.15,119.81)
  L4_SIG2 w0.114: v5(103.43,88.26) 102.87,88.83 102.87,93.5 102.44,93.93 102.44,94.64 103.05,95.25 103.05,96.44 103.71,97.1 103.71,98.3 104.74,99.33 107.47,99.33 107.82,99.67 107.82,101.73 106.8,102.75 106.8,104.08 106.1,104.77 104.65,104.77 103.66,105.76 102.59,105.76 101.26,107.09 101.26,109.79 102.55,111.08 102.55,117.47 103.79,118.71 v5(103.79,120.1)
N21036619: length 94.9
  TOP w0.173: R734.2 v8(105.03,103.76)
  L4_SIG2 w0.114: J21.52 149.9,150.47 135.42,150.47 134.37,149.42 134.37,148.62 133.76,148.01 116.96,148.01 116.32,147.37 116.32,146.62 113.36,143.66 110.82,143.66 108.78,141.62 108.78,139.34 107.18,137.74 105.64,137.74 102.34,134.45 102.34,130.84 101.59,130.08 101.59,128.41 102.28,127.71 102.28,120.45 103.05,119.68 103.05,118.8 101.97,117.72 101.97,111.32 100.18,109.53 100.18,107.14 102.29,105.03 103.25,105.03 104.52,103.76 v8(105.03,103.76)
N21099488: length 6
  BOTTOM w0.083: U43.C2 93.13,129.7 93.13,130.51
  BOTTOM w0.173: 93.13,130.51 93.13,135.29 C265.1
N21180149: length 15.6
  TOP w0.173: U1.B15 112.64,80.81 115.87,80.81 117.89,78.8 121.58,78.8 122.32,78.06 TP22.1
N21180152: length 16.7
  TOP w0.173: TP23.1 127.64,78.82 122.33,78.82 122,79.15 118.03,79.15 115.97,81.21 U1.A15
N21306186: length 8.5
  TOP w0.173: TP24.1 v8(162.36,94.37)
  BOTTOM w0.173: v8(162.36,94.37) 162.36,95.31 161.68,95.98 160.01,95.98 159.56,96.42 158.2,96.42 157.76,95.98 156.89,95.98 U89.B6
N21306311: length 3.3
  BOTTOM w0.173: U89.A8 160.5,97.59 R567.1
N21306314: length 4.4
  BOTTOM w0.173: U89.B8 156.91,97.26 159.87,97.26 R585.1
N21307911: length 3.5
  BOTTOM w0.173: R586.1 148.34,95.97 149.35,95.97 149.68,96.29 U89.K6
N21605448: length 5.3
  TOP w0.508: J50.1 15.67,41.96 ; J50.1 13.54,41.96 ; J50.1 15.75,40.89 ; J50.1 13.46,40.89
N21620210: length 26.9
  L10_SIG4 w0.109: v7(178.96,79.8) 178.76,79.6 178.76,71.98 177.13,70.35 177.13,61.79 176.43,61.09 v7(176.43,57.4)
  BOTTOM w0.173: U72.3 v7(178.96,79.8) ; R368.2 C197.1 v7(176.43,57.4)
N21620213: length 30
  L10_SIG4 w0.109: v7(176.43,54.86) 177.17,55.6 177.17,60.58 177.93,61.34 177.93,66.67 179.07,67.82 179.07,71.26 180.09,72.27 180.09,79.62 v7(180.26,79.8)
  BOTTOM w0.173: v7(176.43,54.86) C198.1 R370.2 ; U72.5 v7(180.26,79.8)
N21620216: length 33.6
  L10_SIG4 w0.109: v7(181.56,79.8) 181.23,79.47 181.23,73.91 180.89,73.57 180.89,71.51 180.11,70.73 180.11,67.08 178.31,65.28 178.31,60.96 177.67,60.32 177.67,58.88 178.31,58.25 178.31,54.2 v7(176.43,52.32)
  BOTTOM w0.173: U72.7 v7(181.56,79.8) ; R372.2 C199.1 v7(176.43,52.32)
N21620219: length 36.2
  L10_SIG4 w0.109: v7(182.86,79.8) 182.5,79.44 182.5,73.91 182.25,73.66 182.25,71.56 181.61,70.93 181.61,66.76 179.18,64.32 179.18,52.53 v7(176.43,49.78)
  BOTTOM w0.173: R374.2 C200.1 v7(176.43,49.78) ; U72.9 v7(182.86,79.8)
N21620222: length 39.2
  L10_SIG4 w0.109: v7(184.16,79.8) 183.77,79.41 183.77,74.17 183.64,74.04 183.64,71.66 182.75,70.77 182.75,66.38 180.34,63.96 180.34,55.22 179.71,54.59 179.71,50.52 v7(176.43,47.24)
  BOTTOM w0.173: v7(176.43,47.24) C201.1 R373.2 ; U72.11 v7(184.16,79.8)
N21620225: length 38.9
  L10_SIG4 w0.109: v7(183.39,62.86) 183.39,51.66 182.37,50.65 182.37,44.66 v7(182.75,44.28)
  BOTTOM w0.173: R375.2 C202.1 176.43,44.63 176.78,44.28 v7(182.75,44.28) ; U72.18 184.16,71.26 182.88,69.98 182.88,63.37 v7(183.39,62.86)
N21620228: length 39.7
  L10_SIG4 w0.109: v7(181.74,41.61) 181.74,50.63 182.25,51.14 v7(182.25,62.86)
  BOTTOM w0.173: v7(181.74,41.61) 176.98,41.61 176.43,42.16 C203.1 R376.2 ; U72.20 182.86,71.23 182.25,70.61 v7(182.25,62.86)
N21620231: length 40.9
  L10_SIG4 w0.109: v7(180.98,39.32) 180.98,50.88 181.48,51.39 v7(181.48,63.63)
  BOTTOM w0.173: U72.22 181.56,63.71 v7(181.48,63.63) ; R378.2 C204.1 176.43,39.68 176.78,39.32 v7(180.98,39.32)
N21685968: length 1
  TOP w0.254: U1.K14 v4(106.23,82.41)
  L3_SIG1 w0.254: v4(106.23,82.41) v5(106.63,82.66)
  vias: v5(116.84,82) v5(117.86,82) v6(118.87,82) v6(118.87,80.98) v7(118.87,82) v7(118.87,80.98)
N21685998: length 3.4
  TOP w0.173: J46.4 R798.2 R638.1
N21984965: length 1.8
  BOTTOM w0.173: U78.2 187.1,92.1 R429.1
N21986708: length 3.1
  TOP w0.173: J18.4 R587.1
N21987254: length 3.2
  TOP w0.173: J18.10 v8(177.55,88.77)
  BOTTOM w0.173: R806.2 177.67,88.9 v8(177.55,88.77)
N22242148: length 8.9
  TOP w0.173: U1.V2 99.04,92.01 99.04,93.58 98.81,93.81 98.81,96.7 96.9,98.6 R660.2
N22242162: length 8.4
  TOP w0.173: R659.2 94.61,98.41 97.83,95.19 U1.Y1
N22688543: length 6.3
  TOP w0.173: R428.2 R835.2 146.43,137.92 147.19,138.68 147.19,140.26 147.65,140.72 U96.2
N22817064: length 6.5
  TOP w0.169: 130.35,145.92 130.35,148.02 J21.32
  TOP w0.173: 130.35,145.92 130.35,144.06 R846.2 R838.2
N22817067: length 6.4
  TOP w0.169: R847.2 132.35,144.03 132.35,148.02 J21.34
  TOP w0.173: R847.2 R839.2
N22817070: length 6.4
  TOP w0.169: J21.36 134.35,148.02 134.35,144.04 R848.2
  TOP w0.173: R840.2 R848.2
N22817073: length 6.5
  TOP w0.169: R849.2 136.35,144.07 136.35,148.02 J21.38
  TOP w0.173: R841.2 R849.2
N22817076: length 6.5
  TOP w0.169: R850.2 140.35,144.13 140.35,148.02 J21.42
  TOP w0.173: R842.2 R850.2
N22817095: length 6.5
  TOP w0.169: R851.2 142.35,144.17 142.35,148.02 J21.44
  TOP w0.173: R843.2 R851.2
N22817104: length 6.5
  TOP w0.169: R852.2 144.35,144.2 144.35,148.02 J21.46
  TOP w0.173: R844.2 R852.2
N22817113: length 6.5
  TOP w0.169: J21.48 146.35,148.02 146.35,144.23 R853.2
  TOP w0.173: R845.2 R853.2
N22829911: length 4.3
  TOP w0.254: U3.K12 143.81,123.17 v8(143.83,123.17)
  BOTTOM w0.381: v8(143.83,123.17) 144.1,123.44 C562.1 144.53,125.09 144.91,125.48 R854.2
N22843188: length 6.2
  TOP w0.169: R855.2 154.34,144.06 v8(154.34,144.78) 154.34,148.02 J21.54
  BOTTOM w0.173: R855.2 154.31,144.74 v8(154.34,144.78)
N22843197: length 7.4
  TOP w0.169: R856.2 156.34,145.03 156.34,148.02 J21.56
  TOP w0.173: v8(158.12,144.02) R856.2
  BOTTOM w0.173: R856.2 v8(158.12,144.02)
N22941894: length 4.1
  TOP w0.173: R857.1 R871.1 151.35,144.11 J21.51
N22941897: length 4
  TOP w0.173: J21.53 153.35,144.07 R872.1 R858.1
N22941900: length 4
  TOP w0.173: R859.1 R873.1 155.35,144.04 J21.55
N22942582: length 4.2
  BOTTOM w0.173: R861.1 R865.1 131.32,146.99 J21.31
N22942589: length 4.1
  BOTTOM w0.173: R866.1 R862.1 133.35,147.02 J21.33
N22942599: length 4.2
  BOTTOM w0.173: R867.1 R863.1 135.38,146.98 J21.35
N22942601: length 4.5
  TOP w0.173: R868.1 R864.1 137.35,145.1 J21.37
N22982995: length 269
  TOP w0.173: R884.2 v3(91.19,100.94)
  L3_SIG1 w0.109: v3(91.19,100.94) v5(91.19,101.52)
  L4_SIG2 w0.114: v5(108.46,150.01) 124.37,150.01 125.35,149.04 J21.26
  L10_SIG4 w0.109: v5(91.19,101.52) 90.8,101.14 89.76,101.14 87.76,103.13 83.6,103.13 78.96,107.77 70.78,107.77 68.73,109.82 62.03,109.82 61.33,110.52 56.78,110.52 54.36,108.11 52.82,108.11 52.32,108.62 43.77,108.62 43.05,107.9 38.43,107.9 37.58,108.75 35.95,108.75 34.64,107.43 34.25,107.05 31.86,107.05 30.99,106.18 28.97,106.18 28.75,105.96 26.88,105.96 26.21,105.29 26.21,104.72 25.91,104.42 25.91,103.88 25.61,103.58 25.07,103.58 23.98,102.49 22.33,102.49 20.43,100.59 17.8,100.59 14.22,104.17 14.22,109.96 15.24,110.98 15.24,113.68 15.45,113.89 15.45,115.23 9.52,121.16 6.48,121.16 4.57,123.06 4.57,141.48 11.25,148.15 65,148.15 69,144.15 72.15,144.15 73.04,143.26 80.81,143.26 83.78,146.23 85.64,146.23 85.74,146.13 89.49,146.13 90.25,146.89 96.31,146.89 96.9,146.3 97.65,146.3 99.33,147.98 105.66,147.98 106.43,148.74 106.43,149.4 107.04,150.01 v5(108.46,150.01)
  BOTTOM w0.173: R888.2 124.35,143.9 124.35,148.02 J21.26
N22983025: length 263.6
  TOP w0.173: R885.2 v3(87.38,100.94)
  L3_SIG1 w0.109: v3(87.38,100.94) v5(87.38,101.52)
  L4_SIG2 w0.114: J21.28 125.9,150.47 102.79,150.47 v5(102.41,150.09)
  L10_SIG4 w0.109: v5(102.41,150.09) 102.01,150.5 100.69,150.5 100.05,149.86 99.64,149.86 99.31,150.2 98.63,150.2 97.31,148.87 93.07,148.87 92.89,149.05 92.12,149.05 91.64,148.56 87.58,148.56 86.35,147.34 85.81,147.34 85.62,147.15 80.7,147.15 79.51,145.96 72.87,145.96 72.34,145.42 72.34,145.39 71.68,144.73 69.24,144.73 65.24,148.73 10.93,148.73 3.93,141.73 3.93,113.57 17.54,99.96 20.69,99.96 22.59,101.87 24.24,101.87 25.39,103.01 25.85,103.01 26.49,103.64 26.49,104.11 26.93,104.55 27.25,104.55 28.09,105.38 28.99,105.38 29.15,105.55 31.17,105.55 32.09,106.47 34.57,106.47 36.18,108.09 37.35,108.09 38.11,107.33 43.29,107.33 43.93,107.96 51.96,107.96 52.46,107.45 54.72,107.45 55.87,108.6 60.08,108.6 61.1,107.58 67.95,107.58 68.34,107.19 78.74,107.19 83.36,102.56 86.34,102.56 v5(87.38,101.52)
  BOTTOM w0.173: J21.28 126.35,148.02 126.35,143.91 R889.2
N22983056: length 268.6
  TOP w0.173: v3(106.32,150.01) 106.96,150.65 115.03,150.65 115.72,149.96 116.82,149.96 117.1,150.25 128.12,150.25 J21.30 ; R886.2 v3(88.65,100.94)
  L3_SIG1 w0.109: v3(88.65,100.94) v5(88.65,101.52) ; v5(104.34,150.01) v3(106.32,150.01)
  L10_SIG4 w0.109: v5(88.65,101.52) 87.32,102.85 83.48,102.85 78.84,107.49 70.66,107.49 68.61,109.53 61.92,109.53 61.21,110.24 56.9,110.24 54.48,107.82 52.7,107.82 52.2,108.33 43.89,108.33 43.17,107.61 38.31,107.61 37.46,108.46 36.07,108.46 34.92,107.31 34.92,107.31 34.37,106.76 31.98,106.76 31.1,105.89 29.09,105.89 28.87,105.67 27,105.67 26.56,105.24 26.56,104.67 26.2,104.3 26.2,103.76 25.73,103.3 25.19,103.3 24.1,102.21 22.45,102.21 20.55,100.3 17.68,100.3 4.22,113.77 4.22,141.61 11.05,148.44 65.12,148.44 69.12,144.44 71.8,144.44 72.62,145.27 72.62,145.3 72.99,145.67 80.26,145.67 81.32,144.6 81.75,144.6 83.73,146.58 85.69,146.58 85.86,146.42 89.37,146.42 90.13,147.18 92.67,147.18 93.37,147.88 97.38,147.88 98.5,149 99.68,149 100.69,150.01 101.87,150.01 102.23,149.65 102.59,149.65 102.95,150.01 v5(104.34,150.01)
  BOTTOM w0.173: J21.30 128.35,148.02 128.35,143.94 R890.2
N22983147: length 172.2
  TOP w0.173: R891.2 148.59,144.65 148.35,144.9 148.35,148.02 J21.50 147.77,150.6 116.56,150.6 v3(116.4,150.43) ; R887.2 v3(38.35,109.55)
  L3_SIG1 w0.109: v5(87.04,149.74) 87.77,150.47 96.6,150.47 97.18,151.05 115.77,151.05 v3(116.4,150.43) ; v3(38.35,109.55) v5(38.35,110.19)
  L4_SIG2 w0.114: v5(38.35,110.19) 35.76,110.19 34.06,111.89 31.93,111.89 31.24,111.2 28.45,111.2 25.68,113.97 25.68,120.75 25.86,120.93 25.86,121.67 26.67,122.48 26.67,123.14 27.99,124.46 27.99,126.88 29.64,128.54 33.59,128.54 34.42,127.71 37.31,127.71 37.62,128.02 47.42,128.02 48.29,128.89 52.84,128.89 54.4,127.33 59.23,127.33 65.07,133.17 67.89,133.17 71.62,136.91 78.16,136.91 81.46,140.21 81.46,144.15 v5(87.04,149.74)
N22983150: length 297.5
  TOP w0.173: R892.2 v3(166.75,150.5) ; R881.2 v3(84.84,100.94)
  L3_SIG1 w0.109: v3(166.75,150.5) 166.32,150.93 119.25,150.93 J21.18 ; v3(84.84,100.94) v5(84.84,101.52)
  L10_SIG4 w0.109: J21.18 115.31,151.05 96.88,151.05 96.15,150.33 87.01,150.33 86.7,150.01 84.15,150.01 83.99,150.17 82.18,150.17 81.92,149.92 81.92,149.54 79.4,147.02 67.76,147.02 65.48,149.3 10.62,149.3 3.36,142.04 3.36,113.23 17.27,99.31 20.95,99.31 22.86,101.22 24.51,101.22 24.93,101.63 26.46,101.63 27.23,102.41 27.23,103.71 27.81,104.29 29.93,104.29 30.54,104.9 31.04,104.9 31.35,104.59 33.95,104.59 34.66,105.3 34.66,105.66 36.45,107.44 37.08,107.44 37.97,106.55 54.74,106.55 56.13,107.95 59.82,107.95 60.83,106.93 67.56,106.93 68.04,106.46 78.65,106.46 83.59,101.52 v5(84.84,101.52)
N22983153: length 308.6
  TOP w0.173: R893.2 v3(169.04,150.5) ; R882.2 v3(89.92,100.94)
  L3_SIG1 w0.109: v5(82.96,141.58) 83.24,141.86 93.18,141.86 93.91,142.59 99.75,142.59 102.72,145.57 113.61,145.57 114.38,146.33 114.38,147.35 115.03,148.01 v5(115.93,148.01) ; v3(89.92,100.94) v5(89.92,101.52) ; v3(169.04,150.5) v5(168.4,150.5)
  L10_SIG4 w0.109: v5(89.92,101.52) 88.02,103.42 83.72,103.42 81.41,105.73 81.41,107.44 78.74,110.11 64.29,110.11 63.14,111.25 61.47,111.25 61.09,110.87 57.57,110.87 56.18,112.27 49.16,112.27 48.96,112.07 38.87,112.07 34.13,107.33 31.74,107.33 30.87,106.46 28.85,106.46 28.63,106.24 26.76,106.24 24.89,104.37 24.89,103.81 23.86,102.78 22.21,102.78 20.31,100.88 17.92,100.88 14.9,103.9 14.9,109.26 16.1,110.47 16.1,111.45 17.18,112.52 17.18,114.01 15.24,115.95 9.74,121.45 6.6,121.45 4.86,123.18 4.86,141.36 11.37,147.87 64.88,147.87 68.88,143.87 72.03,143.87 72.92,142.98 81.56,142.98 v5(82.96,141.58) ; v5(115.93,148.01) 118.34,148.01 119.35,149.01 J21.20 121.31,150.99 167.91,150.99 v5(168.4,150.5)
N23074888: length 3.4
  BOTTOM w0.173: J21.57 156.34,146.01 R860.1
N23239351: length 2.6
  BOTTOM w0.173: X1.1 164.88,149.57 R902.1
N23239414: length 17.3
  BOTTOM w0.173: J9.23 185.67,138.41 185.67,140.72 184.53,141.86 174.62,141.86 R903.1
N23403418: length 8
  BOTTOM w0.173: 170.56,45.76 170.56,43.94 R12.1 168.73,42.11 168.73,41.23 168.25,40.75 167.36,40.75 166.88,41.23 U2.2
N23403425: length 11
  TOP w0.173: v8(172.05,42.15) SW1.4 SW1.3
  BOTTOM w0.173: v8(172.05,42.15) 171.55,41.65 U49.1 170.56,42.93
N23403875: length 111.7
  L4_SIG2 w0.114: v8(148.59,77.47) 149.1,77.47 166.94,59.63 166.94,50.87 165.44,49.38 v8(165.44,47.79)
  BOTTOM w0.173: R9.2 135.35,125.4 133.1,125.4 132.78,125.07 132.78,124.94 131.37,123.53 131.37,120.55 134.83,117.09 136.36,117.09 138.52,114.93 140,114.93 142.71,112.22 142.71,110 138.94,106.23 138.94,104.35 136.53,101.93 136.53,95.5 137.06,94.97 137.06,89.43 136.53,88.9 136.53,85.98 144.15,78.36 147.7,78.36 v8(148.59,77.47) ; v8(165.44,47.79) 165.02,47.37 163.96,47.37 162.93,46.34 U98.1
N23404270: length 5.8
  BOTTOM w0.173: U2.4 166.24,43.89 R912.1 166.12,45.59 165.48,46.23 163.96,46.23 163.58,45.85 U98.2
N23423235: length 33
  TOP w0.173: U100.8 145.95,71.14 141.04,66.23 141.04,60.96 139.9,59.82 133.48,59.82 130.35,62.95 126.42,62.95 125.95,62.48 R487.2
N23423238: length 32.1
  TOP w0.173: R486.2 129.79,60.2 130.81,59.18 139.95,59.18 141.39,60.62 141.39,66.08 146.05,70.74 U100.9
N23520464: length 2.8
  TOP w0.173: U105.4 156.84,112.46 157.04,112.27 C583.1 R927.1
N23520486: length 1.8
  TOP w0.173: TP27.1 151.83,112.46 U105.3

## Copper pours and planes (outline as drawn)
AGND_GBETH0 on BOTTOM: 23.51,136.72 42.67,136.72 43.92,135.46 44.58,135.46 44.83,135.72 44.83,136.48 43.89,137.42 43.89,140.47 43.31,141.05 25.02,141.05 22.73,138.77 22.35,138.77 22.1,138.51 22.1,138.13
AGND_GBETH1 on BOTTOM: 45.72,136.72 64.9,136.72 66.55,138.37 66.55,140.78 66.29,141.03 46.48,141.03 45.21,142.3 44.58,142.3 44.32,142.05 44.32,138.11
AGND_PROFI on BOTTOM: 79.37,1.27 77.72,2.92 77.72,4.95 79.76,6.99 85.72,6.99 87.38,5.33 103.12,5.33 103.76,5.97 103.76,7.49 104.52,8.25 106.81,8.25 109.47,5.59 109.47,1.78 108.97,1.27
AGNDFRAME_PRU1ETH0 on BOTTOM: 12.07,120.86 14.61,120.86 15.11,121.37 15.11,137.37 16,138.26 17.78,138.26 18.03,138.51 18.03,140.8 16.64,142.19 12.32,142.19 11.68,141.56 11.68,121.24
AGNDFRAME_PRU1ETH1 on BOTTOM: 13.08,97.11 15.05,97.11 15.56,97.62 15.49,115.02 15.49,118.13 15.18,118.45 12.57,118.45 12.52,118.5 11.76,118.5 11.51,118.24 11.51,117.33 12.12,116.72 12.13,116.72 12.13,98.06
AGNDFRAME_PRU2ETH0 on BOTTOM: 12.45,72.85 14.8,72.85 15.3,73.36 15.3,90.76 15.56,91.01 15.56,93.87 15.24,94.19 12.19,94.19 11.87,93.87 11.87,73.42
AGNDFRAME_PRU2ETH1 on BOTTOM: 12.57,48.47 14.86,48.47 15.37,48.98 15.37,66.38 15.62,66.63 15.62,69.17 14.99,69.8 12.57,69.8 11.94,69.17 11.94,49.1
DGND on TOP (solid shape): 159.82,85.67 159.82,83.95 159.51,83.64 159.08,83.64 158.91,83.8 158.69,83.86 157.27,83.86 156.78,84.35 156.78,85.62 155.82,86.58 154.66,86.58 154.61,86.58 154.56,86.58 153.81,86.58 153.53,86.85 152.79,86.85 152.79,87.49 150.08,87.49 150.08,85.28 152.79,85.28 152.79,85.91 153.15,85.91 153.42,85.64 154.36,85.64 154.36,85.48 154.86,85.48 154.86,85.64 155.44,85.64 155.84,85.23 155.84,83.96 156.23,83.58 156.25,83.47 156.16,83.4 154.86,83.4 154.86,83.57 154.36,83.57 154.36,83.4 153.53,83.4 152.87,82.75 152.79,82.75 152.79,83.39 150.08,83.39 150.08,81.18 152.79,81.18 152.79,81.81 153.26,81.81 153.91,82.47 154.56,82.47 154.61,82.47 154.66,82.47 156.15,82.47 156.19,82.42 157.84,82.42 157.84,82.23 157.4,81.79 156.69,81.79 156.68,81.8 156.51,81.83 156.35,81.8 156.34,81.79 156.26,81.79 156.13,81.67 155.88,81.67 155.88,81.41 154.86,80.4 149.91,80.4 148.89,81.41 148.89,87.51 149.53,88.14 157.35,88.14
DGND on TOP (solid shape): outline of 138 points within 132.89,130.51 139.55,141.3
DGND on BOTTOM (solid shape): 129.29,118.01 129.29,115.47 128.98,115.17 125.55,115.17 125.3,115.42 125.3,117.86 125.73,118.29 129.01,118.29
DGND on BOTTOM (solid shape): 130.56,125.94 130.56,122.64 130.3,122.38 127.51,122.38 127.38,122.51 127.38,126.32 127.51,126.45 130.05,126.45
DGND on BOTTOM (solid shape): 130.81,131.91 130.81,131.27 130.43,130.89 127.38,130.89 127.25,131.02 127.25,132.03 127.38,132.16 130.56,132.16
DGND on BOTTOM (solid shape): 136.14,135.97 136.14,133.69 135.76,133.3 131.57,133.3 131.32,133.56 131.32,135.59 131.95,136.23 135.89,136.23
DGND on BOTTOM (solid shape): 146.56,136.61 146.56,134.96 146.43,134.83 142.37,134.83 142.11,135.08 142.11,136.61 142.37,136.86 146.3,136.86
DGND on BOTTOM (solid shape): 150.5,133.81 150.5,127.46 150.24,127.21 148.34,127.21 148.08,127.46 148.08,133.81 148.34,134.07 150.24,134.07
DGND on BOTTOM (solid shape): 153.72,105.63 153.72,104 153.1,103.38 150.11,103.38 149.91,103.58 149.91,105.65 150.15,105.89 153.47,105.89
DGND on BOTTOM (solid shape): 132.64,129.54 132.64,128.38 132.33,128.07 131.17,128.07 130.94,128.3 130.94,129.91 130.89,129.95 130.99,130.05 132.13,130.05
DGND on BOTTOM (solid shape): 143.76,127.05 143.76,126.07 143.64,125.94 141.35,125.94 141.18,126.11 141.35,126.29 141.35,127.18 141.38,127.21 143.61,127.21
DGND on BOTTOM (solid shape): 132.46,126.7 132.46,125.42 132.31,125.27 132.31,125.13 131.97,124.8 131.32,124.8 130.68,125.43 130.68,126.57 130.89,126.78 132.38,126.78
DGND on BOTTOM (solid shape): 135.26,123.56 135.22,123.48 135.13,123.47 134.8,123.36 134.74,123.03 134.73,122.93 134.65,122.89 132.08,122.89 131.93,123.04 131.93,123.37 132.23,123.68 132.23,123.74 133.24,124.75 133.24,124.88 133.3,124.93 135.26,124.93
DGND on TOP: 106.2,88.9 105.46,88.9 105.33,89.03 105.33,90.33 105.78,90.78 106.3,90.78 106.51,90.56 106.51,89.22
DGND on TOP: 94.74,84.86 93.7,84.86 93.28,85.28 93.28,86.06 93.07,86.26 91.28,86.26 91.06,86.49 91.06,87.25 91.29,87.48 94.23,87.48 94.95,86.77 94.95,85.06
DGND on TOP: 94.74,91.11 91.41,91.11 90.63,91.9 90.63,93.14 91.27,93.79 94.81,93.79 95.2,93.4 95.2,91.57
DGND on TOP: 93.05,77.55 93.05,77.9 93.49,78.35 94.79,78.35 95.02,78.11 95.02,77.7 94.63,77.3 93.29,77.3
DGND on TOP: 99.57,76.07 99.57,77.17 99.87,77.47 100.84,77.47 101.47,76.83 102.62,76.83 102.87,76.58 102.87,76.07 102.62,75.82 99.82,75.82
DGND on TOP: 101.09,79.12 101.09,78.49 100.84,78.23 100.08,78.23 99.44,78.87 98.55,78.87 98.42,78.99 98.42,79.76 98.55,79.88 100.33,79.88
DGND on TOP: 102.29,70.71 102.29,71.07 102.92,71.7 102.92,74.17 103.28,74.52 106.93,74.52 107.16,74.3 107.16,70.36 106.93,70.13 102.87,70.13
DGND on TOP: 67.44,91.52 78.99,91.52 82.04,88.47 82.04,86 81.91,85.87 79.69,85.87 78.87,85.04 67.69,85.04 67.31,85.43 67.31,91.39
DGND on TOP: 37.69,88.14 40,88.14 40.61,87.53 40.61,82.5 40.23,82.12 37.77,82.12 37.46,82.43 37.46,87.91
DGND on TOP: 106.55,17.4 106.05,17.4 105.28,18.16 103.5,18.16 102.87,18.8 102.87,19.94 103.12,20.19 105.54,20.19 105.79,19.94 105.79,18.67 106.55,17.91
DGND on TOP: 185.29,72.26 185.29,74.42 184.79,74.93 182.88,74.93 182.63,74.68 182.63,72.64 183.13,72.14 185.17,72.14
DGND on TOP: 98.32,74.35 98.65,74.35 98.97,74.02 98.97,73.16 98.4,72.59 98.22,72.59 97.93,72.89 97.93,73.95
DGND on TOP: 109.41,82.66 109.41,83.02 109.86,83.46 111.15,83.46 111.68,82.93 111.68,82.6 111.51,82.42 109.65,82.42
DGND on TOP: 97.03,84.07 95.93,84.07 95.63,84.37 95.63,85.6 96.27,86.23 96.27,87.12 96.52,87.38 97.03,87.38 97.28,87.12 97.28,84.33
DGND on TOP: 5.76,42.93 5.76,46.78 6.35,47.37 9.4,47.37 9.82,46.94 9.82,42.93 9.32,42.42 6.27,42.42
DGND on TOP: 108.2,88.39 109.3,88.39 109.6,88.09 109.6,86.87 108.46,85.72 108.08,85.72 107.95,85.85 107.95,88.14
DGND on TOP: 5.84,34.54 6.99,34.54 7.24,34.29 7.24,31.24 6.99,30.99 5.84,30.99 5.59,31.24 5.59,34.29
DGND on TOP: 177.06,119.33 188.75,119.33 189.13,118.95 189.13,114.51 187.73,113.11 185.32,113.11 184.43,112.22 184.43,110.44 183.41,109.43 181,109.43 179.86,110.57 179.86,112.22 176.43,115.65 176.43,118.7
DGND on TOP: 37.57,63.5 39.88,63.5 40.49,62.9 40.49,57.87 40.11,57.49 37.8,57.49 37.72,57.41 37.24,57.89 37.24,63.17
DGND on TOP: 151.77,97.87 155.96,97.87 156.34,97.49 156.34,96.47 156.72,96.09 156.72,94.32 156.46,94.06 154.18,94.06 153.42,93.3 152.91,93.3 152.4,93.81 152.4,95.2 151.51,96.09 151.51,97.62
DGND on TOP: 94.23,128.61 94.61,128.22 95.5,128.22 95.89,128.61 95.89,129.49 96.14,129.75 96.52,129.75 96.77,129.49 96.77,128.1 97.66,127.21 97.66,126.83 97.41,126.57 96.9,126.57 95.76,125.43 95.76,123.91 95.5,123.65 94.74,123.65 94.49,123.91 94.49,126.95 93.34,128.1 93.34,129.49 93.6,129.75 93.98,129.75 94.23,129.49
DGND on TOP: 5.97,38.82 7.11,38.82 7.62,38.31 7.62,35.39 7.37,35.13 5.97,35.13 5.71,35.39 5.71,38.56
DGND on TOP: 150.5,138.81 151.77,138.81 152.02,138.56 152.02,135.89 151.77,135.64 150.5,135.64 150.11,136.02 150.11,138.43
DGND on TOP: 95.58,82.47 101.07,82.47 101.37,82.78 101.37,82.88 100.51,83.74 100.51,85.67 100.69,85.85 101.07,85.85 101.3,85.62 101.3,84.48 101.68,84.1 102.13,84.1 102.36,83.87 102.36,81.94 102.57,81.74 102.67,81.74 103.5,82.58 104.5,82.58 104.5,82.63 105.26,83.39 105.61,83.39 105.7,83.3 105.7,83.07 105.51,82.88 105.51,82.58 105.71,82.37 105.71,81.89 105.79,81.81 106.71,81.81 107.31,81.2 107.31,80.67 107.29,80.64 106.1,80.64 105.23,81.51 104.14,81.51 103.94,81.31 103.94,81.05 104.06,80.92 104.06,80.77 103.94,80.64 102.49,80.64 102.13,81 101.57,81 101.22,80.64 94.82,80.64 94.06,81.41 94.06,82.09 93.52,82.63 93.52,83.06 94.03,83.57 94.49,83.57
DGND on TOP: 155.45,127.46 157.14,127.46 157.35,127.25 157.35,125.94 156.72,125.3 155.45,125.3 155.19,125.56 155.19,127.21
DGND on TOP: 147.82,110.69 149.45,110.69 149.73,110.41 149.73,108.03 149.61,107.9 147.7,107.9 147.45,108.16 147.45,110.32
DGND on TOP: 109.42,77.65 109.42,78.1 109.72,78.4 111.02,78.4 111.4,78.01 111.4,77.52 111.24,77.36 109.72,77.36
DGND on TOP: 180.59,79.63 182.88,79.63 183.13,79.38 183.13,77.85 181.99,76.71 180.34,76.71 180.09,76.96 180.09,79.12
DGND on TOP: 169.32,117.18 169.06,116.92 165.1,116.92 164.72,117.3 164.72,120.35 165.32,120.95 165.32,130.71 166.39,131.78 184.18,131.78 185.06,130.89 185.06,127.97 184.05,126.95 177.7,126.95 177.06,126.32 169.7,126.32 169.32,125.94
DGND on TOP, BOTTOM: 161.62,111.68 161.62,108.38 161.37,108.13 159.84,108.13 159.59,108.38 159.59,111.68 159.84,111.94 161.37,111.94
DGND on BOTTOM: 85.19,89.84 85.19,91.32 85.62,91.74 90.53,91.74 91.29,90.99 91.29,89.84 91.16,89.72 85.32,89.72
DGND on BOTTOM: 81.1,84.63 81.58,84.63 81.71,84.51 81.71,81.15 81.36,80.8 80.72,80.8 80.24,81.28 80.24,83.77
DGND on BOTTOM: 110.31,85.09 111.23,85.09 111.58,84.73 111.58,84.18 111.48,84.07 111.48,83.29 111.15,82.96 110.54,82.96 110.11,83.39 110.11,84.89
DGND on BOTTOM: 101.17,87.76 102.49,87.76 102.74,87.5 103.61,87.5 103.84,87.27 103.84,85.98 103.63,85.78 102.11,85.78 101.7,86.18 101.7,86.77 101.47,87 101.12,87 100.97,87.15 100.97,87.55
DGND on BOTTOM: 98.68,90.38 98.68,92.79 98.93,93.05 100.97,93.05 101.22,92.79 101.22,91.95 100.61,91.34 100.61,90.4 100.46,90.25 98.81,90.25
DGND on BOTTOM: 72.82,145.45 75.51,145.45 75.99,144.97 77.28,144.97 77.6,144.65 77.6,143.64 77.47,143.51 76.45,143.51 75.93,144.03 75.26,144.03 75.26,143.79 75.23,143.77 72.85,143.77 72.8,143.82 72.8,144.03 72.31,144.03 72.12,144.22 72.12,145 72.16,145.04 72.72,145.04 72.77,145.09 72.77,145.39
DGND on BOTTOM: 74.42,114.64 74.42,116.41 74.68,116.67 76.2,116.67 76.45,116.41 76.45,114.64 76.2,114.38 74.68,114.38
DGND on BOTTOM: 101.17,82.12 101.68,82.12 101.8,82.25 101.8,83.01 102.08,83.29 102.51,83.29 102.77,83.03 102.77,81.69 102.31,81.23 98.7,81.23 98.7,81.72 99.57,82.58 100.71,82.58
DGND on BOTTOM: 102.72,74.65 104.14,74.65 104.44,74.35 104.44,73.18 104.17,72.9 102.79,72.9 102.49,73.2 102.49,74.42
DGND on BOTTOM: 91.64,89.38 92.18,89.38 92.41,89.15 92.41,88.09 92.02,87.71 91.62,87.71 91.52,87.81 91.52,89.26
DGND on BOTTOM: 92.05,75.95 93.22,75.95 93.42,75.74 93.42,72.8 92.91,72.29 92.48,72.29 92.48,72.64 92.18,72.95 90.6,72.95 90.32,73.23 90.32,74.22
DGND on BOTTOM: 40.64,60.91 40.64,54.31 40.89,54.06 48.01,54.06 48.64,53.42 51.56,53.42 51.69,53.55 51.69,54.06 51.56,54.18 50.67,54.18 50.29,54.56 50.29,56.19 48.89,57.59 48.89,60.66 48.39,61.17 40.89,61.17
DGND on BOTTOM: 104.29,88.93 103.99,89.23 103.99,89.84 104.3,90.15 105.99,90.15 106.85,91.01 107.77,91.01 108.03,90.75 108.03,90.22 108.84,89.41 108.84,89.03 108.74,88.93
DGND on BOTTOM: 34.95,123.5 37.67,123.5 38.2,122.97 38.2,121.01 37.49,120.3 35,120.3 34.54,120.76 34.54,123.09
DGND on BOTTOM: 96.7,76.38 101.63,76.38 101.83,76.18 101.83,74.52 100.05,72.75 98.96,72.75 98.7,73 98.7,73.63 99.39,74.32 99.39,75.33 99.01,75.71 96.7,75.71
DGND on BOTTOM: 103.5,94.61 110.87,94.61 111.25,94.23 111.25,93.22 110.87,92.84 103.63,92.84 103.12,93.34 103.12,94.23
DGND on BOTTOM: 101.22,90.8 102.49,90.8 102.74,90.55 103.12,90.55 103.63,90.04 103.63,89.53 103.5,89.41 101.22,89.41 100.97,89.66 100.97,90.55
DGND on BOTTOM: 92.96,79.35 94.59,79.35 94.67,79.27 94.67,78.61 94.34,78.28 94.34,76.35 94.28,76.3 92.86,76.3 92.68,76.48 92.68,79.07
DGND on BOTTOM: 32,17.14 33.15,17.14 33.4,16.89 33.4,13.84 33.15,13.59 32,13.59 31.75,13.84 31.75,16.89
DGND on BOTTOM: 106.5,114.89 112.65,114.89 113.03,114.51 113.03,113.87 112.78,113.62 106.55,113.62 106.43,113.75 106.43,114.81
DGND on BOTTOM: 112.78,84.96 112.01,84.96 111.33,85.65 111.33,89.08 111,89.41 111,91.31 111.63,91.95 112.52,91.95 112.95,91.52 112.95,85.14
DGND on BOTTOM: 67.95,107.27 67.95,109.3 68.2,109.56 69.72,109.56 69.98,109.3 69.98,107.27 69.72,107.02 68.2,107.02
DGND on BOTTOM: 117.22,75.44 117.22,78.05 116.92,78.36 115.19,78.36 115.06,78.23 115.06,76.33 114.94,76.2 114.94,74.3 115.19,74.04 115.82,74.04
DGND on BOTTOM: 50.55,108.16 52.07,106.63 52.07,100.03 50.41,98.37 44.48,98.37 43.21,99.64 43.21,107.51 38.82,107.51 38.59,107.73 38.59,108.67 38.77,108.85 41.18,108.85 41.88,108.16
DGND on BOTTOM: 108.69,84.81 108.81,84.68 108.81,83.97 107.39,82.55 107.06,82.55 106.93,82.68 106.93,83.16 107.65,83.87 107.65,84.66 107.8,84.81
DGND on BOTTOM: 109.73,78.36 111,78.36 111.25,78.11 111.25,76.71 110.87,76.33 110.24,76.33 109.6,75.69 109.6,75.31 109.35,75.06 105.16,75.06 104.65,75.56 104.65,76.2 104.27,76.58 104.27,77.09 104.52,77.34 106.17,77.34 106.93,76.58 107.31,76.58 107.7,76.2 108.97,76.2 109.47,76.71 109.47,78.11
DGND on BOTTOM: 92.66,82.88 93.9,82.88 93.98,82.8 93.98,81.61 93.73,81.36 93.34,81.36 92.58,82.12 92.58,82.8
DGND on BOTTOM: 121.41,87.5 122.55,87.5 123.09,86.97 123.09,85.62 122.45,84.99 121.39,84.99 121.03,85.34 121.03,87.12
DGND on BOTTOM: 92.2,67.56 97.03,67.56 98.17,68.71 98.17,69.72 97.66,70.23 95.76,70.23 95.5,70.48 95.5,71.12 95.25,71.37 94.87,71.37 94.61,71.12 94.61,69.85 94.36,69.6 92.33,69.6 91.82,69.09 91.82,67.95
DGND on BOTTOM: 100.43,78.64 103.88,78.64 103.99,78.54 103.99,77.57 103.86,77.44 102.59,77.44 102.42,77.27 101.88,77.27 101.75,77.4 101.75,77.72 101.6,77.88 100.46,77.88 100.28,78.05 100.28,78.49
DGND on BOTTOM: 119.05,80.14 119.05,78.92 118.87,78.74 117.83,78.74 117.7,78.87 117.7,80.29 117.86,80.44 118.75,80.44
DGND on BOTTOM: 63.5,104.6 65.41,102.7 65.41,96.86 64.39,95.84 58.8,95.84 57.4,97.24 57.4,104.22 57.78,104.6
DGND on BOTTOM: 109.98,18.03 110.36,18.41 110.74,18.41 111.12,18.03 111.12,16.13 110.74,15.75 110.74,14.22 110.36,13.84 106.93,13.84 106.55,14.22 106.55,17.65 106.93,18.03
DGND on BOTTOM: 113.77,80.01 113.77,78.92 113.59,78.74 112.88,78.74 112.5,79.12 112.5,79.68 113.03,80.21 113.56,80.21
DGND on BOTTOM: 155.7,127.72 157.48,127.72 157.61,127.59 157.61,125.94 156.97,125.3 155.45,125.3 155.19,125.56 155.19,127.21
DGND on BOTTOM: 32.3,108.29 27.94,112.65 27.94,114 28.19,114.25 28.19,114.76 27.94,115.02 27.94,115.65 26.16,117.43 23.88,117.43 23.88,116.16 24.38,115.65 25.15,115.65 25.65,115.14 25.65,111.89 31.73,105.81 33.72,105.81 36.2,103.33 37.72,103.33 37.85,103.46 37.85,105.49 35.05,108.29
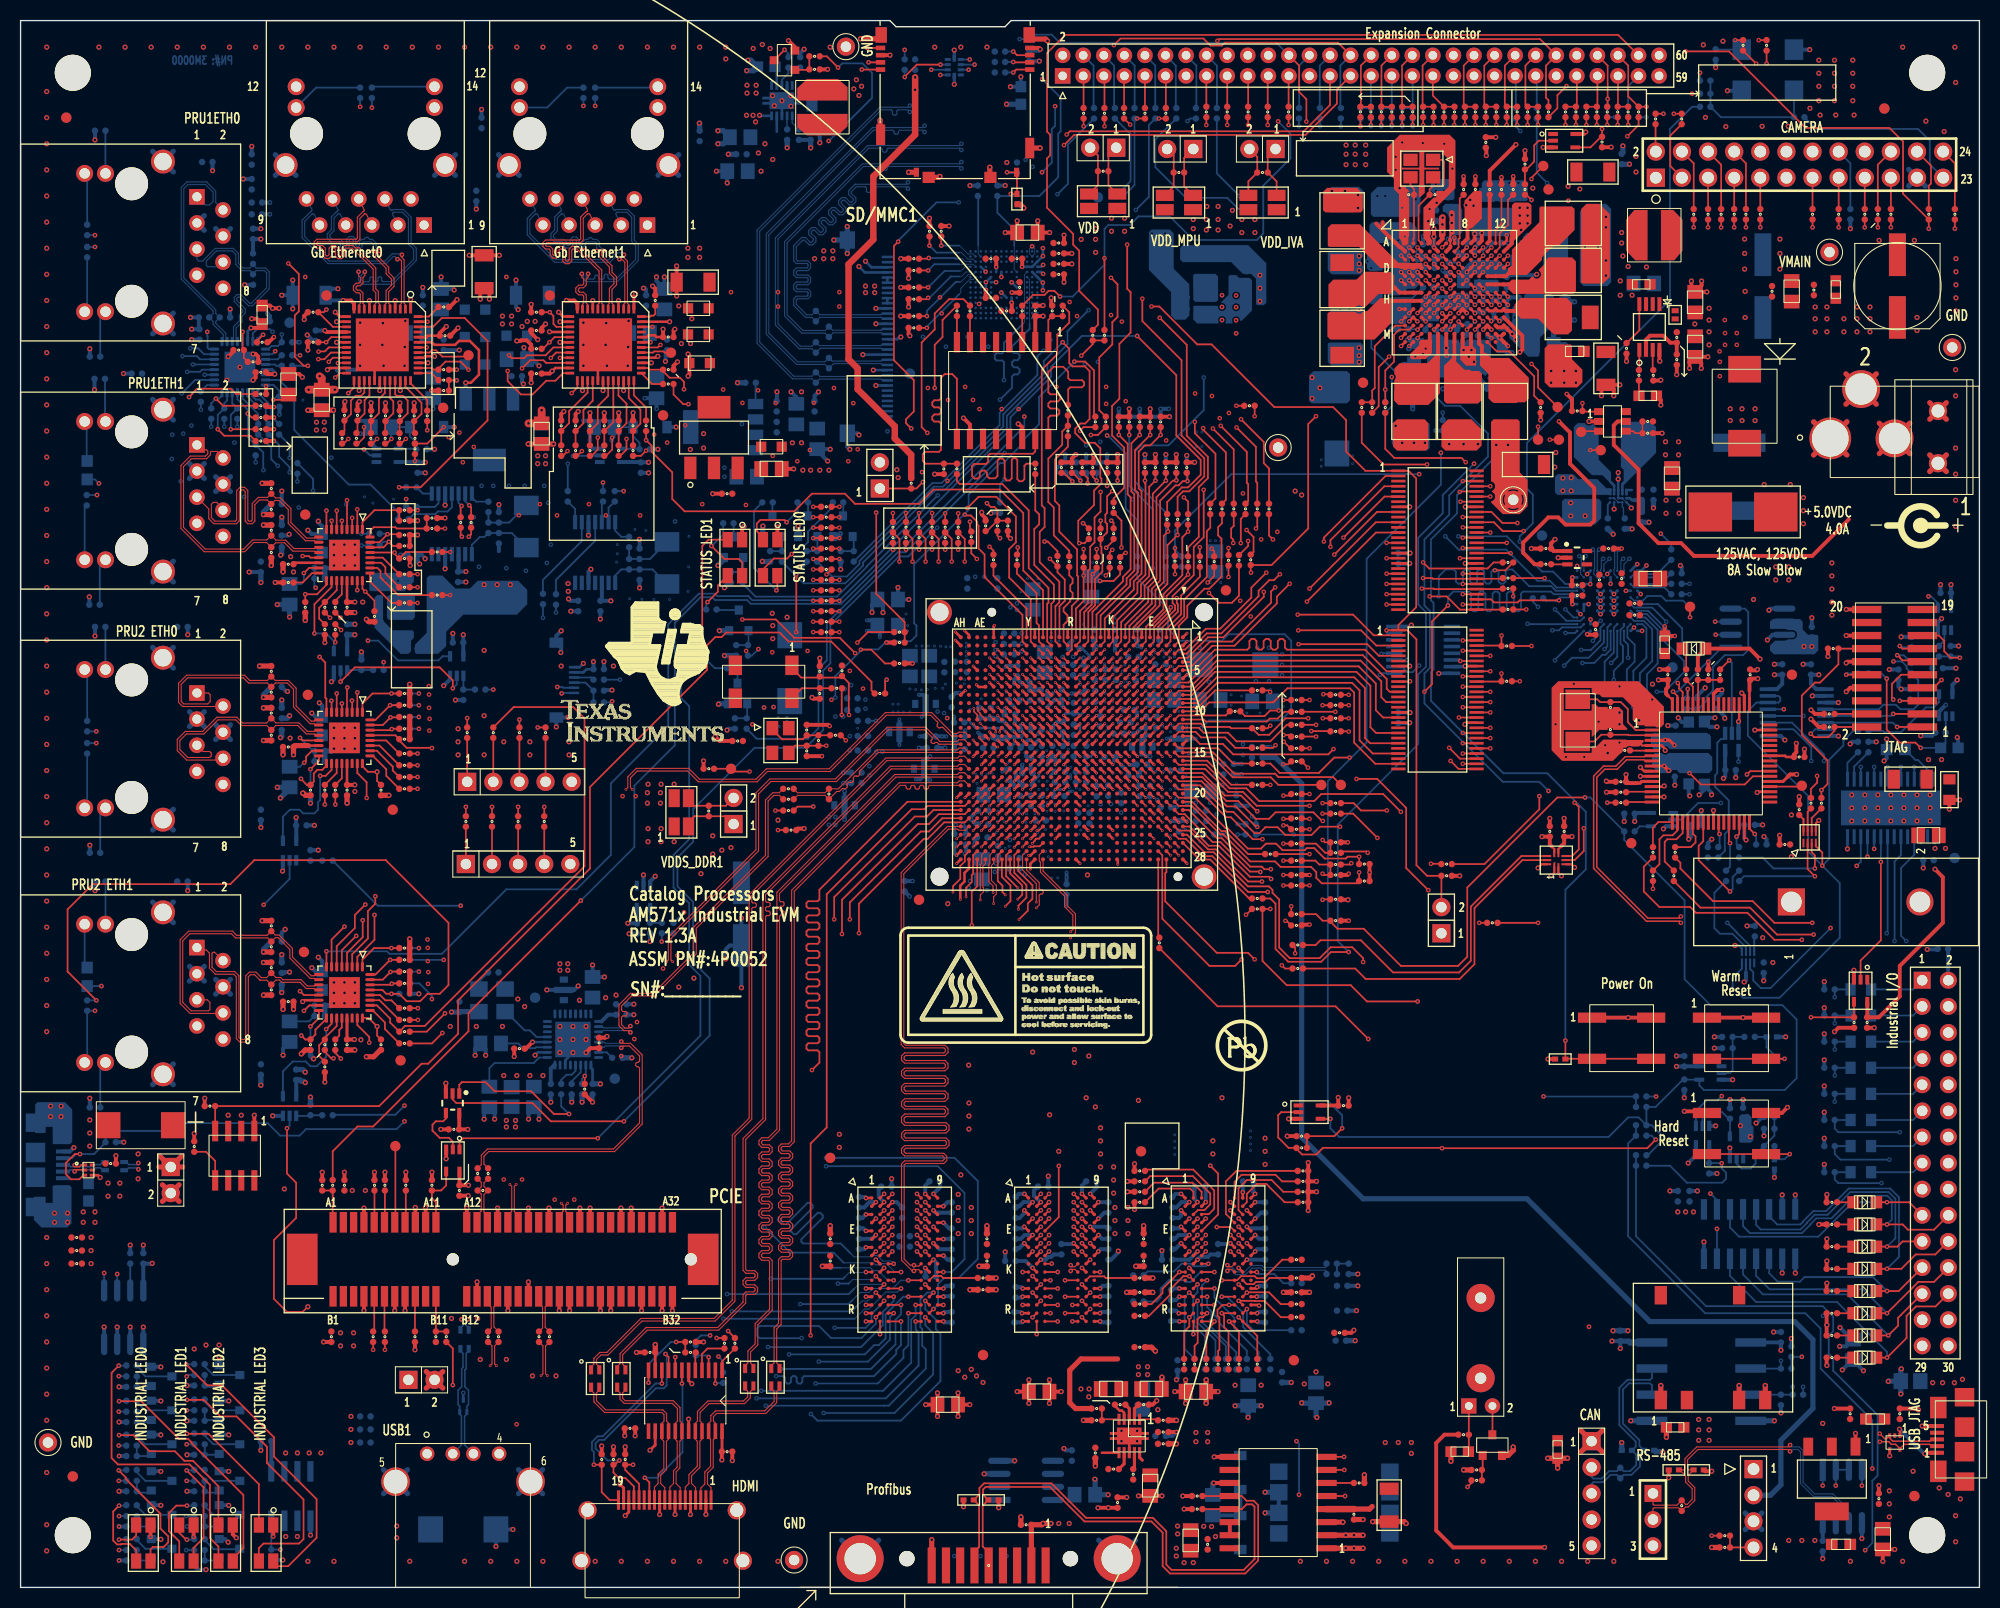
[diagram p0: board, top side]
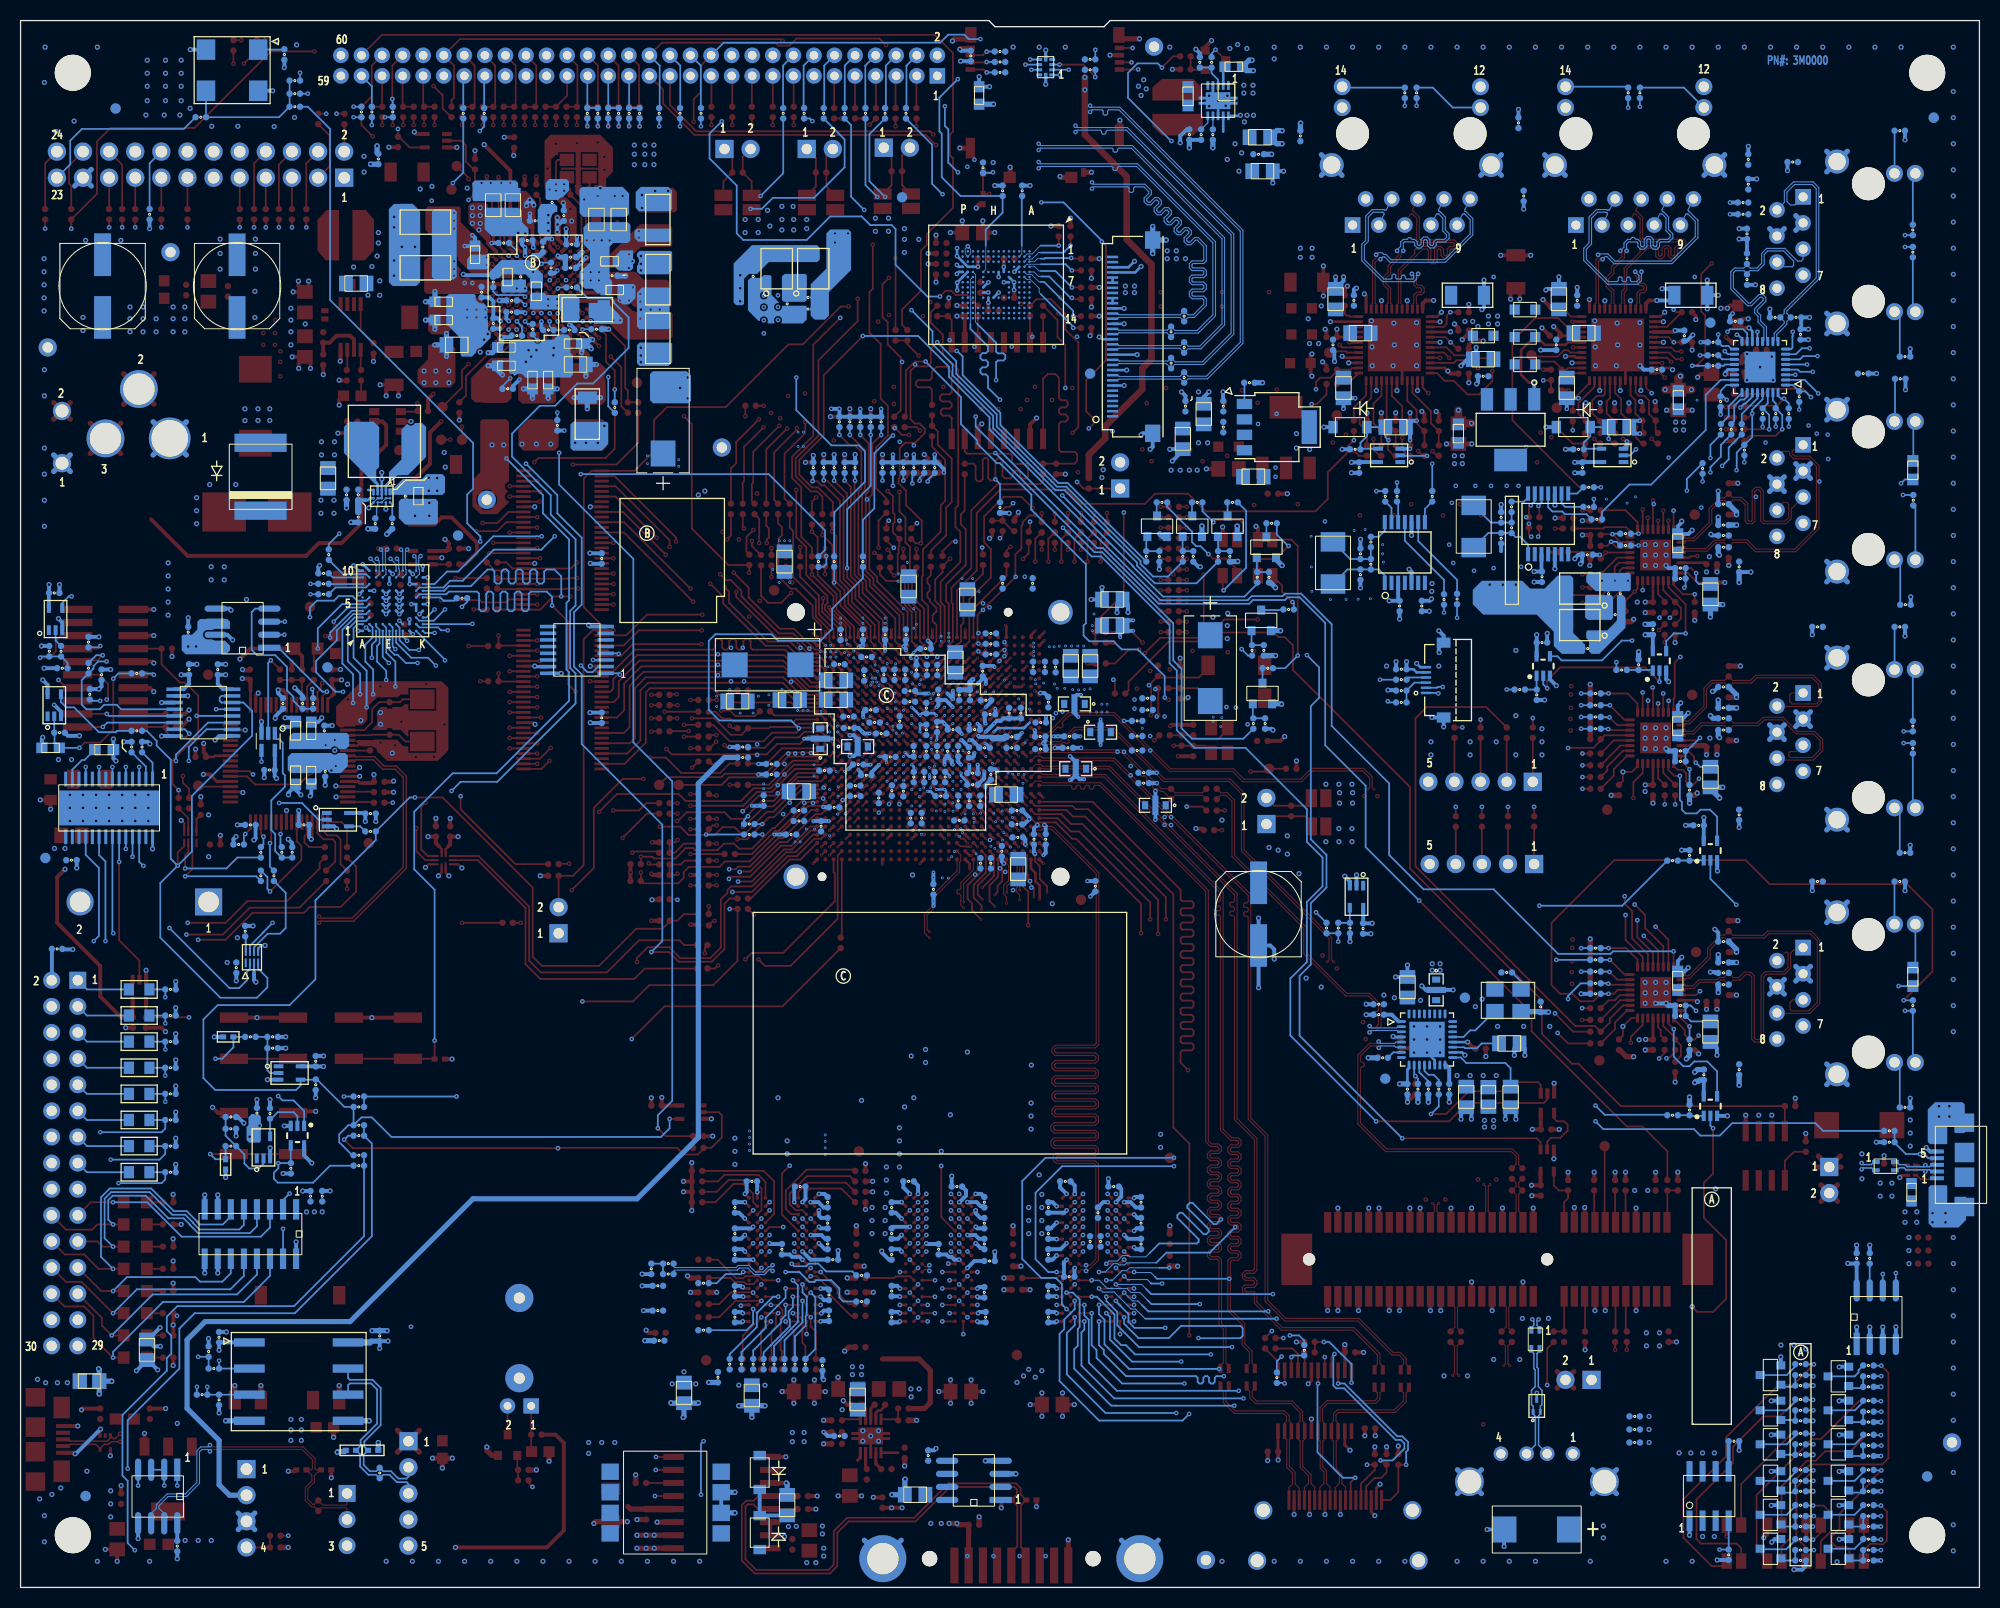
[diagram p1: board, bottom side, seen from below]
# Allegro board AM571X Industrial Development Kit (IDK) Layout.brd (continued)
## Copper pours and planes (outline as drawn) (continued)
DGND on BOTTOM: 88.27,34.62 88.11,34.47 87.25,34.47 86.59,33.81 85.29,33.81 85.12,33.99 85.12,34.67 85.62,35.18 86.13,35.18 87.17,36.22 88.09,36.22 88.27,36.04
DGND on BOTTOM: 162.94,141.61 161.54,143 161.54,148.34 164.34,151.13 173.36,151.13 174.62,149.86 174.62,144.27 175.9,143 186.66,143 188.93,140.74 188.93,136.35 188.06,135.48 183.67,135.48 183.13,136.02 183.13,139.95 182.25,140.84 173.74,140.84 172.97,141.61
DGND on BOTTOM: 90.5,84.43 90.96,84.43 91.11,84.28 91.11,81.38 90.91,81.18 90.47,81.18 90.3,81.36 90.3,84.23
DGND on BOTTOM: 64.26,111.21 64.26,114.51 64.9,115.14 66.55,115.14 66.93,114.76 66.93,110.95 66.55,110.57 64.9,110.57
DGND on BOTTOM: 56.87,123.42 58.01,123.42 58.83,122.61 59.79,122.61 59.8,122.6 59.8,120.86 59.42,120.48 56.63,120.48 56.38,120.73 56.38,122.93
DGND on BOTTOM: 97.03,96.77 97.03,98.17 98,99.14 99.31,99.14 99.57,98.89 99.57,96.77 99.14,96.35 97.45,96.35
DGND on BOTTOM: 116.08,87.55 117.68,87.55 118.01,87.22 118.01,85.5 117.75,85.24 116.18,85.24 115.9,85.52 115.9,87.38
DGND on BOTTOM: 165.51,127.84 165.51,131.15 166.52,132.16 181.13,132.16 181.51,131.78 184.05,131.78 184.56,131.27 184.56,127.46 184.3,127.21 166.14,127.21
DGND on BOTTOM: 75.58,83.41 73.77,83.41 73.2,83.98 73.2,87.12 73.61,87.53 76,87.53 76.33,87.2 76.33,84.16
DGND on BOTTOM: 115.27,102.16 116.81,102.16 117.14,101.83 117.14,100.21 116.99,100.06 115.37,100.06 115.14,100.28 115.14,102.04
DGND on BOTTOM: 93.5,86.84 96.09,86.84 96.39,86.54 96.39,85.5 96.06,85.17 96.06,84.66 95.96,84.56 95.55,84.56 94.95,85.17 93.01,85.17 92.81,85.37 92.81,86.16
DGND on BOTTOM: 6.1,38.18 7.11,38.18 7.62,37.67 7.62,35.39 7.37,35.13 5.97,35.13 5.71,35.39 5.71,37.8
DGND on BOTTOM: 79.93,79.76 80.82,79.76 81.08,79.5 81.08,77.88 80.47,77.27 80.47,74.63 80.26,74.42 80.06,74.42 79.73,74.75 79.73,79.55
DGND on BOTTOM: 120.14,91.78 122.81,91.78 123.19,91.39 123.19,88.39 122.68,87.88 119.84,87.88 119.51,88.22 119.51,91.14
DGND on BOTTOM: 96.65,93.3 97.41,93.3 97.66,93.05 97.66,90.51 97.41,90.25 96.65,90.25 96.39,90.51 96.39,93.05
DGND on BOTTOM: 103,97.92 103,99.44 103.5,99.95 105.16,99.95 105.54,99.57 105.54,97.92 105.24,97.62 103.3,97.62
DGND on L2_GND1, L5_GND2: 2.2,151.13 84.01,151.13 84.61,150.53 96.26,150.53 96.86,151.13 188.3,151.13 189.2,150.22 189.2,2.21 188.29,1.3 2.21,1.3 1.27,2.24 1.27,150.2
DGND on L3_SIG1: 94.89,85.65 95.61,85.65 95.96,86 95.96,86.61 96.82,86.61 96.82,84.68 96.62,84.48 95.48,84.48 95,84.96 94.49,84.96 93.6,85.85 93.6,86.21 93.75,86.36 94.18,86.36
DGND on L3_SIG1: 173.36,1.61 171.45,3.51 171.45,20.02 160.63,30.84 155.68,30.84 143.51,18.67 134.11,18.67 131.83,20.95 131.83,59.31 133.35,60.83 138.18,60.83 144.27,66.93 189.23,66.93 189.23,3.51 187.33,1.61
DGND on L3_SIG1: 111.63,89.24 111.51,89.36 111.51,89.87 112.01,90.38 112.65,90.38 113.28,91.01 115.82,91.01 118.24,93.43 118.24,99.14 120.14,101.05 120.14,104.2 115.54,108.79 111.63,108.79 110.85,109.58 109.55,109.58 105.21,113.92 93.17,113.92 91.95,115.14 84.58,115.14 84.33,114.89 69.27,114.89 64.44,110.06 60.07,110.06 59.94,110.19 59.94,111.38 61.29,112.73 62.71,112.73 67.41,117.43 75.31,117.43 75.51,117.63 101.27,117.63 101.5,117.4 105.82,117.4 112.65,110.57 112.65,110.19 113.16,109.68 115.95,109.68 122.58,103.05 122.58,102.32 121.92,101.66 121.49,101.66 119.28,99.45 119.28,98.84 120.02,98.1 120.02,92.92 116.89,89.79 112.69,89.79 112.14,89.24 ; 2 cut-outs
DGND on L3_SIG1: 1.91,150.83 83.82,150.83 84.45,150.2 96.52,150.2 97.16,150.83 98.47,150.83 99.69,149.61 99.69,144.65 98.65,143.61 74.52,143.61 67.77,136.86 48.89,136.86 43.18,131.15 21.59,131.15 14.61,124.16 14.61,89.24 12.07,86.7 3.17,86.7 1.27,88.6 1.27,150.2
DGND on L3_SIG1: 49.91,119.99 51.28,121.37 52.65,121.37 54.05,122.76 59.31,122.76 60.6,124.06 64.77,124.06 65.13,124.41 84.79,124.41 85.62,123.58 86.97,123.58 87.68,124.29 88.52,124.29 89.41,123.4 96.93,123.4 97.84,122.48 100.03,122.48 100.46,122.92 106.4,122.92 117.6,111.71 117.86,111.71 117.98,111.59 118.36,111.59 119,112.22 119,112.98 106.68,125.3 90.68,125.3 90.04,125.94 85.85,125.94 85.43,126.36 85.09,126.36 84.88,126.57 64.49,126.57 63.88,125.96 60.99,125.96 60.2,125.18 58.67,125.18 58.29,124.8 51.05,124.8 48.64,122.38 48.64,120.73 46.86,118.95 46.86,116.67 47.37,116.16 49.28,116.16 49.91,116.79 ; 1 cut-out
DGND on L3_SIG1: 108.61,86.21 109.07,86.21 109.35,86.49 109.35,87.2 110.16,88.01 110.16,88.47 110.01,88.62 108.79,88.62 108.48,88.32 108.48,86.33
DGND on L3_SIG1: 167.13,145.29 175.01,145.29 176.15,144.15 176.15,134.24 171.7,129.79 171.7,122.05 163.96,114.3 163.96,111.38 166.12,109.22 167.13,109.22 173.86,115.95 173.86,121.28 177.04,124.46 177.04,130.81 182.25,136.02 186.44,136.02 189.1,133.35 189.1,107.82 186.44,105.16 166.5,105.16 157.73,113.92 157.73,135.89
DGND on L3_SIG1: 111.9,83.27 111.9,83.52 111.62,83.79 109.66,83.79 109.49,83.62 109.49,83.24 109.94,82.78 111.4,82.78
DGND on L3_SIG1: 6.99,80.35 20.32,80.35 24.77,75.9 24.77,72.09 21.59,68.92 21.59,53.68 15.24,47.33 8.25,47.33 5.71,49.87 5.71,79.08
DGND on L3_SIG1: 101.37,80.31 101.37,81.1 100.58,81.89 100.58,82.68 100.25,83.01 99.47,83.01 99.47,82.19 98.97,81.7 96.86,81.7 95.96,80.8 95.96,80.42 96.06,80.31
DGND on L3_SIG1: 106.17,76.71 109.73,73.15 109.73,72.64 111.63,70.74 111.63,69.98 121.92,59.69 125.35,59.69 129.67,55.37 129.67,25.15 127.38,22.86 123.32,22.86 120.9,25.27 120.9,39.75 120.14,40.51 120.14,44.2 106.68,57.66 106.68,62.61 106.3,62.99 106.3,65.53 101.22,70.61 101.22,73.84 99.95,75.11 99.95,76.71 100.84,77.6 104.27,77.6 105.16,76.71
DGND on L3_SIG1: 44.66,86.7 53.34,86.7 55.04,88.39 60.32,88.39 61.21,87.5 61.21,85.34 54.74,78.87 54.74,70.87 39.5,55.63 23.49,55.63 23.49,63.88 35.51,75.9 36.53,75.9 42.16,81.53 42.16,84.2
DGND on L4_SIG2: 169.42,119 186.06,119 188.59,116.46 188.59,105.11 186.06,102.57 171.53,102.57 166.78,97.82 162.69,97.82 162.69,112.27
DGND on L4_SIG2: 95.63,81.91 95,81.91 94.03,80.95 94.03,79.43 94.82,78.64 103.61,78.64 135.26,46.99 135.26,30.82 127.81,23.37 82.55,23.37 81.28,22.1 72.9,22.1 68.96,26.03 62.23,26.03 55.5,19.3 42.8,19.3 38.99,23.11 38.99,35.81 40.51,37.34 40.51,48.89 41.4,49.78 41.4,54.86 56.52,69.98 56.52,78.87 66.55,88.9 83.19,88.9 83.82,88.27 89.76,88.27 92.68,85.34 95.63,85.34 96.01,84.96 96.01,82.3
DGND on L4_SIG2: 2.54,150.83 83.82,150.83 84.45,150.2 84.45,147.66 80.64,143.85 80.64,142.37 79.63,141.35 67.31,141.35 56.77,130.81 26.33,130.81 17.78,122.26 17.78,113.41 3.81,113.41 1.91,115.32 1.91,150.2
DGND on L6_PWR1: 2.2,151.13 69.14,151.13 70,150.27 70,129.34 73.53,125.81 82.68,125.81 83.19,126.32 83.19,128.22 85.22,130.26 105.41,130.26 106.6,129.06 106.6,119.08 95.35,107.83 95.35,96.3 94.39,95.33 82.55,95.33 81.28,94.06 81.28,84.79 80.49,84 60.68,84 58.67,82 58.67,76.54 58.04,75.9 50.55,75.9 49.02,74.38 49.02,47.45 48.51,46.94 1.78,46.94 1.27,47.45 1.27,150.2
DGND on L8_GND3: 2.2,151.13 84.01,151.13 84.61,150.53 96.26,150.53 96.29,150.55 96.29,147.76 96.39,147.66 60.83,112.1 60.83,81.62 74.5,67.95 93.77,67.95 100.33,74.5 103.38,74.5 105.33,76.45 113.79,76.45 114.3,76.96 114.3,78.36 113.41,79.25 113.41,84.16 113.79,84.54 121.28,84.54 124.59,87.84 124.59,105.62 124.84,105.87 151.26,105.87 153.8,108.41 153.8,139.65 149.73,143.72 136.78,143.72 136.65,143.85 136.65,145.62 134.49,147.78 97.28,147.78 96.65,148.42 96.65,150.91 96.86,151.13 188.3,151.13 189.2,150.22 189.2,2.21 188.29,1.3 2.21,1.3 1.27,2.24 1.27,150.2
DGND on L9_SIG3: outline of 96 points within 1.27,1.4 116.2,150.83
DGND on L9_SIG3: 111.67,13.72 78.23,13.72 74.57,17.37 71.58,17.37 69.42,19.53 69.42,24.31 64.52,29.21 64.52,57.66 85.09,78.23 89.43,78.23 89.97,78.77 97.49,78.77 101.07,75.18 114.05,75.18 118.11,71.12 118.11,66.04 127,57.15 127,52.83 131.19,48.64 131.19,21.34 123.46,13.6
DGND on L9_SIG3: 38.1,108.92 53.98,108.92 55.88,107.02 55.88,100.03 58.42,97.49 58.42,82.42 57.11,81.11 57.11,75.22 55.24,73.36 55.24,68.28 52.07,65.11 52.07,46.35 54.74,46.35 57.02,44.07 57.02,36.45 58.67,34.8 58.67,19.18 60.45,17.4 60.45,16.51 58.29,14.35 55.5,14.35 49.78,20.07 49.78,26.8 47.12,29.46 40,29.46 35.24,34.23 35.24,38.8 34.29,39.75 34.29,75.9 35.56,77.17 35.56,82.25 37.46,84.16 40.64,84.16 42.55,86.06 42.55,89.87 40.64,91.78 40.64,102.57 37.46,105.75 37.46,108.29
DGND on L9_SIG3: 147.19,98.02 147.19,101.73 153.34,107.87 153.34,117.02 155.58,119.25 184.53,119.25 188.85,114.94 188.85,9.68 182.14,2.97 156.67,2.97 154.31,5.33 134.3,5.33 133.29,6.35 133.29,16.45 136.65,19.81 136.65,52.32 138.3,53.98 138.3,55.12 136.65,56.77 136.65,77.36 136.66,77.37 136.66,85.63 140.37,89.34 140.37,91.2
DGND on L10_SIG4: 2.75,1.4 1.27,2.87 1.27,149.56 1.91,150.2 8.17,150.2 9.27,149.1 9.27,148.08 2.92,141.73 2.92,113.03 22.73,93.22 22.73,91.19 20.7,89.15 20.7,49.4 18.92,47.62 18.92,37.72 20.7,35.94 20.7,35.05 33.27,22.48 33.27,20.7 32,19.43 27.94,19.43 24.64,16.13 24.64,2.75 23.29,1.4
DGND on L10_SIG4: 78.38,112.53 62.1,112.53 59.69,114.94 40.95,114.94 40.39,114.38 39.75,114.38 37.41,116.72 29.93,116.72 29.47,117.18 29.47,118.19 30.47,118.19 30.52,118.14 40.93,118.14 42.71,116.36 60.83,116.36 62.59,114.61 82.58,114.61 86.79,110.39 86.79,106.06 85.62,104.89 85.62,104.63 85.22,104.22 84.2,104.22 82.14,106.28 82.14,108.77 ; 1 cut-out
DGND on L10_SIG4: 41.91,106.05 76.71,106.05 78.87,103.89 78.87,100.58 74.93,96.65 64.39,96.65 54.48,86.74 34.92,86.74 33.91,87.76 33.91,91.44 38.35,95.89 38.35,102.49
DGND on L10_SIG4: 129.79,11.05 140.08,21.34 140.08,29.46 151.26,40.64 151.26,62.1 151.59,62.44 164.89,62.44 170.69,56.64 170.69,43.31 169.04,41.66 169.04,27.69 170.82,25.91 170.82,18.41 173.86,15.37 175.26,15.37 175.64,15.75 175.64,25.4 174.24,26.8 174.24,42.29 183.52,51.56 183.52,60.03 184.79,61.3 184.79,77.6 180.98,81.41 180.98,99.95 170.61,110.31 170.61,131.34 174.86,135.59 183.52,135.59 189.23,129.88 189.23,3.51 187.33,1.61 44.5,1.61 42.29,3.81 42.29,8.97 55.8,8.97 59.69,5.08 108.71,5.08 109.6,4.19 117.98,4.19 124.84,11.05
DGND on L10_SIG4: 106.1,94.54 111.18,94.54 112.04,93.68 112.04,92.71 113.03,91.72 113.03,90.5 112.83,90.3 111.15,90.3 110.87,90.58 110.87,91.01 111.12,91.26 111.12,93.22 110.87,93.47 105.82,93.47 105.69,93.6 105.69,94.13
DGND on L10_SIG4: 107.7,32.38 119.38,32.38 121.67,34.67 121.67,44.07 116.33,49.4 116.33,65.02 117.35,66.04 117.35,71.5 116.71,72.14 112.27,72.14 108.58,75.82 108.58,76.5 108.05,77.04 107.29,77.04 106.86,76.61 104.8,76.61 103.5,75.31 103.5,69.72 101.98,68.2 101.98,63.37 103.5,61.85 103.5,41.53 105.66,39.37 105.66,34.42
DGND on L10_SIG4: 41.91,49.02 66.04,49.02 67.95,47.12 67.95,43.52 66.67,42.25 66.67,39.71 67.31,39.07 67.31,25.1 65.41,23.2 58.55,23.2 56.09,25.65 52.15,25.65 39.37,38.44 39.37,46.48
DGND on L10_SIG4: 95.96,87.78 96.6,87.78 96.95,87.43 96.95,85.55 96.62,85.22 95.76,85.22 95.48,85.5 95.48,87.3
DGND on L10_SIG4: 101.09,86.31 101.47,86.7 102.1,86.7 102.29,86.51 102.29,83.19 102.84,82.63 103.73,82.63 104.09,82.98 104.29,82.98 104.64,82.63 105.46,82.63 105.66,82.42 105.66,81.74 105.41,81.49 104.39,81.49 103.12,80.22 101.6,80.22 101.35,79.96 101.35,79.08 101.09,78.82 98.3,78.82 97.92,79.2 97.92,79.2 96.9,80.21 96.16,80.21 95.91,80.47 95.91,81.25 96.22,81.56 97.23,81.56 97.54,81.86 97.54,83.06 98.68,84.2 99.82,84.2 99.95,84.33 99.95,85.95 100.31,86.31
DGND on L11_GND4: 2.2,151.13 84.01,151.13 84.61,150.53 96.26,150.53 96.86,151.13 188.3,151.13 189.2,150.22 189.2,2.21 188.26,1.27 2.24,1.27 1.27,2.24 1.27,150.2
GND_CAN1 on L3_SIG1: 170.05,19.64 170.05,13.31 165.9,9.16 165.9,7.49 161.84,3.42 150.77,3.42 148.08,6.11 148.08,19.89 155.07,26.88 162.81,26.88
GND_OSC0 on TOP: 70.74,84.66 80.26,84.66 81.15,83.77 81.15,82.63 78.66,80.14 70.65,80.14 69.85,80.94 69.85,83.77
GND_OSC0 on L3_SIG1: 78.7,84.3 80.11,84.3 81.05,83.36 86.44,83.36 87.9,81.9 94.19,81.9 94.56,81.53 94.56,80.92 94.11,80.47 80.01,80.47 79.93,80.54 79.27,80.54 78.84,80.11 77.94,80.11 77.54,80.52 77.54,83.14
GNDPROFI on TOP: 112.39,6.35 116.2,6.35 116.59,6.73 118.62,6.73 118.75,6.6 118.75,4.83 118.49,4.57 115.95,4.57 115.7,4.32 115.19,4.32 114.68,4.83 112.27,4.83 112.27,6.22
GNDPROFI on L3_SIG1: 92.46,13.89 118.52,13.89 121.95,10.46 121.95,6.91 119.38,4.34 116.31,4.34 115.85,4.8 112.57,4.8 109.14,8.23 103.33,8.23 103.2,8.36 98.6,8.36 97.84,7.59 97.84,6.07 97.87,6.05 97.87,2.67 96.57,1.37 89.31,1.37 87.73,2.95 87.73,9.17
GNDUSB1 on BOTTOM: 49.91,15.05 49.91,16.46 50.42,16.97 52.76,16.97 53.26,16.46 53.26,9.78 50.62,7.14 48.21,7.14 46.61,8.74 38.46,8.74 37.41,7.7 34.59,7.7 33.71,8.59 33.71,16.94 33.91,17.14 34.67,17.14 40.18,11.63 46.5,11.63
GNDUSB2 on BOTTOM (solid shape): 5.03,46.49 5.03,43.34 4.8,43.11 3.2,43.11 3.13,43.18 3.13,44.8 2.42,44.8 2.42,44.2 1.43,44.2 1.43,46.97 1.65,47.2 4.32,47.2
GNDUSB2 on BOTTOM (solid shape): 4.95,38.92 4.95,35.41 4.55,35.01 2.03,35.01 1.3,35.74 1.3,38 2.42,38 2.42,37.4 3.13,37.4 3.13,39.05 3.18,39.1 3.43,39.1 3.43,39.12 4.75,39.12
GNDUSB2 on TOP: 1.4,35.69 1.4,46.94 1.65,47.2 4.06,47.2 4.32,46.94 4.32,45.67 3.84,45.19 3.84,39.04 4.06,38.82 5.08,38.82 5.28,38.61 5.28,31.19 5.08,30.99 4.45,30.99 4.19,31.24 4.19,32.89
GNDUSBJ on TOP: 186.87,8.31 185.6,9.58 185.6,11.35 186.08,11.84 186.77,11.84 187.43,11.18 189.2,11.18 189.2,8.31
GNDUSBJ on TOP: 185.78,16.46 185.55,16.69 185.55,16.84 185.6,16.89 185.6,20.22 186.44,21.06 189.2,21.06 189.2,17.48 188.14,17.48 188.11,17.5 187.2,16.59 187.2,16.46
GNDUSBJ on BOTTOM: 184.02,21.16 188.49,21.16 189.18,20.47 189.18,8.31 188.57,7.7 187.2,7.7 185.8,9.09 185.8,10.01 186.66,10.87 186.66,18.14 185.98,18.82 184.28,18.82 183.74,19.35 183.74,20.88
V1_2D on TOP: 154.05,101.43 154.31,101.17 154.31,100.79 154.56,100.54 155.7,100.54 156.59,101.43 159.26,101.43 161.16,99.52 161.16,96.6 160.15,95.59 160.15,93.3 156.84,90 150.24,90 149.35,90.89 149.35,94.44 149.99,95.08 151.77,95.08 152.02,94.82 152.02,93.55 152.65,92.92 153.67,92.92 154.43,93.68 156.72,93.68 157.1,94.06 157.1,96.6 157.35,96.86 158.37,96.86 158.75,97.24 158.75,99.01 158.24,99.52 153.42,99.52 152.91,100.03 152.02,100.03 151.77,100.28 151.77,101.17 152.02,101.43
V1_8D on BOTTOM (solid shape): 121.16,128.78 121.16,124.97 120.9,124.71 120.27,124.71 120.14,124.84 120.14,127.28 119.66,127.76 118.87,127.76 117.73,128.91 113.03,128.91 112.78,129.16 112.78,130.3 113.03,130.56 119.38,130.56
V1_8D on BOTTOM (solid shape): 139.45,136.61 139.45,135.08 139.32,134.96 138.4,134.96 138.21,134.96 138.03,135.15 137.78,135.24 137.76,135.24 137.16,135.84 137.16,136.73 137.41,136.99 139.07,136.99
V1_8D on BOTTOM (solid shape): 42.29,97.16 43.69,97.16 44.45,97.92 48.39,97.92 49.28,97.03 49.28,95.63 48.26,94.61 43.05,94.61 41.65,93.21 41.62,93.18 41.4,92.96 41.4,91.57 40.87,91.03 40.84,91.03 40.61,90.8 38.48,90.8 38.35,90.93 38.35,91.69 39.5,92.84 39.5,98.17 39.75,98.42 41.02,98.42
V1_8D on BOTTOM: 96.98,75.62 98.83,75.62 99.06,75.39 99.06,74.3 98.93,74.17 96.75,74.17 96.65,74.27 96.65,75.29
V1_8D on BOTTOM: 94.92,77.98 96.32,77.98 96.37,77.93 96.37,77.65 96.55,77.47 97.54,77.47 98.76,78.69 99.97,78.69 100.13,78.54 100.13,77.06 99.72,76.66 96.62,76.66 96.32,76.35 94.84,76.35 94.77,76.43 94.77,77.83
V1_8D on BOTTOM: 102.52,76.74 102.87,77.09 103.63,77.09 103.89,76.83 103.89,76.58 104.32,76.15 104.32,75.16 104.17,75.01 102.59,75.01 102.52,75.07
V1_8D on BOTTOM: 91.82,98.68 93.73,98.68 93.98,98.42 93.98,98.04 93.85,97.92 91.69,97.92 91.57,98.04 91.57,98.42
V1_8D on BOTTOM: 102.97,87.66 102.62,88.01 101.17,88.01 100.97,88.21 100.97,88.93 101.15,89.11 103.93,89.11 104.01,89.03 104.01,88.77 103.76,88.52 103.76,88.27 103.89,88.14 103.89,87.66
V1_8D on L3_SIG1: 98.83,78.59 99.85,78.59 100.1,78.33 100.1,77.62 99.95,77.47 99.57,77.47 99.19,77.85 98.42,77.85 97.66,77.09 96.39,77.09 95.89,77.6 95.89,78.23 96.77,79.12 97.66,79.12 97.79,79.25 98.17,79.25
V1_8D on L4_SIG2: 96.04,88.56 100.67,88.56 101.3,87.92 101.3,86.65 101.05,86.4 96.5,86.4 95.76,87.15 95.76,88.27
V1_8D on L7_PWR2: 105.55,87.57 105.55,86.68 105.54,86.7 105.54,81.69 107.64,79.58 108.29,79.58 109.42,78.46 109.42,76.3 108.64,75.52 102.49,75.52 100.46,77.55 100.46,77.8 100.05,78.21 98.86,78.21 98.53,78.54 98.53,78.54 98.25,78.82 96.39,78.82 96.01,78.44 96.01,74.76 68.45,74.76 66.67,76.54 66.67,85.43 55.42,96.72 53.34,98.81 52.07,98.81 50.16,96.9 43.94,96.9 40.89,99.95 40.89,102.95 41.66,103.71 64.26,103.71 66.67,101.3 73.18,101.3 75.97,104.09 92.33,104.09 93.47,102.95 95.38,102.95 96.52,104.09 113.03,104.09 115.32,106.38 115.32,128.99 116.33,130 127.89,130 131.44,133.56 131.44,137.11 131.95,137.62 139.83,137.62 141.86,135.59 141.86,131.4 139.32,128.86 139.32,126.07 133.1,119.84 133.1,102.44 125.6,94.95 87.63,94.95 86.61,95.97 84.96,95.97 83.57,94.57 83.57,91.52 91.95,83.14 100.08,83.14 100.46,83.52 100.46,86.44 99.95,86.95 96.9,86.95 96.14,87.71 96.14,88.73 96.52,89.11 105.16,89.11 105.54,88.73 105.54,87.58
V1_8D on L8_GND3: 96.98,75.49 95.83,76.63 95.83,78.18 96.19,78.54 99.54,78.54 99.8,78.28 99.8,76.5 98.78,75.49
V1_8D on L10_SIG4: 138.89,136.78 139.95,135.72 139.95,135.08 139.7,134.83 138.1,134.83 137.72,135.21 136.4,135.21 136.02,135.59 136.02,136.48 136.32,136.78
V1_8D on L10_SIG4: 104.17,88.09 104.27,87.99 105.08,87.99 105.28,87.78 105.28,87.38 104.95,87.05 104.95,86.82 104.62,86.82 104.24,87.2 103.1,87.2 102.54,87.76 102.54,88.7 103.12,89.28 104.06,89.28 104.34,89 104.34,88.57 104.17,88.39
V1_8D on L10_SIG4: 92.58,98.55 93.85,98.55 94.23,98.17 94.23,97.54 93.73,97.03 92.71,97.03 92.33,97.41 92.33,98.3
V1_8FTDI on TOP: 159,91.44 160.4,91.44 160.53,91.31 160.53,90.04 160.27,89.79 159.39,89.79 159.13,89.53 159.13,89.03 159.51,88.65 159.51,87.5 159.26,87.25 158.75,87.25 158.24,87.76 158.24,90.68
V1_8FTDI on L8_GND3: 156.97,89.24 169.42,89.24 173.1,85.55 173.1,76.43 169.4,72.73 159.51,72.73 155.32,76.92 155.32,87.58
V1_8PHY_HDMI on BOTTOM: 82.3,75.82 81.91,75.44 81.03,75.44 80.82,75.64 80.82,77.14 81.46,77.77 81.46,79.81 81.79,80.14 82.68,80.14 82.93,79.88 82.93,78.11 82.3,77.47
V1_8PHY_HDMI on L6_PWR1: 97.16,78.49 97.33,78.66 97.33,81.13 96.8,81.66 93.6,81.66 91.69,79.76 83.74,79.76 83.44,80.06 80.95,80.06 80.64,79.76 80.64,78.16 81.56,77.24 94.54,77.24 95.78,78.49
V1_8PHY_HDMI on L10_SIG4: 81.28,80.14 82.68,80.14 82.93,79.88 82.93,78.23 82.42,77.72 81.15,77.72 80.9,77.98 80.9,79.76
V1_8PHY_LDO3 on BOTTOM: 85.04,86.57 87.12,86.57 87.38,86.31 87.38,84.84 87.07,84.53 87.07,82.63 87,82.55 86.36,82.55 86.11,82.8 86.11,84.33 85.85,84.58 85.09,84.58 84.58,85.09 84.58,86.11
V1_8PHY_LDO3 on L8_GND3: 112.39,106.51 111.38,105.49 111.38,93.81 107.57,90 99.19,90 97.79,88.6 97.79,86.44 98.3,85.93 98.3,83.9 97.16,82.76 89.41,82.76 88.18,81.53 81.66,81.53 80.77,82.42 80.77,84.45 81.28,84.96 89.15,84.96 90.93,86.74 90.93,98.17 103.5,110.74 130.18,110.74 144.48,125.05 152.15,125.05 153.16,124.03 153.16,108.67 151,106.51
V1_8PHY_LDO3 on L10_SIG4: 84.35,82.78 84.35,85.75 84.71,86.11 85.85,86.11 87.25,84.71 87.25,82.93 86.56,82.25 84.89,82.25
V1_8PHY_LDO4 on BOTTOM: 145.54,127.13 147.45,127.13 147.7,126.87 147.7,126.36 147.45,126.11 145.29,126.11 145.16,126.24 145.16,126.75
V1_8PHY_LDO4 on BOTTOM: 86.23,75.06 84.1,72.92 79.1,72.92 78.36,73.66 78.36,76.58 78.49,76.71 79.32,76.71 79.5,76.53 79.5,74.37 79.88,73.99 81.74,73.99 83.44,75.69 83.44,79.38 84.33,80.26 87.12,80.26 87.25,80.14 87.25,79.25 87.12,79.12 86.36,79.12 86.23,78.99
V1_8PHY_LDO4 on L5_GND2: 82.07,80.64 82.07,86.26 82.55,86.74 88.01,86.74 88.52,86.23 88.52,85.6 87.2,84.28 87.2,80.09 84.33,77.22 78.49,77.22 78.23,77.47 78.23,78.99 78.87,79.63 81.05,79.63
V1_8PHY_LDO4 on L8_GND3: 87.3,85.32 88.57,85.32 90.35,87.1 90.35,98.48 103.28,111.4 129.95,111.4 144.02,125.48 145.8,125.48 146.18,125.86 146.18,127.89 145.29,128.78 144.02,128.78 129.67,114.43 101.57,114.43 86.61,99.47 86.61,86
V1_8PHY_LDO4 on L10_SIG4: 78.61,73.79 79.38,73.79 79.63,74.04 79.63,78.99 79.5,79.12 78.49,79.12 78.36,78.99 78.36,74.04
V1_8PHY_LDO4 on L10_SIG4: 147.45,126.62 147.7,126.87 147.7,127.38 147.32,127.76 144.78,127.76 144.53,127.51 144.53,126.87 144.78,126.62
V1_8PHY_LDO4 on L10_SIG4: 88.27,85.14 88.52,85.39 88.52,85.95 88.14,86.33 87.5,86.33 87.07,85.9 87.07,85.5 87.43,85.14
V1_8PHY_PCIE on BOTTOM: 95.76,79.88 95.15,80.49 93.19,80.49 92.71,80.01 91.57,80.01 90.42,78.87 88.65,78.87 88.52,78.99 88.52,80.01 89.53,81.03 91.19,81.03 91.44,81.28 91.44,81.79 91.69,82.04 92.08,82.04 92.96,81.15 93.98,81.15 94.28,81.46 94.28,81.97 94.49,82.17 97.41,82.17 97.79,82.55 97.79,81.41 96.27,79.88
V1_8PHY_SATA on BOTTOM: 84.45,80.9 82.3,80.9 82.09,81.1 82.09,83.11 82.68,83.69 84.71,83.69 84.84,83.57 84.84,81.28
V1_8PHY_SATA on L4_SIG2: 95.12,81.53 97.16,81.53 97.79,82.17 97.79,83.82 98.04,84.07 99.31,84.07 99.69,83.69 99.69,81.91 98.17,80.39 98.17,79.76 97.92,79.5 95,79.5 94.49,80.01 94.49,80.9
V1_8PHY_USB on BOTTOM: 88.9,86.61 89.41,86.61 90.04,85.98 90.8,85.98 91.06,85.72 91.06,85.34 90.42,84.71 89.03,84.71 88.65,85.09 88.65,86.36
V1_8PHY_USB on L10_SIG4: 95.12,84.84 97.92,84.84 98.17,84.58 98.17,84.2 97.92,83.95 97.66,83.95 96.39,82.68 92.71,82.68 90.68,84.71 89.15,84.71 88.9,84.96 88.9,85.72 89.15,85.98 91.69,85.98 92.33,86.61 93.34,86.61
V1_8PLL on BOTTOM: 111.16,81.99 114.75,81.99 117.3,84.54 122.43,84.54 123.44,85.55 123.44,107.27 123.95,107.78 126.62,107.78 127.13,107.27 127.13,102.82 128.02,101.94 128.02,84.66 126.11,82.76 118.62,82.76 116.66,80.8 110.33,80.8 109.73,81.41 109.73,82.17 109.94,82.38 110.77,82.38
V1_8PLL on L5_GND2: 92.89,80.27 94,80.27 94.69,79.58 98.37,79.58 100.76,81.97 106.07,81.97 106.4,82.3 113.31,82.3 113.51,82.09 114.2,82.09 114.4,82.3 115.52,82.3 115.9,81.91 115.9,81.13 113.63,78.87 103.96,78.87 102.34,77.24 93.95,77.24 92.66,78.54 92.66,80.04
V1_8PLL on L6_PWR1: 137.92,132.54 137.92,131.4 136.27,129.75 134.62,129.75 131.7,126.83 131.7,115.02 125.6,108.92 125.6,105.75 124.84,104.98 123.19,104.98 122.3,105.87 122.3,109.81 128.4,115.91 128.4,127.59 133.6,132.8 137.67,132.8
V1_8PLL on L10_SIG4: 112.57,82.2 115.62,82.2 116.08,81.74 116.08,80.9 115.95,80.77 112.55,80.77 112.42,80.9 112.42,82.05
V1_8PLLA on BOTTOM: 113.41,84.07 113.61,83.87 113.61,83.39 113.39,83.16 112.24,83.16 111.86,83.55 111.86,83.92 112.01,84.07
V1_8PLLA on L3_SIG1: 100.82,82.98 101.4,82.98 102.01,82.37 104.21,82.37 104.43,82.6 105.26,82.6 105.26,82.31 110.02,82.31 110.4,81.93 110.4,80.92 110,80.52 104.48,80.52 104.48,79.64 104.36,79.52 103.73,79.52 103.23,80.02 103.09,80.02 101.81,78.74 101.06,78.74 100.84,78.96 100.84,79.26 100.96,79.38 101.47,79.38 101.85,79.76 101.85,81.15 100.68,82.33 100.68,82.84
V1_8PLLA on L10_SIG4: 106.35,82.07 108.56,82.07 109.63,83.14 111.68,83.14 111.81,83.27 111.81,83.87 112.01,84.07 113.41,84.07 113.65,83.83 113.65,82.87 113.18,82.4 112.5,82.4 112.17,82.07 112.17,81.39 111.93,81.15 109.89,81.15 109.86,81.11 106.43,81.11 106.17,81.36 106.17,81.89
V1_8PLLB on BOTTOM: 101.17,81.03 102.59,81.03 102.84,81.28 102.84,82.47 103.43,83.06 103.43,84.94 103.64,85.15 103.91,85.15 104.11,84.94 104.11,82.66 104.39,82.38 108.25,82.38 108.46,82.17 108.46,81.41 108.41,81.36 104.39,81.36 104.22,81.18 103.81,81.18 103.33,80.7 103.33,80.07 103.12,79.86 102.95,79.86 102.49,80.32 101.09,80.32 100.99,80.42 100.99,80.85
V3_3ACDCM on BOTTOM: 51.94,56.6 56.77,56.6 57.15,56.22 57.15,55.33 57.4,55.07 58.17,55.07 58.29,55.2 58.29,57.74 58.04,57.99 54.61,57.99 54.1,57.49 51.94,57.49 51.82,57.36 51.82,56.72
V3_3ACDCM on L9_SIG3: 55.2,58.88 58.42,58.88 59.05,58.25 59.05,54.06 57.96,52.96 54.99,52.96 53.34,54.61 53.34,57.02
V3_3APCIE on BOTTOM: 46.86,47.88 50.55,47.88 51.26,48.6 51.69,48.6 51.94,48.85 51.94,49.74 51.69,49.99 51.23,49.99 50.67,50.55 46.99,50.55 46.61,50.16 46.61,48.13
V3_3APCIE on L9_SIG3: 41.99,57.87 47.62,57.87 53.29,52.2 59.44,52.2 60.32,51.31 60.32,48.21 58.72,46.61 48.6,46.61 40.89,54.31 40.89,56.77
V3_3AUX_PCIE on TOP: 39.24,18.92 41.27,18.92 41.53,19.18 41.53,22.23 40.89,22.86 40.89,24 40.64,24.26 40.13,24.26 39.88,24.51 39.88,29.34 39.75,29.46 39.12,29.46 38.99,29.34 38.99,19.18
V3_3D on BOTTOM (solid shape): 168.34,45.74 168.34,44.98 168.53,44.79 168.53,43.52 168.28,43.26 167.26,43.26 167.13,43.39 167.13,45.8 167.34,46.01 167.77,46.01 167.77,46.06 168.02,46.06
V3_3D on BOTTOM (solid shape): 38.23,98.42 38.23,97.79 37.34,96.9 35.66,96.9 35.66,96.9 35.34,96.9 35.34,96.9 34.51,96.9 34.51,96.9 34.04,96.9 33.91,97.03 33.91,98.55 34.04,98.68 37.97,98.68
V3_3D on BOTTOM (solid shape): 144.91,127.94 144.91,127.53 144.7,127.32 144.03,127.32 143.64,127.72 141.35,127.72 140.97,127.34 140.97,126.45 140.87,126.35 139.8,126.35 139.7,126.45 139.7,127.72 141.1,129.11 143.74,129.11
V3_3D on L10_SIG4 (solid shape): 37.59,97.66 37.59,97.03 37.08,96.52 34.29,96.52 33.66,97.16 33.66,97.79 34.16,98.3 36.96,98.3
V3_3D on TOP: 31.88,54.75 32.13,54.5 32.13,53.87 32.26,53.74 33.21,53.74 33.4,53.55 33.4,53.04 33.21,52.85 31.5,52.85 31.37,52.98 31.37,53.61 31.5,53.74 31.5,54.63 31.62,54.75
V3_3D on TOP: 172.97,73.74 171.83,74.88 171.83,75.27 172.09,75.52 173.23,75.52 173.48,75.27 173.48,73.23 173.1,73.23 172.97,73.36
V3_3D on TOP: 73.28,112.35 73.53,112.6 76.07,112.6 76.33,112.35 76.33,110.57 76.07,110.32 73.53,110.32 73.28,110.57
V3_3D on TOP: 25.35,125.56 25.68,125.23 25.68,124.34 25.48,124.13 22.66,124.13 22.56,124.03 20.14,124.03 19.89,124.29 19.89,124.82 20.62,125.56
V3_3D on TOP: 31.94,79.58 32.13,79.39 32.13,78.76 32.26,78.63 32.7,78.63 32.89,78.44 32.89,77.3 32.77,77.17 32.38,77.17 32.13,77.42 32.13,77.68 31.5,77.68 31.37,77.81 31.37,78.5 31.5,78.63 31.5,79.46 31.62,79.58
V3_3D on TOP: 131.83,9.4 131.83,10.29 131.89,10.35 131.89,13.73 132.59,14.43 136.02,14.43 136.65,13.8 136.65,10.03 135.26,8.64 132.97,8.64 131.7,7.37 129.03,7.37 128.91,7.49 128.91,8 129.16,8.25 130.68,8.25
V3_3D on TOP: 161.29,19.51 162.69,19.51 163.07,19.13 163.07,16.85 164.47,16.85 164.72,16.59 164.72,15.19 164.34,14.81 161.29,14.81 161.16,14.94 161.16,19.39
V3_3D on TOP: 31.88,97.36 32.13,97.11 32.13,96.47 32.26,96.35 33.53,96.35 33.66,96.22 33.66,95.46 31.5,95.46 31.37,95.59 31.37,96.22 31.5,96.35 31.5,97.24 31.62,97.36
V3_3D on TOP: 176.78,4.7 176.78,3.68 176.53,3.43 171.83,3.43 171.58,3.68 171.58,4.7 171.83,4.95 176.53,4.95
V3_3D on TOP: 99.06,130.51 99.57,130.51 100.2,131.15 100.58,131.15 100.84,130.89 100.84,127.46 100.58,127.21 99.06,127.21 98.81,127.46 98.81,130.26
V3_3D on TOP: 108.84,12.19 109.6,12.95 111.68,12.95 114.17,15.45 115.54,15.45 116.03,14.97 116.03,13.47 112.8,10.24 106.05,10.24 105.28,11 105.28,11.77 105.54,12.02 105.92,12.02 106.17,11.77 106.17,11.26 106.55,10.88 108.46,10.88 108.84,11.26
V3_3D on BOTTOM: 54.92,98.38 54.92,95.84 54.67,95.59 53.4,95.59 52.76,96.23 52.76,97.77 53.49,98.51 54.8,98.51
V3_3D on BOTTOM: 52.15,60.79 52.15,59.06 52.4,58.81 53.26,58.81 53.52,59.06 53.52,60.79 53.34,60.96 52.32,60.96
V3_3D on BOTTOM: 50.16,111.84 51.18,111.84 51.56,111.46 51.56,109.43 51.05,108.92 50.16,108.92 49.78,109.3 49.78,111.46
V3_3D on BOTTOM: 112.09,79.91 112.09,79.17 111.84,78.92 110.57,78.92 110.24,79.25 110.24,79.93 110.41,80.11 111.89,80.11
V3_3D on BOTTOM: 132.46,10.16 134.24,10.16 134.62,10.54 134.62,12.32 133.99,12.95 132.72,12.95 132.33,13.34 132.33,14.18 132.59,14.43 135.26,14.43 135.89,13.8 135.89,6.73 135.64,6.48 132.08,6.48 131.32,7.24 131.32,9.02
V3_3D on BOTTOM: 162.79,17.07 164.47,17.07 165.96,15.58 165.96,8.89 167.21,7.65 175.51,7.65 175.87,7.29 175.87,4.58 175.46,4.17 173.89,4.17 171.96,2.24 163.47,2.24 161.95,3.76 161.95,16.24
V3_3D on BOTTOM: 160.15,37.8 163.83,37.8 164.08,37.55 164.08,35.77 163.96,35.64 160.15,35.64 159.77,36.02 159.77,37.42
V3_3D on BOTTOM: 38.51,101.43 40.51,101.43 40.82,101.12 40.82,99.27 40.69,99.14 37.41,99.14 37.31,99.24 37.31,99.67 37.54,99.9 38.07,99.9 38.3,100.13 38.3,101.12 38.25,101.17
V3_3D on BOTTOM: 168.5,60.28 170.41,60.28 170.79,60.66 170.79,60.91 170.54,61.17 168.5,61.17
V3_3D on BOTTOM: 107.3,88.6 108.53,88.6 108.94,88.19 108.94,87.93 108.51,87.5 107.01,87.5 106.86,87.66 106.86,87.78 107.09,88.01 107.09,88.19 107.19,88.29 107.19,88.49
V3_3D on BOTTOM: 94.41,128.73 95,128.73 95.15,128.58 95.15,127.69 94.16,126.7 94.16,126.07 94.03,125.94 93.73,125.94 93.6,126.07 93.6,126.88 93.22,127.26 93.22,127.54
V3_3D on BOTTOM: 110.49,90.42 109.86,90.42 109.47,90.04 109.17,90.04 109.04,90.17 108.61,90.17 108.41,90.37 108.41,90.78 108.81,91.19 110.36,91.19 110.62,90.93 110.62,90.55
V3_3D on BOTTOM: 102.87,91.69 103.63,91.69 104.27,91.06 104.27,90.3 104.01,90.04 103.89,90.04 103.63,90.3 103.63,90.55 103.25,90.93 102.74,90.93 102.62,91.06 102.62,91.44
V3_3D on BOTTOM: 110.49,76.2 111.12,76.2 111.25,76.07 111.25,74.68 112.01,73.91 113.54,73.91 113.66,73.79 113.66,72.9 113.41,72.64 111.12,72.64 110.11,73.66 110.11,75.82
V3_3D on BOTTOM: 48.51,121.49 48.51,123.4 48.77,123.65 50.16,123.65 50.42,123.4 50.42,121.37 50.04,120.99 49.02,120.99
V3_3D on BOTTOM: 118.49,87.12 120.4,87.12 120.52,87 120.52,85.47 120.78,85.22 120.78,84.96 120.52,84.71 118.87,84.71 118.36,85.22 118.36,87
V3_3D on BOTTOM: 28.83,115.27 29.72,115.27 29.97,115.02 29.97,112.5 29.67,112.2 28.78,112.2 28.4,112.58 28.4,113.7 28.7,114 28.7,115.14
V3_3D on BOTTOM: 84.71,94.95 86.23,94.95 86.61,94.57 86.61,92.92 86.36,92.66 84.71,92.66 84.45,92.92 84.45,94.7
V3_3D on BOTTOM: 97.28,128.73 98.4,128.73 99.11,129.44 99.11,130.41 99.24,130.54 99.62,130.54 99.75,130.41 99.75,129.39 98.53,128.17 97.28,128.17 97.16,128.3 97.16,128.61
V3_3D on BOTTOM: 46.74,44.79 46.74,47.33 46.99,47.58 48.51,47.58 48.64,47.45 48.64,44.79 48.26,44.4 47.12,44.4
V3_3D on BOTTOM: 91.72,89.89 91.72,91.77 91.9,91.95 92.33,91.95 92.43,91.85 92.43,89.87 92.33,89.76 91.85,89.76
V3_3D on L4_SIG2: 176.53,101.17 187.45,101.17 188.85,99.78 188.85,80.22 187.07,78.44 180.09,78.44 178.94,79.58 178.94,88.73 175.51,92.16 175.51,100.16
V3_3D on L5_GND2: 103.76,87.71 103.76,85.81 103.5,85.55 101.09,85.55 100.71,85.93 100.71,88.85 100.2,89.36 97.66,89.36 97.41,89.62 97.41,90.76 97.66,91.01 100.46,91.01
V3_3D on L7_PWR2: 2.11,1.91 1.91,2.11 1.91,150.32 2.08,150.5 83.75,150.5 84.35,149.9 96.53,149.9 97.13,150.5 187.96,150.5 188.59,149.86 188.59,139.99 188.39,139.78 181.23,139.78 180.21,138.77 180.21,138.26 180.28,138.19 180.28,129.05 176.53,125.3 176.53,83.65 178.18,82 178.18,81.11 176.53,79.46 176.53,55.12 177.17,54.48 177.17,53.59 176.45,52.88 176.45,17.02 173.15,13.72 71.04,13.72 69.09,11.77 67.44,11.77 65.41,13.8 36.37,13.8 35.56,14.61 35.56,38.23 34.04,39.75 28.83,39.75 26.8,37.72 26.8,2.92 25.78,1.91 ; 1 cut-out
V3_3D on L9_SIG3: 110.49,80.09 111.76,80.09 111.89,79.96 111.89,77.55 111.12,76.79 108.2,76.79 107.77,77.22 107.77,79.2 108.15,79.58 109.98,79.58
V3_3D on L10_SIG4: 106.73,88.65 108.03,88.65 108.79,87.88 108.79,85.17 108.51,84.89 108.08,84.89 107.9,85.06 107.9,86.97 107.72,87.15 106.6,87.15 106.3,87.45 106.3,88.21
V3_3D on L10_SIG4: 118.62,86.82 118.62,84.92 118.87,84.66 120.78,84.66 121.16,85.04 121.16,86.31 120.52,86.95 118.75,86.95
V3_3D on L10_SIG4: 92.74,89.99 93.85,89.99 94.41,89.43 95.61,89.43 95.78,89.26 95.78,88.06 95.71,87.99 92.96,87.99 92.81,88.14 92.81,88.9 92.13,89.59 91.69,89.59 91.49,89.79 91.49,92.02 91.72,92.25 92.15,92.25 92.51,91.9 92.51,90.22
V3_3D on L10_SIG4: 85.09,92.16 86.23,92.16 86.74,92.66 86.74,94.7 86.36,95.08 85.09,95.08 84.71,94.7 84.71,92.54
V3_3D_PROFIA on BOTTOM: 132.33,6.02 134.82,6.02 135.51,5.33 135.51,3.56 134.62,2.67 128.27,2.67 128.14,2.79 128.14,3.94 128.52,4.32 131.83,4.32 132.33,4.83
V3_3D_PROFIB on BOTTOM: 134.11,10.54 133.99,10.41 132.33,10.41 131.06,9.14 131.06,5.08 130.68,4.7 128.91,4.7 128.27,5.33 128.27,11.3 129.54,12.57 133.86,12.57 134.11,12.32
V3_3D_PRU1ETH0JCK on BOTTOM: 16.92,133.99 17.98,133.99 19.08,132.9 20.55,132.9 21.64,133.99 21.64,136.12 21.89,136.38 22.71,136.38 22.86,136.23 22.86,133.38 21.81,132.33 21.81,131.74 20.88,130.81 18.16,130.81 16.46,132.52 16.46,133.53
V3_3D_PRU1ETH1JCK on BOTTOM: 16.59,111.41 21.94,111.41 22.83,110.52 22.83,103 23.19,102.65 24.67,102.65 24.67,102.56 24.72,102.51 24.72,100.36 23.83,99.47 17.1,99.47 15.96,100.62 15.96,110.78
V3_3D_PRU2ETH0JCK on BOTTOM: 23.68,86.16 24.72,85.12 24.72,76.23 23.83,75.35 17.1,75.35 15.96,76.49 15.96,85.35 16.41,85.81 18.06,85.81 18.41,86.16
V3_3D_PRU2ETH1JCK on BOTTOM: 23.94,61.14 24.72,60.36 24.72,51.47 23.83,50.58 17.1,50.58 15.96,51.72 15.96,60.86 16.05,60.86 16.33,61.14
V3_3FTDI on BOTTOM (solid shape): 173.31,93.93 173.31,93.17 173.82,92.66 174.71,92.66 174.83,92.54 174.83,91.14 174.45,90.76 170.52,90.76 170.13,91.14 170.13,91.64 170.21,91.69 170.28,91.75 170.63,92.09 171.51,92.09 171.69,92.12 171.86,92.21 172.3,92.21 172.76,92.66 172.3,93.12 171.86,93.12 171.69,93.21 171.51,93.24 170.13,93.24 170.13,93.93 170.39,94.19 173.06,94.19
V3_3FTDI on TOP: 173.48,72.83 172.06,72.83 171.74,72.52 171.74,71.07 172.07,70.74 172.61,70.74 173.48,71.61
V3_3FTDI on TOP: 175.64,14.86 176.66,14.86 176.91,14.61 176.91,12.83 178.18,11.56 178.18,10.29 180.09,8.38 180.98,8.38 181.36,8.76 181.36,9.53 181.61,9.78 182.12,9.78 182.37,9.53 182.37,5.46 181.86,4.95 180.47,4.95 178.94,3.43 177.55,3.43 177.29,3.68 177.29,5.97 177.04,6.22 174.5,6.22 174.12,6.6 174.12,11.56 175.39,12.83 175.39,14.61
V3_3FTDI on BOTTOM: 168.78,62.18 168.78,61.42 168.48,61.42 168.48,62.62 168.15,62.95 168.15,63.58 168.28,63.71 169.52,63.71 169.8,63.43 169.8,63.2
V3_3FTDI on L4_SIG2: 180.34,6.35 182.12,6.35 184.02,8.25 184.02,11.94 182.5,13.46 182.5,56.52 175.77,63.25 175.77,79.63 174.75,80.64 174.75,91.57 174.12,92.2 162.05,92.2 153.67,83.82 153.67,76.33 177.04,52.96 177.04,9.65
V3_3USB on L6_PWR1: 82.6,94.99 81.41,93.8 81.41,85.39 82.52,84.28 94.23,84.28 94.72,83.8 100.74,83.8 100.97,84.03 100.97,87.58 100.67,87.88 100.67,88.52 94.19,94.99
V3_3USB on L8_GND3: 143.38,129.03 143.38,129.88 142.18,131.08 138.49,131.08 130.44,123.02 97.8,123.02 77.6,102.82 77.6,86.87 78.87,85.6 84.58,85.6 85.98,87 85.98,99.65 101.39,115.06 129.41,115.06
V3_7LCD on BOTTOM: 70.61,112.6 70.74,112.73 74.3,112.73 74.3,113.49 74.68,113.87 76.64,113.87 76.64,114.32 77.09,114.76 77.72,114.76 79.12,116.16 84.84,116.16 84.96,116.03 84.96,114.76 84.84,114.64 80.9,114.64 78.11,111.84 76.58,111.84 75.95,111.21 72.9,111.21 72.52,111.59 70.74,111.59 70.61,111.71
V5_0D on TOP: 20.19,46.31 21.46,46.31 21.84,45.93 21.84,43.39 21.59,43.13 20.07,43.13 19.81,43.39 19.81,45.93
V5_0D on TOP: 159.59,104.06 159.59,107.37 159.84,107.62 161.37,107.62 161.62,107.37 161.62,104.06 161.37,103.81 159.84,103.81
V5_0D on BOTTOM: 156.51,106.66 156.51,107.3 156.87,107.65 161.29,107.65 163.2,105.75 163.2,102.87 166.03,100.03 171.83,100.03 172.47,99.4 172.47,97.92 172.09,97.54 164.97,97.54 159.64,102.87 159.64,105.87 159.1,106.41 156.77,106.41
V5_0D on BOTTOM: 25.27,7.49 25.27,4.83 25.53,4.57 27.05,4.57 27.3,4.83 27.3,7.49 27.18,7.62 25.4,7.62
V5_0D on L6_PWR1: 188.59,2.11 188.39,1.91 2.55,1.91 1.91,2.55 1.91,45.93 2.29,46.31 47.75,46.31 48.89,45.17 48.89,25.99 50.8,24.08 65.02,24.08 71.25,17.86 75.18,17.86 75.25,17.92 81.98,17.92 84.2,15.7 98.17,15.7 100.58,18.12 111.63,18.12 112.78,16.97 113.92,16.97 115.06,18.12 164.85,18.12 169.04,22.31 169.04,65.41 169.46,65.83 169.46,90.68 170.31,91.52 170.31,92.33 169.46,93.17 169.46,112.06 170.05,112.65 170.05,114.81 169.46,115.4 169.46,150.22 169.73,150.5 188.31,150.5 188.59,150.21
V5_0D on L9_SIG3: 101.47,144.23 99.95,145.74 99.95,150.68 100.38,151.11 188.16,151.11 189.2,150.07 189.2,135.08 188.7,134.57 155.62,134.57 147.83,142.37 145.29,142.37 143.43,144.23
V5_0HDMICONN on TOP: 59.56,16 61.21,16 61.34,15.88 61.34,14.48 61.21,14.35 59.82,14.35 59.44,14.73 59.44,15.88
V5_0HDMICONN on BOTTOM: 57.99,9.49 59.53,9.49 61.81,11.77 61.81,15.3 60.2,16.92 59.53,16.92 59.04,16.42 59.04,15.32 59.41,14.94 59.41,12.48 57.76,10.82 57.76,9.72
V5_0VOP on TOP: 185.92,74.08 187.29,74.08 187.58,73.79 187.58,71.88 187.57,71.88 187.2,71.51 186.06,71.51 185.8,71.76 185.8,73.96
V5_0VOP on BOTTOM: 186.01,73.97 187.12,73.97 187.58,73.5 187.58,70.5 186.56,69.48 186.02,69.48 185.67,69.83 185.67,72.04 185.85,72.22 185.85,73.8
V12_0D on TOP: 32.77,29.34 32.77,23.37 32.51,23.11 30.99,23.11 30.73,23.37 30.73,24.26 30.48,24.51 29.97,24.51 29.72,24.77 29.72,29.21 30.1,29.59 32.51,29.59
V12_0D on TOP: 32.77,37.08 32.77,34.42 32.51,34.16 31.24,34.16 30.99,34.42 30.99,38.73 31.24,38.99 33.66,38.99 33.91,38.73 33.91,38.23
V12_0D on TOP: 160.81,121.71 161.58,121.71 161.96,121.32 161.96,120.95 162.15,120.76 163.54,120.76 163.82,120.48 164.21,120.48 164.75,121.02 164.75,124.51 164.47,124.8 162.13,124.8 161.93,124.59 161.93,124.08 161.5,123.65 160.56,123.65 160.56,121.96
V12_0D on L7_PWR2: 27.69,37.85 28.96,39.12 33.78,39.12 34.92,37.97 34.92,14.22 36.11,13.04 65.28,13.04 67.26,11.05 69.34,11.05 71.33,13.04 173.74,13.04 177.17,16.46 177.17,52.7 177.8,53.34 177.8,54.74 177.17,55.37 177.17,125.09 180.85,128.78 180.85,135.84 180.91,135.91 180.91,138.45 181.61,139.15 188.34,139.15 188.59,138.89 188.59,2.37 188.13,1.91 28.7,1.91 27.69,2.92
V12_0D on L9_SIG3: 162.43,126.07 162.43,122 164.08,120.35 186.69,120.35 189.23,122.89 189.23,129.49 187.71,131.02 167.39,131.02
VDD_CORE on TOP: 107.95,83.49 108.13,83.31 108.13,82.17 107.63,81.67 107.37,81.67 107.07,81.98 107.07,82.94 107.62,83.49
VDD_CORE on TOP: 133.86,131.15 133.86,136.99 132.46,138.38 132.46,140.42 131.95,140.92 128.65,140.92 128.4,140.67 128.4,136.99 128.78,136.61 130.05,136.61 131.32,135.34 131.32,132.03 133.48,129.87 134.11,129.88 134.49,130.26 134.49,130.51
VDD_CORE on TOP: 103.7,85.75 103.7,83.75 104.09,83.36 104.09,82.96 103.73,82.96 103.56,83.13 103.33,83.13 103.15,82.96 102.92,82.96 102.79,83.08 102.79,83.34 102.95,83.49 102.95,83.74 102.11,84.58 102.11,85.65 102.21,85.75
VDD_CORE on TOP: 105.56,88.39 105.72,88.23 105.72,86.93 105.18,86.39 104.93,86.39 104.62,86.69 104.62,87.78 105.23,88.39
VDD_CORE on TOP: 100.28,85.74 100.03,85.74 98.86,86.91 98.86,87.53 99.01,87.68 100.08,87.68 100.53,87.22 100.53,86.63 100.79,86.37 100.79,86.25
VDD_CORE on TOP: 103.02,134.73 104.75,134.73 104.9,134.57 104.9,129.7 104.67,129.47 104.04,129.47 102.74,130.76 102.74,134.45
VDD_CORE on TOP: 101.73,80.6 101.98,80.6 102.49,80.09 102.49,78.31 101.6,77.42 101.35,77.42 101.22,77.55 101.22,77.68 101.47,77.93 101.47,79.71 101.22,79.96 101.22,80.09
VDD_CORE on BOTTOM: 109.17,85.04 109.73,85.04 109.8,84.96 109.8,83.44 109.58,83.21 109.04,83.21 108.66,82.83 108.18,82.83 108.18,83.08 108.58,83.49 108.66,83.49 109.12,83.95 109.12,84.99
VDD_CORE on BOTTOM: 98.93,80.95 100.48,80.95 100.79,80.64 100.79,79.83 100.69,79.73 98.83,79.73 98.68,79.88 98.68,80.7
VDD_CORE on BOTTOM: 112.39,78.36 114.43,78.36 114.55,78.23 114.55,74.3 114.3,74.04 113.92,74.04 113.79,74.17 113.79,74.7 113.03,75.46 113.03,75.74 112.01,76.76 112.01,77.98
VDD_CORE on BOTTOM: 72.52,94.7 73.02,95.2 76.07,95.2 77.04,94.24 77.04,91.6 76.45,91.01 73.28,91.01 72.51,91.78
VDD_CORE on BOTTOM: 101.6,85.39 102.77,85.39 103.17,85.8 103.89,85.8 103.99,85.7 103.99,85.5 103.17,84.68 103.17,83.36 102.97,83.36 102.74,83.59 102.13,83.59 101.88,83.85 101.88,84.45 101.7,84.63 101.4,84.63 101.27,84.76 101.27,85.06
VDD_CORE on BOTTOM: 99.44,86.74 100.46,86.74 100.58,86.87 100.58,89.74 100.46,89.87 98.83,89.87 98.68,89.71 98.68,87.5
VDD_CORE on BOTTOM: 79.76,85.72 80.52,85.72 80.77,85.47 80.77,84.84 80.19,84.25 79.17,84.25 78.99,84.43 78.99,84.96
VDD_CORE on L3_SIG1: 98.6,80.16 101.57,80.16 101.63,80.11 101.63,79.76 101.35,79.48 98.5,79.48 98.35,79.63 98.35,79.91
VDD_CORE on L3_SIG1: 105.33,88.54 105.99,88.54 106.17,88.37 106.17,87.22 105.87,86.92 105.41,86.92 105.21,87.12 105.21,88.42
VDD_CORE on L3_SIG1: 100.97,85.47 103.17,85.47 103.56,85.85 104.11,85.85 104.11,85.27 103.66,84.81 103.66,83.95 103.81,83.79 104.22,83.79 104.22,83.01 104.14,82.93 102.13,82.93 101.85,83.21 101.85,84.35 101.68,84.53 100.99,84.53 100.74,84.79 100.74,85.24
VDD_CORE on L8_GND3: 97.92,123.27 76.96,102.32 76.96,86.57 78.57,84.96 79.88,84.96 80.39,84.45 80.39,82.17 81.53,81.03 88.31,81.03 89.66,82.38 97.16,82.38 98.55,83.77 98.55,85.93 98.17,86.31 98.17,88.35 99.44,89.62 106.43,89.62 106.81,89.24 106.81,87.97 105.79,86.95 105.16,86.95 104.39,86.19 104.39,84.45 104.77,84.07 108.46,84.07 109.17,84.79 112.52,84.79 113.03,84.28 113.03,79.12 113.92,78.23 113.92,77.09 113.66,76.83 105.2,76.83 103.25,74.88 100.2,74.88 93.26,67.95 75.14,67.95 61.47,81.62 61.47,112.1 96.39,147.02 134.62,147.02 136.27,145.37 136.27,142.7 129.03,135.46 112.39,135.46 110.87,133.94 110.87,124.16 109.98,123.27
VDD_CORE on L10_SIG4: 108.01,77.79 108.18,77.95 108.18,79.2 107.95,79.43 107.44,79.43 107.16,79.15 107.16,77.98 107.35,77.79
VDD_CORE on L10_SIG4: 99.83,86.18 100.04,86.4 100.04,87.81 99.85,88.01 99.36,88.01 98.93,87.58 98.93,86.54 99.29,86.18
VDD_CORE on L10_SIG4: 79.12,85.09 80.01,85.09 80.26,84.84 80.26,83.82 80.01,83.57 79.12,83.57 78.99,83.69 78.99,84.96
VDD_CORE on L10_SIG4: 111.89,78.06 113.54,78.06 114.55,77.04 114.55,76.1 114.15,75.69 112.98,75.69 111.63,77.04 111.63,77.81
VDD_CORE on L10_SIG4: 103.57,82.98 103.78,83.2 103.78,84.94 104.09,85.24 104.09,85.88 103.96,86 103.56,86 102.67,85.12 102.67,83.34 103.03,82.98
VDD_CORE on L10_SIG4: 108.38,82.42 108.86,82.9 108.86,83.64 108.53,83.97 108.13,83.97 107.95,83.79 107.95,83.31 107.75,83.11 107.75,82.7 108.03,82.42
VDD_DSP on TOP: 104.44,85.83 106.32,85.83 106.53,85.62 106.53,84.1 104.01,84.1 104.01,85.39
VDD_DSP on BOTTOM: 104.24,84.61 104.24,86.19 104.25,86.2 104.25,87.57 104.27,87.58 104.27,88.32 104.5,88.54 106.68,88.54 106.83,88.39 106.83,88.09 106.38,87.63 106.38,85.42 105.41,84.45 105.3,84.45 105.29,84.44 105.28,84.45 104.39,84.45
VDD_DSP on BOTTOM: 115.27,99.77 117.22,99.77 117.81,99.19 117.81,98.91 117.3,98.4 117.3,97.49 117.12,97.31 115.21,97.31 115.01,97.51 115.01,99.52
VDD_DSP on BOTTOM: 113.94,87.27 115.27,87.27 115.49,87.05 115.49,85.39 115.16,85.06 113.84,85.06 113.66,85.24 113.66,87
VDD_DSP on BOTTOM: 126.19,108.69 125.93,108.95 125.93,111.38 126.36,111.82 129.64,111.82 129.92,111.54 129.92,109 129.62,108.69
VDD_DSP on L3_SIG1: 104.72,86.18 106.73,86.18 107.01,85.9 107.01,84.99 106.68,84.66 104.55,84.66 104.5,84.71 104.5,85.95
VDD_DSP on L4_SIG2: 115.06,104.09 116.59,102.57 123.95,102.57 129.54,108.16 129.54,110.36 127.25,112.65 117.6,112.65 116.33,111.38 116.33,106.32 115.06,105.05
VDD_DSP on L8_GND3: 112.39,106 111.63,105.24 111.63,93.43 107.19,88.98 107.19,87.84 105.92,86.57 105.28,86.57 104.77,86.06 104.77,84.68 108.61,84.68 109.09,85.17 121.03,85.17 123.95,88.09 123.95,105.49 123.44,106
VDD_DSP on L10_SIG4: 115.19,98.13 115.19,98.89 115.57,99.27 117.37,99.27 117.47,99.17 117.47,98 117.07,97.59 115.72,97.59
VDD_DSP on L10_SIG4: 113.54,87.08 114.43,87.08 115.19,86.31 115.19,84.92 115.06,84.79 113.54,84.79 113.03,85.3 113.03,86.57
VDD_DSP on L10_SIG4: 115.34,103.69 115.06,103.97 115.06,104.98 115.95,105.87 117.98,105.87 118.69,105.16 118.69,104.12 118.26,103.69
VDD_DSP on L10_SIG4: 104.75,86.14 105.24,86.14 105.38,86.28 105.38,86.94 105.61,87.17 106.1,87.17 106.98,86.28 106.98,84.96 106.86,84.84 104.72,84.84 104.62,84.94 104.62,85.09 104.5,85.22 104.5,85.42 104.55,85.47 104.55,85.93
VDD_GPU on TOP (solid shape): 136.91,113.24 136.91,110.83 136.65,110.57 133.86,110.57 133.48,110.95 133.48,113.24 133.86,113.62 136.53,113.62
VDD_GPU on BOTTOM (solid shape): 137.03,113.11 137.03,110.83 136.78,110.57 133.99,110.57 133.35,111.21 133.35,113.24 133.48,113.37 136.78,113.37
VDD_GPU on TOP: 98.17,85.85 99.44,85.85 99.92,85.37 99.92,83.67 99.44,83.19 98.55,83.19 97.92,83.82 97.92,85.6
VDD_GPU on BOTTOM: 85.55,89.28 90.96,89.28 91.19,89.06 91.19,87.63 90.78,87.22 86.11,87.22 85.45,87.88 85.45,89.18
VDD_GPU on BOTTOM: 96.93,86.62 99.34,86.62 99.56,86.4 99.56,85.56 100.05,85.07 100.05,83.88 99.77,83.6 99.19,83.6 98.27,84.51 97.13,84.51 97,84.64 97,85.93 96.82,86.11 96.82,86.52
VDD_GPU on L3_SIG1: 97.69,86.21 98.73,86.21 100.03,84.91 100.03,83.97 99.9,83.85 98.65,83.85 98.4,83.59 98.4,83.36 99.21,82.55 99.21,82.17 99.11,82.07 97.94,82.07 97.54,82.47 97.54,86.06
VDD_GPU on L9_SIG3: 126.28,124.59 133.35,124.59 133.86,124.08 133.86,122.81 134.49,122.17 136.4,122.17 137.03,122.81 137.03,123.7 137.67,124.33 139.32,124.33 139.95,123.7 139.95,114 135.68,109.73 130.73,109.73 120.78,99.78 107.95,99.78 104.01,95.84 104.01,87.08 98.93,82 93.09,82 92.18,82.91 94.97,82.91 96.01,83.95 96.01,86.61 94.87,87.76 93.6,87.76 92.2,86.36 90.68,86.36 88.9,88.14 88.9,89.92 87.5,91.31 86.68,91.31 86.68,102.63 96.2,112.16 113.86,112.16
VDD_GPU on L10_SIG4: 97.69,86.21 98.73,86.21 99.77,85.17 99.77,84.58 98.78,84.58 98.17,85.19 97.54,85.19 97.54,86.06
VDD_GPU on L10_SIG4: 86.23,88.85 86.36,88.98 90.8,88.98 91.26,88.52 91.26,87.71 90.88,87.33 90.04,87.33 89.79,87.08 86.36,87.08 86.23,87.2
VDD_IVA on TOP: 118.03,134.7 120.17,134.7 120.42,134.45 120.42,131.7 120.14,131.42 118.08,131.42 117.3,132.21 117.3,133.96
VDD_IVA on BOTTOM: 104.57,84.12 105.59,84.12 106.76,85.29 106.76,86.33 107.43,87.01 108.72,87.01 109.35,87.63 109.35,89.41 110.11,90.17 110.49,90.17 110.62,90.04 110.62,89.28 110.95,88.95 110.95,85.55 110.87,85.47 108.03,85.47 107.24,84.68 107.24,83.87 106.68,83.31 106.68,82.93 106.5,82.75 104.57,82.75 104.27,83.06 104.27,83.82
VDD_IVA on L3_SIG1: 104.88,84.48 107.09,84.48 107.75,83.82 107.75,83.16 107.34,82.75 104.85,82.75 104.58,83.03 104.58,84.18
VDD_IVA on L9_SIG3: 104.24,86.08 104.77,86.61 104.77,95.2 108.76,99.19 121.03,99.19 130.94,109.09 135.94,109.09 140.34,113.49 140.34,124.08 139.45,124.97 137.29,124.97 136.27,123.95 136.27,122.94 135.89,122.55 134.75,122.55 134.37,122.94 134.37,125.6 135,126.24 136.91,126.24 140.21,129.54 140.21,133.55 138.38,135.38 124.59,135.38 119.81,130.61 117.98,130.61 116.79,131.8 116.79,141.81 118.24,143.26 143.38,143.26 147.57,139.07 147.57,110.95 138.22,101.6 138.18,101.6 125.48,88.9 125.48,88.85 117.42,80.8 105.68,80.8 104.24,82.25
VDD_IVA on L10_SIG4: 104.65,84.45 106.81,84.45 107.7,83.57 107.7,83.36 107.26,82.93 104.85,82.93 104.52,83.26 104.52,84.33
VDD_MIPI on TOP: 157.99,99.14 158.24,98.89 158.24,97.36 158.12,97.24 156.84,97.24 156.72,97.36 156.72,97.74 156.21,98.25 152.15,98.25 151.77,98.63 151.77,98.89 152.02,99.14
VDD_MPU on TOP (solid shape): 146.65,134.7 146.71,134.65 146.78,134.61 146.94,134.45 146.94,132.67 145.03,130.76 144.91,130.76 144.78,130.89 144.78,131.31 144.86,131.52 144.79,131.72 144.78,131.74 144.78,131.78 145.03,132.03 145.03,134.45 145.29,134.7
VDD_MPU on TOP: 102.95,79.83 104.09,79.83 104.55,80.29 104.55,80.54 104.39,80.7 104.39,80.87 104.6,81.08 104.72,81.08 105.11,80.7 105.23,80.7 106.5,79.43 106.5,77.42 105.23,77.42 104.44,78.21 102.97,78.21 102.95,78.23
VDD_MPU on TOP: 108.84,133.81 109.65,134.62 112.14,134.62 112.27,134.49 112.27,131.06 114.85,128.48 118.75,128.48 119.76,127.46 119.76,122.51 118.87,121.62 114.55,121.62 108.84,127.34
VDD_MPU on BOTTOM: 105.97,80.17 106.5,80.17 106.88,79.78 106.88,78.82 107.24,78.47 108.89,78.47 109.25,78.11 109.25,76.84 108.99,76.59 108.1,76.59 107.72,76.97 106.86,76.97 106.81,76.92 106.76,76.92 106.07,77.6 104.55,77.6 104.37,77.78 104.37,79.22 104.29,79.3 104.29,80.7 104.7,81.11 105.66,81.11 105.79,80.98 105.79,80.35
VDD_MPU on BOTTOM: 95.63,95.97 99.31,95.97 99.57,95.71 99.57,94.32 99.31,94.06 95.76,94.06 95.38,94.44 95.38,95.71
VDD_MPU on BOTTOM: 113.62,91.65 115.74,91.65 116.08,91.31 116.08,88.14 115.7,87.76 113.92,87.76 113.28,88.39 113.28,91.31
VDD_MPU on BOTTOM: 115.7,80.47 117.09,80.47 117.35,80.22 117.35,78.99 117.09,78.74 115.91,78.74 115.44,79.2 115.44,80.22
VDD_MPU on BOTTOM: 101.17,79.71 101.42,79.96 102.49,79.96 102.97,79.48 102.97,79.05 102.77,78.85 101.5,78.85 101.17,79.18
VDD_MPU on BOTTOM: 103.33,97.11 104.95,97.11 105.16,96.9 105.16,95.25 104.9,95 103.38,95 103.12,95.25 103.12,96.9
VDD_MPU on L3_SIG1: 102.84,77.88 104.85,77.88 105.54,77.19 106.2,77.19 106.98,77.98 106.98,79.27 106.78,79.48 106.55,79.48 106.1,79.93 106.1,80.19 104.72,80.19 104.72,79.45 104.39,79.12 103.58,79.12 103.3,79.4 102.87,79.4 102.69,79.22 102.69,78.03
VDD_MPU on L6_PWR1: 95.63,117.73 108.03,130.13 116.97,130.13 126.87,140.04 144.91,140.04 147.19,137.75 147.19,131.91 146.56,131.27 144.65,131.27 143.13,132.8 141.22,132.8 140.59,132.16 138.68,132.16 137.67,133.18 133.48,133.18 128.02,127.72 128.02,116.03 121.67,109.68 121.67,105.92 120.9,105.16 120.9,104.6 119.63,103.33 119.63,77.68 118.79,76.83 101.05,76.83 100.61,77.27 100.61,88.85 100.79,89.03 95.63,94.19
VDD_MPU on L10_SIG4: 102.49,80.09 103.35,79.23 104.32,79.23 104.57,79.48 104.57,80.6 104.55,80.62 104.55,80.75 104.83,81.03 105.77,81.03 106.07,80.73 106.07,79.84 106.88,79.02 106.88,77.72 106.22,77.06 105.71,77.06 104.85,77.93 100.86,77.93 100.84,77.91 100.71,78.03 100.71,78.41 100.79,78.49 101.27,78.49 101.47,78.69 101.47,79.96 101.6,80.09
VDD_MPU on L10_SIG4: 116.59,80.14 116.59,78.74 116.33,78.49 115.44,78.49 115.19,78.74 115.19,80.14 115.44,80.39 116.33,80.39
VDD_MPU on L10_SIG4: 95.89,94.06 95.89,95.59 96.52,96.22 97.41,96.22 97.79,95.84 97.79,93.43 97.54,93.17 96.77,93.17
VDD_MPU on L10_SIG4: 103.5,95.5 104.77,95.5 105.03,95.25 105.03,94.23 104.9,94.11 103.38,94.11 103.12,94.36 103.12,95.12
VDD_RTC on TOP (solid shape): 138.59,133.4 138.59,131.47 138.21,131.1 138.05,131.1 138.05,131.25 137.94,131.36 137.94,133.32 138.18,133.56 138.43,133.56
VDD_RTC on BOTTOM: 79.88,86.11 80.52,86.11 80.77,86.36 80.77,86.74 81.03,87 81.03,88.01 80.9,88.14 80.26,88.14 79.76,87.63 79.76,86.23
VDD_RTC on L9_SIG3: 114.07,130.03 119.87,130.03 124.03,134.19 138.3,134.19 139.32,133.18 139.32,129.54 136.4,126.62 127.3,126.62 114.98,114.3 96.95,114.3 86.23,103.59 86.23,89.05 84.56,87.38 82.68,87.38 81.79,86.49 81.79,84.02 81.53,83.77 80.42,83.77 78.11,86.09 78.11,107.02 92.25,121.16 105.2,121.16
VDD_RTC on L10_SIG4: 80.26,88.01 81.03,88.01 81.28,87.76 81.28,87.38 81.03,87.12 81.03,86.23 80.64,85.85 79.88,85.85 79.5,86.23 79.5,87.25
VDDR_VREF on TOP: 109.09,33.78 111.51,33.78 112.52,32.77 113.41,32.77 113.54,32.89 113.79,32.89 113.92,32.77 113.92,32.51 113.28,31.88 108.97,31.88 108.58,32.26 108.58,33.27
VDDR_VREF on TOP: 105.44,12.55 106.98,12.55 106.98,13.67 106.1,13.67 104.14,15.62 99.19,15.62 93.22,21.59 91.19,21.59 90.68,21.08 90.68,20.19 97.66,13.21 104.77,13.21
VDDR_VREF on TOP: 78.61,33.78 81.03,33.78 82.04,32.77 82.93,32.77 83.06,32.89 83.31,32.89 83.44,32.77 83.44,32.51 82.8,31.88 78.49,31.88 78.11,32.26 78.11,33.27
VDDR_VREF on TOP: 93.85,33.78 96.27,33.78 97.28,32.77 98.17,32.77 98.3,32.89 98.55,32.89 98.68,32.77 98.68,32.51 98.04,31.88 93.73,31.88 93.34,32.26 93.34,33.27
